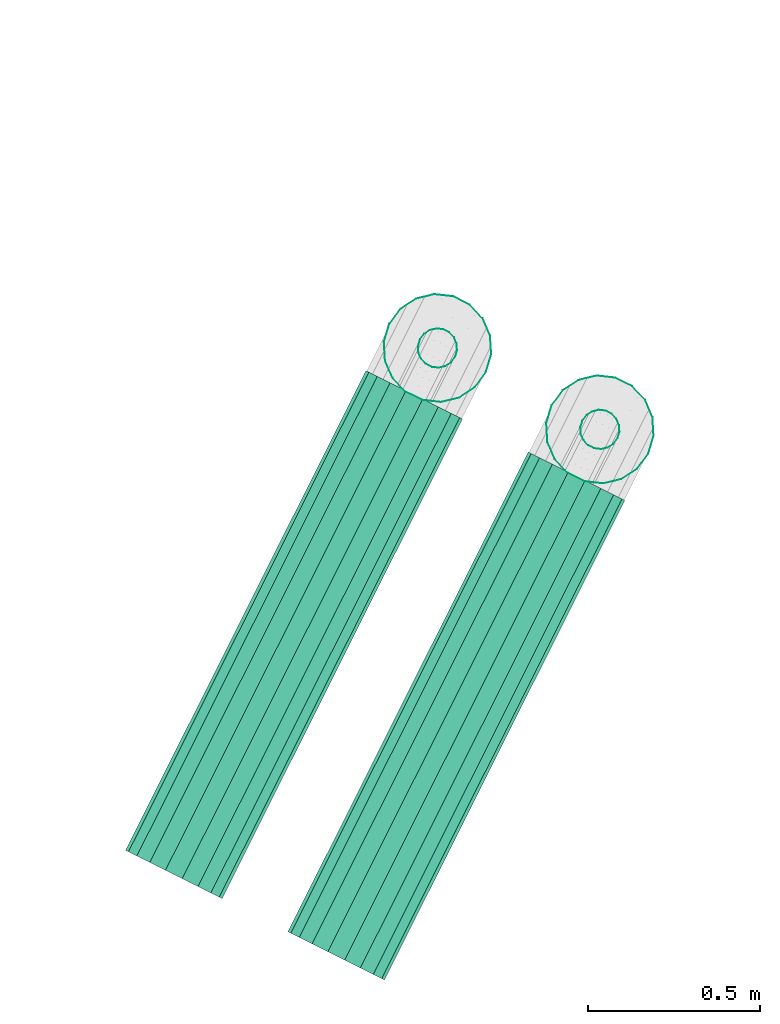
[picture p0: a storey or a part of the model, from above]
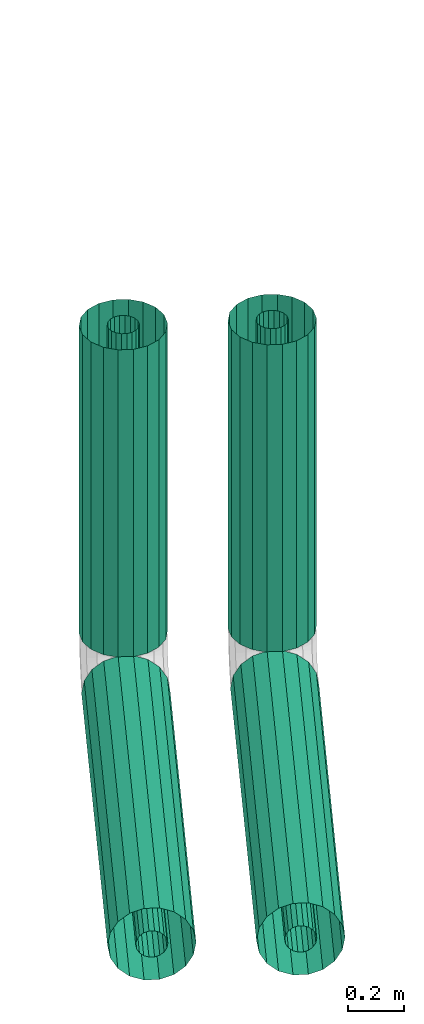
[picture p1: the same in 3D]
Properties of the parts of a building model (IFC2X3), part 1 of 23

# File
Description: ViewDefinition [CoordinationView_V2.0], RevitIdentifiers [ContentGUID: 118f7e49-5a85-4aa1-87a6-58cd707cd526, VersionGUID: 2906a081-f5fd-45af-9664-1ba8e915f47c, NumberOfSaves: 2], CoordinateReference [CoordinateBase: Aktuelle gemeinsam genutzte Koordinaten, ProjectSite: Intern], ExchangeRequirement [Architecture]
File name: Zentrale.ifc
Time: 2026-09-11T20:31:49+01:00
Written by: ODA SDAI 25.12
Made in: Autodesk - Revit 27.2.0.39 (DEU) - 27.3.0.12

# IfcProject, 2018_01
Phase: Projekt Status

# IfcSite, Default
RefLatitude: 50, 43, 7, 999999; RefLongitude: 7, 8, 55, 999999; RefElevation: 0 m
Andere - Projektausgabedatum: Projekt Datum; Projektstatus: Projekt Status; Auftraggeber: Bauherr; Projektnummer: 2018_01; Verfasser Firma 1: AUTODESK GmbH; Verfasser PLZ Ort: Ort; Verfasser Strasse: Adresse; Verfasser Telefon: Telefon; Verfasser eMail: E-Mail; Verfasser URL: www.Autodesk.de/BIM; Kategorie: Projektinformationen
IFC-Parameter - IfcOrganization: Trimble Inc.; IfcApplicationVersion: 16.1.0.21; IfcApplicationName: Trimble Nova 16.1.0.21; NameOverride: Neu Gebäude
Text - Bauherr: AUTODESK; Baustellenort: BAUORT; Baustellenstraße: BAUSTRASSE 1; Gerichtsbezirk: GERICHTSBEZIRK; Grundstücksnummer: GR; Katastralgemeinde: KG; Kundenadresse: KUNDENSTRASSE 1; Kundenort: KUNDENORT; Kundenzusatz: KUNDENZUSATZ; Kundentelefon: 0000-00000-1; Einlagezahl: 123-45; PrintManagerSettings: <PrintManagerDS xmlns="http://tempuri.org/PrintManagerDS.xsd"> <xs:schema id="PrintManagerDS" targetNamespace="http://tempuri.org/PrintManagerDS.xsd" xmlns:mstns="http://tempuri.org/PrintManagerDS.xsd" xmlns="http://tempuri.org/PrintManagerDS.xsd" xmlns:xs="http://www.w3.org/2001/XMLSchema" xmlns:msdata="urn:schemas-microsoft-com:xml-msdata" attributeFormDefault="qualified" elementFormDefault="qualified"> <xs:element name="PrintManagerDS" msdata:IsDataSet="true" msdata:UseCurrentLocale="true"> <xs:complexType> <xs:choice minOccurs="0" maxOccurs="unbounded"> <xs:element name="DruckEinstellungDT"> <xs:complexType> <xs:sequence> <xs:element name="ID" msdata:DataType="System.Guid, mscorlib, Version=4.0.0.0, Culture=neutral, PublicKeyToken=b77a5c561934e089" msdata:AutoIncrementSeed="-1" msdata:AutoIncrementStep="-1" type="xs:string" minOccurs="0" /> <xs:element name="Name" type="xs:string" minOccurs="0" /> <xs:element name="Beschreibung" type="xs:string" minOccurs="0" /> <xs:element name="Kategorie" type="xs:string" minOccurs="0" /> <xs:element name="PrinterName" type="xs:string" minOccurs="0" /> <xs:element name="PrintToFile" type="xs:boolean" minOccurs="0" /> <xs:element name="FileName" type="xs:string" minOccurs="0" /> <xs:element name="ColorDepth" type="xs:string" minOccurs="0" /> <xs:element name="HiddenLineViews" type="xs:string" minOccurs="0" /> <xs:element name="HideCropBoundaries" type="xs:boolean" minOccurs="0" /> <xs:element name="HideRefOrWorkPlanes" type="xs:boolean" minOccurs="0" /> <xs:element name="HideScopeBoxes" type="xs:boolean" minOccurs="0" /> <xs:element name="HideUnreferencedViewTags" type="xs:boolean" minOccurs="0" /> <xs:element name="MarginType" type="xs:string" minOccurs="0" /> <xs:element name="PageOrientation" type="xs:string" minOccurs="0" /> <xs:element name="PaperPlacement" type="xs:string" minOccurs="0" /> <xs:element name="PaperSize" type="xs:string" minOccurs="0" /> <xs:element name="PaperSource" type="xs:string" minOccurs="0" /> <xs:element name="RasterQuality" type="xs:string" minOccurs="0" /> <xs:element name="ReplaceHalftoneWithThinLines" type="xs:boolean" minOccurs="0" /> <xs:element name="UserDefinedMarginX" type="xs:double" minOccurs="0" /> <xs:element name="UserDefinedMarginY" type="xs:double" minOccurs="0" /> <xs:element name="ViewLinksInBlue" type="xs:boolean" minOccurs="0" /> <xs:element name="Zoom" type="xs:int" minOccurs="0" /> <xs:element name="ZoomType" type="xs:string" minOccurs="0" /> </xs:sequence> </xs:complexType> </xs:element> <xs:element name="DruckSatzDT"> <xs:complexType> <xs:sequence> <xs:element name="ID" msdata:DataType="System.Guid, mscorlib, Version=4.0.0.0, Culture=neutral, PublicKeyToken=b77a5c561934e089" type="xs:string" minOccurs="0" /> <xs:element name="PlanID" type="xs:string" minOccurs="0" /> <xs:element name="DruckEinstellungID" msdata:DataType="System.Guid, mscorlib, Version=4.0.0.0, Culture=neutral, PublicKeyToken=b77a5c561934e089" type="xs:string" minOccurs="0" /> <xs:element name="Name" type="xs:string" minOccurs="0" /> <xs:element name="Beschreibung" type="xs:string" minOccurs="0" /> <xs:element name="ParameterName" type="xs:string" minOccurs="0" /> <xs:element name="File" type="xs:string" minOccurs="0" /> <xs:element name="Path" type="xs:string" minOccurs="0" /> <xs:element name="GenerateFileName" type="xs:boolean" minOccurs="0" /> <xs:element name="Kategorie" type="xs:string" minOccurs="0" /> </xs:sequence> </xs:complexType> </xs:element> <xs:element name="DruckJobDT"> <xs:complexType> <xs:sequence> <xs:element name="ID" msdata:DataType="System.Guid, mscorlib, Version=4.0.0.0, Culture=neutral, PublicKeyToken=b77a5c561934e089" type="xs:string" minOccurs="0" /> <xs:element name="DruckJobGruppeID" msdata:DataType="System.Guid, mscorlib, Version=4.0.0.0, Culture=neutral, PublicKeyToken=b77a5c561934e089" type="xs:string" minOccurs="0" /> <xs:element name="DruckSatzID" msdata:DataType="System.Guid, mscorlib, Version=4.0.0.0, Culture=neutral, PublicKeyToken=b77a5c561934e089" type="xs:string" minOccurs="0" /> <xs:element name="Anzahl" type="xs:int" minOccurs="0" /> </xs:sequence> </xs:complexType> </xs:element> <xs:element name="DruckJobGruppeDT"> <xs:complexType> <xs:sequence> <xs:element name="ID" msdata:DataType="System.Guid, mscorlib, Version=4.0.0.0, Culture=neutral, PublicKeyToken=b77a5c561934e089" type="xs:string" minOccurs="0" /> <xs:element name="Name" type="xs:string" minOccurs="0" /> <xs:element name="Beschreibung" type="xs:string" minOccurs="0" /> <xs:element name="JobCount" msdata:ReadOnly="true" msdata:Expression="Count(Child(DruckJobGruppeDT_DruckJobDT).Anzahl)" type="xs:int" minOccurs="0" /> <xs:element name="Kategorie" type="xs:string" minOccurs="0" /> </xs:sequence> </xs:complexType> </xs:element> <xs:element name="PrintSettingCategories"> <xs:complexType> <xs:sequence> <xs:element name="CategoryName" type="xs:string" minOccurs="0" /> </xs:sequence> </xs:complexType> </xs:element> <xs:element name="PrintRecordCategories"> <xs:complexType> <xs:sequence> <xs:element name="CategoryName" type="xs:string" /> </xs:sequence> </xs:complexType> </xs:element> <xs:element name="JobGroupCategories"> <xs:complexType> <xs:sequence> <xs:element name="CategoryName" type="xs:string" /> </xs:sequence> </xs:complexType> </xs:element> <xs:element name="ExportSettingsDT"> <xs:complexType> <xs:sequence> <xs:element name="ID" msdata:DataType="System.Guid, mscorlib, Version=4.0.0.0, Culture=neutral, PublicKeyToken=b77a5c561934e089" type="xs:string" /> <xs:element name="Name" type="xs:string" minOccurs="0" /> <xs:element name="Description" type="xs:string" default="&quot;&quot;" minOccurs="0" /> <xs:element name="Category" type="xs:string" minOccurs="0" /> <xs:element name="Type" type="xs:string" minOccurs="0" /> <xs:element name="Data" type="xs:string" minOccurs="0" /> </xs:sequence> </xs:complexType> </xs:element> <xs:element name="ExportMappingDT"> <xs:complexType> <xs:sequence> <xs:element name="ID" msdata:DataType="System.Guid, mscorlib, Version=4.0.0.0, Culture=neutral, PublicKeyToken=b77a5c561934e089" type="xs:string" /> <xs:element name="DWG" msdata:DataType="System.Guid, mscorlib, Version=4.0.0.0, Culture=neutral, PublicKeyToken=b77a5c561934e089" type="xs:string" minOccurs="0" /> <xs:element name="DWGPath" type="xs:string" minOccurs="0" /> <xs:element name="DWGFile" type="xs:string" minOccurs="0" /> </xs:sequence> </xs:complexType> </xs:element> <xs:element name="ExportSettingCategories"> <xs:complexType> <xs:sequence> <xs:element name="CategoryName" type="xs:string" /> </xs:sequence> </xs:complexType> </xs:element> </xs:choice> </xs:complexType> <xs:unique name="Constraint1"> <xs:selector xpath=".//mstns:DruckEinstellungDT" /> <xs:field xpath="mstns:ID" /> </xs:unique> <xs:unique name="Constraint2"> <xs:selector xpath=".//mstns:DruckEinstellungDT" /> <xs:field xpath="mstns:Name" /> </xs:unique> <xs:unique name="DruckSatzDT_Constraint1" msdata:ConstraintName="Constraint1"> <xs:selector xpath=".//mstns:DruckSatzDT" /> <xs:field xpath="mstns:ID" /> </xs:unique> <xs:unique name="DruckJobDT_Constraint1" msdata:ConstraintName="Constraint1"> <xs:selector xpath=".//mstns:DruckJobDT" /> <xs:field xpath="mstns:ID" /> </xs:unique> <xs:unique name="DruckJobGruppeDT_Constraint1" msdata:ConstraintName="Constraint1"> <xs:selector xpath=".//mstns:DruckJobGruppeDT" /> <xs:field xpath="mstns:ID" /> </xs:unique> <xs:unique name="PrintSettingCategories_Constraint1" msdata:ConstraintName="Constraint1"> <xs:selector xpath=".//mstns:PrintSettingCategories" /> <xs:field xpath="mstns:CategoryName" /> </xs:unique> <xs:unique name="PrintRecordCategories_Constraint1" msdata:ConstraintName="Constraint1" msdata:PrimaryKey="true"> <xs:selector xpath=".//mstns:PrintRecordCategories" /> <xs:field xpath="mstns:CategoryName" /> </xs:unique> <xs:unique name="JobGroupCategories_Constraint1" msdata:ConstraintName="Constraint1" msdata:PrimaryKey="true"> <xs:selector xpath=".//mstns:JobGroupCategories" /> <xs:field xpath="mstns:CategoryName" /> </xs:unique> <xs:unique name="ExportSettingsDT_Constraint1" msdata:ConstraintName="Constraint1" msdata:PrimaryKey="true"> <xs:selector xpath=".//mstns:ExportSettingsDT" /> <xs:field xpath="mstns:ID" /> </xs:unique> <xs:unique name="ExportSettingsDT_Constraint2" msdata:ConstraintName="Constraint2"> <xs:selector xpath=".//mstns:ExportSettingsDT" /> <xs:field xpath="mstns:Name" /> </xs:unique> <xs:unique name="ExportMappingDT_Constraint1" msdata:ConstraintName="Constraint1" msdata:PrimaryKey="true"> <xs:selector xpath=".//mstns:ExportMappingDT" /> <xs:field xpath="mstns:ID" /> </xs:unique> <xs:unique name="ExportSettingCategories_Constraint1" msdata:ConstraintName="Constraint1" msdata:PrimaryKey="true"> <xs:selector xpath=".//mstns:ExportSettingCategories" /> <xs:field xpath="mstns:CategoryName" /> </xs:unique> </xs:element> <xs:annotation> <xs:appinfo> <msdata:Relationship name="PrintSettingCategories_DruckEinstellungDT" msdata:parent="PrintSettingCategories" msdata:child="DruckEinstellungDT" msdata:parentkey="CategoryName" msdata:childkey="Kategorie" /> <msdata:Relationship name="DruckEinstellungDT_DruckSatzDT" msdata:parent="DruckEinstellungDT" msdata:child="DruckSatzDT" msdata:parentkey="ID" msdata:childkey="DruckEinstellungID" /> <msdata:Relationship name="DruckJobGruppeDT_DruckJobDT" msdata:parent="DruckJobGruppeDT" msdata:child="DruckJobDT" msdata:parentkey="ID" msdata:childkey="DruckJobGruppeID" /> <msdata:Relationship name="DruckEinstellungDT_PrintRecordCategories" msdata:parent="DruckSatzDT" msdata:child="PrintRecordCategories" msdata:parentkey="Kategorie" msdata:childkey="CategoryName" /> <msdata:Relationship name="DruckJobGruppeDT_JobGroupCategories" msdata:parent="DruckJobGruppeDT" msdata:child="JobGroupCategories" msdata:parentkey="Kategorie" msdata:childkey="CategoryName" /> <msdata:Relationship name="DruckSatzDT_DruckJobDT" msdata:parent="DruckSatzDT" msdata:child="DruckJobDT" msdata:parentkey="ID" msdata:childkey="DruckSatzID" /> <msdata:Relationship name="DruckSatzDT_ExportMappingDT" msdata:parent="DruckSatzDT" msdata:child="ExportMappingDT" msdata:parentkey="ID" msdata:childkey="ID" /> <msdata:Relationship name="ExportSettingsDT_ExportSettingCategories" msdata:parent="ExportSettingCategories" msdata:child="ExportSettingsDT" msdata:parentkey="CategoryName" msdata:childkey="Category" /> </xs:appinfo> </xs:annotation> </xs:schema> <PrintRecordCategories> <CategoryName>&lt;Keine&gt;</CategoryName> </PrintRecordCategories> <JobGroupCategories> <CategoryName>&lt;Keine&gt;</CategoryName> </JobGroupCategories> </PrintManagerDS>

# IfcBuilding
Pset_BuildingCommon - NumberOfStoreys: 3
Andere - Projektausgabedatum: Projekt Datum; Projektstatus: Projekt Status; Auftraggeber: Bauherr; Projektnummer: 2018_01; Verfasser Firma 1: AUTODESK GmbH; Verfasser PLZ Ort: Ort; Verfasser Strasse: Adresse; Verfasser Telefon: Telefon; Verfasser eMail: E-Mail; Verfasser URL: www.Autodesk.de/BIM; Kategorie: Projektinformationen
IFC-Parameter - IfcOrganization: Trimble Inc.; IfcApplicationVersion: 16.1.0.21; IfcApplicationName: Trimble Nova 16.1.0.21; NameOverride: Neu Gebäude
Text - Bauherr: AUTODESK; Baustellenort: BAUORT; Baustellenstraße: BAUSTRASSE 1; Gerichtsbezirk: GERICHTSBEZIRK; Grundstücksnummer: GR; Katastralgemeinde: KG; Kundenadresse: KUNDENSTRASSE 1; Kundenort: KUNDENORT; Kundenzusatz: KUNDENZUSATZ; Kundentelefon: 0000-00000-1; Einlagezahl: 123-45; PrintManagerSettings: <PrintManagerDS xmlns="http://tempuri.org/PrintManagerDS.xsd"> <xs:schema id="PrintManagerDS" targetNamespace="http://tempuri.org/PrintManagerDS.xsd" xmlns:mstns="http://tempuri.org/PrintManagerDS.xsd" xmlns="http://tempuri.org/PrintManagerDS.xsd" xmlns:xs="http://www.w3.org/2001/XMLSchema" xmlns:msdata="urn:schemas-microsoft-com:xml-msdata" attributeFormDefault="qualified" elementFormDefault="qualified"> <xs:element name="PrintManagerDS" msdata:IsDataSet="true" msdata:UseCurrentLocale="true"> <xs:complexType> <xs:choice minOccurs="0" maxOccurs="unbounded"> <xs:element name="DruckEinstellungDT"> <xs:complexType> <xs:sequence> <xs:element name="ID" msdata:DataType="System.Guid, mscorlib, Version=4.0.0.0, Culture=neutral, PublicKeyToken=b77a5c561934e089" msdata:AutoIncrementSeed="-1" msdata:AutoIncrementStep="-1" type="xs:string" minOccurs="0" /> <xs:element name="Name" type="xs:string" minOccurs="0" /> <xs:element name="Beschreibung" type="xs:string" minOccurs="0" /> <xs:element name="Kategorie" type="xs:string" minOccurs="0" /> <xs:element name="PrinterName" type="xs:string" minOccurs="0" /> <xs:element name="PrintToFile" type="xs:boolean" minOccurs="0" /> <xs:element name="FileName" type="xs:string" minOccurs="0" /> <xs:element name="ColorDepth" type="xs:string" minOccurs="0" /> <xs:element name="HiddenLineViews" type="xs:string" minOccurs="0" /> <xs:element name="HideCropBoundaries" type="xs:boolean" minOccurs="0" /> <xs:element name="HideRefOrWorkPlanes" type="xs:boolean" minOccurs="0" /> <xs:element name="HideScopeBoxes" type="xs:boolean" minOccurs="0" /> <xs:element name="HideUnreferencedViewTags" type="xs:boolean" minOccurs="0" /> <xs:element name="MarginType" type="xs:string" minOccurs="0" /> <xs:element name="PageOrientation" type="xs:string" minOccurs="0" /> <xs:element name="PaperPlacement" type="xs:string" minOccurs="0" /> <xs:element name="PaperSize" type="xs:string" minOccurs="0" /> <xs:element name="PaperSource" type="xs:string" minOccurs="0" /> <xs:element name="RasterQuality" type="xs:string" minOccurs="0" /> <xs:element name="ReplaceHalftoneWithThinLines" type="xs:boolean" minOccurs="0" /> <xs:element name="UserDefinedMarginX" type="xs:double" minOccurs="0" /> <xs:element name="UserDefinedMarginY" type="xs:double" minOccurs="0" /> <xs:element name="ViewLinksInBlue" type="xs:boolean" minOccurs="0" /> <xs:element name="Zoom" type="xs:int" minOccurs="0" /> <xs:element name="ZoomType" type="xs:string" minOccurs="0" /> </xs:sequence> </xs:complexType> </xs:element> <xs:element name="DruckSatzDT"> <xs:complexType> <xs:sequence> <xs:element name="ID" msdata:DataType="System.Guid, mscorlib, Version=4.0.0.0, Culture=neutral, PublicKeyToken=b77a5c561934e089" type="xs:string" minOccurs="0" /> <xs:element name="PlanID" type="xs:string" minOccurs="0" /> <xs:element name="DruckEinstellungID" msdata:DataType="System.Guid, mscorlib, Version=4.0.0.0, Culture=neutral, PublicKeyToken=b77a5c561934e089" type="xs:string" minOccurs="0" /> <xs:element name="Name" type="xs:string" minOccurs="0" /> <xs:element name="Beschreibung" type="xs:string" minOccurs="0" /> <xs:element name="ParameterName" type="xs:string" minOccurs="0" /> <xs:element name="File" type="xs:string" minOccurs="0" /> <xs:element name="Path" type="xs:string" minOccurs="0" /> <xs:element name="GenerateFileName" type="xs:boolean" minOccurs="0" /> <xs:element name="Kategorie" type="xs:string" minOccurs="0" /> </xs:sequence> </xs:complexType> </xs:element> <xs:element name="DruckJobDT"> <xs:complexType> <xs:sequence> <xs:element name="ID" msdata:DataType="System.Guid, mscorlib, Version=4.0.0.0, Culture=neutral, PublicKeyToken=b77a5c561934e089" type="xs:string" minOccurs="0" /> <xs:element name="DruckJobGruppeID" msdata:DataType="System.Guid, mscorlib, Version=4.0.0.0, Culture=neutral, PublicKeyToken=b77a5c561934e089" type="xs:string" minOccurs="0" /> <xs:element name="DruckSatzID" msdata:DataType="System.Guid, mscorlib, Version=4.0.0.0, Culture=neutral, PublicKeyToken=b77a5c561934e089" type="xs:string" minOccurs="0" /> <xs:element name="Anzahl" type="xs:int" minOccurs="0" /> </xs:sequence> </xs:complexType> </xs:element> <xs:element name="DruckJobGruppeDT"> <xs:complexType> <xs:sequence> <xs:element name="ID" msdata:DataType="System.Guid, mscorlib, Version=4.0.0.0, Culture=neutral, PublicKeyToken=b77a5c561934e089" type="xs:string" minOccurs="0" /> <xs:element name="Name" type="xs:string" minOccurs="0" /> <xs:element name="Beschreibung" type="xs:string" minOccurs="0" /> <xs:element name="JobCount" msdata:ReadOnly="true" msdata:Expression="Count(Child(DruckJobGruppeDT_DruckJobDT).Anzahl)" type="xs:int" minOccurs="0" /> <xs:element name="Kategorie" type="xs:string" minOccurs="0" /> </xs:sequence> </xs:complexType> </xs:element> <xs:element name="PrintSettingCategories"> <xs:complexType> <xs:sequence> <xs:element name="CategoryName" type="xs:string" minOccurs="0" /> </xs:sequence> </xs:complexType> </xs:element> <xs:element name="PrintRecordCategories"> <xs:complexType> <xs:sequence> <xs:element name="CategoryName" type="xs:string" /> </xs:sequence> </xs:complexType> </xs:element> <xs:element name="JobGroupCategories"> <xs:complexType> <xs:sequence> <xs:element name="CategoryName" type="xs:string" /> </xs:sequence> </xs:complexType> </xs:element> <xs:element name="ExportSettingsDT"> <xs:complexType> <xs:sequence> <xs:element name="ID" msdata:DataType="System.Guid, mscorlib, Version=4.0.0.0, Culture=neutral, PublicKeyToken=b77a5c561934e089" type="xs:string" /> <xs:element name="Name" type="xs:string" minOccurs="0" /> <xs:element name="Description" type="xs:string" default="&quot;&quot;" minOccurs="0" /> <xs:element name="Category" type="xs:string" minOccurs="0" /> <xs:element name="Type" type="xs:string" minOccurs="0" /> <xs:element name="Data" type="xs:string" minOccurs="0" /> </xs:sequence> </xs:complexType> </xs:element> <xs:element name="ExportMappingDT"> <xs:complexType> <xs:sequence> <xs:element name="ID" msdata:DataType="System.Guid, mscorlib, Version=4.0.0.0, Culture=neutral, PublicKeyToken=b77a5c561934e089" type="xs:string" /> <xs:element name="DWG" msdata:DataType="System.Guid, mscorlib, Version=4.0.0.0, Culture=neutral, PublicKeyToken=b77a5c561934e089" type="xs:string" minOccurs="0" /> <xs:element name="DWGPath" type="xs:string" minOccurs="0" /> <xs:element name="DWGFile" type="xs:string" minOccurs="0" /> </xs:sequence> </xs:complexType> </xs:element> <xs:element name="ExportSettingCategories"> <xs:complexType> <xs:sequence> <xs:element name="CategoryName" type="xs:string" /> </xs:sequence> </xs:complexType> </xs:element> </xs:choice> </xs:complexType> <xs:unique name="Constraint1"> <xs:selector xpath=".//mstns:DruckEinstellungDT" /> <xs:field xpath="mstns:ID" /> </xs:unique> <xs:unique name="Constraint2"> <xs:selector xpath=".//mstns:DruckEinstellungDT" /> <xs:field xpath="mstns:Name" /> </xs:unique> <xs:unique name="DruckSatzDT_Constraint1" msdata:ConstraintName="Constraint1"> <xs:selector xpath=".//mstns:DruckSatzDT" /> <xs:field xpath="mstns:ID" /> </xs:unique> <xs:unique name="DruckJobDT_Constraint1" msdata:ConstraintName="Constraint1"> <xs:selector xpath=".//mstns:DruckJobDT" /> <xs:field xpath="mstns:ID" /> </xs:unique> <xs:unique name="DruckJobGruppeDT_Constraint1" msdata:ConstraintName="Constraint1"> <xs:selector xpath=".//mstns:DruckJobGruppeDT" /> <xs:field xpath="mstns:ID" /> </xs:unique> <xs:unique name="PrintSettingCategories_Constraint1" msdata:ConstraintName="Constraint1"> <xs:selector xpath=".//mstns:PrintSettingCategories" /> <xs:field xpath="mstns:CategoryName" /> </xs:unique> <xs:unique name="PrintRecordCategories_Constraint1" msdata:ConstraintName="Constraint1" msdata:PrimaryKey="true"> <xs:selector xpath=".//mstns:PrintRecordCategories" /> <xs:field xpath="mstns:CategoryName" /> </xs:unique> <xs:unique name="JobGroupCategories_Constraint1" msdata:ConstraintName="Constraint1" msdata:PrimaryKey="true"> <xs:selector xpath=".//mstns:JobGroupCategories" /> <xs:field xpath="mstns:CategoryName" /> </xs:unique> <xs:unique name="ExportSettingsDT_Constraint1" msdata:ConstraintName="Constraint1" msdata:PrimaryKey="true"> <xs:selector xpath=".//mstns:ExportSettingsDT" /> <xs:field xpath="mstns:ID" /> </xs:unique> <xs:unique name="ExportSettingsDT_Constraint2" msdata:ConstraintName="Constraint2"> <xs:selector xpath=".//mstns:ExportSettingsDT" /> <xs:field xpath="mstns:Name" /> </xs:unique> <xs:unique name="ExportMappingDT_Constraint1" msdata:ConstraintName="Constraint1" msdata:PrimaryKey="true"> <xs:selector xpath=".//mstns:ExportMappingDT" /> <xs:field xpath="mstns:ID" /> </xs:unique> <xs:unique name="ExportSettingCategories_Constraint1" msdata:ConstraintName="Constraint1" msdata:PrimaryKey="true"> <xs:selector xpath=".//mstns:ExportSettingCategories" /> <xs:field xpath="mstns:CategoryName" /> </xs:unique> </xs:element> <xs:annotation> <xs:appinfo> <msdata:Relationship name="PrintSettingCategories_DruckEinstellungDT" msdata:parent="PrintSettingCategories" msdata:child="DruckEinstellungDT" msdata:parentkey="CategoryName" msdata:childkey="Kategorie" /> <msdata:Relationship name="DruckEinstellungDT_DruckSatzDT" msdata:parent="DruckEinstellungDT" msdata:child="DruckSatzDT" msdata:parentkey="ID" msdata:childkey="DruckEinstellungID" /> <msdata:Relationship name="DruckJobGruppeDT_DruckJobDT" msdata:parent="DruckJobGruppeDT" msdata:child="DruckJobDT" msdata:parentkey="ID" msdata:childkey="DruckJobGruppeID" /> <msdata:Relationship name="DruckEinstellungDT_PrintRecordCategories" msdata:parent="DruckSatzDT" msdata:child="PrintRecordCategories" msdata:parentkey="Kategorie" msdata:childkey="CategoryName" /> <msdata:Relationship name="DruckJobGruppeDT_JobGroupCategories" msdata:parent="DruckJobGruppeDT" msdata:child="JobGroupCategories" msdata:parentkey="Kategorie" msdata:childkey="CategoryName" /> <msdata:Relationship name="DruckSatzDT_DruckJobDT" msdata:parent="DruckSatzDT" msdata:child="DruckJobDT" msdata:parentkey="ID" msdata:childkey="DruckSatzID" /> <msdata:Relationship name="DruckSatzDT_ExportMappingDT" msdata:parent="DruckSatzDT" msdata:child="ExportMappingDT" msdata:parentkey="ID" msdata:childkey="ID" /> <msdata:Relationship name="ExportSettingsDT_ExportSettingCategories" msdata:parent="ExportSettingCategories" msdata:child="ExportSettingsDT" msdata:parentkey="CategoryName" msdata:childkey="Category" /> </xs:appinfo> </xs:annotation> </xs:schema> <PrintRecordCategories> <CategoryName>&lt;Keine&gt;</CategoryName> </PrintRecordCategories> <JobGroupCategories> <CategoryName>&lt;Keine&gt;</CategoryName> </JobGroupCategories> </PrintManagerDS>

# IfcBuildingStorey (3)
Pset_AirSideSystemInformation - sets with these values: 2
Andere - Typ: Ebene OK FFB; Familie: Ebene; Familie und Typ: Ebene: Ebene OK FFB; Typ-ID: 696869; Kategorie: Ebenen
Bemaßungen - Höhe für Berechnung: 0 m
ID-Daten - Tragwerk: no; Gebäudegeschoss: yes
IFC-Parameter - In IFC-Datei exportieren: Nach Typ; In IFC exportieren als: ifcbuildingstorey
Andere(Typ) - Kategorie: Ebenen; Familienname: Ebene
Abhängigkeiten(Typ) - Basishöhe: Projekt-Basispunkt
Grafiken(Typ) - Linienstärke: 2; Farbe: 255; Linienmuster: (Ebene); Symbol: Beschriftung Ebene Oberkante : Fertig Fußboden; Symbol bei Ende 1 Standard: no; Symbol bei Ende 2 Standard: yes
ID-Daten(Typ) - Typname: Ebene OK FFB
IFC-Parameter(Typ) - Typ in IFC-Datei exportieren: Vorgabe
Name | LongName = Pset_AirSideSystemInformation, Name = ID-Daten, Name | Elevation (m) = Höhe (m)
1. Untergeschoss | 1. Untergeschoss | -2.75
Erdgeschoss | Erdgeschoss | 0
1. Obergeschoss | 1. Obergeschoss | 2.75

# IfcBuildingElementProxy: BuildingElementProxy 100:BuildingElementProxy 100, BuildingElementProxy 100
In: Erdgeschoss
Type - Material: IfcSurfaceStyle #623543
Type - Andere - Kategorie: Allgemeines Modell; Familienname: BuildingElementProxy 100
Type - ID-Daten - Typname: BuildingElementProxy 100
Type - IFC-Parameter - Typ in IFC-Datei exportieren: Vorgabe
Description: IfcBuildingElementProxy
Pset_BuildingElementProxyCommon - Reference: BuildingElementProxy 100; sets with these values: 2
Andere - Typ: BuildingElementProxy 100; Familie: BuildingElementProxy 100; Familie und Typ: BuildingElementProxy 100: BuildingElementProxy 100; Typ-ID: 2538749
Abhängigkeiten - Höhe von Ebene: 0 m; Verschieben mit umliegenden Elementen: no
Bemaßungen - Fläche: 0.00905707 m2; Volumen: 0.000161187 m3
IFC-Parameter - In IFC-Datei exportieren: Nach Typ; In IFC exportieren als: ifcbuildingelementproxy; NameOverride: BuildingElementProxy 100; IfcPresentationLayer: 0; IfcDescription: IfcBuildingElementProxy
Phasen - Phase erstellt: Phase 01

# IfcBuildingElementProxy: BuildingElementProxy 101:BuildingElementProxy 101, BuildingElementProxy 101
In: Erdgeschoss
Type - Material: IfcSurfaceStyle #623543
Type - Andere - Kategorie: Allgemeines Modell; Familienname: BuildingElementProxy 101
Type - ID-Daten - Typname: BuildingElementProxy 101
Type - IFC-Parameter - Typ in IFC-Datei exportieren: Vorgabe
Description: IfcBuildingElementProxy
Pset_BuildingElementProxyCommon - Reference: BuildingElementProxy 101; sets with these values: 2
Andere - Typ: BuildingElementProxy 101; Familie: BuildingElementProxy 101; Familie und Typ: BuildingElementProxy 101: BuildingElementProxy 101; Typ-ID: 2538756
Abhängigkeiten - Höhe von Ebene: 0 m; Verschieben mit umliegenden Elementen: no
Bemaßungen - Fläche: 0.00687765 m2; Volumen: 0.0000187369 m3
IFC-Parameter - In IFC-Datei exportieren: Nach Typ; In IFC exportieren als: ifcbuildingelementproxy; NameOverride: BuildingElementProxy 101; IfcPresentationLayer: 0; IfcDescription: IfcBuildingElementProxy
Phasen - Phase erstellt: Phase 01

# IfcBuildingElementProxy: BuildingElementProxy 102:BuildingElementProxy 102, BuildingElementProxy 102
In: Erdgeschoss
Type - Material: IfcSurfaceStyle #623543
Type - Andere - Kategorie: Allgemeines Modell; Familienname: BuildingElementProxy 102
Type - ID-Daten - Typname: BuildingElementProxy 102
Type - IFC-Parameter - Typ in IFC-Datei exportieren: Vorgabe
Description: IfcBuildingElementProxy
Pset_BuildingElementProxyCommon - Reference: BuildingElementProxy 102; sets with these values: 2
Andere - Typ: BuildingElementProxy 102; Familie: BuildingElementProxy 102; Familie und Typ: BuildingElementProxy 102: BuildingElementProxy 102; Typ-ID: 2538763
Abhängigkeiten - Höhe von Ebene: 0 m; Verschieben mit umliegenden Elementen: no
Bemaßungen - Fläche: 0.0156619 m2; Volumen: 0.0000724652 m3
IFC-Parameter - In IFC-Datei exportieren: Nach Typ; In IFC exportieren als: ifcbuildingelementproxy; NameOverride: BuildingElementProxy 102; IfcPresentationLayer: 0; IfcDescription: IfcBuildingElementProxy
Phasen - Phase erstellt: Phase 01

# IfcBuildingElementProxy: BuildingElementProxy 103:BuildingElementProxy 103, BuildingElementProxy 103
In: Erdgeschoss
Type - Material: IfcSurfaceStyle #623543
Type - Andere - Kategorie: Allgemeines Modell; Familienname: BuildingElementProxy 103
Type - ID-Daten - Typname: BuildingElementProxy 103
Type - IFC-Parameter - Typ in IFC-Datei exportieren: Vorgabe
Description: IfcBuildingElementProxy
Pset_BuildingElementProxyCommon - Reference: BuildingElementProxy 103; sets with these values: 2
Andere - Typ: BuildingElementProxy 103; Familie: BuildingElementProxy 103; Familie und Typ: BuildingElementProxy 103: BuildingElementProxy 103; Typ-ID: 2538770
Abhängigkeiten - Höhe von Ebene: 0 m; Verschieben mit umliegenden Elementen: no
Bemaßungen - Fläche: 0.00687765 m2; Volumen: 0.0000187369 m3
IFC-Parameter - In IFC-Datei exportieren: Nach Typ; In IFC exportieren als: ifcbuildingelementproxy; NameOverride: BuildingElementProxy 103; IfcPresentationLayer: 0; IfcDescription: IfcBuildingElementProxy
Phasen - Phase erstellt: Phase 01

# IfcBuildingElementProxy: BuildingElementProxy 104:BuildingElementProxy 104, BuildingElementProxy 104
In: Erdgeschoss
Type - Material: IfcSurfaceStyle #624876
Type - Andere - Kategorie: Allgemeines Modell; Familienname: BuildingElementProxy 104
Type - ID-Daten - Typname: BuildingElementProxy 104
Type - IFC-Parameter - Typ in IFC-Datei exportieren: Vorgabe
Description: IfcBuildingElementProxy
Pset_BuildingElementProxyCommon - Reference: BuildingElementProxy 104; sets with these values: 2
Andere - Typ: BuildingElementProxy 104; Familie: BuildingElementProxy 104; Familie und Typ: BuildingElementProxy 104: BuildingElementProxy 104; Typ-ID: 2538777
Abhängigkeiten - Höhe von Ebene: 0 m; Verschieben mit umliegenden Elementen: no
Bemaßungen - Fläche: 0.00047718 m2; Volumen: 0.00000156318 m3
IFC-Parameter - In IFC-Datei exportieren: Nach Typ; In IFC exportieren als: ifcbuildingelementproxy; NameOverride: BuildingElementProxy 104; IfcPresentationLayer: 0; IfcDescription: IfcBuildingElementProxy
Phasen - Phase erstellt: Phase 01

# IfcBuildingElementProxy: BuildingElementProxy 105:BuildingElementProxy 105, BuildingElementProxy 105
In: Erdgeschoss
Type - Material: IfcSurfaceStyle #623543
Type - Andere - Kategorie: Allgemeines Modell; Familienname: BuildingElementProxy 105
Type - ID-Daten - Typname: BuildingElementProxy 105
Type - IFC-Parameter - Typ in IFC-Datei exportieren: Vorgabe
Description: IfcBuildingElementProxy
Pset_BuildingElementProxyCommon - Reference: BuildingElementProxy 105; sets with these values: 2
Andere - Typ: BuildingElementProxy 105; Familie: BuildingElementProxy 105; Familie und Typ: BuildingElementProxy 105: BuildingElementProxy 105; Typ-ID: 2538784
Abhängigkeiten - Höhe von Ebene: 0 m; Verschieben mit umliegenden Elementen: no
Bemaßungen - Fläche: 0.00687765 m2; Volumen: 0.0000187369 m3
IFC-Parameter - In IFC-Datei exportieren: Nach Typ; In IFC exportieren als: ifcbuildingelementproxy; NameOverride: BuildingElementProxy 105; IfcPresentationLayer: 0; IfcDescription: IfcBuildingElementProxy
Phasen - Phase erstellt: Phase 01

# IfcBuildingElementProxy: BuildingElementProxy 106:BuildingElementProxy 106, BuildingElementProxy 106
In: Erdgeschoss
Type - Material: IfcSurfaceStyle #631137
Type - Andere - Kategorie: Allgemeines Modell; Familienname: BuildingElementProxy 106
Type - ID-Daten - Typname: BuildingElementProxy 106
Type - IFC-Parameter - Typ in IFC-Datei exportieren: Vorgabe
Description: IfcBuildingElementProxy
Pset_BuildingElementProxyCommon - Reference: BuildingElementProxy 106; sets with these values: 2
Andere - Typ: BuildingElementProxy 106; Familie: BuildingElementProxy 106; Familie und Typ: BuildingElementProxy 106: BuildingElementProxy 106; Typ-ID: 2538791
Abhängigkeiten - Höhe von Ebene: 0 m; Verschieben mit umliegenden Elementen: no
Bemaßungen - Fläche: 0.000530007 m2; Volumen: 0.00000237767 m3
IFC-Parameter - In IFC-Datei exportieren: Nach Typ; In IFC exportieren als: ifcbuildingelementproxy; NameOverride: BuildingElementProxy 106; IfcPresentationLayer: 0; IfcDescription: IfcBuildingElementProxy
Phasen - Phase erstellt: Phase 01

# IfcBuildingElementProxy: BuildingElementProxy 107:BuildingElementProxy 107, BuildingElementProxy 107
In: Erdgeschoss
Type - Material: IfcSurfaceStyle #631137
Type - Andere - Kategorie: Allgemeines Modell; Familienname: BuildingElementProxy 107
Type - ID-Daten - Typname: BuildingElementProxy 107
Type - IFC-Parameter - Typ in IFC-Datei exportieren: Vorgabe
Description: IfcBuildingElementProxy
Pset_BuildingElementProxyCommon - Reference: BuildingElementProxy 107; sets with these values: 2
Andere - Typ: BuildingElementProxy 107; Familie: BuildingElementProxy 107; Familie und Typ: BuildingElementProxy 107: BuildingElementProxy 107; Typ-ID: 2538798
Abhängigkeiten - Höhe von Ebene: 0 m; Verschieben mit umliegenden Elementen: no
Bemaßungen - Fläche: 0.000530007 m2; Volumen: 0.00000237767 m3
IFC-Parameter - In IFC-Datei exportieren: Nach Typ; In IFC exportieren als: ifcbuildingelementproxy; NameOverride: BuildingElementProxy 107; IfcPresentationLayer: 0; IfcDescription: IfcBuildingElementProxy
Phasen - Phase erstellt: Phase 01

# IfcBuildingElementProxy: BuildingElementProxy 108:BuildingElementProxy 108, BuildingElementProxy 108
In: Erdgeschoss
Type - Material: IfcSurfaceStyle #624289
Type - Andere - Kategorie: Allgemeines Modell; Familienname: BuildingElementProxy 108
Type - ID-Daten - Typname: BuildingElementProxy 108
Type - IFC-Parameter - Typ in IFC-Datei exportieren: Vorgabe
Description: IfcBuildingElementProxy
Pset_BuildingElementProxyCommon - Reference: BuildingElementProxy 108; sets with these values: 2
Andere - Typ: BuildingElementProxy 108; Familie: BuildingElementProxy 108; Familie und Typ: BuildingElementProxy 108: BuildingElementProxy 108; Typ-ID: 2538805
Abhängigkeiten - Höhe von Ebene: 0 m; Verschieben mit umliegenden Elementen: no
Bemaßungen - Fläche: 0.00160546 m2; Volumen: 0.0000092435 m3
IFC-Parameter - In IFC-Datei exportieren: Nach Typ; In IFC exportieren als: ifcbuildingelementproxy; NameOverride: BuildingElementProxy 108; IfcPresentationLayer: 0; IfcDescription: IfcBuildingElementProxy
Phasen - Phase erstellt: Phase 01

# IfcBuildingElementProxy: BuildingElementProxy 109:BuildingElementProxy 109, BuildingElementProxy 109
In: Erdgeschoss
Type - Material: IfcSurfaceStyle #631137
Type - Andere - Kategorie: Allgemeines Modell; Familienname: BuildingElementProxy 109
Type - ID-Daten - Typname: BuildingElementProxy 109
Type - IFC-Parameter - Typ in IFC-Datei exportieren: Vorgabe
Description: IfcBuildingElementProxy
Pset_BuildingElementProxyCommon - Reference: BuildingElementProxy 109; sets with these values: 2
Andere - Typ: BuildingElementProxy 109; Familie: BuildingElementProxy 109; Familie und Typ: BuildingElementProxy 109: BuildingElementProxy 109; Typ-ID: 2538812
Abhängigkeiten - Höhe von Ebene: 0 m; Verschieben mit umliegenden Elementen: no
Bemaßungen - Fläche: 0.000439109 m2; Volumen: 7.40875e-07 m3
IFC-Parameter - In IFC-Datei exportieren: Nach Typ; In IFC exportieren als: ifcbuildingelementproxy; NameOverride: BuildingElementProxy 109; IfcPresentationLayer: 0; IfcDescription: IfcBuildingElementProxy
Phasen - Phase erstellt: Phase 01

# IfcBuildingElementProxy: BuildingElementProxy 10:BuildingElementProxy 10, BuildingElementProxy 10
In: 1. Obergeschoss
Type - Material: IfcSurfaceStyle #220236
Type - Andere - Kategorie: Allgemeines Modell; Familienname: BuildingElementProxy 10
Type - ID-Daten - Typname: BuildingElementProxy 10
Type - IFC-Parameter - Typ in IFC-Datei exportieren: Vorgabe
Description: IfcBuildingElementProxy
Pset_BuildingElementProxyCommon - Reference: BuildingElementProxy 10; sets with these values: 2
Andere - Typ: BuildingElementProxy 10; Familie: BuildingElementProxy 10; Familie und Typ: BuildingElementProxy 10: BuildingElementProxy 10; Typ-ID: 2531754
Abhängigkeiten - Höhe von Ebene: 0 m; Verschieben mit umliegenden Elementen: no
IFC-Parameter - In IFC-Datei exportieren: Nach Typ; In IFC exportieren als: ifcbuildingelementproxy; NameOverride: BuildingElementProxy 10; IfcPresentationLayer: 0-TFT-X_Geometrie; IfcDescription: IfcBuildingElementProxy
Phasen - Phase erstellt: Phase 01

# IfcBuildingElementProxy: BuildingElementProxy 110:BuildingElementProxy 110, BuildingElementProxy 110
In: Erdgeschoss
Type - Material: IfcSurfaceStyle #624289
Type - Andere - Kategorie: Allgemeines Modell; Familienname: BuildingElementProxy 110
Type - ID-Daten - Typname: BuildingElementProxy 110
Type - IFC-Parameter - Typ in IFC-Datei exportieren: Vorgabe
Description: IfcBuildingElementProxy
Pset_BuildingElementProxyCommon - Reference: BuildingElementProxy 110; sets with these values: 2
Andere - Typ: BuildingElementProxy 110; Familie: BuildingElementProxy 110; Familie und Typ: BuildingElementProxy 110: BuildingElementProxy 110; Typ-ID: 2538819
Abhängigkeiten - Höhe von Ebene: 0 m; Verschieben mit umliegenden Elementen: no
Bemaßungen - Fläche: 0.00160152 m2; Volumen: 0.00000465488 m3
IFC-Parameter - In IFC-Datei exportieren: Nach Typ; In IFC exportieren als: ifcbuildingelementproxy; NameOverride: BuildingElementProxy 110; IfcPresentationLayer: 0; IfcDescription: IfcBuildingElementProxy
Phasen - Phase erstellt: Phase 01

# IfcBuildingElementProxy: BuildingElementProxy 111:BuildingElementProxy 111, BuildingElementProxy 111
In: Erdgeschoss
Type - Material: IfcSurfaceStyle #623543
Type - Andere - Kategorie: Allgemeines Modell; Familienname: BuildingElementProxy 111
Type - ID-Daten - Typname: BuildingElementProxy 111
Type - IFC-Parameter - Typ in IFC-Datei exportieren: Vorgabe
Description: IfcBuildingElementProxy
Pset_BuildingElementProxyCommon - Reference: BuildingElementProxy 111; sets with these values: 2
Andere - Typ: BuildingElementProxy 111; Familie: BuildingElementProxy 111; Familie und Typ: BuildingElementProxy 111: BuildingElementProxy 111; Typ-ID: 2538826
Abhängigkeiten - Höhe von Ebene: 0 m; Verschieben mit umliegenden Elementen: no
Bemaßungen - Fläche: 0.00687765 m2; Volumen: 0.0000187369 m3
IFC-Parameter - In IFC-Datei exportieren: Nach Typ; In IFC exportieren als: ifcbuildingelementproxy; NameOverride: BuildingElementProxy 111; IfcPresentationLayer: 0; IfcDescription: IfcBuildingElementProxy
Phasen - Phase erstellt: Phase 01

# IfcBuildingElementProxy: BuildingElementProxy 112:BuildingElementProxy 112, BuildingElementProxy 112
In: Erdgeschoss
Type - Material: IfcSurfaceStyle #626231
Type - Andere - Kategorie: Allgemeines Modell; Familienname: BuildingElementProxy 112
Type - ID-Daten - Typname: BuildingElementProxy 112
Type - IFC-Parameter - Typ in IFC-Datei exportieren: Vorgabe
Description: IfcBuildingElementProxy
Pset_BuildingElementProxyCommon - Reference: BuildingElementProxy 112; sets with these values: 2
Andere - Typ: BuildingElementProxy 112; Familie: BuildingElementProxy 112; Familie und Typ: BuildingElementProxy 112: BuildingElementProxy 112; Typ-ID: 2538833
Abhängigkeiten - Höhe von Ebene: 0 m; Verschieben mit umliegenden Elementen: no
Bemaßungen - Fläche: 0.174591 m2; Volumen: 0.0100035 m3
IFC-Parameter - In IFC-Datei exportieren: Nach Typ; In IFC exportieren als: ifcbuildingelementproxy; NameOverride: BuildingElementProxy 112; IfcPresentationLayer: 0; IfcDescription: IfcBuildingElementProxy
Phasen - Phase erstellt: Phase 01

# IfcBuildingElementProxy: BuildingElementProxy 113:BuildingElementProxy 113, BuildingElementProxy 113
In: Erdgeschoss
Type - Material: IfcSurfaceStyle #623543
Type - Andere - Kategorie: Allgemeines Modell; Familienname: BuildingElementProxy 113
Type - ID-Daten - Typname: BuildingElementProxy 113
Type - IFC-Parameter - Typ in IFC-Datei exportieren: Vorgabe
Description: IfcBuildingElementProxy
Pset_BuildingElementProxyCommon - Reference: BuildingElementProxy 113; sets with these values: 2
Andere - Typ: BuildingElementProxy 113; Familie: BuildingElementProxy 113; Familie und Typ: BuildingElementProxy 113: BuildingElementProxy 113; Typ-ID: 2538840
Abhängigkeiten - Höhe von Ebene: 0 m; Verschieben mit umliegenden Elementen: no
Bemaßungen - Fläche: 0.00687765 m2; Volumen: 0.0000187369 m3
IFC-Parameter - In IFC-Datei exportieren: Nach Typ; In IFC exportieren als: ifcbuildingelementproxy; NameOverride: BuildingElementProxy 113; IfcPresentationLayer: 0; IfcDescription: IfcBuildingElementProxy
Phasen - Phase erstellt: Phase 01

# IfcBuildingElementProxy: BuildingElementProxy 114:BuildingElementProxy 114, BuildingElementProxy 114
In: Erdgeschoss
Type - Material: IfcSurfaceStyle #631137
Type - Andere - Kategorie: Allgemeines Modell; Familienname: BuildingElementProxy 114
Type - ID-Daten - Typname: BuildingElementProxy 114
Type - IFC-Parameter - Typ in IFC-Datei exportieren: Vorgabe
Description: IfcBuildingElementProxy
Pset_BuildingElementProxyCommon - Reference: BuildingElementProxy 114; sets with these values: 2
Andere - Typ: BuildingElementProxy 114; Familie: BuildingElementProxy 114; Familie und Typ: BuildingElementProxy 114: BuildingElementProxy 114; Typ-ID: 2538847
Abhängigkeiten - Höhe von Ebene: 0 m; Verschieben mit umliegenden Elementen: no
Bemaßungen - Fläche: 0.000530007 m2; Volumen: 0.00000237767 m3
IFC-Parameter - In IFC-Datei exportieren: Nach Typ; In IFC exportieren als: ifcbuildingelementproxy; NameOverride: BuildingElementProxy 114; IfcPresentationLayer: 0; IfcDescription: IfcBuildingElementProxy
Phasen - Phase erstellt: Phase 01

# IfcBuildingElementProxy: BuildingElementProxy 115:BuildingElementProxy 115, BuildingElementProxy 115
In: Erdgeschoss
Type - Material: IfcSurfaceStyle #624876
Type - Andere - Kategorie: Allgemeines Modell; Familienname: BuildingElementProxy 115
Type - ID-Daten - Typname: BuildingElementProxy 115
Type - IFC-Parameter - Typ in IFC-Datei exportieren: Vorgabe
Description: IfcBuildingElementProxy
Pset_BuildingElementProxyCommon - Reference: BuildingElementProxy 115; sets with these values: 2
Andere - Typ: BuildingElementProxy 115; Familie: BuildingElementProxy 115; Familie und Typ: BuildingElementProxy 115: BuildingElementProxy 115; Typ-ID: 2538854
Abhängigkeiten - Höhe von Ebene: 0 m; Verschieben mit umliegenden Elementen: no
Bemaßungen - Fläche: 0.200194 m2; Volumen: 0.00324073 m3
IFC-Parameter - In IFC-Datei exportieren: Nach Typ; In IFC exportieren als: ifcbuildingelementproxy; NameOverride: BuildingElementProxy 115; IfcPresentationLayer: 0; IfcDescription: IfcBuildingElementProxy
Phasen - Phase erstellt: Phase 01

# IfcBuildingElementProxy: BuildingElementProxy 116:BuildingElementProxy 116, BuildingElementProxy 116
In: Erdgeschoss
Type - Material: IfcSurfaceStyle #631137
Type - Andere - Kategorie: Allgemeines Modell; Familienname: BuildingElementProxy 116
Type - ID-Daten - Typname: BuildingElementProxy 116
Type - IFC-Parameter - Typ in IFC-Datei exportieren: Vorgabe
Description: IfcBuildingElementProxy
Pset_BuildingElementProxyCommon - Reference: BuildingElementProxy 116; sets with these values: 2
Andere - Typ: BuildingElementProxy 116; Familie: BuildingElementProxy 116; Familie und Typ: BuildingElementProxy 116: BuildingElementProxy 116; Typ-ID: 2538861
Abhängigkeiten - Höhe von Ebene: 0 m; Verschieben mit umliegenden Elementen: no
Bemaßungen - Fläche: 0.00148508 m2; Volumen: 0.00000917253 m3
IFC-Parameter - In IFC-Datei exportieren: Nach Typ; In IFC exportieren als: ifcbuildingelementproxy; NameOverride: BuildingElementProxy 116; IfcPresentationLayer: 0; IfcDescription: IfcBuildingElementProxy
Phasen - Phase erstellt: Phase 01

# IfcBuildingElementProxy: BuildingElementProxy 117:BuildingElementProxy 117, BuildingElementProxy 117
In: Erdgeschoss
Type - Material: IfcSurfaceStyle #626231
Type - Andere - Kategorie: Allgemeines Modell; Familienname: BuildingElementProxy 117
Type - ID-Daten - Typname: BuildingElementProxy 117
Type - IFC-Parameter - Typ in IFC-Datei exportieren: Vorgabe
Description: IfcBuildingElementProxy
Pset_BuildingElementProxyCommon - Reference: BuildingElementProxy 117; sets with these values: 2
Andere - Typ: BuildingElementProxy 117; Familie: BuildingElementProxy 117; Familie und Typ: BuildingElementProxy 117: BuildingElementProxy 117; Typ-ID: 2538868
Abhängigkeiten - Höhe von Ebene: 0 m; Verschieben mit umliegenden Elementen: no
Bemaßungen - Fläche: 0.0729791 m2; Volumen: 0.000638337 m3
IFC-Parameter - In IFC-Datei exportieren: Nach Typ; In IFC exportieren als: ifcbuildingelementproxy; NameOverride: BuildingElementProxy 117; IfcPresentationLayer: 0; IfcDescription: IfcBuildingElementProxy
Phasen - Phase erstellt: Phase 01

# IfcBuildingElementProxy: BuildingElementProxy 118:BuildingElementProxy 118, BuildingElementProxy 118
In: Erdgeschoss
Type - Material: IfcSurfaceStyle #631137
Type - Andere - Kategorie: Allgemeines Modell; Familienname: BuildingElementProxy 118
Type - ID-Daten - Typname: BuildingElementProxy 118
Type - IFC-Parameter - Typ in IFC-Datei exportieren: Vorgabe
Description: IfcBuildingElementProxy
Pset_BuildingElementProxyCommon - Reference: BuildingElementProxy 118; sets with these values: 2
Andere - Typ: BuildingElementProxy 118; Familie: BuildingElementProxy 118; Familie und Typ: BuildingElementProxy 118: BuildingElementProxy 118; Typ-ID: 2538875
Abhängigkeiten - Höhe von Ebene: 0 m; Verschieben mit umliegenden Elementen: no
Bemaßungen - Fläche: 0.000530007 m2; Volumen: 0.00000237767 m3
IFC-Parameter - In IFC-Datei exportieren: Nach Typ; In IFC exportieren als: ifcbuildingelementproxy; NameOverride: BuildingElementProxy 118; IfcPresentationLayer: 0; IfcDescription: IfcBuildingElementProxy
Phasen - Phase erstellt: Phase 01

# IfcBuildingElementProxy: BuildingElementProxy 119:BuildingElementProxy 119, BuildingElementProxy 119
In: Erdgeschoss
Type - Material: IfcSurfaceStyle #623543
Type - Andere - Kategorie: Allgemeines Modell; Familienname: BuildingElementProxy 119
Type - ID-Daten - Typname: BuildingElementProxy 119
Type - IFC-Parameter - Typ in IFC-Datei exportieren: Vorgabe
Description: IfcBuildingElementProxy
Pset_BuildingElementProxyCommon - Reference: BuildingElementProxy 119; sets with these values: 2
Andere - Typ: BuildingElementProxy 119; Familie: BuildingElementProxy 119; Familie und Typ: BuildingElementProxy 119: BuildingElementProxy 119; Typ-ID: 2538882
Abhängigkeiten - Höhe von Ebene: 0 m; Verschieben mit umliegenden Elementen: no
Bemaßungen - Fläche: 0.010758 m2; Volumen: 0.0000135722 m3
IFC-Parameter - In IFC-Datei exportieren: Nach Typ; In IFC exportieren als: ifcbuildingelementproxy; NameOverride: BuildingElementProxy 119; IfcPresentationLayer: 0; IfcDescription: IfcBuildingElementProxy
Phasen - Phase erstellt: Phase 01

# IfcBuildingElementProxy: BuildingElementProxy 11:BuildingElementProxy 11, BuildingElementProxy 11
In: 1. Obergeschoss
Type - Material: IfcSurfaceStyle #220236
Type - Andere - Kategorie: Allgemeines Modell; Familienname: BuildingElementProxy 11
Type - ID-Daten - Typname: BuildingElementProxy 11
Type - IFC-Parameter - Typ in IFC-Datei exportieren: Vorgabe
Description: IfcBuildingElementProxy
Pset_BuildingElementProxyCommon - Reference: BuildingElementProxy 11; sets with these values: 2
Andere - Typ: BuildingElementProxy 11; Familie: BuildingElementProxy 11; Familie und Typ: BuildingElementProxy 11: BuildingElementProxy 11; Typ-ID: 2531831
Abhängigkeiten - Höhe von Ebene: 0 m; Verschieben mit umliegenden Elementen: no
IFC-Parameter - In IFC-Datei exportieren: Nach Typ; In IFC exportieren als: ifcbuildingelementproxy; NameOverride: BuildingElementProxy 11; IfcPresentationLayer: 0-TFT-X_Geometrie; IfcDescription: IfcBuildingElementProxy
Phasen - Phase erstellt: Phase 01

# IfcBuildingElementProxy: BuildingElementProxy 120:BuildingElementProxy 120, BuildingElementProxy 120
In: Erdgeschoss
Type - Material: IfcSurfaceStyle #220236
Type - Andere - Kategorie: Allgemeines Modell; Familienname: BuildingElementProxy 120
Type - ID-Daten - Typname: BuildingElementProxy 120
Type - IFC-Parameter - Typ in IFC-Datei exportieren: Vorgabe
Description: IfcBuildingElementProxy
Pset_BuildingElementProxyCommon - Reference: BuildingElementProxy 120; sets with these values: 2
Andere - Typ: BuildingElementProxy 120; Familie: BuildingElementProxy 120; Familie und Typ: BuildingElementProxy 120: BuildingElementProxy 120; Typ-ID: 2538889
Abhängigkeiten - Höhe von Ebene: 0 m; Verschieben mit umliegenden Elementen: no
Bemaßungen - Fläche: 0.00282063 m2; Volumen: 0.00000407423 m3
IFC-Parameter - In IFC-Datei exportieren: Nach Typ; In IFC exportieren als: ifcbuildingelementproxy; NameOverride: BuildingElementProxy 120; IfcPresentationLayer: 0; IfcDescription: IfcBuildingElementProxy
Phasen - Phase erstellt: Phase 01

# IfcBuildingElementProxy: BuildingElementProxy 121:BuildingElementProxy 121, BuildingElementProxy 121
In: Erdgeschoss
Type - Material: IfcSurfaceStyle #624876
Type - Andere - Kategorie: Allgemeines Modell; Familienname: BuildingElementProxy 121
Type - ID-Daten - Typname: BuildingElementProxy 121
Type - IFC-Parameter - Typ in IFC-Datei exportieren: Vorgabe
Description: IfcBuildingElementProxy
Pset_BuildingElementProxyCommon - Reference: BuildingElementProxy 121; sets with these values: 2
Andere - Typ: BuildingElementProxy 121; Familie: BuildingElementProxy 121; Familie und Typ: BuildingElementProxy 121: BuildingElementProxy 121; Typ-ID: 2538896
Abhängigkeiten - Höhe von Ebene: 0 m; Verschieben mit umliegenden Elementen: no
Bemaßungen - Fläche: 0.0063033 m2; Volumen: 0.000103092 m3
IFC-Parameter - In IFC-Datei exportieren: Nach Typ; In IFC exportieren als: ifcbuildingelementproxy; NameOverride: BuildingElementProxy 121; IfcPresentationLayer: 0; IfcDescription: IfcBuildingElementProxy
Phasen - Phase erstellt: Phase 01

# IfcBuildingElementProxy: BuildingElementProxy 122:BuildingElementProxy 122, BuildingElementProxy 122
In: Erdgeschoss
Type - Material: IfcSurfaceStyle #649647
Type - Andere - Kategorie: Allgemeines Modell; Familienname: BuildingElementProxy 122
Type - ID-Daten - Typname: BuildingElementProxy 122
Type - IFC-Parameter - Typ in IFC-Datei exportieren: Vorgabe
Description: IfcBuildingElementProxy
Pset_BuildingElementProxyCommon - Reference: BuildingElementProxy 122; sets with these values: 2
Andere - Typ: BuildingElementProxy 122; Familie: BuildingElementProxy 122; Familie und Typ: BuildingElementProxy 122: BuildingElementProxy 122; Typ-ID: 2538903
Abhängigkeiten - Höhe von Ebene: 0 m; Verschieben mit umliegenden Elementen: no
Bemaßungen - Fläche: 0.0140767 m2; Volumen: 0.000185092 m3
IFC-Parameter - In IFC-Datei exportieren: Nach Typ; In IFC exportieren als: ifcbuildingelementproxy; NameOverride: BuildingElementProxy 122; IfcPresentationLayer: 0; IfcDescription: IfcBuildingElementProxy
Phasen - Phase erstellt: Phase 01

# IfcBuildingElementProxy: BuildingElementProxy 123:BuildingElementProxy 123, BuildingElementProxy 123
In: Erdgeschoss
Type - Material: IfcSurfaceStyle #649647
Type - Andere - Kategorie: Allgemeines Modell; Familienname: BuildingElementProxy 123
Type - ID-Daten - Typname: BuildingElementProxy 123
Type - IFC-Parameter - Typ in IFC-Datei exportieren: Vorgabe
Description: IfcBuildingElementProxy
Pset_BuildingElementProxyCommon - Reference: BuildingElementProxy 123; sets with these values: 2
Andere - Typ: BuildingElementProxy 123; Familie: BuildingElementProxy 123; Familie und Typ: BuildingElementProxy 123: BuildingElementProxy 123; Typ-ID: 2538910
Abhängigkeiten - Höhe von Ebene: 0 m; Verschieben mit umliegenden Elementen: no
Bemaßungen - Fläche: 0.064131 m2; Volumen: 0.00257661 m3
IFC-Parameter - In IFC-Datei exportieren: Nach Typ; In IFC exportieren als: ifcbuildingelementproxy; NameOverride: BuildingElementProxy 123; IfcPresentationLayer: 0; IfcDescription: IfcBuildingElementProxy
Phasen - Phase erstellt: Phase 01

# IfcBuildingElementProxy: BuildingElementProxy 124:BuildingElementProxy 124, BuildingElementProxy 124
In: Erdgeschoss
Type - Material: IfcSurfaceStyle #623543
Type - Andere - Kategorie: Allgemeines Modell; Familienname: BuildingElementProxy 124
Type - ID-Daten - Typname: BuildingElementProxy 124
Type - IFC-Parameter - Typ in IFC-Datei exportieren: Vorgabe
Description: IfcBuildingElementProxy
Pset_BuildingElementProxyCommon - Reference: BuildingElementProxy 124; sets with these values: 2
Andere - Typ: BuildingElementProxy 124; Familie: BuildingElementProxy 124; Familie und Typ: BuildingElementProxy 124: BuildingElementProxy 124; Typ-ID: 2538917
Abhängigkeiten - Höhe von Ebene: 0 m; Verschieben mit umliegenden Elementen: no
Bemaßungen - Fläche: 0.00687765 m2; Volumen: 0.0000187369 m3
IFC-Parameter - In IFC-Datei exportieren: Nach Typ; In IFC exportieren als: ifcbuildingelementproxy; NameOverride: BuildingElementProxy 124; IfcPresentationLayer: 0; IfcDescription: IfcBuildingElementProxy
Phasen - Phase erstellt: Phase 01

# IfcBuildingElementProxy: BuildingElementProxy 125:BuildingElementProxy 125, BuildingElementProxy 125
In: Erdgeschoss
Type - Material: IfcSurfaceStyle #631137
Type - Andere - Kategorie: Allgemeines Modell; Familienname: BuildingElementProxy 125
Type - ID-Daten - Typname: BuildingElementProxy 125
Type - IFC-Parameter - Typ in IFC-Datei exportieren: Vorgabe
Description: IfcBuildingElementProxy
Pset_BuildingElementProxyCommon - Reference: BuildingElementProxy 125; sets with these values: 2
Andere - Typ: BuildingElementProxy 125; Familie: BuildingElementProxy 125; Familie und Typ: BuildingElementProxy 125: BuildingElementProxy 125; Typ-ID: 2538924
Abhängigkeiten - Höhe von Ebene: 0 m; Verschieben mit umliegenden Elementen: no
Bemaßungen - Fläche: 0.000439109 m2; Volumen: 7.40875e-07 m3
IFC-Parameter - In IFC-Datei exportieren: Nach Typ; In IFC exportieren als: ifcbuildingelementproxy; NameOverride: BuildingElementProxy 125; IfcPresentationLayer: 0; IfcDescription: IfcBuildingElementProxy
Phasen - Phase erstellt: Phase 01

# IfcBuildingElementProxy: BuildingElementProxy 126:BuildingElementProxy 126, BuildingElementProxy 126
In: Erdgeschoss
Type - Material: IfcSurfaceStyle #623543
Type - Andere - Kategorie: Allgemeines Modell; Familienname: BuildingElementProxy 126
Type - ID-Daten - Typname: BuildingElementProxy 126
Type - IFC-Parameter - Typ in IFC-Datei exportieren: Vorgabe
Description: IfcBuildingElementProxy
Pset_BuildingElementProxyCommon - Reference: BuildingElementProxy 126; sets with these values: 2
Andere - Typ: BuildingElementProxy 126; Familie: BuildingElementProxy 126; Familie und Typ: BuildingElementProxy 126: BuildingElementProxy 126; Typ-ID: 2538931
Abhängigkeiten - Höhe von Ebene: 0 m; Verschieben mit umliegenden Elementen: no
Bemaßungen - Fläche: 0.0614416 m2; Volumen: 0.00315739 m3
IFC-Parameter - In IFC-Datei exportieren: Nach Typ; In IFC exportieren als: ifcbuildingelementproxy; NameOverride: BuildingElementProxy 126; IfcPresentationLayer: 0; IfcDescription: IfcBuildingElementProxy
Phasen - Phase erstellt: Phase 01

# IfcBuildingElementProxy: BuildingElementProxy 127:BuildingElementProxy 127, BuildingElementProxy 127
In: Erdgeschoss
Type - Material: IfcSurfaceStyle #623543
Type - Andere - Kategorie: Allgemeines Modell; Familienname: BuildingElementProxy 127
Type - ID-Daten - Typname: BuildingElementProxy 127
Type - IFC-Parameter - Typ in IFC-Datei exportieren: Vorgabe
Description: IfcBuildingElementProxy
Pset_BuildingElementProxyCommon - Reference: BuildingElementProxy 127; sets with these values: 2
Andere - Typ: BuildingElementProxy 127; Familie: BuildingElementProxy 127; Familie und Typ: BuildingElementProxy 127: BuildingElementProxy 127; Typ-ID: 2538938
Abhängigkeiten - Höhe von Ebene: 0 m; Verschieben mit umliegenden Elementen: no
Bemaßungen - Fläche: 0.00687765 m2; Volumen: 0.0000187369 m3
IFC-Parameter - In IFC-Datei exportieren: Nach Typ; In IFC exportieren als: ifcbuildingelementproxy; NameOverride: BuildingElementProxy 127; IfcPresentationLayer: 0; IfcDescription: IfcBuildingElementProxy
Phasen - Phase erstellt: Phase 01

# IfcBuildingElementProxy: BuildingElementProxy 128:BuildingElementProxy 128, BuildingElementProxy 128
In: Erdgeschoss
Type - Material: IfcSurfaceStyle #623543
Type - Andere - Kategorie: Allgemeines Modell; Familienname: BuildingElementProxy 128
Type - ID-Daten - Typname: BuildingElementProxy 128
Type - IFC-Parameter - Typ in IFC-Datei exportieren: Vorgabe
Description: IfcBuildingElementProxy
Pset_BuildingElementProxyCommon - Reference: BuildingElementProxy 128; sets with these values: 2
Andere - Typ: BuildingElementProxy 128; Familie: BuildingElementProxy 128; Familie und Typ: BuildingElementProxy 128: BuildingElementProxy 128; Typ-ID: 2538945
Abhängigkeiten - Höhe von Ebene: 0 m; Verschieben mit umliegenden Elementen: no
Bemaßungen - Fläche: 0.00687765 m2; Volumen: 0.0000187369 m3
IFC-Parameter - In IFC-Datei exportieren: Nach Typ; In IFC exportieren als: ifcbuildingelementproxy; NameOverride: BuildingElementProxy 128; IfcPresentationLayer: 0; IfcDescription: IfcBuildingElementProxy
Phasen - Phase erstellt: Phase 01

# IfcBuildingElementProxy: BuildingElementProxy 129:BuildingElementProxy 129, BuildingElementProxy 129
In: Erdgeschoss
Type - Material: IfcSurfaceStyle #626231
Type - Andere - Kategorie: Allgemeines Modell; Familienname: BuildingElementProxy 129
Type - ID-Daten - Typname: BuildingElementProxy 129
Type - IFC-Parameter - Typ in IFC-Datei exportieren: Vorgabe
Description: IfcBuildingElementProxy
Pset_BuildingElementProxyCommon - Reference: BuildingElementProxy 129; sets with these values: 2
Andere - Typ: BuildingElementProxy 129; Familie: BuildingElementProxy 129; Familie und Typ: BuildingElementProxy 129: BuildingElementProxy 129; Typ-ID: 2538952
Abhängigkeiten - Höhe von Ebene: 0 m; Verschieben mit umliegenden Elementen: no
Bemaßungen - Fläche: 0.123579 m2; Volumen: 0.00304414 m3
IFC-Parameter - In IFC-Datei exportieren: Nach Typ; In IFC exportieren als: ifcbuildingelementproxy; NameOverride: BuildingElementProxy 129; IfcPresentationLayer: 0; IfcDescription: IfcBuildingElementProxy
Phasen - Phase erstellt: Phase 01

# IfcBuildingElementProxy: BuildingElementProxy 130:BuildingElementProxy 130, BuildingElementProxy 130
In: Erdgeschoss
Type - Material: IfcSurfaceStyle #623543
Type - Andere - Kategorie: Allgemeines Modell; Familienname: BuildingElementProxy 130
Type - ID-Daten - Typname: BuildingElementProxy 130
Type - IFC-Parameter - Typ in IFC-Datei exportieren: Vorgabe
Description: IfcBuildingElementProxy
Pset_BuildingElementProxyCommon - Reference: BuildingElementProxy 130; sets with these values: 2
Andere - Typ: BuildingElementProxy 130; Familie: BuildingElementProxy 130; Familie und Typ: BuildingElementProxy 130: BuildingElementProxy 130; Typ-ID: 2538959
Abhängigkeiten - Höhe von Ebene: 0 m; Verschieben mit umliegenden Elementen: no
Bemaßungen - Fläche: 0.00687765 m2; Volumen: 0.0000187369 m3
IFC-Parameter - In IFC-Datei exportieren: Nach Typ; In IFC exportieren als: ifcbuildingelementproxy; NameOverride: BuildingElementProxy 130; IfcPresentationLayer: 0; IfcDescription: IfcBuildingElementProxy
Phasen - Phase erstellt: Phase 01

# IfcBuildingElementProxy: BuildingElementProxy 131:BuildingElementProxy 131, BuildingElementProxy 131
In: Erdgeschoss
Type - Material: IfcSurfaceStyle #623543
Type - Andere - Kategorie: Allgemeines Modell; Familienname: BuildingElementProxy 131
Type - ID-Daten - Typname: BuildingElementProxy 131
Type - IFC-Parameter - Typ in IFC-Datei exportieren: Vorgabe
Description: IfcBuildingElementProxy
Pset_BuildingElementProxyCommon - Reference: BuildingElementProxy 131; sets with these values: 2
Andere - Typ: BuildingElementProxy 131; Familie: BuildingElementProxy 131; Familie und Typ: BuildingElementProxy 131: BuildingElementProxy 131; Typ-ID: 2538966
Abhängigkeiten - Höhe von Ebene: 0 m; Verschieben mit umliegenden Elementen: no
Bemaßungen - Fläche: 0.00687765 m2; Volumen: 0.0000187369 m3
IFC-Parameter - In IFC-Datei exportieren: Nach Typ; In IFC exportieren als: ifcbuildingelementproxy; NameOverride: BuildingElementProxy 131; IfcPresentationLayer: 0; IfcDescription: IfcBuildingElementProxy
Phasen - Phase erstellt: Phase 01

# IfcBuildingElementProxy: BuildingElementProxy 132:BuildingElementProxy 132, BuildingElementProxy 132
In: Erdgeschoss
Type - Material: IfcSurfaceStyle #220236
Type - Andere - Kategorie: Allgemeines Modell; Familienname: BuildingElementProxy 132
Type - ID-Daten - Typname: BuildingElementProxy 132
Type - IFC-Parameter - Typ in IFC-Datei exportieren: Vorgabe
Description: IfcBuildingElementProxy
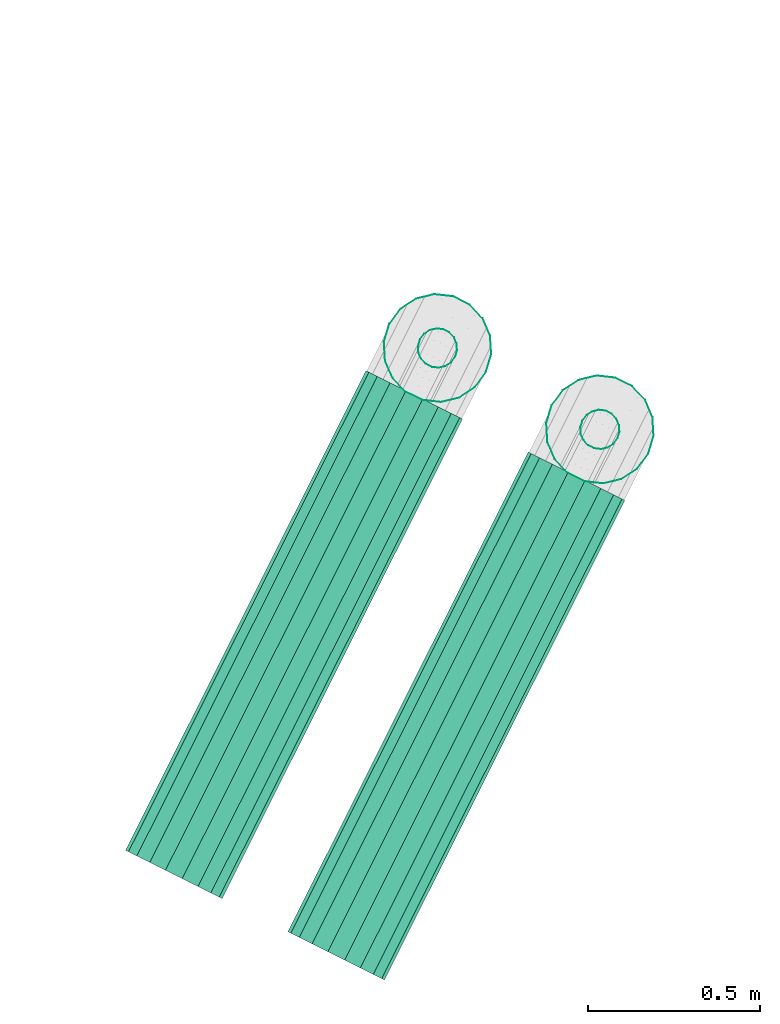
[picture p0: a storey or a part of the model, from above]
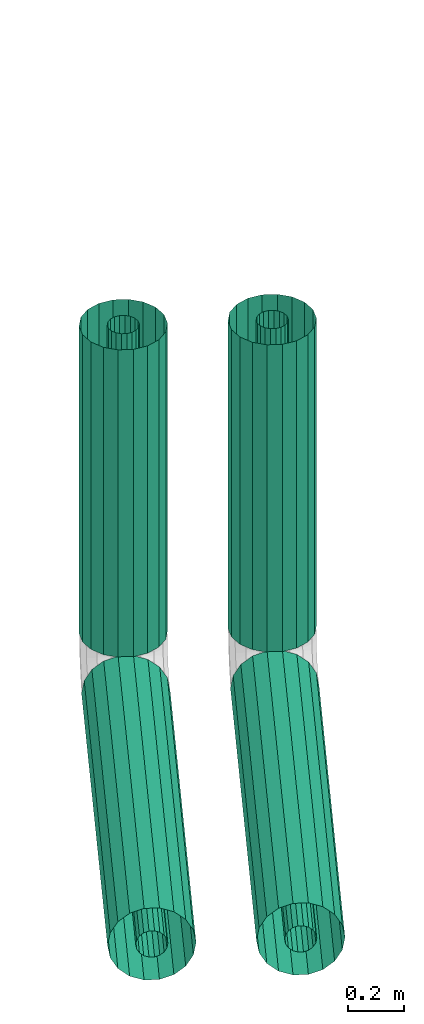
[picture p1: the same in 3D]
Properties of the parts of a building model (IFC2X3), part 2 of 23

# IfcBuildingElementProxy: BuildingElementProxy 132:BuildingElementProxy 132, BuildingElementProxy 132
Pset_BuildingElementProxyCommon - Reference: BuildingElementProxy 132; sets with these values: 2
Andere - Typ: BuildingElementProxy 132; Familie: BuildingElementProxy 132; Familie und Typ: BuildingElementProxy 132: BuildingElementProxy 132; Typ-ID: 2538973
Abhängigkeiten - Höhe von Ebene: 0 m; Verschieben mit umliegenden Elementen: no
Bemaßungen - Fläche: 0.000149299 m2
IFC-Parameter - In IFC-Datei exportieren: Nach Typ; In IFC exportieren als: ifcbuildingelementproxy; NameOverride: BuildingElementProxy 132; IfcPresentationLayer: 0; IfcDescription: IfcBuildingElementProxy
Phasen - Phase erstellt: Phase 01

# IfcBuildingElementProxy: BuildingElementProxy 133:BuildingElementProxy 133, BuildingElementProxy 133
In: Erdgeschoss
Type - Material: IfcSurfaceStyle #623543
Type - Andere - Kategorie: Allgemeines Modell; Familienname: BuildingElementProxy 133
Type - ID-Daten - Typname: BuildingElementProxy 133
Type - IFC-Parameter - Typ in IFC-Datei exportieren: Vorgabe
Description: IfcBuildingElementProxy
Pset_BuildingElementProxyCommon - Reference: BuildingElementProxy 133; sets with these values: 2
Andere - Typ: BuildingElementProxy 133; Familie: BuildingElementProxy 133; Familie und Typ: BuildingElementProxy 133: BuildingElementProxy 133; Typ-ID: 2538980
Abhängigkeiten - Höhe von Ebene: 0 m; Verschieben mit umliegenden Elementen: no
Bemaßungen - Fläche: 0.00687765 m2; Volumen: 0.0000187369 m3
IFC-Parameter - In IFC-Datei exportieren: Nach Typ; In IFC exportieren als: ifcbuildingelementproxy; NameOverride: BuildingElementProxy 133; IfcPresentationLayer: 0; IfcDescription: IfcBuildingElementProxy
Phasen - Phase erstellt: Phase 01

# IfcBuildingElementProxy: BuildingElementProxy 134:BuildingElementProxy 134, BuildingElementProxy 134
In: Erdgeschoss
Type - Material: IfcSurfaceStyle #623543
Type - Andere - Kategorie: Allgemeines Modell; Familienname: BuildingElementProxy 134
Type - ID-Daten - Typname: BuildingElementProxy 134
Type - IFC-Parameter - Typ in IFC-Datei exportieren: Vorgabe
Description: IfcBuildingElementProxy
Pset_BuildingElementProxyCommon - Reference: BuildingElementProxy 134; sets with these values: 2
Andere - Typ: BuildingElementProxy 134; Familie: BuildingElementProxy 134; Familie und Typ: BuildingElementProxy 134: BuildingElementProxy 134; Typ-ID: 2538987
Abhängigkeiten - Höhe von Ebene: 0 m; Verschieben mit umliegenden Elementen: no
Bemaßungen - Fläche: 0.00687765 m2; Volumen: 0.0000187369 m3
IFC-Parameter - In IFC-Datei exportieren: Nach Typ; In IFC exportieren als: ifcbuildingelementproxy; NameOverride: BuildingElementProxy 134; IfcPresentationLayer: 0; IfcDescription: IfcBuildingElementProxy
Phasen - Phase erstellt: Phase 01

# IfcBuildingElementProxy: BuildingElementProxy 135:BuildingElementProxy 135, BuildingElementProxy 135
In: Erdgeschoss
Type - Material: IfcSurfaceStyle #623543
Type - Andere - Kategorie: Allgemeines Modell; Familienname: BuildingElementProxy 135
Type - ID-Daten - Typname: BuildingElementProxy 135
Type - IFC-Parameter - Typ in IFC-Datei exportieren: Vorgabe
Description: IfcBuildingElementProxy
Pset_BuildingElementProxyCommon - Reference: BuildingElementProxy 135; sets with these values: 2
Andere - Typ: BuildingElementProxy 135; Familie: BuildingElementProxy 135; Familie und Typ: BuildingElementProxy 135: BuildingElementProxy 135; Typ-ID: 2538994
Abhängigkeiten - Höhe von Ebene: 0 m; Verschieben mit umliegenden Elementen: no
Bemaßungen - Fläche: 0.00687765 m2; Volumen: 0.0000187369 m3
IFC-Parameter - In IFC-Datei exportieren: Nach Typ; In IFC exportieren als: ifcbuildingelementproxy; NameOverride: BuildingElementProxy 135; IfcPresentationLayer: 0; IfcDescription: IfcBuildingElementProxy
Phasen - Phase erstellt: Phase 01

# IfcBuildingElementProxy: BuildingElementProxy 136:BuildingElementProxy 136, BuildingElementProxy 136
In: Erdgeschoss
Type - Material: IfcSurfaceStyle #623543
Type - Andere - Kategorie: Allgemeines Modell; Familienname: BuildingElementProxy 136
Type - ID-Daten - Typname: BuildingElementProxy 136
Type - IFC-Parameter - Typ in IFC-Datei exportieren: Vorgabe
Description: IfcBuildingElementProxy
Pset_BuildingElementProxyCommon - Reference: BuildingElementProxy 136; sets with these values: 2
Andere - Typ: BuildingElementProxy 136; Familie: BuildingElementProxy 136; Familie und Typ: BuildingElementProxy 136: BuildingElementProxy 136; Typ-ID: 2539001
Abhängigkeiten - Höhe von Ebene: 0 m; Verschieben mit umliegenden Elementen: no
Bemaßungen - Fläche: 0.00687765 m2; Volumen: 0.0000187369 m3
IFC-Parameter - In IFC-Datei exportieren: Nach Typ; In IFC exportieren als: ifcbuildingelementproxy; NameOverride: BuildingElementProxy 136; IfcPresentationLayer: 0; IfcDescription: IfcBuildingElementProxy
Phasen - Phase erstellt: Phase 01

# IfcBuildingElementProxy: BuildingElementProxy 137:BuildingElementProxy 137, BuildingElementProxy 137
In: Erdgeschoss
Type - Material: IfcSurfaceStyle #626231
Type - Andere - Kategorie: Allgemeines Modell; Familienname: BuildingElementProxy 137
Type - ID-Daten - Typname: BuildingElementProxy 137
Type - IFC-Parameter - Typ in IFC-Datei exportieren: Vorgabe
Description: IfcBuildingElementProxy
Pset_BuildingElementProxyCommon - Reference: BuildingElementProxy 137; sets with these values: 2
Andere - Typ: BuildingElementProxy 137; Familie: BuildingElementProxy 137; Familie und Typ: BuildingElementProxy 137: BuildingElementProxy 137; Typ-ID: 2539008
Abhängigkeiten - Höhe von Ebene: 0 m; Verschieben mit umliegenden Elementen: no
Bemaßungen - Fläche: 0.135547 m2; Volumen: 0.00324928 m3
IFC-Parameter - In IFC-Datei exportieren: Nach Typ; In IFC exportieren als: ifcbuildingelementproxy; NameOverride: BuildingElementProxy 137; IfcPresentationLayer: 0; IfcDescription: IfcBuildingElementProxy
Phasen - Phase erstellt: Phase 01

# IfcBuildingElementProxy: BuildingElementProxy 18:BuildingElementProxy 18, BuildingElementProxy 18
In: 1. Obergeschoss
Type - Material: IfcSurfaceStyle #270045
Type - Andere - Kategorie: Allgemeines Modell; Familienname: BuildingElementProxy 18
Type - ID-Daten - Typname: BuildingElementProxy 18
Type - IFC-Parameter - Typ in IFC-Datei exportieren: Vorgabe
Description: Ausdehnungsgefäß
Pset_BuildingElementProxyCommon - Reference: BuildingElementProxy 18; sets with these values: 2
Andere - Typ: BuildingElementProxy 18; Familie: BuildingElementProxy 18; Familie und Typ: BuildingElementProxy 18: BuildingElementProxy 18; Typ-ID: 2533345
Abhängigkeiten - Höhe von Ebene: 0 m; Verschieben mit umliegenden Elementen: no
Bemaßungen - Fläche: 4.39168 m2; Volumen: 1.8992 m3
IFC-Parameter - In IFC-Datei exportieren: Nach Typ; In IFC exportieren als: ifcbuildingelementproxy; NameOverride: BuildingElementProxy 18; IfcPresentationLayer: 0-TFT-S_Einrichtungsgegenstände; Pset MEP.Name: Ausdehnungsgefäß; IfcDescription: Ausdehnungsgefäß
Phasen - Phase erstellt: Phase 01

# IfcBuildingElementProxy: BuildingElementProxy 19:BuildingElementProxy 19, BuildingElementProxy 19
In: 1. Obergeschoss
Type - Material: IfcSurfaceStyle #270045
Type - Andere - Kategorie: Allgemeines Modell; Familienname: BuildingElementProxy 19
Type - ID-Daten - Typname: BuildingElementProxy 19
Type - IFC-Parameter - Typ in IFC-Datei exportieren: Vorgabe
Description: Ausdehnungsgefäß
Pset_BuildingElementProxyCommon - Reference: BuildingElementProxy 19; sets with these values: 2
Andere - Typ: BuildingElementProxy 19; Familie: BuildingElementProxy 19; Familie und Typ: BuildingElementProxy 19: BuildingElementProxy 19; Typ-ID: 2533402
Abhängigkeiten - Höhe von Ebene: 0 m; Verschieben mit umliegenden Elementen: no
Bemaßungen - Fläche: 4.39168 m2; Volumen: 1.8992 m3
IFC-Parameter - In IFC-Datei exportieren: Nach Typ; In IFC exportieren als: ifcbuildingelementproxy; NameOverride: BuildingElementProxy 19; IfcPresentationLayer: 0-TFT-S_Einrichtungsgegenstände; Pset MEP.Name: Ausdehnungsgefäß; IfcDescription: Ausdehnungsgefäß
Phasen - Phase erstellt: Phase 01

# IfcBuildingElementProxy: BuildingElementProxy 1:BuildingElementProxy 1, BuildingElementProxy 1
In: 1. Obergeschoss
Type - Material: IfcSurfaceStyle #220236
Type - Andere - Kategorie: Allgemeines Modell; Familienname: BuildingElementProxy 1
Type - ID-Daten - Typname: BuildingElementProxy 1
Type - IFC-Parameter - Typ in IFC-Datei exportieren: Vorgabe
Description: IfcBuildingElementProxy
Pset_BuildingElementProxyCommon - Reference: BuildingElementProxy 1; sets with these values: 2
Andere - Typ: BuildingElementProxy 1; Familie: BuildingElementProxy 1; Familie und Typ: BuildingElementProxy 1: BuildingElementProxy 1; Typ-ID: 2531596
Abhängigkeiten - Höhe von Ebene: 0 m; Verschieben mit umliegenden Elementen: no
IFC-Parameter - In IFC-Datei exportieren: Nach Typ; In IFC exportieren als: ifcbuildingelementproxy; NameOverride: BuildingElementProxy 1; IfcPresentationLayer: 0-TFT-X_Geometrie; IfcDescription: IfcBuildingElementProxy
Phasen - Phase erstellt: Phase 01

# IfcBuildingElementProxy: BuildingElementProxy 30:BuildingElementProxy 30, BuildingElementProxy 30
In: Erdgeschoss
Type - Material: IfcSurfaceStyle #220236
Type - Andere - Kategorie: Allgemeines Modell; Familienname: BuildingElementProxy 30
Type - ID-Daten - Typname: BuildingElementProxy 30
Type - IFC-Parameter - Typ in IFC-Datei exportieren: Vorgabe
Description: IfcBuildingElementProxy
Pset_BuildingElementProxyCommon - Reference: BuildingElementProxy 30; sets with these values: 2
Andere - Typ: BuildingElementProxy 30; Familie: BuildingElementProxy 30; Familie und Typ: BuildingElementProxy 30: BuildingElementProxy 30; Typ-ID: 2536968
Abhängigkeiten - Höhe von Ebene: 0 m; Verschieben mit umliegenden Elementen: no
IFC-Parameter - In IFC-Datei exportieren: Nach Typ; In IFC exportieren als: ifcbuildingelementproxy; NameOverride: BuildingElementProxy 30; IfcPresentationLayer: 0-TFT-X_Geometrie; IfcDescription: IfcBuildingElementProxy
Phasen - Phase erstellt: Phase 01

# IfcBuildingElementProxy: BuildingElementProxy 31:BuildingElementProxy 31, BuildingElementProxy 31
In: Erdgeschoss
Type - Material: IfcSurfaceStyle #220236
Type - Andere - Kategorie: Allgemeines Modell; Familienname: BuildingElementProxy 31
Type - ID-Daten - Typname: BuildingElementProxy 31
Type - IFC-Parameter - Typ in IFC-Datei exportieren: Vorgabe
Description: IfcBuildingElementProxy
Pset_BuildingElementProxyCommon - Reference: BuildingElementProxy 31; sets with these values: 2
Andere - Typ: BuildingElementProxy 31; Familie: BuildingElementProxy 31; Familie und Typ: BuildingElementProxy 31: BuildingElementProxy 31; Typ-ID: 2537248
Abhängigkeiten - Höhe von Ebene: 0 m; Verschieben mit umliegenden Elementen: no
IFC-Parameter - In IFC-Datei exportieren: Nach Typ; In IFC exportieren als: ifcbuildingelementproxy; NameOverride: BuildingElementProxy 31; IfcPresentationLayer: 0-TFT-X_Geometrie; IfcDescription: IfcBuildingElementProxy
Phasen - Phase erstellt: Phase 01

# IfcBuildingElementProxy: BuildingElementProxy 32:BuildingElementProxy 32, BuildingElementProxy 32
In: Erdgeschoss
Type - Material: IfcSurfaceStyle #623543
Type - Andere - Kategorie: Allgemeines Modell; Familienname: BuildingElementProxy 32
Type - ID-Daten - Typname: BuildingElementProxy 32
Type - IFC-Parameter - Typ in IFC-Datei exportieren: Vorgabe
Description: IfcBuildingElementProxy
Pset_BuildingElementProxyCommon - Reference: BuildingElementProxy 32; sets with these values: 2
Andere - Typ: BuildingElementProxy 32; Familie: BuildingElementProxy 32; Familie und Typ: BuildingElementProxy 32: BuildingElementProxy 32; Typ-ID: 2538266
Abhängigkeiten - Höhe von Ebene: 0 m; Verschieben mit umliegenden Elementen: no
Bemaßungen - Fläche: 0.00687765 m2; Volumen: 0.0000187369 m3
IFC-Parameter - In IFC-Datei exportieren: Nach Typ; In IFC exportieren als: ifcbuildingelementproxy; NameOverride: BuildingElementProxy 32; IfcPresentationLayer: 0; IfcDescription: IfcBuildingElementProxy
Phasen - Phase erstellt: Phase 01

# IfcBuildingElementProxy: BuildingElementProxy 33:BuildingElementProxy 33, BuildingElementProxy 33
In: Erdgeschoss
Type - Material: IfcSurfaceStyle #623543
Type - Andere - Kategorie: Allgemeines Modell; Familienname: BuildingElementProxy 33
Type - ID-Daten - Typname: BuildingElementProxy 33
Type - IFC-Parameter - Typ in IFC-Datei exportieren: Vorgabe
Description: IfcBuildingElementProxy
Pset_BuildingElementProxyCommon - Reference: BuildingElementProxy 33; sets with these values: 2
Andere - Typ: BuildingElementProxy 33; Familie: BuildingElementProxy 33; Familie und Typ: BuildingElementProxy 33: BuildingElementProxy 33; Typ-ID: 2538274
Abhängigkeiten - Höhe von Ebene: 0 m; Verschieben mit umliegenden Elementen: no
Bemaßungen - Fläche: 0.0190098 m2; Volumen: 0.0000417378 m3
IFC-Parameter - In IFC-Datei exportieren: Nach Typ; In IFC exportieren als: ifcbuildingelementproxy; NameOverride: BuildingElementProxy 33; IfcPresentationLayer: 0; IfcDescription: IfcBuildingElementProxy
Phasen - Phase erstellt: Phase 01

# IfcBuildingElementProxy: BuildingElementProxy 34:BuildingElementProxy 34, BuildingElementProxy 34
In: Erdgeschoss
Type - Material: IfcSurfaceStyle #624289
Type - Andere - Kategorie: Allgemeines Modell; Familienname: BuildingElementProxy 34
Type - ID-Daten - Typname: BuildingElementProxy 34
Type - IFC-Parameter - Typ in IFC-Datei exportieren: Vorgabe
Description: IfcBuildingElementProxy
Pset_BuildingElementProxyCommon - Reference: BuildingElementProxy 34; sets with these values: 2
Andere - Typ: BuildingElementProxy 34; Familie: BuildingElementProxy 34; Familie und Typ: BuildingElementProxy 34: BuildingElementProxy 34; Typ-ID: 2538281
Abhängigkeiten - Höhe von Ebene: 0 m; Verschieben mit umliegenden Elementen: no
Bemaßungen - Fläche: 0.22259 m2; Volumen: 0.00298771 m3
IFC-Parameter - In IFC-Datei exportieren: Nach Typ; In IFC exportieren als: ifcbuildingelementproxy; NameOverride: BuildingElementProxy 34; IfcPresentationLayer: 0; IfcDescription: IfcBuildingElementProxy
Phasen - Phase erstellt: Phase 01

# IfcBuildingElementProxy: BuildingElementProxy 35:BuildingElementProxy 35, BuildingElementProxy 35
In: Erdgeschoss
Type - Material: IfcSurfaceStyle #624876
Type - Andere - Kategorie: Allgemeines Modell; Familienname: BuildingElementProxy 35
Type - ID-Daten - Typname: BuildingElementProxy 35
Type - IFC-Parameter - Typ in IFC-Datei exportieren: Vorgabe
Description: IfcBuildingElementProxy
Pset_BuildingElementProxyCommon - Reference: BuildingElementProxy 35; sets with these values: 2
Andere - Typ: BuildingElementProxy 35; Familie: BuildingElementProxy 35; Familie und Typ: BuildingElementProxy 35: BuildingElementProxy 35; Typ-ID: 2538289
Abhängigkeiten - Höhe von Ebene: 0 m; Verschieben mit umliegenden Elementen: no
Bemaßungen - Fläche: 0.000997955 m2; Volumen: 0.00000176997 m3
IFC-Parameter - In IFC-Datei exportieren: Nach Typ; In IFC exportieren als: ifcbuildingelementproxy; NameOverride: BuildingElementProxy 35; IfcPresentationLayer: 0; IfcDescription: IfcBuildingElementProxy
Phasen - Phase erstellt: Phase 01

# IfcBuildingElementProxy: BuildingElementProxy 36:BuildingElementProxy 36, BuildingElementProxy 36
In: Erdgeschoss
Type - Material: IfcSurfaceStyle #626231
Type - Andere - Kategorie: Allgemeines Modell; Familienname: BuildingElementProxy 36
Type - ID-Daten - Typname: BuildingElementProxy 36
Type - IFC-Parameter - Typ in IFC-Datei exportieren: Vorgabe
Description: IfcBuildingElementProxy
Pset_BuildingElementProxyCommon - Reference: BuildingElementProxy 36; sets with these values: 2
Andere - Typ: BuildingElementProxy 36; Familie: BuildingElementProxy 36; Familie und Typ: BuildingElementProxy 36: BuildingElementProxy 36; Typ-ID: 2538297
Abhängigkeiten - Höhe von Ebene: 0 m; Verschieben mit umliegenden Elementen: no
Bemaßungen - Fläche: 0.0300089 m2; Volumen: 0.000528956 m3
IFC-Parameter - In IFC-Datei exportieren: Nach Typ; In IFC exportieren als: ifcbuildingelementproxy; NameOverride: BuildingElementProxy 36; IfcPresentationLayer: 0; IfcDescription: IfcBuildingElementProxy
Phasen - Phase erstellt: Phase 01

# IfcBuildingElementProxy: BuildingElementProxy 37:BuildingElementProxy 37, BuildingElementProxy 37
In: Erdgeschoss
Type - Material: IfcSurfaceStyle #626231
Type - Andere - Kategorie: Allgemeines Modell; Familienname: BuildingElementProxy 37
Type - ID-Daten - Typname: BuildingElementProxy 37
Type - IFC-Parameter - Typ in IFC-Datei exportieren: Vorgabe
Description: IfcBuildingElementProxy
Pset_BuildingElementProxyCommon - Reference: BuildingElementProxy 37; sets with these values: 2
Andere - Typ: BuildingElementProxy 37; Familie: BuildingElementProxy 37; Familie und Typ: BuildingElementProxy 37: BuildingElementProxy 37; Typ-ID: 2538305
Abhängigkeiten - Höhe von Ebene: 0 m; Verschieben mit umliegenden Elementen: no
Bemaßungen - Fläche: 0.117708 m2; Volumen: 0.00298537 m3
IFC-Parameter - In IFC-Datei exportieren: Nach Typ; In IFC exportieren als: ifcbuildingelementproxy; NameOverride: BuildingElementProxy 37; IfcPresentationLayer: 0; IfcDescription: IfcBuildingElementProxy
Phasen - Phase erstellt: Phase 01

# IfcBuildingElementProxy: BuildingElementProxy 38:BuildingElementProxy 38, BuildingElementProxy 38
In: Erdgeschoss
Type - Material: IfcSurfaceStyle #631137
Type - Andere - Kategorie: Allgemeines Modell; Familienname: BuildingElementProxy 38
Type - ID-Daten - Typname: BuildingElementProxy 38
Type - IFC-Parameter - Typ in IFC-Datei exportieren: Vorgabe
Description: IfcBuildingElementProxy
Pset_BuildingElementProxyCommon - Reference: BuildingElementProxy 38; sets with these values: 2
Andere - Typ: BuildingElementProxy 38; Familie: BuildingElementProxy 38; Familie und Typ: BuildingElementProxy 38: BuildingElementProxy 38; Typ-ID: 2538312
Abhängigkeiten - Höhe von Ebene: 0 m; Verschieben mit umliegenden Elementen: no
Bemaßungen - Fläche: 0.090148 m2; Volumen: 0.000756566 m3
IFC-Parameter - In IFC-Datei exportieren: Nach Typ; In IFC exportieren als: ifcbuildingelementproxy; NameOverride: BuildingElementProxy 38; IfcPresentationLayer: 0; IfcDescription: IfcBuildingElementProxy
Phasen - Phase erstellt: Phase 01

# IfcBuildingElementProxy: BuildingElementProxy 39:BuildingElementProxy 39, BuildingElementProxy 39
In: Erdgeschoss
Type - Material: IfcSurfaceStyle #623543
Type - Andere - Kategorie: Allgemeines Modell; Familienname: BuildingElementProxy 39
Type - ID-Daten - Typname: BuildingElementProxy 39
Type - IFC-Parameter - Typ in IFC-Datei exportieren: Vorgabe
Description: IfcBuildingElementProxy
Pset_BuildingElementProxyCommon - Reference: BuildingElementProxy 39; sets with these values: 2
Andere - Typ: BuildingElementProxy 39; Familie: BuildingElementProxy 39; Familie und Typ: BuildingElementProxy 39: BuildingElementProxy 39; Typ-ID: 2538320
Abhängigkeiten - Höhe von Ebene: 0 m; Verschieben mit umliegenden Elementen: no
Bemaßungen - Fläche: 0.00421083 m2; Volumen: 0.0000473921 m3
IFC-Parameter - In IFC-Datei exportieren: Nach Typ; In IFC exportieren als: ifcbuildingelementproxy; NameOverride: BuildingElementProxy 39; IfcPresentationLayer: 0; IfcDescription: IfcBuildingElementProxy
Phasen - Phase erstellt: Phase 01

# IfcBuildingElementProxy: BuildingElementProxy 40:BuildingElementProxy 40, BuildingElementProxy 40
In: Erdgeschoss
Type - Material: IfcSurfaceStyle #623543
Type - Andere - Kategorie: Allgemeines Modell; Familienname: BuildingElementProxy 40
Type - ID-Daten - Typname: BuildingElementProxy 40
Type - IFC-Parameter - Typ in IFC-Datei exportieren: Vorgabe
Description: IfcBuildingElementProxy
Pset_BuildingElementProxyCommon - Reference: BuildingElementProxy 40; sets with these values: 2
Andere - Typ: BuildingElementProxy 40; Familie: BuildingElementProxy 40; Familie und Typ: BuildingElementProxy 40: BuildingElementProxy 40; Typ-ID: 2538327
Abhängigkeiten - Höhe von Ebene: 0 m; Verschieben mit umliegenden Elementen: no
IFC-Parameter - In IFC-Datei exportieren: Nach Typ; In IFC exportieren als: ifcbuildingelementproxy; NameOverride: BuildingElementProxy 40; IfcPresentationLayer: 0; IfcDescription: IfcBuildingElementProxy
Phasen - Phase erstellt: Phase 01

# IfcBuildingElementProxy: BuildingElementProxy 41:BuildingElementProxy 41, BuildingElementProxy 41
In: Erdgeschoss
Type - Material: IfcSurfaceStyle #631137
Type - Andere - Kategorie: Allgemeines Modell; Familienname: BuildingElementProxy 41
Type - ID-Daten - Typname: BuildingElementProxy 41
Type - IFC-Parameter - Typ in IFC-Datei exportieren: Vorgabe
Description: IfcBuildingElementProxy
Pset_BuildingElementProxyCommon - Reference: BuildingElementProxy 41; sets with these values: 2
Andere - Typ: BuildingElementProxy 41; Familie: BuildingElementProxy 41; Familie und Typ: BuildingElementProxy 41: BuildingElementProxy 41; Typ-ID: 2538334
Abhängigkeiten - Höhe von Ebene: 0 m; Verschieben mit umliegenden Elementen: no
Bemaßungen - Fläche: 0.00148731 m2; Volumen: 0.00000918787 m3
IFC-Parameter - In IFC-Datei exportieren: Nach Typ; In IFC exportieren als: ifcbuildingelementproxy; NameOverride: BuildingElementProxy 41; IfcPresentationLayer: 0; IfcDescription: IfcBuildingElementProxy
Phasen - Phase erstellt: Phase 01

# IfcBuildingElementProxy: BuildingElementProxy 42:BuildingElementProxy 42, BuildingElementProxy 42
In: Erdgeschoss
Type - Material: IfcSurfaceStyle #631137
Type - Andere - Kategorie: Allgemeines Modell; Familienname: BuildingElementProxy 42
Type - ID-Daten - Typname: BuildingElementProxy 42
Type - IFC-Parameter - Typ in IFC-Datei exportieren: Vorgabe
Description: IfcBuildingElementProxy
Pset_BuildingElementProxyCommon - Reference: BuildingElementProxy 42; sets with these values: 2
Andere - Typ: BuildingElementProxy 42; Familie: BuildingElementProxy 42; Familie und Typ: BuildingElementProxy 42: BuildingElementProxy 42; Typ-ID: 2538341
Abhängigkeiten - Höhe von Ebene: 0 m; Verschieben mit umliegenden Elementen: no
Bemaßungen - Fläche: 0.00480338 m2; Volumen: 0.0000108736 m3
IFC-Parameter - In IFC-Datei exportieren: Nach Typ; In IFC exportieren als: ifcbuildingelementproxy; NameOverride: BuildingElementProxy 42; IfcPresentationLayer: 0; IfcDescription: IfcBuildingElementProxy
Phasen - Phase erstellt: Phase 01

# IfcBuildingElementProxy: BuildingElementProxy 43:BuildingElementProxy 43, BuildingElementProxy 43
In: Erdgeschoss
Type - Material: IfcSurfaceStyle #623543
Type - Andere - Kategorie: Allgemeines Modell; Familienname: BuildingElementProxy 43
Type - ID-Daten - Typname: BuildingElementProxy 43
Type - IFC-Parameter - Typ in IFC-Datei exportieren: Vorgabe
Description: IfcBuildingElementProxy
Pset_BuildingElementProxyCommon - Reference: BuildingElementProxy 43; sets with these values: 2
Andere - Typ: BuildingElementProxy 43; Familie: BuildingElementProxy 43; Familie und Typ: BuildingElementProxy 43: BuildingElementProxy 43; Typ-ID: 2538348
Abhängigkeiten - Höhe von Ebene: 0 m; Verschieben mit umliegenden Elementen: no
IFC-Parameter - In IFC-Datei exportieren: Nach Typ; In IFC exportieren als: ifcbuildingelementproxy; NameOverride: BuildingElementProxy 43; IfcPresentationLayer: 0; IfcDescription: IfcBuildingElementProxy
Phasen - Phase erstellt: Phase 01

# IfcBuildingElementProxy: BuildingElementProxy 44:BuildingElementProxy 44, BuildingElementProxy 44
In: Erdgeschoss
Type - Material: IfcSurfaceStyle #623543
Type - Andere - Kategorie: Allgemeines Modell; Familienname: BuildingElementProxy 44
Type - ID-Daten - Typname: BuildingElementProxy 44
Type - IFC-Parameter - Typ in IFC-Datei exportieren: Vorgabe
Description: IfcBuildingElementProxy
Pset_BuildingElementProxyCommon - Reference: BuildingElementProxy 44; sets with these values: 2
Andere - Typ: BuildingElementProxy 44; Familie: BuildingElementProxy 44; Familie und Typ: BuildingElementProxy 44: BuildingElementProxy 44; Typ-ID: 2538355
Abhängigkeiten - Höhe von Ebene: 0 m; Verschieben mit umliegenden Elementen: no
Bemaßungen - Fläche: 0.00687765 m2; Volumen: 0.0000187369 m3
IFC-Parameter - In IFC-Datei exportieren: Nach Typ; In IFC exportieren als: ifcbuildingelementproxy; NameOverride: BuildingElementProxy 44; IfcPresentationLayer: 0; IfcDescription: IfcBuildingElementProxy
Phasen - Phase erstellt: Phase 01

# IfcBuildingElementProxy: BuildingElementProxy 45:BuildingElementProxy 45, BuildingElementProxy 45
In: Erdgeschoss
Type - Material: IfcSurfaceStyle #631137
Type - Andere - Kategorie: Allgemeines Modell; Familienname: BuildingElementProxy 45
Type - ID-Daten - Typname: BuildingElementProxy 45
Type - IFC-Parameter - Typ in IFC-Datei exportieren: Vorgabe
Description: IfcBuildingElementProxy
Pset_BuildingElementProxyCommon - Reference: BuildingElementProxy 45; sets with these values: 2
Andere - Typ: BuildingElementProxy 45; Familie: BuildingElementProxy 45; Familie und Typ: BuildingElementProxy 45: BuildingElementProxy 45; Typ-ID: 2538362
Abhängigkeiten - Höhe von Ebene: 0 m; Verschieben mit umliegenden Elementen: no
Bemaßungen - Fläche: 0.000439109 m2; Volumen: 7.40875e-07 m3
IFC-Parameter - In IFC-Datei exportieren: Nach Typ; In IFC exportieren als: ifcbuildingelementproxy; NameOverride: BuildingElementProxy 45; IfcPresentationLayer: 0; IfcDescription: IfcBuildingElementProxy
Phasen - Phase erstellt: Phase 01

# IfcBuildingElementProxy: BuildingElementProxy 46:BuildingElementProxy 46, BuildingElementProxy 46
In: Erdgeschoss
Type - Material: IfcSurfaceStyle #624876
Type - Andere - Kategorie: Allgemeines Modell; Familienname: BuildingElementProxy 46
Type - ID-Daten - Typname: BuildingElementProxy 46
Type - IFC-Parameter - Typ in IFC-Datei exportieren: Vorgabe
Description: IfcBuildingElementProxy
Pset_BuildingElementProxyCommon - Reference: BuildingElementProxy 46; sets with these values: 2
Andere - Typ: BuildingElementProxy 46; Familie: BuildingElementProxy 46; Familie und Typ: BuildingElementProxy 46: BuildingElementProxy 46; Typ-ID: 2538369
Abhängigkeiten - Höhe von Ebene: 0 m; Verschieben mit umliegenden Elementen: no
Bemaßungen - Fläche: 0.00167763 m2; Volumen: 0.0000136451 m3
IFC-Parameter - In IFC-Datei exportieren: Nach Typ; In IFC exportieren als: ifcbuildingelementproxy; NameOverride: BuildingElementProxy 46; IfcPresentationLayer: 0; IfcDescription: IfcBuildingElementProxy
Phasen - Phase erstellt: Phase 01

# IfcBuildingElementProxy: BuildingElementProxy 47:BuildingElementProxy 47, BuildingElementProxy 47
In: Erdgeschoss
Type - Material: IfcSurfaceStyle #623543
Type - Andere - Kategorie: Allgemeines Modell; Familienname: BuildingElementProxy 47
Type - ID-Daten - Typname: BuildingElementProxy 47
Type - IFC-Parameter - Typ in IFC-Datei exportieren: Vorgabe
Description: IfcBuildingElementProxy
Pset_BuildingElementProxyCommon - Reference: BuildingElementProxy 47; sets with these values: 2
Andere - Typ: BuildingElementProxy 47; Familie: BuildingElementProxy 47; Familie und Typ: BuildingElementProxy 47: BuildingElementProxy 47; Typ-ID: 2538376
Abhängigkeiten - Höhe von Ebene: 0 m; Verschieben mit umliegenden Elementen: no
Bemaßungen - Fläche: 0.00687765 m2; Volumen: 0.0000187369 m3
IFC-Parameter - In IFC-Datei exportieren: Nach Typ; In IFC exportieren als: ifcbuildingelementproxy; NameOverride: BuildingElementProxy 47; IfcPresentationLayer: 0; IfcDescription: IfcBuildingElementProxy
Phasen - Phase erstellt: Phase 01

# IfcBuildingElementProxy: BuildingElementProxy 48:BuildingElementProxy 48, BuildingElementProxy 48
In: Erdgeschoss
Type - Material: IfcSurfaceStyle #626231
Type - Andere - Kategorie: Allgemeines Modell; Familienname: BuildingElementProxy 48
Type - ID-Daten - Typname: BuildingElementProxy 48
Type - IFC-Parameter - Typ in IFC-Datei exportieren: Vorgabe
Description: IfcBuildingElementProxy
Pset_BuildingElementProxyCommon - Reference: BuildingElementProxy 48; sets with these values: 2
Andere - Typ: BuildingElementProxy 48; Familie: BuildingElementProxy 48; Familie und Typ: BuildingElementProxy 48: BuildingElementProxy 48; Typ-ID: 2538383
Abhängigkeiten - Höhe von Ebene: 0 m; Verschieben mit umliegenden Elementen: no
Bemaßungen - Fläche: 0.00760332 m2; Volumen: 0.00004062 m3
IFC-Parameter - In IFC-Datei exportieren: Nach Typ; In IFC exportieren als: ifcbuildingelementproxy; NameOverride: BuildingElementProxy 48; IfcPresentationLayer: 0; IfcDescription: IfcBuildingElementProxy
Phasen - Phase erstellt: Phase 01

# IfcBuildingElementProxy: BuildingElementProxy 49:BuildingElementProxy 49, BuildingElementProxy 49
In: Erdgeschoss
Type - Material: IfcSurfaceStyle #623543
Type - Andere - Kategorie: Allgemeines Modell; Familienname: BuildingElementProxy 49
Type - ID-Daten - Typname: BuildingElementProxy 49
Type - IFC-Parameter - Typ in IFC-Datei exportieren: Vorgabe
Description: IfcBuildingElementProxy
Pset_BuildingElementProxyCommon - Reference: BuildingElementProxy 49; sets with these values: 2
Andere - Typ: BuildingElementProxy 49; Familie: BuildingElementProxy 49; Familie und Typ: BuildingElementProxy 49: BuildingElementProxy 49; Typ-ID: 2538390
Abhängigkeiten - Höhe von Ebene: 0 m; Verschieben mit umliegenden Elementen: no
IFC-Parameter - In IFC-Datei exportieren: Nach Typ; In IFC exportieren als: ifcbuildingelementproxy; NameOverride: BuildingElementProxy 49; IfcPresentationLayer: 0; IfcDescription: IfcBuildingElementProxy
Phasen - Phase erstellt: Phase 01

# IfcBuildingElementProxy: BuildingElementProxy 50:BuildingElementProxy 50, BuildingElementProxy 50
In: Erdgeschoss
Type - Material: IfcSurfaceStyle #623543
Type - Andere - Kategorie: Allgemeines Modell; Familienname: BuildingElementProxy 50
Type - ID-Daten - Typname: BuildingElementProxy 50
Type - IFC-Parameter - Typ in IFC-Datei exportieren: Vorgabe
Description: IfcBuildingElementProxy
Pset_BuildingElementProxyCommon - Reference: BuildingElementProxy 50; sets with these values: 2
Andere - Typ: BuildingElementProxy 50; Familie: BuildingElementProxy 50; Familie und Typ: BuildingElementProxy 50: BuildingElementProxy 50; Typ-ID: 2538397
Abhängigkeiten - Höhe von Ebene: 0 m; Verschieben mit umliegenden Elementen: no
Bemaßungen - Fläche: 0.00687765 m2; Volumen: 0.0000187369 m3
IFC-Parameter - In IFC-Datei exportieren: Nach Typ; In IFC exportieren als: ifcbuildingelementproxy; NameOverride: BuildingElementProxy 50; IfcPresentationLayer: 0; IfcDescription: IfcBuildingElementProxy
Phasen - Phase erstellt: Phase 01

# IfcBuildingElementProxy: BuildingElementProxy 51:BuildingElementProxy 51, BuildingElementProxy 51
In: Erdgeschoss
Type - Material: IfcSurfaceStyle #623543
Type - Andere - Kategorie: Allgemeines Modell; Familienname: BuildingElementProxy 51
Type - ID-Daten - Typname: BuildingElementProxy 51
Type - IFC-Parameter - Typ in IFC-Datei exportieren: Vorgabe
Description: IfcBuildingElementProxy
Pset_BuildingElementProxyCommon - Reference: BuildingElementProxy 51; sets with these values: 2
Andere - Typ: BuildingElementProxy 51; Familie: BuildingElementProxy 51; Familie und Typ: BuildingElementProxy 51: BuildingElementProxy 51; Typ-ID: 2538404
Abhängigkeiten - Höhe von Ebene: 0 m; Verschieben mit umliegenden Elementen: no
Bemaßungen - Fläche: 0.0216736 m2; Volumen: 0.000613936 m3
IFC-Parameter - In IFC-Datei exportieren: Nach Typ; In IFC exportieren als: ifcbuildingelementproxy; NameOverride: BuildingElementProxy 51; IfcPresentationLayer: 0; IfcDescription: IfcBuildingElementProxy
Phasen - Phase erstellt: Phase 01

# IfcBuildingElementProxy: BuildingElementProxy 52:BuildingElementProxy 52, BuildingElementProxy 52
In: Erdgeschoss
Type - Material: IfcSurfaceStyle #623543
Type - Andere - Kategorie: Allgemeines Modell; Familienname: BuildingElementProxy 52
Type - ID-Daten - Typname: BuildingElementProxy 52
Type - IFC-Parameter - Typ in IFC-Datei exportieren: Vorgabe
Description: IfcBuildingElementProxy
Pset_BuildingElementProxyCommon - Reference: BuildingElementProxy 52; sets with these values: 2
Andere - Typ: BuildingElementProxy 52; Familie: BuildingElementProxy 52; Familie und Typ: BuildingElementProxy 52: BuildingElementProxy 52; Typ-ID: 2538411
Abhängigkeiten - Höhe von Ebene: 0 m; Verschieben mit umliegenden Elementen: no
Bemaßungen - Fläche: 0.00687765 m2; Volumen: 0.0000187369 m3
IFC-Parameter - In IFC-Datei exportieren: Nach Typ; In IFC exportieren als: ifcbuildingelementproxy; NameOverride: BuildingElementProxy 52; IfcPresentationLayer: 0; IfcDescription: IfcBuildingElementProxy
Phasen - Phase erstellt: Phase 01

# IfcBuildingElementProxy: BuildingElementProxy 53:BuildingElementProxy 53, BuildingElementProxy 53
In: Erdgeschoss
Type - Material: IfcSurfaceStyle #631137
Type - Andere - Kategorie: Allgemeines Modell; Familienname: BuildingElementProxy 53
Type - ID-Daten - Typname: BuildingElementProxy 53
Type - IFC-Parameter - Typ in IFC-Datei exportieren: Vorgabe
Description: IfcBuildingElementProxy
Pset_BuildingElementProxyCommon - Reference: BuildingElementProxy 53; sets with these values: 2
Andere - Typ: BuildingElementProxy 53; Familie: BuildingElementProxy 53; Familie und Typ: BuildingElementProxy 53: BuildingElementProxy 53; Typ-ID: 2538418
Abhängigkeiten - Höhe von Ebene: 0 m; Verschieben mit umliegenden Elementen: no
IFC-Parameter - In IFC-Datei exportieren: Nach Typ; In IFC exportieren als: ifcbuildingelementproxy; NameOverride: BuildingElementProxy 53; IfcPresentationLayer: 0; IfcDescription: IfcBuildingElementProxy
Phasen - Phase erstellt: Phase 01

# IfcBuildingElementProxy: BuildingElementProxy 54:BuildingElementProxy 54, BuildingElementProxy 54
In: Erdgeschoss
Type - Material: IfcSurfaceStyle #626231
Type - Andere - Kategorie: Allgemeines Modell; Familienname: BuildingElementProxy 54
Type - ID-Daten - Typname: BuildingElementProxy 54
Type - IFC-Parameter - Typ in IFC-Datei exportieren: Vorgabe
Description: IfcBuildingElementProxy
Pset_BuildingElementProxyCommon - Reference: BuildingElementProxy 54; sets with these values: 2
Andere - Typ: BuildingElementProxy 54; Familie: BuildingElementProxy 54; Familie und Typ: BuildingElementProxy 54: BuildingElementProxy 54; Typ-ID: 2538425
Abhängigkeiten - Höhe von Ebene: 0 m; Verschieben mit umliegenden Elementen: no
Bemaßungen - Fläche: 0.00443146 m2; Volumen: 0.0000637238 m3
IFC-Parameter - In IFC-Datei exportieren: Nach Typ; In IFC exportieren als: ifcbuildingelementproxy; NameOverride: BuildingElementProxy 54; IfcPresentationLayer: 0; IfcDescription: IfcBuildingElementProxy
Phasen - Phase erstellt: Phase 01

# IfcBuildingElementProxy: BuildingElementProxy 55:BuildingElementProxy 55, BuildingElementProxy 55
In: Erdgeschoss
Type - Material: IfcSurfaceStyle #623543
Type - Andere - Kategorie: Allgemeines Modell; Familienname: BuildingElementProxy 55
Type - ID-Daten - Typname: BuildingElementProxy 55
Type - IFC-Parameter - Typ in IFC-Datei exportieren: Vorgabe
Description: IfcBuildingElementProxy
Pset_BuildingElementProxyCommon - Reference: BuildingElementProxy 55; sets with these values: 2
Andere - Typ: BuildingElementProxy 55; Familie: BuildingElementProxy 55; Familie und Typ: BuildingElementProxy 55: BuildingElementProxy 55; Typ-ID: 2538432
Abhängigkeiten - Höhe von Ebene: 0 m; Verschieben mit umliegenden Elementen: no
Bemaßungen - Fläche: 0.00687765 m2; Volumen: 0.0000187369 m3
IFC-Parameter - In IFC-Datei exportieren: Nach Typ; In IFC exportieren als: ifcbuildingelementproxy; NameOverride: BuildingElementProxy 55; IfcPresentationLayer: 0; IfcDescription: IfcBuildingElementProxy
Phasen - Phase erstellt: Phase 01

# IfcBuildingElementProxy: BuildingElementProxy 56:BuildingElementProxy 56, BuildingElementProxy 56
In: Erdgeschoss
Type - Material: IfcSurfaceStyle #649647
Type - Andere - Kategorie: Allgemeines Modell; Familienname: BuildingElementProxy 56
Type - ID-Daten - Typname: BuildingElementProxy 56
Type - IFC-Parameter - Typ in IFC-Datei exportieren: Vorgabe
Description: IfcBuildingElementProxy
Pset_BuildingElementProxyCommon - Reference: BuildingElementProxy 56; sets with these values: 2
Andere - Typ: BuildingElementProxy 56; Familie: BuildingElementProxy 56; Familie und Typ: BuildingElementProxy 56: BuildingElementProxy 56; Typ-ID: 2538439
Abhängigkeiten - Höhe von Ebene: 0 m; Verschieben mit umliegenden Elementen: no
Bemaßungen - Fläche: 0.102308 m2; Volumen: 0.00707921 m3
IFC-Parameter - In IFC-Datei exportieren: Nach Typ; In IFC exportieren als: ifcbuildingelementproxy; NameOverride: BuildingElementProxy 56; IfcPresentationLayer: 0; IfcDescription: IfcBuildingElementProxy
Phasen - Phase erstellt: Phase 01

# IfcBuildingElementProxy: BuildingElementProxy 57:BuildingElementProxy 57, BuildingElementProxy 57
In: Erdgeschoss
Type - Material: IfcSurfaceStyle #220236
Type - Andere - Kategorie: Allgemeines Modell; Familienname: BuildingElementProxy 57
Type - ID-Daten - Typname: BuildingElementProxy 57
Type - IFC-Parameter - Typ in IFC-Datei exportieren: Vorgabe
Description: IfcBuildingElementProxy
Pset_BuildingElementProxyCommon - Reference: BuildingElementProxy 57; sets with these values: 2
Andere - Typ: BuildingElementProxy 57; Familie: BuildingElementProxy 57; Familie und Typ: BuildingElementProxy 57: BuildingElementProxy 57; Typ-ID: 2538447
Abhängigkeiten - Höhe von Ebene: 0 m; Verschieben mit umliegenden Elementen: no
Bemaßungen - Fläche: 0.000149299 m2
IFC-Parameter - In IFC-Datei exportieren: Nach Typ; In IFC exportieren als: ifcbuildingelementproxy; NameOverride: BuildingElementProxy 57; IfcPresentationLayer: 0; IfcDescription: IfcBuildingElementProxy
Phasen - Phase erstellt: Phase 01

# IfcBuildingElementProxy: BuildingElementProxy 58:BuildingElementProxy 58, BuildingElementProxy 58
In: Erdgeschoss
Type - Material: IfcSurfaceStyle #623543
Type - Andere - Kategorie: Allgemeines Modell; Familienname: BuildingElementProxy 58
Type - ID-Daten - Typname: BuildingElementProxy 58
Type - IFC-Parameter - Typ in IFC-Datei exportieren: Vorgabe
Description: IfcBuildingElementProxy
Pset_BuildingElementProxyCommon - Reference: BuildingElementProxy 58; sets with these values: 2
Andere - Typ: BuildingElementProxy 58; Familie: BuildingElementProxy 58; Familie und Typ: BuildingElementProxy 58: BuildingElementProxy 58; Typ-ID: 2538454
Abhängigkeiten - Höhe von Ebene: 0 m; Verschieben mit umliegenden Elementen: no
Bemaßungen - Fläche: 0.137565 m2; Volumen: 0.00658776 m3
IFC-Parameter - In IFC-Datei exportieren: Nach Typ; In IFC exportieren als: ifcbuildingelementproxy; NameOverride: BuildingElementProxy 58; IfcPresentationLayer: 0; IfcDescription: IfcBuildingElementProxy
Phasen - Phase erstellt: Phase 01

# IfcBuildingElementProxy: BuildingElementProxy 59:BuildingElementProxy 59, BuildingElementProxy 59
In: Erdgeschoss
Type - Material: IfcSurfaceStyle #623543
Type - Andere - Kategorie: Allgemeines Modell; Familienname: BuildingElementProxy 59
Type - ID-Daten - Typname: BuildingElementProxy 59
Type - IFC-Parameter - Typ in IFC-Datei exportieren: Vorgabe
Description: IfcBuildingElementProxy
Pset_BuildingElementProxyCommon - Reference: BuildingElementProxy 59; sets with these values: 2
Andere - Typ: BuildingElementProxy 59; Familie: BuildingElementProxy 59; Familie und Typ: BuildingElementProxy 59: BuildingElementProxy 59; Typ-ID: 2538461
Abhängigkeiten - Höhe von Ebene: 0 m; Verschieben mit umliegenden Elementen: no
Bemaßungen - Fläche: 0.00687765 m2; Volumen: 0.0000187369 m3
IFC-Parameter - In IFC-Datei exportieren: Nach Typ; In IFC exportieren als: ifcbuildingelementproxy; NameOverride: BuildingElementProxy 59; IfcPresentationLayer: 0; IfcDescription: IfcBuildingElementProxy
Phasen - Phase erstellt: Phase 01

# IfcBuildingElementProxy: BuildingElementProxy 60:BuildingElementProxy 60, BuildingElementProxy 60
In: Erdgeschoss
Type - Material: IfcSurfaceStyle #631137
Type - Andere - Kategorie: Allgemeines Modell; Familienname: BuildingElementProxy 60
Type - ID-Daten - Typname: BuildingElementProxy 60
Type - IFC-Parameter - Typ in IFC-Datei exportieren: Vorgabe
Description: IfcBuildingElementProxy
Pset_BuildingElementProxyCommon - Reference: BuildingElementProxy 60; sets with these values: 2
Andere - Typ: BuildingElementProxy 60; Familie: BuildingElementProxy 60; Familie und Typ: BuildingElementProxy 60: BuildingElementProxy 60; Typ-ID: 2538468
Abhängigkeiten - Höhe von Ebene: 0 m; Verschieben mit umliegenden Elementen: no
Bemaßungen - Fläche: 0.00100548 m2; Volumen: 9.57839e-08 m3
IFC-Parameter - In IFC-Datei exportieren: Nach Typ; In IFC exportieren als: ifcbuildingelementproxy; NameOverride: BuildingElementProxy 60; IfcPresentationLayer: 0; IfcDescription: IfcBuildingElementProxy
Phasen - Phase erstellt: Phase 01

# IfcBuildingElementProxy: BuildingElementProxy 61:BuildingElementProxy 61, BuildingElementProxy 61
In: Erdgeschoss
Type - Material: IfcSurfaceStyle #623543
Type - Andere - Kategorie: Allgemeines Modell; Familienname: BuildingElementProxy 61
Type - ID-Daten - Typname: BuildingElementProxy 61
Type - IFC-Parameter - Typ in IFC-Datei exportieren: Vorgabe
Description: IfcBuildingElementProxy
Pset_BuildingElementProxyCommon - Reference: BuildingElementProxy 61; sets with these values: 2
Andere - Typ: BuildingElementProxy 61; Familie: BuildingElementProxy 61; Familie und Typ: BuildingElementProxy 61: BuildingElementProxy 61; Typ-ID: 2538475
Abhängigkeiten - Höhe von Ebene: 0 m; Verschieben mit umliegenden Elementen: no
Bemaßungen - Fläche: 0.000643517 m2; Volumen: 0.00000337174 m3
IFC-Parameter - In IFC-Datei exportieren: Nach Typ; In IFC exportieren als: ifcbuildingelementproxy; NameOverride: BuildingElementProxy 61; IfcPresentationLayer: 0; IfcDescription: IfcBuildingElementProxy
Phasen - Phase erstellt: Phase 01

# IfcBuildingElementProxy: BuildingElementProxy 62:BuildingElementProxy 62, BuildingElementProxy 62
In: Erdgeschoss
Type - Material: IfcSurfaceStyle #220236
Type - Andere - Kategorie: Allgemeines Modell; Familienname: BuildingElementProxy 62
Type - ID-Daten - Typname: BuildingElementProxy 62
Type - IFC-Parameter - Typ in IFC-Datei exportieren: Vorgabe
Description: IfcBuildingElementProxy
Pset_BuildingElementProxyCommon - Reference: BuildingElementProxy 62; sets with these values: 2
Andere - Typ: BuildingElementProxy 62; Familie: BuildingElementProxy 62; Familie und Typ: BuildingElementProxy 62: BuildingElementProxy 62; Typ-ID: 2538482
Abhängigkeiten - Höhe von Ebene: 0 m; Verschieben mit umliegenden Elementen: no
Bemaßungen - Fläche: 0.0131497 m2; Volumen: 0.0000124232 m3
IFC-Parameter - In IFC-Datei exportieren: Nach Typ; In IFC exportieren als: ifcbuildingelementproxy; NameOverride: BuildingElementProxy 62; IfcPresentationLayer: 0; IfcDescription: IfcBuildingElementProxy
Phasen - Phase erstellt: Phase 01

# IfcBuildingElementProxy: BuildingElementProxy 63:BuildingElementProxy 63, BuildingElementProxy 63
In: Erdgeschoss
Type - Material: IfcSurfaceStyle #649647
Type - Andere - Kategorie: Allgemeines Modell; Familienname: BuildingElementProxy 63
Type - ID-Daten - Typname: BuildingElementProxy 63
Type - IFC-Parameter - Typ in IFC-Datei exportieren: Vorgabe
Description: IfcBuildingElementProxy
Pset_BuildingElementProxyCommon - Reference: BuildingElementProxy 63; sets with these values: 2
Andere - Typ: BuildingElementProxy 63; Familie: BuildingElementProxy 63; Familie und Typ: BuildingElementProxy 63: BuildingElementProxy 63; Typ-ID: 2538489
Abhängigkeiten - Höhe von Ebene: 0 m; Verschieben mit umliegenden Elementen: no
Bemaßungen - Fläche: 0.0214209 m2; Volumen: 0.000566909 m3
IFC-Parameter - In IFC-Datei exportieren: Nach Typ; In IFC exportieren als: ifcbuildingelementproxy; NameOverride: BuildingElementProxy 63; IfcPresentationLayer: 0; IfcDescription: IfcBuildingElementProxy
Phasen - Phase erstellt: Phase 01

# IfcBuildingElementProxy: BuildingElementProxy 64:BuildingElementProxy 64, BuildingElementProxy 64
In: Erdgeschoss
Type - Material: IfcSurfaceStyle #623543
Type - Andere - Kategorie: Allgemeines Modell; Familienname: BuildingElementProxy 64
Type - ID-Daten - Typname: BuildingElementProxy 64
Type - IFC-Parameter - Typ in IFC-Datei exportieren: Vorgabe
Description: IfcBuildingElementProxy
Pset_BuildingElementProxyCommon - Reference: BuildingElementProxy 64; sets with these values: 2
Andere - Typ: BuildingElementProxy 64; Familie: BuildingElementProxy 64; Familie und Typ: BuildingElementProxy 64: BuildingElementProxy 64; Typ-ID: 2538496
Abhängigkeiten - Höhe von Ebene: 0 m; Verschieben mit umliegenden Elementen: no
IFC-Parameter - In IFC-Datei exportieren: Nach Typ; In IFC exportieren als: ifcbuildingelementproxy; NameOverride: BuildingElementProxy 64; IfcPresentationLayer: 0; IfcDescription: IfcBuildingElementProxy
Phasen - Phase erstellt: Phase 01

# IfcBuildingElementProxy: BuildingElementProxy 65:BuildingElementProxy 65, BuildingElementProxy 65
In: Erdgeschoss
Type - Material: IfcSurfaceStyle #631137
Type - Andere - Kategorie: Allgemeines Modell; Familienname: BuildingElementProxy 65
Type - ID-Daten - Typname: BuildingElementProxy 65
Type - IFC-Parameter - Typ in IFC-Datei exportieren: Vorgabe
Description: IfcBuildingElementProxy
Pset_BuildingElementProxyCommon - Reference: BuildingElementProxy 65; sets with these values: 2
Andere - Typ: BuildingElementProxy 65; Familie: BuildingElementProxy 65; Familie und Typ: BuildingElementProxy 65: BuildingElementProxy 65; Typ-ID: 2538503
Abhängigkeiten - Höhe von Ebene: 0 m; Verschieben mit umliegenden Elementen: no
Bemaßungen - Fläche: 0.000439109 m2; Volumen: 7.40875e-07 m3
IFC-Parameter - In IFC-Datei exportieren: Nach Typ; In IFC exportieren als: ifcbuildingelementproxy; NameOverride: BuildingElementProxy 65; IfcPresentationLayer: 0; IfcDescription: IfcBuildingElementProxy
Phasen - Phase erstellt: Phase 01

# IfcBuildingElementProxy: BuildingElementProxy 66:BuildingElementProxy 66, BuildingElementProxy 66
In: Erdgeschoss
Type - Material: IfcSurfaceStyle #623543
Type - Andere - Kategorie: Allgemeines Modell; Familienname: BuildingElementProxy 66
Type - ID-Daten - Typname: BuildingElementProxy 66
Type - IFC-Parameter - Typ in IFC-Datei exportieren: Vorgabe
Description: IfcBuildingElementProxy
Pset_BuildingElementProxyCommon - Reference: BuildingElementProxy 66; sets with these values: 2
Andere - Typ: BuildingElementProxy 66; Familie: BuildingElementProxy 66; Familie und Typ: BuildingElementProxy 66: BuildingElementProxy 66; Typ-ID: 2538510
Abhängigkeiten - Höhe von Ebene: 0 m; Verschieben mit umliegenden Elementen: no
Bemaßungen - Fläche: 0.00687765 m2; Volumen: 0.0000187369 m3
IFC-Parameter - In IFC-Datei exportieren: Nach Typ; In IFC exportieren als: ifcbuildingelementproxy; NameOverride: BuildingElementProxy 66; IfcPresentationLayer: 0; IfcDescription: IfcBuildingElementProxy
Phasen - Phase erstellt: Phase 01

# IfcBuildingElementProxy: BuildingElementProxy 67:BuildingElementProxy 67, BuildingElementProxy 67
In: Erdgeschoss
Type - Material: IfcSurfaceStyle #631137
Type - Andere - Kategorie: Allgemeines Modell; Familienname: BuildingElementProxy 67
Type - ID-Daten - Typname: BuildingElementProxy 67
Type - IFC-Parameter - Typ in IFC-Datei exportieren: Vorgabe
Description: IfcBuildingElementProxy
Pset_BuildingElementProxyCommon - Reference: BuildingElementProxy 67; sets with these values: 2
Andere - Typ: BuildingElementProxy 67; Familie: BuildingElementProxy 67; Familie und Typ: BuildingElementProxy 67: BuildingElementProxy 67; Typ-ID: 2538517
Abhängigkeiten - Höhe von Ebene: 0 m; Verschieben mit umliegenden Elementen: no
Bemaßungen - Fläche: 0.000439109 m2; Volumen: 7.40875e-07 m3
IFC-Parameter - In IFC-Datei exportieren: Nach Typ; In IFC exportieren als: ifcbuildingelementproxy; NameOverride: BuildingElementProxy 67; IfcPresentationLayer: 0; IfcDescription: IfcBuildingElementProxy
Phasen - Phase erstellt: Phase 01

# IfcBuildingElementProxy: BuildingElementProxy 68:BuildingElementProxy 68, BuildingElementProxy 68
In: Erdgeschoss
Type - Material: IfcSurfaceStyle #623543
Type - Andere - Kategorie: Allgemeines Modell; Familienname: BuildingElementProxy 68
Type - ID-Daten - Typname: BuildingElementProxy 68
Type - IFC-Parameter - Typ in IFC-Datei exportieren: Vorgabe
Description: IfcBuildingElementProxy
Pset_BuildingElementProxyCommon - Reference: BuildingElementProxy 68; sets with these values: 2
Andere - Typ: BuildingElementProxy 68; Familie: BuildingElementProxy 68; Familie und Typ: BuildingElementProxy 68: BuildingElementProxy 68; Typ-ID: 2538524
Abhängigkeiten - Höhe von Ebene: 0 m; Verschieben mit umliegenden Elementen: no
Bemaßungen - Fläche: 0.00687765 m2; Volumen: 0.0000187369 m3
IFC-Parameter - In IFC-Datei exportieren: Nach Typ; In IFC exportieren als: ifcbuildingelementproxy; NameOverride: BuildingElementProxy 68; IfcPresentationLayer: 0; IfcDescription: IfcBuildingElementProxy
Phasen - Phase erstellt: Phase 01

# IfcBuildingElementProxy: BuildingElementProxy 69:BuildingElementProxy 69, BuildingElementProxy 69
In: Erdgeschoss
Type - Material: IfcSurfaceStyle #623543
Type - Andere - Kategorie: Allgemeines Modell; Familienname: BuildingElementProxy 69
Type - ID-Daten - Typname: BuildingElementProxy 69
Type - IFC-Parameter - Typ in IFC-Datei exportieren: Vorgabe
Description: IfcBuildingElementProxy
Pset_BuildingElementProxyCommon - Reference: BuildingElementProxy 69; sets with these values: 2
Andere - Typ: BuildingElementProxy 69; Familie: BuildingElementProxy 69; Familie und Typ: BuildingElementProxy 69: BuildingElementProxy 69; Typ-ID: 2538531
Abhängigkeiten - Höhe von Ebene: 0 m; Verschieben mit umliegenden Elementen: no
Bemaßungen - Fläche: 0.0227427 m2; Volumen: 0.000543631 m3
IFC-Parameter - In IFC-Datei exportieren: Nach Typ; In IFC exportieren als: ifcbuildingelementproxy; NameOverride: BuildingElementProxy 69; IfcPresentationLayer: 0; IfcDescription: IfcBuildingElementProxy
Phasen - Phase erstellt: Phase 01

# IfcBuildingElementProxy: BuildingElementProxy 70:BuildingElementProxy 70, BuildingElementProxy 70
In: Erdgeschoss
Type - Material: IfcSurfaceStyle #623543
Type - Andere - Kategorie: Allgemeines Modell; Familienname: BuildingElementProxy 70
Type - ID-Daten - Typname: BuildingElementProxy 70
Type - IFC-Parameter - Typ in IFC-Datei exportieren: Vorgabe
Description: IfcBuildingElementProxy
Pset_BuildingElementProxyCommon - Reference: BuildingElementProxy 70; sets with these values: 2
Andere - Typ: BuildingElementProxy 70; Familie: BuildingElementProxy 70; Familie und Typ: BuildingElementProxy 70: BuildingElementProxy 70; Typ-ID: 2538538
Abhängigkeiten - Höhe von Ebene: 0 m; Verschieben mit umliegenden Elementen: no
Bemaßungen - Fläche: 0.00687765 m2; Volumen: 0.0000187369 m3
IFC-Parameter - In IFC-Datei exportieren: Nach Typ; In IFC exportieren als: ifcbuildingelementproxy; NameOverride: BuildingElementProxy 70; IfcPresentationLayer: 0; IfcDescription: IfcBuildingElementProxy
Phasen - Phase erstellt: Phase 01

# IfcBuildingElementProxy: BuildingElementProxy 71:BuildingElementProxy 71, BuildingElementProxy 71
In: Erdgeschoss
Type - Material: IfcSurfaceStyle #631137
Type - Andere - Kategorie: Allgemeines Modell; Familienname: BuildingElementProxy 71
Type - ID-Daten - Typname: BuildingElementProxy 71
Type - IFC-Parameter - Typ in IFC-Datei exportieren: Vorgabe
Description: IfcBuildingElementProxy
Pset_BuildingElementProxyCommon - Reference: BuildingElementProxy 71; sets with these values: 2
Andere - Typ: BuildingElementProxy 71; Familie: BuildingElementProxy 71; Familie und Typ: BuildingElementProxy 71: BuildingElementProxy 71; Typ-ID: 2538545
Abhängigkeiten - Höhe von Ebene: 0 m; Verschieben mit umliegenden Elementen: no
Bemaßungen - Fläche: 0.000530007 m2; Volumen: 0.00000237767 m3
IFC-Parameter - In IFC-Datei exportieren: Nach Typ; In IFC exportieren als: ifcbuildingelementproxy; NameOverride: BuildingElementProxy 71; IfcPresentationLayer: 0; IfcDescription: IfcBuildingElementProxy
Phasen - Phase erstellt: Phase 01

# IfcBuildingElementProxy: BuildingElementProxy 72:BuildingElementProxy 72, BuildingElementProxy 72
In: Erdgeschoss
Type - Material: IfcSurfaceStyle #626231
Type - Andere - Kategorie: Allgemeines Modell; Familienname: BuildingElementProxy 72
Type - ID-Daten - Typname: BuildingElementProxy 72
Type - IFC-Parameter - Typ in IFC-Datei exportieren: Vorgabe
Description: IfcBuildingElementProxy
Pset_BuildingElementProxyCommon - Reference: BuildingElementProxy 72; sets with these values: 2
Andere - Typ: BuildingElementProxy 72; Familie: BuildingElementProxy 72; Familie und Typ: BuildingElementProxy 72: BuildingElementProxy 72; Typ-ID: 2538552
Abhängigkeiten - Höhe von Ebene: 0 m; Verschieben mit umliegenden Elementen: no
IFC-Parameter - In IFC-Datei exportieren: Nach Typ; In IFC exportieren als: ifcbuildingelementproxy; NameOverride: BuildingElementProxy 72; IfcPresentationLayer: 0; IfcDescription: IfcBuildingElementProxy
Phasen - Phase erstellt: Phase 01

# IfcBuildingElementProxy: BuildingElementProxy 73:BuildingElementProxy 73, BuildingElementProxy 73
In: Erdgeschoss
Type - Material: IfcSurfaceStyle #623543
Type - Andere - Kategorie: Allgemeines Modell; Familienname: BuildingElementProxy 73
Type - ID-Daten - Typname: BuildingElementProxy 73
Type - IFC-Parameter - Typ in IFC-Datei exportieren: Vorgabe
Description: IfcBuildingElementProxy
Pset_BuildingElementProxyCommon - Reference: BuildingElementProxy 73; sets with these values: 2
Andere - Typ: BuildingElementProxy 73; Familie: BuildingElementProxy 73; Familie und Typ: BuildingElementProxy 73: BuildingElementProxy 73; Typ-ID: 2538559
Abhängigkeiten - Höhe von Ebene: 0 m; Verschieben mit umliegenden Elementen: no
IFC-Parameter - In IFC-Datei exportieren: Nach Typ; In IFC exportieren als: ifcbuildingelementproxy; NameOverride: BuildingElementProxy 73; IfcPresentationLayer: 0; IfcDescription: IfcBuildingElementProxy
Phasen - Phase erstellt: Phase 01

# IfcBuildingElementProxy: BuildingElementProxy 74:BuildingElementProxy 74, BuildingElementProxy 74
In: Erdgeschoss
Type - Material: IfcSurfaceStyle #631137
Type - Andere - Kategorie: Allgemeines Modell; Familienname: BuildingElementProxy 74
Type - ID-Daten - Typname: BuildingElementProxy 74
Type - IFC-Parameter - Typ in IFC-Datei exportieren: Vorgabe
Description: IfcBuildingElementProxy
Pset_BuildingElementProxyCommon - Reference: BuildingElementProxy 74; sets with these values: 2
Andere - Typ: BuildingElementProxy 74; Familie: BuildingElementProxy 74; Familie und Typ: BuildingElementProxy 74: BuildingElementProxy 74; Typ-ID: 2538566
Abhängigkeiten - Höhe von Ebene: 0 m; Verschieben mit umliegenden Elementen: no
IFC-Parameter - In IFC-Datei exportieren: Nach Typ; In IFC exportieren als: ifcbuildingelementproxy; NameOverride: BuildingElementProxy 74; IfcPresentationLayer: 0; IfcDescription: IfcBuildingElementProxy
Phasen - Phase erstellt: Phase 01

# IfcBuildingElementProxy: BuildingElementProxy 75:BuildingElementProxy 75, BuildingElementProxy 75
In: Erdgeschoss
Type - Material: IfcSurfaceStyle #626231
Type - Andere - Kategorie: Allgemeines Modell; Familienname: BuildingElementProxy 75
Type - ID-Daten - Typname: BuildingElementProxy 75
Type - IFC-Parameter - Typ in IFC-Datei exportieren: Vorgabe
Description: IfcBuildingElementProxy
Pset_BuildingElementProxyCommon - Reference: BuildingElementProxy 75; sets with these values: 2
Andere - Typ: BuildingElementProxy 75; Familie: BuildingElementProxy 75; Familie und Typ: BuildingElementProxy 75: BuildingElementProxy 75; Typ-ID: 2538573
Abhängigkeiten - Höhe von Ebene: 0 m; Verschieben mit umliegenden Elementen: no
Bemaßungen - Fläche: 0.0907802 m2; Volumen: 0.00191442 m3
IFC-Parameter - In IFC-Datei exportieren: Nach Typ; In IFC exportieren als: ifcbuildingelementproxy; NameOverride: BuildingElementProxy 75; IfcPresentationLayer: 0; IfcDescription: IfcBuildingElementProxy
Phasen - Phase erstellt: Phase 01

# IfcBuildingElementProxy: BuildingElementProxy 76:BuildingElementProxy 76, BuildingElementProxy 76
In: Erdgeschoss
Type - Material: IfcSurfaceStyle #649647
Type - Andere - Kategorie: Allgemeines Modell; Familienname: BuildingElementProxy 76
Type - ID-Daten - Typname: BuildingElementProxy 76
Type - IFC-Parameter - Typ in IFC-Datei exportieren: Vorgabe
Description: IfcBuildingElementProxy
Pset_BuildingElementProxyCommon - Reference: BuildingElementProxy 76; sets with these values: 2
Andere - Typ: BuildingElementProxy 76; Familie: BuildingElementProxy 76; Familie und Typ: BuildingElementProxy 76: BuildingElementProxy 76; Typ-ID: 2538580
Abhängigkeiten - Höhe von Ebene: 0 m; Verschieben mit umliegenden Elementen: no
Bemaßungen - Fläche: 0.00742041 m2; Volumen: 0.000092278 m3
IFC-Parameter - In IFC-Datei exportieren: Nach Typ; In IFC exportieren als: ifcbuildingelementproxy; NameOverride: BuildingElementProxy 76; IfcPresentationLayer: 0; IfcDescription: IfcBuildingElementProxy
Phasen - Phase erstellt: Phase 01

# IfcBuildingElementProxy: BuildingElementProxy 77:BuildingElementProxy 77, BuildingElementProxy 77
In: Erdgeschoss
Type - Material: IfcSurfaceStyle #623543
Type - Andere - Kategorie: Allgemeines Modell; Familienname: BuildingElementProxy 77
Type - ID-Daten - Typname: BuildingElementProxy 77
Type - IFC-Parameter - Typ in IFC-Datei exportieren: Vorgabe
Description: IfcBuildingElementProxy
Pset_BuildingElementProxyCommon - Reference: BuildingElementProxy 77; sets with these values: 2
Andere - Typ: BuildingElementProxy 77; Familie: BuildingElementProxy 77; Familie und Typ: BuildingElementProxy 77: BuildingElementProxy 77; Typ-ID: 2538587
Abhängigkeiten - Höhe von Ebene: 0 m; Verschieben mit umliegenden Elementen: no
Bemaßungen - Fläche: 0.00687765 m2; Volumen: 0.0000187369 m3
IFC-Parameter - In IFC-Datei exportieren: Nach Typ; In IFC exportieren als: ifcbuildingelementproxy; NameOverride: BuildingElementProxy 77; IfcPresentationLayer: 0; IfcDescription: IfcBuildingElementProxy
Phasen - Phase erstellt: Phase 01

# IfcBuildingElementProxy: BuildingElementProxy 78:BuildingElementProxy 78, BuildingElementProxy 78
In: Erdgeschoss
Type - Material: IfcSurfaceStyle #631137
Type - Andere - Kategorie: Allgemeines Modell; Familienname: BuildingElementProxy 78
Type - ID-Daten - Typname: BuildingElementProxy 78
Type - IFC-Parameter - Typ in IFC-Datei exportieren: Vorgabe
Description: IfcBuildingElementProxy
Pset_BuildingElementProxyCommon - Reference: BuildingElementProxy 78; sets with these values: 2
Andere - Typ: BuildingElementProxy 78; Familie: BuildingElementProxy 78; Familie und Typ: BuildingElementProxy 78: BuildingElementProxy 78; Typ-ID: 2538594
Abhängigkeiten - Höhe von Ebene: 0 m; Verschieben mit umliegenden Elementen: no
Bemaßungen - Fläche: 0.000530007 m2; Volumen: 0.00000237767 m3
IFC-Parameter - In IFC-Datei exportieren: Nach Typ; In IFC exportieren als: ifcbuildingelementproxy; NameOverride: BuildingElementProxy 78; IfcPresentationLayer: 0; IfcDescription: IfcBuildingElementProxy
Phasen - Phase erstellt: Phase 01

# IfcBuildingElementProxy: BuildingElementProxy 79:BuildingElementProxy 79, BuildingElementProxy 79
In: Erdgeschoss
Type - Material: IfcSurfaceStyle #623543
Type - Andere - Kategorie: Allgemeines Modell; Familienname: BuildingElementProxy 79
Type - ID-Daten - Typname: BuildingElementProxy 79
Type - IFC-Parameter - Typ in IFC-Datei exportieren: Vorgabe
Description: IfcBuildingElementProxy
Pset_BuildingElementProxyCommon - Reference: BuildingElementProxy 79; sets with these values: 2
Andere - Typ: BuildingElementProxy 79; Familie: BuildingElementProxy 79; Familie und Typ: BuildingElementProxy 79: BuildingElementProxy 79; Typ-ID: 2538601
Abhängigkeiten - Höhe von Ebene: 0 m; Verschieben mit umliegenden Elementen: no
Bemaßungen - Fläche: 0.0178588 m2; Volumen: 0.0000826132 m3
IFC-Parameter - In IFC-Datei exportieren: Nach Typ; In IFC exportieren als: ifcbuildingelementproxy; NameOverride: BuildingElementProxy 79; IfcPresentationLayer: 0; IfcDescription: IfcBuildingElementProxy
Phasen - Phase erstellt: Phase 01

# IfcBuildingElementProxy: BuildingElementProxy 80:BuildingElementProxy 80, BuildingElementProxy 80
In: Erdgeschoss
Type - Material: IfcSurfaceStyle #631137
Type - Andere - Kategorie: Allgemeines Modell; Familienname: BuildingElementProxy 80
Type - ID-Daten - Typname: BuildingElementProxy 80
Type - IFC-Parameter - Typ in IFC-Datei exportieren: Vorgabe
Description: IfcBuildingElementProxy
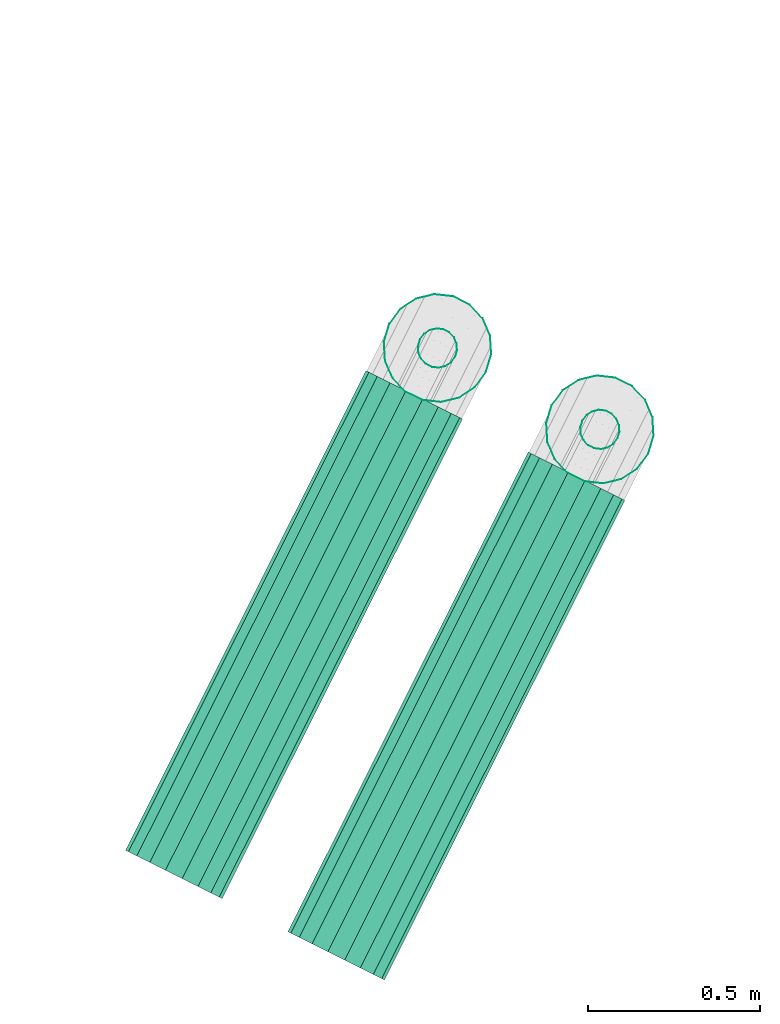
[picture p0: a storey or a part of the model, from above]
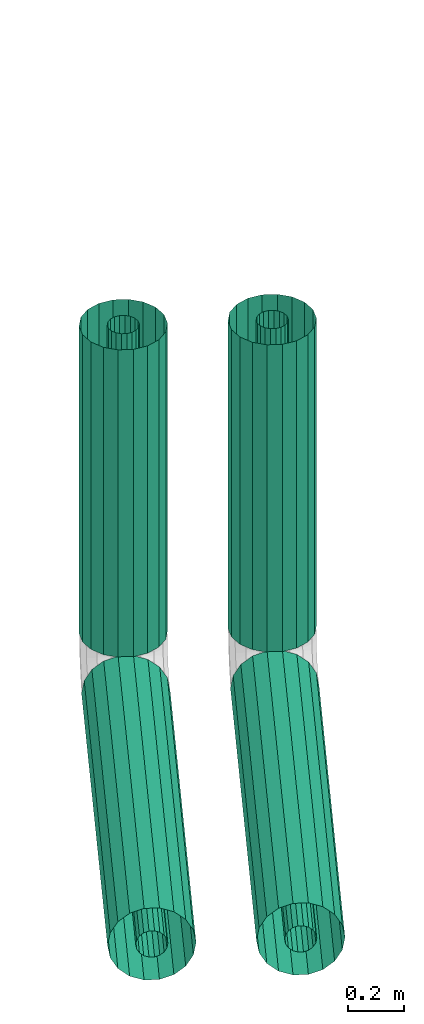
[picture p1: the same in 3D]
Properties of the parts of a building model (IFC2X3), part 3 of 23

# IfcBuildingElementProxy: BuildingElementProxy 80:BuildingElementProxy 80, BuildingElementProxy 80
Pset_BuildingElementProxyCommon - Reference: BuildingElementProxy 80; sets with these values: 2
Andere - Typ: BuildingElementProxy 80; Familie: BuildingElementProxy 80; Familie und Typ: BuildingElementProxy 80: BuildingElementProxy 80; Typ-ID: 2538608
Abhängigkeiten - Höhe von Ebene: 0 m; Verschieben mit umliegenden Elementen: no
Bemaßungen - Fläche: 0.0153135 m2; Volumen: 0.000165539 m3
IFC-Parameter - In IFC-Datei exportieren: Nach Typ; In IFC exportieren als: ifcbuildingelementproxy; NameOverride: BuildingElementProxy 80; IfcPresentationLayer: 0; IfcDescription: IfcBuildingElementProxy
Phasen - Phase erstellt: Phase 01

# IfcBuildingElementProxy: BuildingElementProxy 81:BuildingElementProxy 81, BuildingElementProxy 81
In: Erdgeschoss
Type - Material: IfcSurfaceStyle #623543
Type - Andere - Kategorie: Allgemeines Modell; Familienname: BuildingElementProxy 81
Type - ID-Daten - Typname: BuildingElementProxy 81
Type - IFC-Parameter - Typ in IFC-Datei exportieren: Vorgabe
Description: IfcBuildingElementProxy
Pset_BuildingElementProxyCommon - Reference: BuildingElementProxy 81; sets with these values: 2
Andere - Typ: BuildingElementProxy 81; Familie: BuildingElementProxy 81; Familie und Typ: BuildingElementProxy 81: BuildingElementProxy 81; Typ-ID: 2538615
Abhängigkeiten - Höhe von Ebene: 0 m; Verschieben mit umliegenden Elementen: no
Bemaßungen - Fläche: 0.00687765 m2; Volumen: 0.0000187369 m3
IFC-Parameter - In IFC-Datei exportieren: Nach Typ; In IFC exportieren als: ifcbuildingelementproxy; NameOverride: BuildingElementProxy 81; IfcPresentationLayer: 0; IfcDescription: IfcBuildingElementProxy
Phasen - Phase erstellt: Phase 01

# IfcBuildingElementProxy: BuildingElementProxy 82:BuildingElementProxy 82, BuildingElementProxy 82
In: Erdgeschoss
Type - Material: IfcSurfaceStyle #631137
Type - Andere - Kategorie: Allgemeines Modell; Familienname: BuildingElementProxy 82
Type - ID-Daten - Typname: BuildingElementProxy 82
Type - IFC-Parameter - Typ in IFC-Datei exportieren: Vorgabe
Description: IfcBuildingElementProxy
Pset_BuildingElementProxyCommon - Reference: BuildingElementProxy 82; sets with these values: 2
Andere - Typ: BuildingElementProxy 82; Familie: BuildingElementProxy 82; Familie und Typ: BuildingElementProxy 82: BuildingElementProxy 82; Typ-ID: 2538622
Abhängigkeiten - Höhe von Ebene: 0 m; Verschieben mit umliegenden Elementen: no
Bemaßungen - Fläche: 0.000530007 m2; Volumen: 0.00000237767 m3
IFC-Parameter - In IFC-Datei exportieren: Nach Typ; In IFC exportieren als: ifcbuildingelementproxy; NameOverride: BuildingElementProxy 82; IfcPresentationLayer: 0; IfcDescription: IfcBuildingElementProxy
Phasen - Phase erstellt: Phase 01

# IfcBuildingElementProxy: BuildingElementProxy 83:BuildingElementProxy 83, BuildingElementProxy 83
In: Erdgeschoss
Type - Material: IfcSurfaceStyle #623543
Type - Andere - Kategorie: Allgemeines Modell; Familienname: BuildingElementProxy 83
Type - ID-Daten - Typname: BuildingElementProxy 83
Type - IFC-Parameter - Typ in IFC-Datei exportieren: Vorgabe
Description: IfcBuildingElementProxy
Pset_BuildingElementProxyCommon - Reference: BuildingElementProxy 83; sets with these values: 2
Andere - Typ: BuildingElementProxy 83; Familie: BuildingElementProxy 83; Familie und Typ: BuildingElementProxy 83: BuildingElementProxy 83; Typ-ID: 2538629
Abhängigkeiten - Höhe von Ebene: 0 m; Verschieben mit umliegenden Elementen: no
Bemaßungen - Fläche: 0.00687765 m2; Volumen: 0.0000187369 m3
IFC-Parameter - In IFC-Datei exportieren: Nach Typ; In IFC exportieren als: ifcbuildingelementproxy; NameOverride: BuildingElementProxy 83; IfcPresentationLayer: 0; IfcDescription: IfcBuildingElementProxy
Phasen - Phase erstellt: Phase 01

# IfcBuildingElementProxy: BuildingElementProxy 84:BuildingElementProxy 84, BuildingElementProxy 84
In: Erdgeschoss
Type - Material: IfcSurfaceStyle #623543
Type - Andere - Kategorie: Allgemeines Modell; Familienname: BuildingElementProxy 84
Type - ID-Daten - Typname: BuildingElementProxy 84
Type - IFC-Parameter - Typ in IFC-Datei exportieren: Vorgabe
Description: IfcBuildingElementProxy
Pset_BuildingElementProxyCommon - Reference: BuildingElementProxy 84; sets with these values: 2
Andere - Typ: BuildingElementProxy 84; Familie: BuildingElementProxy 84; Familie und Typ: BuildingElementProxy 84: BuildingElementProxy 84; Typ-ID: 2538636
Abhängigkeiten - Höhe von Ebene: 0 m; Verschieben mit umliegenden Elementen: no
Bemaßungen - Fläche: 0.00687765 m2; Volumen: 0.0000187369 m3
IFC-Parameter - In IFC-Datei exportieren: Nach Typ; In IFC exportieren als: ifcbuildingelementproxy; NameOverride: BuildingElementProxy 84; IfcPresentationLayer: 0; IfcDescription: IfcBuildingElementProxy
Phasen - Phase erstellt: Phase 01

# IfcBuildingElementProxy: BuildingElementProxy 85:BuildingElementProxy 85, BuildingElementProxy 85
In: Erdgeschoss
Type - Material: IfcSurfaceStyle #631137
Type - Andere - Kategorie: Allgemeines Modell; Familienname: BuildingElementProxy 85
Type - ID-Daten - Typname: BuildingElementProxy 85
Type - IFC-Parameter - Typ in IFC-Datei exportieren: Vorgabe
Description: IfcBuildingElementProxy
Pset_BuildingElementProxyCommon - Reference: BuildingElementProxy 85; sets with these values: 2
Andere - Typ: BuildingElementProxy 85; Familie: BuildingElementProxy 85; Familie und Typ: BuildingElementProxy 85: BuildingElementProxy 85; Typ-ID: 2538643
Abhängigkeiten - Höhe von Ebene: 0 m; Verschieben mit umliegenden Elementen: no
Bemaßungen - Fläche: 0.000439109 m2; Volumen: 7.40875e-07 m3
IFC-Parameter - In IFC-Datei exportieren: Nach Typ; In IFC exportieren als: ifcbuildingelementproxy; NameOverride: BuildingElementProxy 85; IfcPresentationLayer: 0; IfcDescription: IfcBuildingElementProxy
Phasen - Phase erstellt: Phase 01

# IfcBuildingElementProxy: BuildingElementProxy 86:BuildingElementProxy 86, BuildingElementProxy 86
In: Erdgeschoss
Type - Material: IfcSurfaceStyle #623543
Type - Andere - Kategorie: Allgemeines Modell; Familienname: BuildingElementProxy 86
Type - ID-Daten - Typname: BuildingElementProxy 86
Type - IFC-Parameter - Typ in IFC-Datei exportieren: Vorgabe
Description: IfcBuildingElementProxy
Pset_BuildingElementProxyCommon - Reference: BuildingElementProxy 86; sets with these values: 2
Andere - Typ: BuildingElementProxy 86; Familie: BuildingElementProxy 86; Familie und Typ: BuildingElementProxy 86: BuildingElementProxy 86; Typ-ID: 2538650
Abhängigkeiten - Höhe von Ebene: 0 m; Verschieben mit umliegenden Elementen: no
Bemaßungen - Fläche: 0.00687765 m2; Volumen: 0.0000187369 m3
IFC-Parameter - In IFC-Datei exportieren: Nach Typ; In IFC exportieren als: ifcbuildingelementproxy; NameOverride: BuildingElementProxy 86; IfcPresentationLayer: 0; IfcDescription: IfcBuildingElementProxy
Phasen - Phase erstellt: Phase 01

# IfcBuildingElementProxy: BuildingElementProxy 87:BuildingElementProxy 87, BuildingElementProxy 87
In: Erdgeschoss
Type - Material: IfcSurfaceStyle #623543
Type - Andere - Kategorie: Allgemeines Modell; Familienname: BuildingElementProxy 87
Type - ID-Daten - Typname: BuildingElementProxy 87
Type - IFC-Parameter - Typ in IFC-Datei exportieren: Vorgabe
Description: IfcBuildingElementProxy
Pset_BuildingElementProxyCommon - Reference: BuildingElementProxy 87; sets with these values: 2
Andere - Typ: BuildingElementProxy 87; Familie: BuildingElementProxy 87; Familie und Typ: BuildingElementProxy 87: BuildingElementProxy 87; Typ-ID: 2538657
Abhängigkeiten - Höhe von Ebene: 0 m; Verschieben mit umliegenden Elementen: no
Bemaßungen - Fläche: 0.00687765 m2; Volumen: 0.0000187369 m3
IFC-Parameter - In IFC-Datei exportieren: Nach Typ; In IFC exportieren als: ifcbuildingelementproxy; NameOverride: BuildingElementProxy 87; IfcPresentationLayer: 0; IfcDescription: IfcBuildingElementProxy
Phasen - Phase erstellt: Phase 01

# IfcBuildingElementProxy: BuildingElementProxy 88:BuildingElementProxy 88, BuildingElementProxy 88
In: Erdgeschoss
Type - Material: IfcSurfaceStyle #623543
Type - Andere - Kategorie: Allgemeines Modell; Familienname: BuildingElementProxy 88
Type - ID-Daten - Typname: BuildingElementProxy 88
Type - IFC-Parameter - Typ in IFC-Datei exportieren: Vorgabe
Description: IfcBuildingElementProxy
Pset_BuildingElementProxyCommon - Reference: BuildingElementProxy 88; sets with these values: 2
Andere - Typ: BuildingElementProxy 88; Familie: BuildingElementProxy 88; Familie und Typ: BuildingElementProxy 88: BuildingElementProxy 88; Typ-ID: 2538664
Abhängigkeiten - Höhe von Ebene: 0 m; Verschieben mit umliegenden Elementen: no
IFC-Parameter - In IFC-Datei exportieren: Nach Typ; In IFC exportieren als: ifcbuildingelementproxy; NameOverride: BuildingElementProxy 88; IfcPresentationLayer: 0; IfcDescription: IfcBuildingElementProxy
Phasen - Phase erstellt: Phase 01

# IfcBuildingElementProxy: BuildingElementProxy 89:BuildingElementProxy 89, BuildingElementProxy 89
In: Erdgeschoss
Type - Material: IfcSurfaceStyle #626231
Type - Andere - Kategorie: Allgemeines Modell; Familienname: BuildingElementProxy 89
Type - ID-Daten - Typname: BuildingElementProxy 89
Type - IFC-Parameter - Typ in IFC-Datei exportieren: Vorgabe
Description: IfcBuildingElementProxy
Pset_BuildingElementProxyCommon - Reference: BuildingElementProxy 89; sets with these values: 2
Andere - Typ: BuildingElementProxy 89; Familie: BuildingElementProxy 89; Familie und Typ: BuildingElementProxy 89: BuildingElementProxy 89; Typ-ID: 2538671
Abhängigkeiten - Höhe von Ebene: 0 m; Verschieben mit umliegenden Elementen: no
Bemaßungen - Fläche: 0.012165 m2; Volumen: 0.000173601 m3
IFC-Parameter - In IFC-Datei exportieren: Nach Typ; In IFC exportieren als: ifcbuildingelementproxy; NameOverride: BuildingElementProxy 89; IfcPresentationLayer: 0; IfcDescription: IfcBuildingElementProxy
Phasen - Phase erstellt: Phase 01

# IfcBuildingElementProxy: BuildingElementProxy 90:BuildingElementProxy 90, BuildingElementProxy 90
In: Erdgeschoss
Type - Material: IfcSurfaceStyle #623543
Type - Andere - Kategorie: Allgemeines Modell; Familienname: BuildingElementProxy 90
Type - ID-Daten - Typname: BuildingElementProxy 90
Type - IFC-Parameter - Typ in IFC-Datei exportieren: Vorgabe
Description: IfcBuildingElementProxy
Pset_BuildingElementProxyCommon - Reference: BuildingElementProxy 90; sets with these values: 2
Andere - Typ: BuildingElementProxy 90; Familie: BuildingElementProxy 90; Familie und Typ: BuildingElementProxy 90: BuildingElementProxy 90; Typ-ID: 2538678
Abhängigkeiten - Höhe von Ebene: 0 m; Verschieben mit umliegenden Elementen: no
Bemaßungen - Fläche: 0.00687765 m2; Volumen: 0.0000187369 m3
IFC-Parameter - In IFC-Datei exportieren: Nach Typ; In IFC exportieren als: ifcbuildingelementproxy; NameOverride: BuildingElementProxy 90; IfcPresentationLayer: 0; IfcDescription: IfcBuildingElementProxy
Phasen - Phase erstellt: Phase 01

# IfcBuildingElementProxy: BuildingElementProxy 91:BuildingElementProxy 91, BuildingElementProxy 91
In: Erdgeschoss
Type - Material: IfcSurfaceStyle #631137
Type - Andere - Kategorie: Allgemeines Modell; Familienname: BuildingElementProxy 91
Type - ID-Daten - Typname: BuildingElementProxy 91
Type - IFC-Parameter - Typ in IFC-Datei exportieren: Vorgabe
Description: IfcBuildingElementProxy
Pset_BuildingElementProxyCommon - Reference: BuildingElementProxy 91; sets with these values: 2
Andere - Typ: BuildingElementProxy 91; Familie: BuildingElementProxy 91; Familie und Typ: BuildingElementProxy 91: BuildingElementProxy 91; Typ-ID: 2538685
Abhängigkeiten - Höhe von Ebene: 0 m; Verschieben mit umliegenden Elementen: no
Bemaßungen - Fläche: 0.000439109 m2; Volumen: 7.40875e-07 m3
IFC-Parameter - In IFC-Datei exportieren: Nach Typ; In IFC exportieren als: ifcbuildingelementproxy; NameOverride: BuildingElementProxy 91; IfcPresentationLayer: 0; IfcDescription: IfcBuildingElementProxy
Phasen - Phase erstellt: Phase 01

# IfcBuildingElementProxy: BuildingElementProxy 92:BuildingElementProxy 92, BuildingElementProxy 92
In: Erdgeschoss
Type - Material: IfcSurfaceStyle #631137
Type - Andere - Kategorie: Allgemeines Modell; Familienname: BuildingElementProxy 92
Type - ID-Daten - Typname: BuildingElementProxy 92
Type - IFC-Parameter - Typ in IFC-Datei exportieren: Vorgabe
Description: IfcBuildingElementProxy
Pset_BuildingElementProxyCommon - Reference: BuildingElementProxy 92; sets with these values: 2
Andere - Typ: BuildingElementProxy 92; Familie: BuildingElementProxy 92; Familie und Typ: BuildingElementProxy 92: BuildingElementProxy 92; Typ-ID: 2538692
Abhängigkeiten - Höhe von Ebene: 0 m; Verschieben mit umliegenden Elementen: no
Bemaßungen - Fläche: 0.000530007 m2; Volumen: 0.00000237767 m3
IFC-Parameter - In IFC-Datei exportieren: Nach Typ; In IFC exportieren als: ifcbuildingelementproxy; NameOverride: BuildingElementProxy 92; IfcPresentationLayer: 0; IfcDescription: IfcBuildingElementProxy
Phasen - Phase erstellt: Phase 01

# IfcBuildingElementProxy: BuildingElementProxy 93:BuildingElementProxy 93, BuildingElementProxy 93
In: Erdgeschoss
Type - Material: IfcSurfaceStyle #626231
Type - Andere - Kategorie: Allgemeines Modell; Familienname: BuildingElementProxy 93
Type - ID-Daten - Typname: BuildingElementProxy 93
Type - IFC-Parameter - Typ in IFC-Datei exportieren: Vorgabe
Description: IfcBuildingElementProxy
Pset_BuildingElementProxyCommon - Reference: BuildingElementProxy 93; sets with these values: 2
Andere - Typ: BuildingElementProxy 93; Familie: BuildingElementProxy 93; Familie und Typ: BuildingElementProxy 93: BuildingElementProxy 93; Typ-ID: 2538699
Abhängigkeiten - Höhe von Ebene: 0 m; Verschieben mit umliegenden Elementen: no
IFC-Parameter - In IFC-Datei exportieren: Nach Typ; In IFC exportieren als: ifcbuildingelementproxy; NameOverride: BuildingElementProxy 93; IfcPresentationLayer: 0; IfcDescription: IfcBuildingElementProxy
Phasen - Phase erstellt: Phase 01

# IfcBuildingElementProxy: BuildingElementProxy 94:BuildingElementProxy 94, BuildingElementProxy 94
In: Erdgeschoss
Type - Material: IfcSurfaceStyle #623543
Type - Andere - Kategorie: Allgemeines Modell; Familienname: BuildingElementProxy 94
Type - ID-Daten - Typname: BuildingElementProxy 94
Type - IFC-Parameter - Typ in IFC-Datei exportieren: Vorgabe
Description: IfcBuildingElementProxy
Pset_BuildingElementProxyCommon - Reference: BuildingElementProxy 94; sets with these values: 2
Andere - Typ: BuildingElementProxy 94; Familie: BuildingElementProxy 94; Familie und Typ: BuildingElementProxy 94: BuildingElementProxy 94; Typ-ID: 2538706
Abhängigkeiten - Höhe von Ebene: 0 m; Verschieben mit umliegenden Elementen: no
Bemaßungen - Fläche: 0.0154189 m2; Volumen: 0.000130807 m3
IFC-Parameter - In IFC-Datei exportieren: Nach Typ; In IFC exportieren als: ifcbuildingelementproxy; NameOverride: BuildingElementProxy 94; IfcPresentationLayer: 0; IfcDescription: IfcBuildingElementProxy
Phasen - Phase erstellt: Phase 01

# IfcBuildingElementProxy: BuildingElementProxy 95:BuildingElementProxy 95, BuildingElementProxy 95
In: Erdgeschoss
Type - Material: IfcSurfaceStyle #624289
Type - Andere - Kategorie: Allgemeines Modell; Familienname: BuildingElementProxy 95
Type - ID-Daten - Typname: BuildingElementProxy 95
Type - IFC-Parameter - Typ in IFC-Datei exportieren: Vorgabe
Description: IfcBuildingElementProxy
Pset_BuildingElementProxyCommon - Reference: BuildingElementProxy 95; sets with these values: 2
Andere - Typ: BuildingElementProxy 95; Familie: BuildingElementProxy 95; Familie und Typ: BuildingElementProxy 95: BuildingElementProxy 95; Typ-ID: 2538713
Abhängigkeiten - Höhe von Ebene: 0 m; Verschieben mit umliegenden Elementen: no
Bemaßungen - Fläche: 0.00172493 m2; Volumen: 0.0000108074 m3
IFC-Parameter - In IFC-Datei exportieren: Nach Typ; In IFC exportieren als: ifcbuildingelementproxy; NameOverride: BuildingElementProxy 95; IfcPresentationLayer: 0; IfcDescription: IfcBuildingElementProxy
Phasen - Phase erstellt: Phase 01

# IfcBuildingElementProxy: BuildingElementProxy 96:BuildingElementProxy 96, BuildingElementProxy 96
In: Erdgeschoss
Type - Material: IfcSurfaceStyle #623543
Type - Andere - Kategorie: Allgemeines Modell; Familienname: BuildingElementProxy 96
Type - ID-Daten - Typname: BuildingElementProxy 96
Type - IFC-Parameter - Typ in IFC-Datei exportieren: Vorgabe
Description: IfcBuildingElementProxy
Pset_BuildingElementProxyCommon - Reference: BuildingElementProxy 96; sets with these values: 2
Andere - Typ: BuildingElementProxy 96; Familie: BuildingElementProxy 96; Familie und Typ: BuildingElementProxy 96: BuildingElementProxy 96; Typ-ID: 2538720
Abhängigkeiten - Höhe von Ebene: 0 m; Verschieben mit umliegenden Elementen: no
Bemaßungen - Fläche: 0.00687765 m2; Volumen: 0.0000187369 m3
IFC-Parameter - In IFC-Datei exportieren: Nach Typ; In IFC exportieren als: ifcbuildingelementproxy; NameOverride: BuildingElementProxy 96; IfcPresentationLayer: 0; IfcDescription: IfcBuildingElementProxy
Phasen - Phase erstellt: Phase 01

# IfcBuildingElementProxy: BuildingElementProxy 97:BuildingElementProxy 97, BuildingElementProxy 97
In: Erdgeschoss
Type - Material: IfcSurfaceStyle #823620
Type - Andere - Kategorie: Allgemeines Modell; Familienname: BuildingElementProxy 97
Type - ID-Daten - Typname: BuildingElementProxy 97
Type - IFC-Parameter - Typ in IFC-Datei exportieren: Vorgabe
Description: IfcBuildingElementProxy
Pset_BuildingElementProxyCommon - Reference: BuildingElementProxy 97; sets with these values: 2
Andere - Typ: BuildingElementProxy 97; Familie: BuildingElementProxy 97; Familie und Typ: BuildingElementProxy 97: BuildingElementProxy 97; Typ-ID: 2538727
Abhängigkeiten - Höhe von Ebene: 0 m; Verschieben mit umliegenden Elementen: no
Bemaßungen - Fläche: 0.000772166 m2
IFC-Parameter - In IFC-Datei exportieren: Nach Typ; In IFC exportieren als: ifcbuildingelementproxy; NameOverride: BuildingElementProxy 97; IfcPresentationLayer: 0; IfcDescription: IfcBuildingElementProxy
Phasen - Phase erstellt: Phase 01

# IfcBuildingElementProxy: BuildingElementProxy 98:BuildingElementProxy 98, BuildingElementProxy 98
In: Erdgeschoss
Type - Material: IfcSurfaceStyle #631137
Type - Andere - Kategorie: Allgemeines Modell; Familienname: BuildingElementProxy 98
Type - ID-Daten - Typname: BuildingElementProxy 98
Type - IFC-Parameter - Typ in IFC-Datei exportieren: Vorgabe
Description: IfcBuildingElementProxy
Pset_BuildingElementProxyCommon - Reference: BuildingElementProxy 98; sets with these values: 2
Andere - Typ: BuildingElementProxy 98; Familie: BuildingElementProxy 98; Familie und Typ: BuildingElementProxy 98: BuildingElementProxy 98; Typ-ID: 2538735
Abhängigkeiten - Höhe von Ebene: 0 m; Verschieben mit umliegenden Elementen: no
Bemaßungen - Fläche: 0.000439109 m2; Volumen: 7.40875e-07 m3
IFC-Parameter - In IFC-Datei exportieren: Nach Typ; In IFC exportieren als: ifcbuildingelementproxy; NameOverride: BuildingElementProxy 98; IfcPresentationLayer: 0; IfcDescription: IfcBuildingElementProxy
Phasen - Phase erstellt: Phase 01

# IfcBuildingElementProxy: BuildingElementProxy 99:BuildingElementProxy 99, BuildingElementProxy 99
In: Erdgeschoss
Type - Material: IfcSurfaceStyle #624876
Type - Andere - Kategorie: Allgemeines Modell; Familienname: BuildingElementProxy 99
Type - ID-Daten - Typname: BuildingElementProxy 99
Type - IFC-Parameter - Typ in IFC-Datei exportieren: Vorgabe
Description: IfcBuildingElementProxy
Pset_BuildingElementProxyCommon - Reference: BuildingElementProxy 99; sets with these values: 2
Andere - Typ: BuildingElementProxy 99; Familie: BuildingElementProxy 99; Familie und Typ: BuildingElementProxy 99: BuildingElementProxy 99; Typ-ID: 2538742
Abhängigkeiten - Höhe von Ebene: 0 m; Verschieben mit umliegenden Elementen: no
Bemaßungen - Fläche: 0.000527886 m2; Volumen: 0.00000249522 m3
IFC-Parameter - In IFC-Datei exportieren: Nach Typ; In IFC exportieren als: ifcbuildingelementproxy; NameOverride: BuildingElementProxy 99; IfcPresentationLayer: 0; IfcDescription: IfcBuildingElementProxy
Phasen - Phase erstellt: Phase 01

# IfcBuildingElementProxy: DirectShape:Gebäudeautomation (89)
Type - Andere - Kategorie: Allgemeines Modell; Familienname: DirectShape
Type - ID-Daten - Typname: Gebäudeautomation
Type - IFC-Parameter - Typ in IFC-Datei exportieren: Vorgabe
Pset_BuildingElementProxyCommon - Reference: Gebäudeautomation; sets with these values: 2
Andere - Typ: Gebäudeautomation; Familie: DirectShape; Familie und Typ: DirectShape: Gebäudeautomation; Typ-ID: 2540517
IFC-Parameter - In IFC-Datei exportieren: Nach Typ
Phasen - Phase erstellt: Phase 01
Tragwerk - Betonüberdeckung: c=2.0cm <2,0 cm>
Group: Modellgruppe:Gebäudeautomation:2542714
Name (DirectShape:...) | In | RRX-Key | RRX-Label | RRX-Funktion
Wärmeversorgungsnetz Vorlauffühler:2540516 | 1. Obergeschoss | =H11.1-WVN-TI01 | Wärmeversorgungsnetz Vorlauffühler | Vorlauffühler
Wärmeversorgungsnetz Rücklauffühler:2540536 | 1. Obergeschoss | =H11.1-WVN-TI02 | Wärmeversorgungsnetz Rücklauffühler | Rücklauffühler
Wärmeversorgungsnetz Differenzdruck:2540553 | 1. Obergeschoss | =H11.1-WVN-PDI01 | Wärmeversorgungsnetz Differenzdruck | Differenzdruck
Wärmeversorgungsnetz Druckaufnehmer:2540570 | 1. Obergeschoss | =H11.1-WVN-PI01 | Wärmeversorgungsnetz Druckaufnehmer | Druckaufnehmer
Wärmeversorgungsnetz Schmutzfänger:2540587 | 1. Obergeschoss | =H11.1-WVN-PDI02 | Wärmeversorgungsnetz Schmutzfänger | Schmutzfänger
Wärmeversorgungsnetz Versorgungspumpe:2540611 | 1. Obergeschoss | =H11.1-WVN-FU-P01 | Wärmeversorgungsnetz Versorgungspumpe | Versorgungspumpe
Wärmeversorgungsnetz Versorgungspumpe:2540631 | 1. Obergeschoss | =H11.1-WVN-FU-P02 | Wärmeversorgungsnetz Versorgungspumpe | Versorgungspumpe
Wärmeversorgungsnetz Versorgungspumpe:2540651 | 1. Obergeschoss | =H11.1-WVN-FU-P03 | Wärmeversorgungsnetz Versorgungspumpe | Versorgungspumpe
Wärmeversorgungsnetz Wärmemengenzähler:2540670 | 1. Obergeschoss | =H11.1-WVN-WMZ01 | Wärmeversorgungsnetz Wärmemengenzähler | Wärmemengenzähler
Wärmeversorgungsnetz Druckaufnehmer:2540687 | 1. Obergeschoss | =H11.1-WVN-PI02 | Wärmeversorgungsnetz Druckaufnehmer | Druckaufnehmer
Wärmeversorgungsnetz Regelventil:2540705 | 1. Obergeschoss | =H11.1-WVN-Y01 | Wärmeversorgungsnetz Regelventil | Regelventil
Wärmeversorgungsnetz Regelventil:2540723 | 1. Obergeschoss | =H11.1-WVN-Y02 | Wärmeversorgungsnetz Regelventil | Regelventil
Wärmeversorgungsnetz Regelventil:2540741 | 1. Obergeschoss | =H11.1-WVN-Y03 | Wärmeversorgungsnetz Regelventil | Regelventil
Wärmeversorgungsnetz Regelventil:2540759 | 1. Obergeschoss | =H11.1-WVN-Y04 | Wärmeversorgungsnetz Regelventil | Regelventil
Wärmespeicher Vorlauffühler:2540809 | 1. Obergeschoss | =H11.1-WSP-TI06 | Wärmespeicher Vorlauffühler | Vorlauffühler
Wärmespeicher Rücklauffühler:2540827 | 1. Obergeschoss | =H11.1-WSP-TI07 | Wärmespeicher Rücklauffühler | Rücklauffühler
Wärmespeicher Vorlauffühler:2540845 | 1. Obergeschoss | =H11.1-WSP-TI08 | Wärmespeicher Vorlauffühler | Vorlauffühler
Wärmespeicher Pufferfühler oben:2540863 | 1. Obergeschoss | =H11.1-WSP-TI01 | Wärmespeicher Pufferfühler oben | Pufferfühler oben
Wärmespeicher Pufferfühler oben mitte:2540881 | 1. Obergeschoss | =H11.1-WSP-TI02 | Wärmespeicher Pufferfühler oben mitte | Pufferfühler oben mitte
Wärmespeicher Pufferfühler mitte:2540899 | 1. Obergeschoss | =H11.1-WSP-TI03 | Wärmespeicher Pufferfühler mitte | Pufferfühler mitte
Wärmespeicher Pufferfühler unten mitte:2540917 | Erdgeschoss | =H11.1-WSP-TI04 | Wärmespeicher Pufferfühler unten mitte | Pufferfühler unten mitte
Wärmespeicher Pufferfühler unten:2540935 | Erdgeschoss | =H11.1-WSP-TI05 | Wärmespeicher Pufferfühler unten | Pufferfühler unten
Heizkessel 1 Brennersteuerung:2541409 | Erdgeschoss | =H11.1-HZK1-A01 | Heizkessel 1 Brennersteuerung | Brennersteuerung
Heizkessel 1 Vorlauffühler:2541427 | Erdgeschoss | =H11.1-HZK1-TI01 | Heizkessel 1 Vorlauffühler | Vorlauffühler
Heizkessel 1 Gasmengenzähler:2541444 | Erdgeschoss | =H11.1-HZK1-GMZ01 | Heizkessel 1 Gasmengenzähler | Gasmengenzähler
Heizkessel 1 Brennermotor:2541460 | Erdgeschoss | =H11.1-HZK1-KES01 | Heizkessel 1 Brennermotor | Brennermotor
Heizkessel 1 Pumpe:2541481 | Erdgeschoss | =H11.1-HZK1-P01 | Heizkessel 1 Pumpe | Pumpe
Heizkessel 1 Regelventil:2541499 | Erdgeschoss | =H11.1-HZK1-Y01 | Heizkessel 1 Regelventil | Regelventil
Heizkessel 1 Rücklauffühler:2541517 | Erdgeschoss | =H11.1-HZK1-TI02 | Heizkessel 1 Rücklauffühler | Rücklauffühler
Heizkessel 2 Brennersteuerung:2541559 | Erdgeschoss | =H11.1-HZK2-A01 | Heizkessel 2 Brennersteuerung | Brennersteuerung
Heizkessel 2 Vorlauffühler:2541577 | Erdgeschoss | =H11.1-HZK2-TI01 | Heizkessel 2 Vorlauffühler | Vorlauffühler
Heizkessel 2 Gasmengenzähler:2541594 | Erdgeschoss | =H11.1-HZK2-GMZ01 | Heizkessel 2 Gasmengenzähler | Gasmengenzähler
Heizkessel 2 Brennermotor:2541610 | Erdgeschoss | =H11.1-HZK2-KES01 | Heizkessel 2 Brennermotor | Brennermotor
Heizkessel 2 Pumpe:2541631 | Erdgeschoss | =H11.1-HZK2-P01 | Heizkessel 2 Pumpe | Pumpe
Heizkessel 2 Regelventil:2541649 | Erdgeschoss | =H11.1-HZK2-Y01 | Heizkessel 2 Regelventil | Regelventil
Heizkessel 2 Rücklauffühler:2541667 | Erdgeschoss | =H11.1-HZK2-TI02 | Heizkessel 2 Rücklauffühler | Rücklauffühler
Heizkessel 3 Brennersteuerung:2541692 | Erdgeschoss | =H11.1-HZK3-A01 | Heizkessel 3 Brennersteuerung | Brennersteuerung
Heizkessel 3 Vorlauffühler:2541707 | Erdgeschoss | =H11.1-HZK3-TI01 | Heizkessel 3 Vorlauffühler | Vorlauffühler
Heizkessel 3 Gasmengenzähler:2541723 | Erdgeschoss | =H11.1-HZK3-GMZ01 | Heizkessel 3 Gasmengenzähler | Gasmengenzähler
Heizkessel 3 Brennermotor:2541737 | Erdgeschoss | =H11.1-HZK3-KES01 | Heizkessel 3 Brennermotor | Brennermotor
Heizkessel 3 Pumpe:2541755 | Erdgeschoss | =H11.1-HZK3-P01 | Heizkessel 3 Pumpe | Pumpe
Heizkessel 3 Regelventil:2541771 | Erdgeschoss | =H11.1-HZK3-Y01 | Heizkessel 3 Regelventil | Regelventil
Heizkessel 3 Rücklauffühler:2541786 | Erdgeschoss | =H11.1-HZK3-TI02 | Heizkessel 3 Rücklauffühler | Rücklauffühler
Blockheizkreaftwerk Gasmengenzähler:2541823 | Erdgeschoss | =H11.1-BHKW-GMZ01 | Blockheizkreaftwerk Gasmengenzähler | Gasmengenzähler
Blockheizkreaftwerk Wärmemengenzähler:2541841 | 1. Obergeschoss | =H11.1-BHKW-WMZ01 | Blockheizkreaftwerk Wärmemengenzähler | Wärmemengenzähler
Blockheizkreaftwerk:2541876 | Erdgeschoss | =H11.1-BHKW-A01 | Blockheizkreaftwerk
Blockheizkreaftwerk Gaswarngerät:2541893 | Erdgeschoss | =H11.1-BHKW-A02 | Blockheizkreaftwerk Gaswarngerät | Gaswarngerät
Blockheizkreaftwerk Neutralisation:2541911 | Erdgeschoss | =H11.1-BHKW-E01 | Blockheizkreaftwerk Neutralisation | Neutralisation
Lüftung Maschinenhalle Abluftventilator 1:2541933 | 1. Obergeschoss | =H11.1-RLT-VENT01 | Lüftung Maschinenhalle Abluftventilator 1 | Abluftventilator 1
Lüftung Maschinenhalle Abluftventilator 2:2541951 | 1. Obergeschoss | =H11.1-RLT-VENT02 | Lüftung Maschinenhalle Abluftventilator 2 | Abluftventilator 2
Schaltschranktür Versorgungspumpe 1:2541967 | 1. Obergeschoss | =H11.1-SST-HHA01 | Schaltschranktür Versorgungspumpe 1 | Versorgungspumpe 1
Schaltschranktür Versorgungspumpe 2:2541983 | 1. Obergeschoss | =H11.1-SST-HHA02 | Schaltschranktür Versorgungspumpe 2 | Versorgungspumpe 2
Schaltschranktür Versorgungspumpe 3:2541999 | 1. Obergeschoss | =H11.1-SST-HHA03 | Schaltschranktür Versorgungspumpe 3 | Versorgungspumpe 3
Schaltschranktür Heizkessel 1:2542015 | 1. Obergeschoss | =H11.1-SST-HHA04 | Schaltschranktür Heizkessel 1 | Heizkessel 1
Schaltschranktür Heizkessel 2:2542031 | 1. Obergeschoss | =H11.1-SST-HHA05 | Schaltschranktür Heizkessel 2 | Heizkessel 2
Schaltschranktür Heizkessel 3:2542047 | 1. Obergeschoss | =H11.1-SST-HHA06 | Schaltschranktür Heizkessel 3 | Heizkessel 3
Schaltschranktür BHKW:2542063 | 1. Obergeschoss | =H11.1-SST-HHA07 | Schaltschranktür BHKW | BHKW
Wärmeerzeugung Vorlauffühler:2542089 | Erdgeschoss | =H11.1-WEZ-TI01 | Wärmeerzeugung Vorlauffühler | Vorlauffühler
Wärmeerzeugung Rücklauffühler:2542107 | 1. Obergeschoss | =H11.1-WEZ-TI02 | Wärmeerzeugung Rücklauffühler | Rücklauffühler
Wärmeerzeugung Druckaufnehmer:2542124 | 1. Obergeschoss | =H11.1-WEZ-PI01 | Wärmeerzeugung Druckaufnehmer | Druckaufnehmer
Sanitär Osmoseanlage:2542140 | 1. Obergeschoss | =H11.1-SAN-A01 | Sanitär Osmoseanlage | Osmoseanlage
Sanitär Druckhaltung:2542158 | 1. Obergeschoss | =H11.1-SAN-A02 | Sanitär Druckhaltung | Druckhaltung
Sanitär Reinwasserbehälter:2542174 | 1. Obergeschoss | =H11.1-SAN-A03 | Sanitär Reinwasserbehälter | Reinwasserbehälter
Sanitär Dosierung:2542191 | 1. Obergeschoss | =H11.1-SAN-A04 | Sanitär Dosierung | Dosierung
Sanitär Druckerhöhungsanlage:2542207 | 1. Obergeschoss | =H11.1-SAN-A11 | Sanitär Druckerhöhungsanlage | Druckerhöhungsanlage
Verteiler Rücklauffühler:2542273 | 1. Obergeschoss | =H11.1-HKV-TI01 | Verteiler Rücklauffühler | Rücklauffühler | ID-Daten - RRX-Articles[0]: Name: THM 200mm | Beschreibung: THM Tauchhülse Messing für STP 200 mm | Hersteller: Schneider Electric | Kuerzel: SE | Gruppe: Fühler Wasser
Verteiler Ventil Nachspeisung:2542290 | 1. Obergeschoss | =H11.1-HKV-Y01 | Verteiler Ventil Nachspeisung | Ventil Nachspeisung | ID-Daten - RRX-Articles[0]: Name: H6125S/EV24A-MP-TPC | Beschreibung: Hubventil, 2-Weg, DN 125, kvs 220 m³/h | Hersteller: Belimo | Kuerzel: BEL | Gruppe: Hubventil mit Antrieb
Verteiler Rücklauffühler:2542308 | 1. Obergeschoss | =H11.1-HKV-TI02 | Verteiler Rücklauffühler | Rücklauffühler | ID-Daten - RRX-Articles[0]: Name: THM 200mm | Beschreibung: THM Tauchhülse Messing für STP 200 mm | Hersteller: Schneider Electric | Kuerzel: SE | Gruppe: Fühler Wasser
Verteiler Rücklauffühler:2542326 | 1. Obergeschoss | =H11.1-HKV-TI03 | Verteiler Rücklauffühler | Rücklauffühler | ID-Daten - RRX-Articles[0]: Name: THM 200mm | Beschreibung: THM Tauchhülse Messing für STP 200 mm | Hersteller: Schneider Electric | Kuerzel: SE | Gruppe: Fühler Wasser
Schaltschrank Aussenfühler:2542347 | Erdgeschoss | =H11.1-SSK-B01 | Schaltschrank Aussenfühler | Aussenfühler | ID-Daten - RRX-Articles[0]: Name: 01UT-1F | Beschreibung: Aussensensor Temperatur passiv, NTC1k8 | Hersteller: Belimo | Kuerzel: Bel | Gruppe: Aussensensor
Schaltschrank:2542381 | 1. Obergeschoss | =H11.1-SSK01 | Schaltschrank | ID-Daten - RRX-Articles[0]: Name: M-Bus/Modbus-TCP-Gateway | Beschreibung: Bis zu 20 M-Bus Loads | Hersteller: Anybus | Kuerzel: Anybus | Gruppe: Gateway; RRX-Articles[1]: Name: UK24MOD | Beschreibung: Gateway MP zu Modbus RTU | Hersteller: Belimo | Kuerzel: BEL | Gruppe: Gateway
Gebäudeautomation:2542399 | 1. Obergeschoss | M01 |  | PS-24V | ID-Daten - RRX-Articles[0]: Name: SmartX PS-24V | Beschreibung: PS-24V Spannungsversorgung 24 VAC/VDC | Hersteller: Schneider Electric | Kuerzel: SE | Gruppe: Automationsstationen; RRX-Articles[1]: Name: SmartX PS-24V | Beschreibung: PS-24V Spannungsversorgung 24 VAC/VDC | Hersteller: Schneider Electric | Kuerzel: SE | Gruppe: Automationsstationen; RRX-Zubehör[0]: Name: SmartX PS-24V | Beschreibung: PS-24V Spannungsversorgung 24 VAC/VDC | Hersteller: Schneider Electric | Kuerzel: SE | Gruppe: Automationsstationen; RRX-Zubehör[1]: Name: SmartX PS-24V | Beschreibung: PS-24V Spannungsversorgung 24 VAC/VDC | Hersteller: Schneider Electric | Kuerzel: SE | Gruppe: Automationsstationen
Gebäudeautomation:2542417 | 1. Obergeschoss | M02 |  | AS-P | ID-Daten - RRX-Articles[0]: Name: SmartX AS-P | Beschreibung: Controller AS-P | Hersteller: Schneider Electric | Kuerzel: SE | Gruppe: Automationsstationen; RRX-Articles[1]: Name: Sockel AS-P | Beschreibung: TB-ASP-W1 Sockel für AS-P und AS-P-NL (W1) | Hersteller: Schneider Electric | Kuerzel: SE | Gruppe: Automationsstationen; RRX-Zubehör[0]: Name: SmartX AS-P | Beschreibung: Controller AS-P | Hersteller: Schneider Electric | Kuerzel: SE | Gruppe: Automationsstationen; RRX-Zubehör[1]: Name: Sockel AS-P | Beschreibung: TB-ASP-W1 Sockel für AS-P und AS-P-NL (W1) | Hersteller: Schneider Electric | Kuerzel: SE | Gruppe: Automationsstationen
Gebäudeautomation:2542435 | 1. Obergeschoss | M03 |  | DO-FA-12-H | ID-Daten - RRX-Articles[0]: Name: SmartX Modul DO-FA-12-H | Beschreibung: Modul DO-FA-12-H - 12 Digitalausgänge (Schließer) Hand | Hersteller: Schneider Electric | Kuerzel: SE | Gruppe: Automationsstationen; RRX-Articles[1]: Name: Sockel IO | Beschreibung: TB-IO-W1 Sockel für I/O-Module | Hersteller: Schneider Electric | Kuerzel: SE | Gruppe: Automationsstationen; RRX-Zubehör[0]: Name: SmartX Modul DO-FA-12-H | Beschreibung: Modul DO-FA-12-H - 12 Digitalausgänge (Schließer) Hand | Hersteller: Schneider Electric | Kuerzel: SE | Gruppe: Automationsstationen; RRX-Zubehör[1]: Name: Sockel IO | Beschreibung: TB-IO-W1 Sockel für I/O-Module | Hersteller: Schneider Electric | Kuerzel: SE | Gruppe: Automationsstationen
Gebäudeautomation:2542453 | 1. Obergeschoss | M04 |  | DO-FA-12-H | ID-Daten - RRX-Articles[0]: Name: SmartX Modul DO-FA-12-H | Beschreibung: Modul DO-FA-12-H - 12 Digitalausgänge (Schließer) Hand | Hersteller: Schneider Electric | Kuerzel: SE | Gruppe: Automationsstationen; RRX-Articles[1]: Name: Sockel IO | Beschreibung: TB-IO-W1 Sockel für I/O-Module | Hersteller: Schneider Electric | Kuerzel: SE | Gruppe: Automationsstationen; RRX-Zubehör[0]: Name: SmartX Modul DO-FA-12-H | Beschreibung: Modul DO-FA-12-H - 12 Digitalausgänge (Schließer) Hand | Hersteller: Schneider Electric | Kuerzel: SE | Gruppe: Automationsstationen; RRX-Zubehör[1]: Name: Sockel IO | Beschreibung: TB-IO-W1 Sockel für I/O-Module | Hersteller: Schneider Electric | Kuerzel: SE | Gruppe: Automationsstationen
Gebäudeautomation:2542471 | 1. Obergeschoss | M05 |  | AO-V-8-H | ID-Daten - RRX-Articles[0]: Name: SmartX Modul AO-V-8-H | Beschreibung: Modul AO-V-8-H - 8 Analogausgänge (Spannung) Hand | Hersteller: Schneider Electric | Kuerzel: SE | Gruppe: Automationsstationen; RRX-Articles[1]: Name: Sockel IO | Beschreibung: TB-IO-W1 Sockel für I/O-Module | Hersteller: Schneider Electric | Kuerzel: SE | Gruppe: Automationsstationen; RRX-Zubehör[0]: Name: SmartX Modul AO-V-8-H | Beschreibung: Modul AO-V-8-H - 8 Analogausgänge (Spannung) Hand | Hersteller: Schneider Electric | Kuerzel: SE | Gruppe: Automationsstationen; RRX-Zubehör[1]: Name: Sockel IO | Beschreibung: TB-IO-W1 Sockel für I/O-Module | Hersteller: Schneider Electric | Kuerzel: SE | Gruppe: Automationsstationen
Gebäudeautomation:2542489 | 1. Obergeschoss | M06 |  | DO-FA-12-H | ID-Daten - RRX-Articles[0]: Name: SmartX Modul DO-FA-12-H | Beschreibung: Modul DO-FA-12-H - 12 Digitalausgänge (Schließer) Hand | Hersteller: Schneider Electric | Kuerzel: SE | Gruppe: Automationsstationen; RRX-Articles[1]: Name: Sockel IO | Beschreibung: TB-IO-W1 Sockel für I/O-Module | Hersteller: Schneider Electric | Kuerzel: SE | Gruppe: Automationsstationen; RRX-Zubehör[0]: Name: SmartX Modul DO-FA-12-H | Beschreibung: Modul DO-FA-12-H - 12 Digitalausgänge (Schließer) Hand | Hersteller: Schneider Electric | Kuerzel: SE | Gruppe: Automationsstationen; RRX-Zubehör[1]: Name: Sockel IO | Beschreibung: TB-IO-W1 Sockel für I/O-Module | Hersteller: Schneider Electric | Kuerzel: SE | Gruppe: Automationsstationen
Gebäudeautomation:2542507 | 1. Obergeschoss | M07 |  | UI-8-AO-V-4-H | ID-Daten - RRX-Articles[0]: Name: SmartX Modul UI-8/AO-V-4-H | Beschreibung: Modul UI-8/AO-V-4-H - Universalein-/Analogausg. (V) Hand | Hersteller: Schneider Electric | Kuerzel: SE | Gruppe: Automationsstationen; RRX-Articles[1]: Name: Sockel IO | Beschreibung: TB-IO-W1 Sockel für I/O-Module | Hersteller: Schneider Electric | Kuerzel: SE | Gruppe: Automationsstationen; RRX-Zubehör[0]: Name: SmartX Modul UI-8/AO-V-4-H | Beschreibung: Modul UI-8/AO-V-4-H - Universalein-/Analogausg. (V) Hand | Hersteller: Schneider Electric | Kuerzel: SE | Gruppe: Automationsstationen; RRX-Zubehör[1]: Name: Sockel IO | Beschreibung: TB-IO-W1 Sockel für I/O-Module | Hersteller: Schneider Electric | Kuerzel: SE | Gruppe: Automationsstationen
Gebäudeautomation:2542525 | 1. Obergeschoss | M08 |  | UI-16 | ID-Daten - RRX-Articles[0]: Name: SmartX Modul UI-16 | Beschreibung: Modul UI-16 - 16 Universaleingänge | Hersteller: Schneider Electric | Kuerzel: SE | Gruppe: Automationsstationen; RRX-Articles[1]: Name: Sockel IO | Beschreibung: TB-IO-W1 Sockel für I/O-Module | Hersteller: Schneider Electric | Kuerzel: SE | Gruppe: Automationsstationen; RRX-Zubehör[0]: Name: SmartX Modul UI-16 | Beschreibung: Modul UI-16 - 16 Universaleingänge | Hersteller: Schneider Electric | Kuerzel: SE | Gruppe: Automationsstationen; RRX-Zubehör[1]: Name: Sockel IO | Beschreibung: TB-IO-W1 Sockel für I/O-Module | Hersteller: Schneider Electric | Kuerzel: SE | Gruppe: Automationsstationen
Gebäudeautomation:2542543 | 1. Obergeschoss | M09 |  | DI-16 | ID-Daten - RRX-Articles[0]: Name: SmartX Modul DI-16 | Beschreibung: Modul DI-16 - 16 Digitaleingänge | Hersteller: Schneider Electric | Kuerzel: SE | Gruppe: Automationsstationen; RRX-Articles[1]: Name: Sockel IO | Beschreibung: TB-IO-W1 Sockel für I/O-Module | Hersteller: Schneider Electric | Kuerzel: SE | Gruppe: Automationsstationen; RRX-Zubehör[0]: Name: SmartX Modul DI-16 | Beschreibung: Modul DI-16 - 16 Digitaleingänge | Hersteller: Schneider Electric | Kuerzel: SE | Gruppe: Automationsstationen; RRX-Zubehör[1]: Name: Sockel IO | Beschreibung: TB-IO-W1 Sockel für I/O-Module | Hersteller: Schneider Electric | Kuerzel: SE | Gruppe: Automationsstationen
Gebäudeautomation:2542561 | 1. Obergeschoss | M10 |  | DI-16 | ID-Daten - RRX-Articles[0]: Name: SmartX Modul DI-16 | Beschreibung: Modul DI-16 - 16 Digitaleingänge | Hersteller: Schneider Electric | Kuerzel: SE | Gruppe: Automationsstationen; RRX-Articles[1]: Name: Sockel IO | Beschreibung: TB-IO-W1 Sockel für I/O-Module | Hersteller: Schneider Electric | Kuerzel: SE | Gruppe: Automationsstationen; RRX-Zubehör[0]: Name: SmartX Modul DI-16 | Beschreibung: Modul DI-16 - 16 Digitaleingänge | Hersteller: Schneider Electric | Kuerzel: SE | Gruppe: Automationsstationen; RRX-Zubehör[1]: Name: Sockel IO | Beschreibung: TB-IO-W1 Sockel für I/O-Module | Hersteller: Schneider Electric | Kuerzel: SE | Gruppe: Automationsstationen
Gebäudeautomation:2542579 | 1. Obergeschoss | M11 |  | DI-16 | ID-Daten - RRX-Articles[0]: Name: SmartX Modul DI-16 | Beschreibung: Modul DI-16 - 16 Digitaleingänge | Hersteller: Schneider Electric | Kuerzel: SE | Gruppe: Automationsstationen; RRX-Articles[1]: Name: Sockel IO | Beschreibung: TB-IO-W1 Sockel für I/O-Module | Hersteller: Schneider Electric | Kuerzel: SE | Gruppe: Automationsstationen; RRX-Zubehör[0]: Name: SmartX Modul DI-16 | Beschreibung: Modul DI-16 - 16 Digitaleingänge | Hersteller: Schneider Electric | Kuerzel: SE | Gruppe: Automationsstationen; RRX-Zubehör[1]: Name: Sockel IO | Beschreibung: TB-IO-W1 Sockel für I/O-Module | Hersteller: Schneider Electric | Kuerzel: SE | Gruppe: Automationsstationen
Gebäudeautomation:2542597 | 1. Obergeschoss | M12 |  | DI-16 | ID-Daten - RRX-Articles[0]: Name: SmartX Modul DI-16 | Beschreibung: Modul DI-16 - 16 Digitaleingänge | Hersteller: Schneider Electric | Kuerzel: SE | Gruppe: Automationsstationen; RRX-Articles[1]: Name: Sockel IO | Beschreibung: TB-IO-W1 Sockel für I/O-Module | Hersteller: Schneider Electric | Kuerzel: SE | Gruppe: Automationsstationen; RRX-Zubehör[0]: Name: SmartX Modul DI-16 | Beschreibung: Modul DI-16 - 16 Digitaleingänge | Hersteller: Schneider Electric | Kuerzel: SE | Gruppe: Automationsstationen; RRX-Zubehör[1]: Name: Sockel IO | Beschreibung: TB-IO-W1 Sockel für I/O-Module | Hersteller: Schneider Electric | Kuerzel: SE | Gruppe: Automationsstationen
Gebäudeautomation:2542615 | 1. Obergeschoss | M13 |  | DI-16 | ID-Daten - RRX-Articles[0]: Name: SmartX Modul DI-16 | Beschreibung: Modul DI-16 - 16 Digitaleingänge | Hersteller: Schneider Electric | Kuerzel: SE | Gruppe: Automationsstationen; RRX-Articles[1]: Name: Sockel IO | Beschreibung: TB-IO-W1 Sockel für I/O-Module | Hersteller: Schneider Electric | Kuerzel: SE | Gruppe: Automationsstationen; RRX-Zubehör[0]: Name: SmartX Modul DI-16 | Beschreibung: Modul DI-16 - 16 Digitaleingänge | Hersteller: Schneider Electric | Kuerzel: SE | Gruppe: Automationsstationen; RRX-Zubehör[1]: Name: Sockel IO | Beschreibung: TB-IO-W1 Sockel für I/O-Module | Hersteller: Schneider Electric | Kuerzel: SE | Gruppe: Automationsstationen
Gebäudeautomation:2542633 | 1. Obergeschoss | M14 |  | DI-16 | ID-Daten - RRX-Articles[0]: Name: SmartX Modul DI-16 | Beschreibung: Modul DI-16 - 16 Digitaleingänge | Hersteller: Schneider Electric | Kuerzel: SE | Gruppe: Automationsstationen; RRX-Articles[1]: Name: Sockel IO | Beschreibung: TB-IO-W1 Sockel für I/O-Module | Hersteller: Schneider Electric | Kuerzel: SE | Gruppe: Automationsstationen; RRX-Zubehör[0]: Name: SmartX Modul DI-16 | Beschreibung: Modul DI-16 - 16 Digitaleingänge | Hersteller: Schneider Electric | Kuerzel: SE | Gruppe: Automationsstationen; RRX-Zubehör[1]: Name: Sockel IO | Beschreibung: TB-IO-W1 Sockel für I/O-Module | Hersteller: Schneider Electric | Kuerzel: SE | Gruppe: Automationsstationen
Gebäudeautomation:2542651 | 1. Obergeschoss | M15 |  | PS-24V | ID-Daten - RRX-Articles[0]: Name: SmartX PS-24V | Beschreibung: PS-24V Spannungsversorgung 24 VAC/VDC | Hersteller: Schneider Electric | Kuerzel: SE | Gruppe: Automationsstationen; RRX-Articles[1]: Name: SmartX PS-24V | Beschreibung: PS-24V Spannungsversorgung 24 VAC/VDC | Hersteller: Schneider Electric | Kuerzel: SE | Gruppe: Automationsstationen; RRX-Zubehör[0]: Name: SmartX PS-24V | Beschreibung: PS-24V Spannungsversorgung 24 VAC/VDC | Hersteller: Schneider Electric | Kuerzel: SE | Gruppe: Automationsstationen; RRX-Zubehör[1]: Name: SmartX PS-24V | Beschreibung: PS-24V Spannungsversorgung 24 VAC/VDC | Hersteller: Schneider Electric | Kuerzel: SE | Gruppe: Automationsstationen
Gebäudeautomation:2542669 | 1. Obergeschoss | M16 |  | DI-16 | ID-Daten - RRX-Articles[0]: Name: SmartX Modul DI-16 | Beschreibung: Modul DI-16 - 16 Digitaleingänge | Hersteller: Schneider Electric | Kuerzel: SE | Gruppe: Automationsstationen; RRX-Articles[1]: Name: Sockel IO | Beschreibung: TB-IO-W1 Sockel für I/O-Module | Hersteller: Schneider Electric | Kuerzel: SE | Gruppe: Automationsstationen; RRX-Zubehör[0]: Name: SmartX Modul DI-16 | Beschreibung: Modul DI-16 - 16 Digitaleingänge | Hersteller: Schneider Electric | Kuerzel: SE | Gruppe: Automationsstationen; RRX-Zubehör[1]: Name: Sockel IO | Beschreibung: TB-IO-W1 Sockel für I/O-Module | Hersteller: Schneider Electric | Kuerzel: SE | Gruppe: Automationsstationen
Gebäudeautomation:2542687 | 1. Obergeschoss | M17 |  | UI-16 | ID-Daten - RRX-Articles[0]: Name: SmartX Modul UI-16 | Beschreibung: Modul UI-16 - 16 Universaleingänge | Hersteller: Schneider Electric | Kuerzel: SE | Gruppe: Automationsstationen; RRX-Articles[1]: Name: Sockel IO | Beschreibung: TB-IO-W1 Sockel für I/O-Module | Hersteller: Schneider Electric | Kuerzel: SE | Gruppe: Automationsstationen; RRX-Zubehör[0]: Name: SmartX Modul UI-16 | Beschreibung: Modul UI-16 - 16 Universaleingänge | Hersteller: Schneider Electric | Kuerzel: SE | Gruppe: Automationsstationen; RRX-Zubehör[1]: Name: Sockel IO | Beschreibung: TB-IO-W1 Sockel für I/O-Module | Hersteller: Schneider Electric | Kuerzel: SE | Gruppe: Automationsstationen
Gebäudeautomation:2542705 | 1. Obergeschoss | M18 |  | UI-16 | ID-Daten - RRX-Articles[0]: Name: SmartX Modul UI-16 | Beschreibung: Modul UI-16 - 16 Universaleingänge | Hersteller: Schneider Electric | Kuerzel: SE | Gruppe: Automationsstationen; RRX-Articles[1]: Name: Sockel IO | Beschreibung: TB-IO-W1 Sockel für I/O-Module | Hersteller: Schneider Electric | Kuerzel: SE | Gruppe: Automationsstationen; RRX-Zubehör[0]: Name: SmartX Modul UI-16 | Beschreibung: Modul UI-16 - 16 Universaleingänge | Hersteller: Schneider Electric | Kuerzel: SE | Gruppe: Automationsstationen; RRX-Zubehör[1]: Name: Sockel IO | Beschreibung: TB-IO-W1 Sockel für I/O-Module | Hersteller: Schneider Electric | Kuerzel: SE | Gruppe: Automationsstationen

# IfcBuildingElementProxy: Quader 228470:Quader 228470, Quader
In: 1. Obergeschoss
Type - Material: IfcSurfaceStyle #228457
Type - Andere - Kategorie: Allgemeines Modell; Familienname: Quader 228470
Type - ID-Daten - Typname: Quader 228470
Type - IFC-Parameter - Typ in IFC-Datei exportieren: Vorgabe
Description: Quader
Pset_BuildingElementProxyCommon - Reference: Quader 228470; sets with these values: 2
Andere - Typ: Quader 228470; Familie: Quader 228470; Familie und Typ: Quader 228470: Quader 228470; Typ-ID: 2532144
Abhängigkeiten - Höhe von Ebene: 0 m; Verschieben mit umliegenden Elementen: no
Bemaßungen - Fläche: 3.2 m2; Volumen: 0.8 m3
IFC-Parameter - In IFC-Datei exportieren: Nach Typ; In IFC exportieren als: ifcbuildingelementproxy; NameOverride: Quader; IfcPresentationLayer: 0-TFT-X_Geometrie; ObjectTypeOverride: Quader; IfcDescription: Quader; Pset nova - Archi.Name: Quader
Phasen - Phase erstellt: Phase 01

# IfcBuildingElementProxy: Quader 228493:Quader 228493, Quader
In: 1. Obergeschoss
Type - Material: IfcSurfaceStyle #228457
Type - Andere - Kategorie: Allgemeines Modell; Familienname: Quader 228493
Type - ID-Daten - Typname: Quader 228493
Type - IFC-Parameter - Typ in IFC-Datei exportieren: Vorgabe
Description: Quader
Pset_BuildingElementProxyCommon - Reference: Quader 228493; sets with these values: 2
Andere - Typ: Quader 228493; Familie: Quader 228493; Familie und Typ: Quader 228493: Quader 228493; Typ-ID: 2532151
Abhängigkeiten - Höhe von Ebene: 0 m; Verschieben mit umliegenden Elementen: no
Bemaßungen - Fläche: 3.2 m2; Volumen: 0.8 m3
IFC-Parameter - In IFC-Datei exportieren: Nach Typ; In IFC exportieren als: ifcbuildingelementproxy; NameOverride: Quader; IfcPresentationLayer: 0-TFT-X_Geometrie; ObjectTypeOverride: Quader; IfcDescription: Quader; Pset nova - Archi.Name: Quader
Phasen - Phase erstellt: Phase 01

# IfcBuildingElementProxy: Quader 270063:Quader 270063, Quader
In: 1. Obergeschoss
Type - Material: IfcSurfaceStyle #270045
Type - Andere - Kategorie: Allgemeines Modell; Familienname: Quader 270063
Type - ID-Daten - Typname: Quader 270063
Type - IFC-Parameter - Typ in IFC-Datei exportieren: Vorgabe
Description: Quader
Pset_BuildingElementProxyCommon - Reference: Quader 270063; sets with these values: 2
Andere - Typ: Quader 270063; Familie: Quader 270063; Familie und Typ: Quader 270063: Quader 270063; Typ-ID: 2533355
Abhängigkeiten - Höhe von Ebene: 0 m; Verschieben mit umliegenden Elementen: no
Bemaßungen - Fläche: 1.1042 m2; Volumen: 0.19292 m3
IFC-Parameter - In IFC-Datei exportieren: Nach Typ; In IFC exportieren als: ifcbuildingelementproxy; NameOverride: Quader; IfcPresentationLayer: 0-TFT-S_Einrichtungsgegenstände; ObjectTypeOverride: Quader; IfcDescription: Quader; Pset nova - Archi.Name: Quader
Phasen - Phase erstellt: Phase 01

# IfcBuildingElementProxy: Quader 270130:Quader 270130, Quader
In: 1. Obergeschoss
Type - Material: IfcSurfaceStyle #270045
Type - Andere - Kategorie: Allgemeines Modell; Familienname: Quader 270130
Type - ID-Daten - Typname: Quader 270130
Type - IFC-Parameter - Typ in IFC-Datei exportieren: Vorgabe
Description: Quader
Pset_BuildingElementProxyCommon - Reference: Quader 270130; sets with these values: 2
Andere - Typ: Quader 270130; Familie: Quader 270130; Familie und Typ: Quader 270130: Quader 270130; Typ-ID: 2533362
Abhängigkeiten - Höhe von Ebene: 0 m; Verschieben mit umliegenden Elementen: no
Bemaßungen - Fläche: 3.5724 m2; Volumen: 1.15596 m3
IFC-Parameter - In IFC-Datei exportieren: Nach Typ; In IFC exportieren als: ifcbuildingelementproxy; NameOverride: Quader; IfcPresentationLayer: 0-TFT-S_Einrichtungsgegenstände; ObjectTypeOverride: Quader; IfcDescription: Quader; Pset nova - Archi.Name: Quader
Phasen - Phase erstellt: Phase 01

# IfcBuildingElementProxy: Quader 270197:Quader 270197, Quader
In: 1. Obergeschoss
Type - Material: IfcSurfaceStyle #270045
Type - Andere - Kategorie: Allgemeines Modell; Familienname: Quader 270197
Type - ID-Daten - Typname: Quader 270197
Type - IFC-Parameter - Typ in IFC-Datei exportieren: Vorgabe
Description: Quader
Pset_BuildingElementProxyCommon - Reference: Quader 270197; sets with these values: 2
Andere - Typ: Quader 270197; Familie: Quader 270197; Familie und Typ: Quader 270197: Quader 270197; Typ-ID: 2533369
Abhängigkeiten - Höhe von Ebene: 0 m; Verschieben mit umliegenden Elementen: no
Bemaßungen - Fläche: 3.5724 m2; Volumen: 1.15596 m3
IFC-Parameter - In IFC-Datei exportieren: Nach Typ; In IFC exportieren als: ifcbuildingelementproxy; NameOverride: Quader; IfcPresentationLayer: 0-TFT-S_Einrichtungsgegenstände; ObjectTypeOverride: Quader; IfcDescription: Quader; Pset nova - Archi.Name: Quader
Phasen - Phase erstellt: Phase 01

# IfcBuildingElementProxy: Quader 270220:Quader 270220, Quader
In: 1. Obergeschoss
Type - Material: IfcSurfaceStyle #270045
Type - Andere - Kategorie: Allgemeines Modell; Familienname: Quader 270220
Type - ID-Daten - Typname: Quader 270220
Type - IFC-Parameter - Typ in IFC-Datei exportieren: Vorgabe
Description: Quader
Pset_BuildingElementProxyCommon - Reference: Quader 270220; sets with these values: 2
Andere - Typ: Quader 270220; Familie: Quader 270220; Familie und Typ: Quader 270220: Quader 270220; Typ-ID: 2533376
Abhängigkeiten - Höhe von Ebene: 0 m; Verschieben mit umliegenden Elementen: no
Bemaßungen - Fläche: 1.1436 m2; Volumen: 0.19503 m3
IFC-Parameter - In IFC-Datei exportieren: Nach Typ; In IFC exportieren als: ifcbuildingelementproxy; NameOverride: Quader; IfcPresentationLayer: 0-TFT-S_Einrichtungsgegenstände; ObjectTypeOverride: Quader; IfcDescription: Quader; Pset nova - Archi.Name: Quader
Phasen - Phase erstellt: Phase 01

# IfcBuildingElementProxy: Quader 270309:Quader 270309, Quader
In: 1. Obergeschoss
Type - Material: IfcSurfaceStyle #270045
Type - Andere - Kategorie: Allgemeines Modell; Familienname: Quader 270309
Type - ID-Daten - Typname: Quader 270309
Type - IFC-Parameter - Typ in IFC-Datei exportieren: Vorgabe
Description: Quader
Pset_BuildingElementProxyCommon - Reference: Quader 270309; sets with these values: 2
Andere - Typ: Quader 270309; Familie: Quader 270309; Familie und Typ: Quader 270309: Quader 270309; Typ-ID: 2533395
Abhängigkeiten - Höhe von Ebene: 0 m; Verschieben mit umliegenden Elementen: no
Bemaßungen - Fläche: 1.716 m2; Volumen: 0.4068 m3
IFC-Parameter - In IFC-Datei exportieren: Nach Typ; In IFC exportieren als: ifcbuildingelementproxy; NameOverride: Quader; IfcPresentationLayer: 0-TFT-S_Einrichtungsgegenstände; ObjectTypeOverride: Quader; IfcDescription: Quader; Pset nova - Archi.Name: Quader
Phasen - Phase erstellt: Phase 01

# IfcBuildingElementProxy: Quader 277766:Quader 277766, Quader
In: Erdgeschoss
Type - Material: IfcSurfaceStyle #277833
Type - Andere - Kategorie: Allgemeines Modell; Familienname: Quader 277766
Type - ID-Daten - Typname: Quader 277766
Type - IFC-Parameter - Typ in IFC-Datei exportieren: Vorgabe
Description: Quader
Pset_BuildingElementProxyCommon - Reference: Quader 277766; sets with these values: 2
Andere - Typ: Quader 277766; Familie: Quader 277766; Familie und Typ: Quader 277766: Quader 277766; Typ-ID: 2533893
Abhängigkeiten - Höhe von Ebene: 0 m; Verschieben mit umliegenden Elementen: no
Bemaßungen - Fläche: 15.8 m2
IFC-Parameter - In IFC-Datei exportieren: Nach Typ; In IFC exportieren als: ifcbuildingelementproxy; NameOverride: Quader; IfcPresentationLayer: 0-TFT-H_Bauteil; ObjectTypeOverride: Quader; IfcDescription: Quader; Pset nova - Archi.Name: Quader
Phasen - Phase erstellt: Phase 01

# IfcBuildingElementProxy: Quader 277839:Quader 277839, Quader
In: Erdgeschoss
Type - Material: IfcSurfaceStyle #271082
Type - Andere - Kategorie: Allgemeines Modell; Familienname: Quader 277839
Type - ID-Daten - Typname: Quader 277839
Type - IFC-Parameter - Typ in IFC-Datei exportieren: Vorgabe
Description: Quader
Pset_BuildingElementProxyCommon - Reference: Quader 277839; sets with these values: 2
Andere - Typ: Quader 277839; Familie: Quader 277839; Familie und Typ: Quader 277839: Quader 277839; Typ-ID: 2533903
Abhängigkeiten - Höhe von Ebene: 0 m; Verschieben mit umliegenden Elementen: no
Bemaßungen - Fläche: 16.7637 m2; Volumen: 12.1595 m3
IFC-Parameter - In IFC-Datei exportieren: Nach Typ; In IFC exportieren als: ifcbuildingelementproxy; NameOverride: Quader; IfcPresentationLayer: 0-TFT-H_Variante 2 Kessel; ObjectTypeOverride: Quader; IfcDescription: Quader; Pset nova - Archi.Name: Quader
Phasen - Phase erstellt: Phase 01

# IfcBuildingElementProxy: Quader 277908:Quader 277908, Quader
In: Erdgeschoss
Type - Material: IfcSurfaceStyle #271082
Type - Andere - Kategorie: Allgemeines Modell; Familienname: Quader 277908
Type - ID-Daten - Typname: Quader 277908
Type - IFC-Parameter - Typ in IFC-Datei exportieren: Vorgabe
Description: Quader
Pset_BuildingElementProxyCommon - Reference: Quader 277908; sets with these values: 2
Andere - Typ: Quader 277908; Familie: Quader 277908; Familie und Typ: Quader 277908: Quader 277908; Typ-ID: 2533910
Abhängigkeiten - Höhe von Ebene: 0 m; Verschieben mit umliegenden Elementen: no
Bemaßungen - Fläche: 16.7637 m2; Volumen: 12.1595 m3
IFC-Parameter - In IFC-Datei exportieren: Nach Typ; In IFC exportieren als: ifcbuildingelementproxy; NameOverride: Quader; IfcPresentationLayer: 0-TFT-H_Variante 2 Kessel; ObjectTypeOverride: Quader; IfcDescription: Quader; Pset nova - Archi.Name: Quader
Phasen - Phase erstellt: Phase 01

# IfcBuildingElementProxy: Quader 277931:Quader 277931, Quader
In: Erdgeschoss
Type - Material: IfcSurfaceStyle #277
Type - Andere - Kategorie: Allgemeines Modell; Familienname: Quader 277931
Type - ID-Daten - Typname: Quader 277931
Type - IFC-Parameter - Typ in IFC-Datei exportieren: Vorgabe
Description: Quader
Pset_BuildingElementProxyCommon - Reference: Quader 277931; sets with these values: 2
Andere - Typ: Quader 277931; Familie: Quader 277931; Familie und Typ: Quader 277931: Quader 277931; Typ-ID: 2533917
Abhängigkeiten - Höhe von Ebene: 0 m; Verschieben mit umliegenden Elementen: no
Bemaßungen - Fläche: 12.5418 m2; Volumen: 8.2104 m3
IFC-Parameter - In IFC-Datei exportieren: Nach Typ; In IFC exportieren als: ifcbuildingelementproxy; NameOverride: Quader; IfcPresentationLayer: 0-TFT-H_Variante 3 Kessel; ObjectTypeOverride: Quader; IfcDescription: Quader; Pset nova - Archi.Name: Quader
Phasen - Phase erstellt: Phase 01

# IfcBuildingElementProxy: Quader 297247:Quader 297247, Quader
In: Erdgeschoss
Type - Material: IfcSurfaceStyle #277
Type - Andere - Kategorie: Allgemeines Modell; Familienname: Quader 297247
Type - ID-Daten - Typname: Quader 297247
Type - IFC-Parameter - Typ in IFC-Datei exportieren: Vorgabe
Description: Quader
Pset_BuildingElementProxyCommon - Reference: Quader 297247; sets with these values: 2
Andere - Typ: Quader 297247; Familie: Quader 297247; Familie und Typ: Quader 297247: Quader 297247; Typ-ID: 2534746
Abhängigkeiten - Höhe von Ebene: 0 m; Verschieben mit umliegenden Elementen: no
Bemaßungen - Fläche: 12.5419 m2; Volumen: 8.2104 m3
IFC-Parameter - In IFC-Datei exportieren: Nach Typ; In IFC exportieren als: ifcbuildingelementproxy; NameOverride: Quader; IfcPresentationLayer: 0-TFT-H_Variante 3 Kessel; ObjectTypeOverride: Quader; IfcDescription: Quader; Pset nova - Archi.Name: Quader
Phasen - Phase erstellt: Phase 01

# IfcBuildingElementProxy: Quader 297270:Quader 297270, Quader
In: Erdgeschoss
Type - Material: IfcSurfaceStyle #277
Type - Andere - Kategorie: Allgemeines Modell; Familienname: Quader 297270
Type - ID-Daten - Typname: Quader 297270
Type - IFC-Parameter - Typ in IFC-Datei exportieren: Vorgabe
Description: Quader
Pset_BuildingElementProxyCommon - Reference: Quader 297270; sets with these values: 2
Andere - Typ: Quader 297270; Familie: Quader 297270; Familie und Typ: Quader 297270: Quader 297270; Typ-ID: 2534755
Abhängigkeiten - Höhe von Ebene: 0 m; Verschieben mit umliegenden Elementen: no
Bemaßungen - Fläche: 12.5419 m2; Volumen: 8.2104 m3
IFC-Parameter - In IFC-Datei exportieren: Nach Typ; In IFC exportieren als: ifcbuildingelementproxy; NameOverride: Quader; IfcPresentationLayer: 0-TFT-H_Variante 3 Kessel; ObjectTypeOverride: Quader; IfcDescription: Quader; Pset nova - Archi.Name: Quader
Phasen - Phase erstellt: Phase 01

# IfcBuildingElementProxy: Quader 326973:Quader 326973, Quader
In: Erdgeschoss
Type - Material: IfcSurfaceStyle #228457
Type - Andere - Kategorie: Allgemeines Modell; Familienname: Quader 326973
Type - ID-Daten - Typname: Quader 326973
Type - IFC-Parameter - Typ in IFC-Datei exportieren: Vorgabe
Description: Quader
Pset_BuildingElementProxyCommon - Reference: Quader 326973; sets with these values: 2
Andere - Typ: Quader 326973; Familie: Quader 326973; Familie und Typ: Quader 326973: Quader 326973; Typ-ID: 2535635
Abhängigkeiten - Höhe von Ebene: 0 m; Verschieben mit umliegenden Elementen: no
Bemaßungen - Fläche: 4.1625 m2; Volumen: 1.4625 m3
IFC-Parameter - In IFC-Datei exportieren: Nach Typ; In IFC exportieren als: ifcbuildingelementproxy; NameOverride: Quader; IfcPresentationLayer: 0-TFT-H_Bauteil; ObjectTypeOverride: Quader; IfcDescription: Quader; Pset nova - Archi.Name: Quader
Phasen - Phase erstellt: Phase 01

# IfcBuildingElementProxy: Quader 327038:Quader 327038, Quader
In: Erdgeschoss
Type - Material: IfcSurfaceStyle #228457
Type - Andere - Kategorie: Allgemeines Modell; Familienname: Quader 327038
Type - ID-Daten - Typname: Quader 327038
Type - IFC-Parameter - Typ in IFC-Datei exportieren: Vorgabe
Description: Quader
Pset_BuildingElementProxyCommon - Reference: Quader 327038; sets with these values: 2
Andere - Typ: Quader 327038; Familie: Quader 327038; Familie und Typ: Quader 327038: Quader 327038; Typ-ID: 2535642
Abhängigkeiten - Höhe von Ebene: 0 m; Verschieben mit umliegenden Elementen: no
Bemaßungen - Fläche: 4.1625 m2; Volumen: 1.4625 m3
IFC-Parameter - In IFC-Datei exportieren: Nach Typ; In IFC exportieren als: ifcbuildingelementproxy; NameOverride: Quader; IfcPresentationLayer: 0-TFT-H_Bauteil; ObjectTypeOverride: Quader; IfcDescription: Quader; Pset nova - Archi.Name: Quader
Phasen - Phase erstellt: Phase 01

# IfcBuildingElementProxy: Quader 355711:Quader 355711, Quader
In: Erdgeschoss
Type - Material: IfcSurfaceStyle #352577
Type - Andere - Kategorie: Allgemeines Modell; Familienname: Quader 355711
Type - ID-Daten - Typname: Quader 355711
Type - IFC-Parameter - Typ in IFC-Datei exportieren: Vorgabe
Description: Quader
Pset_BuildingElementProxyCommon - Reference: Quader 355711; sets with these values: 2
Andere - Typ: Quader 355711; Familie: Quader 355711; Familie und Typ: Quader 355711: Quader 355711; Typ-ID: 2536765
Abhängigkeiten - Höhe von Ebene: 0 m; Verschieben mit umliegenden Elementen: no
Bemaßungen - Fläche: 0.14 m2; Volumen: 0.01 m3
IFC-Parameter - In IFC-Datei exportieren: Nach Typ; In IFC exportieren als: ifcbuildingelementproxy; NameOverride: Quader; IfcPresentationLayer: 0-TFT-S_Gas; ObjectTypeOverride: Quader; IfcDescription: Quader; Pset nova - Archi.Name: Quader
Phasen - Phase erstellt: Phase 01

# IfcBuildingElementProxy: Quader 604201:Quader 604201, Quader
In: Erdgeschoss
Type - Material: IfcSurfaceStyle #352577
Type - Andere - Kategorie: Allgemeines Modell; Familienname: Quader 604201
Type - ID-Daten - Typname: Quader 604201
Type - IFC-Parameter - Typ in IFC-Datei exportieren: Vorgabe
Description: Quader
Pset_BuildingElementProxyCommon - Reference: Quader 604201; sets with these values: 2
Andere - Typ: Quader 604201; Familie: Quader 604201; Familie und Typ: Quader 604201: Quader 604201; Typ-ID: 2537073
Abhängigkeiten - Höhe von Ebene: 0 m; Verschieben mit umliegenden Elementen: no
Bemaßungen - Fläche: 0.14 m2; Volumen: 0.01 m3
IFC-Parameter - In IFC-Datei exportieren: Nach Typ; In IFC exportieren als: ifcbuildingelementproxy; NameOverride: Quader; IfcPresentationLayer: 0-TFT-S_Gas; ObjectTypeOverride: Quader; IfcDescription: Quader; Pset nova - Archi.Name: Quader
Phasen - Phase erstellt: Phase 01

# IfcBuildingElementProxy: Quader 604929:Quader 604929, Quader
In: Erdgeschoss
Type - Material: IfcSurfaceStyle #352577
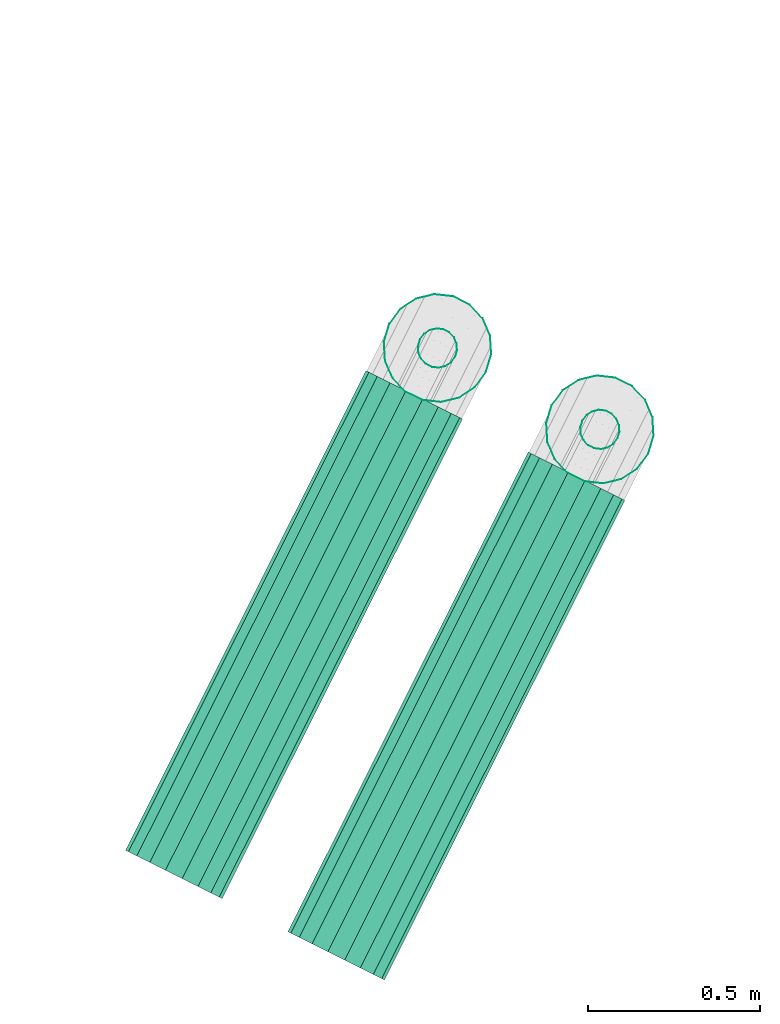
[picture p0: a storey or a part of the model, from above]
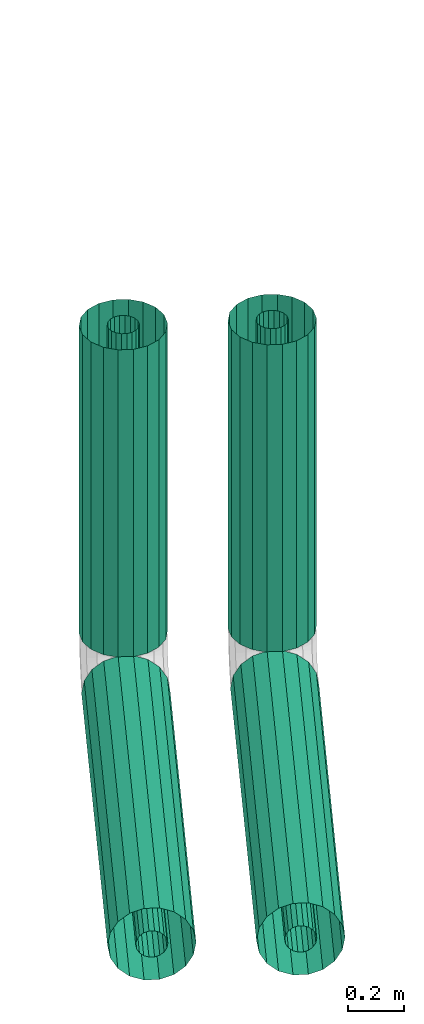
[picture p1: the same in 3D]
Properties of the parts of a building model (IFC2X3), part 4 of 23

# IfcBuildingElementProxy: Quader 604929:Quader 604929, Quader
Type - Andere - Kategorie: Allgemeines Modell; Familienname: Quader 604929
Type - ID-Daten - Typname: Quader 604929
Type - IFC-Parameter - Typ in IFC-Datei exportieren: Vorgabe
Description: Quader
Pset_BuildingElementProxyCommon - Reference: Quader 604929; sets with these values: 2
Andere - Typ: Quader 604929; Familie: Quader 604929; Familie und Typ: Quader 604929: Quader 604929; Typ-ID: 2537297
Abhängigkeiten - Höhe von Ebene: 0 m; Verschieben mit umliegenden Elementen: no
Bemaßungen - Fläche: 0.14 m2; Volumen: 0.01 m3
IFC-Parameter - In IFC-Datei exportieren: Nach Typ; In IFC exportieren als: ifcbuildingelementproxy; NameOverride: Quader; IfcPresentationLayer: 0-TFT-S_Gas; ObjectTypeOverride: Quader; IfcDescription: Quader; Pset nova - Archi.Name: Quader
Phasen - Phase erstellt: Phase 01

# IfcBuildingElementProxy: Quader 620148:Quader 620148, Quader
In: Erdgeschoss
Type - Material: IfcSurfaceStyle #228457
Type - Andere - Kategorie: Allgemeines Modell; Familienname: Quader 620148
Type - ID-Daten - Typname: Quader 620148
Type - IFC-Parameter - Typ in IFC-Datei exportieren: Vorgabe
Description: Quader
Pset_BuildingElementProxyCommon - Reference: Quader 620148; sets with these values: 2
Andere - Typ: Quader 620148; Familie: Quader 620148; Familie und Typ: Quader 620148: Quader 620148; Typ-ID: 2537951
Abhängigkeiten - Höhe von Ebene: 0 m; Verschieben mit umliegenden Elementen: no
Bemaßungen - Fläche: 3.28 m2; Volumen: 0.96 m3
IFC-Parameter - In IFC-Datei exportieren: Nach Typ; In IFC exportieren als: ifcbuildingelementproxy; NameOverride: Quader; IfcPresentationLayer: 0-TFT-X_Geometrie; ObjectTypeOverride: Quader; IfcDescription: Quader; Pset nova - Archi.Name: Quader
Phasen - Phase erstellt: Phase 01

# IfcBuildingElementProxy: Quader 620211:Quader 620211, Quader
In: Erdgeschoss
Type - Material: IfcSurfaceStyle #228457
Type - Andere - Kategorie: Allgemeines Modell; Familienname: Quader 620211
Type - ID-Daten - Typname: Quader 620211
Type - IFC-Parameter - Typ in IFC-Datei exportieren: Vorgabe
Description: Quader
Pset_BuildingElementProxyCommon - Reference: Quader 620211; sets with these values: 2
Andere - Typ: Quader 620211; Familie: Quader 620211; Familie und Typ: Quader 620211: Quader 620211; Typ-ID: 2537958
Abhängigkeiten - Höhe von Ebene: 0 m; Verschieben mit umliegenden Elementen: no
Bemaßungen - Fläche: 2.5 m2; Volumen: 0.6 m3
IFC-Parameter - In IFC-Datei exportieren: Nach Typ; In IFC exportieren als: ifcbuildingelementproxy; NameOverride: Quader; IfcPresentationLayer: 0-TFT-X_Geometrie; ObjectTypeOverride: Quader; IfcDescription: Quader; Pset nova - Archi.Name: Quader
Phasen - Phase erstellt: Phase 01

# IfcBuildingElementProxy: Quader 620274:Quader 620274, Quader
In: Erdgeschoss
Type - Material: IfcSurfaceStyle #620343
Type - Andere - Kategorie: Allgemeines Modell; Familienname: Quader 620274
Type - ID-Daten - Typname: Quader 620274
Type - IFC-Parameter - Typ in IFC-Datei exportieren: Vorgabe
Description: Quader
Pset_BuildingElementProxyCommon - Reference: Quader 620274; sets with these values: 2
Andere - Typ: Quader 620274; Familie: Quader 620274; Familie und Typ: Quader 620274: Quader 620274; Typ-ID: 2537965
Abhängigkeiten - Höhe von Ebene: 0 m; Verschieben mit umliegenden Elementen: no
Bemaßungen - Fläche: 7.053 m2; Volumen: 0.9288 m3
IFC-Parameter - In IFC-Datei exportieren: Nach Typ; In IFC exportieren als: ifcbuildingelementproxy; NameOverride: Quader; IfcPresentationLayer: 0-TFT-H_Fundament; ObjectTypeOverride: Quader; IfcDescription: Quader; Pset nova - Archi.Name: Quader
Phasen - Phase erstellt: Phase 01

# IfcBuildingElementProxy: Quader 620349:Quader 620349, Quader
In: Erdgeschoss
Type - Material: IfcSurfaceStyle #620343
Type - Andere - Kategorie: Allgemeines Modell; Familienname: Quader 620349
Type - ID-Daten - Typname: Quader 620349
Type - IFC-Parameter - Typ in IFC-Datei exportieren: Vorgabe
Description: Quader
Pset_BuildingElementProxyCommon - Reference: Quader 620349; sets with these values: 2
Andere - Typ: Quader 620349; Familie: Quader 620349; Familie und Typ: Quader 620349: Quader 620349; Typ-ID: 2537973
Abhängigkeiten - Höhe von Ebene: 0 m; Verschieben mit umliegenden Elementen: no
Bemaßungen - Fläche: 25.203 m2; Volumen: 3.5424 m3
IFC-Parameter - In IFC-Datei exportieren: Nach Typ; In IFC exportieren als: ifcbuildingelementproxy; NameOverride: Quader; IfcPresentationLayer: 0-TFT-H_Fundament; ObjectTypeOverride: Quader; IfcDescription: Quader; Pset nova - Archi.Name: Quader
Phasen - Phase erstellt: Phase 01

# IfcBuildingElementProxy: Quader 620414:Quader 620414, Quader
In: Erdgeschoss
Type - Material: IfcSurfaceStyle #620343
Type - Andere - Kategorie: Allgemeines Modell; Familienname: Quader 620414
Type - ID-Daten - Typname: Quader 620414
Type - IFC-Parameter - Typ in IFC-Datei exportieren: Vorgabe
Description: Quader
Pset_BuildingElementProxyCommon - Reference: Quader 620414; sets with these values: 2
Andere - Typ: Quader 620414; Familie: Quader 620414; Familie und Typ: Quader 620414: Quader 620414; Typ-ID: 2537980
Abhängigkeiten - Höhe von Ebene: 0 m; Verschieben mit umliegenden Elementen: no
Bemaßungen - Fläche: 4.509 m2; Volumen: 0.5832 m3
IFC-Parameter - In IFC-Datei exportieren: Nach Typ; In IFC exportieren als: ifcbuildingelementproxy; NameOverride: Quader; IfcPresentationLayer: 0-TFT-H_Fundament; ObjectTypeOverride: Quader; IfcDescription: Quader; Pset nova - Archi.Name: Quader
Phasen - Phase erstellt: Phase 01

# IfcBuildingElementProxy: Quader 849478:Quader 849478, Quader
In: Erdgeschoss
Type - Material: IfcSurfaceStyle #228457
Type - Andere - Kategorie: Allgemeines Modell; Familienname: Quader 849478
Type - ID-Daten - Typname: Quader 849478
Type - IFC-Parameter - Typ in IFC-Datei exportieren: Vorgabe
Description: Quader
Pset_BuildingElementProxyCommon - Reference: Quader 849478; sets with these values: 2
Andere - Typ: Quader 849478; Familie: Quader 849478; Familie und Typ: Quader 849478: Quader 849478; Typ-ID: 2539057
Abhängigkeiten - Höhe von Ebene: 0 m; Verschieben mit umliegenden Elementen: no
Bemaßungen - Fläche: 2.24 m2; Volumen: 0.48 m3
IFC-Parameter - In IFC-Datei exportieren: Nach Typ; In IFC exportieren als: ifcbuildingelementproxy; NameOverride: Quader; IfcPresentationLayer: 0-TFT-X_Geometrie; ObjectTypeOverride: Quader; IfcDescription: Quader; Pset nova - Archi.Name: Quader
Phasen - Phase erstellt: Phase 01

# IfcBuildingElementProxy: Quader 849525:Quader 849525, Quader
In: Erdgeschoss
Type - Material: IfcSurfaceStyle #228457
Type - Andere - Kategorie: Allgemeines Modell; Familienname: Quader 849525
Type - ID-Daten - Typname: Quader 849525
Type - IFC-Parameter - Typ in IFC-Datei exportieren: Vorgabe
Description: Quader
Pset_BuildingElementProxyCommon - Reference: Quader 849525; sets with these values: 2
Andere - Typ: Quader 849525; Familie: Quader 849525; Familie und Typ: Quader 849525: Quader 849525; Typ-ID: 2539064
Abhängigkeiten - Höhe von Ebene: 0 m; Verschieben mit umliegenden Elementen: no
Bemaßungen - Fläche: 2.24 m2; Volumen: 0.48 m3
IFC-Parameter - In IFC-Datei exportieren: Nach Typ; In IFC exportieren als: ifcbuildingelementproxy; NameOverride: Quader; IfcPresentationLayer: 0-TFT-X_Geometrie; ObjectTypeOverride: Quader; IfcDescription: Quader; Pset nova - Archi.Name: Quader
Phasen - Phase erstellt: Phase 01

# IfcBuildingElementProxy: Quader 851191:Quader 851191, Quader
In: Erdgeschoss
Type - Material: IfcSurfaceStyle #270045
Type - Andere - Kategorie: Allgemeines Modell; Familienname: Quader 851191
Type - ID-Daten - Typname: Quader 851191
Type - IFC-Parameter - Typ in IFC-Datei exportieren: Vorgabe
Description: Quader
Pset_BuildingElementProxyCommon - Reference: Quader 851191; sets with these values: 2
Andere - Typ: Quader 851191; Familie: Quader 851191; Familie und Typ: Quader 851191: Quader 851191; Typ-ID: 2539225
Abhängigkeiten - Höhe von Ebene: 0 m; Verschieben mit umliegenden Elementen: no
Bemaßungen - Fläche: 0.372342 m2; Volumen: 0.0430175 m3
IFC-Parameter - In IFC-Datei exportieren: Nach Typ; In IFC exportieren als: ifcbuildingelementproxy; NameOverride: Quader; IfcPresentationLayer: 0-TFT-S_Einrichtungsgegenstände; ObjectTypeOverride: Quader; IfcDescription: Quader; Pset nova - Archi.Name: Quader
Phasen - Phase erstellt: Phase 01

# IfcBuildingElementProxy: Quader 851264:Quader 851264, Quader
In: Erdgeschoss
Type - Material: IfcSurfaceStyle #270045
Type - Andere - Kategorie: Allgemeines Modell; Familienname: Quader 851264
Type - ID-Daten - Typname: Quader 851264
Type - IFC-Parameter - Typ in IFC-Datei exportieren: Vorgabe
Description: Quader
Pset_BuildingElementProxyCommon - Reference: Quader 851264; sets with these values: 2
Andere - Typ: Quader 851264; Familie: Quader 851264; Familie und Typ: Quader 851264: Quader 851264; Typ-ID: 2539246
Abhängigkeiten - Höhe von Ebene: 0 m; Verschieben mit umliegenden Elementen: no
Bemaßungen - Fläche: 1.089 m2; Volumen: 0.2088 m3
IFC-Parameter - In IFC-Datei exportieren: Nach Typ; In IFC exportieren als: ifcbuildingelementproxy; NameOverride: Quader; IfcPresentationLayer: 0-TFT-S_Einrichtungsgegenstände; ObjectTypeOverride: Quader; IfcDescription: Quader; Pset nova - Archi.Name: Quader
Phasen - Phase erstellt: Phase 01

# IfcBuildingElementProxy: Quader 851335:Quader 851335, Quader
In: Erdgeschoss
Type - Material: IfcSurfaceStyle #270045
Type - Andere - Kategorie: Allgemeines Modell; Familienname: Quader 851335
Type - ID-Daten - Typname: Quader 851335
Type - IFC-Parameter - Typ in IFC-Datei exportieren: Vorgabe
Description: Quader
Pset_BuildingElementProxyCommon - Reference: Quader 851335; sets with these values: 2
Andere - Typ: Quader 851335; Familie: Quader 851335; Familie und Typ: Quader 851335: Quader 851335; Typ-ID: 2539267
Abhängigkeiten - Höhe von Ebene: 0 m; Verschieben mit umliegenden Elementen: no
Bemaßungen - Fläche: 0.372342 m2; Volumen: 0.0430175 m3
IFC-Parameter - In IFC-Datei exportieren: Nach Typ; In IFC exportieren als: ifcbuildingelementproxy; NameOverride: Quader; IfcPresentationLayer: 0-TFT-S_Einrichtungsgegenstände; ObjectTypeOverride: Quader; IfcDescription: Quader; Pset nova - Archi.Name: Quader
Phasen - Phase erstellt: Phase 01

# IfcBuildingElementProxy: Quader:Quader, Quader
In: 1. Obergeschoss
Type - Material: IfcSurfaceStyle #228457
Type - Andere - Kategorie: Allgemeines Modell; Familienname: Quader
Type - ID-Daten - Typname: Quader
Type - IFC-Parameter - Typ in IFC-Datei exportieren: Vorgabe
Description: Quader
Pset_BuildingElementProxyCommon - Reference: Quader; sets with these values: 2
Andere - Typ: Quader; Familie: Quader; Familie und Typ: Quader: Quader; Typ-ID: 2532132
Abhängigkeiten - Höhe von Ebene: 0 m; Verschieben mit umliegenden Elementen: no
Bemaßungen - Fläche: 3.2 m2; Volumen: 0.8 m3
IFC-Parameter - In IFC-Datei exportieren: Nach Typ; In IFC exportieren als: ifcbuildingelementproxy; NameOverride: Quader; IfcPresentationLayer: 0-TFT-X_Geometrie; ObjectTypeOverride: Quader; IfcDescription: Quader; Pset nova - Archi.Name: Quader
Phasen - Phase erstellt: Phase 01

# IfcBuildingElementProxy: Zylinder:Zylinder, Zylinder
In: 1. Obergeschoss
Type - Material: IfcSurfaceStyle #270045
Type - Andere - Kategorie: Allgemeines Modell; Familienname: Zylinder
Type - ID-Daten - Typname: Zylinder
Type - IFC-Parameter - Typ in IFC-Datei exportieren: Vorgabe
Description: Zylinder
Pset_BuildingElementProxyCommon - Reference: Zylinder; sets with these values: 2
Andere - Typ: Zylinder; Familie: Zylinder; Familie und Typ: Zylinder: Zylinder; Typ-ID: 2533383
Abhängigkeiten - Höhe von Ebene: 0 m; Verschieben mit umliegenden Elementen: no
Bemaßungen - Fläche: 0.0314117 m2; Volumen: 0.0182204 m3
IFC-Parameter - In IFC-Datei exportieren: Nach Typ; In IFC exportieren als: ifcbuildingelementproxy; NameOverride: Zylinder; IfcPresentationLayer: 0-TFT-S_Einrichtungsgegenstände; ObjectTypeOverride: Zylinder; IfcDescription: Zylinder; Pset nova - Archi.Name: Zylinder
Phasen - Phase erstellt: Phase 01

# IfcDistributionControlElement: Messarmatur 602914:Messarmatur 602914, Messarmatur
In: Erdgeschoss
Type - Material: IfcSurfaceStyle #352577
Type - Andere - Kategorie: Allgemeines Modell; Familienname: Messarmatur 602914
Type - ID-Daten - Typname: Messarmatur 602914
Type - IFC-Parameter - Typ in IFC-Datei exportieren: Vorgabe
Description: Messarmatur
Pset_QuantityTakeOff - Reference: Messarmatur 602914
Andere - Typ: Messarmatur 602914; Familie: Messarmatur 602914; Familie und Typ: Messarmatur 602914: Messarmatur 602914; Typ-ID: 2536975
Abhängigkeiten - Höhe von Ebene: 0 m; Verschieben mit umliegenden Elementen: no
Bemaßungen - Fläche: 0.00463475 m2; Volumen: 0.0000437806 m3
IFC-Parameter - In IFC-Datei exportieren: Nach Typ; In IFC exportieren als: ifcdistributioncontrolelement; NameOverride: Messarmatur; IfcPresentationLayer: S_Gas; ObjectTypeOverride: Messarmatur; Pset MEP.Name: Messarmatur; IfcDescription: Messarmatur
Phasen - Phase erstellt: Phase 01

# IfcDistributionControlElement: Messarmatur 604316:Messarmatur 604316, Messarmatur
In: Erdgeschoss
Type - Material: IfcSurfaceStyle #352577
Type - Andere - Kategorie: Allgemeines Modell; Familienname: Messarmatur 604316
Type - ID-Daten - Typname: Messarmatur 604316
Type - IFC-Parameter - Typ in IFC-Datei exportieren: Vorgabe
Description: Messarmatur
Pset_QuantityTakeOff - Reference: Messarmatur 604316
Andere - Typ: Messarmatur 604316; Familie: Messarmatur 604316; Familie und Typ: Messarmatur 604316: Messarmatur 604316; Typ-ID: 2537108
Abhängigkeiten - Höhe von Ebene: 0 m; Verschieben mit umliegenden Elementen: no
Bemaßungen - Fläche: 0.00463475 m2; Volumen: 0.0000437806 m3
IFC-Parameter - In IFC-Datei exportieren: Nach Typ; In IFC exportieren als: ifcdistributioncontrolelement; NameOverride: Messarmatur; IfcPresentationLayer: S_Gas; ObjectTypeOverride: Messarmatur; Pset MEP.Name: Messarmatur; IfcDescription: Messarmatur
Phasen - Phase erstellt: Phase 01

# IfcDistributionControlElement: Messarmatur 612673:Messarmatur 612673, Messarmatur
In: Erdgeschoss
Type - Material: IfcSurfaceStyle #352577
Type - Andere - Kategorie: Allgemeines Modell; Familienname: Messarmatur 612673
Type - ID-Daten - Typname: Messarmatur 612673
Type - IFC-Parameter - Typ in IFC-Datei exportieren: Vorgabe
Description: Messarmatur
Pset_QuantityTakeOff - Reference: Messarmatur 612673
Andere - Typ: Messarmatur 612673; Familie: Messarmatur 612673; Familie und Typ: Messarmatur 612673: Messarmatur 612673; Typ-ID: 2537605
Abhängigkeiten - Höhe von Ebene: 0 m; Verschieben mit umliegenden Elementen: no
Bemaßungen - Fläche: 0.00463475 m2; Volumen: 0.0000437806 m3
IFC-Parameter - In IFC-Datei exportieren: Nach Typ; In IFC exportieren als: ifcdistributioncontrolelement; NameOverride: Messarmatur; IfcPresentationLayer: S_Gas; ObjectTypeOverride: Messarmatur; Pset MEP.Name: Messarmatur; IfcDescription: Messarmatur
Phasen - Phase erstellt: Phase 01

# IfcDistributionControlElement: Messarmatur:Messarmatur, Messarmatur
In: Erdgeschoss
Type - Material: IfcSurfaceStyle #352577
Type - Andere - Kategorie: Allgemeines Modell; Familienname: Messarmatur
Type - ID-Daten - Typname: Messarmatur
Type - IFC-Parameter - Typ in IFC-Datei exportieren: Vorgabe
Description: Messarmatur
Pset_QuantityTakeOff - Reference: Messarmatur
Andere - Typ: Messarmatur; Familie: Messarmatur; Familie und Typ: Messarmatur: Messarmatur; Typ-ID: 2536716
Abhängigkeiten - Höhe von Ebene: 0 m; Verschieben mit umliegenden Elementen: no
Bemaßungen - Fläche: 0.00463475 m2; Volumen: 0.0000437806 m3
IFC-Parameter - In IFC-Datei exportieren: Nach Typ; In IFC exportieren als: ifcdistributioncontrolelement; NameOverride: Messarmatur; IfcPresentationLayer: S_Gas; ObjectTypeOverride: Messarmatur; Pset MEP.Name: Messarmatur; IfcDescription: Messarmatur
Phasen - Phase erstellt: Phase 01

# IfcDistributionControlElement: Zählerpaßstück 319218:Zählerpaßstück 319218, Zählerpaßstück
In: 1. Obergeschoss
Type - Material: IfcSurfaceStyle #1741
Type - Andere - Kategorie: Allgemeines Modell; Familienname: Zählerpaßstück 319218
Type - ID-Daten - Typname: Zählerpaßstück 319218
Type - IFC-Parameter - Typ in IFC-Datei exportieren: Vorgabe
Description: Zählerpaßstück
Pset_QuantityTakeOff - Reference: Zählerpaßstück 319218
Andere - Typ: Zählerpaßstück 319218; Familie: Zählerpaßstück 319218; Familie und Typ: Zählerpaßstück 319218: Zählerpaßstück 319218; Typ-ID: 2535418
Abhängigkeiten - Höhe von Ebene: 0 m; Verschieben mit umliegenden Elementen: no
Bemaßungen - Fläche: 0.449231 m2; Volumen: 0.0378303 m3
IFC-Parameter - In IFC-Datei exportieren: Nach Typ; Pset MEP.Tech-Insulation thickness (mm): 100; Pset MEP.Tech-PN: 16; Pset MEP.Tech-Connection type (Inner thread=2, flange=3): 2; Pset MEP.Geom-DN: 100; Pset MEP.Geom-Outer Ø (mm): 220; Pset MEP.Geom-Length (mm): 350; In IFC exportieren als: ifcdistributioncontrolelement; NameOverride: Zählerpaßstück; IfcPresentationLayer: 0-TFT-H_Ruecklauf; ObjectTypeOverride: Zählerpaßstück; Pset MEP.Name: Zählerpaßstück; IfcDescription: Zählerpaßstück
Phasen - Phase erstellt: Phase 01

# IfcDistributionControlElement: Zählerpaßstück 334871:Zählerpaßstück 334871, Zählerpaßstück
In: Erdgeschoss
Type - Material: IfcSurfaceStyle #1741
Type - Andere - Kategorie: Allgemeines Modell; Familienname: Zählerpaßstück 334871
Type - ID-Daten - Typname: Zählerpaßstück 334871
Type - IFC-Parameter - Typ in IFC-Datei exportieren: Vorgabe
Description: Zählerpaßstück
Pset_QuantityTakeOff - Reference: Zählerpaßstück 334871
Andere - Typ: Zählerpaßstück 334871; Familie: Zählerpaßstück 334871; Familie und Typ: Zählerpaßstück 334871: Zählerpaßstück 334871; Typ-ID: 2535817
Abhängigkeiten - Höhe von Ebene: 0 m; Verschieben mit umliegenden Elementen: no
Bemaßungen - Fläche: 0.311901 m2; Volumen: 0.0247303 m3
IFC-Parameter - In IFC-Datei exportieren: Nach Typ; Pset MEP.Tech-Insulation thickness (mm): 100; Pset MEP.Tech-PN: 16; Pset MEP.Tech-Connection type (Inner thread=2, flange=3): 2; Pset MEP.Geom-DN: 65; Pset MEP.Geom-Outer Ø (mm): 185; Pset MEP.Geom-Length (mm): 290; In IFC exportieren als: ifcdistributioncontrolelement; NameOverride: Zählerpaßstück; IfcPresentationLayer: 0-TFT-H_Ruecklauf; ObjectTypeOverride: Zählerpaßstück; Pset MEP.Name: Zählerpaßstück; IfcDescription: Zählerpaßstück
Phasen - Phase erstellt: Phase 01

# IfcDistributionControlElement: Zählerpaßstück 614674:Zählerpaßstück 614674, Zählerpaßstück
In: 1. Obergeschoss
Type - Material: IfcSurfaceStyle #1741
Type - Andere - Kategorie: Allgemeines Modell; Familienname: Zählerpaßstück 614674
Type - ID-Daten - Typname: Zählerpaßstück 614674
Type - IFC-Parameter - Typ in IFC-Datei exportieren: Vorgabe
Description: Zählerpaßstück
Pset_QuantityTakeOff - Reference: Zählerpaßstück 614674
Andere - Typ: Zählerpaßstück 614674; Familie: Zählerpaßstück 614674; Familie und Typ: Zählerpaßstück 614674: Zählerpaßstück 614674; Typ-ID: 2537780
Abhängigkeiten - Höhe von Ebene: 0 m; Verschieben mit umliegenden Elementen: no
Bemaßungen - Fläche: 0.449231 m2; Volumen: 0.0378303 m3
IFC-Parameter - In IFC-Datei exportieren: Nach Typ; Pset MEP.Tech-Insulation thickness (mm): 100; Pset MEP.Tech-PN: 16; Pset MEP.Tech-Connection type (Inner thread=2, flange=3): 2; Pset MEP.Geom-DN: 100; Pset MEP.Geom-Outer Ø (mm): 220; Pset MEP.Geom-Length (mm): 350; In IFC exportieren als: ifcdistributioncontrolelement; NameOverride: Zählerpaßstück; IfcPresentationLayer: 0-TFT-H_Ruecklauf; ObjectTypeOverride: Zählerpaßstück; Pset MEP.Name: Zählerpaßstück; IfcDescription: Zählerpaßstück
Phasen - Phase erstellt: Phase 01

# IfcDistributionControlElement: Zählerpaßstück:Zählerpaßstück, Zählerpaßstück
In: 1. Obergeschoss
Type - Material: IfcSurfaceStyle #1741
Type - Andere - Kategorie: Allgemeines Modell; Familienname: Zählerpaßstück
Type - ID-Daten - Typname: Zählerpaßstück
Type - IFC-Parameter - Typ in IFC-Datei exportieren: Vorgabe
Description: Zählerpaßstück
Pset_QuantityTakeOff - Reference: Zählerpaßstück
Andere - Typ: Zählerpaßstück; Familie: Zählerpaßstück; Familie und Typ: Zählerpaßstück: Zählerpaßstück; Typ-ID: 2535084
Abhängigkeiten - Höhe von Ebene: 0 m; Verschieben mit umliegenden Elementen: no
Bemaßungen - Fläche: 0.219494 m2; Volumen: 0.00615581 m3
IFC-Parameter - In IFC-Datei exportieren: Nach Typ; Pset MEP.Tech-Insulation thickness (mm): 100; Pset MEP.Tech-PN: 16; Pset MEP.Tech-Connection type (Inner thread=2, flange=3): 2; Pset MEP.Geom-DN: 100; Pset MEP.Geom-Outer Ø (mm): 220; Pset MEP.Geom-Length (mm): 350; In IFC exportieren als: ifcdistributioncontrolelement; NameOverride: Zählerpaßstück; IfcPresentationLayer: 0-TFT-H_Ruecklauf; ObjectTypeOverride: Zählerpaßstück; Pset MEP.Name: Zählerpaßstück; IfcDescription: Zählerpaßstück
Phasen - Phase erstellt: Phase 01

# IfcDistributionFlowElement: Lüftungsgerät Komponente 271590:Lüftungsgerät Komponente 271590, Lüftungsgerät Komponente
In: 1. Obergeschoss
Type - Material: IfcSurfaceStyle #271082
Type - Andere - Kategorie: HLS-Bauteile; Familienname: Lüftungsgerät Komponente 271590
Type - ID-Daten - Typname: Lüftungsgerät Komponente 271590
Type - IFC-Parameter - Typ in IFC-Datei exportieren: Vorgabe
Type - HLS - Klassifizierung: Keine
Description: Lüftungsgerät Komponente
Pset_DistributionFlowElementCommon - Reference: Lüftungsgerät Komponente 271590; sets with these values: 2
Andere - Typ: Lüftungsgerät Komponente 271590; Familie: Lüftungsgerät Komponente 271590; Familie und Typ: Lüftungsgerät Komponente 271590: Lüftungsgerät Komponente 271590; Typ-ID: 2533482
Abhängigkeiten - Höhe von Ebene: 0 m; Verschieben mit umliegenden Elementen: no
Bemaßungen - Fläche: 27.4276 m2; Volumen: 21.7972 m3
IFC-Parameter - In IFC-Datei exportieren: Nach Typ; In IFC exportieren als: ifcdistributionflowelement; NameOverride: Lüftungsgerät Komponente; IfcPresentationLayer: 0-TFT-L_Bauteil; ObjectTypeOverride: Lüftungsgerät Komponente; Pset MEP.Name: Lüftungsgerät Komponente; IfcDescription: Lüftungsgerät Komponente; Pset MEP.Geom-Length (mm): 5573; Pset MEP.Geom-Height (mm): 1624; Pset MEP.Geom-Width (mm): 2448
Phasen - Phase erstellt: Phase 01

# IfcDistributionFlowElement: Lüftungsgerät Komponente:Lüftungsgerät Komponente, Lüftungsgerät Komponente
In: 1. Obergeschoss
Type - Material: IfcSurfaceStyle #271082
Type - Andere - Kategorie: HLS-Bauteile; Familienname: Lüftungsgerät Komponente
Type - ID-Daten - Typname: Lüftungsgerät Komponente
Type - IFC-Parameter - Typ in IFC-Datei exportieren: Vorgabe
Type - HLS - Klassifizierung: Keine
Description: Lüftungsgerät Komponente
Pset_DistributionFlowElementCommon - Reference: Lüftungsgerät Komponente; sets with these values: 2
Andere - Typ: Lüftungsgerät Komponente; Familie: Lüftungsgerät Komponente; Familie und Typ: Lüftungsgerät Komponente: Lüftungsgerät Komponente; Typ-ID: 2533460
Abhängigkeiten - Höhe von Ebene: 0 m; Verschieben mit umliegenden Elementen: no
Bemaßungen - Fläche: 23.0265 m2; Volumen: 17.6523 m3
IFC-Parameter - In IFC-Datei exportieren: Nach Typ; In IFC exportieren als: ifcdistributionflowelement; NameOverride: Lüftungsgerät Komponente; IfcPresentationLayer: 0-TFT-L_Bauteil; ObjectTypeOverride: Lüftungsgerät Komponente; Pset MEP.Name: Lüftungsgerät Komponente; IfcDescription: Lüftungsgerät Komponente; Pset MEP.Geom-Length (mm): 4513; Pset MEP.Geom-Height (mm): 1624; Pset MEP.Geom-Width (mm): 2448
Phasen - Phase erstellt: Phase 01

# IfcDoor: Tür:Tür, Tür
In: Erdgeschoss
Type - OperationType: DOUBLE_DOOR_SINGLE_SWING; ParameterTakesPrecedence: no; Sizeable: no; Material: <Unnamed>
Type - Tür:1 - PanelOperation: SWINGING
Type - Andere - Kategorie: Türen; Familienname: Tür
Type - ID-Daten - Typenmarkierung: 230; Typname: Tür
Type - IFC-Parameter - Typ in IFC-Datei exportieren: Vorgabe; Typ in IFC exportieren als: ifcdoor; Vorgang: DOUBLE_DOOR_SINGLE_SWING
Type - Analytische Eigenschaften - Thermische Eigenschaften definieren durch: Schema-Typ; Analytische Konstruktion: <Keine Auswahl>
OverallHeight: 2.1 m; OverallWidth: 2 m
Pset_DoorCommon - IsExternal: yes; Reference: Tür
Pset_QuantityTakeOff - Reference: Tür
Andere - Host-ID: 2540056; Typ: Tür; Familie: Tür; Familie und Typ: Tür: Tür; Typ-ID: 2539926
Abhängigkeiten - Ebene: Erdgeschoss; Schwelle/Brüstung: 0 m; Sturzhöhe: 0 m
Bemaßungen - Fläche: 4.51 m2
ID-Daten - Kennzeichen: TU 2
IFC-Parameter - In IFC-Datei exportieren: Nach Typ; In IFC exportieren als: ifcdoor; NameOverride: Tür; IfcPresentationLayer: 0-TFT-A_Tuer; ObjectTypeOverride: Tür; Pset MEP.Geom-Surface (m2): 4.2; Pset MEP.Name: Tür; Pset MEP.OverallHeight(mm): 2100; Pset MEP.OverallWidth (mm): 2000
Phasen - Phase erstellt: Phase 01

# IfcFlowController: Absperrklappe 355806:Absperrklappe 355806, Absperrklappe
In: Erdgeschoss
Type - Material: IfcSurfaceStyle #352577
Type - Andere - Kategorie: Allgemeines Modell; Familienname: Absperrklappe 355806
Type - ID-Daten - Typname: Absperrklappe 355806
Type - IFC-Parameter - Typ in IFC-Datei exportieren: Vorgabe
Description: Absperrklappe
Pset_DistributionFlowElementCommon - Reference: Absperrklappe 355806; sets with these values: 2
Andere - Typ: Absperrklappe 355806; Familie: Absperrklappe 355806; Familie und Typ: Absperrklappe 355806: Absperrklappe 355806; Typ-ID: 2536779
Abhängigkeiten - Höhe von Ebene: 0 m; Verschieben mit umliegenden Elementen: no
Bemaßungen - Fläche: 0.104043 m2; Volumen: 0.00200072 m3
IFC-Parameter - In IFC-Datei exportieren: Nach Typ; Pset MEP.Tech-PN: 16; Pset MEP.Tech-Connection type (Inner thread=2, flange=3): 2; Pset MEP.Geom-DN: 65; Pset MEP.Geom-Outer Ø (mm): 185; Pset MEP.Geom-Length (mm): 290; In IFC exportieren als: ifcflowcontroller; NameOverride: Absperrklappe; IfcPresentationLayer: S_Gas; ObjectTypeOverride: Absperrklappe; Pset MEP.Name: Absperrklappe; IfcDescription: Absperrklappe
Phasen - Phase erstellt: Phase 01

# IfcFlowController: Absperrklappe 359789:Absperrklappe 359789, Absperrklappe
In: Erdgeschoss
Type - Material: IfcSurfaceStyle #352577
Type - Andere - Kategorie: Allgemeines Modell; Familienname: Absperrklappe 359789
Type - ID-Daten - Typname: Absperrklappe 359789
Type - IFC-Parameter - Typ in IFC-Datei exportieren: Vorgabe
Description: Absperrklappe
Pset_DistributionFlowElementCommon - Reference: Absperrklappe 359789; sets with these values: 2
Andere - Typ: Absperrklappe 359789; Familie: Absperrklappe 359789; Familie und Typ: Absperrklappe 359789: Absperrklappe 359789; Typ-ID: 2536940
Abhängigkeiten - Höhe von Ebene: 0 m; Verschieben mit umliegenden Elementen: no
Bemaßungen - Fläche: 0.104043 m2; Volumen: 0.00203759 m3
IFC-Parameter - In IFC-Datei exportieren: Nach Typ; Pset MEP.Tech-PN: 16; Pset MEP.Tech-Connection type (Inner thread=2, flange=3): 2; Pset MEP.Geom-DN: 65; Pset MEP.Geom-Outer Ø (mm): 185; Pset MEP.Geom-Length (mm): 290; In IFC exportieren als: ifcflowcontroller; NameOverride: Absperrklappe; IfcPresentationLayer: S_Gas; ObjectTypeOverride: Absperrklappe; Pset MEP.Name: Absperrklappe; IfcDescription: Absperrklappe
Phasen - Phase erstellt: Phase 01

# IfcFlowController: Absperrklappe 603100:Absperrklappe 603100, Absperrklappe
In: Erdgeschoss
Type - Material: IfcSurfaceStyle #352577
Type - Andere - Kategorie: Allgemeines Modell; Familienname: Absperrklappe 603100
Type - ID-Daten - Typname: Absperrklappe 603100
Type - IFC-Parameter - Typ in IFC-Datei exportieren: Vorgabe
Description: Absperrklappe
Pset_DistributionFlowElementCommon - Reference: Absperrklappe 603100; sets with these values: 2
Andere - Typ: Absperrklappe 603100; Familie: Absperrklappe 603100; Familie und Typ: Absperrklappe 603100: Absperrklappe 603100; Typ-ID: 2537031
Abhängigkeiten - Höhe von Ebene: 0 m; Verschieben mit umliegenden Elementen: no
Bemaßungen - Fläche: 0.104043 m2; Volumen: 0.00200072 m3
IFC-Parameter - In IFC-Datei exportieren: Nach Typ; Pset MEP.Tech-PN: 16; Pset MEP.Tech-Connection type (Inner thread=2, flange=3): 2; Pset MEP.Geom-DN: 65; Pset MEP.Geom-Outer Ø (mm): 185; Pset MEP.Geom-Length (mm): 290; In IFC exportieren als: ifcflowcontroller; NameOverride: Absperrklappe; IfcPresentationLayer: S_Gas; ObjectTypeOverride: Absperrklappe; Pset MEP.Name: Absperrklappe; IfcDescription: Absperrklappe
Phasen - Phase erstellt: Phase 01

# IfcFlowController: Absperrklappe 604431:Absperrklappe 604431, Absperrklappe
In: Erdgeschoss
Type - Material: IfcSurfaceStyle #352577
Type - Andere - Kategorie: Allgemeines Modell; Familienname: Absperrklappe 604431
Type - ID-Daten - Typname: Absperrklappe 604431
Type - IFC-Parameter - Typ in IFC-Datei exportieren: Vorgabe
Description: Absperrklappe
Pset_DistributionFlowElementCommon - Reference: Absperrklappe 604431; sets with these values: 2
Andere - Typ: Absperrklappe 604431; Familie: Absperrklappe 604431; Familie und Typ: Absperrklappe 604431: Absperrklappe 604431; Typ-ID: 2537143
Abhängigkeiten - Höhe von Ebene: 0 m; Verschieben mit umliegenden Elementen: no
Bemaßungen - Fläche: 0.104043 m2; Volumen: 0.00200072 m3
IFC-Parameter - In IFC-Datei exportieren: Nach Typ; Pset MEP.Tech-PN: 16; Pset MEP.Tech-Connection type (Inner thread=2, flange=3): 2; Pset MEP.Geom-DN: 65; Pset MEP.Geom-Outer Ø (mm): 185; Pset MEP.Geom-Length (mm): 290; In IFC exportieren als: ifcflowcontroller; NameOverride: Absperrklappe; IfcPresentationLayer: S_Gas; ObjectTypeOverride: Absperrklappe; Pset MEP.Name: Absperrklappe; IfcDescription: Absperrklappe
Phasen - Phase erstellt: Phase 01

# IfcFlowController: Absperrklappe 604707:Absperrklappe 604707, Absperrklappe
In: Erdgeschoss
Type - Material: IfcSurfaceStyle #352577
Type - Andere - Kategorie: Allgemeines Modell; Familienname: Absperrklappe 604707
Type - ID-Daten - Typname: Absperrklappe 604707
Type - IFC-Parameter - Typ in IFC-Datei exportieren: Vorgabe
Description: Absperrklappe
Pset_DistributionFlowElementCommon - Reference: Absperrklappe 604707; sets with these values: 2
Andere - Typ: Absperrklappe 604707; Familie: Absperrklappe 604707; Familie und Typ: Absperrklappe 604707: Absperrklappe 604707; Typ-ID: 2537227
Abhängigkeiten - Höhe von Ebene: 0 m; Verschieben mit umliegenden Elementen: no
Bemaßungen - Fläche: 0.104043 m2; Volumen: 0.00203759 m3
IFC-Parameter - In IFC-Datei exportieren: Nach Typ; Pset MEP.Tech-PN: 16; Pset MEP.Tech-Connection type (Inner thread=2, flange=3): 2; Pset MEP.Geom-DN: 65; Pset MEP.Geom-Outer Ø (mm): 185; Pset MEP.Geom-Length (mm): 290; In IFC exportieren als: ifcflowcontroller; NameOverride: Absperrklappe; IfcPresentationLayer: S_Gas; ObjectTypeOverride: Absperrklappe; Pset MEP.Name: Absperrklappe; IfcDescription: Absperrklappe
Phasen - Phase erstellt: Phase 01

# IfcFlowController: Absperrklappe 606151:Absperrklappe 606151, Absperrklappe
In: Erdgeschoss
Type - Material: IfcSurfaceStyle #352577
Type - Andere - Kategorie: Allgemeines Modell; Familienname: Absperrklappe 606151
Type - ID-Daten - Typname: Absperrklappe 606151
Type - IFC-Parameter - Typ in IFC-Datei exportieren: Vorgabe
Description: Absperrklappe
Pset_DistributionFlowElementCommon - Reference: Absperrklappe 606151; sets with these values: 2
Andere - Typ: Absperrklappe 606151; Familie: Absperrklappe 606151; Familie und Typ: Absperrklappe 606151: Absperrklappe 606151; Typ-ID: 2537367
Abhängigkeiten - Höhe von Ebene: 0 m; Verschieben mit umliegenden Elementen: no
Bemaßungen - Fläche: 0.0553537 m2; Volumen: 0.000754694 m3
IFC-Parameter - In IFC-Datei exportieren: Nach Typ; Pset MEP.Tech-PN: 16; Pset MEP.Tech-Connection type (Inner thread=2, flange=3): 2; Pset MEP.Geom-DN: 32; Pset MEP.Geom-Outer Ø (mm): 140; In IFC exportieren als: ifcflowcontroller; NameOverride: Absperrklappe; IfcPresentationLayer: S_Gas; ObjectTypeOverride: Absperrklappe; Pset MEP.Name: Absperrklappe; IfcDescription: Absperrklappe; Pset MEP.Geom-Length (mm): 180
Phasen - Phase erstellt: Phase 01

# IfcFlowController: Absperrklappe 607034:Absperrklappe 607034, Absperrklappe
In: Erdgeschoss
Type - Material: IfcSurfaceStyle #352577
Type - Andere - Kategorie: Allgemeines Modell; Familienname: Absperrklappe 607034
Type - ID-Daten - Typname: Absperrklappe 607034
Type - IFC-Parameter - Typ in IFC-Datei exportieren: Vorgabe
Description: Absperrklappe
Pset_DistributionFlowElementCommon - Reference: Absperrklappe 607034; sets with these values: 2
Andere - Typ: Absperrklappe 607034; Familie: Absperrklappe 607034; Familie und Typ: Absperrklappe 607034: Absperrklappe 607034; Typ-ID: 2537374
Abhängigkeiten - Höhe von Ebene: 0 m; Verschieben mit umliegenden Elementen: no
Bemaßungen - Fläche: 0.0553537 m2; Volumen: 0.000754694 m3
IFC-Parameter - In IFC-Datei exportieren: Nach Typ; Pset MEP.Tech-PN: 16; Pset MEP.Tech-Connection type (Inner thread=2, flange=3): 2; Pset MEP.Geom-DN: 32; Pset MEP.Geom-Outer Ø (mm): 140; Pset MEP.Geom-Length (mm): 180; In IFC exportieren als: ifcflowcontroller; NameOverride: Absperrklappe; IfcPresentationLayer: S_Gas; ObjectTypeOverride: Absperrklappe; Pset MEP.Name: Absperrklappe; IfcDescription: Absperrklappe
Phasen - Phase erstellt: Phase 01

# IfcFlowController: Absperrklappe:Absperrklappe, Absperrklappe
In: Erdgeschoss
Type - Material: IfcSurfaceStyle #352577
Type - Andere - Kategorie: Allgemeines Modell; Familienname: Absperrklappe
Type - ID-Daten - Typname: Absperrklappe
Type - IFC-Parameter - Typ in IFC-Datei exportieren: Vorgabe
Description: Absperrklappe
Pset_DistributionFlowElementCommon - Reference: Absperrklappe; sets with these values: 2
Andere - Typ: Absperrklappe; Familie: Absperrklappe; Familie und Typ: Absperrklappe: Absperrklappe; Typ-ID: 2536688
Abhängigkeiten - Höhe von Ebene: 0 m; Verschieben mit umliegenden Elementen: no
Bemaßungen - Fläche: 0.104043 m2; Volumen: 0.00203759 m3
IFC-Parameter - In IFC-Datei exportieren: Nach Typ; Pset MEP.Tech-PN: 16; Pset MEP.Tech-Connection type (Inner thread=2, flange=3): 2; Pset MEP.Geom-DN: 65; Pset MEP.Geom-Outer Ø (mm): 185; Pset MEP.Geom-Length (mm): 290; In IFC exportieren als: ifcflowcontroller; NameOverride: Absperrklappe; IfcPresentationLayer: S_Gas; ObjectTypeOverride: Absperrklappe; Pset MEP.Name: Absperrklappe; IfcDescription: Absperrklappe
Phasen - Phase erstellt: Phase 01

# IfcFlowController: Disco-Rückschlagklappe:Disco-Rückschlagklappe, Disco-Rückschlagklappe
In: Erdgeschoss
Type - Material: IfcSurfaceStyle #1741
Type - Andere - Kategorie: Allgemeines Modell; Familienname: Disco-Rückschlagklappe
Type - ID-Daten - Typname: Disco-Rückschlagklappe
Type - IFC-Parameter - Typ in IFC-Datei exportieren: Vorgabe
Description: Disco-Rückschlagklappe
Pset_DistributionFlowElementCommon - Reference: Disco-Rückschlagklappe; sets with these values: 2
Andere - Typ: Disco-Rückschlagklappe; Familie: Disco-Rückschlagklappe; Familie und Typ: Disco-Rückschlagklappe: Disco-Rückschlagklappe; Typ-ID: 2535712
Abhängigkeiten - Höhe von Ebene: 0 m; Verschieben mit umliegenden Elementen: no
Bemaßungen - Fläche: 0.0446607 m2; Volumen: 0.00270837 m3
IFC-Parameter - In IFC-Datei exportieren: Nach Typ; Pset MEP.Tech-Insulation thickness (mm): 100; Pset MEP.Tech-PN: 16; Pset MEP.Tech-Connection type (Inner thread=2, flange=3): 2; Pset MEP.Geom-Length (mm): 46; Pset MEP.Geom-DN: 65; In IFC exportieren als: ifcflowcontroller; NameOverride: Disco-Rückschlagklappe; IfcPresentationLayer: 0-TFT-H_Ruecklauf; ObjectTypeOverride: Disco-Rückschlagklappe; Pset MEP.Name: Disco-Rückschlagklappe; IfcDescription: Disco-Rückschlagklappe; Pset MEP.Geom-Outer Ø (mm): 115
Phasen - Phase erstellt: Phase 01

# IfcFlowController: Dreiwegeventil 318032:Dreiwegeventil 318032, Dreiwegeventil
In: Erdgeschoss
Type - Material: IfcSurfaceStyle #1741
Type - Andere - Kategorie: Allgemeines Modell; Familienname: Dreiwegeventil 318032
Type - ID-Daten - Typname: Dreiwegeventil 318032
Type - IFC-Parameter - Typ in IFC-Datei exportieren: Vorgabe
Description: Dreiwegeventil
Pset_DistributionFlowElementCommon - Reference: Dreiwegeventil 318032; sets with these values: 2
Andere - Typ: Dreiwegeventil 318032; Familie: Dreiwegeventil 318032; Familie und Typ: Dreiwegeventil 318032: Dreiwegeventil 318032; Typ-ID: 2535320
Abhängigkeiten - Höhe von Ebene: 0 m; Verschieben mit umliegenden Elementen: no
Bemaßungen - Fläche: 0.822403 m2; Volumen: 0.073947 m3
IFC-Parameter - In IFC-Datei exportieren: Nach Typ; Pset MEP.Tech-Insulation thickness (mm): 100; Pset MEP.Tech-PN: 16; Pset MEP.Tech-Connection type (Inner thread=2, flange=3): 2; Pset MEP.Geom-DN: 125; Pset MEP.Geom-Outer Ø (mm): 250; In IFC exportieren als: ifcflowcontroller; NameOverride: Dreiwegeventil; IfcPresentationLayer: 0-TFT-H_Ruecklauf; ObjectTypeOverride: Dreiwegeventil; Pset MEP.Name: Dreiwegeventil; IfcDescription: Dreiwegeventil
Phasen - Phase erstellt: Phase 01

# IfcFlowController: Dreiwegeventil 323126:Dreiwegeventil 323126, Dreiwegeventil
In: Erdgeschoss
Type - Material: IfcSurfaceStyle #1741
Type - Andere - Kategorie: Allgemeines Modell; Familienname: Dreiwegeventil 323126
Type - ID-Daten - Typname: Dreiwegeventil 323126
Type - IFC-Parameter - Typ in IFC-Datei exportieren: Vorgabe
Description: Dreiwegeventil
Pset_DistributionFlowElementCommon - Reference: Dreiwegeventil 323126; sets with these values: 2
Andere - Typ: Dreiwegeventil 323126; Familie: Dreiwegeventil 323126; Familie und Typ: Dreiwegeventil 323126: Dreiwegeventil 323126; Typ-ID: 2535600
Abhängigkeiten - Höhe von Ebene: 0 m; Verschieben mit umliegenden Elementen: no
Bemaßungen - Fläche: 0.445884 m2; Volumen: 0.0363136 m3
IFC-Parameter - In IFC-Datei exportieren: Nach Typ; Pset MEP.Tech-Insulation thickness (mm): 100; Pset MEP.Tech-PN: 16; Pset MEP.Tech-Connection type (Inner thread=2, flange=3): 2; Pset MEP.Geom-DN: 65; Pset MEP.Geom-Outer Ø (mm): 185; In IFC exportieren als: ifcflowcontroller; NameOverride: Dreiwegeventil; IfcPresentationLayer: 0-TFT-H_Ruecklauf; ObjectTypeOverride: Dreiwegeventil; Pset MEP.Name: Dreiwegeventil; IfcDescription: Dreiwegeventil
Phasen - Phase erstellt: Phase 01

# IfcFlowController: Dreiwegeventil 340742:Dreiwegeventil 340742, Dreiwegeventil
In: Erdgeschoss
Type - Material: IfcSurfaceStyle #1741
Type - Andere - Kategorie: Allgemeines Modell; Familienname: Dreiwegeventil 340742
Type - ID-Daten - Typname: Dreiwegeventil 340742
Type - IFC-Parameter - Typ in IFC-Datei exportieren: Vorgabe
Description: Dreiwegeventil
Pset_DistributionFlowElementCommon - Reference: Dreiwegeventil 340742; sets with these values: 2
Andere - Typ: Dreiwegeventil 340742; Familie: Dreiwegeventil 340742; Familie und Typ: Dreiwegeventil 340742: Dreiwegeventil 340742; Typ-ID: 2535922
Abhängigkeiten - Höhe von Ebene: 0 m; Verschieben mit umliegenden Elementen: no
Bemaßungen - Fläche: 0.822403 m2; Volumen: 0.073947 m3
IFC-Parameter - In IFC-Datei exportieren: Nach Typ; Pset MEP.Tech-Insulation thickness (mm): 100; Pset MEP.Tech-PN: 16; Pset MEP.Tech-Connection type (Inner thread=2, flange=3): 2; Pset MEP.Geom-DN: 125; Pset MEP.Geom-Outer Ø (mm): 250; In IFC exportieren als: ifcflowcontroller; NameOverride: Dreiwegeventil; IfcPresentationLayer: 0-TFT-H_Ruecklauf; ObjectTypeOverride: Dreiwegeventil; Pset MEP.Name: Dreiwegeventil; IfcDescription: Dreiwegeventil
Phasen - Phase erstellt: Phase 01

# IfcFlowController: Dreiwegeventil:Dreiwegeventil, Dreiwegeventil
In: Erdgeschoss
Type - Material: IfcSurfaceStyle #1741
Type - Andere - Kategorie: Allgemeines Modell; Familienname: Dreiwegeventil
Type - ID-Daten - Typname: Dreiwegeventil
Type - IFC-Parameter - Typ in IFC-Datei exportieren: Vorgabe
Description: Dreiwegeventil
Pset_DistributionFlowElementCommon - Reference: Dreiwegeventil; sets with these values: 2
Andere - Typ: Dreiwegeventil; Familie: Dreiwegeventil; Familie und Typ: Dreiwegeventil: Dreiwegeventil; Typ-ID: 2534986
Abhängigkeiten - Höhe von Ebene: 0 m; Verschieben mit umliegenden Elementen: no
Bemaßungen - Fläche: 0.400438 m2; Volumen: 0.0116139 m3
IFC-Parameter - In IFC-Datei exportieren: Nach Typ; Pset MEP.Tech-Insulation thickness (mm): 100; Pset MEP.Tech-PN: 16; Pset MEP.Tech-Connection type (Inner thread=2, flange=3): 2; Pset MEP.Geom-DN: 125; Pset MEP.Geom-Outer Ø (mm): 250; In IFC exportieren als: ifcflowcontroller; NameOverride: Dreiwegeventil; IfcPresentationLayer: 0-TFT-H_Ruecklauf; ObjectTypeOverride: Dreiwegeventil; Pset MEP.Name: Dreiwegeventil; IfcDescription: Dreiwegeventil
Phasen - Phase erstellt: Phase 01

# IfcFlowController: Gasfilter 602937:Gasfilter 602937, Gasfilter
In: Erdgeschoss
Type - Material: IfcSurfaceStyle #352577
Type - Andere - Kategorie: Allgemeines Modell; Familienname: Gasfilter 602937
Type - ID-Daten - Typname: Gasfilter 602937
Type - IFC-Parameter - Typ in IFC-Datei exportieren: Vorgabe
Description: Gasfilter
Pset_DistributionFlowElementCommon - Reference: Gasfilter 602937; sets with these values: 2
Andere - Typ: Gasfilter 602937; Familie: Gasfilter 602937; Familie und Typ: Gasfilter 602937: Gasfilter 602937; Typ-ID: 2536982
Abhängigkeiten - Höhe von Ebene: 0 m; Verschieben mit umliegenden Elementen: no
Bemaßungen - Fläche: 0.0208436 m2; Volumen: 0.000435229 m3
IFC-Parameter - In IFC-Datei exportieren: Nach Typ; Pset MEP.Tech-PN: 16; Pset MEP.Tech-Connection type (Inner thread=2, flange=3): 2; Pset MEP.Geom-DN: 50; Pset MEP.Geom-Outer Ø (mm): 95; Pset MEP.Geom-Length (mm): 80; In IFC exportieren als: ifcflowcontroller; NameOverride: Gasfilter; IfcPresentationLayer: S_Gas; ObjectTypeOverride: Gasfilter; Pset MEP.Name: Gasfilter; IfcDescription: Gasfilter
Phasen - Phase erstellt: Phase 01

# IfcFlowController: Gasfilter 604339:Gasfilter 604339, Gasfilter
In: Erdgeschoss
Type - Material: IfcSurfaceStyle #352577
Type - Andere - Kategorie: Allgemeines Modell; Familienname: Gasfilter 604339
Type - ID-Daten - Typname: Gasfilter 604339
Type - IFC-Parameter - Typ in IFC-Datei exportieren: Vorgabe
Description: Gasfilter
Pset_DistributionFlowElementCommon - Reference: Gasfilter 604339; sets with these values: 2
Andere - Typ: Gasfilter 604339; Familie: Gasfilter 604339; Familie und Typ: Gasfilter 604339: Gasfilter 604339; Typ-ID: 2537115
Abhängigkeiten - Höhe von Ebene: 0 m; Verschieben mit umliegenden Elementen: no
Bemaßungen - Fläche: 0.0208436 m2; Volumen: 0.000435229 m3
IFC-Parameter - In IFC-Datei exportieren: Nach Typ; Pset MEP.Tech-PN: 16; Pset MEP.Tech-Connection type (Inner thread=2, flange=3): 2; Pset MEP.Geom-DN: 50; Pset MEP.Geom-Outer Ø (mm): 95; Pset MEP.Geom-Length (mm): 80; In IFC exportieren als: ifcflowcontroller; NameOverride: Gasfilter; IfcPresentationLayer: S_Gas; ObjectTypeOverride: Gasfilter; Pset MEP.Name: Gasfilter; IfcDescription: Gasfilter
Phasen - Phase erstellt: Phase 01

# IfcFlowController: Gasfilter 607536:Gasfilter 607536, Gasfilter
In: Erdgeschoss
Type - Material: IfcSurfaceStyle #352577
Type - Andere - Kategorie: Allgemeines Modell; Familienname: Gasfilter 607536
Type - ID-Daten - Typname: Gasfilter 607536
Type - IFC-Parameter - Typ in IFC-Datei exportieren: Vorgabe
Description: Gasfilter
Pset_DistributionFlowElementCommon - Reference: Gasfilter 607536; sets with these values: 2
Andere - Typ: Gasfilter 607536; Familie: Gasfilter 607536; Familie und Typ: Gasfilter 607536: Gasfilter 607536; Typ-ID: 2537402
Abhängigkeiten - Höhe von Ebene: 0 m; Verschieben mit umliegenden Elementen: no
Bemaßungen - Fläche: 0.0140068 m2; Volumen: 0.000249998 m3
IFC-Parameter - In IFC-Datei exportieren: Nach Typ; Pset MEP.Tech-PN: 16; Pset MEP.Tech-Connection type (Inner thread=2, flange=3): 2; Pset MEP.Geom-Length (mm): 80; Pset MEP.Geom-DN: 32; In IFC exportieren als: ifcflowcontroller; NameOverride: Gasfilter; IfcPresentationLayer: S_Gas; ObjectTypeOverride: Gasfilter; Pset MEP.Name: Gasfilter; IfcDescription: Gasfilter; Pset MEP.Geom-Outer Ø (mm): 72
Phasen - Phase erstellt: Phase 01

# IfcFlowController: Gasfilter:Gasfilter, Gasfilter
In: Erdgeschoss
Type - Material: IfcSurfaceStyle #352577
Type - Andere - Kategorie: Allgemeines Modell; Familienname: Gasfilter
Type - ID-Daten - Typname: Gasfilter
Type - IFC-Parameter - Typ in IFC-Datei exportieren: Vorgabe
Description: Gasfilter
Pset_DistributionFlowElementCommon - Reference: Gasfilter; sets with these values: 2
Andere - Typ: Gasfilter; Familie: Gasfilter; Familie und Typ: Gasfilter: Gasfilter; Typ-ID: 2536723
Abhängigkeiten - Höhe von Ebene: 0 m; Verschieben mit umliegenden Elementen: no
Bemaßungen - Fläche: 0.0208436 m2; Volumen: 0.000435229 m3
IFC-Parameter - In IFC-Datei exportieren: Nach Typ; Pset MEP.Tech-PN: 16; Pset MEP.Tech-Connection type (Inner thread=2, flange=3): 2; Pset MEP.Geom-DN: 50; In IFC exportieren als: ifcflowcontroller; NameOverride: Gasfilter; IfcPresentationLayer: S_Gas; ObjectTypeOverride: Gasfilter; Pset MEP.Name: Gasfilter; IfcDescription: Gasfilter; Pset MEP.Geom-Outer Ø (mm): 95; Pset MEP.Geom-Length (mm): 80
Phasen - Phase erstellt: Phase 01

# IfcFlowController: Jalousieklappe:Jalousieklappe, Jalousieklappe
In: Erdgeschoss
Type - Material: IfcSurfaceStyle #271082
Type - Andere - Kategorie: Allgemeines Modell; Familienname: Jalousieklappe
Type - ID-Daten - Typname: Jalousieklappe
Type - IFC-Parameter - Typ in IFC-Datei exportieren: Vorgabe
Description: Jalousieklappe
Pset_DistributionFlowElementCommon - Reference: Jalousieklappe; sets with these values: 2
Andere - Typ: Jalousieklappe; Familie: Jalousieklappe; Familie und Typ: Jalousieklappe: Jalousieklappe; Typ-ID: 2539407
Abhängigkeiten - Höhe von Ebene: 0 m; Verschieben mit umliegenden Elementen: no
Bemaßungen - Fläche: 0.490056 m2; Volumen: 0.0531895 m3
IFC-Parameter - In IFC-Datei exportieren: Nach Typ; Pset MEP.Calc-Pressure loss (Pa): 22; Pset MEP.Calc-Zeta: 2; Pset MEP.Geom-Side 2 (mm): 900; Pset MEP.Geom-Length (mm): 180; In IFC exportieren als: ifcflowcontroller; NameOverride: Jalousieklappe; IfcPresentationLayer: 0-TFT-L_Bauteil; ObjectTypeOverride: Jalousieklappe; Pset MEP.Name: Jalousieklappe; IfcDescription: Jalousieklappe; Pset MEP.Tech-Medium: L_Zuluft; Pset MEP.Geom-Side 1 (mm): 500
Phasen - Phase erstellt: Phase 01

# IfcFlowController: Rückschlagklappe 236840:Rückschlagklappe 236840, Rückschlagklappe
In: 1. Obergeschoss
Type - Material: IfcSurfaceStyle #9317
Type - Andere - Kategorie: Allgemeines Modell; Familienname: Rückschlagklappe 236840
Type - ID-Daten - Typname: Rückschlagklappe 236840
Type - IFC-Parameter - Typ in IFC-Datei exportieren: Vorgabe
Description: Rückschlagklappe
Pset_DistributionFlowElementCommon - Reference: Rückschlagklappe 236840; sets with these values: 2
Andere - Typ: Rückschlagklappe 236840; Familie: Rückschlagklappe 236840; Familie und Typ: Rückschlagklappe 236840: Rückschlagklappe 236840; Typ-ID: 2532277
Abhängigkeiten - Höhe von Ebene: 0 m; Verschieben mit umliegenden Elementen: no
Bemaßungen - Fläche: 0.228543 m2; Volumen: 0.0147093 m3
IFC-Parameter - In IFC-Datei exportieren: Nach Typ; Pset MEP.Tech-Insulation thickness (mm): 100; Pset MEP.Tech-PN: 16; Pset MEP.Tech-Connection type (Inner thread=2, flange=3): 2; Pset MEP.Geom-DN: 125; Pset MEP.Geom-Outer Ø (mm): 250; Pset MEP.Geom-Length (mm): 100; In IFC exportieren als: ifcflowcontroller; NameOverride: Rückschlagklappe; IfcPresentationLayer: 0-TFT-H_Vorlauf; ObjectTypeOverride: Rückschlagklappe; Pset MEP.Name: Rückschlagklappe; IfcDescription: Rückschlagklappe
Phasen - Phase erstellt: Phase 01

# IfcFlowController: Rückschlagklappe 237093:Rückschlagklappe 237093, Rückschlagklappe
In: 1. Obergeschoss
Type - Material: IfcSurfaceStyle #9317
Type - Andere - Kategorie: Allgemeines Modell; Familienname: Rückschlagklappe 237093
Type - ID-Daten - Typname: Rückschlagklappe 237093
Type - IFC-Parameter - Typ in IFC-Datei exportieren: Vorgabe
Description: Rückschlagklappe
Pset_DistributionFlowElementCommon - Reference: Rückschlagklappe 237093; sets with these values: 2
Andere - Typ: Rückschlagklappe 237093; Familie: Rückschlagklappe 237093; Familie und Typ: Rückschlagklappe 237093: Rückschlagklappe 237093; Typ-ID: 2532354
Abhängigkeiten - Höhe von Ebene: 0 m; Verschieben mit umliegenden Elementen: no
Bemaßungen - Fläche: 0.228543 m2; Volumen: 0.0147093 m3
IFC-Parameter - In IFC-Datei exportieren: Nach Typ; Pset MEP.Tech-Insulation thickness (mm): 100; Pset MEP.Tech-PN: 16; Pset MEP.Tech-Connection type (Inner thread=2, flange=3): 2; Pset MEP.Geom-DN: 125; Pset MEP.Geom-Outer Ø (mm): 250; Pset MEP.Geom-Length (mm): 100; In IFC exportieren als: ifcflowcontroller; NameOverride: Rückschlagklappe; IfcPresentationLayer: 0-TFT-H_Vorlauf; ObjectTypeOverride: Rückschlagklappe; Pset MEP.Name: Rückschlagklappe; IfcDescription: Rückschlagklappe
Phasen - Phase erstellt: Phase 01

# IfcFlowController: Rückschlagklappe 308152:Rückschlagklappe 308152, Rückschlagklappe
In: Erdgeschoss
Type - Material: IfcSurfaceStyle #1741
Type - Andere - Kategorie: Allgemeines Modell; Familienname: Rückschlagklappe 308152
Type - ID-Daten - Typname: Rückschlagklappe 308152
Type - IFC-Parameter - Typ in IFC-Datei exportieren: Vorgabe
Description: Rückschlagklappe
Pset_DistributionFlowElementCommon - Reference: Rückschlagklappe 308152; sets with these values: 2
Andere - Typ: Rückschlagklappe 308152; Familie: Rückschlagklappe 308152; Familie und Typ: Rückschlagklappe 308152: Rückschlagklappe 308152; Typ-ID: 2535028
Abhängigkeiten - Höhe von Ebene: 0 m; Verschieben mit umliegenden Elementen: no
Bemaßungen - Fläche: 0.213269 m2; Volumen: 0.00705453 m3
IFC-Parameter - In IFC-Datei exportieren: Nach Typ; Pset MEP.Tech-PN: 16; Pset MEP.Tech-Connection type (Inner thread=2, flange=3): 2; Pset MEP.Geom-Length (mm): 400; Pset MEP.Geom-DN: 125; Pset MEP.Geom-Outer Ø (mm): 250; In IFC exportieren als: ifcflowcontroller; NameOverride: Rückschlagklappe; IfcPresentationLayer: 0-TFT-H_Ruecklauf; ObjectTypeOverride: Rückschlagklappe; Pset MEP.Name: Rückschlagklappe; IfcDescription: Rückschlagklappe
Phasen - Phase erstellt: Phase 01

# IfcFlowController: Rückschlagklappe 318782:Rückschlagklappe 318782, Rückschlagklappe
In: Erdgeschoss
Type - Material: IfcSurfaceStyle #1741
Type - Andere - Kategorie: Allgemeines Modell; Familienname: Rückschlagklappe 318782
Type - ID-Daten - Typname: Rückschlagklappe 318782
Type - IFC-Parameter - Typ in IFC-Datei exportieren: Vorgabe
Description: Rückschlagklappe
Pset_DistributionFlowElementCommon - Reference: Rückschlagklappe 318782; sets with these values: 2
Andere - Typ: Rückschlagklappe 318782; Familie: Rückschlagklappe 318782; Familie und Typ: Rückschlagklappe 318782: Rückschlagklappe 318782; Typ-ID: 2535362
Abhängigkeiten - Höhe von Ebene: 0 m; Verschieben mit umliegenden Elementen: no
Bemaßungen - Fläche: 0.213269 m2; Volumen: 0.00705453 m3
IFC-Parameter - In IFC-Datei exportieren: Nach Typ; Pset MEP.Tech-PN: 16; Pset MEP.Tech-Connection type (Inner thread=2, flange=3): 2; Pset MEP.Geom-Length (mm): 400; Pset MEP.Geom-DN: 125; Pset MEP.Geom-Outer Ø (mm): 250; In IFC exportieren als: ifcflowcontroller; NameOverride: Rückschlagklappe; IfcPresentationLayer: 0-TFT-H_Ruecklauf; ObjectTypeOverride: Rückschlagklappe; Pset MEP.Name: Rückschlagklappe; IfcDescription: Rückschlagklappe
Phasen - Phase erstellt: Phase 01

# IfcFlowController: Rückschlagklappe 340834:Rückschlagklappe 340834, Rückschlagklappe
In: Erdgeschoss
Type - Material: IfcSurfaceStyle #1741
Type - Andere - Kategorie: Allgemeines Modell; Familienname: Rückschlagklappe 340834
Type - ID-Daten - Typname: Rückschlagklappe 340834
Type - IFC-Parameter - Typ in IFC-Datei exportieren: Vorgabe
Description: Rückschlagklappe
Pset_DistributionFlowElementCommon - Reference: Rückschlagklappe 340834; sets with these values: 2
Andere - Typ: Rückschlagklappe 340834; Familie: Rückschlagklappe 340834; Familie und Typ: Rückschlagklappe 340834: Rückschlagklappe 340834; Typ-ID: 2535950
Abhängigkeiten - Höhe von Ebene: 0 m; Verschieben mit umliegenden Elementen: no
Bemaßungen - Fläche: 0.213269 m2; Volumen: 0.00705453 m3
IFC-Parameter - In IFC-Datei exportieren: Nach Typ; Pset MEP.Tech-PN: 16; Pset MEP.Tech-Connection type (Inner thread=2, flange=3): 2; Pset MEP.Geom-Length (mm): 400; Pset MEP.Geom-DN: 125; Pset MEP.Geom-Outer Ø (mm): 250; In IFC exportieren als: ifcflowcontroller; NameOverride: Rückschlagklappe; IfcPresentationLayer: 0-TFT-H_Ruecklauf; ObjectTypeOverride: Rückschlagklappe; Pset MEP.Name: Rückschlagklappe; IfcDescription: Rückschlagklappe
Phasen - Phase erstellt: Phase 01

# IfcFlowController: Rückschlagklappe:Rückschlagklappe, Rückschlagklappe
In: 1. Obergeschoss
Type - Material: IfcSurfaceStyle #9317
Type - Andere - Kategorie: Allgemeines Modell; Familienname: Rückschlagklappe
Type - ID-Daten - Typname: Rückschlagklappe
Type - IFC-Parameter - Typ in IFC-Datei exportieren: Vorgabe
Description: Rückschlagklappe
Pset_DistributionFlowElementCommon - Reference: Rückschlagklappe; sets with these values: 2
Andere - Typ: Rückschlagklappe; Familie: Rückschlagklappe; Familie und Typ: Rückschlagklappe: Rückschlagklappe; Typ-ID: 2532200
Abhängigkeiten - Höhe von Ebene: 0 m; Verschieben mit umliegenden Elementen: no
Bemaßungen - Fläche: 0.228543 m2; Volumen: 0.0147093 m3
IFC-Parameter - In IFC-Datei exportieren: Nach Typ; Pset MEP.Tech-Insulation thickness (mm): 100; Pset MEP.Tech-PN: 16; Pset MEP.Tech-Connection type (Inner thread=2, flange=3): 2; Pset MEP.Geom-DN: 125; In IFC exportieren als: ifcflowcontroller; NameOverride: Rückschlagklappe; IfcPresentationLayer: 0-TFT-H_Vorlauf; ObjectTypeOverride: Rückschlagklappe; Pset MEP.Name: Rückschlagklappe; IfcDescription: Rückschlagklappe; Pset MEP.Geom-Outer Ø (mm): 250; Pset MEP.Geom-Length (mm): 100
Phasen - Phase erstellt: Phase 01

# IfcFlowController: Schieber 602983:Schieber 602983, Schieber
In: Erdgeschoss
Type - Material: IfcSurfaceStyle #352577
Type - Andere - Kategorie: Allgemeines Modell; Familienname: Schieber 602983
Type - ID-Daten - Typname: Schieber 602983
Type - IFC-Parameter - Typ in IFC-Datei exportieren: Vorgabe
Description: Schieber
Pset_DistributionFlowElementCommon - Reference: Schieber 602983; sets with these values: 2
Andere - Typ: Schieber 602983; Familie: Schieber 602983; Familie und Typ: Schieber 602983: Schieber 602983; Typ-ID: 2536996
Abhängigkeiten - Höhe von Ebene: 0 m; Verschieben mit umliegenden Elementen: no
Bemaßungen - Fläche: 0.152579 m2; Volumen: 0.00190894 m3
IFC-Parameter - In IFC-Datei exportieren: Nach Typ; Pset MEP.Tech-PN: 16; Pset MEP.Tech-Connection type (Inner thread=2, flange=3): 2; Pset MEP.Geom-DN: 65; Pset MEP.Geom-Outer Ø (mm): 185; Pset MEP.Geom-Length (mm): 290; In IFC exportieren als: ifcflowcontroller; NameOverride: Schieber; IfcPresentationLayer: S_Gas; ObjectTypeOverride: Schieber; Pset MEP.Name: Schieber; IfcDescription: Schieber
Phasen - Phase erstellt: Phase 01

# IfcFlowController: Schieber 604454:Schieber 604454, Schieber
In: Erdgeschoss
Type - Material: IfcSurfaceStyle #352577
Type - Andere - Kategorie: Allgemeines Modell; Familienname: Schieber 604454
Type - ID-Daten - Typname: Schieber 604454
Type - IFC-Parameter - Typ in IFC-Datei exportieren: Vorgabe
Description: Schieber
Pset_DistributionFlowElementCommon - Reference: Schieber 604454; sets with these values: 2
Andere - Typ: Schieber 604454; Familie: Schieber 604454; Familie und Typ: Schieber 604454: Schieber 604454; Typ-ID: 2537150
Abhängigkeiten - Höhe von Ebene: 0 m; Verschieben mit umliegenden Elementen: no
Bemaßungen - Fläche: 0.152579 m2; Volumen: 0.00190894 m3
IFC-Parameter - In IFC-Datei exportieren: Nach Typ; Pset MEP.Tech-PN: 16; Pset MEP.Tech-Connection type (Inner thread=2, flange=3): 2; Pset MEP.Geom-DN: 65; Pset MEP.Geom-Outer Ø (mm): 185; Pset MEP.Geom-Length (mm): 290; In IFC exportieren als: ifcflowcontroller; NameOverride: Schieber; IfcPresentationLayer: S_Gas; ObjectTypeOverride: Schieber; Pset MEP.Name: Schieber; IfcDescription: Schieber
Phasen - Phase erstellt: Phase 01

# IfcFlowController: Schieber 608661:Schieber 608661, Schieber
In: Erdgeschoss
Type - Material: IfcSurfaceStyle #352577
Type - Andere - Kategorie: Allgemeines Modell; Familienname: Schieber 608661
Type - ID-Daten - Typname: Schieber 608661
Type - IFC-Parameter - Typ in IFC-Datei exportieren: Vorgabe
Description: Schieber
Pset_DistributionFlowElementCommon - Reference: Schieber 608661; sets with these values: 2
Andere - Typ: Schieber 608661; Familie: Schieber 608661; Familie und Typ: Schieber 608661: Schieber 608661; Typ-ID: 2537472
Abhängigkeiten - Höhe von Ebene: 0 m; Verschieben mit umliegenden Elementen: no
Bemaßungen - Fläche: 0.0736727 m2; Volumen: 0.000972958 m3
IFC-Parameter - In IFC-Datei exportieren: Nach Typ; Pset MEP.Tech-PN: 16; Pset MEP.Tech-Connection type (Inner thread=2, flange=3): 2; Pset MEP.Geom-DN: 32; Pset MEP.Geom-Outer Ø (mm): 140; Pset MEP.Geom-Length (mm): 180; In IFC exportieren als: ifcflowcontroller; NameOverride: Schieber; IfcPresentationLayer: S_Gas; ObjectTypeOverride: Schieber; Pset MEP.Name: Schieber; IfcDescription: Schieber
Phasen - Phase erstellt: Phase 01

# IfcFlowController: Schieber:Schieber, Schieber
In: Erdgeschoss
Type - Material: IfcSurfaceStyle #352577
Type - Andere - Kategorie: Allgemeines Modell; Familienname: Schieber
Type - ID-Daten - Typname: Schieber
Type - IFC-Parameter - Typ in IFC-Datei exportieren: Vorgabe
Description: Schieber
Pset_DistributionFlowElementCommon - Reference: Schieber; sets with these values: 2
Andere - Typ: Schieber; Familie: Schieber; Familie und Typ: Schieber: Schieber; Typ-ID: 2536835
Abhängigkeiten - Höhe von Ebene: 0 m; Verschieben mit umliegenden Elementen: no
Bemaßungen - Fläche: 0.152579 m2; Volumen: 0.00190894 m3
IFC-Parameter - In IFC-Datei exportieren: Nach Typ; Pset MEP.Tech-PN: 16; Pset MEP.Tech-Connection type (Inner thread=2, flange=3): 2; Pset MEP.Geom-DN: 65; Pset MEP.Geom-Outer Ø (mm): 185; Pset MEP.Geom-Length (mm): 290; In IFC exportieren als: ifcflowcontroller; NameOverride: Schieber; IfcPresentationLayer: S_Gas; ObjectTypeOverride: Schieber; Pset MEP.Name: Schieber; IfcDescription: Schieber
Phasen - Phase erstellt: Phase 01

# IfcFlowController: Ventil 258801:Ventil 258801, Ventil
In: 1. Obergeschoss
Type - Material: IfcSurfaceStyle #1741
Type - Andere - Kategorie: Allgemeines Modell; Familienname: Ventil 258801
Type - ID-Daten - Typname: Ventil 258801
Type - IFC-Parameter - Typ in IFC-Datei exportieren: Vorgabe
Description: Ventil
Pset_DistributionFlowElementCommon - Reference: Ventil 258801; sets with these values: 2
Andere - Typ: Ventil 258801; Familie: Ventil 258801; Familie und Typ: Ventil 258801: Ventil 258801; Typ-ID: 2532995
Abhängigkeiten - Höhe von Ebene: 0 m; Verschieben mit umliegenden Elementen: no
Bemaßungen - Fläche: 0.304962 m2; Volumen: 0.0246867 m3
IFC-Parameter - In IFC-Datei exportieren: Nach Typ; Pset MEP.Tech-Insulation thickness (mm): 100; Pset MEP.Tech-PN: 16; Pset MEP.Tech-Connection type (Inner thread=2, flange=3): 2; Pset MEP.Geom-DN: 65; Pset MEP.Geom-Outer Ø (mm): 185; Pset MEP.Geom-Length (mm): 290; In IFC exportieren als: ifcflowcontroller; NameOverride: Ventil; IfcPresentationLayer: 0-TFT-H_Ruecklauf; ObjectTypeOverride: Ventil; Pset MEP.Name: Ventil; IfcDescription: Ventil
Phasen - Phase erstellt: Phase 01

# IfcFlowController: Ventil 263077:Ventil 263077, Ventil
In: 1. Obergeschoss
Type - Material: IfcSurfaceStyle #9317
Type - Andere - Kategorie: Allgemeines Modell; Familienname: Ventil 263077
Type - ID-Daten - Typname: Ventil 263077
Type - IFC-Parameter - Typ in IFC-Datei exportieren: Vorgabe
Description: Ventil
Pset_DistributionFlowElementCommon - Reference: Ventil 263077; sets with these values: 2
Andere - Typ: Ventil 263077; Familie: Ventil 263077; Familie und Typ: Ventil 263077: Ventil 263077; Typ-ID: 2533156
Abhängigkeiten - Höhe von Ebene: 0 m; Verschieben mit umliegenden Elementen: no
Bemaßungen - Fläche: 0.444799 m2; Volumen: 0.0377699 m3
IFC-Parameter - In IFC-Datei exportieren: Nach Typ; Pset MEP.Tech-Insulation thickness (mm): 100; Pset MEP.Tech-PN: 16; Pset MEP.Tech-Connection type (Inner thread=2, flange=3): 2; Pset MEP.Geom-DN: 100; Pset MEP.Geom-Outer Ø (mm): 220; In IFC exportieren als: ifcflowcontroller; NameOverride: Ventil; IfcPresentationLayer: 0-TFT-H_Vorlauf; ObjectTypeOverride: Ventil; Pset MEP.Name: Ventil; IfcDescription: Ventil; Pset MEP.Geom-Length (mm): 350
Phasen - Phase erstellt: Phase 01

# IfcFlowController: Ventil 267043:Ventil 267043, Ventil
In: 1. Obergeschoss
Type - Material: IfcSurfaceStyle #9317
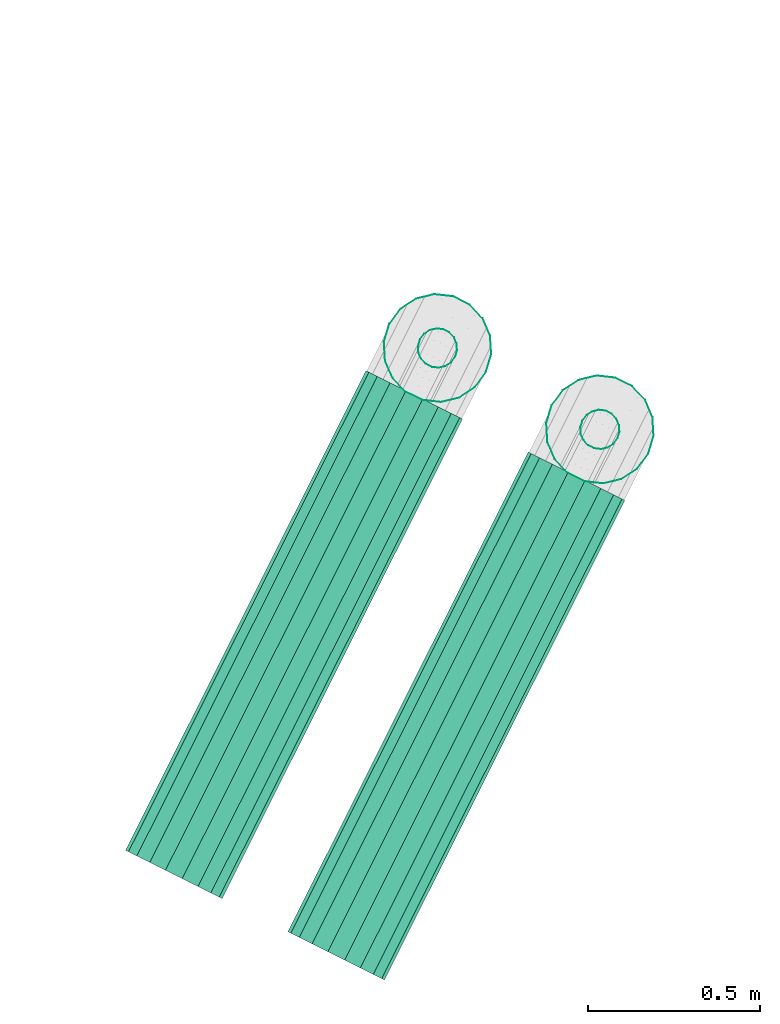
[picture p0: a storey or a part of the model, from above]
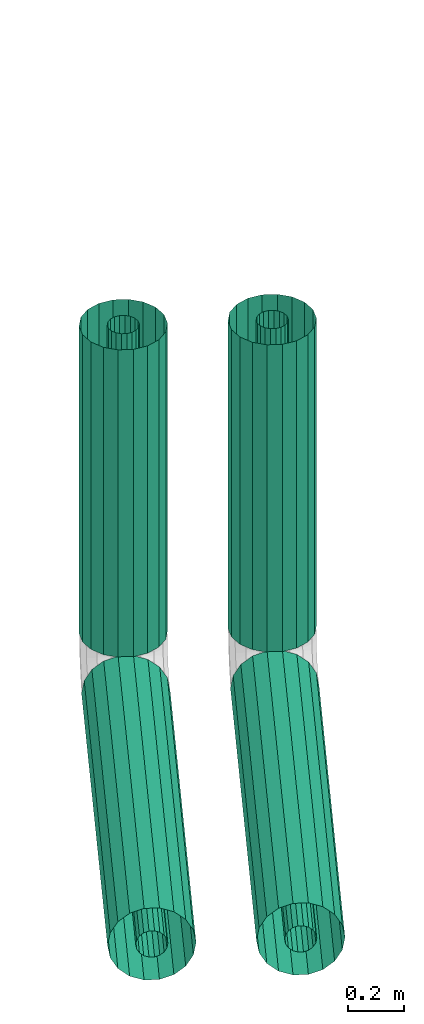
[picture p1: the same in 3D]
Properties of the parts of a building model (IFC2X3), part 5 of 23

# IfcFlowController: Ventil 267043:Ventil 267043, Ventil
Type - Andere - Kategorie: Allgemeines Modell; Familienname: Ventil 267043
Type - ID-Daten - Typname: Ventil 267043
Type - IFC-Parameter - Typ in IFC-Datei exportieren: Vorgabe
Description: Ventil
Pset_DistributionFlowElementCommon - Reference: Ventil 267043; sets with these values: 2
Andere - Typ: Ventil 267043; Familie: Ventil 267043; Familie und Typ: Ventil 267043: Ventil 267043; Typ-ID: 2533212
Abhängigkeiten - Höhe von Ebene: 0 m; Verschieben mit umliegenden Elementen: no
Bemaßungen - Fläche: 0.444799 m2; Volumen: 0.0377699 m3
IFC-Parameter - In IFC-Datei exportieren: Nach Typ; Pset MEP.Tech-Insulation thickness (mm): 100; Pset MEP.Tech-PN: 16; Pset MEP.Tech-Connection type (Inner thread=2, flange=3): 2; Pset MEP.Geom-DN: 100; Pset MEP.Geom-Outer Ø (mm): 220; Pset MEP.Geom-Length (mm): 350; In IFC exportieren als: ifcflowcontroller; NameOverride: Ventil; IfcPresentationLayer: 0-TFT-H_Vorlauf; ObjectTypeOverride: Ventil; Pset MEP.Name: Ventil; IfcDescription: Ventil
Phasen - Phase erstellt: Phase 01

# IfcFlowController: Ventil 615460:Ventil 615460, Ventil
In: Erdgeschoss
Type - Material: IfcSurfaceStyle #352577
Type - Andere - Kategorie: Allgemeines Modell; Familienname: Ventil 615460
Type - ID-Daten - Typname: Ventil 615460
Type - IFC-Parameter - Typ in IFC-Datei exportieren: Vorgabe
Description: Ventil
Pset_DistributionFlowElementCommon - Reference: Ventil 615460; sets with these values: 2
Andere - Typ: Ventil 615460; Familie: Ventil 615460; Familie und Typ: Ventil 615460: Ventil 615460; Typ-ID: 2537822
Abhängigkeiten - Höhe von Ebene: 0 m; Verschieben mit umliegenden Elementen: no
Bemaßungen - Fläche: 0.0588991 m2; Volumen: 0.000784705 m3
IFC-Parameter - In IFC-Datei exportieren: Nach Typ; Pset MEP.Tech-PN: 16; Pset MEP.Tech-Connection type (Inner thread=2, flange=3): 2; Pset MEP.Geom-DN: 32; Pset MEP.Geom-Outer Ø (mm): 140; Pset MEP.Geom-Length (mm): 180; In IFC exportieren als: ifcflowcontroller; NameOverride: Ventil; IfcPresentationLayer: S_Gas; ObjectTypeOverride: Ventil; Pset MEP.Name: Ventil; IfcDescription: Ventil
Phasen - Phase erstellt: Phase 01

# IfcFlowController: Ventil:Ventil, Ventil
In: 1. Obergeschoss
Type - Material: IfcSurfaceStyle #1741
Type - Andere - Kategorie: Allgemeines Modell; Familienname: Ventil
Type - ID-Daten - Typname: Ventil
Type - IFC-Parameter - Typ in IFC-Datei exportieren: Vorgabe
Description: Ventil
Pset_DistributionFlowElementCommon - Reference: Ventil; sets with these values: 2
Andere - Typ: Ventil; Familie: Ventil; Familie und Typ: Ventil: Ventil; Typ-ID: 2532960
Abhängigkeiten - Höhe von Ebene: 0 m; Verschieben mit umliegenden Elementen: no
Bemaßungen - Fläche: 0.304962 m2; Volumen: 0.0246867 m3
IFC-Parameter - In IFC-Datei exportieren: Nach Typ; Pset MEP.Tech-Insulation thickness (mm): 100; Pset MEP.Tech-PN: 16; Pset MEP.Tech-Connection type (Inner thread=2, flange=3): 2; In IFC exportieren als: ifcflowcontroller; NameOverride: Ventil; IfcPresentationLayer: 0-TFT-H_Ruecklauf; ObjectTypeOverride: Ventil; Pset MEP.Name: Ventil; IfcDescription: Ventil; Pset MEP.Geom-DN: 65; Pset MEP.Geom-Outer Ø (mm): 185; Pset MEP.Geom-Length (mm): 290
Phasen - Phase erstellt: Phase 01

# IfcFlowController: Zwischenflanschklappe 12210:Zwischenflanschklappe 12210, Zwischenflanschklappe
In: 1. Obergeschoss
Type - Material: IfcSurfaceStyle #9317
Type - Andere - Kategorie: Allgemeines Modell; Familienname: Zwischenflanschklappe 12210
Type - ID-Daten - Typname: Zwischenflanschklappe 12210
Type - IFC-Parameter - Typ in IFC-Datei exportieren: Vorgabe
Description: Zwischenflanschklappe
Pset_DistributionFlowElementCommon - Reference: Zwischenflanschklappe 12210; sets with these values: 2
Andere - Typ: Zwischenflanschklappe 12210; Familie: Zwischenflanschklappe 12210; Familie und Typ: Zwischenflanschklappe 12210: Zwischenflanschklappe 12210; Typ-ID: 2531541
Abhängigkeiten - Höhe von Ebene: 0 m; Verschieben mit umliegenden Elementen: no
Bemaßungen - Fläche: 0.190915 m2; Volumen: 0.00902063 m3
IFC-Parameter - In IFC-Datei exportieren: Nach Typ; Pset MEP.Tech-Insulation thickness (mm): 100; Pset MEP.Tech-PN: 16; Pset MEP.Tech-Connection type (Inner thread=2, flange=3): 2; Pset MEP.Geom-DN: 150; In IFC exportieren als: ifcflowcontroller; NameOverride: Zwischenflanschklappe; IfcPresentationLayer: 0-TFT-H_Vorlauf; ObjectTypeOverride: Zwischenflanschklappe; Pset MEP.Name: Zwischenflanschklappe; IfcDescription: Zwischenflanschklappe; Pset MEP.Geom-Length (mm): 56
Phasen - Phase erstellt: Phase 01

# IfcFlowController: Zwischenflanschklappe 221228:Zwischenflanschklappe 221228, Zwischenflanschklappe
In: 1. Obergeschoss
Type - Material: IfcSurfaceStyle #9317
Type - Andere - Kategorie: Allgemeines Modell; Familienname: Zwischenflanschklappe 221228
Type - ID-Daten - Typname: Zwischenflanschklappe 221228
Type - IFC-Parameter - Typ in IFC-Datei exportieren: Vorgabe
Description: Zwischenflanschklappe
Pset_DistributionFlowElementCommon - Reference: Zwischenflanschklappe 221228; sets with these values: 2
Andere - Typ: Zwischenflanschklappe 221228; Familie: Zwischenflanschklappe 221228; Familie und Typ: Zwischenflanschklappe 221228: Zwischenflanschklappe 221228; Typ-ID: 2531709
Abhängigkeiten - Höhe von Ebene: 0 m; Verschieben mit umliegenden Elementen: no
Bemaßungen - Fläche: 0.190915 m2; Volumen: 0.00902063 m3
IFC-Parameter - In IFC-Datei exportieren: Nach Typ; Pset MEP.Tech-Insulation thickness (mm): 100; Pset MEP.Tech-PN: 16; Pset MEP.Tech-Connection type (Inner thread=2, flange=3): 2; Pset MEP.Geom-DN: 150; Pset MEP.Geom-Length (mm): 56; In IFC exportieren als: ifcflowcontroller; NameOverride: Zwischenflanschklappe; IfcPresentationLayer: 0-TFT-H_Vorlauf; ObjectTypeOverride: Zwischenflanschklappe; Pset MEP.Name: Zwischenflanschklappe; IfcDescription: Zwischenflanschklappe
Phasen - Phase erstellt: Phase 01

# IfcFlowController: Zwischenflanschklappe 221494:Zwischenflanschklappe 221494, Zwischenflanschklappe
In: 1. Obergeschoss
Type - Material: IfcSurfaceStyle #9317
Type - Andere - Kategorie: Allgemeines Modell; Familienname: Zwischenflanschklappe 221494
Type - ID-Daten - Typname: Zwischenflanschklappe 221494
Type - IFC-Parameter - Typ in IFC-Datei exportieren: Vorgabe
Description: Zwischenflanschklappe
Pset_DistributionFlowElementCommon - Reference: Zwischenflanschklappe 221494; sets with these values: 2
Andere - Typ: Zwischenflanschklappe 221494; Familie: Zwischenflanschklappe 221494; Familie und Typ: Zwischenflanschklappe 221494: Zwischenflanschklappe 221494; Typ-ID: 2531789
Abhängigkeiten - Höhe von Ebene: 0 m; Verschieben mit umliegenden Elementen: no
Bemaßungen - Fläche: 0.190915 m2; Volumen: 0.00902063 m3
IFC-Parameter - In IFC-Datei exportieren: Nach Typ; Pset MEP.Tech-Insulation thickness (mm): 100; Pset MEP.Tech-PN: 16; Pset MEP.Tech-Connection type (Inner thread=2, flange=3): 2; Pset MEP.Geom-DN: 150; Pset MEP.Geom-Length (mm): 56; In IFC exportieren als: ifcflowcontroller; NameOverride: Zwischenflanschklappe; IfcPresentationLayer: 0-TFT-H_Vorlauf; ObjectTypeOverride: Zwischenflanschklappe; Pset MEP.Name: Zwischenflanschklappe; IfcDescription: Zwischenflanschklappe
Phasen - Phase erstellt: Phase 01

# IfcFlowController: Zwischenflanschklappe 234235:Zwischenflanschklappe 234235, Zwischenflanschklappe
In: 1. Obergeschoss
Type - Material: IfcSurfaceStyle #9317
Type - Andere - Kategorie: Allgemeines Modell; Familienname: Zwischenflanschklappe 234235
Type - ID-Daten - Typname: Zwischenflanschklappe 234235
Type - IFC-Parameter - Typ in IFC-Datei exportieren: Vorgabe
Description: Zwischenflanschklappe
Pset_DistributionFlowElementCommon - Reference: Zwischenflanschklappe 234235; sets with these values: 2
Andere - Typ: Zwischenflanschklappe 234235; Familie: Zwischenflanschklappe 234235; Familie und Typ: Zwischenflanschklappe 234235: Zwischenflanschklappe 234235; Typ-ID: 2532221
Abhängigkeiten - Höhe von Ebene: 0 m; Verschieben mit umliegenden Elementen: no
Bemaßungen - Fläche: 0.190915 m2; Volumen: 0.00902063 m3
IFC-Parameter - In IFC-Datei exportieren: Nach Typ; Pset MEP.Tech-Insulation thickness (mm): 100; Pset MEP.Tech-PN: 16; Pset MEP.Tech-Connection type (Inner thread=2, flange=3): 2; Pset MEP.Geom-DN: 150; Pset MEP.Geom-Length (mm): 56; In IFC exportieren als: ifcflowcontroller; NameOverride: Zwischenflanschklappe; IfcPresentationLayer: 0-TFT-H_Vorlauf; ObjectTypeOverride: Zwischenflanschklappe; Pset MEP.Name: Zwischenflanschklappe; IfcDescription: Zwischenflanschklappe
Phasen - Phase erstellt: Phase 01

# IfcFlowController: Zwischenflanschklappe 236909:Zwischenflanschklappe 236909, Zwischenflanschklappe
In: 1. Obergeschoss
Type - Material: IfcSurfaceStyle #9317
Type - Andere - Kategorie: Allgemeines Modell; Familienname: Zwischenflanschklappe 236909
Type - ID-Daten - Typname: Zwischenflanschklappe 236909
Type - IFC-Parameter - Typ in IFC-Datei exportieren: Vorgabe
Description: Zwischenflanschklappe
Pset_DistributionFlowElementCommon - Reference: Zwischenflanschklappe 236909; sets with these values: 2
Andere - Typ: Zwischenflanschklappe 236909; Familie: Zwischenflanschklappe 236909; Familie und Typ: Zwischenflanschklappe 236909: Zwischenflanschklappe 236909; Typ-ID: 2532298
Abhängigkeiten - Höhe von Ebene: 0 m; Verschieben mit umliegenden Elementen: no
Bemaßungen - Fläche: 0.190915 m2; Volumen: 0.00902063 m3
IFC-Parameter - In IFC-Datei exportieren: Nach Typ; Pset MEP.Tech-Insulation thickness (mm): 100; Pset MEP.Tech-PN: 16; Pset MEP.Tech-Connection type (Inner thread=2, flange=3): 2; Pset MEP.Geom-DN: 150; Pset MEP.Geom-Length (mm): 56; In IFC exportieren als: ifcflowcontroller; NameOverride: Zwischenflanschklappe; IfcPresentationLayer: 0-TFT-H_Vorlauf; ObjectTypeOverride: Zwischenflanschklappe; Pset MEP.Name: Zwischenflanschklappe; IfcDescription: Zwischenflanschklappe
Phasen - Phase erstellt: Phase 01

# IfcFlowController: Zwischenflanschklappe 237162:Zwischenflanschklappe 237162, Zwischenflanschklappe
In: 1. Obergeschoss
Type - Material: IfcSurfaceStyle #9317
Type - Andere - Kategorie: Allgemeines Modell; Familienname: Zwischenflanschklappe 237162
Type - ID-Daten - Typname: Zwischenflanschklappe 237162
Type - IFC-Parameter - Typ in IFC-Datei exportieren: Vorgabe
Description: Zwischenflanschklappe
Pset_DistributionFlowElementCommon - Reference: Zwischenflanschklappe 237162; sets with these values: 2
Andere - Typ: Zwischenflanschklappe 237162; Familie: Zwischenflanschklappe 237162; Familie und Typ: Zwischenflanschklappe 237162: Zwischenflanschklappe 237162; Typ-ID: 2532375
Abhängigkeiten - Höhe von Ebene: 0 m; Verschieben mit umliegenden Elementen: no
Bemaßungen - Fläche: 0.190915 m2; Volumen: 0.00902063 m3
IFC-Parameter - In IFC-Datei exportieren: Nach Typ; Pset MEP.Tech-Insulation thickness (mm): 100; Pset MEP.Tech-PN: 16; Pset MEP.Tech-Connection type (Inner thread=2, flange=3): 2; Pset MEP.Geom-DN: 150; Pset MEP.Geom-Length (mm): 56; In IFC exportieren als: ifcflowcontroller; NameOverride: Zwischenflanschklappe; IfcPresentationLayer: 0-TFT-H_Vorlauf; ObjectTypeOverride: Zwischenflanschklappe; Pset MEP.Name: Zwischenflanschklappe; IfcDescription: Zwischenflanschklappe
Phasen - Phase erstellt: Phase 01

# IfcFlowController: Zwischenflanschklappe 240629:Zwischenflanschklappe 240629, Zwischenflanschklappe
In: 1. Obergeschoss
Type - Material: IfcSurfaceStyle #9317
Type - Andere - Kategorie: Allgemeines Modell; Familienname: Zwischenflanschklappe 240629
Type - ID-Daten - Typname: Zwischenflanschklappe 240629
Type - IFC-Parameter - Typ in IFC-Datei exportieren: Vorgabe
Description: Zwischenflanschklappe
Pset_DistributionFlowElementCommon - Reference: Zwischenflanschklappe 240629; sets with these values: 2
Andere - Typ: Zwischenflanschklappe 240629; Familie: Zwischenflanschklappe 240629; Familie und Typ: Zwischenflanschklappe 240629: Zwischenflanschklappe 240629; Typ-ID: 2532466
Abhängigkeiten - Höhe von Ebene: 0 m; Verschieben mit umliegenden Elementen: no
Bemaßungen - Fläche: 0.119603 m2; Volumen: 0.00586969 m3
IFC-Parameter - In IFC-Datei exportieren: Nach Typ; Pset MEP.Tech-Insulation thickness (mm): 100; Pset MEP.Tech-PN: 16; Pset MEP.Tech-Connection type (Inner thread=2, flange=3): 2; Pset MEP.Geom-DN: 100; Pset MEP.Geom-Length (mm): 52; In IFC exportieren als: ifcflowcontroller; NameOverride: Zwischenflanschklappe; IfcPresentationLayer: 0-TFT-H_Vorlauf; ObjectTypeOverride: Zwischenflanschklappe; Pset MEP.Name: Zwischenflanschklappe; IfcDescription: Zwischenflanschklappe
Phasen - Phase erstellt: Phase 01

# IfcFlowController: Zwischenflanschklappe 243412:Zwischenflanschklappe 243412, Zwischenflanschklappe
In: 1. Obergeschoss
Type - Material: IfcSurfaceStyle #9317
Type - Andere - Kategorie: Allgemeines Modell; Familienname: Zwischenflanschklappe 243412
Type - ID-Daten - Typname: Zwischenflanschklappe 243412
Type - IFC-Parameter - Typ in IFC-Datei exportieren: Vorgabe
Description: Zwischenflanschklappe
Pset_DistributionFlowElementCommon - Reference: Zwischenflanschklappe 243412; sets with these values: 2
Andere - Typ: Zwischenflanschklappe 243412; Familie: Zwischenflanschklappe 243412; Familie und Typ: Zwischenflanschklappe 243412: Zwischenflanschklappe 243412; Typ-ID: 2532487
Abhängigkeiten - Höhe von Ebene: 0 m; Verschieben mit umliegenden Elementen: no
Bemaßungen - Fläche: 0.271849 m2; Volumen: 0.012674 m3
IFC-Parameter - In IFC-Datei exportieren: Nach Typ; Pset MEP.Geom-DN: 200; Pset MEP.Tech-Insulation thickness (mm): 100; Pset MEP.Tech-PN: 16; Pset MEP.Geom-Length (mm): 60; Pset MEP.Tech-Connection type (Inner thread=2, flange=3): 2; In IFC exportieren als: ifcflowcontroller; NameOverride: Zwischenflanschklappe; IfcPresentationLayer: 0-TFT-H_Vorlauf; ObjectTypeOverride: Zwischenflanschklappe; Pset MEP.Name: Zwischenflanschklappe; IfcDescription: Zwischenflanschklappe
Phasen - Phase erstellt: Phase 01

# IfcFlowController: Zwischenflanschklappe 245443:Zwischenflanschklappe 245443, Zwischenflanschklappe
In: 1. Obergeschoss
Type - Material: IfcSurfaceStyle #9317
Type - Andere - Kategorie: Allgemeines Modell; Familienname: Zwischenflanschklappe 245443
Type - ID-Daten - Typname: Zwischenflanschklappe 245443
Type - IFC-Parameter - Typ in IFC-Datei exportieren: Vorgabe
Description: Zwischenflanschklappe
Pset_DistributionFlowElementCommon - Reference: Zwischenflanschklappe 245443; sets with these values: 2
Andere - Typ: Zwischenflanschklappe 245443; Familie: Zwischenflanschklappe 245443; Familie und Typ: Zwischenflanschklappe 245443: Zwischenflanschklappe 245443; Typ-ID: 2532508
Abhängigkeiten - Höhe von Ebene: 0 m; Verschieben mit umliegenden Elementen: no
Bemaßungen - Fläche: 0.271849 m2; Volumen: 0.012674 m3
IFC-Parameter - In IFC-Datei exportieren: Nach Typ; Pset MEP.Geom-DN: 200; Pset MEP.Tech-Insulation thickness (mm): 100; Pset MEP.Tech-PN: 16; Pset MEP.Geom-Length (mm): 60; Pset MEP.Tech-Connection type (Inner thread=2, flange=3): 2; In IFC exportieren als: ifcflowcontroller; NameOverride: Zwischenflanschklappe; IfcPresentationLayer: 0-TFT-H_Vorlauf; ObjectTypeOverride: Zwischenflanschklappe; Pset MEP.Name: Zwischenflanschklappe; IfcDescription: Zwischenflanschklappe
Phasen - Phase erstellt: Phase 01

# IfcFlowController: Zwischenflanschklappe 245512:Zwischenflanschklappe 245512, Zwischenflanschklappe
In: 1. Obergeschoss
Type - Material: IfcSurfaceStyle #9317
Type - Andere - Kategorie: Allgemeines Modell; Familienname: Zwischenflanschklappe 245512
Type - ID-Daten - Typname: Zwischenflanschklappe 245512
Type - IFC-Parameter - Typ in IFC-Datei exportieren: Vorgabe
Description: Zwischenflanschklappe
Pset_DistributionFlowElementCommon - Reference: Zwischenflanschklappe 245512; sets with these values: 2
Andere - Typ: Zwischenflanschklappe 245512; Familie: Zwischenflanschklappe 245512; Familie und Typ: Zwischenflanschklappe 245512: Zwischenflanschklappe 245512; Typ-ID: 2532529
Abhängigkeiten - Höhe von Ebene: 0 m; Verschieben mit umliegenden Elementen: no
Bemaßungen - Fläche: 0.271849 m2; Volumen: 0.012674 m3
IFC-Parameter - In IFC-Datei exportieren: Nach Typ; Pset MEP.Geom-DN: 200; Pset MEP.Tech-Insulation thickness (mm): 100; Pset MEP.Tech-PN: 16; Pset MEP.Geom-Length (mm): 60; Pset MEP.Tech-Connection type (Inner thread=2, flange=3): 2; In IFC exportieren als: ifcflowcontroller; NameOverride: Zwischenflanschklappe; IfcPresentationLayer: 0-TFT-H_Vorlauf; ObjectTypeOverride: Zwischenflanschklappe; Pset MEP.Name: Zwischenflanschklappe; IfcDescription: Zwischenflanschklappe
Phasen - Phase erstellt: Phase 01

# IfcFlowController: Zwischenflanschklappe 247202:Zwischenflanschklappe 247202, Zwischenflanschklappe
In: 1. Obergeschoss
Type - Material: IfcSurfaceStyle #1741
Type - Andere - Kategorie: Allgemeines Modell; Familienname: Zwischenflanschklappe 247202
Type - ID-Daten - Typname: Zwischenflanschklappe 247202
Type - IFC-Parameter - Typ in IFC-Datei exportieren: Vorgabe
Description: Zwischenflanschklappe
Pset_DistributionFlowElementCommon - Reference: Zwischenflanschklappe 247202; sets with these values: 2
Andere - Typ: Zwischenflanschklappe 247202; Familie: Zwischenflanschklappe 247202; Familie und Typ: Zwischenflanschklappe 247202: Zwischenflanschklappe 247202; Typ-ID: 2532585
Abhängigkeiten - Höhe von Ebene: 0 m; Verschieben mit umliegenden Elementen: no
Bemaßungen - Fläche: 0.119603 m2; Volumen: 0.00586969 m3
IFC-Parameter - In IFC-Datei exportieren: Nach Typ; Pset MEP.Tech-Insulation thickness (mm): 100; Pset MEP.Tech-PN: 16; Pset MEP.Tech-Connection type (Inner thread=2, flange=3): 2; Pset MEP.Geom-DN: 100; Pset MEP.Geom-Length (mm): 52; In IFC exportieren als: ifcflowcontroller; NameOverride: Zwischenflanschklappe; IfcPresentationLayer: 0-TFT-H_Ruecklauf; ObjectTypeOverride: Zwischenflanschklappe; Pset MEP.Name: Zwischenflanschklappe; IfcDescription: Zwischenflanschklappe
Phasen - Phase erstellt: Phase 01

# IfcFlowController: Zwischenflanschklappe 247271:Zwischenflanschklappe 247271, Zwischenflanschklappe
In: 1. Obergeschoss
Type - Material: IfcSurfaceStyle #1741
Type - Andere - Kategorie: Allgemeines Modell; Familienname: Zwischenflanschklappe 247271
Type - ID-Daten - Typname: Zwischenflanschklappe 247271
Type - IFC-Parameter - Typ in IFC-Datei exportieren: Vorgabe
Description: Zwischenflanschklappe
Pset_DistributionFlowElementCommon - Reference: Zwischenflanschklappe 247271; sets with these values: 2
Andere - Typ: Zwischenflanschklappe 247271; Familie: Zwischenflanschklappe 247271; Familie und Typ: Zwischenflanschklappe 247271: Zwischenflanschklappe 247271; Typ-ID: 2532606
Abhängigkeiten - Höhe von Ebene: 0 m; Verschieben mit umliegenden Elementen: no
Bemaßungen - Fläche: 0.271849 m2; Volumen: 0.012674 m3
IFC-Parameter - In IFC-Datei exportieren: Nach Typ; Pset MEP.Geom-DN: 200; Pset MEP.Tech-Insulation thickness (mm): 100; Pset MEP.Tech-PN: 16; Pset MEP.Geom-Length (mm): 60; Pset MEP.Tech-Connection type (Inner thread=2, flange=3): 2; In IFC exportieren als: ifcflowcontroller; NameOverride: Zwischenflanschklappe; IfcPresentationLayer: 0-TFT-H_Ruecklauf; ObjectTypeOverride: Zwischenflanschklappe; Pset MEP.Name: Zwischenflanschklappe; IfcDescription: Zwischenflanschklappe
Phasen - Phase erstellt: Phase 01

# IfcFlowController: Zwischenflanschklappe 247340:Zwischenflanschklappe 247340, Zwischenflanschklappe
In: 1. Obergeschoss
Type - Material: IfcSurfaceStyle #1741
Type - Andere - Kategorie: Allgemeines Modell; Familienname: Zwischenflanschklappe 247340
Type - ID-Daten - Typname: Zwischenflanschklappe 247340
Type - IFC-Parameter - Typ in IFC-Datei exportieren: Vorgabe
Description: Zwischenflanschklappe
Pset_DistributionFlowElementCommon - Reference: Zwischenflanschklappe 247340; sets with these values: 2
Andere - Typ: Zwischenflanschklappe 247340; Familie: Zwischenflanschklappe 247340; Familie und Typ: Zwischenflanschklappe 247340: Zwischenflanschklappe 247340; Typ-ID: 2532627
Abhängigkeiten - Höhe von Ebene: 0 m; Verschieben mit umliegenden Elementen: no
Bemaßungen - Fläche: 0.271849 m2; Volumen: 0.012674 m3
IFC-Parameter - In IFC-Datei exportieren: Nach Typ; Pset MEP.Geom-DN: 200; Pset MEP.Tech-Insulation thickness (mm): 100; Pset MEP.Tech-PN: 16; Pset MEP.Geom-Length (mm): 60; Pset MEP.Tech-Connection type (Inner thread=2, flange=3): 2; In IFC exportieren als: ifcflowcontroller; NameOverride: Zwischenflanschklappe; IfcPresentationLayer: 0-TFT-H_Ruecklauf; ObjectTypeOverride: Zwischenflanschklappe; Pset MEP.Name: Zwischenflanschklappe; IfcDescription: Zwischenflanschklappe
Phasen - Phase erstellt: Phase 01

# IfcFlowController: Zwischenflanschklappe 247409:Zwischenflanschklappe 247409, Zwischenflanschklappe
In: 1. Obergeschoss
Type - Material: IfcSurfaceStyle #1741
Type - Andere - Kategorie: Allgemeines Modell; Familienname: Zwischenflanschklappe 247409
Type - ID-Daten - Typname: Zwischenflanschklappe 247409
Type - IFC-Parameter - Typ in IFC-Datei exportieren: Vorgabe
Description: Zwischenflanschklappe
Pset_DistributionFlowElementCommon - Reference: Zwischenflanschklappe 247409; sets with these values: 2
Andere - Typ: Zwischenflanschklappe 247409; Familie: Zwischenflanschklappe 247409; Familie und Typ: Zwischenflanschklappe 247409: Zwischenflanschklappe 247409; Typ-ID: 2532648
Abhängigkeiten - Höhe von Ebene: 0 m; Verschieben mit umliegenden Elementen: no
Bemaßungen - Fläche: 0.271849 m2; Volumen: 0.012674 m3
IFC-Parameter - In IFC-Datei exportieren: Nach Typ; Pset MEP.Geom-DN: 200; Pset MEP.Tech-Insulation thickness (mm): 100; Pset MEP.Tech-PN: 16; Pset MEP.Geom-Length (mm): 60; Pset MEP.Tech-Connection type (Inner thread=2, flange=3): 2; In IFC exportieren als: ifcflowcontroller; NameOverride: Zwischenflanschklappe; IfcPresentationLayer: 0-TFT-H_Ruecklauf; ObjectTypeOverride: Zwischenflanschklappe; Pset MEP.Name: Zwischenflanschklappe; IfcDescription: Zwischenflanschklappe
Phasen - Phase erstellt: Phase 01

# IfcFlowController: Zwischenflanschklappe 253202:Zwischenflanschklappe 253202, Zwischenflanschklappe
In: 1. Obergeschoss
Type - Material: IfcSurfaceStyle #1741
Type - Andere - Kategorie: Allgemeines Modell; Familienname: Zwischenflanschklappe 253202
Type - ID-Daten - Typname: Zwischenflanschklappe 253202
Type - IFC-Parameter - Typ in IFC-Datei exportieren: Vorgabe
Description: Zwischenflanschklappe
Pset_DistributionFlowElementCommon - Reference: Zwischenflanschklappe 253202; sets with these values: 2
Andere - Typ: Zwischenflanschklappe 253202; Familie: Zwischenflanschklappe 253202; Familie und Typ: Zwischenflanschklappe 253202: Zwischenflanschklappe 253202; Typ-ID: 2532932
Abhängigkeiten - Höhe von Ebene: 0 m; Verschieben mit umliegenden Elementen: no
Bemaßungen - Fläche: 0.221213 m2; Volumen: 0.00369805 m3
IFC-Parameter - In IFC-Datei exportieren: Nach Typ; Pset MEP.Geom-DN: 200; Pset MEP.Tech-Insulation thickness (mm): 100; Pset MEP.Tech-PN: 16; Pset MEP.Geom-Length (mm): 60; Pset MEP.Tech-Connection type (Inner thread=2, flange=3): 2; In IFC exportieren als: ifcflowcontroller; NameOverride: Zwischenflanschklappe; IfcPresentationLayer: 0-TFT-H_Ruecklauf; ObjectTypeOverride: Zwischenflanschklappe; Pset MEP.Name: Zwischenflanschklappe; IfcDescription: Zwischenflanschklappe
Phasen - Phase erstellt: Phase 01

# IfcFlowController: Zwischenflanschklappe 260081:Zwischenflanschklappe 260081, Zwischenflanschklappe
In: 1. Obergeschoss
Type - Material: IfcSurfaceStyle #1741
Type - Andere - Kategorie: Allgemeines Modell; Familienname: Zwischenflanschklappe 260081
Type - ID-Daten - Typname: Zwischenflanschklappe 260081
Type - IFC-Parameter - Typ in IFC-Datei exportieren: Vorgabe
Description: Zwischenflanschklappe
Pset_DistributionFlowElementCommon - Reference: Zwischenflanschklappe 260081; sets with these values: 2
Andere - Typ: Zwischenflanschklappe 260081; Familie: Zwischenflanschklappe 260081; Familie und Typ: Zwischenflanschklappe 260081: Zwischenflanschklappe 260081; Typ-ID: 2533079
Abhängigkeiten - Höhe von Ebene: 0 m; Verschieben mit umliegenden Elementen: no
Bemaßungen - Fläche: 0.0806654 m2; Volumen: 0.00412498 m3
IFC-Parameter - In IFC-Datei exportieren: Nach Typ; Pset MEP.Tech-Insulation thickness (mm): 100; Pset MEP.Tech-PN: 16; Pset MEP.Tech-Connection type (Inner thread=2, flange=3): 2; Pset MEP.Geom-Length (mm): 46; Pset MEP.Geom-DN: 65; In IFC exportieren als: ifcflowcontroller; NameOverride: Zwischenflanschklappe; IfcPresentationLayer: 0-TFT-H_Ruecklauf; ObjectTypeOverride: Zwischenflanschklappe; Pset MEP.Name: Zwischenflanschklappe; IfcDescription: Zwischenflanschklappe
Phasen - Phase erstellt: Phase 01

# IfcFlowController: Zwischenflanschklappe 262704:Zwischenflanschklappe 262704, Zwischenflanschklappe
In: 1. Obergeschoss
Type - Material: IfcSurfaceStyle #9317
Type - Andere - Kategorie: Allgemeines Modell; Familienname: Zwischenflanschklappe 262704
Type - ID-Daten - Typname: Zwischenflanschklappe 262704
Type - IFC-Parameter - Typ in IFC-Datei exportieren: Vorgabe
Description: Zwischenflanschklappe
Pset_DistributionFlowElementCommon - Reference: Zwischenflanschklappe 262704; sets with these values: 2
Andere - Typ: Zwischenflanschklappe 262704; Familie: Zwischenflanschklappe 262704; Familie und Typ: Zwischenflanschklappe 262704: Zwischenflanschklappe 262704; Typ-ID: 2533121
Abhängigkeiten - Höhe von Ebene: 0 m; Verschieben mit umliegenden Elementen: no
Bemaßungen - Fläche: 0.271849 m2; Volumen: 0.012674 m3
IFC-Parameter - In IFC-Datei exportieren: Nach Typ; Pset MEP.Geom-DN: 200; Pset MEP.Tech-Insulation thickness (mm): 100; Pset MEP.Tech-PN: 16; Pset MEP.Geom-Length (mm): 60; Pset MEP.Tech-Connection type (Inner thread=2, flange=3): 2; In IFC exportieren als: ifcflowcontroller; NameOverride: Zwischenflanschklappe; IfcPresentationLayer: 0-TFT-H_Vorlauf; ObjectTypeOverride: Zwischenflanschklappe; Pset MEP.Name: Zwischenflanschklappe; IfcDescription: Zwischenflanschklappe
Phasen - Phase erstellt: Phase 01

# IfcFlowController: Zwischenflanschklappe 301597:Zwischenflanschklappe 301597, Zwischenflanschklappe
In: 1. Obergeschoss
Type - Material: IfcSurfaceStyle #9317
Type - Andere - Kategorie: Allgemeines Modell; Familienname: Zwischenflanschklappe 301597
Type - ID-Daten - Typname: Zwischenflanschklappe 301597
Type - IFC-Parameter - Typ in IFC-Datei exportieren: Vorgabe
Description: Zwischenflanschklappe
Pset_DistributionFlowElementCommon - Reference: Zwischenflanschklappe 301597; sets with these values: 2
Andere - Typ: Zwischenflanschklappe 301597; Familie: Zwischenflanschklappe 301597; Familie und Typ: Zwischenflanschklappe 301597: Zwischenflanschklappe 301597; Typ-ID: 2534804
Abhängigkeiten - Höhe von Ebene: 0 m; Verschieben mit umliegenden Elementen: no
Bemaßungen - Fläche: 0.271849 m2; Volumen: 0.0124191 m3
IFC-Parameter - In IFC-Datei exportieren: Nach Typ; Pset MEP.Geom-DN: 200; Pset MEP.Tech-Insulation thickness (mm): 100; Pset MEP.Tech-PN: 16; Pset MEP.Geom-Length (mm): 60; Pset MEP.Tech-Connection type (Inner thread=2, flange=3): 2; In IFC exportieren als: ifcflowcontroller; NameOverride: Zwischenflanschklappe; IfcPresentationLayer: 0-TFT-H_Vorlauf; ObjectTypeOverride: Zwischenflanschklappe; Pset MEP.Name: Zwischenflanschklappe; IfcDescription: Zwischenflanschklappe
Phasen - Phase erstellt: Phase 01

# IfcFlowController: Zwischenflanschklappe 315135:Zwischenflanschklappe 315135, Zwischenflanschklappe
In: 1. Obergeschoss
Type - Material: IfcSurfaceStyle #1741
Type - Andere - Kategorie: Allgemeines Modell; Familienname: Zwischenflanschklappe 315135
Type - ID-Daten - Typname: Zwischenflanschklappe 315135
Type - IFC-Parameter - Typ in IFC-Datei exportieren: Vorgabe
Description: Zwischenflanschklappe
Pset_DistributionFlowElementCommon - Reference: Zwischenflanschklappe 315135; sets with these values: 2
Andere - Typ: Zwischenflanschklappe 315135; Familie: Zwischenflanschklappe 315135; Familie und Typ: Zwischenflanschklappe 315135: Zwischenflanschklappe 315135; Typ-ID: 2535194
Abhängigkeiten - Höhe von Ebene: 0 m; Verschieben mit umliegenden Elementen: no
Bemaßungen - Fläche: 0.148468 m2; Volumen: 0.0021425 m3
IFC-Parameter - In IFC-Datei exportieren: Nach Typ; Pset MEP.Tech-Insulation thickness (mm): 100; Pset MEP.Tech-PN: 16; Pset MEP.Tech-Connection type (Inner thread=2, flange=3): 2; Pset MEP.Geom-DN: 150; Pset MEP.Geom-Length (mm): 56; In IFC exportieren als: ifcflowcontroller; NameOverride: Zwischenflanschklappe; IfcPresentationLayer: 0-TFT-H_Ruecklauf; ObjectTypeOverride: Zwischenflanschklappe; Pset MEP.Name: Zwischenflanschklappe; IfcDescription: Zwischenflanschklappe
Phasen - Phase erstellt: Phase 01

# IfcFlowController: Zwischenflanschklappe 320400:Zwischenflanschklappe 320400, Zwischenflanschklappe
In: 1. Obergeschoss
Type - Material: IfcSurfaceStyle #1741
Type - Andere - Kategorie: Allgemeines Modell; Familienname: Zwischenflanschklappe 320400
Type - ID-Daten - Typname: Zwischenflanschklappe 320400
Type - IFC-Parameter - Typ in IFC-Datei exportieren: Vorgabe
Description: Zwischenflanschklappe
Pset_DistributionFlowElementCommon - Reference: Zwischenflanschklappe 320400; sets with these values: 2
Andere - Typ: Zwischenflanschklappe 320400; Familie: Zwischenflanschklappe 320400; Familie und Typ: Zwischenflanschklappe 320400: Zwischenflanschklappe 320400; Typ-ID: 2535516
Abhängigkeiten - Höhe von Ebene: 0 m; Verschieben mit umliegenden Elementen: no
Bemaßungen - Fläche: 0.190915 m2; Volumen: 0.00890044 m3
IFC-Parameter - In IFC-Datei exportieren: Nach Typ; Pset MEP.Tech-Insulation thickness (mm): 100; Pset MEP.Tech-PN: 16; Pset MEP.Tech-Connection type (Inner thread=2, flange=3): 2; Pset MEP.Geom-DN: 150; Pset MEP.Geom-Length (mm): 56; In IFC exportieren als: ifcflowcontroller; NameOverride: Zwischenflanschklappe; IfcPresentationLayer: 0-TFT-H_Ruecklauf; ObjectTypeOverride: Zwischenflanschklappe; Pset MEP.Name: Zwischenflanschklappe; IfcDescription: Zwischenflanschklappe
Phasen - Phase erstellt: Phase 01

# IfcFlowController: Zwischenflanschklappe 336372:Zwischenflanschklappe 336372, Zwischenflanschklappe
In: Erdgeschoss
Type - Material: IfcSurfaceStyle #1741
Type - Andere - Kategorie: Allgemeines Modell; Familienname: Zwischenflanschklappe 336372
Type - ID-Daten - Typname: Zwischenflanschklappe 336372
Type - IFC-Parameter - Typ in IFC-Datei exportieren: Vorgabe
Description: Zwischenflanschklappe
Pset_DistributionFlowElementCommon - Reference: Zwischenflanschklappe 336372; sets with these values: 2
Andere - Typ: Zwischenflanschklappe 336372; Familie: Zwischenflanschklappe 336372; Familie und Typ: Zwischenflanschklappe 336372: Zwischenflanschklappe 336372; Typ-ID: 2535845
Abhängigkeiten - Höhe von Ebene: 0 m; Verschieben mit umliegenden Elementen: no
Bemaßungen - Fläche: 0.0806654 m2; Volumen: 0.00411192 m3
IFC-Parameter - In IFC-Datei exportieren: Nach Typ; Pset MEP.Tech-Insulation thickness (mm): 100; Pset MEP.Tech-PN: 16; Pset MEP.Tech-Connection type (Inner thread=2, flange=3): 2; Pset MEP.Geom-Length (mm): 46; Pset MEP.Geom-DN: 65; In IFC exportieren als: ifcflowcontroller; NameOverride: Zwischenflanschklappe; IfcPresentationLayer: 0-TFT-H_Ruecklauf; ObjectTypeOverride: Zwischenflanschklappe; Pset MEP.Name: Zwischenflanschklappe; IfcDescription: Zwischenflanschklappe
Phasen - Phase erstellt: Phase 01

# IfcFlowController: Zwischenflanschklappe 338066:Zwischenflanschklappe 338066, Zwischenflanschklappe
In: Erdgeschoss
Type - Material: IfcSurfaceStyle #9317
Type - Andere - Kategorie: Allgemeines Modell; Familienname: Zwischenflanschklappe 338066
Type - ID-Daten - Typname: Zwischenflanschklappe 338066
Type - IFC-Parameter - Typ in IFC-Datei exportieren: Vorgabe
Description: Zwischenflanschklappe
Pset_DistributionFlowElementCommon - Reference: Zwischenflanschklappe 338066; sets with these values: 2
Andere - Typ: Zwischenflanschklappe 338066; Familie: Zwischenflanschklappe 338066; Familie und Typ: Zwischenflanschklappe 338066: Zwischenflanschklappe 338066; Typ-ID: 2535852
Abhängigkeiten - Höhe von Ebene: 0 m; Verschieben mit umliegenden Elementen: no
Bemaßungen - Fläche: 0.0927054 m2; Volumen: 0.00452555 m3
IFC-Parameter - In IFC-Datei exportieren: Nach Typ; Pset MEP.Tech-Insulation thickness (mm): 100; Pset MEP.Tech-PN: 16; Pset MEP.Tech-Connection type (Inner thread=2, flange=3): 2; Pset MEP.Geom-DN: 80; Pset MEP.Geom-Length (mm): 46; In IFC exportieren als: ifcflowcontroller; NameOverride: Zwischenflanschklappe; IfcPresentationLayer: 0-TFT-H_Vorlauf; ObjectTypeOverride: Zwischenflanschklappe; Pset MEP.Name: Zwischenflanschklappe; IfcDescription: Zwischenflanschklappe
Phasen - Phase erstellt: Phase 01

# IfcFlowController: Zwischenflanschklappe 342931:Zwischenflanschklappe 342931, Zwischenflanschklappe
In: Erdgeschoss
Type - Material: IfcSurfaceStyle #9317
Type - Andere - Kategorie: Allgemeines Modell; Familienname: Zwischenflanschklappe 342931
Type - ID-Daten - Typname: Zwischenflanschklappe 342931
Type - IFC-Parameter - Typ in IFC-Datei exportieren: Vorgabe
Description: Zwischenflanschklappe
Pset_DistributionFlowElementCommon - Reference: Zwischenflanschklappe 342931; sets with these values: 2
Andere - Typ: Zwischenflanschklappe 342931; Familie: Zwischenflanschklappe 342931; Familie und Typ: Zwischenflanschklappe 342931: Zwischenflanschklappe 342931; Typ-ID: 2536167
Abhängigkeiten - Höhe von Ebene: 0 m; Verschieben mit umliegenden Elementen: no
Bemaßungen - Fläche: 0.190915 m2; Volumen: 0.00890044 m3
IFC-Parameter - In IFC-Datei exportieren: Nach Typ; Pset MEP.Tech-Insulation thickness (mm): 100; Pset MEP.Tech-PN: 16; Pset MEP.Tech-Connection type (Inner thread=2, flange=3): 2; Pset MEP.Geom-DN: 150; Pset MEP.Geom-Length (mm): 56; In IFC exportieren als: ifcflowcontroller; NameOverride: Zwischenflanschklappe; IfcPresentationLayer: 0-TFT-H_Vorlauf; ObjectTypeOverride: Zwischenflanschklappe; Pset MEP.Name: Zwischenflanschklappe; IfcDescription: Zwischenflanschklappe
Phasen - Phase erstellt: Phase 01

# IfcFlowController: Zwischenflanschklappe 343081:Zwischenflanschklappe 343081, Zwischenflanschklappe
In: Erdgeschoss
Type - Material: IfcSurfaceStyle #9317
Type - Andere - Kategorie: Allgemeines Modell; Familienname: Zwischenflanschklappe 343081
Type - ID-Daten - Typname: Zwischenflanschklappe 343081
Type - IFC-Parameter - Typ in IFC-Datei exportieren: Vorgabe
Description: Zwischenflanschklappe
Pset_DistributionFlowElementCommon - Reference: Zwischenflanschklappe 343081; sets with these values: 2
Andere - Typ: Zwischenflanschklappe 343081; Familie: Zwischenflanschklappe 343081; Familie und Typ: Zwischenflanschklappe 343081: Zwischenflanschklappe 343081; Typ-ID: 2536209
Abhängigkeiten - Höhe von Ebene: 0 m; Verschieben mit umliegenden Elementen: no
Bemaßungen - Fläche: 0.190915 m2; Volumen: 0.00902063 m3
IFC-Parameter - In IFC-Datei exportieren: Nach Typ; Pset MEP.Tech-Insulation thickness (mm): 100; Pset MEP.Tech-PN: 16; Pset MEP.Tech-Connection type (Inner thread=2, flange=3): 2; Pset MEP.Geom-DN: 150; Pset MEP.Geom-Length (mm): 56; In IFC exportieren als: ifcflowcontroller; NameOverride: Zwischenflanschklappe; IfcPresentationLayer: 0-TFT-H_Vorlauf; ObjectTypeOverride: Zwischenflanschklappe; Pset MEP.Name: Zwischenflanschklappe; IfcDescription: Zwischenflanschklappe
Phasen - Phase erstellt: Phase 01

# IfcFlowController: Zwischenflanschklappe 343385:Zwischenflanschklappe 343385, Zwischenflanschklappe
In: Erdgeschoss
Type - Material: IfcSurfaceStyle #9317
Type - Andere - Kategorie: Allgemeines Modell; Familienname: Zwischenflanschklappe 343385
Type - ID-Daten - Typname: Zwischenflanschklappe 343385
Type - IFC-Parameter - Typ in IFC-Datei exportieren: Vorgabe
Description: Zwischenflanschklappe
Pset_DistributionFlowElementCommon - Reference: Zwischenflanschklappe 343385; sets with these values: 2
Andere - Typ: Zwischenflanschklappe 343385; Familie: Zwischenflanschklappe 343385; Familie und Typ: Zwischenflanschklappe 343385: Zwischenflanschklappe 343385; Typ-ID: 2536223
Abhängigkeiten - Höhe von Ebene: 0 m; Verschieben mit umliegenden Elementen: no
Bemaßungen - Fläche: 0.190915 m2; Volumen: 0.00902063 m3
IFC-Parameter - In IFC-Datei exportieren: Nach Typ; Pset MEP.Tech-Insulation thickness (mm): 100; Pset MEP.Tech-PN: 16; Pset MEP.Tech-Connection type (Inner thread=2, flange=3): 2; Pset MEP.Geom-DN: 150; Pset MEP.Geom-Length (mm): 56; In IFC exportieren als: ifcflowcontroller; NameOverride: Zwischenflanschklappe; IfcPresentationLayer: 0-TFT-H_Vorlauf; ObjectTypeOverride: Zwischenflanschklappe; Pset MEP.Name: Zwischenflanschklappe; IfcDescription: Zwischenflanschklappe
Phasen - Phase erstellt: Phase 01

# IfcFlowController: Zwischenflanschklappe 350180:Zwischenflanschklappe 350180, Zwischenflanschklappe
In: Erdgeschoss
Type - Material: IfcSurfaceStyle #1741
Type - Andere - Kategorie: Allgemeines Modell; Familienname: Zwischenflanschklappe 350180
Type - ID-Daten - Typname: Zwischenflanschklappe 350180
Type - IFC-Parameter - Typ in IFC-Datei exportieren: Vorgabe
Description: Zwischenflanschklappe
Pset_DistributionFlowElementCommon - Reference: Zwischenflanschklappe 350180; sets with these values: 2
Andere - Typ: Zwischenflanschklappe 350180; Familie: Zwischenflanschklappe 350180; Familie und Typ: Zwischenflanschklappe 350180: Zwischenflanschklappe 350180; Typ-ID: 2536489
Abhängigkeiten - Höhe von Ebene: 0 m; Verschieben mit umliegenden Elementen: no
Bemaßungen - Fläche: 0.271849 m2; Volumen: 0.012674 m3
IFC-Parameter - In IFC-Datei exportieren: Nach Typ; Pset MEP.Geom-DN: 200; Pset MEP.Tech-Insulation thickness (mm): 100; Pset MEP.Tech-PN: 16; Pset MEP.Geom-Length (mm): 60; Pset MEP.Tech-Connection type (Inner thread=2, flange=3): 2; In IFC exportieren als: ifcflowcontroller; NameOverride: Zwischenflanschklappe; IfcPresentationLayer: 0-TFT-H_Ruecklauf; ObjectTypeOverride: Zwischenflanschklappe; Pset MEP.Name: Zwischenflanschklappe; IfcDescription: Zwischenflanschklappe
Phasen - Phase erstellt: Phase 01

# IfcFlowController: Zwischenflanschklappe 351404:Zwischenflanschklappe 351404, Zwischenflanschklappe
In: Erdgeschoss
Type - Material: IfcSurfaceStyle #9317
Type - Andere - Kategorie: Allgemeines Modell; Familienname: Zwischenflanschklappe 351404
Type - ID-Daten - Typname: Zwischenflanschklappe 351404
Type - IFC-Parameter - Typ in IFC-Datei exportieren: Vorgabe
Description: Zwischenflanschklappe
Pset_DistributionFlowElementCommon - Reference: Zwischenflanschklappe 351404; sets with these values: 2
Andere - Typ: Zwischenflanschklappe 351404; Familie: Zwischenflanschklappe 351404; Familie und Typ: Zwischenflanschklappe 351404: Zwischenflanschklappe 351404; Typ-ID: 2536573
Abhängigkeiten - Höhe von Ebene: 0 m; Verschieben mit umliegenden Elementen: no
Bemaßungen - Fläche: 0.119603 m2; Volumen: 0.00586969 m3
IFC-Parameter - In IFC-Datei exportieren: Nach Typ; Pset MEP.Tech-Insulation thickness (mm): 100; Pset MEP.Tech-PN: 16; Pset MEP.Tech-Connection type (Inner thread=2, flange=3): 2; Pset MEP.Geom-DN: 100; Pset MEP.Geom-Length (mm): 52; In IFC exportieren als: ifcflowcontroller; NameOverride: Zwischenflanschklappe; IfcPresentationLayer: 0-TFT-H_Vorlauf; ObjectTypeOverride: Zwischenflanschklappe; Pset MEP.Name: Zwischenflanschklappe; IfcDescription: Zwischenflanschklappe
Phasen - Phase erstellt: Phase 01

# IfcFlowController: Zwischenflanschklappe 351737:Zwischenflanschklappe 351737, Zwischenflanschklappe
In: Erdgeschoss
Type - Material: IfcSurfaceStyle #1741
Type - Andere - Kategorie: Allgemeines Modell; Familienname: Zwischenflanschklappe 351737
Type - ID-Daten - Typname: Zwischenflanschklappe 351737
Type - IFC-Parameter - Typ in IFC-Datei exportieren: Vorgabe
Description: Zwischenflanschklappe
Pset_DistributionFlowElementCommon - Reference: Zwischenflanschklappe 351737; sets with these values: 2
Andere - Typ: Zwischenflanschklappe 351737; Familie: Zwischenflanschklappe 351737; Familie und Typ: Zwischenflanschklappe 351737: Zwischenflanschklappe 351737; Typ-ID: 2536594
Abhängigkeiten - Höhe von Ebene: 0 m; Verschieben mit umliegenden Elementen: no
Bemaßungen - Fläche: 0.119603 m2; Volumen: 0.00586969 m3
IFC-Parameter - In IFC-Datei exportieren: Nach Typ; Pset MEP.Tech-Insulation thickness (mm): 100; Pset MEP.Tech-PN: 16; Pset MEP.Tech-Connection type (Inner thread=2, flange=3): 2; Pset MEP.Geom-DN: 100; Pset MEP.Geom-Length (mm): 52; In IFC exportieren als: ifcflowcontroller; NameOverride: Zwischenflanschklappe; IfcPresentationLayer: 0-TFT-H_Ruecklauf; ObjectTypeOverride: Zwischenflanschklappe; Pset MEP.Name: Zwischenflanschklappe; IfcDescription: Zwischenflanschklappe
Phasen - Phase erstellt: Phase 01

# IfcFlowController: Zwischenflanschklappe 5613:Zwischenflanschklappe 5613, Zwischenflanschklappe
In: 1. Obergeschoss
Type - Material: IfcSurfaceStyle #1741
Type - Andere - Kategorie: Allgemeines Modell; Familienname: Zwischenflanschklappe 5613
Type - ID-Daten - Typname: Zwischenflanschklappe 5613
Type - IFC-Parameter - Typ in IFC-Datei exportieren: Vorgabe
Description: Zwischenflanschklappe
Pset_DistributionFlowElementCommon - Reference: Zwischenflanschklappe 5613; sets with these values: 2
Andere - Typ: Zwischenflanschklappe 5613; Familie: Zwischenflanschklappe 5613; Familie und Typ: Zwischenflanschklappe 5613: Zwischenflanschklappe 5613; Typ-ID: 2531387
Abhängigkeiten - Höhe von Ebene: 0 m; Verschieben mit umliegenden Elementen: no
Bemaßungen - Fläche: 0.261208 m2; Volumen: 0.012589 m3
IFC-Parameter - In IFC-Datei exportieren: Nach Typ; Pset MEP.Geom-DN: 200; Pset MEP.Tech-Insulation thickness (mm): 100; Pset MEP.Tech-PN: 16; Pset MEP.Geom-Length (mm): 60; Pset MEP.Tech-Connection type (Inner thread=2, flange=3): 2; In IFC exportieren als: ifcflowcontroller; NameOverride: Zwischenflanschklappe; IfcPresentationLayer: 0-TFT-H_Ruecklauf; ObjectTypeOverride: Zwischenflanschklappe; Pset MEP.Name: Zwischenflanschklappe; IfcDescription: Zwischenflanschklappe
Phasen - Phase erstellt: Phase 01

# IfcFlowController: Zwischenflanschklappe 5636:Zwischenflanschklappe 5636, Zwischenflanschklappe
In: 1. Obergeschoss
Type - Material: IfcSurfaceStyle #1741
Type - Andere - Kategorie: Allgemeines Modell; Familienname: Zwischenflanschklappe 5636
Type - ID-Daten - Typname: Zwischenflanschklappe 5636
Type - IFC-Parameter - Typ in IFC-Datei exportieren: Vorgabe
Description: Zwischenflanschklappe
Pset_DistributionFlowElementCommon - Reference: Zwischenflanschklappe 5636; sets with these values: 2
Andere - Typ: Zwischenflanschklappe 5636; Familie: Zwischenflanschklappe 5636; Familie und Typ: Zwischenflanschklappe 5636: Zwischenflanschklappe 5636; Typ-ID: 2531394
Abhängigkeiten - Höhe von Ebene: 0 m; Verschieben mit umliegenden Elementen: no
Bemaßungen - Fläche: 0.261208 m2; Volumen: 0.012589 m3
IFC-Parameter - In IFC-Datei exportieren: Nach Typ; Pset MEP.Geom-DN: 200; Pset MEP.Tech-Insulation thickness (mm): 100; Pset MEP.Tech-PN: 16; Pset MEP.Geom-Length (mm): 60; Pset MEP.Tech-Connection type (Inner thread=2, flange=3): 2; In IFC exportieren als: ifcflowcontroller; NameOverride: Zwischenflanschklappe; IfcPresentationLayer: 0-TFT-H_Ruecklauf; ObjectTypeOverride: Zwischenflanschklappe; Pset MEP.Name: Zwischenflanschklappe; IfcDescription: Zwischenflanschklappe
Phasen - Phase erstellt: Phase 01

# IfcFlowController: Zwischenflanschklappe 613281:Zwischenflanschklappe 613281, Zwischenflanschklappe
In: 1. Obergeschoss
Type - Material: IfcSurfaceStyle #9317
Type - Andere - Kategorie: Allgemeines Modell; Familienname: Zwischenflanschklappe 613281
Type - ID-Daten - Typname: Zwischenflanschklappe 613281
Type - IFC-Parameter - Typ in IFC-Datei exportieren: Vorgabe
Description: Zwischenflanschklappe
Pset_DistributionFlowElementCommon - Reference: Zwischenflanschklappe 613281; sets with these values: 2
Andere - Typ: Zwischenflanschklappe 613281; Familie: Zwischenflanschklappe 613281; Familie und Typ: Zwischenflanschklappe 613281: Zwischenflanschklappe 613281; Typ-ID: 2537633
Abhängigkeiten - Höhe von Ebene: 0 m; Verschieben mit umliegenden Elementen: no
Bemaßungen - Fläche: 0.271849 m2; Volumen: 0.012674 m3
IFC-Parameter - In IFC-Datei exportieren: Nach Typ; Pset MEP.Geom-DN: 200; Pset MEP.Tech-Insulation thickness (mm): 100; Pset MEP.Tech-PN: 16; Pset MEP.Geom-Length (mm): 60; Pset MEP.Tech-Connection type (Inner thread=2, flange=3): 2; In IFC exportieren als: ifcflowcontroller; NameOverride: Zwischenflanschklappe; IfcPresentationLayer: 0-TFT-H_Vorlauf; ObjectTypeOverride: Zwischenflanschklappe; Pset MEP.Name: Zwischenflanschklappe; IfcDescription: Zwischenflanschklappe
Phasen - Phase erstellt: Phase 01

# IfcFlowController: Zwischenflanschklappe 614474:Zwischenflanschklappe 614474, Zwischenflanschklappe
In: 1. Obergeschoss
Type - Material: IfcSurfaceStyle #1741
Type - Andere - Kategorie: Allgemeines Modell; Familienname: Zwischenflanschklappe 614474
Type - ID-Daten - Typname: Zwischenflanschklappe 614474
Type - IFC-Parameter - Typ in IFC-Datei exportieren: Vorgabe
Description: Zwischenflanschklappe
Pset_DistributionFlowElementCommon - Reference: Zwischenflanschklappe 614474; sets with these values: 2
Andere - Typ: Zwischenflanschklappe 614474; Familie: Zwischenflanschklappe 614474; Familie und Typ: Zwischenflanschklappe 614474: Zwischenflanschklappe 614474; Typ-ID: 2537724
Abhängigkeiten - Höhe von Ebene: 0 m; Verschieben mit umliegenden Elementen: no
Bemaßungen - Fläche: 0.190915 m2; Volumen: 0.00890044 m3
IFC-Parameter - In IFC-Datei exportieren: Nach Typ; Pset MEP.Tech-Insulation thickness (mm): 100; Pset MEP.Tech-PN: 16; Pset MEP.Tech-Connection type (Inner thread=2, flange=3): 2; Pset MEP.Geom-DN: 150; Pset MEP.Geom-Length (mm): 56; In IFC exportieren als: ifcflowcontroller; NameOverride: Zwischenflanschklappe; IfcPresentationLayer: 0-TFT-H_Ruecklauf; ObjectTypeOverride: Zwischenflanschklappe; Pset MEP.Name: Zwischenflanschklappe; IfcDescription: Zwischenflanschklappe
Phasen - Phase erstellt: Phase 01

# IfcFlowController: Zwischenflanschklappe 623319:Zwischenflanschklappe 623319, Zwischenflanschklappe
In: 1. Obergeschoss
Type - Material: IfcSurfaceStyle #1741
Type - Andere - Kategorie: Allgemeines Modell; Familienname: Zwischenflanschklappe 623319
Type - ID-Daten - Typname: Zwischenflanschklappe 623319
Type - IFC-Parameter - Typ in IFC-Datei exportieren: Vorgabe
Description: Zwischenflanschklappe
Pset_DistributionFlowElementCommon - Reference: Zwischenflanschklappe 623319; sets with these values: 2
Andere - Typ: Zwischenflanschklappe 623319; Familie: Zwischenflanschklappe 623319; Familie und Typ: Zwischenflanschklappe 623319: Zwischenflanschklappe 623319; Typ-ID: 2538245
Abhängigkeiten - Höhe von Ebene: 0 m; Verschieben mit umliegenden Elementen: no
Bemaßungen - Fläche: 0.190915 m2; Volumen: 0.00902063 m3
IFC-Parameter - In IFC-Datei exportieren: Nach Typ; Pset MEP.Tech-Insulation thickness (mm): 100; Pset MEP.Tech-PN: 16; Pset MEP.Tech-Connection type (Inner thread=2, flange=3): 2; Pset MEP.Geom-DN: 150; Pset MEP.Geom-Length (mm): 56; In IFC exportieren als: ifcflowcontroller; NameOverride: Zwischenflanschklappe; IfcPresentationLayer: 0-TFT-H_Ruecklauf; ObjectTypeOverride: Zwischenflanschklappe; Pset MEP.Name: Zwischenflanschklappe; IfcDescription: Zwischenflanschklappe
Phasen - Phase erstellt: Phase 01

# IfcFlowController: Zwischenflanschklappe 860856:Zwischenflanschklappe 860856, Zwischenflanschklappe
In: 1. Untergeschoss
Type - Material: IfcSurfaceStyle #9317
Type - Andere - Kategorie: Allgemeines Modell; Familienname: Zwischenflanschklappe 860856
Type - ID-Daten - Typname: Zwischenflanschklappe 860856
Type - IFC-Parameter - Typ in IFC-Datei exportieren: Vorgabe
Description: Zwischenflanschklappe
Pset_DistributionFlowElementCommon - Reference: Zwischenflanschklappe 860856; sets with these values: 2
Andere - Typ: Zwischenflanschklappe 860856; Familie: Zwischenflanschklappe 860856; Familie und Typ: Zwischenflanschklappe 860856: Zwischenflanschklappe 860856; Typ-ID: 2539618
Abhängigkeiten - Höhe von Ebene: 0 m; Verschieben mit umliegenden Elementen: no
Bemaßungen - Fläche: 0.271849 m2; Volumen: 0.012674 m3
IFC-Parameter - In IFC-Datei exportieren: Nach Typ; Pset MEP.Geom-DN: 200; Pset MEP.Tech-Insulation thickness (mm): 100; Pset MEP.Tech-PN: 16; Pset MEP.Geom-Length (mm): 60; Pset MEP.Tech-Connection type (Inner thread=2, flange=3): 2; In IFC exportieren als: ifcflowcontroller; NameOverride: Zwischenflanschklappe; IfcPresentationLayer: 0-TFT-H_Vorlauf; ObjectTypeOverride: Zwischenflanschklappe; Pset MEP.Name: Zwischenflanschklappe; IfcDescription: Zwischenflanschklappe
Phasen - Phase erstellt: Phase 01

# IfcFlowController: Zwischenflanschklappe 861187:Zwischenflanschklappe 861187, Zwischenflanschklappe
In: 1. Untergeschoss
Type - Material: IfcSurfaceStyle #1741
Type - Andere - Kategorie: Allgemeines Modell; Familienname: Zwischenflanschklappe 861187
Type - ID-Daten - Typname: Zwischenflanschklappe 861187
Type - IFC-Parameter - Typ in IFC-Datei exportieren: Vorgabe
Description: Zwischenflanschklappe
Pset_DistributionFlowElementCommon - Reference: Zwischenflanschklappe 861187; sets with these values: 2
Andere - Typ: Zwischenflanschklappe 861187; Familie: Zwischenflanschklappe 861187; Familie und Typ: Zwischenflanschklappe 861187: Zwischenflanschklappe 861187; Typ-ID: 2539639
Abhängigkeiten - Höhe von Ebene: 0 m; Verschieben mit umliegenden Elementen: no
Bemaßungen - Fläche: 0.271849 m2; Volumen: 0.012674 m3
IFC-Parameter - In IFC-Datei exportieren: Nach Typ; Pset MEP.Geom-DN: 200; Pset MEP.Tech-Insulation thickness (mm): 100; Pset MEP.Tech-PN: 16; Pset MEP.Geom-Length (mm): 60; Pset MEP.Tech-Connection type (Inner thread=2, flange=3): 2; In IFC exportieren als: ifcflowcontroller; NameOverride: Zwischenflanschklappe; IfcPresentationLayer: 0-TFT-H_Ruecklauf; ObjectTypeOverride: Zwischenflanschklappe; Pset MEP.Name: Zwischenflanschklappe; IfcDescription: Zwischenflanschklappe
Phasen - Phase erstellt: Phase 01

# IfcFlowController: Zwischenflanschklappe:Zwischenflanschklappe, Zwischenflanschklappe
In: 1. Obergeschoss
Type - Material: IfcSurfaceStyle #1741
Type - Andere - Kategorie: Allgemeines Modell; Familienname: Zwischenflanschklappe
Type - ID-Daten - Typname: Zwischenflanschklappe
Type - IFC-Parameter - Typ in IFC-Datei exportieren: Vorgabe
Description: Zwischenflanschklappe
Pset_DistributionFlowElementCommon - Reference: Zwischenflanschklappe; sets with these values: 2
Andere - Typ: Zwischenflanschklappe; Familie: Zwischenflanschklappe; Familie und Typ: Zwischenflanschklappe: Zwischenflanschklappe; Typ-ID: 2531362
Abhängigkeiten - Höhe von Ebene: 0 m; Verschieben mit umliegenden Elementen: no
Bemaßungen - Fläche: 0.261208 m2; Volumen: 0.012589 m3
IFC-Parameter - In IFC-Datei exportieren: Nach Typ; Pset MEP.Geom-DN: 200; Pset MEP.Tech-Insulation thickness (mm): 100; Pset MEP.Tech-PN: 16; In IFC exportieren als: ifcflowcontroller; NameOverride: Zwischenflanschklappe; IfcPresentationLayer: 0-TFT-H_Ruecklauf; ObjectTypeOverride: Zwischenflanschklappe; Pset MEP.Name: Zwischenflanschklappe; IfcDescription: Zwischenflanschklappe; Pset MEP.Geom-Length (mm): 60; Pset MEP.Tech-Connection type (Inner thread=2, flange=3): 2
Phasen - Phase erstellt: Phase 01

# IfcFlowFitting: Abzweigstück 221421:Abzweigstück 221421, Abzweigstück
In: 1. Obergeschoss
Type - Material: IfcSurfaceStyle #9317
Type - Andere - Kategorie: Allgemeines Modell; Familienname: Abzweigstück 221421
Type - ID-Daten - Typname: Abzweigstück 221421
Type - IFC-Parameter - Typ in IFC-Datei exportieren: Vorgabe
Description: Abzweigstück
Pset_DistributionFlowElementCommon - Reference: Abzweigstück 221421; sets with these values: 2
Andere - Typ: Abzweigstück 221421; Familie: Abzweigstück 221421; Familie und Typ: Abzweigstück 221421: Abzweigstück 221421; Typ-ID: 2531768
Abhängigkeiten - Höhe von Ebene: 0 m; Verschieben mit umliegenden Elementen: no
Bemaßungen - Fläche: 0.263294 m2; Volumen: 0.0253543 m3
IFC-Parameter - In IFC-Datei exportieren: Nach Typ; Pset MEP.Tech-Insulation thickness (mm): 100; Pset MEP.Geom-DN1: 150; Pset MEP.Geom-DN2: 150; Pset MEP.Geom-Length (mm): 286; Pset MEP.Geom-DN3: 150; Pset MEP.Geom-Length outlet (mm): 143; In IFC exportieren als: ifcflowfitting; NameOverride: Abzweigstück; IfcPresentationLayer: 0-TFT-H_Vorlauf; ObjectTypeOverride: Abzweigstück; Pset MEP.Name: Abzweigstück; IfcDescription: Abzweigstück; Pset MEP.Tech-Material: nach DIN 2615; Pset MEP.Geom-Outer Ø1 (mm): 168.3; Pset MEP.Geom-Outer Ø2 (mm): 168.3; Pset MEP.Geom-Outer Ø3 (mm): 168.3
Phasen - Phase erstellt: Phase 01

# IfcFlowFitting: Abzweigstück 221678:Abzweigstück 221678, Abzweigstück
In: 1. Obergeschoss
Type - Material: IfcSurfaceStyle #9317
Type - Andere - Kategorie: Allgemeines Modell; Familienname: Abzweigstück 221678
Type - ID-Daten - Typname: Abzweigstück 221678
Type - IFC-Parameter - Typ in IFC-Datei exportieren: Vorgabe
Description: Abzweigstück
Pset_DistributionFlowElementCommon - Reference: Abzweigstück 221678; sets with these values: 2
Andere - Typ: Abzweigstück 221678; Familie: Abzweigstück 221678; Familie und Typ: Abzweigstück 221678: Abzweigstück 221678; Typ-ID: 2531845
Abhängigkeiten - Höhe von Ebene: 0 m; Verschieben mit umliegenden Elementen: no
Bemaßungen - Fläche: 0.375346 m2; Volumen: 0.041967 m3
IFC-Parameter - In IFC-Datei exportieren: Nach Typ; Pset MEP.Tech-Insulation thickness (mm): 100; Pset MEP.Geom-DN1: 200; Pset MEP.Geom-DN2: 200; Pset MEP.Geom-DN3: 150; In IFC exportieren als: ifcflowfitting; NameOverride: Abzweigstück; IfcPresentationLayer: 0-TFT-H_Vorlauf; ObjectTypeOverride: Abzweigstück; Pset MEP.Name: Abzweigstück; IfcDescription: Abzweigstück; Pset MEP.Tech-Material: nach DIN 2615; Pset MEP.Geom-Outer Ø1 (mm): 219.1; Pset MEP.Geom-Outer Ø2 (mm): 219.1; Pset MEP.Geom-Length (mm): 356; Pset MEP.Geom-Length outlet (mm): 168; Pset MEP.Geom-Outer Ø3 (mm): 168.3
Phasen - Phase erstellt: Phase 01

# IfcFlowFitting: Abzweigstück 222781:Abzweigstück 222781, Abzweigstück
In: 1. Obergeschoss
Type - Material: IfcSurfaceStyle #9317
Type - Andere - Kategorie: Allgemeines Modell; Familienname: Abzweigstück 222781
Type - ID-Daten - Typname: Abzweigstück 222781
Type - IFC-Parameter - Typ in IFC-Datei exportieren: Vorgabe
Description: Abzweigstück
Pset_DistributionFlowElementCommon - Reference: Abzweigstück 222781; sets with these values: 2
Andere - Typ: Abzweigstück 222781; Familie: Abzweigstück 222781; Familie und Typ: Abzweigstück 222781: Abzweigstück 222781; Typ-ID: 2531873
Abhängigkeiten - Höhe von Ebene: 0 m; Verschieben mit umliegenden Elementen: no
Bemaßungen - Fläche: 0.392022 m2; Volumen: 0.0435045 m3
IFC-Parameter - In IFC-Datei exportieren: Nach Typ; Pset MEP.Tech-Insulation thickness (mm): 100; Pset MEP.Geom-DN1: 200; Pset MEP.Geom-DN2: 200; In IFC exportieren als: ifcflowfitting; NameOverride: Abzweigstück; IfcPresentationLayer: 0-TFT-H_Vorlauf; ObjectTypeOverride: Abzweigstück; Pset MEP.Name: Abzweigstück; IfcDescription: Abzweigstück; Pset MEP.Tech-Material: nach DIN 2615; Pset MEP.Geom-Outer Ø1 (mm): 219.1; Pset MEP.Geom-Outer Ø2 (mm): 219.1; Pset MEP.Geom-Length (mm): 356; Pset MEP.Geom-DN3: 200; Pset MEP.Geom-Length outlet (mm): 178; Pset MEP.Geom-Outer Ø3 (mm): 219.1
Phasen - Phase erstellt: Phase 01

# IfcFlowFitting: Abzweigstück 225554:Abzweigstück 225554, Abzweigstück
In: 1. Obergeschoss
Type - Material: IfcSurfaceStyle #9317
Type - Andere - Kategorie: Allgemeines Modell; Familienname: Abzweigstück 225554
Type - ID-Daten - Typname: Abzweigstück 225554
Type - IFC-Parameter - Typ in IFC-Datei exportieren: Vorgabe
Description: Abzweigstück
Pset_DistributionFlowElementCommon - Reference: Abzweigstück 225554; sets with these values: 2
Andere - Typ: Abzweigstück 225554; Familie: Abzweigstück 225554; Familie und Typ: Abzweigstück 225554: Abzweigstück 225554; Typ-ID: 2531957
Abhängigkeiten - Höhe von Ebene: 0 m; Verschieben mit umliegenden Elementen: no
Bemaßungen - Fläche: 0.36478 m2; Volumen: 0.0412113 m3
IFC-Parameter - In IFC-Datei exportieren: Nach Typ; Pset MEP.Tech-Insulation thickness (mm): 100; Pset MEP.Geom-DN1: 200; Pset MEP.Geom-DN2: 200; In IFC exportieren als: ifcflowfitting; NameOverride: Abzweigstück; IfcPresentationLayer: 0-TFT-H_Vorlauf; ObjectTypeOverride: Abzweigstück; Pset MEP.Name: Abzweigstück; IfcDescription: Abzweigstück; Pset MEP.Tech-Material: nach DIN 2615; Pset MEP.Geom-Outer Ø1 (mm): 219.1; Pset MEP.Geom-Outer Ø2 (mm): 219.1; Pset MEP.Geom-Length (mm): 356; Pset MEP.Geom-DN3: 100; Pset MEP.Geom-Length outlet (mm): 156; Pset MEP.Geom-Outer Ø3 (mm): 114.3
Phasen - Phase erstellt: Phase 01

# IfcFlowFitting: Abzweigstück 225748:Abzweigstück 225748, Abzweigstück
In: 1. Obergeschoss
Type - Material: IfcSurfaceStyle #9317
Type - Andere - Kategorie: Allgemeines Modell; Familienname: Abzweigstück 225748
Type - ID-Daten - Typname: Abzweigstück 225748
Type - IFC-Parameter - Typ in IFC-Datei exportieren: Vorgabe
Description: Abzweigstück
Pset_DistributionFlowElementCommon - Reference: Abzweigstück 225748; sets with these values: 2
Andere - Typ: Abzweigstück 225748; Familie: Abzweigstück 225748; Familie und Typ: Abzweigstück 225748: Abzweigstück 225748; Typ-ID: 2531964
Abhängigkeiten - Höhe von Ebene: 0 m; Verschieben mit umliegenden Elementen: no
Bemaßungen - Fläche: 0.392022 m2; Volumen: 0.0435045 m3
IFC-Parameter - In IFC-Datei exportieren: Nach Typ; Pset MEP.Tech-Insulation thickness (mm): 100; Pset MEP.Geom-DN1: 200; Pset MEP.Geom-DN2: 200; Pset MEP.Geom-DN3: 200; Pset MEP.Geom-Length outlet (mm): 178; In IFC exportieren als: ifcflowfitting; NameOverride: Abzweigstück; IfcPresentationLayer: 0-TFT-H_Vorlauf; ObjectTypeOverride: Abzweigstück; Pset MEP.Name: Abzweigstück; IfcDescription: Abzweigstück; Pset MEP.Tech-Material: nach DIN 2615; Pset MEP.Geom-Outer Ø1 (mm): 219.1; Pset MEP.Geom-Outer Ø2 (mm): 219.1; Pset MEP.Geom-Length (mm): 356; Pset MEP.Geom-Outer Ø3 (mm): 219.1
Phasen - Phase erstellt: Phase 01

# IfcFlowFitting: Abzweigstück 226052:Abzweigstück 226052, Abzweigstück
In: 1. Obergeschoss
Type - Material: IfcSurfaceStyle #9317
Type - Andere - Kategorie: Allgemeines Modell; Familienname: Abzweigstück 226052
Type - ID-Daten - Typname: Abzweigstück 226052
Type - IFC-Parameter - Typ in IFC-Datei exportieren: Vorgabe
Description: Abzweigstück
Pset_DistributionFlowElementCommon - Reference: Abzweigstück 226052; sets with these values: 2
Andere - Typ: Abzweigstück 226052; Familie: Abzweigstück 226052; Familie und Typ: Abzweigstück 226052: Abzweigstück 226052; Typ-ID: 2531978
Abhängigkeiten - Höhe von Ebene: 0 m; Verschieben mit umliegenden Elementen: no
Bemaßungen - Fläche: 0.392022 m2; Volumen: 0.0435045 m3
IFC-Parameter - In IFC-Datei exportieren: Nach Typ; Pset MEP.Tech-Insulation thickness (mm): 100; Pset MEP.Geom-DN1: 200; Pset MEP.Geom-DN2: 200; Pset MEP.Geom-DN3: 200; Pset MEP.Geom-Length outlet (mm): 178; In IFC exportieren als: ifcflowfitting; NameOverride: Abzweigstück; IfcPresentationLayer: 0-TFT-H_Vorlauf; ObjectTypeOverride: Abzweigstück; Pset MEP.Name: Abzweigstück; IfcDescription: Abzweigstück; Pset MEP.Tech-Material: nach DIN 2615; Pset MEP.Geom-Outer Ø1 (mm): 219.1; Pset MEP.Geom-Outer Ø2 (mm): 219.1; Pset MEP.Geom-Length (mm): 356; Pset MEP.Geom-Outer Ø3 (mm): 219.1
Phasen - Phase erstellt: Phase 01

# IfcFlowFitting: Abzweigstück 226356:Abzweigstück 226356, Abzweigstück
In: 1. Obergeschoss
Type - Material: IfcSurfaceStyle #9317
Type - Andere - Kategorie: Allgemeines Modell; Familienname: Abzweigstück 226356
Type - ID-Daten - Typname: Abzweigstück 226356
Type - IFC-Parameter - Typ in IFC-Datei exportieren: Vorgabe
Description: Abzweigstück
Pset_DistributionFlowElementCommon - Reference: Abzweigstück 226356; sets with these values: 2
Andere - Typ: Abzweigstück 226356; Familie: Abzweigstück 226356; Familie und Typ: Abzweigstück 226356: Abzweigstück 226356; Typ-ID: 2531992
Abhängigkeiten - Höhe von Ebene: 0 m; Verschieben mit umliegenden Elementen: no
Bemaßungen - Fläche: 0.392022 m2; Volumen: 0.0435045 m3
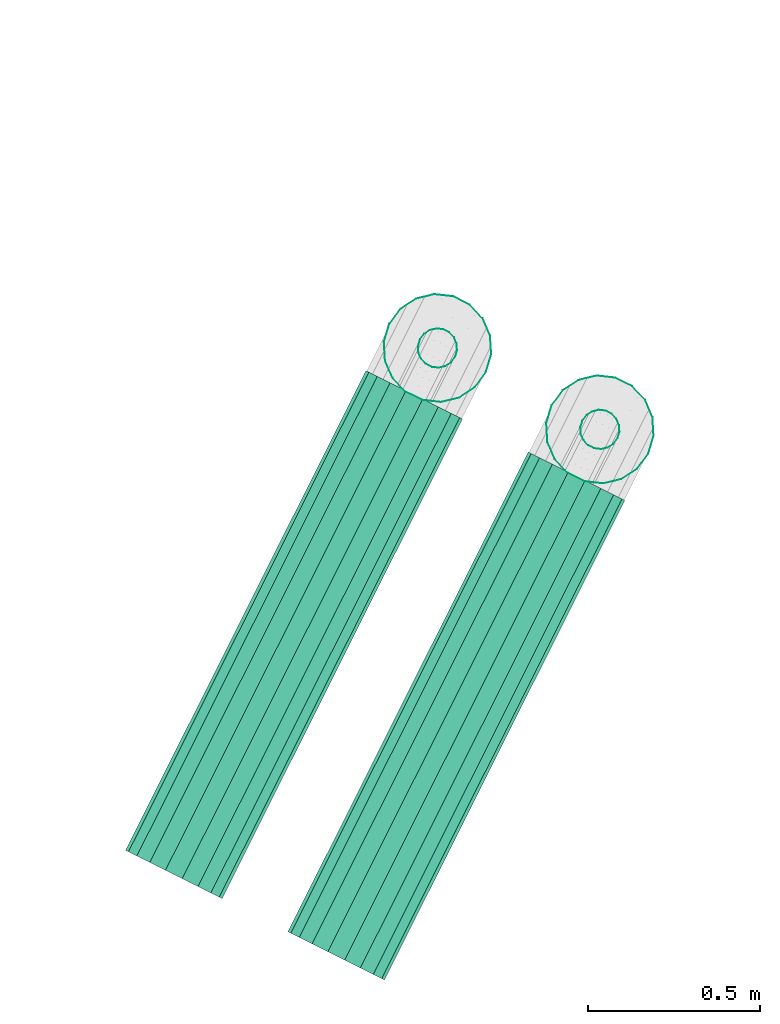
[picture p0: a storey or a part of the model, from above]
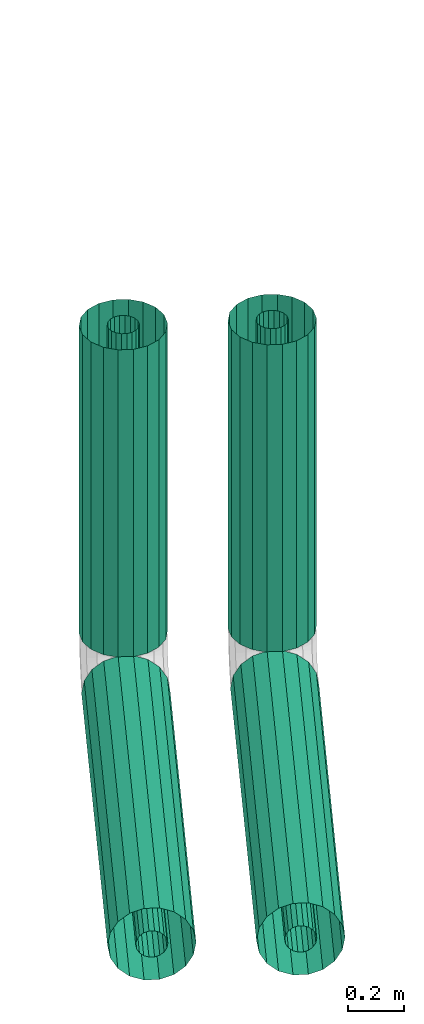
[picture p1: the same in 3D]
Properties of the parts of a building model (IFC2X3), part 6 of 23

# IfcFlowFitting: Abzweigstück 226356:Abzweigstück 226356, Abzweigstück
IFC-Parameter - In IFC-Datei exportieren: Nach Typ; Pset MEP.Tech-Insulation thickness (mm): 100; Pset MEP.Geom-DN1: 200; Pset MEP.Geom-DN2: 200; Pset MEP.Geom-DN3: 200; Pset MEP.Geom-Length outlet (mm): 178; In IFC exportieren als: ifcflowfitting; NameOverride: Abzweigstück; IfcPresentationLayer: 0-TFT-H_Vorlauf; ObjectTypeOverride: Abzweigstück; Pset MEP.Name: Abzweigstück; IfcDescription: Abzweigstück; Pset MEP.Tech-Material: nach DIN 2615; Pset MEP.Geom-Outer Ø1 (mm): 219.1; Pset MEP.Geom-Outer Ø2 (mm): 219.1; Pset MEP.Geom-Length (mm): 356; Pset MEP.Geom-Outer Ø3 (mm): 219.1
Phasen - Phase erstellt: Phase 01

# IfcFlowFitting: Abzweigstück 226660:Abzweigstück 226660, Abzweigstück
In: 1. Obergeschoss
Type - Material: IfcSurfaceStyle #1741
Type - Andere - Kategorie: Allgemeines Modell; Familienname: Abzweigstück 226660
Type - ID-Daten - Typname: Abzweigstück 226660
Type - IFC-Parameter - Typ in IFC-Datei exportieren: Vorgabe
Description: Abzweigstück
Pset_DistributionFlowElementCommon - Reference: Abzweigstück 226660; sets with these values: 2
Andere - Typ: Abzweigstück 226660; Familie: Abzweigstück 226660; Familie und Typ: Abzweigstück 226660: Abzweigstück 226660; Typ-ID: 2532006
Abhängigkeiten - Höhe von Ebene: 0 m; Verschieben mit umliegenden Elementen: no
Bemaßungen - Fläche: 0.36478 m2; Volumen: 0.0412113 m3
IFC-Parameter - In IFC-Datei exportieren: Nach Typ; Pset MEP.Tech-Insulation thickness (mm): 100; Pset MEP.Geom-DN1: 200; Pset MEP.Geom-DN2: 200; Pset MEP.Geom-DN3: 100; Pset MEP.Geom-Length outlet (mm): 156; In IFC exportieren als: ifcflowfitting; NameOverride: Abzweigstück; IfcPresentationLayer: 0-TFT-H_Ruecklauf; ObjectTypeOverride: Abzweigstück; Pset MEP.Name: Abzweigstück; IfcDescription: Abzweigstück; Pset MEP.Tech-Material: nach DIN 2615; Pset MEP.Geom-Outer Ø1 (mm): 219.1; Pset MEP.Geom-Outer Ø2 (mm): 219.1; Pset MEP.Geom-Length (mm): 356; Pset MEP.Geom-Outer Ø3 (mm): 114.3
Phasen - Phase erstellt: Phase 01

# IfcFlowFitting: Abzweigstück 226683:Abzweigstück 226683, Abzweigstück
In: 1. Obergeschoss
Type - Material: IfcSurfaceStyle #1741
Type - Andere - Kategorie: Allgemeines Modell; Familienname: Abzweigstück 226683
Type - ID-Daten - Typname: Abzweigstück 226683
Type - IFC-Parameter - Typ in IFC-Datei exportieren: Vorgabe
Description: Abzweigstück
Pset_DistributionFlowElementCommon - Reference: Abzweigstück 226683; sets with these values: 2
Andere - Typ: Abzweigstück 226683; Familie: Abzweigstück 226683; Familie und Typ: Abzweigstück 226683: Abzweigstück 226683; Typ-ID: 2532013
Abhängigkeiten - Höhe von Ebene: 0 m; Verschieben mit umliegenden Elementen: no
Bemaßungen - Fläche: 0.392022 m2; Volumen: 0.0435045 m3
IFC-Parameter - In IFC-Datei exportieren: Nach Typ; Pset MEP.Tech-Insulation thickness (mm): 100; Pset MEP.Geom-DN1: 200; Pset MEP.Geom-DN2: 200; Pset MEP.Geom-DN3: 200; Pset MEP.Geom-Length outlet (mm): 178; In IFC exportieren als: ifcflowfitting; NameOverride: Abzweigstück; IfcPresentationLayer: 0-TFT-H_Ruecklauf; ObjectTypeOverride: Abzweigstück; Pset MEP.Name: Abzweigstück; IfcDescription: Abzweigstück; Pset MEP.Tech-Material: nach DIN 2615; Pset MEP.Geom-Outer Ø1 (mm): 219.1; Pset MEP.Geom-Outer Ø2 (mm): 219.1; Pset MEP.Geom-Length (mm): 356; Pset MEP.Geom-Outer Ø3 (mm): 219.1
Phasen - Phase erstellt: Phase 01

# IfcFlowFitting: Abzweigstück 226729:Abzweigstück 226729, Abzweigstück
In: 1. Obergeschoss
Type - Material: IfcSurfaceStyle #1741
Type - Andere - Kategorie: Allgemeines Modell; Familienname: Abzweigstück 226729
Type - ID-Daten - Typname: Abzweigstück 226729
Type - IFC-Parameter - Typ in IFC-Datei exportieren: Vorgabe
Description: Abzweigstück
Pset_DistributionFlowElementCommon - Reference: Abzweigstück 226729; sets with these values: 2
Andere - Typ: Abzweigstück 226729; Familie: Abzweigstück 226729; Familie und Typ: Abzweigstück 226729: Abzweigstück 226729; Typ-ID: 2532027
Abhängigkeiten - Höhe von Ebene: 0 m; Verschieben mit umliegenden Elementen: no
Bemaßungen - Fläche: 0.392022 m2; Volumen: 0.0435045 m3
IFC-Parameter - In IFC-Datei exportieren: Nach Typ; Pset MEP.Tech-Insulation thickness (mm): 100; Pset MEP.Geom-DN1: 200; Pset MEP.Geom-DN2: 200; Pset MEP.Geom-DN3: 200; Pset MEP.Geom-Length outlet (mm): 178; In IFC exportieren als: ifcflowfitting; NameOverride: Abzweigstück; IfcPresentationLayer: 0-TFT-H_Ruecklauf; ObjectTypeOverride: Abzweigstück; Pset MEP.Name: Abzweigstück; IfcDescription: Abzweigstück; Pset MEP.Tech-Material: nach DIN 2615; Pset MEP.Geom-Outer Ø1 (mm): 219.1; Pset MEP.Geom-Outer Ø2 (mm): 219.1; Pset MEP.Geom-Length (mm): 356; Pset MEP.Geom-Outer Ø3 (mm): 219.1
Phasen - Phase erstellt: Phase 01

# IfcFlowFitting: Abzweigstück 226775:Abzweigstück 226775, Abzweigstück
In: 1. Obergeschoss
Type - Material: IfcSurfaceStyle #1741
Type - Andere - Kategorie: Allgemeines Modell; Familienname: Abzweigstück 226775
Type - ID-Daten - Typname: Abzweigstück 226775
Type - IFC-Parameter - Typ in IFC-Datei exportieren: Vorgabe
Description: Abzweigstück
Pset_DistributionFlowElementCommon - Reference: Abzweigstück 226775; sets with these values: 2
Andere - Typ: Abzweigstück 226775; Familie: Abzweigstück 226775; Familie und Typ: Abzweigstück 226775: Abzweigstück 226775; Typ-ID: 2532041
Abhängigkeiten - Höhe von Ebene: 0 m; Verschieben mit umliegenden Elementen: no
Bemaßungen - Fläche: 0.392022 m2; Volumen: 0.0435045 m3
IFC-Parameter - In IFC-Datei exportieren: Nach Typ; Pset MEP.Tech-Insulation thickness (mm): 100; Pset MEP.Geom-DN1: 200; Pset MEP.Geom-DN2: 200; Pset MEP.Geom-DN3: 200; Pset MEP.Geom-Length outlet (mm): 178; In IFC exportieren als: ifcflowfitting; NameOverride: Abzweigstück; IfcPresentationLayer: 0-TFT-H_Ruecklauf; ObjectTypeOverride: Abzweigstück; Pset MEP.Name: Abzweigstück; IfcDescription: Abzweigstück; Pset MEP.Tech-Material: nach DIN 2615; Pset MEP.Geom-Outer Ø1 (mm): 219.1; Pset MEP.Geom-Outer Ø2 (mm): 219.1; Pset MEP.Geom-Length (mm): 356; Pset MEP.Geom-Outer Ø3 (mm): 219.1
Phasen - Phase erstellt: Phase 01

# IfcFlowFitting: Abzweigstück 228516:Abzweigstück 228516, Abzweigstück
In: 1. Obergeschoss
Type - Material: IfcSurfaceStyle #1741
Type - Andere - Kategorie: Allgemeines Modell; Familienname: Abzweigstück 228516
Type - ID-Daten - Typname: Abzweigstück 228516
Type - IFC-Parameter - Typ in IFC-Datei exportieren: Vorgabe
Description: Abzweigstück
Pset_DistributionFlowElementCommon - Reference: Abzweigstück 228516; sets with these values: 2
Andere - Typ: Abzweigstück 228516; Familie: Abzweigstück 228516; Familie und Typ: Abzweigstück 228516: Abzweigstück 228516; Typ-ID: 2532158
Abhängigkeiten - Höhe von Ebene: 0 m; Verschieben mit umliegenden Elementen: no
Bemaßungen - Fläche: 0.392022 m2; Volumen: 0.0435045 m3
IFC-Parameter - In IFC-Datei exportieren: Nach Typ; Pset MEP.Tech-Insulation thickness (mm): 100; Pset MEP.Geom-DN1: 200; Pset MEP.Geom-DN2: 200; Pset MEP.Geom-DN3: 200; Pset MEP.Geom-Length outlet (mm): 178; In IFC exportieren als: ifcflowfitting; NameOverride: Abzweigstück; IfcPresentationLayer: 0-TFT-H_Ruecklauf; ObjectTypeOverride: Abzweigstück; Pset MEP.Name: Abzweigstück; IfcDescription: Abzweigstück; Pset MEP.Tech-Material: nach DIN 2615; Pset MEP.Geom-Outer Ø1 (mm): 219.1; Pset MEP.Geom-Outer Ø2 (mm): 219.1; Pset MEP.Geom-Length (mm): 356; Pset MEP.Geom-Outer Ø3 (mm): 219.1
Phasen - Phase erstellt: Phase 01

# IfcFlowFitting: Abzweigstück 247876:Abzweigstück 247876, Abzweigstück
In: 1. Obergeschoss
Type - Material: IfcSurfaceStyle #1741
Type - Andere - Kategorie: Allgemeines Modell; Familienname: Abzweigstück 247876
Type - ID-Daten - Typname: Abzweigstück 247876
Type - IFC-Parameter - Typ in IFC-Datei exportieren: Vorgabe
Description: Abzweigstück
Pset_DistributionFlowElementCommon - Reference: Abzweigstück 247876; sets with these values: 2
Andere - Typ: Abzweigstück 247876; Familie: Abzweigstück 247876; Familie und Typ: Abzweigstück 247876: Abzweigstück 247876; Typ-ID: 2532711
Abhängigkeiten - Höhe von Ebene: 0 m; Verschieben mit umliegenden Elementen: no
Bemaßungen - Fläche: 0.392022 m2; Volumen: 0.0435045 m3
IFC-Parameter - In IFC-Datei exportieren: Nach Typ; Pset MEP.Tech-Insulation thickness (mm): 100; Pset MEP.Geom-DN1: 200; Pset MEP.Geom-DN2: 200; Pset MEP.Geom-DN3: 200; Pset MEP.Geom-Length outlet (mm): 178; In IFC exportieren als: ifcflowfitting; NameOverride: Abzweigstück; IfcPresentationLayer: 0-TFT-H_Ruecklauf; ObjectTypeOverride: Abzweigstück; Pset MEP.Name: Abzweigstück; IfcDescription: Abzweigstück; Pset MEP.Tech-Material: nach DIN 2615; Pset MEP.Geom-Outer Ø1 (mm): 219.1; Pset MEP.Geom-Outer Ø2 (mm): 219.1; Pset MEP.Geom-Length (mm): 356; Pset MEP.Geom-Outer Ø3 (mm): 219.1
Phasen - Phase erstellt: Phase 01

# IfcFlowFitting: Abzweigstück 249742:Abzweigstück 249742, Abzweigstück
In: 1. Obergeschoss
Type - Material: IfcSurfaceStyle #1741
Type - Andere - Kategorie: Allgemeines Modell; Familienname: Abzweigstück 249742
Type - ID-Daten - Typname: Abzweigstück 249742
Type - IFC-Parameter - Typ in IFC-Datei exportieren: Vorgabe
Description: Abzweigstück
Pset_DistributionFlowElementCommon - Reference: Abzweigstück 249742; sets with these values: 2
Andere - Typ: Abzweigstück 249742; Familie: Abzweigstück 249742; Familie und Typ: Abzweigstück 249742: Abzweigstück 249742; Typ-ID: 2532781
Abhängigkeiten - Höhe von Ebene: 0 m; Verschieben mit umliegenden Elementen: no
Bemaßungen - Fläche: 0.392022 m2; Volumen: 0.0435045 m3
IFC-Parameter - In IFC-Datei exportieren: Nach Typ; Pset MEP.Tech-Insulation thickness (mm): 100; Pset MEP.Geom-DN1: 200; Pset MEP.Geom-DN2: 200; Pset MEP.Geom-DN3: 200; Pset MEP.Geom-Length outlet (mm): 178; In IFC exportieren als: ifcflowfitting; NameOverride: Abzweigstück; IfcPresentationLayer: 0-TFT-H_Ruecklauf; ObjectTypeOverride: Abzweigstück; Pset MEP.Name: Abzweigstück; IfcDescription: Abzweigstück; Pset MEP.Tech-Material: nach DIN 2615; Pset MEP.Geom-Outer Ø1 (mm): 219.1; Pset MEP.Geom-Outer Ø2 (mm): 219.1; Pset MEP.Geom-Length (mm): 356; Pset MEP.Geom-Outer Ø3 (mm): 219.1
Phasen - Phase erstellt: Phase 01

# IfcFlowFitting: Abzweigstück 251239:Abzweigstück 251239, Abzweigstück
In: 1. Obergeschoss
Type - Material: IfcSurfaceStyle #9317
Type - Andere - Kategorie: Allgemeines Modell; Familienname: Abzweigstück 251239
Type - ID-Daten - Typname: Abzweigstück 251239
Type - IFC-Parameter - Typ in IFC-Datei exportieren: Vorgabe
Description: Abzweigstück
Pset_DistributionFlowElementCommon - Reference: Abzweigstück 251239; sets with these values: 2
Andere - Typ: Abzweigstück 251239; Familie: Abzweigstück 251239; Familie und Typ: Abzweigstück 251239: Abzweigstück 251239; Typ-ID: 2532844
Abhängigkeiten - Höhe von Ebene: 0 m; Verschieben mit umliegenden Elementen: no
Bemaßungen - Fläche: 0.392022 m2; Volumen: 0.0435045 m3
IFC-Parameter - In IFC-Datei exportieren: Nach Typ; Pset MEP.Tech-Insulation thickness (mm): 100; Pset MEP.Geom-DN1: 200; Pset MEP.Geom-DN2: 200; Pset MEP.Geom-DN3: 200; Pset MEP.Geom-Length outlet (mm): 178; In IFC exportieren als: ifcflowfitting; NameOverride: Abzweigstück; IfcPresentationLayer: 0-TFT-H_Vorlauf; ObjectTypeOverride: Abzweigstück; Pset MEP.Name: Abzweigstück; IfcDescription: Abzweigstück; Pset MEP.Tech-Material: nach DIN 2615; Pset MEP.Geom-Outer Ø1 (mm): 219.1; Pset MEP.Geom-Outer Ø2 (mm): 219.1; Pset MEP.Geom-Length (mm): 356; Pset MEP.Geom-Outer Ø3 (mm): 219.1
Phasen - Phase erstellt: Phase 01

# IfcFlowFitting: Abzweigstück 252243:Abzweigstück 252243, Abzweigstück
In: 1. Obergeschoss
Type - Material: IfcSurfaceStyle #1741
Type - Andere - Kategorie: Allgemeines Modell; Familienname: Abzweigstück 252243
Type - ID-Daten - Typname: Abzweigstück 252243
Type - IFC-Parameter - Typ in IFC-Datei exportieren: Vorgabe
Description: Abzweigstück
Pset_DistributionFlowElementCommon - Reference: Abzweigstück 252243; sets with these values: 2
Andere - Typ: Abzweigstück 252243; Familie: Abzweigstück 252243; Familie und Typ: Abzweigstück 252243: Abzweigstück 252243; Typ-ID: 2532897
Abhängigkeiten - Höhe von Ebene: 0 m; Verschieben mit umliegenden Elementen: no
Bemaßungen - Fläche: 0.392022 m2; Volumen: 0.0435045 m3
IFC-Parameter - In IFC-Datei exportieren: Nach Typ; Pset MEP.Tech-Insulation thickness (mm): 100; Pset MEP.Geom-DN1: 200; Pset MEP.Geom-DN2: 200; Pset MEP.Geom-DN3: 200; Pset MEP.Geom-Length outlet (mm): 178; In IFC exportieren als: ifcflowfitting; NameOverride: Abzweigstück; IfcPresentationLayer: 0-TFT-H_Ruecklauf; ObjectTypeOverride: Abzweigstück; Pset MEP.Name: Abzweigstück; IfcDescription: Abzweigstück; Pset MEP.Tech-Material: nach DIN 2615; Pset MEP.Geom-Outer Ø1 (mm): 219.1; Pset MEP.Geom-Outer Ø2 (mm): 219.1; Pset MEP.Geom-Length (mm): 356; Pset MEP.Geom-Outer Ø3 (mm): 219.1
Phasen - Phase erstellt: Phase 01

# IfcFlowFitting: Abzweigstück 253225:Abzweigstück 253225, Abzweigstück
In: 1. Obergeschoss
Type - Material: IfcSurfaceStyle #1741
Type - Andere - Kategorie: Allgemeines Modell; Familienname: Abzweigstück 253225
Type - ID-Daten - Typname: Abzweigstück 253225
Type - IFC-Parameter - Typ in IFC-Datei exportieren: Vorgabe
Description: Abzweigstück
Pset_DistributionFlowElementCommon - Reference: Abzweigstück 253225; sets with these values: 2
Andere - Typ: Abzweigstück 253225; Familie: Abzweigstück 253225; Familie und Typ: Abzweigstück 253225: Abzweigstück 253225; Typ-ID: 2532939
Abhängigkeiten - Höhe von Ebene: 0 m; Verschieben mit umliegenden Elementen: no
Bemaßungen - Fläche: 0.36162 m2; Volumen: 0.0410381 m3
IFC-Parameter - In IFC-Datei exportieren: Nach Typ; Pset MEP.Tech-Insulation thickness (mm): 100; Pset MEP.Geom-DN1: 200; Pset MEP.Geom-DN2: 200; In IFC exportieren als: ifcflowfitting; NameOverride: Abzweigstück; IfcPresentationLayer: 0-TFT-H_Ruecklauf; ObjectTypeOverride: Abzweigstück; Pset MEP.Name: Abzweigstück; IfcDescription: Abzweigstück; Pset MEP.Tech-Material: nach DIN 2615; Pset MEP.Geom-Outer Ø1 (mm): 219.1; Pset MEP.Geom-Outer Ø2 (mm): 219.1; Pset MEP.Geom-Length (mm): 356; Pset MEP.Geom-DN3: 80; Pset MEP.Geom-Length outlet (mm): 152; Pset MEP.Geom-Outer Ø3 (mm): 88.9
Phasen - Phase erstellt: Phase 01

# IfcFlowFitting: Abzweigstück 253418:Abzweigstück 253418, Abzweigstück
In: 1. Obergeschoss
Type - Material: IfcSurfaceStyle #1741
Type - Andere - Kategorie: Allgemeines Modell; Familienname: Abzweigstück 253418
Type - ID-Daten - Typname: Abzweigstück 253418
Type - IFC-Parameter - Typ in IFC-Datei exportieren: Vorgabe
Description: Abzweigstück
Pset_DistributionFlowElementCommon - Reference: Abzweigstück 253418; sets with these values: 2
Andere - Typ: Abzweigstück 253418; Familie: Abzweigstück 253418; Familie und Typ: Abzweigstück 253418: Abzweigstück 253418; Typ-ID: 2532946
Abhängigkeiten - Höhe von Ebene: 0 m; Verschieben mit umliegenden Elementen: no
Bemaßungen - Fläche: 0.0898086 m2; Volumen: 0.00654962 m3
IFC-Parameter - In IFC-Datei exportieren: Nach Typ; Pset MEP.Tech-Insulation thickness (mm): 100; Pset MEP.Geom-Length (mm): 152; In IFC exportieren als: ifcflowfitting; NameOverride: Abzweigstück; IfcPresentationLayer: 0-TFT-H_Ruecklauf; ObjectTypeOverride: Abzweigstück; Pset MEP.Name: Abzweigstück; IfcDescription: Abzweigstück; Pset MEP.Tech-Material: nach DIN 2615; Pset MEP.Geom-DN1: 65; Pset MEP.Geom-DN2: 65; Pset MEP.Geom-Outer Ø1 (mm): 76.1; Pset MEP.Geom-Outer Ø2 (mm): 76.1; Pset MEP.Geom-DN3: 65; Pset MEP.Geom-Length outlet (mm): 76; Pset MEP.Geom-Outer Ø3 (mm): 76.1
Phasen - Phase erstellt: Phase 01

# IfcFlowFitting: Abzweigstück 259209:Abzweigstück 259209, Abzweigstück
In: 1. Obergeschoss
Type - Material: IfcSurfaceStyle #1741
Type - Andere - Kategorie: Allgemeines Modell; Familienname: Abzweigstück 259209
Type - ID-Daten - Typname: Abzweigstück 259209
Type - IFC-Parameter - Typ in IFC-Datei exportieren: Vorgabe
Description: Abzweigstück
Pset_DistributionFlowElementCommon - Reference: Abzweigstück 259209; sets with these values: 2
Andere - Typ: Abzweigstück 259209; Familie: Abzweigstück 259209; Familie und Typ: Abzweigstück 259209: Abzweigstück 259209; Typ-ID: 2533037
Abhängigkeiten - Höhe von Ebene: 0 m; Verschieben mit umliegenden Elementen: no
Bemaßungen - Fläche: 0.0898086 m2; Volumen: 0.00654962 m3
IFC-Parameter - In IFC-Datei exportieren: Nach Typ; Pset MEP.Tech-Insulation thickness (mm): 100; Pset MEP.Geom-Length (mm): 152; Pset MEP.Geom-DN1: 65; Pset MEP.Geom-DN2: 65; Pset MEP.Geom-DN3: 65; Pset MEP.Geom-Length outlet (mm): 76; In IFC exportieren als: ifcflowfitting; NameOverride: Abzweigstück; IfcPresentationLayer: 0-TFT-H_Ruecklauf; ObjectTypeOverride: Abzweigstück; Pset MEP.Name: Abzweigstück; IfcDescription: Abzweigstück; Pset MEP.Tech-Material: nach DIN 2615; Pset MEP.Geom-Outer Ø1 (mm): 76.1; Pset MEP.Geom-Outer Ø2 (mm): 76.1; Pset MEP.Geom-Outer Ø3 (mm): 76.1
Phasen - Phase erstellt: Phase 01

# IfcFlowFitting: Abzweigstück 260012:Abzweigstück 260012, Abzweigstück
In: 1. Obergeschoss
Type - Material: IfcSurfaceStyle #9317
Type - Andere - Kategorie: Allgemeines Modell; Familienname: Abzweigstück 260012
Type - ID-Daten - Typname: Abzweigstück 260012
Type - IFC-Parameter - Typ in IFC-Datei exportieren: Vorgabe
Description: Abzweigstück
Pset_DistributionFlowElementCommon - Reference: Abzweigstück 260012; sets with these values: 2
Andere - Typ: Abzweigstück 260012; Familie: Abzweigstück 260012; Familie und Typ: Abzweigstück 260012: Abzweigstück 260012; Typ-ID: 2533058
Abhängigkeiten - Höhe von Ebene: 0 m; Verschieben mit umliegenden Elementen: no
Bemaßungen - Fläche: 0.36162 m2; Volumen: 0.0410381 m3
IFC-Parameter - In IFC-Datei exportieren: Nach Typ; Pset MEP.Tech-Insulation thickness (mm): 100; Pset MEP.Geom-DN1: 200; Pset MEP.Geom-DN2: 200; Pset MEP.Geom-DN3: 80; Pset MEP.Geom-Length outlet (mm): 152; In IFC exportieren als: ifcflowfitting; NameOverride: Abzweigstück; IfcPresentationLayer: 0-TFT-H_Vorlauf; ObjectTypeOverride: Abzweigstück; Pset MEP.Name: Abzweigstück; IfcDescription: Abzweigstück; Pset MEP.Tech-Material: nach DIN 2615; Pset MEP.Geom-Outer Ø1 (mm): 219.1; Pset MEP.Geom-Outer Ø2 (mm): 219.1; Pset MEP.Geom-Length (mm): 356; Pset MEP.Geom-Outer Ø3 (mm): 88.9
Phasen - Phase erstellt: Phase 01

# IfcFlowFitting: Abzweigstück 263054:Abzweigstück 263054, Abzweigstück
In: 1. Obergeschoss
Type - Material: IfcSurfaceStyle #9317
Type - Andere - Kategorie: Allgemeines Modell; Familienname: Abzweigstück 263054
Type - ID-Daten - Typname: Abzweigstück 263054
Type - IFC-Parameter - Typ in IFC-Datei exportieren: Vorgabe
Description: Abzweigstück
Pset_DistributionFlowElementCommon - Reference: Abzweigstück 263054; sets with these values: 2
Andere - Typ: Abzweigstück 263054; Familie: Abzweigstück 263054; Familie und Typ: Abzweigstück 263054: Abzweigstück 263054; Typ-ID: 2533149
Abhängigkeiten - Höhe von Ebene: 0 m; Verschieben mit umliegenden Elementen: no
Bemaßungen - Fläche: 0.36478 m2; Volumen: 0.0412113 m3
IFC-Parameter - In IFC-Datei exportieren: Nach Typ; Pset MEP.Tech-Insulation thickness (mm): 100; Pset MEP.Geom-DN1: 200; Pset MEP.Geom-DN2: 200; Pset MEP.Geom-DN3: 100; Pset MEP.Geom-Length outlet (mm): 156; In IFC exportieren als: ifcflowfitting; NameOverride: Abzweigstück; IfcPresentationLayer: 0-TFT-H_Vorlauf; ObjectTypeOverride: Abzweigstück; Pset MEP.Name: Abzweigstück; IfcDescription: Abzweigstück; Pset MEP.Tech-Material: nach DIN 2615; Pset MEP.Geom-Outer Ø1 (mm): 219.1; Pset MEP.Geom-Outer Ø2 (mm): 219.1; Pset MEP.Geom-Length (mm): 356; Pset MEP.Geom-Outer Ø3 (mm): 114.3
Phasen - Phase erstellt: Phase 01

# IfcFlowFitting: Abzweigstück 266716:Abzweigstück 266716, Abzweigstück
In: 1. Obergeschoss
Type - Material: IfcSurfaceStyle #9317
Type - Andere - Kategorie: Allgemeines Modell; Familienname: Abzweigstück 266716
Type - ID-Daten - Typname: Abzweigstück 266716
Type - IFC-Parameter - Typ in IFC-Datei exportieren: Vorgabe
Description: Abzweigstück
Pset_DistributionFlowElementCommon - Reference: Abzweigstück 266716; sets with these values: 2
Andere - Typ: Abzweigstück 266716; Familie: Abzweigstück 266716; Familie und Typ: Abzweigstück 266716: Abzweigstück 266716; Typ-ID: 2533191
Abhängigkeiten - Höhe von Ebene: 0 m; Verschieben mit umliegenden Elementen: no
Bemaßungen - Fläche: 0.36478 m2; Volumen: 0.0412113 m3
IFC-Parameter - In IFC-Datei exportieren: Nach Typ; Pset MEP.Tech-Insulation thickness (mm): 100; Pset MEP.Geom-DN1: 200; Pset MEP.Geom-DN2: 200; Pset MEP.Geom-DN3: 100; Pset MEP.Geom-Length outlet (mm): 156; In IFC exportieren als: ifcflowfitting; NameOverride: Abzweigstück; IfcPresentationLayer: 0-TFT-H_Vorlauf; ObjectTypeOverride: Abzweigstück; Pset MEP.Name: Abzweigstück; IfcDescription: Abzweigstück; Pset MEP.Tech-Material: nach DIN 2615; Pset MEP.Geom-Outer Ø1 (mm): 219.1; Pset MEP.Geom-Outer Ø2 (mm): 219.1; Pset MEP.Geom-Length (mm): 356; Pset MEP.Geom-Outer Ø3 (mm): 114.3
Phasen - Phase erstellt: Phase 01

# IfcFlowFitting: Abzweigstück 316911:Abzweigstück 316911, Abzweigstück
In: Erdgeschoss
Type - Material: IfcSurfaceStyle #9317
Type - Andere - Kategorie: Allgemeines Modell; Familienname: Abzweigstück 316911
Type - ID-Daten - Typname: Abzweigstück 316911
Type - IFC-Parameter - Typ in IFC-Datei exportieren: Vorgabe
Description: Abzweigstück
Pset_DistributionFlowElementCommon - Reference: Abzweigstück 316911; sets with these values: 2
Andere - Typ: Abzweigstück 316911; Familie: Abzweigstück 316911; Familie und Typ: Abzweigstück 316911: Abzweigstück 316911; Typ-ID: 2535236
Abhängigkeiten - Höhe von Ebene: 0 m; Verschieben mit umliegenden Elementen: no
Bemaßungen - Fläche: 0.0905371 m2; Volumen: 0.00485821 m3
IFC-Parameter - In IFC-Datei exportieren: Nach Typ; Pset MEP.Tech-Insulation thickness (mm): 100; Pset MEP.Geom-DN1: 150; Pset MEP.Geom-DN2: 150; Pset MEP.Geom-Length (mm): 286; In IFC exportieren als: ifcflowfitting; NameOverride: Abzweigstück; IfcPresentationLayer: 0-TFT-H_Vorlauf; ObjectTypeOverride: Abzweigstück; Pset MEP.Name: Abzweigstück; IfcDescription: Abzweigstück; Pset MEP.Tech-Material: nach DIN 2615; Pset MEP.Geom-Outer Ø1 (mm): 168.3; Pset MEP.Geom-Outer Ø2 (mm): 168.3; Pset MEP.Geom-DN3: 125; Pset MEP.Geom-Length outlet (mm): 137; Pset MEP.Geom-Outer Ø3 (mm): 139.7
Phasen - Phase erstellt: Phase 01

# IfcFlowFitting: Abzweigstück 317503:Abzweigstück 317503, Abzweigstück
In: Erdgeschoss
Type - Material: IfcSurfaceStyle #9317
Type - Andere - Kategorie: Allgemeines Modell; Familienname: Abzweigstück 317503
Type - ID-Daten - Typname: Abzweigstück 317503
Type - IFC-Parameter - Typ in IFC-Datei exportieren: Vorgabe
Description: Abzweigstück
Pset_DistributionFlowElementCommon - Reference: Abzweigstück 317503; sets with these values: 2
Andere - Typ: Abzweigstück 317503; Familie: Abzweigstück 317503; Familie und Typ: Abzweigstück 317503: Abzweigstück 317503; Typ-ID: 2535285
Abhängigkeiten - Höhe von Ebene: 0 m; Verschieben mit umliegenden Elementen: no
Bemaßungen - Fläche: 0.255156 m2; Volumen: 0.0247609 m3
IFC-Parameter - In IFC-Datei exportieren: Nach Typ; Pset MEP.Tech-Insulation thickness (mm): 100; Pset MEP.Geom-DN1: 150; Pset MEP.Geom-DN2: 150; Pset MEP.Geom-Length (mm): 286; Pset MEP.Geom-DN3: 125; Pset MEP.Geom-Length outlet (mm): 137; In IFC exportieren als: ifcflowfitting; NameOverride: Abzweigstück; IfcPresentationLayer: 0-TFT-H_Vorlauf; ObjectTypeOverride: Abzweigstück; Pset MEP.Name: Abzweigstück; IfcDescription: Abzweigstück; Pset MEP.Tech-Material: nach DIN 2615; Pset MEP.Geom-Outer Ø1 (mm): 168.3; Pset MEP.Geom-Outer Ø2 (mm): 168.3; Pset MEP.Geom-Outer Ø3 (mm): 139.7
Phasen - Phase erstellt: Phase 01

# IfcFlowFitting: Abzweigstück 320975:Abzweigstück 320975, Abzweigstück
In: 1. Obergeschoss
Type - Material: IfcSurfaceStyle #1741
Type - Andere - Kategorie: Allgemeines Modell; Familienname: Abzweigstück 320975
Type - ID-Daten - Typname: Abzweigstück 320975
Type - IFC-Parameter - Typ in IFC-Datei exportieren: Vorgabe
Description: Abzweigstück
Pset_DistributionFlowElementCommon - Reference: Abzweigstück 320975; sets with these values: 2
Andere - Typ: Abzweigstück 320975; Familie: Abzweigstück 320975; Familie und Typ: Abzweigstück 320975: Abzweigstück 320975; Typ-ID: 2535565
Abhängigkeiten - Höhe von Ebene: 0 m; Verschieben mit umliegenden Elementen: no
Bemaßungen - Fläche: 0.375346 m2; Volumen: 0.041967 m3
IFC-Parameter - In IFC-Datei exportieren: Nach Typ; Pset MEP.Tech-Insulation thickness (mm): 100; Pset MEP.Geom-DN1: 200; Pset MEP.Geom-DN2: 200; Pset MEP.Geom-DN3: 150; Pset MEP.Geom-Length outlet (mm): 168; In IFC exportieren als: ifcflowfitting; NameOverride: Abzweigstück; IfcPresentationLayer: 0-TFT-H_Ruecklauf; ObjectTypeOverride: Abzweigstück; Pset MEP.Name: Abzweigstück; IfcDescription: Abzweigstück; Pset MEP.Tech-Material: nach DIN 2615; Pset MEP.Geom-Outer Ø1 (mm): 219.1; Pset MEP.Geom-Outer Ø2 (mm): 219.1; Pset MEP.Geom-Length (mm): 356; Pset MEP.Geom-Outer Ø3 (mm): 168.3
Phasen - Phase erstellt: Phase 01

# IfcFlowFitting: Abzweigstück 327061:Abzweigstück 327061, Abzweigstück
In: Erdgeschoss
Type - Material: IfcSurfaceStyle #9317
Type - Andere - Kategorie: Allgemeines Modell; Familienname: Abzweigstück 327061
Type - ID-Daten - Typname: Abzweigstück 327061
Type - IFC-Parameter - Typ in IFC-Datei exportieren: Vorgabe
Description: Abzweigstück
Pset_DistributionFlowElementCommon - Reference: Abzweigstück 327061; sets with these values: 2
Andere - Typ: Abzweigstück 327061; Familie: Abzweigstück 327061; Familie und Typ: Abzweigstück 327061: Abzweigstück 327061; Typ-ID: 2535649
Abhängigkeiten - Höhe von Ebene: 0 m; Verschieben mit umliegenden Elementen: no
Bemaßungen - Fläche: 0.152889 m2; Volumen: 0.0125089 m3
IFC-Parameter - In IFC-Datei exportieren: Nach Typ; Pset MEP.Tech-Insulation thickness (mm): 100; Pset MEP.Geom-DN1: 100; Pset MEP.Geom-DN2: 100; Pset MEP.Geom-DN3: 100; In IFC exportieren als: ifcflowfitting; NameOverride: Abzweigstück; IfcPresentationLayer: 0-TFT-H_Vorlauf; ObjectTypeOverride: Abzweigstück; Pset MEP.Name: Abzweigstück; IfcDescription: Abzweigstück; Pset MEP.Tech-Material: nach DIN 2615; Pset MEP.Geom-Outer Ø1 (mm): 114.3; Pset MEP.Geom-Outer Ø2 (mm): 114.3; Pset MEP.Geom-Length (mm): 210; Pset MEP.Geom-Length outlet (mm): 105; Pset MEP.Geom-Outer Ø3 (mm): 114.3
Phasen - Phase erstellt: Phase 01

# IfcFlowFitting: Abzweigstück 327505:Abzweigstück 327505, Abzweigstück
In: Erdgeschoss
Type - Material: IfcSurfaceStyle #1741
Type - Andere - Kategorie: Allgemeines Modell; Familienname: Abzweigstück 327505
Type - ID-Daten - Typname: Abzweigstück 327505
Type - IFC-Parameter - Typ in IFC-Datei exportieren: Vorgabe
Description: Abzweigstück
Pset_DistributionFlowElementCommon - Reference: Abzweigstück 327505; sets with these values: 2
Andere - Typ: Abzweigstück 327505; Familie: Abzweigstück 327505; Familie und Typ: Abzweigstück 327505: Abzweigstück 327505; Typ-ID: 2535656
Abhängigkeiten - Höhe von Ebene: 0 m; Verschieben mit umliegenden Elementen: no
Bemaßungen - Fläche: 0.152889 m2; Volumen: 0.0125089 m3
IFC-Parameter - In IFC-Datei exportieren: Nach Typ; Pset MEP.Tech-Insulation thickness (mm): 100; Pset MEP.Geom-DN1: 100; Pset MEP.Geom-DN2: 100; Pset MEP.Geom-DN3: 100; Pset MEP.Geom-Length (mm): 210; Pset MEP.Geom-Length outlet (mm): 105; In IFC exportieren als: ifcflowfitting; NameOverride: Abzweigstück; IfcPresentationLayer: 0-TFT-H_Ruecklauf; ObjectTypeOverride: Abzweigstück; Pset MEP.Name: Abzweigstück; IfcDescription: Abzweigstück; Pset MEP.Tech-Material: nach DIN 2615; Pset MEP.Geom-Outer Ø1 (mm): 114.3; Pset MEP.Geom-Outer Ø2 (mm): 114.3; Pset MEP.Geom-Outer Ø3 (mm): 114.3
Phasen - Phase erstellt: Phase 01

# IfcFlowFitting: Abzweigstück 331504:Abzweigstück 331504, Abzweigstück
In: Erdgeschoss
Type - Material: IfcSurfaceStyle #9317
Type - Andere - Kategorie: Allgemeines Modell; Familienname: Abzweigstück 331504
Type - ID-Daten - Typname: Abzweigstück 331504
Type - IFC-Parameter - Typ in IFC-Datei exportieren: Vorgabe
Description: Abzweigstück
Pset_DistributionFlowElementCommon - Reference: Abzweigstück 331504; sets with these values: 2
Andere - Typ: Abzweigstück 331504; Familie: Abzweigstück 331504; Familie und Typ: Abzweigstück 331504: Abzweigstück 331504; Typ-ID: 2535768
Abhängigkeiten - Höhe von Ebene: 0 m; Verschieben mit umliegenden Elementen: no
Bemaßungen - Fläche: 0.107315 m2; Volumen: 0.00820616 m3
IFC-Parameter - In IFC-Datei exportieren: Nach Typ; Pset MEP.Tech-Insulation thickness (mm): 100; Pset MEP.Geom-DN2: 80; Pset MEP.Geom-DN1: 80; Pset MEP.Geom-DN3: 65; In IFC exportieren als: ifcflowfitting; NameOverride: Abzweigstück; IfcPresentationLayer: 0-TFT-H_Vorlauf; ObjectTypeOverride: Abzweigstück; Pset MEP.Name: Abzweigstück; IfcDescription: Abzweigstück; Pset MEP.Tech-Material: nach DIN 2615; Pset MEP.Geom-Outer Ø1 (mm): 88.9; Pset MEP.Geom-Outer Ø2 (mm): 88.9; Pset MEP.Geom-Length (mm): 172; Pset MEP.Geom-Length outlet (mm): 83; Pset MEP.Geom-Outer Ø3 (mm): 76.1
Phasen - Phase erstellt: Phase 01

# IfcFlowFitting: Abzweigstück 340627:Abzweigstück 340627, Abzweigstück
In: Erdgeschoss
Type - Material: IfcSurfaceStyle #9317
Type - Andere - Kategorie: Allgemeines Modell; Familienname: Abzweigstück 340627
Type - ID-Daten - Typname: Abzweigstück 340627
Type - IFC-Parameter - Typ in IFC-Datei exportieren: Vorgabe
Description: Abzweigstück
Pset_DistributionFlowElementCommon - Reference: Abzweigstück 340627; sets with these values: 2
Andere - Typ: Abzweigstück 340627; Familie: Abzweigstück 340627; Familie und Typ: Abzweigstück 340627: Abzweigstück 340627; Typ-ID: 2535887
Abhängigkeiten - Höhe von Ebene: 0 m; Verschieben mit umliegenden Elementen: no
Bemaßungen - Fläche: 0.255156 m2; Volumen: 0.0247609 m3
IFC-Parameter - In IFC-Datei exportieren: Nach Typ; Pset MEP.Tech-Insulation thickness (mm): 100; Pset MEP.Geom-DN1: 150; Pset MEP.Geom-DN2: 150; Pset MEP.Geom-Length (mm): 286; Pset MEP.Geom-DN3: 125; Pset MEP.Geom-Length outlet (mm): 137; In IFC exportieren als: ifcflowfitting; NameOverride: Abzweigstück; IfcPresentationLayer: 0-TFT-H_Vorlauf; ObjectTypeOverride: Abzweigstück; Pset MEP.Name: Abzweigstück; IfcDescription: Abzweigstück; Pset MEP.Tech-Material: nach DIN 2615; Pset MEP.Geom-Outer Ø1 (mm): 168.3; Pset MEP.Geom-Outer Ø2 (mm): 168.3; Pset MEP.Geom-Outer Ø3 (mm): 139.7
Phasen - Phase erstellt: Phase 01

# IfcFlowFitting: Abzweigstück 343477:Abzweigstück 343477, Abzweigstück
In: Erdgeschoss
Type - Material: IfcSurfaceStyle #9317
Type - Andere - Kategorie: Allgemeines Modell; Familienname: Abzweigstück 343477
Type - ID-Daten - Typname: Abzweigstück 343477
Type - IFC-Parameter - Typ in IFC-Datei exportieren: Vorgabe
Description: Abzweigstück
Pset_DistributionFlowElementCommon - Reference: Abzweigstück 343477; sets with these values: 2
Andere - Typ: Abzweigstück 343477; Familie: Abzweigstück 343477; Familie und Typ: Abzweigstück 343477: Abzweigstück 343477; Typ-ID: 2536251
Abhängigkeiten - Höhe von Ebene: 0 m; Verschieben mit umliegenden Elementen: no
Bemaßungen - Fläche: 0.375346 m2; Volumen: 0.041967 m3
IFC-Parameter - In IFC-Datei exportieren: Nach Typ; Pset MEP.Tech-Insulation thickness (mm): 100; Pset MEP.Geom-DN1: 200; Pset MEP.Geom-DN2: 200; Pset MEP.Geom-DN3: 150; Pset MEP.Geom-Length outlet (mm): 168; In IFC exportieren als: ifcflowfitting; NameOverride: Abzweigstück; IfcPresentationLayer: 0-TFT-H_Vorlauf; ObjectTypeOverride: Abzweigstück; Pset MEP.Name: Abzweigstück; IfcDescription: Abzweigstück; Pset MEP.Tech-Material: nach DIN 2615; Pset MEP.Geom-Outer Ø1 (mm): 219.1; Pset MEP.Geom-Outer Ø2 (mm): 219.1; Pset MEP.Geom-Length (mm): 356; Pset MEP.Geom-Outer Ø3 (mm): 168.3
Phasen - Phase erstellt: Phase 01

# IfcFlowFitting: Abzweigstück 343500:Abzweigstück 343500, Abzweigstück
In: Erdgeschoss
Type - Material: IfcSurfaceStyle #9317
Type - Andere - Kategorie: Allgemeines Modell; Familienname: Abzweigstück 343500
Type - ID-Daten - Typname: Abzweigstück 343500
Type - IFC-Parameter - Typ in IFC-Datei exportieren: Vorgabe
Description: Abzweigstück
Pset_DistributionFlowElementCommon - Reference: Abzweigstück 343500; sets with these values: 2
Andere - Typ: Abzweigstück 343500; Familie: Abzweigstück 343500; Familie und Typ: Abzweigstück 343500: Abzweigstück 343500; Typ-ID: 2536258
Abhängigkeiten - Höhe von Ebene: 0 m; Verschieben mit umliegenden Elementen: no
Bemaßungen - Fläche: 0.375346 m2; Volumen: 0.041967 m3
IFC-Parameter - In IFC-Datei exportieren: Nach Typ; Pset MEP.Tech-Insulation thickness (mm): 100; Pset MEP.Geom-DN1: 200; Pset MEP.Geom-DN2: 200; Pset MEP.Geom-DN3: 150; Pset MEP.Geom-Length outlet (mm): 168; In IFC exportieren als: ifcflowfitting; NameOverride: Abzweigstück; IfcPresentationLayer: 0-TFT-H_Vorlauf; ObjectTypeOverride: Abzweigstück; Pset MEP.Name: Abzweigstück; IfcDescription: Abzweigstück; Pset MEP.Tech-Material: nach DIN 2615; Pset MEP.Geom-Outer Ø1 (mm): 219.1; Pset MEP.Geom-Outer Ø2 (mm): 219.1; Pset MEP.Geom-Length (mm): 356; Pset MEP.Geom-Outer Ø3 (mm): 168.3
Phasen - Phase erstellt: Phase 01

# IfcFlowFitting: Abzweigstück 345322:Abzweigstück 345322, Abzweigstück
In: Erdgeschoss
Type - Material: IfcSurfaceStyle #9317
Type - Andere - Kategorie: Allgemeines Modell; Familienname: Abzweigstück 345322
Type - ID-Daten - Typname: Abzweigstück 345322
Type - IFC-Parameter - Typ in IFC-Datei exportieren: Vorgabe
Description: Abzweigstück
Pset_DistributionFlowElementCommon - Reference: Abzweigstück 345322; sets with these values: 2
Andere - Typ: Abzweigstück 345322; Familie: Abzweigstück 345322; Familie und Typ: Abzweigstück 345322: Abzweigstück 345322; Typ-ID: 2536321
Abhängigkeiten - Höhe von Ebene: 0 m; Verschieben mit umliegenden Elementen: no
Bemaßungen - Fläche: 0.392022 m2; Volumen: 0.0435045 m3
IFC-Parameter - In IFC-Datei exportieren: Nach Typ; Pset MEP.Tech-Insulation thickness (mm): 100; Pset MEP.Geom-DN1: 200; Pset MEP.Geom-DN2: 200; Pset MEP.Geom-DN3: 200; Pset MEP.Geom-Length outlet (mm): 178; In IFC exportieren als: ifcflowfitting; NameOverride: Abzweigstück; IfcPresentationLayer: 0-TFT-H_Vorlauf; ObjectTypeOverride: Abzweigstück; Pset MEP.Name: Abzweigstück; IfcDescription: Abzweigstück; Pset MEP.Tech-Material: nach DIN 2615; Pset MEP.Geom-Outer Ø1 (mm): 219.1; Pset MEP.Geom-Outer Ø2 (mm): 219.1; Pset MEP.Geom-Length (mm): 356; Pset MEP.Geom-Outer Ø3 (mm): 219.1
Phasen - Phase erstellt: Phase 01

# IfcFlowFitting: Abzweigstück 346827:Abzweigstück 346827, Abzweigstück
In: 1. Obergeschoss
Type - Material: IfcSurfaceStyle #9317
Type - Andere - Kategorie: Allgemeines Modell; Familienname: Abzweigstück 346827
Type - ID-Daten - Typname: Abzweigstück 346827
Type - IFC-Parameter - Typ in IFC-Datei exportieren: Vorgabe
Description: Abzweigstück
Pset_DistributionFlowElementCommon - Reference: Abzweigstück 346827; sets with these values: 2
Andere - Typ: Abzweigstück 346827; Familie: Abzweigstück 346827; Familie und Typ: Abzweigstück 346827: Abzweigstück 346827; Typ-ID: 2536363
Abhängigkeiten - Höhe von Ebene: 0 m; Verschieben mit umliegenden Elementen: no
Bemaßungen - Fläche: 0.392022 m2; Volumen: 0.0435045 m3
IFC-Parameter - In IFC-Datei exportieren: Nach Typ; Pset MEP.Tech-Insulation thickness (mm): 100; Pset MEP.Geom-DN1: 200; Pset MEP.Geom-DN2: 200; Pset MEP.Geom-DN3: 200; Pset MEP.Geom-Length outlet (mm): 178; In IFC exportieren als: ifcflowfitting; NameOverride: Abzweigstück; IfcPresentationLayer: 0-TFT-H_Vorlauf; ObjectTypeOverride: Abzweigstück; Pset MEP.Name: Abzweigstück; IfcDescription: Abzweigstück; Pset MEP.Tech-Material: nach DIN 2615; Pset MEP.Geom-Outer Ø1 (mm): 219.1; Pset MEP.Geom-Outer Ø2 (mm): 219.1; Pset MEP.Geom-Length (mm): 356; Pset MEP.Geom-Outer Ø3 (mm): 219.1
Phasen - Phase erstellt: Phase 01

# IfcFlowFitting: Abzweigstück 347923:Abzweigstück 347923, Abzweigstück
In: 1. Obergeschoss
Type - Material: IfcSurfaceStyle #1741
Type - Andere - Kategorie: Allgemeines Modell; Familienname: Abzweigstück 347923
Type - ID-Daten - Typname: Abzweigstück 347923
Type - IFC-Parameter - Typ in IFC-Datei exportieren: Vorgabe
Description: Abzweigstück
Pset_DistributionFlowElementCommon - Reference: Abzweigstück 347923; sets with these values: 2
Andere - Typ: Abzweigstück 347923; Familie: Abzweigstück 347923; Familie und Typ: Abzweigstück 347923: Abzweigstück 347923; Typ-ID: 2536419
Abhängigkeiten - Höhe von Ebene: 0 m; Verschieben mit umliegenden Elementen: no
Bemaßungen - Fläche: 0.36162 m2; Volumen: 0.0410381 m3
IFC-Parameter - In IFC-Datei exportieren: Nach Typ; Pset MEP.Tech-Insulation thickness (mm): 100; Pset MEP.Geom-DN1: 200; Pset MEP.Geom-DN2: 200; Pset MEP.Geom-DN3: 80; Pset MEP.Geom-Length outlet (mm): 152; In IFC exportieren als: ifcflowfitting; NameOverride: Abzweigstück; IfcPresentationLayer: 0-TFT-H_Ruecklauf; ObjectTypeOverride: Abzweigstück; Pset MEP.Name: Abzweigstück; IfcDescription: Abzweigstück; Pset MEP.Tech-Material: nach DIN 2615; Pset MEP.Geom-Outer Ø1 (mm): 219.1; Pset MEP.Geom-Outer Ø2 (mm): 219.1; Pset MEP.Geom-Length (mm): 356; Pset MEP.Geom-Outer Ø3 (mm): 88.9
Phasen - Phase erstellt: Phase 01

# IfcFlowFitting: Abzweigstück 353086:Abzweigstück 353086, Abzweigstück
In: Erdgeschoss
Type - Material: IfcSurfaceStyle #352577
Type - Andere - Kategorie: Allgemeines Modell; Familienname: Abzweigstück 353086
Type - ID-Daten - Typname: Abzweigstück 353086
Type - IFC-Parameter - Typ in IFC-Datei exportieren: Vorgabe
Description: Abzweigstück
Pset_DistributionFlowElementCommon - Reference: Abzweigstück 353086; sets with these values: 2
Andere - Typ: Abzweigstück 353086; Familie: Abzweigstück 353086; Familie und Typ: Abzweigstück 353086: Abzweigstück 353086; Typ-ID: 2536653
Abhängigkeiten - Höhe von Ebene: 0 m; Verschieben mit umliegenden Elementen: no
Bemaßungen - Fläche: 0.0497368 m2; Volumen: 0.00186618 m3
IFC-Parameter - In IFC-Datei exportieren: Nach Typ; Pset MEP.Geom-DN1: 100; Pset MEP.Geom-DN2: 100; Pset MEP.Geom-DN3: 100; Pset MEP.Geom-Length (mm): 210; Pset MEP.Geom-Length outlet (mm): 105; In IFC exportieren als: ifcflowfitting; NameOverride: Abzweigstück; IfcPresentationLayer: S_Gas; ObjectTypeOverride: Abzweigstück; Pset MEP.Name: Abzweigstück; IfcDescription: Abzweigstück; Pset MEP.Tech-Material: nach DIN 2615; Pset MEP.Geom-Outer Ø1 (mm): 114.3; Pset MEP.Geom-Outer Ø2 (mm): 114.3; Pset MEP.Geom-Outer Ø3 (mm): 114.3
Phasen - Phase erstellt: Phase 01

# IfcFlowFitting: Abzweigstück 604998:Abzweigstück 604998, Abzweigstück
In: Erdgeschoss
Type - Material: IfcSurfaceStyle #352577
Type - Andere - Kategorie: Allgemeines Modell; Familienname: Abzweigstück 604998
Type - ID-Daten - Typname: Abzweigstück 604998
Type - IFC-Parameter - Typ in IFC-Datei exportieren: Vorgabe
Description: Abzweigstück
Pset_DistributionFlowElementCommon - Reference: Abzweigstück 604998; sets with these values: 2
Andere - Typ: Abzweigstück 604998; Familie: Abzweigstück 604998; Familie und Typ: Abzweigstück 604998: Abzweigstück 604998; Typ-ID: 2537318
Abhängigkeiten - Höhe von Ebene: 0 m; Verschieben mit umliegenden Elementen: no
Bemaßungen - Fläche: 0.0242208 m2; Volumen: 0.000605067 m3
IFC-Parameter - In IFC-Datei exportieren: Nach Typ; Pset MEP.Geom-Length (mm): 152; Pset MEP.Geom-DN1: 65; Pset MEP.Geom-DN2: 65; Pset MEP.Geom-DN3: 65; Pset MEP.Geom-Length outlet (mm): 76; In IFC exportieren als: ifcflowfitting; NameOverride: Abzweigstück; IfcPresentationLayer: S_Gas; ObjectTypeOverride: Abzweigstück; Pset MEP.Name: Abzweigstück; IfcDescription: Abzweigstück; Pset MEP.Tech-Material: nach DIN 2615; Pset MEP.Geom-Outer Ø1 (mm): 76.1; Pset MEP.Geom-Outer Ø2 (mm): 76.1; Pset MEP.Geom-Outer Ø3 (mm): 76.1
Phasen - Phase erstellt: Phase 01

# IfcFlowFitting: Abzweigstück 612696:Abzweigstück 612696, Abzweigstück
In: 1. Obergeschoss
Type - Material: IfcSurfaceStyle #9317
Type - Andere - Kategorie: Allgemeines Modell; Familienname: Abzweigstück 612696
Type - ID-Daten - Typname: Abzweigstück 612696
Type - IFC-Parameter - Typ in IFC-Datei exportieren: Vorgabe
Description: Abzweigstück
Pset_DistributionFlowElementCommon - Reference: Abzweigstück 612696; sets with these values: 2
Andere - Typ: Abzweigstück 612696; Familie: Abzweigstück 612696; Familie und Typ: Abzweigstück 612696: Abzweigstück 612696; Typ-ID: 2537612
Abhängigkeiten - Höhe von Ebene: 0 m; Verschieben mit umliegenden Elementen: no
Bemaßungen - Fläche: 0.392022 m2; Volumen: 0.0435045 m3
IFC-Parameter - In IFC-Datei exportieren: Nach Typ; Pset MEP.Tech-Insulation thickness (mm): 100; Pset MEP.Geom-DN1: 200; Pset MEP.Geom-DN2: 200; Pset MEP.Geom-DN3: 200; Pset MEP.Geom-Length outlet (mm): 178; In IFC exportieren als: ifcflowfitting; NameOverride: Abzweigstück; IfcPresentationLayer: 0-TFT-H_Vorlauf; ObjectTypeOverride: Abzweigstück; Pset MEP.Name: Abzweigstück; IfcDescription: Abzweigstück; Pset MEP.Tech-Material: nach DIN 2615; Pset MEP.Geom-Outer Ø1 (mm): 219.1; Pset MEP.Geom-Outer Ø2 (mm): 219.1; Pset MEP.Geom-Length (mm): 356; Pset MEP.Geom-Outer Ø3 (mm): 219.1
Phasen - Phase erstellt: Phase 01

# IfcFlowFitting: Abzweigstück 614428:Abzweigstück 614428, Abzweigstück
In: 1. Obergeschoss
Type - Material: IfcSurfaceStyle #1741
Type - Andere - Kategorie: Allgemeines Modell; Familienname: Abzweigstück 614428
Type - ID-Daten - Typname: Abzweigstück 614428
Type - IFC-Parameter - Typ in IFC-Datei exportieren: Vorgabe
Description: Abzweigstück
Pset_DistributionFlowElementCommon - Reference: Abzweigstück 614428; sets with these values: 2
Andere - Typ: Abzweigstück 614428; Familie: Abzweigstück 614428; Familie und Typ: Abzweigstück 614428: Abzweigstück 614428; Typ-ID: 2537710
Abhängigkeiten - Höhe von Ebene: 0 m; Verschieben mit umliegenden Elementen: no
Bemaßungen - Fläche: 0.375346 m2; Volumen: 0.041967 m3
IFC-Parameter - In IFC-Datei exportieren: Nach Typ; Pset MEP.Tech-Insulation thickness (mm): 100; Pset MEP.Geom-DN1: 200; Pset MEP.Geom-DN2: 200; Pset MEP.Geom-DN3: 150; Pset MEP.Geom-Length outlet (mm): 168; In IFC exportieren als: ifcflowfitting; NameOverride: Abzweigstück; IfcPresentationLayer: 0-TFT-H_Ruecklauf; ObjectTypeOverride: Abzweigstück; Pset MEP.Name: Abzweigstück; IfcDescription: Abzweigstück; Pset MEP.Tech-Material: nach DIN 2615; Pset MEP.Geom-Outer Ø1 (mm): 219.1; Pset MEP.Geom-Outer Ø2 (mm): 219.1; Pset MEP.Geom-Length (mm): 356; Pset MEP.Geom-Outer Ø3 (mm): 168.3
Phasen - Phase erstellt: Phase 01

# IfcFlowFitting: Abzweigstück 848954:Abzweigstück 848954, Abzweigstück
In: Erdgeschoss
Type - Material: IfcSurfaceStyle #352577
Type - Andere - Kategorie: Allgemeines Modell; Familienname: Abzweigstück 848954
Type - ID-Daten - Typname: Abzweigstück 848954
Type - IFC-Parameter - Typ in IFC-Datei exportieren: Vorgabe
Description: Abzweigstück
Pset_DistributionFlowElementCommon - Reference: Abzweigstück 848954; sets with these values: 2
Andere - Typ: Abzweigstück 848954; Familie: Abzweigstück 848954; Familie und Typ: Abzweigstück 848954: Abzweigstück 848954; Typ-ID: 2539029
Abhängigkeiten - Höhe von Ebene: 0 m; Verschieben mit umliegenden Elementen: no
Bemaßungen - Fläche: 0.0428456 m2; Volumen: 0.00154074 m3
IFC-Parameter - In IFC-Datei exportieren: Nach Typ; Pset MEP.Geom-DN1: 100; Pset MEP.Geom-DN2: 100; Pset MEP.Geom-DN3: 65; Pset MEP.Geom-Length (mm): 210; In IFC exportieren als: ifcflowfitting; NameOverride: Abzweigstück; IfcPresentationLayer: S_Gas; ObjectTypeOverride: Abzweigstück; Pset MEP.Name: Abzweigstück; IfcDescription: Abzweigstück; Pset MEP.Tech-Material: nach DIN 2615; Pset MEP.Geom-Outer Ø1 (mm): 114.3; Pset MEP.Geom-Outer Ø2 (mm): 114.3; Pset MEP.Geom-Length outlet (mm): 95; Pset MEP.Geom-Outer Ø3 (mm): 76.1
Phasen - Phase erstellt: Phase 01

# IfcFlowFitting: Abzweigstück 860202:Abzweigstück 860202, Abzweigstück
In: 1. Untergeschoss
Type - Material: IfcSurfaceStyle #1741
Type - Andere - Kategorie: Allgemeines Modell; Familienname: Abzweigstück 860202
Type - ID-Daten - Typname: Abzweigstück 860202
Type - IFC-Parameter - Typ in IFC-Datei exportieren: Vorgabe
Description: Abzweigstück
Pset_DistributionFlowElementCommon - Reference: Abzweigstück 860202; sets with these values: 2
Andere - Typ: Abzweigstück 860202; Familie: Abzweigstück 860202; Familie und Typ: Abzweigstück 860202: Abzweigstück 860202; Typ-ID: 2539576
Abhängigkeiten - Höhe von Ebene: 0 m; Verschieben mit umliegenden Elementen: no
Bemaßungen - Fläche: 0.392022 m2; Volumen: 0.0435045 m3
IFC-Parameter - In IFC-Datei exportieren: Nach Typ; Pset MEP.Tech-Insulation thickness (mm): 100; Pset MEP.Geom-DN1: 200; Pset MEP.Geom-DN2: 200; Pset MEP.Geom-DN3: 200; Pset MEP.Geom-Length outlet (mm): 178; In IFC exportieren als: ifcflowfitting; NameOverride: Abzweigstück; IfcPresentationLayer: 0-TFT-H_Ruecklauf; ObjectTypeOverride: Abzweigstück; Pset MEP.Name: Abzweigstück; IfcDescription: Abzweigstück; Pset MEP.Tech-Material: nach DIN 2615; Pset MEP.Geom-Outer Ø1 (mm): 219.1; Pset MEP.Geom-Outer Ø2 (mm): 219.1; Pset MEP.Geom-Length (mm): 356; Pset MEP.Geom-Outer Ø3 (mm): 219.1
Phasen - Phase erstellt: Phase 01

# IfcFlowFitting: Abzweigstück 860787:Abzweigstück 860787, Abzweigstück
In: 1. Untergeschoss
Type - Material: IfcSurfaceStyle #9317
Type - Andere - Kategorie: Allgemeines Modell; Familienname: Abzweigstück 860787
Type - ID-Daten - Typname: Abzweigstück 860787
Type - IFC-Parameter - Typ in IFC-Datei exportieren: Vorgabe
Description: Abzweigstück
Pset_DistributionFlowElementCommon - Reference: Abzweigstück 860787; sets with these values: 2
Andere - Typ: Abzweigstück 860787; Familie: Abzweigstück 860787; Familie und Typ: Abzweigstück 860787: Abzweigstück 860787; Typ-ID: 2539597
Abhängigkeiten - Höhe von Ebene: 0 m; Verschieben mit umliegenden Elementen: no
Bemaßungen - Fläche: 0.392022 m2; Volumen: 0.0435045 m3
IFC-Parameter - In IFC-Datei exportieren: Nach Typ; Pset MEP.Tech-Insulation thickness (mm): 100; Pset MEP.Geom-DN1: 200; Pset MEP.Geom-DN2: 200; Pset MEP.Geom-DN3: 200; Pset MEP.Geom-Length outlet (mm): 178; In IFC exportieren als: ifcflowfitting; NameOverride: Abzweigstück; IfcPresentationLayer: 0-TFT-H_Vorlauf; ObjectTypeOverride: Abzweigstück; Pset MEP.Name: Abzweigstück; IfcDescription: Abzweigstück; Pset MEP.Tech-Material: nach DIN 2615; Pset MEP.Geom-Outer Ø1 (mm): 219.1; Pset MEP.Geom-Outer Ø2 (mm): 219.1; Pset MEP.Geom-Length (mm): 356; Pset MEP.Geom-Outer Ø3 (mm): 219.1
Phasen - Phase erstellt: Phase 01

# IfcFlowFitting: Abzweigstück 90° 622630:Abzweigstück 90° 622630, Abzweigstück 90°
In: Erdgeschoss
Type - Material: IfcSurfaceStyle #251447
Type - Andere - Kategorie: Allgemeines Modell; Familienname: Abzweigstück 90° 622630
Type - ID-Daten - Typname: Abzweigstück 90° 622630
Type - IFC-Parameter - Typ in IFC-Datei exportieren: Vorgabe
Description: Abzweigstück 90°
Pset_DistributionFlowElementCommon - Reference: Abzweigstück 90° 622630; sets with these values: 2
Andere - Typ: Abzweigstück 90° 622630; Familie: Abzweigstück 90° 622630; Familie und Typ: Abzweigstück 90° 622630: Abzweigstück 90° 622630; Typ-ID: 2538196
Abhängigkeiten - Höhe von Ebene: 0 m; Verschieben mit umliegenden Elementen: no
Bemaßungen - Fläche: 0.454489 m2; Volumen: 0.0596779 m3
IFC-Parameter - In IFC-Datei exportieren: Nach Typ; Pset MEP.Tech-Material (ID): 1; Pset MEP.Geom-Length (mm): 570; Pset MEP.Geom-Ø main (mm): 400; Pset MEP.Geom-Ø secondary (mm): 400; Pset MEP.Angle (°): 90; Pset MEP.Geom-Length branch (mm): 285; Pset MEP.Geom-Ø branch (mm): 400; In IFC exportieren als: ifcflowfitting; NameOverride: Abzweigstück 90°; IfcPresentationLayer: 0-TFT-H_Abgasabführung Variante 1; ObjectTypeOverride: Abzweigstück 90°; Pset MEP.Name: Abzweigstück 90°; IfcDescription: Abzweigstück 90°; Pset MEP.Abbreviation: ATE; Pset MEP.Tech-Medium: L_Entrauchung
Phasen - Phase erstellt: Phase 01

# IfcFlowFitting: Abzweigstück 90° 622808:Abzweigstück 90° 622808, Abzweigstück 90°
In: Erdgeschoss
Type - Material: IfcSurfaceStyle #251447
Type - Andere - Kategorie: Allgemeines Modell; Familienname: Abzweigstück 90° 622808
Type - ID-Daten - Typname: Abzweigstück 90° 622808
Type - IFC-Parameter - Typ in IFC-Datei exportieren: Vorgabe
Description: Abzweigstück 90°
Pset_DistributionFlowElementCommon - Reference: Abzweigstück 90° 622808; sets with these values: 2
Andere - Typ: Abzweigstück 90° 622808; Familie: Abzweigstück 90° 622808; Familie und Typ: Abzweigstück 90° 622808: Abzweigstück 90° 622808; Typ-ID: 2538210
Abhängigkeiten - Höhe von Ebene: 0 m; Verschieben mit umliegenden Elementen: no
Bemaßungen - Fläche: 0.454489 m2; Volumen: 0.0596779 m3
IFC-Parameter - In IFC-Datei exportieren: Nach Typ; Pset MEP.Tech-Material (ID): 1; Pset MEP.Geom-Length (mm): 570; Pset MEP.Geom-Ø main (mm): 400; Pset MEP.Geom-Ø secondary (mm): 400; Pset MEP.Angle (°): 90; Pset MEP.Geom-Length branch (mm): 285; Pset MEP.Geom-Ø branch (mm): 400; In IFC exportieren als: ifcflowfitting; NameOverride: Abzweigstück 90°; IfcPresentationLayer: 0-TFT-H_Abgasabführung Variante 1; ObjectTypeOverride: Abzweigstück 90°; Pset MEP.Name: Abzweigstück 90°; IfcDescription: Abzweigstück 90°; Pset MEP.Abbreviation: ATE; Pset MEP.Tech-Medium: L_Entrauchung
Phasen - Phase erstellt: Phase 01

# IfcFlowFitting: Abzweigstück 90°:Abzweigstück 90°, Abzweigstück 90°
In: Erdgeschoss
Type - Material: IfcSurfaceStyle #251447
Type - Andere - Kategorie: Allgemeines Modell; Familienname: Abzweigstück 90°
Type - ID-Daten - Typname: Abzweigstück 90°
Type - IFC-Parameter - Typ in IFC-Datei exportieren: Vorgabe
Description: Abzweigstück 90°
Pset_DistributionFlowElementCommon - Reference: Abzweigstück 90°; sets with these values: 2
Andere - Typ: Abzweigstück 90°; Familie: Abzweigstück 90°; Familie und Typ: Abzweigstück 90°: Abzweigstück 90°; Typ-ID: 2538176
Abhängigkeiten - Höhe von Ebene: 0 m; Verschieben mit umliegenden Elementen: no
Bemaßungen - Fläche: 0.454489 m2; Volumen: 0.0596779 m3
IFC-Parameter - In IFC-Datei exportieren: Nach Typ; Pset MEP.Tech-Material (ID): 1; In IFC exportieren als: ifcflowfitting; NameOverride: Abzweigstück 90°; IfcPresentationLayer: 0-TFT-H_Abgasabführung Variante 1; ObjectTypeOverride: Abzweigstück 90°; Pset MEP.Name: Abzweigstück 90°; IfcDescription: Abzweigstück 90°; Pset MEP.Geom-Length (mm): 570; Pset MEP.Abbreviation: ATE; Pset MEP.Tech-Medium: L_Entrauchung; Pset MEP.Geom-Ø main (mm): 400; Pset MEP.Geom-Ø secondary (mm): 400; Pset MEP.Angle (°): 90; Pset MEP.Geom-Length branch (mm): 285; Pset MEP.Geom-Ø branch (mm): 400
Phasen - Phase erstellt: Phase 01

# IfcFlowFitting: Abzweigstück:Abzweigstück, Abzweigstück
In: 1. Obergeschoss
Type - Material: IfcSurfaceStyle #9317
Type - Andere - Kategorie: Allgemeines Modell; Familienname: Abzweigstück
Type - ID-Daten - Typname: Abzweigstück
Type - IFC-Parameter - Typ in IFC-Datei exportieren: Vorgabe
Description: Abzweigstück
Pset_DistributionFlowElementCommon - Reference: Abzweigstück; sets with these values: 2
Andere - Typ: Abzweigstück; Familie: Abzweigstück; Familie und Typ: Abzweigstück: Abzweigstück; Typ-ID: 2531548
Abhängigkeiten - Höhe von Ebene: 0 m; Verschieben mit umliegenden Elementen: no
Bemaßungen - Fläche: 0.263294 m2; Volumen: 0.0253543 m3
IFC-Parameter - In IFC-Datei exportieren: Nach Typ; Pset MEP.Tech-Insulation thickness (mm): 100; Pset MEP.Geom-DN1: 150; In IFC exportieren als: ifcflowfitting; NameOverride: Abzweigstück; IfcPresentationLayer: 0-TFT-H_Vorlauf; ObjectTypeOverride: Abzweigstück; Pset MEP.Name: Abzweigstück; IfcDescription: Abzweigstück; Pset MEP.Tech-Material: nach DIN 2615; Pset MEP.Geom-DN2: 150; Pset MEP.Geom-Outer Ø1 (mm): 168.3; Pset MEP.Geom-Outer Ø2 (mm): 168.3; Pset MEP.Geom-Length (mm): 286; Pset MEP.Geom-DN3: 150; Pset MEP.Geom-Length outlet (mm): 143; Pset MEP.Geom-Outer Ø3 (mm): 168.3
Phasen - Phase erstellt: Phase 01

# IfcFlowFitting: Bodenwasserablauf:Bodenwasserablauf, Bodenwasserablauf
In: 1. Untergeschoss
Type - Material: IfcSurfaceStyle #850376
Type - Andere - Kategorie: Allgemeines Modell; Familienname: Bodenwasserablauf
Type - ID-Daten - Typname: Bodenwasserablauf
Type - IFC-Parameter - Typ in IFC-Datei exportieren: Vorgabe
Description: Bodenwasserablauf
Pset_DistributionFlowElementCommon - Reference: Bodenwasserablauf; sets with these values: 2
Andere - Typ: Bodenwasserablauf; Familie: Bodenwasserablauf; Familie und Typ: Bodenwasserablauf: Bodenwasserablauf; Typ-ID: 2539092
Abhängigkeiten - Höhe von Ebene: 0 m; Verschieben mit umliegenden Elementen: no
Bemaßungen - Fläche: 0.0242735 m2; Volumen: 0.000432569 m3
IFC-Parameter - In IFC-Datei exportieren: Nach Typ; In IFC exportieren als: ifcflowfitting; NameOverride: Bodenwasserablauf; IfcPresentationLayer: 0-TFT-S_Schmutzwasser; ObjectTypeOverride: Bodenwasserablauf; Pset MEP.Name: Bodenwasserablauf; IfcDescription: Bodenwasserablauf; Pset MEP.Geom-DN: 60; Pset MEP.Tech-Medium: S_Schmutzwasser
Phasen - Phase erstellt: Phase 01

# IfcFlowFitting: Bogen asymmetrisch 272380:Bogen asymmetrisch 272380, Bogen asymmetrisch
In: 1. Obergeschoss
Type - Material: IfcSurfaceStyle #271571
Type - Andere - Kategorie: Allgemeines Modell; Familienname: Bogen asymmetrisch 272380
Type - ID-Daten - Typname: Bogen asymmetrisch 272380
Type - IFC-Parameter - Typ in IFC-Datei exportieren: Vorgabe
Description: Bogen asymmetrisch
Pset_DistributionFlowElementCommon - Reference: Bogen asymmetrisch 272380; sets with these values: 2
Andere - Typ: Bogen asymmetrisch 272380; Familie: Bogen asymmetrisch 272380; Familie und Typ: Bogen asymmetrisch 272380: Bogen asymmetrisch 272380; Typ-ID: 2533516
Abhängigkeiten - Höhe von Ebene: 0 m; Verschieben mit umliegenden Elementen: no
Bemaßungen - Fläche: 4.10182 m2; Volumen: 1.82415 m3
IFC-Parameter - In IFC-Datei exportieren: Nach Typ; Pset MEP.Tech-Material (ID): 1; Pset MEP.Geom-Angle (°): 90; Pset MEP.Geom-Radius (mm): 50; Pset MEP.Geom-Side 1 (mm): 1500; In IFC exportieren als: ifcflowfitting; NameOverride: Bogen asymmetrisch; IfcPresentationLayer: 0-TFT-L_Abluft; ObjectTypeOverride: Bogen asymmetrisch; Pset MEP.Geom-Surface (m2): 15.6461; Pset MEP.Name: Bogen asymmetrisch; IfcDescription: Bogen asymmetrisch; Pset MEP.Abbreviation: BA; Pset MEP.Tech-Medium: L_Abluft; Pset MEP.Geom-Side 2 (mm): 1530; Pset MEP.Geom-Thickness (mm): 1500; Pset MEP.Tech-Weight (kg): 125.168
Phasen - Phase erstellt: Phase 01

# IfcFlowFitting: Bogen asymmetrisch 272668:Bogen asymmetrisch 272668, Bogen asymmetrisch
In: Erdgeschoss
Type - Material: IfcSurfaceStyle #271571
Type - Andere - Kategorie: Allgemeines Modell; Familienname: Bogen asymmetrisch 272668
Type - ID-Daten - Typname: Bogen asymmetrisch 272668
Type - IFC-Parameter - Typ in IFC-Datei exportieren: Vorgabe
Description: Bogen asymmetrisch
Pset_DistributionFlowElementCommon - Reference: Bogen asymmetrisch 272668; sets with these values: 2
Andere - Typ: Bogen asymmetrisch 272668; Familie: Bogen asymmetrisch 272668; Familie und Typ: Bogen asymmetrisch 272668: Bogen asymmetrisch 272668; Typ-ID: 2533523
Abhängigkeiten - Höhe von Ebene: 0 m; Verschieben mit umliegenden Elementen: no
Bemaßungen - Fläche: 0.939337 m2; Volumen: 0.621667 m3
IFC-Parameter - In IFC-Datei exportieren: Nach Typ; Pset MEP.Tech-Material (ID): 1; Pset MEP.Geom-Radius (mm): 50; Pset MEP.Geom-Side 1 (mm): 1500; Pset MEP.Geom-Side 2 (mm): 1530; Pset MEP.Geom-Thickness (mm): 1500; In IFC exportieren als: ifcflowfitting; NameOverride: Bogen asymmetrisch; IfcPresentationLayer: 0-TFT-L_Abluft; ObjectTypeOverride: Bogen asymmetrisch; Pset MEP.Geom-Surface (m2): 3.11268; Pset MEP.Name: Bogen asymmetrisch; IfcDescription: Bogen asymmetrisch; Pset MEP.Abbreviation: BA; Pset MEP.Tech-Medium: L_Abluft; Pset MEP.Geom-Angle (°): 15; Pset MEP.Tech-Weight (kg): 24.9014
Phasen - Phase erstellt: Phase 01

# IfcFlowFitting: Bogen asymmetrisch 273239:Bogen asymmetrisch 273239, Bogen asymmetrisch
In: Erdgeschoss
Type - Material: IfcSurfaceStyle #271263
Type - Andere - Kategorie: Allgemeines Modell; Familienname: Bogen asymmetrisch 273239
Type - ID-Daten - Typname: Bogen asymmetrisch 273239
Type - IFC-Parameter - Typ in IFC-Datei exportieren: Vorgabe
Description: Bogen asymmetrisch
Pset_DistributionFlowElementCommon - Reference: Bogen asymmetrisch 273239; sets with these values: 2
Andere - Typ: Bogen asymmetrisch 273239; Familie: Bogen asymmetrisch 273239; Familie und Typ: Bogen asymmetrisch 273239: Bogen asymmetrisch 273239; Typ-ID: 2533551
Abhängigkeiten - Höhe von Ebene: 0 m; Verschieben mit umliegenden Elementen: no
Bemaßungen - Fläche: 0.948696 m2; Volumen: 0.329785 m3
IFC-Parameter - In IFC-Datei exportieren: Nach Typ; Pset MEP.Tech-Material (ID): 1; Pset MEP.Geom-Radius (mm): 50; Pset MEP.Geom-Thickness (mm): 1530; Pset MEP.Geom-Side 2 (mm): 1500; Pset MEP.Geom-Angle (°): 15; Pset MEP.Geom-Side 1 (mm): 1530; In IFC exportieren als: ifcflowfitting; NameOverride: Bogen asymmetrisch; IfcPresentationLayer: 0-TFT-L_Zuluft; ObjectTypeOverride: Bogen asymmetrisch; Pset MEP.Geom-Surface (m2): 3.1435; Pset MEP.Name: Bogen asymmetrisch; IfcDescription: Bogen asymmetrisch; Pset MEP.Abbreviation: BA; Pset MEP.Tech-Medium: L_Zuluft; Pset MEP.Tech-Weight (kg): 25.148
Phasen - Phase erstellt: Phase 01

# IfcFlowFitting: Bogen asymmetrisch 273551:Bogen asymmetrisch 273551, Bogen asymmetrisch
In: 1. Obergeschoss
Type - Material: IfcSurfaceStyle #271263
Type - Andere - Kategorie: Allgemeines Modell; Familienname: Bogen asymmetrisch 273551
Type - ID-Daten - Typname: Bogen asymmetrisch 273551
Type - IFC-Parameter - Typ in IFC-Datei exportieren: Vorgabe
Description: Bogen asymmetrisch
Pset_DistributionFlowElementCommon - Reference: Bogen asymmetrisch 273551; sets with these values: 2
Andere - Typ: Bogen asymmetrisch 273551; Familie: Bogen asymmetrisch 273551; Familie und Typ: Bogen asymmetrisch 273551: Bogen asymmetrisch 273551; Typ-ID: 2533572
Abhängigkeiten - Höhe von Ebene: 0 m; Verschieben mit umliegenden Elementen: no
Bemaßungen - Fläche: 5.37537 m2; Volumen: 2.6957 m3
IFC-Parameter - In IFC-Datei exportieren: Nach Typ; Pset MEP.Tech-Material (ID): 1; Pset MEP.Geom-Angle (°): 90; Pset MEP.Geom-Radius (mm): 50; Pset MEP.Geom-Side 2 (mm): 1500; Pset MEP.Geom-Side 1 (mm): 1530; In IFC exportieren als: ifcflowfitting; NameOverride: Bogen asymmetrisch; IfcPresentationLayer: 0-TFT-L_Zuluft; ObjectTypeOverride: Bogen asymmetrisch; Pset MEP.Geom-Surface (m2): 20.4586; Pset MEP.Name: Bogen asymmetrisch; IfcDescription: Bogen asymmetrisch; Pset MEP.Abbreviation: BA; Pset MEP.Tech-Medium: L_Zuluft; Pset MEP.Geom-Thickness (mm): 2432; Pset MEP.Tech-Weight (kg): 180.036
Phasen - Phase erstellt: Phase 01

# IfcFlowFitting: Bogen asymmetrisch 273840:Bogen asymmetrisch 273840, Bogen asymmetrisch
In: 1. Obergeschoss
Type - Material: IfcSurfaceStyle #271263
Type - Andere - Kategorie: Allgemeines Modell; Familienname: Bogen asymmetrisch 273840
Type - ID-Daten - Typname: Bogen asymmetrisch 273840
Type - IFC-Parameter - Typ in IFC-Datei exportieren: Vorgabe
Description: Bogen asymmetrisch
Pset_DistributionFlowElementCommon - Reference: Bogen asymmetrisch 273840; sets with these values: 2
Andere - Typ: Bogen asymmetrisch 273840; Familie: Bogen asymmetrisch 273840; Familie und Typ: Bogen asymmetrisch 273840: Bogen asymmetrisch 273840; Typ-ID: 2533579
Abhängigkeiten - Höhe von Ebene: 0 m; Verschieben mit umliegenden Elementen: no
Bemaßungen - Fläche: 5.03958 m2; Volumen: 2.0794 m3
IFC-Parameter - In IFC-Datei exportieren: Nach Typ; Pset MEP.Tech-Material (ID): 1; Pset MEP.Geom-Angle (°): 90; Pset MEP.Geom-Radius (mm): 50; Pset MEP.Geom-Thickness (mm): 1500; In IFC exportieren als: ifcflowfitting; NameOverride: Bogen asymmetrisch; IfcPresentationLayer: 0-TFT-L_Zuluft; ObjectTypeOverride: Bogen asymmetrisch; Pset MEP.Geom-Surface (m2): 31.4459; Pset MEP.Name: Bogen asymmetrisch; IfcDescription: Bogen asymmetrisch; Pset MEP.Abbreviation: BA; Pset MEP.Tech-Medium: L_Zuluft; Pset MEP.Geom-Side 1 (mm): 1000; Pset MEP.Geom-Side 2 (mm): 2432; Pset MEP.Tech-Weight (kg): 276.724
Phasen - Phase erstellt: Phase 01

# IfcFlowFitting: Bogen asymmetrisch 275258:Bogen asymmetrisch 275258, Bogen asymmetrisch
In: 1. Obergeschoss
Type - Material: IfcSurfaceStyle #271184
Type - Andere - Kategorie: Allgemeines Modell; Familienname: Bogen asymmetrisch 275258
Type - ID-Daten - Typname: Bogen asymmetrisch 275258
Type - IFC-Parameter - Typ in IFC-Datei exportieren: Vorgabe
Description: Bogen asymmetrisch
Pset_DistributionFlowElementCommon - Reference: Bogen asymmetrisch 275258; sets with these values: 2
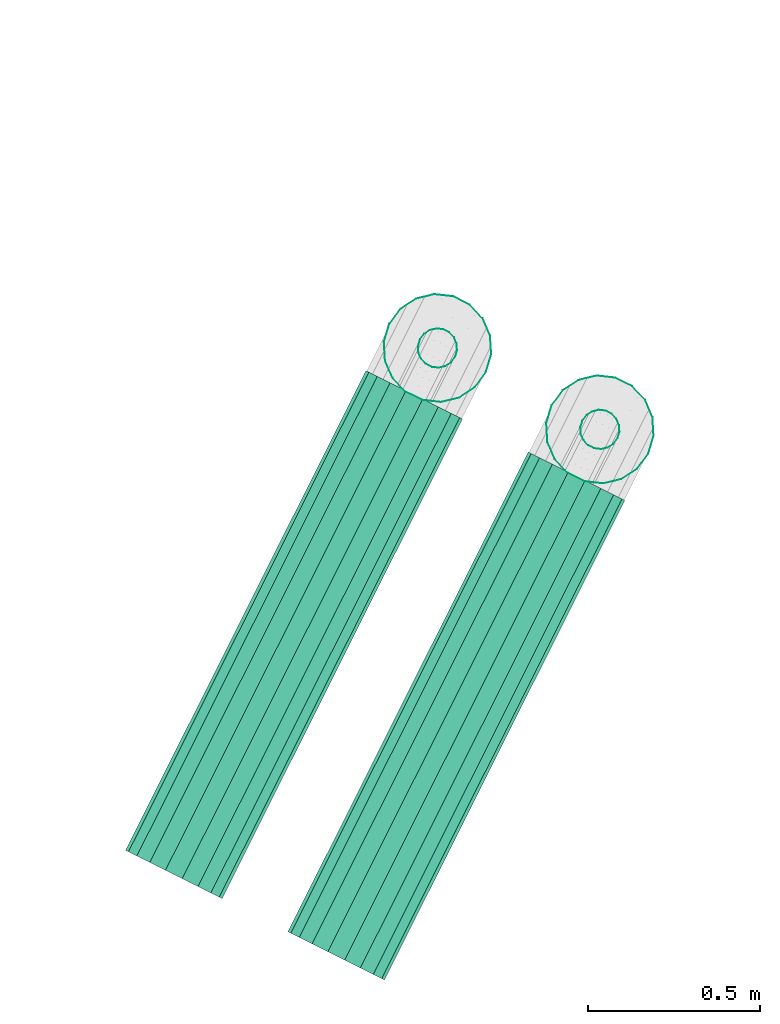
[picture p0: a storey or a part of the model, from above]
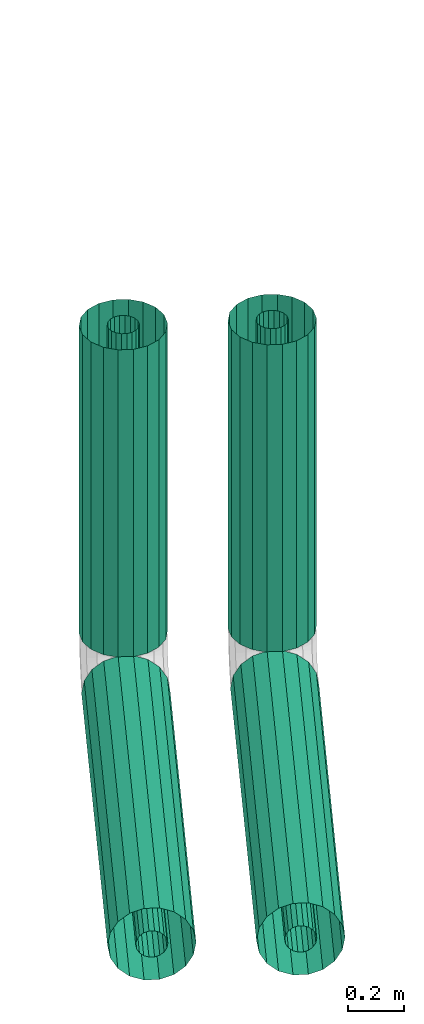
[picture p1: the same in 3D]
Properties of the parts of a building model (IFC2X3), part 7 of 23

# IfcFlowFitting: Bogen asymmetrisch 275258:Bogen asymmetrisch 275258, Bogen asymmetrisch
Andere - Typ: Bogen asymmetrisch 275258; Familie: Bogen asymmetrisch 275258; Familie und Typ: Bogen asymmetrisch 275258: Bogen asymmetrisch 275258; Typ-ID: 2533738
Abhängigkeiten - Höhe von Ebene: 0 m; Verschieben mit umliegenden Elementen: no
Bemaßungen - Fläche: 3.40214 m2; Volumen: 1.40442 m3
IFC-Parameter - In IFC-Datei exportieren: Nach Typ; Pset MEP.Tech-Material (ID): 1; Pset MEP.Geom-Angle (°): 90; Pset MEP.Geom-Radius (mm): 50; In IFC exportieren als: ifcflowfitting; NameOverride: Bogen asymmetrisch; IfcPresentationLayer: 0-TFT-L_Aussenluft; ObjectTypeOverride: Bogen asymmetrisch; Pset MEP.Geom-Surface (m2): 14.4889; Pset MEP.Name: Bogen asymmetrisch; IfcDescription: Bogen asymmetrisch; Pset MEP.Abbreviation: BA; Pset MEP.Tech-Medium: L_Aussenluft; Pset MEP.Geom-Side 1 (mm): 1242; Pset MEP.Geom-Side 2 (mm): 900; Pset MEP.Geom-Thickness (mm): 2160; Pset MEP.Tech-Weight (kg): 127.502
Phasen - Phase erstellt: Phase 01

# IfcFlowFitting: Bogen asymmetrisch 275561:Bogen asymmetrisch 275561, Bogen asymmetrisch
In: 1. Obergeschoss
Type - Material: IfcSurfaceStyle #271184
Type - Andere - Kategorie: Allgemeines Modell; Familienname: Bogen asymmetrisch 275561
Type - ID-Daten - Typname: Bogen asymmetrisch 275561
Type - IFC-Parameter - Typ in IFC-Datei exportieren: Vorgabe
Description: Bogen asymmetrisch
Pset_DistributionFlowElementCommon - Reference: Bogen asymmetrisch 275561; sets with these values: 2
Andere - Typ: Bogen asymmetrisch 275561; Familie: Bogen asymmetrisch 275561; Familie und Typ: Bogen asymmetrisch 275561: Bogen asymmetrisch 275561; Typ-ID: 2533745
Abhängigkeiten - Höhe von Ebene: 0 m; Verschieben mit umliegenden Elementen: no
Bemaßungen - Fläche: 4.20256 m2; Volumen: 1.42994 m3
IFC-Parameter - In IFC-Datei exportieren: Nach Typ; Pset MEP.Tech-Material (ID): 1; Pset MEP.Geom-Angle (°): 90; Pset MEP.Geom-Radius (mm): 50; In IFC exportieren als: ifcflowfitting; NameOverride: Bogen asymmetrisch; IfcPresentationLayer: 0-TFT-L_Aussenluft; ObjectTypeOverride: Bogen asymmetrisch; Pset MEP.Geom-Surface (m2): 21.8573; Pset MEP.Name: Bogen asymmetrisch; IfcDescription: Bogen asymmetrisch; Pset MEP.Abbreviation: BA; Pset MEP.Tech-Medium: L_Aussenluft; Pset MEP.Geom-Side 1 (mm): 2160; Pset MEP.Geom-Side 2 (mm): 1300; Pset MEP.Geom-Thickness (mm): 900; Pset MEP.Tech-Weight (kg): 192.345
Phasen - Phase erstellt: Phase 01

# IfcFlowFitting: Bogen asymmetrisch 276275:Bogen asymmetrisch 276275, Bogen asymmetrisch
In: 1. Obergeschoss
Type - Material: IfcSurfaceStyle #274455
Type - Andere - Kategorie: Allgemeines Modell; Familienname: Bogen asymmetrisch 276275
Type - ID-Daten - Typname: Bogen asymmetrisch 276275
Type - IFC-Parameter - Typ in IFC-Datei exportieren: Vorgabe
Description: Bogen asymmetrisch
Pset_DistributionFlowElementCommon - Reference: Bogen asymmetrisch 276275; sets with these values: 2
Andere - Typ: Bogen asymmetrisch 276275; Familie: Bogen asymmetrisch 276275; Familie und Typ: Bogen asymmetrisch 276275: Bogen asymmetrisch 276275; Typ-ID: 2533787
Abhängigkeiten - Höhe von Ebene: 0 m; Verschieben mit umliegenden Elementen: no
Bemaßungen - Fläche: 4.34563 m2; Volumen: 2.0136 m3
IFC-Parameter - In IFC-Datei exportieren: Nach Typ; Pset MEP.Tech-Material (ID): 1; Pset MEP.Geom-Angle (°): 90; Pset MEP.Geom-Radius (mm): 50; Pset MEP.Geom-Side 1 (mm): 1000; In IFC exportieren als: ifcflowfitting; NameOverride: Bogen asymmetrisch; IfcPresentationLayer: 0-TFT-L_Fortluft; ObjectTypeOverride: Bogen asymmetrisch; Pset MEP.Geom-Surface (m2): 19.6305; Pset MEP.Name: Bogen asymmetrisch; IfcDescription: Bogen asymmetrisch; Pset MEP.Abbreviation: BA; Pset MEP.Tech-Medium: L_Fortluft; Pset MEP.Geom-Side 2 (mm): 1514; Pset MEP.Geom-Thickness (mm): 2325; Pset MEP.Tech-Weight (kg): 172.749
Phasen - Phase erstellt: Phase 01

# IfcFlowFitting: Bogen asymmetrisch 276563:Bogen asymmetrisch 276563, Bogen asymmetrisch
In: 1. Obergeschoss
Type - Material: IfcSurfaceStyle #274455
Type - Andere - Kategorie: Allgemeines Modell; Familienname: Bogen asymmetrisch 276563
Type - ID-Daten - Typname: Bogen asymmetrisch 276563
Type - IFC-Parameter - Typ in IFC-Datei exportieren: Vorgabe
Description: Bogen asymmetrisch
Pset_DistributionFlowElementCommon - Reference: Bogen asymmetrisch 276563; sets with these values: 2
Andere - Typ: Bogen asymmetrisch 276563; Familie: Bogen asymmetrisch 276563; Familie und Typ: Bogen asymmetrisch 276563: Bogen asymmetrisch 276563; Typ-ID: 2533794
Abhängigkeiten - Höhe von Ebene: 0 m; Verschieben mit umliegenden Elementen: no
Bemaßungen - Fläche: 4.03019 m2; Volumen: 1.32563 m3
IFC-Parameter - In IFC-Datei exportieren: Nach Typ; Pset MEP.Tech-Material (ID): 1; Pset MEP.Geom-Angle (°): 90; Pset MEP.Geom-Radius (mm): 50; Pset MEP.Geom-Side 1 (mm): 1000; Pset MEP.Geom-Thickness (mm): 1000; In IFC exportieren als: ifcflowfitting; NameOverride: Bogen asymmetrisch; IfcPresentationLayer: 0-TFT-L_Fortluft; ObjectTypeOverride: Bogen asymmetrisch; Pset MEP.Geom-Surface (m2): 25.4738; Pset MEP.Name: Bogen asymmetrisch; IfcDescription: Bogen asymmetrisch; Pset MEP.Abbreviation: BA; Pset MEP.Tech-Medium: L_Fortluft; Pset MEP.Geom-Side 2 (mm): 2325; Pset MEP.Tech-Weight (kg): 224.169
Phasen - Phase erstellt: Phase 01

# IfcFlowFitting: Bogen asymmetrisch 851641:Bogen asymmetrisch 851641, Bogen asymmetrisch
In: Erdgeschoss
Type - Material: IfcSurfaceStyle #271263
Type - Andere - Kategorie: Allgemeines Modell; Familienname: Bogen asymmetrisch 851641
Type - ID-Daten - Typname: Bogen asymmetrisch 851641
Type - IFC-Parameter - Typ in IFC-Datei exportieren: Vorgabe
Description: Bogen asymmetrisch
Pset_DistributionFlowElementCommon - Reference: Bogen asymmetrisch 851641; sets with these values: 2
Andere - Typ: Bogen asymmetrisch 851641; Familie: Bogen asymmetrisch 851641; Familie und Typ: Bogen asymmetrisch 851641: Bogen asymmetrisch 851641; Typ-ID: 2539400
Abhängigkeiten - Höhe von Ebene: 0 m; Verschieben mit umliegenden Elementen: no
Bemaßungen - Fläche: 1.10914 m2; Volumen: 0.25021 m3
IFC-Parameter - In IFC-Datei exportieren: Nach Typ; Pset MEP.Tech-Material (ID): 1; Pset MEP.Geom-Angle (°): 90; Pset MEP.Geom-Radius (mm): 50; Pset MEP.Geom-Thickness (mm): 900; In IFC exportieren als: ifcflowfitting; NameOverride: Bogen asymmetrisch; IfcPresentationLayer: 0-TFT-L_Zuluft; ObjectTypeOverride: Bogen asymmetrisch; Pset MEP.Geom-Surface (m2): 4.8796; Pset MEP.Name: Bogen asymmetrisch; IfcDescription: Bogen asymmetrisch; Pset MEP.Abbreviation: BA; Pset MEP.Tech-Medium: L_Zuluft; Pset MEP.Geom-Side 1 (mm): 800; Pset MEP.Geom-Side 2 (mm): 500; Pset MEP.Tech-Weight (kg): 31.2294
Phasen - Phase erstellt: Phase 01

# IfcFlowFitting: Bogen asymmetrisch 852461:Bogen asymmetrisch 852461, Bogen asymmetrisch
In: Erdgeschoss
Type - Material: IfcSurfaceStyle #271571
Type - Andere - Kategorie: Allgemeines Modell; Familienname: Bogen asymmetrisch 852461
Type - ID-Daten - Typname: Bogen asymmetrisch 852461
Type - IFC-Parameter - Typ in IFC-Datei exportieren: Vorgabe
Description: Bogen asymmetrisch
Pset_DistributionFlowElementCommon - Reference: Bogen asymmetrisch 852461; sets with these values: 2
Andere - Typ: Bogen asymmetrisch 852461; Familie: Bogen asymmetrisch 852461; Familie und Typ: Bogen asymmetrisch 852461: Bogen asymmetrisch 852461; Typ-ID: 2539478
Abhängigkeiten - Höhe von Ebene: 0 m; Verschieben mit umliegenden Elementen: no
Bemaßungen - Fläche: 0.939337 m2; Volumen: 0.621667 m3
IFC-Parameter - In IFC-Datei exportieren: Nach Typ; Pset MEP.Tech-Material (ID): 1; Pset MEP.Geom-Radius (mm): 50; Pset MEP.Geom-Side 1 (mm): 1500; Pset MEP.Geom-Side 2 (mm): 1530; Pset MEP.Geom-Thickness (mm): 1500; Pset MEP.Geom-Angle (°): 15; In IFC exportieren als: ifcflowfitting; NameOverride: Bogen asymmetrisch; IfcPresentationLayer: 0-TFT-L_Abluft; ObjectTypeOverride: Bogen asymmetrisch; Pset MEP.Geom-Surface (m2): 3.11268; Pset MEP.Name: Bogen asymmetrisch; IfcDescription: Bogen asymmetrisch; Pset MEP.Abbreviation: BA; Pset MEP.Tech-Medium: L_Abluft; Pset MEP.Tech-Weight (kg): 24.9014
Phasen - Phase erstellt: Phase 01

# IfcFlowFitting: Bogen asymmetrisch 852484:Bogen asymmetrisch 852484, Bogen asymmetrisch
In: Erdgeschoss
Type - Material: IfcSurfaceStyle #271263
Type - Andere - Kategorie: Allgemeines Modell; Familienname: Bogen asymmetrisch 852484
Type - ID-Daten - Typname: Bogen asymmetrisch 852484
Type - IFC-Parameter - Typ in IFC-Datei exportieren: Vorgabe
Description: Bogen asymmetrisch
Pset_DistributionFlowElementCommon - Reference: Bogen asymmetrisch 852484; sets with these values: 2
Andere - Typ: Bogen asymmetrisch 852484; Familie: Bogen asymmetrisch 852484; Familie und Typ: Bogen asymmetrisch 852484: Bogen asymmetrisch 852484; Typ-ID: 2539485
Abhängigkeiten - Höhe von Ebene: 0 m; Verschieben mit umliegenden Elementen: no
Bemaßungen - Fläche: 0.948696 m2; Volumen: 0.329785 m3
IFC-Parameter - In IFC-Datei exportieren: Nach Typ; Pset MEP.Tech-Material (ID): 1; Pset MEP.Geom-Radius (mm): 50; Pset MEP.Geom-Thickness (mm): 1530; Pset MEP.Geom-Side 2 (mm): 1500; Pset MEP.Geom-Angle (°): 15; Pset MEP.Geom-Side 1 (mm): 1530; In IFC exportieren als: ifcflowfitting; NameOverride: Bogen asymmetrisch; IfcPresentationLayer: 0-TFT-L_Zuluft; ObjectTypeOverride: Bogen asymmetrisch; Pset MEP.Geom-Surface (m2): 3.1435; Pset MEP.Name: Bogen asymmetrisch; IfcDescription: Bogen asymmetrisch; Pset MEP.Abbreviation: BA; Pset MEP.Tech-Medium: L_Zuluft; Pset MEP.Tech-Weight (kg): 25.148
Phasen - Phase erstellt: Phase 01

# IfcFlowFitting: Bogen asymmetrisch:Bogen asymmetrisch, Bogen asymmetrisch
In: 1. Obergeschoss
Type - Material: IfcSurfaceStyle #271571
Type - Andere - Kategorie: Allgemeines Modell; Familienname: Bogen asymmetrisch
Type - ID-Daten - Typname: Bogen asymmetrisch
Type - IFC-Parameter - Typ in IFC-Datei exportieren: Vorgabe
Description: Bogen asymmetrisch
Pset_DistributionFlowElementCommon - Reference: Bogen asymmetrisch; sets with these values: 2
Andere - Typ: Bogen asymmetrisch; Familie: Bogen asymmetrisch; Familie und Typ: Bogen asymmetrisch: Bogen asymmetrisch; Typ-ID: 2533489
Abhängigkeiten - Höhe von Ebene: 0 m; Verschieben mit umliegenden Elementen: no
Bemaßungen - Fläche: 6.27604 m2; Volumen: 2.98769 m3
IFC-Parameter - In IFC-Datei exportieren: Nach Typ; Pset MEP.Tech-Material (ID): 1; In IFC exportieren als: ifcflowfitting; NameOverride: Bogen asymmetrisch; IfcPresentationLayer: 0-TFT-L_Abluft; ObjectTypeOverride: Bogen asymmetrisch; Pset MEP.Geom-Surface (m2): 31.6858; Pset MEP.Name: Bogen asymmetrisch; IfcDescription: Bogen asymmetrisch; Pset MEP.Abbreviation: BA; Pset MEP.Tech-Medium: L_Abluft; Pset MEP.Geom-Angle (°): 90; Pset MEP.Geom-Radius (mm): 50; Pset MEP.Geom-Side 1 (mm): 1500; Pset MEP.Geom-Side 2 (mm): 2432; Pset MEP.Geom-Thickness (mm): 1530; Pset MEP.Tech-Weight (kg): 278.835
Phasen - Phase erstellt: Phase 01

# IfcFlowFitting: Bogen symmetrisch 272910:Bogen symmetrisch 272910, Bogen symmetrisch
In: 1. Obergeschoss
Type - Material: IfcSurfaceStyle #271263
Type - Andere - Kategorie: Allgemeines Modell; Familienname: Bogen symmetrisch 272910
Type - ID-Daten - Typname: Bogen symmetrisch 272910
Type - IFC-Parameter - Typ in IFC-Datei exportieren: Vorgabe
Description: Bogen symmetrisch
Pset_DistributionFlowElementCommon - Reference: Bogen symmetrisch 272910; sets with these values: 2
Andere - Typ: Bogen symmetrisch 272910; Familie: Bogen symmetrisch 272910; Familie und Typ: Bogen symmetrisch 272910: Bogen symmetrisch 272910; Typ-ID: 2533537
Abhängigkeiten - Höhe von Ebene: 0 m; Verschieben mit umliegenden Elementen: no
Bemaßungen - Fläche: 4.07186 m2; Volumen: 1.64983 m3
IFC-Parameter - In IFC-Datei exportieren: Nach Typ; Pset MEP.Tech-Material (ID): 1; Pset MEP.Geom-Angle (°): 90; Pset MEP.Geom-Radius (mm): 50; Pset MEP.Geom-Side 1 (mm): 1500; Pset MEP.Geom-Thickness (mm): 1530; Pset MEP.Geom-Side 2 (mm): 1500; In IFC exportieren als: ifcflowfitting; NameOverride: Bogen symmetrisch; IfcPresentationLayer: 0-TFT-L_Zuluft; ObjectTypeOverride: Bogen symmetrisch; Pset MEP.Geom-Surface (m2): 15.3605; Pset MEP.Name: Bogen symmetrisch; IfcDescription: Bogen symmetrisch; Pset MEP.Abbreviation: BS; Pset MEP.Tech-Medium: L_Zuluft; Pset MEP.Tech-Weight (kg): 122.884
Phasen - Phase erstellt: Phase 01

# IfcFlowFitting: Bogen symmetrisch 272938:Bogen symmetrisch 272938, Bogen symmetrisch
In: 1. Obergeschoss
Type - Material: IfcSurfaceStyle #271263
Type - Andere - Kategorie: Allgemeines Modell; Familienname: Bogen symmetrisch 272938
Type - ID-Daten - Typname: Bogen symmetrisch 272938
Type - IFC-Parameter - Typ in IFC-Datei exportieren: Vorgabe
Description: Bogen symmetrisch
Pset_DistributionFlowElementCommon - Reference: Bogen symmetrisch 272938; sets with these values: 2
Andere - Typ: Bogen symmetrisch 272938; Familie: Bogen symmetrisch 272938; Familie und Typ: Bogen symmetrisch 272938: Bogen symmetrisch 272938; Typ-ID: 2533544
Abhängigkeiten - Höhe von Ebene: 0 m; Verschieben mit umliegenden Elementen: no
Bemaßungen - Fläche: 4.14206 m2; Volumen: 1.67709 m3
IFC-Parameter - In IFC-Datei exportieren: Nach Typ; Pset MEP.Tech-Material (ID): 1; Pset MEP.Geom-Angle (°): 90; Pset MEP.Geom-Radius (mm): 50; Pset MEP.Geom-Side 2 (mm): 1530; Pset MEP.Geom-Thickness (mm): 1500; In IFC exportieren als: ifcflowfitting; NameOverride: Bogen symmetrisch; IfcPresentationLayer: 0-TFT-L_Zuluft; ObjectTypeOverride: Bogen symmetrisch; Pset MEP.Geom-Surface (m2): 15.6461; Pset MEP.Name: Bogen symmetrisch; IfcDescription: Bogen symmetrisch; Pset MEP.Abbreviation: BS; Pset MEP.Tech-Medium: L_Zuluft; Pset MEP.Geom-Side 1 (mm): 1530; Pset MEP.Tech-Weight (kg): 125.168
Phasen - Phase erstellt: Phase 01

# IfcFlowFitting: Bogen symmetrisch 274544:Bogen symmetrisch 274544, Bogen symmetrisch
In: 1. Obergeschoss
Type - Material: IfcSurfaceStyle #274455
Type - Andere - Kategorie: Allgemeines Modell; Familienname: Bogen symmetrisch 274544
Type - ID-Daten - Typname: Bogen symmetrisch 274544
Type - IFC-Parameter - Typ in IFC-Datei exportieren: Vorgabe
Description: Bogen symmetrisch
Pset_DistributionFlowElementCommon - Reference: Bogen symmetrisch 274544; sets with these values: 2
Andere - Typ: Bogen symmetrisch 274544; Familie: Bogen symmetrisch 274544; Familie und Typ: Bogen symmetrisch 274544: Bogen symmetrisch 274544; Typ-ID: 2533657
Abhängigkeiten - Höhe von Ebene: 0 m; Verschieben mit umliegenden Elementen: no
Bemaßungen - Fläche: 0.283765 m2; Volumen: 0.082989 m3
IFC-Parameter - In IFC-Datei exportieren: Nach Typ; Pset MEP.Tech-Material (ID): 1; Pset MEP.Geom-Side 1 (mm): 1000; Pset MEP.Geom-Side 2 (mm): 1000; In IFC exportieren als: ifcflowfitting; NameOverride: Bogen symmetrisch; IfcPresentationLayer: 0-TFT-L_Fortluft; ObjectTypeOverride: Bogen symmetrisch; Pset MEP.Geom-Surface (m2): 1; Pset MEP.Name: Bogen symmetrisch; IfcDescription: Bogen symmetrisch; Pset MEP.Abbreviation: BS; Pset MEP.Tech-Medium: L_Fortluft; Pset MEP.Geom-Angle (°): 4; Pset MEP.Geom-Radius (mm): 100; Pset MEP.Geom-Thickness (mm): 1000; Pset MEP.Tech-Weight (kg): 4.52594
Phasen - Phase erstellt: Phase 01

# IfcFlowFitting: Bogen symmetrisch 274813:Bogen symmetrisch 274813, Bogen symmetrisch
In: 1. Obergeschoss
Type - Material: IfcSurfaceStyle #274455
Type - Andere - Kategorie: Allgemeines Modell; Familienname: Bogen symmetrisch 274813
Type - ID-Daten - Typname: Bogen symmetrisch 274813
Type - IFC-Parameter - Typ in IFC-Datei exportieren: Vorgabe
Description: Bogen symmetrisch
Pset_DistributionFlowElementCommon - Reference: Bogen symmetrisch 274813; sets with these values: 2
Andere - Typ: Bogen symmetrisch 274813; Familie: Bogen symmetrisch 274813; Familie und Typ: Bogen symmetrisch 274813: Bogen symmetrisch 274813; Typ-ID: 2533683
Abhängigkeiten - Höhe von Ebene: 0 m; Verschieben mit umliegenden Elementen: no
Bemaßungen - Fläche: 0.283765 m2; Volumen: 0.0829609 m3
IFC-Parameter - In IFC-Datei exportieren: Nach Typ; Pset MEP.Tech-Material (ID): 1; Pset MEP.Geom-Side 1 (mm): 1000; Pset MEP.Geom-Side 2 (mm): 1000; Pset MEP.Geom-Surface (m2): 1; Pset MEP.Geom-Angle (°): 4; Pset MEP.Geom-Radius (mm): 100; Pset MEP.Geom-Thickness (mm): 1000; In IFC exportieren als: ifcflowfitting; NameOverride: Bogen symmetrisch; IfcPresentationLayer: 0-TFT-L_Fortluft; ObjectTypeOverride: Bogen symmetrisch; Pset MEP.Name: Bogen symmetrisch; IfcDescription: Bogen symmetrisch; Pset MEP.Abbreviation: BS; Pset MEP.Tech-Medium: L_Fortluft; Pset MEP.Tech-Weight (kg): 4.52594
Phasen - Phase erstellt: Phase 01

# IfcFlowFitting: Bogen symmetrisch 275929:Bogen symmetrisch 275929, Bogen symmetrisch
In: 1. Obergeschoss
Type - Material: IfcSurfaceStyle #271184
Type - Andere - Kategorie: Allgemeines Modell; Familienname: Bogen symmetrisch 275929
Type - ID-Daten - Typname: Bogen symmetrisch 275929
Type - IFC-Parameter - Typ in IFC-Datei exportieren: Vorgabe
Description: Bogen symmetrisch
Pset_DistributionFlowElementCommon - Reference: Bogen symmetrisch 275929; sets with these values: 2
Andere - Typ: Bogen symmetrisch 275929; Familie: Bogen symmetrisch 275929; Familie und Typ: Bogen symmetrisch 275929: Bogen symmetrisch 275929; Typ-ID: 2533759
Abhängigkeiten - Höhe von Ebene: 0 m; Verschieben mit umliegenden Elementen: no
Bemaßungen - Fläche: 0.325574 m2; Volumen: 0.100131 m3
IFC-Parameter - In IFC-Datei exportieren: Nach Typ; Pset MEP.Tech-Material (ID): 1; Pset MEP.Geom-Surface (m2): 1; Pset MEP.Geom-Radius (mm): 100; Pset MEP.Geom-Side 2 (mm): 900; In IFC exportieren als: ifcflowfitting; NameOverride: Bogen symmetrisch; IfcPresentationLayer: 0-TFT-L_Aussenluft; ObjectTypeOverride: Bogen symmetrisch; Pset MEP.Name: Bogen symmetrisch; IfcDescription: Bogen symmetrisch; Pset MEP.Abbreviation: BS; Pset MEP.Tech-Medium: L_Aussenluft; Pset MEP.Geom-Angle (°): 5; Pset MEP.Geom-Side 1 (mm): 900; Pset MEP.Geom-Thickness (mm): 1300; Pset MEP.Tech-Weight (kg): 6.59178
Phasen - Phase erstellt: Phase 01

# IfcFlowFitting: Bogen symmetrisch 276186:Bogen symmetrisch 276186, Bogen symmetrisch
In: 1. Obergeschoss
Type - Material: IfcSurfaceStyle #271184
Type - Andere - Kategorie: Allgemeines Modell; Familienname: Bogen symmetrisch 276186
Type - ID-Daten - Typname: Bogen symmetrisch 276186
Type - IFC-Parameter - Typ in IFC-Datei exportieren: Vorgabe
Description: Bogen symmetrisch
Pset_DistributionFlowElementCommon - Reference: Bogen symmetrisch 276186; sets with these values: 2
Andere - Typ: Bogen symmetrisch 276186; Familie: Bogen symmetrisch 276186; Familie und Typ: Bogen symmetrisch 276186: Bogen symmetrisch 276186; Typ-ID: 2533773
Abhängigkeiten - Höhe von Ebene: 0 m; Verschieben mit umliegenden Elementen: no
Bemaßungen - Fläche: 0.325574 m2; Volumen: 0.100131 m3
IFC-Parameter - In IFC-Datei exportieren: Nach Typ; Pset MEP.Tech-Material (ID): 1; Pset MEP.Geom-Surface (m2): 1; Pset MEP.Geom-Radius (mm): 100; Pset MEP.Geom-Side 2 (mm): 900; Pset MEP.Geom-Angle (°): 5; Pset MEP.Geom-Side 1 (mm): 900; Pset MEP.Geom-Thickness (mm): 1300; In IFC exportieren als: ifcflowfitting; NameOverride: Bogen symmetrisch; IfcPresentationLayer: 0-TFT-L_Aussenluft; ObjectTypeOverride: Bogen symmetrisch; Pset MEP.Name: Bogen symmetrisch; IfcDescription: Bogen symmetrisch; Pset MEP.Abbreviation: BS; Pset MEP.Tech-Medium: L_Aussenluft; Pset MEP.Tech-Weight (kg): 6.59178
Phasen - Phase erstellt: Phase 01

# IfcFlowFitting: Bogen symmetrisch:Bogen symmetrisch, Bogen symmetrisch
In: 1. Obergeschoss
Type - Material: IfcSurfaceStyle #271571
Type - Andere - Kategorie: Allgemeines Modell; Familienname: Bogen symmetrisch
Type - ID-Daten - Typname: Bogen symmetrisch
Type - IFC-Parameter - Typ in IFC-Datei exportieren: Vorgabe
Description: Bogen symmetrisch
Pset_DistributionFlowElementCommon - Reference: Bogen symmetrisch; sets with these values: 2
Andere - Typ: Bogen symmetrisch; Familie: Bogen symmetrisch; Familie und Typ: Bogen symmetrisch: Bogen symmetrisch; Typ-ID: 2533509
Abhängigkeiten - Höhe von Ebene: 0 m; Verschieben mit umliegenden Elementen: no
Bemaßungen - Fläche: 4.07186 m2; Volumen: 1.64983 m3
IFC-Parameter - In IFC-Datei exportieren: Nach Typ; Pset MEP.Tech-Material (ID): 1; Pset MEP.Geom-Angle (°): 90; Pset MEP.Geom-Radius (mm): 50; Pset MEP.Geom-Side 1 (mm): 1500; Pset MEP.Geom-Thickness (mm): 1530; In IFC exportieren als: ifcflowfitting; NameOverride: Bogen symmetrisch; IfcPresentationLayer: 0-TFT-L_Abluft; ObjectTypeOverride: Bogen symmetrisch; Pset MEP.Geom-Surface (m2): 15.3605; Pset MEP.Name: Bogen symmetrisch; IfcDescription: Bogen symmetrisch; Pset MEP.Abbreviation: BS; Pset MEP.Tech-Medium: L_Abluft; Pset MEP.Geom-Side 2 (mm): 1500; Pset MEP.Tech-Weight (kg): 122.884
Phasen - Phase erstellt: Phase 01

# IfcFlowFitting: Flansch 11443:Flansch 11443, Flansch
In: 1. Obergeschoss
Type - Material: IfcSurfaceStyle #9317
Type - Andere - Kategorie: Allgemeines Modell; Familienname: Flansch 11443
Type - ID-Daten - Typname: Flansch 11443
Type - IFC-Parameter - Typ in IFC-Datei exportieren: Vorgabe
Description: Flansch
Pset_DistributionFlowElementCommon - Reference: Flansch 11443; sets with these values: 2
Andere - Typ: Flansch 11443; Familie: Flansch 11443; Familie und Typ: Flansch 11443: Flansch 11443; Typ-ID: 2531534
Abhängigkeiten - Höhe von Ebene: 0 m; Verschieben mit umliegenden Elementen: no
Bemaßungen - Fläche: 0.111243 m2; Volumen: 0.00814942 m3
IFC-Parameter - In IFC-Datei exportieren: Nach Typ; Pset MEP.Tech-Insulation thickness (mm): 100; Pset MEP.Tech-PN: 16; In IFC exportieren als: ifcflowfitting; NameOverride: Flansch; IfcPresentationLayer: 0-TFT-H_Vorlauf; ObjectTypeOverride: Flansch; Pset MEP.Name: Flansch; IfcDescription: Flansch; Pset MEP.Geom-Depth: 55; Pset MEP.Geom-DN: 150; Pset MEP.Geom-Outer Ø (mm): 285; Pset MEP.Tech-Material: nach DIN 2627
Phasen - Phase erstellt: Phase 01

# IfcFlowFitting: Flansch 15062:Flansch 15062, Flansch
In: 1. Obergeschoss
Type - Material: IfcSurfaceStyle #9317
Type - Andere - Kategorie: Allgemeines Modell; Familienname: Flansch 15062
Type - ID-Daten - Typname: Flansch 15062
Type - IFC-Parameter - Typ in IFC-Datei exportieren: Vorgabe
Description: Flansch
Pset_DistributionFlowElementCommon - Reference: Flansch 15062; sets with these values: 2
Andere - Typ: Flansch 15062; Familie: Flansch 15062; Familie und Typ: Flansch 15062: Flansch 15062; Typ-ID: 2531568
Abhängigkeiten - Höhe von Ebene: 0 m; Verschieben mit umliegenden Elementen: no
Bemaßungen - Fläche: 0.111243 m2; Volumen: 0.00814942 m3
IFC-Parameter - In IFC-Datei exportieren: Nach Typ; Pset MEP.Tech-Insulation thickness (mm): 100; Pset MEP.Tech-PN: 16; Pset MEP.Geom-Depth: 55; Pset MEP.Geom-DN: 150; Pset MEP.Geom-Outer Ø (mm): 285; In IFC exportieren als: ifcflowfitting; NameOverride: Flansch; IfcPresentationLayer: 0-TFT-H_Vorlauf; ObjectTypeOverride: Flansch; Pset MEP.Name: Flansch; IfcDescription: Flansch; Pset MEP.Tech-Material: nach DIN 2627
Phasen - Phase erstellt: Phase 01

# IfcFlowFitting: Flansch 16447:Flansch 16447, Flansch
In: 1. Obergeschoss
Type - Material: IfcSurfaceStyle #9317
Type - Andere - Kategorie: Allgemeines Modell; Familienname: Flansch 16447
Type - ID-Daten - Typname: Flansch 16447
Type - IFC-Parameter - Typ in IFC-Datei exportieren: Vorgabe
Description: Flansch
Pset_DistributionFlowElementCommon - Reference: Flansch 16447; sets with these values: 2
Andere - Typ: Flansch 16447; Familie: Flansch 16447; Familie und Typ: Flansch 16447: Flansch 16447; Typ-ID: 2531582
Abhängigkeiten - Höhe von Ebene: 0 m; Verschieben mit umliegenden Elementen: no
Bemaßungen - Fläche: 0.0724331 m2; Volumen: 0.0046363 m3
IFC-Parameter - In IFC-Datei exportieren: Nach Typ; Pset MEP.Tech-Insulation thickness (mm): 100; Pset MEP.Tech-PN: 16; Pset MEP.Geom-DN: 80; In IFC exportieren als: ifcflowfitting; NameOverride: Flansch; IfcPresentationLayer: 0-TFT-H_Vorlauf; ObjectTypeOverride: Flansch; Pset MEP.Name: Flansch; IfcDescription: Flansch; Pset MEP.Geom-Depth: 50; Pset MEP.Geom-Outer Ø (mm): 200; Pset MEP.Tech-Material: nach DIN 2627
Phasen - Phase erstellt: Phase 01

# IfcFlowFitting: Flansch 17216:Flansch 17216, Flansch
In: 1. Obergeschoss
Type - Material: IfcSurfaceStyle #9317
Type - Andere - Kategorie: Allgemeines Modell; Familienname: Flansch 17216
Type - ID-Daten - Typname: Flansch 17216
Type - IFC-Parameter - Typ in IFC-Datei exportieren: Vorgabe
Description: Flansch
Pset_DistributionFlowElementCommon - Reference: Flansch 17216; sets with these values: 2
Andere - Typ: Flansch 17216; Familie: Flansch 17216; Familie und Typ: Flansch 17216: Flansch 17216; Typ-ID: 2531589
Abhängigkeiten - Höhe von Ebene: 0 m; Verschieben mit umliegenden Elementen: no
Bemaßungen - Fläche: 0.0724331 m2; Volumen: 0.0046363 m3
IFC-Parameter - In IFC-Datei exportieren: Nach Typ; Pset MEP.Tech-Insulation thickness (mm): 100; Pset MEP.Tech-PN: 16; Pset MEP.Geom-DN: 80; Pset MEP.Geom-Depth: 50; Pset MEP.Geom-Outer Ø (mm): 200; In IFC exportieren als: ifcflowfitting; NameOverride: Flansch; IfcPresentationLayer: 0-TFT-H_Vorlauf; ObjectTypeOverride: Flansch; Pset MEP.Name: Flansch; IfcDescription: Flansch; Pset MEP.Tech-Material: nach DIN 2627
Phasen - Phase erstellt: Phase 01

# IfcFlowFitting: Flansch 221205:Flansch 221205, Flansch
In: 1. Obergeschoss
Type - Material: IfcSurfaceStyle #9317
Type - Andere - Kategorie: Allgemeines Modell; Familienname: Flansch 221205
Type - ID-Daten - Typname: Flansch 221205
Type - IFC-Parameter - Typ in IFC-Datei exportieren: Vorgabe
Description: Flansch
Pset_DistributionFlowElementCommon - Reference: Flansch 221205; sets with these values: 2
Andere - Typ: Flansch 221205; Familie: Flansch 221205; Familie und Typ: Flansch 221205: Flansch 221205; Typ-ID: 2531702
Abhängigkeiten - Höhe von Ebene: 0 m; Verschieben mit umliegenden Elementen: no
Bemaßungen - Fläche: 0.111243 m2; Volumen: 0.00814942 m3
IFC-Parameter - In IFC-Datei exportieren: Nach Typ; Pset MEP.Tech-Insulation thickness (mm): 100; Pset MEP.Tech-PN: 16; Pset MEP.Geom-Depth: 55; Pset MEP.Geom-DN: 150; Pset MEP.Geom-Outer Ø (mm): 285; In IFC exportieren als: ifcflowfitting; NameOverride: Flansch; IfcPresentationLayer: 0-TFT-H_Vorlauf; ObjectTypeOverride: Flansch; Pset MEP.Name: Flansch; IfcDescription: Flansch; Pset MEP.Tech-Material: nach DIN 2627
Phasen - Phase erstellt: Phase 01

# IfcFlowFitting: Flansch 221274:Flansch 221274, Flansch
In: 1. Obergeschoss
Type - Material: IfcSurfaceStyle #9317
Type - Andere - Kategorie: Allgemeines Modell; Familienname: Flansch 221274
Type - ID-Daten - Typname: Flansch 221274
Type - IFC-Parameter - Typ in IFC-Datei exportieren: Vorgabe
Description: Flansch
Pset_DistributionFlowElementCommon - Reference: Flansch 221274; sets with these values: 2
Andere - Typ: Flansch 221274; Familie: Flansch 221274; Familie und Typ: Flansch 221274: Flansch 221274; Typ-ID: 2531723
Abhängigkeiten - Höhe von Ebene: 0 m; Verschieben mit umliegenden Elementen: no
Bemaßungen - Fläche: 0.111243 m2; Volumen: 0.00814942 m3
IFC-Parameter - In IFC-Datei exportieren: Nach Typ; Pset MEP.Tech-Insulation thickness (mm): 100; Pset MEP.Tech-PN: 16; Pset MEP.Geom-Depth: 55; Pset MEP.Geom-DN: 150; Pset MEP.Geom-Outer Ø (mm): 285; In IFC exportieren als: ifcflowfitting; NameOverride: Flansch; IfcPresentationLayer: 0-TFT-H_Vorlauf; ObjectTypeOverride: Flansch; Pset MEP.Name: Flansch; IfcDescription: Flansch; Pset MEP.Tech-Material: nach DIN 2627
Phasen - Phase erstellt: Phase 01

# IfcFlowFitting: Flansch 221320:Flansch 221320, Flansch
In: 1. Obergeschoss
Type - Material: IfcSurfaceStyle #221345
Type - Andere - Kategorie: Allgemeines Modell; Familienname: Flansch 221320
Type - ID-Daten - Typname: Flansch 221320
Type - IFC-Parameter - Typ in IFC-Datei exportieren: Vorgabe
Description: Flansch
Pset_DistributionFlowElementCommon - Reference: Flansch 221320; sets with these values: 2
Andere - Typ: Flansch 221320; Familie: Flansch 221320; Familie und Typ: Flansch 221320: Flansch 221320; Typ-ID: 2531737
Abhängigkeiten - Höhe von Ebene: 0 m; Verschieben mit umliegenden Elementen: no
Bemaßungen - Fläche: 0.0724331 m2; Volumen: 0.0046363 m3
IFC-Parameter - In IFC-Datei exportieren: Nach Typ; Pset MEP.Tech-Insulation thickness (mm): 100; Pset MEP.Tech-PN: 16; Pset MEP.Geom-DN: 80; Pset MEP.Geom-Depth: 50; Pset MEP.Geom-Outer Ø (mm): 200; In IFC exportieren als: ifcflowfitting; NameOverride: Flansch; IfcPresentationLayer: 0; ObjectTypeOverride: Flansch; Pset MEP.Name: Flansch; IfcDescription: Flansch; Pset MEP.Tech-Material: nach DIN 2627
Phasen - Phase erstellt: Phase 01

# IfcFlowFitting: Flansch 221352:Flansch 221352, Flansch
In: 1. Obergeschoss
Type - Material: IfcSurfaceStyle #9317
Type - Andere - Kategorie: Allgemeines Modell; Familienname: Flansch 221352
Type - ID-Daten - Typname: Flansch 221352
Type - IFC-Parameter - Typ in IFC-Datei exportieren: Vorgabe
Description: Flansch
Pset_DistributionFlowElementCommon - Reference: Flansch 221352; sets with these values: 2
Andere - Typ: Flansch 221352; Familie: Flansch 221352; Familie und Typ: Flansch 221352: Flansch 221352; Typ-ID: 2531747
Abhängigkeiten - Höhe von Ebene: 0 m; Verschieben mit umliegenden Elementen: no
Bemaßungen - Fläche: 0.0724331 m2; Volumen: 0.0046363 m3
IFC-Parameter - In IFC-Datei exportieren: Nach Typ; Pset MEP.Tech-Insulation thickness (mm): 100; Pset MEP.Tech-PN: 16; Pset MEP.Geom-DN: 80; Pset MEP.Geom-Depth: 50; Pset MEP.Geom-Outer Ø (mm): 200; In IFC exportieren als: ifcflowfitting; NameOverride: Flansch; IfcPresentationLayer: 0-TFT-H_Vorlauf; ObjectTypeOverride: Flansch; Pset MEP.Name: Flansch; IfcDescription: Flansch; Pset MEP.Tech-Material: nach DIN 2627
Phasen - Phase erstellt: Phase 01

# IfcFlowFitting: Flansch 221471:Flansch 221471, Flansch
In: 1. Obergeschoss
Type - Material: IfcSurfaceStyle #9317
Type - Andere - Kategorie: Allgemeines Modell; Familienname: Flansch 221471
Type - ID-Daten - Typname: Flansch 221471
Type - IFC-Parameter - Typ in IFC-Datei exportieren: Vorgabe
Description: Flansch
Pset_DistributionFlowElementCommon - Reference: Flansch 221471; sets with these values: 2
Andere - Typ: Flansch 221471; Familie: Flansch 221471; Familie und Typ: Flansch 221471: Flansch 221471; Typ-ID: 2531782
Abhängigkeiten - Höhe von Ebene: 0 m; Verschieben mit umliegenden Elementen: no
Bemaßungen - Fläche: 0.111243 m2; Volumen: 0.00814942 m3
IFC-Parameter - In IFC-Datei exportieren: Nach Typ; Pset MEP.Tech-Insulation thickness (mm): 100; Pset MEP.Tech-PN: 16; Pset MEP.Geom-Depth: 55; Pset MEP.Geom-DN: 150; Pset MEP.Geom-Outer Ø (mm): 285; In IFC exportieren als: ifcflowfitting; NameOverride: Flansch; IfcPresentationLayer: 0-TFT-H_Vorlauf; ObjectTypeOverride: Flansch; Pset MEP.Name: Flansch; IfcDescription: Flansch; Pset MEP.Tech-Material: nach DIN 2627
Phasen - Phase erstellt: Phase 01

# IfcFlowFitting: Flansch 221540:Flansch 221540, Flansch
In: 1. Obergeschoss
Type - Material: IfcSurfaceStyle #9317
Type - Andere - Kategorie: Allgemeines Modell; Familienname: Flansch 221540
Type - ID-Daten - Typname: Flansch 221540
Type - IFC-Parameter - Typ in IFC-Datei exportieren: Vorgabe
Description: Flansch
Pset_DistributionFlowElementCommon - Reference: Flansch 221540; sets with these values: 2
Andere - Typ: Flansch 221540; Familie: Flansch 221540; Familie und Typ: Flansch 221540: Flansch 221540; Typ-ID: 2531803
Abhängigkeiten - Höhe von Ebene: 0 m; Verschieben mit umliegenden Elementen: no
Bemaßungen - Fläche: 0.111243 m2; Volumen: 0.00814942 m3
IFC-Parameter - In IFC-Datei exportieren: Nach Typ; Pset MEP.Tech-Insulation thickness (mm): 100; Pset MEP.Tech-PN: 16; Pset MEP.Geom-Depth: 55; Pset MEP.Geom-DN: 150; Pset MEP.Geom-Outer Ø (mm): 285; In IFC exportieren als: ifcflowfitting; NameOverride: Flansch; IfcPresentationLayer: 0-TFT-H_Vorlauf; ObjectTypeOverride: Flansch; Pset MEP.Name: Flansch; IfcDescription: Flansch; Pset MEP.Tech-Material: nach DIN 2627
Phasen - Phase erstellt: Phase 01

# IfcFlowFitting: Flansch 221586:Flansch 221586, Flansch
In: 1. Obergeschoss
Type - Material: IfcSurfaceStyle #221345
Type - Andere - Kategorie: Allgemeines Modell; Familienname: Flansch 221586
Type - ID-Daten - Typname: Flansch 221586
Type - IFC-Parameter - Typ in IFC-Datei exportieren: Vorgabe
Description: Flansch
Pset_DistributionFlowElementCommon - Reference: Flansch 221586; sets with these values: 2
Andere - Typ: Flansch 221586; Familie: Flansch 221586; Familie und Typ: Flansch 221586: Flansch 221586; Typ-ID: 2531817
Abhängigkeiten - Höhe von Ebene: 0 m; Verschieben mit umliegenden Elementen: no
Bemaßungen - Fläche: 0.0724331 m2; Volumen: 0.0046363 m3
IFC-Parameter - In IFC-Datei exportieren: Nach Typ; Pset MEP.Tech-Insulation thickness (mm): 100; Pset MEP.Tech-PN: 16; Pset MEP.Geom-DN: 80; Pset MEP.Geom-Depth: 50; Pset MEP.Geom-Outer Ø (mm): 200; In IFC exportieren als: ifcflowfitting; NameOverride: Flansch; IfcPresentationLayer: 0; ObjectTypeOverride: Flansch; Pset MEP.Name: Flansch; IfcDescription: Flansch; Pset MEP.Tech-Material: nach DIN 2627
Phasen - Phase erstellt: Phase 01

# IfcFlowFitting: Flansch 221609:Flansch 221609, Flansch
In: 1. Obergeschoss
Type - Material: IfcSurfaceStyle #9317
Type - Andere - Kategorie: Allgemeines Modell; Familienname: Flansch 221609
Type - ID-Daten - Typname: Flansch 221609
Type - IFC-Parameter - Typ in IFC-Datei exportieren: Vorgabe
Description: Flansch
Pset_DistributionFlowElementCommon - Reference: Flansch 221609; sets with these values: 2
Andere - Typ: Flansch 221609; Familie: Flansch 221609; Familie und Typ: Flansch 221609: Flansch 221609; Typ-ID: 2531824
Abhängigkeiten - Höhe von Ebene: 0 m; Verschieben mit umliegenden Elementen: no
Bemaßungen - Fläche: 0.0724331 m2; Volumen: 0.0046363 m3
IFC-Parameter - In IFC-Datei exportieren: Nach Typ; Pset MEP.Tech-Insulation thickness (mm): 100; Pset MEP.Tech-PN: 16; Pset MEP.Geom-DN: 80; Pset MEP.Geom-Depth: 50; Pset MEP.Geom-Outer Ø (mm): 200; In IFC exportieren als: ifcflowfitting; NameOverride: Flansch; IfcPresentationLayer: 0-TFT-H_Vorlauf; ObjectTypeOverride: Flansch; Pset MEP.Name: Flansch; IfcDescription: Flansch; Pset MEP.Tech-Material: nach DIN 2627
Phasen - Phase erstellt: Phase 01

# IfcFlowFitting: Flansch 233463:Flansch 233463, Flansch
In: 1. Obergeschoss
Type - Material: IfcSurfaceStyle #9317
Type - Andere - Kategorie: Allgemeines Modell; Familienname: Flansch 233463
Type - ID-Daten - Typname: Flansch 233463
Type - IFC-Parameter - Typ in IFC-Datei exportieren: Vorgabe
Description: Flansch
Pset_DistributionFlowElementCommon - Reference: Flansch 233463; sets with these values: 2
Andere - Typ: Flansch 233463; Familie: Flansch 233463; Familie und Typ: Flansch 233463: Flansch 233463; Typ-ID: 2532214
Abhängigkeiten - Höhe von Ebene: 0 m; Verschieben mit umliegenden Elementen: no
Bemaßungen - Fläche: 0.0951801 m2; Volumen: 0.00573602 m3
IFC-Parameter - In IFC-Datei exportieren: Nach Typ; Pset MEP.Tech-Insulation thickness (mm): 100; Pset MEP.Tech-PN: 16; Pset MEP.Geom-Depth: 55; Pset MEP.Geom-DN: 125; Pset MEP.Geom-Outer Ø (mm): 250; In IFC exportieren als: ifcflowfitting; NameOverride: Flansch; IfcPresentationLayer: 0-TFT-H_Vorlauf; ObjectTypeOverride: Flansch; Pset MEP.Name: Flansch; IfcDescription: Flansch; Pset MEP.Tech-Material: nach DIN 2627
Phasen - Phase erstellt: Phase 01

# IfcFlowFitting: Flansch 234258:Flansch 234258, Flansch
In: 1. Obergeschoss
Type - Material: IfcSurfaceStyle #9317
Type - Andere - Kategorie: Allgemeines Modell; Familienname: Flansch 234258
Type - ID-Daten - Typname: Flansch 234258
Type - IFC-Parameter - Typ in IFC-Datei exportieren: Vorgabe
Description: Flansch
Pset_DistributionFlowElementCommon - Reference: Flansch 234258; sets with these values: 2
Andere - Typ: Flansch 234258; Familie: Flansch 234258; Familie und Typ: Flansch 234258: Flansch 234258; Typ-ID: 2532228
Abhängigkeiten - Höhe von Ebene: 0 m; Verschieben mit umliegenden Elementen: no
Bemaßungen - Fläche: 0.0951801 m2; Volumen: 0.00682535 m3
IFC-Parameter - In IFC-Datei exportieren: Nach Typ; Pset MEP.Tech-Insulation thickness (mm): 100; Pset MEP.Tech-PN: 16; Pset MEP.Geom-Depth: 55; Pset MEP.Geom-DN: 125; Pset MEP.Geom-Outer Ø (mm): 250; In IFC exportieren als: ifcflowfitting; NameOverride: Flansch; IfcPresentationLayer: 0-TFT-H_Vorlauf; ObjectTypeOverride: Flansch; Pset MEP.Name: Flansch; IfcDescription: Flansch; Pset MEP.Tech-Material: nach DIN 2627
Phasen - Phase erstellt: Phase 01

# IfcFlowFitting: Flansch 236004:Flansch 236004, Flansch
In: 1. Obergeschoss
Type - Material: IfcSurfaceStyle #9317
Type - Andere - Kategorie: Allgemeines Modell; Familienname: Flansch 236004
Type - ID-Daten - Typname: Flansch 236004
Type - IFC-Parameter - Typ in IFC-Datei exportieren: Vorgabe
Description: Flansch
Pset_DistributionFlowElementCommon - Reference: Flansch 236004; sets with these values: 2
Andere - Typ: Flansch 236004; Familie: Flansch 236004; Familie und Typ: Flansch 236004: Flansch 236004; Typ-ID: 2532249
Abhängigkeiten - Höhe von Ebene: 0 m; Verschieben mit umliegenden Elementen: no
Bemaßungen - Fläche: 0.111243 m2; Volumen: 0.00683497 m3
IFC-Parameter - In IFC-Datei exportieren: Nach Typ; Pset MEP.Tech-Insulation thickness (mm): 100; Pset MEP.Tech-PN: 16; Pset MEP.Geom-Depth: 55; Pset MEP.Geom-DN: 150; Pset MEP.Geom-Outer Ø (mm): 285; In IFC exportieren als: ifcflowfitting; NameOverride: Flansch; IfcPresentationLayer: 0-TFT-H_Vorlauf; ObjectTypeOverride: Flansch; Pset MEP.Name: Flansch; IfcDescription: Flansch; Pset MEP.Tech-Material: nach DIN 2627
Phasen - Phase erstellt: Phase 01

# IfcFlowFitting: Flansch 236886:Flansch 236886, Flansch
In: 1. Obergeschoss
Type - Material: IfcSurfaceStyle #9317
Type - Andere - Kategorie: Allgemeines Modell; Familienname: Flansch 236886
Type - ID-Daten - Typname: Flansch 236886
Type - IFC-Parameter - Typ in IFC-Datei exportieren: Vorgabe
Description: Flansch
Pset_DistributionFlowElementCommon - Reference: Flansch 236886; sets with these values: 2
Andere - Typ: Flansch 236886; Familie: Flansch 236886; Familie und Typ: Flansch 236886: Flansch 236886; Typ-ID: 2532291
Abhängigkeiten - Höhe von Ebene: 0 m; Verschieben mit umliegenden Elementen: no
Bemaßungen - Fläche: 0.0951801 m2; Volumen: 0.00573602 m3
IFC-Parameter - In IFC-Datei exportieren: Nach Typ; Pset MEP.Tech-Insulation thickness (mm): 100; Pset MEP.Tech-PN: 16; Pset MEP.Geom-Depth: 55; Pset MEP.Geom-DN: 125; Pset MEP.Geom-Outer Ø (mm): 250; In IFC exportieren als: ifcflowfitting; NameOverride: Flansch; IfcPresentationLayer: 0-TFT-H_Vorlauf; ObjectTypeOverride: Flansch; Pset MEP.Name: Flansch; IfcDescription: Flansch; Pset MEP.Tech-Material: nach DIN 2627
Phasen - Phase erstellt: Phase 01

# IfcFlowFitting: Flansch 236932:Flansch 236932, Flansch
In: 1. Obergeschoss
Type - Material: IfcSurfaceStyle #9317
Type - Andere - Kategorie: Allgemeines Modell; Familienname: Flansch 236932
Type - ID-Daten - Typname: Flansch 236932
Type - IFC-Parameter - Typ in IFC-Datei exportieren: Vorgabe
Description: Flansch
Pset_DistributionFlowElementCommon - Reference: Flansch 236932; sets with these values: 2
Andere - Typ: Flansch 236932; Familie: Flansch 236932; Familie und Typ: Flansch 236932: Flansch 236932; Typ-ID: 2532305
Abhängigkeiten - Höhe von Ebene: 0 m; Verschieben mit umliegenden Elementen: no
Bemaßungen - Fläche: 0.0951801 m2; Volumen: 0.00682535 m3
IFC-Parameter - In IFC-Datei exportieren: Nach Typ; Pset MEP.Tech-Insulation thickness (mm): 100; Pset MEP.Tech-PN: 16; Pset MEP.Geom-Depth: 55; Pset MEP.Geom-DN: 125; Pset MEP.Geom-Outer Ø (mm): 250; In IFC exportieren als: ifcflowfitting; NameOverride: Flansch; IfcPresentationLayer: 0-TFT-H_Vorlauf; ObjectTypeOverride: Flansch; Pset MEP.Name: Flansch; IfcDescription: Flansch; Pset MEP.Tech-Material: nach DIN 2627
Phasen - Phase erstellt: Phase 01

# IfcFlowFitting: Flansch 237001:Flansch 237001, Flansch
In: 1. Obergeschoss
Type - Material: IfcSurfaceStyle #9317
Type - Andere - Kategorie: Allgemeines Modell; Familienname: Flansch 237001
Type - ID-Daten - Typname: Flansch 237001
Type - IFC-Parameter - Typ in IFC-Datei exportieren: Vorgabe
Description: Flansch
Pset_DistributionFlowElementCommon - Reference: Flansch 237001; sets with these values: 2
Andere - Typ: Flansch 237001; Familie: Flansch 237001; Familie und Typ: Flansch 237001: Flansch 237001; Typ-ID: 2532326
Abhängigkeiten - Höhe von Ebene: 0 m; Verschieben mit umliegenden Elementen: no
Bemaßungen - Fläche: 0.111243 m2; Volumen: 0.00683497 m3
IFC-Parameter - In IFC-Datei exportieren: Nach Typ; Pset MEP.Tech-Insulation thickness (mm): 100; Pset MEP.Tech-PN: 16; Pset MEP.Geom-Depth: 55; Pset MEP.Geom-DN: 150; Pset MEP.Geom-Outer Ø (mm): 285; In IFC exportieren als: ifcflowfitting; NameOverride: Flansch; IfcPresentationLayer: 0-TFT-H_Vorlauf; ObjectTypeOverride: Flansch; Pset MEP.Name: Flansch; IfcDescription: Flansch; Pset MEP.Tech-Material: nach DIN 2627
Phasen - Phase erstellt: Phase 01

# IfcFlowFitting: Flansch 237139:Flansch 237139, Flansch
In: 1. Obergeschoss
Type - Material: IfcSurfaceStyle #9317
Type - Andere - Kategorie: Allgemeines Modell; Familienname: Flansch 237139
Type - ID-Daten - Typname: Flansch 237139
Type - IFC-Parameter - Typ in IFC-Datei exportieren: Vorgabe
Description: Flansch
Pset_DistributionFlowElementCommon - Reference: Flansch 237139; sets with these values: 2
Andere - Typ: Flansch 237139; Familie: Flansch 237139; Familie und Typ: Flansch 237139: Flansch 237139; Typ-ID: 2532368
Abhängigkeiten - Höhe von Ebene: 0 m; Verschieben mit umliegenden Elementen: no
Bemaßungen - Fläche: 0.0951801 m2; Volumen: 0.00573602 m3
IFC-Parameter - In IFC-Datei exportieren: Nach Typ; Pset MEP.Tech-Insulation thickness (mm): 100; Pset MEP.Tech-PN: 16; Pset MEP.Geom-Depth: 55; Pset MEP.Geom-DN: 125; Pset MEP.Geom-Outer Ø (mm): 250; In IFC exportieren als: ifcflowfitting; NameOverride: Flansch; IfcPresentationLayer: 0-TFT-H_Vorlauf; ObjectTypeOverride: Flansch; Pset MEP.Name: Flansch; IfcDescription: Flansch; Pset MEP.Tech-Material: nach DIN 2627
Phasen - Phase erstellt: Phase 01

# IfcFlowFitting: Flansch 237185:Flansch 237185, Flansch
In: 1. Obergeschoss
Type - Material: IfcSurfaceStyle #9317
Type - Andere - Kategorie: Allgemeines Modell; Familienname: Flansch 237185
Type - ID-Daten - Typname: Flansch 237185
Type - IFC-Parameter - Typ in IFC-Datei exportieren: Vorgabe
Description: Flansch
Pset_DistributionFlowElementCommon - Reference: Flansch 237185; sets with these values: 2
Andere - Typ: Flansch 237185; Familie: Flansch 237185; Familie und Typ: Flansch 237185: Flansch 237185; Typ-ID: 2532382
Abhängigkeiten - Höhe von Ebene: 0 m; Verschieben mit umliegenden Elementen: no
Bemaßungen - Fläche: 0.0951801 m2; Volumen: 0.00682535 m3
IFC-Parameter - In IFC-Datei exportieren: Nach Typ; Pset MEP.Tech-Insulation thickness (mm): 100; Pset MEP.Tech-PN: 16; Pset MEP.Geom-Depth: 55; Pset MEP.Geom-DN: 125; Pset MEP.Geom-Outer Ø (mm): 250; In IFC exportieren als: ifcflowfitting; NameOverride: Flansch; IfcPresentationLayer: 0-TFT-H_Vorlauf; ObjectTypeOverride: Flansch; Pset MEP.Name: Flansch; IfcDescription: Flansch; Pset MEP.Tech-Material: nach DIN 2627
Phasen - Phase erstellt: Phase 01

# IfcFlowFitting: Flansch 237254:Flansch 237254, Flansch
In: 1. Obergeschoss
Type - Material: IfcSurfaceStyle #9317
Type - Andere - Kategorie: Allgemeines Modell; Familienname: Flansch 237254
Type - ID-Daten - Typname: Flansch 237254
Type - IFC-Parameter - Typ in IFC-Datei exportieren: Vorgabe
Description: Flansch
Pset_DistributionFlowElementCommon - Reference: Flansch 237254; sets with these values: 2
Andere - Typ: Flansch 237254; Familie: Flansch 237254; Familie und Typ: Flansch 237254: Flansch 237254; Typ-ID: 2532403
Abhängigkeiten - Höhe von Ebene: 0 m; Verschieben mit umliegenden Elementen: no
Bemaßungen - Fläche: 0.111243 m2; Volumen: 0.00683497 m3
IFC-Parameter - In IFC-Datei exportieren: Nach Typ; Pset MEP.Tech-Insulation thickness (mm): 100; Pset MEP.Tech-PN: 16; Pset MEP.Geom-Depth: 55; Pset MEP.Geom-DN: 150; Pset MEP.Geom-Outer Ø (mm): 285; In IFC exportieren als: ifcflowfitting; NameOverride: Flansch; IfcPresentationLayer: 0-TFT-H_Vorlauf; ObjectTypeOverride: Flansch; Pset MEP.Name: Flansch; IfcDescription: Flansch; Pset MEP.Tech-Material: nach DIN 2627
Phasen - Phase erstellt: Phase 01

# IfcFlowFitting: Flansch 237558:Flansch 237558, Flansch
In: 1. Obergeschoss
Type - Material: IfcSurfaceStyle #9317
Type - Andere - Kategorie: Allgemeines Modell; Familienname: Flansch 237558
Type - ID-Daten - Typname: Flansch 237558
Type - IFC-Parameter - Typ in IFC-Datei exportieren: Vorgabe
Description: Flansch
Pset_DistributionFlowElementCommon - Reference: Flansch 237558; sets with these values: 2
Andere - Typ: Flansch 237558; Familie: Flansch 237558; Familie und Typ: Flansch 237558: Flansch 237558; Typ-ID: 2532417
Abhängigkeiten - Höhe von Ebene: 0 m; Verschieben mit umliegenden Elementen: no
Bemaßungen - Fläche: 0.111243 m2; Volumen: 0.00683497 m3
IFC-Parameter - In IFC-Datei exportieren: Nach Typ; Pset MEP.Tech-Insulation thickness (mm): 100; Pset MEP.Tech-PN: 16; Pset MEP.Geom-Depth: 55; Pset MEP.Geom-DN: 150; Pset MEP.Geom-Outer Ø (mm): 285; In IFC exportieren als: ifcflowfitting; NameOverride: Flansch; IfcPresentationLayer: 0-TFT-H_Vorlauf; ObjectTypeOverride: Flansch; Pset MEP.Name: Flansch; IfcDescription: Flansch; Pset MEP.Tech-Material: nach DIN 2627
Phasen - Phase erstellt: Phase 01

# IfcFlowFitting: Flansch 242638:Flansch 242638, Flansch
In: 1. Obergeschoss
Type - Material: IfcSurfaceStyle #9317
Type - Andere - Kategorie: Allgemeines Modell; Familienname: Flansch 242638
Type - ID-Daten - Typname: Flansch 242638
Type - IFC-Parameter - Typ in IFC-Datei exportieren: Vorgabe
Description: Flansch
Pset_DistributionFlowElementCommon - Reference: Flansch 242638; sets with these values: 2
Andere - Typ: Flansch 242638; Familie: Flansch 242638; Familie und Typ: Flansch 242638: Flansch 242638; Typ-ID: 2532480
Abhängigkeiten - Höhe von Ebene: 0 m; Verschieben mit umliegenden Elementen: no
Bemaßungen - Fläche: 0.0800177 m2; Volumen: 0.00456789 m3
IFC-Parameter - In IFC-Datei exportieren: Nach Typ; Pset MEP.Tech-Insulation thickness (mm): 100; Pset MEP.Tech-PN: 16; Pset MEP.Geom-DN: 100; In IFC exportieren als: ifcflowfitting; NameOverride: Flansch; IfcPresentationLayer: 0-TFT-H_Vorlauf; ObjectTypeOverride: Flansch; Pset MEP.Name: Flansch; IfcDescription: Flansch; Pset MEP.Geom-Depth: 52; Pset MEP.Geom-Outer Ø (mm): 220; Pset MEP.Tech-Material: nach DIN 2627
Phasen - Phase erstellt: Phase 01

# IfcFlowFitting: Flansch 245416:Flansch 245416, Flansch
In: 1. Obergeschoss
Type - Material: IfcSurfaceStyle #9317
Type - Andere - Kategorie: Allgemeines Modell; Familienname: Flansch 245416
Type - ID-Daten - Typname: Flansch 245416
Type - IFC-Parameter - Typ in IFC-Datei exportieren: Vorgabe
Description: Flansch
Pset_DistributionFlowElementCommon - Reference: Flansch 245416; sets with these values: 2
Andere - Typ: Flansch 245416; Familie: Flansch 245416; Familie und Typ: Flansch 245416: Flansch 245416; Typ-ID: 2532501
Abhängigkeiten - Höhe von Ebene: 0 m; Verschieben mit umliegenden Elementen: no
Bemaßungen - Fläche: 0.144185 m2; Volumen: 0.0099386 m3
IFC-Parameter - In IFC-Datei exportieren: Nach Typ; Pset MEP.Geom-Depth: 62; Pset MEP.Geom-DN: 200; Pset MEP.Geom-Outer Ø (mm): 340; Pset MEP.Tech-Insulation thickness (mm): 100; Pset MEP.Tech-PN: 16; In IFC exportieren als: ifcflowfitting; NameOverride: Flansch; IfcPresentationLayer: 0-TFT-H_Vorlauf; ObjectTypeOverride: Flansch; Pset MEP.Name: Flansch; IfcDescription: Flansch; Pset MEP.Tech-Material: nach DIN 2627
Phasen - Phase erstellt: Phase 01

# IfcFlowFitting: Flansch 245489:Flansch 245489, Flansch
In: 1. Obergeschoss
Type - Material: IfcSurfaceStyle #9317
Type - Andere - Kategorie: Allgemeines Modell; Familienname: Flansch 245489
Type - ID-Daten - Typname: Flansch 245489
Type - IFC-Parameter - Typ in IFC-Datei exportieren: Vorgabe
Description: Flansch
Pset_DistributionFlowElementCommon - Reference: Flansch 245489; sets with these values: 2
Andere - Typ: Flansch 245489; Familie: Flansch 245489; Familie und Typ: Flansch 245489: Flansch 245489; Typ-ID: 2532522
Abhängigkeiten - Höhe von Ebene: 0 m; Verschieben mit umliegenden Elementen: no
Bemaßungen - Fläche: 0.144185 m2; Volumen: 0.0099386 m3
IFC-Parameter - In IFC-Datei exportieren: Nach Typ; Pset MEP.Geom-Depth: 62; Pset MEP.Geom-DN: 200; Pset MEP.Geom-Outer Ø (mm): 340; Pset MEP.Tech-Insulation thickness (mm): 100; Pset MEP.Tech-PN: 16; In IFC exportieren als: ifcflowfitting; NameOverride: Flansch; IfcPresentationLayer: 0-TFT-H_Vorlauf; ObjectTypeOverride: Flansch; Pset MEP.Name: Flansch; IfcDescription: Flansch; Pset MEP.Tech-Material: nach DIN 2627
Phasen - Phase erstellt: Phase 01

# IfcFlowFitting: Flansch 245558:Flansch 245558, Flansch
In: 1. Obergeschoss
Type - Material: IfcSurfaceStyle #9317
Type - Andere - Kategorie: Allgemeines Modell; Familienname: Flansch 245558
Type - ID-Daten - Typname: Flansch 245558
Type - IFC-Parameter - Typ in IFC-Datei exportieren: Vorgabe
Description: Flansch
Pset_DistributionFlowElementCommon - Reference: Flansch 245558; sets with these values: 2
Andere - Typ: Flansch 245558; Familie: Flansch 245558; Familie und Typ: Flansch 245558: Flansch 245558; Typ-ID: 2532543
Abhängigkeiten - Höhe von Ebene: 0 m; Verschieben mit umliegenden Elementen: no
Bemaßungen - Fläche: 0.144185 m2; Volumen: 0.0099386 m3
IFC-Parameter - In IFC-Datei exportieren: Nach Typ; Pset MEP.Geom-Depth: 62; Pset MEP.Geom-DN: 200; Pset MEP.Geom-Outer Ø (mm): 340; Pset MEP.Tech-Insulation thickness (mm): 100; Pset MEP.Tech-PN: 16; In IFC exportieren als: ifcflowfitting; NameOverride: Flansch; IfcPresentationLayer: 0-TFT-H_Vorlauf; ObjectTypeOverride: Flansch; Pset MEP.Name: Flansch; IfcDescription: Flansch; Pset MEP.Tech-Material: nach DIN 2627
Phasen - Phase erstellt: Phase 01

# IfcFlowFitting: Flansch 245581:Flansch 245581, Flansch
In: 1. Obergeschoss
Type - Material: IfcSurfaceStyle #9317
Type - Andere - Kategorie: Allgemeines Modell; Familienname: Flansch 245581
Type - ID-Daten - Typname: Flansch 245581
Type - IFC-Parameter - Typ in IFC-Datei exportieren: Vorgabe
Description: Flansch
Pset_DistributionFlowElementCommon - Reference: Flansch 245581; sets with these values: 2
Andere - Typ: Flansch 245581; Familie: Flansch 245581; Familie und Typ: Flansch 245581: Flansch 245581; Typ-ID: 2532550
Abhängigkeiten - Höhe von Ebene: 0 m; Verschieben mit umliegenden Elementen: no
Bemaßungen - Fläche: 0.144185 m2; Volumen: 0.0118373 m3
IFC-Parameter - In IFC-Datei exportieren: Nach Typ; Pset MEP.Geom-Depth: 62; Pset MEP.Geom-DN: 200; Pset MEP.Geom-Outer Ø (mm): 340; Pset MEP.Tech-Insulation thickness (mm): 100; Pset MEP.Tech-PN: 16; In IFC exportieren als: ifcflowfitting; NameOverride: Flansch; IfcPresentationLayer: 0-TFT-H_Vorlauf; ObjectTypeOverride: Flansch; Pset MEP.Name: Flansch; IfcDescription: Flansch; Pset MEP.Tech-Material: nach DIN 2627
Phasen - Phase erstellt: Phase 01

# IfcFlowFitting: Flansch 245885:Flansch 245885, Flansch
In: 1. Obergeschoss
Type - Material: IfcSurfaceStyle #9317
Type - Andere - Kategorie: Allgemeines Modell; Familienname: Flansch 245885
Type - ID-Daten - Typname: Flansch 245885
Type - IFC-Parameter - Typ in IFC-Datei exportieren: Vorgabe
Description: Flansch
Pset_DistributionFlowElementCommon - Reference: Flansch 245885; sets with these values: 2
Andere - Typ: Flansch 245885; Familie: Flansch 245885; Familie und Typ: Flansch 245885: Flansch 245885; Typ-ID: 2532564
Abhängigkeiten - Höhe von Ebene: 0 m; Verschieben mit umliegenden Elementen: no
Bemaßungen - Fläche: 0.0800177 m2; Volumen: 0.00543566 m3
IFC-Parameter - In IFC-Datei exportieren: Nach Typ; Pset MEP.Tech-Insulation thickness (mm): 100; Pset MEP.Tech-PN: 16; Pset MEP.Geom-DN: 100; Pset MEP.Geom-Depth: 52; Pset MEP.Geom-Outer Ø (mm): 220; In IFC exportieren als: ifcflowfitting; NameOverride: Flansch; IfcPresentationLayer: 0-TFT-H_Vorlauf; ObjectTypeOverride: Flansch; Pset MEP.Name: Flansch; IfcDescription: Flansch; Pset MEP.Tech-Material: nach DIN 2627
Phasen - Phase erstellt: Phase 01

# IfcFlowFitting: Flansch 247248:Flansch 247248, Flansch
In: 1. Obergeschoss
Type - Material: IfcSurfaceStyle #1741
Type - Andere - Kategorie: Allgemeines Modell; Familienname: Flansch 247248
Type - ID-Daten - Typname: Flansch 247248
Type - IFC-Parameter - Typ in IFC-Datei exportieren: Vorgabe
Description: Flansch
Pset_DistributionFlowElementCommon - Reference: Flansch 247248; sets with these values: 2
Andere - Typ: Flansch 247248; Familie: Flansch 247248; Familie und Typ: Flansch 247248: Flansch 247248; Typ-ID: 2532599
Abhängigkeiten - Höhe von Ebene: 0 m; Verschieben mit umliegenden Elementen: no
Bemaßungen - Fläche: 0.0800177 m2; Volumen: 0.00456789 m3
IFC-Parameter - In IFC-Datei exportieren: Nach Typ; Pset MEP.Tech-Insulation thickness (mm): 100; Pset MEP.Tech-PN: 16; Pset MEP.Geom-DN: 100; Pset MEP.Geom-Depth: 52; Pset MEP.Geom-Outer Ø (mm): 220; In IFC exportieren als: ifcflowfitting; NameOverride: Flansch; IfcPresentationLayer: 0-TFT-H_Ruecklauf; ObjectTypeOverride: Flansch; Pset MEP.Name: Flansch; IfcDescription: Flansch; Pset MEP.Tech-Material: nach DIN 2627
Phasen - Phase erstellt: Phase 01

# IfcFlowFitting: Flansch 247317:Flansch 247317, Flansch
In: 1. Obergeschoss
Type - Material: IfcSurfaceStyle #1741
Type - Andere - Kategorie: Allgemeines Modell; Familienname: Flansch 247317
Type - ID-Daten - Typname: Flansch 247317
Type - IFC-Parameter - Typ in IFC-Datei exportieren: Vorgabe
Description: Flansch
Pset_DistributionFlowElementCommon - Reference: Flansch 247317; sets with these values: 2
Andere - Typ: Flansch 247317; Familie: Flansch 247317; Familie und Typ: Flansch 247317: Flansch 247317; Typ-ID: 2532620
Abhängigkeiten - Höhe von Ebene: 0 m; Verschieben mit umliegenden Elementen: no
Bemaßungen - Fläche: 0.144185 m2; Volumen: 0.0099386 m3
IFC-Parameter - In IFC-Datei exportieren: Nach Typ; Pset MEP.Geom-Depth: 62; Pset MEP.Geom-DN: 200; Pset MEP.Geom-Outer Ø (mm): 340; Pset MEP.Tech-Insulation thickness (mm): 100; Pset MEP.Tech-PN: 16; In IFC exportieren als: ifcflowfitting; NameOverride: Flansch; IfcPresentationLayer: 0-TFT-H_Ruecklauf; ObjectTypeOverride: Flansch; Pset MEP.Name: Flansch; IfcDescription: Flansch; Pset MEP.Tech-Material: nach DIN 2627
Phasen - Phase erstellt: Phase 01

# IfcFlowFitting: Flansch 247386:Flansch 247386, Flansch
In: 1. Obergeschoss
Type - Material: IfcSurfaceStyle #1741
Type - Andere - Kategorie: Allgemeines Modell; Familienname: Flansch 247386
Type - ID-Daten - Typname: Flansch 247386
Type - IFC-Parameter - Typ in IFC-Datei exportieren: Vorgabe
Description: Flansch
Pset_DistributionFlowElementCommon - Reference: Flansch 247386; sets with these values: 2
Andere - Typ: Flansch 247386; Familie: Flansch 247386; Familie und Typ: Flansch 247386: Flansch 247386; Typ-ID: 2532641
Abhängigkeiten - Höhe von Ebene: 0 m; Verschieben mit umliegenden Elementen: no
Bemaßungen - Fläche: 0.144185 m2; Volumen: 0.0099386 m3
IFC-Parameter - In IFC-Datei exportieren: Nach Typ; Pset MEP.Geom-Depth: 62; Pset MEP.Geom-DN: 200; Pset MEP.Geom-Outer Ø (mm): 340; Pset MEP.Tech-Insulation thickness (mm): 100; Pset MEP.Tech-PN: 16; In IFC exportieren als: ifcflowfitting; NameOverride: Flansch; IfcPresentationLayer: 0-TFT-H_Ruecklauf; ObjectTypeOverride: Flansch; Pset MEP.Name: Flansch; IfcDescription: Flansch; Pset MEP.Tech-Material: nach DIN 2627
Phasen - Phase erstellt: Phase 01

# IfcFlowFitting: Flansch 247455:Flansch 247455, Flansch
In: 1. Obergeschoss
Type - Material: IfcSurfaceStyle #1741
Type - Andere - Kategorie: Allgemeines Modell; Familienname: Flansch 247455
Type - ID-Daten - Typname: Flansch 247455
Type - IFC-Parameter - Typ in IFC-Datei exportieren: Vorgabe
Description: Flansch
Pset_DistributionFlowElementCommon - Reference: Flansch 247455; sets with these values: 2
Andere - Typ: Flansch 247455; Familie: Flansch 247455; Familie und Typ: Flansch 247455: Flansch 247455; Typ-ID: 2532662
Abhängigkeiten - Höhe von Ebene: 0 m; Verschieben mit umliegenden Elementen: no
Bemaßungen - Fläche: 0.144185 m2; Volumen: 0.0099386 m3
IFC-Parameter - In IFC-Datei exportieren: Nach Typ; Pset MEP.Geom-Depth: 62; Pset MEP.Geom-DN: 200; Pset MEP.Geom-Outer Ø (mm): 340; Pset MEP.Tech-Insulation thickness (mm): 100; Pset MEP.Tech-PN: 16; In IFC exportieren als: ifcflowfitting; NameOverride: Flansch; IfcPresentationLayer: 0-TFT-H_Ruecklauf; ObjectTypeOverride: Flansch; Pset MEP.Name: Flansch; IfcDescription: Flansch; Pset MEP.Tech-Material: nach DIN 2627
Phasen - Phase erstellt: Phase 01

# IfcFlowFitting: Flansch 247478:Flansch 247478, Flansch
In: 1. Obergeschoss
Type - Material: IfcSurfaceStyle #1741
Type - Andere - Kategorie: Allgemeines Modell; Familienname: Flansch 247478
Type - ID-Daten - Typname: Flansch 247478
Type - IFC-Parameter - Typ in IFC-Datei exportieren: Vorgabe
Description: Flansch
Pset_DistributionFlowElementCommon - Reference: Flansch 247478; sets with these values: 2
Andere - Typ: Flansch 247478; Familie: Flansch 247478; Familie und Typ: Flansch 247478: Flansch 247478; Typ-ID: 2532669
Abhängigkeiten - Höhe von Ebene: 0 m; Verschieben mit umliegenden Elementen: no
Bemaßungen - Fläche: 0.144185 m2; Volumen: 0.0118373 m3
IFC-Parameter - In IFC-Datei exportieren: Nach Typ; Pset MEP.Geom-Depth: 62; Pset MEP.Geom-DN: 200; Pset MEP.Geom-Outer Ø (mm): 340; Pset MEP.Tech-Insulation thickness (mm): 100; Pset MEP.Tech-PN: 16; In IFC exportieren als: ifcflowfitting; NameOverride: Flansch; IfcPresentationLayer: 0-TFT-H_Ruecklauf; ObjectTypeOverride: Flansch; Pset MEP.Name: Flansch; IfcDescription: Flansch; Pset MEP.Tech-Material: nach DIN 2627
Phasen - Phase erstellt: Phase 01

# IfcFlowFitting: Flansch 247524:Flansch 247524, Flansch
In: 1. Obergeschoss
Type - Material: IfcSurfaceStyle #1741
Type - Andere - Kategorie: Allgemeines Modell; Familienname: Flansch 247524
Type - ID-Daten - Typname: Flansch 247524
Type - IFC-Parameter - Typ in IFC-Datei exportieren: Vorgabe
Description: Flansch
Pset_DistributionFlowElementCommon - Reference: Flansch 247524; sets with these values: 2
Andere - Typ: Flansch 247524; Familie: Flansch 247524; Familie und Typ: Flansch 247524: Flansch 247524; Typ-ID: 2532683
Abhängigkeiten - Höhe von Ebene: 0 m; Verschieben mit umliegenden Elementen: no
Bemaßungen - Fläche: 0.0800177 m2; Volumen: 0.00543566 m3
IFC-Parameter - In IFC-Datei exportieren: Nach Typ; Pset MEP.Tech-Insulation thickness (mm): 100; Pset MEP.Tech-PN: 16; Pset MEP.Geom-DN: 100; Pset MEP.Geom-Depth: 52; Pset MEP.Geom-Outer Ø (mm): 220; In IFC exportieren als: ifcflowfitting; NameOverride: Flansch; IfcPresentationLayer: 0-TFT-H_Ruecklauf; ObjectTypeOverride: Flansch; Pset MEP.Name: Flansch; IfcDescription: Flansch; Pset MEP.Tech-Material: nach DIN 2627
Phasen - Phase erstellt: Phase 01

# IfcFlowFitting: Flansch 253175:Flansch 253175, Flansch
In: 1. Obergeschoss
Type - Material: IfcSurfaceStyle #1741
Type - Andere - Kategorie: Allgemeines Modell; Familienname: Flansch 253175
Type - ID-Daten - Typname: Flansch 253175
Type - IFC-Parameter - Typ in IFC-Datei exportieren: Vorgabe
Description: Flansch
Pset_DistributionFlowElementCommon - Reference: Flansch 253175; sets with these values: 2
Andere - Typ: Flansch 253175; Familie: Flansch 253175; Familie und Typ: Flansch 253175: Flansch 253175; Typ-ID: 2532925
Abhängigkeiten - Höhe von Ebene: 0 m; Verschieben mit umliegenden Elementen: no
Bemaßungen - Fläche: 0.144185 m2; Volumen: 0.0099386 m3
IFC-Parameter - In IFC-Datei exportieren: Nach Typ; Pset MEP.Geom-Depth: 62; Pset MEP.Geom-DN: 200; Pset MEP.Geom-Outer Ø (mm): 340; Pset MEP.Tech-Insulation thickness (mm): 100; Pset MEP.Tech-PN: 16; In IFC exportieren als: ifcflowfitting; NameOverride: Flansch; IfcPresentationLayer: 0-TFT-H_Ruecklauf; ObjectTypeOverride: Flansch; Pset MEP.Name: Flansch; IfcDescription: Flansch; Pset MEP.Tech-Material: nach DIN 2627
Phasen - Phase erstellt: Phase 01

# IfcFlowFitting: Flansch 256500:Flansch 256500, Flansch
In: 1. Obergeschoss
Type - Material: IfcSurfaceStyle #1741
Type - Andere - Kategorie: Allgemeines Modell; Familienname: Flansch 256500
Type - ID-Daten - Typname: Flansch 256500
Type - IFC-Parameter - Typ in IFC-Datei exportieren: Vorgabe
Description: Flansch
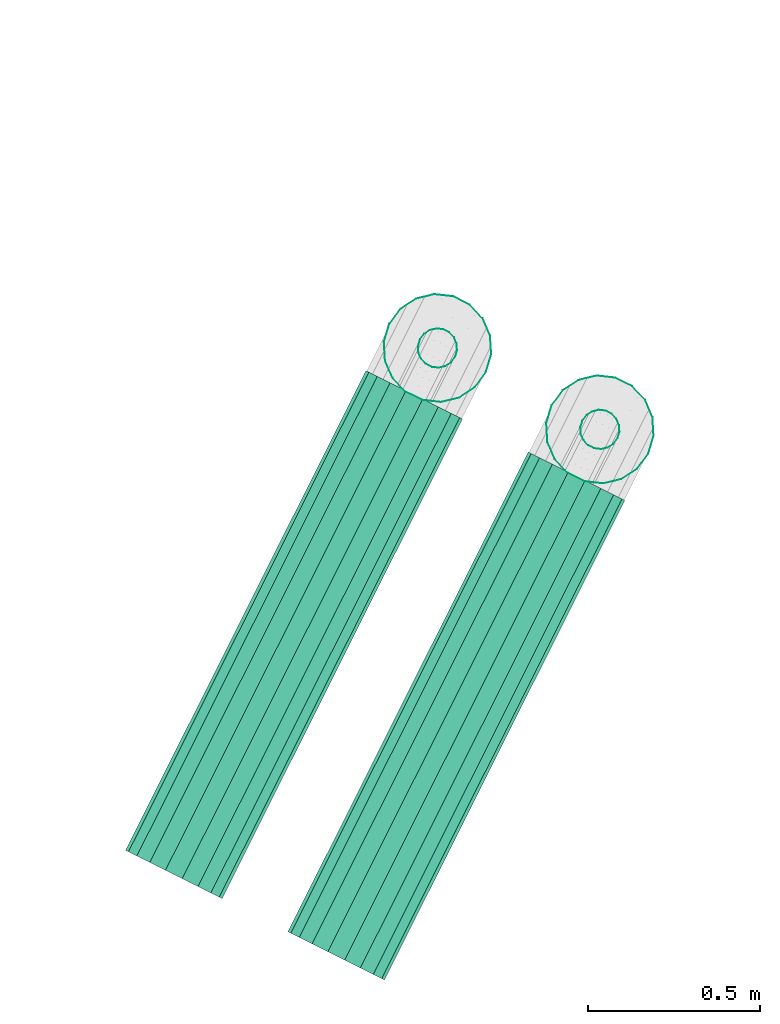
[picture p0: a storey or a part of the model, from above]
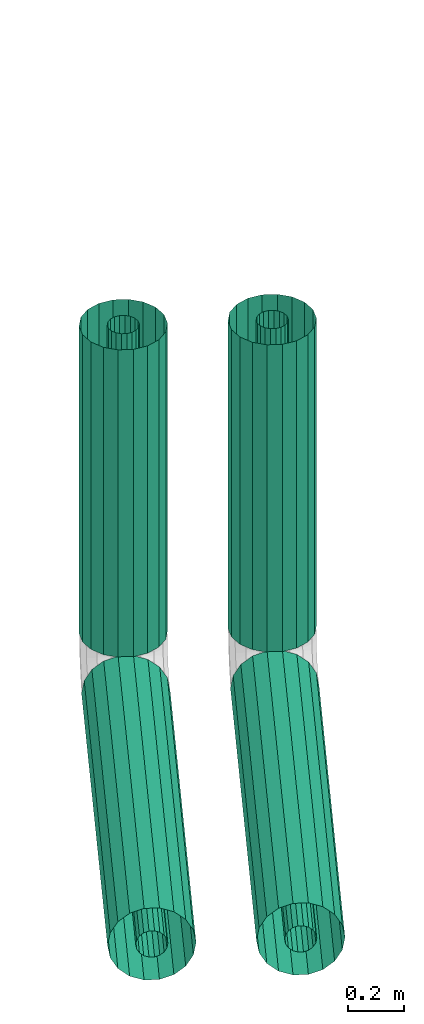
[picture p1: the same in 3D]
Properties of the parts of a building model (IFC2X3), part 8 of 23

# IfcFlowFitting: Flansch 256500:Flansch 256500, Flansch
Pset_DistributionFlowElementCommon - Reference: Flansch 256500; sets with these values: 2
Andere - Typ: Flansch 256500; Familie: Flansch 256500; Familie und Typ: Flansch 256500: Flansch 256500; Typ-ID: 2532974
Abhängigkeiten - Höhe von Ebene: 0 m; Verschieben mit umliegenden Elementen: no
Bemaßungen - Fläche: 0.0638334 m2; Volumen: 0.00317536 m3
IFC-Parameter - In IFC-Datei exportieren: Nach Typ; Pset MEP.Tech-Insulation thickness (mm): 100; Pset MEP.Tech-PN: 16; Pset MEP.Geom-DN: 65; Pset MEP.Geom-Outer Ø (mm): 185; In IFC exportieren als: ifcflowfitting; NameOverride: Flansch; IfcPresentationLayer: 0-TFT-H_Ruecklauf; ObjectTypeOverride: Flansch; Pset MEP.Name: Flansch; IfcDescription: Flansch; Pset MEP.Geom-Depth: 45; Pset MEP.Tech-Material: nach DIN 2627
Phasen - Phase erstellt: Phase 01

# IfcFlowFitting: Flansch 259105:Flansch 259105, Flansch
In: 1. Obergeschoss
Type - Material: IfcSurfaceStyle #1741
Type - Andere - Kategorie: Allgemeines Modell; Familienname: Flansch 259105
Type - ID-Daten - Typname: Flansch 259105
Type - IFC-Parameter - Typ in IFC-Datei exportieren: Vorgabe
Description: Flansch
Pset_DistributionFlowElementCommon - Reference: Flansch 259105; sets with these values: 2
Andere - Typ: Flansch 259105; Familie: Flansch 259105; Familie und Typ: Flansch 259105: Flansch 259105; Typ-ID: 2533009
Abhängigkeiten - Höhe von Ebene: 0 m; Verschieben mit umliegenden Elementen: no
Bemaßungen - Fläche: 0.0638334 m2; Volumen: 0.00317536 m3
IFC-Parameter - In IFC-Datei exportieren: Nach Typ; Pset MEP.Tech-Insulation thickness (mm): 100; Pset MEP.Tech-PN: 16; Pset MEP.Geom-DN: 65; Pset MEP.Geom-Outer Ø (mm): 185; Pset MEP.Geom-Depth: 45; In IFC exportieren als: ifcflowfitting; NameOverride: Flansch; IfcPresentationLayer: 0-TFT-H_Ruecklauf; ObjectTypeOverride: Flansch; Pset MEP.Name: Flansch; IfcDescription: Flansch; Pset MEP.Tech-Material: nach DIN 2627
Phasen - Phase erstellt: Phase 01

# IfcFlowFitting: Flansch 259128:Flansch 259128, Flansch
In: 1. Obergeschoss
Type - Material: IfcSurfaceStyle #1741
Type - Andere - Kategorie: Allgemeines Modell; Familienname: Flansch 259128
Type - ID-Daten - Typname: Flansch 259128
Type - IFC-Parameter - Typ in IFC-Datei exportieren: Vorgabe
Description: Flansch
Pset_DistributionFlowElementCommon - Reference: Flansch 259128; sets with these values: 2
Andere - Typ: Flansch 259128; Familie: Flansch 259128; Familie und Typ: Flansch 259128: Flansch 259128; Typ-ID: 2533016
Abhängigkeiten - Höhe von Ebene: 0 m; Verschieben mit umliegenden Elementen: no
Bemaßungen - Fläche: 0.0638334 m2; Volumen: 0.00317536 m3
IFC-Parameter - In IFC-Datei exportieren: Nach Typ; Pset MEP.Tech-Insulation thickness (mm): 100; Pset MEP.Tech-PN: 16; Pset MEP.Geom-DN: 65; Pset MEP.Geom-Outer Ø (mm): 185; Pset MEP.Geom-Depth: 45; In IFC exportieren als: ifcflowfitting; NameOverride: Flansch; IfcPresentationLayer: 0-TFT-H_Ruecklauf; ObjectTypeOverride: Flansch; Pset MEP.Name: Flansch; IfcDescription: Flansch; Pset MEP.Tech-Material: nach DIN 2627
Phasen - Phase erstellt: Phase 01

# IfcFlowFitting: Flansch 259232:Flansch 259232, Flansch
In: 1. Obergeschoss
Type - Material: IfcSurfaceStyle #1741
Type - Andere - Kategorie: Allgemeines Modell; Familienname: Flansch 259232
Type - ID-Daten - Typname: Flansch 259232
Type - IFC-Parameter - Typ in IFC-Datei exportieren: Vorgabe
Description: Flansch
Pset_DistributionFlowElementCommon - Reference: Flansch 259232; sets with these values: 2
Andere - Typ: Flansch 259232; Familie: Flansch 259232; Familie und Typ: Flansch 259232: Flansch 259232; Typ-ID: 2533044
Abhängigkeiten - Höhe von Ebene: 0 m; Verschieben mit umliegenden Elementen: no
Bemaßungen - Fläche: 0.0638334 m2; Volumen: 0.00380173 m3
IFC-Parameter - In IFC-Datei exportieren: Nach Typ; Pset MEP.Tech-Insulation thickness (mm): 100; Pset MEP.Tech-PN: 16; Pset MEP.Geom-DN: 65; Pset MEP.Geom-Outer Ø (mm): 185; Pset MEP.Geom-Depth: 45; In IFC exportieren als: ifcflowfitting; NameOverride: Flansch; IfcPresentationLayer: 0-TFT-H_Ruecklauf; ObjectTypeOverride: Flansch; Pset MEP.Name: Flansch; IfcDescription: Flansch; Pset MEP.Tech-Material: nach DIN 2627
Phasen - Phase erstellt: Phase 01

# IfcFlowFitting: Flansch 262090:Flansch 262090, Flansch
In: 1. Obergeschoss
Type - Material: IfcSurfaceStyle #1741
Type - Andere - Kategorie: Allgemeines Modell; Familienname: Flansch 262090
Type - ID-Daten - Typname: Flansch 262090
Type - IFC-Parameter - Typ in IFC-Datei exportieren: Vorgabe
Description: Flansch
Pset_DistributionFlowElementCommon - Reference: Flansch 262090; sets with these values: 2
Andere - Typ: Flansch 262090; Familie: Flansch 262090; Familie und Typ: Flansch 262090: Flansch 262090; Typ-ID: 2533093
Abhängigkeiten - Höhe von Ebene: 0 m; Verschieben mit umliegenden Elementen: no
Bemaßungen - Fläche: 0.0638334 m2; Volumen: 0.00317536 m3
IFC-Parameter - In IFC-Datei exportieren: Nach Typ; Pset MEP.Tech-Insulation thickness (mm): 100; Pset MEP.Tech-PN: 16; Pset MEP.Geom-DN: 65; Pset MEP.Geom-Outer Ø (mm): 185; Pset MEP.Geom-Depth: 45; In IFC exportieren als: ifcflowfitting; NameOverride: Flansch; IfcPresentationLayer: 0-TFT-H_Ruecklauf; ObjectTypeOverride: Flansch; Pset MEP.Name: Flansch; IfcDescription: Flansch; Pset MEP.Tech-Material: nach DIN 2627
Phasen - Phase erstellt: Phase 01

# IfcFlowFitting: Flansch 262119:Flansch 262119, Flansch
In: 1. Obergeschoss
Type - Material: IfcSurfaceStyle #1741
Type - Andere - Kategorie: Allgemeines Modell; Familienname: Flansch 262119
Type - ID-Daten - Typname: Flansch 262119
Type - IFC-Parameter - Typ in IFC-Datei exportieren: Vorgabe
Description: Flansch
Pset_DistributionFlowElementCommon - Reference: Flansch 262119; sets with these values: 2
Andere - Typ: Flansch 262119; Familie: Flansch 262119; Familie und Typ: Flansch 262119: Flansch 262119; Typ-ID: 2533100
Abhängigkeiten - Höhe von Ebene: 0 m; Verschieben mit umliegenden Elementen: no
Bemaßungen - Fläche: 0.0638334 m2; Volumen: 0.00380173 m3
IFC-Parameter - In IFC-Datei exportieren: Nach Typ; Pset MEP.Tech-Insulation thickness (mm): 100; Pset MEP.Tech-PN: 16; Pset MEP.Geom-DN: 65; Pset MEP.Geom-Outer Ø (mm): 185; Pset MEP.Geom-Depth: 45; In IFC exportieren als: ifcflowfitting; NameOverride: Flansch; IfcPresentationLayer: 0-TFT-H_Ruecklauf; ObjectTypeOverride: Flansch; Pset MEP.Name: Flansch; IfcDescription: Flansch; Pset MEP.Tech-Material: nach DIN 2627
Phasen - Phase erstellt: Phase 01

# IfcFlowFitting: Flansch 262727:Flansch 262727, Flansch
In: 1. Obergeschoss
Type - Material: IfcSurfaceStyle #9317
Type - Andere - Kategorie: Allgemeines Modell; Familienname: Flansch 262727
Type - ID-Daten - Typname: Flansch 262727
Type - IFC-Parameter - Typ in IFC-Datei exportieren: Vorgabe
Description: Flansch
Pset_DistributionFlowElementCommon - Reference: Flansch 262727; sets with these values: 2
Andere - Typ: Flansch 262727; Familie: Flansch 262727; Familie und Typ: Flansch 262727: Flansch 262727; Typ-ID: 2533128
Abhängigkeiten - Höhe von Ebene: 0 m; Verschieben mit umliegenden Elementen: no
Bemaßungen - Fläche: 0.144185 m2; Volumen: 0.0118373 m3
IFC-Parameter - In IFC-Datei exportieren: Nach Typ; Pset MEP.Geom-Depth: 62; Pset MEP.Geom-DN: 200; Pset MEP.Geom-Outer Ø (mm): 340; Pset MEP.Tech-Insulation thickness (mm): 100; Pset MEP.Tech-PN: 16; In IFC exportieren als: ifcflowfitting; NameOverride: Flansch; IfcPresentationLayer: 0-TFT-H_Vorlauf; ObjectTypeOverride: Flansch; Pset MEP.Name: Flansch; IfcDescription: Flansch; Pset MEP.Tech-Material: nach DIN 2627
Phasen - Phase erstellt: Phase 01

# IfcFlowFitting: Flansch 262750:Flansch 262750, Flansch
In: 1. Obergeschoss
Type - Material: IfcSurfaceStyle #9317
Type - Andere - Kategorie: Allgemeines Modell; Familienname: Flansch 262750
Type - ID-Daten - Typname: Flansch 262750
Type - IFC-Parameter - Typ in IFC-Datei exportieren: Vorgabe
Description: Flansch
Pset_DistributionFlowElementCommon - Reference: Flansch 262750; sets with these values: 2
Andere - Typ: Flansch 262750; Familie: Flansch 262750; Familie und Typ: Flansch 262750: Flansch 262750; Typ-ID: 2533135
Abhängigkeiten - Höhe von Ebene: 0 m; Verschieben mit umliegenden Elementen: no
Bemaßungen - Fläche: 0.144185 m2; Volumen: 0.0118373 m3
IFC-Parameter - In IFC-Datei exportieren: Nach Typ; Pset MEP.Geom-Depth: 62; Pset MEP.Geom-DN: 200; Pset MEP.Geom-Outer Ø (mm): 340; Pset MEP.Tech-Insulation thickness (mm): 100; Pset MEP.Tech-PN: 16; In IFC exportieren als: ifcflowfitting; NameOverride: Flansch; IfcPresentationLayer: 0-TFT-H_Vorlauf; ObjectTypeOverride: Flansch; Pset MEP.Name: Flansch; IfcDescription: Flansch; Pset MEP.Tech-Material: nach DIN 2627
Phasen - Phase erstellt: Phase 01

# IfcFlowFitting: Flansch 265680:Flansch 265680, Flansch
In: 1. Obergeschoss
Type - Material: IfcSurfaceStyle #9317
Type - Andere - Kategorie: Allgemeines Modell; Familienname: Flansch 265680
Type - ID-Daten - Typname: Flansch 265680
Type - IFC-Parameter - Typ in IFC-Datei exportieren: Vorgabe
Description: Flansch
Pset_DistributionFlowElementCommon - Reference: Flansch 265680; sets with these values: 2
Andere - Typ: Flansch 265680; Familie: Flansch 265680; Familie und Typ: Flansch 265680: Flansch 265680; Typ-ID: 2533170
Abhängigkeiten - Höhe von Ebene: 0 m; Verschieben mit umliegenden Elementen: no
Bemaßungen - Fläche: 0.0800177 m2; Volumen: 0.00543566 m3
IFC-Parameter - In IFC-Datei exportieren: Nach Typ; Pset MEP.Tech-Insulation thickness (mm): 100; Pset MEP.Tech-PN: 16; Pset MEP.Geom-DN: 100; Pset MEP.Geom-Depth: 52; Pset MEP.Geom-Outer Ø (mm): 220; In IFC exportieren als: ifcflowfitting; NameOverride: Flansch; IfcPresentationLayer: 0-TFT-H_Vorlauf; ObjectTypeOverride: Flansch; Pset MEP.Name: Flansch; IfcDescription: Flansch; Pset MEP.Tech-Material: nach DIN 2627
Phasen - Phase erstellt: Phase 01

# IfcFlowFitting: Flansch 265703:Flansch 265703, Flansch
In: 1. Obergeschoss
Type - Material: IfcSurfaceStyle #9317
Type - Andere - Kategorie: Allgemeines Modell; Familienname: Flansch 265703
Type - ID-Daten - Typname: Flansch 265703
Type - IFC-Parameter - Typ in IFC-Datei exportieren: Vorgabe
Description: Flansch
Pset_DistributionFlowElementCommon - Reference: Flansch 265703; sets with these values: 2
Andere - Typ: Flansch 265703; Familie: Flansch 265703; Familie und Typ: Flansch 265703: Flansch 265703; Typ-ID: 2533177
Abhängigkeiten - Höhe von Ebene: 0 m; Verschieben mit umliegenden Elementen: no
Bemaßungen - Fläche: 0.0800177 m2; Volumen: 0.00543566 m3
IFC-Parameter - In IFC-Datei exportieren: Nach Typ; Pset MEP.Tech-Insulation thickness (mm): 100; Pset MEP.Tech-PN: 16; Pset MEP.Geom-DN: 100; Pset MEP.Geom-Depth: 52; Pset MEP.Geom-Outer Ø (mm): 220; In IFC exportieren als: ifcflowfitting; NameOverride: Flansch; IfcPresentationLayer: 0-TFT-H_Vorlauf; ObjectTypeOverride: Flansch; Pset MEP.Name: Flansch; IfcDescription: Flansch; Pset MEP.Tech-Material: nach DIN 2627
Phasen - Phase erstellt: Phase 01

# IfcFlowFitting: Flansch 267347:Flansch 267347, Flansch
In: 1. Obergeschoss
Type - Material: IfcSurfaceStyle #9317
Type - Andere - Kategorie: Allgemeines Modell; Familienname: Flansch 267347
Type - ID-Daten - Typname: Flansch 267347
Type - IFC-Parameter - Typ in IFC-Datei exportieren: Vorgabe
Description: Flansch
Pset_DistributionFlowElementCommon - Reference: Flansch 267347; sets with these values: 2
Andere - Typ: Flansch 267347; Familie: Flansch 267347; Familie und Typ: Flansch 267347: Flansch 267347; Typ-ID: 2533226
Abhängigkeiten - Höhe von Ebene: 0 m; Verschieben mit umliegenden Elementen: no
Bemaßungen - Fläche: 0.0800177 m2; Volumen: 0.00456789 m3
IFC-Parameter - In IFC-Datei exportieren: Nach Typ; Pset MEP.Tech-Insulation thickness (mm): 100; Pset MEP.Tech-PN: 16; Pset MEP.Geom-DN: 100; Pset MEP.Geom-Depth: 52; Pset MEP.Geom-Outer Ø (mm): 220; In IFC exportieren als: ifcflowfitting; NameOverride: Flansch; IfcPresentationLayer: 0-TFT-H_Vorlauf; ObjectTypeOverride: Flansch; Pset MEP.Name: Flansch; IfcDescription: Flansch; Pset MEP.Tech-Material: nach DIN 2627
Phasen - Phase erstellt: Phase 01

# IfcFlowFitting: Flansch 267399:Flansch 267399, Flansch
In: 1. Obergeschoss
Type - Material: IfcSurfaceStyle #9317
Type - Andere - Kategorie: Allgemeines Modell; Familienname: Flansch 267399
Type - ID-Daten - Typname: Flansch 267399
Type - IFC-Parameter - Typ in IFC-Datei exportieren: Vorgabe
Description: Flansch
Pset_DistributionFlowElementCommon - Reference: Flansch 267399; sets with these values: 2
Andere - Typ: Flansch 267399; Familie: Flansch 267399; Familie und Typ: Flansch 267399: Flansch 267399; Typ-ID: 2533240
Abhängigkeiten - Höhe von Ebene: 0 m; Verschieben mit umliegenden Elementen: no
Bemaßungen - Fläche: 0.0800177 m2; Volumen: 0.00543566 m3
IFC-Parameter - In IFC-Datei exportieren: Nach Typ; Pset MEP.Tech-Insulation thickness (mm): 100; Pset MEP.Tech-PN: 16; Pset MEP.Geom-DN: 100; Pset MEP.Geom-Depth: 52; Pset MEP.Geom-Outer Ø (mm): 220; In IFC exportieren als: ifcflowfitting; NameOverride: Flansch; IfcPresentationLayer: 0-TFT-H_Vorlauf; ObjectTypeOverride: Flansch; Pset MEP.Name: Flansch; IfcDescription: Flansch; Pset MEP.Tech-Material: nach DIN 2627
Phasen - Phase erstellt: Phase 01

# IfcFlowFitting: Flansch 293605:Flansch 293605, Flansch
In: Erdgeschoss
Type - Material: IfcSurfaceStyle #9317
Type - Andere - Kategorie: Allgemeines Modell; Familienname: Flansch 293605
Type - ID-Daten - Typname: Flansch 293605
Type - IFC-Parameter - Typ in IFC-Datei exportieren: Vorgabe
Description: Flansch
Pset_DistributionFlowElementCommon - Reference: Flansch 293605; sets with these values: 2
Andere - Typ: Flansch 293605; Familie: Flansch 293605; Familie und Typ: Flansch 293605: Flansch 293605; Typ-ID: 2534396
Abhängigkeiten - Höhe von Ebene: 0 m; Verschieben mit umliegenden Elementen: no
Bemaßungen - Fläche: 0.0724331 m2; Volumen: 0.0046363 m3
IFC-Parameter - In IFC-Datei exportieren: Nach Typ; Pset MEP.Tech-Insulation thickness (mm): 100; Pset MEP.Tech-PN: 16; Pset MEP.Geom-DN: 80; Pset MEP.Geom-Depth: 50; Pset MEP.Geom-Outer Ø (mm): 200; In IFC exportieren als: ifcflowfitting; NameOverride: Flansch; IfcPresentationLayer: 0-TFT-H_Vorlauf; ObjectTypeOverride: Flansch; Pset MEP.Name: Flansch; IfcDescription: Flansch; Pset MEP.Tech-Material: nach DIN 2627
Phasen - Phase erstellt: Phase 01

# IfcFlowFitting: Flansch 301516:Flansch 301516, Flansch
In: Erdgeschoss
Type - Material: IfcSurfaceStyle #1741
Type - Andere - Kategorie: Allgemeines Modell; Familienname: Flansch 301516
Type - ID-Daten - Typname: Flansch 301516
Type - IFC-Parameter - Typ in IFC-Datei exportieren: Vorgabe
Description: Flansch
Pset_DistributionFlowElementCommon - Reference: Flansch 301516; sets with these values: 2
Andere - Typ: Flansch 301516; Familie: Flansch 301516; Familie und Typ: Flansch 301516: Flansch 301516; Typ-ID: 2534783
Abhängigkeiten - Höhe von Ebene: 0 m; Verschieben mit umliegenden Elementen: no
Bemaßungen - Fläche: 0.144185 m2; Volumen: 0.0099386 m3
IFC-Parameter - In IFC-Datei exportieren: Nach Typ; Pset MEP.Geom-Depth: 62; Pset MEP.Geom-DN: 200; Pset MEP.Geom-Outer Ø (mm): 340; Pset MEP.Tech-Insulation thickness (mm): 100; Pset MEP.Tech-PN: 16; In IFC exportieren als: ifcflowfitting; NameOverride: Flansch; IfcPresentationLayer: 0-TFT-H_Ruecklauf; ObjectTypeOverride: Flansch; Pset MEP.Name: Flansch; IfcDescription: Flansch; Pset MEP.Tech-Material: nach DIN 2627
Phasen - Phase erstellt: Phase 01

# IfcFlowFitting: Flansch 301545:Flansch 301545, Flansch
In: Erdgeschoss
Type - Material: IfcSurfaceStyle #1741
Type - Andere - Kategorie: Allgemeines Modell; Familienname: Flansch 301545
Type - ID-Daten - Typname: Flansch 301545
Type - IFC-Parameter - Typ in IFC-Datei exportieren: Vorgabe
Description: Flansch
Pset_DistributionFlowElementCommon - Reference: Flansch 301545; sets with these values: 2
Andere - Typ: Flansch 301545; Familie: Flansch 301545; Familie und Typ: Flansch 301545: Flansch 301545; Typ-ID: 2534790
Abhängigkeiten - Höhe von Ebene: 0 m; Verschieben mit umliegenden Elementen: no
Bemaßungen - Fläche: 0.144185 m2; Volumen: 0.0099386 m3
IFC-Parameter - In IFC-Datei exportieren: Nach Typ; Pset MEP.Geom-Depth: 62; Pset MEP.Geom-DN: 200; Pset MEP.Geom-Outer Ø (mm): 340; Pset MEP.Tech-Insulation thickness (mm): 100; Pset MEP.Tech-PN: 16; In IFC exportieren als: ifcflowfitting; NameOverride: Flansch; IfcPresentationLayer: 0-TFT-H_Ruecklauf; ObjectTypeOverride: Flansch; Pset MEP.Name: Flansch; IfcDescription: Flansch; Pset MEP.Tech-Material: nach DIN 2627
Phasen - Phase erstellt: Phase 01

# IfcFlowFitting: Flansch 301574:Flansch 301574, Flansch
In: 1. Obergeschoss
Type - Material: IfcSurfaceStyle #9317
Type - Andere - Kategorie: Allgemeines Modell; Familienname: Flansch 301574
Type - ID-Daten - Typname: Flansch 301574
Type - IFC-Parameter - Typ in IFC-Datei exportieren: Vorgabe
Description: Flansch
Pset_DistributionFlowElementCommon - Reference: Flansch 301574; sets with these values: 2
Andere - Typ: Flansch 301574; Familie: Flansch 301574; Familie und Typ: Flansch 301574: Flansch 301574; Typ-ID: 2534797
Abhängigkeiten - Höhe von Ebene: 0 m; Verschieben mit umliegenden Elementen: no
Bemaßungen - Fläche: 0.144185 m2; Volumen: 0.0118373 m3
IFC-Parameter - In IFC-Datei exportieren: Nach Typ; Pset MEP.Geom-Depth: 62; Pset MEP.Geom-DN: 200; Pset MEP.Geom-Outer Ø (mm): 340; Pset MEP.Tech-Insulation thickness (mm): 100; Pset MEP.Tech-PN: 16; In IFC exportieren als: ifcflowfitting; NameOverride: Flansch; IfcPresentationLayer: 0-TFT-H_Vorlauf; ObjectTypeOverride: Flansch; Pset MEP.Name: Flansch; IfcDescription: Flansch; Pset MEP.Tech-Material: nach DIN 2627
Phasen - Phase erstellt: Phase 01

# IfcFlowFitting: Flansch 303291:Flansch 303291, Flansch
In: 1. Obergeschoss
Type - Material: IfcSurfaceStyle #9317
Type - Andere - Kategorie: Allgemeines Modell; Familienname: Flansch 303291
Type - ID-Daten - Typname: Flansch 303291
Type - IFC-Parameter - Typ in IFC-Datei exportieren: Vorgabe
Description: Flansch
Pset_DistributionFlowElementCommon - Reference: Flansch 303291; sets with these values: 2
Andere - Typ: Flansch 303291; Familie: Flansch 303291; Familie und Typ: Flansch 303291: Flansch 303291; Typ-ID: 2534811
Abhängigkeiten - Höhe von Ebene: 0 m; Verschieben mit umliegenden Elementen: no
Bemaßungen - Fläche: 0.144185 m2; Volumen: 0.0099386 m3
IFC-Parameter - In IFC-Datei exportieren: Nach Typ; Pset MEP.Geom-Depth: 62; Pset MEP.Geom-DN: 200; Pset MEP.Geom-Outer Ø (mm): 340; Pset MEP.Tech-Insulation thickness (mm): 100; Pset MEP.Tech-PN: 16; In IFC exportieren als: ifcflowfitting; NameOverride: Flansch; IfcPresentationLayer: 0-TFT-H_Vorlauf; ObjectTypeOverride: Flansch; Pset MEP.Name: Flansch; IfcDescription: Flansch; Pset MEP.Tech-Material: nach DIN 2627
Phasen - Phase erstellt: Phase 01

# IfcFlowFitting: Flansch 303318:Flansch 303318, Flansch
In: 1. Obergeschoss
Type - Material: IfcSurfaceStyle #9317
Type - Andere - Kategorie: Allgemeines Modell; Familienname: Flansch 303318
Type - ID-Daten - Typname: Flansch 303318
Type - IFC-Parameter - Typ in IFC-Datei exportieren: Vorgabe
Description: Flansch
Pset_DistributionFlowElementCommon - Reference: Flansch 303318; sets with these values: 2
Andere - Typ: Flansch 303318; Familie: Flansch 303318; Familie und Typ: Flansch 303318: Flansch 303318; Typ-ID: 2534818
Abhängigkeiten - Höhe von Ebene: 0 m; Verschieben mit umliegenden Elementen: no
Bemaßungen - Fläche: 0.144185 m2; Volumen: 0.0099386 m3
IFC-Parameter - In IFC-Datei exportieren: Nach Typ; Pset MEP.Geom-Depth: 62; Pset MEP.Geom-DN: 200; Pset MEP.Geom-Outer Ø (mm): 340; Pset MEP.Tech-Insulation thickness (mm): 100; Pset MEP.Tech-PN: 16; In IFC exportieren als: ifcflowfitting; NameOverride: Flansch; IfcPresentationLayer: 0-TFT-H_Vorlauf; ObjectTypeOverride: Flansch; Pset MEP.Name: Flansch; IfcDescription: Flansch; Pset MEP.Tech-Material: nach DIN 2627
Phasen - Phase erstellt: Phase 01

# IfcFlowFitting: Flansch 303626:Flansch 303626, Flansch
In: 1. Obergeschoss
Type - Material: IfcSurfaceStyle #9317
Type - Andere - Kategorie: Allgemeines Modell; Familienname: Flansch 303626
Type - ID-Daten - Typname: Flansch 303626
Type - IFC-Parameter - Typ in IFC-Datei exportieren: Vorgabe
Description: Flansch
Pset_DistributionFlowElementCommon - Reference: Flansch 303626; sets with these values: 2
Andere - Typ: Flansch 303626; Familie: Flansch 303626; Familie und Typ: Flansch 303626: Flansch 303626; Typ-ID: 2534832
Abhängigkeiten - Höhe von Ebene: 0 m; Verschieben mit umliegenden Elementen: no
Bemaßungen - Fläche: 0.144185 m2; Volumen: 0.0099386 m3
IFC-Parameter - In IFC-Datei exportieren: Nach Typ; Pset MEP.Geom-Depth: 62; Pset MEP.Geom-DN: 200; Pset MEP.Geom-Outer Ø (mm): 340; Pset MEP.Tech-Insulation thickness (mm): 100; Pset MEP.Tech-PN: 16; In IFC exportieren als: ifcflowfitting; NameOverride: Flansch; IfcPresentationLayer: 0-TFT-H_Vorlauf; ObjectTypeOverride: Flansch; Pset MEP.Name: Flansch; IfcDescription: Flansch; Pset MEP.Tech-Material: nach DIN 2627
Phasen - Phase erstellt: Phase 01

# IfcFlowFitting: Flansch 303653:Flansch 303653, Flansch
In: Erdgeschoss
Type - Material: IfcSurfaceStyle #1741
Type - Andere - Kategorie: Allgemeines Modell; Familienname: Flansch 303653
Type - ID-Daten - Typname: Flansch 303653
Type - IFC-Parameter - Typ in IFC-Datei exportieren: Vorgabe
Description: Flansch
Pset_DistributionFlowElementCommon - Reference: Flansch 303653; sets with these values: 2
Andere - Typ: Flansch 303653; Familie: Flansch 303653; Familie und Typ: Flansch 303653: Flansch 303653; Typ-ID: 2534839
Abhängigkeiten - Höhe von Ebene: 0 m; Verschieben mit umliegenden Elementen: no
Bemaßungen - Fläche: 0.0503828 m2; Volumen: 0.00171028 m3
IFC-Parameter - In IFC-Datei exportieren: Nach Typ; Pset MEP.Tech-Insulation thickness (mm): 100; Pset MEP.Tech-PN: 16; Pset MEP.Geom-Depth: 55; Pset MEP.Geom-DN: 150; Pset MEP.Geom-Outer Ø (mm): 285; In IFC exportieren als: ifcflowfitting; NameOverride: Flansch; IfcPresentationLayer: 0-TFT-H_Ruecklauf; ObjectTypeOverride: Flansch; Pset MEP.Name: Flansch; IfcDescription: Flansch; Pset MEP.Tech-Material: nach DIN 2627
Phasen - Phase erstellt: Phase 01

# IfcFlowFitting: Flansch 304728:Flansch 304728, Flansch
In: Erdgeschoss
Type - Material: IfcSurfaceStyle #9317
Type - Andere - Kategorie: Allgemeines Modell; Familienname: Flansch 304728
Type - ID-Daten - Typname: Flansch 304728
Type - IFC-Parameter - Typ in IFC-Datei exportieren: Vorgabe
Description: Flansch
Pset_DistributionFlowElementCommon - Reference: Flansch 304728; sets with these values: 2
Andere - Typ: Flansch 304728; Familie: Flansch 304728; Familie und Typ: Flansch 304728: Flansch 304728; Typ-ID: 2534930
Abhängigkeiten - Höhe von Ebene: 0 m; Verschieben mit umliegenden Elementen: no
Bemaßungen - Fläche: 0.0503828 m2; Volumen: 0.00171028 m3
IFC-Parameter - In IFC-Datei exportieren: Nach Typ; Pset MEP.Tech-Insulation thickness (mm): 100; Pset MEP.Tech-PN: 16; Pset MEP.Geom-Depth: 55; Pset MEP.Geom-DN: 150; Pset MEP.Geom-Outer Ø (mm): 285; In IFC exportieren als: ifcflowfitting; NameOverride: Flansch; IfcPresentationLayer: 0-TFT-H_Vorlauf; ObjectTypeOverride: Flansch; Pset MEP.Name: Flansch; IfcDescription: Flansch; Pset MEP.Tech-Material: nach DIN 2627
Phasen - Phase erstellt: Phase 01

# IfcFlowFitting: Flansch 307744:Flansch 307744, Flansch
In: Erdgeschoss
Type - Material: IfcSurfaceStyle #1741
Type - Andere - Kategorie: Allgemeines Modell; Familienname: Flansch 307744
Type - ID-Daten - Typname: Flansch 307744
Type - IFC-Parameter - Typ in IFC-Datei exportieren: Vorgabe
Description: Flansch
Pset_DistributionFlowElementCommon - Reference: Flansch 307744; sets with these values: 2
Andere - Typ: Flansch 307744; Familie: Flansch 307744; Familie und Typ: Flansch 307744: Flansch 307744; Typ-ID: 2534993
Abhängigkeiten - Höhe von Ebene: 0 m; Verschieben mit umliegenden Elementen: no
Bemaßungen - Fläche: 0.0318326 m2; Volumen: 0.000895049 m3
IFC-Parameter - In IFC-Datei exportieren: Nach Typ; Pset MEP.Tech-Insulation thickness (mm): 100; Pset MEP.Tech-PN: 16; Pset MEP.Geom-DN: 100; Pset MEP.Geom-Depth: 52; Pset MEP.Geom-Outer Ø (mm): 220; In IFC exportieren als: ifcflowfitting; NameOverride: Flansch; IfcPresentationLayer: 0-TFT-H_Ruecklauf; ObjectTypeOverride: Flansch; Pset MEP.Name: Flansch; IfcDescription: Flansch; Pset MEP.Tech-Material: nach DIN 2627
Phasen - Phase erstellt: Phase 01

# IfcFlowFitting: Flansch 307790:Flansch 307790, Flansch
In: Erdgeschoss
Type - Material: IfcSurfaceStyle #1741
Type - Andere - Kategorie: Allgemeines Modell; Familienname: Flansch 307790
Type - ID-Daten - Typname: Flansch 307790
Type - IFC-Parameter - Typ in IFC-Datei exportieren: Vorgabe
Description: Flansch
Pset_DistributionFlowElementCommon - Reference: Flansch 307790; sets with these values: 2
Andere - Typ: Flansch 307790; Familie: Flansch 307790; Familie und Typ: Flansch 307790: Flansch 307790; Typ-ID: 2535007
Abhängigkeiten - Höhe von Ebene: 0 m; Verschieben mit umliegenden Elementen: no
Bemaßungen - Fläche: 0.0404913 m2; Volumen: 0.00128585 m3
IFC-Parameter - In IFC-Datei exportieren: Nach Typ; Pset MEP.Tech-Insulation thickness (mm): 100; Pset MEP.Tech-PN: 16; Pset MEP.Geom-Depth: 55; Pset MEP.Geom-DN: 125; Pset MEP.Geom-Outer Ø (mm): 250; In IFC exportieren als: ifcflowfitting; NameOverride: Flansch; IfcPresentationLayer: 0-TFT-H_Ruecklauf; ObjectTypeOverride: Flansch; Pset MEP.Name: Flansch; IfcDescription: Flansch; Pset MEP.Tech-Material: nach DIN 2627
Phasen - Phase erstellt: Phase 01

# IfcFlowFitting: Flansch 307813:Flansch 307813, Flansch
In: 1. Obergeschoss
Type - Material: IfcSurfaceStyle #1741
Type - Andere - Kategorie: Allgemeines Modell; Familienname: Flansch 307813
Type - ID-Daten - Typname: Flansch 307813
Type - IFC-Parameter - Typ in IFC-Datei exportieren: Vorgabe
Description: Flansch
Pset_DistributionFlowElementCommon - Reference: Flansch 307813; sets with these values: 2
Andere - Typ: Flansch 307813; Familie: Flansch 307813; Familie und Typ: Flansch 307813: Flansch 307813; Typ-ID: 2535014
Abhängigkeiten - Höhe von Ebene: 0 m; Verschieben mit umliegenden Elementen: no
Bemaßungen - Fläche: 0.0318326 m2; Volumen: 0.000895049 m3
IFC-Parameter - In IFC-Datei exportieren: Nach Typ; Pset MEP.Tech-Insulation thickness (mm): 100; Pset MEP.Tech-PN: 16; Pset MEP.Geom-DN: 100; Pset MEP.Geom-Depth: 52; Pset MEP.Geom-Outer Ø (mm): 220; In IFC exportieren als: ifcflowfitting; NameOverride: Flansch; IfcPresentationLayer: 0-TFT-H_Ruecklauf; ObjectTypeOverride: Flansch; Pset MEP.Name: Flansch; IfcDescription: Flansch; Pset MEP.Tech-Material: nach DIN 2627
Phasen - Phase erstellt: Phase 01

# IfcFlowFitting: Flansch 309235:Flansch 309235, Flansch
In: Erdgeschoss
Type - Material: IfcSurfaceStyle #1741
Type - Andere - Kategorie: Allgemeines Modell; Familienname: Flansch 309235
Type - ID-Daten - Typname: Flansch 309235
Type - IFC-Parameter - Typ in IFC-Datei exportieren: Vorgabe
Description: Flansch
Pset_DistributionFlowElementCommon - Reference: Flansch 309235; sets with these values: 2
Andere - Typ: Flansch 309235; Familie: Flansch 309235; Familie und Typ: Flansch 309235: Flansch 309235; Typ-ID: 2535035
Abhängigkeiten - Höhe von Ebene: 0 m; Verschieben mit umliegenden Elementen: no
Bemaßungen - Fläche: 0.0318326 m2; Volumen: 0.000895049 m3
IFC-Parameter - In IFC-Datei exportieren: Nach Typ; Pset MEP.Tech-Insulation thickness (mm): 100; Pset MEP.Tech-PN: 16; Pset MEP.Geom-DN: 100; Pset MEP.Geom-Depth: 52; Pset MEP.Geom-Outer Ø (mm): 220; In IFC exportieren als: ifcflowfitting; NameOverride: Flansch; IfcPresentationLayer: 0-TFT-H_Ruecklauf; ObjectTypeOverride: Flansch; Pset MEP.Name: Flansch; IfcDescription: Flansch; Pset MEP.Tech-Material: nach DIN 2627
Phasen - Phase erstellt: Phase 01

# IfcFlowFitting: Flansch 309258:Flansch 309258, Flansch
In: Erdgeschoss
Type - Material: IfcSurfaceStyle #1741
Type - Andere - Kategorie: Allgemeines Modell; Familienname: Flansch 309258
Type - ID-Daten - Typname: Flansch 309258
Type - IFC-Parameter - Typ in IFC-Datei exportieren: Vorgabe
Description: Flansch
Pset_DistributionFlowElementCommon - Reference: Flansch 309258; sets with these values: 2
Andere - Typ: Flansch 309258; Familie: Flansch 309258; Familie und Typ: Flansch 309258: Flansch 309258; Typ-ID: 2535042
Abhängigkeiten - Höhe von Ebene: 0 m; Verschieben mit umliegenden Elementen: no
Bemaßungen - Fläche: 0.0404913 m2; Volumen: 0.00128585 m3
IFC-Parameter - In IFC-Datei exportieren: Nach Typ; Pset MEP.Tech-Insulation thickness (mm): 100; Pset MEP.Tech-PN: 16; Pset MEP.Geom-Depth: 55; Pset MEP.Geom-DN: 125; Pset MEP.Geom-Outer Ø (mm): 250; In IFC exportieren als: ifcflowfitting; NameOverride: Flansch; IfcPresentationLayer: 0-TFT-H_Ruecklauf; ObjectTypeOverride: Flansch; Pset MEP.Name: Flansch; IfcDescription: Flansch; Pset MEP.Tech-Material: nach DIN 2627
Phasen - Phase erstellt: Phase 01

# IfcFlowFitting: Flansch 309281:Flansch 309281, Flansch
In: Erdgeschoss
Type - Material: IfcSurfaceStyle #1741
Type - Andere - Kategorie: Allgemeines Modell; Familienname: Flansch 309281
Type - ID-Daten - Typname: Flansch 309281
Type - IFC-Parameter - Typ in IFC-Datei exportieren: Vorgabe
Description: Flansch
Pset_DistributionFlowElementCommon - Reference: Flansch 309281; sets with these values: 2
Andere - Typ: Flansch 309281; Familie: Flansch 309281; Familie und Typ: Flansch 309281: Flansch 309281; Typ-ID: 2535049
Abhängigkeiten - Höhe von Ebene: 0 m; Verschieben mit umliegenden Elementen: no
Bemaßungen - Fläche: 0.0404913 m2; Volumen: 0.00128585 m3
IFC-Parameter - In IFC-Datei exportieren: Nach Typ; Pset MEP.Tech-Insulation thickness (mm): 100; Pset MEP.Tech-PN: 16; Pset MEP.Geom-Depth: 55; Pset MEP.Geom-DN: 125; Pset MEP.Geom-Outer Ø (mm): 250; In IFC exportieren als: ifcflowfitting; NameOverride: Flansch; IfcPresentationLayer: 0-TFT-H_Ruecklauf; ObjectTypeOverride: Flansch; Pset MEP.Name: Flansch; IfcDescription: Flansch; Pset MEP.Tech-Material: nach DIN 2627
Phasen - Phase erstellt: Phase 01

# IfcFlowFitting: Flansch 311528:Flansch 311528, Flansch
In: 1. Obergeschoss
Type - Material: IfcSurfaceStyle #1741
Type - Andere - Kategorie: Allgemeines Modell; Familienname: Flansch 311528
Type - ID-Daten - Typname: Flansch 311528
Type - IFC-Parameter - Typ in IFC-Datei exportieren: Vorgabe
Description: Flansch
Pset_DistributionFlowElementCommon - Reference: Flansch 311528; sets with these values: 2
Andere - Typ: Flansch 311528; Familie: Flansch 311528; Familie und Typ: Flansch 311528: Flansch 311528; Typ-ID: 2535105
Abhängigkeiten - Höhe von Ebene: 0 m; Verschieben mit umliegenden Elementen: no
Bemaßungen - Fläche: 0.0318326 m2; Volumen: 0.000544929 m3
IFC-Parameter - In IFC-Datei exportieren: Nach Typ; Pset MEP.Tech-Insulation thickness (mm): 100; Pset MEP.Tech-PN: 16; Pset MEP.Geom-DN: 100; Pset MEP.Geom-Depth: 52; Pset MEP.Geom-Outer Ø (mm): 220; In IFC exportieren als: ifcflowfitting; NameOverride: Flansch; IfcPresentationLayer: 0-TFT-H_Ruecklauf; ObjectTypeOverride: Flansch; Pset MEP.Name: Flansch; IfcDescription: Flansch; Pset MEP.Tech-Material: nach DIN 2627
Phasen - Phase erstellt: Phase 01

# IfcFlowFitting: Flansch 311584:Flansch 311584, Flansch
In: Erdgeschoss
Type - Material: IfcSurfaceStyle #1741
Type - Andere - Kategorie: Allgemeines Modell; Familienname: Flansch 311584
Type - ID-Daten - Typname: Flansch 311584
Type - IFC-Parameter - Typ in IFC-Datei exportieren: Vorgabe
Description: Flansch
Pset_DistributionFlowElementCommon - Reference: Flansch 311584; sets with these values: 2
Andere - Typ: Flansch 311584; Familie: Flansch 311584; Familie und Typ: Flansch 311584: Flansch 311584; Typ-ID: 2535119
Abhängigkeiten - Höhe von Ebene: 0 m; Verschieben mit umliegenden Elementen: no
Bemaßungen - Fläche: 0.0404913 m2; Volumen: 0.00128585 m3
IFC-Parameter - In IFC-Datei exportieren: Nach Typ; Pset MEP.Tech-PN: 16; Pset MEP.Geom-Depth: 55; Pset MEP.Geom-DN: 125; Pset MEP.Geom-Outer Ø (mm): 250; In IFC exportieren als: ifcflowfitting; NameOverride: Flansch; IfcPresentationLayer: 0-TFT-H_Ruecklauf; ObjectTypeOverride: Flansch; Pset MEP.Name: Flansch; IfcDescription: Flansch; Pset MEP.Tech-Material: nach DIN 2627
Phasen - Phase erstellt: Phase 01

# IfcFlowFitting: Flansch 311610:Flansch 311610, Flansch
In: Erdgeschoss
Type - Material: IfcSurfaceStyle #1741
Type - Andere - Kategorie: Allgemeines Modell; Familienname: Flansch 311610
Type - ID-Daten - Typname: Flansch 311610
Type - IFC-Parameter - Typ in IFC-Datei exportieren: Vorgabe
Description: Flansch
Pset_DistributionFlowElementCommon - Reference: Flansch 311610; sets with these values: 2
Andere - Typ: Flansch 311610; Familie: Flansch 311610; Familie und Typ: Flansch 311610: Flansch 311610; Typ-ID: 2535126
Abhängigkeiten - Höhe von Ebene: 0 m; Verschieben mit umliegenden Elementen: no
Bemaßungen - Fläche: 0.0404913 m2; Volumen: 0.00128585 m3
IFC-Parameter - In IFC-Datei exportieren: Nach Typ; Pset MEP.Tech-Insulation thickness (mm): 100; Pset MEP.Tech-PN: 16; Pset MEP.Geom-Depth: 55; Pset MEP.Geom-DN: 125; Pset MEP.Geom-Outer Ø (mm): 250; In IFC exportieren als: ifcflowfitting; NameOverride: Flansch; IfcPresentationLayer: 0-TFT-H_Ruecklauf; ObjectTypeOverride: Flansch; Pset MEP.Name: Flansch; IfcDescription: Flansch; Pset MEP.Tech-Material: nach DIN 2627
Phasen - Phase erstellt: Phase 01

# IfcFlowFitting: Flansch 314715:Flansch 314715, Flansch
In: Erdgeschoss
Type - Material: IfcSurfaceStyle #1741
Type - Andere - Kategorie: Allgemeines Modell; Familienname: Flansch 314715
Type - ID-Daten - Typname: Flansch 314715
Type - IFC-Parameter - Typ in IFC-Datei exportieren: Vorgabe
Description: Flansch
Pset_DistributionFlowElementCommon - Reference: Flansch 314715; sets with these values: 2
Andere - Typ: Flansch 314715; Familie: Flansch 314715; Familie und Typ: Flansch 314715: Flansch 314715; Typ-ID: 2535152
Abhängigkeiten - Höhe von Ebene: 0 m; Verschieben mit umliegenden Elementen: no
Bemaßungen - Fläche: 0.0404913 m2; Volumen: 0.00128585 m3
IFC-Parameter - In IFC-Datei exportieren: Nach Typ; Pset MEP.Tech-Insulation thickness (mm): 100; Pset MEP.Tech-PN: 16; Pset MEP.Geom-Depth: 55; Pset MEP.Geom-DN: 125; Pset MEP.Geom-Outer Ø (mm): 250; In IFC exportieren als: ifcflowfitting; NameOverride: Flansch; IfcPresentationLayer: 0-TFT-H_Ruecklauf; ObjectTypeOverride: Flansch; Pset MEP.Name: Flansch; IfcDescription: Flansch; Pset MEP.Tech-Material: nach DIN 2627
Phasen - Phase erstellt: Phase 01

# IfcFlowFitting: Flansch 314916:Flansch 314916, Flansch
In: Erdgeschoss
Type - Material: IfcSurfaceStyle #1741
Type - Andere - Kategorie: Allgemeines Modell; Familienname: Flansch 314916
Type - ID-Daten - Typname: Flansch 314916
Type - IFC-Parameter - Typ in IFC-Datei exportieren: Vorgabe
Description: Flansch
Pset_DistributionFlowElementCommon - Reference: Flansch 314916; sets with these values: 2
Andere - Typ: Flansch 314916; Familie: Flansch 314916; Familie und Typ: Flansch 314916: Flansch 314916; Typ-ID: 2535173
Abhängigkeiten - Höhe von Ebene: 0 m; Verschieben mit umliegenden Elementen: no
Bemaßungen - Fläche: 0.0503828 m2; Volumen: 0.00109829 m3
IFC-Parameter - In IFC-Datei exportieren: Nach Typ; Pset MEP.Tech-Insulation thickness (mm): 100; Pset MEP.Tech-PN: 16; Pset MEP.Geom-Depth: 55; Pset MEP.Geom-DN: 150; Pset MEP.Geom-Outer Ø (mm): 285; In IFC exportieren als: ifcflowfitting; NameOverride: Flansch; IfcPresentationLayer: 0-TFT-H_Ruecklauf; ObjectTypeOverride: Flansch; Pset MEP.Name: Flansch; IfcDescription: Flansch; Pset MEP.Tech-Material: nach DIN 2627
Phasen - Phase erstellt: Phase 01

# IfcFlowFitting: Flansch 314957:Flansch 314957, Flansch
In: Erdgeschoss
Type - Material: IfcSurfaceStyle #1741
Type - Andere - Kategorie: Allgemeines Modell; Familienname: Flansch 314957
Type - ID-Daten - Typname: Flansch 314957
Type - IFC-Parameter - Typ in IFC-Datei exportieren: Vorgabe
Description: Flansch
Pset_DistributionFlowElementCommon - Reference: Flansch 314957; sets with these values: 2
Andere - Typ: Flansch 314957; Familie: Flansch 314957; Familie und Typ: Flansch 314957: Flansch 314957; Typ-ID: 2535180
Abhängigkeiten - Höhe von Ebene: 0 m; Verschieben mit umliegenden Elementen: no
Bemaßungen - Fläche: 0.0503828 m2; Volumen: 0.00171028 m3
IFC-Parameter - In IFC-Datei exportieren: Nach Typ; Pset MEP.Tech-Insulation thickness (mm): 100; Pset MEP.Tech-PN: 16; Pset MEP.Geom-Depth: 55; Pset MEP.Geom-DN: 150; Pset MEP.Geom-Outer Ø (mm): 285; In IFC exportieren als: ifcflowfitting; NameOverride: Flansch; IfcPresentationLayer: 0-TFT-H_Ruecklauf; ObjectTypeOverride: Flansch; Pset MEP.Name: Flansch; IfcDescription: Flansch; Pset MEP.Tech-Material: nach DIN 2627
Phasen - Phase erstellt: Phase 01

# IfcFlowFitting: Flansch 316667:Flansch 316667, Flansch
In: 1. Obergeschoss
Type - Material: IfcSurfaceStyle #1741
Type - Andere - Kategorie: Allgemeines Modell; Familienname: Flansch 316667
Type - ID-Daten - Typname: Flansch 316667
Type - IFC-Parameter - Typ in IFC-Datei exportieren: Vorgabe
Description: Flansch
Pset_DistributionFlowElementCommon - Reference: Flansch 316667; sets with these values: 2
Andere - Typ: Flansch 316667; Familie: Flansch 316667; Familie und Typ: Flansch 316667: Flansch 316667; Typ-ID: 2535201
Abhängigkeiten - Höhe von Ebene: 0 m; Verschieben mit umliegenden Elementen: no
Bemaßungen - Fläche: 0.0503828 m2; Volumen: 0.00171028 m3
IFC-Parameter - In IFC-Datei exportieren: Nach Typ; Pset MEP.Tech-Insulation thickness (mm): 100; Pset MEP.Tech-PN: 16; Pset MEP.Geom-Depth: 55; Pset MEP.Geom-DN: 150; Pset MEP.Geom-Outer Ø (mm): 285; In IFC exportieren als: ifcflowfitting; NameOverride: Flansch; IfcPresentationLayer: 0-TFT-H_Ruecklauf; ObjectTypeOverride: Flansch; Pset MEP.Name: Flansch; IfcDescription: Flansch; Pset MEP.Tech-Material: nach DIN 2627
Phasen - Phase erstellt: Phase 01

# IfcFlowFitting: Flansch 316845:Flansch 316845, Flansch
In: 1. Obergeschoss
Type - Material: IfcSurfaceStyle #1741
Type - Andere - Kategorie: Allgemeines Modell; Familienname: Flansch 316845
Type - ID-Daten - Typname: Flansch 316845
Type - IFC-Parameter - Typ in IFC-Datei exportieren: Vorgabe
Description: Flansch
Pset_DistributionFlowElementCommon - Reference: Flansch 316845; sets with these values: 2
Andere - Typ: Flansch 316845; Familie: Flansch 316845; Familie und Typ: Flansch 316845: Flansch 316845; Typ-ID: 2535215
Abhängigkeiten - Höhe von Ebene: 0 m; Verschieben mit umliegenden Elementen: no
Bemaßungen - Fläche: 0.0503828 m2; Volumen: 0.00171028 m3
IFC-Parameter - In IFC-Datei exportieren: Nach Typ; Pset MEP.Tech-Insulation thickness (mm): 100; Pset MEP.Tech-PN: 16; Pset MEP.Geom-Depth: 55; Pset MEP.Geom-DN: 150; Pset MEP.Geom-Outer Ø (mm): 285; In IFC exportieren als: ifcflowfitting; NameOverride: Flansch; IfcPresentationLayer: 0-TFT-H_Ruecklauf; ObjectTypeOverride: Flansch; Pset MEP.Name: Flansch; IfcDescription: Flansch; Pset MEP.Tech-Material: nach DIN 2627
Phasen - Phase erstellt: Phase 01

# IfcFlowFitting: Flansch 316891:Flansch 316891, Flansch
In: Erdgeschoss
Type - Material: IfcSurfaceStyle #9317
Type - Andere - Kategorie: Allgemeines Modell; Familienname: Flansch 316891
Type - ID-Daten - Typname: Flansch 316891
Type - IFC-Parameter - Typ in IFC-Datei exportieren: Vorgabe
Description: Flansch
Pset_DistributionFlowElementCommon - Reference: Flansch 316891; sets with these values: 2
Andere - Typ: Flansch 316891; Familie: Flansch 316891; Familie und Typ: Flansch 316891: Flansch 316891; Typ-ID: 2535229
Abhängigkeiten - Höhe von Ebene: 0 m; Verschieben mit umliegenden Elementen: no
Bemaßungen - Fläche: 0.0503828 m2; Volumen: 0.00171028 m3
IFC-Parameter - In IFC-Datei exportieren: Nach Typ; Pset MEP.Tech-Insulation thickness (mm): 100; Pset MEP.Tech-PN: 16; Pset MEP.Geom-Depth: 55; Pset MEP.Geom-DN: 150; Pset MEP.Geom-Outer Ø (mm): 285; In IFC exportieren als: ifcflowfitting; NameOverride: Flansch; IfcPresentationLayer: 0-TFT-H_Vorlauf; ObjectTypeOverride: Flansch; Pset MEP.Name: Flansch; IfcDescription: Flansch; Pset MEP.Tech-Material: nach DIN 2627
Phasen - Phase erstellt: Phase 01

# IfcFlowFitting: Flansch 317259:Flansch 317259, Flansch
In: Erdgeschoss
Type - Material: IfcSurfaceStyle #1741
Type - Andere - Kategorie: Allgemeines Modell; Familienname: Flansch 317259
Type - ID-Daten - Typname: Flansch 317259
Type - IFC-Parameter - Typ in IFC-Datei exportieren: Vorgabe
Description: Flansch
Pset_DistributionFlowElementCommon - Reference: Flansch 317259; sets with these values: 2
Andere - Typ: Flansch 317259; Familie: Flansch 317259; Familie und Typ: Flansch 317259: Flansch 317259; Typ-ID: 2535250
Abhängigkeiten - Höhe von Ebene: 0 m; Verschieben mit umliegenden Elementen: no
Bemaßungen - Fläche: 0.0404913 m2; Volumen: 0.00128585 m3
IFC-Parameter - In IFC-Datei exportieren: Nach Typ; Pset MEP.Tech-Insulation thickness (mm): 100; Pset MEP.Tech-PN: 16; Pset MEP.Geom-Depth: 55; Pset MEP.Geom-DN: 125; Pset MEP.Geom-Outer Ø (mm): 250; In IFC exportieren als: ifcflowfitting; NameOverride: Flansch; IfcPresentationLayer: 0-TFT-H_Ruecklauf; ObjectTypeOverride: Flansch; Pset MEP.Name: Flansch; IfcDescription: Flansch; Pset MEP.Tech-Material: nach DIN 2627
Phasen - Phase erstellt: Phase 01

# IfcFlowFitting: Flansch 317437:Flansch 317437, Flansch
In: Erdgeschoss
Type - Material: IfcSurfaceStyle #9317
Type - Andere - Kategorie: Allgemeines Modell; Familienname: Flansch 317437
Type - ID-Daten - Typname: Flansch 317437
Type - IFC-Parameter - Typ in IFC-Datei exportieren: Vorgabe
Description: Flansch
Pset_DistributionFlowElementCommon - Reference: Flansch 317437; sets with these values: 2
Andere - Typ: Flansch 317437; Familie: Flansch 317437; Familie und Typ: Flansch 317437: Flansch 317437; Typ-ID: 2535264
Abhängigkeiten - Höhe von Ebene: 0 m; Verschieben mit umliegenden Elementen: no
Bemaßungen - Fläche: 0.111243 m2; Volumen: 0.00814942 m3
IFC-Parameter - In IFC-Datei exportieren: Nach Typ; Pset MEP.Tech-Insulation thickness (mm): 100; Pset MEP.Tech-PN: 16; Pset MEP.Geom-Depth: 55; Pset MEP.Geom-DN: 150; Pset MEP.Geom-Outer Ø (mm): 285; In IFC exportieren als: ifcflowfitting; NameOverride: Flansch; IfcPresentationLayer: 0-TFT-H_Vorlauf; ObjectTypeOverride: Flansch; Pset MEP.Name: Flansch; IfcDescription: Flansch; Pset MEP.Tech-Material: nach DIN 2627
Phasen - Phase erstellt: Phase 01

# IfcFlowFitting: Flansch 317483:Flansch 317483, Flansch
In: Erdgeschoss
Type - Material: IfcSurfaceStyle #9317
Type - Andere - Kategorie: Allgemeines Modell; Familienname: Flansch 317483
Type - ID-Daten - Typname: Flansch 317483
Type - IFC-Parameter - Typ in IFC-Datei exportieren: Vorgabe
Description: Flansch
Pset_DistributionFlowElementCommon - Reference: Flansch 317483; sets with these values: 2
Andere - Typ: Flansch 317483; Familie: Flansch 317483; Familie und Typ: Flansch 317483: Flansch 317483; Typ-ID: 2535278
Abhängigkeiten - Höhe von Ebene: 0 m; Verschieben mit umliegenden Elementen: no
Bemaßungen - Fläche: 0.111243 m2; Volumen: 0.00814942 m3
IFC-Parameter - In IFC-Datei exportieren: Nach Typ; Pset MEP.Tech-Insulation thickness (mm): 100; Pset MEP.Tech-PN: 16; Pset MEP.Geom-Depth: 55; Pset MEP.Geom-DN: 150; Pset MEP.Geom-Outer Ø (mm): 285; In IFC exportieren als: ifcflowfitting; NameOverride: Flansch; IfcPresentationLayer: 0-TFT-H_Vorlauf; ObjectTypeOverride: Flansch; Pset MEP.Name: Flansch; IfcDescription: Flansch; Pset MEP.Tech-Material: nach DIN 2627
Phasen - Phase erstellt: Phase 01

# IfcFlowFitting: Flansch 317675:Flansch 317675, Flansch
In: Erdgeschoss
Type - Material: IfcSurfaceStyle #1741
Type - Andere - Kategorie: Allgemeines Modell; Familienname: Flansch 317675
Type - ID-Daten - Typname: Flansch 317675
Type - IFC-Parameter - Typ in IFC-Datei exportieren: Vorgabe
Description: Flansch
Pset_DistributionFlowElementCommon - Reference: Flansch 317675; sets with these values: 2
Andere - Typ: Flansch 317675; Familie: Flansch 317675; Familie und Typ: Flansch 317675: Flansch 317675; Typ-ID: 2535299
Abhängigkeiten - Höhe von Ebene: 0 m; Verschieben mit umliegenden Elementen: no
Bemaßungen - Fläche: 0.111243 m2; Volumen: 0.00814942 m3
IFC-Parameter - In IFC-Datei exportieren: Nach Typ; Pset MEP.Tech-Insulation thickness (mm): 100; Pset MEP.Tech-PN: 16; Pset MEP.Geom-Depth: 55; Pset MEP.Geom-DN: 150; Pset MEP.Geom-Outer Ø (mm): 285; In IFC exportieren als: ifcflowfitting; NameOverride: Flansch; IfcPresentationLayer: 0-TFT-H_Ruecklauf; ObjectTypeOverride: Flansch; Pset MEP.Name: Flansch; IfcDescription: Flansch; Pset MEP.Tech-Material: nach DIN 2627
Phasen - Phase erstellt: Phase 01

# IfcFlowFitting: Flansch 318379:Flansch 318379, Flansch
In: Erdgeschoss
Type - Material: IfcSurfaceStyle #1741
Type - Andere - Kategorie: Allgemeines Modell; Familienname: Flansch 318379
Type - ID-Daten - Typname: Flansch 318379
Type - IFC-Parameter - Typ in IFC-Datei exportieren: Vorgabe
Description: Flansch
Pset_DistributionFlowElementCommon - Reference: Flansch 318379; sets with these values: 2
Andere - Typ: Flansch 318379; Familie: Flansch 318379; Familie und Typ: Flansch 318379: Flansch 318379; Typ-ID: 2535327
Abhängigkeiten - Höhe von Ebene: 0 m; Verschieben mit umliegenden Elementen: no
Bemaßungen - Fläche: 0.0800177 m2; Volumen: 0.00543566 m3
IFC-Parameter - In IFC-Datei exportieren: Nach Typ; Pset MEP.Tech-Insulation thickness (mm): 100; Pset MEP.Tech-PN: 16; Pset MEP.Geom-DN: 100; Pset MEP.Geom-Depth: 52; Pset MEP.Geom-Outer Ø (mm): 220; In IFC exportieren als: ifcflowfitting; NameOverride: Flansch; IfcPresentationLayer: 0-TFT-H_Ruecklauf; ObjectTypeOverride: Flansch; Pset MEP.Name: Flansch; IfcDescription: Flansch; Pset MEP.Tech-Material: nach DIN 2627
Phasen - Phase erstellt: Phase 01

# IfcFlowFitting: Flansch 318425:Flansch 318425, Flansch
In: Erdgeschoss
Type - Material: IfcSurfaceStyle #1741
Type - Andere - Kategorie: Allgemeines Modell; Familienname: Flansch 318425
Type - ID-Daten - Typname: Flansch 318425
Type - IFC-Parameter - Typ in IFC-Datei exportieren: Vorgabe
Description: Flansch
Pset_DistributionFlowElementCommon - Reference: Flansch 318425; sets with these values: 2
Andere - Typ: Flansch 318425; Familie: Flansch 318425; Familie und Typ: Flansch 318425: Flansch 318425; Typ-ID: 2535341
Abhängigkeiten - Höhe von Ebene: 0 m; Verschieben mit umliegenden Elementen: no
Bemaßungen - Fläche: 0.0951801 m2; Volumen: 0.00682535 m3
IFC-Parameter - In IFC-Datei exportieren: Nach Typ; Pset MEP.Tech-Insulation thickness (mm): 100; Pset MEP.Tech-PN: 16; Pset MEP.Geom-Depth: 55; Pset MEP.Geom-DN: 125; Pset MEP.Geom-Outer Ø (mm): 250; In IFC exportieren als: ifcflowfitting; NameOverride: Flansch; IfcPresentationLayer: 0-TFT-H_Ruecklauf; ObjectTypeOverride: Flansch; Pset MEP.Name: Flansch; IfcDescription: Flansch; Pset MEP.Tech-Material: nach DIN 2627
Phasen - Phase erstellt: Phase 01

# IfcFlowFitting: Flansch 318448:Flansch 318448, Flansch
In: 1. Obergeschoss
Type - Material: IfcSurfaceStyle #1741
Type - Andere - Kategorie: Allgemeines Modell; Familienname: Flansch 318448
Type - ID-Daten - Typname: Flansch 318448
Type - IFC-Parameter - Typ in IFC-Datei exportieren: Vorgabe
Description: Flansch
Pset_DistributionFlowElementCommon - Reference: Flansch 318448; sets with these values: 2
Andere - Typ: Flansch 318448; Familie: Flansch 318448; Familie und Typ: Flansch 318448: Flansch 318448; Typ-ID: 2535348
Abhängigkeiten - Höhe von Ebene: 0 m; Verschieben mit umliegenden Elementen: no
Bemaßungen - Fläche: 0.0800177 m2; Volumen: 0.00543566 m3
IFC-Parameter - In IFC-Datei exportieren: Nach Typ; Pset MEP.Tech-Insulation thickness (mm): 100; Pset MEP.Tech-PN: 16; Pset MEP.Geom-DN: 100; Pset MEP.Geom-Depth: 52; Pset MEP.Geom-Outer Ø (mm): 220; In IFC exportieren als: ifcflowfitting; NameOverride: Flansch; IfcPresentationLayer: 0-TFT-H_Ruecklauf; ObjectTypeOverride: Flansch; Pset MEP.Name: Flansch; IfcDescription: Flansch; Pset MEP.Tech-Material: nach DIN 2627
Phasen - Phase erstellt: Phase 01

# IfcFlowFitting: Flansch 318805:Flansch 318805, Flansch
In: Erdgeschoss
Type - Material: IfcSurfaceStyle #1741
Type - Andere - Kategorie: Allgemeines Modell; Familienname: Flansch 318805
Type - ID-Daten - Typname: Flansch 318805
Type - IFC-Parameter - Typ in IFC-Datei exportieren: Vorgabe
Description: Flansch
Pset_DistributionFlowElementCommon - Reference: Flansch 318805; sets with these values: 2
Andere - Typ: Flansch 318805; Familie: Flansch 318805; Familie und Typ: Flansch 318805: Flansch 318805; Typ-ID: 2535369
Abhängigkeiten - Höhe von Ebene: 0 m; Verschieben mit umliegenden Elementen: no
Bemaßungen - Fläche: 0.0800177 m2; Volumen: 0.00543566 m3
IFC-Parameter - In IFC-Datei exportieren: Nach Typ; Pset MEP.Tech-Insulation thickness (mm): 100; Pset MEP.Tech-PN: 16; Pset MEP.Geom-DN: 100; Pset MEP.Geom-Depth: 52; Pset MEP.Geom-Outer Ø (mm): 220; In IFC exportieren als: ifcflowfitting; NameOverride: Flansch; IfcPresentationLayer: 0-TFT-H_Ruecklauf; ObjectTypeOverride: Flansch; Pset MEP.Name: Flansch; IfcDescription: Flansch; Pset MEP.Tech-Material: nach DIN 2627
Phasen - Phase erstellt: Phase 01

# IfcFlowFitting: Flansch 318828:Flansch 318828, Flansch
In: Erdgeschoss
Type - Material: IfcSurfaceStyle #1741
Type - Andere - Kategorie: Allgemeines Modell; Familienname: Flansch 318828
Type - ID-Daten - Typname: Flansch 318828
Type - IFC-Parameter - Typ in IFC-Datei exportieren: Vorgabe
Description: Flansch
Pset_DistributionFlowElementCommon - Reference: Flansch 318828; sets with these values: 2
Andere - Typ: Flansch 318828; Familie: Flansch 318828; Familie und Typ: Flansch 318828: Flansch 318828; Typ-ID: 2535376
Abhängigkeiten - Höhe von Ebene: 0 m; Verschieben mit umliegenden Elementen: no
Bemaßungen - Fläche: 0.0951801 m2; Volumen: 0.00682535 m3
IFC-Parameter - In IFC-Datei exportieren: Nach Typ; Pset MEP.Tech-Insulation thickness (mm): 100; Pset MEP.Tech-PN: 16; Pset MEP.Geom-Depth: 55; Pset MEP.Geom-DN: 125; Pset MEP.Geom-Outer Ø (mm): 250; In IFC exportieren als: ifcflowfitting; NameOverride: Flansch; IfcPresentationLayer: 0-TFT-H_Ruecklauf; ObjectTypeOverride: Flansch; Pset MEP.Name: Flansch; IfcDescription: Flansch; Pset MEP.Tech-Material: nach DIN 2627
Phasen - Phase erstellt: Phase 01

# IfcFlowFitting: Flansch 318851:Flansch 318851, Flansch
In: Erdgeschoss
Type - Material: IfcSurfaceStyle #1741
Type - Andere - Kategorie: Allgemeines Modell; Familienname: Flansch 318851
Type - ID-Daten - Typname: Flansch 318851
Type - IFC-Parameter - Typ in IFC-Datei exportieren: Vorgabe
Description: Flansch
Pset_DistributionFlowElementCommon - Reference: Flansch 318851; sets with these values: 2
Andere - Typ: Flansch 318851; Familie: Flansch 318851; Familie und Typ: Flansch 318851: Flansch 318851; Typ-ID: 2535383
Abhängigkeiten - Höhe von Ebene: 0 m; Verschieben mit umliegenden Elementen: no
Bemaßungen - Fläche: 0.0951801 m2; Volumen: 0.00682535 m3
IFC-Parameter - In IFC-Datei exportieren: Nach Typ; Pset MEP.Tech-Insulation thickness (mm): 100; Pset MEP.Tech-PN: 16; Pset MEP.Geom-Depth: 55; Pset MEP.Geom-DN: 125; Pset MEP.Geom-Outer Ø (mm): 250; In IFC exportieren als: ifcflowfitting; NameOverride: Flansch; IfcPresentationLayer: 0-TFT-H_Ruecklauf; ObjectTypeOverride: Flansch; Pset MEP.Name: Flansch; IfcDescription: Flansch; Pset MEP.Tech-Material: nach DIN 2627
Phasen - Phase erstellt: Phase 01

# IfcFlowFitting: Flansch 319861:Flansch 319861, Flansch
In: 1. Obergeschoss
Type - Material: IfcSurfaceStyle #1741
Type - Andere - Kategorie: Allgemeines Modell; Familienname: Flansch 319861
Type - ID-Daten - Typname: Flansch 319861
Type - IFC-Parameter - Typ in IFC-Datei exportieren: Vorgabe
Description: Flansch
Pset_DistributionFlowElementCommon - Reference: Flansch 319861; sets with these values: 2
Andere - Typ: Flansch 319861; Familie: Flansch 319861; Familie und Typ: Flansch 319861: Flansch 319861; Typ-ID: 2535439
Abhängigkeiten - Höhe von Ebene: 0 m; Verschieben mit umliegenden Elementen: no
Bemaßungen - Fläche: 0.0800177 m2; Volumen: 0.00456789 m3
IFC-Parameter - In IFC-Datei exportieren: Nach Typ; Pset MEP.Tech-Insulation thickness (mm): 100; Pset MEP.Tech-PN: 16; Pset MEP.Geom-DN: 100; Pset MEP.Geom-Depth: 52; Pset MEP.Geom-Outer Ø (mm): 220; In IFC exportieren als: ifcflowfitting; NameOverride: Flansch; IfcPresentationLayer: 0-TFT-H_Ruecklauf; ObjectTypeOverride: Flansch; Pset MEP.Name: Flansch; IfcDescription: Flansch; Pset MEP.Tech-Material: nach DIN 2627
Phasen - Phase erstellt: Phase 01

# IfcFlowFitting: Flansch 319907:Flansch 319907, Flansch
In: Erdgeschoss
Type - Material: IfcSurfaceStyle #1741
Type - Andere - Kategorie: Allgemeines Modell; Familienname: Flansch 319907
Type - ID-Daten - Typname: Flansch 319907
Type - IFC-Parameter - Typ in IFC-Datei exportieren: Vorgabe
Description: Flansch
Pset_DistributionFlowElementCommon - Reference: Flansch 319907; sets with these values: 2
Andere - Typ: Flansch 319907; Familie: Flansch 319907; Familie und Typ: Flansch 319907: Flansch 319907; Typ-ID: 2535453
Abhängigkeiten - Höhe von Ebene: 0 m; Verschieben mit umliegenden Elementen: no
Bemaßungen - Fläche: 0.0404913 m2; Volumen: 0.00128585 m3
IFC-Parameter - In IFC-Datei exportieren: Nach Typ; Pset MEP.Tech-PN: 16; Pset MEP.Geom-Depth: 55; Pset MEP.Geom-DN: 125; Pset MEP.Geom-Outer Ø (mm): 250; In IFC exportieren als: ifcflowfitting; NameOverride: Flansch; IfcPresentationLayer: 0-TFT-H_Ruecklauf; ObjectTypeOverride: Flansch; Pset MEP.Name: Flansch; IfcDescription: Flansch; Pset MEP.Tech-Material: nach DIN 2627
Phasen - Phase erstellt: Phase 01

# IfcFlowFitting: Flansch 319928:Flansch 319928, Flansch
In: Erdgeschoss
Type - Material: IfcSurfaceStyle #1741
Type - Andere - Kategorie: Allgemeines Modell; Familienname: Flansch 319928
Type - ID-Daten - Typname: Flansch 319928
Type - IFC-Parameter - Typ in IFC-Datei exportieren: Vorgabe
Description: Flansch
Pset_DistributionFlowElementCommon - Reference: Flansch 319928; sets with these values: 2
Andere - Typ: Flansch 319928; Familie: Flansch 319928; Familie und Typ: Flansch 319928: Flansch 319928; Typ-ID: 2535460
Abhängigkeiten - Höhe von Ebene: 0 m; Verschieben mit umliegenden Elementen: no
Bemaßungen - Fläche: 0.0951801 m2; Volumen: 0.00682535 m3
IFC-Parameter - In IFC-Datei exportieren: Nach Typ; Pset MEP.Tech-Insulation thickness (mm): 100; Pset MEP.Tech-PN: 16; Pset MEP.Geom-Depth: 55; Pset MEP.Geom-DN: 125; Pset MEP.Geom-Outer Ø (mm): 250; In IFC exportieren als: ifcflowfitting; NameOverride: Flansch; IfcPresentationLayer: 0-TFT-H_Ruecklauf; ObjectTypeOverride: Flansch; Pset MEP.Name: Flansch; IfcDescription: Flansch; Pset MEP.Tech-Material: nach DIN 2627
Phasen - Phase erstellt: Phase 01

# IfcFlowFitting: Flansch 320155:Flansch 320155, Flansch
In: Erdgeschoss
Type - Material: IfcSurfaceStyle #1741
Type - Andere - Kategorie: Allgemeines Modell; Familienname: Flansch 320155
Type - ID-Daten - Typname: Flansch 320155
Type - IFC-Parameter - Typ in IFC-Datei exportieren: Vorgabe
Description: Flansch
Pset_DistributionFlowElementCommon - Reference: Flansch 320155; sets with these values: 2
Andere - Typ: Flansch 320155; Familie: Flansch 320155; Familie und Typ: Flansch 320155: Flansch 320155; Typ-ID: 2535481
Abhängigkeiten - Höhe von Ebene: 0 m; Verschieben mit umliegenden Elementen: no
Bemaßungen - Fläche: 0.0951801 m2; Volumen: 0.00682535 m3
IFC-Parameter - In IFC-Datei exportieren: Nach Typ; Pset MEP.Tech-Insulation thickness (mm): 100; Pset MEP.Tech-PN: 16; Pset MEP.Geom-Depth: 55; Pset MEP.Geom-DN: 125; Pset MEP.Geom-Outer Ø (mm): 250; In IFC exportieren als: ifcflowfitting; NameOverride: Flansch; IfcPresentationLayer: 0-TFT-H_Ruecklauf; ObjectTypeOverride: Flansch; Pset MEP.Name: Flansch; IfcDescription: Flansch; Pset MEP.Tech-Material: nach DIN 2627
Phasen - Phase erstellt: Phase 01

# IfcFlowFitting: Flansch 320350:Flansch 320350, Flansch
In: Erdgeschoss
Type - Material: IfcSurfaceStyle #1741
Type - Andere - Kategorie: Allgemeines Modell; Familienname: Flansch 320350
Type - ID-Daten - Typname: Flansch 320350
Type - IFC-Parameter - Typ in IFC-Datei exportieren: Vorgabe
Description: Flansch
Pset_DistributionFlowElementCommon - Reference: Flansch 320350; sets with these values: 2
Andere - Typ: Flansch 320350; Familie: Flansch 320350; Familie und Typ: Flansch 320350: Flansch 320350; Typ-ID: 2535502
Abhängigkeiten - Höhe von Ebene: 0 m; Verschieben mit umliegenden Elementen: no
Bemaßungen - Fläche: 0.111243 m2; Volumen: 0.00683497 m3
IFC-Parameter - In IFC-Datei exportieren: Nach Typ; Pset MEP.Tech-Insulation thickness (mm): 100; Pset MEP.Tech-PN: 16; Pset MEP.Geom-Depth: 55; Pset MEP.Geom-DN: 150; Pset MEP.Geom-Outer Ø (mm): 285; In IFC exportieren als: ifcflowfitting; NameOverride: Flansch; IfcPresentationLayer: 0-TFT-H_Ruecklauf; ObjectTypeOverride: Flansch; Pset MEP.Name: Flansch; IfcDescription: Flansch; Pset MEP.Tech-Material: nach DIN 2627
Phasen - Phase erstellt: Phase 01

# IfcFlowFitting: Flansch 320377:Flansch 320377, Flansch
In: Erdgeschoss
Type - Material: IfcSurfaceStyle #1741
Type - Andere - Kategorie: Allgemeines Modell; Familienname: Flansch 320377
Type - ID-Daten - Typname: Flansch 320377
Type - IFC-Parameter - Typ in IFC-Datei exportieren: Vorgabe
Description: Flansch
Pset_DistributionFlowElementCommon - Reference: Flansch 320377; sets with these values: 2
Andere - Typ: Flansch 320377; Familie: Flansch 320377; Familie und Typ: Flansch 320377: Flansch 320377; Typ-ID: 2535509
Abhängigkeiten - Höhe von Ebene: 0 m; Verschieben mit umliegenden Elementen: no
Bemaßungen - Fläche: 0.111243 m2; Volumen: 0.00814942 m3
IFC-Parameter - In IFC-Datei exportieren: Nach Typ; Pset MEP.Tech-Insulation thickness (mm): 100; Pset MEP.Tech-PN: 16; Pset MEP.Geom-Depth: 55; Pset MEP.Geom-DN: 150; Pset MEP.Geom-Outer Ø (mm): 285; In IFC exportieren als: ifcflowfitting; NameOverride: Flansch; IfcPresentationLayer: 0-TFT-H_Ruecklauf; ObjectTypeOverride: Flansch; Pset MEP.Name: Flansch; IfcDescription: Flansch; Pset MEP.Tech-Material: nach DIN 2627
Phasen - Phase erstellt: Phase 01

# IfcFlowFitting: Flansch 320585:Flansch 320585, Flansch
In: 1. Obergeschoss
Type - Material: IfcSurfaceStyle #1741
Type - Andere - Kategorie: Allgemeines Modell; Familienname: Flansch 320585
Type - ID-Daten - Typname: Flansch 320585
Type - IFC-Parameter - Typ in IFC-Datei exportieren: Vorgabe
Description: Flansch
Pset_DistributionFlowElementCommon - Reference: Flansch 320585; sets with these values: 2
Andere - Typ: Flansch 320585; Familie: Flansch 320585; Familie und Typ: Flansch 320585: Flansch 320585; Typ-ID: 2535523
Abhängigkeiten - Höhe von Ebene: 0 m; Verschieben mit umliegenden Elementen: no
Bemaßungen - Fläche: 0.111243 m2; Volumen: 0.00814942 m3
IFC-Parameter - In IFC-Datei exportieren: Nach Typ; Pset MEP.Tech-Insulation thickness (mm): 100; Pset MEP.Tech-PN: 16; Pset MEP.Geom-Depth: 55; Pset MEP.Geom-DN: 150; Pset MEP.Geom-Outer Ø (mm): 285; In IFC exportieren als: ifcflowfitting; NameOverride: Flansch; IfcPresentationLayer: 0-TFT-H_Ruecklauf; ObjectTypeOverride: Flansch; Pset MEP.Name: Flansch; IfcDescription: Flansch; Pset MEP.Tech-Material: nach DIN 2627
Phasen - Phase erstellt: Phase 01

# IfcFlowFitting: Flansch 320757:Flansch 320757, Flansch
In: 1. Obergeschoss
Type - Material: IfcSurfaceStyle #1741
Type - Andere - Kategorie: Allgemeines Modell; Familienname: Flansch 320757
Type - ID-Daten - Typname: Flansch 320757
Type - IFC-Parameter - Typ in IFC-Datei exportieren: Vorgabe
Description: Flansch
Pset_DistributionFlowElementCommon - Reference: Flansch 320757; sets with these values: 2
Andere - Typ: Flansch 320757; Familie: Flansch 320757; Familie und Typ: Flansch 320757: Flansch 320757; Typ-ID: 2535537
Abhängigkeiten - Höhe von Ebene: 0 m; Verschieben mit umliegenden Elementen: no
Bemaßungen - Fläche: 0.111243 m2; Volumen: 0.00814942 m3
IFC-Parameter - In IFC-Datei exportieren: Nach Typ; Pset MEP.Tech-Insulation thickness (mm): 100; Pset MEP.Tech-PN: 16; Pset MEP.Geom-Depth: 55; Pset MEP.Geom-DN: 150; Pset MEP.Geom-Outer Ø (mm): 285; In IFC exportieren als: ifcflowfitting; NameOverride: Flansch; IfcPresentationLayer: 0-TFT-H_Ruecklauf; ObjectTypeOverride: Flansch; Pset MEP.Name: Flansch; IfcDescription: Flansch; Pset MEP.Tech-Material: nach DIN 2627
Phasen - Phase erstellt: Phase 01
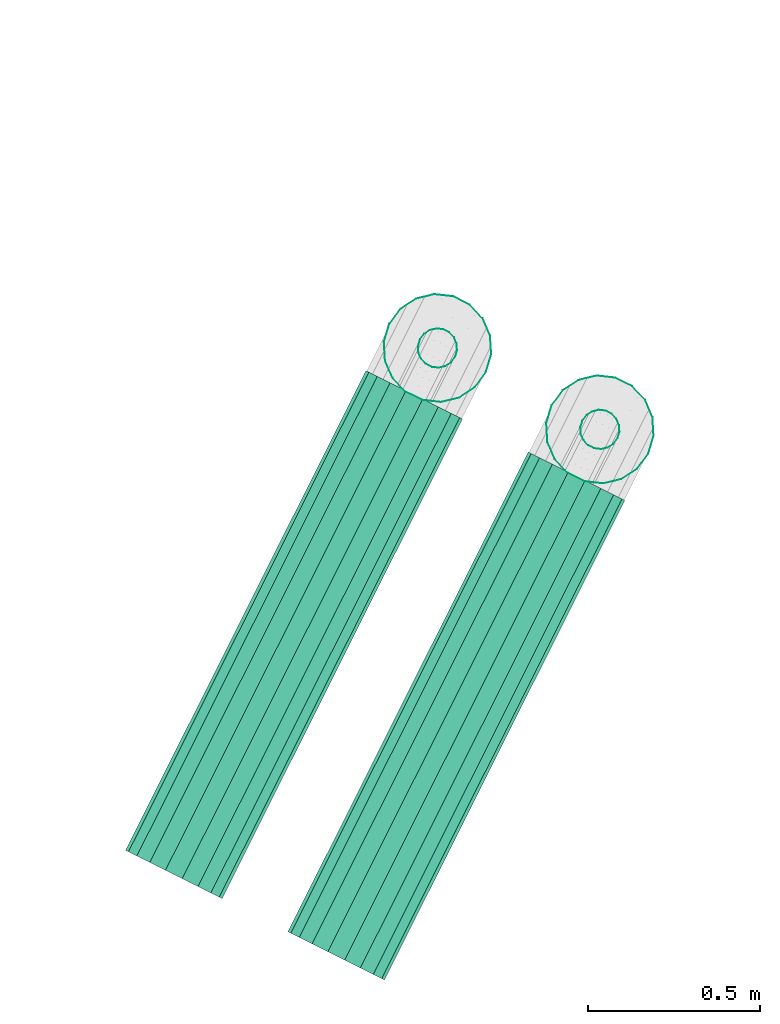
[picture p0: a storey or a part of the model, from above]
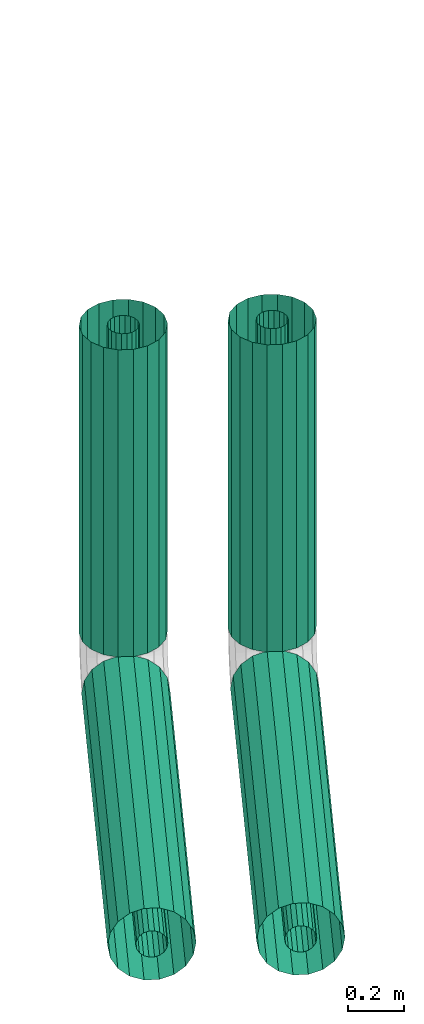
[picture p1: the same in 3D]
Properties of the parts of a building model (IFC2X3), part 9 of 23

# IfcFlowFitting: Flansch 320780:Flansch 320780, Flansch
In: Erdgeschoss
Type - Material: IfcSurfaceStyle #1741
Type - Andere - Kategorie: Allgemeines Modell; Familienname: Flansch 320780
Type - ID-Daten - Typname: Flansch 320780
Type - IFC-Parameter - Typ in IFC-Datei exportieren: Vorgabe
Description: Flansch
Pset_DistributionFlowElementCommon - Reference: Flansch 320780; sets with these values: 2
Andere - Typ: Flansch 320780; Familie: Flansch 320780; Familie und Typ: Flansch 320780: Flansch 320780; Typ-ID: 2535544
Abhängigkeiten - Höhe von Ebene: 0 m; Verschieben mit umliegenden Elementen: no
Bemaßungen - Fläche: 0.0951801 m2; Volumen: 0.00682535 m3
IFC-Parameter - In IFC-Datei exportieren: Nach Typ; Pset MEP.Tech-Insulation thickness (mm): 100; Pset MEP.Tech-PN: 16; Pset MEP.Geom-Depth: 55; Pset MEP.Geom-DN: 125; Pset MEP.Geom-Outer Ø (mm): 250; In IFC exportieren als: ifcflowfitting; NameOverride: Flansch; IfcPresentationLayer: 0-TFT-H_Ruecklauf; ObjectTypeOverride: Flansch; Pset MEP.Name: Flansch; IfcDescription: Flansch; Pset MEP.Tech-Material: nach DIN 2627
Phasen - Phase erstellt: Phase 01

# IfcFlowFitting: Flansch 325457:Flansch 325457, Flansch
In: Erdgeschoss
Type - Material: IfcSurfaceStyle #1741
Type - Andere - Kategorie: Allgemeines Modell; Familienname: Flansch 325457
Type - ID-Daten - Typname: Flansch 325457
Type - IFC-Parameter - Typ in IFC-Datei exportieren: Vorgabe
Description: Flansch
Pset_DistributionFlowElementCommon - Reference: Flansch 325457; sets with these values: 2
Andere - Typ: Flansch 325457; Familie: Flansch 325457; Familie und Typ: Flansch 325457: Flansch 325457; Typ-ID: 2535607
Abhängigkeiten - Höhe von Ebene: 0 m; Verschieben mit umliegenden Elementen: no
Bemaßungen - Fläche: 0.0567765 m2; Volumen: 0.00335128 m3
IFC-Parameter - In IFC-Datei exportieren: Nach Typ; Pset MEP.Tech-Insulation thickness (mm): 100; Pset MEP.Tech-PN: 16; Pset MEP.Geom-Depth: 45; Pset MEP.Geom-DN: 50; Pset MEP.Geom-Outer Ø (mm): 165; In IFC exportieren als: ifcflowfitting; NameOverride: Flansch; IfcPresentationLayer: 0-TFT-H_Ruecklauf; ObjectTypeOverride: Flansch; Pset MEP.Name: Flansch; IfcDescription: Flansch; Pset MEP.Tech-Material: nach DIN 2627
Phasen - Phase erstellt: Phase 01

# IfcFlowFitting: Flansch 325929:Flansch 325929, Flansch
In: Erdgeschoss
Type - Material: IfcSurfaceStyle #1741
Type - Andere - Kategorie: Allgemeines Modell; Familienname: Flansch 325929
Type - ID-Daten - Typname: Flansch 325929
Type - IFC-Parameter - Typ in IFC-Datei exportieren: Vorgabe
Description: Flansch
Pset_DistributionFlowElementCommon - Reference: Flansch 325929; sets with these values: 2
Andere - Typ: Flansch 325929; Familie: Flansch 325929; Familie und Typ: Flansch 325929: Flansch 325929; Typ-ID: 2535614
Abhängigkeiten - Höhe von Ebene: 0 m; Verschieben mit umliegenden Elementen: no
Bemaßungen - Fläche: 0.0638334 m2; Volumen: 0.00380173 m3
IFC-Parameter - In IFC-Datei exportieren: Nach Typ; Pset MEP.Tech-Insulation thickness (mm): 100; Pset MEP.Tech-PN: 16; Pset MEP.Geom-DN: 65; Pset MEP.Geom-Outer Ø (mm): 185; Pset MEP.Geom-Depth: 45; In IFC exportieren als: ifcflowfitting; NameOverride: Flansch; IfcPresentationLayer: 0-TFT-H_Ruecklauf; ObjectTypeOverride: Flansch; Pset MEP.Name: Flansch; IfcDescription: Flansch; Pset MEP.Tech-Material: nach DIN 2627
Phasen - Phase erstellt: Phase 01

# IfcFlowFitting: Flansch 326950:Flansch 326950, Flansch
In: Erdgeschoss
Type - Material: IfcSurfaceStyle #1741
Type - Andere - Kategorie: Allgemeines Modell; Familienname: Flansch 326950
Type - ID-Daten - Typname: Flansch 326950
Type - IFC-Parameter - Typ in IFC-Datei exportieren: Vorgabe
Description: Flansch
Pset_DistributionFlowElementCommon - Reference: Flansch 326950; sets with these values: 2
Andere - Typ: Flansch 326950; Familie: Flansch 326950; Familie und Typ: Flansch 326950: Flansch 326950; Typ-ID: 2535628
Abhängigkeiten - Höhe von Ebene: 0 m; Verschieben mit umliegenden Elementen: no
Bemaßungen - Fläche: 0.0638334 m2; Volumen: 0.00380173 m3
IFC-Parameter - In IFC-Datei exportieren: Nach Typ; Pset MEP.Tech-Insulation thickness (mm): 100; Pset MEP.Tech-PN: 16; Pset MEP.Geom-DN: 65; Pset MEP.Geom-Outer Ø (mm): 185; Pset MEP.Geom-Depth: 45; In IFC exportieren als: ifcflowfitting; NameOverride: Flansch; IfcPresentationLayer: 0-TFT-H_Ruecklauf; ObjectTypeOverride: Flansch; Pset MEP.Name: Flansch; IfcDescription: Flansch; Pset MEP.Tech-Material: nach DIN 2627
Phasen - Phase erstellt: Phase 01

# IfcFlowFitting: Flansch 329199:Flansch 329199, Flansch
In: Erdgeschoss
Type - Material: IfcSurfaceStyle #1741
Type - Andere - Kategorie: Allgemeines Modell; Familienname: Flansch 329199
Type - ID-Daten - Typname: Flansch 329199
Type - IFC-Parameter - Typ in IFC-Datei exportieren: Vorgabe
Description: Flansch
Pset_DistributionFlowElementCommon - Reference: Flansch 329199; sets with these values: 2
Andere - Typ: Flansch 329199; Familie: Flansch 329199; Familie und Typ: Flansch 329199: Flansch 329199; Typ-ID: 2535684
Abhängigkeiten - Höhe von Ebene: 0 m; Verschieben mit umliegenden Elementen: no
Bemaßungen - Fläche: 0.0724331 m2; Volumen: 0.0046363 m3
IFC-Parameter - In IFC-Datei exportieren: Nach Typ; Pset MEP.Tech-Insulation thickness (mm): 100; Pset MEP.Tech-PN: 16; Pset MEP.Geom-DN: 80; Pset MEP.Geom-Depth: 50; Pset MEP.Geom-Outer Ø (mm): 200; In IFC exportieren als: ifcflowfitting; NameOverride: Flansch; IfcPresentationLayer: 0-TFT-H_Ruecklauf; ObjectTypeOverride: Flansch; Pset MEP.Name: Flansch; IfcDescription: Flansch; Pset MEP.Tech-Material: nach DIN 2627
Phasen - Phase erstellt: Phase 01

# IfcFlowFitting: Flansch 329268:Flansch 329268, Flansch
In: Erdgeschoss
Type - Material: IfcSurfaceStyle #1741
Type - Andere - Kategorie: Allgemeines Modell; Familienname: Flansch 329268
Type - ID-Daten - Typname: Flansch 329268
Type - IFC-Parameter - Typ in IFC-Datei exportieren: Vorgabe
Description: Flansch
Pset_DistributionFlowElementCommon - Reference: Flansch 329268; sets with these values: 2
Andere - Typ: Flansch 329268; Familie: Flansch 329268; Familie und Typ: Flansch 329268: Flansch 329268; Typ-ID: 2535705
Abhängigkeiten - Höhe von Ebene: 0 m; Verschieben mit umliegenden Elementen: no
Bemaßungen - Fläche: 0.0567765 m2; Volumen: 0.00335128 m3
IFC-Parameter - In IFC-Datei exportieren: Nach Typ; Pset MEP.Tech-Insulation thickness (mm): 100; Pset MEP.Tech-PN: 16; Pset MEP.Geom-Depth: 45; Pset MEP.Geom-DN: 50; Pset MEP.Geom-Outer Ø (mm): 165; In IFC exportieren als: ifcflowfitting; NameOverride: Flansch; IfcPresentationLayer: 0-TFT-H_Ruecklauf; ObjectTypeOverride: Flansch; Pset MEP.Name: Flansch; IfcDescription: Flansch; Pset MEP.Tech-Material: nach DIN 2627
Phasen - Phase erstellt: Phase 01

# IfcFlowFitting: Flansch 330104:Flansch 330104, Flansch
In: Erdgeschoss
Type - Material: IfcSurfaceStyle #1741
Type - Andere - Kategorie: Allgemeines Modell; Familienname: Flansch 330104
Type - ID-Daten - Typname: Flansch 330104
Type - IFC-Parameter - Typ in IFC-Datei exportieren: Vorgabe
Description: Flansch
Pset_DistributionFlowElementCommon - Reference: Flansch 330104; sets with these values: 2
Andere - Typ: Flansch 330104; Familie: Flansch 330104; Familie und Typ: Flansch 330104: Flansch 330104; Typ-ID: 2535726
Abhängigkeiten - Höhe von Ebene: 0 m; Verschieben mit umliegenden Elementen: no
Bemaßungen - Fläche: 0.0638334 m2; Volumen: 0.00317536 m3
IFC-Parameter - In IFC-Datei exportieren: Nach Typ; Pset MEP.Tech-Insulation thickness (mm): 100; Pset MEP.Tech-PN: 16; Pset MEP.Geom-DN: 65; Pset MEP.Geom-Outer Ø (mm): 185; Pset MEP.Geom-Depth: 45; In IFC exportieren als: ifcflowfitting; NameOverride: Flansch; IfcPresentationLayer: 0-TFT-H_Ruecklauf; ObjectTypeOverride: Flansch; Pset MEP.Name: Flansch; IfcDescription: Flansch; Pset MEP.Tech-Material: nach DIN 2627
Phasen - Phase erstellt: Phase 01

# IfcFlowFitting: Flansch 331171:Flansch 331171, Flansch
In: Erdgeschoss
Type - Material: IfcSurfaceStyle #1741
Type - Andere - Kategorie: Allgemeines Modell; Familienname: Flansch 331171
Type - ID-Daten - Typname: Flansch 331171
Type - IFC-Parameter - Typ in IFC-Datei exportieren: Vorgabe
Description: Flansch
Pset_DistributionFlowElementCommon - Reference: Flansch 331171; sets with these values: 2
Andere - Typ: Flansch 331171; Familie: Flansch 331171; Familie und Typ: Flansch 331171: Flansch 331171; Typ-ID: 2535747
Abhängigkeiten - Höhe von Ebene: 0 m; Verschieben mit umliegenden Elementen: no
Bemaßungen - Fläche: 0.0638334 m2; Volumen: 0.00317536 m3
IFC-Parameter - In IFC-Datei exportieren: Nach Typ; Pset MEP.Tech-Insulation thickness (mm): 100; Pset MEP.Tech-PN: 16; Pset MEP.Geom-DN: 65; Pset MEP.Geom-Outer Ø (mm): 185; Pset MEP.Geom-Depth: 45; In IFC exportieren als: ifcflowfitting; NameOverride: Flansch; IfcPresentationLayer: 0-TFT-H_Ruecklauf; ObjectTypeOverride: Flansch; Pset MEP.Name: Flansch; IfcDescription: Flansch; Pset MEP.Tech-Material: nach DIN 2627
Phasen - Phase erstellt: Phase 01

# IfcFlowFitting: Flansch 334538:Flansch 334538, Flansch
In: Erdgeschoss
Type - Material: IfcSurfaceStyle #1741
Type - Andere - Kategorie: Allgemeines Modell; Familienname: Flansch 334538
Type - ID-Daten - Typname: Flansch 334538
Type - IFC-Parameter - Typ in IFC-Datei exportieren: Vorgabe
Description: Flansch
Pset_DistributionFlowElementCommon - Reference: Flansch 334538; sets with these values: 2
Andere - Typ: Flansch 334538; Familie: Flansch 334538; Familie und Typ: Flansch 334538: Flansch 334538; Typ-ID: 2535796
Abhängigkeiten - Höhe von Ebene: 0 m; Verschieben mit umliegenden Elementen: no
Bemaßungen - Fläche: 0.0638334 m2; Volumen: 0.00380173 m3
IFC-Parameter - In IFC-Datei exportieren: Nach Typ; Pset MEP.Tech-Insulation thickness (mm): 100; Pset MEP.Tech-PN: 16; Pset MEP.Geom-DN: 65; Pset MEP.Geom-Outer Ø (mm): 185; Pset MEP.Geom-Depth: 45; In IFC exportieren als: ifcflowfitting; NameOverride: Flansch; IfcPresentationLayer: 0-TFT-H_Ruecklauf; ObjectTypeOverride: Flansch; Pset MEP.Name: Flansch; IfcDescription: Flansch; Pset MEP.Tech-Material: nach DIN 2627
Phasen - Phase erstellt: Phase 01

# IfcFlowFitting: Flansch 334842:Flansch 334842, Flansch
In: Erdgeschoss
Type - Material: IfcSurfaceStyle #1741
Type - Andere - Kategorie: Allgemeines Modell; Familienname: Flansch 334842
Type - ID-Daten - Typname: Flansch 334842
Type - IFC-Parameter - Typ in IFC-Datei exportieren: Vorgabe
Description: Flansch
Pset_DistributionFlowElementCommon - Reference: Flansch 334842; sets with these values: 2
Andere - Typ: Flansch 334842; Familie: Flansch 334842; Familie und Typ: Flansch 334842: Flansch 334842; Typ-ID: 2535810
Abhängigkeiten - Höhe von Ebene: 0 m; Verschieben mit umliegenden Elementen: no
Bemaßungen - Fläche: 0.0638334 m2; Volumen: 0.00317536 m3
IFC-Parameter - In IFC-Datei exportieren: Nach Typ; Pset MEP.Tech-Insulation thickness (mm): 100; Pset MEP.Tech-PN: 16; Pset MEP.Geom-DN: 65; Pset MEP.Geom-Outer Ø (mm): 185; Pset MEP.Geom-Depth: 45; In IFC exportieren als: ifcflowfitting; NameOverride: Flansch; IfcPresentationLayer: 0-TFT-H_Ruecklauf; ObjectTypeOverride: Flansch; Pset MEP.Name: Flansch; IfcDescription: Flansch; Pset MEP.Tech-Material: nach DIN 2627
Phasen - Phase erstellt: Phase 01

# IfcFlowFitting: Flansch 336047:Flansch 336047, Flansch
In: Erdgeschoss
Type - Material: IfcSurfaceStyle #1741
Type - Andere - Kategorie: Allgemeines Modell; Familienname: Flansch 336047
Type - ID-Daten - Typname: Flansch 336047
Type - IFC-Parameter - Typ in IFC-Datei exportieren: Vorgabe
Description: Flansch
Pset_DistributionFlowElementCommon - Reference: Flansch 336047; sets with these values: 2
Andere - Typ: Flansch 336047; Familie: Flansch 336047; Familie und Typ: Flansch 336047: Flansch 336047; Typ-ID: 2535824
Abhängigkeiten - Höhe von Ebene: 0 m; Verschieben mit umliegenden Elementen: no
Bemaßungen - Fläche: 0.0638334 m2; Volumen: 0.00380173 m3
IFC-Parameter - In IFC-Datei exportieren: Nach Typ; Pset MEP.Tech-Insulation thickness (mm): 100; Pset MEP.Tech-PN: 16; Pset MEP.Geom-DN: 65; Pset MEP.Geom-Outer Ø (mm): 185; Pset MEP.Geom-Depth: 45; In IFC exportieren als: ifcflowfitting; NameOverride: Flansch; IfcPresentationLayer: 0-TFT-H_Ruecklauf; ObjectTypeOverride: Flansch; Pset MEP.Name: Flansch; IfcDescription: Flansch; Pset MEP.Tech-Material: nach DIN 2627
Phasen - Phase erstellt: Phase 01

# IfcFlowFitting: Flansch 336070:Flansch 336070, Flansch
In: Erdgeschoss
Type - Material: IfcSurfaceStyle #1741
Type - Andere - Kategorie: Allgemeines Modell; Familienname: Flansch 336070
Type - ID-Daten - Typname: Flansch 336070
Type - IFC-Parameter - Typ in IFC-Datei exportieren: Vorgabe
Description: Flansch
Pset_DistributionFlowElementCommon - Reference: Flansch 336070; sets with these values: 2
Andere - Typ: Flansch 336070; Familie: Flansch 336070; Familie und Typ: Flansch 336070: Flansch 336070; Typ-ID: 2535831
Abhängigkeiten - Höhe von Ebene: 0 m; Verschieben mit umliegenden Elementen: no
Bemaßungen - Fläche: 0.0638334 m2; Volumen: 0.00380173 m3
IFC-Parameter - In IFC-Datei exportieren: Nach Typ; Pset MEP.Tech-Insulation thickness (mm): 100; Pset MEP.Tech-PN: 16; Pset MEP.Geom-DN: 65; Pset MEP.Geom-Outer Ø (mm): 185; Pset MEP.Geom-Depth: 45; In IFC exportieren als: ifcflowfitting; NameOverride: Flansch; IfcPresentationLayer: 0-TFT-H_Ruecklauf; ObjectTypeOverride: Flansch; Pset MEP.Name: Flansch; IfcDescription: Flansch; Pset MEP.Tech-Material: nach DIN 2627
Phasen - Phase erstellt: Phase 01

# IfcFlowFitting: Flansch 339794:Flansch 339794, Flansch
In: Erdgeschoss
Type - Material: IfcSurfaceStyle #9317
Type - Andere - Kategorie: Allgemeines Modell; Familienname: Flansch 339794
Type - ID-Daten - Typname: Flansch 339794
Type - IFC-Parameter - Typ in IFC-Datei exportieren: Vorgabe
Description: Flansch
Pset_DistributionFlowElementCommon - Reference: Flansch 339794; sets with these values: 2
Andere - Typ: Flansch 339794; Familie: Flansch 339794; Familie und Typ: Flansch 339794: Flansch 339794; Typ-ID: 2535859
Abhängigkeiten - Höhe von Ebene: 0 m; Verschieben mit umliegenden Elementen: no
Bemaßungen - Fläche: 0.0724331 m2; Volumen: 0.00386894 m3
IFC-Parameter - In IFC-Datei exportieren: Nach Typ; Pset MEP.Tech-Insulation thickness (mm): 100; Pset MEP.Tech-PN: 16; Pset MEP.Geom-DN: 80; Pset MEP.Geom-Depth: 50; Pset MEP.Geom-Outer Ø (mm): 200; In IFC exportieren als: ifcflowfitting; NameOverride: Flansch; IfcPresentationLayer: 0-TFT-H_Vorlauf; ObjectTypeOverride: Flansch; Pset MEP.Name: Flansch; IfcDescription: Flansch; Pset MEP.Tech-Material: nach DIN 2627
Phasen - Phase erstellt: Phase 01

# IfcFlowFitting: Flansch 340561:Flansch 340561, Flansch
In: Erdgeschoss
Type - Material: IfcSurfaceStyle #9317
Type - Andere - Kategorie: Allgemeines Modell; Familienname: Flansch 340561
Type - ID-Daten - Typname: Flansch 340561
Type - IFC-Parameter - Typ in IFC-Datei exportieren: Vorgabe
Description: Flansch
Pset_DistributionFlowElementCommon - Reference: Flansch 340561; sets with these values: 2
Andere - Typ: Flansch 340561; Familie: Flansch 340561; Familie und Typ: Flansch 340561: Flansch 340561; Typ-ID: 2535866
Abhängigkeiten - Höhe von Ebene: 0 m; Verschieben mit umliegenden Elementen: no
Bemaßungen - Fläche: 0.111243 m2; Volumen: 0.00814942 m3
IFC-Parameter - In IFC-Datei exportieren: Nach Typ; Pset MEP.Tech-Insulation thickness (mm): 100; Pset MEP.Tech-PN: 16; Pset MEP.Geom-Depth: 55; Pset MEP.Geom-DN: 150; Pset MEP.Geom-Outer Ø (mm): 285; In IFC exportieren als: ifcflowfitting; NameOverride: Flansch; IfcPresentationLayer: 0-TFT-H_Vorlauf; ObjectTypeOverride: Flansch; Pset MEP.Name: Flansch; IfcDescription: Flansch; Pset MEP.Tech-Material: nach DIN 2627
Phasen - Phase erstellt: Phase 01

# IfcFlowFitting: Flansch 340607:Flansch 340607, Flansch
In: Erdgeschoss
Type - Material: IfcSurfaceStyle #9317
Type - Andere - Kategorie: Allgemeines Modell; Familienname: Flansch 340607
Type - ID-Daten - Typname: Flansch 340607
Type - IFC-Parameter - Typ in IFC-Datei exportieren: Vorgabe
Description: Flansch
Pset_DistributionFlowElementCommon - Reference: Flansch 340607; sets with these values: 2
Andere - Typ: Flansch 340607; Familie: Flansch 340607; Familie und Typ: Flansch 340607: Flansch 340607; Typ-ID: 2535880
Abhängigkeiten - Höhe von Ebene: 0 m; Verschieben mit umliegenden Elementen: no
Bemaßungen - Fläche: 0.111243 m2; Volumen: 0.00814942 m3
IFC-Parameter - In IFC-Datei exportieren: Nach Typ; Pset MEP.Tech-Insulation thickness (mm): 100; Pset MEP.Tech-PN: 16; Pset MEP.Geom-Depth: 55; Pset MEP.Geom-DN: 150; Pset MEP.Geom-Outer Ø (mm): 285; In IFC exportieren als: ifcflowfitting; NameOverride: Flansch; IfcPresentationLayer: 0-TFT-H_Vorlauf; ObjectTypeOverride: Flansch; Pset MEP.Name: Flansch; IfcDescription: Flansch; Pset MEP.Tech-Material: nach DIN 2627
Phasen - Phase erstellt: Phase 01

# IfcFlowFitting: Flansch 340673:Flansch 340673, Flansch
In: Erdgeschoss
Type - Material: IfcSurfaceStyle #1741
Type - Andere - Kategorie: Allgemeines Modell; Familienname: Flansch 340673
Type - ID-Daten - Typname: Flansch 340673
Type - IFC-Parameter - Typ in IFC-Datei exportieren: Vorgabe
Description: Flansch
Pset_DistributionFlowElementCommon - Reference: Flansch 340673; sets with these values: 2
Andere - Typ: Flansch 340673; Familie: Flansch 340673; Familie und Typ: Flansch 340673: Flansch 340673; Typ-ID: 2535901
Abhängigkeiten - Höhe von Ebene: 0 m; Verschieben mit umliegenden Elementen: no
Bemaßungen - Fläche: 0.111243 m2; Volumen: 0.00814942 m3
IFC-Parameter - In IFC-Datei exportieren: Nach Typ; Pset MEP.Tech-Insulation thickness (mm): 100; Pset MEP.Tech-PN: 16; Pset MEP.Geom-Depth: 55; Pset MEP.Geom-DN: 150; Pset MEP.Geom-Outer Ø (mm): 285; In IFC exportieren als: ifcflowfitting; NameOverride: Flansch; IfcPresentationLayer: 0-TFT-H_Ruecklauf; ObjectTypeOverride: Flansch; Pset MEP.Name: Flansch; IfcDescription: Flansch; Pset MEP.Tech-Material: nach DIN 2627
Phasen - Phase erstellt: Phase 01

# IfcFlowFitting: Flansch 340765:Flansch 340765, Flansch
In: Erdgeschoss
Type - Material: IfcSurfaceStyle #1741
Type - Andere - Kategorie: Allgemeines Modell; Familienname: Flansch 340765
Type - ID-Daten - Typname: Flansch 340765
Type - IFC-Parameter - Typ in IFC-Datei exportieren: Vorgabe
Description: Flansch
Pset_DistributionFlowElementCommon - Reference: Flansch 340765; sets with these values: 2
Andere - Typ: Flansch 340765; Familie: Flansch 340765; Familie und Typ: Flansch 340765: Flansch 340765; Typ-ID: 2535929
Abhängigkeiten - Höhe von Ebene: 0 m; Verschieben mit umliegenden Elementen: no
Bemaßungen - Fläche: 0.0800177 m2; Volumen: 0.00543566 m3
IFC-Parameter - In IFC-Datei exportieren: Nach Typ; Pset MEP.Tech-Insulation thickness (mm): 100; Pset MEP.Tech-PN: 16; Pset MEP.Geom-DN: 100; Pset MEP.Geom-Depth: 52; Pset MEP.Geom-Outer Ø (mm): 220; In IFC exportieren als: ifcflowfitting; NameOverride: Flansch; IfcPresentationLayer: 0-TFT-H_Ruecklauf; ObjectTypeOverride: Flansch; Pset MEP.Name: Flansch; IfcDescription: Flansch; Pset MEP.Tech-Material: nach DIN 2627
Phasen - Phase erstellt: Phase 01

# IfcFlowFitting: Flansch 340811:Flansch 340811, Flansch
In: Erdgeschoss
Type - Material: IfcSurfaceStyle #1741
Type - Andere - Kategorie: Allgemeines Modell; Familienname: Flansch 340811
Type - ID-Daten - Typname: Flansch 340811
Type - IFC-Parameter - Typ in IFC-Datei exportieren: Vorgabe
Description: Flansch
Pset_DistributionFlowElementCommon - Reference: Flansch 340811; sets with these values: 2
Andere - Typ: Flansch 340811; Familie: Flansch 340811; Familie und Typ: Flansch 340811: Flansch 340811; Typ-ID: 2535943
Abhängigkeiten - Höhe von Ebene: 0 m; Verschieben mit umliegenden Elementen: no
Bemaßungen - Fläche: 0.0951801 m2; Volumen: 0.00682535 m3
IFC-Parameter - In IFC-Datei exportieren: Nach Typ; Pset MEP.Tech-Insulation thickness (mm): 100; Pset MEP.Tech-PN: 16; Pset MEP.Geom-Depth: 55; Pset MEP.Geom-DN: 125; Pset MEP.Geom-Outer Ø (mm): 250; In IFC exportieren als: ifcflowfitting; NameOverride: Flansch; IfcPresentationLayer: 0-TFT-H_Ruecklauf; ObjectTypeOverride: Flansch; Pset MEP.Name: Flansch; IfcDescription: Flansch; Pset MEP.Tech-Material: nach DIN 2627
Phasen - Phase erstellt: Phase 01

# IfcFlowFitting: Flansch 340857:Flansch 340857, Flansch
In: Erdgeschoss
Type - Material: IfcSurfaceStyle #1741
Type - Andere - Kategorie: Allgemeines Modell; Familienname: Flansch 340857
Type - ID-Daten - Typname: Flansch 340857
Type - IFC-Parameter - Typ in IFC-Datei exportieren: Vorgabe
Description: Flansch
Pset_DistributionFlowElementCommon - Reference: Flansch 340857; sets with these values: 2
Andere - Typ: Flansch 340857; Familie: Flansch 340857; Familie und Typ: Flansch 340857: Flansch 340857; Typ-ID: 2535957
Abhängigkeiten - Höhe von Ebene: 0 m; Verschieben mit umliegenden Elementen: no
Bemaßungen - Fläche: 0.0800177 m2; Volumen: 0.00543566 m3
IFC-Parameter - In IFC-Datei exportieren: Nach Typ; Pset MEP.Tech-Insulation thickness (mm): 100; Pset MEP.Tech-PN: 16; Pset MEP.Geom-DN: 100; Pset MEP.Geom-Depth: 52; Pset MEP.Geom-Outer Ø (mm): 220; In IFC exportieren als: ifcflowfitting; NameOverride: Flansch; IfcPresentationLayer: 0-TFT-H_Ruecklauf; ObjectTypeOverride: Flansch; Pset MEP.Name: Flansch; IfcDescription: Flansch; Pset MEP.Tech-Material: nach DIN 2627
Phasen - Phase erstellt: Phase 01

# IfcFlowFitting: Flansch 340880:Flansch 340880, Flansch
In: Erdgeschoss
Type - Material: IfcSurfaceStyle #1741
Type - Andere - Kategorie: Allgemeines Modell; Familienname: Flansch 340880
Type - ID-Daten - Typname: Flansch 340880
Type - IFC-Parameter - Typ in IFC-Datei exportieren: Vorgabe
Description: Flansch
Pset_DistributionFlowElementCommon - Reference: Flansch 340880; sets with these values: 2
Andere - Typ: Flansch 340880; Familie: Flansch 340880; Familie und Typ: Flansch 340880: Flansch 340880; Typ-ID: 2535964
Abhängigkeiten - Höhe von Ebene: 0 m; Verschieben mit umliegenden Elementen: no
Bemaßungen - Fläche: 0.0951801 m2; Volumen: 0.00682535 m3
IFC-Parameter - In IFC-Datei exportieren: Nach Typ; Pset MEP.Tech-Insulation thickness (mm): 100; Pset MEP.Tech-PN: 16; Pset MEP.Geom-Depth: 55; Pset MEP.Geom-DN: 125; Pset MEP.Geom-Outer Ø (mm): 250; In IFC exportieren als: ifcflowfitting; NameOverride: Flansch; IfcPresentationLayer: 0-TFT-H_Ruecklauf; ObjectTypeOverride: Flansch; Pset MEP.Name: Flansch; IfcDescription: Flansch; Pset MEP.Tech-Material: nach DIN 2627
Phasen - Phase erstellt: Phase 01

# IfcFlowFitting: Flansch 340903:Flansch 340903, Flansch
In: Erdgeschoss
Type - Material: IfcSurfaceStyle #1741
Type - Andere - Kategorie: Allgemeines Modell; Familienname: Flansch 340903
Type - ID-Daten - Typname: Flansch 340903
Type - IFC-Parameter - Typ in IFC-Datei exportieren: Vorgabe
Description: Flansch
Pset_DistributionFlowElementCommon - Reference: Flansch 340903; sets with these values: 2
Andere - Typ: Flansch 340903; Familie: Flansch 340903; Familie und Typ: Flansch 340903: Flansch 340903; Typ-ID: 2535971
Abhängigkeiten - Höhe von Ebene: 0 m; Verschieben mit umliegenden Elementen: no
Bemaßungen - Fläche: 0.0951801 m2; Volumen: 0.00682535 m3
IFC-Parameter - In IFC-Datei exportieren: Nach Typ; Pset MEP.Tech-Insulation thickness (mm): 100; Pset MEP.Tech-PN: 16; Pset MEP.Geom-Depth: 55; Pset MEP.Geom-DN: 125; Pset MEP.Geom-Outer Ø (mm): 250; In IFC exportieren als: ifcflowfitting; NameOverride: Flansch; IfcPresentationLayer: 0-TFT-H_Ruecklauf; ObjectTypeOverride: Flansch; Pset MEP.Name: Flansch; IfcDescription: Flansch; Pset MEP.Tech-Material: nach DIN 2627
Phasen - Phase erstellt: Phase 01

# IfcFlowFitting: Flansch 340995:Flansch 340995, Flansch
In: Erdgeschoss
Type - Material: IfcSurfaceStyle #1741
Type - Andere - Kategorie: Allgemeines Modell; Familienname: Flansch 340995
Type - ID-Daten - Typname: Flansch 340995
Type - IFC-Parameter - Typ in IFC-Datei exportieren: Vorgabe
Description: Flansch
Pset_DistributionFlowElementCommon - Reference: Flansch 340995; sets with these values: 2
Andere - Typ: Flansch 340995; Familie: Flansch 340995; Familie und Typ: Flansch 340995: Flansch 340995; Typ-ID: 2535999
Abhängigkeiten - Höhe von Ebene: 0 m; Verschieben mit umliegenden Elementen: no
Bemaßungen - Fläche: 0.0404913 m2; Volumen: 0.00128585 m3
IFC-Parameter - In IFC-Datei exportieren: Nach Typ; Pset MEP.Tech-PN: 16; Pset MEP.Geom-Depth: 55; Pset MEP.Geom-DN: 125; Pset MEP.Geom-Outer Ø (mm): 250; In IFC exportieren als: ifcflowfitting; NameOverride: Flansch; IfcPresentationLayer: 0-TFT-H_Ruecklauf; ObjectTypeOverride: Flansch; Pset MEP.Name: Flansch; IfcDescription: Flansch; Pset MEP.Tech-Material: nach DIN 2627
Phasen - Phase erstellt: Phase 01

# IfcFlowFitting: Flansch 341016:Flansch 341016, Flansch
In: Erdgeschoss
Type - Material: IfcSurfaceStyle #1741
Type - Andere - Kategorie: Allgemeines Modell; Familienname: Flansch 341016
Type - ID-Daten - Typname: Flansch 341016
Type - IFC-Parameter - Typ in IFC-Datei exportieren: Vorgabe
Description: Flansch
Pset_DistributionFlowElementCommon - Reference: Flansch 341016; sets with these values: 2
Andere - Typ: Flansch 341016; Familie: Flansch 341016; Familie und Typ: Flansch 341016: Flansch 341016; Typ-ID: 2536006
Abhängigkeiten - Höhe von Ebene: 0 m; Verschieben mit umliegenden Elementen: no
Bemaßungen - Fläche: 0.0951801 m2; Volumen: 0.00682535 m3
IFC-Parameter - In IFC-Datei exportieren: Nach Typ; Pset MEP.Tech-Insulation thickness (mm): 100; Pset MEP.Tech-PN: 16; Pset MEP.Geom-Depth: 55; Pset MEP.Geom-DN: 125; Pset MEP.Geom-Outer Ø (mm): 250; In IFC exportieren als: ifcflowfitting; NameOverride: Flansch; IfcPresentationLayer: 0-TFT-H_Ruecklauf; ObjectTypeOverride: Flansch; Pset MEP.Name: Flansch; IfcDescription: Flansch; Pset MEP.Tech-Material: nach DIN 2627
Phasen - Phase erstellt: Phase 01

# IfcFlowFitting: Flansch 341081:Flansch 341081, Flansch
In: Erdgeschoss
Type - Material: IfcSurfaceStyle #1741
Type - Andere - Kategorie: Allgemeines Modell; Familienname: Flansch 341081
Type - ID-Daten - Typname: Flansch 341081
Type - IFC-Parameter - Typ in IFC-Datei exportieren: Vorgabe
Description: Flansch
Pset_DistributionFlowElementCommon - Reference: Flansch 341081; sets with these values: 2
Andere - Typ: Flansch 341081; Familie: Flansch 341081; Familie und Typ: Flansch 341081: Flansch 341081; Typ-ID: 2536027
Abhängigkeiten - Höhe von Ebene: 0 m; Verschieben mit umliegenden Elementen: no
Bemaßungen - Fläche: 0.0951801 m2; Volumen: 0.00682535 m3
IFC-Parameter - In IFC-Datei exportieren: Nach Typ; Pset MEP.Tech-Insulation thickness (mm): 100; Pset MEP.Tech-PN: 16; Pset MEP.Geom-Depth: 55; Pset MEP.Geom-DN: 125; Pset MEP.Geom-Outer Ø (mm): 250; In IFC exportieren als: ifcflowfitting; NameOverride: Flansch; IfcPresentationLayer: 0-TFT-H_Ruecklauf; ObjectTypeOverride: Flansch; Pset MEP.Name: Flansch; IfcDescription: Flansch; Pset MEP.Tech-Material: nach DIN 2627
Phasen - Phase erstellt: Phase 01

# IfcFlowFitting: Flansch 341150:Flansch 341150, Flansch
In: Erdgeschoss
Type - Material: IfcSurfaceStyle #1741
Type - Andere - Kategorie: Allgemeines Modell; Familienname: Flansch 341150
Type - ID-Daten - Typname: Flansch 341150
Type - IFC-Parameter - Typ in IFC-Datei exportieren: Vorgabe
Description: Flansch
Pset_DistributionFlowElementCommon - Reference: Flansch 341150; sets with these values: 2
Andere - Typ: Flansch 341150; Familie: Flansch 341150; Familie und Typ: Flansch 341150: Flansch 341150; Typ-ID: 2536048
Abhängigkeiten - Höhe von Ebene: 0 m; Verschieben mit umliegenden Elementen: no
Bemaßungen - Fläche: 0.111243 m2; Volumen: 0.00683497 m3
IFC-Parameter - In IFC-Datei exportieren: Nach Typ; Pset MEP.Tech-Insulation thickness (mm): 100; Pset MEP.Tech-PN: 16; Pset MEP.Geom-Depth: 55; Pset MEP.Geom-DN: 150; Pset MEP.Geom-Outer Ø (mm): 285; In IFC exportieren als: ifcflowfitting; NameOverride: Flansch; IfcPresentationLayer: 0-TFT-H_Ruecklauf; ObjectTypeOverride: Flansch; Pset MEP.Name: Flansch; IfcDescription: Flansch; Pset MEP.Tech-Material: nach DIN 2627
Phasen - Phase erstellt: Phase 01

# IfcFlowFitting: Flansch 341197:Flansch 341197, Flansch
In: Erdgeschoss
Type - Material: IfcSurfaceStyle #1741
Type - Andere - Kategorie: Allgemeines Modell; Familienname: Flansch 341197
Type - ID-Daten - Typname: Flansch 341197
Type - IFC-Parameter - Typ in IFC-Datei exportieren: Vorgabe
Description: Flansch
Pset_DistributionFlowElementCommon - Reference: Flansch 341197; sets with these values: 2
Andere - Typ: Flansch 341197; Familie: Flansch 341197; Familie und Typ: Flansch 341197: Flansch 341197; Typ-ID: 2536055
Abhängigkeiten - Höhe von Ebene: 0 m; Verschieben mit umliegenden Elementen: no
Bemaßungen - Fläche: 0.0951801 m2; Volumen: 0.00682535 m3
IFC-Parameter - In IFC-Datei exportieren: Nach Typ; Pset MEP.Tech-Insulation thickness (mm): 100; Pset MEP.Tech-PN: 16; Pset MEP.Geom-Depth: 55; Pset MEP.Geom-DN: 125; Pset MEP.Geom-Outer Ø (mm): 250; In IFC exportieren als: ifcflowfitting; NameOverride: Flansch; IfcPresentationLayer: 0-TFT-H_Ruecklauf; ObjectTypeOverride: Flansch; Pset MEP.Name: Flansch; IfcDescription: Flansch; Pset MEP.Tech-Material: nach DIN 2627
Phasen - Phase erstellt: Phase 01

# IfcFlowFitting: Flansch 342954:Flansch 342954, Flansch
In: Erdgeschoss
Type - Material: IfcSurfaceStyle #9317
Type - Andere - Kategorie: Allgemeines Modell; Familienname: Flansch 342954
Type - ID-Daten - Typname: Flansch 342954
Type - IFC-Parameter - Typ in IFC-Datei exportieren: Vorgabe
Description: Flansch
Pset_DistributionFlowElementCommon - Reference: Flansch 342954; sets with these values: 2
Andere - Typ: Flansch 342954; Familie: Flansch 342954; Familie und Typ: Flansch 342954: Flansch 342954; Typ-ID: 2536174
Abhängigkeiten - Höhe von Ebene: 0 m; Verschieben mit umliegenden Elementen: no
Bemaßungen - Fläche: 0.0503828 m2; Volumen: 0.00109829 m3
IFC-Parameter - In IFC-Datei exportieren: Nach Typ; Pset MEP.Tech-Insulation thickness (mm): 100; Pset MEP.Tech-PN: 16; Pset MEP.Geom-Depth: 55; Pset MEP.Geom-DN: 150; Pset MEP.Geom-Outer Ø (mm): 285; In IFC exportieren als: ifcflowfitting; NameOverride: Flansch; IfcPresentationLayer: 0-TFT-H_Vorlauf; ObjectTypeOverride: Flansch; Pset MEP.Name: Flansch; IfcDescription: Flansch; Pset MEP.Tech-Material: nach DIN 2627
Phasen - Phase erstellt: Phase 01

# IfcFlowFitting: Flansch 343006:Flansch 343006, Flansch
In: Erdgeschoss
Type - Material: IfcSurfaceStyle #9317
Type - Andere - Kategorie: Allgemeines Modell; Familienname: Flansch 343006
Type - ID-Daten - Typname: Flansch 343006
Type - IFC-Parameter - Typ in IFC-Datei exportieren: Vorgabe
Description: Flansch
Pset_DistributionFlowElementCommon - Reference: Flansch 343006; sets with these values: 2
Andere - Typ: Flansch 343006; Familie: Flansch 343006; Familie und Typ: Flansch 343006: Flansch 343006; Typ-ID: 2536188
Abhängigkeiten - Höhe von Ebene: 0 m; Verschieben mit umliegenden Elementen: no
Bemaßungen - Fläche: 0.111243 m2; Volumen: 0.00814942 m3
IFC-Parameter - In IFC-Datei exportieren: Nach Typ; Pset MEP.Tech-Insulation thickness (mm): 100; Pset MEP.Tech-PN: 16; Pset MEP.Geom-Depth: 55; Pset MEP.Geom-DN: 150; Pset MEP.Geom-Outer Ø (mm): 285; In IFC exportieren als: ifcflowfitting; NameOverride: Flansch; IfcPresentationLayer: 0-TFT-H_Vorlauf; ObjectTypeOverride: Flansch; Pset MEP.Name: Flansch; IfcDescription: Flansch; Pset MEP.Tech-Material: nach DIN 2627
Phasen - Phase erstellt: Phase 01

# IfcFlowFitting: Flansch 343029:Flansch 343029, Flansch
In: Erdgeschoss
Type - Material: IfcSurfaceStyle #9317
Type - Andere - Kategorie: Allgemeines Modell; Familienname: Flansch 343029
Type - ID-Daten - Typname: Flansch 343029
Type - IFC-Parameter - Typ in IFC-Datei exportieren: Vorgabe
Description: Flansch
Pset_DistributionFlowElementCommon - Reference: Flansch 343029; sets with these values: 2
Andere - Typ: Flansch 343029; Familie: Flansch 343029; Familie und Typ: Flansch 343029: Flansch 343029; Typ-ID: 2536195
Abhängigkeiten - Höhe von Ebene: 0 m; Verschieben mit umliegenden Elementen: no
Bemaßungen - Fläche: 0.111243 m2; Volumen: 0.00683497 m3
IFC-Parameter - In IFC-Datei exportieren: Nach Typ; Pset MEP.Tech-Insulation thickness (mm): 100; Pset MEP.Tech-PN: 16; Pset MEP.Geom-Depth: 55; Pset MEP.Geom-DN: 150; Pset MEP.Geom-Outer Ø (mm): 285; In IFC exportieren als: ifcflowfitting; NameOverride: Flansch; IfcPresentationLayer: 0-TFT-H_Vorlauf; ObjectTypeOverride: Flansch; Pset MEP.Name: Flansch; IfcDescription: Flansch; Pset MEP.Tech-Material: nach DIN 2627
Phasen - Phase erstellt: Phase 01

# IfcFlowFitting: Flansch 343058:Flansch 343058, Flansch
In: Erdgeschoss
Type - Material: IfcSurfaceStyle #9317
Type - Andere - Kategorie: Allgemeines Modell; Familienname: Flansch 343058
Type - ID-Daten - Typname: Flansch 343058
Type - IFC-Parameter - Typ in IFC-Datei exportieren: Vorgabe
Description: Flansch
Pset_DistributionFlowElementCommon - Reference: Flansch 343058; sets with these values: 2
Andere - Typ: Flansch 343058; Familie: Flansch 343058; Familie und Typ: Flansch 343058: Flansch 343058; Typ-ID: 2536202
Abhängigkeiten - Höhe von Ebene: 0 m; Verschieben mit umliegenden Elementen: no
Bemaßungen - Fläche: 0.0503828 m2; Volumen: 0.00171028 m3
IFC-Parameter - In IFC-Datei exportieren: Nach Typ; Pset MEP.Tech-Insulation thickness (mm): 100; Pset MEP.Tech-PN: 16; Pset MEP.Geom-Depth: 55; Pset MEP.Geom-DN: 150; Pset MEP.Geom-Outer Ø (mm): 285; In IFC exportieren als: ifcflowfitting; NameOverride: Flansch; IfcPresentationLayer: 0-TFT-H_Vorlauf; ObjectTypeOverride: Flansch; Pset MEP.Name: Flansch; IfcDescription: Flansch; Pset MEP.Tech-Material: nach DIN 2627
Phasen - Phase erstellt: Phase 01

# IfcFlowFitting: Flansch 343431:Flansch 343431, Flansch
In: Erdgeschoss
Type - Material: IfcSurfaceStyle #9317
Type - Andere - Kategorie: Allgemeines Modell; Familienname: Flansch 343431
Type - ID-Daten - Typname: Flansch 343431
Type - IFC-Parameter - Typ in IFC-Datei exportieren: Vorgabe
Description: Flansch
Pset_DistributionFlowElementCommon - Reference: Flansch 343431; sets with these values: 2
Andere - Typ: Flansch 343431; Familie: Flansch 343431; Familie und Typ: Flansch 343431: Flansch 343431; Typ-ID: 2536237
Abhängigkeiten - Höhe von Ebene: 0 m; Verschieben mit umliegenden Elementen: no
Bemaßungen - Fläche: 0.111243 m2; Volumen: 0.00683497 m3
IFC-Parameter - In IFC-Datei exportieren: Nach Typ; Pset MEP.Tech-Insulation thickness (mm): 100; Pset MEP.Tech-PN: 16; Pset MEP.Geom-Depth: 55; Pset MEP.Geom-DN: 150; Pset MEP.Geom-Outer Ø (mm): 285; In IFC exportieren als: ifcflowfitting; NameOverride: Flansch; IfcPresentationLayer: 0-TFT-H_Vorlauf; ObjectTypeOverride: Flansch; Pset MEP.Name: Flansch; IfcDescription: Flansch; Pset MEP.Tech-Material: nach DIN 2627
Phasen - Phase erstellt: Phase 01

# IfcFlowFitting: Flansch 343454:Flansch 343454, Flansch
In: Erdgeschoss
Type - Material: IfcSurfaceStyle #9317
Type - Andere - Kategorie: Allgemeines Modell; Familienname: Flansch 343454
Type - ID-Daten - Typname: Flansch 343454
Type - IFC-Parameter - Typ in IFC-Datei exportieren: Vorgabe
Description: Flansch
Pset_DistributionFlowElementCommon - Reference: Flansch 343454; sets with these values: 2
Andere - Typ: Flansch 343454; Familie: Flansch 343454; Familie und Typ: Flansch 343454: Flansch 343454; Typ-ID: 2536244
Abhängigkeiten - Höhe von Ebene: 0 m; Verschieben mit umliegenden Elementen: no
Bemaßungen - Fläche: 0.0503828 m2; Volumen: 0.00171028 m3
IFC-Parameter - In IFC-Datei exportieren: Nach Typ; Pset MEP.Tech-Insulation thickness (mm): 100; Pset MEP.Tech-PN: 16; Pset MEP.Geom-Depth: 55; Pset MEP.Geom-DN: 150; Pset MEP.Geom-Outer Ø (mm): 285; In IFC exportieren als: ifcflowfitting; NameOverride: Flansch; IfcPresentationLayer: 0-TFT-H_Vorlauf; ObjectTypeOverride: Flansch; Pset MEP.Name: Flansch; IfcDescription: Flansch; Pset MEP.Tech-Material: nach DIN 2627
Phasen - Phase erstellt: Phase 01

# IfcFlowFitting: Flansch 344699:Flansch 344699, Flansch
In: Erdgeschoss
Type - Material: IfcSurfaceStyle #9317
Type - Andere - Kategorie: Allgemeines Modell; Familienname: Flansch 344699
Type - ID-Daten - Typname: Flansch 344699
Type - IFC-Parameter - Typ in IFC-Datei exportieren: Vorgabe
Description: Flansch
Pset_DistributionFlowElementCommon - Reference: Flansch 344699; sets with these values: 2
Andere - Typ: Flansch 344699; Familie: Flansch 344699; Familie und Typ: Flansch 344699: Flansch 344699; Typ-ID: 2536307
Abhängigkeiten - Höhe von Ebene: 0 m; Verschieben mit umliegenden Elementen: no
Bemaßungen - Fläche: 0.0263438 m2; Volumen: 0.000677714 m3
IFC-Parameter - In IFC-Datei exportieren: Nach Typ; Pset MEP.Tech-Insulation thickness (mm): 100; Pset MEP.Tech-PN: 16; Pset MEP.Geom-DN: 80; Pset MEP.Geom-Depth: 50; Pset MEP.Geom-Outer Ø (mm): 200; In IFC exportieren als: ifcflowfitting; NameOverride: Flansch; IfcPresentationLayer: 0-TFT-H_Vorlauf; ObjectTypeOverride: Flansch; Pset MEP.Name: Flansch; IfcDescription: Flansch; Pset MEP.Tech-Material: nach DIN 2627
Phasen - Phase erstellt: Phase 01

# IfcFlowFitting: Flansch 348272:Flansch 348272, Flansch
In: Erdgeschoss
Type - Material: IfcSurfaceStyle #1741
Type - Andere - Kategorie: Allgemeines Modell; Familienname: Flansch 348272
Type - ID-Daten - Typname: Flansch 348272
Type - IFC-Parameter - Typ in IFC-Datei exportieren: Vorgabe
Description: Flansch
Pset_DistributionFlowElementCommon - Reference: Flansch 348272; sets with these values: 2
Andere - Typ: Flansch 348272; Familie: Flansch 348272; Familie und Typ: Flansch 348272: Flansch 348272; Typ-ID: 2536440
Abhängigkeiten - Höhe von Ebene: 0 m; Verschieben mit umliegenden Elementen: no
Bemaßungen - Fläche: 0.0219883 m2; Volumen: 0.000503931 m3
IFC-Parameter - In IFC-Datei exportieren: Nach Typ; Pset MEP.Tech-Insulation thickness (mm): 100; Pset MEP.Tech-PN: 16; Pset MEP.Geom-DN: 65; Pset MEP.Geom-Outer Ø (mm): 185; Pset MEP.Geom-Depth: 45; In IFC exportieren als: ifcflowfitting; NameOverride: Flansch; IfcPresentationLayer: 0-TFT-H_Ruecklauf; ObjectTypeOverride: Flansch; Pset MEP.Name: Flansch; IfcDescription: Flansch; Pset MEP.Tech-Material: nach DIN 2627
Phasen - Phase erstellt: Phase 01

# IfcFlowFitting: Flansch 350492:Flansch 350492, Flansch
In: Erdgeschoss
Type - Material: IfcSurfaceStyle #1741
Type - Andere - Kategorie: Allgemeines Modell; Familienname: Flansch 350492
Type - ID-Daten - Typname: Flansch 350492
Type - IFC-Parameter - Typ in IFC-Datei exportieren: Vorgabe
Description: Flansch
Pset_DistributionFlowElementCommon - Reference: Flansch 350492; sets with these values: 2
Andere - Typ: Flansch 350492; Familie: Flansch 350492; Familie und Typ: Flansch 350492: Flansch 350492; Typ-ID: 2536503
Abhängigkeiten - Höhe von Ebene: 0 m; Verschieben mit umliegenden Elementen: no
Bemaßungen - Fläche: 0.0709996 m2; Volumen: 0.00186495 m3
IFC-Parameter - In IFC-Datei exportieren: Nach Typ; Pset MEP.Geom-Depth: 62; Pset MEP.Geom-DN: 200; Pset MEP.Geom-Outer Ø (mm): 340; Pset MEP.Tech-Insulation thickness (mm): 100; Pset MEP.Tech-PN: 16; In IFC exportieren als: ifcflowfitting; NameOverride: Flansch; IfcPresentationLayer: 0-TFT-H_Ruecklauf; ObjectTypeOverride: Flansch; Pset MEP.Name: Flansch; IfcDescription: Flansch; Pset MEP.Tech-Material: nach DIN 2627
Phasen - Phase erstellt: Phase 01

# IfcFlowFitting: Flansch 350519:Flansch 350519, Flansch
In: Erdgeschoss
Type - Material: IfcSurfaceStyle #1741
Type - Andere - Kategorie: Allgemeines Modell; Familienname: Flansch 350519
Type - ID-Daten - Typname: Flansch 350519
Type - IFC-Parameter - Typ in IFC-Datei exportieren: Vorgabe
Description: Flansch
Pset_DistributionFlowElementCommon - Reference: Flansch 350519; sets with these values: 2
Andere - Typ: Flansch 350519; Familie: Flansch 350519; Familie und Typ: Flansch 350519: Flansch 350519; Typ-ID: 2536510
Abhängigkeiten - Höhe von Ebene: 0 m; Verschieben mit umliegenden Elementen: no
Bemaßungen - Fläche: 0.0709996 m2; Volumen: 0.00284161 m3
IFC-Parameter - In IFC-Datei exportieren: Nach Typ; Pset MEP.Geom-Depth: 62; Pset MEP.Geom-DN: 200; Pset MEP.Geom-Outer Ø (mm): 340; Pset MEP.Tech-Insulation thickness (mm): 100; Pset MEP.Tech-PN: 16; In IFC exportieren als: ifcflowfitting; NameOverride: Flansch; IfcPresentationLayer: 0-TFT-H_Ruecklauf; ObjectTypeOverride: Flansch; Pset MEP.Name: Flansch; IfcDescription: Flansch; Pset MEP.Tech-Material: nach DIN 2627
Phasen - Phase erstellt: Phase 01

# IfcFlowFitting: Flansch 351708:Flansch 351708, Flansch
In: Erdgeschoss
Type - Material: IfcSurfaceStyle #9317
Type - Andere - Kategorie: Allgemeines Modell; Familienname: Flansch 351708
Type - ID-Daten - Typname: Flansch 351708
Type - IFC-Parameter - Typ in IFC-Datei exportieren: Vorgabe
Description: Flansch
Pset_DistributionFlowElementCommon - Reference: Flansch 351708; sets with these values: 2
Andere - Typ: Flansch 351708; Familie: Flansch 351708; Familie und Typ: Flansch 351708: Flansch 351708; Typ-ID: 2536587
Abhängigkeiten - Höhe von Ebene: 0 m; Verschieben mit umliegenden Elementen: no
Bemaßungen - Fläche: 0.0800177 m2; Volumen: 0.00456789 m3
IFC-Parameter - In IFC-Datei exportieren: Nach Typ; Pset MEP.Tech-Insulation thickness (mm): 100; Pset MEP.Tech-PN: 16; Pset MEP.Geom-DN: 100; Pset MEP.Geom-Depth: 52; Pset MEP.Geom-Outer Ø (mm): 220; In IFC exportieren als: ifcflowfitting; NameOverride: Flansch; IfcPresentationLayer: 0-TFT-H_Vorlauf; ObjectTypeOverride: Flansch; Pset MEP.Name: Flansch; IfcDescription: Flansch; Pset MEP.Tech-Material: nach DIN 2627
Phasen - Phase erstellt: Phase 01

# IfcFlowFitting: Flansch 351783:Flansch 351783, Flansch
In: Erdgeschoss
Type - Material: IfcSurfaceStyle #1741
Type - Andere - Kategorie: Allgemeines Modell; Familienname: Flansch 351783
Type - ID-Daten - Typname: Flansch 351783
Type - IFC-Parameter - Typ in IFC-Datei exportieren: Vorgabe
Description: Flansch
Pset_DistributionFlowElementCommon - Reference: Flansch 351783; sets with these values: 2
Andere - Typ: Flansch 351783; Familie: Flansch 351783; Familie und Typ: Flansch 351783: Flansch 351783; Typ-ID: 2536608
Abhängigkeiten - Höhe von Ebene: 0 m; Verschieben mit umliegenden Elementen: no
Bemaßungen - Fläche: 0.0800177 m2; Volumen: 0.00456789 m3
IFC-Parameter - In IFC-Datei exportieren: Nach Typ; Pset MEP.Tech-Insulation thickness (mm): 100; Pset MEP.Tech-PN: 16; Pset MEP.Geom-DN: 100; Pset MEP.Geom-Depth: 52; Pset MEP.Geom-Outer Ø (mm): 220; In IFC exportieren als: ifcflowfitting; NameOverride: Flansch; IfcPresentationLayer: 0-TFT-H_Ruecklauf; ObjectTypeOverride: Flansch; Pset MEP.Name: Flansch; IfcDescription: Flansch; Pset MEP.Tech-Material: nach DIN 2627
Phasen - Phase erstellt: Phase 01

# IfcFlowFitting: Flansch 353114:Flansch 353114, Flansch
In: Erdgeschoss
Type - Material: IfcSurfaceStyle #352577
Type - Andere - Kategorie: Allgemeines Modell; Familienname: Flansch 353114
Type - ID-Daten - Typname: Flansch 353114
Type - IFC-Parameter - Typ in IFC-Datei exportieren: Vorgabe
Description: Flansch
Pset_DistributionFlowElementCommon - Reference: Flansch 353114; sets with these values: 2
Andere - Typ: Flansch 353114; Familie: Flansch 353114; Familie und Typ: Flansch 353114: Flansch 353114; Typ-ID: 2536660
Abhängigkeiten - Höhe von Ebene: 0 m; Verschieben mit umliegenden Elementen: no
Bemaßungen - Fläche: 0.0219883 m2; Volumen: 0.000503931 m3
IFC-Parameter - In IFC-Datei exportieren: Nach Typ; Pset MEP.Tech-PN: 16; Pset MEP.Geom-DN: 65; Pset MEP.Geom-Outer Ø (mm): 185; Pset MEP.Geom-Depth: 45; In IFC exportieren als: ifcflowfitting; NameOverride: Flansch; IfcPresentationLayer: S_Gas; ObjectTypeOverride: Flansch; Pset MEP.Name: Flansch; IfcDescription: Flansch; Pset MEP.Tech-Material: nach DIN 2627
Phasen - Phase erstellt: Phase 01

# IfcFlowFitting: Flansch 353144:Flansch 353144, Flansch
In: Erdgeschoss
Type - Material: IfcSurfaceStyle #352577
Type - Andere - Kategorie: Allgemeines Modell; Familienname: Flansch 353144
Type - ID-Daten - Typname: Flansch 353144
Type - IFC-Parameter - Typ in IFC-Datei exportieren: Vorgabe
Description: Flansch
Pset_DistributionFlowElementCommon - Reference: Flansch 353144; sets with these values: 2
Andere - Typ: Flansch 353144; Familie: Flansch 353144; Familie und Typ: Flansch 353144: Flansch 353144; Typ-ID: 2536667
Abhängigkeiten - Höhe von Ebene: 0 m; Verschieben mit umliegenden Elementen: no
Bemaßungen - Fläche: 0.0219883 m2; Volumen: 0.000503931 m3
IFC-Parameter - In IFC-Datei exportieren: Nach Typ; Pset MEP.Tech-PN: 16; Pset MEP.Geom-DN: 65; Pset MEP.Geom-Outer Ø (mm): 185; Pset MEP.Geom-Depth: 45; In IFC exportieren als: ifcflowfitting; NameOverride: Flansch; IfcPresentationLayer: S_Gas; ObjectTypeOverride: Flansch; Pset MEP.Name: Flansch; IfcDescription: Flansch; Pset MEP.Tech-Material: nach DIN 2627
Phasen - Phase erstellt: Phase 01

# IfcFlowFitting: Flansch 353167:Flansch 353167, Flansch
In: Erdgeschoss
Type - Material: IfcSurfaceStyle #352577
Type - Andere - Kategorie: Allgemeines Modell; Familienname: Flansch 353167
Type - ID-Daten - Typname: Flansch 353167
Type - IFC-Parameter - Typ in IFC-Datei exportieren: Vorgabe
Description: Flansch
Pset_DistributionFlowElementCommon - Reference: Flansch 353167; sets with these values: 2
Andere - Typ: Flansch 353167; Familie: Flansch 353167; Familie und Typ: Flansch 353167: Flansch 353167; Typ-ID: 2536674
Abhängigkeiten - Höhe von Ebene: 0 m; Verschieben mit umliegenden Elementen: no
Bemaßungen - Fläche: 0.0219883 m2; Volumen: 0.000293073 m3
IFC-Parameter - In IFC-Datei exportieren: Nach Typ; Pset MEP.Tech-PN: 16; Pset MEP.Geom-DN: 65; Pset MEP.Geom-Outer Ø (mm): 185; Pset MEP.Geom-Depth: 45; In IFC exportieren als: ifcflowfitting; NameOverride: Flansch; IfcPresentationLayer: S_Gas; ObjectTypeOverride: Flansch; Pset MEP.Name: Flansch; IfcDescription: Flansch; Pset MEP.Tech-Material: nach DIN 2627
Phasen - Phase erstellt: Phase 01

# IfcFlowFitting: Flansch 353196:Flansch 353196, Flansch
In: Erdgeschoss
Type - Material: IfcSurfaceStyle #352577
Type - Andere - Kategorie: Allgemeines Modell; Familienname: Flansch 353196
Type - ID-Daten - Typname: Flansch 353196
Type - IFC-Parameter - Typ in IFC-Datei exportieren: Vorgabe
Description: Flansch
Pset_DistributionFlowElementCommon - Reference: Flansch 353196; sets with these values: 2
Andere - Typ: Flansch 353196; Familie: Flansch 353196; Familie und Typ: Flansch 353196: Flansch 353196; Typ-ID: 2536681
Abhängigkeiten - Höhe von Ebene: 0 m; Verschieben mit umliegenden Elementen: no
Bemaßungen - Fläche: 0.0219883 m2; Volumen: 0.000503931 m3
IFC-Parameter - In IFC-Datei exportieren: Nach Typ; Pset MEP.Tech-PN: 16; Pset MEP.Geom-DN: 65; Pset MEP.Geom-Outer Ø (mm): 185; Pset MEP.Geom-Depth: 45; In IFC exportieren als: ifcflowfitting; NameOverride: Flansch; IfcPresentationLayer: S_Gas; ObjectTypeOverride: Flansch; Pset MEP.Name: Flansch; IfcDescription: Flansch; Pset MEP.Tech-Material: nach DIN 2627
Phasen - Phase erstellt: Phase 01

# IfcFlowFitting: Flansch 354304:Flansch 354304, Flansch
In: Erdgeschoss
Type - Material: IfcSurfaceStyle #352577
Type - Andere - Kategorie: Allgemeines Modell; Familienname: Flansch 354304
Type - ID-Daten - Typname: Flansch 354304
Type - IFC-Parameter - Typ in IFC-Datei exportieren: Vorgabe
Description: Flansch
Pset_DistributionFlowElementCommon - Reference: Flansch 354304; sets with these values: 2
Andere - Typ: Flansch 354304; Familie: Flansch 354304; Familie und Typ: Flansch 354304: Flansch 354304; Typ-ID: 2536695
Abhängigkeiten - Höhe von Ebene: 0 m; Verschieben mit umliegenden Elementen: no
Bemaßungen - Fläche: 0.0219883 m2; Volumen: 0.000293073 m3
IFC-Parameter - In IFC-Datei exportieren: Nach Typ; Pset MEP.Tech-PN: 16; Pset MEP.Geom-DN: 65; Pset MEP.Geom-Outer Ø (mm): 185; Pset MEP.Geom-Depth: 45; In IFC exportieren als: ifcflowfitting; NameOverride: Flansch; IfcPresentationLayer: S_Gas; ObjectTypeOverride: Flansch; Pset MEP.Name: Flansch; IfcDescription: Flansch; Pset MEP.Tech-Material: nach DIN 2627
Phasen - Phase erstellt: Phase 01

# IfcFlowFitting: Flansch 354333:Flansch 354333, Flansch
In: Erdgeschoss
Type - Material: IfcSurfaceStyle #352577
Type - Andere - Kategorie: Allgemeines Modell; Familienname: Flansch 354333
Type - ID-Daten - Typname: Flansch 354333
Type - IFC-Parameter - Typ in IFC-Datei exportieren: Vorgabe
Description: Flansch
Pset_DistributionFlowElementCommon - Reference: Flansch 354333; sets with these values: 2
Andere - Typ: Flansch 354333; Familie: Flansch 354333; Familie und Typ: Flansch 354333: Flansch 354333; Typ-ID: 2536702
Abhängigkeiten - Höhe von Ebene: 0 m; Verschieben mit umliegenden Elementen: no
Bemaßungen - Fläche: 0.0219883 m2; Volumen: 0.000503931 m3
IFC-Parameter - In IFC-Datei exportieren: Nach Typ; Pset MEP.Tech-PN: 16; Pset MEP.Geom-DN: 65; Pset MEP.Geom-Outer Ø (mm): 185; Pset MEP.Geom-Depth: 45; In IFC exportieren als: ifcflowfitting; NameOverride: Flansch; IfcPresentationLayer: S_Gas; ObjectTypeOverride: Flansch; Pset MEP.Name: Flansch; IfcDescription: Flansch; Pset MEP.Tech-Material: nach DIN 2627
Phasen - Phase erstellt: Phase 01

# IfcFlowFitting: Flansch 354354:Flansch 354354, Flansch
In: Erdgeschoss
Type - Material: IfcSurfaceStyle #352577
Type - Andere - Kategorie: Allgemeines Modell; Familienname: Flansch 354354
Type - ID-Daten - Typname: Flansch 354354
Type - IFC-Parameter - Typ in IFC-Datei exportieren: Vorgabe
Description: Flansch
Pset_DistributionFlowElementCommon - Reference: Flansch 354354; sets with these values: 2
Andere - Typ: Flansch 354354; Familie: Flansch 354354; Familie und Typ: Flansch 354354: Flansch 354354; Typ-ID: 2536709
Abhängigkeiten - Höhe von Ebene: 0 m; Verschieben mit umliegenden Elementen: no
Bemaßungen - Fläche: 0.0219883 m2; Volumen: 0.000503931 m3
IFC-Parameter - In IFC-Datei exportieren: Nach Typ; Pset MEP.Tech-PN: 16; Pset MEP.Geom-DN: 65; Pset MEP.Geom-Outer Ø (mm): 185; Pset MEP.Geom-Depth: 45; In IFC exportieren als: ifcflowfitting; NameOverride: Flansch; IfcPresentationLayer: S_Gas; ObjectTypeOverride: Flansch; Pset MEP.Name: Flansch; IfcDescription: Flansch; Pset MEP.Tech-Material: nach DIN 2627
Phasen - Phase erstellt: Phase 01

# IfcFlowFitting: Flansch 355455:Flansch 355455, Flansch
In: Erdgeschoss
Type - Material: IfcSurfaceStyle #352577
Type - Andere - Kategorie: Allgemeines Modell; Familienname: Flansch 355455
Type - ID-Daten - Typname: Flansch 355455
Type - IFC-Parameter - Typ in IFC-Datei exportieren: Vorgabe
Description: Flansch
Pset_DistributionFlowElementCommon - Reference: Flansch 355455; sets with these values: 2
Andere - Typ: Flansch 355455; Familie: Flansch 355455; Familie und Typ: Flansch 355455: Flansch 355455; Typ-ID: 2536730
Abhängigkeiten - Höhe von Ebene: 0 m; Verschieben mit umliegenden Elementen: no
Bemaßungen - Fläche: 0.0219883 m2; Volumen: 0.000293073 m3
IFC-Parameter - In IFC-Datei exportieren: Nach Typ; Pset MEP.Tech-PN: 16; Pset MEP.Geom-DN: 65; Pset MEP.Geom-Outer Ø (mm): 185; Pset MEP.Geom-Depth: 45; In IFC exportieren als: ifcflowfitting; NameOverride: Flansch; IfcPresentationLayer: S_Gas; ObjectTypeOverride: Flansch; Pset MEP.Name: Flansch; IfcDescription: Flansch; Pset MEP.Tech-Material: nach DIN 2627
Phasen - Phase erstellt: Phase 01

# IfcFlowFitting: Flansch 355484:Flansch 355484, Flansch
In: Erdgeschoss
Type - Material: IfcSurfaceStyle #352577
Type - Andere - Kategorie: Allgemeines Modell; Familienname: Flansch 355484
Type - ID-Daten - Typname: Flansch 355484
Type - IFC-Parameter - Typ in IFC-Datei exportieren: Vorgabe
Description: Flansch
Pset_DistributionFlowElementCommon - Reference: Flansch 355484; sets with these values: 2
Andere - Typ: Flansch 355484; Familie: Flansch 355484; Familie und Typ: Flansch 355484: Flansch 355484; Typ-ID: 2536737
Abhängigkeiten - Höhe von Ebene: 0 m; Verschieben mit umliegenden Elementen: no
Bemaßungen - Fläche: 0.0219883 m2; Volumen: 0.000503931 m3
IFC-Parameter - In IFC-Datei exportieren: Nach Typ; Pset MEP.Tech-PN: 16; Pset MEP.Geom-DN: 65; Pset MEP.Geom-Outer Ø (mm): 185; Pset MEP.Geom-Depth: 45; In IFC exportieren als: ifcflowfitting; NameOverride: Flansch; IfcPresentationLayer: S_Gas; ObjectTypeOverride: Flansch; Pset MEP.Name: Flansch; IfcDescription: Flansch; Pset MEP.Tech-Material: nach DIN 2627
Phasen - Phase erstellt: Phase 01

# IfcFlowFitting: Flansch 355505:Flansch 355505, Flansch
In: Erdgeschoss
Type - Material: IfcSurfaceStyle #352577
Type - Andere - Kategorie: Allgemeines Modell; Familienname: Flansch 355505
Type - ID-Daten - Typname: Flansch 355505
Type - IFC-Parameter - Typ in IFC-Datei exportieren: Vorgabe
Description: Flansch
Pset_DistributionFlowElementCommon - Reference: Flansch 355505; sets with these values: 2
Andere - Typ: Flansch 355505; Familie: Flansch 355505; Familie und Typ: Flansch 355505: Flansch 355505; Typ-ID: 2536744
Abhängigkeiten - Höhe von Ebene: 0 m; Verschieben mit umliegenden Elementen: no
Bemaßungen - Fläche: 0.0219883 m2; Volumen: 0.000293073 m3
IFC-Parameter - In IFC-Datei exportieren: Nach Typ; Pset MEP.Tech-PN: 16; Pset MEP.Geom-DN: 65; Pset MEP.Geom-Outer Ø (mm): 185; Pset MEP.Geom-Depth: 45; In IFC exportieren als: ifcflowfitting; NameOverride: Flansch; IfcPresentationLayer: S_Gas; ObjectTypeOverride: Flansch; Pset MEP.Name: Flansch; IfcDescription: Flansch; Pset MEP.Tech-Material: nach DIN 2627
Phasen - Phase erstellt: Phase 01

# IfcFlowFitting: Flansch 355534:Flansch 355534, Flansch
In: Erdgeschoss
Type - Material: IfcSurfaceStyle #352577
Type - Andere - Kategorie: Allgemeines Modell; Familienname: Flansch 355534
Type - ID-Daten - Typname: Flansch 355534
Type - IFC-Parameter - Typ in IFC-Datei exportieren: Vorgabe
Description: Flansch
Pset_DistributionFlowElementCommon - Reference: Flansch 355534; sets with these values: 2
Andere - Typ: Flansch 355534; Familie: Flansch 355534; Familie und Typ: Flansch 355534: Flansch 355534; Typ-ID: 2536751
Abhängigkeiten - Höhe von Ebene: 0 m; Verschieben mit umliegenden Elementen: no
Bemaßungen - Fläche: 0.0219883 m2; Volumen: 0.000503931 m3
IFC-Parameter - In IFC-Datei exportieren: Nach Typ; Pset MEP.Tech-PN: 16; Pset MEP.Geom-DN: 65; Pset MEP.Geom-Outer Ø (mm): 185; Pset MEP.Geom-Depth: 45; In IFC exportieren als: ifcflowfitting; NameOverride: Flansch; IfcPresentationLayer: S_Gas; ObjectTypeOverride: Flansch; Pset MEP.Name: Flansch; IfcDescription: Flansch; Pset MEP.Tech-Material: nach DIN 2627
Phasen - Phase erstellt: Phase 01

# IfcFlowFitting: Flansch 357862:Flansch 357862, Flansch
In: Erdgeschoss
Type - Material: IfcSurfaceStyle #352577
Type - Andere - Kategorie: Allgemeines Modell; Familienname: Flansch 357862
Type - ID-Daten - Typname: Flansch 357862
Type - IFC-Parameter - Typ in IFC-Datei exportieren: Vorgabe
Description: Flansch
Pset_DistributionFlowElementCommon - Reference: Flansch 357862; sets with these values: 2
Andere - Typ: Flansch 357862; Familie: Flansch 357862; Familie und Typ: Flansch 357862: Flansch 357862; Typ-ID: 2536793
Abhängigkeiten - Höhe von Ebene: 0 m; Verschieben mit umliegenden Elementen: no
Bemaßungen - Fläche: 0.0219883 m2; Volumen: 0.000293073 m3
IFC-Parameter - In IFC-Datei exportieren: Nach Typ; Pset MEP.Tech-PN: 16; Pset MEP.Geom-DN: 65; Pset MEP.Geom-Outer Ø (mm): 185; Pset MEP.Geom-Depth: 45; In IFC exportieren als: ifcflowfitting; NameOverride: Flansch; IfcPresentationLayer: S_Gas; ObjectTypeOverride: Flansch; Pset MEP.Name: Flansch; IfcDescription: Flansch; Pset MEP.Tech-Material: nach DIN 2627
Phasen - Phase erstellt: Phase 01

# IfcFlowFitting: Flansch 357885:Flansch 357885, Flansch
In: Erdgeschoss
Type - Material: IfcSurfaceStyle #352577
Type - Andere - Kategorie: Allgemeines Modell; Familienname: Flansch 357885
Type - ID-Daten - Typname: Flansch 357885
Type - IFC-Parameter - Typ in IFC-Datei exportieren: Vorgabe
Description: Flansch
Pset_DistributionFlowElementCommon - Reference: Flansch 357885; sets with these values: 2
Andere - Typ: Flansch 357885; Familie: Flansch 357885; Familie und Typ: Flansch 357885: Flansch 357885; Typ-ID: 2536800
Abhängigkeiten - Höhe von Ebene: 0 m; Verschieben mit umliegenden Elementen: no
Bemaßungen - Fläche: 0.0219883 m2; Volumen: 0.000503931 m3
IFC-Parameter - In IFC-Datei exportieren: Nach Typ; Pset MEP.Tech-PN: 16; Pset MEP.Geom-DN: 65; Pset MEP.Geom-Outer Ø (mm): 185; Pset MEP.Geom-Depth: 45; In IFC exportieren als: ifcflowfitting; NameOverride: Flansch; IfcPresentationLayer: S_Gas; ObjectTypeOverride: Flansch; Pset MEP.Name: Flansch; IfcDescription: Flansch; Pset MEP.Tech-Material: nach DIN 2627
Phasen - Phase erstellt: Phase 01

# IfcFlowFitting: Flansch 357906:Flansch 357906, Flansch
In: Erdgeschoss
Type - Material: IfcSurfaceStyle #352577
Type - Andere - Kategorie: Allgemeines Modell; Familienname: Flansch 357906
Type - ID-Daten - Typname: Flansch 357906
Type - IFC-Parameter - Typ in IFC-Datei exportieren: Vorgabe
Description: Flansch
Pset_DistributionFlowElementCommon - Reference: Flansch 357906; sets with these values: 2
Andere - Typ: Flansch 357906; Familie: Flansch 357906; Familie und Typ: Flansch 357906: Flansch 357906; Typ-ID: 2536807
Abhängigkeiten - Höhe von Ebene: 0 m; Verschieben mit umliegenden Elementen: no
Bemaßungen - Fläche: 0.0219883 m2; Volumen: 0.000503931 m3
IFC-Parameter - In IFC-Datei exportieren: Nach Typ; Pset MEP.Tech-PN: 16; Pset MEP.Geom-DN: 65; Pset MEP.Geom-Outer Ø (mm): 185; Pset MEP.Geom-Depth: 45; In IFC exportieren als: ifcflowfitting; NameOverride: Flansch; IfcPresentationLayer: S_Gas; ObjectTypeOverride: Flansch; Pset MEP.Name: Flansch; IfcDescription: Flansch; Pset MEP.Tech-Material: nach DIN 2627
Phasen - Phase erstellt: Phase 01

# IfcFlowFitting: Flansch 357927:Flansch 357927, Flansch
In: Erdgeschoss
Type - Material: IfcSurfaceStyle #352577
Type - Andere - Kategorie: Allgemeines Modell; Familienname: Flansch 357927
Type - ID-Daten - Typname: Flansch 357927
Type - IFC-Parameter - Typ in IFC-Datei exportieren: Vorgabe
Description: Flansch
Pset_DistributionFlowElementCommon - Reference: Flansch 357927; sets with these values: 2
Andere - Typ: Flansch 357927; Familie: Flansch 357927; Familie und Typ: Flansch 357927: Flansch 357927; Typ-ID: 2536814
Abhängigkeiten - Höhe von Ebene: 0 m; Verschieben mit umliegenden Elementen: no
Bemaßungen - Fläche: 0.0219883 m2; Volumen: 0.000293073 m3
IFC-Parameter - In IFC-Datei exportieren: Nach Typ; Pset MEP.Tech-PN: 16; Pset MEP.Geom-DN: 65; Pset MEP.Geom-Outer Ø (mm): 185; Pset MEP.Geom-Depth: 45; In IFC exportieren als: ifcflowfitting; NameOverride: Flansch; IfcPresentationLayer: S_Gas; ObjectTypeOverride: Flansch; Pset MEP.Name: Flansch; IfcDescription: Flansch; Pset MEP.Tech-Material: nach DIN 2627
Phasen - Phase erstellt: Phase 01

# IfcFlowFitting: Flansch 357950:Flansch 357950, Flansch
In: Erdgeschoss
Type - Material: IfcSurfaceStyle #352577
Type - Andere - Kategorie: Allgemeines Modell; Familienname: Flansch 357950
Type - ID-Daten - Typname: Flansch 357950
Type - IFC-Parameter - Typ in IFC-Datei exportieren: Vorgabe
Description: Flansch
Pset_DistributionFlowElementCommon - Reference: Flansch 357950; sets with these values: 2
Andere - Typ: Flansch 357950; Familie: Flansch 357950; Familie und Typ: Flansch 357950: Flansch 357950; Typ-ID: 2536821
Abhängigkeiten - Höhe von Ebene: 0 m; Verschieben mit umliegenden Elementen: no
Bemaßungen - Fläche: 0.0219883 m2; Volumen: 0.000293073 m3
IFC-Parameter - In IFC-Datei exportieren: Nach Typ; Pset MEP.Tech-PN: 16; Pset MEP.Geom-DN: 65; Pset MEP.Geom-Outer Ø (mm): 185; Pset MEP.Geom-Depth: 45; In IFC exportieren als: ifcflowfitting; NameOverride: Flansch; IfcPresentationLayer: S_Gas; ObjectTypeOverride: Flansch; Pset MEP.Name: Flansch; IfcDescription: Flansch; Pset MEP.Tech-Material: nach DIN 2627
Phasen - Phase erstellt: Phase 01

# IfcFlowFitting: Flansch 357973:Flansch 357973, Flansch
In: Erdgeschoss
Type - Material: IfcSurfaceStyle #352577
Type - Andere - Kategorie: Allgemeines Modell; Familienname: Flansch 357973
Type - ID-Daten - Typname: Flansch 357973
Type - IFC-Parameter - Typ in IFC-Datei exportieren: Vorgabe
Description: Flansch
Pset_DistributionFlowElementCommon - Reference: Flansch 357973; sets with these values: 2
Andere - Typ: Flansch 357973; Familie: Flansch 357973; Familie und Typ: Flansch 357973: Flansch 357973; Typ-ID: 2536828
Abhängigkeiten - Höhe von Ebene: 0 m; Verschieben mit umliegenden Elementen: no
Bemaßungen - Fläche: 0.0219883 m2; Volumen: 0.000293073 m3
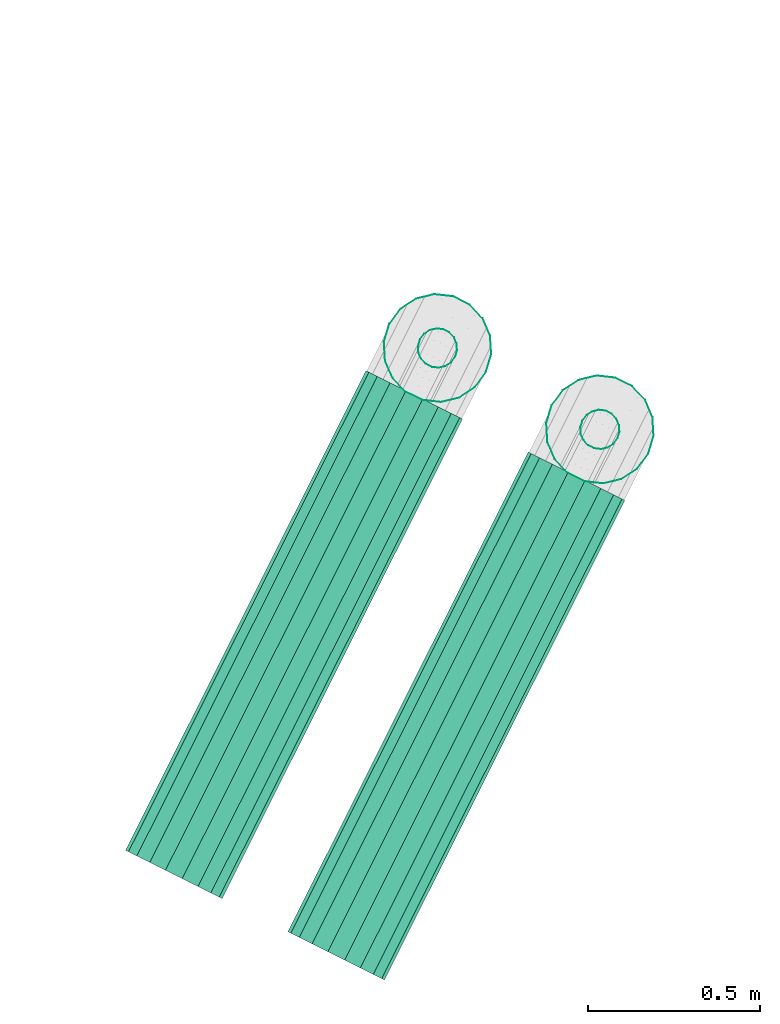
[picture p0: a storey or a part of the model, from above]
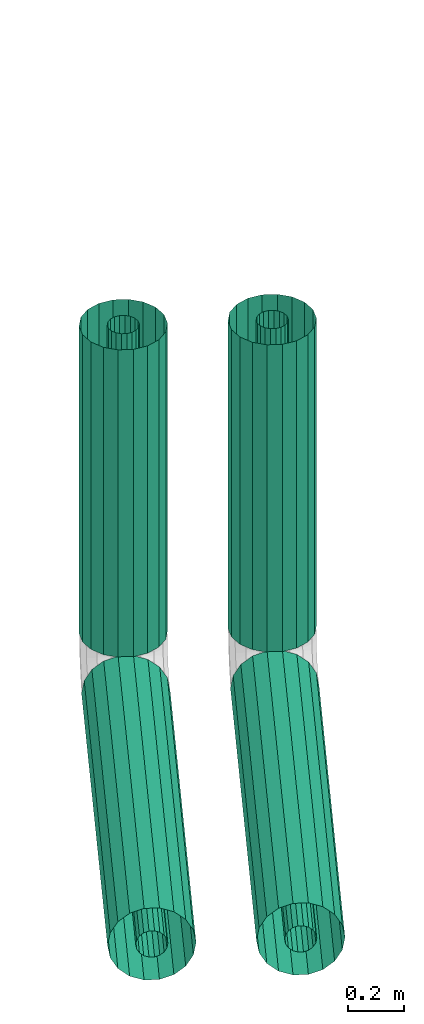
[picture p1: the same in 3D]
Properties of the parts of a building model (IFC2X3), part 10 of 23

# IfcFlowFitting: Flansch 357973:Flansch 357973, Flansch
IFC-Parameter - In IFC-Datei exportieren: Nach Typ; Pset MEP.Tech-PN: 16; Pset MEP.Geom-DN: 65; Pset MEP.Geom-Outer Ø (mm): 185; Pset MEP.Geom-Depth: 45; In IFC exportieren als: ifcflowfitting; NameOverride: Flansch; IfcPresentationLayer: S_Gas; ObjectTypeOverride: Flansch; Pset MEP.Name: Flansch; IfcDescription: Flansch; Pset MEP.Tech-Material: nach DIN 2627
Phasen - Phase erstellt: Phase 01

# IfcFlowFitting: Flansch 359647:Flansch 359647, Flansch
In: Erdgeschoss
Type - Material: IfcSurfaceStyle #352577
Type - Andere - Kategorie: Allgemeines Modell; Familienname: Flansch 359647
Type - ID-Daten - Typname: Flansch 359647
Type - IFC-Parameter - Typ in IFC-Datei exportieren: Vorgabe
Description: Flansch
Pset_DistributionFlowElementCommon - Reference: Flansch 359647; sets with these values: 2
Andere - Typ: Flansch 359647; Familie: Flansch 359647; Familie und Typ: Flansch 359647: Flansch 359647; Typ-ID: 2536898
Abhängigkeiten - Höhe von Ebene: 0 m; Verschieben mit umliegenden Elementen: no
Bemaßungen - Fläche: 0.0219883 m2; Volumen: 0.000503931 m3
IFC-Parameter - In IFC-Datei exportieren: Nach Typ; Pset MEP.Tech-PN: 16; Pset MEP.Geom-DN: 65; Pset MEP.Geom-Outer Ø (mm): 185; Pset MEP.Geom-Depth: 45; In IFC exportieren als: ifcflowfitting; NameOverride: Flansch; IfcPresentationLayer: S_Gas; ObjectTypeOverride: Flansch; Pset MEP.Name: Flansch; IfcDescription: Flansch; Pset MEP.Tech-Material: nach DIN 2627
Phasen - Phase erstellt: Phase 01

# IfcFlowFitting: Flansch 359670:Flansch 359670, Flansch
In: Erdgeschoss
Type - Material: IfcSurfaceStyle #352577
Type - Andere - Kategorie: Allgemeines Modell; Familienname: Flansch 359670
Type - ID-Daten - Typname: Flansch 359670
Type - IFC-Parameter - Typ in IFC-Datei exportieren: Vorgabe
Description: Flansch
Pset_DistributionFlowElementCommon - Reference: Flansch 359670; sets with these values: 2
Andere - Typ: Flansch 359670; Familie: Flansch 359670; Familie und Typ: Flansch 359670: Flansch 359670; Typ-ID: 2536905
Abhängigkeiten - Höhe von Ebene: 0 m; Verschieben mit umliegenden Elementen: no
Bemaßungen - Fläche: 0.0219883 m2; Volumen: 0.000503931 m3
IFC-Parameter - In IFC-Datei exportieren: Nach Typ; Pset MEP.Tech-PN: 16; Pset MEP.Geom-DN: 65; Pset MEP.Geom-Outer Ø (mm): 185; Pset MEP.Geom-Depth: 45; In IFC exportieren als: ifcflowfitting; NameOverride: Flansch; IfcPresentationLayer: S_Gas; ObjectTypeOverride: Flansch; Pset MEP.Name: Flansch; IfcDescription: Flansch; Pset MEP.Tech-Material: nach DIN 2627
Phasen - Phase erstellt: Phase 01

# IfcFlowFitting: Flansch 359693:Flansch 359693, Flansch
In: Erdgeschoss
Type - Material: IfcSurfaceStyle #352577
Type - Andere - Kategorie: Allgemeines Modell; Familienname: Flansch 359693
Type - ID-Daten - Typname: Flansch 359693
Type - IFC-Parameter - Typ in IFC-Datei exportieren: Vorgabe
Description: Flansch
Pset_DistributionFlowElementCommon - Reference: Flansch 359693; sets with these values: 2
Andere - Typ: Flansch 359693; Familie: Flansch 359693; Familie und Typ: Flansch 359693: Flansch 359693; Typ-ID: 2536912
Abhängigkeiten - Höhe von Ebene: 0 m; Verschieben mit umliegenden Elementen: no
Bemaßungen - Fläche: 0.0219883 m2; Volumen: 0.000293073 m3
IFC-Parameter - In IFC-Datei exportieren: Nach Typ; Pset MEP.Tech-PN: 16; Pset MEP.Geom-DN: 65; Pset MEP.Geom-Outer Ø (mm): 185; Pset MEP.Geom-Depth: 45; In IFC exportieren als: ifcflowfitting; NameOverride: Flansch; IfcPresentationLayer: S_Gas; ObjectTypeOverride: Flansch; Pset MEP.Name: Flansch; IfcDescription: Flansch; Pset MEP.Tech-Material: nach DIN 2627
Phasen - Phase erstellt: Phase 01

# IfcFlowFitting: Flansch 359720:Flansch 359720, Flansch
In: Erdgeschoss
Type - Material: IfcSurfaceStyle #352577
Type - Andere - Kategorie: Allgemeines Modell; Familienname: Flansch 359720
Type - ID-Daten - Typname: Flansch 359720
Type - IFC-Parameter - Typ in IFC-Datei exportieren: Vorgabe
Description: Flansch
Pset_DistributionFlowElementCommon - Reference: Flansch 359720; sets with these values: 2
Andere - Typ: Flansch 359720; Familie: Flansch 359720; Familie und Typ: Flansch 359720: Flansch 359720; Typ-ID: 2536919
Abhängigkeiten - Höhe von Ebene: 0 m; Verschieben mit umliegenden Elementen: no
Bemaßungen - Fläche: 0.0219883 m2; Volumen: 0.000503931 m3
IFC-Parameter - In IFC-Datei exportieren: Nach Typ; Pset MEP.Tech-PN: 16; Pset MEP.Geom-DN: 65; Pset MEP.Geom-Outer Ø (mm): 185; Pset MEP.Geom-Depth: 45; In IFC exportieren als: ifcflowfitting; NameOverride: Flansch; IfcPresentationLayer: S_Gas; ObjectTypeOverride: Flansch; Pset MEP.Name: Flansch; IfcDescription: Flansch; Pset MEP.Tech-Material: nach DIN 2627
Phasen - Phase erstellt: Phase 01

# IfcFlowFitting: Flansch 359743:Flansch 359743, Flansch
In: Erdgeschoss
Type - Material: IfcSurfaceStyle #352577
Type - Andere - Kategorie: Allgemeines Modell; Familienname: Flansch 359743
Type - ID-Daten - Typname: Flansch 359743
Type - IFC-Parameter - Typ in IFC-Datei exportieren: Vorgabe
Description: Flansch
Pset_DistributionFlowElementCommon - Reference: Flansch 359743; sets with these values: 2
Andere - Typ: Flansch 359743; Familie: Flansch 359743; Familie und Typ: Flansch 359743: Flansch 359743; Typ-ID: 2536926
Abhängigkeiten - Höhe von Ebene: 0 m; Verschieben mit umliegenden Elementen: no
Bemaßungen - Fläche: 0.0219883 m2; Volumen: 0.000293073 m3
IFC-Parameter - In IFC-Datei exportieren: Nach Typ; Pset MEP.Tech-PN: 16; Pset MEP.Geom-DN: 65; Pset MEP.Geom-Outer Ø (mm): 185; Pset MEP.Geom-Depth: 45; In IFC exportieren als: ifcflowfitting; NameOverride: Flansch; IfcPresentationLayer: S_Gas; ObjectTypeOverride: Flansch; Pset MEP.Name: Flansch; IfcDescription: Flansch; Pset MEP.Tech-Material: nach DIN 2627
Phasen - Phase erstellt: Phase 01

# IfcFlowFitting: Flansch 360782:Flansch 360782, Flansch
In: Erdgeschoss
Type - Material: IfcSurfaceStyle #352577
Type - Andere - Kategorie: Allgemeines Modell; Familienname: Flansch 360782
Type - ID-Daten - Typname: Flansch 360782
Type - IFC-Parameter - Typ in IFC-Datei exportieren: Vorgabe
Description: Flansch
Pset_DistributionFlowElementCommon - Reference: Flansch 360782; sets with these values: 2
Andere - Typ: Flansch 360782; Familie: Flansch 360782; Familie und Typ: Flansch 360782: Flansch 360782; Typ-ID: 2536947
Abhängigkeiten - Höhe von Ebene: 0 m; Verschieben mit umliegenden Elementen: no
Bemaßungen - Fläche: 0.0219883 m2; Volumen: 0.000503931 m3
IFC-Parameter - In IFC-Datei exportieren: Nach Typ; Pset MEP.Tech-PN: 16; Pset MEP.Geom-DN: 65; Pset MEP.Geom-Outer Ø (mm): 185; Pset MEP.Geom-Depth: 45; In IFC exportieren als: ifcflowfitting; NameOverride: Flansch; IfcPresentationLayer: S_Gas; ObjectTypeOverride: Flansch; Pset MEP.Name: Flansch; IfcDescription: Flansch; Pset MEP.Tech-Material: nach DIN 2627
Phasen - Phase erstellt: Phase 01

# IfcFlowFitting: Flansch 360828:Flansch 360828, Flansch
In: Erdgeschoss
Type - Material: IfcSurfaceStyle #352577
Type - Andere - Kategorie: Allgemeines Modell; Familienname: Flansch 360828
Type - ID-Daten - Typname: Flansch 360828
Type - IFC-Parameter - Typ in IFC-Datei exportieren: Vorgabe
Description: Flansch
Pset_DistributionFlowElementCommon - Reference: Flansch 360828; sets with these values: 2
Andere - Typ: Flansch 360828; Familie: Flansch 360828; Familie und Typ: Flansch 360828: Flansch 360828; Typ-ID: 2536961
Abhängigkeiten - Höhe von Ebene: 0 m; Verschieben mit umliegenden Elementen: no
Bemaßungen - Fläche: 0.0219883 m2; Volumen: 0.000293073 m3
IFC-Parameter - In IFC-Datei exportieren: Nach Typ; Pset MEP.Tech-PN: 16; Pset MEP.Geom-DN: 65; Pset MEP.Geom-Outer Ø (mm): 185; Pset MEP.Geom-Depth: 45; In IFC exportieren als: ifcflowfitting; NameOverride: Flansch; IfcPresentationLayer: S_Gas; ObjectTypeOverride: Flansch; Pset MEP.Name: Flansch; IfcDescription: Flansch; Pset MEP.Tech-Material: nach DIN 2627
Phasen - Phase erstellt: Phase 01

# IfcFlowFitting: Flansch 4825:Flansch 4825, Flansch
In: 1. Obergeschoss
Type - Material: IfcSurfaceStyle #1741
Type - Andere - Kategorie: Allgemeines Modell; Familienname: Flansch 4825
Type - ID-Daten - Typname: Flansch 4825
Type - IFC-Parameter - Typ in IFC-Datei exportieren: Vorgabe
Description: Flansch
Pset_DistributionFlowElementCommon - Reference: Flansch 4825; sets with these values: 2
Andere - Typ: Flansch 4825; Familie: Flansch 4825; Familie und Typ: Flansch 4825: Flansch 4825; Typ-ID: 2531373
Abhängigkeiten - Höhe von Ebene: 0 m; Verschieben mit umliegenden Elementen: no
Bemaßungen - Fläche: 0.144185 m2; Volumen: 0.0099386 m3
IFC-Parameter - In IFC-Datei exportieren: Nach Typ; Pset MEP.Geom-Depth: 62; Pset MEP.Geom-DN: 200; Pset MEP.Geom-Outer Ø (mm): 340; Pset MEP.Tech-Insulation thickness (mm): 100; Pset MEP.Tech-PN: 16; In IFC exportieren als: ifcflowfitting; NameOverride: Flansch; IfcPresentationLayer: 0-TFT-H_Ruecklauf; ObjectTypeOverride: Flansch; Pset MEP.Name: Flansch; IfcDescription: Flansch; Pset MEP.Tech-Material: nach DIN 2627
Phasen - Phase erstellt: Phase 01

# IfcFlowFitting: Flansch 5590:Flansch 5590, Flansch
In: 1. Obergeschoss
Type - Material: IfcSurfaceStyle #1741
Type - Andere - Kategorie: Allgemeines Modell; Familienname: Flansch 5590
Type - ID-Daten - Typname: Flansch 5590
Type - IFC-Parameter - Typ in IFC-Datei exportieren: Vorgabe
Description: Flansch
Pset_DistributionFlowElementCommon - Reference: Flansch 5590; sets with these values: 2
Andere - Typ: Flansch 5590; Familie: Flansch 5590; Familie und Typ: Flansch 5590: Flansch 5590; Typ-ID: 2531380
Abhängigkeiten - Höhe von Ebene: 0 m; Verschieben mit umliegenden Elementen: no
Bemaßungen - Fläche: 0.144185 m2; Volumen: 0.0118373 m3
IFC-Parameter - In IFC-Datei exportieren: Nach Typ; Pset MEP.Geom-Depth: 62; Pset MEP.Geom-DN: 200; Pset MEP.Geom-Outer Ø (mm): 340; Pset MEP.Tech-Insulation thickness (mm): 100; Pset MEP.Tech-PN: 16; In IFC exportieren als: ifcflowfitting; NameOverride: Flansch; IfcPresentationLayer: 0-TFT-H_Ruecklauf; ObjectTypeOverride: Flansch; Pset MEP.Name: Flansch; IfcDescription: Flansch; Pset MEP.Tech-Material: nach DIN 2627
Phasen - Phase erstellt: Phase 01

# IfcFlowFitting: Flansch 5663:Flansch 5663, Flansch
In: 1. Obergeschoss
Type - Material: IfcSurfaceStyle #1741
Type - Andere - Kategorie: Allgemeines Modell; Familienname: Flansch 5663
Type - ID-Daten - Typname: Flansch 5663
Type - IFC-Parameter - Typ in IFC-Datei exportieren: Vorgabe
Description: Flansch
Pset_DistributionFlowElementCommon - Reference: Flansch 5663; sets with these values: 2
Andere - Typ: Flansch 5663; Familie: Flansch 5663; Familie und Typ: Flansch 5663: Flansch 5663; Typ-ID: 2531401
Abhängigkeiten - Höhe von Ebene: 0 m; Verschieben mit umliegenden Elementen: no
Bemaßungen - Fläche: 0.144185 m2; Volumen: 0.0118373 m3
IFC-Parameter - In IFC-Datei exportieren: Nach Typ; Pset MEP.Geom-Depth: 62; Pset MEP.Geom-DN: 200; Pset MEP.Geom-Outer Ø (mm): 340; Pset MEP.Tech-Insulation thickness (mm): 100; Pset MEP.Tech-PN: 16; In IFC exportieren als: ifcflowfitting; NameOverride: Flansch; IfcPresentationLayer: 0-TFT-H_Ruecklauf; ObjectTypeOverride: Flansch; Pset MEP.Name: Flansch; IfcDescription: Flansch; Pset MEP.Tech-Material: nach DIN 2627
Phasen - Phase erstellt: Phase 01

# IfcFlowFitting: Flansch 5686:Flansch 5686, Flansch
In: 1. Obergeschoss
Type - Material: IfcSurfaceStyle #1741
Type - Andere - Kategorie: Allgemeines Modell; Familienname: Flansch 5686
Type - ID-Daten - Typname: Flansch 5686
Type - IFC-Parameter - Typ in IFC-Datei exportieren: Vorgabe
Description: Flansch
Pset_DistributionFlowElementCommon - Reference: Flansch 5686; sets with these values: 2
Andere - Typ: Flansch 5686; Familie: Flansch 5686; Familie und Typ: Flansch 5686: Flansch 5686; Typ-ID: 2531408
Abhängigkeiten - Höhe von Ebene: 0 m; Verschieben mit umliegenden Elementen: no
Bemaßungen - Fläche: 0.144185 m2; Volumen: 0.0118373 m3
IFC-Parameter - In IFC-Datei exportieren: Nach Typ; Pset MEP.Geom-Depth: 62; Pset MEP.Geom-DN: 200; Pset MEP.Geom-Outer Ø (mm): 340; Pset MEP.Tech-Insulation thickness (mm): 100; Pset MEP.Tech-PN: 16; In IFC exportieren als: ifcflowfitting; NameOverride: Flansch; IfcPresentationLayer: 0-TFT-H_Ruecklauf; ObjectTypeOverride: Flansch; Pset MEP.Name: Flansch; IfcDescription: Flansch; Pset MEP.Tech-Material: nach DIN 2627
Phasen - Phase erstellt: Phase 01

# IfcFlowFitting: Flansch 5742:Flansch 5742, Flansch
In: 1. Obergeschoss
Type - Material: IfcSurfaceStyle #1741
Type - Andere - Kategorie: Allgemeines Modell; Familienname: Flansch 5742
Type - ID-Daten - Typname: Flansch 5742
Type - IFC-Parameter - Typ in IFC-Datei exportieren: Vorgabe
Description: Flansch
Pset_DistributionFlowElementCommon - Reference: Flansch 5742; sets with these values: 2
Andere - Typ: Flansch 5742; Familie: Flansch 5742; Familie und Typ: Flansch 5742: Flansch 5742; Typ-ID: 2531422
Abhängigkeiten - Höhe von Ebene: 0 m; Verschieben mit umliegenden Elementen: no
Bemaßungen - Fläche: 0.144185 m2; Volumen: 0.0099386 m3
IFC-Parameter - In IFC-Datei exportieren: Nach Typ; Pset MEP.Geom-Depth: 62; Pset MEP.Geom-DN: 200; Pset MEP.Geom-Outer Ø (mm): 340; Pset MEP.Tech-Insulation thickness (mm): 100; Pset MEP.Tech-PN: 16; In IFC exportieren als: ifcflowfitting; NameOverride: Flansch; IfcPresentationLayer: 0-TFT-H_Ruecklauf; ObjectTypeOverride: Flansch; Pset MEP.Name: Flansch; IfcDescription: Flansch; Pset MEP.Tech-Material: nach DIN 2627
Phasen - Phase erstellt: Phase 01

# IfcFlowFitting: Flansch 5771:Flansch 5771, Flansch
In: 1. Obergeschoss
Type - Material: IfcSurfaceStyle #1741
Type - Andere - Kategorie: Allgemeines Modell; Familienname: Flansch 5771
Type - ID-Daten - Typname: Flansch 5771
Type - IFC-Parameter - Typ in IFC-Datei exportieren: Vorgabe
Description: Flansch
Pset_DistributionFlowElementCommon - Reference: Flansch 5771; sets with these values: 2
Andere - Typ: Flansch 5771; Familie: Flansch 5771; Familie und Typ: Flansch 5771: Flansch 5771; Typ-ID: 2531429
Abhängigkeiten - Höhe von Ebene: 0 m; Verschieben mit umliegenden Elementen: no
Bemaßungen - Fläche: 0.144185 m2; Volumen: 0.0099386 m3
IFC-Parameter - In IFC-Datei exportieren: Nach Typ; Pset MEP.Geom-Depth: 62; Pset MEP.Geom-DN: 200; Pset MEP.Geom-Outer Ø (mm): 340; Pset MEP.Tech-Insulation thickness (mm): 100; Pset MEP.Tech-PN: 16; In IFC exportieren als: ifcflowfitting; NameOverride: Flansch; IfcPresentationLayer: 0-TFT-H_Ruecklauf; ObjectTypeOverride: Flansch; Pset MEP.Name: Flansch; IfcDescription: Flansch; Pset MEP.Tech-Material: nach DIN 2627
Phasen - Phase erstellt: Phase 01

# IfcFlowFitting: Flansch 603006:Flansch 603006, Flansch
In: Erdgeschoss
Type - Material: IfcSurfaceStyle #352577
Type - Andere - Kategorie: Allgemeines Modell; Familienname: Flansch 603006
Type - ID-Daten - Typname: Flansch 603006
Type - IFC-Parameter - Typ in IFC-Datei exportieren: Vorgabe
Description: Flansch
Pset_DistributionFlowElementCommon - Reference: Flansch 603006; sets with these values: 2
Andere - Typ: Flansch 603006; Familie: Flansch 603006; Familie und Typ: Flansch 603006: Flansch 603006; Typ-ID: 2537003
Abhängigkeiten - Höhe von Ebene: 0 m; Verschieben mit umliegenden Elementen: no
Bemaßungen - Fläche: 0.0219883 m2; Volumen: 0.000503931 m3
IFC-Parameter - In IFC-Datei exportieren: Nach Typ; Pset MEP.Tech-PN: 16; Pset MEP.Geom-DN: 65; Pset MEP.Geom-Outer Ø (mm): 185; Pset MEP.Geom-Depth: 45; In IFC exportieren als: ifcflowfitting; NameOverride: Flansch; IfcPresentationLayer: S_Gas; ObjectTypeOverride: Flansch; Pset MEP.Name: Flansch; IfcDescription: Flansch; Pset MEP.Tech-Material: nach DIN 2627
Phasen - Phase erstellt: Phase 01

# IfcFlowFitting: Flansch 603027:Flansch 603027, Flansch
In: Erdgeschoss
Type - Material: IfcSurfaceStyle #352577
Type - Andere - Kategorie: Allgemeines Modell; Familienname: Flansch 603027
Type - ID-Daten - Typname: Flansch 603027
Type - IFC-Parameter - Typ in IFC-Datei exportieren: Vorgabe
Description: Flansch
Pset_DistributionFlowElementCommon - Reference: Flansch 603027; sets with these values: 2
Andere - Typ: Flansch 603027; Familie: Flansch 603027; Familie und Typ: Flansch 603027: Flansch 603027; Typ-ID: 2537010
Abhängigkeiten - Höhe von Ebene: 0 m; Verschieben mit umliegenden Elementen: no
Bemaßungen - Fläche: 0.0219883 m2; Volumen: 0.000503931 m3
IFC-Parameter - In IFC-Datei exportieren: Nach Typ; Pset MEP.Tech-PN: 16; Pset MEP.Geom-DN: 65; Pset MEP.Geom-Outer Ø (mm): 185; Pset MEP.Geom-Depth: 45; In IFC exportieren als: ifcflowfitting; NameOverride: Flansch; IfcPresentationLayer: S_Gas; ObjectTypeOverride: Flansch; Pset MEP.Name: Flansch; IfcDescription: Flansch; Pset MEP.Tech-Material: nach DIN 2627
Phasen - Phase erstellt: Phase 01

# IfcFlowFitting: Flansch 603050:Flansch 603050, Flansch
In: Erdgeschoss
Type - Material: IfcSurfaceStyle #352577
Type - Andere - Kategorie: Allgemeines Modell; Familienname: Flansch 603050
Type - ID-Daten - Typname: Flansch 603050
Type - IFC-Parameter - Typ in IFC-Datei exportieren: Vorgabe
Description: Flansch
Pset_DistributionFlowElementCommon - Reference: Flansch 603050; sets with these values: 2
Andere - Typ: Flansch 603050; Familie: Flansch 603050; Familie und Typ: Flansch 603050: Flansch 603050; Typ-ID: 2537017
Abhängigkeiten - Höhe von Ebene: 0 m; Verschieben mit umliegenden Elementen: no
Bemaßungen - Fläche: 0.0219883 m2; Volumen: 0.000293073 m3
IFC-Parameter - In IFC-Datei exportieren: Nach Typ; Pset MEP.Tech-PN: 16; Pset MEP.Geom-DN: 65; Pset MEP.Geom-Outer Ø (mm): 185; Pset MEP.Geom-Depth: 45; In IFC exportieren als: ifcflowfitting; NameOverride: Flansch; IfcPresentationLayer: S_Gas; ObjectTypeOverride: Flansch; Pset MEP.Name: Flansch; IfcDescription: Flansch; Pset MEP.Tech-Material: nach DIN 2627
Phasen - Phase erstellt: Phase 01

# IfcFlowFitting: Flansch 603073:Flansch 603073, Flansch
In: Erdgeschoss
Type - Material: IfcSurfaceStyle #352577
Type - Andere - Kategorie: Allgemeines Modell; Familienname: Flansch 603073
Type - ID-Daten - Typname: Flansch 603073
Type - IFC-Parameter - Typ in IFC-Datei exportieren: Vorgabe
Description: Flansch
Pset_DistributionFlowElementCommon - Reference: Flansch 603073; sets with these values: 2
Andere - Typ: Flansch 603073; Familie: Flansch 603073; Familie und Typ: Flansch 603073: Flansch 603073; Typ-ID: 2537024
Abhängigkeiten - Höhe von Ebene: 0 m; Verschieben mit umliegenden Elementen: no
Bemaßungen - Fläche: 0.0219883 m2; Volumen: 0.000293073 m3
IFC-Parameter - In IFC-Datei exportieren: Nach Typ; Pset MEP.Tech-PN: 16; Pset MEP.Geom-DN: 65; Pset MEP.Geom-Outer Ø (mm): 185; Pset MEP.Geom-Depth: 45; In IFC exportieren als: ifcflowfitting; NameOverride: Flansch; IfcPresentationLayer: S_Gas; ObjectTypeOverride: Flansch; Pset MEP.Name: Flansch; IfcDescription: Flansch; Pset MEP.Tech-Material: nach DIN 2627
Phasen - Phase erstellt: Phase 01

# IfcFlowFitting: Flansch 604088:Flansch 604088, Flansch
In: Erdgeschoss
Type - Material: IfcSurfaceStyle #352577
Type - Andere - Kategorie: Allgemeines Modell; Familienname: Flansch 604088
Type - ID-Daten - Typname: Flansch 604088
Type - IFC-Parameter - Typ in IFC-Datei exportieren: Vorgabe
Description: Flansch
Pset_DistributionFlowElementCommon - Reference: Flansch 604088; sets with these values: 2
Andere - Typ: Flansch 604088; Familie: Flansch 604088; Familie und Typ: Flansch 604088: Flansch 604088; Typ-ID: 2537038
Abhängigkeiten - Höhe von Ebene: 0 m; Verschieben mit umliegenden Elementen: no
Bemaßungen - Fläche: 0.0219883 m2; Volumen: 0.000503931 m3
IFC-Parameter - In IFC-Datei exportieren: Nach Typ; Pset MEP.Tech-PN: 16; Pset MEP.Geom-DN: 65; Pset MEP.Geom-Outer Ø (mm): 185; Pset MEP.Geom-Depth: 45; In IFC exportieren als: ifcflowfitting; NameOverride: Flansch; IfcPresentationLayer: S_Gas; ObjectTypeOverride: Flansch; Pset MEP.Name: Flansch; IfcDescription: Flansch; Pset MEP.Tech-Material: nach DIN 2627
Phasen - Phase erstellt: Phase 01

# IfcFlowFitting: Flansch 604109:Flansch 604109, Flansch
In: Erdgeschoss
Type - Material: IfcSurfaceStyle #352577
Type - Andere - Kategorie: Allgemeines Modell; Familienname: Flansch 604109
Type - ID-Daten - Typname: Flansch 604109
Type - IFC-Parameter - Typ in IFC-Datei exportieren: Vorgabe
Description: Flansch
Pset_DistributionFlowElementCommon - Reference: Flansch 604109; sets with these values: 2
Andere - Typ: Flansch 604109; Familie: Flansch 604109; Familie und Typ: Flansch 604109: Flansch 604109; Typ-ID: 2537045
Abhängigkeiten - Höhe von Ebene: 0 m; Verschieben mit umliegenden Elementen: no
Bemaßungen - Fläche: 0.0219883 m2; Volumen: 0.000293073 m3
IFC-Parameter - In IFC-Datei exportieren: Nach Typ; Pset MEP.Tech-PN: 16; Pset MEP.Geom-DN: 65; Pset MEP.Geom-Outer Ø (mm): 185; Pset MEP.Geom-Depth: 45; In IFC exportieren als: ifcflowfitting; NameOverride: Flansch; IfcPresentationLayer: S_Gas; ObjectTypeOverride: Flansch; Pset MEP.Name: Flansch; IfcDescription: Flansch; Pset MEP.Tech-Material: nach DIN 2627
Phasen - Phase erstellt: Phase 01

# IfcFlowFitting: Flansch 604132:Flansch 604132, Flansch
In: Erdgeschoss
Type - Material: IfcSurfaceStyle #352577
Type - Andere - Kategorie: Allgemeines Modell; Familienname: Flansch 604132
Type - ID-Daten - Typname: Flansch 604132
Type - IFC-Parameter - Typ in IFC-Datei exportieren: Vorgabe
Description: Flansch
Pset_DistributionFlowElementCommon - Reference: Flansch 604132; sets with these values: 2
Andere - Typ: Flansch 604132; Familie: Flansch 604132; Familie und Typ: Flansch 604132: Flansch 604132; Typ-ID: 2537052
Abhängigkeiten - Höhe von Ebene: 0 m; Verschieben mit umliegenden Elementen: no
Bemaßungen - Fläche: 0.0219883 m2; Volumen: 0.000293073 m3
IFC-Parameter - In IFC-Datei exportieren: Nach Typ; Pset MEP.Tech-PN: 16; Pset MEP.Geom-DN: 65; Pset MEP.Geom-Outer Ø (mm): 185; Pset MEP.Geom-Depth: 45; In IFC exportieren als: ifcflowfitting; NameOverride: Flansch; IfcPresentationLayer: S_Gas; ObjectTypeOverride: Flansch; Pset MEP.Name: Flansch; IfcDescription: Flansch; Pset MEP.Tech-Material: nach DIN 2627
Phasen - Phase erstellt: Phase 01

# IfcFlowFitting: Flansch 604159:Flansch 604159, Flansch
In: Erdgeschoss
Type - Material: IfcSurfaceStyle #352577
Type - Andere - Kategorie: Allgemeines Modell; Familienname: Flansch 604159
Type - ID-Daten - Typname: Flansch 604159
Type - IFC-Parameter - Typ in IFC-Datei exportieren: Vorgabe
Description: Flansch
Pset_DistributionFlowElementCommon - Reference: Flansch 604159; sets with these values: 2
Andere - Typ: Flansch 604159; Familie: Flansch 604159; Familie und Typ: Flansch 604159: Flansch 604159; Typ-ID: 2537059
Abhängigkeiten - Höhe von Ebene: 0 m; Verschieben mit umliegenden Elementen: no
Bemaßungen - Fläche: 0.0219883 m2; Volumen: 0.000503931 m3
IFC-Parameter - In IFC-Datei exportieren: Nach Typ; Pset MEP.Tech-PN: 16; Pset MEP.Geom-DN: 65; Pset MEP.Geom-Outer Ø (mm): 185; Pset MEP.Geom-Depth: 45; In IFC exportieren als: ifcflowfitting; NameOverride: Flansch; IfcPresentationLayer: S_Gas; ObjectTypeOverride: Flansch; Pset MEP.Name: Flansch; IfcDescription: Flansch; Pset MEP.Tech-Material: nach DIN 2627
Phasen - Phase erstellt: Phase 01

# IfcFlowFitting: Flansch 604180:Flansch 604180, Flansch
In: Erdgeschoss
Type - Material: IfcSurfaceStyle #352577
Type - Andere - Kategorie: Allgemeines Modell; Familienname: Flansch 604180
Type - ID-Daten - Typname: Flansch 604180
Type - IFC-Parameter - Typ in IFC-Datei exportieren: Vorgabe
Description: Flansch
Pset_DistributionFlowElementCommon - Reference: Flansch 604180; sets with these values: 2
Andere - Typ: Flansch 604180; Familie: Flansch 604180; Familie und Typ: Flansch 604180: Flansch 604180; Typ-ID: 2537066
Abhängigkeiten - Höhe von Ebene: 0 m; Verschieben mit umliegenden Elementen: no
Bemaßungen - Fläche: 0.0219883 m2; Volumen: 0.000503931 m3
IFC-Parameter - In IFC-Datei exportieren: Nach Typ; Pset MEP.Tech-PN: 16; Pset MEP.Geom-DN: 65; Pset MEP.Geom-Outer Ø (mm): 185; Pset MEP.Geom-Depth: 45; In IFC exportieren als: ifcflowfitting; NameOverride: Flansch; IfcPresentationLayer: S_Gas; ObjectTypeOverride: Flansch; Pset MEP.Name: Flansch; IfcDescription: Flansch; Pset MEP.Tech-Material: nach DIN 2627
Phasen - Phase erstellt: Phase 01

# IfcFlowFitting: Flansch 604293:Flansch 604293, Flansch
In: Erdgeschoss
Type - Material: IfcSurfaceStyle #352577
Type - Andere - Kategorie: Allgemeines Modell; Familienname: Flansch 604293
Type - ID-Daten - Typname: Flansch 604293
Type - IFC-Parameter - Typ in IFC-Datei exportieren: Vorgabe
Description: Flansch
Pset_DistributionFlowElementCommon - Reference: Flansch 604293; sets with these values: 2
Andere - Typ: Flansch 604293; Familie: Flansch 604293; Familie und Typ: Flansch 604293: Flansch 604293; Typ-ID: 2537101
Abhängigkeiten - Höhe von Ebene: 0 m; Verschieben mit umliegenden Elementen: no
Bemaßungen - Fläche: 0.0219883 m2; Volumen: 0.000293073 m3
IFC-Parameter - In IFC-Datei exportieren: Nach Typ; Pset MEP.Tech-PN: 16; Pset MEP.Geom-DN: 65; Pset MEP.Geom-Outer Ø (mm): 185; Pset MEP.Geom-Depth: 45; In IFC exportieren als: ifcflowfitting; NameOverride: Flansch; IfcPresentationLayer: S_Gas; ObjectTypeOverride: Flansch; Pset MEP.Name: Flansch; IfcDescription: Flansch; Pset MEP.Tech-Material: nach DIN 2627
Phasen - Phase erstellt: Phase 01

# IfcFlowFitting: Flansch 604362:Flansch 604362, Flansch
In: Erdgeschoss
Type - Material: IfcSurfaceStyle #352577
Type - Andere - Kategorie: Allgemeines Modell; Familienname: Flansch 604362
Type - ID-Daten - Typname: Flansch 604362
Type - IFC-Parameter - Typ in IFC-Datei exportieren: Vorgabe
Description: Flansch
Pset_DistributionFlowElementCommon - Reference: Flansch 604362; sets with these values: 2
Andere - Typ: Flansch 604362; Familie: Flansch 604362; Familie und Typ: Flansch 604362: Flansch 604362; Typ-ID: 2537122
Abhängigkeiten - Höhe von Ebene: 0 m; Verschieben mit umliegenden Elementen: no
Bemaßungen - Fläche: 0.0219883 m2; Volumen: 0.000503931 m3
IFC-Parameter - In IFC-Datei exportieren: Nach Typ; Pset MEP.Tech-PN: 16; Pset MEP.Geom-DN: 65; Pset MEP.Geom-Outer Ø (mm): 185; Pset MEP.Geom-Depth: 45; In IFC exportieren als: ifcflowfitting; NameOverride: Flansch; IfcPresentationLayer: S_Gas; ObjectTypeOverride: Flansch; Pset MEP.Name: Flansch; IfcDescription: Flansch; Pset MEP.Tech-Material: nach DIN 2627
Phasen - Phase erstellt: Phase 01

# IfcFlowFitting: Flansch 604385:Flansch 604385, Flansch
In: Erdgeschoss
Type - Material: IfcSurfaceStyle #352577
Type - Andere - Kategorie: Allgemeines Modell; Familienname: Flansch 604385
Type - ID-Daten - Typname: Flansch 604385
Type - IFC-Parameter - Typ in IFC-Datei exportieren: Vorgabe
Description: Flansch
Pset_DistributionFlowElementCommon - Reference: Flansch 604385; sets with these values: 2
Andere - Typ: Flansch 604385; Familie: Flansch 604385; Familie und Typ: Flansch 604385: Flansch 604385; Typ-ID: 2537129
Abhängigkeiten - Höhe von Ebene: 0 m; Verschieben mit umliegenden Elementen: no
Bemaßungen - Fläche: 0.0219883 m2; Volumen: 0.000293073 m3
IFC-Parameter - In IFC-Datei exportieren: Nach Typ; Pset MEP.Tech-PN: 16; Pset MEP.Geom-DN: 65; Pset MEP.Geom-Outer Ø (mm): 185; Pset MEP.Geom-Depth: 45; In IFC exportieren als: ifcflowfitting; NameOverride: Flansch; IfcPresentationLayer: S_Gas; ObjectTypeOverride: Flansch; Pset MEP.Name: Flansch; IfcDescription: Flansch; Pset MEP.Tech-Material: nach DIN 2627
Phasen - Phase erstellt: Phase 01

# IfcFlowFitting: Flansch 604408:Flansch 604408, Flansch
In: Erdgeschoss
Type - Material: IfcSurfaceStyle #352577
Type - Andere - Kategorie: Allgemeines Modell; Familienname: Flansch 604408
Type - ID-Daten - Typname: Flansch 604408
Type - IFC-Parameter - Typ in IFC-Datei exportieren: Vorgabe
Description: Flansch
Pset_DistributionFlowElementCommon - Reference: Flansch 604408; sets with these values: 2
Andere - Typ: Flansch 604408; Familie: Flansch 604408; Familie und Typ: Flansch 604408: Flansch 604408; Typ-ID: 2537136
Abhängigkeiten - Höhe von Ebene: 0 m; Verschieben mit umliegenden Elementen: no
Bemaßungen - Fläche: 0.0219883 m2; Volumen: 0.000293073 m3
IFC-Parameter - In IFC-Datei exportieren: Nach Typ; Pset MEP.Tech-PN: 16; Pset MEP.Geom-DN: 65; Pset MEP.Geom-Outer Ø (mm): 185; Pset MEP.Geom-Depth: 45; In IFC exportieren als: ifcflowfitting; NameOverride: Flansch; IfcPresentationLayer: S_Gas; ObjectTypeOverride: Flansch; Pset MEP.Name: Flansch; IfcDescription: Flansch; Pset MEP.Tech-Material: nach DIN 2627
Phasen - Phase erstellt: Phase 01

# IfcFlowFitting: Flansch 604477:Flansch 604477, Flansch
In: Erdgeschoss
Type - Material: IfcSurfaceStyle #352577
Type - Andere - Kategorie: Allgemeines Modell; Familienname: Flansch 604477
Type - ID-Daten - Typname: Flansch 604477
Type - IFC-Parameter - Typ in IFC-Datei exportieren: Vorgabe
Description: Flansch
Pset_DistributionFlowElementCommon - Reference: Flansch 604477; sets with these values: 2
Andere - Typ: Flansch 604477; Familie: Flansch 604477; Familie und Typ: Flansch 604477: Flansch 604477; Typ-ID: 2537157
Abhängigkeiten - Höhe von Ebene: 0 m; Verschieben mit umliegenden Elementen: no
Bemaßungen - Fläche: 0.0219883 m2; Volumen: 0.000503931 m3
IFC-Parameter - In IFC-Datei exportieren: Nach Typ; Pset MEP.Tech-PN: 16; Pset MEP.Geom-DN: 65; Pset MEP.Geom-Outer Ø (mm): 185; Pset MEP.Geom-Depth: 45; In IFC exportieren als: ifcflowfitting; NameOverride: Flansch; IfcPresentationLayer: S_Gas; ObjectTypeOverride: Flansch; Pset MEP.Name: Flansch; IfcDescription: Flansch; Pset MEP.Tech-Material: nach DIN 2627
Phasen - Phase erstellt: Phase 01

# IfcFlowFitting: Flansch 604546:Flansch 604546, Flansch
In: Erdgeschoss
Type - Material: IfcSurfaceStyle #352577
Type - Andere - Kategorie: Allgemeines Modell; Familienname: Flansch 604546
Type - ID-Daten - Typname: Flansch 604546
Type - IFC-Parameter - Typ in IFC-Datei exportieren: Vorgabe
Description: Flansch
Pset_DistributionFlowElementCommon - Reference: Flansch 604546; sets with these values: 2
Andere - Typ: Flansch 604546; Familie: Flansch 604546; Familie und Typ: Flansch 604546: Flansch 604546; Typ-ID: 2537178
Abhängigkeiten - Höhe von Ebene: 0 m; Verschieben mit umliegenden Elementen: no
Bemaßungen - Fläche: 0.0219883 m2; Volumen: 0.000503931 m3
IFC-Parameter - In IFC-Datei exportieren: Nach Typ; Pset MEP.Tech-PN: 16; Pset MEP.Geom-DN: 65; Pset MEP.Geom-Outer Ø (mm): 185; Pset MEP.Geom-Depth: 45; In IFC exportieren als: ifcflowfitting; NameOverride: Flansch; IfcPresentationLayer: S_Gas; ObjectTypeOverride: Flansch; Pset MEP.Name: Flansch; IfcDescription: Flansch; Pset MEP.Tech-Material: nach DIN 2627
Phasen - Phase erstellt: Phase 01

# IfcFlowFitting: Flansch 604569:Flansch 604569, Flansch
In: Erdgeschoss
Type - Material: IfcSurfaceStyle #352577
Type - Andere - Kategorie: Allgemeines Modell; Familienname: Flansch 604569
Type - ID-Daten - Typname: Flansch 604569
Type - IFC-Parameter - Typ in IFC-Datei exportieren: Vorgabe
Description: Flansch
Pset_DistributionFlowElementCommon - Reference: Flansch 604569; sets with these values: 2
Andere - Typ: Flansch 604569; Familie: Flansch 604569; Familie und Typ: Flansch 604569: Flansch 604569; Typ-ID: 2537185
Abhängigkeiten - Höhe von Ebene: 0 m; Verschieben mit umliegenden Elementen: no
Bemaßungen - Fläche: 0.0219883 m2; Volumen: 0.000293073 m3
IFC-Parameter - In IFC-Datei exportieren: Nach Typ; Pset MEP.Tech-PN: 16; Pset MEP.Geom-DN: 65; Pset MEP.Geom-Outer Ø (mm): 185; Pset MEP.Geom-Depth: 45; In IFC exportieren als: ifcflowfitting; NameOverride: Flansch; IfcPresentationLayer: S_Gas; ObjectTypeOverride: Flansch; Pset MEP.Name: Flansch; IfcDescription: Flansch; Pset MEP.Tech-Material: nach DIN 2627
Phasen - Phase erstellt: Phase 01

# IfcFlowFitting: Flansch 604592:Flansch 604592, Flansch
In: Erdgeschoss
Type - Material: IfcSurfaceStyle #352577
Type - Andere - Kategorie: Allgemeines Modell; Familienname: Flansch 604592
Type - ID-Daten - Typname: Flansch 604592
Type - IFC-Parameter - Typ in IFC-Datei exportieren: Vorgabe
Description: Flansch
Pset_DistributionFlowElementCommon - Reference: Flansch 604592; sets with these values: 2
Andere - Typ: Flansch 604592; Familie: Flansch 604592; Familie und Typ: Flansch 604592: Flansch 604592; Typ-ID: 2537192
Abhängigkeiten - Höhe von Ebene: 0 m; Verschieben mit umliegenden Elementen: no
Bemaßungen - Fläche: 0.0219883 m2; Volumen: 0.000293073 m3
IFC-Parameter - In IFC-Datei exportieren: Nach Typ; Pset MEP.Tech-PN: 16; Pset MEP.Geom-DN: 65; Pset MEP.Geom-Outer Ø (mm): 185; Pset MEP.Geom-Depth: 45; In IFC exportieren als: ifcflowfitting; NameOverride: Flansch; IfcPresentationLayer: S_Gas; ObjectTypeOverride: Flansch; Pset MEP.Name: Flansch; IfcDescription: Flansch; Pset MEP.Tech-Material: nach DIN 2627
Phasen - Phase erstellt: Phase 01

# IfcFlowFitting: Flansch 604615:Flansch 604615, Flansch
In: Erdgeschoss
Type - Material: IfcSurfaceStyle #352577
Type - Andere - Kategorie: Allgemeines Modell; Familienname: Flansch 604615
Type - ID-Daten - Typname: Flansch 604615
Type - IFC-Parameter - Typ in IFC-Datei exportieren: Vorgabe
Description: Flansch
Pset_DistributionFlowElementCommon - Reference: Flansch 604615; sets with these values: 2
Andere - Typ: Flansch 604615; Familie: Flansch 604615; Familie und Typ: Flansch 604615: Flansch 604615; Typ-ID: 2537199
Abhängigkeiten - Höhe von Ebene: 0 m; Verschieben mit umliegenden Elementen: no
Bemaßungen - Fläche: 0.0219883 m2; Volumen: 0.000503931 m3
IFC-Parameter - In IFC-Datei exportieren: Nach Typ; Pset MEP.Tech-PN: 16; Pset MEP.Geom-DN: 65; Pset MEP.Geom-Outer Ø (mm): 185; Pset MEP.Geom-Depth: 45; In IFC exportieren als: ifcflowfitting; NameOverride: Flansch; IfcPresentationLayer: S_Gas; ObjectTypeOverride: Flansch; Pset MEP.Name: Flansch; IfcDescription: Flansch; Pset MEP.Tech-Material: nach DIN 2627
Phasen - Phase erstellt: Phase 01

# IfcFlowFitting: Flansch 604638:Flansch 604638, Flansch
In: Erdgeschoss
Type - Material: IfcSurfaceStyle #352577
Type - Andere - Kategorie: Allgemeines Modell; Familienname: Flansch 604638
Type - ID-Daten - Typname: Flansch 604638
Type - IFC-Parameter - Typ in IFC-Datei exportieren: Vorgabe
Description: Flansch
Pset_DistributionFlowElementCommon - Reference: Flansch 604638; sets with these values: 2
Andere - Typ: Flansch 604638; Familie: Flansch 604638; Familie und Typ: Flansch 604638: Flansch 604638; Typ-ID: 2537206
Abhängigkeiten - Höhe von Ebene: 0 m; Verschieben mit umliegenden Elementen: no
Bemaßungen - Fläche: 0.0219883 m2; Volumen: 0.000293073 m3
IFC-Parameter - In IFC-Datei exportieren: Nach Typ; Pset MEP.Tech-PN: 16; Pset MEP.Geom-DN: 65; Pset MEP.Geom-Outer Ø (mm): 185; Pset MEP.Geom-Depth: 45; In IFC exportieren als: ifcflowfitting; NameOverride: Flansch; IfcPresentationLayer: S_Gas; ObjectTypeOverride: Flansch; Pset MEP.Name: Flansch; IfcDescription: Flansch; Pset MEP.Tech-Material: nach DIN 2627
Phasen - Phase erstellt: Phase 01

# IfcFlowFitting: Flansch 604730:Flansch 604730, Flansch
In: Erdgeschoss
Type - Material: IfcSurfaceStyle #352577
Type - Andere - Kategorie: Allgemeines Modell; Familienname: Flansch 604730
Type - ID-Daten - Typname: Flansch 604730
Type - IFC-Parameter - Typ in IFC-Datei exportieren: Vorgabe
Description: Flansch
Pset_DistributionFlowElementCommon - Reference: Flansch 604730; sets with these values: 2
Andere - Typ: Flansch 604730; Familie: Flansch 604730; Familie und Typ: Flansch 604730: Flansch 604730; Typ-ID: 2537234
Abhängigkeiten - Höhe von Ebene: 0 m; Verschieben mit umliegenden Elementen: no
Bemaßungen - Fläche: 0.0219883 m2; Volumen: 0.000503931 m3
IFC-Parameter - In IFC-Datei exportieren: Nach Typ; Pset MEP.Tech-PN: 16; Pset MEP.Geom-DN: 65; Pset MEP.Geom-Outer Ø (mm): 185; Pset MEP.Geom-Depth: 45; In IFC exportieren als: ifcflowfitting; NameOverride: Flansch; IfcPresentationLayer: S_Gas; ObjectTypeOverride: Flansch; Pset MEP.Name: Flansch; IfcDescription: Flansch; Pset MEP.Tech-Material: nach DIN 2627
Phasen - Phase erstellt: Phase 01

# IfcFlowFitting: Flansch 604820:Flansch 604820, Flansch
In: Erdgeschoss
Type - Material: IfcSurfaceStyle #352577
Type - Andere - Kategorie: Allgemeines Modell; Familienname: Flansch 604820
Type - ID-Daten - Typname: Flansch 604820
Type - IFC-Parameter - Typ in IFC-Datei exportieren: Vorgabe
Description: Flansch
Pset_DistributionFlowElementCommon - Reference: Flansch 604820; sets with these values: 2
Andere - Typ: Flansch 604820; Familie: Flansch 604820; Familie und Typ: Flansch 604820: Flansch 604820; Typ-ID: 2537262
Abhängigkeiten - Höhe von Ebene: 0 m; Verschieben mit umliegenden Elementen: no
Bemaßungen - Fläche: 0.0219883 m2; Volumen: 0.000293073 m3
IFC-Parameter - In IFC-Datei exportieren: Nach Typ; Pset MEP.Tech-PN: 16; Pset MEP.Geom-DN: 65; Pset MEP.Geom-Outer Ø (mm): 185; Pset MEP.Geom-Depth: 45; In IFC exportieren als: ifcflowfitting; NameOverride: Flansch; IfcPresentationLayer: S_Gas; ObjectTypeOverride: Flansch; Pset MEP.Name: Flansch; IfcDescription: Flansch; Pset MEP.Tech-Material: nach DIN 2627
Phasen - Phase erstellt: Phase 01

# IfcFlowFitting: Flansch 604843:Flansch 604843, Flansch
In: Erdgeschoss
Type - Material: IfcSurfaceStyle #352577
Type - Andere - Kategorie: Allgemeines Modell; Familienname: Flansch 604843
Type - ID-Daten - Typname: Flansch 604843
Type - IFC-Parameter - Typ in IFC-Datei exportieren: Vorgabe
Description: Flansch
Pset_DistributionFlowElementCommon - Reference: Flansch 604843; sets with these values: 2
Andere - Typ: Flansch 604843; Familie: Flansch 604843; Familie und Typ: Flansch 604843: Flansch 604843; Typ-ID: 2537269
Abhängigkeiten - Höhe von Ebene: 0 m; Verschieben mit umliegenden Elementen: no
Bemaßungen - Fläche: 0.0219883 m2; Volumen: 0.000503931 m3
IFC-Parameter - In IFC-Datei exportieren: Nach Typ; Pset MEP.Tech-PN: 16; Pset MEP.Geom-DN: 65; Pset MEP.Geom-Outer Ø (mm): 185; Pset MEP.Geom-Depth: 45; In IFC exportieren als: ifcflowfitting; NameOverride: Flansch; IfcPresentationLayer: S_Gas; ObjectTypeOverride: Flansch; Pset MEP.Name: Flansch; IfcDescription: Flansch; Pset MEP.Tech-Material: nach DIN 2627
Phasen - Phase erstellt: Phase 01

# IfcFlowFitting: Flansch 604864:Flansch 604864, Flansch
In: Erdgeschoss
Type - Material: IfcSurfaceStyle #352577
Type - Andere - Kategorie: Allgemeines Modell; Familienname: Flansch 604864
Type - ID-Daten - Typname: Flansch 604864
Type - IFC-Parameter - Typ in IFC-Datei exportieren: Vorgabe
Description: Flansch
Pset_DistributionFlowElementCommon - Reference: Flansch 604864; sets with these values: 2
Andere - Typ: Flansch 604864; Familie: Flansch 604864; Familie und Typ: Flansch 604864: Flansch 604864; Typ-ID: 2537276
Abhängigkeiten - Höhe von Ebene: 0 m; Verschieben mit umliegenden Elementen: no
Bemaßungen - Fläche: 0.0219883 m2; Volumen: 0.000503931 m3
IFC-Parameter - In IFC-Datei exportieren: Nach Typ; Pset MEP.Tech-PN: 16; Pset MEP.Geom-DN: 65; Pset MEP.Geom-Outer Ø (mm): 185; Pset MEP.Geom-Depth: 45; In IFC exportieren als: ifcflowfitting; NameOverride: Flansch; IfcPresentationLayer: S_Gas; ObjectTypeOverride: Flansch; Pset MEP.Name: Flansch; IfcDescription: Flansch; Pset MEP.Tech-Material: nach DIN 2627
Phasen - Phase erstellt: Phase 01

# IfcFlowFitting: Flansch 604885:Flansch 604885, Flansch
In: Erdgeschoss
Type - Material: IfcSurfaceStyle #352577
Type - Andere - Kategorie: Allgemeines Modell; Familienname: Flansch 604885
Type - ID-Daten - Typname: Flansch 604885
Type - IFC-Parameter - Typ in IFC-Datei exportieren: Vorgabe
Description: Flansch
Pset_DistributionFlowElementCommon - Reference: Flansch 604885; sets with these values: 2
Andere - Typ: Flansch 604885; Familie: Flansch 604885; Familie und Typ: Flansch 604885: Flansch 604885; Typ-ID: 2537283
Abhängigkeiten - Höhe von Ebene: 0 m; Verschieben mit umliegenden Elementen: no
Bemaßungen - Fläche: 0.0219883 m2; Volumen: 0.000293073 m3
IFC-Parameter - In IFC-Datei exportieren: Nach Typ; Pset MEP.Tech-PN: 16; Pset MEP.Geom-DN: 65; Pset MEP.Geom-Outer Ø (mm): 185; Pset MEP.Geom-Depth: 45; In IFC exportieren als: ifcflowfitting; NameOverride: Flansch; IfcPresentationLayer: S_Gas; ObjectTypeOverride: Flansch; Pset MEP.Name: Flansch; IfcDescription: Flansch; Pset MEP.Tech-Material: nach DIN 2627
Phasen - Phase erstellt: Phase 01

# IfcFlowFitting: Flansch 604908:Flansch 604908, Flansch
In: Erdgeschoss
Type - Material: IfcSurfaceStyle #352577
Type - Andere - Kategorie: Allgemeines Modell; Familienname: Flansch 604908
Type - ID-Daten - Typname: Flansch 604908
Type - IFC-Parameter - Typ in IFC-Datei exportieren: Vorgabe
Description: Flansch
Pset_DistributionFlowElementCommon - Reference: Flansch 604908; sets with these values: 2
Andere - Typ: Flansch 604908; Familie: Flansch 604908; Familie und Typ: Flansch 604908: Flansch 604908; Typ-ID: 2537290
Abhängigkeiten - Höhe von Ebene: 0 m; Verschieben mit umliegenden Elementen: no
Bemaßungen - Fläche: 0.0219883 m2; Volumen: 0.000503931 m3
IFC-Parameter - In IFC-Datei exportieren: Nach Typ; Pset MEP.Tech-PN: 16; Pset MEP.Geom-DN: 65; Pset MEP.Geom-Outer Ø (mm): 185; Pset MEP.Geom-Depth: 45; In IFC exportieren als: ifcflowfitting; NameOverride: Flansch; IfcPresentationLayer: S_Gas; ObjectTypeOverride: Flansch; Pset MEP.Name: Flansch; IfcDescription: Flansch; Pset MEP.Tech-Material: nach DIN 2627
Phasen - Phase erstellt: Phase 01

# IfcFlowFitting: Flansch 604952:Flansch 604952, Flansch
In: Erdgeschoss
Type - Material: IfcSurfaceStyle #352577
Type - Andere - Kategorie: Allgemeines Modell; Familienname: Flansch 604952
Type - ID-Daten - Typname: Flansch 604952
Type - IFC-Parameter - Typ in IFC-Datei exportieren: Vorgabe
Description: Flansch
Pset_DistributionFlowElementCommon - Reference: Flansch 604952; sets with these values: 2
Andere - Typ: Flansch 604952; Familie: Flansch 604952; Familie und Typ: Flansch 604952: Flansch 604952; Typ-ID: 2537304
Abhängigkeiten - Höhe von Ebene: 0 m; Verschieben mit umliegenden Elementen: no
Bemaßungen - Fläche: 0.0219883 m2; Volumen: 0.000503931 m3
IFC-Parameter - In IFC-Datei exportieren: Nach Typ; Pset MEP.Tech-PN: 16; Pset MEP.Geom-DN: 65; Pset MEP.Geom-Outer Ø (mm): 185; Pset MEP.Geom-Depth: 45; In IFC exportieren als: ifcflowfitting; NameOverride: Flansch; IfcPresentationLayer: S_Gas; ObjectTypeOverride: Flansch; Pset MEP.Name: Flansch; IfcDescription: Flansch; Pset MEP.Tech-Material: nach DIN 2627
Phasen - Phase erstellt: Phase 01

# IfcFlowFitting: Flansch 604975:Flansch 604975, Flansch
In: Erdgeschoss
Type - Material: IfcSurfaceStyle #352577
Type - Andere - Kategorie: Allgemeines Modell; Familienname: Flansch 604975
Type - ID-Daten - Typname: Flansch 604975
Type - IFC-Parameter - Typ in IFC-Datei exportieren: Vorgabe
Description: Flansch
Pset_DistributionFlowElementCommon - Reference: Flansch 604975; sets with these values: 2
Andere - Typ: Flansch 604975; Familie: Flansch 604975; Familie und Typ: Flansch 604975: Flansch 604975; Typ-ID: 2537311
Abhängigkeiten - Höhe von Ebene: 0 m; Verschieben mit umliegenden Elementen: no
Bemaßungen - Fläche: 0.0219883 m2; Volumen: 0.000293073 m3
IFC-Parameter - In IFC-Datei exportieren: Nach Typ; Pset MEP.Tech-PN: 16; Pset MEP.Geom-DN: 65; Pset MEP.Geom-Outer Ø (mm): 185; Pset MEP.Geom-Depth: 45; In IFC exportieren als: ifcflowfitting; NameOverride: Flansch; IfcPresentationLayer: S_Gas; ObjectTypeOverride: Flansch; Pset MEP.Name: Flansch; IfcDescription: Flansch; Pset MEP.Tech-Material: nach DIN 2627
Phasen - Phase erstellt: Phase 01

# IfcFlowFitting: Flansch 605700:Flansch 605700, Flansch
In: Erdgeschoss
Type - Material: IfcSurfaceStyle #352577
Type - Andere - Kategorie: Allgemeines Modell; Familienname: Flansch 605700
Type - ID-Daten - Typname: Flansch 605700
Type - IFC-Parameter - Typ in IFC-Datei exportieren: Vorgabe
Description: Flansch
Pset_DistributionFlowElementCommon - Reference: Flansch 605700; sets with these values: 2
Andere - Typ: Flansch 605700; Familie: Flansch 605700; Familie und Typ: Flansch 605700: Flansch 605700; Typ-ID: 2537360
Abhängigkeiten - Höhe von Ebene: 0 m; Verschieben mit umliegenden Elementen: no
Bemaßungen - Fläche: 0.0129582 m2; Volumen: 0.000130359 m3
IFC-Parameter - In IFC-Datei exportieren: Nach Typ; Pset MEP.Tech-PN: 16; In IFC exportieren als: ifcflowfitting; NameOverride: Flansch; IfcPresentationLayer: S_Gas; ObjectTypeOverride: Flansch; Pset MEP.Name: Flansch; IfcDescription: Flansch; Pset MEP.Geom-Depth: 40; Pset MEP.Geom-DN: 32; Pset MEP.Geom-Outer Ø (mm): 140; Pset MEP.Tech-Material: nach DIN 2627
Phasen - Phase erstellt: Phase 01

# IfcFlowFitting: Flansch 607057:Flansch 607057, Flansch
In: Erdgeschoss
Type - Material: IfcSurfaceStyle #352577
Type - Andere - Kategorie: Allgemeines Modell; Familienname: Flansch 607057
Type - ID-Daten - Typname: Flansch 607057
Type - IFC-Parameter - Typ in IFC-Datei exportieren: Vorgabe
Description: Flansch
Pset_DistributionFlowElementCommon - Reference: Flansch 607057; sets with these values: 2
Andere - Typ: Flansch 607057; Familie: Flansch 607057; Familie und Typ: Flansch 607057: Flansch 607057; Typ-ID: 2537381
Abhängigkeiten - Höhe von Ebene: 0 m; Verschieben mit umliegenden Elementen: no
Bemaßungen - Fläche: 0.0129582 m2; Volumen: 0.000237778 m3
IFC-Parameter - In IFC-Datei exportieren: Nach Typ; Pset MEP.Tech-PN: 16; Pset MEP.Geom-Depth: 40; Pset MEP.Geom-DN: 32; Pset MEP.Geom-Outer Ø (mm): 140; In IFC exportieren als: ifcflowfitting; NameOverride: Flansch; IfcPresentationLayer: S_Gas; ObjectTypeOverride: Flansch; Pset MEP.Name: Flansch; IfcDescription: Flansch; Pset MEP.Tech-Material: nach DIN 2627
Phasen - Phase erstellt: Phase 01

# IfcFlowFitting: Flansch 607492:Flansch 607492, Flansch
In: Erdgeschoss
Type - Material: IfcSurfaceStyle #352577
Type - Andere - Kategorie: Allgemeines Modell; Familienname: Flansch 607492
Type - ID-Daten - Typname: Flansch 607492
Type - IFC-Parameter - Typ in IFC-Datei exportieren: Vorgabe
Description: Flansch
Pset_DistributionFlowElementCommon - Reference: Flansch 607492; sets with these values: 2
Andere - Typ: Flansch 607492; Familie: Flansch 607492; Familie und Typ: Flansch 607492: Flansch 607492; Typ-ID: 2537388
Abhängigkeiten - Höhe von Ebene: 0 m; Verschieben mit umliegenden Elementen: no
Bemaßungen - Fläche: 0.0129582 m2; Volumen: 0.000237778 m3
IFC-Parameter - In IFC-Datei exportieren: Nach Typ; Pset MEP.Tech-PN: 16; Pset MEP.Geom-Depth: 40; Pset MEP.Geom-DN: 32; Pset MEP.Geom-Outer Ø (mm): 140; In IFC exportieren als: ifcflowfitting; NameOverride: Flansch; IfcPresentationLayer: S_Gas; ObjectTypeOverride: Flansch; Pset MEP.Name: Flansch; IfcDescription: Flansch; Pset MEP.Tech-Material: nach DIN 2627
Phasen - Phase erstellt: Phase 01

# IfcFlowFitting: Flansch 607515:Flansch 607515, Flansch
In: Erdgeschoss
Type - Material: IfcSurfaceStyle #352577
Type - Andere - Kategorie: Allgemeines Modell; Familienname: Flansch 607515
Type - ID-Daten - Typname: Flansch 607515
Type - IFC-Parameter - Typ in IFC-Datei exportieren: Vorgabe
Description: Flansch
Pset_DistributionFlowElementCommon - Reference: Flansch 607515; sets with these values: 2
Andere - Typ: Flansch 607515; Familie: Flansch 607515; Familie und Typ: Flansch 607515: Flansch 607515; Typ-ID: 2537395
Abhängigkeiten - Höhe von Ebene: 0 m; Verschieben mit umliegenden Elementen: no
Bemaßungen - Fläche: 0.0129582 m2; Volumen: 0.000237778 m3
IFC-Parameter - In IFC-Datei exportieren: Nach Typ; Pset MEP.Tech-PN: 16; Pset MEP.Geom-Depth: 40; Pset MEP.Geom-DN: 32; Pset MEP.Geom-Outer Ø (mm): 140; In IFC exportieren als: ifcflowfitting; NameOverride: Flansch; IfcPresentationLayer: S_Gas; ObjectTypeOverride: Flansch; Pset MEP.Name: Flansch; IfcDescription: Flansch; Pset MEP.Tech-Material: nach DIN 2627
Phasen - Phase erstellt: Phase 01

# IfcFlowFitting: Flansch 608161:Flansch 608161, Flansch
In: Erdgeschoss
Type - Material: IfcSurfaceStyle #352577
Type - Andere - Kategorie: Allgemeines Modell; Familienname: Flansch 608161
Type - ID-Daten - Typname: Flansch 608161
Type - IFC-Parameter - Typ in IFC-Datei exportieren: Vorgabe
Description: Flansch
Pset_DistributionFlowElementCommon - Reference: Flansch 608161; sets with these values: 2
Andere - Typ: Flansch 608161; Familie: Flansch 608161; Familie und Typ: Flansch 608161: Flansch 608161; Typ-ID: 2537409
Abhängigkeiten - Höhe von Ebene: 0 m; Verschieben mit umliegenden Elementen: no
Bemaßungen - Fläche: 0.0129582 m2; Volumen: 0.000237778 m3
IFC-Parameter - In IFC-Datei exportieren: Nach Typ; Pset MEP.Tech-PN: 16; Pset MEP.Geom-Depth: 40; Pset MEP.Geom-DN: 32; Pset MEP.Geom-Outer Ø (mm): 140; In IFC exportieren als: ifcflowfitting; NameOverride: Flansch; IfcPresentationLayer: S_Gas; ObjectTypeOverride: Flansch; Pset MEP.Name: Flansch; IfcDescription: Flansch; Pset MEP.Tech-Material: nach DIN 2627
Phasen - Phase erstellt: Phase 01

# IfcFlowFitting: Flansch 608184:Flansch 608184, Flansch
In: Erdgeschoss
Type - Material: IfcSurfaceStyle #352577
Type - Andere - Kategorie: Allgemeines Modell; Familienname: Flansch 608184
Type - ID-Daten - Typname: Flansch 608184
Type - IFC-Parameter - Typ in IFC-Datei exportieren: Vorgabe
Description: Flansch
Pset_DistributionFlowElementCommon - Reference: Flansch 608184; sets with these values: 2
Andere - Typ: Flansch 608184; Familie: Flansch 608184; Familie und Typ: Flansch 608184: Flansch 608184; Typ-ID: 2537416
Abhängigkeiten - Höhe von Ebene: 0 m; Verschieben mit umliegenden Elementen: no
Bemaßungen - Fläche: 0.0129582 m2; Volumen: 0.000237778 m3
IFC-Parameter - In IFC-Datei exportieren: Nach Typ; Pset MEP.Tech-PN: 16; Pset MEP.Geom-Depth: 40; Pset MEP.Geom-DN: 32; Pset MEP.Geom-Outer Ø (mm): 140; In IFC exportieren als: ifcflowfitting; NameOverride: Flansch; IfcPresentationLayer: S_Gas; ObjectTypeOverride: Flansch; Pset MEP.Name: Flansch; IfcDescription: Flansch; Pset MEP.Tech-Material: nach DIN 2627
Phasen - Phase erstellt: Phase 01

# IfcFlowFitting: Flansch 608205:Flansch 608205, Flansch
In: Erdgeschoss
Type - Material: IfcSurfaceStyle #352577
Type - Andere - Kategorie: Allgemeines Modell; Familienname: Flansch 608205
Type - ID-Daten - Typname: Flansch 608205
Type - IFC-Parameter - Typ in IFC-Datei exportieren: Vorgabe
Description: Flansch
Pset_DistributionFlowElementCommon - Reference: Flansch 608205; sets with these values: 2
Andere - Typ: Flansch 608205; Familie: Flansch 608205; Familie und Typ: Flansch 608205: Flansch 608205; Typ-ID: 2537423
Abhängigkeiten - Höhe von Ebene: 0 m; Verschieben mit umliegenden Elementen: no
Bemaßungen - Fläche: 0.0129582 m2; Volumen: 0.000237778 m3
IFC-Parameter - In IFC-Datei exportieren: Nach Typ; Pset MEP.Tech-PN: 16; Pset MEP.Geom-Depth: 40; Pset MEP.Geom-DN: 32; Pset MEP.Geom-Outer Ø (mm): 140; In IFC exportieren als: ifcflowfitting; NameOverride: Flansch; IfcPresentationLayer: S_Gas; ObjectTypeOverride: Flansch; Pset MEP.Name: Flansch; IfcDescription: Flansch; Pset MEP.Tech-Material: nach DIN 2627
Phasen - Phase erstellt: Phase 01

# IfcFlowFitting: Flansch 608228:Flansch 608228, Flansch
In: Erdgeschoss
Type - Material: IfcSurfaceStyle #352577
Type - Andere - Kategorie: Allgemeines Modell; Familienname: Flansch 608228
Type - ID-Daten - Typname: Flansch 608228
Type - IFC-Parameter - Typ in IFC-Datei exportieren: Vorgabe
Description: Flansch
Pset_DistributionFlowElementCommon - Reference: Flansch 608228; sets with these values: 2
Andere - Typ: Flansch 608228; Familie: Flansch 608228; Familie und Typ: Flansch 608228: Flansch 608228; Typ-ID: 2537430
Abhängigkeiten - Höhe von Ebene: 0 m; Verschieben mit umliegenden Elementen: no
Bemaßungen - Fläche: 0.0129582 m2; Volumen: 0.000237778 m3
IFC-Parameter - In IFC-Datei exportieren: Nach Typ; Pset MEP.Tech-PN: 16; Pset MEP.Geom-Depth: 40; Pset MEP.Geom-DN: 32; Pset MEP.Geom-Outer Ø (mm): 140; In IFC exportieren als: ifcflowfitting; NameOverride: Flansch; IfcPresentationLayer: S_Gas; ObjectTypeOverride: Flansch; Pset MEP.Name: Flansch; IfcDescription: Flansch; Pset MEP.Tech-Material: nach DIN 2627
Phasen - Phase erstellt: Phase 01

# IfcFlowFitting: Flansch 608436:Flansch 608436, Flansch
In: Erdgeschoss
Type - Material: IfcSurfaceStyle #352577
Type - Andere - Kategorie: Allgemeines Modell; Familienname: Flansch 608436
Type - ID-Daten - Typname: Flansch 608436
Type - IFC-Parameter - Typ in IFC-Datei exportieren: Vorgabe
Description: Flansch
Pset_DistributionFlowElementCommon - Reference: Flansch 608436; sets with these values: 2
Andere - Typ: Flansch 608436; Familie: Flansch 608436; Familie und Typ: Flansch 608436: Flansch 608436; Typ-ID: 2537444
Abhängigkeiten - Höhe von Ebene: 0 m; Verschieben mit umliegenden Elementen: no
Bemaßungen - Fläche: 0.0129582 m2; Volumen: 0.000237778 m3
IFC-Parameter - In IFC-Datei exportieren: Nach Typ; Pset MEP.Tech-PN: 16; Pset MEP.Geom-Depth: 40; Pset MEP.Geom-DN: 32; Pset MEP.Geom-Outer Ø (mm): 140; In IFC exportieren als: ifcflowfitting; NameOverride: Flansch; IfcPresentationLayer: S_Gas; ObjectTypeOverride: Flansch; Pset MEP.Name: Flansch; IfcDescription: Flansch; Pset MEP.Tech-Material: nach DIN 2627
Phasen - Phase erstellt: Phase 01

# IfcFlowFitting: Flansch 608459:Flansch 608459, Flansch
In: Erdgeschoss
Type - Material: IfcSurfaceStyle #352577
Type - Andere - Kategorie: Allgemeines Modell; Familienname: Flansch 608459
Type - ID-Daten - Typname: Flansch 608459
Type - IFC-Parameter - Typ in IFC-Datei exportieren: Vorgabe
Description: Flansch
Pset_DistributionFlowElementCommon - Reference: Flansch 608459; sets with these values: 2
Andere - Typ: Flansch 608459; Familie: Flansch 608459; Familie und Typ: Flansch 608459: Flansch 608459; Typ-ID: 2537451
Abhängigkeiten - Höhe von Ebene: 0 m; Verschieben mit umliegenden Elementen: no
Bemaßungen - Fläche: 0.0129582 m2; Volumen: 0.000237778 m3
IFC-Parameter - In IFC-Datei exportieren: Nach Typ; Pset MEP.Tech-PN: 16; Pset MEP.Geom-Depth: 40; Pset MEP.Geom-DN: 32; Pset MEP.Geom-Outer Ø (mm): 140; In IFC exportieren als: ifcflowfitting; NameOverride: Flansch; IfcPresentationLayer: S_Gas; ObjectTypeOverride: Flansch; Pset MEP.Name: Flansch; IfcDescription: Flansch; Pset MEP.Tech-Material: nach DIN 2627
Phasen - Phase erstellt: Phase 01

# IfcFlowFitting: Flansch 608632:Flansch 608632, Flansch
In: Erdgeschoss
Type - Material: IfcSurfaceStyle #352577
Type - Andere - Kategorie: Allgemeines Modell; Familienname: Flansch 608632
Type - ID-Daten - Typname: Flansch 608632
Type - IFC-Parameter - Typ in IFC-Datei exportieren: Vorgabe
Description: Flansch
Pset_DistributionFlowElementCommon - Reference: Flansch 608632; sets with these values: 2
Andere - Typ: Flansch 608632; Familie: Flansch 608632; Familie und Typ: Flansch 608632: Flansch 608632; Typ-ID: 2537465
Abhängigkeiten - Höhe von Ebene: 0 m; Verschieben mit umliegenden Elementen: no
Bemaßungen - Fläche: 0.0129582 m2; Volumen: 0.000130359 m3
IFC-Parameter - In IFC-Datei exportieren: Nach Typ; Pset MEP.Tech-PN: 16; Pset MEP.Geom-Depth: 40; Pset MEP.Geom-DN: 32; Pset MEP.Geom-Outer Ø (mm): 140; In IFC exportieren als: ifcflowfitting; NameOverride: Flansch; IfcPresentationLayer: S_Gas; ObjectTypeOverride: Flansch; Pset MEP.Name: Flansch; IfcDescription: Flansch; Pset MEP.Tech-Material: nach DIN 2627
Phasen - Phase erstellt: Phase 01

# IfcFlowFitting: Flansch 610219:Flansch 610219, Flansch
In: Erdgeschoss
Type - Material: IfcSurfaceStyle #352577
Type - Andere - Kategorie: Allgemeines Modell; Familienname: Flansch 610219
Type - ID-Daten - Typname: Flansch 610219
Type - IFC-Parameter - Typ in IFC-Datei exportieren: Vorgabe
Description: Flansch
Pset_DistributionFlowElementCommon - Reference: Flansch 610219; sets with these values: 2
Andere - Typ: Flansch 610219; Familie: Flansch 610219; Familie und Typ: Flansch 610219: Flansch 610219; Typ-ID: 2537479
Abhängigkeiten - Höhe von Ebene: 0 m; Verschieben mit umliegenden Elementen: no
Bemaßungen - Fläche: 0.0129582 m2; Volumen: 0.000130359 m3
IFC-Parameter - In IFC-Datei exportieren: Nach Typ; Pset MEP.Tech-PN: 16; Pset MEP.Geom-Depth: 40; Pset MEP.Geom-DN: 32; Pset MEP.Geom-Outer Ø (mm): 140; In IFC exportieren als: ifcflowfitting; NameOverride: Flansch; IfcPresentationLayer: S_Gas; ObjectTypeOverride: Flansch; Pset MEP.Name: Flansch; IfcDescription: Flansch; Pset MEP.Tech-Material: nach DIN 2627
Phasen - Phase erstellt: Phase 01

# IfcFlowFitting: Flansch 610248:Flansch 610248, Flansch
In: Erdgeschoss
Type - Material: IfcSurfaceStyle #352577
Type - Andere - Kategorie: Allgemeines Modell; Familienname: Flansch 610248
Type - ID-Daten - Typname: Flansch 610248
Type - IFC-Parameter - Typ in IFC-Datei exportieren: Vorgabe
Description: Flansch
Pset_DistributionFlowElementCommon - Reference: Flansch 610248; sets with these values: 2
Andere - Typ: Flansch 610248; Familie: Flansch 610248; Familie und Typ: Flansch 610248: Flansch 610248; Typ-ID: 2537486
Abhängigkeiten - Höhe von Ebene: 0 m; Verschieben mit umliegenden Elementen: no
Bemaßungen - Fläche: 0.0129582 m2; Volumen: 0.000130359 m3
IFC-Parameter - In IFC-Datei exportieren: Nach Typ; Pset MEP.Tech-PN: 16; Pset MEP.Geom-Depth: 40; Pset MEP.Geom-DN: 32; Pset MEP.Geom-Outer Ø (mm): 140; In IFC exportieren als: ifcflowfitting; NameOverride: Flansch; IfcPresentationLayer: S_Gas; ObjectTypeOverride: Flansch; Pset MEP.Name: Flansch; IfcDescription: Flansch; Pset MEP.Tech-Material: nach DIN 2627
Phasen - Phase erstellt: Phase 01

# IfcFlowFitting: Flansch 610987:Flansch 610987, Flansch
In: Erdgeschoss
Type - Material: IfcSurfaceStyle #352577
Type - Andere - Kategorie: Allgemeines Modell; Familienname: Flansch 610987
Type - ID-Daten - Typname: Flansch 610987
Type - IFC-Parameter - Typ in IFC-Datei exportieren: Vorgabe
Description: Flansch
Pset_DistributionFlowElementCommon - Reference: Flansch 610987; sets with these values: 2
Andere - Typ: Flansch 610987; Familie: Flansch 610987; Familie und Typ: Flansch 610987: Flansch 610987; Typ-ID: 2537500
Abhängigkeiten - Höhe von Ebene: 0 m; Verschieben mit umliegenden Elementen: no
Bemaßungen - Fläche: 0.0129582 m2; Volumen: 0.000130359 m3
IFC-Parameter - In IFC-Datei exportieren: Nach Typ; Pset MEP.Tech-PN: 16; Pset MEP.Geom-Depth: 40; Pset MEP.Geom-DN: 32; Pset MEP.Geom-Outer Ø (mm): 140; In IFC exportieren als: ifcflowfitting; NameOverride: Flansch; IfcPresentationLayer: S_Gas; ObjectTypeOverride: Flansch; Pset MEP.Name: Flansch; IfcDescription: Flansch; Pset MEP.Tech-Material: nach DIN 2627
Phasen - Phase erstellt: Phase 01

# IfcFlowFitting: Flansch 611010:Flansch 611010, Flansch
In: Erdgeschoss
Type - Material: IfcSurfaceStyle #352577
Type - Andere - Kategorie: Allgemeines Modell; Familienname: Flansch 611010
Type - ID-Daten - Typname: Flansch 611010
Type - IFC-Parameter - Typ in IFC-Datei exportieren: Vorgabe
Description: Flansch
Pset_DistributionFlowElementCommon - Reference: Flansch 611010; sets with these values: 2
Andere - Typ: Flansch 611010; Familie: Flansch 611010; Familie und Typ: Flansch 611010: Flansch 611010; Typ-ID: 2537507
Abhängigkeiten - Höhe von Ebene: 0 m; Verschieben mit umliegenden Elementen: no
Bemaßungen - Fläche: 0.0129582 m2; Volumen: 0.000130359 m3
IFC-Parameter - In IFC-Datei exportieren: Nach Typ; Pset MEP.Tech-PN: 16; Pset MEP.Geom-Depth: 40; Pset MEP.Geom-DN: 32; Pset MEP.Geom-Outer Ø (mm): 140; In IFC exportieren als: ifcflowfitting; NameOverride: Flansch; IfcPresentationLayer: S_Gas; ObjectTypeOverride: Flansch; Pset MEP.Name: Flansch; IfcDescription: Flansch; Pset MEP.Tech-Material: nach DIN 2627
Phasen - Phase erstellt: Phase 01

# IfcFlowFitting: Flansch 611033:Flansch 611033, Flansch
In: Erdgeschoss
Type - Material: IfcSurfaceStyle #352577
Type - Andere - Kategorie: Allgemeines Modell; Familienname: Flansch 611033
Type - ID-Daten - Typname: Flansch 611033
Type - IFC-Parameter - Typ in IFC-Datei exportieren: Vorgabe
Description: Flansch
Pset_DistributionFlowElementCommon - Reference: Flansch 611033; sets with these values: 2
Andere - Typ: Flansch 611033; Familie: Flansch 611033; Familie und Typ: Flansch 611033: Flansch 611033; Typ-ID: 2537514
Abhängigkeiten - Höhe von Ebene: 0 m; Verschieben mit umliegenden Elementen: no
Bemaßungen - Fläche: 0.0129582 m2; Volumen: 0.000130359 m3
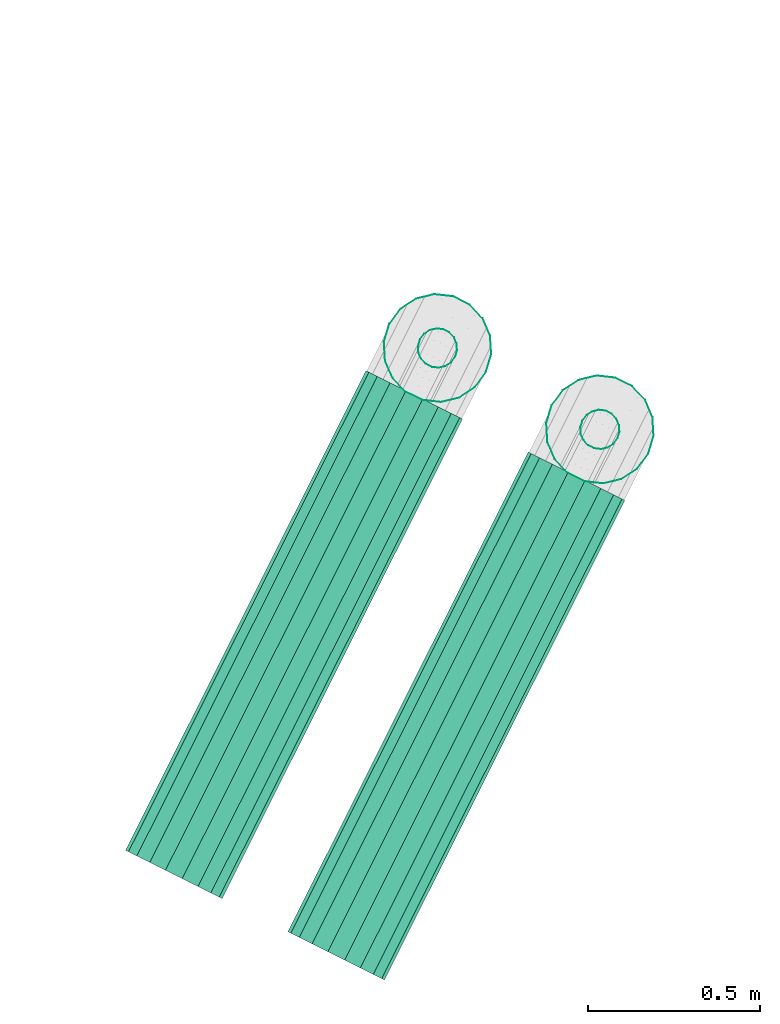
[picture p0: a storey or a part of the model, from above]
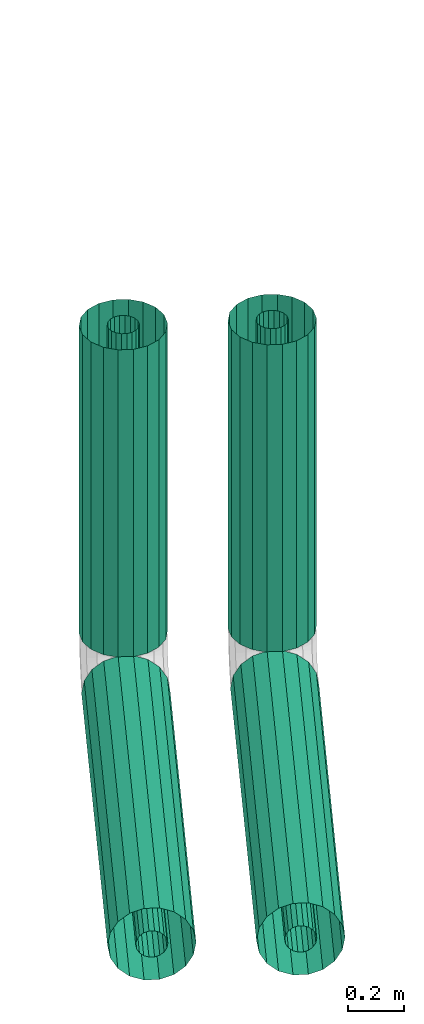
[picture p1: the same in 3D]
Properties of the parts of a building model (IFC2X3), part 11 of 23

# IfcFlowFitting: Flansch 611033:Flansch 611033, Flansch
IFC-Parameter - In IFC-Datei exportieren: Nach Typ; Pset MEP.Tech-PN: 16; Pset MEP.Geom-Depth: 40; Pset MEP.Geom-DN: 32; Pset MEP.Geom-Outer Ø (mm): 140; In IFC exportieren als: ifcflowfitting; NameOverride: Flansch; IfcPresentationLayer: S_Gas; ObjectTypeOverride: Flansch; Pset MEP.Name: Flansch; IfcDescription: Flansch; Pset MEP.Tech-Material: nach DIN 2627
Phasen - Phase erstellt: Phase 01

# IfcFlowFitting: Flansch 612489:Flansch 612489, Flansch
In: Erdgeschoss
Type - Material: IfcSurfaceStyle #352577
Type - Andere - Kategorie: Allgemeines Modell; Familienname: Flansch 612489
Type - ID-Daten - Typname: Flansch 612489
Type - IFC-Parameter - Typ in IFC-Datei exportieren: Vorgabe
Description: Flansch
Pset_DistributionFlowElementCommon - Reference: Flansch 612489; sets with these values: 2
Andere - Typ: Flansch 612489; Familie: Flansch 612489; Familie und Typ: Flansch 612489: Flansch 612489; Typ-ID: 2537591
Abhängigkeiten - Höhe von Ebene: 0 m; Verschieben mit umliegenden Elementen: no
Bemaßungen - Fläche: 0.0129582 m2; Volumen: 0.000130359 m3
IFC-Parameter - In IFC-Datei exportieren: Nach Typ; Pset MEP.Tech-PN: 16; Pset MEP.Geom-Depth: 40; Pset MEP.Geom-DN: 32; Pset MEP.Geom-Outer Ø (mm): 140; In IFC exportieren als: ifcflowfitting; NameOverride: Flansch; IfcPresentationLayer: S_Gas; ObjectTypeOverride: Flansch; Pset MEP.Name: Flansch; IfcDescription: Flansch; Pset MEP.Tech-Material: nach DIN 2627
Phasen - Phase erstellt: Phase 01

# IfcFlowFitting: Flansch 613585:Flansch 613585, Flansch
In: 1. Obergeschoss
Type - Material: IfcSurfaceStyle #9317
Type - Andere - Kategorie: Allgemeines Modell; Familienname: Flansch 613585
Type - ID-Daten - Typname: Flansch 613585
Type - IFC-Parameter - Typ in IFC-Datei exportieren: Vorgabe
Description: Flansch
Pset_DistributionFlowElementCommon - Reference: Flansch 613585; sets with these values: 2
Andere - Typ: Flansch 613585; Familie: Flansch 613585; Familie und Typ: Flansch 613585: Flansch 613585; Typ-ID: 2537647
Abhängigkeiten - Höhe von Ebene: 0 m; Verschieben mit umliegenden Elementen: no
Bemaßungen - Fläche: 0.144185 m2; Volumen: 0.0099386 m3
IFC-Parameter - In IFC-Datei exportieren: Nach Typ; Pset MEP.Geom-Depth: 62; Pset MEP.Geom-DN: 200; Pset MEP.Geom-Outer Ø (mm): 340; Pset MEP.Tech-Insulation thickness (mm): 100; Pset MEP.Tech-PN: 16; In IFC exportieren als: ifcflowfitting; NameOverride: Flansch; IfcPresentationLayer: 0-TFT-H_Vorlauf; ObjectTypeOverride: Flansch; Pset MEP.Name: Flansch; IfcDescription: Flansch; Pset MEP.Tech-Material: nach DIN 2627
Phasen - Phase erstellt: Phase 01

# IfcFlowFitting: Flansch 614336:Flansch 614336, Flansch
In: 1. Obergeschoss
Type - Material: IfcSurfaceStyle #1741
Type - Andere - Kategorie: Allgemeines Modell; Familienname: Flansch 614336
Type - ID-Daten - Typname: Flansch 614336
Type - IFC-Parameter - Typ in IFC-Datei exportieren: Vorgabe
Description: Flansch
Pset_DistributionFlowElementCommon - Reference: Flansch 614336; sets with these values: 2
Andere - Typ: Flansch 614336; Familie: Flansch 614336; Familie und Typ: Flansch 614336: Flansch 614336; Typ-ID: 2537682
Abhängigkeiten - Höhe von Ebene: 0 m; Verschieben mit umliegenden Elementen: no
Bemaßungen - Fläche: 0.111243 m2; Volumen: 0.00814942 m3
IFC-Parameter - In IFC-Datei exportieren: Nach Typ; Pset MEP.Tech-Insulation thickness (mm): 100; Pset MEP.Tech-PN: 16; Pset MEP.Geom-Depth: 55; Pset MEP.Geom-DN: 150; Pset MEP.Geom-Outer Ø (mm): 285; In IFC exportieren als: ifcflowfitting; NameOverride: Flansch; IfcPresentationLayer: 0-TFT-H_Ruecklauf; ObjectTypeOverride: Flansch; Pset MEP.Name: Flansch; IfcDescription: Flansch; Pset MEP.Tech-Material: nach DIN 2627
Phasen - Phase erstellt: Phase 01

# IfcFlowFitting: Flansch 614497:Flansch 614497, Flansch
In: 1. Obergeschoss
Type - Material: IfcSurfaceStyle #1741
Type - Andere - Kategorie: Allgemeines Modell; Familienname: Flansch 614497
Type - ID-Daten - Typname: Flansch 614497
Type - IFC-Parameter - Typ in IFC-Datei exportieren: Vorgabe
Description: Flansch
Pset_DistributionFlowElementCommon - Reference: Flansch 614497; sets with these values: 2
Andere - Typ: Flansch 614497; Familie: Flansch 614497; Familie und Typ: Flansch 614497: Flansch 614497; Typ-ID: 2537731
Abhängigkeiten - Höhe von Ebene: 0 m; Verschieben mit umliegenden Elementen: no
Bemaßungen - Fläche: 0.0800177 m2; Volumen: 0.00543566 m3
IFC-Parameter - In IFC-Datei exportieren: Nach Typ; Pset MEP.Tech-Insulation thickness (mm): 100; Pset MEP.Tech-PN: 16; Pset MEP.Geom-DN: 100; Pset MEP.Geom-Depth: 52; Pset MEP.Geom-Outer Ø (mm): 220; In IFC exportieren als: ifcflowfitting; NameOverride: Flansch; IfcPresentationLayer: 0-TFT-H_Ruecklauf; ObjectTypeOverride: Flansch; Pset MEP.Name: Flansch; IfcDescription: Flansch; Pset MEP.Tech-Material: nach DIN 2627
Phasen - Phase erstellt: Phase 01

# IfcFlowFitting: Flansch 614520:Flansch 614520, Flansch
In: 1. Obergeschoss
Type - Material: IfcSurfaceStyle #1741
Type - Andere - Kategorie: Allgemeines Modell; Familienname: Flansch 614520
Type - ID-Daten - Typname: Flansch 614520
Type - IFC-Parameter - Typ in IFC-Datei exportieren: Vorgabe
Description: Flansch
Pset_DistributionFlowElementCommon - Reference: Flansch 614520; sets with these values: 2
Andere - Typ: Flansch 614520; Familie: Flansch 614520; Familie und Typ: Flansch 614520: Flansch 614520; Typ-ID: 2537738
Abhängigkeiten - Höhe von Ebene: 0 m; Verschieben mit umliegenden Elementen: no
Bemaßungen - Fläche: 0.0800177 m2; Volumen: 0.00456789 m3
IFC-Parameter - In IFC-Datei exportieren: Nach Typ; Pset MEP.Tech-Insulation thickness (mm): 100; Pset MEP.Tech-PN: 16; Pset MEP.Geom-DN: 100; Pset MEP.Geom-Depth: 52; Pset MEP.Geom-Outer Ø (mm): 220; In IFC exportieren als: ifcflowfitting; NameOverride: Flansch; IfcPresentationLayer: 0-TFT-H_Ruecklauf; ObjectTypeOverride: Flansch; Pset MEP.Name: Flansch; IfcDescription: Flansch; Pset MEP.Tech-Material: nach DIN 2627
Phasen - Phase erstellt: Phase 01

# IfcFlowFitting: Flansch 614559:Flansch 614559, Flansch
In: Erdgeschoss
Type - Material: IfcSurfaceStyle #1741
Type - Andere - Kategorie: Allgemeines Modell; Familienname: Flansch 614559
Type - ID-Daten - Typname: Flansch 614559
Type - IFC-Parameter - Typ in IFC-Datei exportieren: Vorgabe
Description: Flansch
Pset_DistributionFlowElementCommon - Reference: Flansch 614559; sets with these values: 2
Andere - Typ: Flansch 614559; Familie: Flansch 614559; Familie und Typ: Flansch 614559: Flansch 614559; Typ-ID: 2537745
Abhängigkeiten - Höhe von Ebene: 0 m; Verschieben mit umliegenden Elementen: no
Bemaßungen - Fläche: 0.111243 m2; Volumen: 0.00814942 m3
IFC-Parameter - In IFC-Datei exportieren: Nach Typ; Pset MEP.Tech-Insulation thickness (mm): 100; Pset MEP.Tech-PN: 16; Pset MEP.Geom-Depth: 55; Pset MEP.Geom-DN: 150; Pset MEP.Geom-Outer Ø (mm): 285; In IFC exportieren als: ifcflowfitting; NameOverride: Flansch; IfcPresentationLayer: 0-TFT-H_Ruecklauf; ObjectTypeOverride: Flansch; Pset MEP.Name: Flansch; IfcDescription: Flansch; Pset MEP.Tech-Material: nach DIN 2627
Phasen - Phase erstellt: Phase 01

# IfcFlowFitting: Flansch 614651:Flansch 614651, Flansch
In: 1. Obergeschoss
Type - Material: IfcSurfaceStyle #1741
Type - Andere - Kategorie: Allgemeines Modell; Familienname: Flansch 614651
Type - ID-Daten - Typname: Flansch 614651
Type - IFC-Parameter - Typ in IFC-Datei exportieren: Vorgabe
Description: Flansch
Pset_DistributionFlowElementCommon - Reference: Flansch 614651; sets with these values: 2
Andere - Typ: Flansch 614651; Familie: Flansch 614651; Familie und Typ: Flansch 614651: Flansch 614651; Typ-ID: 2537773
Abhängigkeiten - Höhe von Ebene: 0 m; Verschieben mit umliegenden Elementen: no
Bemaßungen - Fläche: 0.111243 m2; Volumen: 0.00814942 m3
IFC-Parameter - In IFC-Datei exportieren: Nach Typ; Pset MEP.Tech-Insulation thickness (mm): 100; Pset MEP.Tech-PN: 16; Pset MEP.Geom-Depth: 55; Pset MEP.Geom-DN: 150; Pset MEP.Geom-Outer Ø (mm): 285; In IFC exportieren als: ifcflowfitting; NameOverride: Flansch; IfcPresentationLayer: 0-TFT-H_Ruecklauf; ObjectTypeOverride: Flansch; Pset MEP.Name: Flansch; IfcDescription: Flansch; Pset MEP.Tech-Material: nach DIN 2627
Phasen - Phase erstellt: Phase 01

# IfcFlowFitting: Flansch 617588:Flansch 617588, Flansch
In: Erdgeschoss
Type - Material: IfcSurfaceStyle #352577
Type - Andere - Kategorie: Allgemeines Modell; Familienname: Flansch 617588
Type - ID-Daten - Typname: Flansch 617588
Type - IFC-Parameter - Typ in IFC-Datei exportieren: Vorgabe
Description: Flansch
Pset_DistributionFlowElementCommon - Reference: Flansch 617588; sets with these values: 2
Andere - Typ: Flansch 617588; Familie: Flansch 617588; Familie und Typ: Flansch 617588: Flansch 617588; Typ-ID: 2537829
Abhängigkeiten - Höhe von Ebene: 0 m; Verschieben mit umliegenden Elementen: no
Bemaßungen - Fläche: 0.0129582 m2; Volumen: 0.000237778 m3
IFC-Parameter - In IFC-Datei exportieren: Nach Typ; Pset MEP.Tech-PN: 16; Pset MEP.Geom-Depth: 40; Pset MEP.Geom-DN: 32; Pset MEP.Geom-Outer Ø (mm): 140; In IFC exportieren als: ifcflowfitting; NameOverride: Flansch; IfcPresentationLayer: S_Gas; ObjectTypeOverride: Flansch; Pset MEP.Name: Flansch; IfcDescription: Flansch; Pset MEP.Tech-Material: nach DIN 2627
Phasen - Phase erstellt: Phase 01

# IfcFlowFitting: Flansch 617766:Flansch 617766, Flansch
In: Erdgeschoss
Type - Material: IfcSurfaceStyle #352577
Type - Andere - Kategorie: Allgemeines Modell; Familienname: Flansch 617766
Type - ID-Daten - Typname: Flansch 617766
Type - IFC-Parameter - Typ in IFC-Datei exportieren: Vorgabe
Description: Flansch
Pset_DistributionFlowElementCommon - Reference: Flansch 617766; sets with these values: 2
Andere - Typ: Flansch 617766; Familie: Flansch 617766; Familie und Typ: Flansch 617766: Flansch 617766; Typ-ID: 2537843
Abhängigkeiten - Höhe von Ebene: 0 m; Verschieben mit umliegenden Elementen: no
Bemaßungen - Fläche: 0.0129582 m2; Volumen: 0.000237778 m3
IFC-Parameter - In IFC-Datei exportieren: Nach Typ; Pset MEP.Tech-PN: 16; Pset MEP.Geom-Depth: 40; Pset MEP.Geom-DN: 32; Pset MEP.Geom-Outer Ø (mm): 140; In IFC exportieren als: ifcflowfitting; NameOverride: Flansch; IfcPresentationLayer: S_Gas; ObjectTypeOverride: Flansch; Pset MEP.Name: Flansch; IfcDescription: Flansch; Pset MEP.Tech-Material: nach DIN 2627
Phasen - Phase erstellt: Phase 01

# IfcFlowFitting: Flansch 623342:Flansch 623342, Flansch
In: 1. Obergeschoss
Type - Material: IfcSurfaceStyle #1741
Type - Andere - Kategorie: Allgemeines Modell; Familienname: Flansch 623342
Type - ID-Daten - Typname: Flansch 623342
Type - IFC-Parameter - Typ in IFC-Datei exportieren: Vorgabe
Description: Flansch
Pset_DistributionFlowElementCommon - Reference: Flansch 623342; sets with these values: 2
Andere - Typ: Flansch 623342; Familie: Flansch 623342; Familie und Typ: Flansch 623342: Flansch 623342; Typ-ID: 2538252
Abhängigkeiten - Höhe von Ebene: 0 m; Verschieben mit umliegenden Elementen: no
Bemaßungen - Fläche: 0.0503828 m2; Volumen: 0.00171028 m3
IFC-Parameter - In IFC-Datei exportieren: Nach Typ; Pset MEP.Tech-Insulation thickness (mm): 100; Pset MEP.Tech-PN: 16; Pset MEP.Geom-Depth: 55; Pset MEP.Geom-DN: 150; Pset MEP.Geom-Outer Ø (mm): 285; In IFC exportieren als: ifcflowfitting; NameOverride: Flansch; IfcPresentationLayer: 0-TFT-H_Ruecklauf; ObjectTypeOverride: Flansch; Pset MEP.Name: Flansch; IfcDescription: Flansch; Pset MEP.Tech-Material: nach DIN 2627
Phasen - Phase erstellt: Phase 01

# IfcFlowFitting: Flansch 7864:Flansch 7864, Flansch
In: 1. Obergeschoss
Type - Material: IfcSurfaceStyle #1741
Type - Andere - Kategorie: Allgemeines Modell; Familienname: Flansch 7864
Type - ID-Daten - Typname: Flansch 7864
Type - IFC-Parameter - Typ in IFC-Datei exportieren: Vorgabe
Description: Flansch
Pset_DistributionFlowElementCommon - Reference: Flansch 7864; sets with these values: 2
Andere - Typ: Flansch 7864; Familie: Flansch 7864; Familie und Typ: Flansch 7864: Flansch 7864; Typ-ID: 2531454
Abhängigkeiten - Höhe von Ebene: 0 m; Verschieben mit umliegenden Elementen: no
Bemaßungen - Fläche: 0.144185 m2; Volumen: 0.0118373 m3
IFC-Parameter - In IFC-Datei exportieren: Nach Typ; Pset MEP.Geom-Depth: 62; Pset MEP.Geom-DN: 200; Pset MEP.Geom-Outer Ø (mm): 340; Pset MEP.Tech-Insulation thickness (mm): 100; Pset MEP.Tech-PN: 16; In IFC exportieren als: ifcflowfitting; NameOverride: Flansch; IfcPresentationLayer: 0-TFT-H_Ruecklauf; ObjectTypeOverride: Flansch; Pset MEP.Name: Flansch; IfcDescription: Flansch; Pset MEP.Tech-Material: nach DIN 2627
Phasen - Phase erstellt: Phase 01

# IfcFlowFitting: Flansch 861160:Flansch 861160, Flansch
In: 1. Untergeschoss
Type - Material: IfcSurfaceStyle #9317
Type - Andere - Kategorie: Allgemeines Modell; Familienname: Flansch 861160
Type - ID-Daten - Typname: Flansch 861160
Type - IFC-Parameter - Typ in IFC-Datei exportieren: Vorgabe
Description: Flansch
Pset_DistributionFlowElementCommon - Reference: Flansch 861160; sets with these values: 2
Andere - Typ: Flansch 861160; Familie: Flansch 861160; Familie und Typ: Flansch 861160: Flansch 861160; Typ-ID: 2539632
Abhängigkeiten - Höhe von Ebene: 0 m; Verschieben mit umliegenden Elementen: no
Bemaßungen - Fläche: 0.144185 m2; Volumen: 0.0099386 m3
IFC-Parameter - In IFC-Datei exportieren: Nach Typ; Pset MEP.Geom-Depth: 62; Pset MEP.Geom-DN: 200; Pset MEP.Geom-Outer Ø (mm): 340; Pset MEP.Tech-Insulation thickness (mm): 100; Pset MEP.Tech-PN: 16; In IFC exportieren als: ifcflowfitting; NameOverride: Flansch; IfcPresentationLayer: 0-TFT-H_Vorlauf; ObjectTypeOverride: Flansch; Pset MEP.Name: Flansch; IfcDescription: Flansch; Pset MEP.Tech-Material: nach DIN 2627
Phasen - Phase erstellt: Phase 01

# IfcFlowFitting: Flansch 861233:Flansch 861233, Flansch
In: 1. Untergeschoss
Type - Material: IfcSurfaceStyle #1741
Type - Andere - Kategorie: Allgemeines Modell; Familienname: Flansch 861233
Type - ID-Daten - Typname: Flansch 861233
Type - IFC-Parameter - Typ in IFC-Datei exportieren: Vorgabe
Description: Flansch
Pset_DistributionFlowElementCommon - Reference: Flansch 861233; sets with these values: 2
Andere - Typ: Flansch 861233; Familie: Flansch 861233; Familie und Typ: Flansch 861233: Flansch 861233; Typ-ID: 2539653
Abhängigkeiten - Höhe von Ebene: 0 m; Verschieben mit umliegenden Elementen: no
Bemaßungen - Fläche: 0.144185 m2; Volumen: 0.0099386 m3
IFC-Parameter - In IFC-Datei exportieren: Nach Typ; Pset MEP.Geom-Depth: 62; Pset MEP.Geom-DN: 200; Pset MEP.Geom-Outer Ø (mm): 340; Pset MEP.Tech-Insulation thickness (mm): 100; Pset MEP.Tech-PN: 16; In IFC exportieren als: ifcflowfitting; NameOverride: Flansch; IfcPresentationLayer: 0-TFT-H_Ruecklauf; ObjectTypeOverride: Flansch; Pset MEP.Name: Flansch; IfcDescription: Flansch; Pset MEP.Tech-Material: nach DIN 2627
Phasen - Phase erstellt: Phase 01

# IfcFlowFitting: Flansch:Flansch, Flansch
In: 1. Obergeschoss
Type - Material: IfcSurfaceStyle #1741
Type - Andere - Kategorie: Allgemeines Modell; Familienname: Flansch
Type - ID-Daten - Typname: Flansch
Type - IFC-Parameter - Typ in IFC-Datei exportieren: Vorgabe
Description: Flansch
Pset_DistributionFlowElementCommon - Reference: Flansch; sets with these values: 2
Andere - Typ: Flansch; Familie: Flansch; Familie und Typ: Flansch: Flansch; Typ-ID: 2531319
Abhängigkeiten - Höhe von Ebene: 0 m; Verschieben mit umliegenden Elementen: no
Bemaßungen - Fläche: 0.144185 m2; Volumen: 0.0118373 m3
IFC-Parameter - In IFC-Datei exportieren: Nach Typ; In IFC exportieren als: ifcflowfitting; NameOverride: Flansch; IfcPresentationLayer: 0-TFT-H_Ruecklauf; ObjectTypeOverride: Flansch; Pset MEP.Name: Flansch; IfcDescription: Flansch; Pset MEP.Geom-Depth: 62; Pset MEP.Geom-DN: 200; Pset MEP.Geom-Outer Ø (mm): 340; Pset MEP.Tech-Insulation thickness (mm): 100; Pset MEP.Tech-Material: nach DIN 2627; Pset MEP.Tech-PN: 16
Phasen - Phase erstellt: Phase 01

# IfcFlowFitting: Klöpperboden 240325:Klöpperboden 240325, Klöpperboden
In: 1. Obergeschoss
Type - Material: IfcSurfaceStyle #1741
Type - Andere - Kategorie: Allgemeines Modell; Familienname: Klöpperboden 240325
Type - ID-Daten - Typname: Klöpperboden 240325
Type - IFC-Parameter - Typ in IFC-Datei exportieren: Vorgabe
Description: Klöpperboden
Pset_DistributionFlowElementCommon - Reference: Klöpperboden 240325; sets with these values: 2
Andere - Typ: Klöpperboden 240325; Familie: Klöpperboden 240325; Familie und Typ: Klöpperboden 240325: Klöpperboden 240325; Typ-ID: 2532452
Abhängigkeiten - Höhe von Ebene: 0 m; Verschieben mit umliegenden Elementen: no
Bemaßungen - Fläche: 0.142509 m2; Volumen: 0.013389 m3
IFC-Parameter - In IFC-Datei exportieren: Nach Typ; Pset MEP.Geom-DN: 200; Pset MEP.Tech-Insulation thickness (mm): 100; In IFC exportieren als: ifcflowfitting; NameOverride: Klöpperboden; IfcPresentationLayer: 0-TFT-H_Ruecklauf; ObjectTypeOverride: Klöpperboden; Pset MEP.Name: Klöpperboden; IfcDescription: Klöpperboden; Pset MEP.Geom-Outer Ø (mm): 219.1; Pset MEP.Tech-Material: Stahlrohr nach DIN 2448
Phasen - Phase erstellt: Phase 01

# IfcFlowFitting: Klöpperboden:Klöpperboden, Klöpperboden
In: 1. Obergeschoss
Type - Material: IfcSurfaceStyle #9317
Type - Andere - Kategorie: Allgemeines Modell; Familienname: Klöpperboden
Type - ID-Daten - Typname: Klöpperboden
Type - IFC-Parameter - Typ in IFC-Datei exportieren: Vorgabe
Description: Klöpperboden
Pset_DistributionFlowElementCommon - Reference: Klöpperboden; sets with these values: 2
Andere - Typ: Klöpperboden; Familie: Klöpperboden; Familie und Typ: Klöpperboden: Klöpperboden; Typ-ID: 2532445
Abhängigkeiten - Höhe von Ebene: 0 m; Verschieben mit umliegenden Elementen: no
Bemaßungen - Fläche: 0.142509 m2; Volumen: 0.013389 m3
IFC-Parameter - In IFC-Datei exportieren: Nach Typ; Pset MEP.Geom-DN: 200; Pset MEP.Tech-Insulation thickness (mm): 100; In IFC exportieren als: ifcflowfitting; NameOverride: Klöpperboden; IfcPresentationLayer: 0-TFT-H_Vorlauf; ObjectTypeOverride: Klöpperboden; Pset MEP.Name: Klöpperboden; IfcDescription: Klöpperboden; Pset MEP.Geom-Outer Ø (mm): 219.1; Pset MEP.Tech-Material: Stahlrohr nach DIN 2448
Phasen - Phase erstellt: Phase 01

# IfcFlowFitting: Konisches Übergangsstück:Konisches Übergangsstück, Konisches Übergangsstück
In: Erdgeschoss
Type - Material: IfcSurfaceStyle #251447
Type - Andere - Kategorie: Allgemeines Modell; Familienname: Konisches Übergangsstück
Type - ID-Daten - Typname: Konisches Übergangsstück
Type - IFC-Parameter - Typ in IFC-Datei exportieren: Vorgabe
Description: Konisches Übergangsstück
Pset_DistributionFlowElementCommon - Reference: Konisches Übergangsstück; sets with these values: 2
Andere - Typ: Konisches Übergangsstück; Familie: Konisches Übergangsstück; Familie und Typ: Konisches Übergangsstück: Konisches Übergangsstück; Typ-ID: 2537931
Abhängigkeiten - Höhe von Ebene: 0 m; Verschieben mit umliegenden Elementen: no
Bemaßungen - Fläche: 0.0171762 m2; Volumen: 0.00105566 m3
IFC-Parameter - In IFC-Datei exportieren: Nach Typ; Pset MEP.Tech-Material (ID): 1; In IFC exportieren als: ifcflowfitting; NameOverride: Konisches Übergangsstück; IfcPresentationLayer: 0-TFT-H_Abgasabführung Variante 1; ObjectTypeOverride: Konisches Übergangsstück; Pset MEP.Name: Konisches Übergangsstück; IfcDescription: Konisches Übergangsstück; Pset MEP.Geom-Length (mm): 57; Pset MEP.Abbreviation: USE; Pset MEP.Tech-Medium: L_Entrauchung; Pset MEP.Geom-Offset (mm): 0; Pset MEP.Geom-Ø main (mm): 180; Pset MEP.Geom-Ø secondary (mm): 200
Phasen - Phase erstellt: Phase 01

# IfcFlowFitting: Segmentbogen 2 teilig 620470:Segmentbogen 2 teilig 620470, Segmentbogen 2 teilig
In: Erdgeschoss
Type - Material: IfcSurfaceStyle #251447
Type - Andere - Kategorie: Allgemeines Modell; Familienname: Segmentbogen 2 teilig 620470
Type - ID-Daten - Typname: Segmentbogen 2 teilig 620470
Type - IFC-Parameter - Typ in IFC-Datei exportieren: Vorgabe
Description: Segmentbogen 2 teilig
Pset_DistributionFlowElementCommon - Reference: Segmentbogen 2 teilig 620470; sets with these values: 2
Andere - Typ: Segmentbogen 2 teilig 620470; Familie: Segmentbogen 2 teilig 620470; Familie und Typ: Segmentbogen 2 teilig 620470: Segmentbogen 2 teilig 620470; Typ-ID: 2537987
Abhängigkeiten - Höhe von Ebene: 0 m; Verschieben mit umliegenden Elementen: no
Bemaßungen - Fläche: 0.134003 m2; Volumen: 0.0185922 m3
IFC-Parameter - In IFC-Datei exportieren: Nach Typ; Pset MEP.Geom-Ø (mm): 400; Pset MEP.Tech-Material (ID): 1; Pset MEP.Geom-Radius (mm): 400; Pset MEP.Geom-Angle (°): 30; Pset MEP.Geom-Segment number (if segmented): 2; In IFC exportieren als: ifcflowfitting; NameOverride: Segmentbogen 2 teilig; IfcPresentationLayer: 0-TFT-H_Abgasabführung Variante 1; ObjectTypeOverride: Segmentbogen 2 teilig; Pset MEP.Name: Segmentbogen 2 teilig; IfcDescription: Segmentbogen 2 teilig; Pset MEP.Abbreviation: BSE; Pset MEP.Tech-Medium: L_Entrauchung
Phasen - Phase erstellt: Phase 01

# IfcFlowFitting: Segmentbogen 2 teilig:Segmentbogen 2 teilig, Segmentbogen 2 teilig
In: Erdgeschoss
Type - Material: IfcSurfaceStyle #251447
Type - Andere - Kategorie: Allgemeines Modell; Familienname: Segmentbogen 2 teilig
Type - ID-Daten - Typname: Segmentbogen 2 teilig
Type - IFC-Parameter - Typ in IFC-Datei exportieren: Vorgabe
Description: Segmentbogen 2 teilig
Pset_DistributionFlowElementCommon - Reference: Segmentbogen 2 teilig; sets with these values: 2
Andere - Typ: Segmentbogen 2 teilig; Familie: Segmentbogen 2 teilig; Familie und Typ: Segmentbogen 2 teilig: Segmentbogen 2 teilig; Typ-ID: 2534209
Abhängigkeiten - Höhe von Ebene: 0 m; Verschieben mit umliegenden Elementen: no
Bemaßungen - Fläche: 0.052345 m2; Volumen: 0.00453911 m3
IFC-Parameter - In IFC-Datei exportieren: Nach Typ; Pset MEP.Tech-Material (ID): 1; Pset MEP.Geom-Ø (mm): 250; Pset MEP.Geom-Radius (mm): 250; In IFC exportieren als: ifcflowfitting; NameOverride: Segmentbogen 2 teilig; IfcPresentationLayer: 0-TFT-H_Abgasabführung Variante 2; ObjectTypeOverride: Segmentbogen 2 teilig; Pset MEP.Name: Segmentbogen 2 teilig; IfcDescription: Segmentbogen 2 teilig; Pset MEP.Abbreviation: BSE; Pset MEP.Tech-Medium: L_Entrauchung; Pset MEP.Geom-Angle (°): 30; Pset MEP.Geom-Segment number (if segmented): 2
Phasen - Phase erstellt: Phase 01

# IfcFlowFitting: Segmentbogen 3 teilig 280972:Segmentbogen 3 teilig 280972, Segmentbogen 3 teilig
In: Erdgeschoss
Type - Material: IfcSurfaceStyle #251447
Type - Andere - Kategorie: Allgemeines Modell; Familienname: Segmentbogen 3 teilig 280972
Type - ID-Daten - Typname: Segmentbogen 3 teilig 280972
Type - IFC-Parameter - Typ in IFC-Datei exportieren: Vorgabe
Description: Segmentbogen 3 teilig
Pset_DistributionFlowElementCommon - Reference: Segmentbogen 3 teilig 280972; sets with these values: 2
Andere - Typ: Segmentbogen 3 teilig 280972; Familie: Segmentbogen 3 teilig 280972; Familie und Typ: Segmentbogen 3 teilig 280972: Segmentbogen 3 teilig 280972; Typ-ID: 2534055
Abhängigkeiten - Höhe von Ebene: 0 m; Verschieben mit umliegenden Elementen: no
Bemaßungen - Fläche: 0.268006 m2; Volumen: 0.0386854 m3
IFC-Parameter - In IFC-Datei exportieren: Nach Typ; Pset MEP.Geom-Ø (mm): 400; Pset MEP.Tech-Material (ID): 1; Pset MEP.Geom-Radius (mm): 400; Pset MEP.Geom-Angle (°): 60; Pset MEP.Geom-Segment number (if segmented): 3; In IFC exportieren als: ifcflowfitting; NameOverride: Segmentbogen 3 teilig; IfcPresentationLayer: 0-TFT-H_Abgasabführung Variante 2; ObjectTypeOverride: Segmentbogen 3 teilig; Pset MEP.Name: Segmentbogen 3 teilig; IfcDescription: Segmentbogen 3 teilig; Pset MEP.Abbreviation: BSE; Pset MEP.Tech-Medium: L_Entrauchung
Phasen - Phase erstellt: Phase 01

# IfcFlowFitting: Segmentbogen 3 teilig 281600:Segmentbogen 3 teilig 281600, Segmentbogen 3 teilig
In: Erdgeschoss
Type - Material: IfcSurfaceStyle #251447
Type - Andere - Kategorie: Allgemeines Modell; Familienname: Segmentbogen 3 teilig 281600
Type - ID-Daten - Typname: Segmentbogen 3 teilig 281600
Type - IFC-Parameter - Typ in IFC-Datei exportieren: Vorgabe
Description: Segmentbogen 3 teilig
Pset_DistributionFlowElementCommon - Reference: Segmentbogen 3 teilig 281600; sets with these values: 2
Andere - Typ: Segmentbogen 3 teilig 281600; Familie: Segmentbogen 3 teilig 281600; Familie und Typ: Segmentbogen 3 teilig 281600: Segmentbogen 3 teilig 281600; Typ-ID: 2534125
Abhängigkeiten - Höhe von Ebene: 0 m; Verschieben mit umliegenden Elementen: no
Bemaßungen - Fläche: 0.268006 m2; Volumen: 0.0386854 m3
IFC-Parameter - In IFC-Datei exportieren: Nach Typ; Pset MEP.Geom-Ø (mm): 400; Pset MEP.Tech-Material (ID): 1; Pset MEP.Geom-Radius (mm): 400; Pset MEP.Geom-Angle (°): 60; Pset MEP.Geom-Segment number (if segmented): 3; In IFC exportieren als: ifcflowfitting; NameOverride: Segmentbogen 3 teilig; IfcPresentationLayer: 0-TFT-H_Abgasabführung Variante 2; ObjectTypeOverride: Segmentbogen 3 teilig; Pset MEP.Name: Segmentbogen 3 teilig; IfcDescription: Segmentbogen 3 teilig; Pset MEP.Abbreviation: BSE; Pset MEP.Tech-Medium: L_Entrauchung
Phasen - Phase erstellt: Phase 01

# IfcFlowFitting: Segmentbogen 3 teilig 284191:Segmentbogen 3 teilig 284191, Segmentbogen 3 teilig
In: Erdgeschoss
Type - Material: IfcSurfaceStyle #251447
Type - Andere - Kategorie: Allgemeines Modell; Familienname: Segmentbogen 3 teilig 284191
Type - ID-Daten - Typname: Segmentbogen 3 teilig 284191
Type - IFC-Parameter - Typ in IFC-Datei exportieren: Vorgabe
Description: Segmentbogen 3 teilig
Pset_DistributionFlowElementCommon - Reference: Segmentbogen 3 teilig 284191; sets with these values: 2
Andere - Typ: Segmentbogen 3 teilig 284191; Familie: Segmentbogen 3 teilig 284191; Familie und Typ: Segmentbogen 3 teilig 284191: Segmentbogen 3 teilig 284191; Typ-ID: 2534223
Abhängigkeiten - Höhe von Ebene: 0 m; Verschieben mit umliegenden Elementen: no
Bemaßungen - Fläche: 0.10469 m2; Volumen: 0.00944467 m3
IFC-Parameter - In IFC-Datei exportieren: Nach Typ; Pset MEP.Tech-Material (ID): 1; Pset MEP.Geom-Angle (°): 60; Pset MEP.Geom-Segment number (if segmented): 3; Pset MEP.Geom-Ø (mm): 250; Pset MEP.Geom-Radius (mm): 250; In IFC exportieren als: ifcflowfitting; NameOverride: Segmentbogen 3 teilig; IfcPresentationLayer: 0-TFT-H_Abgasabführung Variante 2; ObjectTypeOverride: Segmentbogen 3 teilig; Pset MEP.Name: Segmentbogen 3 teilig; IfcDescription: Segmentbogen 3 teilig; Pset MEP.Abbreviation: BSE; Pset MEP.Tech-Medium: L_Entrauchung
Phasen - Phase erstellt: Phase 01

# IfcFlowFitting: Segmentbogen 3 teilig 293769:Segmentbogen 3 teilig 293769, Segmentbogen 3 teilig
In: Erdgeschoss
Type - Material: IfcSurfaceStyle #251447
Type - Andere - Kategorie: Allgemeines Modell; Familienname: Segmentbogen 3 teilig 293769
Type - ID-Daten - Typname: Segmentbogen 3 teilig 293769
Type - IFC-Parameter - Typ in IFC-Datei exportieren: Vorgabe
Description: Segmentbogen 3 teilig
Pset_DistributionFlowElementCommon - Reference: Segmentbogen 3 teilig 293769; sets with these values: 2
Andere - Typ: Segmentbogen 3 teilig 293769; Familie: Segmentbogen 3 teilig 293769; Familie und Typ: Segmentbogen 3 teilig 293769: Segmentbogen 3 teilig 293769; Typ-ID: 2534445
Abhängigkeiten - Höhe von Ebene: 0 m; Verschieben mit umliegenden Elementen: no
Bemaßungen - Fläche: 0.10469 m2; Volumen: 0.00944467 m3
IFC-Parameter - In IFC-Datei exportieren: Nach Typ; Pset MEP.Tech-Material (ID): 1; Pset MEP.Geom-Angle (°): 60; Pset MEP.Geom-Segment number (if segmented): 3; Pset MEP.Geom-Ø (mm): 250; Pset MEP.Geom-Radius (mm): 250; In IFC exportieren als: ifcflowfitting; NameOverride: Segmentbogen 3 teilig; IfcPresentationLayer: 0-TFT-H_Abgasabführung Variante 3; ObjectTypeOverride: Segmentbogen 3 teilig; Pset MEP.Name: Segmentbogen 3 teilig; IfcDescription: Segmentbogen 3 teilig; Pset MEP.Abbreviation: BSE; Pset MEP.Tech-Medium: L_Entrauchung
Phasen - Phase erstellt: Phase 01

# IfcFlowFitting: Segmentbogen 3 teilig 294636:Segmentbogen 3 teilig 294636, Segmentbogen 3 teilig
In: Erdgeschoss
Type - Material: IfcSurfaceStyle #251447
Type - Andere - Kategorie: Allgemeines Modell; Familienname: Segmentbogen 3 teilig 294636
Type - ID-Daten - Typname: Segmentbogen 3 teilig 294636
Type - IFC-Parameter - Typ in IFC-Datei exportieren: Vorgabe
Description: Segmentbogen 3 teilig
Pset_DistributionFlowElementCommon - Reference: Segmentbogen 3 teilig 294636; sets with these values: 2
Andere - Typ: Segmentbogen 3 teilig 294636; Familie: Segmentbogen 3 teilig 294636; Familie und Typ: Segmentbogen 3 teilig 294636: Segmentbogen 3 teilig 294636; Typ-ID: 2534508
Abhängigkeiten - Höhe von Ebene: 0 m; Verschieben mit umliegenden Elementen: no
Bemaßungen - Fläche: 0.268006 m2; Volumen: 0.0386854 m3
IFC-Parameter - In IFC-Datei exportieren: Nach Typ; Pset MEP.Geom-Ø (mm): 400; Pset MEP.Tech-Material (ID): 1; Pset MEP.Geom-Radius (mm): 400; Pset MEP.Geom-Angle (°): 60; Pset MEP.Geom-Segment number (if segmented): 3; In IFC exportieren als: ifcflowfitting; NameOverride: Segmentbogen 3 teilig; IfcPresentationLayer: 0-TFT-H_Abgasabführung Variante 3; ObjectTypeOverride: Segmentbogen 3 teilig; Pset MEP.Name: Segmentbogen 3 teilig; IfcDescription: Segmentbogen 3 teilig; Pset MEP.Abbreviation: BSE; Pset MEP.Tech-Medium: L_Entrauchung
Phasen - Phase erstellt: Phase 01

# IfcFlowFitting: Segmentbogen 3 teilig 295093:Segmentbogen 3 teilig 295093, Segmentbogen 3 teilig
In: Erdgeschoss
Type - Material: IfcSurfaceStyle #251447
Type - Andere - Kategorie: Allgemeines Modell; Familienname: Segmentbogen 3 teilig 295093
Type - ID-Daten - Typname: Segmentbogen 3 teilig 295093
Type - IFC-Parameter - Typ in IFC-Datei exportieren: Vorgabe
Description: Segmentbogen 3 teilig
Pset_DistributionFlowElementCommon - Reference: Segmentbogen 3 teilig 295093; sets with these values: 2
Andere - Typ: Segmentbogen 3 teilig 295093; Familie: Segmentbogen 3 teilig 295093; Familie und Typ: Segmentbogen 3 teilig 295093: Segmentbogen 3 teilig 295093; Typ-ID: 2534543
Abhängigkeiten - Höhe von Ebene: 0 m; Verschieben mit umliegenden Elementen: no
Bemaßungen - Fläche: 0.268006 m2; Volumen: 0.0386854 m3
IFC-Parameter - In IFC-Datei exportieren: Nach Typ; Pset MEP.Geom-Ø (mm): 400; Pset MEP.Tech-Material (ID): 1; Pset MEP.Geom-Radius (mm): 400; Pset MEP.Geom-Angle (°): 60; Pset MEP.Geom-Segment number (if segmented): 3; In IFC exportieren als: ifcflowfitting; NameOverride: Segmentbogen 3 teilig; IfcPresentationLayer: 0-TFT-H_Abgasabführung Variante 3; ObjectTypeOverride: Segmentbogen 3 teilig; Pset MEP.Name: Segmentbogen 3 teilig; IfcDescription: Segmentbogen 3 teilig; Pset MEP.Abbreviation: BSE; Pset MEP.Tech-Medium: L_Entrauchung
Phasen - Phase erstellt: Phase 01

# IfcFlowFitting: Segmentbogen 3 teilig 295357:Segmentbogen 3 teilig 295357, Segmentbogen 3 teilig
In: Erdgeschoss
Type - Material: IfcSurfaceStyle #251447
Type - Andere - Kategorie: Allgemeines Modell; Familienname: Segmentbogen 3 teilig 295357
Type - ID-Daten - Typname: Segmentbogen 3 teilig 295357
Type - IFC-Parameter - Typ in IFC-Datei exportieren: Vorgabe
Description: Segmentbogen 3 teilig
Pset_DistributionFlowElementCommon - Reference: Segmentbogen 3 teilig 295357; sets with these values: 2
Andere - Typ: Segmentbogen 3 teilig 295357; Familie: Segmentbogen 3 teilig 295357; Familie und Typ: Segmentbogen 3 teilig 295357: Segmentbogen 3 teilig 295357; Typ-ID: 2534585
Abhängigkeiten - Höhe von Ebene: 0 m; Verschieben mit umliegenden Elementen: no
Bemaßungen - Fläche: 0.198955 m2; Volumen: 0.0280923 m3
IFC-Parameter - In IFC-Datei exportieren: Nach Typ; Pset MEP.Geom-Ø (mm): 400; Pset MEP.Tech-Material (ID): 1; Pset MEP.Geom-Radius (mm): 400; Pset MEP.Geom-Segment number (if segmented): 3; In IFC exportieren als: ifcflowfitting; NameOverride: Segmentbogen 3 teilig; IfcPresentationLayer: 0-TFT-H_Abgasabführung Variante 3; ObjectTypeOverride: Segmentbogen 3 teilig; Pset MEP.Name: Segmentbogen 3 teilig; IfcDescription: Segmentbogen 3 teilig; Pset MEP.Abbreviation: BSE; Pset MEP.Tech-Medium: L_Entrauchung; Pset MEP.Geom-Angle (°): 45
Phasen - Phase erstellt: Phase 01

# IfcFlowFitting: Segmentbogen 3 teilig 296050:Segmentbogen 3 teilig 296050, Segmentbogen 3 teilig
In: Erdgeschoss
Type - Material: IfcSurfaceStyle #251447
Type - Andere - Kategorie: Allgemeines Modell; Familienname: Segmentbogen 3 teilig 296050
Type - ID-Daten - Typname: Segmentbogen 3 teilig 296050
Type - IFC-Parameter - Typ in IFC-Datei exportieren: Vorgabe
Description: Segmentbogen 3 teilig
Pset_DistributionFlowElementCommon - Reference: Segmentbogen 3 teilig 296050; sets with these values: 2
Andere - Typ: Segmentbogen 3 teilig 296050; Familie: Segmentbogen 3 teilig 296050; Familie und Typ: Segmentbogen 3 teilig 296050: Segmentbogen 3 teilig 296050; Typ-ID: 2534627
Abhängigkeiten - Höhe von Ebene: 0 m; Verschieben mit umliegenden Elementen: no
Bemaßungen - Fläche: 0.198955 m2; Volumen: 0.0280923 m3
IFC-Parameter - In IFC-Datei exportieren: Nach Typ; Pset MEP.Geom-Ø (mm): 400; Pset MEP.Tech-Material (ID): 1; Pset MEP.Geom-Radius (mm): 400; Pset MEP.Geom-Segment number (if segmented): 3; Pset MEP.Geom-Angle (°): 45; In IFC exportieren als: ifcflowfitting; NameOverride: Segmentbogen 3 teilig; IfcPresentationLayer: 0-TFT-H_Abgasabführung Variante 3; ObjectTypeOverride: Segmentbogen 3 teilig; Pset MEP.Name: Segmentbogen 3 teilig; IfcDescription: Segmentbogen 3 teilig; Pset MEP.Abbreviation: BSE; Pset MEP.Tech-Medium: L_Entrauchung
Phasen - Phase erstellt: Phase 01

# IfcFlowFitting: Segmentbogen 3 teilig 296588:Segmentbogen 3 teilig 296588, Segmentbogen 3 teilig
In: Erdgeschoss
Type - Material: IfcSurfaceStyle #251447
Type - Andere - Kategorie: Allgemeines Modell; Familienname: Segmentbogen 3 teilig 296588
Type - ID-Daten - Typname: Segmentbogen 3 teilig 296588
Type - IFC-Parameter - Typ in IFC-Datei exportieren: Vorgabe
Description: Segmentbogen 3 teilig
Pset_DistributionFlowElementCommon - Reference: Segmentbogen 3 teilig 296588; sets with these values: 2
Andere - Typ: Segmentbogen 3 teilig 296588; Familie: Segmentbogen 3 teilig 296588; Familie und Typ: Segmentbogen 3 teilig 296588: Segmentbogen 3 teilig 296588; Typ-ID: 2534669
Abhängigkeiten - Höhe von Ebene: 0 m; Verschieben mit umliegenden Elementen: no
Bemaßungen - Fläche: 0.268006 m2; Volumen: 0.0386854 m3
IFC-Parameter - In IFC-Datei exportieren: Nach Typ; Pset MEP.Geom-Ø (mm): 400; Pset MEP.Tech-Material (ID): 1; Pset MEP.Geom-Radius (mm): 400; Pset MEP.Geom-Angle (°): 60; Pset MEP.Geom-Segment number (if segmented): 3; In IFC exportieren als: ifcflowfitting; NameOverride: Segmentbogen 3 teilig; IfcPresentationLayer: 0-TFT-H_Abgasabführung Variante 3; ObjectTypeOverride: Segmentbogen 3 teilig; Pset MEP.Name: Segmentbogen 3 teilig; IfcDescription: Segmentbogen 3 teilig; Pset MEP.Abbreviation: BSE; Pset MEP.Tech-Medium: L_Entrauchung
Phasen - Phase erstellt: Phase 01

# IfcFlowFitting: Segmentbogen 3 teilig 618862:Segmentbogen 3 teilig 618862, Segmentbogen 3 teilig
In: Erdgeschoss
Type - Material: IfcSurfaceStyle #251447
Type - Andere - Kategorie: Allgemeines Modell; Familienname: Segmentbogen 3 teilig 618862
Type - ID-Daten - Typname: Segmentbogen 3 teilig 618862
Type - IFC-Parameter - Typ in IFC-Datei exportieren: Vorgabe
Description: Segmentbogen 3 teilig
Pset_DistributionFlowElementCommon - Reference: Segmentbogen 3 teilig 618862; sets with these values: 2
Andere - Typ: Segmentbogen 3 teilig 618862; Familie: Segmentbogen 3 teilig 618862; Familie und Typ: Segmentbogen 3 teilig 618862: Segmentbogen 3 teilig 618862; Typ-ID: 2537892
Abhängigkeiten - Höhe von Ebene: 0 m; Verschieben mit umliegenden Elementen: no
Bemaßungen - Fläche: 0.0497387 m2; Volumen: 0.00351153 m3
IFC-Parameter - In IFC-Datei exportieren: Nach Typ; Pset MEP.Tech-Material (ID): 1; Pset MEP.Geom-Ø (mm): 200; Pset MEP.Geom-Segment number (if segmented): 3; Pset MEP.Geom-Angle (°): 45; Pset MEP.Geom-Radius (mm): 200; In IFC exportieren als: ifcflowfitting; NameOverride: Segmentbogen 3 teilig; IfcPresentationLayer: 0-TFT-H_Abgasabführung Variante 1; ObjectTypeOverride: Segmentbogen 3 teilig; Pset MEP.Name: Segmentbogen 3 teilig; IfcDescription: Segmentbogen 3 teilig; Pset MEP.Abbreviation: BSE; Pset MEP.Tech-Medium: L_Entrauchung
Phasen - Phase erstellt: Phase 01

# IfcFlowFitting: Segmentbogen 3 teilig 619455:Segmentbogen 3 teilig 619455, Segmentbogen 3 teilig
In: Erdgeschoss
Type - Material: IfcSurfaceStyle #251447
Type - Andere - Kategorie: Allgemeines Modell; Familienname: Segmentbogen 3 teilig 619455
Type - ID-Daten - Typname: Segmentbogen 3 teilig 619455
Type - IFC-Parameter - Typ in IFC-Datei exportieren: Vorgabe
Description: Segmentbogen 3 teilig
Pset_DistributionFlowElementCommon - Reference: Segmentbogen 3 teilig 619455; sets with these values: 2
Andere - Typ: Segmentbogen 3 teilig 619455; Familie: Segmentbogen 3 teilig 619455; Familie und Typ: Segmentbogen 3 teilig 619455: Segmentbogen 3 teilig 619455; Typ-ID: 2537906
Abhängigkeiten - Höhe von Ebene: 0 m; Verschieben mit umliegenden Elementen: no
Bemaßungen - Fläche: 0.0497387 m2; Volumen: 0.00351153 m3
IFC-Parameter - In IFC-Datei exportieren: Nach Typ; Pset MEP.Tech-Material (ID): 1; Pset MEP.Geom-Ø (mm): 200; Pset MEP.Geom-Segment number (if segmented): 3; Pset MEP.Geom-Angle (°): 45; Pset MEP.Geom-Radius (mm): 200; In IFC exportieren als: ifcflowfitting; NameOverride: Segmentbogen 3 teilig; IfcPresentationLayer: 0-TFT-H_Abgasabführung Variante 1; ObjectTypeOverride: Segmentbogen 3 teilig; Pset MEP.Name: Segmentbogen 3 teilig; IfcDescription: Segmentbogen 3 teilig; Pset MEP.Abbreviation: BSE; Pset MEP.Tech-Medium: L_Entrauchung
Phasen - Phase erstellt: Phase 01

# IfcFlowFitting: Segmentbogen 3 teilig 620877:Segmentbogen 3 teilig 620877, Segmentbogen 3 teilig
In: Erdgeschoss
Type - Material: IfcSurfaceStyle #251447
Type - Andere - Kategorie: Allgemeines Modell; Familienname: Segmentbogen 3 teilig 620877
Type - ID-Daten - Typname: Segmentbogen 3 teilig 620877
Type - IFC-Parameter - Typ in IFC-Datei exportieren: Vorgabe
Description: Segmentbogen 3 teilig
Pset_DistributionFlowElementCommon - Reference: Segmentbogen 3 teilig 620877; sets with these values: 2
Andere - Typ: Segmentbogen 3 teilig 620877; Familie: Segmentbogen 3 teilig 620877; Familie und Typ: Segmentbogen 3 teilig 620877: Segmentbogen 3 teilig 620877; Typ-ID: 2538029
Abhängigkeiten - Höhe von Ebene: 0 m; Verschieben mit umliegenden Elementen: no
Bemaßungen - Fläche: 0.198955 m2; Volumen: 0.0280923 m3
IFC-Parameter - In IFC-Datei exportieren: Nach Typ; Pset MEP.Geom-Ø (mm): 400; Pset MEP.Tech-Material (ID): 1; Pset MEP.Geom-Radius (mm): 400; Pset MEP.Geom-Segment number (if segmented): 3; Pset MEP.Geom-Angle (°): 45; In IFC exportieren als: ifcflowfitting; NameOverride: Segmentbogen 3 teilig; IfcPresentationLayer: 0-TFT-H_Abgasabführung Variante 1; ObjectTypeOverride: Segmentbogen 3 teilig; Pset MEP.Name: Segmentbogen 3 teilig; IfcDescription: Segmentbogen 3 teilig; Pset MEP.Abbreviation: BSE; Pset MEP.Tech-Medium: L_Entrauchung
Phasen - Phase erstellt: Phase 01

# IfcFlowFitting: Segmentbogen 3 teilig 621520:Segmentbogen 3 teilig 621520, Segmentbogen 3 teilig
In: Erdgeschoss
Type - Material: IfcSurfaceStyle #251447
Type - Andere - Kategorie: Allgemeines Modell; Familienname: Segmentbogen 3 teilig 621520
Type - ID-Daten - Typname: Segmentbogen 3 teilig 621520
Type - IFC-Parameter - Typ in IFC-Datei exportieren: Vorgabe
Description: Segmentbogen 3 teilig
Pset_DistributionFlowElementCommon - Reference: Segmentbogen 3 teilig 621520; sets with these values: 2
Andere - Typ: Segmentbogen 3 teilig 621520; Familie: Segmentbogen 3 teilig 621520; Familie und Typ: Segmentbogen 3 teilig 621520: Segmentbogen 3 teilig 621520; Typ-ID: 2538064
Abhängigkeiten - Höhe von Ebene: 0 m; Verschieben mit umliegenden Elementen: no
Bemaßungen - Fläche: 0.198955 m2; Volumen: 0.0280923 m3
IFC-Parameter - In IFC-Datei exportieren: Nach Typ; Pset MEP.Geom-Ø (mm): 400; Pset MEP.Tech-Material (ID): 1; Pset MEP.Geom-Radius (mm): 400; Pset MEP.Geom-Segment number (if segmented): 3; Pset MEP.Geom-Angle (°): 45; In IFC exportieren als: ifcflowfitting; NameOverride: Segmentbogen 3 teilig; IfcPresentationLayer: 0-TFT-H_Abgasabführung Variante 1; ObjectTypeOverride: Segmentbogen 3 teilig; Pset MEP.Name: Segmentbogen 3 teilig; IfcDescription: Segmentbogen 3 teilig; Pset MEP.Abbreviation: BSE; Pset MEP.Tech-Medium: L_Entrauchung
Phasen - Phase erstellt: Phase 01

# IfcFlowFitting: Segmentbogen 3 teilig:Segmentbogen 3 teilig, Segmentbogen 3 teilig
In: Erdgeschoss
Type - Material: IfcSurfaceStyle #251447
Type - Andere - Kategorie: Allgemeines Modell; Familienname: Segmentbogen 3 teilig
Type - ID-Daten - Typname: Segmentbogen 3 teilig
Type - IFC-Parameter - Typ in IFC-Datei exportieren: Vorgabe
Description: Segmentbogen 3 teilig
Pset_DistributionFlowElementCommon - Reference: Segmentbogen 3 teilig; sets with these values: 2
Andere - Typ: Segmentbogen 3 teilig; Familie: Segmentbogen 3 teilig; Familie und Typ: Segmentbogen 3 teilig: Segmentbogen 3 teilig; Typ-ID: 2533992
Abhängigkeiten - Höhe von Ebene: 0 m; Verschieben mit umliegenden Elementen: no
Bemaßungen - Fläche: 0.268006 m2; Volumen: 0.0386854 m3
IFC-Parameter - In IFC-Datei exportieren: Nach Typ; Pset MEP.Geom-Ø (mm): 400; Pset MEP.Tech-Material (ID): 1; Pset MEP.Geom-Radius (mm): 400; In IFC exportieren als: ifcflowfitting; NameOverride: Segmentbogen 3 teilig; IfcPresentationLayer: 0-TFT-H_Abgasabführung Variante 2; ObjectTypeOverride: Segmentbogen 3 teilig; Pset MEP.Name: Segmentbogen 3 teilig; IfcDescription: Segmentbogen 3 teilig; Pset MEP.Abbreviation: BSE; Pset MEP.Tech-Medium: L_Entrauchung; Pset MEP.Geom-Angle (°): 60; Pset MEP.Geom-Segment number (if segmented): 3
Phasen - Phase erstellt: Phase 01

# IfcFlowFitting: Segmentbogen 4 teilig 278884:Segmentbogen 4 teilig 278884, Segmentbogen 4 teilig
In: Erdgeschoss
Type - Material: IfcSurfaceStyle #251447
Type - Andere - Kategorie: Allgemeines Modell; Familienname: Segmentbogen 4 teilig 278884
Type - ID-Daten - Typname: Segmentbogen 4 teilig 278884
Type - IFC-Parameter - Typ in IFC-Datei exportieren: Vorgabe
Description: Segmentbogen 4 teilig
Pset_DistributionFlowElementCommon - Reference: Segmentbogen 4 teilig 278884; sets with these values: 2
Andere - Typ: Segmentbogen 4 teilig 278884; Familie: Segmentbogen 4 teilig 278884; Familie und Typ: Segmentbogen 4 teilig 278884: Segmentbogen 4 teilig 278884; Typ-ID: 2533950
Abhängigkeiten - Höhe von Ebene: 0 m; Verschieben mit umliegenden Elementen: no
Bemaßungen - Fläche: 0.40201 m2; Volumen: 0.0619677 m3
IFC-Parameter - In IFC-Datei exportieren: Nach Typ; Pset MEP.Geom-Ø (mm): 400; Pset MEP.Tech-Material (ID): 1; Pset MEP.Geom-Angle (°): 90; Pset MEP.Geom-Segment number (if segmented): 4; In IFC exportieren als: ifcflowfitting; NameOverride: Segmentbogen 4 teilig; IfcPresentationLayer: 0-TFT-H_Abgasabführung Variante 1; ObjectTypeOverride: Segmentbogen 4 teilig; Pset MEP.Name: Segmentbogen 4 teilig; IfcDescription: Segmentbogen 4 teilig; Pset MEP.Abbreviation: BSE; Pset MEP.Tech-Medium: L_Entrauchung; Pset MEP.Geom-Radius (mm): 400
Phasen - Phase erstellt: Phase 01

# IfcFlowFitting: Segmentbogen 4 teilig 279474:Segmentbogen 4 teilig 279474, Segmentbogen 4 teilig
In: Erdgeschoss
Type - Material: IfcSurfaceStyle #251447
Type - Andere - Kategorie: Allgemeines Modell; Familienname: Segmentbogen 4 teilig 279474
Type - ID-Daten - Typname: Segmentbogen 4 teilig 279474
Type - IFC-Parameter - Typ in IFC-Datei exportieren: Vorgabe
Description: Segmentbogen 4 teilig
Pset_DistributionFlowElementCommon - Reference: Segmentbogen 4 teilig 279474; sets with these values: 2
Andere - Typ: Segmentbogen 4 teilig 279474; Familie: Segmentbogen 4 teilig 279474; Familie und Typ: Segmentbogen 4 teilig 279474: Segmentbogen 4 teilig 279474; Typ-ID: 2533964
Abhängigkeiten - Höhe von Ebene: 0 m; Verschieben mit umliegenden Elementen: no
Bemaßungen - Fläche: 0.40201 m2; Volumen: 0.0619677 m3
IFC-Parameter - In IFC-Datei exportieren: Nach Typ; Pset MEP.Geom-Ø (mm): 400; Pset MEP.Tech-Material (ID): 1; Pset MEP.Geom-Angle (°): 90; Pset MEP.Geom-Segment number (if segmented): 4; Pset MEP.Geom-Radius (mm): 400; In IFC exportieren als: ifcflowfitting; NameOverride: Segmentbogen 4 teilig; IfcPresentationLayer: 0-TFT-H_Abgasabführung Variante 2; ObjectTypeOverride: Segmentbogen 4 teilig; Pset MEP.Name: Segmentbogen 4 teilig; IfcDescription: Segmentbogen 4 teilig; Pset MEP.Abbreviation: BSE; Pset MEP.Tech-Medium: L_Entrauchung
Phasen - Phase erstellt: Phase 01

# IfcFlowFitting: Segmentbogen 4 teilig 279497:Segmentbogen 4 teilig 279497, Segmentbogen 4 teilig
In: Erdgeschoss
Type - Material: IfcSurfaceStyle #251447
Type - Andere - Kategorie: Allgemeines Modell; Familienname: Segmentbogen 4 teilig 279497
Type - ID-Daten - Typname: Segmentbogen 4 teilig 279497
Type - IFC-Parameter - Typ in IFC-Datei exportieren: Vorgabe
Description: Segmentbogen 4 teilig
Pset_DistributionFlowElementCommon - Reference: Segmentbogen 4 teilig 279497; sets with these values: 2
Andere - Typ: Segmentbogen 4 teilig 279497; Familie: Segmentbogen 4 teilig 279497; Familie und Typ: Segmentbogen 4 teilig 279497: Segmentbogen 4 teilig 279497; Typ-ID: 2533971
Abhängigkeiten - Höhe von Ebene: 0 m; Verschieben mit umliegenden Elementen: no
Bemaßungen - Fläche: 0.40201 m2; Volumen: 0.0619677 m3
IFC-Parameter - In IFC-Datei exportieren: Nach Typ; Pset MEP.Geom-Ø (mm): 400; Pset MEP.Tech-Material (ID): 1; Pset MEP.Geom-Angle (°): 90; Pset MEP.Geom-Segment number (if segmented): 4; Pset MEP.Geom-Radius (mm): 400; In IFC exportieren als: ifcflowfitting; NameOverride: Segmentbogen 4 teilig; IfcPresentationLayer: 0-TFT-H_Abgasabführung Variante 2; ObjectTypeOverride: Segmentbogen 4 teilig; Pset MEP.Name: Segmentbogen 4 teilig; IfcDescription: Segmentbogen 4 teilig; Pset MEP.Abbreviation: BSE; Pset MEP.Tech-Medium: L_Entrauchung
Phasen - Phase erstellt: Phase 01

# IfcFlowFitting: Segmentbogen 4 teilig 280394:Segmentbogen 4 teilig 280394, Segmentbogen 4 teilig
In: Erdgeschoss
Type - Material: IfcSurfaceStyle #251447
Type - Andere - Kategorie: Allgemeines Modell; Familienname: Segmentbogen 4 teilig 280394
Type - ID-Daten - Typname: Segmentbogen 4 teilig 280394
Type - IFC-Parameter - Typ in IFC-Datei exportieren: Vorgabe
Description: Segmentbogen 4 teilig
Pset_DistributionFlowElementCommon - Reference: Segmentbogen 4 teilig 280394; sets with these values: 2
Andere - Typ: Segmentbogen 4 teilig 280394; Familie: Segmentbogen 4 teilig 280394; Familie und Typ: Segmentbogen 4 teilig 280394: Segmentbogen 4 teilig 280394; Typ-ID: 2533999
Abhängigkeiten - Höhe von Ebene: 0 m; Verschieben mit umliegenden Elementen: no
Bemaßungen - Fläche: 0.40201 m2; Volumen: 0.0619677 m3
IFC-Parameter - In IFC-Datei exportieren: Nach Typ; Pset MEP.Geom-Ø (mm): 400; Pset MEP.Tech-Material (ID): 1; Pset MEP.Geom-Angle (°): 90; Pset MEP.Geom-Segment number (if segmented): 4; Pset MEP.Geom-Radius (mm): 400; In IFC exportieren als: ifcflowfitting; NameOverride: Segmentbogen 4 teilig; IfcPresentationLayer: 0-TFT-H_Abgasabführung Variante 2; ObjectTypeOverride: Segmentbogen 4 teilig; Pset MEP.Name: Segmentbogen 4 teilig; IfcDescription: Segmentbogen 4 teilig; Pset MEP.Abbreviation: BSE; Pset MEP.Tech-Medium: L_Entrauchung
Phasen - Phase erstellt: Phase 01

# IfcFlowFitting: Segmentbogen 4 teilig 280750:Segmentbogen 4 teilig 280750, Segmentbogen 4 teilig
In: Erdgeschoss
Type - Material: IfcSurfaceStyle #251447
Type - Andere - Kategorie: Allgemeines Modell; Familienname: Segmentbogen 4 teilig 280750
Type - ID-Daten - Typname: Segmentbogen 4 teilig 280750
Type - IFC-Parameter - Typ in IFC-Datei exportieren: Vorgabe
Description: Segmentbogen 4 teilig
Pset_DistributionFlowElementCommon - Reference: Segmentbogen 4 teilig 280750; sets with these values: 2
Andere - Typ: Segmentbogen 4 teilig 280750; Familie: Segmentbogen 4 teilig 280750; Familie und Typ: Segmentbogen 4 teilig 280750: Segmentbogen 4 teilig 280750; Typ-ID: 2534027
Abhängigkeiten - Höhe von Ebene: 0 m; Verschieben mit umliegenden Elementen: no
Bemaßungen - Fläche: 0.40201 m2; Volumen: 0.0619677 m3
IFC-Parameter - In IFC-Datei exportieren: Nach Typ; Pset MEP.Geom-Ø (mm): 400; Pset MEP.Tech-Material (ID): 1; Pset MEP.Geom-Angle (°): 90; Pset MEP.Geom-Segment number (if segmented): 4; Pset MEP.Geom-Radius (mm): 400; In IFC exportieren als: ifcflowfitting; NameOverride: Segmentbogen 4 teilig; IfcPresentationLayer: 0-TFT-H_Abgasabführung Variante 2; ObjectTypeOverride: Segmentbogen 4 teilig; Pset MEP.Name: Segmentbogen 4 teilig; IfcDescription: Segmentbogen 4 teilig; Pset MEP.Abbreviation: BSE; Pset MEP.Tech-Medium: L_Entrauchung
Phasen - Phase erstellt: Phase 01

# IfcFlowFitting: Segmentbogen 4 teilig 280773:Segmentbogen 4 teilig 280773, Segmentbogen 4 teilig
In: Erdgeschoss
Type - Material: IfcSurfaceStyle #251447
Type - Andere - Kategorie: Allgemeines Modell; Familienname: Segmentbogen 4 teilig 280773
Type - ID-Daten - Typname: Segmentbogen 4 teilig 280773
Type - IFC-Parameter - Typ in IFC-Datei exportieren: Vorgabe
Description: Segmentbogen 4 teilig
Pset_DistributionFlowElementCommon - Reference: Segmentbogen 4 teilig 280773; sets with these values: 2
Andere - Typ: Segmentbogen 4 teilig 280773; Familie: Segmentbogen 4 teilig 280773; Familie und Typ: Segmentbogen 4 teilig 280773: Segmentbogen 4 teilig 280773; Typ-ID: 2534034
Abhängigkeiten - Höhe von Ebene: 0 m; Verschieben mit umliegenden Elementen: no
Bemaßungen - Fläche: 0.40201 m2; Volumen: 0.0619677 m3
IFC-Parameter - In IFC-Datei exportieren: Nach Typ; Pset MEP.Geom-Ø (mm): 400; Pset MEP.Tech-Material (ID): 1; Pset MEP.Geom-Angle (°): 90; Pset MEP.Geom-Segment number (if segmented): 4; Pset MEP.Geom-Radius (mm): 400; In IFC exportieren als: ifcflowfitting; NameOverride: Segmentbogen 4 teilig; IfcPresentationLayer: 0-TFT-H_Abgasabführung Variante 2; ObjectTypeOverride: Segmentbogen 4 teilig; Pset MEP.Name: Segmentbogen 4 teilig; IfcDescription: Segmentbogen 4 teilig; Pset MEP.Abbreviation: BSE; Pset MEP.Tech-Medium: L_Entrauchung
Phasen - Phase erstellt: Phase 01

# IfcFlowFitting: Segmentbogen 4 teilig 281152:Segmentbogen 4 teilig 281152, Segmentbogen 4 teilig
In: Erdgeschoss
Type - Material: IfcSurfaceStyle #251447
Type - Andere - Kategorie: Allgemeines Modell; Familienname: Segmentbogen 4 teilig 281152
Type - ID-Daten - Typname: Segmentbogen 4 teilig 281152
Type - IFC-Parameter - Typ in IFC-Datei exportieren: Vorgabe
Description: Segmentbogen 4 teilig
Pset_DistributionFlowElementCommon - Reference: Segmentbogen 4 teilig 281152; sets with these values: 2
Andere - Typ: Segmentbogen 4 teilig 281152; Familie: Segmentbogen 4 teilig 281152; Familie und Typ: Segmentbogen 4 teilig 281152: Segmentbogen 4 teilig 281152; Typ-ID: 2534069
Abhängigkeiten - Höhe von Ebene: 0 m; Verschieben mit umliegenden Elementen: no
Bemaßungen - Fläche: 0.40201 m2; Volumen: 0.0619677 m3
IFC-Parameter - In IFC-Datei exportieren: Nach Typ; Pset MEP.Geom-Ø (mm): 400; Pset MEP.Tech-Material (ID): 1; Pset MEP.Geom-Angle (°): 90; Pset MEP.Geom-Segment number (if segmented): 4; Pset MEP.Geom-Radius (mm): 400; In IFC exportieren als: ifcflowfitting; NameOverride: Segmentbogen 4 teilig; IfcPresentationLayer: 0-TFT-H_Abgasabführung Variante 2; ObjectTypeOverride: Segmentbogen 4 teilig; Pset MEP.Name: Segmentbogen 4 teilig; IfcDescription: Segmentbogen 4 teilig; Pset MEP.Abbreviation: BSE; Pset MEP.Tech-Medium: L_Entrauchung
Phasen - Phase erstellt: Phase 01

# IfcFlowFitting: Segmentbogen 4 teilig 281376:Segmentbogen 4 teilig 281376, Segmentbogen 4 teilig
In: Erdgeschoss
Type - Material: IfcSurfaceStyle #251447
Type - Andere - Kategorie: Allgemeines Modell; Familienname: Segmentbogen 4 teilig 281376
Type - ID-Daten - Typname: Segmentbogen 4 teilig 281376
Type - IFC-Parameter - Typ in IFC-Datei exportieren: Vorgabe
Description: Segmentbogen 4 teilig
Pset_DistributionFlowElementCommon - Reference: Segmentbogen 4 teilig 281376; sets with these values: 2
Andere - Typ: Segmentbogen 4 teilig 281376; Familie: Segmentbogen 4 teilig 281376; Familie und Typ: Segmentbogen 4 teilig 281376: Segmentbogen 4 teilig 281376; Typ-ID: 2534097
Abhängigkeiten - Höhe von Ebene: 0 m; Verschieben mit umliegenden Elementen: no
Bemaßungen - Fläche: 0.40201 m2; Volumen: 0.0619677 m3
IFC-Parameter - In IFC-Datei exportieren: Nach Typ; Pset MEP.Geom-Ø (mm): 400; Pset MEP.Tech-Material (ID): 1; Pset MEP.Geom-Angle (°): 90; Pset MEP.Geom-Segment number (if segmented): 4; Pset MEP.Geom-Radius (mm): 400; In IFC exportieren als: ifcflowfitting; NameOverride: Segmentbogen 4 teilig; IfcPresentationLayer: 0-TFT-H_Abgasabführung Variante 2; ObjectTypeOverride: Segmentbogen 4 teilig; Pset MEP.Name: Segmentbogen 4 teilig; IfcDescription: Segmentbogen 4 teilig; Pset MEP.Abbreviation: BSE; Pset MEP.Tech-Medium: L_Entrauchung
Phasen - Phase erstellt: Phase 01

# IfcFlowFitting: Segmentbogen 4 teilig 281399:Segmentbogen 4 teilig 281399, Segmentbogen 4 teilig
In: Erdgeschoss
Type - Material: IfcSurfaceStyle #251447
Type - Andere - Kategorie: Allgemeines Modell; Familienname: Segmentbogen 4 teilig 281399
Type - ID-Daten - Typname: Segmentbogen 4 teilig 281399
Type - IFC-Parameter - Typ in IFC-Datei exportieren: Vorgabe
Description: Segmentbogen 4 teilig
Pset_DistributionFlowElementCommon - Reference: Segmentbogen 4 teilig 281399; sets with these values: 2
Andere - Typ: Segmentbogen 4 teilig 281399; Familie: Segmentbogen 4 teilig 281399; Familie und Typ: Segmentbogen 4 teilig 281399: Segmentbogen 4 teilig 281399; Typ-ID: 2534104
Abhängigkeiten - Höhe von Ebene: 0 m; Verschieben mit umliegenden Elementen: no
Bemaßungen - Fläche: 0.40201 m2; Volumen: 0.0619677 m3
IFC-Parameter - In IFC-Datei exportieren: Nach Typ; Pset MEP.Geom-Ø (mm): 400; Pset MEP.Tech-Material (ID): 1; Pset MEP.Geom-Angle (°): 90; Pset MEP.Geom-Segment number (if segmented): 4; Pset MEP.Geom-Radius (mm): 400; In IFC exportieren als: ifcflowfitting; NameOverride: Segmentbogen 4 teilig; IfcPresentationLayer: 0-TFT-H_Abgasabführung Variante 2; ObjectTypeOverride: Segmentbogen 4 teilig; Pset MEP.Name: Segmentbogen 4 teilig; IfcDescription: Segmentbogen 4 teilig; Pset MEP.Abbreviation: BSE; Pset MEP.Tech-Medium: L_Entrauchung
Phasen - Phase erstellt: Phase 01

# IfcFlowFitting: Segmentbogen 4 teilig 281778:Segmentbogen 4 teilig 281778, Segmentbogen 4 teilig
In: Erdgeschoss
Type - Material: IfcSurfaceStyle #251447
Type - Andere - Kategorie: Allgemeines Modell; Familienname: Segmentbogen 4 teilig 281778
Type - ID-Daten - Typname: Segmentbogen 4 teilig 281778
Type - IFC-Parameter - Typ in IFC-Datei exportieren: Vorgabe
Description: Segmentbogen 4 teilig
Pset_DistributionFlowElementCommon - Reference: Segmentbogen 4 teilig 281778; sets with these values: 2
Andere - Typ: Segmentbogen 4 teilig 281778; Familie: Segmentbogen 4 teilig 281778; Familie und Typ: Segmentbogen 4 teilig 281778: Segmentbogen 4 teilig 281778; Typ-ID: 2534139
Abhängigkeiten - Höhe von Ebene: 0 m; Verschieben mit umliegenden Elementen: no
Bemaßungen - Fläche: 0.40201 m2; Volumen: 0.0619677 m3
IFC-Parameter - In IFC-Datei exportieren: Nach Typ; Pset MEP.Geom-Ø (mm): 400; Pset MEP.Tech-Material (ID): 1; Pset MEP.Geom-Angle (°): 90; Pset MEP.Geom-Segment number (if segmented): 4; Pset MEP.Geom-Radius (mm): 400; In IFC exportieren als: ifcflowfitting; NameOverride: Segmentbogen 4 teilig; IfcPresentationLayer: 0-TFT-H_Abgasabführung Variante 2; ObjectTypeOverride: Segmentbogen 4 teilig; Pset MEP.Name: Segmentbogen 4 teilig; IfcDescription: Segmentbogen 4 teilig; Pset MEP.Abbreviation: BSE; Pset MEP.Tech-Medium: L_Entrauchung
Phasen - Phase erstellt: Phase 01

# IfcFlowFitting: Segmentbogen 4 teilig 282981:Segmentbogen 4 teilig 282981, Segmentbogen 4 teilig
In: Erdgeschoss
Type - Material: IfcSurfaceStyle #251447
Type - Andere - Kategorie: Allgemeines Modell; Familienname: Segmentbogen 4 teilig 282981
Type - ID-Daten - Typname: Segmentbogen 4 teilig 282981
Type - IFC-Parameter - Typ in IFC-Datei exportieren: Vorgabe
Description: Segmentbogen 4 teilig
Pset_DistributionFlowElementCommon - Reference: Segmentbogen 4 teilig 282981; sets with these values: 2
Andere - Typ: Segmentbogen 4 teilig 282981; Familie: Segmentbogen 4 teilig 282981; Familie und Typ: Segmentbogen 4 teilig 282981: Segmentbogen 4 teilig 282981; Typ-ID: 2534181
Abhängigkeiten - Höhe von Ebene: 0 m; Verschieben mit umliegenden Elementen: no
Bemaßungen - Fläche: 0.157035 m2; Volumen: 0.0151288 m3
IFC-Parameter - In IFC-Datei exportieren: Nach Typ; Pset MEP.Tech-Material (ID): 1; Pset MEP.Geom-Angle (°): 90; Pset MEP.Geom-Segment number (if segmented): 4; Pset MEP.Geom-Ø (mm): 250; In IFC exportieren als: ifcflowfitting; NameOverride: Segmentbogen 4 teilig; IfcPresentationLayer: 0-TFT-H_Abgasabführung Variante 2; ObjectTypeOverride: Segmentbogen 4 teilig; Pset MEP.Name: Segmentbogen 4 teilig; IfcDescription: Segmentbogen 4 teilig; Pset MEP.Abbreviation: BSE; Pset MEP.Tech-Medium: L_Entrauchung; Pset MEP.Geom-Radius (mm): 250
Phasen - Phase erstellt: Phase 01

# IfcFlowFitting: Segmentbogen 4 teilig 283546:Segmentbogen 4 teilig 283546, Segmentbogen 4 teilig
In: Erdgeschoss
Type - Material: IfcSurfaceStyle #251447
Type - Andere - Kategorie: Allgemeines Modell; Familienname: Segmentbogen 4 teilig 283546
Type - ID-Daten - Typname: Segmentbogen 4 teilig 283546
Type - IFC-Parameter - Typ in IFC-Datei exportieren: Vorgabe
Description: Segmentbogen 4 teilig
Pset_DistributionFlowElementCommon - Reference: Segmentbogen 4 teilig 283546; sets with these values: 2
Andere - Typ: Segmentbogen 4 teilig 283546; Familie: Segmentbogen 4 teilig 283546; Familie und Typ: Segmentbogen 4 teilig 283546: Segmentbogen 4 teilig 283546; Typ-ID: 2534188
Abhängigkeiten - Höhe von Ebene: 0 m; Verschieben mit umliegenden Elementen: no
Bemaßungen - Fläche: 0.157035 m2; Volumen: 0.0151288 m3
IFC-Parameter - In IFC-Datei exportieren: Nach Typ; Pset MEP.Tech-Material (ID): 1; Pset MEP.Geom-Angle (°): 90; Pset MEP.Geom-Segment number (if segmented): 4; Pset MEP.Geom-Ø (mm): 250; Pset MEP.Geom-Radius (mm): 250; In IFC exportieren als: ifcflowfitting; NameOverride: Segmentbogen 4 teilig; IfcPresentationLayer: 0-TFT-H_Abgasabführung Variante 2; ObjectTypeOverride: Segmentbogen 4 teilig; Pset MEP.Name: Segmentbogen 4 teilig; IfcDescription: Segmentbogen 4 teilig; Pset MEP.Abbreviation: BSE; Pset MEP.Tech-Medium: L_Entrauchung
Phasen - Phase erstellt: Phase 01

# IfcFlowFitting: Segmentbogen 4 teilig 284962:Segmentbogen 4 teilig 284962, Segmentbogen 4 teilig
In: Erdgeschoss
Type - Material: IfcSurfaceStyle #251447
Type - Andere - Kategorie: Allgemeines Modell; Familienname: Segmentbogen 4 teilig 284962
Type - ID-Daten - Typname: Segmentbogen 4 teilig 284962
Type - IFC-Parameter - Typ in IFC-Datei exportieren: Vorgabe
Description: Segmentbogen 4 teilig
Pset_DistributionFlowElementCommon - Reference: Segmentbogen 4 teilig 284962; sets with these values: 2
Andere - Typ: Segmentbogen 4 teilig 284962; Familie: Segmentbogen 4 teilig 284962; Familie und Typ: Segmentbogen 4 teilig 284962: Segmentbogen 4 teilig 284962; Typ-ID: 2534258
Abhängigkeiten - Höhe von Ebene: 0 m; Verschieben mit umliegenden Elementen: no
Bemaßungen - Fläche: 0.157035 m2; Volumen: 0.0151288 m3
IFC-Parameter - In IFC-Datei exportieren: Nach Typ; Pset MEP.Tech-Material (ID): 1; Pset MEP.Geom-Angle (°): 90; Pset MEP.Geom-Segment number (if segmented): 4; Pset MEP.Geom-Ø (mm): 250; Pset MEP.Geom-Radius (mm): 250; In IFC exportieren als: ifcflowfitting; NameOverride: Segmentbogen 4 teilig; IfcPresentationLayer: 0-TFT-H_Abgasabführung Variante 2; ObjectTypeOverride: Segmentbogen 4 teilig; Pset MEP.Name: Segmentbogen 4 teilig; IfcDescription: Segmentbogen 4 teilig; Pset MEP.Abbreviation: BSE; Pset MEP.Tech-Medium: L_Entrauchung
Phasen - Phase erstellt: Phase 01

# IfcFlowFitting: Segmentbogen 4 teilig 293653:Segmentbogen 4 teilig 293653, Segmentbogen 4 teilig
In: Erdgeschoss
Type - Material: IfcSurfaceStyle #251447
Type - Andere - Kategorie: Allgemeines Modell; Familienname: Segmentbogen 4 teilig 293653
Type - ID-Daten - Typname: Segmentbogen 4 teilig 293653
Type - IFC-Parameter - Typ in IFC-Datei exportieren: Vorgabe
Description: Segmentbogen 4 teilig
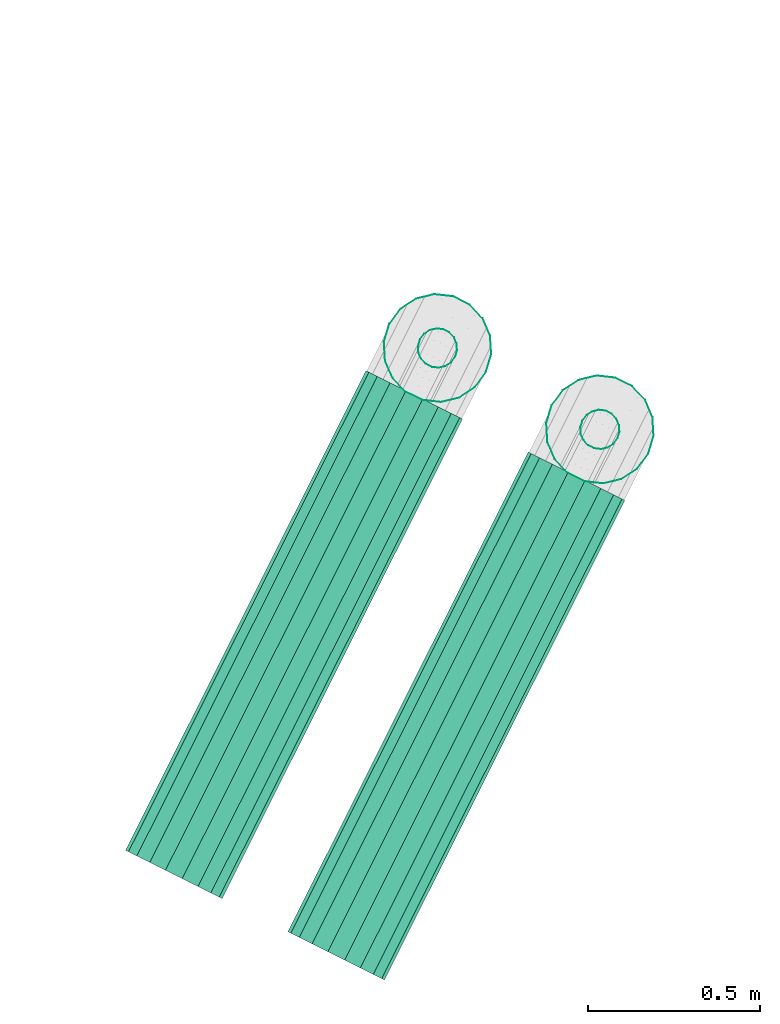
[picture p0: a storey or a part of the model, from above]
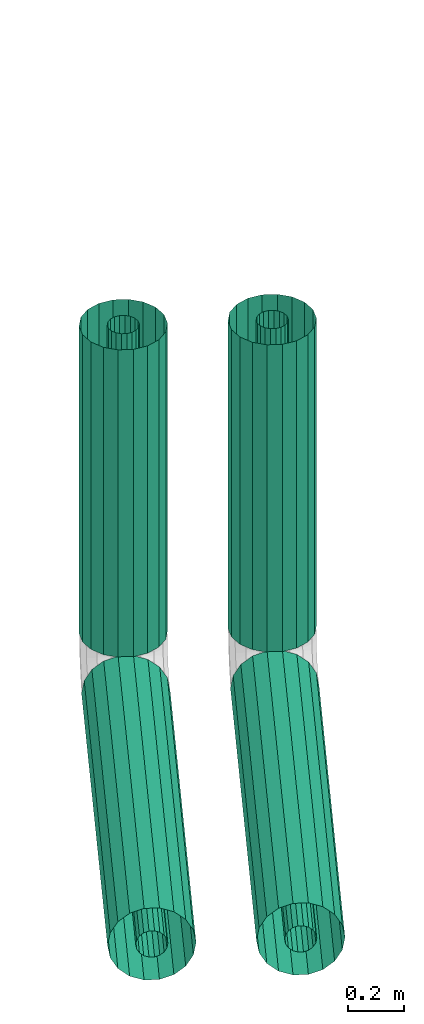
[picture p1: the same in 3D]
Properties of the parts of a building model (IFC2X3), part 12 of 23

# IfcFlowFitting: Segmentbogen 4 teilig 293653:Segmentbogen 4 teilig 293653, Segmentbogen 4 teilig
Pset_DistributionFlowElementCommon - Reference: Segmentbogen 4 teilig 293653; sets with these values: 2
Andere - Typ: Segmentbogen 4 teilig 293653; Familie: Segmentbogen 4 teilig 293653; Familie und Typ: Segmentbogen 4 teilig 293653: Segmentbogen 4 teilig 293653; Typ-ID: 2534410
Abhängigkeiten - Höhe von Ebene: 0 m; Verschieben mit umliegenden Elementen: no
Bemaßungen - Fläche: 0.157035 m2; Volumen: 0.0151288 m3
IFC-Parameter - In IFC-Datei exportieren: Nach Typ; Pset MEP.Tech-Material (ID): 1; Pset MEP.Geom-Angle (°): 90; Pset MEP.Geom-Segment number (if segmented): 4; Pset MEP.Geom-Ø (mm): 250; Pset MEP.Geom-Radius (mm): 250; In IFC exportieren als: ifcflowfitting; NameOverride: Segmentbogen 4 teilig; IfcPresentationLayer: 0-TFT-H_Abgasabführung Variante 3; ObjectTypeOverride: Segmentbogen 4 teilig; Pset MEP.Name: Segmentbogen 4 teilig; IfcDescription: Segmentbogen 4 teilig; Pset MEP.Abbreviation: BSE; Pset MEP.Tech-Medium: L_Entrauchung
Phasen - Phase erstellt: Phase 01

# IfcFlowFitting: Segmentbogen 4 teilig 293676:Segmentbogen 4 teilig 293676, Segmentbogen 4 teilig
In: Erdgeschoss
Type - Material: IfcSurfaceStyle #251447
Type - Andere - Kategorie: Allgemeines Modell; Familienname: Segmentbogen 4 teilig 293676
Type - ID-Daten - Typname: Segmentbogen 4 teilig 293676
Type - IFC-Parameter - Typ in IFC-Datei exportieren: Vorgabe
Description: Segmentbogen 4 teilig
Pset_DistributionFlowElementCommon - Reference: Segmentbogen 4 teilig 293676; sets with these values: 2
Andere - Typ: Segmentbogen 4 teilig 293676; Familie: Segmentbogen 4 teilig 293676; Familie und Typ: Segmentbogen 4 teilig 293676: Segmentbogen 4 teilig 293676; Typ-ID: 2534417
Abhängigkeiten - Höhe von Ebene: 0 m; Verschieben mit umliegenden Elementen: no
Bemaßungen - Fläche: 0.157035 m2; Volumen: 0.0151288 m3
IFC-Parameter - In IFC-Datei exportieren: Nach Typ; Pset MEP.Tech-Material (ID): 1; Pset MEP.Geom-Angle (°): 90; Pset MEP.Geom-Segment number (if segmented): 4; Pset MEP.Geom-Ø (mm): 250; Pset MEP.Geom-Radius (mm): 250; In IFC exportieren als: ifcflowfitting; NameOverride: Segmentbogen 4 teilig; IfcPresentationLayer: 0-TFT-H_Abgasabführung Variante 3; ObjectTypeOverride: Segmentbogen 4 teilig; Pset MEP.Name: Segmentbogen 4 teilig; IfcDescription: Segmentbogen 4 teilig; Pset MEP.Abbreviation: BSE; Pset MEP.Tech-Medium: L_Entrauchung
Phasen - Phase erstellt: Phase 01

# IfcFlowFitting: Segmentbogen 4 teilig 293722:Segmentbogen 4 teilig 293722, Segmentbogen 4 teilig
In: Erdgeschoss
Type - Material: IfcSurfaceStyle #251447
Type - Andere - Kategorie: Allgemeines Modell; Familienname: Segmentbogen 4 teilig 293722
Type - ID-Daten - Typname: Segmentbogen 4 teilig 293722
Type - IFC-Parameter - Typ in IFC-Datei exportieren: Vorgabe
Description: Segmentbogen 4 teilig
Pset_DistributionFlowElementCommon - Reference: Segmentbogen 4 teilig 293722; sets with these values: 2
Andere - Typ: Segmentbogen 4 teilig 293722; Familie: Segmentbogen 4 teilig 293722; Familie und Typ: Segmentbogen 4 teilig 293722: Segmentbogen 4 teilig 293722; Typ-ID: 2534431
Abhängigkeiten - Höhe von Ebene: 0 m; Verschieben mit umliegenden Elementen: no
Bemaßungen - Fläche: 0.157035 m2; Volumen: 0.0151288 m3
IFC-Parameter - In IFC-Datei exportieren: Nach Typ; Pset MEP.Tech-Material (ID): 1; Pset MEP.Geom-Angle (°): 90; Pset MEP.Geom-Segment number (if segmented): 4; Pset MEP.Geom-Ø (mm): 250; Pset MEP.Geom-Radius (mm): 250; In IFC exportieren als: ifcflowfitting; NameOverride: Segmentbogen 4 teilig; IfcPresentationLayer: 0-TFT-H_Abgasabführung Variante 3; ObjectTypeOverride: Segmentbogen 4 teilig; Pset MEP.Name: Segmentbogen 4 teilig; IfcDescription: Segmentbogen 4 teilig; Pset MEP.Abbreviation: BSE; Pset MEP.Tech-Medium: L_Entrauchung
Phasen - Phase erstellt: Phase 01

# IfcFlowFitting: Segmentbogen 4 teilig 293742:Segmentbogen 4 teilig 293742, Segmentbogen 4 teilig
In: Erdgeschoss
Type - Material: IfcSurfaceStyle #251447
Type - Andere - Kategorie: Allgemeines Modell; Familienname: Segmentbogen 4 teilig 293742
Type - ID-Daten - Typname: Segmentbogen 4 teilig 293742
Type - IFC-Parameter - Typ in IFC-Datei exportieren: Vorgabe
Description: Segmentbogen 4 teilig
Pset_DistributionFlowElementCommon - Reference: Segmentbogen 4 teilig 293742; sets with these values: 2
Andere - Typ: Segmentbogen 4 teilig 293742; Familie: Segmentbogen 4 teilig 293742; Familie und Typ: Segmentbogen 4 teilig 293742: Segmentbogen 4 teilig 293742; Typ-ID: 2534438
Abhängigkeiten - Höhe von Ebene: 0 m; Verschieben mit umliegenden Elementen: no
Bemaßungen - Fläche: 0.157035 m2; Volumen: 0.0151288 m3
IFC-Parameter - In IFC-Datei exportieren: Nach Typ; Pset MEP.Tech-Material (ID): 1; Pset MEP.Geom-Angle (°): 90; Pset MEP.Geom-Segment number (if segmented): 4; Pset MEP.Geom-Ø (mm): 250; Pset MEP.Geom-Radius (mm): 250; In IFC exportieren als: ifcflowfitting; NameOverride: Segmentbogen 4 teilig; IfcPresentationLayer: 0-TFT-H_Abgasabführung Variante 3; ObjectTypeOverride: Segmentbogen 4 teilig; Pset MEP.Name: Segmentbogen 4 teilig; IfcDescription: Segmentbogen 4 teilig; Pset MEP.Abbreviation: BSE; Pset MEP.Tech-Medium: L_Entrauchung
Phasen - Phase erstellt: Phase 01

# IfcFlowFitting: Segmentbogen 4 teilig 294590:Segmentbogen 4 teilig 294590, Segmentbogen 4 teilig
In: Erdgeschoss
Type - Material: IfcSurfaceStyle #251447
Type - Andere - Kategorie: Allgemeines Modell; Familienname: Segmentbogen 4 teilig 294590
Type - ID-Daten - Typname: Segmentbogen 4 teilig 294590
Type - IFC-Parameter - Typ in IFC-Datei exportieren: Vorgabe
Description: Segmentbogen 4 teilig
Pset_DistributionFlowElementCommon - Reference: Segmentbogen 4 teilig 294590; sets with these values: 2
Andere - Typ: Segmentbogen 4 teilig 294590; Familie: Segmentbogen 4 teilig 294590; Familie und Typ: Segmentbogen 4 teilig 294590: Segmentbogen 4 teilig 294590; Typ-ID: 2534494
Abhängigkeiten - Höhe von Ebene: 0 m; Verschieben mit umliegenden Elementen: no
Bemaßungen - Fläche: 0.40201 m2; Volumen: 0.0619677 m3
IFC-Parameter - In IFC-Datei exportieren: Nach Typ; Pset MEP.Geom-Ø (mm): 400; Pset MEP.Tech-Material (ID): 1; Pset MEP.Geom-Angle (°): 90; Pset MEP.Geom-Segment number (if segmented): 4; Pset MEP.Geom-Radius (mm): 400; In IFC exportieren als: ifcflowfitting; NameOverride: Segmentbogen 4 teilig; IfcPresentationLayer: 0-TFT-H_Abgasabführung Variante 3; ObjectTypeOverride: Segmentbogen 4 teilig; Pset MEP.Name: Segmentbogen 4 teilig; IfcDescription: Segmentbogen 4 teilig; Pset MEP.Abbreviation: BSE; Pset MEP.Tech-Medium: L_Entrauchung
Phasen - Phase erstellt: Phase 01

# IfcFlowFitting: Segmentbogen 4 teilig 294659:Segmentbogen 4 teilig 294659, Segmentbogen 4 teilig
In: Erdgeschoss
Type - Material: IfcSurfaceStyle #251447
Type - Andere - Kategorie: Allgemeines Modell; Familienname: Segmentbogen 4 teilig 294659
Type - ID-Daten - Typname: Segmentbogen 4 teilig 294659
Type - IFC-Parameter - Typ in IFC-Datei exportieren: Vorgabe
Description: Segmentbogen 4 teilig
Pset_DistributionFlowElementCommon - Reference: Segmentbogen 4 teilig 294659; sets with these values: 2
Andere - Typ: Segmentbogen 4 teilig 294659; Familie: Segmentbogen 4 teilig 294659; Familie und Typ: Segmentbogen 4 teilig 294659: Segmentbogen 4 teilig 294659; Typ-ID: 2534515
Abhängigkeiten - Höhe von Ebene: 0 m; Verschieben mit umliegenden Elementen: no
Bemaßungen - Fläche: 0.40201 m2; Volumen: 0.0619677 m3
IFC-Parameter - In IFC-Datei exportieren: Nach Typ; Pset MEP.Geom-Ø (mm): 400; Pset MEP.Tech-Material (ID): 1; Pset MEP.Geom-Angle (°): 90; Pset MEP.Geom-Segment number (if segmented): 4; Pset MEP.Geom-Radius (mm): 400; In IFC exportieren als: ifcflowfitting; NameOverride: Segmentbogen 4 teilig; IfcPresentationLayer: 0-TFT-H_Abgasabführung Variante 3; ObjectTypeOverride: Segmentbogen 4 teilig; Pset MEP.Name: Segmentbogen 4 teilig; IfcDescription: Segmentbogen 4 teilig; Pset MEP.Abbreviation: BSE; Pset MEP.Tech-Medium: L_Entrauchung
Phasen - Phase erstellt: Phase 01

# IfcFlowFitting: Segmentbogen 4 teilig 294679:Segmentbogen 4 teilig 294679, Segmentbogen 4 teilig
In: Erdgeschoss
Type - Material: IfcSurfaceStyle #251447
Type - Andere - Kategorie: Allgemeines Modell; Familienname: Segmentbogen 4 teilig 294679
Type - ID-Daten - Typname: Segmentbogen 4 teilig 294679
Type - IFC-Parameter - Typ in IFC-Datei exportieren: Vorgabe
Description: Segmentbogen 4 teilig
Pset_DistributionFlowElementCommon - Reference: Segmentbogen 4 teilig 294679; sets with these values: 2
Andere - Typ: Segmentbogen 4 teilig 294679; Familie: Segmentbogen 4 teilig 294679; Familie und Typ: Segmentbogen 4 teilig 294679: Segmentbogen 4 teilig 294679; Typ-ID: 2534522
Abhängigkeiten - Höhe von Ebene: 0 m; Verschieben mit umliegenden Elementen: no
Bemaßungen - Fläche: 0.40201 m2; Volumen: 0.0619677 m3
IFC-Parameter - In IFC-Datei exportieren: Nach Typ; Pset MEP.Geom-Ø (mm): 400; Pset MEP.Tech-Material (ID): 1; Pset MEP.Geom-Angle (°): 90; Pset MEP.Geom-Segment number (if segmented): 4; Pset MEP.Geom-Radius (mm): 400; In IFC exportieren als: ifcflowfitting; NameOverride: Segmentbogen 4 teilig; IfcPresentationLayer: 0-TFT-H_Abgasabführung Variante 3; ObjectTypeOverride: Segmentbogen 4 teilig; Pset MEP.Name: Segmentbogen 4 teilig; IfcDescription: Segmentbogen 4 teilig; Pset MEP.Abbreviation: BSE; Pset MEP.Tech-Medium: L_Entrauchung
Phasen - Phase erstellt: Phase 01

# IfcFlowFitting: Segmentbogen 4 teilig 295291:Segmentbogen 4 teilig 295291, Segmentbogen 4 teilig
In: Erdgeschoss
Type - Material: IfcSurfaceStyle #251447
Type - Andere - Kategorie: Allgemeines Modell; Familienname: Segmentbogen 4 teilig 295291
Type - ID-Daten - Typname: Segmentbogen 4 teilig 295291
Type - IFC-Parameter - Typ in IFC-Datei exportieren: Vorgabe
Description: Segmentbogen 4 teilig
Pset_DistributionFlowElementCommon - Reference: Segmentbogen 4 teilig 295291; sets with these values: 2
Andere - Typ: Segmentbogen 4 teilig 295291; Familie: Segmentbogen 4 teilig 295291; Familie und Typ: Segmentbogen 4 teilig 295291: Segmentbogen 4 teilig 295291; Typ-ID: 2534564
Abhängigkeiten - Höhe von Ebene: 0 m; Verschieben mit umliegenden Elementen: no
Bemaßungen - Fläche: 0.40201 m2; Volumen: 0.0619677 m3
IFC-Parameter - In IFC-Datei exportieren: Nach Typ; Pset MEP.Geom-Ø (mm): 400; Pset MEP.Tech-Material (ID): 1; Pset MEP.Geom-Angle (°): 90; Pset MEP.Geom-Segment number (if segmented): 4; Pset MEP.Geom-Radius (mm): 400; In IFC exportieren als: ifcflowfitting; NameOverride: Segmentbogen 4 teilig; IfcPresentationLayer: 0-TFT-H_Abgasabführung Variante 3; ObjectTypeOverride: Segmentbogen 4 teilig; Pset MEP.Name: Segmentbogen 4 teilig; IfcDescription: Segmentbogen 4 teilig; Pset MEP.Abbreviation: BSE; Pset MEP.Tech-Medium: L_Entrauchung
Phasen - Phase erstellt: Phase 01

# IfcFlowFitting: Segmentbogen 4 teilig 295802:Segmentbogen 4 teilig 295802, Segmentbogen 4 teilig
In: Erdgeschoss
Type - Material: IfcSurfaceStyle #251447
Type - Andere - Kategorie: Allgemeines Modell; Familienname: Segmentbogen 4 teilig 295802
Type - ID-Daten - Typname: Segmentbogen 4 teilig 295802
Type - IFC-Parameter - Typ in IFC-Datei exportieren: Vorgabe
Description: Segmentbogen 4 teilig
Pset_DistributionFlowElementCommon - Reference: Segmentbogen 4 teilig 295802; sets with these values: 2
Andere - Typ: Segmentbogen 4 teilig 295802; Familie: Segmentbogen 4 teilig 295802; Familie und Typ: Segmentbogen 4 teilig 295802: Segmentbogen 4 teilig 295802; Typ-ID: 2534592
Abhängigkeiten - Höhe von Ebene: 0 m; Verschieben mit umliegenden Elementen: no
Bemaßungen - Fläche: 0.40201 m2; Volumen: 0.0619677 m3
IFC-Parameter - In IFC-Datei exportieren: Nach Typ; Pset MEP.Geom-Ø (mm): 400; Pset MEP.Tech-Material (ID): 1; Pset MEP.Geom-Angle (°): 90; Pset MEP.Geom-Segment number (if segmented): 4; Pset MEP.Geom-Radius (mm): 400; In IFC exportieren als: ifcflowfitting; NameOverride: Segmentbogen 4 teilig; IfcPresentationLayer: 0-TFT-H_Abgasabführung Variante 3; ObjectTypeOverride: Segmentbogen 4 teilig; Pset MEP.Name: Segmentbogen 4 teilig; IfcDescription: Segmentbogen 4 teilig; Pset MEP.Abbreviation: BSE; Pset MEP.Tech-Medium: L_Entrauchung
Phasen - Phase erstellt: Phase 01

# IfcFlowFitting: Segmentbogen 4 teilig 295845:Segmentbogen 4 teilig 295845, Segmentbogen 4 teilig
In: Erdgeschoss
Type - Material: IfcSurfaceStyle #251447
Type - Andere - Kategorie: Allgemeines Modell; Familienname: Segmentbogen 4 teilig 295845
Type - ID-Daten - Typname: Segmentbogen 4 teilig 295845
Type - IFC-Parameter - Typ in IFC-Datei exportieren: Vorgabe
Description: Segmentbogen 4 teilig
Pset_DistributionFlowElementCommon - Reference: Segmentbogen 4 teilig 295845; sets with these values: 2
Andere - Typ: Segmentbogen 4 teilig 295845; Familie: Segmentbogen 4 teilig 295845; Familie und Typ: Segmentbogen 4 teilig 295845: Segmentbogen 4 teilig 295845; Typ-ID: 2534606
Abhängigkeiten - Höhe von Ebene: 0 m; Verschieben mit umliegenden Elementen: no
Bemaßungen - Fläche: 0.40201 m2; Volumen: 0.0619677 m3
IFC-Parameter - In IFC-Datei exportieren: Nach Typ; Pset MEP.Geom-Ø (mm): 400; Pset MEP.Tech-Material (ID): 1; Pset MEP.Geom-Angle (°): 90; Pset MEP.Geom-Segment number (if segmented): 4; Pset MEP.Geom-Radius (mm): 400; In IFC exportieren als: ifcflowfitting; NameOverride: Segmentbogen 4 teilig; IfcPresentationLayer: 0-TFT-H_Abgasabführung Variante 3; ObjectTypeOverride: Segmentbogen 4 teilig; Pset MEP.Name: Segmentbogen 4 teilig; IfcDescription: Segmentbogen 4 teilig; Pset MEP.Abbreviation: BSE; Pset MEP.Tech-Medium: L_Entrauchung
Phasen - Phase erstellt: Phase 01

# IfcFlowFitting: Segmentbogen 4 teilig 296410:Segmentbogen 4 teilig 296410, Segmentbogen 4 teilig
In: Erdgeschoss
Type - Material: IfcSurfaceStyle #251447
Type - Andere - Kategorie: Allgemeines Modell; Familienname: Segmentbogen 4 teilig 296410
Type - ID-Daten - Typname: Segmentbogen 4 teilig 296410
Type - IFC-Parameter - Typ in IFC-Datei exportieren: Vorgabe
Description: Segmentbogen 4 teilig
Pset_DistributionFlowElementCommon - Reference: Segmentbogen 4 teilig 296410; sets with these values: 2
Andere - Typ: Segmentbogen 4 teilig 296410; Familie: Segmentbogen 4 teilig 296410; Familie und Typ: Segmentbogen 4 teilig 296410: Segmentbogen 4 teilig 296410; Typ-ID: 2534655
Abhängigkeiten - Höhe von Ebene: 0 m; Verschieben mit umliegenden Elementen: no
Bemaßungen - Fläche: 0.40201 m2; Volumen: 0.0619677 m3
IFC-Parameter - In IFC-Datei exportieren: Nach Typ; Pset MEP.Geom-Ø (mm): 400; Pset MEP.Tech-Material (ID): 1; Pset MEP.Geom-Angle (°): 90; Pset MEP.Geom-Segment number (if segmented): 4; Pset MEP.Geom-Radius (mm): 400; In IFC exportieren als: ifcflowfitting; NameOverride: Segmentbogen 4 teilig; IfcPresentationLayer: 0-TFT-H_Abgasabführung Variante 3; ObjectTypeOverride: Segmentbogen 4 teilig; Pset MEP.Name: Segmentbogen 4 teilig; IfcDescription: Segmentbogen 4 teilig; Pset MEP.Abbreviation: BSE; Pset MEP.Tech-Medium: L_Entrauchung
Phasen - Phase erstellt: Phase 01

# IfcFlowFitting: Segmentbogen 4 teilig 296617:Segmentbogen 4 teilig 296617, Segmentbogen 4 teilig
In: Erdgeschoss
Type - Material: IfcSurfaceStyle #251447
Type - Andere - Kategorie: Allgemeines Modell; Familienname: Segmentbogen 4 teilig 296617
Type - ID-Daten - Typname: Segmentbogen 4 teilig 296617
Type - IFC-Parameter - Typ in IFC-Datei exportieren: Vorgabe
Description: Segmentbogen 4 teilig
Pset_DistributionFlowElementCommon - Reference: Segmentbogen 4 teilig 296617; sets with these values: 2
Andere - Typ: Segmentbogen 4 teilig 296617; Familie: Segmentbogen 4 teilig 296617; Familie und Typ: Segmentbogen 4 teilig 296617: Segmentbogen 4 teilig 296617; Typ-ID: 2534676
Abhängigkeiten - Höhe von Ebene: 0 m; Verschieben mit umliegenden Elementen: no
Bemaßungen - Fläche: 0.40201 m2; Volumen: 0.0619677 m3
IFC-Parameter - In IFC-Datei exportieren: Nach Typ; Pset MEP.Geom-Ø (mm): 400; Pset MEP.Tech-Material (ID): 1; Pset MEP.Geom-Angle (°): 90; Pset MEP.Geom-Segment number (if segmented): 4; Pset MEP.Geom-Radius (mm): 400; In IFC exportieren als: ifcflowfitting; NameOverride: Segmentbogen 4 teilig; IfcPresentationLayer: 0-TFT-H_Abgasabführung Variante 3; ObjectTypeOverride: Segmentbogen 4 teilig; Pset MEP.Name: Segmentbogen 4 teilig; IfcDescription: Segmentbogen 4 teilig; Pset MEP.Abbreviation: BSE; Pset MEP.Tech-Medium: L_Entrauchung
Phasen - Phase erstellt: Phase 01

# IfcFlowFitting: Segmentbogen 4 teilig 296837:Segmentbogen 4 teilig 296837, Segmentbogen 4 teilig
In: Erdgeschoss
Type - Material: IfcSurfaceStyle #251447
Type - Andere - Kategorie: Allgemeines Modell; Familienname: Segmentbogen 4 teilig 296837
Type - ID-Daten - Typname: Segmentbogen 4 teilig 296837
Type - IFC-Parameter - Typ in IFC-Datei exportieren: Vorgabe
Description: Segmentbogen 4 teilig
Pset_DistributionFlowElementCommon - Reference: Segmentbogen 4 teilig 296837; sets with these values: 2
Andere - Typ: Segmentbogen 4 teilig 296837; Familie: Segmentbogen 4 teilig 296837; Familie und Typ: Segmentbogen 4 teilig 296837: Segmentbogen 4 teilig 296837; Typ-ID: 2534704
Abhängigkeiten - Höhe von Ebene: 0 m; Verschieben mit umliegenden Elementen: no
Bemaßungen - Fläche: 0.40201 m2; Volumen: 0.0619677 m3
IFC-Parameter - In IFC-Datei exportieren: Nach Typ; Pset MEP.Geom-Ø (mm): 400; Pset MEP.Tech-Material (ID): 1; Pset MEP.Geom-Angle (°): 90; Pset MEP.Geom-Segment number (if segmented): 4; Pset MEP.Geom-Radius (mm): 400; In IFC exportieren als: ifcflowfitting; NameOverride: Segmentbogen 4 teilig; IfcPresentationLayer: 0-TFT-H_Abgasabführung Variante 3; ObjectTypeOverride: Segmentbogen 4 teilig; Pset MEP.Name: Segmentbogen 4 teilig; IfcDescription: Segmentbogen 4 teilig; Pset MEP.Abbreviation: BSE; Pset MEP.Tech-Medium: L_Entrauchung
Phasen - Phase erstellt: Phase 01

# IfcFlowFitting: Segmentbogen 4 teilig 296860:Segmentbogen 4 teilig 296860, Segmentbogen 4 teilig
In: Erdgeschoss
Type - Material: IfcSurfaceStyle #251447
Type - Andere - Kategorie: Allgemeines Modell; Familienname: Segmentbogen 4 teilig 296860
Type - ID-Daten - Typname: Segmentbogen 4 teilig 296860
Type - IFC-Parameter - Typ in IFC-Datei exportieren: Vorgabe
Description: Segmentbogen 4 teilig
Pset_DistributionFlowElementCommon - Reference: Segmentbogen 4 teilig 296860; sets with these values: 2
Andere - Typ: Segmentbogen 4 teilig 296860; Familie: Segmentbogen 4 teilig 296860; Familie und Typ: Segmentbogen 4 teilig 296860: Segmentbogen 4 teilig 296860; Typ-ID: 2534711
Abhängigkeiten - Höhe von Ebene: 0 m; Verschieben mit umliegenden Elementen: no
Bemaßungen - Fläche: 0.40201 m2; Volumen: 0.0619677 m3
IFC-Parameter - In IFC-Datei exportieren: Nach Typ; Pset MEP.Geom-Ø (mm): 400; Pset MEP.Tech-Material (ID): 1; Pset MEP.Geom-Angle (°): 90; Pset MEP.Geom-Segment number (if segmented): 4; Pset MEP.Geom-Radius (mm): 400; In IFC exportieren als: ifcflowfitting; NameOverride: Segmentbogen 4 teilig; IfcPresentationLayer: 0-TFT-H_Abgasabführung Variante 3; ObjectTypeOverride: Segmentbogen 4 teilig; Pset MEP.Name: Segmentbogen 4 teilig; IfcDescription: Segmentbogen 4 teilig; Pset MEP.Abbreviation: BSE; Pset MEP.Tech-Medium: L_Entrauchung
Phasen - Phase erstellt: Phase 01

# IfcFlowFitting: Segmentbogen 4 teilig 297316:Segmentbogen 4 teilig 297316, Segmentbogen 4 teilig
In: Erdgeschoss
Type - Material: IfcSurfaceStyle #251447
Type - Andere - Kategorie: Allgemeines Modell; Familienname: Segmentbogen 4 teilig 297316
Type - ID-Daten - Typname: Segmentbogen 4 teilig 297316
Type - IFC-Parameter - Typ in IFC-Datei exportieren: Vorgabe
Description: Segmentbogen 4 teilig
Pset_DistributionFlowElementCommon - Reference: Segmentbogen 4 teilig 297316; sets with these values: 2
Andere - Typ: Segmentbogen 4 teilig 297316; Familie: Segmentbogen 4 teilig 297316; Familie und Typ: Segmentbogen 4 teilig 297316: Segmentbogen 4 teilig 297316; Typ-ID: 2534769
Abhängigkeiten - Höhe von Ebene: 0 m; Verschieben mit umliegenden Elementen: no
Bemaßungen - Fläche: 0.40201 m2; Volumen: 0.0619677 m3
IFC-Parameter - In IFC-Datei exportieren: Nach Typ; Pset MEP.Geom-Ø (mm): 400; Pset MEP.Tech-Material (ID): 1; Pset MEP.Geom-Angle (°): 90; Pset MEP.Geom-Segment number (if segmented): 4; Pset MEP.Geom-Radius (mm): 400; In IFC exportieren als: ifcflowfitting; NameOverride: Segmentbogen 4 teilig; IfcPresentationLayer: 0-TFT-H_Abgasabführung Variante 1; ObjectTypeOverride: Segmentbogen 4 teilig; Pset MEP.Name: Segmentbogen 4 teilig; IfcDescription: Segmentbogen 4 teilig; Pset MEP.Abbreviation: BSE; Pset MEP.Tech-Medium: L_Entrauchung
Phasen - Phase erstellt: Phase 01

# IfcFlowFitting: Segmentbogen 4 teilig 614290:Segmentbogen 4 teilig 614290, Segmentbogen 4 teilig
In: Erdgeschoss
Type - Material: IfcSurfaceStyle #251447
Type - Andere - Kategorie: Allgemeines Modell; Familienname: Segmentbogen 4 teilig 614290
Type - ID-Daten - Typname: Segmentbogen 4 teilig 614290
Type - IFC-Parameter - Typ in IFC-Datei exportieren: Vorgabe
Description: Segmentbogen 4 teilig
Pset_DistributionFlowElementCommon - Reference: Segmentbogen 4 teilig 614290; sets with these values: 2
Andere - Typ: Segmentbogen 4 teilig 614290; Familie: Segmentbogen 4 teilig 614290; Familie und Typ: Segmentbogen 4 teilig 614290: Segmentbogen 4 teilig 614290; Typ-ID: 2537668
Abhängigkeiten - Höhe von Ebene: 0 m; Verschieben mit umliegenden Elementen: no
Bemaßungen - Fläche: 0.0814069 m2; Volumen: 0.00564681 m3
IFC-Parameter - In IFC-Datei exportieren: Nach Typ; Pset MEP.Tech-Material (ID): 1; Pset MEP.Geom-Angle (°): 90; Pset MEP.Geom-Ø (mm): 180; Pset MEP.Geom-Radius (mm): 180; Pset MEP.Geom-Segment number (if segmented): 4; In IFC exportieren als: ifcflowfitting; NameOverride: Segmentbogen 4 teilig; IfcPresentationLayer: 0-TFT-H_Abgasabführung Variante 1; ObjectTypeOverride: Segmentbogen 4 teilig; Pset MEP.Name: Segmentbogen 4 teilig; IfcDescription: Segmentbogen 4 teilig; Pset MEP.Abbreviation: BSE; Pset MEP.Tech-Medium: L_Entrauchung
Phasen - Phase erstellt: Phase 01

# IfcFlowFitting: Segmentbogen 4 teilig 617944:Segmentbogen 4 teilig 617944, Segmentbogen 4 teilig
In: Erdgeschoss
Type - Material: IfcSurfaceStyle #251447
Type - Andere - Kategorie: Allgemeines Modell; Familienname: Segmentbogen 4 teilig 617944
Type - ID-Daten - Typname: Segmentbogen 4 teilig 617944
Type - IFC-Parameter - Typ in IFC-Datei exportieren: Vorgabe
Description: Segmentbogen 4 teilig
Pset_DistributionFlowElementCommon - Reference: Segmentbogen 4 teilig 617944; sets with these values: 2
Andere - Typ: Segmentbogen 4 teilig 617944; Familie: Segmentbogen 4 teilig 617944; Familie und Typ: Segmentbogen 4 teilig 617944: Segmentbogen 4 teilig 617944; Typ-ID: 2537857
Abhängigkeiten - Höhe von Ebene: 0 m; Verschieben mit umliegenden Elementen: no
Bemaßungen - Fläche: 0.100502 m2; Volumen: 0.00774597 m3
IFC-Parameter - In IFC-Datei exportieren: Nach Typ; Pset MEP.Tech-Material (ID): 1; Pset MEP.Geom-Ø (mm): 200; Pset MEP.Geom-Angle (°): 90; Pset MEP.Geom-Segment number (if segmented): 4; In IFC exportieren als: ifcflowfitting; NameOverride: Segmentbogen 4 teilig; IfcPresentationLayer: 0-TFT-H_Abgasabführung Variante 1; ObjectTypeOverride: Segmentbogen 4 teilig; Pset MEP.Name: Segmentbogen 4 teilig; IfcDescription: Segmentbogen 4 teilig; Pset MEP.Abbreviation: BSE; Pset MEP.Tech-Medium: L_Entrauchung; Pset MEP.Geom-Radius (mm): 200
Phasen - Phase erstellt: Phase 01

# IfcFlowFitting: Segmentbogen 4 teilig 618684:Segmentbogen 4 teilig 618684, Segmentbogen 4 teilig
In: Erdgeschoss
Type - Material: IfcSurfaceStyle #251447
Type - Andere - Kategorie: Allgemeines Modell; Familienname: Segmentbogen 4 teilig 618684
Type - ID-Daten - Typname: Segmentbogen 4 teilig 618684
Type - IFC-Parameter - Typ in IFC-Datei exportieren: Vorgabe
Description: Segmentbogen 4 teilig
Pset_DistributionFlowElementCommon - Reference: Segmentbogen 4 teilig 618684; sets with these values: 2
Andere - Typ: Segmentbogen 4 teilig 618684; Familie: Segmentbogen 4 teilig 618684; Familie und Typ: Segmentbogen 4 teilig 618684: Segmentbogen 4 teilig 618684; Typ-ID: 2537878
Abhängigkeiten - Höhe von Ebene: 0 m; Verschieben mit umliegenden Elementen: no
Bemaßungen - Fläche: 0.100502 m2; Volumen: 0.00774597 m3
IFC-Parameter - In IFC-Datei exportieren: Nach Typ; Pset MEP.Tech-Material (ID): 1; Pset MEP.Geom-Ø (mm): 200; Pset MEP.Geom-Angle (°): 90; Pset MEP.Geom-Segment number (if segmented): 4; Pset MEP.Geom-Radius (mm): 200; In IFC exportieren als: ifcflowfitting; NameOverride: Segmentbogen 4 teilig; IfcPresentationLayer: 0-TFT-H_Abgasabführung Variante 1; ObjectTypeOverride: Segmentbogen 4 teilig; Pset MEP.Name: Segmentbogen 4 teilig; IfcDescription: Segmentbogen 4 teilig; Pset MEP.Abbreviation: BSE; Pset MEP.Tech-Medium: L_Entrauchung
Phasen - Phase erstellt: Phase 01

# IfcFlowFitting: Segmentbogen 4 teilig 620645:Segmentbogen 4 teilig 620645, Segmentbogen 4 teilig
In: Erdgeschoss
Type - Material: IfcSurfaceStyle #251447
Type - Andere - Kategorie: Allgemeines Modell; Familienname: Segmentbogen 4 teilig 620645
Type - ID-Daten - Typname: Segmentbogen 4 teilig 620645
Type - IFC-Parameter - Typ in IFC-Datei exportieren: Vorgabe
Description: Segmentbogen 4 teilig
Pset_DistributionFlowElementCommon - Reference: Segmentbogen 4 teilig 620645; sets with these values: 2
Andere - Typ: Segmentbogen 4 teilig 620645; Familie: Segmentbogen 4 teilig 620645; Familie und Typ: Segmentbogen 4 teilig 620645: Segmentbogen 4 teilig 620645; Typ-ID: 2538001
Abhängigkeiten - Höhe von Ebene: 0 m; Verschieben mit umliegenden Elementen: no
Bemaßungen - Fläche: 0.40201 m2; Volumen: 0.0619677 m3
IFC-Parameter - In IFC-Datei exportieren: Nach Typ; Pset MEP.Geom-Ø (mm): 400; Pset MEP.Tech-Material (ID): 1; Pset MEP.Geom-Angle (°): 90; Pset MEP.Geom-Segment number (if segmented): 4; Pset MEP.Geom-Radius (mm): 400; In IFC exportieren als: ifcflowfitting; NameOverride: Segmentbogen 4 teilig; IfcPresentationLayer: 0-TFT-H_Abgasabführung Variante 1; ObjectTypeOverride: Segmentbogen 4 teilig; Pset MEP.Name: Segmentbogen 4 teilig; IfcDescription: Segmentbogen 4 teilig; Pset MEP.Abbreviation: BSE; Pset MEP.Tech-Medium: L_Entrauchung
Phasen - Phase erstellt: Phase 01

# IfcFlowFitting: Segmentbogen 4 teilig 620668:Segmentbogen 4 teilig 620668, Segmentbogen 4 teilig
In: Erdgeschoss
Type - Material: IfcSurfaceStyle #251447
Type - Andere - Kategorie: Allgemeines Modell; Familienname: Segmentbogen 4 teilig 620668
Type - ID-Daten - Typname: Segmentbogen 4 teilig 620668
Type - IFC-Parameter - Typ in IFC-Datei exportieren: Vorgabe
Description: Segmentbogen 4 teilig
Pset_DistributionFlowElementCommon - Reference: Segmentbogen 4 teilig 620668; sets with these values: 2
Andere - Typ: Segmentbogen 4 teilig 620668; Familie: Segmentbogen 4 teilig 620668; Familie und Typ: Segmentbogen 4 teilig 620668: Segmentbogen 4 teilig 620668; Typ-ID: 2538008
Abhängigkeiten - Höhe von Ebene: 0 m; Verschieben mit umliegenden Elementen: no
Bemaßungen - Fläche: 0.40201 m2; Volumen: 0.0619677 m3
IFC-Parameter - In IFC-Datei exportieren: Nach Typ; Pset MEP.Geom-Ø (mm): 400; Pset MEP.Tech-Material (ID): 1; Pset MEP.Geom-Angle (°): 90; Pset MEP.Geom-Segment number (if segmented): 4; Pset MEP.Geom-Radius (mm): 400; In IFC exportieren als: ifcflowfitting; NameOverride: Segmentbogen 4 teilig; IfcPresentationLayer: 0-TFT-H_Abgasabführung Variante 1; ObjectTypeOverride: Segmentbogen 4 teilig; Pset MEP.Name: Segmentbogen 4 teilig; IfcDescription: Segmentbogen 4 teilig; Pset MEP.Abbreviation: BSE; Pset MEP.Tech-Medium: L_Entrauchung
Phasen - Phase erstellt: Phase 01

# IfcFlowFitting: Segmentbogen 4 teilig 621900:Segmentbogen 4 teilig 621900, Segmentbogen 4 teilig
In: Erdgeschoss
Type - Material: IfcSurfaceStyle #251447
Type - Andere - Kategorie: Allgemeines Modell; Familienname: Segmentbogen 4 teilig 621900
Type - ID-Daten - Typname: Segmentbogen 4 teilig 621900
Type - IFC-Parameter - Typ in IFC-Datei exportieren: Vorgabe
Description: Segmentbogen 4 teilig
Pset_DistributionFlowElementCommon - Reference: Segmentbogen 4 teilig 621900; sets with these values: 2
Andere - Typ: Segmentbogen 4 teilig 621900; Familie: Segmentbogen 4 teilig 621900; Familie und Typ: Segmentbogen 4 teilig 621900: Segmentbogen 4 teilig 621900; Typ-ID: 2538099
Abhängigkeiten - Höhe von Ebene: 0 m; Verschieben mit umliegenden Elementen: no
Bemaßungen - Fläche: 0.40201 m2; Volumen: 0.0619677 m3
IFC-Parameter - In IFC-Datei exportieren: Nach Typ; Pset MEP.Geom-Ø (mm): 400; Pset MEP.Tech-Material (ID): 1; Pset MEP.Geom-Angle (°): 90; Pset MEP.Geom-Segment number (if segmented): 4; Pset MEP.Geom-Radius (mm): 400; In IFC exportieren als: ifcflowfitting; NameOverride: Segmentbogen 4 teilig; IfcPresentationLayer: 0-TFT-H_Abgasabführung Variante 1; ObjectTypeOverride: Segmentbogen 4 teilig; Pset MEP.Name: Segmentbogen 4 teilig; IfcDescription: Segmentbogen 4 teilig; Pset MEP.Abbreviation: BSE; Pset MEP.Tech-Medium: L_Entrauchung
Phasen - Phase erstellt: Phase 01

# IfcFlowFitting: Segmentbogen 4 teilig 621969:Segmentbogen 4 teilig 621969, Segmentbogen 4 teilig
In: Erdgeschoss
Type - Material: IfcSurfaceStyle #251447
Type - Andere - Kategorie: Allgemeines Modell; Familienname: Segmentbogen 4 teilig 621969
Type - ID-Daten - Typname: Segmentbogen 4 teilig 621969
Type - IFC-Parameter - Typ in IFC-Datei exportieren: Vorgabe
Description: Segmentbogen 4 teilig
Pset_DistributionFlowElementCommon - Reference: Segmentbogen 4 teilig 621969; sets with these values: 2
Andere - Typ: Segmentbogen 4 teilig 621969; Familie: Segmentbogen 4 teilig 621969; Familie und Typ: Segmentbogen 4 teilig 621969: Segmentbogen 4 teilig 621969; Typ-ID: 2538120
Abhängigkeiten - Höhe von Ebene: 0 m; Verschieben mit umliegenden Elementen: no
Bemaßungen - Fläche: 0.40201 m2; Volumen: 0.0619677 m3
IFC-Parameter - In IFC-Datei exportieren: Nach Typ; Pset MEP.Geom-Ø (mm): 400; Pset MEP.Tech-Material (ID): 1; Pset MEP.Geom-Angle (°): 90; Pset MEP.Geom-Segment number (if segmented): 4; Pset MEP.Geom-Radius (mm): 400; In IFC exportieren als: ifcflowfitting; NameOverride: Segmentbogen 4 teilig; IfcPresentationLayer: 0-TFT-H_Abgasabführung Variante 1; ObjectTypeOverride: Segmentbogen 4 teilig; Pset MEP.Name: Segmentbogen 4 teilig; IfcDescription: Segmentbogen 4 teilig; Pset MEP.Abbreviation: BSE; Pset MEP.Tech-Medium: L_Entrauchung
Phasen - Phase erstellt: Phase 01

# IfcFlowFitting: Segmentbogen 4 teilig 622065:Segmentbogen 4 teilig 622065, Segmentbogen 4 teilig
In: Erdgeschoss
Type - Material: IfcSurfaceStyle #251447
Type - Andere - Kategorie: Allgemeines Modell; Familienname: Segmentbogen 4 teilig 622065
Type - ID-Daten - Typname: Segmentbogen 4 teilig 622065
Type - IFC-Parameter - Typ in IFC-Datei exportieren: Vorgabe
Description: Segmentbogen 4 teilig
Pset_DistributionFlowElementCommon - Reference: Segmentbogen 4 teilig 622065; sets with these values: 2
Andere - Typ: Segmentbogen 4 teilig 622065; Familie: Segmentbogen 4 teilig 622065; Familie und Typ: Segmentbogen 4 teilig 622065: Segmentbogen 4 teilig 622065; Typ-ID: 2538148
Abhängigkeiten - Höhe von Ebene: 0 m; Verschieben mit umliegenden Elementen: no
Bemaßungen - Fläche: 0.40201 m2; Volumen: 0.0619677 m3
IFC-Parameter - In IFC-Datei exportieren: Nach Typ; Pset MEP.Geom-Ø (mm): 400; Pset MEP.Tech-Material (ID): 1; Pset MEP.Geom-Angle (°): 90; Pset MEP.Geom-Segment number (if segmented): 4; Pset MEP.Geom-Radius (mm): 400; In IFC exportieren als: ifcflowfitting; NameOverride: Segmentbogen 4 teilig; IfcPresentationLayer: 0-TFT-H_Abgasabführung Variante 1; ObjectTypeOverride: Segmentbogen 4 teilig; Pset MEP.Name: Segmentbogen 4 teilig; IfcDescription: Segmentbogen 4 teilig; Pset MEP.Abbreviation: BSE; Pset MEP.Tech-Medium: L_Entrauchung
Phasen - Phase erstellt: Phase 01

# IfcFlowFitting: Segmentbogen 4 teilig 622128:Segmentbogen 4 teilig 622128, Segmentbogen 4 teilig
In: Erdgeschoss
Type - Material: IfcSurfaceStyle #251447
Type - Andere - Kategorie: Allgemeines Modell; Familienname: Segmentbogen 4 teilig 622128
Type - ID-Daten - Typname: Segmentbogen 4 teilig 622128
Type - IFC-Parameter - Typ in IFC-Datei exportieren: Vorgabe
Description: Segmentbogen 4 teilig
Pset_DistributionFlowElementCommon - Reference: Segmentbogen 4 teilig 622128; sets with these values: 2
Andere - Typ: Segmentbogen 4 teilig 622128; Familie: Segmentbogen 4 teilig 622128; Familie und Typ: Segmentbogen 4 teilig 622128: Segmentbogen 4 teilig 622128; Typ-ID: 2538169
Abhängigkeiten - Höhe von Ebene: 0 m; Verschieben mit umliegenden Elementen: no
Bemaßungen - Fläche: 0.40201 m2; Volumen: 0.0619677 m3
IFC-Parameter - In IFC-Datei exportieren: Nach Typ; Pset MEP.Geom-Ø (mm): 400; Pset MEP.Tech-Material (ID): 1; Pset MEP.Geom-Angle (°): 90; Pset MEP.Geom-Segment number (if segmented): 4; Pset MEP.Geom-Radius (mm): 400; In IFC exportieren als: ifcflowfitting; NameOverride: Segmentbogen 4 teilig; IfcPresentationLayer: 0-TFT-H_Abgasabführung Variante 1; ObjectTypeOverride: Segmentbogen 4 teilig; Pset MEP.Name: Segmentbogen 4 teilig; IfcDescription: Segmentbogen 4 teilig; Pset MEP.Abbreviation: BSE; Pset MEP.Tech-Medium: L_Entrauchung
Phasen - Phase erstellt: Phase 01

# IfcFlowFitting: Segmentbogen 4 teilig:Segmentbogen 4 teilig, Segmentbogen 4 teilig
In: Erdgeschoss
Type - Material: IfcSurfaceStyle #251447
Type - Andere - Kategorie: Allgemeines Modell; Familienname: Segmentbogen 4 teilig
Type - ID-Daten - Typname: Segmentbogen 4 teilig
Type - IFC-Parameter - Typ in IFC-Datei exportieren: Vorgabe
Description: Segmentbogen 4 teilig
Pset_DistributionFlowElementCommon - Reference: Segmentbogen 4 teilig; sets with these values: 2
Andere - Typ: Segmentbogen 4 teilig; Familie: Segmentbogen 4 teilig; Familie und Typ: Segmentbogen 4 teilig: Segmentbogen 4 teilig; Typ-ID: 2533934
Abhängigkeiten - Höhe von Ebene: 0 m; Verschieben mit umliegenden Elementen: no
Bemaßungen - Fläche: 0.0814069 m2; Volumen: 0.00564681 m3
IFC-Parameter - In IFC-Datei exportieren: Nach Typ; Pset MEP.Tech-Material (ID): 1; Pset MEP.Geom-Angle (°): 90; In IFC exportieren als: ifcflowfitting; NameOverride: Segmentbogen 4 teilig; IfcPresentationLayer: 0-TFT-H_Abgasabführung Variante 1; ObjectTypeOverride: Segmentbogen 4 teilig; Pset MEP.Name: Segmentbogen 4 teilig; IfcDescription: Segmentbogen 4 teilig; Pset MEP.Abbreviation: BSE; Pset MEP.Geom-Ø (mm): 180; Pset MEP.Tech-Medium: L_Entrauchung; Pset MEP.Geom-Radius (mm): 180; Pset MEP.Geom-Segment number (if segmented): 4
Phasen - Phase erstellt: Phase 01

# IfcFlowFitting: Übergang asymmetrisch 277154:Übergang asymmetrisch 277154, Übergang asymmetrisch
In: 1. Obergeschoss
Type - Material: IfcSurfaceStyle #271184
Type - Andere - Kategorie: Allgemeines Modell; Familienname: Übergang asymmetrisch 277154
Type - ID-Daten - Typname: Übergang asymmetrisch 277154
Type - IFC-Parameter - Typ in IFC-Datei exportieren: Vorgabe
Description: Übergang asymmetrisch
Pset_DistributionFlowElementCommon - Reference: Übergang asymmetrisch 277154; sets with these values: 2
Andere - Typ: Übergang asymmetrisch 277154; Familie: Übergang asymmetrisch 277154; Familie und Typ: Übergang asymmetrisch 277154: Übergang asymmetrisch 277154; Typ-ID: 2533836
Abhängigkeiten - Höhe von Ebene: 0 m; Verschieben mit umliegenden Elementen: no
Bemaßungen - Fläche: 1.23953 m2; Volumen: 0.270375 m3
IFC-Parameter - In IFC-Datei exportieren: Nach Typ; Pset MEP.Tech-Material (ID): 1; In IFC exportieren als: ifcflowfitting; NameOverride: Übergang asymmetrisch; IfcPresentationLayer: 0-TFT-L_Aussenluft; ObjectTypeOverride: Übergang asymmetrisch; Pset MEP.Geom-Surface (m2): 5.6921; Pset MEP.Name: Übergang asymmetrisch; IfcDescription: Übergang asymmetrisch; Pset MEP.Geom-Length (mm): 300; Pset MEP.Abbreviation: UA; Pset MEP.Tech-Medium: L_Aussenluft; Pset MEP.Tech-Weight (kg): 45.5368; Pset MEP.Geom-Offset to edge 1 (mm): 50; Pset MEP.Geom-Offset to edge 2 (mm): 0; Pset MEP.Geom-Section 1 side 1 (mm): 1200; Pset MEP.Geom-Section 1 side 2 (mm): 1800; Pset MEP.Geom-Section 2 side 1 (mm): 1300; Pset MEP.Geom-Section 2 side 2 (mm): 900
Phasen - Phase erstellt: Phase 01

# IfcFlowFitting: Übergang asymmetrisch 277344:Übergang asymmetrisch 277344, Übergang asymmetrisch
In: 1. Obergeschoss
Type - Material: IfcSurfaceStyle #274455
Type - Andere - Kategorie: Allgemeines Modell; Familienname: Übergang asymmetrisch 277344
Type - ID-Daten - Typname: Übergang asymmetrisch 277344
Type - IFC-Parameter - Typ in IFC-Datei exportieren: Vorgabe
Description: Übergang asymmetrisch
Pset_DistributionFlowElementCommon - Reference: Übergang asymmetrisch 277344; sets with these values: 2
Andere - Typ: Übergang asymmetrisch 277344; Familie: Übergang asymmetrisch 277344; Familie und Typ: Übergang asymmetrisch 277344: Übergang asymmetrisch 277344; Typ-ID: 2533850
Abhängigkeiten - Höhe von Ebene: 0 m; Verschieben mit umliegenden Elementen: no
Bemaßungen - Fläche: 1.12759 m2; Volumen: 0.171523 m3
IFC-Parameter - In IFC-Datei exportieren: Nach Typ; Pset MEP.Tech-Material (ID): 1; In IFC exportieren als: ifcflowfitting; NameOverride: Übergang asymmetrisch; IfcPresentationLayer: 0-TFT-L_Fortluft; ObjectTypeOverride: Übergang asymmetrisch; Pset MEP.Geom-Surface (m2): 5.12749; Pset MEP.Name: Übergang asymmetrisch; IfcDescription: Übergang asymmetrisch; Pset MEP.Geom-Length (mm): 300.516; Pset MEP.Abbreviation: UA; Pset MEP.Tech-Medium: L_Fortluft; Pset MEP.Tech-Weight (kg): 41.0199; Pset MEP.Geom-Offset to edge 1 (mm): 100; Pset MEP.Geom-Offset to edge 2 (mm): 800; Pset MEP.Geom-Section 1 side 1 (mm): 1000; Pset MEP.Geom-Section 1 side 2 (mm): 1000; Pset MEP.Geom-Section 2 side 1 (mm): 1200; Pset MEP.Geom-Section 2 side 2 (mm): 1800
Phasen - Phase erstellt: Phase 01

# IfcFlowFitting: Übergang asymmetrisch 851519:Übergang asymmetrisch 851519, Übergang asymmetrisch
In: Erdgeschoss
Type - Material: IfcSurfaceStyle #271263
Type - Andere - Kategorie: Allgemeines Modell; Familienname: Übergang asymmetrisch 851519
Type - ID-Daten - Typname: Übergang asymmetrisch 851519
Type - IFC-Parameter - Typ in IFC-Datei exportieren: Vorgabe
Description: Übergang asymmetrisch
Pset_DistributionFlowElementCommon - Reference: Übergang asymmetrisch 851519; sets with these values: 2
Andere - Typ: Übergang asymmetrisch 851519; Familie: Übergang asymmetrisch 851519; Familie und Typ: Übergang asymmetrisch 851519: Übergang asymmetrisch 851519; Typ-ID: 2539393
Abhängigkeiten - Höhe von Ebene: 0 m; Verschieben mit umliegenden Elementen: no
Bemaßungen - Fläche: 1.47003 m2; Volumen: 0.138 m3
IFC-Parameter - In IFC-Datei exportieren: Nach Typ; Pset MEP.Tech-Material (ID): 1; Pset MEP.Geom-Offset to edge 1 (mm): 0; Pset MEP.Geom-Offset to edge 2 (mm): 0; Pset MEP.Geom-Section 1 side 2 (mm): 1800; Pset MEP.Geom-Section 2 side 2 (mm): 900; In IFC exportieren als: ifcflowfitting; NameOverride: Übergang asymmetrisch; IfcPresentationLayer: 0-TFT-L_Zuluft; ObjectTypeOverride: Übergang asymmetrisch; Pset MEP.Geom-Surface (m2): 6.26929; Pset MEP.Name: Übergang asymmetrisch; IfcDescription: Übergang asymmetrisch; Pset MEP.Geom-Length (mm): 200; Pset MEP.Abbreviation: UA; Pset MEP.Tech-Medium: L_Zuluft; Pset MEP.Tech-Weight (kg): 50.1543; Pset MEP.Geom-Section 1 side 1 (mm): 1600; Pset MEP.Geom-Section 2 side 1 (mm): 800
Phasen - Phase erstellt: Phase 01

# IfcFlowFitting: Übergang asymmetrisch:Übergang asymmetrisch, Übergang asymmetrisch
In: 1. Obergeschoss
Type - Material: IfcSurfaceStyle #271263
Type - Andere - Kategorie: Allgemeines Modell; Familienname: Übergang asymmetrisch
Type - ID-Daten - Typname: Übergang asymmetrisch
Type - IFC-Parameter - Typ in IFC-Datei exportieren: Vorgabe
Description: Übergang asymmetrisch
Pset_DistributionFlowElementCommon - Reference: Übergang asymmetrisch; sets with these values: 2
Andere - Typ: Übergang asymmetrisch; Familie: Übergang asymmetrisch; Familie und Typ: Übergang asymmetrisch: Übergang asymmetrisch; Typ-ID: 2533593
Abhängigkeiten - Höhe von Ebene: 0 m; Verschieben mit umliegenden Elementen: no
Bemaßungen - Fläche: 3.07396 m2; Volumen: 0.821625 m3
IFC-Parameter - In IFC-Datei exportieren: Nach Typ; Pset MEP.Tech-Material (ID): 1; In IFC exportieren als: ifcflowfitting; NameOverride: Übergang asymmetrisch; IfcPresentationLayer: 0-TFT-L_Zuluft; ObjectTypeOverride: Übergang asymmetrisch; Pset MEP.Geom-Surface (m2): 8.0252; Pset MEP.Name: Übergang asymmetrisch; IfcDescription: Übergang asymmetrisch; Pset MEP.Geom-Length (mm): 1000; Pset MEP.Abbreviation: UA; Pset MEP.Tech-Medium: L_Zuluft; Pset MEP.Tech-Weight (kg): 64.2016; Pset MEP.Geom-Offset to edge 1 (mm): 0; Pset MEP.Geom-Offset to edge 2 (mm): 338.186; Pset MEP.Geom-Section 1 side 1 (mm): 1500; Pset MEP.Geom-Section 1 side 2 (mm): 1530; Pset MEP.Geom-Section 2 side 1 (mm): 1500; Pset MEP.Geom-Section 2 side 2 (mm): 1000
Phasen - Phase erstellt: Phase 01

# IfcFlowFitting: Übergangsstück 14455:Übergangsstück 14455, Übergangsstück
In: 1. Obergeschoss
Type - Material: IfcSurfaceStyle #9317
Type - Andere - Kategorie: Allgemeines Modell; Familienname: Übergangsstück 14455
Type - ID-Daten - Typname: Übergangsstück 14455
Type - IFC-Parameter - Typ in IFC-Datei exportieren: Vorgabe
Description: Übergangsstück
Pset_DistributionFlowElementCommon - Reference: Übergangsstück 14455; sets with these values: 2
Andere - Typ: Übergangsstück 14455; Familie: Übergangsstück 14455; Familie und Typ: Übergangsstück 14455: Übergangsstück 14455; Typ-ID: 2531561
Abhängigkeiten - Höhe von Ebene: 0 m; Verschieben mit umliegenden Elementen: no
Bemaßungen - Fläche: 0.104798 m2; Volumen: 0.0102705 m3
IFC-Parameter - In IFC-Datei exportieren: Nach Typ; Pset MEP.Tech-Insulation thickness (mm): 100; Pset MEP.Geom-DN1: 150; In IFC exportieren als: ifcflowfitting; NameOverride: Übergangsstück; IfcPresentationLayer: 0-TFT-H_Vorlauf; ObjectTypeOverride: Übergangsstück; Pset MEP.Name: Übergangsstück; IfcDescription: Übergangsstück; Pset MEP.Tech-Material: nach DIN 2616; Pset MEP.Geom-DN2: 80; Pset MEP.Geom-Outer Ø1 (mm): 168.3; Pset MEP.Geom-Outer Ø2 (mm): 88.9; Pset MEP.Geom-Length (mm): 140
Phasen - Phase erstellt: Phase 01

# IfcFlowFitting: Übergangsstück 221251:Übergangsstück 221251, Übergangsstück
In: 1. Obergeschoss
Type - Material: IfcSurfaceStyle #9317
Type - Andere - Kategorie: Allgemeines Modell; Familienname: Übergangsstück 221251
Type - ID-Daten - Typname: Übergangsstück 221251
Type - IFC-Parameter - Typ in IFC-Datei exportieren: Vorgabe
Description: Übergangsstück
Pset_DistributionFlowElementCommon - Reference: Übergangsstück 221251; sets with these values: 2
Andere - Typ: Übergangsstück 221251; Familie: Übergangsstück 221251; Familie und Typ: Übergangsstück 221251: Übergangsstück 221251; Typ-ID: 2531716
Abhängigkeiten - Höhe von Ebene: 0 m; Verschieben mit umliegenden Elementen: no
Bemaßungen - Fläche: 0.104798 m2; Volumen: 0.0102705 m3
IFC-Parameter - In IFC-Datei exportieren: Nach Typ; Pset MEP.Tech-Insulation thickness (mm): 100; Pset MEP.Geom-DN1: 150; Pset MEP.Geom-DN2: 80; Pset MEP.Geom-Length (mm): 140; In IFC exportieren als: ifcflowfitting; NameOverride: Übergangsstück; IfcPresentationLayer: 0-TFT-H_Vorlauf; ObjectTypeOverride: Übergangsstück; Pset MEP.Name: Übergangsstück; IfcDescription: Übergangsstück; Pset MEP.Tech-Material: nach DIN 2616; Pset MEP.Geom-Outer Ø1 (mm): 168.3; Pset MEP.Geom-Outer Ø2 (mm): 88.9
Phasen - Phase erstellt: Phase 01

# IfcFlowFitting: Übergangsstück 221517:Übergangsstück 221517, Übergangsstück
In: 1. Obergeschoss
Type - Material: IfcSurfaceStyle #9317
Type - Andere - Kategorie: Allgemeines Modell; Familienname: Übergangsstück 221517
Type - ID-Daten - Typname: Übergangsstück 221517
Type - IFC-Parameter - Typ in IFC-Datei exportieren: Vorgabe
Description: Übergangsstück
Pset_DistributionFlowElementCommon - Reference: Übergangsstück 221517; sets with these values: 2
Andere - Typ: Übergangsstück 221517; Familie: Übergangsstück 221517; Familie und Typ: Übergangsstück 221517: Übergangsstück 221517; Typ-ID: 2531796
Abhängigkeiten - Höhe von Ebene: 0 m; Verschieben mit umliegenden Elementen: no
Bemaßungen - Fläche: 0.104798 m2; Volumen: 0.0102705 m3
IFC-Parameter - In IFC-Datei exportieren: Nach Typ; Pset MEP.Tech-Insulation thickness (mm): 100; Pset MEP.Geom-DN1: 150; Pset MEP.Geom-DN2: 80; Pset MEP.Geom-Length (mm): 140; In IFC exportieren als: ifcflowfitting; NameOverride: Übergangsstück; IfcPresentationLayer: 0-TFT-H_Vorlauf; ObjectTypeOverride: Übergangsstück; Pset MEP.Name: Übergangsstück; IfcDescription: Übergangsstück; Pset MEP.Tech-Material: nach DIN 2616; Pset MEP.Geom-Outer Ø1 (mm): 168.3; Pset MEP.Geom-Outer Ø2 (mm): 88.9
Phasen - Phase erstellt: Phase 01

# IfcFlowFitting: Übergangsstück 222976:Übergangsstück 222976, Übergangsstück
In: 1. Obergeschoss
Type - Material: IfcSurfaceStyle #9317
Type - Andere - Kategorie: Allgemeines Modell; Familienname: Übergangsstück 222976
Type - ID-Daten - Typname: Übergangsstück 222976
Type - IFC-Parameter - Typ in IFC-Datei exportieren: Vorgabe
Description: Übergangsstück
Pset_DistributionFlowElementCommon - Reference: Übergangsstück 222976; sets with these values: 2
Andere - Typ: Übergangsstück 222976; Familie: Übergangsstück 222976; Familie und Typ: Übergangsstück 222976: Übergangsstück 222976; Typ-ID: 2531880
Abhängigkeiten - Höhe von Ebene: 0 m; Verschieben mit umliegenden Elementen: no
Bemaßungen - Fläche: 0.141914 m2; Volumen: 0.0139939 m3
IFC-Parameter - In IFC-Datei exportieren: Nach Typ; Pset MEP.Tech-Insulation thickness (mm): 100; Pset MEP.Geom-DN2: 200; Pset MEP.Geom-DN1: 150; Pset MEP.Geom-Length (mm): 152; In IFC exportieren als: ifcflowfitting; NameOverride: Übergangsstück; IfcPresentationLayer: 0-TFT-H_Vorlauf; ObjectTypeOverride: Übergangsstück; Pset MEP.Name: Übergangsstück; IfcDescription: Übergangsstück; Pset MEP.Tech-Material: nach DIN 2616; Pset MEP.Geom-Outer Ø1 (mm): 168.3; Pset MEP.Geom-Outer Ø2 (mm): 219.1
Phasen - Phase erstellt: Phase 01

# IfcFlowFitting: Übergangsstück 223281:Übergangsstück 223281, Übergangsstück
In: 1. Obergeschoss
Type - Material: IfcSurfaceStyle #9317
Type - Andere - Kategorie: Allgemeines Modell; Familienname: Übergangsstück 223281
Type - ID-Daten - Typname: Übergangsstück 223281
Type - IFC-Parameter - Typ in IFC-Datei exportieren: Vorgabe
Description: Übergangsstück
Pset_DistributionFlowElementCommon - Reference: Übergangsstück 223281; sets with these values: 2
Andere - Typ: Übergangsstück 223281; Familie: Übergangsstück 223281; Familie und Typ: Übergangsstück 223281: Übergangsstück 223281; Typ-ID: 2531894
Abhängigkeiten - Höhe von Ebene: 0 m; Verschieben mit umliegenden Elementen: no
Bemaßungen - Fläche: 0.141914 m2; Volumen: 0.0139939 m3
IFC-Parameter - In IFC-Datei exportieren: Nach Typ; Pset MEP.Tech-Insulation thickness (mm): 100; Pset MEP.Geom-DN2: 200; Pset MEP.Geom-DN1: 150; Pset MEP.Geom-Length (mm): 152; In IFC exportieren als: ifcflowfitting; NameOverride: Übergangsstück; IfcPresentationLayer: 0-TFT-H_Vorlauf; ObjectTypeOverride: Übergangsstück; Pset MEP.Name: Übergangsstück; IfcDescription: Übergangsstück; Pset MEP.Tech-Material: nach DIN 2616; Pset MEP.Geom-Outer Ø1 (mm): 168.3; Pset MEP.Geom-Outer Ø2 (mm): 219.1
Phasen - Phase erstellt: Phase 01

# IfcFlowFitting: Übergangsstück 230215:Übergangsstück 230215, Übergangsstück
In: 1. Obergeschoss
Type - Material: IfcSurfaceStyle #9317
Type - Andere - Kategorie: Allgemeines Modell; Familienname: Übergangsstück 230215
Type - ID-Daten - Typname: Übergangsstück 230215
Type - IFC-Parameter - Typ in IFC-Datei exportieren: Vorgabe
Description: Übergangsstück
Pset_DistributionFlowElementCommon - Reference: Übergangsstück 230215; sets with these values: 2
Andere - Typ: Übergangsstück 230215; Familie: Übergangsstück 230215; Familie und Typ: Übergangsstück 230215: Übergangsstück 230215; Typ-ID: 2532186
Abhängigkeiten - Höhe von Ebene: 0 m; Verschieben mit umliegenden Elementen: no
Bemaßungen - Fläche: 0.0871331 m2; Volumen: 0.00666904 m3
IFC-Parameter - In IFC-Datei exportieren: Nach Typ; Pset MEP.Tech-Insulation thickness (mm): 100; Pset MEP.Geom-DN2: 125; In IFC exportieren als: ifcflowfitting; NameOverride: Übergangsstück; IfcPresentationLayer: 0-TFT-H_Vorlauf; ObjectTypeOverride: Übergangsstück; Pset MEP.Name: Übergangsstück; IfcDescription: Übergangsstück; Pset MEP.Tech-Material: nach DIN 2616; Pset MEP.Geom-DN1: 80; Pset MEP.Geom-Outer Ø1 (mm): 88.9; Pset MEP.Geom-Outer Ø2 (mm): 139.7; Pset MEP.Geom-Length (mm): 127
Phasen - Phase erstellt: Phase 01

# IfcFlowFitting: Übergangsstück 234729:Übergangsstück 234729, Übergangsstück
In: 1. Obergeschoss
Type - Material: IfcSurfaceStyle #9317
Type - Andere - Kategorie: Allgemeines Modell; Familienname: Übergangsstück 234729
Type - ID-Daten - Typname: Übergangsstück 234729
Type - IFC-Parameter - Typ in IFC-Datei exportieren: Vorgabe
Description: Übergangsstück
Pset_DistributionFlowElementCommon - Reference: Übergangsstück 234729; sets with these values: 2
Andere - Typ: Übergangsstück 234729; Familie: Übergangsstück 234729; Familie und Typ: Übergangsstück 234729: Übergangsstück 234729; Typ-ID: 2532235
Abhängigkeiten - Höhe von Ebene: 0 m; Verschieben mit umliegenden Elementen: no
Bemaßungen - Fläche: 0.111844 m2; Volumen: 0.0102325 m3
IFC-Parameter - In IFC-Datei exportieren: Nach Typ; Pset MEP.Tech-Insulation thickness (mm): 100; Pset MEP.Geom-DN2: 150; Pset MEP.Geom-Length (mm): 140; Pset MEP.Geom-DN1: 125; In IFC exportieren als: ifcflowfitting; NameOverride: Übergangsstück; IfcPresentationLayer: 0-TFT-H_Vorlauf; ObjectTypeOverride: Übergangsstück; Pset MEP.Name: Übergangsstück; IfcDescription: Übergangsstück; Pset MEP.Tech-Material: nach DIN 2616; Pset MEP.Geom-Outer Ø1 (mm): 139.7; Pset MEP.Geom-Outer Ø2 (mm): 168.3
Phasen - Phase erstellt: Phase 01

# IfcFlowFitting: Übergangsstück 236794:Übergangsstück 236794, Übergangsstück
In: 1. Obergeschoss
Type - Material: IfcSurfaceStyle #9317
Type - Andere - Kategorie: Allgemeines Modell; Familienname: Übergangsstück 236794
Type - ID-Daten - Typname: Übergangsstück 236794
Type - IFC-Parameter - Typ in IFC-Datei exportieren: Vorgabe
Description: Übergangsstück
Pset_DistributionFlowElementCommon - Reference: Übergangsstück 236794; sets with these values: 2
Andere - Typ: Übergangsstück 236794; Familie: Übergangsstück 236794; Familie und Typ: Übergangsstück 236794: Übergangsstück 236794; Typ-ID: 2532263
Abhängigkeiten - Höhe von Ebene: 0 m; Verschieben mit umliegenden Elementen: no
Bemaßungen - Fläche: 0.0871331 m2; Volumen: 0.00666904 m3
IFC-Parameter - In IFC-Datei exportieren: Nach Typ; Pset MEP.Tech-Insulation thickness (mm): 100; Pset MEP.Geom-DN2: 125; Pset MEP.Geom-DN1: 80; Pset MEP.Geom-Length (mm): 127; In IFC exportieren als: ifcflowfitting; NameOverride: Übergangsstück; IfcPresentationLayer: 0-TFT-H_Vorlauf; ObjectTypeOverride: Übergangsstück; Pset MEP.Name: Übergangsstück; IfcDescription: Übergangsstück; Pset MEP.Tech-Material: nach DIN 2616; Pset MEP.Geom-Outer Ø1 (mm): 88.9; Pset MEP.Geom-Outer Ø2 (mm): 139.7
Phasen - Phase erstellt: Phase 01

# IfcFlowFitting: Übergangsstück 236955:Übergangsstück 236955, Übergangsstück
In: 1. Obergeschoss
Type - Material: IfcSurfaceStyle #9317
Type - Andere - Kategorie: Allgemeines Modell; Familienname: Übergangsstück 236955
Type - ID-Daten - Typname: Übergangsstück 236955
Type - IFC-Parameter - Typ in IFC-Datei exportieren: Vorgabe
Description: Übergangsstück
Pset_DistributionFlowElementCommon - Reference: Übergangsstück 236955; sets with these values: 2
Andere - Typ: Übergangsstück 236955; Familie: Übergangsstück 236955; Familie und Typ: Übergangsstück 236955: Übergangsstück 236955; Typ-ID: 2532312
Abhängigkeiten - Höhe von Ebene: 0 m; Verschieben mit umliegenden Elementen: no
Bemaßungen - Fläche: 0.111844 m2; Volumen: 0.0102325 m3
IFC-Parameter - In IFC-Datei exportieren: Nach Typ; Pset MEP.Tech-Insulation thickness (mm): 100; Pset MEP.Geom-DN2: 150; Pset MEP.Geom-Length (mm): 140; Pset MEP.Geom-DN1: 125; In IFC exportieren als: ifcflowfitting; NameOverride: Übergangsstück; IfcPresentationLayer: 0-TFT-H_Vorlauf; ObjectTypeOverride: Übergangsstück; Pset MEP.Name: Übergangsstück; IfcDescription: Übergangsstück; Pset MEP.Tech-Material: nach DIN 2616; Pset MEP.Geom-Outer Ø1 (mm): 139.7; Pset MEP.Geom-Outer Ø2 (mm): 168.3
Phasen - Phase erstellt: Phase 01

# IfcFlowFitting: Übergangsstück 237047:Übergangsstück 237047, Übergangsstück
In: 1. Obergeschoss
Type - Material: IfcSurfaceStyle #9317
Type - Andere - Kategorie: Allgemeines Modell; Familienname: Übergangsstück 237047
Type - ID-Daten - Typname: Übergangsstück 237047
Type - IFC-Parameter - Typ in IFC-Datei exportieren: Vorgabe
Description: Übergangsstück
Pset_DistributionFlowElementCommon - Reference: Übergangsstück 237047; sets with these values: 2
Andere - Typ: Übergangsstück 237047; Familie: Übergangsstück 237047; Familie und Typ: Übergangsstück 237047: Übergangsstück 237047; Typ-ID: 2532340
Abhängigkeiten - Höhe von Ebene: 0 m; Verschieben mit umliegenden Elementen: no
Bemaßungen - Fläche: 0.0871331 m2; Volumen: 0.00666904 m3
IFC-Parameter - In IFC-Datei exportieren: Nach Typ; Pset MEP.Tech-Insulation thickness (mm): 100; Pset MEP.Geom-DN2: 125; Pset MEP.Geom-DN1: 80; Pset MEP.Geom-Length (mm): 127; In IFC exportieren als: ifcflowfitting; NameOverride: Übergangsstück; IfcPresentationLayer: 0-TFT-H_Vorlauf; ObjectTypeOverride: Übergangsstück; Pset MEP.Name: Übergangsstück; IfcDescription: Übergangsstück; Pset MEP.Tech-Material: nach DIN 2616; Pset MEP.Geom-Outer Ø1 (mm): 88.9; Pset MEP.Geom-Outer Ø2 (mm): 139.7
Phasen - Phase erstellt: Phase 01

# IfcFlowFitting: Übergangsstück 237208:Übergangsstück 237208, Übergangsstück
In: 1. Obergeschoss
Type - Material: IfcSurfaceStyle #9317
Type - Andere - Kategorie: Allgemeines Modell; Familienname: Übergangsstück 237208
Type - ID-Daten - Typname: Übergangsstück 237208
Type - IFC-Parameter - Typ in IFC-Datei exportieren: Vorgabe
Description: Übergangsstück
Pset_DistributionFlowElementCommon - Reference: Übergangsstück 237208; sets with these values: 2
Andere - Typ: Übergangsstück 237208; Familie: Übergangsstück 237208; Familie und Typ: Übergangsstück 237208: Übergangsstück 237208; Typ-ID: 2532389
Abhängigkeiten - Höhe von Ebene: 0 m; Verschieben mit umliegenden Elementen: no
Bemaßungen - Fläche: 0.111844 m2; Volumen: 0.0102325 m3
IFC-Parameter - In IFC-Datei exportieren: Nach Typ; Pset MEP.Tech-Insulation thickness (mm): 100; Pset MEP.Geom-DN2: 150; Pset MEP.Geom-Length (mm): 140; Pset MEP.Geom-DN1: 125; In IFC exportieren als: ifcflowfitting; NameOverride: Übergangsstück; IfcPresentationLayer: 0-TFT-H_Vorlauf; ObjectTypeOverride: Übergangsstück; Pset MEP.Name: Übergangsstück; IfcDescription: Übergangsstück; Pset MEP.Tech-Material: nach DIN 2616; Pset MEP.Geom-Outer Ø1 (mm): 139.7; Pset MEP.Geom-Outer Ø2 (mm): 168.3
Phasen - Phase erstellt: Phase 01

# IfcFlowFitting: Übergangsstück 253935:Übergangsstück 253935, Übergangsstück
In: 1. Obergeschoss
Type - Material: IfcSurfaceStyle #1741
Type - Andere - Kategorie: Allgemeines Modell; Familienname: Übergangsstück 253935
Type - ID-Daten - Typname: Übergangsstück 253935
Type - IFC-Parameter - Typ in IFC-Datei exportieren: Vorgabe
Description: Übergangsstück
Pset_DistributionFlowElementCommon - Reference: Übergangsstück 253935; sets with these values: 2
Andere - Typ: Übergangsstück 253935; Familie: Übergangsstück 253935; Familie und Typ: Übergangsstück 253935: Übergangsstück 253935; Typ-ID: 2532953
Abhängigkeiten - Höhe von Ebene: 0 m; Verschieben mit umliegenden Elementen: no
Bemaßungen - Fläche: 0.0514981 m2; Volumen: 0.00410093 m3
IFC-Parameter - In IFC-Datei exportieren: Nach Typ; Pset MEP.Tech-Insulation thickness (mm): 100; Pset MEP.Geom-DN1: 80; Pset MEP.Geom-DN2: 65; In IFC exportieren als: ifcflowfitting; NameOverride: Übergangsstück; IfcPresentationLayer: 0-TFT-H_Ruecklauf; ObjectTypeOverride: Übergangsstück; Pset MEP.Name: Übergangsstück; IfcDescription: Übergangsstück; Pset MEP.Tech-Material: nach DIN 2616; Pset MEP.Geom-Outer Ø1 (mm): 88.9; Pset MEP.Geom-Outer Ø2 (mm): 76.1; Pset MEP.Geom-Length (mm): 90
Phasen - Phase erstellt: Phase 01

# IfcFlowFitting: Übergangsstück 260035:Übergangsstück 260035, Übergangsstück
In: 1. Obergeschoss
Type - Material: IfcSurfaceStyle #9317
Type - Andere - Kategorie: Allgemeines Modell; Familienname: Übergangsstück 260035
Type - ID-Daten - Typname: Übergangsstück 260035
Type - IFC-Parameter - Typ in IFC-Datei exportieren: Vorgabe
Description: Übergangsstück
Pset_DistributionFlowElementCommon - Reference: Übergangsstück 260035; sets with these values: 2
Andere - Typ: Übergangsstück 260035; Familie: Übergangsstück 260035; Familie und Typ: Übergangsstück 260035: Übergangsstück 260035; Typ-ID: 2533065
Abhängigkeiten - Höhe von Ebene: 0 m; Verschieben mit umliegenden Elementen: no
Bemaßungen - Fläche: 0.0514981 m2; Volumen: 0.00410093 m3
IFC-Parameter - In IFC-Datei exportieren: Nach Typ; Pset MEP.Tech-Insulation thickness (mm): 100; Pset MEP.Geom-DN1: 80; Pset MEP.Geom-DN2: 65; Pset MEP.Geom-Length (mm): 90; In IFC exportieren als: ifcflowfitting; NameOverride: Übergangsstück; IfcPresentationLayer: 0-TFT-H_Vorlauf; ObjectTypeOverride: Übergangsstück; Pset MEP.Name: Übergangsstück; IfcDescription: Übergangsstück; Pset MEP.Tech-Material: nach DIN 2616; Pset MEP.Geom-Outer Ø1 (mm): 88.9; Pset MEP.Geom-Outer Ø2 (mm): 76.1
Phasen - Phase erstellt: Phase 01

# IfcFlowFitting: Übergangsstück 264752:Übergangsstück 264752, Übergangsstück
In: 1. Obergeschoss
Type - Material: IfcSurfaceStyle #9317
Type - Andere - Kategorie: Allgemeines Modell; Familienname: Übergangsstück 264752
Type - ID-Daten - Typname: Übergangsstück 264752
Type - IFC-Parameter - Typ in IFC-Datei exportieren: Vorgabe
Description: Übergangsstück
Pset_DistributionFlowElementCommon - Reference: Übergangsstück 264752; sets with these values: 2
Andere - Typ: Übergangsstück 264752; Familie: Übergangsstück 264752; Familie und Typ: Übergangsstück 264752: Übergangsstück 264752; Typ-ID: 2533163
Abhängigkeiten - Höhe von Ebene: 0 m; Verschieben mit umliegenden Elementen: no
Bemaßungen - Fläche: 0.135542 m2; Volumen: 0.014883 m3
IFC-Parameter - In IFC-Datei exportieren: Nach Typ; Pset MEP.Tech-Insulation thickness (mm): 100; Pset MEP.Geom-DN1: 200; Pset MEP.Geom-DN2: 100; Pset MEP.Geom-Length (mm): 152; In IFC exportieren als: ifcflowfitting; NameOverride: Übergangsstück; IfcPresentationLayer: 0-TFT-H_Vorlauf; ObjectTypeOverride: Übergangsstück; Pset MEP.Name: Übergangsstück; IfcDescription: Übergangsstück; Pset MEP.Tech-Material: nach DIN 2616; Pset MEP.Geom-Outer Ø1 (mm): 219.1; Pset MEP.Geom-Outer Ø2 (mm): 114.3
Phasen - Phase erstellt: Phase 01

# IfcFlowFitting: Übergangsstück 265726:Übergangsstück 265726, Übergangsstück
In: 1. Obergeschoss
Type - Material: IfcSurfaceStyle #9317
Type - Andere - Kategorie: Allgemeines Modell; Familienname: Übergangsstück 265726
Type - ID-Daten - Typname: Übergangsstück 265726
Type - IFC-Parameter - Typ in IFC-Datei exportieren: Vorgabe
Description: Übergangsstück
Pset_DistributionFlowElementCommon - Reference: Übergangsstück 265726; sets with these values: 2
Andere - Typ: Übergangsstück 265726; Familie: Übergangsstück 265726; Familie und Typ: Übergangsstück 265726: Übergangsstück 265726; Typ-ID: 2533184
Abhängigkeiten - Höhe von Ebene: 0 m; Verschieben mit umliegenden Elementen: no
Bemaßungen - Fläche: 0.135542 m2; Volumen: 0.0108282 m3
IFC-Parameter - In IFC-Datei exportieren: Nach Typ; Pset MEP.Tech-Insulation thickness (mm): 100; Pset MEP.Geom-DN2: 200; Pset MEP.Geom-DN1: 100; Pset MEP.Geom-Length (mm): 152; In IFC exportieren als: ifcflowfitting; NameOverride: Übergangsstück; IfcPresentationLayer: 0-TFT-H_Vorlauf; ObjectTypeOverride: Übergangsstück; Pset MEP.Name: Übergangsstück; IfcDescription: Übergangsstück; Pset MEP.Tech-Material: nach DIN 2616; Pset MEP.Geom-Outer Ø1 (mm): 114.3; Pset MEP.Geom-Outer Ø2 (mm): 219.1
Phasen - Phase erstellt: Phase 01

# IfcFlowFitting: Übergangsstück 304753:Übergangsstück 304753, Übergangsstück
In: 1. Obergeschoss
Type - Material: IfcSurfaceStyle #1741
Type - Andere - Kategorie: Allgemeines Modell; Familienname: Übergangsstück 304753
Type - ID-Daten - Typname: Übergangsstück 304753
Type - IFC-Parameter - Typ in IFC-Datei exportieren: Vorgabe
Description: Übergangsstück
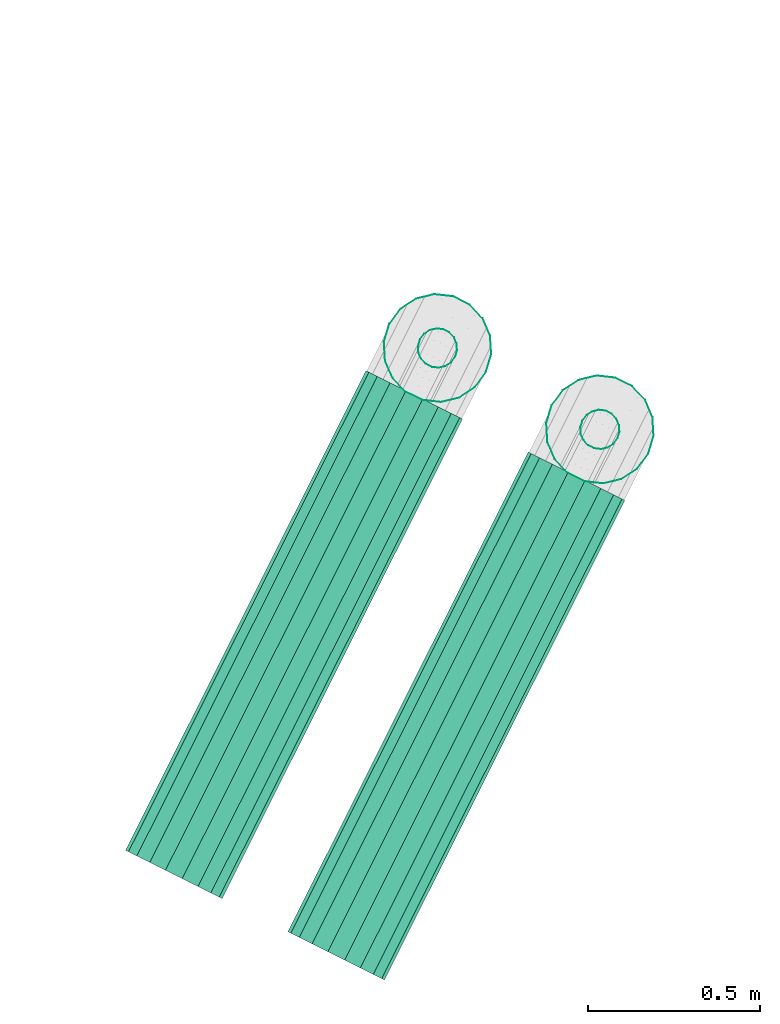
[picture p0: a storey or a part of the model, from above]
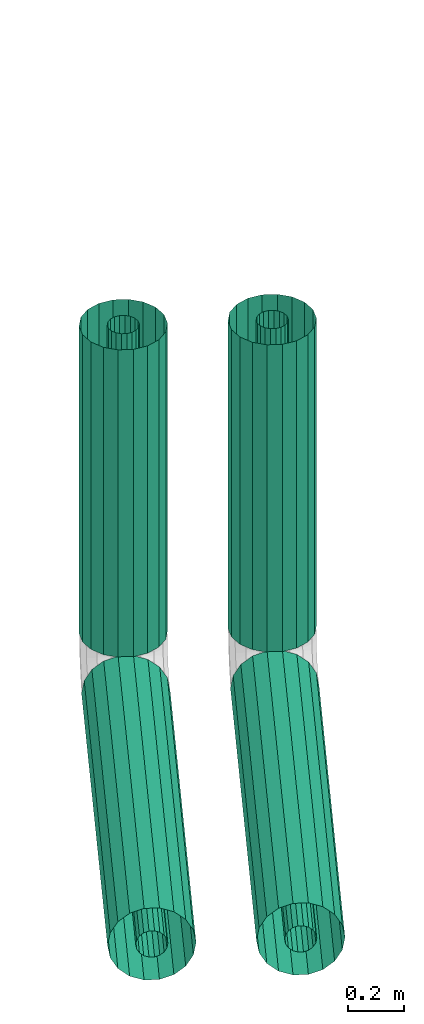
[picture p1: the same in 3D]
Properties of the parts of a building model (IFC2X3), part 13 of 23

# IfcFlowFitting: Übergangsstück 304753:Übergangsstück 304753, Übergangsstück
Pset_DistributionFlowElementCommon - Reference: Übergangsstück 304753; sets with these values: 2
Andere - Typ: Übergangsstück 304753; Familie: Übergangsstück 304753; Familie und Typ: Übergangsstück 304753: Übergangsstück 304753; Typ-ID: 2534937
Abhängigkeiten - Höhe von Ebene: 0 m; Verschieben mit umliegenden Elementen: no
Bemaßungen - Fläche: 0.141914 m2; Volumen: 0.0139939 m3
IFC-Parameter - In IFC-Datei exportieren: Nach Typ; Pset MEP.Tech-Insulation thickness (mm): 100; Pset MEP.Geom-DN2: 200; Pset MEP.Geom-DN1: 150; Pset MEP.Geom-Length (mm): 152; In IFC exportieren als: ifcflowfitting; NameOverride: Übergangsstück; IfcPresentationLayer: 0-TFT-H_Ruecklauf; ObjectTypeOverride: Übergangsstück; Pset MEP.Name: Übergangsstück; IfcDescription: Übergangsstück; Pset MEP.Tech-Material: nach DIN 2616; Pset MEP.Geom-Outer Ø1 (mm): 168.3; Pset MEP.Geom-Outer Ø2 (mm): 219.1
Phasen - Phase erstellt: Phase 01

# IfcFlowFitting: Übergangsstück 305407:Übergangsstück 305407, Übergangsstück
In: Erdgeschoss
Type - Material: IfcSurfaceStyle #1741
Type - Andere - Kategorie: Allgemeines Modell; Familienname: Übergangsstück 305407
Type - ID-Daten - Typname: Übergangsstück 305407
Type - IFC-Parameter - Typ in IFC-Datei exportieren: Vorgabe
Description: Übergangsstück
Pset_DistributionFlowElementCommon - Reference: Übergangsstück 305407; sets with these values: 2
Andere - Typ: Übergangsstück 305407; Familie: Übergangsstück 305407; Familie und Typ: Übergangsstück 305407: Übergangsstück 305407; Typ-ID: 2534979
Abhängigkeiten - Höhe von Ebene: 0 m; Verschieben mit umliegenden Elementen: no
Bemaßungen - Fläche: 0.0253671 m2; Volumen: 0.00115185 m3
IFC-Parameter - In IFC-Datei exportieren: Nach Typ; Pset MEP.Tech-Insulation thickness (mm): 100; Pset MEP.Geom-DN2: 100; Pset MEP.Geom-DN1: 125; Pset MEP.Geom-Length (mm): 127; In IFC exportieren als: ifcflowfitting; NameOverride: Übergangsstück; IfcPresentationLayer: 0-TFT-H_Ruecklauf; ObjectTypeOverride: Übergangsstück; Pset MEP.Name: Übergangsstück; IfcDescription: Übergangsstück; Pset MEP.Tech-Material: nach DIN 2616; Pset MEP.Geom-Outer Ø1 (mm): 139.7; Pset MEP.Geom-Outer Ø2 (mm): 114.3
Phasen - Phase erstellt: Phase 01

# IfcFlowFitting: Übergangsstück 307767:Übergangsstück 307767, Übergangsstück
In: Erdgeschoss
Type - Material: IfcSurfaceStyle #1741
Type - Andere - Kategorie: Allgemeines Modell; Familienname: Übergangsstück 307767
Type - ID-Daten - Typname: Übergangsstück 307767
Type - IFC-Parameter - Typ in IFC-Datei exportieren: Vorgabe
Description: Übergangsstück
Pset_DistributionFlowElementCommon - Reference: Übergangsstück 307767; sets with these values: 2
Andere - Typ: Übergangsstück 307767; Familie: Übergangsstück 307767; Familie und Typ: Übergangsstück 307767: Übergangsstück 307767; Typ-ID: 2535000
Abhängigkeiten - Höhe von Ebene: 0 m; Verschieben mit umliegenden Elementen: no
Bemaßungen - Fläche: 0.0253671 m2; Volumen: 0.00115185 m3
IFC-Parameter - In IFC-Datei exportieren: Nach Typ; Pset MEP.Tech-Insulation thickness (mm): 100; Pset MEP.Geom-DN2: 100; Pset MEP.Geom-DN1: 125; Pset MEP.Geom-Length (mm): 127; In IFC exportieren als: ifcflowfitting; NameOverride: Übergangsstück; IfcPresentationLayer: 0-TFT-H_Ruecklauf; ObjectTypeOverride: Übergangsstück; Pset MEP.Name: Übergangsstück; IfcDescription: Übergangsstück; Pset MEP.Tech-Material: nach DIN 2616; Pset MEP.Geom-Outer Ø1 (mm): 139.7; Pset MEP.Geom-Outer Ø2 (mm): 114.3
Phasen - Phase erstellt: Phase 01

# IfcFlowFitting: Übergangsstück 307836:Übergangsstück 307836, Übergangsstück
In: 1. Obergeschoss
Type - Material: IfcSurfaceStyle #1741
Type - Andere - Kategorie: Allgemeines Modell; Familienname: Übergangsstück 307836
Type - ID-Daten - Typname: Übergangsstück 307836
Type - IFC-Parameter - Typ in IFC-Datei exportieren: Vorgabe
Description: Übergangsstück
Pset_DistributionFlowElementCommon - Reference: Übergangsstück 307836; sets with these values: 2
Andere - Typ: Übergangsstück 307836; Familie: Übergangsstück 307836; Familie und Typ: Übergangsstück 307836: Übergangsstück 307836; Typ-ID: 2535021
Abhängigkeiten - Höhe von Ebene: 0 m; Verschieben mit umliegenden Elementen: no
Bemaßungen - Fläche: 0.0316316 m2; Volumen: 0.00119481 m3
IFC-Parameter - In IFC-Datei exportieren: Nach Typ; Pset MEP.Tech-Insulation thickness (mm): 100; Pset MEP.Geom-DN1: 100; Pset MEP.Geom-DN2: 150; Pset MEP.Geom-Length (mm): 140; In IFC exportieren als: ifcflowfitting; NameOverride: Übergangsstück; IfcPresentationLayer: 0-TFT-H_Ruecklauf; ObjectTypeOverride: Übergangsstück; Pset MEP.Name: Übergangsstück; IfcDescription: Übergangsstück; Pset MEP.Tech-Material: nach DIN 2616; Pset MEP.Geom-Outer Ø1 (mm): 114.3; Pset MEP.Geom-Outer Ø2 (mm): 168.3
Phasen - Phase erstellt: Phase 01

# IfcFlowFitting: Übergangsstück 309304:Übergangsstück 309304, Übergangsstück
In: Erdgeschoss
Type - Material: IfcSurfaceStyle #1741
Type - Andere - Kategorie: Allgemeines Modell; Familienname: Übergangsstück 309304
Type - ID-Daten - Typname: Übergangsstück 309304
Type - IFC-Parameter - Typ in IFC-Datei exportieren: Vorgabe
Description: Übergangsstück
Pset_DistributionFlowElementCommon - Reference: Übergangsstück 309304; sets with these values: 2
Andere - Typ: Übergangsstück 309304; Familie: Übergangsstück 309304; Familie und Typ: Übergangsstück 309304: Übergangsstück 309304; Typ-ID: 2535056
Abhängigkeiten - Höhe von Ebene: 0 m; Verschieben mit umliegenden Elementen: no
Bemaßungen - Fläche: 0.0339137 m2; Volumen: 0.00156123 m3
IFC-Parameter - In IFC-Datei exportieren: Nach Typ; Pset MEP.Tech-Insulation thickness (mm): 100; Pset MEP.Geom-DN2: 150; Pset MEP.Geom-Length (mm): 140; Pset MEP.Geom-DN1: 125; In IFC exportieren als: ifcflowfitting; NameOverride: Übergangsstück; IfcPresentationLayer: 0-TFT-H_Ruecklauf; ObjectTypeOverride: Übergangsstück; Pset MEP.Name: Übergangsstück; IfcDescription: Übergangsstück; Pset MEP.Tech-Material: nach DIN 2616; Pset MEP.Geom-Outer Ø1 (mm): 139.7; Pset MEP.Geom-Outer Ø2 (mm): 168.3
Phasen - Phase erstellt: Phase 01

# IfcFlowFitting: Übergangsstück 311059:Übergangsstück 311059, Übergangsstück
In: 1. Obergeschoss
Type - Material: IfcSurfaceStyle #1741
Type - Andere - Kategorie: Allgemeines Modell; Familienname: Übergangsstück 311059
Type - ID-Daten - Typname: Übergangsstück 311059
Type - IFC-Parameter - Typ in IFC-Datei exportieren: Vorgabe
Description: Übergangsstück
Pset_DistributionFlowElementCommon - Reference: Übergangsstück 311059; sets with these values: 2
Andere - Typ: Übergangsstück 311059; Familie: Übergangsstück 311059; Familie und Typ: Übergangsstück 311059: Übergangsstück 311059; Typ-ID: 2535091
Abhängigkeiten - Höhe von Ebene: 0 m; Verschieben mit umliegenden Elementen: no
Bemaßungen - Fläche: 0.0316316 m2; Volumen: 0.0017055 m3
IFC-Parameter - In IFC-Datei exportieren: Nach Typ; Pset MEP.Tech-Insulation thickness (mm): 100; Pset MEP.Geom-DN2: 100; Pset MEP.Geom-DN1: 150; Pset MEP.Geom-Length (mm): 140; In IFC exportieren als: ifcflowfitting; NameOverride: Übergangsstück; IfcPresentationLayer: 0-TFT-H_Ruecklauf; ObjectTypeOverride: Übergangsstück; Pset MEP.Name: Übergangsstück; IfcDescription: Übergangsstück; Pset MEP.Tech-Material: nach DIN 2616; Pset MEP.Geom-Outer Ø1 (mm): 168.3; Pset MEP.Geom-Outer Ø2 (mm): 114.3
Phasen - Phase erstellt: Phase 01

# IfcFlowFitting: Übergangsstück 314738:Übergangsstück 314738, Übergangsstück
In: Erdgeschoss
Type - Material: IfcSurfaceStyle #1741
Type - Andere - Kategorie: Allgemeines Modell; Familienname: Übergangsstück 314738
Type - ID-Daten - Typname: Übergangsstück 314738
Type - IFC-Parameter - Typ in IFC-Datei exportieren: Vorgabe
Description: Übergangsstück
Pset_DistributionFlowElementCommon - Reference: Übergangsstück 314738; sets with these values: 2
Andere - Typ: Übergangsstück 314738; Familie: Übergangsstück 314738; Familie und Typ: Übergangsstück 314738: Übergangsstück 314738; Typ-ID: 2535159
Abhängigkeiten - Höhe von Ebene: 0 m; Verschieben mit umliegenden Elementen: no
Bemaßungen - Fläche: 0.0339137 m2; Volumen: 0.00156123 m3
IFC-Parameter - In IFC-Datei exportieren: Nach Typ; Pset MEP.Tech-Insulation thickness (mm): 100; Pset MEP.Geom-DN2: 150; Pset MEP.Geom-Length (mm): 140; Pset MEP.Geom-DN1: 125; In IFC exportieren als: ifcflowfitting; NameOverride: Übergangsstück; IfcPresentationLayer: 0-TFT-H_Ruecklauf; ObjectTypeOverride: Übergangsstück; Pset MEP.Name: Übergangsstück; IfcDescription: Übergangsstück; Pset MEP.Tech-Material: nach DIN 2616; Pset MEP.Geom-Outer Ø1 (mm): 139.7; Pset MEP.Geom-Outer Ø2 (mm): 168.3
Phasen - Phase erstellt: Phase 01

# IfcFlowFitting: Übergangsstück 317721:Übergangsstück 317721, Übergangsstück
In: Erdgeschoss
Type - Material: IfcSurfaceStyle #1741
Type - Andere - Kategorie: Allgemeines Modell; Familienname: Übergangsstück 317721
Type - ID-Daten - Typname: Übergangsstück 317721
Type - IFC-Parameter - Typ in IFC-Datei exportieren: Vorgabe
Description: Übergangsstück
Pset_DistributionFlowElementCommon - Reference: Übergangsstück 317721; sets with these values: 2
Andere - Typ: Übergangsstück 317721; Familie: Übergangsstück 317721; Familie und Typ: Übergangsstück 317721: Übergangsstück 317721; Typ-ID: 2535313
Abhängigkeiten - Höhe von Ebene: 0 m; Verschieben mit umliegenden Elementen: no
Bemaßungen - Fläche: 0.0906541 m2; Volumen: 0.00837638 m3
IFC-Parameter - In IFC-Datei exportieren: Nach Typ; Pset MEP.Tech-Insulation thickness (mm): 100; Pset MEP.Geom-DN2: 100; Pset MEP.Geom-DN1: 125; Pset MEP.Geom-Length (mm): 127; In IFC exportieren als: ifcflowfitting; NameOverride: Übergangsstück; IfcPresentationLayer: 0-TFT-H_Ruecklauf; ObjectTypeOverride: Übergangsstück; Pset MEP.Name: Übergangsstück; IfcDescription: Übergangsstück; Pset MEP.Tech-Material: nach DIN 2616; Pset MEP.Geom-Outer Ø1 (mm): 139.7; Pset MEP.Geom-Outer Ø2 (mm): 114.3
Phasen - Phase erstellt: Phase 01

# IfcFlowFitting: Übergangsstück 318402:Übergangsstück 318402, Übergangsstück
In: Erdgeschoss
Type - Material: IfcSurfaceStyle #1741
Type - Andere - Kategorie: Allgemeines Modell; Familienname: Übergangsstück 318402
Type - ID-Daten - Typname: Übergangsstück 318402
Type - IFC-Parameter - Typ in IFC-Datei exportieren: Vorgabe
Description: Übergangsstück
Pset_DistributionFlowElementCommon - Reference: Übergangsstück 318402; sets with these values: 2
Andere - Typ: Übergangsstück 318402; Familie: Übergangsstück 318402; Familie und Typ: Übergangsstück 318402: Übergangsstück 318402; Typ-ID: 2535334
Abhängigkeiten - Höhe von Ebene: 0 m; Verschieben mit umliegenden Elementen: no
Bemaßungen - Fläche: 0.0906541 m2; Volumen: 0.00837638 m3
IFC-Parameter - In IFC-Datei exportieren: Nach Typ; Pset MEP.Tech-Insulation thickness (mm): 100; Pset MEP.Geom-DN2: 100; Pset MEP.Geom-DN1: 125; Pset MEP.Geom-Length (mm): 127; In IFC exportieren als: ifcflowfitting; NameOverride: Übergangsstück; IfcPresentationLayer: 0-TFT-H_Ruecklauf; ObjectTypeOverride: Übergangsstück; Pset MEP.Name: Übergangsstück; IfcDescription: Übergangsstück; Pset MEP.Tech-Material: nach DIN 2616; Pset MEP.Geom-Outer Ø1 (mm): 139.7; Pset MEP.Geom-Outer Ø2 (mm): 114.3
Phasen - Phase erstellt: Phase 01

# IfcFlowFitting: Übergangsstück 318471:Übergangsstück 318471, Übergangsstück
In: 1. Obergeschoss
Type - Material: IfcSurfaceStyle #1741
Type - Andere - Kategorie: Allgemeines Modell; Familienname: Übergangsstück 318471
Type - ID-Daten - Typname: Übergangsstück 318471
Type - IFC-Parameter - Typ in IFC-Datei exportieren: Vorgabe
Description: Übergangsstück
Pset_DistributionFlowElementCommon - Reference: Übergangsstück 318471; sets with these values: 2
Andere - Typ: Übergangsstück 318471; Familie: Übergangsstück 318471; Familie und Typ: Übergangsstück 318471: Übergangsstück 318471; Typ-ID: 2535355
Abhängigkeiten - Höhe von Ebene: 0 m; Verschieben mit umliegenden Elementen: no
Bemaßungen - Fläche: 0.107925 m2; Volumen: 0.00897342 m3
IFC-Parameter - In IFC-Datei exportieren: Nach Typ; Pset MEP.Tech-Insulation thickness (mm): 100; Pset MEP.Geom-DN1: 100; Pset MEP.Geom-DN2: 150; Pset MEP.Geom-Length (mm): 140; In IFC exportieren als: ifcflowfitting; NameOverride: Übergangsstück; IfcPresentationLayer: 0-TFT-H_Ruecklauf; ObjectTypeOverride: Übergangsstück; Pset MEP.Name: Übergangsstück; IfcDescription: Übergangsstück; Pset MEP.Tech-Material: nach DIN 2616; Pset MEP.Geom-Outer Ø1 (mm): 114.3; Pset MEP.Geom-Outer Ø2 (mm): 168.3
Phasen - Phase erstellt: Phase 01

# IfcFlowFitting: Übergangsstück 318874:Übergangsstück 318874, Übergangsstück
In: Erdgeschoss
Type - Material: IfcSurfaceStyle #1741
Type - Andere - Kategorie: Allgemeines Modell; Familienname: Übergangsstück 318874
Type - ID-Daten - Typname: Übergangsstück 318874
Type - IFC-Parameter - Typ in IFC-Datei exportieren: Vorgabe
Description: Übergangsstück
Pset_DistributionFlowElementCommon - Reference: Übergangsstück 318874; sets with these values: 2
Andere - Typ: Übergangsstück 318874; Familie: Übergangsstück 318874; Familie und Typ: Übergangsstück 318874: Übergangsstück 318874; Typ-ID: 2535390
Abhängigkeiten - Höhe von Ebene: 0 m; Verschieben mit umliegenden Elementen: no
Bemaßungen - Fläche: 0.111844 m2; Volumen: 0.0102325 m3
IFC-Parameter - In IFC-Datei exportieren: Nach Typ; Pset MEP.Tech-Insulation thickness (mm): 100; Pset MEP.Geom-DN2: 150; Pset MEP.Geom-Length (mm): 140; Pset MEP.Geom-DN1: 125; In IFC exportieren als: ifcflowfitting; NameOverride: Übergangsstück; IfcPresentationLayer: 0-TFT-H_Ruecklauf; ObjectTypeOverride: Übergangsstück; Pset MEP.Name: Übergangsstück; IfcDescription: Übergangsstück; Pset MEP.Tech-Material: nach DIN 2616; Pset MEP.Geom-Outer Ø1 (mm): 139.7; Pset MEP.Geom-Outer Ø2 (mm): 168.3
Phasen - Phase erstellt: Phase 01

# IfcFlowFitting: Übergangsstück 319403:Übergangsstück 319403, Übergangsstück
In: 1. Obergeschoss
Type - Material: IfcSurfaceStyle #1741
Type - Andere - Kategorie: Allgemeines Modell; Familienname: Übergangsstück 319403
Type - ID-Daten - Typname: Übergangsstück 319403
Type - IFC-Parameter - Typ in IFC-Datei exportieren: Vorgabe
Description: Übergangsstück
Pset_DistributionFlowElementCommon - Reference: Übergangsstück 319403; sets with these values: 2
Andere - Typ: Übergangsstück 319403; Familie: Übergangsstück 319403; Familie und Typ: Übergangsstück 319403: Übergangsstück 319403; Typ-ID: 2535425
Abhängigkeiten - Höhe von Ebene: 0 m; Verschieben mit umliegenden Elementen: no
Bemaßungen - Fläche: 0.107925 m2; Volumen: 0.0107176 m3
IFC-Parameter - In IFC-Datei exportieren: Nach Typ; Pset MEP.Tech-Insulation thickness (mm): 100; Pset MEP.Geom-DN2: 100; Pset MEP.Geom-DN1: 150; Pset MEP.Geom-Length (mm): 140; In IFC exportieren als: ifcflowfitting; NameOverride: Übergangsstück; IfcPresentationLayer: 0-TFT-H_Ruecklauf; ObjectTypeOverride: Übergangsstück; Pset MEP.Name: Übergangsstück; IfcDescription: Übergangsstück; Pset MEP.Tech-Material: nach DIN 2616; Pset MEP.Geom-Outer Ø1 (mm): 168.3; Pset MEP.Geom-Outer Ø2 (mm): 114.3
Phasen - Phase erstellt: Phase 01

# IfcFlowFitting: Übergangsstück 320178:Übergangsstück 320178, Übergangsstück
In: Erdgeschoss
Type - Material: IfcSurfaceStyle #1741
Type - Andere - Kategorie: Allgemeines Modell; Familienname: Übergangsstück 320178
Type - ID-Daten - Typname: Übergangsstück 320178
Type - IFC-Parameter - Typ in IFC-Datei exportieren: Vorgabe
Description: Übergangsstück
Pset_DistributionFlowElementCommon - Reference: Übergangsstück 320178; sets with these values: 2
Andere - Typ: Übergangsstück 320178; Familie: Übergangsstück 320178; Familie und Typ: Übergangsstück 320178: Übergangsstück 320178; Typ-ID: 2535488
Abhängigkeiten - Höhe von Ebene: 0 m; Verschieben mit umliegenden Elementen: no
Bemaßungen - Fläche: 0.111844 m2; Volumen: 0.0102325 m3
IFC-Parameter - In IFC-Datei exportieren: Nach Typ; Pset MEP.Tech-Insulation thickness (mm): 100; Pset MEP.Geom-DN2: 150; Pset MEP.Geom-Length (mm): 140; Pset MEP.Geom-DN1: 125; In IFC exportieren als: ifcflowfitting; NameOverride: Übergangsstück; IfcPresentationLayer: 0-TFT-H_Ruecklauf; ObjectTypeOverride: Übergangsstück; Pset MEP.Name: Übergangsstück; IfcDescription: Übergangsstück; Pset MEP.Tech-Material: nach DIN 2616; Pset MEP.Geom-Outer Ø1 (mm): 139.7; Pset MEP.Geom-Outer Ø2 (mm): 168.3
Phasen - Phase erstellt: Phase 01

# IfcFlowFitting: Übergangsstück 325952:Übergangsstück 325952, Übergangsstück
In: Erdgeschoss
Type - Material: IfcSurfaceStyle #1741
Type - Andere - Kategorie: Allgemeines Modell; Familienname: Übergangsstück 325952
Type - ID-Daten - Typname: Übergangsstück 325952
Type - IFC-Parameter - Typ in IFC-Datei exportieren: Vorgabe
Description: Übergangsstück
Pset_DistributionFlowElementCommon - Reference: Übergangsstück 325952; sets with these values: 2
Andere - Typ: Übergangsstück 325952; Familie: Übergangsstück 325952; Familie und Typ: Übergangsstück 325952: Übergangsstück 325952; Typ-ID: 2535621
Abhängigkeiten - Höhe von Ebene: 0 m; Verschieben mit umliegenden Elementen: no
Bemaßungen - Fläche: 0.0475479 m2; Volumen: 0.00342617 m3
IFC-Parameter - In IFC-Datei exportieren: Nach Typ; Pset MEP.Tech-Insulation thickness (mm): 100; Pset MEP.Geom-DN2: 65; Pset MEP.Geom-Length (mm): 90; In IFC exportieren als: ifcflowfitting; NameOverride: Übergangsstück; IfcPresentationLayer: 0-TFT-H_Ruecklauf; ObjectTypeOverride: Übergangsstück; Pset MEP.Name: Übergangsstück; IfcDescription: Übergangsstück; Pset MEP.Tech-Material: nach DIN 2616; Pset MEP.Geom-DN1: 50; Pset MEP.Geom-Outer Ø1 (mm): 60.3; Pset MEP.Geom-Outer Ø2 (mm): 76.1
Phasen - Phase erstellt: Phase 01

# IfcFlowFitting: Übergangsstück 330081:Übergangsstück 330081, Übergangsstück
In: Erdgeschoss
Type - Material: IfcSurfaceStyle #1741
Type - Andere - Kategorie: Allgemeines Modell; Familienname: Übergangsstück 330081
Type - ID-Daten - Typname: Übergangsstück 330081
Type - IFC-Parameter - Typ in IFC-Datei exportieren: Vorgabe
Description: Übergangsstück
Pset_DistributionFlowElementCommon - Reference: Übergangsstück 330081; sets with these values: 2
Andere - Typ: Übergangsstück 330081; Familie: Übergangsstück 330081; Familie und Typ: Übergangsstück 330081: Übergangsstück 330081; Typ-ID: 2535719
Abhängigkeiten - Höhe von Ebene: 0 m; Verschieben mit umliegenden Elementen: no
Bemaßungen - Fläche: 0.0475479 m2; Volumen: 0.00342617 m3
IFC-Parameter - In IFC-Datei exportieren: Nach Typ; Pset MEP.Tech-Insulation thickness (mm): 100; Pset MEP.Geom-DN2: 65; Pset MEP.Geom-Length (mm): 90; Pset MEP.Geom-DN1: 50; In IFC exportieren als: ifcflowfitting; NameOverride: Übergangsstück; IfcPresentationLayer: 0-TFT-H_Ruecklauf; ObjectTypeOverride: Übergangsstück; Pset MEP.Name: Übergangsstück; IfcDescription: Übergangsstück; Pset MEP.Tech-Material: nach DIN 2616; Pset MEP.Geom-Outer Ø1 (mm): 60.3; Pset MEP.Geom-Outer Ø2 (mm): 76.1
Phasen - Phase erstellt: Phase 01

# IfcFlowFitting: Übergangsstück 330867:Übergangsstück 330867, Übergangsstück
In: Erdgeschoss
Type - Material: IfcSurfaceStyle #1741
Type - Andere - Kategorie: Allgemeines Modell; Familienname: Übergangsstück 330867
Type - ID-Daten - Typname: Übergangsstück 330867
Type - IFC-Parameter - Typ in IFC-Datei exportieren: Vorgabe
Description: Übergangsstück
Pset_DistributionFlowElementCommon - Reference: Übergangsstück 330867; sets with these values: 2
Andere - Typ: Übergangsstück 330867; Familie: Übergangsstück 330867; Familie und Typ: Übergangsstück 330867: Übergangsstück 330867; Typ-ID: 2535733
Abhängigkeiten - Höhe von Ebene: 0 m; Verschieben mit umliegenden Elementen: no
Bemaßungen - Fläche: 0.0514981 m2; Volumen: 0.00410093 m3
IFC-Parameter - In IFC-Datei exportieren: Nach Typ; Pset MEP.Tech-Insulation thickness (mm): 100; Pset MEP.Geom-DN1: 80; Pset MEP.Geom-DN2: 65; Pset MEP.Geom-Length (mm): 90; In IFC exportieren als: ifcflowfitting; NameOverride: Übergangsstück; IfcPresentationLayer: 0-TFT-H_Ruecklauf; ObjectTypeOverride: Übergangsstück; Pset MEP.Name: Übergangsstück; IfcDescription: Übergangsstück; Pset MEP.Tech-Material: nach DIN 2616; Pset MEP.Geom-Outer Ø1 (mm): 88.9; Pset MEP.Geom-Outer Ø2 (mm): 76.1
Phasen - Phase erstellt: Phase 01

# IfcFlowFitting: Übergangsstück 340719:Übergangsstück 340719, Übergangsstück
In: Erdgeschoss
Type - Material: IfcSurfaceStyle #1741
Type - Andere - Kategorie: Allgemeines Modell; Familienname: Übergangsstück 340719
Type - ID-Daten - Typname: Übergangsstück 340719
Type - IFC-Parameter - Typ in IFC-Datei exportieren: Vorgabe
Description: Übergangsstück
Pset_DistributionFlowElementCommon - Reference: Übergangsstück 340719; sets with these values: 2
Andere - Typ: Übergangsstück 340719; Familie: Übergangsstück 340719; Familie und Typ: Übergangsstück 340719: Übergangsstück 340719; Typ-ID: 2535915
Abhängigkeiten - Höhe von Ebene: 0 m; Verschieben mit umliegenden Elementen: no
Bemaßungen - Fläche: 0.0906541 m2; Volumen: 0.00837638 m3
IFC-Parameter - In IFC-Datei exportieren: Nach Typ; Pset MEP.Tech-Insulation thickness (mm): 100; Pset MEP.Geom-DN2: 100; Pset MEP.Geom-DN1: 125; Pset MEP.Geom-Length (mm): 127; In IFC exportieren als: ifcflowfitting; NameOverride: Übergangsstück; IfcPresentationLayer: 0-TFT-H_Ruecklauf; ObjectTypeOverride: Übergangsstück; Pset MEP.Name: Übergangsstück; IfcDescription: Übergangsstück; Pset MEP.Tech-Material: nach DIN 2616; Pset MEP.Geom-Outer Ø1 (mm): 139.7; Pset MEP.Geom-Outer Ø2 (mm): 114.3
Phasen - Phase erstellt: Phase 01

# IfcFlowFitting: Übergangsstück 340788:Übergangsstück 340788, Übergangsstück
In: Erdgeschoss
Type - Material: IfcSurfaceStyle #1741
Type - Andere - Kategorie: Allgemeines Modell; Familienname: Übergangsstück 340788
Type - ID-Daten - Typname: Übergangsstück 340788
Type - IFC-Parameter - Typ in IFC-Datei exportieren: Vorgabe
Description: Übergangsstück
Pset_DistributionFlowElementCommon - Reference: Übergangsstück 340788; sets with these values: 2
Andere - Typ: Übergangsstück 340788; Familie: Übergangsstück 340788; Familie und Typ: Übergangsstück 340788: Übergangsstück 340788; Typ-ID: 2535936
Abhängigkeiten - Höhe von Ebene: 0 m; Verschieben mit umliegenden Elementen: no
Bemaßungen - Fläche: 0.0906541 m2; Volumen: 0.00837638 m3
IFC-Parameter - In IFC-Datei exportieren: Nach Typ; Pset MEP.Tech-Insulation thickness (mm): 100; Pset MEP.Geom-DN2: 100; Pset MEP.Geom-DN1: 125; Pset MEP.Geom-Length (mm): 127; In IFC exportieren als: ifcflowfitting; NameOverride: Übergangsstück; IfcPresentationLayer: 0-TFT-H_Ruecklauf; ObjectTypeOverride: Übergangsstück; Pset MEP.Name: Übergangsstück; IfcDescription: Übergangsstück; Pset MEP.Tech-Material: nach DIN 2616; Pset MEP.Geom-Outer Ø1 (mm): 139.7; Pset MEP.Geom-Outer Ø2 (mm): 114.3
Phasen - Phase erstellt: Phase 01

# IfcFlowFitting: Übergangsstück 340926:Übergangsstück 340926, Übergangsstück
In: Erdgeschoss
Type - Material: IfcSurfaceStyle #1741
Type - Andere - Kategorie: Allgemeines Modell; Familienname: Übergangsstück 340926
Type - ID-Daten - Typname: Übergangsstück 340926
Type - IFC-Parameter - Typ in IFC-Datei exportieren: Vorgabe
Description: Übergangsstück
Pset_DistributionFlowElementCommon - Reference: Übergangsstück 340926; sets with these values: 2
Andere - Typ: Übergangsstück 340926; Familie: Übergangsstück 340926; Familie und Typ: Übergangsstück 340926: Übergangsstück 340926; Typ-ID: 2535978
Abhängigkeiten - Höhe von Ebene: 0 m; Verschieben mit umliegenden Elementen: no
Bemaßungen - Fläche: 0.111844 m2; Volumen: 0.0102325 m3
IFC-Parameter - In IFC-Datei exportieren: Nach Typ; Pset MEP.Tech-Insulation thickness (mm): 100; Pset MEP.Geom-DN2: 150; Pset MEP.Geom-Length (mm): 140; Pset MEP.Geom-DN1: 125; In IFC exportieren als: ifcflowfitting; NameOverride: Übergangsstück; IfcPresentationLayer: 0-TFT-H_Ruecklauf; ObjectTypeOverride: Übergangsstück; Pset MEP.Name: Übergangsstück; IfcDescription: Übergangsstück; Pset MEP.Tech-Material: nach DIN 2616; Pset MEP.Geom-Outer Ø1 (mm): 139.7; Pset MEP.Geom-Outer Ø2 (mm): 168.3
Phasen - Phase erstellt: Phase 01

# IfcFlowFitting: Übergangsstück 341104:Übergangsstück 341104, Übergangsstück
In: Erdgeschoss
Type - Material: IfcSurfaceStyle #1741
Type - Andere - Kategorie: Allgemeines Modell; Familienname: Übergangsstück 341104
Type - ID-Daten - Typname: Übergangsstück 341104
Type - IFC-Parameter - Typ in IFC-Datei exportieren: Vorgabe
Description: Übergangsstück
Pset_DistributionFlowElementCommon - Reference: Übergangsstück 341104; sets with these values: 2
Andere - Typ: Übergangsstück 341104; Familie: Übergangsstück 341104; Familie und Typ: Übergangsstück 341104: Übergangsstück 341104; Typ-ID: 2536034
Abhängigkeiten - Höhe von Ebene: 0 m; Verschieben mit umliegenden Elementen: no
Bemaßungen - Fläche: 0.111844 m2; Volumen: 0.0102325 m3
IFC-Parameter - In IFC-Datei exportieren: Nach Typ; Pset MEP.Tech-Insulation thickness (mm): 100; Pset MEP.Geom-DN2: 150; Pset MEP.Geom-Length (mm): 140; Pset MEP.Geom-DN1: 125; In IFC exportieren als: ifcflowfitting; NameOverride: Übergangsstück; IfcPresentationLayer: 0-TFT-H_Ruecklauf; ObjectTypeOverride: Übergangsstück; Pset MEP.Name: Übergangsstück; IfcDescription: Übergangsstück; Pset MEP.Tech-Material: nach DIN 2616; Pset MEP.Geom-Outer Ø1 (mm): 139.7; Pset MEP.Geom-Outer Ø2 (mm): 168.3
Phasen - Phase erstellt: Phase 01

# IfcFlowFitting: Übergangsstück 344722:Übergangsstück 344722, Übergangsstück
In: Erdgeschoss
Type - Material: IfcSurfaceStyle #9317
Type - Andere - Kategorie: Allgemeines Modell; Familienname: Übergangsstück 344722
Type - ID-Daten - Typname: Übergangsstück 344722
Type - IFC-Parameter - Typ in IFC-Datei exportieren: Vorgabe
Description: Übergangsstück
Pset_DistributionFlowElementCommon - Reference: Übergangsstück 344722; sets with these values: 2
Andere - Typ: Übergangsstück 344722; Familie: Übergangsstück 344722; Familie und Typ: Übergangsstück 344722: Übergangsstück 344722; Typ-ID: 2536314
Abhängigkeiten - Höhe von Ebene: 0 m; Verschieben mit umliegenden Elementen: no
Bemaßungen - Fläche: 0.141914 m2; Volumen: 0.0161443 m3
IFC-Parameter - In IFC-Datei exportieren: Nach Typ; Pset MEP.Tech-Insulation thickness (mm): 100; Pset MEP.Geom-DN1: 200; Pset MEP.Geom-Length (mm): 152; Pset MEP.Geom-DN2: 150; In IFC exportieren als: ifcflowfitting; NameOverride: Übergangsstück; IfcPresentationLayer: 0-TFT-H_Vorlauf; ObjectTypeOverride: Übergangsstück; Pset MEP.Name: Übergangsstück; IfcDescription: Übergangsstück; Pset MEP.Tech-Material: nach DIN 2616; Pset MEP.Geom-Outer Ø1 (mm): 219.1; Pset MEP.Geom-Outer Ø2 (mm): 168.3
Phasen - Phase erstellt: Phase 01

# IfcFlowFitting: Übergangsstück 345655:Übergangsstück 345655, Übergangsstück
In: Erdgeschoss
Type - Material: IfcSurfaceStyle #9317
Type - Andere - Kategorie: Allgemeines Modell; Familienname: Übergangsstück 345655
Type - ID-Daten - Typname: Übergangsstück 345655
Type - IFC-Parameter - Typ in IFC-Datei exportieren: Vorgabe
Description: Übergangsstück
Pset_DistributionFlowElementCommon - Reference: Übergangsstück 345655; sets with these values: 2
Andere - Typ: Übergangsstück 345655; Familie: Übergangsstück 345655; Familie und Typ: Übergangsstück 345655: Übergangsstück 345655; Typ-ID: 2536342
Abhängigkeiten - Höhe von Ebene: 0 m; Verschieben mit umliegenden Elementen: no
Bemaßungen - Fläche: 0.133473 m2; Volumen: 0.0143501 m3
IFC-Parameter - In IFC-Datei exportieren: Nach Typ; Pset MEP.Tech-Insulation thickness (mm): 100; Pset MEP.Geom-DN1: 200; Pset MEP.Geom-Length (mm): 152; Pset MEP.Geom-DN2: 80; In IFC exportieren als: ifcflowfitting; NameOverride: Übergangsstück; IfcPresentationLayer: 0-TFT-H_Vorlauf; ObjectTypeOverride: Übergangsstück; Pset MEP.Name: Übergangsstück; IfcDescription: Übergangsstück; Pset MEP.Tech-Material: nach DIN 2616; Pset MEP.Geom-Outer Ø1 (mm): 219.1; Pset MEP.Geom-Outer Ø2 (mm): 88.9
Phasen - Phase erstellt: Phase 01

# IfcFlowFitting: Übergangsstück 348295:Übergangsstück 348295, Übergangsstück
In: Erdgeschoss
Type - Material: IfcSurfaceStyle #1741
Type - Andere - Kategorie: Allgemeines Modell; Familienname: Übergangsstück 348295
Type - ID-Daten - Typname: Übergangsstück 348295
Type - IFC-Parameter - Typ in IFC-Datei exportieren: Vorgabe
Description: Übergangsstück
Pset_DistributionFlowElementCommon - Reference: Übergangsstück 348295; sets with these values: 2
Andere - Typ: Übergangsstück 348295; Familie: Übergangsstück 348295; Familie und Typ: Übergangsstück 348295: Übergangsstück 348295; Typ-ID: 2536447
Abhängigkeiten - Höhe von Ebene: 0 m; Verschieben mit umliegenden Elementen: no
Bemaßungen - Fläche: 0.0514981 m2; Volumen: 0.0039017 m3
IFC-Parameter - In IFC-Datei exportieren: Nach Typ; Pset MEP.Tech-Insulation thickness (mm): 100; Pset MEP.Geom-DN2: 80; Pset MEP.Geom-DN1: 65; Pset MEP.Geom-Length (mm): 90; In IFC exportieren als: ifcflowfitting; NameOverride: Übergangsstück; IfcPresentationLayer: 0-TFT-H_Ruecklauf; ObjectTypeOverride: Übergangsstück; Pset MEP.Name: Übergangsstück; IfcDescription: Übergangsstück; Pset MEP.Tech-Material: nach DIN 2616; Pset MEP.Geom-Outer Ø1 (mm): 76.1; Pset MEP.Geom-Outer Ø2 (mm): 88.9
Phasen - Phase erstellt: Phase 01

# IfcFlowFitting: Übergangsstück 358843:Übergangsstück 358843, Übergangsstück
In: Erdgeschoss
Type - Material: IfcSurfaceStyle #352577
Type - Andere - Kategorie: Allgemeines Modell; Familienname: Übergangsstück 358843
Type - ID-Daten - Typname: Übergangsstück 358843
Type - IFC-Parameter - Typ in IFC-Datei exportieren: Vorgabe
Description: Übergangsstück
Pset_DistributionFlowElementCommon - Reference: Übergangsstück 358843; sets with these values: 2
Andere - Typ: Übergangsstück 358843; Familie: Übergangsstück 358843; Familie und Typ: Übergangsstück 358843: Übergangsstück 358843; Typ-ID: 2536863
Abhängigkeiten - Höhe von Ebene: 0 m; Verschieben mit umliegenden Elementen: no
Bemaßungen - Fläche: 0.0152448 m2; Volumen: 0.000558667 m3
IFC-Parameter - In IFC-Datei exportieren: Nach Typ; Pset MEP.Geom-DN1: 100; Pset MEP.Geom-Length (mm): 100; Pset MEP.Geom-DN2: 65; In IFC exportieren als: ifcflowfitting; NameOverride: Übergangsstück; IfcPresentationLayer: S_Gas; ObjectTypeOverride: Übergangsstück; Pset MEP.Name: Übergangsstück; IfcDescription: Übergangsstück; Pset MEP.Tech-Material: nach DIN 2616; Pset MEP.Geom-Outer Ø1 (mm): 114.3; Pset MEP.Geom-Outer Ø2 (mm): 76.1
Phasen - Phase erstellt: Phase 01

# IfcFlowFitting: Übergangsstück 605382:Übergangsstück 605382, Übergangsstück
In: Erdgeschoss
Type - Material: IfcSurfaceStyle #352577
Type - Andere - Kategorie: Allgemeines Modell; Familienname: Übergangsstück 605382
Type - ID-Daten - Typname: Übergangsstück 605382
Type - IFC-Parameter - Typ in IFC-Datei exportieren: Vorgabe
Description: Übergangsstück
Pset_DistributionFlowElementCommon - Reference: Übergangsstück 605382; sets with these values: 2
Andere - Typ: Übergangsstück 605382; Familie: Übergangsstück 605382; Familie und Typ: Übergangsstück 605382: Übergangsstück 605382; Typ-ID: 2537353
Abhängigkeiten - Höhe von Ebene: 0 m; Verschieben mit umliegenden Elementen: no
Bemaßungen - Fläche: 0.00854683 m2; Volumen: 0.000209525 m3
IFC-Parameter - In IFC-Datei exportieren: Nach Typ; Pset MEP.Geom-DN1: 65; Pset MEP.Geom-Length (mm): 90; In IFC exportieren als: ifcflowfitting; NameOverride: Übergangsstück; IfcPresentationLayer: S_Gas; ObjectTypeOverride: Übergangsstück; Pset MEP.Name: Übergangsstück; IfcDescription: Übergangsstück; Pset MEP.Tech-Material: nach DIN 2616; Pset MEP.Geom-DN2: 32; Pset MEP.Geom-Outer Ø1 (mm): 76.1; Pset MEP.Geom-Outer Ø2 (mm): 42.4
Phasen - Phase erstellt: Phase 01

# IfcFlowFitting: Übergangsstück 614405:Übergangsstück 614405, Übergangsstück
In: 1. Obergeschoss
Type - Material: IfcSurfaceStyle #1741
Type - Andere - Kategorie: Allgemeines Modell; Familienname: Übergangsstück 614405
Type - ID-Daten - Typname: Übergangsstück 614405
Type - IFC-Parameter - Typ in IFC-Datei exportieren: Vorgabe
Description: Übergangsstück
Pset_DistributionFlowElementCommon - Reference: Übergangsstück 614405; sets with these values: 2
Andere - Typ: Übergangsstück 614405; Familie: Übergangsstück 614405; Familie und Typ: Übergangsstück 614405: Übergangsstück 614405; Typ-ID: 2537703
Abhängigkeiten - Höhe von Ebene: 0 m; Verschieben mit umliegenden Elementen: no
Bemaßungen - Fläche: 0.107925 m2; Volumen: 0.00897342 m3
IFC-Parameter - In IFC-Datei exportieren: Nach Typ; Pset MEP.Tech-Insulation thickness (mm): 100; Pset MEP.Geom-DN1: 100; Pset MEP.Geom-DN2: 150; Pset MEP.Geom-Length (mm): 140; In IFC exportieren als: ifcflowfitting; NameOverride: Übergangsstück; IfcPresentationLayer: 0-TFT-H_Ruecklauf; ObjectTypeOverride: Übergangsstück; Pset MEP.Name: Übergangsstück; IfcDescription: Übergangsstück; Pset MEP.Tech-Material: nach DIN 2616; Pset MEP.Geom-Outer Ø1 (mm): 114.3; Pset MEP.Geom-Outer Ø2 (mm): 168.3
Phasen - Phase erstellt: Phase 01

# IfcFlowFitting: Übergangsstück 614605:Übergangsstück 614605, Übergangsstück
In: 1. Obergeschoss
Type - Material: IfcSurfaceStyle #1741
Type - Andere - Kategorie: Allgemeines Modell; Familienname: Übergangsstück 614605
Type - ID-Daten - Typname: Übergangsstück 614605
Type - IFC-Parameter - Typ in IFC-Datei exportieren: Vorgabe
Description: Übergangsstück
Pset_DistributionFlowElementCommon - Reference: Übergangsstück 614605; sets with these values: 2
Andere - Typ: Übergangsstück 614605; Familie: Übergangsstück 614605; Familie und Typ: Übergangsstück 614605: Übergangsstück 614605; Typ-ID: 2537759
Abhängigkeiten - Höhe von Ebene: 0 m; Verschieben mit umliegenden Elementen: no
Bemaßungen - Fläche: 0.107925 m2; Volumen: 0.0107176 m3
IFC-Parameter - In IFC-Datei exportieren: Nach Typ; Pset MEP.Tech-Insulation thickness (mm): 100; Pset MEP.Geom-DN2: 100; Pset MEP.Geom-DN1: 150; Pset MEP.Geom-Length (mm): 140; In IFC exportieren als: ifcflowfitting; NameOverride: Übergangsstück; IfcPresentationLayer: 0-TFT-H_Ruecklauf; ObjectTypeOverride: Übergangsstück; Pset MEP.Name: Übergangsstück; IfcDescription: Übergangsstück; Pset MEP.Tech-Material: nach DIN 2616; Pset MEP.Geom-Outer Ø1 (mm): 168.3; Pset MEP.Geom-Outer Ø2 (mm): 114.3
Phasen - Phase erstellt: Phase 01

# IfcFlowFitting: Übergangsstück 849300:Übergangsstück 849300, Übergangsstück
In: Erdgeschoss
Type - Material: IfcSurfaceStyle #352577
Type - Andere - Kategorie: Allgemeines Modell; Familienname: Übergangsstück 849300
Type - ID-Daten - Typname: Übergangsstück 849300
Type - IFC-Parameter - Typ in IFC-Datei exportieren: Vorgabe
Description: Übergangsstück
Pset_DistributionFlowElementCommon - Reference: Übergangsstück 849300; sets with these values: 2
Andere - Typ: Übergangsstück 849300; Familie: Übergangsstück 849300; Familie und Typ: Übergangsstück 849300: Übergangsstück 849300; Typ-ID: 2539043
Abhängigkeiten - Höhe von Ebene: 0 m; Verschieben mit umliegenden Elementen: no
Bemaßungen - Fläche: 0.0152448 m2; Volumen: 0.000558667 m3
IFC-Parameter - In IFC-Datei exportieren: Nach Typ; Pset MEP.Geom-DN1: 100; Pset MEP.Geom-Length (mm): 100; Pset MEP.Geom-DN2: 65; In IFC exportieren als: ifcflowfitting; NameOverride: Übergangsstück; IfcPresentationLayer: S_Gas; ObjectTypeOverride: Übergangsstück; Pset MEP.Name: Übergangsstück; IfcDescription: Übergangsstück; Pset MEP.Tech-Material: nach DIN 2616; Pset MEP.Geom-Outer Ø1 (mm): 114.3; Pset MEP.Geom-Outer Ø2 (mm): 76.1
Phasen - Phase erstellt: Phase 01

# IfcFlowFitting: Übergangsstück:Übergangsstück, Übergangsstück
In: 1. Obergeschoss
Type - Material: IfcSurfaceStyle #9317
Type - Andere - Kategorie: Allgemeines Modell; Familienname: Übergangsstück
Type - ID-Daten - Typname: Übergangsstück
Type - IFC-Parameter - Typ in IFC-Datei exportieren: Vorgabe
Description: Übergangsstück
Pset_DistributionFlowElementCommon - Reference: Übergangsstück; sets with these values: 2
Andere - Typ: Übergangsstück; Familie: Übergangsstück; Familie und Typ: Übergangsstück: Übergangsstück; Typ-ID: 2531520
Abhängigkeiten - Höhe von Ebene: 0 m; Verschieben mit umliegenden Elementen: no
Bemaßungen - Fläche: 0.141914 m2; Volumen: 0.0139939 m3
IFC-Parameter - In IFC-Datei exportieren: Nach Typ; Pset MEP.Tech-Insulation thickness (mm): 100; Pset MEP.Geom-DN2: 200; In IFC exportieren als: ifcflowfitting; NameOverride: Übergangsstück; IfcPresentationLayer: 0-TFT-H_Vorlauf; ObjectTypeOverride: Übergangsstück; Pset MEP.Name: Übergangsstück; IfcDescription: Übergangsstück; Pset MEP.Tech-Material: nach DIN 2616; Pset MEP.Geom-DN1: 150; Pset MEP.Geom-Outer Ø1 (mm): 168.3; Pset MEP.Geom-Outer Ø2 (mm): 219.1; Pset MEP.Geom-Length (mm): 152
Phasen - Phase erstellt: Phase 01

# IfcFlowMovingDevice: Dachventilator Rund 271102:Dachventilator Rund 271102, Dachventilator Rund
In: 1. Obergeschoss
Type - Material: IfcSurfaceStyle #271082
Type - Andere - Kategorie: HLS-Bauteile; Familienname: Dachventilator Rund 271102
Type - ID-Daten - Typname: Dachventilator Rund 271102
Type - IFC-Parameter - Typ in IFC-Datei exportieren: Vorgabe
Type - HLS - Klassifizierung: Keine
Description: Dachventilator Rund
Pset_DistributionFlowElementCommon - Reference: Dachventilator Rund 271102; sets with these values: 2
Andere - Typ: Dachventilator Rund 271102; Familie: Dachventilator Rund 271102; Familie und Typ: Dachventilator Rund 271102: Dachventilator Rund 271102; Typ-ID: 2533427
Abhängigkeiten - Höhe von Ebene: 0 m; Verschieben mit umliegenden Elementen: no
Bemaßungen - Fläche: 1.12819 m2; Volumen: 0.137448 m3
IFC-Parameter - In IFC-Datei exportieren: Nach Typ; In IFC exportieren als: ifcflowmovingdevice; NameOverride: Dachventilator Rund; IfcPresentationLayer: 0-TFT-L_Bauteil; ObjectTypeOverride: Dachventilator Rund; Pset MEP.Name: Dachventilator Rund; IfcDescription: Dachventilator Rund; Pset MEP.Tech-Medium: L_Zuluft; Pset MEP.Geom-Ø Connection (mm): 438
Phasen - Phase erstellt: Phase 01

# IfcFlowMovingDevice: Dachventilator Rund:Dachventilator Rund, Dachventilator Rund
In: 1. Obergeschoss
Type - Material: IfcSurfaceStyle #271082
Type - Andere - Kategorie: HLS-Bauteile; Familienname: Dachventilator Rund
Type - ID-Daten - Typname: Dachventilator Rund
Type - IFC-Parameter - Typ in IFC-Datei exportieren: Vorgabe
Type - HLS - Klassifizierung: Keine
Description: Dachventilator Rund
Pset_DistributionFlowElementCommon - Reference: Dachventilator Rund; sets with these values: 2
Andere - Typ: Dachventilator Rund; Familie: Dachventilator Rund; Familie und Typ: Dachventilator Rund: Dachventilator Rund; Typ-ID: 2533409
Abhängigkeiten - Höhe von Ebene: 0 m; Verschieben mit umliegenden Elementen: no
Bemaßungen - Fläche: 1.12819 m2; Volumen: 0.137448 m3
IFC-Parameter - In IFC-Datei exportieren: Nach Typ; In IFC exportieren als: ifcflowmovingdevice; NameOverride: Dachventilator Rund; IfcPresentationLayer: 0-TFT-L_Bauteil; ObjectTypeOverride: Dachventilator Rund; Pset MEP.Name: Dachventilator Rund; IfcDescription: Dachventilator Rund; Pset MEP.Tech-Medium: L_Zuluft; Pset MEP.Geom-Ø Connection (mm): 438
Phasen - Phase erstellt: Phase 01

# IfcFlowMovingDevice: Geräteanschluss 271206:Geräteanschluss 271206, Geräteanschluss
In: 1. Obergeschoss
Type - Material: IfcSurfaceStyle #271263
Type - Andere - Kategorie: HLS-Bauteile; Familienname: Geräteanschluss 271206
Type - ID-Daten - Typname: Geräteanschluss 271206
Type - IFC-Parameter - Typ in IFC-Datei exportieren: Vorgabe
Type - HLS - Klassifizierung: Keine
Description: Geräteanschluss
Pset_DistributionFlowElementCommon - Reference: Geräteanschluss 271206; sets with these values: 2
Andere - Typ: Geräteanschluss 271206; Familie: Geräteanschluss 271206; Familie und Typ: Geräteanschluss 271206: Geräteanschluss 271206; Typ-ID: 2533450
Abhängigkeiten - Höhe von Ebene: 0 m; Verschieben mit umliegenden Elementen: no
Bemaßungen - Fläche: 0.3962 m2; Volumen: 0.248064 m3
IFC-Parameter - In IFC-Datei exportieren: Nach Typ; In IFC exportieren als: ifcflowmovingdevice; NameOverride: Geräteanschluss; IfcPresentationLayer: 0-TFT-L_Zuluft; ObjectTypeOverride: Geräteanschluss; Pset MEP.Name: Geräteanschluss; IfcDescription: Geräteanschluss; Pset MEP.Tech-Medium: L_Zuluft; Pset MEP.Geom-Side 1 connection (mm): 2432; Pset MEP.Geom-Side 2 connection (mm): 1530; Pset MEP.Name of System: Zuluft
Phasen - Phase erstellt: Phase 01

# IfcFlowMovingDevice: Geräteanschluss 271546:Geräteanschluss 271546, Geräteanschluss
In: 1. Obergeschoss
Type - Material: IfcSurfaceStyle #271571
Type - Andere - Kategorie: HLS-Bauteile; Familienname: Geräteanschluss 271546
Type - ID-Daten - Typname: Geräteanschluss 271546
Type - IFC-Parameter - Typ in IFC-Datei exportieren: Vorgabe
Type - HLS - Klassifizierung: Keine
Description: Geräteanschluss
Pset_DistributionFlowElementCommon - Reference: Geräteanschluss 271546; sets with these values: 2
Andere - Typ: Geräteanschluss 271546; Familie: Geräteanschluss 271546; Familie und Typ: Geräteanschluss 271546: Geräteanschluss 271546; Typ-ID: 2533472
Abhängigkeiten - Höhe von Ebene: 0 m; Verschieben mit umliegenden Elementen: no
Bemaßungen - Fläche: 0.3962 m2; Volumen: 0.248064 m3
IFC-Parameter - In IFC-Datei exportieren: Nach Typ; Pset MEP.Geom-Side 2 connection (mm): 1530; In IFC exportieren als: ifcflowmovingdevice; NameOverride: Geräteanschluss; IfcPresentationLayer: 0-TFT-L_Abluft; ObjectTypeOverride: Geräteanschluss; Pset MEP.Name: Geräteanschluss; IfcDescription: Geräteanschluss; Pset MEP.Tech-Medium: L_Abluft; Pset MEP.Geom-Side 1 connection (mm): 2432; Pset MEP.Name of System: Abluft
Phasen - Phase erstellt: Phase 01

# IfcFlowMovingDevice: Geräteanschluss 276213:Geräteanschluss 276213, Geräteanschluss
In: 1. Obergeschoss
Type - Material: IfcSurfaceStyle #274455
Type - Andere - Kategorie: HLS-Bauteile; Familienname: Geräteanschluss 276213
Type - ID-Daten - Typname: Geräteanschluss 276213
Type - IFC-Parameter - Typ in IFC-Datei exportieren: Vorgabe
Type - HLS - Klassifizierung: Keine
Description: Geräteanschluss
Pset_DistributionFlowElementCommon - Reference: Geräteanschluss 276213; sets with these values: 2
Andere - Typ: Geräteanschluss 276213; Familie: Geräteanschluss 276213; Familie und Typ: Geräteanschluss 276213: Geräteanschluss 276213; Typ-ID: 2533780
Abhängigkeiten - Höhe von Ebene: 0 m; Verschieben mit umliegenden Elementen: no
Bemaßungen - Fläche: 0.3839 m2; Volumen: 0.23467 m3
IFC-Parameter - In IFC-Datei exportieren: Nach Typ; In IFC exportieren als: ifcflowmovingdevice; NameOverride: Geräteanschluss; IfcPresentationLayer: 0-TFT-L_Fortluft; ObjectTypeOverride: Geräteanschluss; Pset MEP.Name: Geräteanschluss; IfcDescription: Geräteanschluss; Pset MEP.Tech-Medium: L_Fortluft; Pset MEP.Geom-Side 1 connection (mm): 1514; Pset MEP.Geom-Side 2 connection (mm): 2325; Pset MEP.Name of System: Abluft
Phasen - Phase erstellt: Phase 01

# IfcFlowMovingDevice: Geräteanschluss:Geräteanschluss, Geräteanschluss
In: 1. Obergeschoss
Type - Material: IfcSurfaceStyle #271184
Type - Andere - Kategorie: HLS-Bauteile; Familienname: Geräteanschluss
Type - ID-Daten - Typname: Geräteanschluss
Type - IFC-Parameter - Typ in IFC-Datei exportieren: Vorgabe
Type - HLS - Klassifizierung: Keine
Description: Geräteanschluss
Pset_DistributionFlowElementCommon - Reference: Geräteanschluss; sets with these values: 2
Andere - Typ: Geräteanschluss; Familie: Geräteanschluss; Familie und Typ: Geräteanschluss: Geräteanschluss; Typ-ID: 2533434
Abhängigkeiten - Höhe von Ebene: 0 m; Verschieben mit umliegenden Elementen: no
Bemaßungen - Fläche: 0.3402 m2; Volumen: 0.178848 m3
IFC-Parameter - In IFC-Datei exportieren: Nach Typ; In IFC exportieren als: ifcflowmovingdevice; NameOverride: Geräteanschluss; IfcPresentationLayer: 0-TFT-L_Aussenluft; ObjectTypeOverride: Geräteanschluss; Pset MEP.Name: Geräteanschluss; IfcDescription: Geräteanschluss; Pset MEP.Tech-Medium: L_Aussenluft; Pset MEP.Geom-Side 1 connection (mm): 2160; Pset MEP.Geom-Side 2 connection (mm): 1242; Pset MEP.Name of System: Außenluft
Phasen - Phase erstellt: Phase 01

# IfcFlowMovingDevice: Inline-Pumpe 319949:Inline-Pumpe 319949, Inline-Pumpe
In: Erdgeschoss
Type - Material: IfcSurfaceStyle #1741
Type - Andere - Kategorie: HLS-Bauteile; Familienname: Inline-Pumpe 319949
Type - ID-Daten - Typname: Inline-Pumpe 319949
Type - IFC-Parameter - Typ in IFC-Datei exportieren: Vorgabe
Type - HLS - Klassifizierung: Keine
Description: Inline-Pumpe
Pset_DistributionFlowElementCommon - Reference: Inline-Pumpe 319949; sets with these values: 2
Andere - Typ: Inline-Pumpe 319949; Familie: Inline-Pumpe 319949; Familie und Typ: Inline-Pumpe 319949: Inline-Pumpe 319949; Typ-ID: 2535467
Abhängigkeiten - Höhe von Ebene: 0 m; Verschieben mit umliegenden Elementen: no
Bemaßungen - Fläche: 0.284172 m2; Volumen: 0.0132919 m3
IFC-Parameter - In IFC-Datei exportieren: Nach Typ; Pset MEP.Tech-Insulation thickness (mm): 100; Pset MEP.Tech-PN: 16; Pset MEP.Tech-Connection type (Inner thread=2, flange=3): 2; Pset MEP.Geom-DN: 100; Pset MEP.Geom-Outer Ø (mm): 220; Pset MEP.Geom-Length (mm): 350; In IFC exportieren als: ifcflowmovingdevice; NameOverride: Inline-Pumpe; IfcPresentationLayer: 0-TFT-H_Ruecklauf; ObjectTypeOverride: Inline-Pumpe; Pset MEP.Name: Inline-Pumpe; IfcDescription: Inline-Pumpe
Phasen - Phase erstellt: Phase 01

# IfcFlowMovingDevice: Inline-Pumpe 321583:Inline-Pumpe 321583, Inline-Pumpe
In: Erdgeschoss
Type - Material: IfcSurfaceStyle #1741
Type - Andere - Kategorie: HLS-Bauteile; Familienname: Inline-Pumpe 321583
Type - ID-Daten - Typname: Inline-Pumpe 321583
Type - IFC-Parameter - Typ in IFC-Datei exportieren: Vorgabe
Type - HLS - Klassifizierung: Keine
Description: Inline-Pumpe
Pset_DistributionFlowElementCommon - Reference: Inline-Pumpe 321583; sets with these values: 2
Andere - Typ: Inline-Pumpe 321583; Familie: Inline-Pumpe 321583; Familie und Typ: Inline-Pumpe 321583: Inline-Pumpe 321583; Typ-ID: 2535593
Abhängigkeiten - Höhe von Ebene: 0 m; Verschieben mit umliegenden Elementen: no
Bemaßungen - Fläche: 0.126567 m2; Volumen: 0.00435939 m3
IFC-Parameter - In IFC-Datei exportieren: Nach Typ; Pset MEP.Tech-Insulation thickness (mm): 100; Pset MEP.Tech-PN: 16; Pset MEP.Tech-Connection type (Inner thread=2, flange=3): 2; In IFC exportieren als: ifcflowmovingdevice; NameOverride: Inline-Pumpe; IfcPresentationLayer: 0-TFT-H_Ruecklauf; ObjectTypeOverride: Inline-Pumpe; Pset MEP.Name: Inline-Pumpe; IfcDescription: Inline-Pumpe; Pset MEP.Geom-DN: 50; Pset MEP.Geom-Outer Ø (mm): 165; Pset MEP.Geom-Length (mm): 230
Phasen - Phase erstellt: Phase 01

# IfcFlowMovingDevice: Inline-Pumpe 341037:Inline-Pumpe 341037, Inline-Pumpe
In: Erdgeschoss
Type - Material: IfcSurfaceStyle #1741
Type - Andere - Kategorie: HLS-Bauteile; Familienname: Inline-Pumpe 341037
Type - ID-Daten - Typname: Inline-Pumpe 341037
Type - IFC-Parameter - Typ in IFC-Datei exportieren: Vorgabe
Type - HLS - Klassifizierung: Keine
Description: Inline-Pumpe
Pset_DistributionFlowElementCommon - Reference: Inline-Pumpe 341037; sets with these values: 2
Andere - Typ: Inline-Pumpe 341037; Familie: Inline-Pumpe 341037; Familie und Typ: Inline-Pumpe 341037: Inline-Pumpe 341037; Typ-ID: 2536013
Abhängigkeiten - Höhe von Ebene: 0 m; Verschieben mit umliegenden Elementen: no
Bemaßungen - Fläche: 0.284172 m2; Volumen: 0.0132919 m3
IFC-Parameter - In IFC-Datei exportieren: Nach Typ; Pset MEP.Tech-Insulation thickness (mm): 100; Pset MEP.Tech-PN: 16; Pset MEP.Tech-Connection type (Inner thread=2, flange=3): 2; Pset MEP.Geom-DN: 100; Pset MEP.Geom-Outer Ø (mm): 220; Pset MEP.Geom-Length (mm): 350; In IFC exportieren als: ifcflowmovingdevice; NameOverride: Inline-Pumpe; IfcPresentationLayer: 0-TFT-H_Ruecklauf; ObjectTypeOverride: Inline-Pumpe; Pset MEP.Name: Inline-Pumpe; IfcDescription: Inline-Pumpe
Phasen - Phase erstellt: Phase 01

# IfcFlowMovingDevice: Inline-Pumpe:Inline-Pumpe, Inline-Pumpe
In: Erdgeschoss
Type - Material: IfcSurfaceStyle #1741
Type - Andere - Kategorie: HLS-Bauteile; Familienname: Inline-Pumpe
Type - ID-Daten - Typname: Inline-Pumpe
Type - IFC-Parameter - Typ in IFC-Datei exportieren: Vorgabe
Type - HLS - Klassifizierung: Keine
Description: Inline-Pumpe
Pset_DistributionFlowElementCommon - Reference: Inline-Pumpe; sets with these values: 2
Andere - Typ: Inline-Pumpe; Familie: Inline-Pumpe; Familie und Typ: Inline-Pumpe: Inline-Pumpe; Typ-ID: 2535133
Abhängigkeiten - Höhe von Ebene: 0 m; Verschieben mit umliegenden Elementen: no
Bemaßungen - Fläche: 0.284172 m2; Volumen: 0.0132919 m3
IFC-Parameter - In IFC-Datei exportieren: Nach Typ; Pset MEP.Tech-Insulation thickness (mm): 100; Pset MEP.Tech-PN: 16; Pset MEP.Tech-Connection type (Inner thread=2, flange=3): 2; Pset MEP.Geom-DN: 100; Pset MEP.Geom-Outer Ø (mm): 220; Pset MEP.Geom-Length (mm): 350; In IFC exportieren als: ifcflowmovingdevice; NameOverride: Inline-Pumpe; IfcPresentationLayer: 0-TFT-H_Ruecklauf; ObjectTypeOverride: Inline-Pumpe; Pset MEP.Name: Inline-Pumpe; IfcDescription: Inline-Pumpe
Phasen - Phase erstellt: Phase 01

# IfcFlowSegment: Gummikompensator 604247:Gummikompensator 604247, Gummikompensator
In: Erdgeschoss
Type - Material: IfcSurfaceStyle #352577
Type - Andere - Kategorie: Allgemeines Modell; Familienname: Gummikompensator 604247
Type - ID-Daten - Typname: Gummikompensator 604247
Type - IFC-Parameter - Typ in IFC-Datei exportieren: Vorgabe
Description: Gummikompensator
Pset_DistributionFlowElementCommon - Reference: Gummikompensator 604247; sets with these values: 2
Andere - Typ: Gummikompensator 604247; Familie: Gummikompensator 604247; Familie und Typ: Gummikompensator 604247: Gummikompensator 604247; Typ-ID: 2537087
Abhängigkeiten - Höhe von Ebene: 0 m; Verschieben mit umliegenden Elementen: no
Bemaßungen - Fläche: 0.030631 m2; Volumen: 0.000588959 m3
IFC-Parameter - In IFC-Datei exportieren: Nach Typ; Pset MEP.Tech-PN: 16; Pset MEP.Tech-Connection type (Inner thread=2, flange=3): 2; Pset MEP.Geom-Length (mm): 100; Pset MEP.Geom-DN: 65; Pset MEP.Geom-Outer Ø (mm): 100; In IFC exportieren als: ifcflowsegment; NameOverride: Gummikompensator; IfcPresentationLayer: S_Gas; ObjectTypeOverride: Gummikompensator; Pset MEP.Name: Gummikompensator; IfcDescription: Gummikompensator
Phasen - Phase erstellt: Phase 01

# IfcFlowSegment: Gummikompensator 604661:Gummikompensator 604661, Gummikompensator
In: Erdgeschoss
Type - Material: IfcSurfaceStyle #352577
Type - Andere - Kategorie: Allgemeines Modell; Familienname: Gummikompensator 604661
Type - ID-Daten - Typname: Gummikompensator 604661
Type - IFC-Parameter - Typ in IFC-Datei exportieren: Vorgabe
Description: Gummikompensator
Pset_DistributionFlowElementCommon - Reference: Gummikompensator 604661; sets with these values: 2
Andere - Typ: Gummikompensator 604661; Familie: Gummikompensator 604661; Familie und Typ: Gummikompensator 604661: Gummikompensator 604661; Typ-ID: 2537213
Abhängigkeiten - Höhe von Ebene: 0 m; Verschieben mit umliegenden Elementen: no
Bemaßungen - Fläche: 0.030631 m2; Volumen: 0.000588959 m3
IFC-Parameter - In IFC-Datei exportieren: Nach Typ; Pset MEP.Tech-PN: 16; Pset MEP.Tech-Connection type (Inner thread=2, flange=3): 2; Pset MEP.Geom-Length (mm): 100; Pset MEP.Geom-DN: 65; Pset MEP.Geom-Outer Ø (mm): 100; In IFC exportieren als: ifcflowsegment; NameOverride: Gummikompensator; IfcPresentationLayer: S_Gas; ObjectTypeOverride: Gummikompensator; Pset MEP.Name: Gummikompensator; IfcDescription: Gummikompensator
Phasen - Phase erstellt: Phase 01

# IfcFlowSegment: Gummikompensator 610271:Gummikompensator 610271, Gummikompensator
In: Erdgeschoss
Type - Material: IfcSurfaceStyle #352577
Type - Andere - Kategorie: Allgemeines Modell; Familienname: Gummikompensator 610271
Type - ID-Daten - Typname: Gummikompensator 610271
Type - IFC-Parameter - Typ in IFC-Datei exportieren: Vorgabe
Description: Gummikompensator
Pset_DistributionFlowElementCommon - Reference: Gummikompensator 610271; sets with these values: 2
Andere - Typ: Gummikompensator 610271; Familie: Gummikompensator 610271; Familie und Typ: Gummikompensator 610271: Gummikompensator 610271; Typ-ID: 2537493
Abhängigkeiten - Höhe von Ebene: 0 m; Verschieben mit umliegenden Elementen: no
Bemaßungen - Fläche: 0.0535686 m2; Volumen: 0.000961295 m3
IFC-Parameter - In IFC-Datei exportieren: Nach Typ; Pset MEP.Tech-PN: 16; Pset MEP.Tech-Connection type (Inner thread=2, flange=3): 2; Pset MEP.Geom-Length (mm): 100; Pset MEP.Geom-DN: 32; Pset MEP.Geom-Outer Ø (mm): 140; In IFC exportieren als: ifcflowsegment; NameOverride: Gummikompensator; IfcPresentationLayer: S_Gas; ObjectTypeOverride: Gummikompensator; Pset MEP.Name: Gummikompensator; IfcDescription: Gummikompensator
Phasen - Phase erstellt: Phase 01

# IfcFlowSegment: Gummikompensator:Gummikompensator, Gummikompensator
In: Erdgeschoss
Type - Material: IfcSurfaceStyle #352577
Type - Andere - Kategorie: Allgemeines Modell; Familienname: Gummikompensator
Type - ID-Daten - Typname: Gummikompensator
Type - IFC-Parameter - Typ in IFC-Datei exportieren: Vorgabe
Description: Gummikompensator
Pset_DistributionFlowElementCommon - Reference: Gummikompensator; sets with these values: 2
Andere - Typ: Gummikompensator; Familie: Gummikompensator; Familie und Typ: Gummikompensator: Gummikompensator; Typ-ID: 2536786
Abhängigkeiten - Höhe von Ebene: 0 m; Verschieben mit umliegenden Elementen: no
Bemaßungen - Fläche: 0.030631 m2; Volumen: 0.000588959 m3
IFC-Parameter - In IFC-Datei exportieren: Nach Typ; Pset MEP.Tech-PN: 16; Pset MEP.Tech-Connection type (Inner thread=2, flange=3): 2; Pset MEP.Geom-Length (mm): 100; Pset MEP.Geom-DN: 65; In IFC exportieren als: ifcflowsegment; NameOverride: Gummikompensator; IfcPresentationLayer: S_Gas; ObjectTypeOverride: Gummikompensator; Pset MEP.Name: Gummikompensator; IfcDescription: Gummikompensator; Pset MEP.Geom-Outer Ø (mm): 100
Phasen - Phase erstellt: Phase 01

# IfcFlowSegment: Luftleitung 274478:Luftleitung 274478, Luftleitung
In: 1. Obergeschoss
Type - Material: IfcSurfaceStyle #274455
Type - Andere - Kategorie: Allgemeines Modell; Familienname: Luftleitung 274478
Type - ID-Daten - Typname: Luftleitung 274478
Type - IFC-Parameter - Typ in IFC-Datei exportieren: Vorgabe
Description: Luftleitung
Pset_DistributionFlowElementCommon - Reference: Luftleitung 274478; sets with these values: 2
Andere - Typ: Luftleitung 274478; Familie: Luftleitung 274478; Familie und Typ: Luftleitung 274478: Luftleitung 274478; Typ-ID: 2533650
Abhängigkeiten - Höhe von Ebene: 0 m; Verschieben mit umliegenden Elementen: no
Bemaßungen - Fläche: 2.97759 m2; Volumen: 0.99253 m3
IFC-Parameter - In IFC-Datei exportieren: Nach Typ; Pset MEP.Tech-Material (ID): 1; Pset MEP.Geom-Side 1 (mm): 1000; In IFC exportieren als: ifcflowsegment; NameOverride: Luftleitung; IfcPresentationLayer: 0-TFT-L_Fortluft; ObjectTypeOverride: Luftleitung; Pset MEP.Geom-Surface (m2): 5.95518; Pset MEP.Name: Luftleitung; IfcDescription: Luftleitung; Pset MEP.Geom-Length (mm): 1488.8; Pset MEP.Abbreviation: L; Pset MEP.Tech-Medium: L_Fortluft; Pset MEP.Geom-Side 2 (mm): 1000; Pset MEP.Tech-Weight (kg): 38.1132
Phasen - Phase erstellt: Phase 01

# IfcFlowSegment: Luftleitung 276864:Luftleitung 276864, Luftleitung
In: 1. Obergeschoss
Type - Material: IfcSurfaceStyle #274455
Type - Andere - Kategorie: Allgemeines Modell; Familienname: Luftleitung 276864
Type - ID-Daten - Typname: Luftleitung 276864
Type - IFC-Parameter - Typ in IFC-Datei exportieren: Vorgabe
Description: Luftleitung
Pset_DistributionFlowElementCommon - Reference: Luftleitung 276864; sets with these values: 2
Andere - Typ: Luftleitung 276864; Familie: Luftleitung 276864; Familie und Typ: Luftleitung 276864: Luftleitung 276864; Typ-ID: 2533801
Abhängigkeiten - Höhe von Ebene: 0 m; Verschieben mit umliegenden Elementen: no
Bemaßungen - Fläche: 3.325 m2; Volumen: 1.55 m3
IFC-Parameter - In IFC-Datei exportieren: Nach Typ; Pset MEP.Tech-Material (ID): 1; Pset MEP.Geom-Length (mm): 1000; Pset MEP.Geom-Side 2 (mm): 1000; In IFC exportieren als: ifcflowsegment; NameOverride: Luftleitung; IfcPresentationLayer: 0-TFT-L_Fortluft; ObjectTypeOverride: Luftleitung; Pset MEP.Geom-Surface (m2): 6.65; Pset MEP.Name: Luftleitung; IfcDescription: Luftleitung; Pset MEP.Abbreviation: L; Pset MEP.Tech-Medium: L_Fortluft; Pset MEP.Geom-Side 1 (mm): 2325; Pset MEP.Tech-Weight (kg): 58.52
Phasen - Phase erstellt: Phase 01

# IfcFlowSegment: Luftleitung 277036:Luftleitung 277036, Luftleitung
In: 1. Obergeschoss
Type - Material: IfcSurfaceStyle #271571
Type - Andere - Kategorie: Allgemeines Modell; Familienname: Luftleitung 277036
Type - ID-Daten - Typname: Luftleitung 277036
Type - IFC-Parameter - Typ in IFC-Datei exportieren: Vorgabe
Description: Luftleitung
Pset_DistributionFlowElementCommon - Reference: Luftleitung 277036; sets with these values: 2
Andere - Typ: Luftleitung 277036; Familie: Luftleitung 277036; Familie und Typ: Luftleitung 277036: Luftleitung 277036; Typ-ID: 2533822
Abhängigkeiten - Höhe von Ebene: 0 m; Verschieben mit umliegenden Elementen: no
Bemaßungen - Fläche: 3.73232 m2; Volumen: 1.88464 m3
IFC-Parameter - In IFC-Datei exportieren: Nach Typ; Pset MEP.Tech-Material (ID): 1; Pset MEP.Geom-Side 1 (mm): 1500; Pset MEP.Geom-Side 2 (mm): 1530; In IFC exportieren als: ifcflowsegment; NameOverride: Luftleitung; IfcPresentationLayer: 0-TFT-L_Abluft; ObjectTypeOverride: Luftleitung; Pset MEP.Geom-Surface (m2): 7.46464; Pset MEP.Name: Luftleitung; IfcDescription: Luftleitung; Pset MEP.Geom-Length (mm): 1231.79; Pset MEP.Abbreviation: L; Pset MEP.Tech-Medium: L_Abluft; Pset MEP.Tech-Weight (kg): 59.7171
Phasen - Phase erstellt: Phase 01

# IfcFlowSegment: Luftleitung 277095:Luftleitung 277095, Luftleitung
In: 1. Obergeschoss
Type - Material: IfcSurfaceStyle #271263
Type - Andere - Kategorie: Allgemeines Modell; Familienname: Luftleitung 277095
Type - ID-Daten - Typname: Luftleitung 277095
Type - IFC-Parameter - Typ in IFC-Datei exportieren: Vorgabe
Description: Luftleitung
Pset_DistributionFlowElementCommon - Reference: Luftleitung 277095; sets with these values: 2
Andere - Typ: Luftleitung 277095; Familie: Luftleitung 277095; Familie und Typ: Luftleitung 277095: Luftleitung 277095; Typ-ID: 2533829
Abhängigkeiten - Höhe von Ebene: 0 m; Verschieben mit umliegenden Elementen: no
Bemaßungen - Fläche: 2.96334 m2; Volumen: 1.49634 m3
IFC-Parameter - In IFC-Datei exportieren: Nach Typ; Pset MEP.Tech-Material (ID): 1; Pset MEP.Geom-Side 1 (mm): 1500; Pset MEP.Geom-Side 2 (mm): 1530; In IFC exportieren als: ifcflowsegment; NameOverride: Luftleitung; IfcPresentationLayer: 0-TFT-L_Zuluft; ObjectTypeOverride: Luftleitung; Pset MEP.Geom-Surface (m2): 5.92668; Pset MEP.Name: Luftleitung; IfcDescription: Luftleitung; Pset MEP.Geom-Length (mm): 978; Pset MEP.Abbreviation: L; Pset MEP.Tech-Medium: L_Zuluft; Pset MEP.Tech-Weight (kg): 47.4134
Phasen - Phase erstellt: Phase 01

# IfcFlowSegment: Luftleitung 277283:Luftleitung 277283, Luftleitung
In: 1. Obergeschoss
Type - Material: IfcSurfaceStyle #271184
Type - Andere - Kategorie: Allgemeines Modell; Familienname: Luftleitung 277283
Type - ID-Daten - Typname: Luftleitung 277283
Type - IFC-Parameter - Typ in IFC-Datei exportieren: Vorgabe
Description: Luftleitung
Pset_DistributionFlowElementCommon - Reference: Luftleitung 277283; sets with these values: 2
Andere - Typ: Luftleitung 277283; Familie: Luftleitung 277283; Familie und Typ: Luftleitung 277283: Luftleitung 277283; Typ-ID: 2533843
Abhängigkeiten - Höhe von Ebene: 0 m; Verschieben mit umliegenden Elementen: no
Bemaßungen - Fläche: 2.04172 m2; Volumen: 0.723883 m3
IFC-Parameter - In IFC-Datei exportieren: Nach Typ; Pset MEP.Tech-Material (ID): 1; Pset MEP.Geom-Side 2 (mm): 900; Pset MEP.Geom-Side 1 (mm): 1300; In IFC exportieren als: ifcflowsegment; NameOverride: Luftleitung; IfcPresentationLayer: 0-TFT-L_Aussenluft; ObjectTypeOverride: Luftleitung; Pset MEP.Geom-Surface (m2): 4.08344; Pset MEP.Name: Luftleitung; IfcDescription: Luftleitung; Pset MEP.Geom-Length (mm): 928.056; Pset MEP.Abbreviation: L; Pset MEP.Tech-Medium: L_Aussenluft; Pset MEP.Tech-Weight (kg): 32.6676
Phasen - Phase erstellt: Phase 01

# IfcFlowSegment: Luftleitung:Luftleitung, Luftleitung
In: 1. Obergeschoss
Type - Material: IfcSurfaceStyle #271263
Type - Andere - Kategorie: Allgemeines Modell; Familienname: Luftleitung
Type - ID-Daten - Typname: Luftleitung
Type - IFC-Parameter - Typ in IFC-Datei exportieren: Vorgabe
Description: Luftleitung
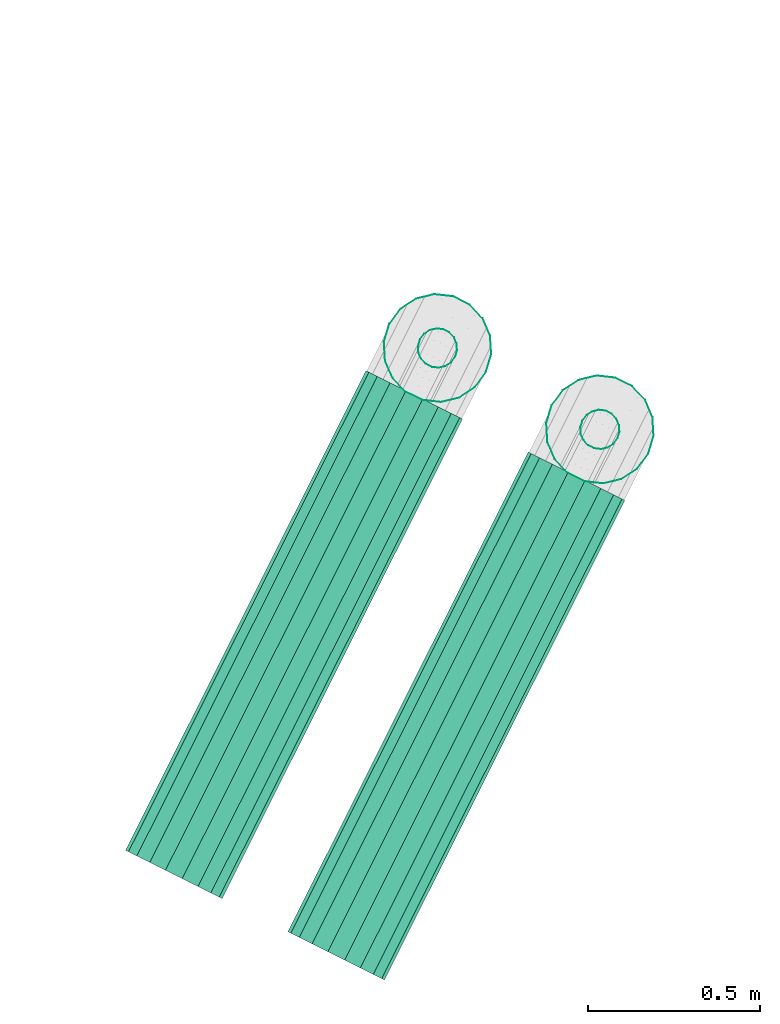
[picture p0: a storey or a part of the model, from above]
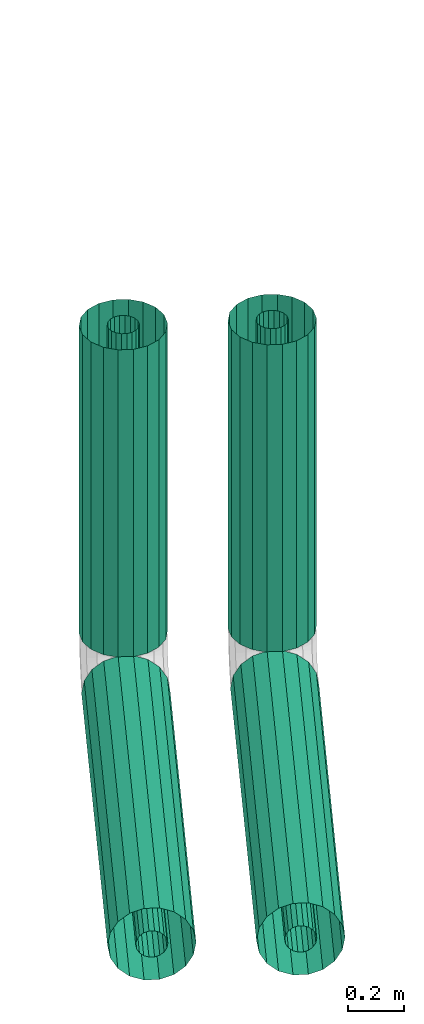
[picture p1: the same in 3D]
Properties of the parts of a building model (IFC2X3), part 14 of 23

# IfcFlowSegment: Luftleitung:Luftleitung, Luftleitung
Pset_DistributionFlowElementCommon - Reference: Luftleitung; sets with these values: 2
Andere - Typ: Luftleitung; Familie: Luftleitung; Familie und Typ: Luftleitung: Luftleitung; Typ-ID: 2533558
Abhängigkeiten - Höhe von Ebene: 0 m; Verschieben mit umliegenden Elementen: no
Bemaßungen - Fläche: 4.545 m2; Volumen: 2.295 m3
IFC-Parameter - In IFC-Datei exportieren: Nach Typ; Pset MEP.Tech-Material (ID): 1; Pset MEP.Geom-Side 1 (mm): 1500; Pset MEP.Geom-Side 2 (mm): 1530; In IFC exportieren als: ifcflowsegment; NameOverride: Luftleitung; IfcPresentationLayer: 0-TFT-L_Zuluft; ObjectTypeOverride: Luftleitung; Pset MEP.Geom-Surface (m2): 9.09; Pset MEP.Name: Luftleitung; IfcDescription: Luftleitung; Pset MEP.Geom-Length (mm): 1500; Pset MEP.Abbreviation: L; Pset MEP.Tech-Medium: L_Zuluft; Pset MEP.Tech-Weight (kg): 72.72
Phasen - Phase erstellt: Phase 01

# IfcFlowSegment: Luftleitungsteil 273492:Luftleitungsteil 273492, Luftleitungsteil
In: 1. Obergeschoss
Type - Material: IfcSurfaceStyle #271263
Type - Andere - Kategorie: Allgemeines Modell; Familienname: Luftleitungsteil 273492
Type - ID-Daten - Typname: Luftleitungsteil 273492
Type - IFC-Parameter - Typ in IFC-Datei exportieren: Vorgabe
Description: Luftleitungsteil
Pset_DistributionFlowElementCommon - Reference: Luftleitungsteil 273492; sets with these values: 2
Andere - Typ: Luftleitungsteil 273492; Familie: Luftleitungsteil 273492; Familie und Typ: Luftleitungsteil 273492: Luftleitungsteil 273492; Typ-ID: 2533565
Abhängigkeiten - Höhe von Ebene: 0 m; Verschieben mit umliegenden Elementen: no
Bemaßungen - Fläche: 0.967231 m2; Volumen: 0.488404 m3
IFC-Parameter - In IFC-Datei exportieren: Nach Typ; Pset MEP.Tech-Material (ID): 1; Pset MEP.Geom-Side 1 (mm): 1500; Pset MEP.Geom-Side 2 (mm): 1530; In IFC exportieren als: ifcflowsegment; NameOverride: Luftleitungsteil; IfcPresentationLayer: 0-TFT-L_Zuluft; ObjectTypeOverride: Luftleitungsteil; Pset MEP.Geom-Surface (m2): 1.93446; Pset MEP.Name: Luftleitungsteil; IfcDescription: Luftleitungsteil; Pset MEP.Geom-Length (mm): 319.218; Pset MEP.Abbreviation: LT; Pset MEP.Tech-Medium: L_Zuluft; Pset MEP.Tech-Weight (kg): 15.4757
Phasen - Phase erstellt: Phase 01

# IfcFlowSegment: Luftleitungsteil 274141:Luftleitungsteil 274141, Luftleitungsteil
In: 1. Obergeschoss
Type - Material: IfcSurfaceStyle #271263
Type - Andere - Kategorie: Allgemeines Modell; Familienname: Luftleitungsteil 274141
Type - ID-Daten - Typname: Luftleitungsteil 274141
Type - IFC-Parameter - Typ in IFC-Datei exportieren: Vorgabe
Description: Luftleitungsteil
Pset_DistributionFlowElementCommon - Reference: Luftleitungsteil 274141; sets with these values: 2
Andere - Typ: Luftleitungsteil 274141; Familie: Luftleitungsteil 274141; Familie und Typ: Luftleitungsteil 274141: Luftleitungsteil 274141; Typ-ID: 2533586
Abhängigkeiten - Höhe von Ebene: 0 m; Verschieben mit umliegenden Elementen: no
Bemaßungen - Fläche: 2.6113 m2; Volumen: 1.31858 m3
IFC-Parameter - In IFC-Datei exportieren: Nach Typ; Pset MEP.Tech-Material (ID): 1; Pset MEP.Geom-Side 1 (mm): 1500; Pset MEP.Geom-Side 2 (mm): 1530; In IFC exportieren als: ifcflowsegment; NameOverride: Luftleitungsteil; IfcPresentationLayer: 0-TFT-L_Zuluft; ObjectTypeOverride: Luftleitungsteil; Pset MEP.Geom-Surface (m2): 5.22259; Pset MEP.Name: Luftleitungsteil; IfcDescription: Luftleitungsteil; Pset MEP.Geom-Length (mm): 861.814; Pset MEP.Abbreviation: LT; Pset MEP.Tech-Medium: L_Zuluft; Pset MEP.Tech-Weight (kg): 41.7807
Phasen - Phase erstellt: Phase 01

# IfcFlowSegment: Luftleitungsteil 274337:Luftleitungsteil 274337, Luftleitungsteil
In: 1. Obergeschoss
Type - Material: IfcSurfaceStyle #271571
Type - Andere - Kategorie: Allgemeines Modell; Familienname: Luftleitungsteil 274337
Type - ID-Daten - Typname: Luftleitungsteil 274337
Type - IFC-Parameter - Typ in IFC-Datei exportieren: Vorgabe
Description: Luftleitungsteil
Pset_DistributionFlowElementCommon - Reference: Luftleitungsteil 274337; sets with these values: 2
Andere - Typ: Luftleitungsteil 274337; Familie: Luftleitungsteil 274337; Familie und Typ: Luftleitungsteil 274337: Luftleitungsteil 274337; Typ-ID: 2533633
Abhängigkeiten - Höhe von Ebene: 0 m; Verschieben mit umliegenden Elementen: no
Bemaßungen - Fläche: 2.48827 m2; Volumen: 1.25645 m3
IFC-Parameter - In IFC-Datei exportieren: Nach Typ; Pset MEP.Tech-Material (ID): 1; Pset MEP.Geom-Side 1 (mm): 1500; Pset MEP.Geom-Side 2 (mm): 1530; In IFC exportieren als: ifcflowsegment; NameOverride: Luftleitungsteil; IfcPresentationLayer: 0-TFT-L_Abluft; ObjectTypeOverride: Luftleitungsteil; Pset MEP.Geom-Surface (m2): 4.97654; Pset MEP.Name: Luftleitungsteil; IfcDescription: Luftleitungsteil; Pset MEP.Geom-Length (mm): 821.212; Pset MEP.Abbreviation: LT; Pset MEP.Tech-Medium: L_Abluft; Pset MEP.Tech-Weight (kg): 39.8123
Phasen - Phase erstellt: Phase 01

# IfcFlowSegment: Luftleitungsteil 274396:Luftleitungsteil 274396, Luftleitungsteil
In: 1. Obergeschoss
Type - Material: IfcSurfaceStyle #274455
Type - Andere - Kategorie: Allgemeines Modell; Familienname: Luftleitungsteil 274396
Type - ID-Daten - Typname: Luftleitungsteil 274396
Type - IFC-Parameter - Typ in IFC-Datei exportieren: Vorgabe
Description: Luftleitungsteil
Pset_DistributionFlowElementCommon - Reference: Luftleitungsteil 274396; sets with these values: 2
Andere - Typ: Luftleitungsteil 274396; Familie: Luftleitungsteil 274396; Familie und Typ: Luftleitungsteil 274396: Luftleitungsteil 274396; Typ-ID: 2533640
Abhängigkeiten - Höhe von Ebene: 0 m; Verschieben mit umliegenden Elementen: no
Bemaßungen - Fläche: 0.933542 m2; Volumen: 0.4481 m3
IFC-Parameter - In IFC-Datei exportieren: Nach Typ; Pset MEP.Tech-Material (ID): 1; In IFC exportieren als: ifcflowsegment; NameOverride: Luftleitungsteil; IfcPresentationLayer: 0-TFT-L_Fortluft; ObjectTypeOverride: Luftleitungsteil; Pset MEP.Geom-Surface (m2): 1.86708; Pset MEP.Name: Luftleitungsteil; IfcDescription: Luftleitungsteil; Pset MEP.Geom-Length (mm): 311.181; Pset MEP.Abbreviation: LT; Pset MEP.Tech-Medium: L_Fortluft; Pset MEP.Geom-Side 1 (mm): 1200; Pset MEP.Geom-Side 2 (mm): 1800; Pset MEP.Tech-Weight (kg): 14.9367
Phasen - Phase erstellt: Phase 01

# IfcFlowSegment: Luftleitungsteil 275061:Luftleitungsteil 275061, Luftleitungsteil
In: 1. Obergeschoss
Type - Material: IfcSurfaceStyle #274455
Type - Andere - Kategorie: Allgemeines Modell; Familienname: Luftleitungsteil 275061
Type - ID-Daten - Typname: Luftleitungsteil 275061
Type - IFC-Parameter - Typ in IFC-Datei exportieren: Vorgabe
Description: Luftleitungsteil
Pset_DistributionFlowElementCommon - Reference: Luftleitungsteil 275061; sets with these values: 2
Andere - Typ: Luftleitungsteil 275061; Familie: Luftleitungsteil 275061; Familie und Typ: Luftleitungsteil 275061: Luftleitungsteil 275061; Typ-ID: 2533703
Abhängigkeiten - Höhe von Ebene: 0 m; Verschieben mit umliegenden Elementen: no
Bemaßungen - Fläche: 0.680435 m2; Volumen: 0.226812 m3
IFC-Parameter - In IFC-Datei exportieren: Nach Typ; Pset MEP.Tech-Material (ID): 1; Pset MEP.Geom-Side 1 (mm): 1000; Pset MEP.Geom-Side 2 (mm): 1000; In IFC exportieren als: ifcflowsegment; NameOverride: Luftleitungsteil; IfcPresentationLayer: 0-TFT-L_Fortluft; ObjectTypeOverride: Luftleitungsteil; Pset MEP.Geom-Surface (m2): 1.36087; Pset MEP.Name: Luftleitungsteil; IfcDescription: Luftleitungsteil; Pset MEP.Geom-Length (mm): 340.218; Pset MEP.Abbreviation: LT; Pset MEP.Tech-Medium: L_Fortluft; Pset MEP.Tech-Weight (kg): 8.70957
Phasen - Phase erstellt: Phase 01

# IfcFlowSegment: Luftleitungsteil 275122:Luftleitungsteil 275122, Luftleitungsteil
In: 1. Obergeschoss
Type - Material: IfcSurfaceStyle #271184
Type - Andere - Kategorie: Allgemeines Modell; Familienname: Luftleitungsteil 275122
Type - ID-Daten - Typname: Luftleitungsteil 275122
Type - IFC-Parameter - Typ in IFC-Datei exportieren: Vorgabe
Description: Luftleitungsteil
Pset_DistributionFlowElementCommon - Reference: Luftleitungsteil 275122; sets with these values: 2
Andere - Typ: Luftleitungsteil 275122; Familie: Luftleitungsteil 275122; Familie und Typ: Luftleitungsteil 275122: Luftleitungsteil 275122; Typ-ID: 2533710
Abhängigkeiten - Höhe von Ebene: 0 m; Verschieben mit umliegenden Elementen: no
Bemaßungen - Fläche: 1.035 m2; Volumen: 0.4968 m3
IFC-Parameter - In IFC-Datei exportieren: Nach Typ; Pset MEP.Tech-Material (ID): 1; In IFC exportieren als: ifcflowsegment; NameOverride: Luftleitungsteil; IfcPresentationLayer: 0-TFT-L_Aussenluft; ObjectTypeOverride: Luftleitungsteil; Pset MEP.Geom-Surface (m2): 2.07; Pset MEP.Name: Luftleitungsteil; IfcDescription: Luftleitungsteil; Pset MEP.Geom-Length (mm): 345; Pset MEP.Abbreviation: LT; Pset MEP.Tech-Medium: L_Aussenluft; Pset MEP.Geom-Side 1 (mm): 1800; Pset MEP.Geom-Side 2 (mm): 1200; Pset MEP.Tech-Weight (kg): 16.56
Phasen - Phase erstellt: Phase 01

# IfcFlowSegment: Luftleitungsteil 275866:Luftleitungsteil 275866, Luftleitungsteil
In: 1. Obergeschoss
Type - Material: IfcSurfaceStyle #271184
Type - Andere - Kategorie: Allgemeines Modell; Familienname: Luftleitungsteil 275866
Type - ID-Daten - Typname: Luftleitungsteil 275866
Type - IFC-Parameter - Typ in IFC-Datei exportieren: Vorgabe
Description: Luftleitungsteil
Pset_DistributionFlowElementCommon - Reference: Luftleitungsteil 275866; sets with these values: 2
Andere - Typ: Luftleitungsteil 275866; Familie: Luftleitungsteil 275866; Familie und Typ: Luftleitungsteil 275866: Luftleitungsteil 275866; Typ-ID: 2533752
Abhängigkeiten - Höhe von Ebene: 0 m; Verschieben mit umliegenden Elementen: no
Bemaßungen - Fläche: 1.08301 m2; Volumen: 0.458688 m3
IFC-Parameter - In IFC-Datei exportieren: Nach Typ; Pset MEP.Tech-Material (ID): 1; Pset MEP.Geom-Side 2 (mm): 900; Pset MEP.Geom-Side 1 (mm): 2160; In IFC exportieren als: ifcflowsegment; NameOverride: Luftleitungsteil; IfcPresentationLayer: 0-TFT-L_Aussenluft; ObjectTypeOverride: Luftleitungsteil; Pset MEP.Geom-Surface (m2): 2.16602; Pset MEP.Name: Luftleitungsteil; IfcDescription: Luftleitungsteil; Pset MEP.Geom-Length (mm): 353.926; Pset MEP.Abbreviation: LT; Pset MEP.Tech-Medium: L_Aussenluft; Pset MEP.Tech-Weight (kg): 19.061
Phasen - Phase erstellt: Phase 01

# IfcFlowSegment: Luftleitungsteil 276919:Luftleitungsteil 276919, Luftleitungsteil
In: 1. Obergeschoss
Type - Material: IfcSurfaceStyle #274455
Type - Andere - Kategorie: Allgemeines Modell; Familienname: Luftleitungsteil 276919
Type - ID-Daten - Typname: Luftleitungsteil 276919
Type - IFC-Parameter - Typ in IFC-Datei exportieren: Vorgabe
Description: Luftleitungsteil
Pset_DistributionFlowElementCommon - Reference: Luftleitungsteil 276919; sets with these values: 2
Andere - Typ: Luftleitungsteil 276919; Familie: Luftleitungsteil 276919; Familie und Typ: Luftleitungsteil 276919: Luftleitungsteil 276919; Typ-ID: 2533808
Abhängigkeiten - Höhe von Ebene: 0 m; Verschieben mit umliegenden Elementen: no
Bemaßungen - Fläche: 2.1014 m2; Volumen: 0.9796 m3
IFC-Parameter - In IFC-Datei exportieren: Nach Typ; Pset MEP.Tech-Material (ID): 1; Pset MEP.Geom-Side 2 (mm): 1000; Pset MEP.Geom-Side 1 (mm): 2325; In IFC exportieren als: ifcflowsegment; NameOverride: Luftleitungsteil; IfcPresentationLayer: 0-TFT-L_Fortluft; ObjectTypeOverride: Luftleitungsteil; Pset MEP.Geom-Surface (m2): 4.2028; Pset MEP.Name: Luftleitungsteil; IfcDescription: Luftleitungsteil; Pset MEP.Geom-Length (mm): 632; Pset MEP.Abbreviation: LT; Pset MEP.Tech-Medium: L_Fortluft; Pset MEP.Tech-Weight (kg): 36.9846
Phasen - Phase erstellt: Phase 01

# IfcFlowSegment: Luftleitungsteil 276978:Luftleitungsteil 276978, Luftleitungsteil
In: 1. Obergeschoss
Type - Material: IfcSurfaceStyle #274455
Type - Andere - Kategorie: Allgemeines Modell; Familienname: Luftleitungsteil 276978
Type - ID-Daten - Typname: Luftleitungsteil 276978
Type - IFC-Parameter - Typ in IFC-Datei exportieren: Vorgabe
Description: Luftleitungsteil
Pset_DistributionFlowElementCommon - Reference: Luftleitungsteil 276978; sets with these values: 2
Andere - Typ: Luftleitungsteil 276978; Familie: Luftleitungsteil 276978; Familie und Typ: Luftleitungsteil 276978: Luftleitungsteil 276978; Typ-ID: 2533815
Abhängigkeiten - Höhe von Ebene: 0 m; Verschieben mit umliegenden Elementen: no
Bemaßungen - Fläche: 0.107 m2; Volumen: 0.0356667 m3
IFC-Parameter - In IFC-Datei exportieren: Nach Typ; Pset MEP.Tech-Material (ID): 1; Pset MEP.Geom-Side 1 (mm): 1000; Pset MEP.Geom-Side 2 (mm): 1000; Pset MEP.Geom-Surface (m2): 1; In IFC exportieren als: ifcflowsegment; NameOverride: Luftleitungsteil; IfcPresentationLayer: 0-TFT-L_Fortluft; ObjectTypeOverride: Luftleitungsteil; Pset MEP.Name: Luftleitungsteil; IfcDescription: Luftleitungsteil; Pset MEP.Geom-Length (mm): 53.5; Pset MEP.Abbreviation: LT; Pset MEP.Tech-Medium: L_Fortluft; Pset MEP.Tech-Weight (kg): 1.3696
Phasen - Phase erstellt: Phase 01

# IfcFlowSegment: Luftleitungsteil 851455:Luftleitungsteil 851455, Luftleitungsteil
In: Erdgeschoss
Type - Material: IfcSurfaceStyle #271263
Type - Andere - Kategorie: Allgemeines Modell; Familienname: Luftleitungsteil 851455
Type - ID-Daten - Typname: Luftleitungsteil 851455
Type - IFC-Parameter - Typ in IFC-Datei exportieren: Vorgabe
Description: Luftleitungsteil
Pset_DistributionFlowElementCommon - Reference: Luftleitungsteil 851455; sets with these values: 2
Andere - Typ: Luftleitungsteil 851455; Familie: Luftleitungsteil 851455; Familie und Typ: Luftleitungsteil 851455: Luftleitungsteil 851455; Typ-ID: 2539386
Abhängigkeiten - Höhe von Ebene: 0 m; Verschieben mit umliegenden Elementen: no
Bemaßungen - Fläche: 1.32235 m2; Volumen: 0.746738 m3
IFC-Parameter - In IFC-Datei exportieren: Nach Typ; Pset MEP.Tech-Material (ID): 1; Pset MEP.Geom-Side 1 (mm): 1800; In IFC exportieren als: ifcflowsegment; NameOverride: Luftleitungsteil; IfcPresentationLayer: 0-TFT-L_Zuluft; ObjectTypeOverride: Luftleitungsteil; Pset MEP.Geom-Surface (m2): 2.6447; Pset MEP.Name: Luftleitungsteil; IfcDescription: Luftleitungsteil; Pset MEP.Geom-Length (mm): 388.926; Pset MEP.Abbreviation: LT; Pset MEP.Tech-Medium: L_Zuluft; Pset MEP.Geom-Side 2 (mm): 1600; Pset MEP.Tech-Weight (kg): 21.1576
Phasen - Phase erstellt: Phase 01

# IfcFlowSegment: Luftleitungsteil 852232:Luftleitungsteil 852232, Luftleitungsteil
In: Erdgeschoss
Type - Material: IfcSurfaceStyle #271082
Type - Andere - Kategorie: Allgemeines Modell; Familienname: Luftleitungsteil 852232
Type - ID-Daten - Typname: Luftleitungsteil 852232
Type - IFC-Parameter - Typ in IFC-Datei exportieren: Vorgabe
Description: Luftleitungsteil
Pset_DistributionFlowElementCommon - Reference: Luftleitungsteil 852232; sets with these values: 2
Andere - Typ: Luftleitungsteil 852232; Familie: Luftleitungsteil 852232; Familie und Typ: Luftleitungsteil 852232: Luftleitungsteil 852232; Typ-ID: 2539429
Abhängigkeiten - Höhe von Ebene: 0 m; Verschieben mit umliegenden Elementen: no
Bemaßungen - Fläche: 0.14 m2; Volumen: 0.03 m3
IFC-Parameter - In IFC-Datei exportieren: Nach Typ; Pset MEP.Geom-Length (mm): 100; Pset MEP.Tech-Material (ID): 1; Pset MEP.Geom-Surface (m2): 1; Pset MEP.Geom-Side 2 (mm): 900; Pset MEP.Geom-Side 1 (mm): 500; In IFC exportieren als: ifcflowsegment; NameOverride: Luftleitungsteil; IfcPresentationLayer: 0-TFT-L_Schalldaempfer; ObjectTypeOverride: Luftleitungsteil; Pset MEP.Name: Luftleitungsteil; IfcDescription: Luftleitungsteil; Pset MEP.Abbreviation: LT; Pset MEP.Tech-Medium: L_Zuluft; Pset MEP.Tech-Weight (kg): 1.792
Phasen - Phase erstellt: Phase 01

# IfcFlowSegment: Luftleitungsteil 852361:Luftleitungsteil 852361, Luftleitungsteil
In: 1. Obergeschoss
Type - Material: IfcSurfaceStyle #271263
Type - Andere - Kategorie: Allgemeines Modell; Familienname: Luftleitungsteil 852361
Type - ID-Daten - Typname: Luftleitungsteil 852361
Type - IFC-Parameter - Typ in IFC-Datei exportieren: Vorgabe
Description: Luftleitungsteil
Pset_DistributionFlowElementCommon - Reference: Luftleitungsteil 852361; sets with these values: 2
Andere - Typ: Luftleitungsteil 852361; Familie: Luftleitungsteil 852361; Familie und Typ: Luftleitungsteil 852361: Luftleitungsteil 852361; Typ-ID: 2539457
Abhängigkeiten - Höhe von Ebene: 0 m; Verschieben mit umliegenden Elementen: no
Bemaßungen - Fläche: 0.967231 m2; Volumen: 0.488404 m3
IFC-Parameter - In IFC-Datei exportieren: Nach Typ; Pset MEP.Tech-Material (ID): 1; Pset MEP.Geom-Side 1 (mm): 1500; Pset MEP.Geom-Side 2 (mm): 1530; In IFC exportieren als: ifcflowsegment; NameOverride: Luftleitungsteil; IfcPresentationLayer: 0-TFT-L_Zuluft; ObjectTypeOverride: Luftleitungsteil; Pset MEP.Geom-Surface (m2): 1.93446; Pset MEP.Name: Luftleitungsteil; IfcDescription: Luftleitungsteil; Pset MEP.Geom-Length (mm): 319.218; Pset MEP.Abbreviation: LT; Pset MEP.Tech-Medium: L_Zuluft; Pset MEP.Tech-Weight (kg): 15.4757
Phasen - Phase erstellt: Phase 01

# IfcFlowSegment: Luftleitungsteil 852384:Luftleitungsteil 852384, Luftleitungsteil
In: 1. Obergeschoss
Type - Material: IfcSurfaceStyle #271571
Type - Andere - Kategorie: Allgemeines Modell; Familienname: Luftleitungsteil 852384
Type - ID-Daten - Typname: Luftleitungsteil 852384
Type - IFC-Parameter - Typ in IFC-Datei exportieren: Vorgabe
Description: Luftleitungsteil
Pset_DistributionFlowElementCommon - Reference: Luftleitungsteil 852384; sets with these values: 2
Andere - Typ: Luftleitungsteil 852384; Familie: Luftleitungsteil 852384; Familie und Typ: Luftleitungsteil 852384: Luftleitungsteil 852384; Typ-ID: 2539464
Abhängigkeiten - Höhe von Ebene: 0 m; Verschieben mit umliegenden Elementen: no
Bemaßungen - Fläche: 0.537951 m2; Volumen: 0.268976 m3
IFC-Parameter - In IFC-Datei exportieren: Nach Typ; Pset MEP.Tech-Material (ID): 1; Pset MEP.Geom-Side 1 (mm): 1500; Pset MEP.Geom-Side 2 (mm): 1500; In IFC exportieren als: ifcflowsegment; NameOverride: Luftleitungsteil; IfcPresentationLayer: 0-TFT-L_Abluft; ObjectTypeOverride: Luftleitungsteil; Pset MEP.Geom-Surface (m2): 1.0759; Pset MEP.Name: Luftleitungsteil; IfcDescription: Luftleitungsteil; Pset MEP.Geom-Length (mm): 179.317; Pset MEP.Abbreviation: LT; Pset MEP.Tech-Medium: L_Abluft; Pset MEP.Tech-Weight (kg): 8.60722
Phasen - Phase erstellt: Phase 01

# IfcFlowSegment: Luftleitungsteil:Luftleitungsteil, Luftleitungsteil
In: 1. Obergeschoss
Type - Material: IfcSurfaceStyle #271571
Type - Andere - Kategorie: Allgemeines Modell; Familienname: Luftleitungsteil
Type - ID-Daten - Typname: Luftleitungsteil
Type - IFC-Parameter - Typ in IFC-Datei exportieren: Vorgabe
Description: Luftleitungsteil
Pset_DistributionFlowElementCommon - Reference: Luftleitungsteil; sets with these values: 2
Andere - Typ: Luftleitungsteil; Familie: Luftleitungsteil; Familie und Typ: Luftleitungsteil: Luftleitungsteil; Typ-ID: 2533530
Abhängigkeiten - Höhe von Ebene: 0 m; Verschieben mit umliegenden Elementen: no
Bemaßungen - Fläche: 0.537951 m2; Volumen: 0.268976 m3
IFC-Parameter - In IFC-Datei exportieren: Nach Typ; Pset MEP.Tech-Material (ID): 1; Pset MEP.Geom-Side 1 (mm): 1500; Pset MEP.Geom-Side 2 (mm): 1500; In IFC exportieren als: ifcflowsegment; NameOverride: Luftleitungsteil; IfcPresentationLayer: 0-TFT-L_Abluft; ObjectTypeOverride: Luftleitungsteil; Pset MEP.Geom-Surface (m2): 1.0759; Pset MEP.Name: Luftleitungsteil; IfcDescription: Luftleitungsteil; Pset MEP.Geom-Length (mm): 179.317; Pset MEP.Abbreviation: LT; Pset MEP.Tech-Medium: L_Abluft; Pset MEP.Tech-Weight (kg): 8.60722
Phasen - Phase erstellt: Phase 01

# IfcFlowSegment: Muffe 621744:Muffe 621744, Muffe
In: Erdgeschoss
Type - Material: IfcSurfaceStyle #251447
Type - Andere - Kategorie: Allgemeines Modell; Familienname: Muffe 621744
Type - ID-Daten - Typname: Muffe 621744
Type - IFC-Parameter - Typ in IFC-Datei exportieren: Vorgabe
Description: Muffe
Pset_DistributionFlowElementCommon - Reference: Muffe 621744; sets with these values: 2
Andere - Typ: Muffe 621744; Familie: Muffe 621744; Familie und Typ: Muffe 621744: Muffe 621744; Typ-ID: 2538092
Abhängigkeiten - Höhe von Ebene: 0 m; Verschieben mit umliegenden Elementen: no
Bemaßungen - Fläche: 0.112524 m2; Volumen: 0.0147753 m3
IFC-Parameter - In IFC-Datei exportieren: Nach Typ; Pset MEP.Geom-Ø (mm): 400; Pset MEP.Tech-Material (ID): 1; In IFC exportieren als: ifcflowsegment; NameOverride: Muffe; IfcPresentationLayer: 0-TFT-H_Abgasabführung Variante 1; ObjectTypeOverride: Muffe; Pset MEP.Name: Muffe; IfcDescription: Muffe; Pset MEP.Abbreviation: MFA; Pset MEP.Tech-Medium: L_Entrauchung; Pset MEP.Geom-Additional length (mm): 20; Pset MEP.Geom-Half length (mm): 80
Phasen - Phase erstellt: Phase 01

# IfcFlowSegment: Muffe 622019:Muffe 622019, Muffe
In: Erdgeschoss
Type - Material: IfcSurfaceStyle #251447
Type - Andere - Kategorie: Allgemeines Modell; Familienname: Muffe 622019
Type - ID-Daten - Typname: Muffe 622019
Type - IFC-Parameter - Typ in IFC-Datei exportieren: Vorgabe
Description: Muffe
Pset_DistributionFlowElementCommon - Reference: Muffe 622019; sets with these values: 2
Andere - Typ: Muffe 622019; Familie: Muffe 622019; Familie und Typ: Muffe 622019: Muffe 622019; Typ-ID: 2538134
Abhängigkeiten - Höhe von Ebene: 0 m; Verschieben mit umliegenden Elementen: no
Bemaßungen - Fläche: 0.112524 m2; Volumen: 0.0147753 m3
IFC-Parameter - In IFC-Datei exportieren: Nach Typ; Pset MEP.Geom-Ø (mm): 400; Pset MEP.Tech-Material (ID): 1; Pset MEP.Geom-Additional length (mm): 20; Pset MEP.Geom-Half length (mm): 80; In IFC exportieren als: ifcflowsegment; NameOverride: Muffe; IfcPresentationLayer: 0-TFT-H_Abgasabführung Variante 1; ObjectTypeOverride: Muffe; Pset MEP.Name: Muffe; IfcDescription: Muffe; Pset MEP.Abbreviation: MFA; Pset MEP.Tech-Medium: L_Entrauchung
Phasen - Phase erstellt: Phase 01

# IfcFlowSegment: Muffe:Muffe, Muffe
In: Erdgeschoss
Type - Material: IfcSurfaceStyle #251447
Type - Andere - Kategorie: Allgemeines Modell; Familienname: Muffe
Type - ID-Daten - Typname: Muffe
Type - IFC-Parameter - Typ in IFC-Datei exportieren: Vorgabe
Description: Muffe
Pset_DistributionFlowElementCommon - Reference: Muffe; sets with these values: 2
Andere - Typ: Muffe; Familie: Muffe; Familie und Typ: Muffe: Muffe; Typ-ID: 2537920
Abhängigkeiten - Höhe von Ebene: 0 m; Verschieben mit umliegenden Elementen: no
Bemaßungen - Fläche: 0.0267245 m2; Volumen: 0.00157911 m3
IFC-Parameter - In IFC-Datei exportieren: Nach Typ; Pset MEP.Tech-Material (ID): 1; Pset MEP.Geom-Ø (mm): 180; In IFC exportieren als: ifcflowsegment; NameOverride: Muffe; IfcPresentationLayer: 0-TFT-H_Abgasabführung Variante 1; ObjectTypeOverride: Muffe; Pset MEP.Name: Muffe; IfcDescription: Muffe; Pset MEP.Abbreviation: MFA; Pset MEP.Tech-Medium: L_Entrauchung; Pset MEP.Geom-Additional length (mm): 15; Pset MEP.Geom-Half length (mm): 40
Phasen - Phase erstellt: Phase 01

# IfcFlowSegment: Rohrbogen 15085:Rohrbogen 15085, Rohrbogen
In: 1. Obergeschoss
Type - Material: IfcSurfaceStyle #9317
Type - Andere - Kategorie: Allgemeines Modell; Familienname: Rohrbogen 15085
Type - ID-Daten - Typname: Rohrbogen 15085
Type - IFC-Parameter - Typ in IFC-Datei exportieren: Vorgabe
Description: Rohrbogen
Pset_DistributionFlowElementCommon - Reference: Rohrbogen 15085; sets with these values: 2
Andere - Typ: Rohrbogen 15085; Familie: Rohrbogen 15085; Familie und Typ: Rohrbogen 15085: Rohrbogen 15085; Typ-ID: 2531575
Abhängigkeiten - Höhe von Ebene: 0 m; Verschieben mit umliegenden Elementen: no
Bemaßungen - Fläche: 0.298575 m2; Volumen: 0.0298688 m3
IFC-Parameter - In IFC-Datei exportieren: Nach Typ; Pset MEP.Tech-Insulation thickness (mm): 100; Pset MEP.Geom-DN1: 150; Pset MEP.Geom-DN2: 150; In IFC exportieren als: ifcflowsegment; NameOverride: Rohrbogen; IfcPresentationLayer: 0-TFT-H_Vorlauf; ObjectTypeOverride: Rohrbogen; Pset MEP.Name: Rohrbogen; IfcDescription: Rohrbogen; Pset MEP.Tech-Material: nach DIN 2605; Pset MEP.Geom-Outer Ø1 (mm): 168.3; Pset MEP.Geom-Outer Ø2 (mm): 168.3
Phasen - Phase erstellt: Phase 01

# IfcFlowSegment: Rohrbogen 220246:Rohrbogen 220246, Rohrbogen
In: 1. Obergeschoss
Type - Material: IfcSurfaceStyle #9317
Type - Andere - Kategorie: Allgemeines Modell; Familienname: Rohrbogen 220246
Type - ID-Daten - Typname: Rohrbogen 220246
Type - IFC-Parameter - Typ in IFC-Datei exportieren: Vorgabe
Description: Rohrbogen
Pset_DistributionFlowElementCommon - Reference: Rohrbogen 220246; sets with these values: 2
Andere - Typ: Rohrbogen 220246; Familie: Rohrbogen 220246; Familie und Typ: Rohrbogen 220246: Rohrbogen 220246; Typ-ID: 2531604
Abhängigkeiten - Höhe von Ebene: 0 m; Verschieben mit umliegenden Elementen: no
Bemaßungen - Fläche: 0.298575 m2; Volumen: 0.0298688 m3
IFC-Parameter - In IFC-Datei exportieren: Nach Typ; Pset MEP.Tech-Insulation thickness (mm): 100; Pset MEP.Geom-DN1: 150; Pset MEP.Geom-DN2: 150; In IFC exportieren als: ifcflowsegment; NameOverride: Rohrbogen; IfcPresentationLayer: 0-TFT-H_Vorlauf; ObjectTypeOverride: Rohrbogen; Pset MEP.Name: Rohrbogen; IfcDescription: Rohrbogen; Pset MEP.Tech-Material: nach DIN 2605; Pset MEP.Geom-Outer Ø1 (mm): 168.3; Pset MEP.Geom-Outer Ø2 (mm): 168.3
Phasen - Phase erstellt: Phase 01

# IfcFlowSegment: Rohrbogen 220556:Rohrbogen 220556, Rohrbogen
In: 1. Obergeschoss
Type - Material: IfcSurfaceStyle #9317
Type - Andere - Kategorie: Allgemeines Modell; Familienname: Rohrbogen 220556
Type - ID-Daten - Typname: Rohrbogen 220556
Type - IFC-Parameter - Typ in IFC-Datei exportieren: Vorgabe
Description: Rohrbogen
Pset_DistributionFlowElementCommon - Reference: Rohrbogen 220556; sets with these values: 2
Andere - Typ: Rohrbogen 220556; Familie: Rohrbogen 220556; Familie und Typ: Rohrbogen 220556: Rohrbogen 220556; Typ-ID: 2531618
Abhängigkeiten - Höhe von Ebene: 0 m; Verschieben mit umliegenden Elementen: no
Bemaßungen - Fläche: 0.47296 m2; Volumen: 0.0544204 m3
IFC-Parameter - In IFC-Datei exportieren: Nach Typ; Pset MEP.Tech-Insulation thickness (mm): 100; Pset MEP.Geom-DN1: 200; Pset MEP.Geom-DN2: 200; In IFC exportieren als: ifcflowsegment; NameOverride: Rohrbogen; IfcPresentationLayer: 0-TFT-H_Vorlauf; ObjectTypeOverride: Rohrbogen; Pset MEP.Name: Rohrbogen; IfcDescription: Rohrbogen; Pset MEP.Tech-Material: nach DIN 2605; Pset MEP.Geom-Outer Ø1 (mm): 219.1; Pset MEP.Geom-Outer Ø2 (mm): 219.1
Phasen - Phase erstellt: Phase 01

# IfcFlowSegment: Rohrbogen 221297:Rohrbogen 221297, Rohrbogen
In: 1. Obergeschoss
Type - Material: IfcSurfaceStyle #9317
Type - Andere - Kategorie: Allgemeines Modell; Familienname: Rohrbogen 221297
Type - ID-Daten - Typname: Rohrbogen 221297
Type - IFC-Parameter - Typ in IFC-Datei exportieren: Vorgabe
Description: Rohrbogen
Pset_DistributionFlowElementCommon - Reference: Rohrbogen 221297; sets with these values: 2
Andere - Typ: Rohrbogen 221297; Familie: Rohrbogen 221297; Familie und Typ: Rohrbogen 221297: Rohrbogen 221297; Typ-ID: 2531730
Abhängigkeiten - Höhe von Ebene: 0 m; Verschieben mit umliegenden Elementen: no
Bemaßungen - Fläche: 0.298575 m2; Volumen: 0.0298688 m3
IFC-Parameter - In IFC-Datei exportieren: Nach Typ; Pset MEP.Tech-Insulation thickness (mm): 100; Pset MEP.Geom-DN1: 150; Pset MEP.Geom-DN2: 150; In IFC exportieren als: ifcflowsegment; NameOverride: Rohrbogen; IfcPresentationLayer: 0-TFT-H_Vorlauf; ObjectTypeOverride: Rohrbogen; Pset MEP.Name: Rohrbogen; IfcDescription: Rohrbogen; Pset MEP.Tech-Material: nach DIN 2605; Pset MEP.Geom-Outer Ø1 (mm): 168.3; Pset MEP.Geom-Outer Ø2 (mm): 168.3
Phasen - Phase erstellt: Phase 01

# IfcFlowSegment: Rohrbogen 221563:Rohrbogen 221563, Rohrbogen
In: 1. Obergeschoss
Type - Material: IfcSurfaceStyle #9317
Type - Andere - Kategorie: Allgemeines Modell; Familienname: Rohrbogen 221563
Type - ID-Daten - Typname: Rohrbogen 221563
Type - IFC-Parameter - Typ in IFC-Datei exportieren: Vorgabe
Description: Rohrbogen
Pset_DistributionFlowElementCommon - Reference: Rohrbogen 221563; sets with these values: 2
Andere - Typ: Rohrbogen 221563; Familie: Rohrbogen 221563; Familie und Typ: Rohrbogen 221563: Rohrbogen 221563; Typ-ID: 2531810
Abhängigkeiten - Höhe von Ebene: 0 m; Verschieben mit umliegenden Elementen: no
Bemaßungen - Fläche: 0.298575 m2; Volumen: 0.0298688 m3
IFC-Parameter - In IFC-Datei exportieren: Nach Typ; Pset MEP.Tech-Insulation thickness (mm): 100; Pset MEP.Geom-DN1: 150; Pset MEP.Geom-DN2: 150; In IFC exportieren als: ifcflowsegment; NameOverride: Rohrbogen; IfcPresentationLayer: 0-TFT-H_Vorlauf; ObjectTypeOverride: Rohrbogen; Pset MEP.Name: Rohrbogen; IfcDescription: Rohrbogen; Pset MEP.Tech-Material: nach DIN 2605; Pset MEP.Geom-Outer Ø1 (mm): 168.3; Pset MEP.Geom-Outer Ø2 (mm): 168.3
Phasen - Phase erstellt: Phase 01

# IfcFlowSegment: Rohrbogen 222471:Rohrbogen 222471, Rohrbogen
In: 1. Obergeschoss
Type - Material: IfcSurfaceStyle #9317
Type - Andere - Kategorie: Allgemeines Modell; Familienname: Rohrbogen 222471
Type - ID-Daten - Typname: Rohrbogen 222471
Type - IFC-Parameter - Typ in IFC-Datei exportieren: Vorgabe
Description: Rohrbogen
Pset_DistributionFlowElementCommon - Reference: Rohrbogen 222471; sets with these values: 2
Andere - Typ: Rohrbogen 222471; Familie: Rohrbogen 222471; Familie und Typ: Rohrbogen 222471: Rohrbogen 222471; Typ-ID: 2531859
Abhängigkeiten - Höhe von Ebene: 0 m; Verschieben mit umliegenden Elementen: no
Bemaßungen - Fläche: 0.298575 m2; Volumen: 0.0298688 m3
IFC-Parameter - In IFC-Datei exportieren: Nach Typ; Pset MEP.Tech-Insulation thickness (mm): 100; Pset MEP.Geom-DN1: 150; Pset MEP.Geom-DN2: 150; In IFC exportieren als: ifcflowsegment; NameOverride: Rohrbogen; IfcPresentationLayer: 0-TFT-H_Vorlauf; ObjectTypeOverride: Rohrbogen; Pset MEP.Name: Rohrbogen; IfcDescription: Rohrbogen; Pset MEP.Tech-Material: nach DIN 2605; Pset MEP.Geom-Outer Ø1 (mm): 168.3; Pset MEP.Geom-Outer Ø2 (mm): 168.3
Phasen - Phase erstellt: Phase 01

# IfcFlowSegment: Rohrbogen 226821:Rohrbogen 226821, Rohrbogen
In: 1. Obergeschoss
Type - Material: IfcSurfaceStyle #1741
Type - Andere - Kategorie: Allgemeines Modell; Familienname: Rohrbogen 226821
Type - ID-Daten - Typname: Rohrbogen 226821
Type - IFC-Parameter - Typ in IFC-Datei exportieren: Vorgabe
Description: Rohrbogen
Pset_DistributionFlowElementCommon - Reference: Rohrbogen 226821; sets with these values: 2
Andere - Typ: Rohrbogen 226821; Familie: Rohrbogen 226821; Familie und Typ: Rohrbogen 226821: Rohrbogen 226821; Typ-ID: 2532055
Abhängigkeiten - Höhe von Ebene: 0 m; Verschieben mit umliegenden Elementen: no
IFC-Parameter - In IFC-Datei exportieren: Nach Typ; Pset MEP.Tech-Insulation thickness (mm): 100; Pset MEP.Geom-DN1: 100; Pset MEP.Geom-DN2: 100; In IFC exportieren als: ifcflowsegment; NameOverride: Rohrbogen; IfcPresentationLayer: 0-TFT-H_Ruecklauf; ObjectTypeOverride: Rohrbogen; Pset MEP.Name: Rohrbogen; IfcDescription: Rohrbogen; Pset MEP.Tech-Material: nach DIN 2605; Pset MEP.Geom-Outer Ø1 (mm): 114.3; Pset MEP.Geom-Outer Ø2 (mm): 114.3
Phasen - Phase erstellt: Phase 01

# IfcFlowSegment: Rohrbogen 226850:Rohrbogen 226850, Rohrbogen
In: 1. Obergeschoss
Type - Material: IfcSurfaceStyle #9317
Type - Andere - Kategorie: Allgemeines Modell; Familienname: Rohrbogen 226850
Type - ID-Daten - Typname: Rohrbogen 226850
Type - IFC-Parameter - Typ in IFC-Datei exportieren: Vorgabe
Description: Rohrbogen
Pset_DistributionFlowElementCommon - Reference: Rohrbogen 226850; sets with these values: 2
Andere - Typ: Rohrbogen 226850; Familie: Rohrbogen 226850; Familie und Typ: Rohrbogen 226850: Rohrbogen 226850; Typ-ID: 2532062
Abhängigkeiten - Höhe von Ebene: 0 m; Verschieben mit umliegenden Elementen: no
IFC-Parameter - In IFC-Datei exportieren: Nach Typ; Pset MEP.Tech-Insulation thickness (mm): 100; Pset MEP.Geom-DN1: 100; Pset MEP.Geom-DN2: 100; In IFC exportieren als: ifcflowsegment; NameOverride: Rohrbogen; IfcPresentationLayer: 0-TFT-H_Vorlauf; ObjectTypeOverride: Rohrbogen; Pset MEP.Name: Rohrbogen; IfcDescription: Rohrbogen; Pset MEP.Tech-Material: nach DIN 2605; Pset MEP.Geom-Outer Ø1 (mm): 114.3; Pset MEP.Geom-Outer Ø2 (mm): 114.3
Phasen - Phase erstellt: Phase 01

# IfcFlowSegment: Rohrbogen 226873:Rohrbogen 226873, Rohrbogen
In: 1. Obergeschoss
Type - Material: IfcSurfaceStyle #9317
Type - Andere - Kategorie: Allgemeines Modell; Familienname: Rohrbogen 226873
Type - ID-Daten - Typname: Rohrbogen 226873
Type - IFC-Parameter - Typ in IFC-Datei exportieren: Vorgabe
Description: Rohrbogen
Pset_DistributionFlowElementCommon - Reference: Rohrbogen 226873; sets with these values: 2
Andere - Typ: Rohrbogen 226873; Familie: Rohrbogen 226873; Familie und Typ: Rohrbogen 226873: Rohrbogen 226873; Typ-ID: 2532069
Abhängigkeiten - Höhe von Ebene: 0 m; Verschieben mit umliegenden Elementen: no
Bemaßungen - Fläche: 0.47296 m2; Volumen: 0.0544204 m3
IFC-Parameter - In IFC-Datei exportieren: Nach Typ; Pset MEP.Tech-Insulation thickness (mm): 100; Pset MEP.Geom-DN1: 200; Pset MEP.Geom-DN2: 200; In IFC exportieren als: ifcflowsegment; NameOverride: Rohrbogen; IfcPresentationLayer: 0-TFT-H_Vorlauf; ObjectTypeOverride: Rohrbogen; Pset MEP.Name: Rohrbogen; IfcDescription: Rohrbogen; Pset MEP.Tech-Material: nach DIN 2605; Pset MEP.Geom-Outer Ø1 (mm): 219.1; Pset MEP.Geom-Outer Ø2 (mm): 219.1
Phasen - Phase erstellt: Phase 01

# IfcFlowSegment: Rohrbogen 226902:Rohrbogen 226902, Rohrbogen
In: 1. Obergeschoss
Type - Material: IfcSurfaceStyle #9317
Type - Andere - Kategorie: Allgemeines Modell; Familienname: Rohrbogen 226902
Type - ID-Daten - Typname: Rohrbogen 226902
Type - IFC-Parameter - Typ in IFC-Datei exportieren: Vorgabe
Description: Rohrbogen
Pset_DistributionFlowElementCommon - Reference: Rohrbogen 226902; sets with these values: 2
Andere - Typ: Rohrbogen 226902; Familie: Rohrbogen 226902; Familie und Typ: Rohrbogen 226902: Rohrbogen 226902; Typ-ID: 2532076
Abhängigkeiten - Höhe von Ebene: 0 m; Verschieben mit umliegenden Elementen: no
Bemaßungen - Fläche: 0.47296 m2; Volumen: 0.0544204 m3
IFC-Parameter - In IFC-Datei exportieren: Nach Typ; Pset MEP.Tech-Insulation thickness (mm): 100; Pset MEP.Geom-DN1: 200; Pset MEP.Geom-DN2: 200; In IFC exportieren als: ifcflowsegment; NameOverride: Rohrbogen; IfcPresentationLayer: 0-TFT-H_Vorlauf; ObjectTypeOverride: Rohrbogen; Pset MEP.Name: Rohrbogen; IfcDescription: Rohrbogen; Pset MEP.Tech-Material: nach DIN 2605; Pset MEP.Geom-Outer Ø1 (mm): 219.1; Pset MEP.Geom-Outer Ø2 (mm): 219.1
Phasen - Phase erstellt: Phase 01

# IfcFlowSegment: Rohrbogen 227214:Rohrbogen 227214, Rohrbogen
In: 1. Obergeschoss
Type - Material: IfcSurfaceStyle #1741
Type - Andere - Kategorie: Allgemeines Modell; Familienname: Rohrbogen 227214
Type - ID-Daten - Typname: Rohrbogen 227214
Type - IFC-Parameter - Typ in IFC-Datei exportieren: Vorgabe
Description: Rohrbogen
Pset_DistributionFlowElementCommon - Reference: Rohrbogen 227214; sets with these values: 2
Andere - Typ: Rohrbogen 227214; Familie: Rohrbogen 227214; Familie und Typ: Rohrbogen 227214: Rohrbogen 227214; Typ-ID: 2532090
Abhängigkeiten - Höhe von Ebene: 0 m; Verschieben mit umliegenden Elementen: no
Bemaßungen - Fläche: 0.47296 m2; Volumen: 0.0544204 m3
IFC-Parameter - In IFC-Datei exportieren: Nach Typ; Pset MEP.Tech-Insulation thickness (mm): 100; Pset MEP.Geom-DN1: 200; Pset MEP.Geom-DN2: 200; In IFC exportieren als: ifcflowsegment; NameOverride: Rohrbogen; IfcPresentationLayer: 0-TFT-H_Ruecklauf; ObjectTypeOverride: Rohrbogen; Pset MEP.Name: Rohrbogen; IfcDescription: Rohrbogen; Pset MEP.Tech-Material: nach DIN 2605; Pset MEP.Geom-Outer Ø1 (mm): 219.1; Pset MEP.Geom-Outer Ø2 (mm): 219.1
Phasen - Phase erstellt: Phase 01

# IfcFlowSegment: Rohrbogen 227237:Rohrbogen 227237, Rohrbogen
In: 1. Obergeschoss
Type - Material: IfcSurfaceStyle #1741
Type - Andere - Kategorie: Allgemeines Modell; Familienname: Rohrbogen 227237
Type - ID-Daten - Typname: Rohrbogen 227237
Type - IFC-Parameter - Typ in IFC-Datei exportieren: Vorgabe
Description: Rohrbogen
Pset_DistributionFlowElementCommon - Reference: Rohrbogen 227237; sets with these values: 2
Andere - Typ: Rohrbogen 227237; Familie: Rohrbogen 227237; Familie und Typ: Rohrbogen 227237: Rohrbogen 227237; Typ-ID: 2532097
Abhängigkeiten - Höhe von Ebene: 0 m; Verschieben mit umliegenden Elementen: no
Bemaßungen - Fläche: 0.47296 m2; Volumen: 0.0544204 m3
IFC-Parameter - In IFC-Datei exportieren: Nach Typ; Pset MEP.Tech-Insulation thickness (mm): 100; Pset MEP.Geom-DN1: 200; Pset MEP.Geom-DN2: 200; In IFC exportieren als: ifcflowsegment; NameOverride: Rohrbogen; IfcPresentationLayer: 0-TFT-H_Ruecklauf; ObjectTypeOverride: Rohrbogen; Pset MEP.Name: Rohrbogen; IfcDescription: Rohrbogen; Pset MEP.Tech-Material: nach DIN 2605; Pset MEP.Geom-Outer Ø1 (mm): 219.1; Pset MEP.Geom-Outer Ø2 (mm): 219.1
Phasen - Phase erstellt: Phase 01

# IfcFlowSegment: Rohrbogen 228539:Rohrbogen 228539, Rohrbogen
In: 1. Obergeschoss
Type - Material: IfcSurfaceStyle #9317
Type - Andere - Kategorie: Allgemeines Modell; Familienname: Rohrbogen 228539
Type - ID-Daten - Typname: Rohrbogen 228539
Type - IFC-Parameter - Typ in IFC-Datei exportieren: Vorgabe
Description: Rohrbogen
Pset_DistributionFlowElementCommon - Reference: Rohrbogen 228539; sets with these values: 2
Andere - Typ: Rohrbogen 228539; Familie: Rohrbogen 228539; Familie und Typ: Rohrbogen 228539: Rohrbogen 228539; Typ-ID: 2532165
Abhängigkeiten - Höhe von Ebene: 0 m; Verschieben mit umliegenden Elementen: no
Bemaßungen - Fläche: 0.47296 m2; Volumen: 0.0544204 m3
IFC-Parameter - In IFC-Datei exportieren: Nach Typ; Pset MEP.Tech-Insulation thickness (mm): 100; Pset MEP.Geom-DN1: 200; Pset MEP.Geom-DN2: 200; In IFC exportieren als: ifcflowsegment; NameOverride: Rohrbogen; IfcPresentationLayer: 0-TFT-H_Vorlauf; ObjectTypeOverride: Rohrbogen; Pset MEP.Name: Rohrbogen; IfcDescription: Rohrbogen; Pset MEP.Tech-Material: nach DIN 2605; Pset MEP.Geom-Outer Ø1 (mm): 219.1; Pset MEP.Geom-Outer Ø2 (mm): 219.1
Phasen - Phase erstellt: Phase 01

# IfcFlowSegment: Rohrbogen 228849:Rohrbogen 228849, Rohrbogen
In: 1. Obergeschoss
Type - Material: IfcSurfaceStyle #9317
Type - Andere - Kategorie: Allgemeines Modell; Familienname: Rohrbogen 228849
Type - ID-Daten - Typname: Rohrbogen 228849
Type - IFC-Parameter - Typ in IFC-Datei exportieren: Vorgabe
Description: Rohrbogen
Pset_DistributionFlowElementCommon - Reference: Rohrbogen 228849; sets with these values: 2
Andere - Typ: Rohrbogen 228849; Familie: Rohrbogen 228849; Familie und Typ: Rohrbogen 228849: Rohrbogen 228849; Typ-ID: 2532179
Abhängigkeiten - Höhe von Ebene: 0 m; Verschieben mit umliegenden Elementen: no
Bemaßungen - Fläche: 0.221319 m2; Volumen: 0.0203891 m3
IFC-Parameter - In IFC-Datei exportieren: Nach Typ; Pset MEP.Tech-Insulation thickness (mm): 100; In IFC exportieren als: ifcflowsegment; NameOverride: Rohrbogen; IfcPresentationLayer: 0-TFT-H_Vorlauf; ObjectTypeOverride: Rohrbogen; Pset MEP.Name: Rohrbogen; IfcDescription: Rohrbogen; Pset MEP.Tech-Material: nach DIN 2605; Pset MEP.Geom-DN1: 125; Pset MEP.Geom-DN2: 125; Pset MEP.Geom-Outer Ø1 (mm): 139.7; Pset MEP.Geom-Outer Ø2 (mm): 139.7
Phasen - Phase erstellt: Phase 01

# IfcFlowSegment: Rohrbogen 236771:Rohrbogen 236771, Rohrbogen
In: 1. Obergeschoss
Type - Material: IfcSurfaceStyle #9317
Type - Andere - Kategorie: Allgemeines Modell; Familienname: Rohrbogen 236771
Type - ID-Daten - Typname: Rohrbogen 236771
Type - IFC-Parameter - Typ in IFC-Datei exportieren: Vorgabe
Description: Rohrbogen
Pset_DistributionFlowElementCommon - Reference: Rohrbogen 236771; sets with these values: 2
Andere - Typ: Rohrbogen 236771; Familie: Rohrbogen 236771; Familie und Typ: Rohrbogen 236771: Rohrbogen 236771; Typ-ID: 2532256
Abhängigkeiten - Höhe von Ebene: 0 m; Verschieben mit umliegenden Elementen: no
Bemaßungen - Fläche: 0.221319 m2; Volumen: 0.0203891 m3
IFC-Parameter - In IFC-Datei exportieren: Nach Typ; Pset MEP.Tech-Insulation thickness (mm): 100; Pset MEP.Geom-DN1: 125; Pset MEP.Geom-DN2: 125; In IFC exportieren als: ifcflowsegment; NameOverride: Rohrbogen; IfcPresentationLayer: 0-TFT-H_Vorlauf; ObjectTypeOverride: Rohrbogen; Pset MEP.Name: Rohrbogen; IfcDescription: Rohrbogen; Pset MEP.Tech-Material: nach DIN 2605; Pset MEP.Geom-Outer Ø1 (mm): 139.7; Pset MEP.Geom-Outer Ø2 (mm): 139.7
Phasen - Phase erstellt: Phase 01

# IfcFlowSegment: Rohrbogen 237024:Rohrbogen 237024, Rohrbogen
In: 1. Obergeschoss
Type - Material: IfcSurfaceStyle #9317
Type - Andere - Kategorie: Allgemeines Modell; Familienname: Rohrbogen 237024
Type - ID-Daten - Typname: Rohrbogen 237024
Type - IFC-Parameter - Typ in IFC-Datei exportieren: Vorgabe
Description: Rohrbogen
Pset_DistributionFlowElementCommon - Reference: Rohrbogen 237024; sets with these values: 2
Andere - Typ: Rohrbogen 237024; Familie: Rohrbogen 237024; Familie und Typ: Rohrbogen 237024: Rohrbogen 237024; Typ-ID: 2532333
Abhängigkeiten - Höhe von Ebene: 0 m; Verschieben mit umliegenden Elementen: no
Bemaßungen - Fläche: 0.221319 m2; Volumen: 0.0203891 m3
IFC-Parameter - In IFC-Datei exportieren: Nach Typ; Pset MEP.Tech-Insulation thickness (mm): 100; Pset MEP.Geom-DN1: 125; Pset MEP.Geom-DN2: 125; In IFC exportieren als: ifcflowsegment; NameOverride: Rohrbogen; IfcPresentationLayer: 0-TFT-H_Vorlauf; ObjectTypeOverride: Rohrbogen; Pset MEP.Name: Rohrbogen; IfcDescription: Rohrbogen; Pset MEP.Tech-Material: nach DIN 2605; Pset MEP.Geom-Outer Ø1 (mm): 139.7; Pset MEP.Geom-Outer Ø2 (mm): 139.7
Phasen - Phase erstellt: Phase 01

# IfcFlowSegment: Rohrbogen 248180:Rohrbogen 248180, Rohrbogen
In: 1. Obergeschoss
Type - Material: IfcSurfaceStyle #1741
Type - Andere - Kategorie: Allgemeines Modell; Familienname: Rohrbogen 248180
Type - ID-Daten - Typname: Rohrbogen 248180
Type - IFC-Parameter - Typ in IFC-Datei exportieren: Vorgabe
Description: Rohrbogen
Pset_DistributionFlowElementCommon - Reference: Rohrbogen 248180; sets with these values: 2
Andere - Typ: Rohrbogen 248180; Familie: Rohrbogen 248180; Familie und Typ: Rohrbogen 248180: Rohrbogen 248180; Typ-ID: 2532725
Abhängigkeiten - Höhe von Ebene: 0 m; Verschieben mit umliegenden Elementen: no
Bemaßungen - Fläche: 0.0794992 m2; Volumen: 0.00757056 m3
IFC-Parameter - In IFC-Datei exportieren: Nach Typ; Pset MEP.Tech-Insulation thickness (mm): 100; Pset MEP.Geom-DN1: 200; Pset MEP.Geom-DN2: 200; In IFC exportieren als: ifcflowsegment; NameOverride: Rohrbogen; IfcPresentationLayer: 0-TFT-H_Ruecklauf; ObjectTypeOverride: Rohrbogen; Pset MEP.Name: Rohrbogen; IfcDescription: Rohrbogen; Pset MEP.Tech-Material: nach DIN 2605; Pset MEP.Geom-Outer Ø1 (mm): 219.1; Pset MEP.Geom-Outer Ø2 (mm): 219.1
Phasen - Phase erstellt: Phase 01

# IfcFlowSegment: Rohrbogen 248783:Rohrbogen 248783, Rohrbogen
In: 1. Obergeschoss
Type - Material: IfcSurfaceStyle #1741
Type - Andere - Kategorie: Allgemeines Modell; Familienname: Rohrbogen 248783
Type - ID-Daten - Typname: Rohrbogen 248783
Type - IFC-Parameter - Typ in IFC-Datei exportieren: Vorgabe
Description: Rohrbogen
Pset_DistributionFlowElementCommon - Reference: Rohrbogen 248783; sets with these values: 2
Andere - Typ: Rohrbogen 248783; Familie: Rohrbogen 248783; Familie und Typ: Rohrbogen 248783: Rohrbogen 248783; Typ-ID: 2532732
Abhängigkeiten - Höhe von Ebene: 0 m; Verschieben mit umliegenden Elementen: no
Bemaßungen - Fläche: 0.0794992 m2; Volumen: 0.00757056 m3
IFC-Parameter - In IFC-Datei exportieren: Nach Typ; Pset MEP.Tech-Insulation thickness (mm): 100; Pset MEP.Geom-DN1: 200; Pset MEP.Geom-DN2: 200; In IFC exportieren als: ifcflowsegment; NameOverride: Rohrbogen; IfcPresentationLayer: 0-TFT-H_Ruecklauf; ObjectTypeOverride: Rohrbogen; Pset MEP.Name: Rohrbogen; IfcDescription: Rohrbogen; Pset MEP.Tech-Material: nach DIN 2605; Pset MEP.Geom-Outer Ø1 (mm): 219.1; Pset MEP.Geom-Outer Ø2 (mm): 219.1
Phasen - Phase erstellt: Phase 01

# IfcFlowSegment: Rohrbogen 249432:Rohrbogen 249432, Rohrbogen
In: 1. Obergeschoss
Type - Material: IfcSurfaceStyle #9317
Type - Andere - Kategorie: Allgemeines Modell; Familienname: Rohrbogen 249432
Type - ID-Daten - Typname: Rohrbogen 249432
Type - IFC-Parameter - Typ in IFC-Datei exportieren: Vorgabe
Description: Rohrbogen
Pset_DistributionFlowElementCommon - Reference: Rohrbogen 249432; sets with these values: 2
Andere - Typ: Rohrbogen 249432; Familie: Rohrbogen 249432; Familie und Typ: Rohrbogen 249432: Rohrbogen 249432; Typ-ID: 2532767
Abhängigkeiten - Höhe von Ebene: 0 m; Verschieben mit umliegenden Elementen: no
Bemaßungen - Fläche: 0.47296 m2; Volumen: 0.0544204 m3
IFC-Parameter - In IFC-Datei exportieren: Nach Typ; Pset MEP.Tech-Insulation thickness (mm): 100; Pset MEP.Geom-DN1: 200; Pset MEP.Geom-DN2: 200; In IFC exportieren als: ifcflowsegment; NameOverride: Rohrbogen; IfcPresentationLayer: 0-TFT-H_Vorlauf; ObjectTypeOverride: Rohrbogen; Pset MEP.Name: Rohrbogen; IfcDescription: Rohrbogen; Pset MEP.Tech-Material: nach DIN 2605; Pset MEP.Geom-Outer Ø1 (mm): 219.1; Pset MEP.Geom-Outer Ø2 (mm): 219.1
Phasen - Phase erstellt: Phase 01

# IfcFlowSegment: Rohrbogen 250327:Rohrbogen 250327, Rohrbogen
In: 1. Obergeschoss
Type - Material: IfcSurfaceStyle #1741
Type - Andere - Kategorie: Allgemeines Modell; Familienname: Rohrbogen 250327
Type - ID-Daten - Typname: Rohrbogen 250327
Type - IFC-Parameter - Typ in IFC-Datei exportieren: Vorgabe
Description: Rohrbogen
Pset_DistributionFlowElementCommon - Reference: Rohrbogen 250327; sets with these values: 2
Andere - Typ: Rohrbogen 250327; Familie: Rohrbogen 250327; Familie und Typ: Rohrbogen 250327: Rohrbogen 250327; Typ-ID: 2532802
Abhängigkeiten - Höhe von Ebene: 0 m; Verschieben mit umliegenden Elementen: no
Bemaßungen - Fläche: 0.47296 m2; Volumen: 0.0544204 m3
IFC-Parameter - In IFC-Datei exportieren: Nach Typ; Pset MEP.Tech-Insulation thickness (mm): 100; Pset MEP.Geom-DN1: 200; Pset MEP.Geom-DN2: 200; In IFC exportieren als: ifcflowsegment; NameOverride: Rohrbogen; IfcPresentationLayer: 0-TFT-H_Ruecklauf; ObjectTypeOverride: Rohrbogen; Pset MEP.Name: Rohrbogen; IfcDescription: Rohrbogen; Pset MEP.Tech-Material: nach DIN 2605; Pset MEP.Geom-Outer Ø1 (mm): 219.1; Pset MEP.Geom-Outer Ø2 (mm): 219.1
Phasen - Phase erstellt: Phase 01

# IfcFlowSegment: Rohrbogen 250912:Rohrbogen 250912, Rohrbogen
In: 1. Obergeschoss
Type - Material: IfcSurfaceStyle #1741
Type - Andere - Kategorie: Allgemeines Modell; Familienname: Rohrbogen 250912
Type - ID-Daten - Typname: Rohrbogen 250912
Type - IFC-Parameter - Typ in IFC-Datei exportieren: Vorgabe
Description: Rohrbogen
Pset_DistributionFlowElementCommon - Reference: Rohrbogen 250912; sets with these values: 2
Andere - Typ: Rohrbogen 250912; Familie: Rohrbogen 250912; Familie und Typ: Rohrbogen 250912: Rohrbogen 250912; Typ-ID: 2532823
Abhängigkeiten - Höhe von Ebene: 0 m; Verschieben mit umliegenden Elementen: no
Bemaßungen - Fläche: 0.47296 m2; Volumen: 0.0544204 m3
IFC-Parameter - In IFC-Datei exportieren: Nach Typ; Pset MEP.Tech-Insulation thickness (mm): 100; Pset MEP.Geom-DN1: 200; Pset MEP.Geom-DN2: 200; In IFC exportieren als: ifcflowsegment; NameOverride: Rohrbogen; IfcPresentationLayer: 0-TFT-H_Ruecklauf; ObjectTypeOverride: Rohrbogen; Pset MEP.Name: Rohrbogen; IfcDescription: Rohrbogen; Pset MEP.Tech-Material: nach DIN 2605; Pset MEP.Geom-Outer Ø1 (mm): 219.1; Pset MEP.Geom-Outer Ø2 (mm): 219.1
Phasen - Phase erstellt: Phase 01

# IfcFlowSegment: Rohrbogen 250935:Rohrbogen 250935, Rohrbogen
In: 1. Obergeschoss
Type - Material: IfcSurfaceStyle #9317
Type - Andere - Kategorie: Allgemeines Modell; Familienname: Rohrbogen 250935
Type - ID-Daten - Typname: Rohrbogen 250935
Type - IFC-Parameter - Typ in IFC-Datei exportieren: Vorgabe
Description: Rohrbogen
Pset_DistributionFlowElementCommon - Reference: Rohrbogen 250935; sets with these values: 2
Andere - Typ: Rohrbogen 250935; Familie: Rohrbogen 250935; Familie und Typ: Rohrbogen 250935: Rohrbogen 250935; Typ-ID: 2532830
Abhängigkeiten - Höhe von Ebene: 0 m; Verschieben mit umliegenden Elementen: no
Bemaßungen - Fläche: 0.47296 m2; Volumen: 0.0544204 m3
IFC-Parameter - In IFC-Datei exportieren: Nach Typ; Pset MEP.Tech-Insulation thickness (mm): 100; Pset MEP.Geom-DN1: 200; Pset MEP.Geom-DN2: 200; In IFC exportieren als: ifcflowsegment; NameOverride: Rohrbogen; IfcPresentationLayer: 0-TFT-H_Vorlauf; ObjectTypeOverride: Rohrbogen; Pset MEP.Name: Rohrbogen; IfcDescription: Rohrbogen; Pset MEP.Tech-Material: nach DIN 2605; Pset MEP.Geom-Outer Ø1 (mm): 219.1; Pset MEP.Geom-Outer Ø2 (mm): 219.1
Phasen - Phase erstellt: Phase 01

# IfcFlowSegment: Rohrbogen 257273:Rohrbogen 257273, Rohrbogen
In: 1. Obergeschoss
Type - Material: IfcSurfaceStyle #1741
Type - Andere - Kategorie: Allgemeines Modell; Familienname: Rohrbogen 257273
Type - ID-Daten - Typname: Rohrbogen 257273
Type - IFC-Parameter - Typ in IFC-Datei exportieren: Vorgabe
Description: Rohrbogen
Pset_DistributionFlowElementCommon - Reference: Rohrbogen 257273; sets with these values: 2
Andere - Typ: Rohrbogen 257273; Familie: Rohrbogen 257273; Familie und Typ: Rohrbogen 257273: Rohrbogen 257273; Typ-ID: 2532981
Abhängigkeiten - Höhe von Ebene: 0 m; Verschieben mit umliegenden Elementen: no
IFC-Parameter - In IFC-Datei exportieren: Nach Typ; Pset MEP.Tech-Insulation thickness (mm): 100; Pset MEP.Geom-DN1: 65; Pset MEP.Geom-DN2: 65; In IFC exportieren als: ifcflowsegment; NameOverride: Rohrbogen; IfcPresentationLayer: 0-TFT-H_Ruecklauf; ObjectTypeOverride: Rohrbogen; Pset MEP.Name: Rohrbogen; IfcDescription: Rohrbogen; Pset MEP.Tech-Material: nach DIN 2605; Pset MEP.Geom-Outer Ø1 (mm): 76.1; Pset MEP.Geom-Outer Ø2 (mm): 76.1
Phasen - Phase erstellt: Phase 01

# IfcFlowSegment: Rohrbogen 259180:Rohrbogen 259180, Rohrbogen
In: 1. Obergeschoss
Type - Material: IfcSurfaceStyle #1741
Type - Andere - Kategorie: Allgemeines Modell; Familienname: Rohrbogen 259180
Type - ID-Daten - Typname: Rohrbogen 259180
Type - IFC-Parameter - Typ in IFC-Datei exportieren: Vorgabe
Description: Rohrbogen
Pset_DistributionFlowElementCommon - Reference: Rohrbogen 259180; sets with these values: 2
Andere - Typ: Rohrbogen 259180; Familie: Rohrbogen 259180; Familie und Typ: Rohrbogen 259180: Rohrbogen 259180; Typ-ID: 2533030
Abhängigkeiten - Höhe von Ebene: 0 m; Verschieben mit umliegenden Elementen: no
IFC-Parameter - In IFC-Datei exportieren: Nach Typ; Pset MEP.Tech-Insulation thickness (mm): 100; Pset MEP.Geom-DN1: 65; Pset MEP.Geom-DN2: 65; In IFC exportieren als: ifcflowsegment; NameOverride: Rohrbogen; IfcPresentationLayer: 0-TFT-H_Ruecklauf; ObjectTypeOverride: Rohrbogen; Pset MEP.Name: Rohrbogen; IfcDescription: Rohrbogen; Pset MEP.Tech-Material: nach DIN 2605; Pset MEP.Geom-Outer Ø1 (mm): 76.1; Pset MEP.Geom-Outer Ø2 (mm): 76.1
Phasen - Phase erstellt: Phase 01

# IfcFlowSegment: Rohrbogen 266739:Rohrbogen 266739, Rohrbogen
In: 1. Obergeschoss
Type - Material: IfcSurfaceStyle #9317
Type - Andere - Kategorie: Allgemeines Modell; Familienname: Rohrbogen 266739
Type - ID-Daten - Typname: Rohrbogen 266739
Type - IFC-Parameter - Typ in IFC-Datei exportieren: Vorgabe
Description: Rohrbogen
Pset_DistributionFlowElementCommon - Reference: Rohrbogen 266739; sets with these values: 2
Andere - Typ: Rohrbogen 266739; Familie: Rohrbogen 266739; Familie und Typ: Rohrbogen 266739: Rohrbogen 266739; Typ-ID: 2533198
Abhängigkeiten - Höhe von Ebene: 0 m; Verschieben mit umliegenden Elementen: no
IFC-Parameter - In IFC-Datei exportieren: Nach Typ; Pset MEP.Tech-Insulation thickness (mm): 100; Pset MEP.Geom-DN1: 100; Pset MEP.Geom-DN2: 100; In IFC exportieren als: ifcflowsegment; NameOverride: Rohrbogen; IfcPresentationLayer: 0-TFT-H_Vorlauf; ObjectTypeOverride: Rohrbogen; Pset MEP.Name: Rohrbogen; IfcDescription: Rohrbogen; Pset MEP.Tech-Material: nach DIN 2605; Pset MEP.Geom-Outer Ø1 (mm): 114.3; Pset MEP.Geom-Outer Ø2 (mm): 114.3
Phasen - Phase erstellt: Phase 01

# IfcFlowSegment: Rohrbogen 267376:Rohrbogen 267376, Rohrbogen
In: 1. Obergeschoss
Type - Material: IfcSurfaceStyle #9317
Type - Andere - Kategorie: Allgemeines Modell; Familienname: Rohrbogen 267376
Type - ID-Daten - Typname: Rohrbogen 267376
Type - IFC-Parameter - Typ in IFC-Datei exportieren: Vorgabe
Description: Rohrbogen
Pset_DistributionFlowElementCommon - Reference: Rohrbogen 267376; sets with these values: 2
Andere - Typ: Rohrbogen 267376; Familie: Rohrbogen 267376; Familie und Typ: Rohrbogen 267376: Rohrbogen 267376; Typ-ID: 2533233
Abhängigkeiten - Höhe von Ebene: 0 m; Verschieben mit umliegenden Elementen: no
IFC-Parameter - In IFC-Datei exportieren: Nach Typ; Pset MEP.Tech-Insulation thickness (mm): 100; Pset MEP.Geom-DN1: 100; Pset MEP.Geom-DN2: 100; In IFC exportieren als: ifcflowsegment; NameOverride: Rohrbogen; IfcPresentationLayer: 0-TFT-H_Vorlauf; ObjectTypeOverride: Rohrbogen; Pset MEP.Name: Rohrbogen; IfcDescription: Rohrbogen; Pset MEP.Tech-Material: nach DIN 2605; Pset MEP.Geom-Outer Ø1 (mm): 114.3; Pset MEP.Geom-Outer Ø2 (mm): 114.3
Phasen - Phase erstellt: Phase 01

# IfcFlowSegment: Rohrbogen 277743:Rohrbogen 277743, Rohrbogen
In: Erdgeschoss
Type - Material: IfcSurfaceStyle #9317
Type - Andere - Kategorie: Allgemeines Modell; Familienname: Rohrbogen 277743
Type - ID-Daten - Typname: Rohrbogen 277743
Type - IFC-Parameter - Typ in IFC-Datei exportieren: Vorgabe
Description: Rohrbogen
Pset_DistributionFlowElementCommon - Reference: Rohrbogen 277743; sets with these values: 2
Andere - Typ: Rohrbogen 277743; Familie: Rohrbogen 277743; Familie und Typ: Rohrbogen 277743: Rohrbogen 277743; Typ-ID: 2533886
Abhängigkeiten - Höhe von Ebene: 0 m; Verschieben mit umliegenden Elementen: no
Bemaßungen - Fläche: 0.47296 m2; Volumen: 0.0544204 m3
IFC-Parameter - In IFC-Datei exportieren: Nach Typ; Pset MEP.Tech-Insulation thickness (mm): 100; Pset MEP.Geom-DN1: 200; Pset MEP.Geom-DN2: 200; In IFC exportieren als: ifcflowsegment; NameOverride: Rohrbogen; IfcPresentationLayer: 0-TFT-H_Vorlauf; ObjectTypeOverride: Rohrbogen; Pset MEP.Name: Rohrbogen; IfcDescription: Rohrbogen; Pset MEP.Tech-Material: nach DIN 2605; Pset MEP.Geom-Outer Ø1 (mm): 219.1; Pset MEP.Geom-Outer Ø2 (mm): 219.1
Phasen - Phase erstellt: Phase 01

# IfcFlowSegment: Rohrbogen 292566:Rohrbogen 292566, Rohrbogen
In: Erdgeschoss
Type - Material: IfcSurfaceStyle #1741
Type - Andere - Kategorie: Allgemeines Modell; Familienname: Rohrbogen 292566
Type - ID-Daten - Typname: Rohrbogen 292566
Type - IFC-Parameter - Typ in IFC-Datei exportieren: Vorgabe
Description: Rohrbogen
Pset_DistributionFlowElementCommon - Reference: Rohrbogen 292566; sets with these values: 2
Andere - Typ: Rohrbogen 292566; Familie: Rohrbogen 292566; Familie und Typ: Rohrbogen 292566: Rohrbogen 292566; Typ-ID: 2534319
Abhängigkeiten - Höhe von Ebene: 0 m; Verschieben mit umliegenden Elementen: no
Bemaßungen - Fläche: 0.47296 m2; Volumen: 0.0544204 m3
IFC-Parameter - In IFC-Datei exportieren: Nach Typ; Pset MEP.Tech-Insulation thickness (mm): 100; Pset MEP.Geom-DN1: 200; Pset MEP.Geom-DN2: 200; In IFC exportieren als: ifcflowsegment; NameOverride: Rohrbogen; IfcPresentationLayer: 0-TFT-H_Ruecklauf; ObjectTypeOverride: Rohrbogen; Pset MEP.Name: Rohrbogen; IfcDescription: Rohrbogen; Pset MEP.Tech-Material: nach DIN 2605; Pset MEP.Geom-Outer Ø1 (mm): 219.1; Pset MEP.Geom-Outer Ø2 (mm): 219.1
Phasen - Phase erstellt: Phase 01

# IfcFlowSegment: Rohrbogen 292589:Rohrbogen 292589, Rohrbogen
In: Erdgeschoss
Type - Material: IfcSurfaceStyle #1741
Type - Andere - Kategorie: Allgemeines Modell; Familienname: Rohrbogen 292589
Type - ID-Daten - Typname: Rohrbogen 292589
Type - IFC-Parameter - Typ in IFC-Datei exportieren: Vorgabe
Description: Rohrbogen
Pset_DistributionFlowElementCommon - Reference: Rohrbogen 292589; sets with these values: 2
Andere - Typ: Rohrbogen 292589; Familie: Rohrbogen 292589; Familie und Typ: Rohrbogen 292589: Rohrbogen 292589; Typ-ID: 2534326
Abhängigkeiten - Höhe von Ebene: 0 m; Verschieben mit umliegenden Elementen: no
IFC-Parameter - In IFC-Datei exportieren: Nach Typ; Pset MEP.Tech-Insulation thickness (mm): 100; Pset MEP.Geom-DN1: 100; Pset MEP.Geom-DN2: 100; In IFC exportieren als: ifcflowsegment; NameOverride: Rohrbogen; IfcPresentationLayer: 0-TFT-H_Ruecklauf; ObjectTypeOverride: Rohrbogen; Pset MEP.Name: Rohrbogen; IfcDescription: Rohrbogen; Pset MEP.Tech-Material: nach DIN 2605; Pset MEP.Geom-Outer Ø1 (mm): 114.3; Pset MEP.Geom-Outer Ø2 (mm): 114.3
Phasen - Phase erstellt: Phase 01

# IfcFlowSegment: Rohrbogen 292612:Rohrbogen 292612, Rohrbogen
In: Erdgeschoss
Type - Material: IfcSurfaceStyle #1741
Type - Andere - Kategorie: Allgemeines Modell; Familienname: Rohrbogen 292612
Type - ID-Daten - Typname: Rohrbogen 292612
Type - IFC-Parameter - Typ in IFC-Datei exportieren: Vorgabe
Description: Rohrbogen
Pset_DistributionFlowElementCommon - Reference: Rohrbogen 292612; sets with these values: 2
Andere - Typ: Rohrbogen 292612; Familie: Rohrbogen 292612; Familie und Typ: Rohrbogen 292612: Rohrbogen 292612; Typ-ID: 2534333
Abhängigkeiten - Höhe von Ebene: 0 m; Verschieben mit umliegenden Elementen: no
IFC-Parameter - In IFC-Datei exportieren: Nach Typ; Pset MEP.Tech-Insulation thickness (mm): 100; Pset MEP.Geom-DN1: 100; Pset MEP.Geom-DN2: 100; In IFC exportieren als: ifcflowsegment; NameOverride: Rohrbogen; IfcPresentationLayer: 0-TFT-H_Ruecklauf; ObjectTypeOverride: Rohrbogen; Pset MEP.Name: Rohrbogen; IfcDescription: Rohrbogen; Pset MEP.Tech-Material: nach DIN 2605; Pset MEP.Geom-Outer Ø1 (mm): 114.3; Pset MEP.Geom-Outer Ø2 (mm): 114.3
Phasen - Phase erstellt: Phase 01

# IfcFlowSegment: Rohrbogen 292641:Rohrbogen 292641, Rohrbogen
In: Erdgeschoss
Type - Material: IfcSurfaceStyle #9317
Type - Andere - Kategorie: Allgemeines Modell; Familienname: Rohrbogen 292641
Type - ID-Daten - Typname: Rohrbogen 292641
Type - IFC-Parameter - Typ in IFC-Datei exportieren: Vorgabe
Description: Rohrbogen
Pset_DistributionFlowElementCommon - Reference: Rohrbogen 292641; sets with these values: 2
Andere - Typ: Rohrbogen 292641; Familie: Rohrbogen 292641; Familie und Typ: Rohrbogen 292641: Rohrbogen 292641; Typ-ID: 2534340
Abhängigkeiten - Höhe von Ebene: 0 m; Verschieben mit umliegenden Elementen: no
IFC-Parameter - In IFC-Datei exportieren: Nach Typ; Pset MEP.Tech-Insulation thickness (mm): 100; Pset MEP.Geom-DN1: 100; Pset MEP.Geom-DN2: 100; In IFC exportieren als: ifcflowsegment; NameOverride: Rohrbogen; IfcPresentationLayer: 0-TFT-H_Vorlauf; ObjectTypeOverride: Rohrbogen; Pset MEP.Name: Rohrbogen; IfcDescription: Rohrbogen; Pset MEP.Tech-Material: nach DIN 2605; Pset MEP.Geom-Outer Ø1 (mm): 114.3; Pset MEP.Geom-Outer Ø2 (mm): 114.3
Phasen - Phase erstellt: Phase 01

# IfcFlowSegment: Rohrbogen 292945:Rohrbogen 292945, Rohrbogen
In: Erdgeschoss
Type - Material: IfcSurfaceStyle #9317
Type - Andere - Kategorie: Allgemeines Modell; Familienname: Rohrbogen 292945
Type - ID-Daten - Typname: Rohrbogen 292945
Type - IFC-Parameter - Typ in IFC-Datei exportieren: Vorgabe
Description: Rohrbogen
Pset_DistributionFlowElementCommon - Reference: Rohrbogen 292945; sets with these values: 2
Andere - Typ: Rohrbogen 292945; Familie: Rohrbogen 292945; Familie und Typ: Rohrbogen 292945: Rohrbogen 292945; Typ-ID: 2534354
Abhängigkeiten - Höhe von Ebene: 0 m; Verschieben mit umliegenden Elementen: no
IFC-Parameter - In IFC-Datei exportieren: Nach Typ; Pset MEP.Tech-Insulation thickness (mm): 100; Pset MEP.Geom-DN1: 100; Pset MEP.Geom-DN2: 100; In IFC exportieren als: ifcflowsegment; NameOverride: Rohrbogen; IfcPresentationLayer: 0-TFT-H_Vorlauf; ObjectTypeOverride: Rohrbogen; Pset MEP.Name: Rohrbogen; IfcDescription: Rohrbogen; Pset MEP.Tech-Material: nach DIN 2605; Pset MEP.Geom-Outer Ø1 (mm): 114.3; Pset MEP.Geom-Outer Ø2 (mm): 114.3
Phasen - Phase erstellt: Phase 01

# IfcFlowSegment: Rohrbogen 292968:Rohrbogen 292968, Rohrbogen
In: Erdgeschoss
Type - Material: IfcSurfaceStyle #9317
Type - Andere - Kategorie: Allgemeines Modell; Familienname: Rohrbogen 292968
Type - ID-Daten - Typname: Rohrbogen 292968
Type - IFC-Parameter - Typ in IFC-Datei exportieren: Vorgabe
Description: Rohrbogen
Pset_DistributionFlowElementCommon - Reference: Rohrbogen 292968; sets with these values: 2
Andere - Typ: Rohrbogen 292968; Familie: Rohrbogen 292968; Familie und Typ: Rohrbogen 292968: Rohrbogen 292968; Typ-ID: 2534361
Abhängigkeiten - Höhe von Ebene: 0 m; Verschieben mit umliegenden Elementen: no
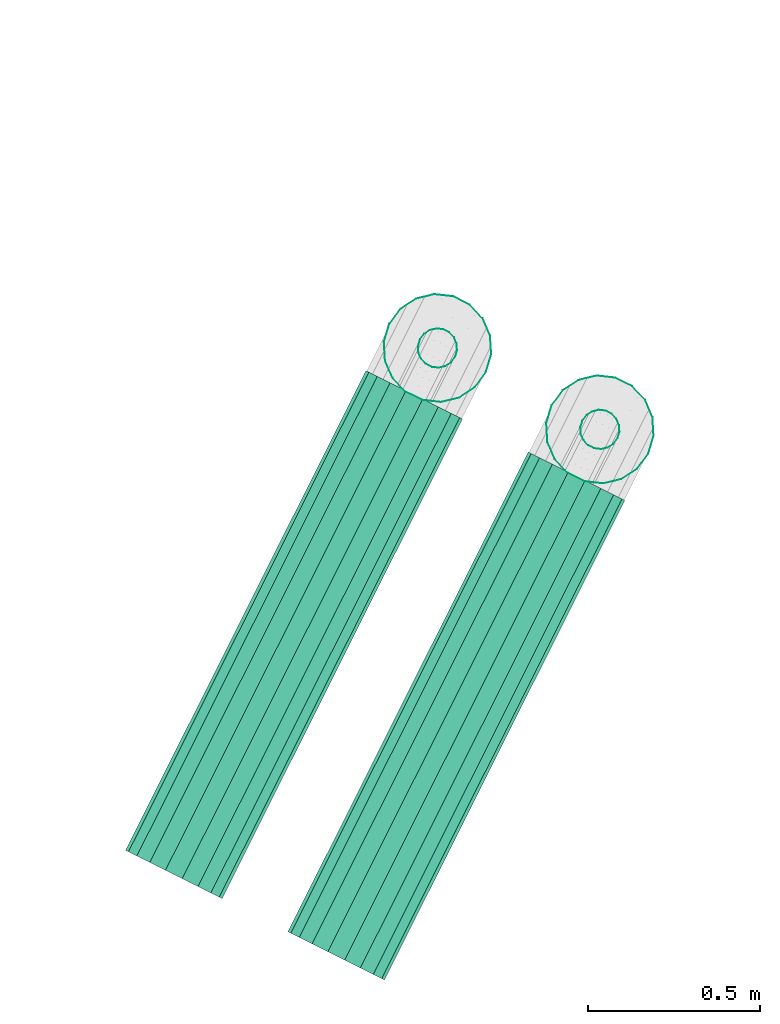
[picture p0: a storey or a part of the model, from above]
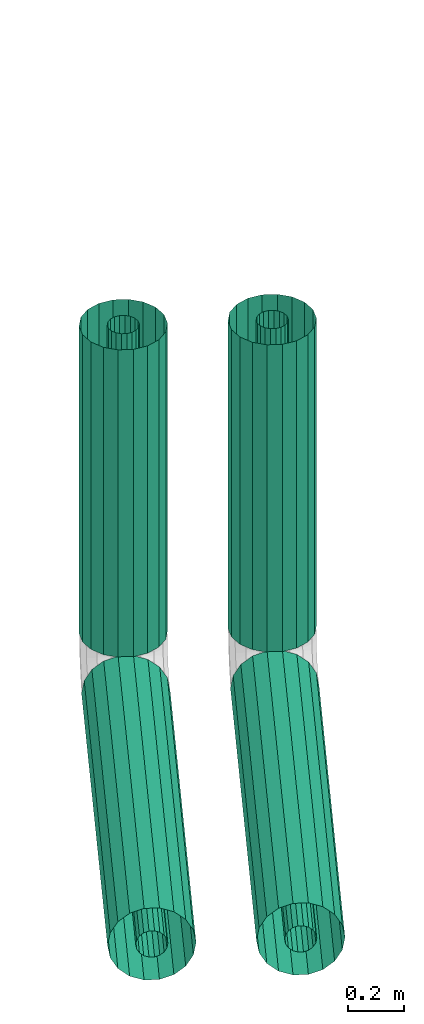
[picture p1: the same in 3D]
Properties of the parts of a building model (IFC2X3), part 15 of 23

# IfcFlowSegment: Rohrbogen 292968:Rohrbogen 292968, Rohrbogen
IFC-Parameter - In IFC-Datei exportieren: Nach Typ; Pset MEP.Tech-Insulation thickness (mm): 100; Pset MEP.Geom-DN1: 100; Pset MEP.Geom-DN2: 100; In IFC exportieren als: ifcflowsegment; NameOverride: Rohrbogen; IfcPresentationLayer: 0-TFT-H_Vorlauf; ObjectTypeOverride: Rohrbogen; Pset MEP.Name: Rohrbogen; IfcDescription: Rohrbogen; Pset MEP.Tech-Material: nach DIN 2605; Pset MEP.Geom-Outer Ø1 (mm): 114.3; Pset MEP.Geom-Outer Ø2 (mm): 114.3
Phasen - Phase erstellt: Phase 01

# IfcFlowSegment: Rohrbogen 293576:Rohrbogen 293576, Rohrbogen
In: 1. Untergeschoss
Type - Material: IfcSurfaceStyle #9317
Type - Andere - Kategorie: Allgemeines Modell; Familienname: Rohrbogen 293576
Type - ID-Daten - Typname: Rohrbogen 293576
Type - IFC-Parameter - Typ in IFC-Datei exportieren: Vorgabe
Description: Rohrbogen
Pset_DistributionFlowElementCommon - Reference: Rohrbogen 293576; sets with these values: 2
Andere - Typ: Rohrbogen 293576; Familie: Rohrbogen 293576; Familie und Typ: Rohrbogen 293576: Rohrbogen 293576; Typ-ID: 2534389
Abhängigkeiten - Höhe von Ebene: 0 m; Verschieben mit umliegenden Elementen: no
IFC-Parameter - In IFC-Datei exportieren: Nach Typ; Pset MEP.Tech-Insulation thickness (mm): 100; Pset MEP.Geom-DN1: 100; Pset MEP.Geom-DN2: 100; In IFC exportieren als: ifcflowsegment; NameOverride: Rohrbogen; IfcPresentationLayer: 0-TFT-H_Vorlauf; ObjectTypeOverride: Rohrbogen; Pset MEP.Name: Rohrbogen; IfcDescription: Rohrbogen; Pset MEP.Tech-Material: nach DIN 2605; Pset MEP.Geom-Outer Ø1 (mm): 114.3; Pset MEP.Geom-Outer Ø2 (mm): 114.3
Phasen - Phase erstellt: Phase 01

# IfcFlowSegment: Rohrbogen 303678:Rohrbogen 303678, Rohrbogen
In: Erdgeschoss
Type - Material: IfcSurfaceStyle #9317
Type - Andere - Kategorie: Allgemeines Modell; Familienname: Rohrbogen 303678
Type - ID-Daten - Typname: Rohrbogen 303678
Type - IFC-Parameter - Typ in IFC-Datei exportieren: Vorgabe
Description: Rohrbogen
Pset_DistributionFlowElementCommon - Reference: Rohrbogen 303678; sets with these values: 2
Andere - Typ: Rohrbogen 303678; Familie: Rohrbogen 303678; Familie und Typ: Rohrbogen 303678: Rohrbogen 303678; Typ-ID: 2534846
Abhängigkeiten - Höhe von Ebene: 0 m; Verschieben mit umliegenden Elementen: no
IFC-Parameter - In IFC-Datei exportieren: Nach Typ; Pset MEP.Tech-Insulation thickness (mm): 100; Pset MEP.Geom-DN1: 100; Pset MEP.Geom-DN2: 100; In IFC exportieren als: ifcflowsegment; NameOverride: Rohrbogen; IfcPresentationLayer: 0-TFT-H_Vorlauf; ObjectTypeOverride: Rohrbogen; Pset MEP.Name: Rohrbogen; IfcDescription: Rohrbogen; Pset MEP.Tech-Material: nach DIN 2605; Pset MEP.Geom-Outer Ø1 (mm): 114.3; Pset MEP.Geom-Outer Ø2 (mm): 114.3
Phasen - Phase erstellt: Phase 01

# IfcFlowSegment: Rohrbogen 304005:Rohrbogen 304005, Rohrbogen
In: Erdgeschoss
Type - Material: IfcSurfaceStyle #9317
Type - Andere - Kategorie: Allgemeines Modell; Familienname: Rohrbogen 304005
Type - ID-Daten - Typname: Rohrbogen 304005
Type - IFC-Parameter - Typ in IFC-Datei exportieren: Vorgabe
Description: Rohrbogen
Pset_DistributionFlowElementCommon - Reference: Rohrbogen 304005; sets with these values: 2
Andere - Typ: Rohrbogen 304005; Familie: Rohrbogen 304005; Familie und Typ: Rohrbogen 304005: Rohrbogen 304005; Typ-ID: 2534867
Abhängigkeiten - Höhe von Ebene: 0 m; Verschieben mit umliegenden Elementen: no
Bemaßungen - Fläche: 0.47296 m2; Volumen: 0.0544204 m3
IFC-Parameter - In IFC-Datei exportieren: Nach Typ; Pset MEP.Tech-Insulation thickness (mm): 100; Pset MEP.Geom-DN1: 200; Pset MEP.Geom-DN2: 200; In IFC exportieren als: ifcflowsegment; NameOverride: Rohrbogen; IfcPresentationLayer: 0-TFT-H_Vorlauf; ObjectTypeOverride: Rohrbogen; Pset MEP.Name: Rohrbogen; IfcDescription: Rohrbogen; Pset MEP.Tech-Material: nach DIN 2605; Pset MEP.Geom-Outer Ø1 (mm): 219.1; Pset MEP.Geom-Outer Ø2 (mm): 219.1
Phasen - Phase erstellt: Phase 01

# IfcFlowSegment: Rohrbogen 304590:Rohrbogen 304590, Rohrbogen
In: Erdgeschoss
Type - Material: IfcSurfaceStyle #1741
Type - Andere - Kategorie: Allgemeines Modell; Familienname: Rohrbogen 304590
Type - ID-Daten - Typname: Rohrbogen 304590
Type - IFC-Parameter - Typ in IFC-Datei exportieren: Vorgabe
Description: Rohrbogen
Pset_DistributionFlowElementCommon - Reference: Rohrbogen 304590; sets with these values: 2
Andere - Typ: Rohrbogen 304590; Familie: Rohrbogen 304590; Familie und Typ: Rohrbogen 304590: Rohrbogen 304590; Typ-ID: 2534888
Abhängigkeiten - Höhe von Ebene: 0 m; Verschieben mit umliegenden Elementen: no
IFC-Parameter - In IFC-Datei exportieren: Nach Typ; Pset MEP.Tech-Insulation thickness (mm): 100; Pset MEP.Geom-DN1: 100; Pset MEP.Geom-DN2: 100; In IFC exportieren als: ifcflowsegment; NameOverride: Rohrbogen; IfcPresentationLayer: 0-TFT-H_Ruecklauf; ObjectTypeOverride: Rohrbogen; Pset MEP.Name: Rohrbogen; IfcDescription: Rohrbogen; Pset MEP.Tech-Material: nach DIN 2605; Pset MEP.Geom-Outer Ø1 (mm): 114.3; Pset MEP.Geom-Outer Ø2 (mm): 114.3
Phasen - Phase erstellt: Phase 01

# IfcFlowSegment: Rohrbogen 304636:Rohrbogen 304636, Rohrbogen
In: Erdgeschoss
Type - Material: IfcSurfaceStyle #1741
Type - Andere - Kategorie: Allgemeines Modell; Familienname: Rohrbogen 304636
Type - ID-Daten - Typname: Rohrbogen 304636
Type - IFC-Parameter - Typ in IFC-Datei exportieren: Vorgabe
Description: Rohrbogen
Pset_DistributionFlowElementCommon - Reference: Rohrbogen 304636; sets with these values: 2
Andere - Typ: Rohrbogen 304636; Familie: Rohrbogen 304636; Familie und Typ: Rohrbogen 304636: Rohrbogen 304636; Typ-ID: 2534902
Abhängigkeiten - Höhe von Ebene: 0 m; Verschieben mit umliegenden Elementen: no
Bemaßungen - Fläche: 0.47296 m2; Volumen: 0.0544204 m3
IFC-Parameter - In IFC-Datei exportieren: Nach Typ; Pset MEP.Tech-Insulation thickness (mm): 100; Pset MEP.Geom-DN1: 200; Pset MEP.Geom-DN2: 200; In IFC exportieren als: ifcflowsegment; NameOverride: Rohrbogen; IfcPresentationLayer: 0-TFT-H_Ruecklauf; ObjectTypeOverride: Rohrbogen; Pset MEP.Name: Rohrbogen; IfcDescription: Rohrbogen; Pset MEP.Tech-Material: nach DIN 2605; Pset MEP.Geom-Outer Ø1 (mm): 219.1; Pset MEP.Geom-Outer Ø2 (mm): 219.1
Phasen - Phase erstellt: Phase 01

# IfcFlowSegment: Rohrbogen 305384:Rohrbogen 305384, Rohrbogen
In: Erdgeschoss
Type - Material: IfcSurfaceStyle #1741
Type - Andere - Kategorie: Allgemeines Modell; Familienname: Rohrbogen 305384
Type - ID-Daten - Typname: Rohrbogen 305384
Type - IFC-Parameter - Typ in IFC-Datei exportieren: Vorgabe
Description: Rohrbogen
Pset_DistributionFlowElementCommon - Reference: Rohrbogen 305384; sets with these values: 2
Andere - Typ: Rohrbogen 305384; Familie: Rohrbogen 305384; Familie und Typ: Rohrbogen 305384: Rohrbogen 305384; Typ-ID: 2534972
Abhängigkeiten - Höhe von Ebene: 0 m; Verschieben mit umliegenden Elementen: no
Bemaßungen - Fläche: 0.0936456 m2; Volumen: 0.00515968 m3
IFC-Parameter - In IFC-Datei exportieren: Nach Typ; Pset MEP.Tech-Insulation thickness (mm): 100; Pset MEP.Geom-DN1: 150; Pset MEP.Geom-DN2: 150; In IFC exportieren als: ifcflowsegment; NameOverride: Rohrbogen; IfcPresentationLayer: 0-TFT-H_Ruecklauf; ObjectTypeOverride: Rohrbogen; Pset MEP.Name: Rohrbogen; IfcDescription: Rohrbogen; Pset MEP.Tech-Material: nach DIN 2605; Pset MEP.Geom-Outer Ø1 (mm): 168.3; Pset MEP.Geom-Outer Ø2 (mm): 168.3
Phasen - Phase erstellt: Phase 01

# IfcFlowSegment: Rohrbogen 309482:Rohrbogen 309482, Rohrbogen
In: Erdgeschoss
Type - Material: IfcSurfaceStyle #1741
Type - Andere - Kategorie: Allgemeines Modell; Familienname: Rohrbogen 309482
Type - ID-Daten - Typname: Rohrbogen 309482
Type - IFC-Parameter - Typ in IFC-Datei exportieren: Vorgabe
Description: Rohrbogen
Pset_DistributionFlowElementCommon - Reference: Rohrbogen 309482; sets with these values: 2
Andere - Typ: Rohrbogen 309482; Familie: Rohrbogen 309482; Familie und Typ: Rohrbogen 309482: Rohrbogen 309482; Typ-ID: 2535070
Abhängigkeiten - Höhe von Ebene: 0 m; Verschieben mit umliegenden Elementen: no
Bemaßungen - Fläche: 0.0936456 m2; Volumen: 0.00515968 m3
IFC-Parameter - In IFC-Datei exportieren: Nach Typ; Pset MEP.Tech-Insulation thickness (mm): 100; Pset MEP.Geom-DN1: 150; Pset MEP.Geom-DN2: 150; In IFC exportieren als: ifcflowsegment; NameOverride: Rohrbogen; IfcPresentationLayer: 0-TFT-H_Ruecklauf; ObjectTypeOverride: Rohrbogen; Pset MEP.Name: Rohrbogen; IfcDescription: Rohrbogen; Pset MEP.Tech-Material: nach DIN 2605; Pset MEP.Geom-Outer Ø1 (mm): 168.3; Pset MEP.Geom-Outer Ø2 (mm): 168.3
Phasen - Phase erstellt: Phase 01

# IfcFlowSegment: Rohrbogen 311557:Rohrbogen 311557, Rohrbogen
In: Erdgeschoss
Type - Material: IfcSurfaceStyle #1741
Type - Andere - Kategorie: Allgemeines Modell; Familienname: Rohrbogen 311557
Type - ID-Daten - Typname: Rohrbogen 311557
Type - IFC-Parameter - Typ in IFC-Datei exportieren: Vorgabe
Description: Rohrbogen
Pset_DistributionFlowElementCommon - Reference: Rohrbogen 311557; sets with these values: 2
Andere - Typ: Rohrbogen 311557; Familie: Rohrbogen 311557; Familie und Typ: Rohrbogen 311557: Rohrbogen 311557; Typ-ID: 2535112
Abhängigkeiten - Höhe von Ebene: 0 m; Verschieben mit umliegenden Elementen: no
Bemaßungen - Fläche: 0.0644938 m2; Volumen: 0.00294944 m3
IFC-Parameter - In IFC-Datei exportieren: Nach Typ; Pset MEP.Tech-Insulation thickness (mm): 100; Pset MEP.Geom-DN1: 125; Pset MEP.Geom-DN2: 125; In IFC exportieren als: ifcflowsegment; NameOverride: Rohrbogen; IfcPresentationLayer: 0-TFT-H_Ruecklauf; ObjectTypeOverride: Rohrbogen; Pset MEP.Name: Rohrbogen; IfcDescription: Rohrbogen; Pset MEP.Tech-Material: nach DIN 2605; Pset MEP.Geom-Outer Ø1 (mm): 139.7; Pset MEP.Geom-Outer Ø2 (mm): 139.7
Phasen - Phase erstellt: Phase 01

# IfcFlowSegment: Rohrbogen 316868:Rohrbogen 316868, Rohrbogen
In: Erdgeschoss
Type - Material: IfcSurfaceStyle #9317
Type - Andere - Kategorie: Allgemeines Modell; Familienname: Rohrbogen 316868
Type - ID-Daten - Typname: Rohrbogen 316868
Type - IFC-Parameter - Typ in IFC-Datei exportieren: Vorgabe
Description: Rohrbogen
Pset_DistributionFlowElementCommon - Reference: Rohrbogen 316868; sets with these values: 2
Andere - Typ: Rohrbogen 316868; Familie: Rohrbogen 316868; Familie und Typ: Rohrbogen 316868: Rohrbogen 316868; Typ-ID: 2535222
Abhängigkeiten - Höhe von Ebene: 0 m; Verschieben mit umliegenden Elementen: no
Bemaßungen - Fläche: 0.0936456 m2; Volumen: 0.00515968 m3
IFC-Parameter - In IFC-Datei exportieren: Nach Typ; Pset MEP.Tech-Insulation thickness (mm): 100; Pset MEP.Geom-DN1: 150; Pset MEP.Geom-DN2: 150; In IFC exportieren als: ifcflowsegment; NameOverride: Rohrbogen; IfcPresentationLayer: 0-TFT-H_Vorlauf; ObjectTypeOverride: Rohrbogen; Pset MEP.Name: Rohrbogen; IfcDescription: Rohrbogen; Pset MEP.Tech-Material: nach DIN 2605; Pset MEP.Geom-Outer Ø1 (mm): 168.3; Pset MEP.Geom-Outer Ø2 (mm): 168.3
Phasen - Phase erstellt: Phase 01

# IfcFlowSegment: Rohrbogen 317460:Rohrbogen 317460, Rohrbogen
In: Erdgeschoss
Type - Material: IfcSurfaceStyle #9317
Type - Andere - Kategorie: Allgemeines Modell; Familienname: Rohrbogen 317460
Type - ID-Daten - Typname: Rohrbogen 317460
Type - IFC-Parameter - Typ in IFC-Datei exportieren: Vorgabe
Description: Rohrbogen
Pset_DistributionFlowElementCommon - Reference: Rohrbogen 317460; sets with these values: 2
Andere - Typ: Rohrbogen 317460; Familie: Rohrbogen 317460; Familie und Typ: Rohrbogen 317460: Rohrbogen 317460; Typ-ID: 2535271
Abhängigkeiten - Höhe von Ebene: 0 m; Verschieben mit umliegenden Elementen: no
Bemaßungen - Fläche: 0.298575 m2; Volumen: 0.0298688 m3
IFC-Parameter - In IFC-Datei exportieren: Nach Typ; Pset MEP.Tech-Insulation thickness (mm): 100; Pset MEP.Geom-DN1: 150; Pset MEP.Geom-DN2: 150; In IFC exportieren als: ifcflowsegment; NameOverride: Rohrbogen; IfcPresentationLayer: 0-TFT-H_Vorlauf; ObjectTypeOverride: Rohrbogen; Pset MEP.Name: Rohrbogen; IfcDescription: Rohrbogen; Pset MEP.Tech-Material: nach DIN 2605; Pset MEP.Geom-Outer Ø1 (mm): 168.3; Pset MEP.Geom-Outer Ø2 (mm): 168.3
Phasen - Phase erstellt: Phase 01

# IfcFlowSegment: Rohrbogen 317698:Rohrbogen 317698, Rohrbogen
In: Erdgeschoss
Type - Material: IfcSurfaceStyle #1741
Type - Andere - Kategorie: Allgemeines Modell; Familienname: Rohrbogen 317698
Type - ID-Daten - Typname: Rohrbogen 317698
Type - IFC-Parameter - Typ in IFC-Datei exportieren: Vorgabe
Description: Rohrbogen
Pset_DistributionFlowElementCommon - Reference: Rohrbogen 317698; sets with these values: 2
Andere - Typ: Rohrbogen 317698; Familie: Rohrbogen 317698; Familie und Typ: Rohrbogen 317698: Rohrbogen 317698; Typ-ID: 2535306
Abhängigkeiten - Höhe von Ebene: 0 m; Verschieben mit umliegenden Elementen: no
Bemaßungen - Fläche: 0.298575 m2; Volumen: 0.0298688 m3
IFC-Parameter - In IFC-Datei exportieren: Nach Typ; Pset MEP.Tech-Insulation thickness (mm): 100; Pset MEP.Geom-DN1: 150; Pset MEP.Geom-DN2: 150; In IFC exportieren als: ifcflowsegment; NameOverride: Rohrbogen; IfcPresentationLayer: 0-TFT-H_Ruecklauf; ObjectTypeOverride: Rohrbogen; Pset MEP.Name: Rohrbogen; IfcDescription: Rohrbogen; Pset MEP.Tech-Material: nach DIN 2605; Pset MEP.Geom-Outer Ø1 (mm): 168.3; Pset MEP.Geom-Outer Ø2 (mm): 168.3
Phasen - Phase erstellt: Phase 01

# IfcFlowSegment: Rohrbogen 319046:Rohrbogen 319046, Rohrbogen
In: Erdgeschoss
Type - Material: IfcSurfaceStyle #1741
Type - Andere - Kategorie: Allgemeines Modell; Familienname: Rohrbogen 319046
Type - ID-Daten - Typname: Rohrbogen 319046
Type - IFC-Parameter - Typ in IFC-Datei exportieren: Vorgabe
Description: Rohrbogen
Pset_DistributionFlowElementCommon - Reference: Rohrbogen 319046; sets with these values: 2
Andere - Typ: Rohrbogen 319046; Familie: Rohrbogen 319046; Familie und Typ: Rohrbogen 319046: Rohrbogen 319046; Typ-ID: 2535404
Abhängigkeiten - Höhe von Ebene: 0 m; Verschieben mit umliegenden Elementen: no
Bemaßungen - Fläche: 0.298575 m2; Volumen: 0.0298688 m3
IFC-Parameter - In IFC-Datei exportieren: Nach Typ; Pset MEP.Tech-Insulation thickness (mm): 100; Pset MEP.Geom-DN1: 150; Pset MEP.Geom-DN2: 150; In IFC exportieren als: ifcflowsegment; NameOverride: Rohrbogen; IfcPresentationLayer: 0-TFT-H_Ruecklauf; ObjectTypeOverride: Rohrbogen; Pset MEP.Name: Rohrbogen; IfcDescription: Rohrbogen; Pset MEP.Tech-Material: nach DIN 2605; Pset MEP.Geom-Outer Ø1 (mm): 168.3; Pset MEP.Geom-Outer Ø2 (mm): 168.3
Phasen - Phase erstellt: Phase 01

# IfcFlowSegment: Rohrbogen 319884:Rohrbogen 319884, Rohrbogen
In: Erdgeschoss
Type - Material: IfcSurfaceStyle #1741
Type - Andere - Kategorie: Allgemeines Modell; Familienname: Rohrbogen 319884
Type - ID-Daten - Typname: Rohrbogen 319884
Type - IFC-Parameter - Typ in IFC-Datei exportieren: Vorgabe
Description: Rohrbogen
Pset_DistributionFlowElementCommon - Reference: Rohrbogen 319884; sets with these values: 2
Andere - Typ: Rohrbogen 319884; Familie: Rohrbogen 319884; Familie und Typ: Rohrbogen 319884: Rohrbogen 319884; Typ-ID: 2535446
Abhängigkeiten - Höhe von Ebene: 0 m; Verschieben mit umliegenden Elementen: no
Bemaßungen - Fläche: 0.221319 m2; Volumen: 0.0203891 m3
IFC-Parameter - In IFC-Datei exportieren: Nach Typ; Pset MEP.Tech-Insulation thickness (mm): 100; Pset MEP.Geom-DN1: 125; Pset MEP.Geom-DN2: 125; In IFC exportieren als: ifcflowsegment; NameOverride: Rohrbogen; IfcPresentationLayer: 0-TFT-H_Ruecklauf; ObjectTypeOverride: Rohrbogen; Pset MEP.Name: Rohrbogen; IfcDescription: Rohrbogen; Pset MEP.Tech-Material: nach DIN 2605; Pset MEP.Geom-Outer Ø1 (mm): 139.7; Pset MEP.Geom-Outer Ø2 (mm): 139.7
Phasen - Phase erstellt: Phase 01

# IfcFlowSegment: Rohrbogen 320952:Rohrbogen 320952, Rohrbogen
In: 1. Obergeschoss
Type - Material: IfcSurfaceStyle #1741
Type - Andere - Kategorie: Allgemeines Modell; Familienname: Rohrbogen 320952
Type - ID-Daten - Typname: Rohrbogen 320952
Type - IFC-Parameter - Typ in IFC-Datei exportieren: Vorgabe
Description: Rohrbogen
Pset_DistributionFlowElementCommon - Reference: Rohrbogen 320952; sets with these values: 2
Andere - Typ: Rohrbogen 320952; Familie: Rohrbogen 320952; Familie und Typ: Rohrbogen 320952: Rohrbogen 320952; Typ-ID: 2535558
Abhängigkeiten - Höhe von Ebene: 0 m; Verschieben mit umliegenden Elementen: no
Bemaßungen - Fläche: 0.0936456 m2; Volumen: 0.00515968 m3
IFC-Parameter - In IFC-Datei exportieren: Nach Typ; Pset MEP.Tech-Insulation thickness (mm): 100; Pset MEP.Geom-DN1: 150; Pset MEP.Geom-DN2: 150; In IFC exportieren als: ifcflowsegment; NameOverride: Rohrbogen; IfcPresentationLayer: 0-TFT-H_Ruecklauf; ObjectTypeOverride: Rohrbogen; Pset MEP.Name: Rohrbogen; IfcDescription: Rohrbogen; Pset MEP.Tech-Material: nach DIN 2605; Pset MEP.Geom-Outer Ø1 (mm): 168.3; Pset MEP.Geom-Outer Ø2 (mm): 168.3
Phasen - Phase erstellt: Phase 01

# IfcFlowSegment: Rohrbogen 327528:Rohrbogen 327528, Rohrbogen
In: Erdgeschoss
Type - Material: IfcSurfaceStyle #9317
Type - Andere - Kategorie: Allgemeines Modell; Familienname: Rohrbogen 327528
Type - ID-Daten - Typname: Rohrbogen 327528
Type - IFC-Parameter - Typ in IFC-Datei exportieren: Vorgabe
Description: Rohrbogen
Pset_DistributionFlowElementCommon - Reference: Rohrbogen 327528; sets with these values: 2
Andere - Typ: Rohrbogen 327528; Familie: Rohrbogen 327528; Familie und Typ: Rohrbogen 327528: Rohrbogen 327528; Typ-ID: 2535663
Abhängigkeiten - Höhe von Ebene: 0 m; Verschieben mit umliegenden Elementen: no
IFC-Parameter - In IFC-Datei exportieren: Nach Typ; Pset MEP.Tech-Insulation thickness (mm): 100; Pset MEP.Geom-DN2: 80; Pset MEP.Geom-DN1: 80; In IFC exportieren als: ifcflowsegment; NameOverride: Rohrbogen; IfcPresentationLayer: 0-TFT-H_Vorlauf; ObjectTypeOverride: Rohrbogen; Pset MEP.Name: Rohrbogen; IfcDescription: Rohrbogen; Pset MEP.Tech-Material: nach DIN 2605; Pset MEP.Geom-Outer Ø1 (mm): 88.9; Pset MEP.Geom-Outer Ø2 (mm): 88.9
Phasen - Phase erstellt: Phase 01

# IfcFlowSegment: Rohrbogen 329222:Rohrbogen 329222, Rohrbogen
In: Erdgeschoss
Type - Material: IfcSurfaceStyle #1741
Type - Andere - Kategorie: Allgemeines Modell; Familienname: Rohrbogen 329222
Type - ID-Daten - Typname: Rohrbogen 329222
Type - IFC-Parameter - Typ in IFC-Datei exportieren: Vorgabe
Description: Rohrbogen
Pset_DistributionFlowElementCommon - Reference: Rohrbogen 329222; sets with these values: 2
Andere - Typ: Rohrbogen 329222; Familie: Rohrbogen 329222; Familie und Typ: Rohrbogen 329222: Rohrbogen 329222; Typ-ID: 2535691
Abhängigkeiten - Höhe von Ebene: 0 m; Verschieben mit umliegenden Elementen: no
IFC-Parameter - In IFC-Datei exportieren: Nach Typ; Pset MEP.Tech-Insulation thickness (mm): 100; Pset MEP.Geom-DN2: 80; Pset MEP.Geom-DN1: 80; In IFC exportieren als: ifcflowsegment; NameOverride: Rohrbogen; IfcPresentationLayer: 0-TFT-H_Ruecklauf; ObjectTypeOverride: Rohrbogen; Pset MEP.Name: Rohrbogen; IfcDescription: Rohrbogen; Pset MEP.Tech-Material: nach DIN 2605; Pset MEP.Geom-Outer Ø1 (mm): 88.9; Pset MEP.Geom-Outer Ø2 (mm): 88.9
Phasen - Phase erstellt: Phase 01

# IfcFlowSegment: Rohrbogen 329245:Rohrbogen 329245, Rohrbogen
In: Erdgeschoss
Type - Material: IfcSurfaceStyle #1741
Type - Andere - Kategorie: Allgemeines Modell; Familienname: Rohrbogen 329245
Type - ID-Daten - Typname: Rohrbogen 329245
Type - IFC-Parameter - Typ in IFC-Datei exportieren: Vorgabe
Description: Rohrbogen
Pset_DistributionFlowElementCommon - Reference: Rohrbogen 329245; sets with these values: 2
Andere - Typ: Rohrbogen 329245; Familie: Rohrbogen 329245; Familie und Typ: Rohrbogen 329245: Rohrbogen 329245; Typ-ID: 2535698
Abhängigkeiten - Höhe von Ebene: 0 m; Verschieben mit umliegenden Elementen: no
IFC-Parameter - In IFC-Datei exportieren: Nach Typ; Pset MEP.Tech-Insulation thickness (mm): 100; Pset MEP.Geom-DN2: 80; Pset MEP.Geom-DN1: 80; In IFC exportieren als: ifcflowsegment; NameOverride: Rohrbogen; IfcPresentationLayer: 0-TFT-H_Ruecklauf; ObjectTypeOverride: Rohrbogen; Pset MEP.Name: Rohrbogen; IfcDescription: Rohrbogen; Pset MEP.Tech-Material: nach DIN 2605; Pset MEP.Geom-Outer Ø1 (mm): 88.9; Pset MEP.Geom-Outer Ø2 (mm): 88.9
Phasen - Phase erstellt: Phase 01

# IfcFlowSegment: Rohrbogen 331481:Rohrbogen 331481, Rohrbogen
In: Erdgeschoss
Type - Material: IfcSurfaceStyle #9317
Type - Andere - Kategorie: Allgemeines Modell; Familienname: Rohrbogen 331481
Type - ID-Daten - Typname: Rohrbogen 331481
Type - IFC-Parameter - Typ in IFC-Datei exportieren: Vorgabe
Description: Rohrbogen
Pset_DistributionFlowElementCommon - Reference: Rohrbogen 331481; sets with these values: 2
Andere - Typ: Rohrbogen 331481; Familie: Rohrbogen 331481; Familie und Typ: Rohrbogen 331481: Rohrbogen 331481; Typ-ID: 2535761
Abhängigkeiten - Höhe von Ebene: 0 m; Verschieben mit umliegenden Elementen: no
IFC-Parameter - In IFC-Datei exportieren: Nach Typ; Pset MEP.Tech-Insulation thickness (mm): 100; Pset MEP.Geom-DN2: 80; Pset MEP.Geom-DN1: 80; In IFC exportieren als: ifcflowsegment; NameOverride: Rohrbogen; IfcPresentationLayer: 0-TFT-H_Vorlauf; ObjectTypeOverride: Rohrbogen; Pset MEP.Name: Rohrbogen; IfcDescription: Rohrbogen; Pset MEP.Tech-Material: nach DIN 2605; Pset MEP.Geom-Outer Ø1 (mm): 88.9; Pset MEP.Geom-Outer Ø2 (mm): 88.9
Phasen - Phase erstellt: Phase 01

# IfcFlowSegment: Rohrbogen 340584:Rohrbogen 340584, Rohrbogen
In: Erdgeschoss
Type - Material: IfcSurfaceStyle #9317
Type - Andere - Kategorie: Allgemeines Modell; Familienname: Rohrbogen 340584
Type - ID-Daten - Typname: Rohrbogen 340584
Type - IFC-Parameter - Typ in IFC-Datei exportieren: Vorgabe
Description: Rohrbogen
Pset_DistributionFlowElementCommon - Reference: Rohrbogen 340584; sets with these values: 2
Andere - Typ: Rohrbogen 340584; Familie: Rohrbogen 340584; Familie und Typ: Rohrbogen 340584: Rohrbogen 340584; Typ-ID: 2535873
Abhängigkeiten - Höhe von Ebene: 0 m; Verschieben mit umliegenden Elementen: no
Bemaßungen - Fläche: 0.298575 m2; Volumen: 0.0298688 m3
IFC-Parameter - In IFC-Datei exportieren: Nach Typ; Pset MEP.Tech-Insulation thickness (mm): 100; Pset MEP.Geom-DN1: 150; Pset MEP.Geom-DN2: 150; In IFC exportieren als: ifcflowsegment; NameOverride: Rohrbogen; IfcPresentationLayer: 0-TFT-H_Vorlauf; ObjectTypeOverride: Rohrbogen; Pset MEP.Name: Rohrbogen; IfcDescription: Rohrbogen; Pset MEP.Tech-Material: nach DIN 2605; Pset MEP.Geom-Outer Ø1 (mm): 168.3; Pset MEP.Geom-Outer Ø2 (mm): 168.3
Phasen - Phase erstellt: Phase 01

# IfcFlowSegment: Rohrbogen 340696:Rohrbogen 340696, Rohrbogen
In: Erdgeschoss
Type - Material: IfcSurfaceStyle #1741
Type - Andere - Kategorie: Allgemeines Modell; Familienname: Rohrbogen 340696
Type - ID-Daten - Typname: Rohrbogen 340696
Type - IFC-Parameter - Typ in IFC-Datei exportieren: Vorgabe
Description: Rohrbogen
Pset_DistributionFlowElementCommon - Reference: Rohrbogen 340696; sets with these values: 2
Andere - Typ: Rohrbogen 340696; Familie: Rohrbogen 340696; Familie und Typ: Rohrbogen 340696: Rohrbogen 340696; Typ-ID: 2535908
Abhängigkeiten - Höhe von Ebene: 0 m; Verschieben mit umliegenden Elementen: no
Bemaßungen - Fläche: 0.298575 m2; Volumen: 0.0298688 m3
IFC-Parameter - In IFC-Datei exportieren: Nach Typ; Pset MEP.Tech-Insulation thickness (mm): 100; Pset MEP.Geom-DN1: 150; Pset MEP.Geom-DN2: 150; In IFC exportieren als: ifcflowsegment; NameOverride: Rohrbogen; IfcPresentationLayer: 0-TFT-H_Ruecklauf; ObjectTypeOverride: Rohrbogen; Pset MEP.Name: Rohrbogen; IfcDescription: Rohrbogen; Pset MEP.Tech-Material: nach DIN 2605; Pset MEP.Geom-Outer Ø1 (mm): 168.3; Pset MEP.Geom-Outer Ø2 (mm): 168.3
Phasen - Phase erstellt: Phase 01

# IfcFlowSegment: Rohrbogen 340972:Rohrbogen 340972, Rohrbogen
In: Erdgeschoss
Type - Material: IfcSurfaceStyle #1741
Type - Andere - Kategorie: Allgemeines Modell; Familienname: Rohrbogen 340972
Type - ID-Daten - Typname: Rohrbogen 340972
Type - IFC-Parameter - Typ in IFC-Datei exportieren: Vorgabe
Description: Rohrbogen
Pset_DistributionFlowElementCommon - Reference: Rohrbogen 340972; sets with these values: 2
Andere - Typ: Rohrbogen 340972; Familie: Rohrbogen 340972; Familie und Typ: Rohrbogen 340972: Rohrbogen 340972; Typ-ID: 2535992
Abhängigkeiten - Höhe von Ebene: 0 m; Verschieben mit umliegenden Elementen: no
Bemaßungen - Fläche: 0.221319 m2; Volumen: 0.0203891 m3
IFC-Parameter - In IFC-Datei exportieren: Nach Typ; Pset MEP.Tech-Insulation thickness (mm): 100; Pset MEP.Geom-DN1: 125; Pset MEP.Geom-DN2: 125; In IFC exportieren als: ifcflowsegment; NameOverride: Rohrbogen; IfcPresentationLayer: 0-TFT-H_Ruecklauf; ObjectTypeOverride: Rohrbogen; Pset MEP.Name: Rohrbogen; IfcDescription: Rohrbogen; Pset MEP.Tech-Material: nach DIN 2605; Pset MEP.Geom-Outer Ø1 (mm): 139.7; Pset MEP.Geom-Outer Ø2 (mm): 139.7
Phasen - Phase erstellt: Phase 01

# IfcFlowSegment: Rohrbogen 341243:Rohrbogen 341243, Rohrbogen
In: Erdgeschoss
Type - Material: IfcSurfaceStyle #9317
Type - Andere - Kategorie: Allgemeines Modell; Familienname: Rohrbogen 341243
Type - ID-Daten - Typname: Rohrbogen 341243
Type - IFC-Parameter - Typ in IFC-Datei exportieren: Vorgabe
Description: Rohrbogen
Pset_DistributionFlowElementCommon - Reference: Rohrbogen 341243; sets with these values: 2
Andere - Typ: Rohrbogen 341243; Familie: Rohrbogen 341243; Familie und Typ: Rohrbogen 341243: Rohrbogen 341243; Typ-ID: 2536069
Abhängigkeiten - Höhe von Ebene: 0 m; Verschieben mit umliegenden Elementen: no
Bemaßungen - Fläche: 0.0465528 m2; Volumen: 0.00215826 m3
IFC-Parameter - In IFC-Datei exportieren: Nach Typ; Pset MEP.Tech-Insulation thickness (mm): 100; Pset MEP.Geom-DN1: 150; Pset MEP.Geom-DN2: 150; In IFC exportieren als: ifcflowsegment; NameOverride: Rohrbogen; IfcPresentationLayer: 0-TFT-H_Vorlauf; ObjectTypeOverride: Rohrbogen; Pset MEP.Name: Rohrbogen; IfcDescription: Rohrbogen; Pset MEP.Tech-Material: nach DIN 2605; Pset MEP.Geom-Outer Ø1 (mm): 168.3; Pset MEP.Geom-Outer Ø2 (mm): 168.3
Phasen - Phase erstellt: Phase 01

# IfcFlowSegment: Rohrbogen 341558:Rohrbogen 341558, Rohrbogen
In: Erdgeschoss
Type - Material: IfcSurfaceStyle #9317
Type - Andere - Kategorie: Allgemeines Modell; Familienname: Rohrbogen 341558
Type - ID-Daten - Typname: Rohrbogen 341558
Type - IFC-Parameter - Typ in IFC-Datei exportieren: Vorgabe
Description: Rohrbogen
Pset_DistributionFlowElementCommon - Reference: Rohrbogen 341558; sets with these values: 2
Andere - Typ: Rohrbogen 341558; Familie: Rohrbogen 341558; Familie und Typ: Rohrbogen 341558: Rohrbogen 341558; Typ-ID: 2536076
Abhängigkeiten - Höhe von Ebene: 0 m; Verschieben mit umliegenden Elementen: no
Bemaßungen - Fläche: 0.0465528 m2; Volumen: 0.00215826 m3
IFC-Parameter - In IFC-Datei exportieren: Nach Typ; Pset MEP.Tech-Insulation thickness (mm): 100; Pset MEP.Geom-DN1: 150; Pset MEP.Geom-DN2: 150; In IFC exportieren als: ifcflowsegment; NameOverride: Rohrbogen; IfcPresentationLayer: 0-TFT-H_Vorlauf; ObjectTypeOverride: Rohrbogen; Pset MEP.Name: Rohrbogen; IfcDescription: Rohrbogen; Pset MEP.Tech-Material: nach DIN 2605; Pset MEP.Geom-Outer Ø1 (mm): 168.3; Pset MEP.Geom-Outer Ø2 (mm): 168.3
Phasen - Phase erstellt: Phase 01

# IfcFlowSegment: Rohrbogen 341748:Rohrbogen 341748, Rohrbogen
In: Erdgeschoss
Type - Material: IfcSurfaceStyle #9317
Type - Andere - Kategorie: Allgemeines Modell; Familienname: Rohrbogen 341748
Type - ID-Daten - Typname: Rohrbogen 341748
Type - IFC-Parameter - Typ in IFC-Datei exportieren: Vorgabe
Description: Rohrbogen
Pset_DistributionFlowElementCommon - Reference: Rohrbogen 341748; sets with these values: 2
Andere - Typ: Rohrbogen 341748; Familie: Rohrbogen 341748; Familie und Typ: Rohrbogen 341748: Rohrbogen 341748; Typ-ID: 2536090
Abhängigkeiten - Höhe von Ebene: 0 m; Verschieben mit umliegenden Elementen: no
Bemaßungen - Fläche: 0.148427 m2; Volumen: 0.0124939 m3
IFC-Parameter - In IFC-Datei exportieren: Nach Typ; Pset MEP.Tech-Insulation thickness (mm): 100; Pset MEP.Geom-DN1: 150; Pset MEP.Geom-DN2: 150; In IFC exportieren als: ifcflowsegment; NameOverride: Rohrbogen; IfcPresentationLayer: 0-TFT-H_Vorlauf; ObjectTypeOverride: Rohrbogen; Pset MEP.Name: Rohrbogen; IfcDescription: Rohrbogen; Pset MEP.Tech-Material: nach DIN 2605; Pset MEP.Geom-Outer Ø1 (mm): 168.3; Pset MEP.Geom-Outer Ø2 (mm): 168.3
Phasen - Phase erstellt: Phase 01

# IfcFlowSegment: Rohrbogen 342059:Rohrbogen 342059, Rohrbogen
In: Erdgeschoss
Type - Material: IfcSurfaceStyle #9317
Type - Andere - Kategorie: Allgemeines Modell; Familienname: Rohrbogen 342059
Type - ID-Daten - Typname: Rohrbogen 342059
Type - IFC-Parameter - Typ in IFC-Datei exportieren: Vorgabe
Description: Rohrbogen
Pset_DistributionFlowElementCommon - Reference: Rohrbogen 342059; sets with these values: 2
Andere - Typ: Rohrbogen 342059; Familie: Rohrbogen 342059; Familie und Typ: Rohrbogen 342059: Rohrbogen 342059; Typ-ID: 2536097
Abhängigkeiten - Höhe von Ebene: 0 m; Verschieben mit umliegenden Elementen: no
Bemaßungen - Fläche: 0.148427 m2; Volumen: 0.0124939 m3
IFC-Parameter - In IFC-Datei exportieren: Nach Typ; Pset MEP.Tech-Insulation thickness (mm): 100; Pset MEP.Geom-DN1: 150; Pset MEP.Geom-DN2: 150; In IFC exportieren als: ifcflowsegment; NameOverride: Rohrbogen; IfcPresentationLayer: 0-TFT-H_Vorlauf; ObjectTypeOverride: Rohrbogen; Pset MEP.Name: Rohrbogen; IfcDescription: Rohrbogen; Pset MEP.Tech-Material: nach DIN 2605; Pset MEP.Geom-Outer Ø1 (mm): 168.3; Pset MEP.Geom-Outer Ø2 (mm): 168.3
Phasen - Phase erstellt: Phase 01

# IfcFlowSegment: Rohrbogen 342231:Rohrbogen 342231, Rohrbogen
In: Erdgeschoss
Type - Material: IfcSurfaceStyle #9317
Type - Andere - Kategorie: Allgemeines Modell; Familienname: Rohrbogen 342231
Type - ID-Daten - Typname: Rohrbogen 342231
Type - IFC-Parameter - Typ in IFC-Datei exportieren: Vorgabe
Description: Rohrbogen
Pset_DistributionFlowElementCommon - Reference: Rohrbogen 342231; sets with these values: 2
Andere - Typ: Rohrbogen 342231; Familie: Rohrbogen 342231; Familie und Typ: Rohrbogen 342231: Rohrbogen 342231; Typ-ID: 2536111
Abhängigkeiten - Höhe von Ebene: 0 m; Verschieben mit umliegenden Elementen: no
Bemaßungen - Fläche: 0.148427 m2; Volumen: 0.0124939 m3
IFC-Parameter - In IFC-Datei exportieren: Nach Typ; Pset MEP.Tech-Insulation thickness (mm): 100; Pset MEP.Geom-DN1: 150; Pset MEP.Geom-DN2: 150; In IFC exportieren als: ifcflowsegment; NameOverride: Rohrbogen; IfcPresentationLayer: 0-TFT-H_Vorlauf; ObjectTypeOverride: Rohrbogen; Pset MEP.Name: Rohrbogen; IfcDescription: Rohrbogen; Pset MEP.Tech-Material: nach DIN 2605; Pset MEP.Geom-Outer Ø1 (mm): 168.3; Pset MEP.Geom-Outer Ø2 (mm): 168.3
Phasen - Phase erstellt: Phase 01

# IfcFlowSegment: Rohrbogen 342254:Rohrbogen 342254, Rohrbogen
In: Erdgeschoss
Type - Material: IfcSurfaceStyle #9317
Type - Andere - Kategorie: Allgemeines Modell; Familienname: Rohrbogen 342254
Type - ID-Daten - Typname: Rohrbogen 342254
Type - IFC-Parameter - Typ in IFC-Datei exportieren: Vorgabe
Description: Rohrbogen
Pset_DistributionFlowElementCommon - Reference: Rohrbogen 342254; sets with these values: 2
Andere - Typ: Rohrbogen 342254; Familie: Rohrbogen 342254; Familie und Typ: Rohrbogen 342254: Rohrbogen 342254; Typ-ID: 2536118
Abhängigkeiten - Höhe von Ebene: 0 m; Verschieben mit umliegenden Elementen: no
Bemaßungen - Fläche: 0.148427 m2; Volumen: 0.0124939 m3
IFC-Parameter - In IFC-Datei exportieren: Nach Typ; Pset MEP.Tech-Insulation thickness (mm): 100; Pset MEP.Geom-DN1: 150; Pset MEP.Geom-DN2: 150; In IFC exportieren als: ifcflowsegment; NameOverride: Rohrbogen; IfcPresentationLayer: 0-TFT-H_Vorlauf; ObjectTypeOverride: Rohrbogen; Pset MEP.Name: Rohrbogen; IfcDescription: Rohrbogen; Pset MEP.Tech-Material: nach DIN 2605; Pset MEP.Geom-Outer Ø1 (mm): 168.3; Pset MEP.Geom-Outer Ø2 (mm): 168.3
Phasen - Phase erstellt: Phase 01

# IfcFlowSegment: Rohrbogen 342300:Rohrbogen 342300, Rohrbogen
In: Erdgeschoss
Type - Material: IfcSurfaceStyle #9317
Type - Andere - Kategorie: Allgemeines Modell; Familienname: Rohrbogen 342300
Type - ID-Daten - Typname: Rohrbogen 342300
Type - IFC-Parameter - Typ in IFC-Datei exportieren: Vorgabe
Description: Rohrbogen
Pset_DistributionFlowElementCommon - Reference: Rohrbogen 342300; sets with these values: 2
Andere - Typ: Rohrbogen 342300; Familie: Rohrbogen 342300; Familie und Typ: Rohrbogen 342300: Rohrbogen 342300; Typ-ID: 2536132
Abhängigkeiten - Höhe von Ebene: 0 m; Verschieben mit umliegenden Elementen: no
Bemaßungen - Fläche: 0.47296 m2; Volumen: 0.0544204 m3
IFC-Parameter - In IFC-Datei exportieren: Nach Typ; Pset MEP.Tech-Insulation thickness (mm): 100; Pset MEP.Geom-DN1: 200; Pset MEP.Geom-DN2: 200; In IFC exportieren als: ifcflowsegment; NameOverride: Rohrbogen; IfcPresentationLayer: 0-TFT-H_Vorlauf; ObjectTypeOverride: Rohrbogen; Pset MEP.Name: Rohrbogen; IfcDescription: Rohrbogen; Pset MEP.Tech-Material: nach DIN 2605; Pset MEP.Geom-Outer Ø1 (mm): 219.1; Pset MEP.Geom-Outer Ø2 (mm): 219.1
Phasen - Phase erstellt: Phase 01

# IfcFlowSegment: Rohrbogen 342323:Rohrbogen 342323, Rohrbogen
In: Erdgeschoss
Type - Material: IfcSurfaceStyle #9317
Type - Andere - Kategorie: Allgemeines Modell; Familienname: Rohrbogen 342323
Type - ID-Daten - Typname: Rohrbogen 342323
Type - IFC-Parameter - Typ in IFC-Datei exportieren: Vorgabe
Description: Rohrbogen
Pset_DistributionFlowElementCommon - Reference: Rohrbogen 342323; sets with these values: 2
Andere - Typ: Rohrbogen 342323; Familie: Rohrbogen 342323; Familie und Typ: Rohrbogen 342323: Rohrbogen 342323; Typ-ID: 2536139
Abhängigkeiten - Höhe von Ebene: 0 m; Verschieben mit umliegenden Elementen: no
Bemaßungen - Fläche: 0.47296 m2; Volumen: 0.0544204 m3
IFC-Parameter - In IFC-Datei exportieren: Nach Typ; Pset MEP.Tech-Insulation thickness (mm): 100; Pset MEP.Geom-DN1: 200; Pset MEP.Geom-DN2: 200; In IFC exportieren als: ifcflowsegment; NameOverride: Rohrbogen; IfcPresentationLayer: 0-TFT-H_Vorlauf; ObjectTypeOverride: Rohrbogen; Pset MEP.Name: Rohrbogen; IfcDescription: Rohrbogen; Pset MEP.Tech-Material: nach DIN 2605; Pset MEP.Geom-Outer Ø1 (mm): 219.1; Pset MEP.Geom-Outer Ø2 (mm): 219.1
Phasen - Phase erstellt: Phase 01

# IfcFlowSegment: Rohrbogen 342627:Rohrbogen 342627, Rohrbogen
In: Erdgeschoss
Type - Material: IfcSurfaceStyle #9317
Type - Andere - Kategorie: Allgemeines Modell; Familienname: Rohrbogen 342627
Type - ID-Daten - Typname: Rohrbogen 342627
Type - IFC-Parameter - Typ in IFC-Datei exportieren: Vorgabe
Description: Rohrbogen
Pset_DistributionFlowElementCommon - Reference: Rohrbogen 342627; sets with these values: 2
Andere - Typ: Rohrbogen 342627; Familie: Rohrbogen 342627; Familie und Typ: Rohrbogen 342627: Rohrbogen 342627; Typ-ID: 2536153
Abhängigkeiten - Höhe von Ebene: 0 m; Verschieben mit umliegenden Elementen: no
Bemaßungen - Fläche: 0.47296 m2; Volumen: 0.0544204 m3
IFC-Parameter - In IFC-Datei exportieren: Nach Typ; Pset MEP.Tech-Insulation thickness (mm): 100; Pset MEP.Geom-DN1: 200; Pset MEP.Geom-DN2: 200; In IFC exportieren als: ifcflowsegment; NameOverride: Rohrbogen; IfcPresentationLayer: 0-TFT-H_Vorlauf; ObjectTypeOverride: Rohrbogen; Pset MEP.Name: Rohrbogen; IfcDescription: Rohrbogen; Pset MEP.Tech-Material: nach DIN 2605; Pset MEP.Geom-Outer Ø1 (mm): 219.1; Pset MEP.Geom-Outer Ø2 (mm): 219.1
Phasen - Phase erstellt: Phase 01

# IfcFlowSegment: Rohrbogen 342983:Rohrbogen 342983, Rohrbogen
In: Erdgeschoss
Type - Material: IfcSurfaceStyle #9317
Type - Andere - Kategorie: Allgemeines Modell; Familienname: Rohrbogen 342983
Type - ID-Daten - Typname: Rohrbogen 342983
Type - IFC-Parameter - Typ in IFC-Datei exportieren: Vorgabe
Description: Rohrbogen
Pset_DistributionFlowElementCommon - Reference: Rohrbogen 342983; sets with these values: 2
Andere - Typ: Rohrbogen 342983; Familie: Rohrbogen 342983; Familie und Typ: Rohrbogen 342983: Rohrbogen 342983; Typ-ID: 2536181
Abhängigkeiten - Höhe von Ebene: 0 m; Verschieben mit umliegenden Elementen: no
Bemaßungen - Fläche: 0.0936456 m2; Volumen: 0.00515968 m3
IFC-Parameter - In IFC-Datei exportieren: Nach Typ; Pset MEP.Tech-Insulation thickness (mm): 100; Pset MEP.Geom-DN1: 150; Pset MEP.Geom-DN2: 150; In IFC exportieren als: ifcflowsegment; NameOverride: Rohrbogen; IfcPresentationLayer: 0-TFT-H_Vorlauf; ObjectTypeOverride: Rohrbogen; Pset MEP.Name: Rohrbogen; IfcDescription: Rohrbogen; Pset MEP.Tech-Material: nach DIN 2605; Pset MEP.Geom-Outer Ø1 (mm): 168.3; Pset MEP.Geom-Outer Ø2 (mm): 168.3
Phasen - Phase erstellt: Phase 01

# IfcFlowSegment: Rohrbogen 344670:Rohrbogen 344670, Rohrbogen
In: Erdgeschoss
Type - Material: IfcSurfaceStyle #9317
Type - Andere - Kategorie: Allgemeines Modell; Familienname: Rohrbogen 344670
Type - ID-Daten - Typname: Rohrbogen 344670
Type - IFC-Parameter - Typ in IFC-Datei exportieren: Vorgabe
Description: Rohrbogen
Pset_DistributionFlowElementCommon - Reference: Rohrbogen 344670; sets with these values: 2
Andere - Typ: Rohrbogen 344670; Familie: Rohrbogen 344670; Familie und Typ: Rohrbogen 344670: Rohrbogen 344670; Typ-ID: 2536300
Abhängigkeiten - Höhe von Ebene: 0 m; Verschieben mit umliegenden Elementen: no
IFC-Parameter - In IFC-Datei exportieren: Nach Typ; Pset MEP.Tech-Insulation thickness (mm): 100; Pset MEP.Geom-DN2: 80; Pset MEP.Geom-DN1: 80; In IFC exportieren als: ifcflowsegment; NameOverride: Rohrbogen; IfcPresentationLayer: 0-TFT-H_Vorlauf; ObjectTypeOverride: Rohrbogen; Pset MEP.Name: Rohrbogen; IfcDescription: Rohrbogen; Pset MEP.Tech-Material: nach DIN 2605; Pset MEP.Geom-Outer Ø1 (mm): 88.9; Pset MEP.Geom-Outer Ø2 (mm): 88.9
Phasen - Phase erstellt: Phase 01

# IfcFlowSegment: Rohrbogen 345626:Rohrbogen 345626, Rohrbogen
In: Erdgeschoss
Type - Material: IfcSurfaceStyle #9317
Type - Andere - Kategorie: Allgemeines Modell; Familienname: Rohrbogen 345626
Type - ID-Daten - Typname: Rohrbogen 345626
Type - IFC-Parameter - Typ in IFC-Datei exportieren: Vorgabe
Description: Rohrbogen
Pset_DistributionFlowElementCommon - Reference: Rohrbogen 345626; sets with these values: 2
Andere - Typ: Rohrbogen 345626; Familie: Rohrbogen 345626; Familie und Typ: Rohrbogen 345626: Rohrbogen 345626; Typ-ID: 2536335
Abhängigkeiten - Höhe von Ebene: 0 m; Verschieben mit umliegenden Elementen: no
IFC-Parameter - In IFC-Datei exportieren: Nach Typ; Pset MEP.Tech-Insulation thickness (mm): 100; Pset MEP.Geom-DN2: 80; Pset MEP.Geom-DN1: 80; In IFC exportieren als: ifcflowsegment; NameOverride: Rohrbogen; IfcPresentationLayer: 0-TFT-H_Vorlauf; ObjectTypeOverride: Rohrbogen; Pset MEP.Name: Rohrbogen; IfcDescription: Rohrbogen; Pset MEP.Tech-Material: nach DIN 2605; Pset MEP.Geom-Outer Ø1 (mm): 88.9; Pset MEP.Geom-Outer Ø2 (mm): 88.9
Phasen - Phase erstellt: Phase 01

# IfcFlowSegment: Rohrbogen 347131:Rohrbogen 347131, Rohrbogen
In: 1. Obergeschoss
Type - Material: IfcSurfaceStyle #9317
Type - Andere - Kategorie: Allgemeines Modell; Familienname: Rohrbogen 347131
Type - ID-Daten - Typname: Rohrbogen 347131
Type - IFC-Parameter - Typ in IFC-Datei exportieren: Vorgabe
Description: Rohrbogen
Pset_DistributionFlowElementCommon - Reference: Rohrbogen 347131; sets with these values: 2
Andere - Typ: Rohrbogen 347131; Familie: Rohrbogen 347131; Familie und Typ: Rohrbogen 347131: Rohrbogen 347131; Typ-ID: 2536377
Abhängigkeiten - Höhe von Ebene: 0 m; Verschieben mit umliegenden Elementen: no
Bemaßungen - Fläche: 0.47296 m2; Volumen: 0.0544204 m3
IFC-Parameter - In IFC-Datei exportieren: Nach Typ; Pset MEP.Tech-Insulation thickness (mm): 100; Pset MEP.Geom-DN1: 200; Pset MEP.Geom-DN2: 200; In IFC exportieren als: ifcflowsegment; NameOverride: Rohrbogen; IfcPresentationLayer: 0-TFT-H_Vorlauf; ObjectTypeOverride: Rohrbogen; Pset MEP.Name: Rohrbogen; IfcDescription: Rohrbogen; Pset MEP.Tech-Material: nach DIN 2605; Pset MEP.Geom-Outer Ø1 (mm): 219.1; Pset MEP.Geom-Outer Ø2 (mm): 219.1
Phasen - Phase erstellt: Phase 01

# IfcFlowSegment: Rohrbogen 347619:Rohrbogen 347619, Rohrbogen
In: Erdgeschoss
Type - Material: IfcSurfaceStyle #1741
Type - Andere - Kategorie: Allgemeines Modell; Familienname: Rohrbogen 347619
Type - ID-Daten - Typname: Rohrbogen 347619
Type - IFC-Parameter - Typ in IFC-Datei exportieren: Vorgabe
Description: Rohrbogen
Pset_DistributionFlowElementCommon - Reference: Rohrbogen 347619; sets with these values: 2
Andere - Typ: Rohrbogen 347619; Familie: Rohrbogen 347619; Familie und Typ: Rohrbogen 347619: Rohrbogen 347619; Typ-ID: 2536405
Abhängigkeiten - Höhe von Ebene: 0 m; Verschieben mit umliegenden Elementen: no
IFC-Parameter - In IFC-Datei exportieren: Nach Typ; Pset MEP.Tech-Insulation thickness (mm): 100; Pset MEP.Geom-DN1: 65; Pset MEP.Geom-DN2: 65; In IFC exportieren als: ifcflowsegment; NameOverride: Rohrbogen; IfcPresentationLayer: 0-TFT-H_Ruecklauf; ObjectTypeOverride: Rohrbogen; Pset MEP.Name: Rohrbogen; IfcDescription: Rohrbogen; Pset MEP.Tech-Material: nach DIN 2605; Pset MEP.Geom-Outer Ø1 (mm): 76.1; Pset MEP.Geom-Outer Ø2 (mm): 76.1
Phasen - Phase erstellt: Phase 01

# IfcFlowSegment: Rohrbogen 347946:Rohrbogen 347946, Rohrbogen
In: Erdgeschoss
Type - Material: IfcSurfaceStyle #1741
Type - Andere - Kategorie: Allgemeines Modell; Familienname: Rohrbogen 347946
Type - ID-Daten - Typname: Rohrbogen 347946
Type - IFC-Parameter - Typ in IFC-Datei exportieren: Vorgabe
Description: Rohrbogen
Pset_DistributionFlowElementCommon - Reference: Rohrbogen 347946; sets with these values: 2
Andere - Typ: Rohrbogen 347946; Familie: Rohrbogen 347946; Familie und Typ: Rohrbogen 347946: Rohrbogen 347946; Typ-ID: 2536426
Abhängigkeiten - Höhe von Ebene: 0 m; Verschieben mit umliegenden Elementen: no
IFC-Parameter - In IFC-Datei exportieren: Nach Typ; Pset MEP.Tech-Insulation thickness (mm): 100; Pset MEP.Geom-DN2: 80; Pset MEP.Geom-DN1: 80; In IFC exportieren als: ifcflowsegment; NameOverride: Rohrbogen; IfcPresentationLayer: 0-TFT-H_Ruecklauf; ObjectTypeOverride: Rohrbogen; Pset MEP.Name: Rohrbogen; IfcDescription: Rohrbogen; Pset MEP.Tech-Material: nach DIN 2605; Pset MEP.Geom-Outer Ø1 (mm): 88.9; Pset MEP.Geom-Outer Ø2 (mm): 88.9
Phasen - Phase erstellt: Phase 01

# IfcFlowSegment: Rohrbogen 349566:Rohrbogen 349566, Rohrbogen
In: 1. Obergeschoss
Type - Material: IfcSurfaceStyle #1741
Type - Andere - Kategorie: Allgemeines Modell; Familienname: Rohrbogen 349566
Type - ID-Daten - Typname: Rohrbogen 349566
Type - IFC-Parameter - Typ in IFC-Datei exportieren: Vorgabe
Description: Rohrbogen
Pset_DistributionFlowElementCommon - Reference: Rohrbogen 349566; sets with these values: 2
Andere - Typ: Rohrbogen 349566; Familie: Rohrbogen 349566; Familie und Typ: Rohrbogen 349566: Rohrbogen 349566; Typ-ID: 2536461
Abhängigkeiten - Höhe von Ebene: 0 m; Verschieben mit umliegenden Elementen: no
Bemaßungen - Fläche: 0.47296 m2; Volumen: 0.0544204 m3
IFC-Parameter - In IFC-Datei exportieren: Nach Typ; Pset MEP.Tech-Insulation thickness (mm): 100; Pset MEP.Geom-DN1: 200; Pset MEP.Geom-DN2: 200; In IFC exportieren als: ifcflowsegment; NameOverride: Rohrbogen; IfcPresentationLayer: 0-TFT-H_Ruecklauf; ObjectTypeOverride: Rohrbogen; Pset MEP.Name: Rohrbogen; IfcDescription: Rohrbogen; Pset MEP.Tech-Material: nach DIN 2605; Pset MEP.Geom-Outer Ø1 (mm): 219.1; Pset MEP.Geom-Outer Ø2 (mm): 219.1
Phasen - Phase erstellt: Phase 01

# IfcFlowSegment: Rohrbogen 350151:Rohrbogen 350151, Rohrbogen
In: Erdgeschoss
Type - Material: IfcSurfaceStyle #1741
Type - Andere - Kategorie: Allgemeines Modell; Familienname: Rohrbogen 350151
Type - ID-Daten - Typname: Rohrbogen 350151
Type - IFC-Parameter - Typ in IFC-Datei exportieren: Vorgabe
Description: Rohrbogen
Pset_DistributionFlowElementCommon - Reference: Rohrbogen 350151; sets with these values: 2
Andere - Typ: Rohrbogen 350151; Familie: Rohrbogen 350151; Familie und Typ: Rohrbogen 350151: Rohrbogen 350151; Typ-ID: 2536482
Abhängigkeiten - Höhe von Ebene: 0 m; Verschieben mit umliegenden Elementen: no
Bemaßungen - Fläche: 0.47296 m2; Volumen: 0.0544204 m3
IFC-Parameter - In IFC-Datei exportieren: Nach Typ; Pset MEP.Tech-Insulation thickness (mm): 100; Pset MEP.Geom-DN1: 200; Pset MEP.Geom-DN2: 200; In IFC exportieren als: ifcflowsegment; NameOverride: Rohrbogen; IfcPresentationLayer: 0-TFT-H_Ruecklauf; ObjectTypeOverride: Rohrbogen; Pset MEP.Name: Rohrbogen; IfcDescription: Rohrbogen; Pset MEP.Tech-Material: nach DIN 2605; Pset MEP.Geom-Outer Ø1 (mm): 219.1; Pset MEP.Geom-Outer Ø2 (mm): 219.1
Phasen - Phase erstellt: Phase 01

# IfcFlowSegment: Rohrbogen 352546:Rohrbogen 352546, Rohrbogen
In: Erdgeschoss
Type - Material: IfcSurfaceStyle #352577
Type - Andere - Kategorie: Allgemeines Modell; Familienname: Rohrbogen 352546
Type - ID-Daten - Typname: Rohrbogen 352546
Type - IFC-Parameter - Typ in IFC-Datei exportieren: Vorgabe
Description: Rohrbogen
Pset_DistributionFlowElementCommon - Reference: Rohrbogen 352546; sets with these values: 2
Andere - Typ: Rohrbogen 352546; Familie: Rohrbogen 352546; Familie und Typ: Rohrbogen 352546: Rohrbogen 352546; Typ-ID: 2536615
Abhängigkeiten - Höhe von Ebene: 0 m; Verschieben mit umliegenden Elementen: no
Bemaßungen - Fläche: 0.0422141 m2; Volumen: 0.00157486 m3
IFC-Parameter - In IFC-Datei exportieren: Nach Typ; Pset MEP.Geom-DN1: 100; Pset MEP.Geom-DN2: 100; In IFC exportieren als: ifcflowsegment; NameOverride: Rohrbogen; IfcPresentationLayer: S_Gas; ObjectTypeOverride: Rohrbogen; Pset MEP.Name: Rohrbogen; IfcDescription: Rohrbogen; Pset MEP.Tech-Material: nach DIN 2605; Pset MEP.Geom-Outer Ø1 (mm): 114.3; Pset MEP.Geom-Outer Ø2 (mm): 114.3
Phasen - Phase erstellt: Phase 01

# IfcFlowSegment: Rohrbogen 352747:Rohrbogen 352747, Rohrbogen
In: Erdgeschoss
Type - Material: IfcSurfaceStyle #352577
Type - Andere - Kategorie: Allgemeines Modell; Familienname: Rohrbogen 352747
Type - ID-Daten - Typname: Rohrbogen 352747
Type - IFC-Parameter - Typ in IFC-Datei exportieren: Vorgabe
Description: Rohrbogen
Pset_DistributionFlowElementCommon - Reference: Rohrbogen 352747; sets with these values: 2
Andere - Typ: Rohrbogen 352747; Familie: Rohrbogen 352747; Familie und Typ: Rohrbogen 352747: Rohrbogen 352747; Typ-ID: 2536632
Abhängigkeiten - Höhe von Ebene: 0 m; Verschieben mit umliegenden Elementen: no
Bemaßungen - Fläche: 0.0422141 m2; Volumen: 0.00157486 m3
IFC-Parameter - In IFC-Datei exportieren: Nach Typ; Pset MEP.Geom-DN1: 100; Pset MEP.Geom-DN2: 100; In IFC exportieren als: ifcflowsegment; NameOverride: Rohrbogen; IfcPresentationLayer: S_Gas; ObjectTypeOverride: Rohrbogen; Pset MEP.Name: Rohrbogen; IfcDescription: Rohrbogen; Pset MEP.Tech-Material: nach DIN 2605; Pset MEP.Geom-Outer Ø1 (mm): 114.3; Pset MEP.Geom-Outer Ø2 (mm): 114.3
Phasen - Phase erstellt: Phase 01

# IfcFlowSegment: Rohrbogen 355778:Rohrbogen 355778, Rohrbogen
In: Erdgeschoss
Type - Material: IfcSurfaceStyle #352577
Type - Andere - Kategorie: Allgemeines Modell; Familienname: Rohrbogen 355778
Type - ID-Daten - Typname: Rohrbogen 355778
Type - IFC-Parameter - Typ in IFC-Datei exportieren: Vorgabe
Description: Rohrbogen
Pset_DistributionFlowElementCommon - Reference: Rohrbogen 355778; sets with these values: 2
Andere - Typ: Rohrbogen 355778; Familie: Rohrbogen 355778; Familie und Typ: Rohrbogen 355778: Rohrbogen 355778; Typ-ID: 2536772
Abhängigkeiten - Höhe von Ebene: 0 m; Verschieben mit umliegenden Elementen: no
Bemaßungen - Fläche: 0.0175661 m2; Volumen: 0.000432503 m3
IFC-Parameter - In IFC-Datei exportieren: Nach Typ; Pset MEP.Geom-DN1: 65; Pset MEP.Geom-DN2: 65; In IFC exportieren als: ifcflowsegment; NameOverride: Rohrbogen; IfcPresentationLayer: S_Gas; ObjectTypeOverride: Rohrbogen; Pset MEP.Name: Rohrbogen; IfcDescription: Rohrbogen; Pset MEP.Tech-Material: nach DIN 2605; Pset MEP.Geom-Outer Ø1 (mm): 76.1; Pset MEP.Geom-Outer Ø2 (mm): 76.1
Phasen - Phase erstellt: Phase 01

# IfcFlowSegment: Rohrbogen 358820:Rohrbogen 358820, Rohrbogen
In: Erdgeschoss
Type - Material: IfcSurfaceStyle #352577
Type - Andere - Kategorie: Allgemeines Modell; Familienname: Rohrbogen 358820
Type - ID-Daten - Typname: Rohrbogen 358820
Type - IFC-Parameter - Typ in IFC-Datei exportieren: Vorgabe
Description: Rohrbogen
Pset_DistributionFlowElementCommon - Reference: Rohrbogen 358820; sets with these values: 2
Andere - Typ: Rohrbogen 358820; Familie: Rohrbogen 358820; Familie und Typ: Rohrbogen 358820: Rohrbogen 358820; Typ-ID: 2536856
Abhängigkeiten - Höhe von Ebene: 0 m; Verschieben mit umliegenden Elementen: no
Bemaßungen - Fläche: 0.0175661 m2; Volumen: 0.000432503 m3
IFC-Parameter - In IFC-Datei exportieren: Nach Typ; Pset MEP.Geom-DN1: 65; Pset MEP.Geom-DN2: 65; In IFC exportieren als: ifcflowsegment; NameOverride: Rohrbogen; IfcPresentationLayer: S_Gas; ObjectTypeOverride: Rohrbogen; Pset MEP.Name: Rohrbogen; IfcDescription: Rohrbogen; Pset MEP.Tech-Material: nach DIN 2605; Pset MEP.Geom-Outer Ø1 (mm): 76.1; Pset MEP.Geom-Outer Ø2 (mm): 76.1
Phasen - Phase erstellt: Phase 01

# IfcFlowSegment: Rohrbogen 359314:Rohrbogen 359314, Rohrbogen
In: Erdgeschoss
Type - Material: IfcSurfaceStyle #352577
Type - Andere - Kategorie: Allgemeines Modell; Familienname: Rohrbogen 359314
Type - ID-Daten - Typname: Rohrbogen 359314
Type - IFC-Parameter - Typ in IFC-Datei exportieren: Vorgabe
Description: Rohrbogen
Pset_DistributionFlowElementCommon - Reference: Rohrbogen 359314; sets with these values: 2
Andere - Typ: Rohrbogen 359314; Familie: Rohrbogen 359314; Familie und Typ: Rohrbogen 359314: Rohrbogen 359314; Typ-ID: 2536877
Abhängigkeiten - Höhe von Ebene: 0 m; Verschieben mit umliegenden Elementen: no
Bemaßungen - Fläche: 0.0175661 m2; Volumen: 0.000432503 m3
IFC-Parameter - In IFC-Datei exportieren: Nach Typ; Pset MEP.Geom-DN1: 65; Pset MEP.Geom-DN2: 65; In IFC exportieren als: ifcflowsegment; NameOverride: Rohrbogen; IfcPresentationLayer: S_Gas; ObjectTypeOverride: Rohrbogen; Pset MEP.Name: Rohrbogen; IfcDescription: Rohrbogen; Pset MEP.Tech-Material: nach DIN 2605; Pset MEP.Geom-Outer Ø1 (mm): 76.1; Pset MEP.Geom-Outer Ø2 (mm): 76.1
Phasen - Phase erstellt: Phase 01

# IfcFlowSegment: Rohrbogen 5713:Rohrbogen 5713, Rohrbogen
In: 1. Obergeschoss
Type - Material: IfcSurfaceStyle #1741
Type - Andere - Kategorie: Allgemeines Modell; Familienname: Rohrbogen 5713
Type - ID-Daten - Typname: Rohrbogen 5713
Type - IFC-Parameter - Typ in IFC-Datei exportieren: Vorgabe
Description: Rohrbogen
Pset_DistributionFlowElementCommon - Reference: Rohrbogen 5713; sets with these values: 2
Andere - Typ: Rohrbogen 5713; Familie: Rohrbogen 5713; Familie und Typ: Rohrbogen 5713: Rohrbogen 5713; Typ-ID: 2531415
Abhängigkeiten - Höhe von Ebene: 0 m; Verschieben mit umliegenden Elementen: no
Bemaßungen - Fläche: 0.47296 m2; Volumen: 0.0544204 m3
IFC-Parameter - In IFC-Datei exportieren: Nach Typ; Pset MEP.Tech-Insulation thickness (mm): 100; Pset MEP.Geom-DN1: 200; Pset MEP.Geom-DN2: 200; In IFC exportieren als: ifcflowsegment; NameOverride: Rohrbogen; IfcPresentationLayer: 0-TFT-H_Ruecklauf; ObjectTypeOverride: Rohrbogen; Pset MEP.Name: Rohrbogen; IfcDescription: Rohrbogen; Pset MEP.Tech-Material: nach DIN 2605; Pset MEP.Geom-Outer Ø1 (mm): 219.1; Pset MEP.Geom-Outer Ø2 (mm): 219.1
Phasen - Phase erstellt: Phase 01

# IfcFlowSegment: Rohrbogen 604270:Rohrbogen 604270, Rohrbogen
In: Erdgeschoss
Type - Material: IfcSurfaceStyle #352577
Type - Andere - Kategorie: Allgemeines Modell; Familienname: Rohrbogen 604270
Type - ID-Daten - Typname: Rohrbogen 604270
Type - IFC-Parameter - Typ in IFC-Datei exportieren: Vorgabe
Description: Rohrbogen
Pset_DistributionFlowElementCommon - Reference: Rohrbogen 604270; sets with these values: 2
Andere - Typ: Rohrbogen 604270; Familie: Rohrbogen 604270; Familie und Typ: Rohrbogen 604270: Rohrbogen 604270; Typ-ID: 2537094
Abhängigkeiten - Höhe von Ebene: 0 m; Verschieben mit umliegenden Elementen: no
Bemaßungen - Fläche: 0.0175661 m2; Volumen: 0.000432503 m3
IFC-Parameter - In IFC-Datei exportieren: Nach Typ; Pset MEP.Geom-DN1: 65; Pset MEP.Geom-DN2: 65; In IFC exportieren als: ifcflowsegment; NameOverride: Rohrbogen; IfcPresentationLayer: S_Gas; ObjectTypeOverride: Rohrbogen; Pset MEP.Name: Rohrbogen; IfcDescription: Rohrbogen; Pset MEP.Tech-Material: nach DIN 2605; Pset MEP.Geom-Outer Ø1 (mm): 76.1; Pset MEP.Geom-Outer Ø2 (mm): 76.1
Phasen - Phase erstellt: Phase 01

# IfcFlowSegment: Rohrbogen 604500:Rohrbogen 604500, Rohrbogen
In: Erdgeschoss
Type - Material: IfcSurfaceStyle #352577
Type - Andere - Kategorie: Allgemeines Modell; Familienname: Rohrbogen 604500
Type - ID-Daten - Typname: Rohrbogen 604500
Type - IFC-Parameter - Typ in IFC-Datei exportieren: Vorgabe
Description: Rohrbogen
Pset_DistributionFlowElementCommon - Reference: Rohrbogen 604500; sets with these values: 2
Andere - Typ: Rohrbogen 604500; Familie: Rohrbogen 604500; Familie und Typ: Rohrbogen 604500: Rohrbogen 604500; Typ-ID: 2537164
Abhängigkeiten - Höhe von Ebene: 0 m; Verschieben mit umliegenden Elementen: no
Bemaßungen - Fläche: 0.0175661 m2; Volumen: 0.000432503 m3
IFC-Parameter - In IFC-Datei exportieren: Nach Typ; Pset MEP.Geom-DN1: 65; Pset MEP.Geom-DN2: 65; In IFC exportieren als: ifcflowsegment; NameOverride: Rohrbogen; IfcPresentationLayer: S_Gas; ObjectTypeOverride: Rohrbogen; Pset MEP.Name: Rohrbogen; IfcDescription: Rohrbogen; Pset MEP.Tech-Material: nach DIN 2605; Pset MEP.Geom-Outer Ø1 (mm): 76.1; Pset MEP.Geom-Outer Ø2 (mm): 76.1
Phasen - Phase erstellt: Phase 01

# IfcFlowSegment: Rohrbogen 605026:Rohrbogen 605026, Rohrbogen
In: Erdgeschoss
Type - Material: IfcSurfaceStyle #352577
Type - Andere - Kategorie: Allgemeines Modell; Familienname: Rohrbogen 605026
Type - ID-Daten - Typname: Rohrbogen 605026
Type - IFC-Parameter - Typ in IFC-Datei exportieren: Vorgabe
Description: Rohrbogen
Pset_DistributionFlowElementCommon - Reference: Rohrbogen 605026; sets with these values: 2
Andere - Typ: Rohrbogen 605026; Familie: Rohrbogen 605026; Familie und Typ: Rohrbogen 605026: Rohrbogen 605026; Typ-ID: 2537325
Abhängigkeiten - Höhe von Ebene: 0 m; Verschieben mit umliegenden Elementen: no
Bemaßungen - Fläche: 0.0175661 m2; Volumen: 0.000432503 m3
IFC-Parameter - In IFC-Datei exportieren: Nach Typ; Pset MEP.Geom-DN1: 65; Pset MEP.Geom-DN2: 65; In IFC exportieren als: ifcflowsegment; NameOverride: Rohrbogen; IfcPresentationLayer: S_Gas; ObjectTypeOverride: Rohrbogen; Pset MEP.Name: Rohrbogen; IfcDescription: Rohrbogen; Pset MEP.Tech-Material: nach DIN 2605; Pset MEP.Geom-Outer Ø1 (mm): 76.1; Pset MEP.Geom-Outer Ø2 (mm): 76.1
Phasen - Phase erstellt: Phase 01

# IfcFlowSegment: Rohrbogen 605204:Rohrbogen 605204, Rohrbogen
In: Erdgeschoss
Type - Material: IfcSurfaceStyle #352577
Type - Andere - Kategorie: Allgemeines Modell; Familienname: Rohrbogen 605204
Type - ID-Daten - Typname: Rohrbogen 605204
Type - IFC-Parameter - Typ in IFC-Datei exportieren: Vorgabe
Description: Rohrbogen
Pset_DistributionFlowElementCommon - Reference: Rohrbogen 605204; sets with these values: 2
Andere - Typ: Rohrbogen 605204; Familie: Rohrbogen 605204; Familie und Typ: Rohrbogen 605204: Rohrbogen 605204; Typ-ID: 2537339
Abhängigkeiten - Höhe von Ebene: 0 m; Verschieben mit umliegenden Elementen: no
Bemaßungen - Fläche: 0.0175661 m2; Volumen: 0.000432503 m3
IFC-Parameter - In IFC-Datei exportieren: Nach Typ; Pset MEP.Geom-DN1: 65; Pset MEP.Geom-DN2: 65; In IFC exportieren als: ifcflowsegment; NameOverride: Rohrbogen; IfcPresentationLayer: S_Gas; ObjectTypeOverride: Rohrbogen; Pset MEP.Name: Rohrbogen; IfcDescription: Rohrbogen; Pset MEP.Tech-Material: nach DIN 2605; Pset MEP.Geom-Outer Ø1 (mm): 76.1; Pset MEP.Geom-Outer Ø2 (mm): 76.1
Phasen - Phase erstellt: Phase 01

# IfcFlowSegment: Rohrbogen 611056:Rohrbogen 611056, Rohrbogen
In: Erdgeschoss
Type - Material: IfcSurfaceStyle #352577
Type - Andere - Kategorie: Allgemeines Modell; Familienname: Rohrbogen 611056
Type - ID-Daten - Typname: Rohrbogen 611056
Type - IFC-Parameter - Typ in IFC-Datei exportieren: Vorgabe
Description: Rohrbogen
Pset_DistributionFlowElementCommon - Reference: Rohrbogen 611056; sets with these values: 2
Andere - Typ: Rohrbogen 611056; Familie: Rohrbogen 611056; Familie und Typ: Rohrbogen 611056: Rohrbogen 611056; Typ-ID: 2537521
Abhängigkeiten - Höhe von Ebene: 0 m; Verschieben mit umliegenden Elementen: no
Bemaßungen - Fläche: 0.0049451 m2; Volumen: 0.0000668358 m3
IFC-Parameter - In IFC-Datei exportieren: Nach Typ; Pset MEP.Geom-DN2: 32; In IFC exportieren als: ifcflowsegment; NameOverride: Rohrbogen; IfcPresentationLayer: S_Gas; ObjectTypeOverride: Rohrbogen; Pset MEP.Name: Rohrbogen; IfcDescription: Rohrbogen; Pset MEP.Tech-Material: nach DIN 2605; Pset MEP.Geom-DN1: 32; Pset MEP.Geom-Outer Ø1 (mm): 42.4; Pset MEP.Geom-Outer Ø2 (mm): 42.4
Phasen - Phase erstellt: Phase 01

# IfcFlowSegment: Rohrbogen 611750:Rohrbogen 611750, Rohrbogen
In: Erdgeschoss
Type - Material: IfcSurfaceStyle #352577
Type - Andere - Kategorie: Allgemeines Modell; Familienname: Rohrbogen 611750
Type - ID-Daten - Typname: Rohrbogen 611750
Type - IFC-Parameter - Typ in IFC-Datei exportieren: Vorgabe
Description: Rohrbogen
Pset_DistributionFlowElementCommon - Reference: Rohrbogen 611750; sets with these values: 2
Andere - Typ: Rohrbogen 611750; Familie: Rohrbogen 611750; Familie und Typ: Rohrbogen 611750: Rohrbogen 611750; Typ-ID: 2537528
Abhängigkeiten - Höhe von Ebene: 0 m; Verschieben mit umliegenden Elementen: no
Bemaßungen - Fläche: 0.0049451 m2; Volumen: 0.0000668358 m3
IFC-Parameter - In IFC-Datei exportieren: Nach Typ; Pset MEP.Geom-DN2: 32; Pset MEP.Geom-DN1: 32; In IFC exportieren als: ifcflowsegment; NameOverride: Rohrbogen; IfcPresentationLayer: S_Gas; ObjectTypeOverride: Rohrbogen; Pset MEP.Name: Rohrbogen; IfcDescription: Rohrbogen; Pset MEP.Tech-Material: nach DIN 2605; Pset MEP.Geom-Outer Ø1 (mm): 42.4; Pset MEP.Geom-Outer Ø2 (mm): 42.4
Phasen - Phase erstellt: Phase 01

# IfcFlowSegment: Rohrbogen 611777:Rohrbogen 611777, Rohrbogen
In: Erdgeschoss
Type - Material: IfcSurfaceStyle #352577
Type - Andere - Kategorie: Allgemeines Modell; Familienname: Rohrbogen 611777
Type - ID-Daten - Typname: Rohrbogen 611777
Type - IFC-Parameter - Typ in IFC-Datei exportieren: Vorgabe
Description: Rohrbogen
Pset_DistributionFlowElementCommon - Reference: Rohrbogen 611777; sets with these values: 2
Andere - Typ: Rohrbogen 611777; Familie: Rohrbogen 611777; Familie und Typ: Rohrbogen 611777: Rohrbogen 611777; Typ-ID: 2537535
Abhängigkeiten - Höhe von Ebene: 0 m; Verschieben mit umliegenden Elementen: no
Bemaßungen - Fläche: 0.0049451 m2; Volumen: 0.0000668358 m3
IFC-Parameter - In IFC-Datei exportieren: Nach Typ; Pset MEP.Geom-DN2: 32; Pset MEP.Geom-DN1: 32; In IFC exportieren als: ifcflowsegment; NameOverride: Rohrbogen; IfcPresentationLayer: S_Gas; ObjectTypeOverride: Rohrbogen; Pset MEP.Name: Rohrbogen; IfcDescription: Rohrbogen; Pset MEP.Tech-Material: nach DIN 2605; Pset MEP.Geom-Outer Ø1 (mm): 42.4; Pset MEP.Geom-Outer Ø2 (mm): 42.4
Phasen - Phase erstellt: Phase 01

# IfcFlowSegment: Rohrbogen 611955:Rohrbogen 611955, Rohrbogen
In: Erdgeschoss
Type - Material: IfcSurfaceStyle #352577
Type - Andere - Kategorie: Allgemeines Modell; Familienname: Rohrbogen 611955
Type - ID-Daten - Typname: Rohrbogen 611955
Type - IFC-Parameter - Typ in IFC-Datei exportieren: Vorgabe
Description: Rohrbogen
Pset_DistributionFlowElementCommon - Reference: Rohrbogen 611955; sets with these values: 2
Andere - Typ: Rohrbogen 611955; Familie: Rohrbogen 611955; Familie und Typ: Rohrbogen 611955: Rohrbogen 611955; Typ-ID: 2537549
Abhängigkeiten - Höhe von Ebene: 0 m; Verschieben mit umliegenden Elementen: no
Bemaßungen - Fläche: 0.0049451 m2; Volumen: 0.0000668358 m3
IFC-Parameter - In IFC-Datei exportieren: Nach Typ; Pset MEP.Geom-DN2: 32; Pset MEP.Geom-DN1: 32; In IFC exportieren als: ifcflowsegment; NameOverride: Rohrbogen; IfcPresentationLayer: S_Gas; ObjectTypeOverride: Rohrbogen; Pset MEP.Name: Rohrbogen; IfcDescription: Rohrbogen; Pset MEP.Tech-Material: nach DIN 2605; Pset MEP.Geom-Outer Ø1 (mm): 42.4; Pset MEP.Geom-Outer Ø2 (mm): 42.4
Phasen - Phase erstellt: Phase 01

# IfcFlowSegment: Rohrbogen 612133:Rohrbogen 612133, Rohrbogen
In: Erdgeschoss
Type - Material: IfcSurfaceStyle #352577
Type - Andere - Kategorie: Allgemeines Modell; Familienname: Rohrbogen 612133
Type - ID-Daten - Typname: Rohrbogen 612133
Type - IFC-Parameter - Typ in IFC-Datei exportieren: Vorgabe
Description: Rohrbogen
Pset_DistributionFlowElementCommon - Reference: Rohrbogen 612133; sets with these values: 2
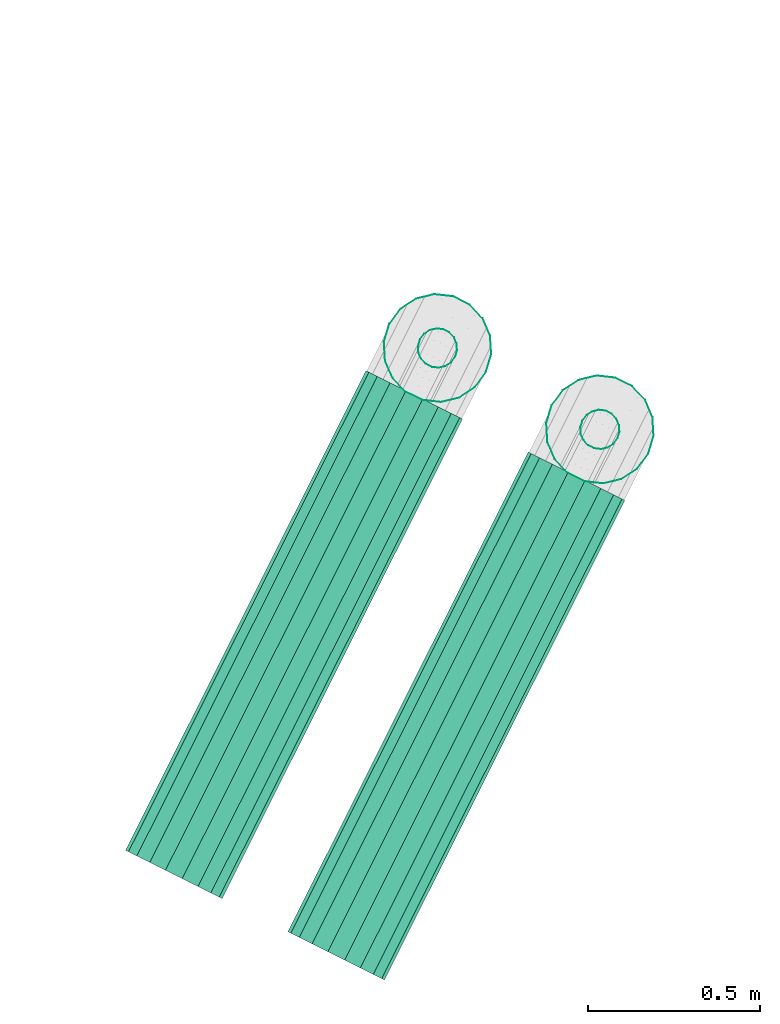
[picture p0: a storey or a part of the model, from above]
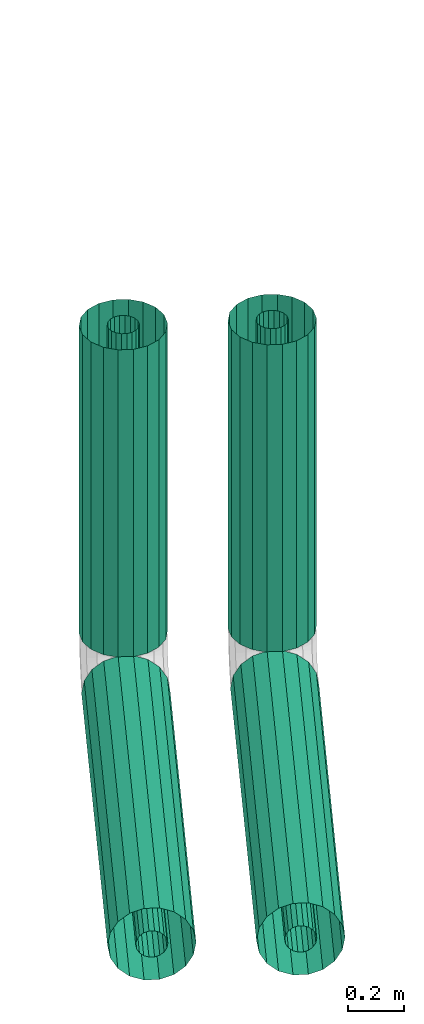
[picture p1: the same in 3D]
Properties of the parts of a building model (IFC2X3), part 16 of 23

# IfcFlowSegment: Rohrbogen 612133:Rohrbogen 612133, Rohrbogen
Andere - Typ: Rohrbogen 612133; Familie: Rohrbogen 612133; Familie und Typ: Rohrbogen 612133: Rohrbogen 612133; Typ-ID: 2537563
Abhängigkeiten - Höhe von Ebene: 0 m; Verschieben mit umliegenden Elementen: no
Bemaßungen - Fläche: 0.0049451 m2; Volumen: 0.0000668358 m3
IFC-Parameter - In IFC-Datei exportieren: Nach Typ; Pset MEP.Geom-DN2: 32; Pset MEP.Geom-DN1: 32; In IFC exportieren als: ifcflowsegment; NameOverride: Rohrbogen; IfcPresentationLayer: S_Gas; ObjectTypeOverride: Rohrbogen; Pset MEP.Name: Rohrbogen; IfcDescription: Rohrbogen; Pset MEP.Tech-Material: nach DIN 2605; Pset MEP.Geom-Outer Ø1 (mm): 42.4; Pset MEP.Geom-Outer Ø2 (mm): 42.4
Phasen - Phase erstellt: Phase 01

# IfcFlowSegment: Rohrbogen 612311:Rohrbogen 612311, Rohrbogen
In: Erdgeschoss
Type - Material: IfcSurfaceStyle #352577
Type - Andere - Kategorie: Allgemeines Modell; Familienname: Rohrbogen 612311
Type - ID-Daten - Typname: Rohrbogen 612311
Type - IFC-Parameter - Typ in IFC-Datei exportieren: Vorgabe
Description: Rohrbogen
Pset_DistributionFlowElementCommon - Reference: Rohrbogen 612311; sets with these values: 2
Andere - Typ: Rohrbogen 612311; Familie: Rohrbogen 612311; Familie und Typ: Rohrbogen 612311: Rohrbogen 612311; Typ-ID: 2537577
Abhängigkeiten - Höhe von Ebene: 0 m; Verschieben mit umliegenden Elementen: no
Bemaßungen - Fläche: 0.0049451 m2; Volumen: 0.0000668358 m3
IFC-Parameter - In IFC-Datei exportieren: Nach Typ; Pset MEP.Geom-DN2: 32; Pset MEP.Geom-DN1: 32; In IFC exportieren als: ifcflowsegment; NameOverride: Rohrbogen; IfcPresentationLayer: S_Gas; ObjectTypeOverride: Rohrbogen; Pset MEP.Name: Rohrbogen; IfcDescription: Rohrbogen; Pset MEP.Tech-Material: nach DIN 2605; Pset MEP.Geom-Outer Ø1 (mm): 42.4; Pset MEP.Geom-Outer Ø2 (mm): 42.4
Phasen - Phase erstellt: Phase 01

# IfcFlowSegment: Rohrbogen 613608:Rohrbogen 613608, Rohrbogen
In: 1. Untergeschoss
Type - Material: IfcSurfaceStyle #1741
Type - Andere - Kategorie: Allgemeines Modell; Familienname: Rohrbogen 613608
Type - ID-Daten - Typname: Rohrbogen 613608
Type - IFC-Parameter - Typ in IFC-Datei exportieren: Vorgabe
Description: Rohrbogen
Pset_DistributionFlowElementCommon - Reference: Rohrbogen 613608; sets with these values: 2
Andere - Typ: Rohrbogen 613608; Familie: Rohrbogen 613608; Familie und Typ: Rohrbogen 613608: Rohrbogen 613608; Typ-ID: 2537654
Abhängigkeiten - Höhe von Ebene: 0 m; Verschieben mit umliegenden Elementen: no
IFC-Parameter - In IFC-Datei exportieren: Nach Typ; Pset MEP.Tech-Insulation thickness (mm): 100; Pset MEP.Geom-DN1: 100; Pset MEP.Geom-DN2: 100; In IFC exportieren als: ifcflowsegment; NameOverride: Rohrbogen; IfcPresentationLayer: 0-TFT-H_Ruecklauf; ObjectTypeOverride: Rohrbogen; Pset MEP.Name: Rohrbogen; IfcDescription: Rohrbogen; Pset MEP.Tech-Material: nach DIN 2605; Pset MEP.Geom-Outer Ø1 (mm): 114.3; Pset MEP.Geom-Outer Ø2 (mm): 114.3
Phasen - Phase erstellt: Phase 01

# IfcFlowSegment: Rohrbogen 614451:Rohrbogen 614451, Rohrbogen
In: Erdgeschoss
Type - Material: IfcSurfaceStyle #1741
Type - Andere - Kategorie: Allgemeines Modell; Familienname: Rohrbogen 614451
Type - ID-Daten - Typname: Rohrbogen 614451
Type - IFC-Parameter - Typ in IFC-Datei exportieren: Vorgabe
Description: Rohrbogen
Pset_DistributionFlowElementCommon - Reference: Rohrbogen 614451; sets with these values: 2
Andere - Typ: Rohrbogen 614451; Familie: Rohrbogen 614451; Familie und Typ: Rohrbogen 614451: Rohrbogen 614451; Typ-ID: 2537717
Abhängigkeiten - Höhe von Ebene: 0 m; Verschieben mit umliegenden Elementen: no
Bemaßungen - Fläche: 0.298575 m2; Volumen: 0.0298688 m3
IFC-Parameter - In IFC-Datei exportieren: Nach Typ; Pset MEP.Tech-Insulation thickness (mm): 100; Pset MEP.Geom-DN1: 150; Pset MEP.Geom-DN2: 150; In IFC exportieren als: ifcflowsegment; NameOverride: Rohrbogen; IfcPresentationLayer: 0-TFT-H_Ruecklauf; ObjectTypeOverride: Rohrbogen; Pset MEP.Name: Rohrbogen; IfcDescription: Rohrbogen; Pset MEP.Tech-Material: nach DIN 2605; Pset MEP.Geom-Outer Ø1 (mm): 168.3; Pset MEP.Geom-Outer Ø2 (mm): 168.3
Phasen - Phase erstellt: Phase 01

# IfcFlowSegment: Rohrbogen 614720:Rohrbogen 614720, Rohrbogen
In: 1. Obergeschoss
Type - Material: IfcSurfaceStyle #1741
Type - Andere - Kategorie: Allgemeines Modell; Familienname: Rohrbogen 614720
Type - ID-Daten - Typname: Rohrbogen 614720
Type - IFC-Parameter - Typ in IFC-Datei exportieren: Vorgabe
Description: Rohrbogen
Pset_DistributionFlowElementCommon - Reference: Rohrbogen 614720; sets with these values: 2
Andere - Typ: Rohrbogen 614720; Familie: Rohrbogen 614720; Familie und Typ: Rohrbogen 614720: Rohrbogen 614720; Typ-ID: 2537794
Abhängigkeiten - Höhe von Ebene: 0 m; Verschieben mit umliegenden Elementen: no
Bemaßungen - Fläche: 0.47296 m2; Volumen: 0.0544204 m3
IFC-Parameter - In IFC-Datei exportieren: Nach Typ; Pset MEP.Tech-Insulation thickness (mm): 100; Pset MEP.Geom-DN1: 200; Pset MEP.Geom-DN2: 200; In IFC exportieren als: ifcflowsegment; NameOverride: Rohrbogen; IfcPresentationLayer: 0-TFT-H_Ruecklauf; ObjectTypeOverride: Rohrbogen; Pset MEP.Name: Rohrbogen; IfcDescription: Rohrbogen; Pset MEP.Tech-Material: nach DIN 2605; Pset MEP.Geom-Outer Ø1 (mm): 219.1; Pset MEP.Geom-Outer Ø2 (mm): 219.1
Phasen - Phase erstellt: Phase 01

# IfcFlowSegment: Rohrbogen 7887:Rohrbogen 7887, Rohrbogen
In: 1. Obergeschoss
Type - Material: IfcSurfaceStyle #1741
Type - Andere - Kategorie: Allgemeines Modell; Familienname: Rohrbogen 7887
Type - ID-Daten - Typname: Rohrbogen 7887
Type - IFC-Parameter - Typ in IFC-Datei exportieren: Vorgabe
Description: Rohrbogen
Pset_DistributionFlowElementCommon - Reference: Rohrbogen 7887; sets with these values: 2
Andere - Typ: Rohrbogen 7887; Familie: Rohrbogen 7887; Familie und Typ: Rohrbogen 7887: Rohrbogen 7887; Typ-ID: 2531461
Abhängigkeiten - Höhe von Ebene: 0 m; Verschieben mit umliegenden Elementen: no
IFC-Parameter - In IFC-Datei exportieren: Nach Typ; Pset MEP.Tech-Insulation thickness (mm): 100; In IFC exportieren als: ifcflowsegment; NameOverride: Rohrbogen; IfcPresentationLayer: 0-TFT-H_Ruecklauf; ObjectTypeOverride: Rohrbogen; Pset MEP.Name: Rohrbogen; IfcDescription: Rohrbogen; Pset MEP.Tech-Material: nach DIN 2605; Pset MEP.Geom-DN1: 100; Pset MEP.Geom-DN2: 100; Pset MEP.Geom-Outer Ø1 (mm): 114.3; Pset MEP.Geom-Outer Ø2 (mm): 114.3
Phasen - Phase erstellt: Phase 01

# IfcFlowSegment: Rohrbogen 852507:Rohrbogen 852507, Rohrbogen
In: 1. Untergeschoss
Type - Material: IfcSurfaceStyle #9317
Type - Andere - Kategorie: Allgemeines Modell; Familienname: Rohrbogen 852507
Type - ID-Daten - Typname: Rohrbogen 852507
Type - IFC-Parameter - Typ in IFC-Datei exportieren: Vorgabe
Description: Rohrbogen
Pset_DistributionFlowElementCommon - Reference: Rohrbogen 852507; sets with these values: 2
Andere - Typ: Rohrbogen 852507; Familie: Rohrbogen 852507; Familie und Typ: Rohrbogen 852507: Rohrbogen 852507; Typ-ID: 2539492
Abhängigkeiten - Höhe von Ebene: 0 m; Verschieben mit umliegenden Elementen: no
Bemaßungen - Fläche: 0.47296 m2; Volumen: 0.0544204 m3
IFC-Parameter - In IFC-Datei exportieren: Nach Typ; Pset MEP.Tech-Insulation thickness (mm): 100; Pset MEP.Geom-DN1: 200; Pset MEP.Geom-DN2: 200; In IFC exportieren als: ifcflowsegment; NameOverride: Rohrbogen; IfcPresentationLayer: 0-TFT-H_Vorlauf; ObjectTypeOverride: Rohrbogen; Pset MEP.Name: Rohrbogen; IfcDescription: Rohrbogen; Pset MEP.Tech-Material: nach DIN 2605; Pset MEP.Geom-Outer Ø1 (mm): 219.1; Pset MEP.Geom-Outer Ø2 (mm): 219.1
Phasen - Phase erstellt: Phase 01

# IfcFlowSegment: Rohrbogen 852813:Rohrbogen 852813, Rohrbogen
In: 1. Untergeschoss
Type - Material: IfcSurfaceStyle #1741
Type - Andere - Kategorie: Allgemeines Modell; Familienname: Rohrbogen 852813
Type - ID-Daten - Typname: Rohrbogen 852813
Type - IFC-Parameter - Typ in IFC-Datei exportieren: Vorgabe
Description: Rohrbogen
Pset_DistributionFlowElementCommon - Reference: Rohrbogen 852813; sets with these values: 2
Andere - Typ: Rohrbogen 852813; Familie: Rohrbogen 852813; Familie und Typ: Rohrbogen 852813: Rohrbogen 852813; Typ-ID: 2539506
Abhängigkeiten - Höhe von Ebene: 0 m; Verschieben mit umliegenden Elementen: no
Bemaßungen - Fläche: 0.47296 m2; Volumen: 0.0544204 m3
IFC-Parameter - In IFC-Datei exportieren: Nach Typ; Pset MEP.Tech-Insulation thickness (mm): 100; Pset MEP.Geom-DN1: 200; Pset MEP.Geom-DN2: 200; In IFC exportieren als: ifcflowsegment; NameOverride: Rohrbogen; IfcPresentationLayer: 0-TFT-H_Ruecklauf; ObjectTypeOverride: Rohrbogen; Pset MEP.Name: Rohrbogen; IfcDescription: Rohrbogen; Pset MEP.Tech-Material: nach DIN 2605; Pset MEP.Geom-Outer Ø1 (mm): 219.1; Pset MEP.Geom-Outer Ø2 (mm): 219.1
Phasen - Phase erstellt: Phase 01

# IfcFlowSegment: Rohrbogen 9292:Rohrbogen 9292, Rohrbogen
In: 1. Obergeschoss
Type - Material: IfcSurfaceStyle #9317
Type - Andere - Kategorie: Allgemeines Modell; Familienname: Rohrbogen 9292
Type - ID-Daten - Typname: Rohrbogen 9292
Type - IFC-Parameter - Typ in IFC-Datei exportieren: Vorgabe
Description: Rohrbogen
Pset_DistributionFlowElementCommon - Reference: Rohrbogen 9292; sets with these values: 2
Andere - Typ: Rohrbogen 9292; Familie: Rohrbogen 9292; Familie und Typ: Rohrbogen 9292: Rohrbogen 9292; Typ-ID: 2531468
Abhängigkeiten - Höhe von Ebene: 0 m; Verschieben mit umliegenden Elementen: no
IFC-Parameter - In IFC-Datei exportieren: Nach Typ; Pset MEP.Tech-Insulation thickness (mm): 100; Pset MEP.Geom-DN1: 100; Pset MEP.Geom-DN2: 100; In IFC exportieren als: ifcflowsegment; NameOverride: Rohrbogen; IfcPresentationLayer: 0-TFT-H_Vorlauf; ObjectTypeOverride: Rohrbogen; Pset MEP.Name: Rohrbogen; IfcDescription: Rohrbogen; Pset MEP.Tech-Material: nach DIN 2605; Pset MEP.Geom-Outer Ø1 (mm): 114.3; Pset MEP.Geom-Outer Ø2 (mm): 114.3
Phasen - Phase erstellt: Phase 01

# IfcFlowSegment: Rohrbogen 9709:Rohrbogen 9709, Rohrbogen
In: 1. Obergeschoss
Type - Material: IfcSurfaceStyle #9317
Type - Andere - Kategorie: Allgemeines Modell; Familienname: Rohrbogen 9709
Type - ID-Daten - Typname: Rohrbogen 9709
Type - IFC-Parameter - Typ in IFC-Datei exportieren: Vorgabe
Description: Rohrbogen
Pset_DistributionFlowElementCommon - Reference: Rohrbogen 9709; sets with these values: 2
Andere - Typ: Rohrbogen 9709; Familie: Rohrbogen 9709; Familie und Typ: Rohrbogen 9709: Rohrbogen 9709; Typ-ID: 2531492
Abhängigkeiten - Höhe von Ebene: 0 m; Verschieben mit umliegenden Elementen: no
IFC-Parameter - In IFC-Datei exportieren: Nach Typ; Pset MEP.Tech-Insulation thickness (mm): 100; Pset MEP.Geom-DN1: 100; Pset MEP.Geom-DN2: 100; In IFC exportieren als: ifcflowsegment; NameOverride: Rohrbogen; IfcPresentationLayer: 0-TFT-H_Vorlauf; ObjectTypeOverride: Rohrbogen; Pset MEP.Name: Rohrbogen; IfcDescription: Rohrbogen; Pset MEP.Tech-Material: nach DIN 2605; Pset MEP.Geom-Outer Ø1 (mm): 114.3; Pset MEP.Geom-Outer Ø2 (mm): 114.3
Phasen - Phase erstellt: Phase 01

# IfcFlowSegment: Rohrbogen 9738:Rohrbogen 9738, Rohrbogen
In: 1. Obergeschoss
Type - Material: IfcSurfaceStyle #1741
Type - Andere - Kategorie: Allgemeines Modell; Familienname: Rohrbogen 9738
Type - ID-Daten - Typname: Rohrbogen 9738
Type - IFC-Parameter - Typ in IFC-Datei exportieren: Vorgabe
Description: Rohrbogen
Pset_DistributionFlowElementCommon - Reference: Rohrbogen 9738; sets with these values: 2
Andere - Typ: Rohrbogen 9738; Familie: Rohrbogen 9738; Familie und Typ: Rohrbogen 9738: Rohrbogen 9738; Typ-ID: 2531499
Abhängigkeiten - Höhe von Ebene: 0 m; Verschieben mit umliegenden Elementen: no
IFC-Parameter - In IFC-Datei exportieren: Nach Typ; Pset MEP.Tech-Insulation thickness (mm): 100; Pset MEP.Geom-DN1: 100; Pset MEP.Geom-DN2: 100; In IFC exportieren als: ifcflowsegment; NameOverride: Rohrbogen; IfcPresentationLayer: 0-TFT-H_Ruecklauf; ObjectTypeOverride: Rohrbogen; Pset MEP.Name: Rohrbogen; IfcDescription: Rohrbogen; Pset MEP.Tech-Material: nach DIN 2605; Pset MEP.Geom-Outer Ø1 (mm): 114.3; Pset MEP.Geom-Outer Ø2 (mm): 114.3
Phasen - Phase erstellt: Phase 01

# IfcFlowSegment: Rohrbogen:Rohrbogen, Rohrbogen
In: 1. Obergeschoss
Type - Material: IfcSurfaceStyle #1741
Type - Andere - Kategorie: Allgemeines Modell; Familienname: Rohrbogen
Type - ID-Daten - Typname: Rohrbogen
Type - IFC-Parameter - Typ in IFC-Datei exportieren: Vorgabe
Description: Rohrbogen
Pset_DistributionFlowElementCommon - Reference: Rohrbogen; sets with these values: 2
Andere - Typ: Rohrbogen; Familie: Rohrbogen; Familie und Typ: Rohrbogen: Rohrbogen; Typ-ID: 2531347
Abhängigkeiten - Höhe von Ebene: 0 m; Verschieben mit umliegenden Elementen: no
Bemaßungen - Fläche: 0.47296 m2; Volumen: 0.0544204 m3
IFC-Parameter - In IFC-Datei exportieren: Nach Typ; Pset MEP.Tech-Insulation thickness (mm): 100; In IFC exportieren als: ifcflowsegment; NameOverride: Rohrbogen; IfcPresentationLayer: 0-TFT-H_Ruecklauf; ObjectTypeOverride: Rohrbogen; Pset MEP.Name: Rohrbogen; IfcDescription: Rohrbogen; Pset MEP.Tech-Material: nach DIN 2605; Pset MEP.Geom-DN1: 200; Pset MEP.Geom-DN2: 200; Pset MEP.Geom-Outer Ø1 (mm): 219.1; Pset MEP.Geom-Outer Ø2 (mm): 219.1
Phasen - Phase erstellt: Phase 01

# IfcFlowSegment: Stahlrohr nach DIN 2448 10064:Stahlrohr nach DIN 2448 10064, Stahlrohr nach DIN 2448
In: 1. Obergeschoss
Type - Material: IfcSurfaceStyle #9317
Type - Andere - Kategorie: Allgemeines Modell; Familienname: Stahlrohr nach DIN 2448 10064
Type - ID-Daten - Typname: Stahlrohr nach DIN 2448 10064
Type - IFC-Parameter - Typ in IFC-Datei exportieren: Vorgabe
Description: Stahlrohr nach DIN 2448
Pset_DistributionFlowElementCommon - Reference: Stahlrohr nach DIN 2448 10064; sets with these values: 2
Andere - Typ: Stahlrohr nach DIN 2448 10064; Familie: Stahlrohr nach DIN 2448 10064; Familie und Typ: Stahlrohr nach DIN 2448 10064: Stahlrohr nach DIN 2448 10064; Typ-ID: 2531513
Abhängigkeiten - Höhe von Ebene: 0 m; Verschieben mit umliegenden Elementen: no
Bemaßungen - Fläche: 2.39022 m2; Volumen: 0.204762 m3
IFC-Parameter - In IFC-Datei exportieren: Nach Typ; Pset MEP.Tech-Insulation thickness (mm): 100; Pset MEP.Geom-DN: 100; In IFC exportieren als: ifcflowsegment; NameOverride: Stahlrohr nach DIN 2448; IfcPresentationLayer: 0-TFT-H_Vorlauf; ObjectTypeOverride: Stahlrohr nach DIN 2448; Pset MEP.Name: Stahlrohr nach DIN 2448; IfcDescription: Stahlrohr nach DIN 2448; Pset MEP.Geom-Outer Ø (mm): 114.3; Pset MEP.Tech-Material: Stahlrohr nach DIN 2448; Pset MEP.Geom-Length (mm): 3568.4
Phasen - Phase erstellt: Phase 01

# IfcFlowSegment: Stahlrohr nach DIN 2448 11088:Stahlrohr nach DIN 2448 11088, Stahlrohr nach DIN 2448
In: 1. Obergeschoss
Type - Material: IfcSurfaceStyle #9317
Type - Andere - Kategorie: Allgemeines Modell; Familienname: Stahlrohr nach DIN 2448 11088
Type - ID-Daten - Typname: Stahlrohr nach DIN 2448 11088
Type - IFC-Parameter - Typ in IFC-Datei exportieren: Vorgabe
Description: Stahlrohr nach DIN 2448
Pset_DistributionFlowElementCommon - Reference: Stahlrohr nach DIN 2448 11088; sets with these values: 2
Andere - Typ: Stahlrohr nach DIN 2448 11088; Familie: Stahlrohr nach DIN 2448 11088; Familie und Typ: Stahlrohr nach DIN 2448 11088: Stahlrohr nach DIN 2448 11088; Typ-ID: 2531527
Abhängigkeiten - Höhe von Ebene: 0 m; Verschieben mit umliegenden Elementen: no
Bemaßungen - Fläche: 0.206154 m2; Volumen: 0.0163662 m3
IFC-Parameter - In IFC-Datei exportieren: Nach Typ; Pset MEP.Tech-Insulation thickness (mm): 100; In IFC exportieren als: ifcflowsegment; NameOverride: Stahlrohr nach DIN 2448; IfcPresentationLayer: 0-TFT-H_Vorlauf; ObjectTypeOverride: Stahlrohr nach DIN 2448; Pset MEP.Name: Stahlrohr nach DIN 2448; IfcDescription: Stahlrohr nach DIN 2448; Pset MEP.Geom-DN: 80; Pset MEP.Geom-Outer Ø (mm): 88.9; Pset MEP.Tech-Material: Stahlrohr nach DIN 2448; Pset MEP.Geom-Length (mm): 349.155
Phasen - Phase erstellt: Phase 01

# IfcFlowSegment: Stahlrohr nach DIN 2448 220275:Stahlrohr nach DIN 2448 220275, Stahlrohr nach DIN 2448
In: 1. Obergeschoss
Type - Material: IfcSurfaceStyle #9317
Type - Andere - Kategorie: Allgemeines Modell; Familienname: Stahlrohr nach DIN 2448 220275
Type - ID-Daten - Typname: Stahlrohr nach DIN 2448 220275
Type - IFC-Parameter - Typ in IFC-Datei exportieren: Vorgabe
Description: Stahlrohr nach DIN 2448
Pset_DistributionFlowElementCommon - Reference: Stahlrohr nach DIN 2448 220275; sets with these values: 2
Andere - Typ: Stahlrohr nach DIN 2448 220275; Familie: Stahlrohr nach DIN 2448 220275; Familie und Typ: Stahlrohr nach DIN 2448 220275: Stahlrohr nach DIN 2448 220275; Typ-ID: 2531611
Abhängigkeiten - Höhe von Ebene: 0 m; Verschieben mit umliegenden Elementen: no
Bemaßungen - Fläche: 0.274138 m2; Volumen: 0.0217633 m3
IFC-Parameter - In IFC-Datei exportieren: Nach Typ; Pset MEP.Tech-Insulation thickness (mm): 100; Pset MEP.Geom-DN: 80; In IFC exportieren als: ifcflowsegment; NameOverride: Stahlrohr nach DIN 2448; IfcPresentationLayer: 0-TFT-H_Vorlauf; ObjectTypeOverride: Stahlrohr nach DIN 2448; Pset MEP.Name: Stahlrohr nach DIN 2448; IfcDescription: Stahlrohr nach DIN 2448; Pset MEP.Geom-Outer Ø (mm): 88.9; Pset MEP.Tech-Material: Stahlrohr nach DIN 2448; Pset MEP.Geom-Length (mm): 464.296
Phasen - Phase erstellt: Phase 01

# IfcFlowSegment: Stahlrohr nach DIN 2448 220585:Stahlrohr nach DIN 2448 220585, Stahlrohr nach DIN 2448
In: 1. Obergeschoss
Type - Material: IfcSurfaceStyle #9317
Type - Andere - Kategorie: Allgemeines Modell; Familienname: Stahlrohr nach DIN 2448 220585
Type - ID-Daten - Typname: Stahlrohr nach DIN 2448 220585
Type - IFC-Parameter - Typ in IFC-Datei exportieren: Vorgabe
Description: Stahlrohr nach DIN 2448
Pset_DistributionFlowElementCommon - Reference: Stahlrohr nach DIN 2448 220585; sets with these values: 2
Andere - Typ: Stahlrohr nach DIN 2448 220585; Familie: Stahlrohr nach DIN 2448 220585; Familie und Typ: Stahlrohr nach DIN 2448 220585: Stahlrohr nach DIN 2448 220585; Typ-ID: 2531625
Abhängigkeiten - Höhe von Ebene: 0 m; Verschieben mit umliegenden Elementen: no
Bemaßungen - Fläche: 0.147597 m2; Volumen: 0.0148054 m3
IFC-Parameter - In IFC-Datei exportieren: Nach Typ; Pset MEP.Tech-Insulation thickness (mm): 100; Pset MEP.Geom-DN: 150; In IFC exportieren als: ifcflowsegment; NameOverride: Stahlrohr nach DIN 2448; IfcPresentationLayer: 0-TFT-H_Vorlauf; ObjectTypeOverride: Stahlrohr nach DIN 2448; Pset MEP.Name: Stahlrohr nach DIN 2448; IfcDescription: Stahlrohr nach DIN 2448; Pset MEP.Geom-Outer Ø (mm): 168.3; Pset MEP.Tech-Material: Stahlrohr nach DIN 2448; Pset MEP.Geom-Length (mm): 176
Phasen - Phase erstellt: Phase 01

# IfcFlowSegment: Stahlrohr nach DIN 2448 220871:Stahlrohr nach DIN 2448 220871, Stahlrohr nach DIN 2448
In: 1. Obergeschoss
Type - Material: IfcSurfaceStyle #9317
Type - Andere - Kategorie: Allgemeines Modell; Familienname: Stahlrohr nach DIN 2448 220871
Type - ID-Daten - Typname: Stahlrohr nach DIN 2448 220871
Type - IFC-Parameter - Typ in IFC-Datei exportieren: Vorgabe
Description: Stahlrohr nach DIN 2448
Pset_DistributionFlowElementCommon - Reference: Stahlrohr nach DIN 2448 220871; sets with these values: 2
Andere - Typ: Stahlrohr nach DIN 2448 220871; Familie: Stahlrohr nach DIN 2448 220871; Familie und Typ: Stahlrohr nach DIN 2448 220871: Stahlrohr nach DIN 2448 220871; Typ-ID: 2531632
Abhängigkeiten - Höhe von Ebene: 0 m; Verschieben mit umliegenden Elementen: no
Bemaßungen - Fläche: 0.376539 m2; Volumen: 0.0377705 m3
IFC-Parameter - In IFC-Datei exportieren: Nach Typ; Pset MEP.Tech-Insulation thickness (mm): 100; Pset MEP.Geom-DN: 150; In IFC exportieren als: ifcflowsegment; NameOverride: Stahlrohr nach DIN 2448; IfcPresentationLayer: 0-TFT-H_Vorlauf; ObjectTypeOverride: Stahlrohr nach DIN 2448; Pset MEP.Name: Stahlrohr nach DIN 2448; IfcDescription: Stahlrohr nach DIN 2448; Pset MEP.Geom-Outer Ø (mm): 168.3; Pset MEP.Tech-Material: Stahlrohr nach DIN 2448; Pset MEP.Geom-Length (mm): 449
Phasen - Phase erstellt: Phase 01

# IfcFlowSegment: Stahlrohr nach DIN 2448 221182:Stahlrohr nach DIN 2448 221182, Stahlrohr nach DIN 2448
In: 1. Obergeschoss
Type - Material: IfcSurfaceStyle #9317
Type - Andere - Kategorie: Allgemeines Modell; Familienname: Stahlrohr nach DIN 2448 221182
Type - ID-Daten - Typname: Stahlrohr nach DIN 2448 221182
Type - IFC-Parameter - Typ in IFC-Datei exportieren: Vorgabe
Description: Stahlrohr nach DIN 2448
Pset_DistributionFlowElementCommon - Reference: Stahlrohr nach DIN 2448 221182; sets with these values: 2
Andere - Typ: Stahlrohr nach DIN 2448 221182; Familie: Stahlrohr nach DIN 2448 221182; Familie und Typ: Stahlrohr nach DIN 2448 221182: Stahlrohr nach DIN 2448 221182; Typ-ID: 2531695
Abhängigkeiten - Höhe von Ebene: 0 m; Verschieben mit umliegenden Elementen: no
Bemaßungen - Fläche: 0.206154 m2; Volumen: 0.0163662 m3
IFC-Parameter - In IFC-Datei exportieren: Nach Typ; Pset MEP.Tech-Insulation thickness (mm): 100; Pset MEP.Geom-DN: 80; In IFC exportieren als: ifcflowsegment; NameOverride: Stahlrohr nach DIN 2448; IfcPresentationLayer: 0-TFT-H_Vorlauf; ObjectTypeOverride: Stahlrohr nach DIN 2448; Pset MEP.Name: Stahlrohr nach DIN 2448; IfcDescription: Stahlrohr nach DIN 2448; Pset MEP.Geom-Outer Ø (mm): 88.9; Pset MEP.Tech-Material: Stahlrohr nach DIN 2448; Pset MEP.Geom-Length (mm): 349.155
Phasen - Phase erstellt: Phase 01

# IfcFlowSegment: Stahlrohr nach DIN 2448 221398:Stahlrohr nach DIN 2448 221398, Stahlrohr nach DIN 2448
In: 1. Obergeschoss
Type - Material: IfcSurfaceStyle #9317
Type - Andere - Kategorie: Allgemeines Modell; Familienname: Stahlrohr nach DIN 2448 221398
Type - ID-Daten - Typname: Stahlrohr nach DIN 2448 221398
Type - IFC-Parameter - Typ in IFC-Datei exportieren: Vorgabe
Description: Stahlrohr nach DIN 2448
Pset_DistributionFlowElementCommon - Reference: Stahlrohr nach DIN 2448 221398; sets with these values: 2
Andere - Typ: Stahlrohr nach DIN 2448 221398; Familie: Stahlrohr nach DIN 2448 221398; Familie und Typ: Stahlrohr nach DIN 2448 221398: Stahlrohr nach DIN 2448 221398; Typ-ID: 2531761
Abhängigkeiten - Höhe von Ebene: 0 m; Verschieben mit umliegenden Elementen: no
Bemaßungen - Fläche: 0.274138 m2; Volumen: 0.0217633 m3
IFC-Parameter - In IFC-Datei exportieren: Nach Typ; Pset MEP.Tech-Insulation thickness (mm): 100; Pset MEP.Geom-DN: 80; In IFC exportieren als: ifcflowsegment; NameOverride: Stahlrohr nach DIN 2448; IfcPresentationLayer: 0-TFT-H_Vorlauf; ObjectTypeOverride: Stahlrohr nach DIN 2448; Pset MEP.Name: Stahlrohr nach DIN 2448; IfcDescription: Stahlrohr nach DIN 2448; Pset MEP.Geom-Outer Ø (mm): 88.9; Pset MEP.Tech-Material: Stahlrohr nach DIN 2448; Pset MEP.Geom-Length (mm): 464.296
Phasen - Phase erstellt: Phase 01

# IfcFlowSegment: Stahlrohr nach DIN 2448 221448:Stahlrohr nach DIN 2448 221448, Stahlrohr nach DIN 2448
In: 1. Obergeschoss
Type - Material: IfcSurfaceStyle #9317
Type - Andere - Kategorie: Allgemeines Modell; Familienname: Stahlrohr nach DIN 2448 221448
Type - ID-Daten - Typname: Stahlrohr nach DIN 2448 221448
Type - IFC-Parameter - Typ in IFC-Datei exportieren: Vorgabe
Description: Stahlrohr nach DIN 2448
Pset_DistributionFlowElementCommon - Reference: Stahlrohr nach DIN 2448 221448; sets with these values: 2
Andere - Typ: Stahlrohr nach DIN 2448 221448; Familie: Stahlrohr nach DIN 2448 221448; Familie und Typ: Stahlrohr nach DIN 2448 221448: Stahlrohr nach DIN 2448 221448; Typ-ID: 2531775
Abhängigkeiten - Höhe von Ebene: 0 m; Verschieben mit umliegenden Elementen: no
Bemaßungen - Fläche: 0.206154 m2; Volumen: 0.0163662 m3
IFC-Parameter - In IFC-Datei exportieren: Nach Typ; Pset MEP.Tech-Insulation thickness (mm): 100; Pset MEP.Geom-DN: 80; In IFC exportieren als: ifcflowsegment; NameOverride: Stahlrohr nach DIN 2448; IfcPresentationLayer: 0-TFT-H_Vorlauf; ObjectTypeOverride: Stahlrohr nach DIN 2448; Pset MEP.Name: Stahlrohr nach DIN 2448; IfcDescription: Stahlrohr nach DIN 2448; Pset MEP.Geom-Outer Ø (mm): 88.9; Pset MEP.Tech-Material: Stahlrohr nach DIN 2448; Pset MEP.Geom-Length (mm): 349.155
Phasen - Phase erstellt: Phase 01

# IfcFlowSegment: Stahlrohr nach DIN 2448 221655:Stahlrohr nach DIN 2448 221655, Stahlrohr nach DIN 2448
In: 1. Obergeschoss
Type - Material: IfcSurfaceStyle #9317
Type - Andere - Kategorie: Allgemeines Modell; Familienname: Stahlrohr nach DIN 2448 221655
Type - ID-Daten - Typname: Stahlrohr nach DIN 2448 221655
Type - IFC-Parameter - Typ in IFC-Datei exportieren: Vorgabe
Description: Stahlrohr nach DIN 2448
Pset_DistributionFlowElementCommon - Reference: Stahlrohr nach DIN 2448 221655; sets with these values: 2
Andere - Typ: Stahlrohr nach DIN 2448 221655; Familie: Stahlrohr nach DIN 2448 221655; Familie und Typ: Stahlrohr nach DIN 2448 221655: Stahlrohr nach DIN 2448 221655; Typ-ID: 2531838
Abhängigkeiten - Höhe von Ebene: 0 m; Verschieben mit umliegenden Elementen: no
Bemaßungen - Fläche: 0.274138 m2; Volumen: 0.0217633 m3
IFC-Parameter - In IFC-Datei exportieren: Nach Typ; Pset MEP.Tech-Insulation thickness (mm): 100; Pset MEP.Geom-DN: 80; In IFC exportieren als: ifcflowsegment; NameOverride: Stahlrohr nach DIN 2448; IfcPresentationLayer: 0-TFT-H_Vorlauf; ObjectTypeOverride: Stahlrohr nach DIN 2448; Pset MEP.Name: Stahlrohr nach DIN 2448; IfcDescription: Stahlrohr nach DIN 2448; Pset MEP.Geom-Outer Ø (mm): 88.9; Pset MEP.Tech-Material: Stahlrohr nach DIN 2448; Pset MEP.Geom-Length (mm): 464.296
Phasen - Phase erstellt: Phase 01

# IfcFlowSegment: Stahlrohr nach DIN 2448 222190:Stahlrohr nach DIN 2448 222190, Stahlrohr nach DIN 2448
In: 1. Obergeschoss
Type - Material: IfcSurfaceStyle #9317
Type - Andere - Kategorie: Allgemeines Modell; Familienname: Stahlrohr nach DIN 2448 222190
Type - ID-Daten - Typname: Stahlrohr nach DIN 2448 222190
Type - IFC-Parameter - Typ in IFC-Datei exportieren: Vorgabe
Description: Stahlrohr nach DIN 2448
Pset_DistributionFlowElementCommon - Reference: Stahlrohr nach DIN 2448 222190; sets with these values: 2
Andere - Typ: Stahlrohr nach DIN 2448 222190; Familie: Stahlrohr nach DIN 2448 222190; Familie und Typ: Stahlrohr nach DIN 2448 222190: Stahlrohr nach DIN 2448 222190; Typ-ID: 2531852
Abhängigkeiten - Höhe von Ebene: 0 m; Verschieben mit umliegenden Elementen: no
Bemaßungen - Fläche: 0.128308 m2; Volumen: 0.0128706 m3
IFC-Parameter - In IFC-Datei exportieren: Nach Typ; Pset MEP.Tech-Insulation thickness (mm): 100; Pset MEP.Geom-DN: 150; In IFC exportieren als: ifcflowsegment; NameOverride: Stahlrohr nach DIN 2448; IfcPresentationLayer: 0-TFT-H_Vorlauf; ObjectTypeOverride: Stahlrohr nach DIN 2448; Pset MEP.Name: Stahlrohr nach DIN 2448; IfcDescription: Stahlrohr nach DIN 2448; Pset MEP.Geom-Outer Ø (mm): 168.3; Pset MEP.Tech-Material: Stahlrohr nach DIN 2448; Pset MEP.Geom-Length (mm): 153
Phasen - Phase erstellt: Phase 01

# IfcFlowSegment: Stahlrohr nach DIN 2448 222500:Stahlrohr nach DIN 2448 222500, Stahlrohr nach DIN 2448
In: 1. Obergeschoss
Type - Material: IfcSurfaceStyle #9317
Type - Andere - Kategorie: Allgemeines Modell; Familienname: Stahlrohr nach DIN 2448 222500
Type - ID-Daten - Typname: Stahlrohr nach DIN 2448 222500
Type - IFC-Parameter - Typ in IFC-Datei exportieren: Vorgabe
Description: Stahlrohr nach DIN 2448
Pset_DistributionFlowElementCommon - Reference: Stahlrohr nach DIN 2448 222500; sets with these values: 2
Andere - Typ: Stahlrohr nach DIN 2448 222500; Familie: Stahlrohr nach DIN 2448 222500; Familie und Typ: Stahlrohr nach DIN 2448 222500: Stahlrohr nach DIN 2448 222500; Typ-ID: 2531866
Abhängigkeiten - Höhe von Ebene: 0 m; Verschieben mit umliegenden Elementen: no
Bemaßungen - Fläche: 0.304804 m2; Volumen: 0.0305748 m3
IFC-Parameter - In IFC-Datei exportieren: Nach Typ; Pset MEP.Tech-Insulation thickness (mm): 100; Pset MEP.Geom-DN: 150; In IFC exportieren als: ifcflowsegment; NameOverride: Stahlrohr nach DIN 2448; IfcPresentationLayer: 0-TFT-H_Vorlauf; ObjectTypeOverride: Stahlrohr nach DIN 2448; Pset MEP.Name: Stahlrohr nach DIN 2448; IfcDescription: Stahlrohr nach DIN 2448; Pset MEP.Geom-Outer Ø (mm): 168.3; Pset MEP.Tech-Material: Stahlrohr nach DIN 2448; Pset MEP.Geom-Length (mm): 363.46
Phasen - Phase erstellt: Phase 01

# IfcFlowSegment: Stahlrohr nach DIN 2448 222999:Stahlrohr nach DIN 2448 222999, Stahlrohr nach DIN 2448
In: 1. Obergeschoss
Type - Material: IfcSurfaceStyle #9317
Type - Andere - Kategorie: Allgemeines Modell; Familienname: Stahlrohr nach DIN 2448 222999
Type - ID-Daten - Typname: Stahlrohr nach DIN 2448 222999
Type - IFC-Parameter - Typ in IFC-Datei exportieren: Vorgabe
Description: Stahlrohr nach DIN 2448
Pset_DistributionFlowElementCommon - Reference: Stahlrohr nach DIN 2448 222999; sets with these values: 2
Andere - Typ: Stahlrohr nach DIN 2448 222999; Familie: Stahlrohr nach DIN 2448 222999; Familie und Typ: Stahlrohr nach DIN 2448 222999: Stahlrohr nach DIN 2448 222999; Typ-ID: 2531887
Abhängigkeiten - Höhe von Ebene: 0 m; Verschieben mit umliegenden Elementen: no
Bemaßungen - Fläche: 0.379012 m2; Volumen: 0.0436008 m3
IFC-Parameter - In IFC-Datei exportieren: Nach Typ; Pset MEP.Geom-DN: 200; Pset MEP.Tech-Insulation thickness (mm): 100; In IFC exportieren als: ifcflowsegment; NameOverride: Stahlrohr nach DIN 2448; IfcPresentationLayer: 0-TFT-H_Vorlauf; ObjectTypeOverride: Stahlrohr nach DIN 2448; Pset MEP.Name: Stahlrohr nach DIN 2448; IfcDescription: Stahlrohr nach DIN 2448; Pset MEP.Geom-Outer Ø (mm): 219.1; Pset MEP.Tech-Material: Stahlrohr nach DIN 2448; Pset MEP.Geom-Length (mm): 380
Phasen - Phase erstellt: Phase 01

# IfcFlowSegment: Stahlrohr nach DIN 2448 223304:Stahlrohr nach DIN 2448 223304, Stahlrohr nach DIN 2448
In: 1. Obergeschoss
Type - Material: IfcSurfaceStyle #1741
Type - Andere - Kategorie: Allgemeines Modell; Familienname: Stahlrohr nach DIN 2448 223304
Type - ID-Daten - Typname: Stahlrohr nach DIN 2448 223304
Type - IFC-Parameter - Typ in IFC-Datei exportieren: Vorgabe
Description: Stahlrohr nach DIN 2448
Pset_DistributionFlowElementCommon - Reference: Stahlrohr nach DIN 2448 223304; sets with these values: 2
Andere - Typ: Stahlrohr nach DIN 2448 223304; Familie: Stahlrohr nach DIN 2448 223304; Familie und Typ: Stahlrohr nach DIN 2448 223304: Stahlrohr nach DIN 2448 223304; Typ-ID: 2531901
Abhängigkeiten - Höhe von Ebene: 0 m; Verschieben mit umliegenden Elementen: no
Bemaßungen - Fläche: 0.400118 m2; Volumen: 0.0460288 m3
IFC-Parameter - In IFC-Datei exportieren: Nach Typ; Pset MEP.Geom-DN: 200; Pset MEP.Tech-Insulation thickness (mm): 100; In IFC exportieren als: ifcflowsegment; NameOverride: Stahlrohr nach DIN 2448; IfcPresentationLayer: 0-TFT-H_Ruecklauf; ObjectTypeOverride: Stahlrohr nach DIN 2448; Pset MEP.Name: Stahlrohr nach DIN 2448; IfcDescription: Stahlrohr nach DIN 2448; Pset MEP.Geom-Outer Ø (mm): 219.1; Pset MEP.Tech-Material: Stahlrohr nach DIN 2448; Pset MEP.Geom-Length (mm): 401.161
Phasen - Phase erstellt: Phase 01

# IfcFlowSegment: Stahlrohr nach DIN 2448 223585:Stahlrohr nach DIN 2448 223585, Stahlrohr nach DIN 2448
In: 1. Obergeschoss
Type - Material: IfcSurfaceStyle #1741
Type - Andere - Kategorie: Allgemeines Modell; Familienname: Stahlrohr nach DIN 2448 223585
Type - ID-Daten - Typname: Stahlrohr nach DIN 2448 223585
Type - IFC-Parameter - Typ in IFC-Datei exportieren: Vorgabe
Description: Stahlrohr nach DIN 2448
Pset_DistributionFlowElementCommon - Reference: Stahlrohr nach DIN 2448 223585; sets with these values: 2
Andere - Typ: Stahlrohr nach DIN 2448 223585; Familie: Stahlrohr nach DIN 2448 223585; Familie und Typ: Stahlrohr nach DIN 2448 223585: Stahlrohr nach DIN 2448 223585; Typ-ID: 2531908
Abhängigkeiten - Höhe von Ebene: 0 m; Verschieben mit umliegenden Elementen: no
Bemaßungen - Fläche: 0.273288 m2; Volumen: 0.0314385 m3
IFC-Parameter - In IFC-Datei exportieren: Nach Typ; Pset MEP.Geom-DN: 200; Pset MEP.Tech-Insulation thickness (mm): 100; In IFC exportieren als: ifcflowsegment; NameOverride: Stahlrohr nach DIN 2448; IfcPresentationLayer: 0-TFT-H_Ruecklauf; ObjectTypeOverride: Stahlrohr nach DIN 2448; Pset MEP.Name: Stahlrohr nach DIN 2448; IfcDescription: Stahlrohr nach DIN 2448; Pset MEP.Geom-Outer Ø (mm): 219.1; Pset MEP.Tech-Material: Stahlrohr nach DIN 2448; Pset MEP.Geom-Length (mm): 274
Phasen - Phase erstellt: Phase 01

# IfcFlowSegment: Stahlrohr nach DIN 2448 223866:Stahlrohr nach DIN 2448 223866, Stahlrohr nach DIN 2448
In: 1. Obergeschoss
Type - Material: IfcSurfaceStyle #1741
Type - Andere - Kategorie: Allgemeines Modell; Familienname: Stahlrohr nach DIN 2448 223866
Type - ID-Daten - Typname: Stahlrohr nach DIN 2448 223866
Type - IFC-Parameter - Typ in IFC-Datei exportieren: Vorgabe
Description: Stahlrohr nach DIN 2448
Pset_DistributionFlowElementCommon - Reference: Stahlrohr nach DIN 2448 223866; sets with these values: 2
Andere - Typ: Stahlrohr nach DIN 2448 223866; Familie: Stahlrohr nach DIN 2448 223866; Familie und Typ: Stahlrohr nach DIN 2448 223866: Stahlrohr nach DIN 2448 223866; Typ-ID: 2531915
Abhängigkeiten - Höhe von Ebene: 0 m; Verschieben mit umliegenden Elementen: no
Bemaßungen - Fläche: 0.322321 m2; Volumen: 0.0370792 m3
IFC-Parameter - In IFC-Datei exportieren: Nach Typ; Pset MEP.Geom-DN: 200; Pset MEP.Tech-Insulation thickness (mm): 100; In IFC exportieren als: ifcflowsegment; NameOverride: Stahlrohr nach DIN 2448; IfcPresentationLayer: 0-TFT-H_Ruecklauf; ObjectTypeOverride: Stahlrohr nach DIN 2448; Pset MEP.Name: Stahlrohr nach DIN 2448; IfcDescription: Stahlrohr nach DIN 2448; Pset MEP.Geom-Outer Ø (mm): 219.1; Pset MEP.Tech-Material: Stahlrohr nach DIN 2448; Pset MEP.Geom-Length (mm): 323.161
Phasen - Phase erstellt: Phase 01

# IfcFlowSegment: Stahlrohr nach DIN 2448 224147:Stahlrohr nach DIN 2448 224147, Stahlrohr nach DIN 2448
In: 1. Obergeschoss
Type - Material: IfcSurfaceStyle #1741
Type - Andere - Kategorie: Allgemeines Modell; Familienname: Stahlrohr nach DIN 2448 224147
Type - ID-Daten - Typname: Stahlrohr nach DIN 2448 224147
Type - IFC-Parameter - Typ in IFC-Datei exportieren: Vorgabe
Description: Stahlrohr nach DIN 2448
Pset_DistributionFlowElementCommon - Reference: Stahlrohr nach DIN 2448 224147; sets with these values: 2
Andere - Typ: Stahlrohr nach DIN 2448 224147; Familie: Stahlrohr nach DIN 2448 224147; Familie und Typ: Stahlrohr nach DIN 2448 224147: Stahlrohr nach DIN 2448 224147; Typ-ID: 2531922
Abhängigkeiten - Höhe von Ebene: 0 m; Verschieben mit umliegenden Elementen: no
Bemaßungen - Fläche: 0.273446 m2; Volumen: 0.0314567 m3
IFC-Parameter - In IFC-Datei exportieren: Nach Typ; Pset MEP.Geom-DN: 200; Pset MEP.Tech-Insulation thickness (mm): 100; In IFC exportieren als: ifcflowsegment; NameOverride: Stahlrohr nach DIN 2448; IfcPresentationLayer: 0-TFT-H_Ruecklauf; ObjectTypeOverride: Stahlrohr nach DIN 2448; Pset MEP.Name: Stahlrohr nach DIN 2448; IfcDescription: Stahlrohr nach DIN 2448; Pset MEP.Geom-Outer Ø (mm): 219.1; Pset MEP.Tech-Material: Stahlrohr nach DIN 2448; Pset MEP.Geom-Length (mm): 274.159
Phasen - Phase erstellt: Phase 01

# IfcFlowSegment: Stahlrohr nach DIN 2448 224428:Stahlrohr nach DIN 2448 224428, Stahlrohr nach DIN 2448
In: 1. Obergeschoss
Type - Material: IfcSurfaceStyle #1741
Type - Andere - Kategorie: Allgemeines Modell; Familienname: Stahlrohr nach DIN 2448 224428
Type - ID-Daten - Typname: Stahlrohr nach DIN 2448 224428
Type - IFC-Parameter - Typ in IFC-Datei exportieren: Vorgabe
Description: Stahlrohr nach DIN 2448
Pset_DistributionFlowElementCommon - Reference: Stahlrohr nach DIN 2448 224428; sets with these values: 2
Andere - Typ: Stahlrohr nach DIN 2448 224428; Familie: Stahlrohr nach DIN 2448 224428; Familie und Typ: Stahlrohr nach DIN 2448 224428: Stahlrohr nach DIN 2448 224428; Typ-ID: 2531929
Abhängigkeiten - Höhe von Ebene: 0 m; Verschieben mit umliegenden Elementen: no
Bemaßungen - Fläche: 1.15587 m2; Volumen: 0.132969 m3
IFC-Parameter - In IFC-Datei exportieren: Nach Typ; Pset MEP.Geom-DN: 200; Pset MEP.Tech-Insulation thickness (mm): 100; In IFC exportieren als: ifcflowsegment; NameOverride: Stahlrohr nach DIN 2448; IfcPresentationLayer: 0-TFT-H_Ruecklauf; ObjectTypeOverride: Stahlrohr nach DIN 2448; Pset MEP.Name: Stahlrohr nach DIN 2448; IfcDescription: Stahlrohr nach DIN 2448; Pset MEP.Geom-Outer Ø (mm): 219.1; Pset MEP.Tech-Material: Stahlrohr nach DIN 2448; Pset MEP.Geom-Length (mm): 1158.88
Phasen - Phase erstellt: Phase 01

# IfcFlowSegment: Stahlrohr nach DIN 2448 224709:Stahlrohr nach DIN 2448 224709, Stahlrohr nach DIN 2448
In: 1. Obergeschoss
Type - Material: IfcSurfaceStyle #1741
Type - Andere - Kategorie: Allgemeines Modell; Familienname: Stahlrohr nach DIN 2448 224709
Type - ID-Daten - Typname: Stahlrohr nach DIN 2448 224709
Type - IFC-Parameter - Typ in IFC-Datei exportieren: Vorgabe
Description: Stahlrohr nach DIN 2448
Pset_DistributionFlowElementCommon - Reference: Stahlrohr nach DIN 2448 224709; sets with these values: 2
Andere - Typ: Stahlrohr nach DIN 2448 224709; Familie: Stahlrohr nach DIN 2448 224709; Familie und Typ: Stahlrohr nach DIN 2448 224709: Stahlrohr nach DIN 2448 224709; Typ-ID: 2531936
Abhängigkeiten - Höhe von Ebene: 0 m; Verschieben mit umliegenden Elementen: no
Bemaßungen - Fläche: 0.641212 m2; Volumen: 0.0737638 m3
IFC-Parameter - In IFC-Datei exportieren: Nach Typ; Pset MEP.Geom-DN: 200; Pset MEP.Tech-Insulation thickness (mm): 100; In IFC exportieren als: ifcflowsegment; NameOverride: Stahlrohr nach DIN 2448; IfcPresentationLayer: 0-TFT-H_Ruecklauf; ObjectTypeOverride: Stahlrohr nach DIN 2448; Pset MEP.Name: Stahlrohr nach DIN 2448; IfcDescription: Stahlrohr nach DIN 2448; Pset MEP.Geom-Outer Ø (mm): 219.1; Pset MEP.Tech-Material: Stahlrohr nach DIN 2448; Pset MEP.Geom-Length (mm): 642.883
Phasen - Phase erstellt: Phase 01

# IfcFlowSegment: Stahlrohr nach DIN 2448 224992:Stahlrohr nach DIN 2448 224992, Stahlrohr nach DIN 2448
In: 1. Obergeschoss
Type - Material: IfcSurfaceStyle #1741
Type - Andere - Kategorie: Allgemeines Modell; Familienname: Stahlrohr nach DIN 2448 224992
Type - ID-Daten - Typname: Stahlrohr nach DIN 2448 224992
Type - IFC-Parameter - Typ in IFC-Datei exportieren: Vorgabe
Description: Stahlrohr nach DIN 2448
Pset_DistributionFlowElementCommon - Reference: Stahlrohr nach DIN 2448 224992; sets with these values: 2
Andere - Typ: Stahlrohr nach DIN 2448 224992; Familie: Stahlrohr nach DIN 2448 224992; Familie und Typ: Stahlrohr nach DIN 2448 224992: Stahlrohr nach DIN 2448 224992; Typ-ID: 2531943
Abhängigkeiten - Höhe von Ebene: 0 m; Verschieben mit umliegenden Elementen: no
Bemaßungen - Fläche: 1.14901 m2; Volumen: 0.132179 m3
IFC-Parameter - In IFC-Datei exportieren: Nach Typ; Pset MEP.Geom-DN: 200; Pset MEP.Tech-Insulation thickness (mm): 100; In IFC exportieren als: ifcflowsegment; NameOverride: Stahlrohr nach DIN 2448; IfcPresentationLayer: 0-TFT-H_Ruecklauf; ObjectTypeOverride: Stahlrohr nach DIN 2448; Pset MEP.Name: Stahlrohr nach DIN 2448; IfcDescription: Stahlrohr nach DIN 2448; Pset MEP.Geom-Outer Ø (mm): 219.1; Pset MEP.Tech-Material: Stahlrohr nach DIN 2448; Pset MEP.Geom-Length (mm): 1152
Phasen - Phase erstellt: Phase 01

# IfcFlowSegment: Stahlrohr nach DIN 2448 225273:Stahlrohr nach DIN 2448 225273, Stahlrohr nach DIN 2448
In: 1. Obergeschoss
Type - Material: IfcSurfaceStyle #1741
Type - Andere - Kategorie: Allgemeines Modell; Familienname: Stahlrohr nach DIN 2448 225273
Type - ID-Daten - Typname: Stahlrohr nach DIN 2448 225273
Type - IFC-Parameter - Typ in IFC-Datei exportieren: Vorgabe
Description: Stahlrohr nach DIN 2448
Pset_DistributionFlowElementCommon - Reference: Stahlrohr nach DIN 2448 225273; sets with these values: 2
Andere - Typ: Stahlrohr nach DIN 2448 225273; Familie: Stahlrohr nach DIN 2448 225273; Familie und Typ: Stahlrohr nach DIN 2448 225273: Stahlrohr nach DIN 2448 225273; Typ-ID: 2531950
Abhängigkeiten - Höhe von Ebene: 0 m; Verschieben mit umliegenden Elementen: no
Bemaßungen - Fläche: 1.15 m2; Volumen: 0.132294 m3
IFC-Parameter - In IFC-Datei exportieren: Nach Typ; Pset MEP.Geom-DN: 200; Pset MEP.Tech-Insulation thickness (mm): 100; In IFC exportieren als: ifcflowsegment; NameOverride: Stahlrohr nach DIN 2448; IfcPresentationLayer: 0-TFT-H_Ruecklauf; ObjectTypeOverride: Stahlrohr nach DIN 2448; Pset MEP.Name: Stahlrohr nach DIN 2448; IfcDescription: Stahlrohr nach DIN 2448; Pset MEP.Geom-Outer Ø (mm): 219.1; Pset MEP.Tech-Material: Stahlrohr nach DIN 2448; Pset MEP.Geom-Length (mm): 1153
Phasen - Phase erstellt: Phase 01

# IfcFlowSegment: Stahlrohr nach DIN 2448 225771:Stahlrohr nach DIN 2448 225771, Stahlrohr nach DIN 2448
In: 1. Obergeschoss
Type - Material: IfcSurfaceStyle #9317
Type - Andere - Kategorie: Allgemeines Modell; Familienname: Stahlrohr nach DIN 2448 225771
Type - ID-Daten - Typname: Stahlrohr nach DIN 2448 225771
Type - IFC-Parameter - Typ in IFC-Datei exportieren: Vorgabe
Description: Stahlrohr nach DIN 2448
Pset_DistributionFlowElementCommon - Reference: Stahlrohr nach DIN 2448 225771; sets with these values: 2
Andere - Typ: Stahlrohr nach DIN 2448 225771; Familie: Stahlrohr nach DIN 2448 225771; Familie und Typ: Stahlrohr nach DIN 2448 225771: Stahlrohr nach DIN 2448 225771; Typ-ID: 2531971
Abhängigkeiten - Höhe von Ebene: 0 m; Verschieben mit umliegenden Elementen: no
Bemaßungen - Fläche: 0.337923 m2; Volumen: 0.038874 m3
IFC-Parameter - In IFC-Datei exportieren: Nach Typ; Pset MEP.Geom-DN: 200; Pset MEP.Tech-Insulation thickness (mm): 100; In IFC exportieren als: ifcflowsegment; NameOverride: Stahlrohr nach DIN 2448; IfcPresentationLayer: 0-TFT-H_Vorlauf; ObjectTypeOverride: Stahlrohr nach DIN 2448; Pset MEP.Name: Stahlrohr nach DIN 2448; IfcDescription: Stahlrohr nach DIN 2448; Pset MEP.Geom-Outer Ø (mm): 219.1; Pset MEP.Tech-Material: Stahlrohr nach DIN 2448; Pset MEP.Geom-Length (mm): 338.804
Phasen - Phase erstellt: Phase 01

# IfcFlowSegment: Stahlrohr nach DIN 2448 226075:Stahlrohr nach DIN 2448 226075, Stahlrohr nach DIN 2448
In: 1. Obergeschoss
Type - Material: IfcSurfaceStyle #9317
Type - Andere - Kategorie: Allgemeines Modell; Familienname: Stahlrohr nach DIN 2448 226075
Type - ID-Daten - Typname: Stahlrohr nach DIN 2448 226075
Type - IFC-Parameter - Typ in IFC-Datei exportieren: Vorgabe
Description: Stahlrohr nach DIN 2448
Pset_DistributionFlowElementCommon - Reference: Stahlrohr nach DIN 2448 226075; sets with these values: 2
Andere - Typ: Stahlrohr nach DIN 2448 226075; Familie: Stahlrohr nach DIN 2448 226075; Familie und Typ: Stahlrohr nach DIN 2448 226075: Stahlrohr nach DIN 2448 226075; Typ-ID: 2531985
Abhängigkeiten - Höhe von Ebene: 0 m; Verschieben mit umliegenden Elementen: no
Bemaßungen - Fläche: 0.369432 m2; Volumen: 0.0424988 m3
IFC-Parameter - In IFC-Datei exportieren: Nach Typ; Pset MEP.Geom-DN: 200; Pset MEP.Tech-Insulation thickness (mm): 100; In IFC exportieren als: ifcflowsegment; NameOverride: Stahlrohr nach DIN 2448; IfcPresentationLayer: 0-TFT-H_Vorlauf; ObjectTypeOverride: Stahlrohr nach DIN 2448; Pset MEP.Name: Stahlrohr nach DIN 2448; IfcDescription: Stahlrohr nach DIN 2448; Pset MEP.Geom-Outer Ø (mm): 219.1; Pset MEP.Tech-Material: Stahlrohr nach DIN 2448; Pset MEP.Geom-Length (mm): 370.395
Phasen - Phase erstellt: Phase 01

# IfcFlowSegment: Stahlrohr nach DIN 2448 226379:Stahlrohr nach DIN 2448 226379, Stahlrohr nach DIN 2448
In: 1. Obergeschoss
Type - Material: IfcSurfaceStyle #9317
Type - Andere - Kategorie: Allgemeines Modell; Familienname: Stahlrohr nach DIN 2448 226379
Type - ID-Daten - Typname: Stahlrohr nach DIN 2448 226379
Type - IFC-Parameter - Typ in IFC-Datei exportieren: Vorgabe
Description: Stahlrohr nach DIN 2448
Pset_DistributionFlowElementCommon - Reference: Stahlrohr nach DIN 2448 226379; sets with these values: 2
Andere - Typ: Stahlrohr nach DIN 2448 226379; Familie: Stahlrohr nach DIN 2448 226379; Familie und Typ: Stahlrohr nach DIN 2448 226379: Stahlrohr nach DIN 2448 226379; Typ-ID: 2531999
Abhängigkeiten - Höhe von Ebene: 0 m; Verschieben mit umliegenden Elementen: no
Bemaßungen - Fläche: 0.381658 m2; Volumen: 0.0439052 m3
IFC-Parameter - In IFC-Datei exportieren: Nach Typ; Pset MEP.Geom-DN: 200; Pset MEP.Tech-Insulation thickness (mm): 100; In IFC exportieren als: ifcflowsegment; NameOverride: Stahlrohr nach DIN 2448; IfcPresentationLayer: 0-TFT-H_Vorlauf; ObjectTypeOverride: Stahlrohr nach DIN 2448; Pset MEP.Name: Stahlrohr nach DIN 2448; IfcDescription: Stahlrohr nach DIN 2448; Pset MEP.Geom-Outer Ø (mm): 219.1; Pset MEP.Tech-Material: Stahlrohr nach DIN 2448; Pset MEP.Geom-Length (mm): 382.653
Phasen - Phase erstellt: Phase 01

# IfcFlowSegment: Stahlrohr nach DIN 2448 226706:Stahlrohr nach DIN 2448 226706, Stahlrohr nach DIN 2448
In: 1. Obergeschoss
Type - Material: IfcSurfaceStyle #1741
Type - Andere - Kategorie: Allgemeines Modell; Familienname: Stahlrohr nach DIN 2448 226706
Type - ID-Daten - Typname: Stahlrohr nach DIN 2448 226706
Type - IFC-Parameter - Typ in IFC-Datei exportieren: Vorgabe
Description: Stahlrohr nach DIN 2448
Pset_DistributionFlowElementCommon - Reference: Stahlrohr nach DIN 2448 226706; sets with these values: 2
Andere - Typ: Stahlrohr nach DIN 2448 226706; Familie: Stahlrohr nach DIN 2448 226706; Familie und Typ: Stahlrohr nach DIN 2448 226706: Stahlrohr nach DIN 2448 226706; Typ-ID: 2532020
Abhängigkeiten - Höhe von Ebene: 0 m; Verschieben mit umliegenden Elementen: no
Bemaßungen - Fläche: 0.337923 m2; Volumen: 0.038874 m3
IFC-Parameter - In IFC-Datei exportieren: Nach Typ; Pset MEP.Geom-DN: 200; Pset MEP.Tech-Insulation thickness (mm): 100; In IFC exportieren als: ifcflowsegment; NameOverride: Stahlrohr nach DIN 2448; IfcPresentationLayer: 0-TFT-H_Ruecklauf; ObjectTypeOverride: Stahlrohr nach DIN 2448; Pset MEP.Name: Stahlrohr nach DIN 2448; IfcDescription: Stahlrohr nach DIN 2448; Pset MEP.Geom-Outer Ø (mm): 219.1; Pset MEP.Tech-Material: Stahlrohr nach DIN 2448; Pset MEP.Geom-Length (mm): 338.804
Phasen - Phase erstellt: Phase 01

# IfcFlowSegment: Stahlrohr nach DIN 2448 226752:Stahlrohr nach DIN 2448 226752, Stahlrohr nach DIN 2448
In: 1. Obergeschoss
Type - Material: IfcSurfaceStyle #1741
Type - Andere - Kategorie: Allgemeines Modell; Familienname: Stahlrohr nach DIN 2448 226752
Type - ID-Daten - Typname: Stahlrohr nach DIN 2448 226752
Type - IFC-Parameter - Typ in IFC-Datei exportieren: Vorgabe
Description: Stahlrohr nach DIN 2448
Pset_DistributionFlowElementCommon - Reference: Stahlrohr nach DIN 2448 226752; sets with these values: 2
Andere - Typ: Stahlrohr nach DIN 2448 226752; Familie: Stahlrohr nach DIN 2448 226752; Familie und Typ: Stahlrohr nach DIN 2448 226752: Stahlrohr nach DIN 2448 226752; Typ-ID: 2532034
Abhängigkeiten - Höhe von Ebene: 0 m; Verschieben mit umliegenden Elementen: no
Bemaßungen - Fläche: 0.369432 m2; Volumen: 0.0424988 m3
IFC-Parameter - In IFC-Datei exportieren: Nach Typ; Pset MEP.Geom-DN: 200; Pset MEP.Tech-Insulation thickness (mm): 100; In IFC exportieren als: ifcflowsegment; NameOverride: Stahlrohr nach DIN 2448; IfcPresentationLayer: 0-TFT-H_Ruecklauf; ObjectTypeOverride: Stahlrohr nach DIN 2448; Pset MEP.Name: Stahlrohr nach DIN 2448; IfcDescription: Stahlrohr nach DIN 2448; Pset MEP.Geom-Outer Ø (mm): 219.1; Pset MEP.Tech-Material: Stahlrohr nach DIN 2448; Pset MEP.Geom-Length (mm): 370.395
Phasen - Phase erstellt: Phase 01

# IfcFlowSegment: Stahlrohr nach DIN 2448 226798:Stahlrohr nach DIN 2448 226798, Stahlrohr nach DIN 2448
In: 1. Obergeschoss
Type - Material: IfcSurfaceStyle #1741
Type - Andere - Kategorie: Allgemeines Modell; Familienname: Stahlrohr nach DIN 2448 226798
Type - ID-Daten - Typname: Stahlrohr nach DIN 2448 226798
Type - IFC-Parameter - Typ in IFC-Datei exportieren: Vorgabe
Description: Stahlrohr nach DIN 2448
Pset_DistributionFlowElementCommon - Reference: Stahlrohr nach DIN 2448 226798; sets with these values: 2
Andere - Typ: Stahlrohr nach DIN 2448 226798; Familie: Stahlrohr nach DIN 2448 226798; Familie und Typ: Stahlrohr nach DIN 2448 226798: Stahlrohr nach DIN 2448 226798; Typ-ID: 2532048
Abhängigkeiten - Höhe von Ebene: 0 m; Verschieben mit umliegenden Elementen: no
Bemaßungen - Fläche: 0.381658 m2; Volumen: 0.0439052 m3
IFC-Parameter - In IFC-Datei exportieren: Nach Typ; Pset MEP.Geom-DN: 200; Pset MEP.Tech-Insulation thickness (mm): 100; In IFC exportieren als: ifcflowsegment; NameOverride: Stahlrohr nach DIN 2448; IfcPresentationLayer: 0-TFT-H_Ruecklauf; ObjectTypeOverride: Stahlrohr nach DIN 2448; Pset MEP.Name: Stahlrohr nach DIN 2448; IfcDescription: Stahlrohr nach DIN 2448; Pset MEP.Geom-Outer Ø (mm): 219.1; Pset MEP.Tech-Material: Stahlrohr nach DIN 2448; Pset MEP.Geom-Length (mm): 382.653
Phasen - Phase erstellt: Phase 01

# IfcFlowSegment: Stahlrohr nach DIN 2448 226931:Stahlrohr nach DIN 2448 226931, Stahlrohr nach DIN 2448
In: 1. Obergeschoss
Type - Material: IfcSurfaceStyle #9317
Type - Andere - Kategorie: Allgemeines Modell; Familienname: Stahlrohr nach DIN 2448 226931
Type - ID-Daten - Typname: Stahlrohr nach DIN 2448 226931
Type - IFC-Parameter - Typ in IFC-Datei exportieren: Vorgabe
Description: Stahlrohr nach DIN 2448
Pset_DistributionFlowElementCommon - Reference: Stahlrohr nach DIN 2448 226931; sets with these values: 2
Andere - Typ: Stahlrohr nach DIN 2448 226931; Familie: Stahlrohr nach DIN 2448 226931; Familie und Typ: Stahlrohr nach DIN 2448 226931: Stahlrohr nach DIN 2448 226931; Typ-ID: 2532083
Abhängigkeiten - Höhe von Ebene: 0 m; Verschieben mit umliegenden Elementen: no
Bemaßungen - Fläche: 4.78355 m2; Volumen: 0.55029 m3
IFC-Parameter - In IFC-Datei exportieren: Nach Typ; Pset MEP.Geom-DN: 200; Pset MEP.Tech-Insulation thickness (mm): 100; In IFC exportieren als: ifcflowsegment; NameOverride: Stahlrohr nach DIN 2448; IfcPresentationLayer: 0-TFT-H_Vorlauf; ObjectTypeOverride: Stahlrohr nach DIN 2448; Pset MEP.Name: Stahlrohr nach DIN 2448; IfcDescription: Stahlrohr nach DIN 2448; Pset MEP.Geom-Outer Ø (mm): 219.1; Pset MEP.Tech-Material: Stahlrohr nach DIN 2448; Pset MEP.Geom-Length (mm): 4796.02
Phasen - Phase erstellt: Phase 01

# IfcFlowSegment: Stahlrohr nach DIN 2448 227266:Stahlrohr nach DIN 2448 227266, Stahlrohr nach DIN 2448
In: 1. Obergeschoss
Type - Material: IfcSurfaceStyle #1741
Type - Andere - Kategorie: Allgemeines Modell; Familienname: Stahlrohr nach DIN 2448 227266
Type - ID-Daten - Typname: Stahlrohr nach DIN 2448 227266
Type - IFC-Parameter - Typ in IFC-Datei exportieren: Vorgabe
Description: Stahlrohr nach DIN 2448
Pset_DistributionFlowElementCommon - Reference: Stahlrohr nach DIN 2448 227266; sets with these values: 2
Andere - Typ: Stahlrohr nach DIN 2448 227266; Familie: Stahlrohr nach DIN 2448 227266; Familie und Typ: Stahlrohr nach DIN 2448 227266: Stahlrohr nach DIN 2448 227266; Typ-ID: 2532104
Abhängigkeiten - Höhe von Ebene: 0 m; Verschieben mit umliegenden Elementen: no
Bemaßungen - Fläche: 3.21944 m2; Volumen: 0.370358 m3
IFC-Parameter - In IFC-Datei exportieren: Nach Typ; Pset MEP.Geom-DN: 200; Pset MEP.Tech-Insulation thickness (mm): 100; In IFC exportieren als: ifcflowsegment; NameOverride: Stahlrohr nach DIN 2448; IfcPresentationLayer: 0-TFT-H_Ruecklauf; ObjectTypeOverride: Stahlrohr nach DIN 2448; Pset MEP.Name: Stahlrohr nach DIN 2448; IfcDescription: Stahlrohr nach DIN 2448; Pset MEP.Geom-Outer Ø (mm): 219.1; Pset MEP.Tech-Material: Stahlrohr nach DIN 2448; Pset MEP.Geom-Length (mm): 3227.83
Phasen - Phase erstellt: Phase 01

# IfcFlowSegment: Stahlrohr nach DIN 2448 227547:Stahlrohr nach DIN 2448 227547, Stahlrohr nach DIN 2448
In: 1. Obergeschoss
Type - Material: IfcSurfaceStyle #1741
Type - Andere - Kategorie: Allgemeines Modell; Familienname: Stahlrohr nach DIN 2448 227547
Type - ID-Daten - Typname: Stahlrohr nach DIN 2448 227547
Type - IFC-Parameter - Typ in IFC-Datei exportieren: Vorgabe
Description: Stahlrohr nach DIN 2448
Pset_DistributionFlowElementCommon - Reference: Stahlrohr nach DIN 2448 227547; sets with these values: 2
Andere - Typ: Stahlrohr nach DIN 2448 227547; Familie: Stahlrohr nach DIN 2448 227547; Familie und Typ: Stahlrohr nach DIN 2448 227547: Stahlrohr nach DIN 2448 227547; Typ-ID: 2532111
Abhängigkeiten - Höhe von Ebene: 0 m; Verschieben mit umliegenden Elementen: no
Bemaßungen - Fläche: 2.18159 m2; Volumen: 0.250966 m3
IFC-Parameter - In IFC-Datei exportieren: Nach Typ; Pset MEP.Geom-DN: 200; Pset MEP.Tech-Insulation thickness (mm): 100; In IFC exportieren als: ifcflowsegment; NameOverride: Stahlrohr nach DIN 2448; IfcPresentationLayer: 0-TFT-H_Ruecklauf; ObjectTypeOverride: Stahlrohr nach DIN 2448; Pset MEP.Name: Stahlrohr nach DIN 2448; IfcDescription: Stahlrohr nach DIN 2448; Pset MEP.Geom-Outer Ø (mm): 219.1; Pset MEP.Tech-Material: Stahlrohr nach DIN 2448; Pset MEP.Geom-Length (mm): 2187.28
Phasen - Phase erstellt: Phase 01

# IfcFlowSegment: Stahlrohr nach DIN 2448 227828:Stahlrohr nach DIN 2448 227828, Stahlrohr nach DIN 2448
In: 1. Obergeschoss
Type - Material: IfcSurfaceStyle #9317
Type - Andere - Kategorie: Allgemeines Modell; Familienname: Stahlrohr nach DIN 2448 227828
Type - ID-Daten - Typname: Stahlrohr nach DIN 2448 227828
Type - IFC-Parameter - Typ in IFC-Datei exportieren: Vorgabe
Description: Stahlrohr nach DIN 2448
Pset_DistributionFlowElementCommon - Reference: Stahlrohr nach DIN 2448 227828; sets with these values: 2
Andere - Typ: Stahlrohr nach DIN 2448 227828; Familie: Stahlrohr nach DIN 2448 227828; Familie und Typ: Stahlrohr nach DIN 2448 227828: Stahlrohr nach DIN 2448 227828; Typ-ID: 2532118
Abhängigkeiten - Höhe von Ebene: 0 m; Verschieben mit umliegenden Elementen: no
Bemaßungen - Fläche: 3.04471 m2; Volumen: 0.260829 m3
IFC-Parameter - In IFC-Datei exportieren: Nach Typ; Pset MEP.Tech-Insulation thickness (mm): 100; Pset MEP.Geom-DN: 100; In IFC exportieren als: ifcflowsegment; NameOverride: Stahlrohr nach DIN 2448; IfcPresentationLayer: 0-TFT-H_Vorlauf; ObjectTypeOverride: Stahlrohr nach DIN 2448; Pset MEP.Name: Stahlrohr nach DIN 2448; IfcDescription: Stahlrohr nach DIN 2448; Pset MEP.Geom-Outer Ø (mm): 114.3; Pset MEP.Tech-Material: Stahlrohr nach DIN 2448; Pset MEP.Geom-Length (mm): 4545.49
Phasen - Phase erstellt: Phase 01

# IfcFlowSegment: Stahlrohr nach DIN 2448 228109:Stahlrohr nach DIN 2448 228109, Stahlrohr nach DIN 2448
In: 1. Obergeschoss
Type - Material: IfcSurfaceStyle #1741
Type - Andere - Kategorie: Allgemeines Modell; Familienname: Stahlrohr nach DIN 2448 228109
Type - ID-Daten - Typname: Stahlrohr nach DIN 2448 228109
Type - IFC-Parameter - Typ in IFC-Datei exportieren: Vorgabe
Description: Stahlrohr nach DIN 2448
Pset_DistributionFlowElementCommon - Reference: Stahlrohr nach DIN 2448 228109; sets with these values: 2
Andere - Typ: Stahlrohr nach DIN 2448 228109; Familie: Stahlrohr nach DIN 2448 228109; Familie und Typ: Stahlrohr nach DIN 2448 228109: Stahlrohr nach DIN 2448 228109; Typ-ID: 2532125
Abhängigkeiten - Höhe von Ebene: 0 m; Verschieben mit umliegenden Elementen: no
Bemaßungen - Fläche: 3.43974 m2; Volumen: 0.29467 m3
IFC-Parameter - In IFC-Datei exportieren: Nach Typ; Pset MEP.Tech-Insulation thickness (mm): 100; Pset MEP.Geom-DN: 100; In IFC exportieren als: ifcflowsegment; NameOverride: Stahlrohr nach DIN 2448; IfcPresentationLayer: 0-TFT-H_Ruecklauf; ObjectTypeOverride: Stahlrohr nach DIN 2448; Pset MEP.Name: Stahlrohr nach DIN 2448; IfcDescription: Stahlrohr nach DIN 2448; Pset MEP.Geom-Outer Ø (mm): 114.3; Pset MEP.Tech-Material: Stahlrohr nach DIN 2448; Pset MEP.Geom-Length (mm): 5135.24
Phasen - Phase erstellt: Phase 01

# IfcFlowSegment: Stahlrohr nach DIN 2448 228568:Stahlrohr nach DIN 2448 228568, Stahlrohr nach DIN 2448
In: 1. Obergeschoss
Type - Material: IfcSurfaceStyle #9317
Type - Andere - Kategorie: Allgemeines Modell; Familienname: Stahlrohr nach DIN 2448 228568
Type - ID-Daten - Typname: Stahlrohr nach DIN 2448 228568
Type - IFC-Parameter - Typ in IFC-Datei exportieren: Vorgabe
Description: Stahlrohr nach DIN 2448
Pset_DistributionFlowElementCommon - Reference: Stahlrohr nach DIN 2448 228568; sets with these values: 2
Andere - Typ: Stahlrohr nach DIN 2448 228568; Familie: Stahlrohr nach DIN 2448 228568; Familie und Typ: Stahlrohr nach DIN 2448 228568: Stahlrohr nach DIN 2448 228568; Typ-ID: 2532172
Abhängigkeiten - Höhe von Ebene: 0 m; Verschieben mit umliegenden Elementen: no
Bemaßungen - Fläche: 0.147338 m2; Volumen: 0.0169495 m3
IFC-Parameter - In IFC-Datei exportieren: Nach Typ; Pset MEP.Geom-DN: 200; Pset MEP.Tech-Insulation thickness (mm): 100; In IFC exportieren als: ifcflowsegment; NameOverride: Stahlrohr nach DIN 2448; IfcPresentationLayer: 0-TFT-H_Vorlauf; ObjectTypeOverride: Stahlrohr nach DIN 2448; Pset MEP.Name: Stahlrohr nach DIN 2448; IfcDescription: Stahlrohr nach DIN 2448; Pset MEP.Geom-Outer Ø (mm): 219.1; Pset MEP.Tech-Material: Stahlrohr nach DIN 2448; Pset MEP.Geom-Length (mm): 147.722
Phasen - Phase erstellt: Phase 01

# IfcFlowSegment: Stahlrohr nach DIN 2448 231212:Stahlrohr nach DIN 2448 231212, Stahlrohr nach DIN 2448
In: 1. Obergeschoss
Type - Material: IfcSurfaceStyle #9317
Type - Andere - Kategorie: Allgemeines Modell; Familienname: Stahlrohr nach DIN 2448 231212
Type - ID-Daten - Typname: Stahlrohr nach DIN 2448 231212
Type - IFC-Parameter - Typ in IFC-Datei exportieren: Vorgabe
Description: Stahlrohr nach DIN 2448
Pset_DistributionFlowElementCommon - Reference: Stahlrohr nach DIN 2448 231212; sets with these values: 2
Andere - Typ: Stahlrohr nach DIN 2448 231212; Familie: Stahlrohr nach DIN 2448 231212; Familie und Typ: Stahlrohr nach DIN 2448 231212: Stahlrohr nach DIN 2448 231212; Typ-ID: 2532193
Abhängigkeiten - Höhe von Ebene: 0 m; Verschieben mit umliegenden Elementen: no
Bemaßungen - Fläche: 0.0389596 m2; Volumen: 0.00359913 m3
IFC-Parameter - In IFC-Datei exportieren: Nach Typ; Pset MEP.Tech-Insulation thickness (mm): 100; In IFC exportieren als: ifcflowsegment; NameOverride: Stahlrohr nach DIN 2448; IfcPresentationLayer: 0-TFT-H_Vorlauf; ObjectTypeOverride: Stahlrohr nach DIN 2448; Pset MEP.Name: Stahlrohr nach DIN 2448; IfcDescription: Stahlrohr nach DIN 2448; Pset MEP.Geom-DN: 125; Pset MEP.Geom-Outer Ø (mm): 139.7; Pset MEP.Tech-Material: Stahlrohr nach DIN 2448; Pset MEP.Geom-Length (mm): 52
Phasen - Phase erstellt: Phase 01

# IfcFlowSegment: Stahlrohr nach DIN 2448 233182:Stahlrohr nach DIN 2448 233182, Stahlrohr nach DIN 2448
In: 1. Obergeschoss
Type - Material: IfcSurfaceStyle #9317
Type - Andere - Kategorie: Allgemeines Modell; Familienname: Stahlrohr nach DIN 2448 233182
Type - ID-Daten - Typname: Stahlrohr nach DIN 2448 233182
Type - IFC-Parameter - Typ in IFC-Datei exportieren: Vorgabe
Description: Stahlrohr nach DIN 2448
Pset_DistributionFlowElementCommon - Reference: Stahlrohr nach DIN 2448 233182; sets with these values: 2
Andere - Typ: Stahlrohr nach DIN 2448 233182; Familie: Stahlrohr nach DIN 2448 233182; Familie und Typ: Stahlrohr nach DIN 2448 233182: Stahlrohr nach DIN 2448 233182; Typ-ID: 2532207
Abhängigkeiten - Höhe von Ebene: 0 m; Verschieben mit umliegenden Elementen: no
Bemaßungen - Fläche: 0.453218 m2; Volumen: 0.0418688 m3
IFC-Parameter - In IFC-Datei exportieren: Nach Typ; Pset MEP.Tech-Insulation thickness (mm): 100; Pset MEP.Geom-DN: 125; In IFC exportieren als: ifcflowsegment; NameOverride: Stahlrohr nach DIN 2448; IfcPresentationLayer: 0-TFT-H_Vorlauf; ObjectTypeOverride: Stahlrohr nach DIN 2448; Pset MEP.Name: Stahlrohr nach DIN 2448; IfcDescription: Stahlrohr nach DIN 2448; Pset MEP.Geom-Outer Ø (mm): 139.7; Pset MEP.Tech-Material: Stahlrohr nach DIN 2448; Pset MEP.Geom-Length (mm): 604.917
Phasen - Phase erstellt: Phase 01

# IfcFlowSegment: Stahlrohr nach DIN 2448 235723:Stahlrohr nach DIN 2448 235723, Stahlrohr nach DIN 2448
In: 1. Obergeschoss
Type - Material: IfcSurfaceStyle #9317
Type - Andere - Kategorie: Allgemeines Modell; Familienname: Stahlrohr nach DIN 2448 235723
Type - ID-Daten - Typname: Stahlrohr nach DIN 2448 235723
Type - IFC-Parameter - Typ in IFC-Datei exportieren: Vorgabe
Description: Stahlrohr nach DIN 2448
Pset_DistributionFlowElementCommon - Reference: Stahlrohr nach DIN 2448 235723; sets with these values: 2
Andere - Typ: Stahlrohr nach DIN 2448 235723; Familie: Stahlrohr nach DIN 2448 235723; Familie und Typ: Stahlrohr nach DIN 2448 235723: Stahlrohr nach DIN 2448 235723; Typ-ID: 2532242
Abhängigkeiten - Höhe von Ebene: 0 m; Verschieben mit umliegenden Elementen: no
Bemaßungen - Fläche: 0.00942146 m2; Volumen: 0.000945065 m3
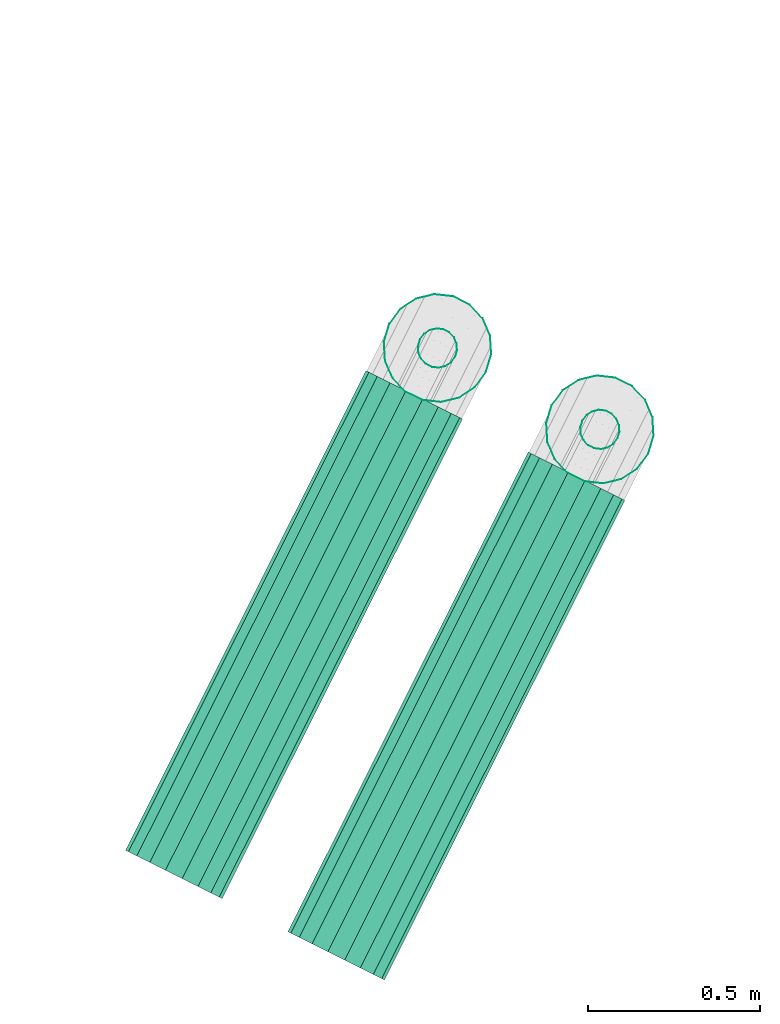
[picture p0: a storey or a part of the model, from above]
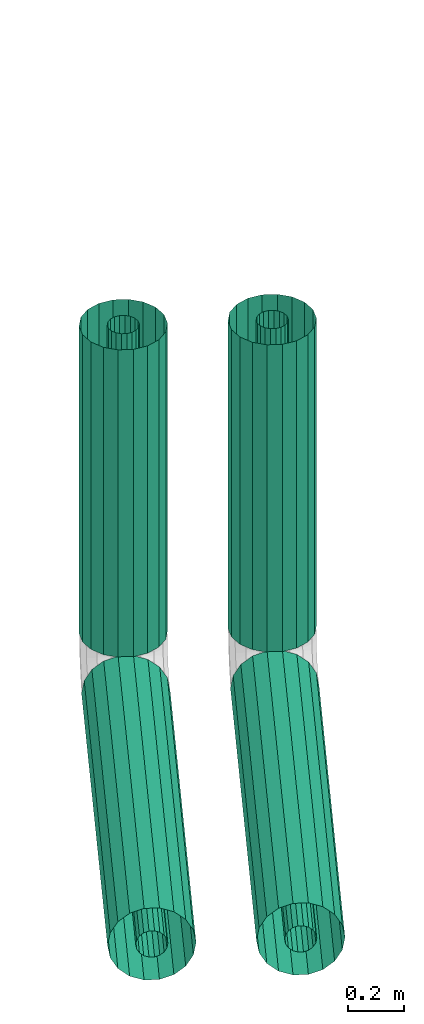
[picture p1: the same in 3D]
Properties of the parts of a building model (IFC2X3), part 17 of 23

# IfcFlowSegment: Stahlrohr nach DIN 2448 235723:Stahlrohr nach DIN 2448 235723, Stahlrohr nach DIN 2448
IFC-Parameter - In IFC-Datei exportieren: Nach Typ; Pset MEP.Tech-Insulation thickness (mm): 100; Pset MEP.Geom-DN: 150; In IFC exportieren als: ifcflowsegment; NameOverride: Stahlrohr nach DIN 2448; IfcPresentationLayer: 0-TFT-H_Vorlauf; ObjectTypeOverride: Stahlrohr nach DIN 2448; Pset MEP.Name: Stahlrohr nach DIN 2448; IfcDescription: Stahlrohr nach DIN 2448; Pset MEP.Geom-Outer Ø (mm): 168.3; Pset MEP.Tech-Material: Stahlrohr nach DIN 2448; Pset MEP.Geom-Length (mm): 11.2345
Phasen - Phase erstellt: Phase 01

# IfcFlowSegment: Stahlrohr nach DIN 2448 236817:Stahlrohr nach DIN 2448 236817, Stahlrohr nach DIN 2448
In: 1. Obergeschoss
Type - Material: IfcSurfaceStyle #9317
Type - Andere - Kategorie: Allgemeines Modell; Familienname: Stahlrohr nach DIN 2448 236817
Type - ID-Daten - Typname: Stahlrohr nach DIN 2448 236817
Type - IFC-Parameter - Typ in IFC-Datei exportieren: Vorgabe
Description: Stahlrohr nach DIN 2448
Pset_DistributionFlowElementCommon - Reference: Stahlrohr nach DIN 2448 236817; sets with these values: 2
Andere - Typ: Stahlrohr nach DIN 2448 236817; Familie: Stahlrohr nach DIN 2448 236817; Familie und Typ: Stahlrohr nach DIN 2448 236817: Stahlrohr nach DIN 2448 236817; Typ-ID: 2532270
Abhängigkeiten - Höhe von Ebene: 0 m; Verschieben mit umliegenden Elementen: no
Bemaßungen - Fläche: 0.0389596 m2; Volumen: 0.00359913 m3
IFC-Parameter - In IFC-Datei exportieren: Nach Typ; Pset MEP.Tech-Insulation thickness (mm): 100; Pset MEP.Geom-DN: 125; Pset MEP.Geom-Length (mm): 52; In IFC exportieren als: ifcflowsegment; NameOverride: Stahlrohr nach DIN 2448; IfcPresentationLayer: 0-TFT-H_Vorlauf; ObjectTypeOverride: Stahlrohr nach DIN 2448; Pset MEP.Name: Stahlrohr nach DIN 2448; IfcDescription: Stahlrohr nach DIN 2448; Pset MEP.Geom-Outer Ø (mm): 139.7; Pset MEP.Tech-Material: Stahlrohr nach DIN 2448
Phasen - Phase erstellt: Phase 01

# IfcFlowSegment: Stahlrohr nach DIN 2448 236863:Stahlrohr nach DIN 2448 236863, Stahlrohr nach DIN 2448
In: 1. Obergeschoss
Type - Material: IfcSurfaceStyle #9317
Type - Andere - Kategorie: Allgemeines Modell; Familienname: Stahlrohr nach DIN 2448 236863
Type - ID-Daten - Typname: Stahlrohr nach DIN 2448 236863
Type - IFC-Parameter - Typ in IFC-Datei exportieren: Vorgabe
Description: Stahlrohr nach DIN 2448
Pset_DistributionFlowElementCommon - Reference: Stahlrohr nach DIN 2448 236863; sets with these values: 2
Andere - Typ: Stahlrohr nach DIN 2448 236863; Familie: Stahlrohr nach DIN 2448 236863; Familie und Typ: Stahlrohr nach DIN 2448 236863: Stahlrohr nach DIN 2448 236863; Typ-ID: 2532284
Abhängigkeiten - Höhe von Ebene: 0 m; Verschieben mit umliegenden Elementen: no
Bemaßungen - Fläche: 0.453218 m2; Volumen: 0.0418688 m3
IFC-Parameter - In IFC-Datei exportieren: Nach Typ; Pset MEP.Tech-Insulation thickness (mm): 100; Pset MEP.Geom-DN: 125; In IFC exportieren als: ifcflowsegment; NameOverride: Stahlrohr nach DIN 2448; IfcPresentationLayer: 0-TFT-H_Vorlauf; ObjectTypeOverride: Stahlrohr nach DIN 2448; Pset MEP.Name: Stahlrohr nach DIN 2448; IfcDescription: Stahlrohr nach DIN 2448; Pset MEP.Geom-Outer Ø (mm): 139.7; Pset MEP.Tech-Material: Stahlrohr nach DIN 2448; Pset MEP.Geom-Length (mm): 604.917
Phasen - Phase erstellt: Phase 01

# IfcFlowSegment: Stahlrohr nach DIN 2448 236978:Stahlrohr nach DIN 2448 236978, Stahlrohr nach DIN 2448
In: 1. Obergeschoss
Type - Material: IfcSurfaceStyle #9317
Type - Andere - Kategorie: Allgemeines Modell; Familienname: Stahlrohr nach DIN 2448 236978
Type - ID-Daten - Typname: Stahlrohr nach DIN 2448 236978
Type - IFC-Parameter - Typ in IFC-Datei exportieren: Vorgabe
Description: Stahlrohr nach DIN 2448
Pset_DistributionFlowElementCommon - Reference: Stahlrohr nach DIN 2448 236978; sets with these values: 2
Andere - Typ: Stahlrohr nach DIN 2448 236978; Familie: Stahlrohr nach DIN 2448 236978; Familie und Typ: Stahlrohr nach DIN 2448 236978: Stahlrohr nach DIN 2448 236978; Typ-ID: 2532319
Abhängigkeiten - Höhe von Ebene: 0 m; Verschieben mit umliegenden Elementen: no
Bemaßungen - Fläche: 0.00942146 m2; Volumen: 0.000945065 m3
IFC-Parameter - In IFC-Datei exportieren: Nach Typ; Pset MEP.Tech-Insulation thickness (mm): 100; Pset MEP.Geom-DN: 150; In IFC exportieren als: ifcflowsegment; NameOverride: Stahlrohr nach DIN 2448; IfcPresentationLayer: 0-TFT-H_Vorlauf; ObjectTypeOverride: Stahlrohr nach DIN 2448; Pset MEP.Name: Stahlrohr nach DIN 2448; IfcDescription: Stahlrohr nach DIN 2448; Pset MEP.Geom-Outer Ø (mm): 168.3; Pset MEP.Tech-Material: Stahlrohr nach DIN 2448; Pset MEP.Geom-Length (mm): 11.2345
Phasen - Phase erstellt: Phase 01

# IfcFlowSegment: Stahlrohr nach DIN 2448 237070:Stahlrohr nach DIN 2448 237070, Stahlrohr nach DIN 2448
In: 1. Obergeschoss
Type - Material: IfcSurfaceStyle #9317
Type - Andere - Kategorie: Allgemeines Modell; Familienname: Stahlrohr nach DIN 2448 237070
Type - ID-Daten - Typname: Stahlrohr nach DIN 2448 237070
Type - IFC-Parameter - Typ in IFC-Datei exportieren: Vorgabe
Description: Stahlrohr nach DIN 2448
Pset_DistributionFlowElementCommon - Reference: Stahlrohr nach DIN 2448 237070; sets with these values: 2
Andere - Typ: Stahlrohr nach DIN 2448 237070; Familie: Stahlrohr nach DIN 2448 237070; Familie und Typ: Stahlrohr nach DIN 2448 237070: Stahlrohr nach DIN 2448 237070; Typ-ID: 2532347
Abhängigkeiten - Höhe von Ebene: 0 m; Verschieben mit umliegenden Elementen: no
Bemaßungen - Fläche: 0.0389596 m2; Volumen: 0.00359913 m3
IFC-Parameter - In IFC-Datei exportieren: Nach Typ; Pset MEP.Tech-Insulation thickness (mm): 100; Pset MEP.Geom-DN: 125; Pset MEP.Geom-Length (mm): 52; In IFC exportieren als: ifcflowsegment; NameOverride: Stahlrohr nach DIN 2448; IfcPresentationLayer: 0-TFT-H_Vorlauf; ObjectTypeOverride: Stahlrohr nach DIN 2448; Pset MEP.Name: Stahlrohr nach DIN 2448; IfcDescription: Stahlrohr nach DIN 2448; Pset MEP.Geom-Outer Ø (mm): 139.7; Pset MEP.Tech-Material: Stahlrohr nach DIN 2448
Phasen - Phase erstellt: Phase 01

# IfcFlowSegment: Stahlrohr nach DIN 2448 237116:Stahlrohr nach DIN 2448 237116, Stahlrohr nach DIN 2448
In: 1. Obergeschoss
Type - Material: IfcSurfaceStyle #9317
Type - Andere - Kategorie: Allgemeines Modell; Familienname: Stahlrohr nach DIN 2448 237116
Type - ID-Daten - Typname: Stahlrohr nach DIN 2448 237116
Type - IFC-Parameter - Typ in IFC-Datei exportieren: Vorgabe
Description: Stahlrohr nach DIN 2448
Pset_DistributionFlowElementCommon - Reference: Stahlrohr nach DIN 2448 237116; sets with these values: 2
Andere - Typ: Stahlrohr nach DIN 2448 237116; Familie: Stahlrohr nach DIN 2448 237116; Familie und Typ: Stahlrohr nach DIN 2448 237116: Stahlrohr nach DIN 2448 237116; Typ-ID: 2532361
Abhängigkeiten - Höhe von Ebene: 0 m; Verschieben mit umliegenden Elementen: no
Bemaßungen - Fläche: 0.453218 m2; Volumen: 0.0418688 m3
IFC-Parameter - In IFC-Datei exportieren: Nach Typ; Pset MEP.Tech-Insulation thickness (mm): 100; Pset MEP.Geom-DN: 125; In IFC exportieren als: ifcflowsegment; NameOverride: Stahlrohr nach DIN 2448; IfcPresentationLayer: 0-TFT-H_Vorlauf; ObjectTypeOverride: Stahlrohr nach DIN 2448; Pset MEP.Name: Stahlrohr nach DIN 2448; IfcDescription: Stahlrohr nach DIN 2448; Pset MEP.Geom-Outer Ø (mm): 139.7; Pset MEP.Tech-Material: Stahlrohr nach DIN 2448; Pset MEP.Geom-Length (mm): 604.917
Phasen - Phase erstellt: Phase 01

# IfcFlowSegment: Stahlrohr nach DIN 2448 237231:Stahlrohr nach DIN 2448 237231, Stahlrohr nach DIN 2448
In: 1. Obergeschoss
Type - Material: IfcSurfaceStyle #9317
Type - Andere - Kategorie: Allgemeines Modell; Familienname: Stahlrohr nach DIN 2448 237231
Type - ID-Daten - Typname: Stahlrohr nach DIN 2448 237231
Type - IFC-Parameter - Typ in IFC-Datei exportieren: Vorgabe
Description: Stahlrohr nach DIN 2448
Pset_DistributionFlowElementCommon - Reference: Stahlrohr nach DIN 2448 237231; sets with these values: 2
Andere - Typ: Stahlrohr nach DIN 2448 237231; Familie: Stahlrohr nach DIN 2448 237231; Familie und Typ: Stahlrohr nach DIN 2448 237231: Stahlrohr nach DIN 2448 237231; Typ-ID: 2532396
Abhängigkeiten - Höhe von Ebene: 0 m; Verschieben mit umliegenden Elementen: no
Bemaßungen - Fläche: 0.00942146 m2; Volumen: 0.000945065 m3
IFC-Parameter - In IFC-Datei exportieren: Nach Typ; Pset MEP.Tech-Insulation thickness (mm): 100; Pset MEP.Geom-DN: 150; In IFC exportieren als: ifcflowsegment; NameOverride: Stahlrohr nach DIN 2448; IfcPresentationLayer: 0-TFT-H_Vorlauf; ObjectTypeOverride: Stahlrohr nach DIN 2448; Pset MEP.Name: Stahlrohr nach DIN 2448; IfcDescription: Stahlrohr nach DIN 2448; Pset MEP.Geom-Outer Ø (mm): 168.3; Pset MEP.Tech-Material: Stahlrohr nach DIN 2448; Pset MEP.Geom-Length (mm): 11.2345
Phasen - Phase erstellt: Phase 01

# IfcFlowSegment: Stahlrohr nach DIN 2448 237277:Stahlrohr nach DIN 2448 237277, Stahlrohr nach DIN 2448
In: 1. Obergeschoss
Type - Material: IfcSurfaceStyle #9317
Type - Andere - Kategorie: Allgemeines Modell; Familienname: Stahlrohr nach DIN 2448 237277
Type - ID-Daten - Typname: Stahlrohr nach DIN 2448 237277
Type - IFC-Parameter - Typ in IFC-Datei exportieren: Vorgabe
Description: Stahlrohr nach DIN 2448
Pset_DistributionFlowElementCommon - Reference: Stahlrohr nach DIN 2448 237277; sets with these values: 2
Andere - Typ: Stahlrohr nach DIN 2448 237277; Familie: Stahlrohr nach DIN 2448 237277; Familie und Typ: Stahlrohr nach DIN 2448 237277: Stahlrohr nach DIN 2448 237277; Typ-ID: 2532410
Abhängigkeiten - Höhe von Ebene: 0 m; Verschieben mit umliegenden Elementen: no
Bemaßungen - Fläche: 0.0385764 m2; Volumen: 0.00386959 m3
IFC-Parameter - In IFC-Datei exportieren: Nach Typ; Pset MEP.Tech-Insulation thickness (mm): 100; Pset MEP.Geom-DN: 150; In IFC exportieren als: ifcflowsegment; NameOverride: Stahlrohr nach DIN 2448; IfcPresentationLayer: 0-TFT-H_Vorlauf; ObjectTypeOverride: Stahlrohr nach DIN 2448; Pset MEP.Name: Stahlrohr nach DIN 2448; IfcDescription: Stahlrohr nach DIN 2448; Pset MEP.Geom-Outer Ø (mm): 168.3; Pset MEP.Tech-Material: Stahlrohr nach DIN 2448; Pset MEP.Geom-Length (mm): 46
Phasen - Phase erstellt: Phase 01

# IfcFlowSegment: Stahlrohr nach DIN 2448 238323:Stahlrohr nach DIN 2448 238323, Stahlrohr nach DIN 2448
In: 1. Obergeschoss
Type - Material: IfcSurfaceStyle #9317
Type - Andere - Kategorie: Allgemeines Modell; Familienname: Stahlrohr nach DIN 2448 238323
Type - ID-Daten - Typname: Stahlrohr nach DIN 2448 238323
Type - IFC-Parameter - Typ in IFC-Datei exportieren: Vorgabe
Description: Stahlrohr nach DIN 2448
Pset_DistributionFlowElementCommon - Reference: Stahlrohr nach DIN 2448 238323; sets with these values: 2
Andere - Typ: Stahlrohr nach DIN 2448 238323; Familie: Stahlrohr nach DIN 2448 238323; Familie und Typ: Stahlrohr nach DIN 2448 238323: Stahlrohr nach DIN 2448 238323; Typ-ID: 2532424
Abhängigkeiten - Höhe von Ebene: 0 m; Verschieben mit umliegenden Elementen: no
Bemaßungen - Fläche: 0.883188 m2; Volumen: 0.0885924 m3
IFC-Parameter - In IFC-Datei exportieren: Nach Typ; Pset MEP.Tech-Insulation thickness (mm): 100; Pset MEP.Geom-DN: 150; In IFC exportieren als: ifcflowsegment; NameOverride: Stahlrohr nach DIN 2448; IfcPresentationLayer: 0-TFT-H_Vorlauf; ObjectTypeOverride: Stahlrohr nach DIN 2448; Pset MEP.Name: Stahlrohr nach DIN 2448; IfcDescription: Stahlrohr nach DIN 2448; Pset MEP.Geom-Outer Ø (mm): 168.3; Pset MEP.Tech-Material: Stahlrohr nach DIN 2448; Pset MEP.Geom-Length (mm): 1053.15
Phasen - Phase erstellt: Phase 01

# IfcFlowSegment: Stahlrohr nach DIN 2448 238604:Stahlrohr nach DIN 2448 238604, Stahlrohr nach DIN 2448
In: 1. Obergeschoss
Type - Material: IfcSurfaceStyle #9317
Type - Andere - Kategorie: Allgemeines Modell; Familienname: Stahlrohr nach DIN 2448 238604
Type - ID-Daten - Typname: Stahlrohr nach DIN 2448 238604
Type - IFC-Parameter - Typ in IFC-Datei exportieren: Vorgabe
Description: Stahlrohr nach DIN 2448
Pset_DistributionFlowElementCommon - Reference: Stahlrohr nach DIN 2448 238604; sets with these values: 2
Andere - Typ: Stahlrohr nach DIN 2448 238604; Familie: Stahlrohr nach DIN 2448 238604; Familie und Typ: Stahlrohr nach DIN 2448 238604: Stahlrohr nach DIN 2448 238604; Typ-ID: 2532431
Abhängigkeiten - Höhe von Ebene: 0 m; Verschieben mit umliegenden Elementen: no
Bemaßungen - Fläche: 0.883188 m2; Volumen: 0.0885924 m3
IFC-Parameter - In IFC-Datei exportieren: Nach Typ; Pset MEP.Tech-Insulation thickness (mm): 100; Pset MEP.Geom-DN: 150; In IFC exportieren als: ifcflowsegment; NameOverride: Stahlrohr nach DIN 2448; IfcPresentationLayer: 0-TFT-H_Vorlauf; ObjectTypeOverride: Stahlrohr nach DIN 2448; Pset MEP.Name: Stahlrohr nach DIN 2448; IfcDescription: Stahlrohr nach DIN 2448; Pset MEP.Geom-Outer Ø (mm): 168.3; Pset MEP.Tech-Material: Stahlrohr nach DIN 2448; Pset MEP.Geom-Length (mm): 1053.15
Phasen - Phase erstellt: Phase 01

# IfcFlowSegment: Stahlrohr nach DIN 2448 238627:Stahlrohr nach DIN 2448 238627, Stahlrohr nach DIN 2448
In: 1. Obergeschoss
Type - Material: IfcSurfaceStyle #9317
Type - Andere - Kategorie: Allgemeines Modell; Familienname: Stahlrohr nach DIN 2448 238627
Type - ID-Daten - Typname: Stahlrohr nach DIN 2448 238627
Type - IFC-Parameter - Typ in IFC-Datei exportieren: Vorgabe
Description: Stahlrohr nach DIN 2448
Pset_DistributionFlowElementCommon - Reference: Stahlrohr nach DIN 2448 238627; sets with these values: 2
Andere - Typ: Stahlrohr nach DIN 2448 238627; Familie: Stahlrohr nach DIN 2448 238627; Familie und Typ: Stahlrohr nach DIN 2448 238627: Stahlrohr nach DIN 2448 238627; Typ-ID: 2532438
Abhängigkeiten - Höhe von Ebene: 0 m; Verschieben mit umliegenden Elementen: no
Bemaßungen - Fläche: 0.883188 m2; Volumen: 0.0885924 m3
IFC-Parameter - In IFC-Datei exportieren: Nach Typ; Pset MEP.Tech-Insulation thickness (mm): 100; Pset MEP.Geom-DN: 150; In IFC exportieren als: ifcflowsegment; NameOverride: Stahlrohr nach DIN 2448; IfcPresentationLayer: 0-TFT-H_Vorlauf; ObjectTypeOverride: Stahlrohr nach DIN 2448; Pset MEP.Name: Stahlrohr nach DIN 2448; IfcDescription: Stahlrohr nach DIN 2448; Pset MEP.Geom-Outer Ø (mm): 168.3; Pset MEP.Tech-Material: Stahlrohr nach DIN 2448; Pset MEP.Geom-Length (mm): 1053.15
Phasen - Phase erstellt: Phase 01

# IfcFlowSegment: Stahlrohr nach DIN 2448 240348:Stahlrohr nach DIN 2448 240348, Stahlrohr nach DIN 2448
In: 1. Obergeschoss
Type - Material: IfcSurfaceStyle #9317
Type - Andere - Kategorie: Allgemeines Modell; Familienname: Stahlrohr nach DIN 2448 240348
Type - ID-Daten - Typname: Stahlrohr nach DIN 2448 240348
Type - IFC-Parameter - Typ in IFC-Datei exportieren: Vorgabe
Description: Stahlrohr nach DIN 2448
Pset_DistributionFlowElementCommon - Reference: Stahlrohr nach DIN 2448 240348; sets with these values: 2
Andere - Typ: Stahlrohr nach DIN 2448 240348; Familie: Stahlrohr nach DIN 2448 240348; Familie und Typ: Stahlrohr nach DIN 2448 240348: Stahlrohr nach DIN 2448 240348; Typ-ID: 2532459
Abhängigkeiten - Höhe von Ebene: 0 m; Verschieben mit umliegenden Elementen: no
Bemaßungen - Fläche: 1.85532 m2; Volumen: 0.213432 m3
IFC-Parameter - In IFC-Datei exportieren: Nach Typ; Pset MEP.Geom-DN: 200; Pset MEP.Tech-Insulation thickness (mm): 100; In IFC exportieren als: ifcflowsegment; NameOverride: Stahlrohr nach DIN 2448; IfcPresentationLayer: 0-TFT-H_Vorlauf; ObjectTypeOverride: Stahlrohr nach DIN 2448; Pset MEP.Name: Stahlrohr nach DIN 2448; IfcDescription: Stahlrohr nach DIN 2448; Pset MEP.Geom-Outer Ø (mm): 219.1; Pset MEP.Tech-Material: Stahlrohr nach DIN 2448; Pset MEP.Geom-Length (mm): 1860.15
Phasen - Phase erstellt: Phase 01

# IfcFlowSegment: Stahlrohr nach DIN 2448 242357:Stahlrohr nach DIN 2448 242357, Stahlrohr nach DIN 2448
In: 1. Obergeschoss
Type - Material: IfcSurfaceStyle #9317
Type - Andere - Kategorie: Allgemeines Modell; Familienname: Stahlrohr nach DIN 2448 242357
Type - ID-Daten - Typname: Stahlrohr nach DIN 2448 242357
Type - IFC-Parameter - Typ in IFC-Datei exportieren: Vorgabe
Description: Stahlrohr nach DIN 2448
Pset_DistributionFlowElementCommon - Reference: Stahlrohr nach DIN 2448 242357; sets with these values: 2
Andere - Typ: Stahlrohr nach DIN 2448 242357; Familie: Stahlrohr nach DIN 2448 242357; Familie und Typ: Stahlrohr nach DIN 2448 242357: Stahlrohr nach DIN 2448 242357; Typ-ID: 2532473
Abhängigkeiten - Höhe von Ebene: 0 m; Verschieben mit umliegenden Elementen: no
Bemaßungen - Fläche: 0.242751 m2; Volumen: 0.0207956 m3
IFC-Parameter - In IFC-Datei exportieren: Nach Typ; Pset MEP.Tech-Insulation thickness (mm): 100; Pset MEP.Geom-DN: 100; In IFC exportieren als: ifcflowsegment; NameOverride: Stahlrohr nach DIN 2448; IfcPresentationLayer: 0-TFT-H_Vorlauf; ObjectTypeOverride: Stahlrohr nach DIN 2448; Pset MEP.Name: Stahlrohr nach DIN 2448; IfcDescription: Stahlrohr nach DIN 2448; Pset MEP.Geom-Outer Ø (mm): 114.3; Pset MEP.Tech-Material: Stahlrohr nach DIN 2448; Pset MEP.Geom-Length (mm): 362.407
Phasen - Phase erstellt: Phase 01

# IfcFlowSegment: Stahlrohr nach DIN 2448 245135:Stahlrohr nach DIN 2448 245135, Stahlrohr nach DIN 2448
In: 1. Obergeschoss
Type - Material: IfcSurfaceStyle #9317
Type - Andere - Kategorie: Allgemeines Modell; Familienname: Stahlrohr nach DIN 2448 245135
Type - ID-Daten - Typname: Stahlrohr nach DIN 2448 245135
Type - IFC-Parameter - Typ in IFC-Datei exportieren: Vorgabe
Description: Stahlrohr nach DIN 2448
Pset_DistributionFlowElementCommon - Reference: Stahlrohr nach DIN 2448 245135; sets with these values: 2
Andere - Typ: Stahlrohr nach DIN 2448 245135; Familie: Stahlrohr nach DIN 2448 245135; Familie und Typ: Stahlrohr nach DIN 2448 245135: Stahlrohr nach DIN 2448 245135; Typ-ID: 2532494
Abhängigkeiten - Höhe von Ebene: 0 m; Verschieben mit umliegenden Elementen: no
Bemaßungen - Fläche: 0.321569 m2; Volumen: 0.0369926 m3
IFC-Parameter - In IFC-Datei exportieren: Nach Typ; Pset MEP.Geom-DN: 200; Pset MEP.Tech-Insulation thickness (mm): 100; In IFC exportieren als: ifcflowsegment; NameOverride: Stahlrohr nach DIN 2448; IfcPresentationLayer: 0-TFT-H_Vorlauf; ObjectTypeOverride: Stahlrohr nach DIN 2448; Pset MEP.Name: Stahlrohr nach DIN 2448; IfcDescription: Stahlrohr nach DIN 2448; Pset MEP.Geom-Outer Ø (mm): 219.1; Pset MEP.Tech-Material: Stahlrohr nach DIN 2448; Pset MEP.Geom-Length (mm): 322.407
Phasen - Phase erstellt: Phase 01

# IfcFlowSegment: Stahlrohr nach DIN 2448 245466:Stahlrohr nach DIN 2448 245466, Stahlrohr nach DIN 2448
In: 1. Obergeschoss
Type - Material: IfcSurfaceStyle #9317
Type - Andere - Kategorie: Allgemeines Modell; Familienname: Stahlrohr nach DIN 2448 245466
Type - ID-Daten - Typname: Stahlrohr nach DIN 2448 245466
Type - IFC-Parameter - Typ in IFC-Datei exportieren: Vorgabe
Description: Stahlrohr nach DIN 2448
Pset_DistributionFlowElementCommon - Reference: Stahlrohr nach DIN 2448 245466; sets with these values: 2
Andere - Typ: Stahlrohr nach DIN 2448 245466; Familie: Stahlrohr nach DIN 2448 245466; Familie und Typ: Stahlrohr nach DIN 2448 245466: Stahlrohr nach DIN 2448 245466; Typ-ID: 2532515
Abhängigkeiten - Höhe von Ebene: 0 m; Verschieben mit umliegenden Elementen: no
Bemaßungen - Fläche: 0.321569 m2; Volumen: 0.0369926 m3
IFC-Parameter - In IFC-Datei exportieren: Nach Typ; Pset MEP.Geom-DN: 200; Pset MEP.Tech-Insulation thickness (mm): 100; In IFC exportieren als: ifcflowsegment; NameOverride: Stahlrohr nach DIN 2448; IfcPresentationLayer: 0-TFT-H_Vorlauf; ObjectTypeOverride: Stahlrohr nach DIN 2448; Pset MEP.Name: Stahlrohr nach DIN 2448; IfcDescription: Stahlrohr nach DIN 2448; Pset MEP.Geom-Outer Ø (mm): 219.1; Pset MEP.Tech-Material: Stahlrohr nach DIN 2448; Pset MEP.Geom-Length (mm): 322.407
Phasen - Phase erstellt: Phase 01

# IfcFlowSegment: Stahlrohr nach DIN 2448 245535:Stahlrohr nach DIN 2448 245535, Stahlrohr nach DIN 2448
In: 1. Obergeschoss
Type - Material: IfcSurfaceStyle #9317
Type - Andere - Kategorie: Allgemeines Modell; Familienname: Stahlrohr nach DIN 2448 245535
Type - ID-Daten - Typname: Stahlrohr nach DIN 2448 245535
Type - IFC-Parameter - Typ in IFC-Datei exportieren: Vorgabe
Description: Stahlrohr nach DIN 2448
Pset_DistributionFlowElementCommon - Reference: Stahlrohr nach DIN 2448 245535; sets with these values: 2
Andere - Typ: Stahlrohr nach DIN 2448 245535; Familie: Stahlrohr nach DIN 2448 245535; Familie und Typ: Stahlrohr nach DIN 2448 245535: Stahlrohr nach DIN 2448 245535; Typ-ID: 2532536
Abhängigkeiten - Höhe von Ebene: 0 m; Verschieben mit umliegenden Elementen: no
Bemaßungen - Fläche: 0.321569 m2; Volumen: 0.0369926 m3
IFC-Parameter - In IFC-Datei exportieren: Nach Typ; Pset MEP.Geom-DN: 200; Pset MEP.Tech-Insulation thickness (mm): 100; In IFC exportieren als: ifcflowsegment; NameOverride: Stahlrohr nach DIN 2448; IfcPresentationLayer: 0-TFT-H_Vorlauf; ObjectTypeOverride: Stahlrohr nach DIN 2448; Pset MEP.Name: Stahlrohr nach DIN 2448; IfcDescription: Stahlrohr nach DIN 2448; Pset MEP.Geom-Outer Ø (mm): 219.1; Pset MEP.Tech-Material: Stahlrohr nach DIN 2448; Pset MEP.Geom-Length (mm): 322.407
Phasen - Phase erstellt: Phase 01

# IfcFlowSegment: Stahlrohr nach DIN 2448 245604:Stahlrohr nach DIN 2448 245604, Stahlrohr nach DIN 2448
In: 1. Obergeschoss
Type - Material: IfcSurfaceStyle #9317
Type - Andere - Kategorie: Allgemeines Modell; Familienname: Stahlrohr nach DIN 2448 245604
Type - ID-Daten - Typname: Stahlrohr nach DIN 2448 245604
Type - IFC-Parameter - Typ in IFC-Datei exportieren: Vorgabe
Description: Stahlrohr nach DIN 2448
Pset_DistributionFlowElementCommon - Reference: Stahlrohr nach DIN 2448 245604; sets with these values: 2
Andere - Typ: Stahlrohr nach DIN 2448 245604; Familie: Stahlrohr nach DIN 2448 245604; Familie und Typ: Stahlrohr nach DIN 2448 245604: Stahlrohr nach DIN 2448 245604; Typ-ID: 2532557
Abhängigkeiten - Höhe von Ebene: 0 m; Verschieben mit umliegenden Elementen: no
Bemaßungen - Fläche: 1.91363 m2; Volumen: 0.220141 m3
IFC-Parameter - In IFC-Datei exportieren: Nach Typ; Pset MEP.Geom-DN: 200; Pset MEP.Tech-Insulation thickness (mm): 100; In IFC exportieren als: ifcflowsegment; NameOverride: Stahlrohr nach DIN 2448; IfcPresentationLayer: 0-TFT-H_Vorlauf; ObjectTypeOverride: Stahlrohr nach DIN 2448; Pset MEP.Name: Stahlrohr nach DIN 2448; IfcDescription: Stahlrohr nach DIN 2448; Pset MEP.Geom-Outer Ø (mm): 219.1; Pset MEP.Tech-Material: Stahlrohr nach DIN 2448; Pset MEP.Geom-Length (mm): 1918.62
Phasen - Phase erstellt: Phase 01

# IfcFlowSegment: Stahlrohr nach DIN 2448 246640:Stahlrohr nach DIN 2448 246640, Stahlrohr nach DIN 2448
In: 1. Obergeschoss
Type - Material: IfcSurfaceStyle #9317
Type - Andere - Kategorie: Allgemeines Modell; Familienname: Stahlrohr nach DIN 2448 246640
Type - ID-Daten - Typname: Stahlrohr nach DIN 2448 246640
Type - IFC-Parameter - Typ in IFC-Datei exportieren: Vorgabe
Description: Stahlrohr nach DIN 2448
Pset_DistributionFlowElementCommon - Reference: Stahlrohr nach DIN 2448 246640; sets with these values: 2
Andere - Typ: Stahlrohr nach DIN 2448 246640; Familie: Stahlrohr nach DIN 2448 246640; Familie und Typ: Stahlrohr nach DIN 2448 246640: Stahlrohr nach DIN 2448 246640; Typ-ID: 2532571
Abhängigkeiten - Höhe von Ebene: 0 m; Verschieben mit umliegenden Elementen: no
Bemaßungen - Fläche: 1.29185 m2; Volumen: 0.110668 m3
IFC-Parameter - In IFC-Datei exportieren: Nach Typ; Pset MEP.Tech-Insulation thickness (mm): 100; Pset MEP.Geom-DN: 100; In IFC exportieren als: ifcflowsegment; NameOverride: Stahlrohr nach DIN 2448; IfcPresentationLayer: 0-TFT-H_Vorlauf; ObjectTypeOverride: Stahlrohr nach DIN 2448; Pset MEP.Name: Stahlrohr nach DIN 2448; IfcDescription: Stahlrohr nach DIN 2448; Pset MEP.Geom-Outer Ø (mm): 114.3; Pset MEP.Tech-Material: Stahlrohr nach DIN 2448; Pset MEP.Geom-Length (mm): 1928.62
Phasen - Phase erstellt: Phase 01

# IfcFlowSegment: Stahlrohr nach DIN 2448 246921:Stahlrohr nach DIN 2448 246921, Stahlrohr nach DIN 2448
In: 1. Obergeschoss
Type - Material: IfcSurfaceStyle #1741
Type - Andere - Kategorie: Allgemeines Modell; Familienname: Stahlrohr nach DIN 2448 246921
Type - ID-Daten - Typname: Stahlrohr nach DIN 2448 246921
Type - IFC-Parameter - Typ in IFC-Datei exportieren: Vorgabe
Description: Stahlrohr nach DIN 2448
Pset_DistributionFlowElementCommon - Reference: Stahlrohr nach DIN 2448 246921; sets with these values: 2
Andere - Typ: Stahlrohr nach DIN 2448 246921; Familie: Stahlrohr nach DIN 2448 246921; Familie und Typ: Stahlrohr nach DIN 2448 246921: Stahlrohr nach DIN 2448 246921; Typ-ID: 2532578
Abhängigkeiten - Höhe von Ebene: 0 m; Verschieben mit umliegenden Elementen: no
Bemaßungen - Fläche: 1.98199 m2; Volumen: 0.228004 m3
IFC-Parameter - In IFC-Datei exportieren: Nach Typ; Pset MEP.Geom-DN: 200; Pset MEP.Tech-Insulation thickness (mm): 100; In IFC exportieren als: ifcflowsegment; NameOverride: Stahlrohr nach DIN 2448; IfcPresentationLayer: 0-TFT-H_Ruecklauf; ObjectTypeOverride: Stahlrohr nach DIN 2448; Pset MEP.Name: Stahlrohr nach DIN 2448; IfcDescription: Stahlrohr nach DIN 2448; Pset MEP.Geom-Outer Ø (mm): 219.1; Pset MEP.Tech-Material: Stahlrohr nach DIN 2448; Pset MEP.Geom-Length (mm): 1987.15
Phasen - Phase erstellt: Phase 01

# IfcFlowSegment: Stahlrohr nach DIN 2448 247225:Stahlrohr nach DIN 2448 247225, Stahlrohr nach DIN 2448
In: 1. Obergeschoss
Type - Material: IfcSurfaceStyle #1741
Type - Andere - Kategorie: Allgemeines Modell; Familienname: Stahlrohr nach DIN 2448 247225
Type - ID-Daten - Typname: Stahlrohr nach DIN 2448 247225
Type - IFC-Parameter - Typ in IFC-Datei exportieren: Vorgabe
Description: Stahlrohr nach DIN 2448
Pset_DistributionFlowElementCommon - Reference: Stahlrohr nach DIN 2448 247225; sets with these values: 2
Andere - Typ: Stahlrohr nach DIN 2448 247225; Familie: Stahlrohr nach DIN 2448 247225; Familie und Typ: Stahlrohr nach DIN 2448 247225: Stahlrohr nach DIN 2448 247225; Typ-ID: 2532592
Abhängigkeiten - Höhe von Ebene: 0 m; Verschieben mit umliegenden Elementen: no
Bemaßungen - Fläche: 0.242751 m2; Volumen: 0.0207956 m3
IFC-Parameter - In IFC-Datei exportieren: Nach Typ; Pset MEP.Tech-Insulation thickness (mm): 100; Pset MEP.Geom-DN: 100; In IFC exportieren als: ifcflowsegment; NameOverride: Stahlrohr nach DIN 2448; IfcPresentationLayer: 0-TFT-H_Ruecklauf; ObjectTypeOverride: Stahlrohr nach DIN 2448; Pset MEP.Name: Stahlrohr nach DIN 2448; IfcDescription: Stahlrohr nach DIN 2448; Pset MEP.Geom-Outer Ø (mm): 114.3; Pset MEP.Tech-Material: Stahlrohr nach DIN 2448; Pset MEP.Geom-Length (mm): 362.407
Phasen - Phase erstellt: Phase 01

# IfcFlowSegment: Stahlrohr nach DIN 2448 247294:Stahlrohr nach DIN 2448 247294, Stahlrohr nach DIN 2448
In: 1. Obergeschoss
Type - Material: IfcSurfaceStyle #1741
Type - Andere - Kategorie: Allgemeines Modell; Familienname: Stahlrohr nach DIN 2448 247294
Type - ID-Daten - Typname: Stahlrohr nach DIN 2448 247294
Type - IFC-Parameter - Typ in IFC-Datei exportieren: Vorgabe
Description: Stahlrohr nach DIN 2448
Pset_DistributionFlowElementCommon - Reference: Stahlrohr nach DIN 2448 247294; sets with these values: 2
Andere - Typ: Stahlrohr nach DIN 2448 247294; Familie: Stahlrohr nach DIN 2448 247294; Familie und Typ: Stahlrohr nach DIN 2448 247294: Stahlrohr nach DIN 2448 247294; Typ-ID: 2532613
Abhängigkeiten - Höhe von Ebene: 0 m; Verschieben mit umliegenden Elementen: no
Bemaßungen - Fläche: 0.321569 m2; Volumen: 0.0369926 m3
IFC-Parameter - In IFC-Datei exportieren: Nach Typ; Pset MEP.Geom-DN: 200; Pset MEP.Tech-Insulation thickness (mm): 100; In IFC exportieren als: ifcflowsegment; NameOverride: Stahlrohr nach DIN 2448; IfcPresentationLayer: 0-TFT-H_Ruecklauf; ObjectTypeOverride: Stahlrohr nach DIN 2448; Pset MEP.Name: Stahlrohr nach DIN 2448; IfcDescription: Stahlrohr nach DIN 2448; Pset MEP.Geom-Outer Ø (mm): 219.1; Pset MEP.Tech-Material: Stahlrohr nach DIN 2448; Pset MEP.Geom-Length (mm): 322.407
Phasen - Phase erstellt: Phase 01

# IfcFlowSegment: Stahlrohr nach DIN 2448 247363:Stahlrohr nach DIN 2448 247363, Stahlrohr nach DIN 2448
In: 1. Obergeschoss
Type - Material: IfcSurfaceStyle #1741
Type - Andere - Kategorie: Allgemeines Modell; Familienname: Stahlrohr nach DIN 2448 247363
Type - ID-Daten - Typname: Stahlrohr nach DIN 2448 247363
Type - IFC-Parameter - Typ in IFC-Datei exportieren: Vorgabe
Description: Stahlrohr nach DIN 2448
Pset_DistributionFlowElementCommon - Reference: Stahlrohr nach DIN 2448 247363; sets with these values: 2
Andere - Typ: Stahlrohr nach DIN 2448 247363; Familie: Stahlrohr nach DIN 2448 247363; Familie und Typ: Stahlrohr nach DIN 2448 247363: Stahlrohr nach DIN 2448 247363; Typ-ID: 2532634
Abhängigkeiten - Höhe von Ebene: 0 m; Verschieben mit umliegenden Elementen: no
Bemaßungen - Fläche: 0.321569 m2; Volumen: 0.0369926 m3
IFC-Parameter - In IFC-Datei exportieren: Nach Typ; Pset MEP.Geom-DN: 200; Pset MEP.Tech-Insulation thickness (mm): 100; In IFC exportieren als: ifcflowsegment; NameOverride: Stahlrohr nach DIN 2448; IfcPresentationLayer: 0-TFT-H_Ruecklauf; ObjectTypeOverride: Stahlrohr nach DIN 2448; Pset MEP.Name: Stahlrohr nach DIN 2448; IfcDescription: Stahlrohr nach DIN 2448; Pset MEP.Geom-Outer Ø (mm): 219.1; Pset MEP.Tech-Material: Stahlrohr nach DIN 2448; Pset MEP.Geom-Length (mm): 322.407
Phasen - Phase erstellt: Phase 01

# IfcFlowSegment: Stahlrohr nach DIN 2448 247432:Stahlrohr nach DIN 2448 247432, Stahlrohr nach DIN 2448
In: 1. Obergeschoss
Type - Material: IfcSurfaceStyle #1741
Type - Andere - Kategorie: Allgemeines Modell; Familienname: Stahlrohr nach DIN 2448 247432
Type - ID-Daten - Typname: Stahlrohr nach DIN 2448 247432
Type - IFC-Parameter - Typ in IFC-Datei exportieren: Vorgabe
Description: Stahlrohr nach DIN 2448
Pset_DistributionFlowElementCommon - Reference: Stahlrohr nach DIN 2448 247432; sets with these values: 2
Andere - Typ: Stahlrohr nach DIN 2448 247432; Familie: Stahlrohr nach DIN 2448 247432; Familie und Typ: Stahlrohr nach DIN 2448 247432: Stahlrohr nach DIN 2448 247432; Typ-ID: 2532655
Abhängigkeiten - Höhe von Ebene: 0 m; Verschieben mit umliegenden Elementen: no
Bemaßungen - Fläche: 0.321569 m2; Volumen: 0.0369926 m3
IFC-Parameter - In IFC-Datei exportieren: Nach Typ; Pset MEP.Geom-DN: 200; Pset MEP.Tech-Insulation thickness (mm): 100; In IFC exportieren als: ifcflowsegment; NameOverride: Stahlrohr nach DIN 2448; IfcPresentationLayer: 0-TFT-H_Ruecklauf; ObjectTypeOverride: Stahlrohr nach DIN 2448; Pset MEP.Name: Stahlrohr nach DIN 2448; IfcDescription: Stahlrohr nach DIN 2448; Pset MEP.Geom-Outer Ø (mm): 219.1; Pset MEP.Tech-Material: Stahlrohr nach DIN 2448; Pset MEP.Geom-Length (mm): 322.407
Phasen - Phase erstellt: Phase 01

# IfcFlowSegment: Stahlrohr nach DIN 2448 247501:Stahlrohr nach DIN 2448 247501, Stahlrohr nach DIN 2448
In: 1. Obergeschoss
Type - Material: IfcSurfaceStyle #1741
Type - Andere - Kategorie: Allgemeines Modell; Familienname: Stahlrohr nach DIN 2448 247501
Type - ID-Daten - Typname: Stahlrohr nach DIN 2448 247501
Type - IFC-Parameter - Typ in IFC-Datei exportieren: Vorgabe
Description: Stahlrohr nach DIN 2448
Pset_DistributionFlowElementCommon - Reference: Stahlrohr nach DIN 2448 247501; sets with these values: 2
Andere - Typ: Stahlrohr nach DIN 2448 247501; Familie: Stahlrohr nach DIN 2448 247501; Familie und Typ: Stahlrohr nach DIN 2448 247501: Stahlrohr nach DIN 2448 247501; Typ-ID: 2532676
Abhängigkeiten - Höhe von Ebene: 0 m; Verschieben mit umliegenden Elementen: no
Bemaßungen - Fläche: 1.91363 m2; Volumen: 0.220141 m3
IFC-Parameter - In IFC-Datei exportieren: Nach Typ; Pset MEP.Geom-DN: 200; Pset MEP.Tech-Insulation thickness (mm): 100; In IFC exportieren als: ifcflowsegment; NameOverride: Stahlrohr nach DIN 2448; IfcPresentationLayer: 0-TFT-H_Ruecklauf; ObjectTypeOverride: Stahlrohr nach DIN 2448; Pset MEP.Name: Stahlrohr nach DIN 2448; IfcDescription: Stahlrohr nach DIN 2448; Pset MEP.Geom-Outer Ø (mm): 219.1; Pset MEP.Tech-Material: Stahlrohr nach DIN 2448; Pset MEP.Geom-Length (mm): 1918.62
Phasen - Phase erstellt: Phase 01

# IfcFlowSegment: Stahlrohr nach DIN 2448 247547:Stahlrohr nach DIN 2448 247547, Stahlrohr nach DIN 2448
In: 1. Obergeschoss
Type - Material: IfcSurfaceStyle #1741
Type - Andere - Kategorie: Allgemeines Modell; Familienname: Stahlrohr nach DIN 2448 247547
Type - ID-Daten - Typname: Stahlrohr nach DIN 2448 247547
Type - IFC-Parameter - Typ in IFC-Datei exportieren: Vorgabe
Description: Stahlrohr nach DIN 2448
Pset_DistributionFlowElementCommon - Reference: Stahlrohr nach DIN 2448 247547; sets with these values: 2
Andere - Typ: Stahlrohr nach DIN 2448 247547; Familie: Stahlrohr nach DIN 2448 247547; Familie und Typ: Stahlrohr nach DIN 2448 247547: Stahlrohr nach DIN 2448 247547; Typ-ID: 2532690
Abhängigkeiten - Höhe von Ebene: 0 m; Verschieben mit umliegenden Elementen: no
Bemaßungen - Fläche: 1.29185 m2; Volumen: 0.110668 m3
IFC-Parameter - In IFC-Datei exportieren: Nach Typ; Pset MEP.Tech-Insulation thickness (mm): 100; Pset MEP.Geom-DN: 100; In IFC exportieren als: ifcflowsegment; NameOverride: Stahlrohr nach DIN 2448; IfcPresentationLayer: 0-TFT-H_Ruecklauf; ObjectTypeOverride: Stahlrohr nach DIN 2448; Pset MEP.Name: Stahlrohr nach DIN 2448; IfcDescription: Stahlrohr nach DIN 2448; Pset MEP.Geom-Outer Ø (mm): 114.3; Pset MEP.Tech-Material: Stahlrohr nach DIN 2448; Pset MEP.Geom-Length (mm): 1928.62
Phasen - Phase erstellt: Phase 01

# IfcFlowSegment: Stahlrohr nach DIN 2448 247570:Stahlrohr nach DIN 2448 247570, Stahlrohr nach DIN 2448
In: 1. Obergeschoss
Type - Material: IfcSurfaceStyle #9317
Type - Andere - Kategorie: Allgemeines Modell; Familienname: Stahlrohr nach DIN 2448 247570
Type - ID-Daten - Typname: Stahlrohr nach DIN 2448 247570
Type - IFC-Parameter - Typ in IFC-Datei exportieren: Vorgabe
Description: Stahlrohr nach DIN 2448
Pset_DistributionFlowElementCommon - Reference: Stahlrohr nach DIN 2448 247570; sets with these values: 2
Andere - Typ: Stahlrohr nach DIN 2448 247570; Familie: Stahlrohr nach DIN 2448 247570; Familie und Typ: Stahlrohr nach DIN 2448 247570: Stahlrohr nach DIN 2448 247570; Typ-ID: 2532697
Abhängigkeiten - Höhe von Ebene: 0 m; Verschieben mit umliegenden Elementen: no
Bemaßungen - Fläche: 0.873713 m2; Volumen: 0.0748478 m3
IFC-Parameter - In IFC-Datei exportieren: Nach Typ; Pset MEP.Tech-Insulation thickness (mm): 100; Pset MEP.Geom-DN: 100; In IFC exportieren als: ifcflowsegment; NameOverride: Stahlrohr nach DIN 2448; IfcPresentationLayer: 0-TFT-H_Vorlauf; ObjectTypeOverride: Stahlrohr nach DIN 2448; Pset MEP.Name: Stahlrohr nach DIN 2448; IfcDescription: Stahlrohr nach DIN 2448; Pset MEP.Geom-Outer Ø (mm): 114.3; Pset MEP.Tech-Material: Stahlrohr nach DIN 2448; Pset MEP.Geom-Length (mm): 1304.38
Phasen - Phase erstellt: Phase 01

# IfcFlowSegment: Stahlrohr nach DIN 2448 247853:Stahlrohr nach DIN 2448 247853, Stahlrohr nach DIN 2448
In: 1. Obergeschoss
Type - Material: IfcSurfaceStyle #1741
Type - Andere - Kategorie: Allgemeines Modell; Familienname: Stahlrohr nach DIN 2448 247853
Type - ID-Daten - Typname: Stahlrohr nach DIN 2448 247853
Type - IFC-Parameter - Typ in IFC-Datei exportieren: Vorgabe
Description: Stahlrohr nach DIN 2448
Pset_DistributionFlowElementCommon - Reference: Stahlrohr nach DIN 2448 247853; sets with these values: 2
Andere - Typ: Stahlrohr nach DIN 2448 247853; Familie: Stahlrohr nach DIN 2448 247853; Familie und Typ: Stahlrohr nach DIN 2448 247853: Stahlrohr nach DIN 2448 247853; Typ-ID: 2532704
Abhängigkeiten - Höhe von Ebene: 0 m; Verschieben mit umliegenden Elementen: no
Bemaßungen - Fläche: 0.873713 m2; Volumen: 0.0748478 m3
IFC-Parameter - In IFC-Datei exportieren: Nach Typ; Pset MEP.Tech-Insulation thickness (mm): 100; Pset MEP.Geom-DN: 100; In IFC exportieren als: ifcflowsegment; NameOverride: Stahlrohr nach DIN 2448; IfcPresentationLayer: 0-TFT-H_Ruecklauf; ObjectTypeOverride: Stahlrohr nach DIN 2448; Pset MEP.Name: Stahlrohr nach DIN 2448; IfcDescription: Stahlrohr nach DIN 2448; Pset MEP.Geom-Outer Ø (mm): 114.3; Pset MEP.Tech-Material: Stahlrohr nach DIN 2448; Pset MEP.Geom-Length (mm): 1304.38
Phasen - Phase erstellt: Phase 01

# IfcFlowSegment: Stahlrohr nach DIN 2448 247899:Stahlrohr nach DIN 2448 247899, Stahlrohr nach DIN 2448
In: 1. Obergeschoss
Type - Material: IfcSurfaceStyle #9317
Type - Andere - Kategorie: Allgemeines Modell; Familienname: Stahlrohr nach DIN 2448 247899
Type - ID-Daten - Typname: Stahlrohr nach DIN 2448 247899
Type - IFC-Parameter - Typ in IFC-Datei exportieren: Vorgabe
Description: Stahlrohr nach DIN 2448
Pset_DistributionFlowElementCommon - Reference: Stahlrohr nach DIN 2448 247899; sets with these values: 2
Andere - Typ: Stahlrohr nach DIN 2448 247899; Familie: Stahlrohr nach DIN 2448 247899; Familie und Typ: Stahlrohr nach DIN 2448 247899: Stahlrohr nach DIN 2448 247899; Typ-ID: 2532718
Abhängigkeiten - Höhe von Ebene: 0 m; Verschieben mit umliegenden Elementen: no
Bemaßungen - Fläche: 1.43137 m2; Volumen: 0.164662 m3
IFC-Parameter - In IFC-Datei exportieren: Nach Typ; Pset MEP.Geom-DN: 200; Pset MEP.Tech-Insulation thickness (mm): 100; In IFC exportieren als: ifcflowsegment; NameOverride: Stahlrohr nach DIN 2448; IfcPresentationLayer: 0-TFT-H_Vorlauf; ObjectTypeOverride: Stahlrohr nach DIN 2448; Pset MEP.Name: Stahlrohr nach DIN 2448; IfcDescription: Stahlrohr nach DIN 2448; Pset MEP.Geom-Outer Ø (mm): 219.1; Pset MEP.Tech-Material: Stahlrohr nach DIN 2448; Pset MEP.Geom-Length (mm): 1435.1
Phasen - Phase erstellt: Phase 01

# IfcFlowSegment: Stahlrohr nach DIN 2448 248812:Stahlrohr nach DIN 2448 248812, Stahlrohr nach DIN 2448
In: 1. Obergeschoss
Type - Material: IfcSurfaceStyle #1741
Type - Andere - Kategorie: Allgemeines Modell; Familienname: Stahlrohr nach DIN 2448 248812
Type - ID-Daten - Typname: Stahlrohr nach DIN 2448 248812
Type - IFC-Parameter - Typ in IFC-Datei exportieren: Vorgabe
Description: Stahlrohr nach DIN 2448
Pset_DistributionFlowElementCommon - Reference: Stahlrohr nach DIN 2448 248812; sets with these values: 2
Andere - Typ: Stahlrohr nach DIN 2448 248812; Familie: Stahlrohr nach DIN 2448 248812; Familie und Typ: Stahlrohr nach DIN 2448 248812: Stahlrohr nach DIN 2448 248812; Typ-ID: 2532739
Abhängigkeiten - Höhe von Ebene: 0 m; Verschieben mit umliegenden Elementen: no
Bemaßungen - Fläche: 0.234406 m2; Volumen: 0.0269656 m3
IFC-Parameter - In IFC-Datei exportieren: Nach Typ; Pset MEP.Geom-DN: 200; Pset MEP.Tech-Insulation thickness (mm): 100; In IFC exportieren als: ifcflowsegment; NameOverride: Stahlrohr nach DIN 2448; IfcPresentationLayer: 0-TFT-H_Ruecklauf; ObjectTypeOverride: Stahlrohr nach DIN 2448; Pset MEP.Name: Stahlrohr nach DIN 2448; IfcDescription: Stahlrohr nach DIN 2448; Pset MEP.Geom-Outer Ø (mm): 219.1; Pset MEP.Tech-Material: Stahlrohr nach DIN 2448; Pset MEP.Geom-Length (mm): 235.016
Phasen - Phase erstellt: Phase 01

# IfcFlowSegment: Stahlrohr nach DIN 2448 249099:Stahlrohr nach DIN 2448 249099, Stahlrohr nach DIN 2448
In: 1. Obergeschoss
Type - Material: IfcSurfaceStyle #9317
Type - Andere - Kategorie: Allgemeines Modell; Familienname: Stahlrohr nach DIN 2448 249099
Type - ID-Daten - Typname: Stahlrohr nach DIN 2448 249099
Type - IFC-Parameter - Typ in IFC-Datei exportieren: Vorgabe
Description: Stahlrohr nach DIN 2448
Pset_DistributionFlowElementCommon - Reference: Stahlrohr nach DIN 2448 249099; sets with these values: 2
Andere - Typ: Stahlrohr nach DIN 2448 249099; Familie: Stahlrohr nach DIN 2448 249099; Familie und Typ: Stahlrohr nach DIN 2448 249099: Stahlrohr nach DIN 2448 249099; Typ-ID: 2532746
Abhängigkeiten - Höhe von Ebene: 0 m; Verschieben mit umliegenden Elementen: no
Bemaßungen - Fläche: 0.00876866 m2; Volumen: 0.000484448 m3
IFC-Parameter - In IFC-Datei exportieren: Nach Typ; Pset MEP.Tech-Insulation thickness (mm): 100; Pset MEP.Geom-DN: 150; In IFC exportieren als: ifcflowsegment; NameOverride: Stahlrohr nach DIN 2448; IfcPresentationLayer: 0-TFT-H_Vorlauf; ObjectTypeOverride: Stahlrohr nach DIN 2448; Pset MEP.Name: Stahlrohr nach DIN 2448; IfcDescription: Stahlrohr nach DIN 2448; Pset MEP.Geom-Outer Ø (mm): 168.3; Pset MEP.Tech-Material: Stahlrohr nach DIN 2448; Pset MEP.Geom-Length (mm): 33.3378
Phasen - Phase erstellt: Phase 01

# IfcFlowSegment: Stahlrohr nach DIN 2448 249254:Stahlrohr nach DIN 2448 249254, Stahlrohr nach DIN 2448
In: 1. Obergeschoss
Type - Material: IfcSurfaceStyle #9317
Type - Andere - Kategorie: Allgemeines Modell; Familienname: Stahlrohr nach DIN 2448 249254
Type - ID-Daten - Typname: Stahlrohr nach DIN 2448 249254
Type - IFC-Parameter - Typ in IFC-Datei exportieren: Vorgabe
Description: Stahlrohr nach DIN 2448
Pset_DistributionFlowElementCommon - Reference: Stahlrohr nach DIN 2448 249254; sets with these values: 2
Andere - Typ: Stahlrohr nach DIN 2448 249254; Familie: Stahlrohr nach DIN 2448 249254; Familie und Typ: Stahlrohr nach DIN 2448 249254: Stahlrohr nach DIN 2448 249254; Typ-ID: 2532753
Abhängigkeiten - Höhe von Ebene: 0 m; Verschieben mit umliegenden Elementen: no
Bemaßungen - Fläche: 0.0313888 m2; Volumen: 0.00173416 m3
IFC-Parameter - In IFC-Datei exportieren: Nach Typ; Pset MEP.Tech-Insulation thickness (mm): 100; Pset MEP.Geom-DN: 150; In IFC exportieren als: ifcflowsegment; NameOverride: Stahlrohr nach DIN 2448; IfcPresentationLayer: 0-TFT-H_Vorlauf; ObjectTypeOverride: Stahlrohr nach DIN 2448; Pset MEP.Name: Stahlrohr nach DIN 2448; IfcDescription: Stahlrohr nach DIN 2448; Pset MEP.Geom-Outer Ø (mm): 168.3; Pset MEP.Tech-Material: Stahlrohr nach DIN 2448; Pset MEP.Geom-Length (mm): 119.338
Phasen - Phase erstellt: Phase 01

# IfcFlowSegment: Stahlrohr nach DIN 2448 249409:Stahlrohr nach DIN 2448 249409, Stahlrohr nach DIN 2448
In: 1. Obergeschoss
Type - Material: IfcSurfaceStyle #9317
Type - Andere - Kategorie: Allgemeines Modell; Familienname: Stahlrohr nach DIN 2448 249409
Type - ID-Daten - Typname: Stahlrohr nach DIN 2448 249409
Type - IFC-Parameter - Typ in IFC-Datei exportieren: Vorgabe
Description: Stahlrohr nach DIN 2448
Pset_DistributionFlowElementCommon - Reference: Stahlrohr nach DIN 2448 249409; sets with these values: 2
Andere - Typ: Stahlrohr nach DIN 2448 249409; Familie: Stahlrohr nach DIN 2448 249409; Familie und Typ: Stahlrohr nach DIN 2448 249409: Stahlrohr nach DIN 2448 249409; Typ-ID: 2532760
Abhängigkeiten - Höhe von Ebene: 0 m; Verschieben mit umliegenden Elementen: no
Bemaßungen - Fläche: 0.0313888 m2; Volumen: 0.00173416 m3
IFC-Parameter - In IFC-Datei exportieren: Nach Typ; Pset MEP.Tech-Insulation thickness (mm): 100; Pset MEP.Geom-DN: 150; In IFC exportieren als: ifcflowsegment; NameOverride: Stahlrohr nach DIN 2448; IfcPresentationLayer: 0-TFT-H_Vorlauf; ObjectTypeOverride: Stahlrohr nach DIN 2448; Pset MEP.Name: Stahlrohr nach DIN 2448; IfcDescription: Stahlrohr nach DIN 2448; Pset MEP.Geom-Outer Ø (mm): 168.3; Pset MEP.Tech-Material: Stahlrohr nach DIN 2448; Pset MEP.Geom-Length (mm): 119.338
Phasen - Phase erstellt: Phase 01

# IfcFlowSegment: Stahlrohr nach DIN 2448 249461:Stahlrohr nach DIN 2448 249461, Stahlrohr nach DIN 2448
In: 1. Obergeschoss
Type - Material: IfcSurfaceStyle #9317
Type - Andere - Kategorie: Allgemeines Modell; Familienname: Stahlrohr nach DIN 2448 249461
Type - ID-Daten - Typname: Stahlrohr nach DIN 2448 249461
Type - IFC-Parameter - Typ in IFC-Datei exportieren: Vorgabe
Description: Stahlrohr nach DIN 2448
Pset_DistributionFlowElementCommon - Reference: Stahlrohr nach DIN 2448 249461; sets with these values: 2
Andere - Typ: Stahlrohr nach DIN 2448 249461; Familie: Stahlrohr nach DIN 2448 249461; Familie und Typ: Stahlrohr nach DIN 2448 249461: Stahlrohr nach DIN 2448 249461; Typ-ID: 2532774
Abhängigkeiten - Höhe von Ebene: 0 m; Verschieben mit umliegenden Elementen: no
Bemaßungen - Fläche: 13.0889 m2; Volumen: 1.50572 m3
IFC-Parameter - In IFC-Datei exportieren: Nach Typ; Pset MEP.Geom-DN: 200; Pset MEP.Tech-Insulation thickness (mm): 100; In IFC exportieren als: ifcflowsegment; NameOverride: Stahlrohr nach DIN 2448; IfcPresentationLayer: 0-TFT-H_Vorlauf; ObjectTypeOverride: Stahlrohr nach DIN 2448; Pset MEP.Name: Stahlrohr nach DIN 2448; IfcDescription: Stahlrohr nach DIN 2448; Pset MEP.Geom-Outer Ø (mm): 219.1; Pset MEP.Tech-Material: Stahlrohr nach DIN 2448; Pset MEP.Geom-Length (mm): 13123
Phasen - Phase erstellt: Phase 01

# IfcFlowSegment: Stahlrohr nach DIN 2448 249765:Stahlrohr nach DIN 2448 249765, Stahlrohr nach DIN 2448
In: 1. Obergeschoss
Type - Material: IfcSurfaceStyle #1741
Type - Andere - Kategorie: Allgemeines Modell; Familienname: Stahlrohr nach DIN 2448 249765
Type - ID-Daten - Typname: Stahlrohr nach DIN 2448 249765
Type - IFC-Parameter - Typ in IFC-Datei exportieren: Vorgabe
Description: Stahlrohr nach DIN 2448
Pset_DistributionFlowElementCommon - Reference: Stahlrohr nach DIN 2448 249765; sets with these values: 2
Andere - Typ: Stahlrohr nach DIN 2448 249765; Familie: Stahlrohr nach DIN 2448 249765; Familie und Typ: Stahlrohr nach DIN 2448 249765: Stahlrohr nach DIN 2448 249765; Typ-ID: 2532788
Abhängigkeiten - Höhe von Ebene: 0 m; Verschieben mit umliegenden Elementen: no
Bemaßungen - Fläche: 9.7924 m2; Volumen: 1.1265 m3
IFC-Parameter - In IFC-Datei exportieren: Nach Typ; Pset MEP.Geom-DN: 200; Pset MEP.Tech-Insulation thickness (mm): 100; In IFC exportieren als: ifcflowsegment; NameOverride: Stahlrohr nach DIN 2448; IfcPresentationLayer: 0-TFT-H_Ruecklauf; ObjectTypeOverride: Stahlrohr nach DIN 2448; Pset MEP.Name: Stahlrohr nach DIN 2448; IfcDescription: Stahlrohr nach DIN 2448; Pset MEP.Geom-Outer Ø (mm): 219.1; Pset MEP.Tech-Material: Stahlrohr nach DIN 2448; Pset MEP.Geom-Length (mm): 9817.92
Phasen - Phase erstellt: Phase 01

# IfcFlowSegment: Stahlrohr nach DIN 2448 250046:Stahlrohr nach DIN 2448 250046, Stahlrohr nach DIN 2448
In: 1. Obergeschoss
Type - Material: IfcSurfaceStyle #9317
Type - Andere - Kategorie: Allgemeines Modell; Familienname: Stahlrohr nach DIN 2448 250046
Type - ID-Daten - Typname: Stahlrohr nach DIN 2448 250046
Type - IFC-Parameter - Typ in IFC-Datei exportieren: Vorgabe
Description: Stahlrohr nach DIN 2448
Pset_DistributionFlowElementCommon - Reference: Stahlrohr nach DIN 2448 250046; sets with these values: 2
Andere - Typ: Stahlrohr nach DIN 2448 250046; Familie: Stahlrohr nach DIN 2448 250046; Familie und Typ: Stahlrohr nach DIN 2448 250046: Stahlrohr nach DIN 2448 250046; Typ-ID: 2532795
Abhängigkeiten - Höhe von Ebene: 0 m; Verschieben mit umliegenden Elementen: no
Bemaßungen - Fläche: 2.01357 m2; Volumen: 0.231637 m3
IFC-Parameter - In IFC-Datei exportieren: Nach Typ; Pset MEP.Geom-DN: 200; Pset MEP.Tech-Insulation thickness (mm): 100; In IFC exportieren als: ifcflowsegment; NameOverride: Stahlrohr nach DIN 2448; IfcPresentationLayer: 0-TFT-H_Vorlauf; ObjectTypeOverride: Stahlrohr nach DIN 2448; Pset MEP.Name: Stahlrohr nach DIN 2448; IfcDescription: Stahlrohr nach DIN 2448; Pset MEP.Geom-Outer Ø (mm): 219.1; Pset MEP.Tech-Material: Stahlrohr nach DIN 2448; Pset MEP.Geom-Length (mm): 2018.82
Phasen - Phase erstellt: Phase 01

# IfcFlowSegment: Stahlrohr nach DIN 2448 250350:Stahlrohr nach DIN 2448 250350, Stahlrohr nach DIN 2448
In: 1. Obergeschoss
Type - Material: IfcSurfaceStyle #1741
Type - Andere - Kategorie: Allgemeines Modell; Familienname: Stahlrohr nach DIN 2448 250350
Type - ID-Daten - Typname: Stahlrohr nach DIN 2448 250350
Type - IFC-Parameter - Typ in IFC-Datei exportieren: Vorgabe
Description: Stahlrohr nach DIN 2448
Pset_DistributionFlowElementCommon - Reference: Stahlrohr nach DIN 2448 250350; sets with these values: 2
Andere - Typ: Stahlrohr nach DIN 2448 250350; Familie: Stahlrohr nach DIN 2448 250350; Familie und Typ: Stahlrohr nach DIN 2448 250350: Stahlrohr nach DIN 2448 250350; Typ-ID: 2532809
Abhängigkeiten - Höhe von Ebene: 0 m; Verschieben mit umliegenden Elementen: no
Bemaßungen - Fläche: 4.06899 m2; Volumen: 0.468089 m3
IFC-Parameter - In IFC-Datei exportieren: Nach Typ; Pset MEP.Geom-DN: 200; Pset MEP.Tech-Insulation thickness (mm): 100; In IFC exportieren als: ifcflowsegment; NameOverride: Stahlrohr nach DIN 2448; IfcPresentationLayer: 0-TFT-H_Ruecklauf; ObjectTypeOverride: Stahlrohr nach DIN 2448; Pset MEP.Name: Stahlrohr nach DIN 2448; IfcDescription: Stahlrohr nach DIN 2448; Pset MEP.Geom-Outer Ø (mm): 219.1; Pset MEP.Tech-Material: Stahlrohr nach DIN 2448; Pset MEP.Geom-Length (mm): 4079.6
Phasen - Phase erstellt: Phase 01

# IfcFlowSegment: Stahlrohr nach DIN 2448 250631:Stahlrohr nach DIN 2448 250631, Stahlrohr nach DIN 2448
In: 1. Obergeschoss
Type - Material: IfcSurfaceStyle #9317
Type - Andere - Kategorie: Allgemeines Modell; Familienname: Stahlrohr nach DIN 2448 250631
Type - ID-Daten - Typname: Stahlrohr nach DIN 2448 250631
Type - IFC-Parameter - Typ in IFC-Datei exportieren: Vorgabe
Description: Stahlrohr nach DIN 2448
Pset_DistributionFlowElementCommon - Reference: Stahlrohr nach DIN 2448 250631; sets with these values: 2
Andere - Typ: Stahlrohr nach DIN 2448 250631; Familie: Stahlrohr nach DIN 2448 250631; Familie und Typ: Stahlrohr nach DIN 2448 250631: Stahlrohr nach DIN 2448 250631; Typ-ID: 2532816
Abhängigkeiten - Höhe von Ebene: 0 m; Verschieben mit umliegenden Elementen: no
Bemaßungen - Fläche: 0.516015 m2; Volumen: 0.0593614 m3
IFC-Parameter - In IFC-Datei exportieren: Nach Typ; Pset MEP.Geom-DN: 200; Pset MEP.Tech-Insulation thickness (mm): 100; In IFC exportieren als: ifcflowsegment; NameOverride: Stahlrohr nach DIN 2448; IfcPresentationLayer: 0-TFT-H_Vorlauf; ObjectTypeOverride: Stahlrohr nach DIN 2448; Pset MEP.Name: Stahlrohr nach DIN 2448; IfcDescription: Stahlrohr nach DIN 2448; Pset MEP.Geom-Outer Ø (mm): 219.1; Pset MEP.Tech-Material: Stahlrohr nach DIN 2448; Pset MEP.Geom-Length (mm): 517.36
Phasen - Phase erstellt: Phase 01

# IfcFlowSegment: Stahlrohr nach DIN 2448 250958:Stahlrohr nach DIN 2448 250958, Stahlrohr nach DIN 2448
In: 1. Obergeschoss
Type - Material: IfcSurfaceStyle #9317
Type - Andere - Kategorie: Allgemeines Modell; Familienname: Stahlrohr nach DIN 2448 250958
Type - ID-Daten - Typname: Stahlrohr nach DIN 2448 250958
Type - IFC-Parameter - Typ in IFC-Datei exportieren: Vorgabe
Description: Stahlrohr nach DIN 2448
Pset_DistributionFlowElementCommon - Reference: Stahlrohr nach DIN 2448 250958; sets with these values: 2
Andere - Typ: Stahlrohr nach DIN 2448 250958; Familie: Stahlrohr nach DIN 2448 250958; Familie und Typ: Stahlrohr nach DIN 2448 250958: Stahlrohr nach DIN 2448 250958; Typ-ID: 2532837
Abhängigkeiten - Höhe von Ebene: 0 m; Verschieben mit umliegenden Elementen: no
Bemaßungen - Fläche: 0.591549 m2; Volumen: 0.0680507 m3
IFC-Parameter - In IFC-Datei exportieren: Nach Typ; Pset MEP.Geom-DN: 200; Pset MEP.Tech-Insulation thickness (mm): 100; In IFC exportieren als: ifcflowsegment; NameOverride: Stahlrohr nach DIN 2448; IfcPresentationLayer: 0-TFT-H_Vorlauf; ObjectTypeOverride: Stahlrohr nach DIN 2448; Pset MEP.Name: Stahlrohr nach DIN 2448; IfcDescription: Stahlrohr nach DIN 2448; Pset MEP.Geom-Outer Ø (mm): 219.1; Pset MEP.Tech-Material: Stahlrohr nach DIN 2448; Pset MEP.Geom-Length (mm): 593.091
Phasen - Phase erstellt: Phase 01

# IfcFlowSegment: Stahlrohr nach DIN 2448 251681:Stahlrohr nach DIN 2448 251681, Stahlrohr nach DIN 2448
In: 1. Obergeschoss
Type - Material: IfcSurfaceStyle #1741
Type - Andere - Kategorie: Allgemeines Modell; Familienname: Stahlrohr nach DIN 2448 251681
Type - ID-Daten - Typname: Stahlrohr nach DIN 2448 251681
Type - IFC-Parameter - Typ in IFC-Datei exportieren: Vorgabe
Description: Stahlrohr nach DIN 2448
Pset_DistributionFlowElementCommon - Reference: Stahlrohr nach DIN 2448 251681; sets with these values: 2
Andere - Typ: Stahlrohr nach DIN 2448 251681; Familie: Stahlrohr nach DIN 2448 251681; Familie und Typ: Stahlrohr nach DIN 2448 251681: Stahlrohr nach DIN 2448 251681; Typ-ID: 2532883
Abhängigkeiten - Höhe von Ebene: 0 m; Verschieben mit umliegenden Elementen: no
Bemaßungen - Fläche: 5.15372 m2; Volumen: 0.4415 m3
IFC-Parameter - In IFC-Datei exportieren: Nach Typ; Pset MEP.Tech-Insulation thickness (mm): 100; Pset MEP.Geom-DN: 100; In IFC exportieren als: ifcflowsegment; NameOverride: Stahlrohr nach DIN 2448; IfcPresentationLayer: 0-TFT-H_Ruecklauf; ObjectTypeOverride: Stahlrohr nach DIN 2448; Pset MEP.Name: Stahlrohr nach DIN 2448; IfcDescription: Stahlrohr nach DIN 2448; Pset MEP.Geom-Outer Ø (mm): 114.3; Pset MEP.Tech-Material: Stahlrohr nach DIN 2448; Pset MEP.Geom-Length (mm): 7694.07
Phasen - Phase erstellt: Phase 01

# IfcFlowSegment: Stahlrohr nach DIN 2448 251962:Stahlrohr nach DIN 2448 251962, Stahlrohr nach DIN 2448
In: 1. Obergeschoss
Type - Material: IfcSurfaceStyle #9317
Type - Andere - Kategorie: Allgemeines Modell; Familienname: Stahlrohr nach DIN 2448 251962
Type - ID-Daten - Typname: Stahlrohr nach DIN 2448 251962
Type - IFC-Parameter - Typ in IFC-Datei exportieren: Vorgabe
Description: Stahlrohr nach DIN 2448
Pset_DistributionFlowElementCommon - Reference: Stahlrohr nach DIN 2448 251962; sets with these values: 2
Andere - Typ: Stahlrohr nach DIN 2448 251962; Familie: Stahlrohr nach DIN 2448 251962; Familie und Typ: Stahlrohr nach DIN 2448 251962: Stahlrohr nach DIN 2448 251962; Typ-ID: 2532890
Abhängigkeiten - Höhe von Ebene: 0 m; Verschieben mit umliegenden Elementen: no
Bemaßungen - Fläche: 4.79965 m2; Volumen: 0.411168 m3
IFC-Parameter - In IFC-Datei exportieren: Nach Typ; Pset MEP.Tech-Insulation thickness (mm): 100; Pset MEP.Geom-DN: 100; In IFC exportieren als: ifcflowsegment; NameOverride: Stahlrohr nach DIN 2448; IfcPresentationLayer: 0-TFT-H_Vorlauf; ObjectTypeOverride: Stahlrohr nach DIN 2448; Pset MEP.Name: Stahlrohr nach DIN 2448; IfcDescription: Stahlrohr nach DIN 2448; Pset MEP.Geom-Outer Ø (mm): 114.3; Pset MEP.Tech-Material: Stahlrohr nach DIN 2448; Pset MEP.Geom-Length (mm): 7165.47
Phasen - Phase erstellt: Phase 01

# IfcFlowSegment: Stahlrohr nach DIN 2448 252266:Stahlrohr nach DIN 2448 252266, Stahlrohr nach DIN 2448
In: 1. Obergeschoss
Type - Material: IfcSurfaceStyle #1741
Type - Andere - Kategorie: Allgemeines Modell; Familienname: Stahlrohr nach DIN 2448 252266
Type - ID-Daten - Typname: Stahlrohr nach DIN 2448 252266
Type - IFC-Parameter - Typ in IFC-Datei exportieren: Vorgabe
Description: Stahlrohr nach DIN 2448
Pset_DistributionFlowElementCommon - Reference: Stahlrohr nach DIN 2448 252266; sets with these values: 2
Andere - Typ: Stahlrohr nach DIN 2448 252266; Familie: Stahlrohr nach DIN 2448 252266; Familie und Typ: Stahlrohr nach DIN 2448 252266: Stahlrohr nach DIN 2448 252266; Typ-ID: 2532904
Abhängigkeiten - Höhe von Ebene: 0 m; Verschieben mit umliegenden Elementen: no
Bemaßungen - Fläche: 2.14169 m2; Volumen: 0.246376 m3
IFC-Parameter - In IFC-Datei exportieren: Nach Typ; Pset MEP.Geom-DN: 200; Pset MEP.Tech-Insulation thickness (mm): 100; In IFC exportieren als: ifcflowsegment; NameOverride: Stahlrohr nach DIN 2448; IfcPresentationLayer: 0-TFT-H_Ruecklauf; ObjectTypeOverride: Stahlrohr nach DIN 2448; Pset MEP.Name: Stahlrohr nach DIN 2448; IfcDescription: Stahlrohr nach DIN 2448; Pset MEP.Geom-Outer Ø (mm): 219.1; Pset MEP.Tech-Material: Stahlrohr nach DIN 2448; Pset MEP.Geom-Length (mm): 2147.27
Phasen - Phase erstellt: Phase 01

# IfcFlowSegment: Stahlrohr nach DIN 2448 252547:Stahlrohr nach DIN 2448 252547, Stahlrohr nach DIN 2448
In: 1. Obergeschoss
Type - Material: IfcSurfaceStyle #1741
Type - Andere - Kategorie: Allgemeines Modell; Familienname: Stahlrohr nach DIN 2448 252547
Type - ID-Daten - Typname: Stahlrohr nach DIN 2448 252547
Type - IFC-Parameter - Typ in IFC-Datei exportieren: Vorgabe
Description: Stahlrohr nach DIN 2448
Pset_DistributionFlowElementCommon - Reference: Stahlrohr nach DIN 2448 252547; sets with these values: 2
Andere - Typ: Stahlrohr nach DIN 2448 252547; Familie: Stahlrohr nach DIN 2448 252547; Familie und Typ: Stahlrohr nach DIN 2448 252547: Stahlrohr nach DIN 2448 252547; Typ-ID: 2532911
Abhängigkeiten - Höhe von Ebene: 0 m; Verschieben mit umliegenden Elementen: no
Bemaßungen - Fläche: 0.334384 m2; Volumen: 0.0384669 m3
IFC-Parameter - In IFC-Datei exportieren: Nach Typ; Pset MEP.Geom-DN: 200; Pset MEP.Tech-Insulation thickness (mm): 100; In IFC exportieren als: ifcflowsegment; NameOverride: Stahlrohr nach DIN 2448; IfcPresentationLayer: 0-TFT-H_Ruecklauf; ObjectTypeOverride: Stahlrohr nach DIN 2448; Pset MEP.Name: Stahlrohr nach DIN 2448; IfcDescription: Stahlrohr nach DIN 2448; Pset MEP.Geom-Outer Ø (mm): 219.1; Pset MEP.Tech-Material: Stahlrohr nach DIN 2448; Pset MEP.Geom-Length (mm): 335.256
Phasen - Phase erstellt: Phase 01

# IfcFlowSegment: Stahlrohr nach DIN 2448 252828:Stahlrohr nach DIN 2448 252828, Stahlrohr nach DIN 2448
In: 1. Obergeschoss
Type - Material: IfcSurfaceStyle #1741
Type - Andere - Kategorie: Allgemeines Modell; Familienname: Stahlrohr nach DIN 2448 252828
Type - ID-Daten - Typname: Stahlrohr nach DIN 2448 252828
Type - IFC-Parameter - Typ in IFC-Datei exportieren: Vorgabe
Description: Stahlrohr nach DIN 2448
Pset_DistributionFlowElementCommon - Reference: Stahlrohr nach DIN 2448 252828; sets with these values: 2
Andere - Typ: Stahlrohr nach DIN 2448 252828; Familie: Stahlrohr nach DIN 2448 252828; Familie und Typ: Stahlrohr nach DIN 2448 252828: Stahlrohr nach DIN 2448 252828; Typ-ID: 2532918
Abhängigkeiten - Höhe von Ebene: 0 m; Verschieben mit umliegenden Elementen: no
Bemaßungen - Fläche: 0.0287987 m2; Volumen: 0.00331295 m3
IFC-Parameter - In IFC-Datei exportieren: Nach Typ; Pset MEP.Geom-DN: 200; Pset MEP.Tech-Insulation thickness (mm): 100; In IFC exportieren als: ifcflowsegment; NameOverride: Stahlrohr nach DIN 2448; IfcPresentationLayer: 0-TFT-H_Ruecklauf; ObjectTypeOverride: Stahlrohr nach DIN 2448; Pset MEP.Name: Stahlrohr nach DIN 2448; IfcDescription: Stahlrohr nach DIN 2448; Pset MEP.Geom-Outer Ø (mm): 219.1; Pset MEP.Tech-Material: Stahlrohr nach DIN 2448; Pset MEP.Geom-Length (mm): 28.8737
Phasen - Phase erstellt: Phase 01

# IfcFlowSegment: Stahlrohr nach DIN 2448 256218:Stahlrohr nach DIN 2448 256218, Stahlrohr nach DIN 2448
In: 1. Obergeschoss
Type - Material: IfcSurfaceStyle #1741
Type - Andere - Kategorie: Allgemeines Modell; Familienname: Stahlrohr nach DIN 2448 256218
Type - ID-Daten - Typname: Stahlrohr nach DIN 2448 256218
Type - IFC-Parameter - Typ in IFC-Datei exportieren: Vorgabe
Description: Stahlrohr nach DIN 2448
Pset_DistributionFlowElementCommon - Reference: Stahlrohr nach DIN 2448 256218; sets with these values: 2
Andere - Typ: Stahlrohr nach DIN 2448 256218; Familie: Stahlrohr nach DIN 2448 256218; Familie und Typ: Stahlrohr nach DIN 2448 256218: Stahlrohr nach DIN 2448 256218; Typ-ID: 2532967
Abhängigkeiten - Höhe von Ebene: 0 m; Verschieben mit umliegenden Elementen: no
Bemaßungen - Fläche: 0.153429 m2; Volumen: 0.0117296 m3
IFC-Parameter - In IFC-Datei exportieren: Nach Typ; Pset MEP.Tech-Insulation thickness (mm): 100; Pset MEP.Geom-DN: 65; In IFC exportieren als: ifcflowsegment; NameOverride: Stahlrohr nach DIN 2448; IfcPresentationLayer: 0-TFT-H_Ruecklauf; ObjectTypeOverride: Stahlrohr nach DIN 2448; Pset MEP.Name: Stahlrohr nach DIN 2448; IfcDescription: Stahlrohr nach DIN 2448; Pset MEP.Geom-Outer Ø (mm): 76.1; Pset MEP.Tech-Material: Stahlrohr nach DIN 2448; Pset MEP.Geom-Length (mm): 278.745
Phasen - Phase erstellt: Phase 01

# IfcFlowSegment: Stahlrohr nach DIN 2448 258520:Stahlrohr nach DIN 2448 258520, Stahlrohr nach DIN 2448
In: 1. Obergeschoss
Type - Material: IfcSurfaceStyle #1741
Type - Andere - Kategorie: Allgemeines Modell; Familienname: Stahlrohr nach DIN 2448 258520
Type - ID-Daten - Typname: Stahlrohr nach DIN 2448 258520
Type - IFC-Parameter - Typ in IFC-Datei exportieren: Vorgabe
Description: Stahlrohr nach DIN 2448
Pset_DistributionFlowElementCommon - Reference: Stahlrohr nach DIN 2448 258520; sets with these values: 2
Andere - Typ: Stahlrohr nach DIN 2448 258520; Familie: Stahlrohr nach DIN 2448 258520; Familie und Typ: Stahlrohr nach DIN 2448 258520: Stahlrohr nach DIN 2448 258520; Typ-ID: 2532988
Abhängigkeiten - Höhe von Ebene: 0 m; Verschieben mit umliegenden Elementen: no
Bemaßungen - Fläche: 0.271347 m2; Volumen: 0.0207443 m3
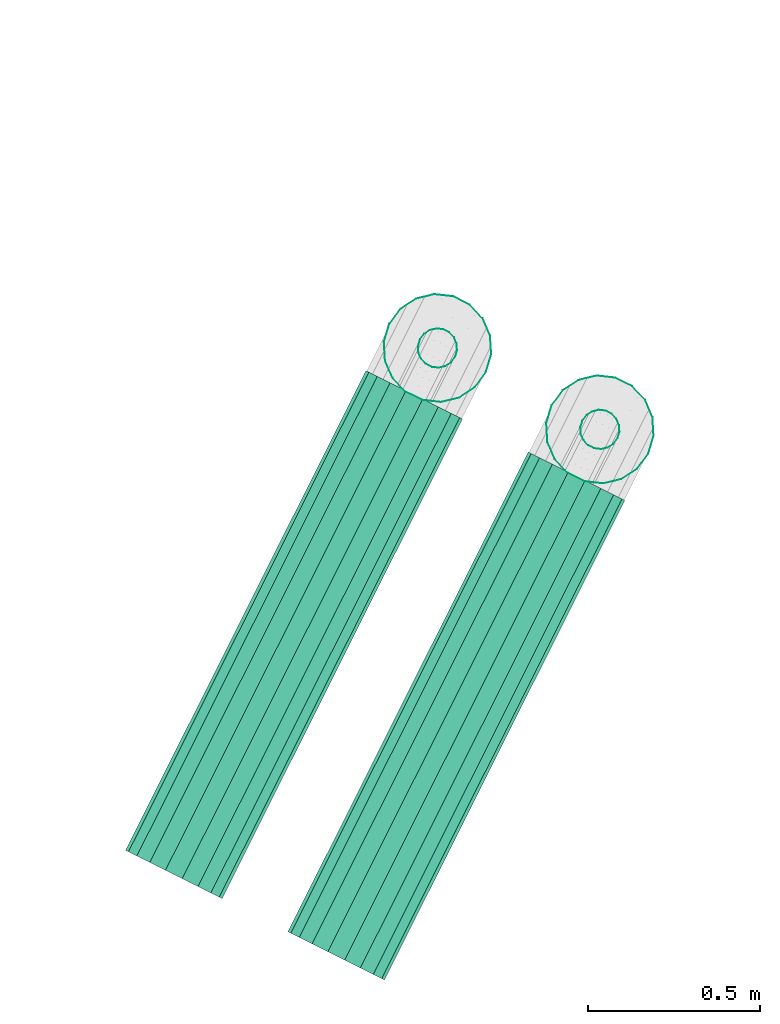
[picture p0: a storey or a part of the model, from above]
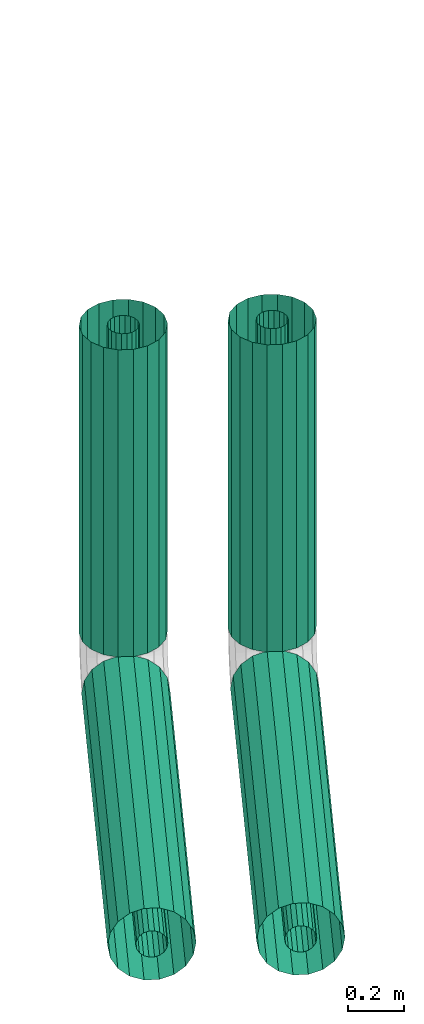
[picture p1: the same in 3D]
Properties of the parts of a building model (IFC2X3), part 18 of 23

# IfcFlowSegment: Stahlrohr nach DIN 2448 258520:Stahlrohr nach DIN 2448 258520, Stahlrohr nach DIN 2448
IFC-Parameter - In IFC-Datei exportieren: Nach Typ; Pset MEP.Tech-Insulation thickness (mm): 100; Pset MEP.Geom-DN: 65; In IFC exportieren als: ifcflowsegment; NameOverride: Stahlrohr nach DIN 2448; IfcPresentationLayer: 0-TFT-H_Ruecklauf; ObjectTypeOverride: Stahlrohr nach DIN 2448; Pset MEP.Name: Stahlrohr nach DIN 2448; IfcDescription: Stahlrohr nach DIN 2448; Pset MEP.Geom-Outer Ø (mm): 76.1; Pset MEP.Tech-Material: Stahlrohr nach DIN 2448; Pset MEP.Geom-Length (mm): 492.973
Phasen - Phase erstellt: Phase 01

# IfcFlowSegment: Stahlrohr nach DIN 2448 258824:Stahlrohr nach DIN 2448 258824, Stahlrohr nach DIN 2448
In: 1. Obergeschoss
Type - Material: IfcSurfaceStyle #1741
Type - Andere - Kategorie: Allgemeines Modell; Familienname: Stahlrohr nach DIN 2448 258824
Type - ID-Daten - Typname: Stahlrohr nach DIN 2448 258824
Type - IFC-Parameter - Typ in IFC-Datei exportieren: Vorgabe
Description: Stahlrohr nach DIN 2448
Pset_DistributionFlowElementCommon - Reference: Stahlrohr nach DIN 2448 258824; sets with these values: 2
Andere - Typ: Stahlrohr nach DIN 2448 258824; Familie: Stahlrohr nach DIN 2448 258824; Familie und Typ: Stahlrohr nach DIN 2448 258824: Stahlrohr nach DIN 2448 258824; Typ-ID: 2533002
Abhängigkeiten - Höhe von Ebene: 0 m; Verschieben mit umliegenden Elementen: no
Bemaßungen - Fläche: 0.142971 m2; Volumen: 0.01093 m3
IFC-Parameter - In IFC-Datei exportieren: Nach Typ; Pset MEP.Tech-Insulation thickness (mm): 100; Pset MEP.Geom-DN: 65; In IFC exportieren als: ifcflowsegment; NameOverride: Stahlrohr nach DIN 2448; IfcPresentationLayer: 0-TFT-H_Ruecklauf; ObjectTypeOverride: Stahlrohr nach DIN 2448; Pset MEP.Name: Stahlrohr nach DIN 2448; IfcDescription: Stahlrohr nach DIN 2448; Pset MEP.Geom-Outer Ø (mm): 76.1; Pset MEP.Tech-Material: Stahlrohr nach DIN 2448; Pset MEP.Geom-Length (mm): 259.745
Phasen - Phase erstellt: Phase 01

# IfcFlowSegment: Stahlrohr nach DIN 2448 259157:Stahlrohr nach DIN 2448 259157, Stahlrohr nach DIN 2448
In: 1. Obergeschoss
Type - Material: IfcSurfaceStyle #1741
Type - Andere - Kategorie: Allgemeines Modell; Familienname: Stahlrohr nach DIN 2448 259157
Type - ID-Daten - Typname: Stahlrohr nach DIN 2448 259157
Type - IFC-Parameter - Typ in IFC-Datei exportieren: Vorgabe
Description: Stahlrohr nach DIN 2448
Pset_DistributionFlowElementCommon - Reference: Stahlrohr nach DIN 2448 259157; sets with these values: 2
Andere - Typ: Stahlrohr nach DIN 2448 259157; Familie: Stahlrohr nach DIN 2448 259157; Familie und Typ: Stahlrohr nach DIN 2448 259157: Stahlrohr nach DIN 2448 259157; Typ-ID: 2533023
Abhängigkeiten - Höhe von Ebene: 0 m; Verschieben mit umliegenden Elementen: no
Bemaßungen - Fläche: 0.142971 m2; Volumen: 0.01093 m3
IFC-Parameter - In IFC-Datei exportieren: Nach Typ; Pset MEP.Tech-Insulation thickness (mm): 100; Pset MEP.Geom-DN: 65; In IFC exportieren als: ifcflowsegment; NameOverride: Stahlrohr nach DIN 2448; IfcPresentationLayer: 0-TFT-H_Ruecklauf; ObjectTypeOverride: Stahlrohr nach DIN 2448; Pset MEP.Name: Stahlrohr nach DIN 2448; IfcDescription: Stahlrohr nach DIN 2448; Pset MEP.Geom-Outer Ø (mm): 76.1; Pset MEP.Tech-Material: Stahlrohr nach DIN 2448; Pset MEP.Geom-Length (mm): 259.745
Phasen - Phase erstellt: Phase 01

# IfcFlowSegment: Stahlrohr nach DIN 2448 259989:Stahlrohr nach DIN 2448 259989, Stahlrohr nach DIN 2448
In: 1. Obergeschoss
Type - Material: IfcSurfaceStyle #1741
Type - Andere - Kategorie: Allgemeines Modell; Familienname: Stahlrohr nach DIN 2448 259989
Type - ID-Daten - Typname: Stahlrohr nach DIN 2448 259989
Type - IFC-Parameter - Typ in IFC-Datei exportieren: Vorgabe
Description: Stahlrohr nach DIN 2448
Pset_DistributionFlowElementCommon - Reference: Stahlrohr nach DIN 2448 259989; sets with these values: 2
Andere - Typ: Stahlrohr nach DIN 2448 259989; Familie: Stahlrohr nach DIN 2448 259989; Familie und Typ: Stahlrohr nach DIN 2448 259989: Stahlrohr nach DIN 2448 259989; Typ-ID: 2533051
Abhängigkeiten - Höhe von Ebene: 0 m; Verschieben mit umliegenden Elementen: no
Bemaßungen - Fläche: 0.153429 m2; Volumen: 0.0117296 m3
IFC-Parameter - In IFC-Datei exportieren: Nach Typ; Pset MEP.Tech-Insulation thickness (mm): 100; Pset MEP.Geom-DN: 65; In IFC exportieren als: ifcflowsegment; NameOverride: Stahlrohr nach DIN 2448; IfcPresentationLayer: 0-TFT-H_Ruecklauf; ObjectTypeOverride: Stahlrohr nach DIN 2448; Pset MEP.Name: Stahlrohr nach DIN 2448; IfcDescription: Stahlrohr nach DIN 2448; Pset MEP.Geom-Outer Ø (mm): 76.1; Pset MEP.Tech-Material: Stahlrohr nach DIN 2448; Pset MEP.Geom-Length (mm): 278.745
Phasen - Phase erstellt: Phase 01

# IfcFlowSegment: Stahlrohr nach DIN 2448 260058:Stahlrohr nach DIN 2448 260058, Stahlrohr nach DIN 2448
In: 1. Obergeschoss
Type - Material: IfcSurfaceStyle #1741
Type - Andere - Kategorie: Allgemeines Modell; Familienname: Stahlrohr nach DIN 2448 260058
Type - ID-Daten - Typname: Stahlrohr nach DIN 2448 260058
Type - IFC-Parameter - Typ in IFC-Datei exportieren: Vorgabe
Description: Stahlrohr nach DIN 2448
Pset_DistributionFlowElementCommon - Reference: Stahlrohr nach DIN 2448 260058; sets with these values: 2
Andere - Typ: Stahlrohr nach DIN 2448 260058; Familie: Stahlrohr nach DIN 2448 260058; Familie und Typ: Stahlrohr nach DIN 2448 260058: Stahlrohr nach DIN 2448 260058; Typ-ID: 2533072
Abhängigkeiten - Höhe von Ebene: 0 m; Verschieben mit umliegenden Elementen: no
Bemaßungen - Fläche: 0.271347 m2; Volumen: 0.0207443 m3
IFC-Parameter - In IFC-Datei exportieren: Nach Typ; Pset MEP.Tech-Insulation thickness (mm): 100; Pset MEP.Geom-DN: 65; In IFC exportieren als: ifcflowsegment; NameOverride: Stahlrohr nach DIN 2448; IfcPresentationLayer: 0-TFT-H_Ruecklauf; ObjectTypeOverride: Stahlrohr nach DIN 2448; Pset MEP.Name: Stahlrohr nach DIN 2448; IfcDescription: Stahlrohr nach DIN 2448; Pset MEP.Geom-Outer Ø (mm): 76.1; Pset MEP.Tech-Material: Stahlrohr nach DIN 2448; Pset MEP.Geom-Length (mm): 492.973
Phasen - Phase erstellt: Phase 01

# IfcFlowSegment: Stahlrohr nach DIN 2448 261809:Stahlrohr nach DIN 2448 261809, Stahlrohr nach DIN 2448
In: 1. Obergeschoss
Type - Material: IfcSurfaceStyle #1741
Type - Andere - Kategorie: Allgemeines Modell; Familienname: Stahlrohr nach DIN 2448 261809
Type - ID-Daten - Typname: Stahlrohr nach DIN 2448 261809
Type - IFC-Parameter - Typ in IFC-Datei exportieren: Vorgabe
Description: Stahlrohr nach DIN 2448
Pset_DistributionFlowElementCommon - Reference: Stahlrohr nach DIN 2448 261809; sets with these values: 2
Andere - Typ: Stahlrohr nach DIN 2448 261809; Familie: Stahlrohr nach DIN 2448 261809; Familie und Typ: Stahlrohr nach DIN 2448 261809: Stahlrohr nach DIN 2448 261809; Typ-ID: 2533086
Abhängigkeiten - Höhe von Ebene: 0 m; Verschieben mit umliegenden Elementen: no
Bemaßungen - Fläche: 0.0213716 m2; Volumen: 0.00163384 m3
IFC-Parameter - In IFC-Datei exportieren: Nach Typ; Pset MEP.Tech-Insulation thickness (mm): 100; Pset MEP.Geom-DN: 65; In IFC exportieren als: ifcflowsegment; NameOverride: Stahlrohr nach DIN 2448; IfcPresentationLayer: 0-TFT-H_Ruecklauf; ObjectTypeOverride: Stahlrohr nach DIN 2448; Pset MEP.Name: Stahlrohr nach DIN 2448; IfcDescription: Stahlrohr nach DIN 2448; Pset MEP.Geom-Outer Ø (mm): 76.1; Pset MEP.Tech-Material: Stahlrohr nach DIN 2448; Pset MEP.Geom-Length (mm): 38.8271
Phasen - Phase erstellt: Phase 01

# IfcFlowSegment: Stahlrohr nach DIN 2448 262142:Stahlrohr nach DIN 2448 262142, Stahlrohr nach DIN 2448
In: 1. Obergeschoss
Type - Material: IfcSurfaceStyle #1741
Type - Andere - Kategorie: Allgemeines Modell; Familienname: Stahlrohr nach DIN 2448 262142
Type - ID-Daten - Typname: Stahlrohr nach DIN 2448 262142
Type - IFC-Parameter - Typ in IFC-Datei exportieren: Vorgabe
Description: Stahlrohr nach DIN 2448
Pset_DistributionFlowElementCommon - Reference: Stahlrohr nach DIN 2448 262142; sets with these values: 2
Andere - Typ: Stahlrohr nach DIN 2448 262142; Familie: Stahlrohr nach DIN 2448 262142; Familie und Typ: Stahlrohr nach DIN 2448 262142: Stahlrohr nach DIN 2448 262142; Typ-ID: 2533107
Abhängigkeiten - Höhe von Ebene: 0 m; Verschieben mit umliegenden Elementen: no
Bemaßungen - Fläche: 0.0220953 m2; Volumen: 0.00168917 m3
IFC-Parameter - In IFC-Datei exportieren: Nach Typ; Pset MEP.Tech-Insulation thickness (mm): 100; Pset MEP.Geom-DN: 65; In IFC exportieren als: ifcflowsegment; NameOverride: Stahlrohr nach DIN 2448; IfcPresentationLayer: 0-TFT-H_Ruecklauf; ObjectTypeOverride: Stahlrohr nach DIN 2448; Pset MEP.Name: Stahlrohr nach DIN 2448; IfcDescription: Stahlrohr nach DIN 2448; Pset MEP.Geom-Outer Ø (mm): 76.1; Pset MEP.Tech-Material: Stahlrohr nach DIN 2448; Pset MEP.Geom-Length (mm): 40.1419
Phasen - Phase erstellt: Phase 01

# IfcFlowSegment: Stahlrohr nach DIN 2448 262423:Stahlrohr nach DIN 2448 262423, Stahlrohr nach DIN 2448
In: 1. Obergeschoss
Type - Material: IfcSurfaceStyle #1741
Type - Andere - Kategorie: Allgemeines Modell; Familienname: Stahlrohr nach DIN 2448 262423
Type - ID-Daten - Typname: Stahlrohr nach DIN 2448 262423
Type - IFC-Parameter - Typ in IFC-Datei exportieren: Vorgabe
Description: Stahlrohr nach DIN 2448
Pset_DistributionFlowElementCommon - Reference: Stahlrohr nach DIN 2448 262423; sets with these values: 2
Andere - Typ: Stahlrohr nach DIN 2448 262423; Familie: Stahlrohr nach DIN 2448 262423; Familie und Typ: Stahlrohr nach DIN 2448 262423: Stahlrohr nach DIN 2448 262423; Typ-ID: 2533114
Abhängigkeiten - Höhe von Ebene: 0 m; Verschieben mit umliegenden Elementen: no
Bemaßungen - Fläche: 0.118322 m2; Volumen: 0.00904562 m3
IFC-Parameter - In IFC-Datei exportieren: Nach Typ; Pset MEP.Tech-Insulation thickness (mm): 100; Pset MEP.Geom-DN: 65; In IFC exportieren als: ifcflowsegment; NameOverride: Stahlrohr nach DIN 2448; IfcPresentationLayer: 0-TFT-H_Ruecklauf; ObjectTypeOverride: Stahlrohr nach DIN 2448; Pset MEP.Name: Stahlrohr nach DIN 2448; IfcDescription: Stahlrohr nach DIN 2448; Pset MEP.Geom-Outer Ø (mm): 76.1; Pset MEP.Tech-Material: Stahlrohr nach DIN 2448; Pset MEP.Geom-Length (mm): 214.962
Phasen - Phase erstellt: Phase 01

# IfcFlowSegment: Stahlrohr nach DIN 2448 262773:Stahlrohr nach DIN 2448 262773, Stahlrohr nach DIN 2448
In: 1. Obergeschoss
Type - Material: IfcSurfaceStyle #9317
Type - Andere - Kategorie: Allgemeines Modell; Familienname: Stahlrohr nach DIN 2448 262773
Type - ID-Daten - Typname: Stahlrohr nach DIN 2448 262773
Type - IFC-Parameter - Typ in IFC-Datei exportieren: Vorgabe
Description: Stahlrohr nach DIN 2448
Pset_DistributionFlowElementCommon - Reference: Stahlrohr nach DIN 2448 262773; sets with these values: 2
Andere - Typ: Stahlrohr nach DIN 2448 262773; Familie: Stahlrohr nach DIN 2448 262773; Familie und Typ: Stahlrohr nach DIN 2448 262773: Stahlrohr nach DIN 2448 262773; Typ-ID: 2533142
Abhängigkeiten - Höhe von Ebene: 0 m; Verschieben mit umliegenden Elementen: no
Bemaßungen - Fläche: 0.360804 m2; Volumen: 0.0415062 m3
IFC-Parameter - In IFC-Datei exportieren: Nach Typ; Pset MEP.Geom-DN: 200; Pset MEP.Tech-Insulation thickness (mm): 100; In IFC exportieren als: ifcflowsegment; NameOverride: Stahlrohr nach DIN 2448; IfcPresentationLayer: 0-TFT-H_Vorlauf; ObjectTypeOverride: Stahlrohr nach DIN 2448; Pset MEP.Name: Stahlrohr nach DIN 2448; IfcDescription: Stahlrohr nach DIN 2448; Pset MEP.Geom-Outer Ø (mm): 219.1; Pset MEP.Tech-Material: Stahlrohr nach DIN 2448; Pset MEP.Geom-Length (mm): 361.744
Phasen - Phase erstellt: Phase 01

# IfcFlowSegment: Stahlrohr nach DIN 2448 266762:Stahlrohr nach DIN 2448 266762, Stahlrohr nach DIN 2448
In: 1. Obergeschoss
Type - Material: IfcSurfaceStyle #9317
Type - Andere - Kategorie: Allgemeines Modell; Familienname: Stahlrohr nach DIN 2448 266762
Type - ID-Daten - Typname: Stahlrohr nach DIN 2448 266762
Type - IFC-Parameter - Typ in IFC-Datei exportieren: Vorgabe
Description: Stahlrohr nach DIN 2448
Pset_DistributionFlowElementCommon - Reference: Stahlrohr nach DIN 2448 266762; sets with these values: 2
Andere - Typ: Stahlrohr nach DIN 2448 266762; Familie: Stahlrohr nach DIN 2448 266762; Familie und Typ: Stahlrohr nach DIN 2448 266762: Stahlrohr nach DIN 2448 266762; Typ-ID: 2533205
Abhängigkeiten - Höhe von Ebene: 0 m; Verschieben mit umliegenden Elementen: no
Bemaßungen - Fläche: 0.236207 m2; Volumen: 0.020235 m3
IFC-Parameter - In IFC-Datei exportieren: Nach Typ; Pset MEP.Tech-Insulation thickness (mm): 100; Pset MEP.Geom-DN: 100; In IFC exportieren als: ifcflowsegment; NameOverride: Stahlrohr nach DIN 2448; IfcPresentationLayer: 0-TFT-H_Vorlauf; ObjectTypeOverride: Stahlrohr nach DIN 2448; Pset MEP.Name: Stahlrohr nach DIN 2448; IfcDescription: Stahlrohr nach DIN 2448; Pset MEP.Geom-Outer Ø (mm): 114.3; Pset MEP.Tech-Material: Stahlrohr nach DIN 2448; Pset MEP.Geom-Length (mm): 352.637
Phasen - Phase erstellt: Phase 01

# IfcFlowSegment: Stahlrohr nach DIN 2448 267066:Stahlrohr nach DIN 2448 267066, Stahlrohr nach DIN 2448
In: 1. Obergeschoss
Type - Material: IfcSurfaceStyle #9317
Type - Andere - Kategorie: Allgemeines Modell; Familienname: Stahlrohr nach DIN 2448 267066
Type - ID-Daten - Typname: Stahlrohr nach DIN 2448 267066
Type - IFC-Parameter - Typ in IFC-Datei exportieren: Vorgabe
Description: Stahlrohr nach DIN 2448
Pset_DistributionFlowElementCommon - Reference: Stahlrohr nach DIN 2448 267066; sets with these values: 2
Andere - Typ: Stahlrohr nach DIN 2448 267066; Familie: Stahlrohr nach DIN 2448 267066; Familie und Typ: Stahlrohr nach DIN 2448 267066: Stahlrohr nach DIN 2448 267066; Typ-ID: 2533219
Abhängigkeiten - Höhe von Ebene: 0 m; Verschieben mit umliegenden Elementen: no
Bemaßungen - Fläche: 0.11923 m2; Volumen: 0.010214 m3
IFC-Parameter - In IFC-Datei exportieren: Nach Typ; Pset MEP.Tech-Insulation thickness (mm): 100; Pset MEP.Geom-DN: 100; In IFC exportieren als: ifcflowsegment; NameOverride: Stahlrohr nach DIN 2448; IfcPresentationLayer: 0-TFT-H_Vorlauf; ObjectTypeOverride: Stahlrohr nach DIN 2448; Pset MEP.Name: Stahlrohr nach DIN 2448; IfcDescription: Stahlrohr nach DIN 2448; Pset MEP.Geom-Outer Ø (mm): 114.3; Pset MEP.Tech-Material: Stahlrohr nach DIN 2448; Pset MEP.Geom-Length (mm): 178
Phasen - Phase erstellt: Phase 01

# IfcFlowSegment: Stahlrohr nach DIN 2448 267422:Stahlrohr nach DIN 2448 267422, Stahlrohr nach DIN 2448
In: 1. Obergeschoss
Type - Material: IfcSurfaceStyle #9317
Type - Andere - Kategorie: Allgemeines Modell; Familienname: Stahlrohr nach DIN 2448 267422
Type - ID-Daten - Typname: Stahlrohr nach DIN 2448 267422
Type - IFC-Parameter - Typ in IFC-Datei exportieren: Vorgabe
Description: Stahlrohr nach DIN 2448
Pset_DistributionFlowElementCommon - Reference: Stahlrohr nach DIN 2448 267422; sets with these values: 2
Andere - Typ: Stahlrohr nach DIN 2448 267422; Familie: Stahlrohr nach DIN 2448 267422; Familie und Typ: Stahlrohr nach DIN 2448 267422: Stahlrohr nach DIN 2448 267422; Typ-ID: 2533247
Abhängigkeiten - Höhe von Ebene: 0 m; Verschieben mit umliegenden Elementen: no
Bemaßungen - Fläche: 0.11923 m2; Volumen: 0.010214 m3
IFC-Parameter - In IFC-Datei exportieren: Nach Typ; Pset MEP.Tech-Insulation thickness (mm): 100; Pset MEP.Geom-DN: 100; Pset MEP.Geom-Length (mm): 178; In IFC exportieren als: ifcflowsegment; NameOverride: Stahlrohr nach DIN 2448; IfcPresentationLayer: 0-TFT-H_Vorlauf; ObjectTypeOverride: Stahlrohr nach DIN 2448; Pset MEP.Name: Stahlrohr nach DIN 2448; IfcDescription: Stahlrohr nach DIN 2448; Pset MEP.Geom-Outer Ø (mm): 114.3; Pset MEP.Tech-Material: Stahlrohr nach DIN 2448
Phasen - Phase erstellt: Phase 01

# IfcFlowSegment: Stahlrohr nach DIN 2448 267445:Stahlrohr nach DIN 2448 267445, Stahlrohr nach DIN 2448
In: 1. Obergeschoss
Type - Material: IfcSurfaceStyle #9317
Type - Andere - Kategorie: Allgemeines Modell; Familienname: Stahlrohr nach DIN 2448 267445
Type - ID-Daten - Typname: Stahlrohr nach DIN 2448 267445
Type - IFC-Parameter - Typ in IFC-Datei exportieren: Vorgabe
Description: Stahlrohr nach DIN 2448
Pset_DistributionFlowElementCommon - Reference: Stahlrohr nach DIN 2448 267445; sets with these values: 2
Andere - Typ: Stahlrohr nach DIN 2448 267445; Familie: Stahlrohr nach DIN 2448 267445; Familie und Typ: Stahlrohr nach DIN 2448 267445: Stahlrohr nach DIN 2448 267445; Typ-ID: 2533254
Abhängigkeiten - Höhe von Ebene: 0 m; Verschieben mit umliegenden Elementen: no
Bemaßungen - Fläche: 0.236207 m2; Volumen: 0.020235 m3
IFC-Parameter - In IFC-Datei exportieren: Nach Typ; Pset MEP.Tech-Insulation thickness (mm): 100; Pset MEP.Geom-DN: 100; In IFC exportieren als: ifcflowsegment; NameOverride: Stahlrohr nach DIN 2448; IfcPresentationLayer: 0-TFT-H_Vorlauf; ObjectTypeOverride: Stahlrohr nach DIN 2448; Pset MEP.Name: Stahlrohr nach DIN 2448; IfcDescription: Stahlrohr nach DIN 2448; Pset MEP.Geom-Outer Ø (mm): 114.3; Pset MEP.Tech-Material: Stahlrohr nach DIN 2448; Pset MEP.Geom-Length (mm): 352.637
Phasen - Phase erstellt: Phase 01

# IfcFlowSegment: Stahlrohr nach DIN 2448 267468:Stahlrohr nach DIN 2448 267468, Stahlrohr nach DIN 2448
In: 1. Obergeschoss
Type - Material: IfcSurfaceStyle #1741
Type - Andere - Kategorie: Allgemeines Modell; Familienname: Stahlrohr nach DIN 2448 267468
Type - ID-Daten - Typname: Stahlrohr nach DIN 2448 267468
Type - IFC-Parameter - Typ in IFC-Datei exportieren: Vorgabe
Description: Stahlrohr nach DIN 2448
Pset_DistributionFlowElementCommon - Reference: Stahlrohr nach DIN 2448 267468; sets with these values: 2
Andere - Typ: Stahlrohr nach DIN 2448 267468; Familie: Stahlrohr nach DIN 2448 267468; Familie und Typ: Stahlrohr nach DIN 2448 267468: Stahlrohr nach DIN 2448 267468; Typ-ID: 2533261
Abhängigkeiten - Höhe von Ebene: 0 m; Verschieben mit umliegenden Elementen: no
Bemaßungen - Fläche: 2.58381 m2; Volumen: 0.297236 m3
IFC-Parameter - In IFC-Datei exportieren: Nach Typ; Pset MEP.Geom-DN: 200; Pset MEP.Tech-Insulation thickness (mm): 100; In IFC exportieren als: ifcflowsegment; NameOverride: Stahlrohr nach DIN 2448; IfcPresentationLayer: 0-TFT-H_Ruecklauf; ObjectTypeOverride: Stahlrohr nach DIN 2448; Pset MEP.Name: Stahlrohr nach DIN 2448; IfcDescription: Stahlrohr nach DIN 2448; Pset MEP.Geom-Outer Ø (mm): 219.1; Pset MEP.Tech-Material: Stahlrohr nach DIN 2448; Pset MEP.Geom-Length (mm): 2590.54
Phasen - Phase erstellt: Phase 01

# IfcFlowSegment: Stahlrohr nach DIN 2448 267749:Stahlrohr nach DIN 2448 267749, Stahlrohr nach DIN 2448
In: 1. Obergeschoss
Type - Material: IfcSurfaceStyle #1741
Type - Andere - Kategorie: Allgemeines Modell; Familienname: Stahlrohr nach DIN 2448 267749
Type - ID-Daten - Typname: Stahlrohr nach DIN 2448 267749
Type - IFC-Parameter - Typ in IFC-Datei exportieren: Vorgabe
Description: Stahlrohr nach DIN 2448
Pset_DistributionFlowElementCommon - Reference: Stahlrohr nach DIN 2448 267749; sets with these values: 2
Andere - Typ: Stahlrohr nach DIN 2448 267749; Familie: Stahlrohr nach DIN 2448 267749; Familie und Typ: Stahlrohr nach DIN 2448 267749: Stahlrohr nach DIN 2448 267749; Typ-ID: 2533268
Abhängigkeiten - Höhe von Ebene: 0 m; Verschieben mit umliegenden Elementen: no
Bemaßungen - Fläche: 0.516137 m2; Volumen: 0.0593754 m3
IFC-Parameter - In IFC-Datei exportieren: Nach Typ; Pset MEP.Geom-DN: 200; Pset MEP.Tech-Insulation thickness (mm): 100; In IFC exportieren als: ifcflowsegment; NameOverride: Stahlrohr nach DIN 2448; IfcPresentationLayer: 0-TFT-H_Ruecklauf; ObjectTypeOverride: Stahlrohr nach DIN 2448; Pset MEP.Name: Stahlrohr nach DIN 2448; IfcDescription: Stahlrohr nach DIN 2448; Pset MEP.Geom-Outer Ø (mm): 219.1; Pset MEP.Tech-Material: Stahlrohr nach DIN 2448; Pset MEP.Geom-Length (mm): 517.482
Phasen - Phase erstellt: Phase 01

# IfcFlowSegment: Stahlrohr nach DIN 2448 268030:Stahlrohr nach DIN 2448 268030, Stahlrohr nach DIN 2448
In: 1. Obergeschoss
Type - Material: IfcSurfaceStyle #9317
Type - Andere - Kategorie: Allgemeines Modell; Familienname: Stahlrohr nach DIN 2448 268030
Type - ID-Daten - Typname: Stahlrohr nach DIN 2448 268030
Type - IFC-Parameter - Typ in IFC-Datei exportieren: Vorgabe
Description: Stahlrohr nach DIN 2448
Pset_DistributionFlowElementCommon - Reference: Stahlrohr nach DIN 2448 268030; sets with these values: 2
Andere - Typ: Stahlrohr nach DIN 2448 268030; Familie: Stahlrohr nach DIN 2448 268030; Familie und Typ: Stahlrohr nach DIN 2448 268030: Stahlrohr nach DIN 2448 268030; Typ-ID: 2533275
Abhängigkeiten - Höhe von Ebene: 0 m; Verschieben mit umliegenden Elementen: no
Bemaßungen - Fläche: 0.722173 m2; Volumen: 0.0830774 m3
IFC-Parameter - In IFC-Datei exportieren: Nach Typ; Pset MEP.Geom-DN: 200; Pset MEP.Tech-Insulation thickness (mm): 100; In IFC exportieren als: ifcflowsegment; NameOverride: Stahlrohr nach DIN 2448; IfcPresentationLayer: 0-TFT-H_Vorlauf; ObjectTypeOverride: Stahlrohr nach DIN 2448; Pset MEP.Name: Stahlrohr nach DIN 2448; IfcDescription: Stahlrohr nach DIN 2448; Pset MEP.Geom-Outer Ø (mm): 219.1; Pset MEP.Tech-Material: Stahlrohr nach DIN 2448; Pset MEP.Geom-Length (mm): 724.055
Phasen - Phase erstellt: Phase 01

# IfcFlowSegment: Stahlrohr nach DIN 2448 268311:Stahlrohr nach DIN 2448 268311, Stahlrohr nach DIN 2448
In: 1. Obergeschoss
Type - Material: IfcSurfaceStyle #9317
Type - Andere - Kategorie: Allgemeines Modell; Familienname: Stahlrohr nach DIN 2448 268311
Type - ID-Daten - Typname: Stahlrohr nach DIN 2448 268311
Type - IFC-Parameter - Typ in IFC-Datei exportieren: Vorgabe
Description: Stahlrohr nach DIN 2448
Pset_DistributionFlowElementCommon - Reference: Stahlrohr nach DIN 2448 268311; sets with these values: 2
Andere - Typ: Stahlrohr nach DIN 2448 268311; Familie: Stahlrohr nach DIN 2448 268311; Familie und Typ: Stahlrohr nach DIN 2448 268311: Stahlrohr nach DIN 2448 268311; Typ-ID: 2533282
Abhängigkeiten - Höhe von Ebene: 0 m; Verschieben mit umliegenden Elementen: no
Bemaßungen - Fläche: 1.04858 m2; Volumen: 0.120627 m3
IFC-Parameter - In IFC-Datei exportieren: Nach Typ; Pset MEP.Geom-DN: 200; Pset MEP.Tech-Insulation thickness (mm): 100; In IFC exportieren als: ifcflowsegment; NameOverride: Stahlrohr nach DIN 2448; IfcPresentationLayer: 0-TFT-H_Vorlauf; ObjectTypeOverride: Stahlrohr nach DIN 2448; Pset MEP.Name: Stahlrohr nach DIN 2448; IfcDescription: Stahlrohr nach DIN 2448; Pset MEP.Geom-Outer Ø (mm): 219.1; Pset MEP.Tech-Material: Stahlrohr nach DIN 2448; Pset MEP.Geom-Length (mm): 1051.31
Phasen - Phase erstellt: Phase 01

# IfcFlowSegment: Stahlrohr nach DIN 2448 268592:Stahlrohr nach DIN 2448 268592, Stahlrohr nach DIN 2448
In: 1. Obergeschoss
Type - Material: IfcSurfaceStyle #9317
Type - Andere - Kategorie: Allgemeines Modell; Familienname: Stahlrohr nach DIN 2448 268592
Type - ID-Daten - Typname: Stahlrohr nach DIN 2448 268592
Type - IFC-Parameter - Typ in IFC-Datei exportieren: Vorgabe
Description: Stahlrohr nach DIN 2448
Pset_DistributionFlowElementCommon - Reference: Stahlrohr nach DIN 2448 268592; sets with these values: 2
Andere - Typ: Stahlrohr nach DIN 2448 268592; Familie: Stahlrohr nach DIN 2448 268592; Familie und Typ: Stahlrohr nach DIN 2448 268592: Stahlrohr nach DIN 2448 268592; Typ-ID: 2533289
Abhängigkeiten - Höhe von Ebene: 0 m; Verschieben mit umliegenden Elementen: no
Bemaßungen - Fläche: 0.326409 m2; Volumen: 0.0375494 m3
IFC-Parameter - In IFC-Datei exportieren: Nach Typ; Pset MEP.Geom-DN: 200; Pset MEP.Tech-Insulation thickness (mm): 100; In IFC exportieren als: ifcflowsegment; NameOverride: Stahlrohr nach DIN 2448; IfcPresentationLayer: 0-TFT-H_Vorlauf; ObjectTypeOverride: Stahlrohr nach DIN 2448; Pset MEP.Name: Stahlrohr nach DIN 2448; IfcDescription: Stahlrohr nach DIN 2448; Pset MEP.Geom-Outer Ø (mm): 219.1; Pset MEP.Tech-Material: Stahlrohr nach DIN 2448; Pset MEP.Geom-Length (mm): 327.259
Phasen - Phase erstellt: Phase 01

# IfcFlowSegment: Stahlrohr nach DIN 2448 277462:Stahlrohr nach DIN 2448 277462, Stahlrohr nach DIN 2448
In: Erdgeschoss
Type - Material: IfcSurfaceStyle #9317
Type - Andere - Kategorie: Allgemeines Modell; Familienname: Stahlrohr nach DIN 2448 277462
Type - ID-Daten - Typname: Stahlrohr nach DIN 2448 277462
Type - IFC-Parameter - Typ in IFC-Datei exportieren: Vorgabe
Description: Stahlrohr nach DIN 2448
Pset_DistributionFlowElementCommon - Reference: Stahlrohr nach DIN 2448 277462; sets with these values: 2
Andere - Typ: Stahlrohr nach DIN 2448 277462; Familie: Stahlrohr nach DIN 2448 277462; Familie und Typ: Stahlrohr nach DIN 2448 277462: Stahlrohr nach DIN 2448 277462; Typ-ID: 2533879
Abhängigkeiten - Höhe von Ebene: 0 m; Verschieben mit umliegenden Elementen: no
Bemaßungen - Fläche: 0.661075 m2; Volumen: 0.0760488 m3
IFC-Parameter - In IFC-Datei exportieren: Nach Typ; Pset MEP.Geom-DN: 200; Pset MEP.Tech-Insulation thickness (mm): 100; In IFC exportieren als: ifcflowsegment; NameOverride: Stahlrohr nach DIN 2448; IfcPresentationLayer: 0-TFT-H_Vorlauf; ObjectTypeOverride: Stahlrohr nach DIN 2448; Pset MEP.Name: Stahlrohr nach DIN 2448; IfcDescription: Stahlrohr nach DIN 2448; Pset MEP.Geom-Outer Ø (mm): 219.1; Pset MEP.Tech-Material: Stahlrohr nach DIN 2448; Pset MEP.Geom-Length (mm): 662.798
Phasen - Phase erstellt: Phase 01

# IfcFlowSegment: Stahlrohr nach DIN 2448 292285:Stahlrohr nach DIN 2448 292285, Stahlrohr nach DIN 2448
In: Erdgeschoss
Type - Material: IfcSurfaceStyle #1741
Type - Andere - Kategorie: Allgemeines Modell; Familienname: Stahlrohr nach DIN 2448 292285
Type - ID-Daten - Typname: Stahlrohr nach DIN 2448 292285
Type - IFC-Parameter - Typ in IFC-Datei exportieren: Vorgabe
Description: Stahlrohr nach DIN 2448
Pset_DistributionFlowElementCommon - Reference: Stahlrohr nach DIN 2448 292285; sets with these values: 2
Andere - Typ: Stahlrohr nach DIN 2448 292285; Familie: Stahlrohr nach DIN 2448 292285; Familie und Typ: Stahlrohr nach DIN 2448 292285: Stahlrohr nach DIN 2448 292285; Typ-ID: 2534312
Abhängigkeiten - Höhe von Ebene: 0 m; Verschieben mit umliegenden Elementen: no
Bemaßungen - Fläche: 6.69094 m2; Volumen: 0.573188 m3
IFC-Parameter - In IFC-Datei exportieren: Nach Typ; Pset MEP.Tech-Insulation thickness (mm): 100; Pset MEP.Geom-DN: 100; In IFC exportieren als: ifcflowsegment; NameOverride: Stahlrohr nach DIN 2448; IfcPresentationLayer: 0-TFT-H_Ruecklauf; ObjectTypeOverride: Stahlrohr nach DIN 2448; Pset MEP.Name: Stahlrohr nach DIN 2448; IfcDescription: Stahlrohr nach DIN 2448; Pset MEP.Geom-Outer Ø (mm): 114.3; Pset MEP.Tech-Material: Stahlrohr nach DIN 2448; Pset MEP.Geom-Length (mm): 9989
Phasen - Phase erstellt: Phase 01

# IfcFlowSegment: Stahlrohr nach DIN 2448 292664:Stahlrohr nach DIN 2448 292664, Stahlrohr nach DIN 2448
In: Erdgeschoss
Type - Material: IfcSurfaceStyle #9317
Type - Andere - Kategorie: Allgemeines Modell; Familienname: Stahlrohr nach DIN 2448 292664
Type - ID-Daten - Typname: Stahlrohr nach DIN 2448 292664
Type - IFC-Parameter - Typ in IFC-Datei exportieren: Vorgabe
Description: Stahlrohr nach DIN 2448
Pset_DistributionFlowElementCommon - Reference: Stahlrohr nach DIN 2448 292664; sets with these values: 2
Andere - Typ: Stahlrohr nach DIN 2448 292664; Familie: Stahlrohr nach DIN 2448 292664; Familie und Typ: Stahlrohr nach DIN 2448 292664: Stahlrohr nach DIN 2448 292664; Typ-ID: 2534347
Abhängigkeiten - Höhe von Ebene: 0 m; Verschieben mit umliegenden Elementen: no
Bemaßungen - Fläche: 6.30645 m2; Volumen: 0.540251 m3
IFC-Parameter - In IFC-Datei exportieren: Nach Typ; Pset MEP.Tech-Insulation thickness (mm): 100; Pset MEP.Geom-DN: 100; In IFC exportieren als: ifcflowsegment; NameOverride: Stahlrohr nach DIN 2448; IfcPresentationLayer: 0-TFT-H_Vorlauf; ObjectTypeOverride: Stahlrohr nach DIN 2448; Pset MEP.Name: Stahlrohr nach DIN 2448; IfcDescription: Stahlrohr nach DIN 2448; Pset MEP.Geom-Outer Ø (mm): 114.3; Pset MEP.Tech-Material: Stahlrohr nach DIN 2448; Pset MEP.Geom-Length (mm): 9415
Phasen - Phase erstellt: Phase 01

# IfcFlowSegment: Stahlrohr nach DIN 2448 292991:Stahlrohr nach DIN 2448 292991, Stahlrohr nach DIN 2448
In: Erdgeschoss
Type - Material: IfcSurfaceStyle #9317
Type - Andere - Kategorie: Allgemeines Modell; Familienname: Stahlrohr nach DIN 2448 292991
Type - ID-Daten - Typname: Stahlrohr nach DIN 2448 292991
Type - IFC-Parameter - Typ in IFC-Datei exportieren: Vorgabe
Description: Stahlrohr nach DIN 2448
Pset_DistributionFlowElementCommon - Reference: Stahlrohr nach DIN 2448 292991; sets with these values: 2
Andere - Typ: Stahlrohr nach DIN 2448 292991; Familie: Stahlrohr nach DIN 2448 292991; Familie und Typ: Stahlrohr nach DIN 2448 292991: Stahlrohr nach DIN 2448 292991; Typ-ID: 2534368
Abhängigkeiten - Höhe von Ebene: 0 m; Verschieben mit umliegenden Elementen: no
Bemaßungen - Fläche: 0.181058 m2; Volumen: 0.0155106 m3
IFC-Parameter - In IFC-Datei exportieren: Nach Typ; Pset MEP.Tech-Insulation thickness (mm): 100; Pset MEP.Geom-DN: 100; In IFC exportieren als: ifcflowsegment; NameOverride: Stahlrohr nach DIN 2448; IfcPresentationLayer: 0-TFT-H_Vorlauf; ObjectTypeOverride: Stahlrohr nach DIN 2448; Pset MEP.Name: Stahlrohr nach DIN 2448; IfcDescription: Stahlrohr nach DIN 2448; Pset MEP.Geom-Outer Ø (mm): 114.3; Pset MEP.Tech-Material: Stahlrohr nach DIN 2448; Pset MEP.Geom-Length (mm): 270.304
Phasen - Phase erstellt: Phase 01

# IfcFlowSegment: Stahlrohr nach DIN 2448 293272:Stahlrohr nach DIN 2448 293272, Stahlrohr nach DIN 2448
In: Erdgeschoss
Type - Material: IfcSurfaceStyle #1741
Type - Andere - Kategorie: Allgemeines Modell; Familienname: Stahlrohr nach DIN 2448 293272
Type - ID-Daten - Typname: Stahlrohr nach DIN 2448 293272
Type - IFC-Parameter - Typ in IFC-Datei exportieren: Vorgabe
Description: Stahlrohr nach DIN 2448
Pset_DistributionFlowElementCommon - Reference: Stahlrohr nach DIN 2448 293272; sets with these values: 2
Andere - Typ: Stahlrohr nach DIN 2448 293272; Familie: Stahlrohr nach DIN 2448 293272; Familie und Typ: Stahlrohr nach DIN 2448 293272: Stahlrohr nach DIN 2448 293272; Typ-ID: 2534375
Abhängigkeiten - Höhe von Ebene: 0 m; Verschieben mit umliegenden Elementen: no
Bemaßungen - Fläche: 0.321654 m2; Volumen: 0.0275549 m3
IFC-Parameter - In IFC-Datei exportieren: Nach Typ; Pset MEP.Tech-Insulation thickness (mm): 100; Pset MEP.Geom-DN: 100; In IFC exportieren als: ifcflowsegment; NameOverride: Stahlrohr nach DIN 2448; IfcPresentationLayer: 0-TFT-H_Ruecklauf; ObjectTypeOverride: Stahlrohr nach DIN 2448; Pset MEP.Name: Stahlrohr nach DIN 2448; IfcDescription: Stahlrohr nach DIN 2448; Pset MEP.Geom-Outer Ø (mm): 114.3; Pset MEP.Tech-Material: Stahlrohr nach DIN 2448; Pset MEP.Geom-Length (mm): 480.202
Phasen - Phase erstellt: Phase 01

# IfcFlowSegment: Stahlrohr nach DIN 2448 293553:Stahlrohr nach DIN 2448 293553, Stahlrohr nach DIN 2448
In: Erdgeschoss
Type - Material: IfcSurfaceStyle #9317
Type - Andere - Kategorie: Allgemeines Modell; Familienname: Stahlrohr nach DIN 2448 293553
Type - ID-Daten - Typname: Stahlrohr nach DIN 2448 293553
Type - IFC-Parameter - Typ in IFC-Datei exportieren: Vorgabe
Description: Stahlrohr nach DIN 2448
Pset_DistributionFlowElementCommon - Reference: Stahlrohr nach DIN 2448 293553; sets with these values: 2
Andere - Typ: Stahlrohr nach DIN 2448 293553; Familie: Stahlrohr nach DIN 2448 293553; Familie und Typ: Stahlrohr nach DIN 2448 293553: Stahlrohr nach DIN 2448 293553; Typ-ID: 2534382
Abhängigkeiten - Höhe von Ebene: 0 m; Verschieben mit umliegenden Elementen: no
Bemaßungen - Fläche: 0.321654 m2; Volumen: 0.0275549 m3
IFC-Parameter - In IFC-Datei exportieren: Nach Typ; Pset MEP.Tech-Insulation thickness (mm): 100; Pset MEP.Geom-DN: 100; In IFC exportieren als: ifcflowsegment; NameOverride: Stahlrohr nach DIN 2448; IfcPresentationLayer: 0-TFT-H_Vorlauf; ObjectTypeOverride: Stahlrohr nach DIN 2448; Pset MEP.Name: Stahlrohr nach DIN 2448; IfcDescription: Stahlrohr nach DIN 2448; Pset MEP.Geom-Outer Ø (mm): 114.3; Pset MEP.Tech-Material: Stahlrohr nach DIN 2448; Pset MEP.Geom-Length (mm): 480.202
Phasen - Phase erstellt: Phase 01

# IfcFlowSegment: Stahlrohr nach DIN 2448 297293:Stahlrohr nach DIN 2448 297293, Stahlrohr nach DIN 2448
In: Erdgeschoss
Type - Material: IfcSurfaceStyle #1741
Type - Andere - Kategorie: Allgemeines Modell; Familienname: Stahlrohr nach DIN 2448 297293
Type - ID-Daten - Typname: Stahlrohr nach DIN 2448 297293
Type - IFC-Parameter - Typ in IFC-Datei exportieren: Vorgabe
Description: Stahlrohr nach DIN 2448
Pset_DistributionFlowElementCommon - Reference: Stahlrohr nach DIN 2448 297293; sets with these values: 2
Andere - Typ: Stahlrohr nach DIN 2448 297293; Familie: Stahlrohr nach DIN 2448 297293; Familie und Typ: Stahlrohr nach DIN 2448 297293: Stahlrohr nach DIN 2448 297293; Typ-ID: 2534762
Abhängigkeiten - Höhe von Ebene: 0 m; Verschieben mit umliegenden Elementen: no
Bemaßungen - Fläche: 0.661075 m2; Volumen: 0.0760488 m3
IFC-Parameter - In IFC-Datei exportieren: Nach Typ; Pset MEP.Geom-DN: 200; Pset MEP.Tech-Insulation thickness (mm): 100; In IFC exportieren als: ifcflowsegment; NameOverride: Stahlrohr nach DIN 2448; IfcPresentationLayer: 0-TFT-H_Ruecklauf; ObjectTypeOverride: Stahlrohr nach DIN 2448; Pset MEP.Name: Stahlrohr nach DIN 2448; IfcDescription: Stahlrohr nach DIN 2448; Pset MEP.Geom-Outer Ø (mm): 219.1; Pset MEP.Tech-Material: Stahlrohr nach DIN 2448; Pset MEP.Geom-Length (mm): 662.798
Phasen - Phase erstellt: Phase 01

# IfcFlowSegment: Stahlrohr nach DIN 2448 303345:Stahlrohr nach DIN 2448 303345, Stahlrohr nach DIN 2448
In: 1. Obergeschoss
Type - Material: IfcSurfaceStyle #9317
Type - Andere - Kategorie: Allgemeines Modell; Familienname: Stahlrohr nach DIN 2448 303345
Type - ID-Daten - Typname: Stahlrohr nach DIN 2448 303345
Type - IFC-Parameter - Typ in IFC-Datei exportieren: Vorgabe
Description: Stahlrohr nach DIN 2448
Pset_DistributionFlowElementCommon - Reference: Stahlrohr nach DIN 2448 303345; sets with these values: 2
Andere - Typ: Stahlrohr nach DIN 2448 303345; Familie: Stahlrohr nach DIN 2448 303345; Familie und Typ: Stahlrohr nach DIN 2448 303345: Stahlrohr nach DIN 2448 303345; Typ-ID: 2534825
Abhängigkeiten - Höhe von Ebene: 0 m; Verschieben mit umliegenden Elementen: no
Bemaßungen - Fläche: 0.0618023 m2; Volumen: 0.00710962 m3
IFC-Parameter - In IFC-Datei exportieren: Nach Typ; Pset MEP.Geom-DN: 200; Pset MEP.Tech-Insulation thickness (mm): 100; In IFC exportieren als: ifcflowsegment; NameOverride: Stahlrohr nach DIN 2448; IfcPresentationLayer: 0-TFT-H_Vorlauf; ObjectTypeOverride: Stahlrohr nach DIN 2448; Pset MEP.Name: Stahlrohr nach DIN 2448; IfcDescription: Stahlrohr nach DIN 2448; Pset MEP.Geom-Outer Ø (mm): 219.1; Pset MEP.Tech-Material: Stahlrohr nach DIN 2448; Pset MEP.Geom-Length (mm): 61.9634
Phasen - Phase erstellt: Phase 01

# IfcFlowSegment: Stahlrohr nach DIN 2448 303701:Stahlrohr nach DIN 2448 303701, Stahlrohr nach DIN 2448
In: Erdgeschoss
Type - Material: IfcSurfaceStyle #9317
Type - Andere - Kategorie: Allgemeines Modell; Familienname: Stahlrohr nach DIN 2448 303701
Type - ID-Daten - Typname: Stahlrohr nach DIN 2448 303701
Type - IFC-Parameter - Typ in IFC-Datei exportieren: Vorgabe
Description: Stahlrohr nach DIN 2448
Pset_DistributionFlowElementCommon - Reference: Stahlrohr nach DIN 2448 303701; sets with these values: 2
Andere - Typ: Stahlrohr nach DIN 2448 303701; Familie: Stahlrohr nach DIN 2448 303701; Familie und Typ: Stahlrohr nach DIN 2448 303701: Stahlrohr nach DIN 2448 303701; Typ-ID: 2534853
Abhängigkeiten - Höhe von Ebene: 0 m; Verschieben mit umliegenden Elementen: no
Bemaßungen - Fläche: 0.034155 m2; Volumen: 0.00292593 m3
IFC-Parameter - In IFC-Datei exportieren: Nach Typ; Pset MEP.Tech-Insulation thickness (mm): 100; Pset MEP.Geom-DN: 100; In IFC exportieren als: ifcflowsegment; NameOverride: Stahlrohr nach DIN 2448; IfcPresentationLayer: 0-TFT-H_Vorlauf; ObjectTypeOverride: Stahlrohr nach DIN 2448; Pset MEP.Name: Stahlrohr nach DIN 2448; IfcDescription: Stahlrohr nach DIN 2448; Pset MEP.Geom-Outer Ø (mm): 114.3; Pset MEP.Tech-Material: Stahlrohr nach DIN 2448; Pset MEP.Geom-Length (mm): 50.9905
Phasen - Phase erstellt: Phase 01

# IfcFlowSegment: Stahlrohr nach DIN 2448 303982:Stahlrohr nach DIN 2448 303982, Stahlrohr nach DIN 2448
In: Erdgeschoss
Type - Material: IfcSurfaceStyle #9317
Type - Andere - Kategorie: Allgemeines Modell; Familienname: Stahlrohr nach DIN 2448 303982
Type - ID-Daten - Typname: Stahlrohr nach DIN 2448 303982
Type - IFC-Parameter - Typ in IFC-Datei exportieren: Vorgabe
Description: Stahlrohr nach DIN 2448
Pset_DistributionFlowElementCommon - Reference: Stahlrohr nach DIN 2448 303982; sets with these values: 2
Andere - Typ: Stahlrohr nach DIN 2448 303982; Familie: Stahlrohr nach DIN 2448 303982; Familie und Typ: Stahlrohr nach DIN 2448 303982: Stahlrohr nach DIN 2448 303982; Typ-ID: 2534860
Abhängigkeiten - Höhe von Ebene: 0 m; Verschieben mit umliegenden Elementen: no
Bemaßungen - Fläche: 0.321654 m2; Volumen: 0.0275549 m3
IFC-Parameter - In IFC-Datei exportieren: Nach Typ; Pset MEP.Tech-Insulation thickness (mm): 100; Pset MEP.Geom-DN: 100; In IFC exportieren als: ifcflowsegment; NameOverride: Stahlrohr nach DIN 2448; IfcPresentationLayer: 0-TFT-H_Vorlauf; ObjectTypeOverride: Stahlrohr nach DIN 2448; Pset MEP.Name: Stahlrohr nach DIN 2448; IfcDescription: Stahlrohr nach DIN 2448; Pset MEP.Geom-Outer Ø (mm): 114.3; Pset MEP.Tech-Material: Stahlrohr nach DIN 2448; Pset MEP.Geom-Length (mm): 480.202
Phasen - Phase erstellt: Phase 01

# IfcFlowSegment: Stahlrohr nach DIN 2448 304028:Stahlrohr nach DIN 2448 304028, Stahlrohr nach DIN 2448
In: Erdgeschoss
Type - Material: IfcSurfaceStyle #9317
Type - Andere - Kategorie: Allgemeines Modell; Familienname: Stahlrohr nach DIN 2448 304028
Type - ID-Daten - Typname: Stahlrohr nach DIN 2448 304028
Type - IFC-Parameter - Typ in IFC-Datei exportieren: Vorgabe
Description: Stahlrohr nach DIN 2448
Pset_DistributionFlowElementCommon - Reference: Stahlrohr nach DIN 2448 304028; sets with these values: 2
Andere - Typ: Stahlrohr nach DIN 2448 304028; Familie: Stahlrohr nach DIN 2448 304028; Familie und Typ: Stahlrohr nach DIN 2448 304028: Stahlrohr nach DIN 2448 304028; Typ-ID: 2534874
Abhängigkeiten - Höhe von Ebene: 0 m; Verschieben mit umliegenden Elementen: no
Bemaßungen - Fläche: 5.04839 m2; Volumen: 0.580757 m3
IFC-Parameter - In IFC-Datei exportieren: Nach Typ; Pset MEP.Geom-DN: 200; Pset MEP.Tech-Insulation thickness (mm): 100; In IFC exportieren als: ifcflowsegment; NameOverride: Stahlrohr nach DIN 2448; IfcPresentationLayer: 0-TFT-H_Vorlauf; ObjectTypeOverride: Stahlrohr nach DIN 2448; Pset MEP.Name: Stahlrohr nach DIN 2448; IfcDescription: Stahlrohr nach DIN 2448; Pset MEP.Geom-Outer Ø (mm): 219.1; Pset MEP.Tech-Material: Stahlrohr nach DIN 2448; Pset MEP.Geom-Length (mm): 5061.54
Phasen - Phase erstellt: Phase 01

# IfcFlowSegment: Stahlrohr nach DIN 2448 304309:Stahlrohr nach DIN 2448 304309, Stahlrohr nach DIN 2448
In: Erdgeschoss
Type - Material: IfcSurfaceStyle #9317
Type - Andere - Kategorie: Allgemeines Modell; Familienname: Stahlrohr nach DIN 2448 304309
Type - ID-Daten - Typname: Stahlrohr nach DIN 2448 304309
Type - IFC-Parameter - Typ in IFC-Datei exportieren: Vorgabe
Description: Stahlrohr nach DIN 2448
Pset_DistributionFlowElementCommon - Reference: Stahlrohr nach DIN 2448 304309; sets with these values: 2
Andere - Typ: Stahlrohr nach DIN 2448 304309; Familie: Stahlrohr nach DIN 2448 304309; Familie und Typ: Stahlrohr nach DIN 2448 304309: Stahlrohr nach DIN 2448 304309; Typ-ID: 2534881
Abhängigkeiten - Höhe von Ebene: 0 m; Verschieben mit umliegenden Elementen: no
Bemaßungen - Fläche: 0.326351 m2; Volumen: 0.0375428 m3
IFC-Parameter - In IFC-Datei exportieren: Nach Typ; Pset MEP.Geom-DN: 200; Pset MEP.Tech-Insulation thickness (mm): 100; In IFC exportieren als: ifcflowsegment; NameOverride: Stahlrohr nach DIN 2448; IfcPresentationLayer: 0-TFT-H_Vorlauf; ObjectTypeOverride: Stahlrohr nach DIN 2448; Pset MEP.Name: Stahlrohr nach DIN 2448; IfcDescription: Stahlrohr nach DIN 2448; Pset MEP.Geom-Outer Ø (mm): 219.1; Pset MEP.Tech-Material: Stahlrohr nach DIN 2448; Pset MEP.Geom-Length (mm): 327.202
Phasen - Phase erstellt: Phase 01

# IfcFlowSegment: Stahlrohr nach DIN 2448 304613:Stahlrohr nach DIN 2448 304613, Stahlrohr nach DIN 2448
In: Erdgeschoss
Type - Material: IfcSurfaceStyle #1741
Type - Andere - Kategorie: Allgemeines Modell; Familienname: Stahlrohr nach DIN 2448 304613
Type - ID-Daten - Typname: Stahlrohr nach DIN 2448 304613
Type - IFC-Parameter - Typ in IFC-Datei exportieren: Vorgabe
Description: Stahlrohr nach DIN 2448
Pset_DistributionFlowElementCommon - Reference: Stahlrohr nach DIN 2448 304613; sets with these values: 2
Andere - Typ: Stahlrohr nach DIN 2448 304613; Familie: Stahlrohr nach DIN 2448 304613; Familie und Typ: Stahlrohr nach DIN 2448 304613: Stahlrohr nach DIN 2448 304613; Typ-ID: 2534895
Abhängigkeiten - Höhe von Ebene: 0 m; Verschieben mit umliegenden Elementen: no
Bemaßungen - Fläche: 0.034155 m2; Volumen: 0.00292593 m3
IFC-Parameter - In IFC-Datei exportieren: Nach Typ; Pset MEP.Tech-Insulation thickness (mm): 100; Pset MEP.Geom-DN: 100; In IFC exportieren als: ifcflowsegment; NameOverride: Stahlrohr nach DIN 2448; IfcPresentationLayer: 0-TFT-H_Ruecklauf; ObjectTypeOverride: Stahlrohr nach DIN 2448; Pset MEP.Name: Stahlrohr nach DIN 2448; IfcDescription: Stahlrohr nach DIN 2448; Pset MEP.Geom-Outer Ø (mm): 114.3; Pset MEP.Tech-Material: Stahlrohr nach DIN 2448; Pset MEP.Geom-Length (mm): 50.9905
Phasen - Phase erstellt: Phase 01

# IfcFlowSegment: Stahlrohr nach DIN 2448 304659:Stahlrohr nach DIN 2448 304659, Stahlrohr nach DIN 2448
In: Erdgeschoss
Type - Material: IfcSurfaceStyle #1741
Type - Andere - Kategorie: Allgemeines Modell; Familienname: Stahlrohr nach DIN 2448 304659
Type - ID-Daten - Typname: Stahlrohr nach DIN 2448 304659
Type - IFC-Parameter - Typ in IFC-Datei exportieren: Vorgabe
Description: Stahlrohr nach DIN 2448
Pset_DistributionFlowElementCommon - Reference: Stahlrohr nach DIN 2448 304659; sets with these values: 2
Andere - Typ: Stahlrohr nach DIN 2448 304659; Familie: Stahlrohr nach DIN 2448 304659; Familie und Typ: Stahlrohr nach DIN 2448 304659: Stahlrohr nach DIN 2448 304659; Typ-ID: 2534909
Abhängigkeiten - Höhe von Ebene: 0 m; Verschieben mit umliegenden Elementen: no
Bemaßungen - Fläche: 5.04839 m2; Volumen: 0.580757 m3
IFC-Parameter - In IFC-Datei exportieren: Nach Typ; Pset MEP.Geom-DN: 200; Pset MEP.Tech-Insulation thickness (mm): 100; In IFC exportieren als: ifcflowsegment; NameOverride: Stahlrohr nach DIN 2448; IfcPresentationLayer: 0-TFT-H_Ruecklauf; ObjectTypeOverride: Stahlrohr nach DIN 2448; Pset MEP.Name: Stahlrohr nach DIN 2448; IfcDescription: Stahlrohr nach DIN 2448; Pset MEP.Geom-Outer Ø (mm): 219.1; Pset MEP.Tech-Material: Stahlrohr nach DIN 2448; Pset MEP.Geom-Length (mm): 5061.54
Phasen - Phase erstellt: Phase 01

# IfcFlowSegment: Stahlrohr nach DIN 2448 304682:Stahlrohr nach DIN 2448 304682, Stahlrohr nach DIN 2448
In: Erdgeschoss
Type - Material: IfcSurfaceStyle #1741
Type - Andere - Kategorie: Allgemeines Modell; Familienname: Stahlrohr nach DIN 2448 304682
Type - ID-Daten - Typname: Stahlrohr nach DIN 2448 304682
Type - IFC-Parameter - Typ in IFC-Datei exportieren: Vorgabe
Description: Stahlrohr nach DIN 2448
Pset_DistributionFlowElementCommon - Reference: Stahlrohr nach DIN 2448 304682; sets with these values: 2
Andere - Typ: Stahlrohr nach DIN 2448 304682; Familie: Stahlrohr nach DIN 2448 304682; Familie und Typ: Stahlrohr nach DIN 2448 304682: Stahlrohr nach DIN 2448 304682; Typ-ID: 2534916
Abhängigkeiten - Höhe von Ebene: 0 m; Verschieben mit umliegenden Elementen: no
Bemaßungen - Fläche: 0.326351 m2; Volumen: 0.0375428 m3
IFC-Parameter - In IFC-Datei exportieren: Nach Typ; Pset MEP.Geom-DN: 200; Pset MEP.Tech-Insulation thickness (mm): 100; In IFC exportieren als: ifcflowsegment; NameOverride: Stahlrohr nach DIN 2448; IfcPresentationLayer: 0-TFT-H_Ruecklauf; ObjectTypeOverride: Stahlrohr nach DIN 2448; Pset MEP.Name: Stahlrohr nach DIN 2448; IfcDescription: Stahlrohr nach DIN 2448; Pset MEP.Geom-Outer Ø (mm): 219.1; Pset MEP.Tech-Material: Stahlrohr nach DIN 2448; Pset MEP.Geom-Length (mm): 327.202
Phasen - Phase erstellt: Phase 01

# IfcFlowSegment: Stahlrohr nach DIN 2448 304705:Stahlrohr nach DIN 2448 304705, Stahlrohr nach DIN 2448
In: Erdgeschoss
Type - Material: IfcSurfaceStyle #1741
Type - Andere - Kategorie: Allgemeines Modell; Familienname: Stahlrohr nach DIN 2448 304705
Type - ID-Daten - Typname: Stahlrohr nach DIN 2448 304705
Type - IFC-Parameter - Typ in IFC-Datei exportieren: Vorgabe
Description: Stahlrohr nach DIN 2448
Pset_DistributionFlowElementCommon - Reference: Stahlrohr nach DIN 2448 304705; sets with these values: 2
Andere - Typ: Stahlrohr nach DIN 2448 304705; Familie: Stahlrohr nach DIN 2448 304705; Familie und Typ: Stahlrohr nach DIN 2448 304705: Stahlrohr nach DIN 2448 304705; Typ-ID: 2534923
Abhängigkeiten - Höhe von Ebene: 0 m; Verschieben mit umliegenden Elementen: no
Bemaßungen - Fläche: 0.321654 m2; Volumen: 0.0275549 m3
IFC-Parameter - In IFC-Datei exportieren: Nach Typ; Pset MEP.Tech-Insulation thickness (mm): 100; Pset MEP.Geom-DN: 100; In IFC exportieren als: ifcflowsegment; NameOverride: Stahlrohr nach DIN 2448; IfcPresentationLayer: 0-TFT-H_Ruecklauf; ObjectTypeOverride: Stahlrohr nach DIN 2448; Pset MEP.Name: Stahlrohr nach DIN 2448; IfcDescription: Stahlrohr nach DIN 2448; Pset MEP.Geom-Outer Ø (mm): 114.3; Pset MEP.Tech-Material: Stahlrohr nach DIN 2448; Pset MEP.Geom-Length (mm): 480.202
Phasen - Phase erstellt: Phase 01

# IfcFlowSegment: Stahlrohr nach DIN 2448 304776:Stahlrohr nach DIN 2448 304776, Stahlrohr nach DIN 2448
In: 1. Untergeschoss
Type - Material: IfcSurfaceStyle #9317
Type - Andere - Kategorie: Allgemeines Modell; Familienname: Stahlrohr nach DIN 2448 304776
Type - ID-Daten - Typname: Stahlrohr nach DIN 2448 304776
Type - IFC-Parameter - Typ in IFC-Datei exportieren: Vorgabe
Description: Stahlrohr nach DIN 2448
Pset_DistributionFlowElementCommon - Reference: Stahlrohr nach DIN 2448 304776; sets with these values: 2
Andere - Typ: Stahlrohr nach DIN 2448 304776; Familie: Stahlrohr nach DIN 2448 304776; Familie und Typ: Stahlrohr nach DIN 2448 304776: Stahlrohr nach DIN 2448 304776; Typ-ID: 2534944
Abhängigkeiten - Höhe von Ebene: 0 m; Verschieben mit umliegenden Elementen: no
Bemaßungen - Fläche: 0.89048 m2; Volumen: 0.0762841 m3
IFC-Parameter - In IFC-Datei exportieren: Nach Typ; Pset MEP.Tech-Insulation thickness (mm): 100; Pset MEP.Geom-DN: 100; In IFC exportieren als: ifcflowsegment; NameOverride: Stahlrohr nach DIN 2448; IfcPresentationLayer: 0-TFT-H_Vorlauf; ObjectTypeOverride: Stahlrohr nach DIN 2448; Pset MEP.Name: Stahlrohr nach DIN 2448; IfcDescription: Stahlrohr nach DIN 2448; Pset MEP.Geom-Outer Ø (mm): 114.3; Pset MEP.Tech-Material: Stahlrohr nach DIN 2448; Pset MEP.Geom-Length (mm): 1329.41
Phasen - Phase erstellt: Phase 01

# IfcFlowSegment: Stahlrohr nach DIN 2448 305057:Stahlrohr nach DIN 2448 305057, Stahlrohr nach DIN 2448
In: Erdgeschoss
Type - Material: IfcSurfaceStyle #9317
Type - Andere - Kategorie: Allgemeines Modell; Familienname: Stahlrohr nach DIN 2448 305057
Type - ID-Daten - Typname: Stahlrohr nach DIN 2448 305057
Type - IFC-Parameter - Typ in IFC-Datei exportieren: Vorgabe
Description: Stahlrohr nach DIN 2448
Pset_DistributionFlowElementCommon - Reference: Stahlrohr nach DIN 2448 305057; sets with these values: 2
Andere - Typ: Stahlrohr nach DIN 2448 305057; Familie: Stahlrohr nach DIN 2448 305057; Familie und Typ: Stahlrohr nach DIN 2448 305057: Stahlrohr nach DIN 2448 305057; Typ-ID: 2534951
Abhängigkeiten - Höhe von Ebene: 0 m; Verschieben mit umliegenden Elementen: no
Bemaßungen - Fläche: 1.19939 m2; Volumen: 0.102747 m3
IFC-Parameter - In IFC-Datei exportieren: Nach Typ; Pset MEP.Tech-Insulation thickness (mm): 100; Pset MEP.Geom-DN: 100; In IFC exportieren als: ifcflowsegment; NameOverride: Stahlrohr nach DIN 2448; IfcPresentationLayer: 0-TFT-H_Vorlauf; ObjectTypeOverride: Stahlrohr nach DIN 2448; Pset MEP.Name: Stahlrohr nach DIN 2448; IfcDescription: Stahlrohr nach DIN 2448; Pset MEP.Geom-Outer Ø (mm): 114.3; Pset MEP.Tech-Material: Stahlrohr nach DIN 2448; Pset MEP.Geom-Length (mm): 1790.59
Phasen - Phase erstellt: Phase 01

# IfcFlowSegment: Stahlrohr nach DIN 2448 305338:Stahlrohr nach DIN 2448 305338, Stahlrohr nach DIN 2448
In: 1. Untergeschoss
Type - Material: IfcSurfaceStyle #1741
Type - Andere - Kategorie: Allgemeines Modell; Familienname: Stahlrohr nach DIN 2448 305338
Type - ID-Daten - Typname: Stahlrohr nach DIN 2448 305338
Type - IFC-Parameter - Typ in IFC-Datei exportieren: Vorgabe
Description: Stahlrohr nach DIN 2448
Pset_DistributionFlowElementCommon - Reference: Stahlrohr nach DIN 2448 305338; sets with these values: 2
Andere - Typ: Stahlrohr nach DIN 2448 305338; Familie: Stahlrohr nach DIN 2448 305338; Familie und Typ: Stahlrohr nach DIN 2448 305338: Stahlrohr nach DIN 2448 305338; Typ-ID: 2534958
Abhängigkeiten - Höhe von Ebene: 0 m; Verschieben mit umliegenden Elementen: no
Bemaßungen - Fläche: 0.89048 m2; Volumen: 0.0762841 m3
IFC-Parameter - In IFC-Datei exportieren: Nach Typ; Pset MEP.Tech-Insulation thickness (mm): 100; Pset MEP.Geom-DN: 100; In IFC exportieren als: ifcflowsegment; NameOverride: Stahlrohr nach DIN 2448; IfcPresentationLayer: 0-TFT-H_Ruecklauf; ObjectTypeOverride: Stahlrohr nach DIN 2448; Pset MEP.Name: Stahlrohr nach DIN 2448; IfcDescription: Stahlrohr nach DIN 2448; Pset MEP.Geom-Outer Ø (mm): 114.3; Pset MEP.Tech-Material: Stahlrohr nach DIN 2448; Pset MEP.Geom-Length (mm): 1329.41
Phasen - Phase erstellt: Phase 01

# IfcFlowSegment: Stahlrohr nach DIN 2448 305361:Stahlrohr nach DIN 2448 305361, Stahlrohr nach DIN 2448
In: Erdgeschoss
Type - Material: IfcSurfaceStyle #1741
Type - Andere - Kategorie: Allgemeines Modell; Familienname: Stahlrohr nach DIN 2448 305361
Type - ID-Daten - Typname: Stahlrohr nach DIN 2448 305361
Type - IFC-Parameter - Typ in IFC-Datei exportieren: Vorgabe
Description: Stahlrohr nach DIN 2448
Pset_DistributionFlowElementCommon - Reference: Stahlrohr nach DIN 2448 305361; sets with these values: 2
Andere - Typ: Stahlrohr nach DIN 2448 305361; Familie: Stahlrohr nach DIN 2448 305361; Familie und Typ: Stahlrohr nach DIN 2448 305361: Stahlrohr nach DIN 2448 305361; Typ-ID: 2534965
Abhängigkeiten - Höhe von Ebene: 0 m; Verschieben mit umliegenden Elementen: no
Bemaßungen - Fläche: 1.19939 m2; Volumen: 0.102747 m3
IFC-Parameter - In IFC-Datei exportieren: Nach Typ; Pset MEP.Tech-Insulation thickness (mm): 100; Pset MEP.Geom-DN: 100; In IFC exportieren als: ifcflowsegment; NameOverride: Stahlrohr nach DIN 2448; IfcPresentationLayer: 0-TFT-H_Ruecklauf; ObjectTypeOverride: Stahlrohr nach DIN 2448; Pset MEP.Name: Stahlrohr nach DIN 2448; IfcDescription: Stahlrohr nach DIN 2448; Pset MEP.Geom-Outer Ø (mm): 114.3; Pset MEP.Tech-Material: Stahlrohr nach DIN 2448; Pset MEP.Geom-Length (mm): 1790.59
Phasen - Phase erstellt: Phase 01

# IfcFlowSegment: Stahlrohr nach DIN 2448 309327:Stahlrohr nach DIN 2448 309327, Stahlrohr nach DIN 2448
In: Erdgeschoss
Type - Material: IfcSurfaceStyle #1741
Type - Andere - Kategorie: Allgemeines Modell; Familienname: Stahlrohr nach DIN 2448 309327
Type - ID-Daten - Typname: Stahlrohr nach DIN 2448 309327
Type - IFC-Parameter - Typ in IFC-Datei exportieren: Vorgabe
Description: Stahlrohr nach DIN 2448
Pset_DistributionFlowElementCommon - Reference: Stahlrohr nach DIN 2448 309327; sets with these values: 2
Andere - Typ: Stahlrohr nach DIN 2448 309327; Familie: Stahlrohr nach DIN 2448 309327; Familie und Typ: Stahlrohr nach DIN 2448 309327: Stahlrohr nach DIN 2448 309327; Typ-ID: 2535063
Abhängigkeiten - Höhe von Ebene: 0 m; Verschieben mit umliegenden Elementen: no
Bemaßungen - Fläche: 0.00551505 m2; Volumen: 0.000304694 m3
IFC-Parameter - In IFC-Datei exportieren: Nach Typ; Pset MEP.Tech-Insulation thickness (mm): 100; Pset MEP.Geom-DN: 150; In IFC exportieren als: ifcflowsegment; NameOverride: Stahlrohr nach DIN 2448; IfcPresentationLayer: 0-TFT-H_Ruecklauf; ObjectTypeOverride: Stahlrohr nach DIN 2448; Pset MEP.Name: Stahlrohr nach DIN 2448; IfcDescription: Stahlrohr nach DIN 2448; Pset MEP.Geom-Outer Ø (mm): 168.3; Pset MEP.Tech-Material: Stahlrohr nach DIN 2448; Pset MEP.Geom-Length (mm): 20.9678
Phasen - Phase erstellt: Phase 01

# IfcFlowSegment: Stahlrohr nach DIN 2448 309511:Stahlrohr nach DIN 2448 309511, Stahlrohr nach DIN 2448
In: Erdgeschoss
Type - Material: IfcSurfaceStyle #1741
Type - Andere - Kategorie: Allgemeines Modell; Familienname: Stahlrohr nach DIN 2448 309511
Type - ID-Daten - Typname: Stahlrohr nach DIN 2448 309511
Type - IFC-Parameter - Typ in IFC-Datei exportieren: Vorgabe
Description: Stahlrohr nach DIN 2448
Pset_DistributionFlowElementCommon - Reference: Stahlrohr nach DIN 2448 309511; sets with these values: 2
Andere - Typ: Stahlrohr nach DIN 2448 309511; Familie: Stahlrohr nach DIN 2448 309511; Familie und Typ: Stahlrohr nach DIN 2448 309511: Stahlrohr nach DIN 2448 309511; Typ-ID: 2535077
Abhängigkeiten - Höhe von Ebene: 0 m; Verschieben mit umliegenden Elementen: no
Bemaßungen - Fläche: 0.131512 m2; Volumen: 0.00726576 m3
IFC-Parameter - In IFC-Datei exportieren: Nach Typ; Pset MEP.Tech-Insulation thickness (mm): 100; Pset MEP.Geom-DN: 150; In IFC exportieren als: ifcflowsegment; NameOverride: Stahlrohr nach DIN 2448; IfcPresentationLayer: 0-TFT-H_Ruecklauf; ObjectTypeOverride: Stahlrohr nach DIN 2448; Pset MEP.Name: Stahlrohr nach DIN 2448; IfcDescription: Stahlrohr nach DIN 2448; Pset MEP.Geom-Outer Ø (mm): 168.3; Pset MEP.Tech-Material: Stahlrohr nach DIN 2448; Pset MEP.Geom-Length (mm): 500
Phasen - Phase erstellt: Phase 01

# IfcFlowSegment: Stahlrohr nach DIN 2448 311373:Stahlrohr nach DIN 2448 311373, Stahlrohr nach DIN 2448
In: 1. Obergeschoss
Type - Material: IfcSurfaceStyle #1741
Type - Andere - Kategorie: Allgemeines Modell; Familienname: Stahlrohr nach DIN 2448 311373
Type - ID-Daten - Typname: Stahlrohr nach DIN 2448 311373
Type - IFC-Parameter - Typ in IFC-Datei exportieren: Vorgabe
Description: Stahlrohr nach DIN 2448
Pset_DistributionFlowElementCommon - Reference: Stahlrohr nach DIN 2448 311373; sets with these values: 2
Andere - Typ: Stahlrohr nach DIN 2448 311373; Familie: Stahlrohr nach DIN 2448 311373; Familie und Typ: Stahlrohr nach DIN 2448 311373: Stahlrohr nach DIN 2448 311373; Typ-ID: 2535098
Abhängigkeiten - Höhe von Ebene: 0 m; Verschieben mit umliegenden Elementen: no
Bemaßungen - Fläche: 0.0426698 m2; Volumen: 0.00160102 m3
IFC-Parameter - In IFC-Datei exportieren: Nach Typ; Pset MEP.Tech-Insulation thickness (mm): 100; Pset MEP.Geom-DN: 100; In IFC exportieren als: ifcflowsegment; NameOverride: Stahlrohr nach DIN 2448; IfcPresentationLayer: 0-TFT-H_Ruecklauf; ObjectTypeOverride: Stahlrohr nach DIN 2448; Pset MEP.Name: Stahlrohr nach DIN 2448; IfcDescription: Stahlrohr nach DIN 2448; Pset MEP.Geom-Outer Ø (mm): 114.3; Pset MEP.Tech-Material: Stahlrohr nach DIN 2448; Pset MEP.Geom-Length (mm): 238.87
Phasen - Phase erstellt: Phase 01

# IfcFlowSegment: Stahlrohr nach DIN 2448 314761:Stahlrohr nach DIN 2448 314761, Stahlrohr nach DIN 2448
In: Erdgeschoss
Type - Material: IfcSurfaceStyle #1741
Type - Andere - Kategorie: Allgemeines Modell; Familienname: Stahlrohr nach DIN 2448 314761
Type - ID-Daten - Typname: Stahlrohr nach DIN 2448 314761
Type - IFC-Parameter - Typ in IFC-Datei exportieren: Vorgabe
Description: Stahlrohr nach DIN 2448
Pset_DistributionFlowElementCommon - Reference: Stahlrohr nach DIN 2448 314761; sets with these values: 2
Andere - Typ: Stahlrohr nach DIN 2448 314761; Familie: Stahlrohr nach DIN 2448 314761; Familie und Typ: Stahlrohr nach DIN 2448 314761: Stahlrohr nach DIN 2448 314761; Typ-ID: 2535166
Abhängigkeiten - Höhe von Ebene: 0 m; Verschieben mit umliegenden Elementen: no
Bemaßungen - Fläche: 0.0178677 m2; Volumen: 0.000987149 m3
IFC-Parameter - In IFC-Datei exportieren: Nach Typ; Pset MEP.Tech-Insulation thickness (mm): 100; Pset MEP.Geom-DN: 150; In IFC exportieren als: ifcflowsegment; NameOverride: Stahlrohr nach DIN 2448; IfcPresentationLayer: 0-TFT-H_Ruecklauf; ObjectTypeOverride: Stahlrohr nach DIN 2448; Pset MEP.Name: Stahlrohr nach DIN 2448; IfcDescription: Stahlrohr nach DIN 2448; Pset MEP.Geom-Outer Ø (mm): 168.3; Pset MEP.Tech-Material: Stahlrohr nach DIN 2448; Pset MEP.Geom-Length (mm): 67.9316
Phasen - Phase erstellt: Phase 01

# IfcFlowSegment: Stahlrohr nach DIN 2448 314980:Stahlrohr nach DIN 2448 314980, Stahlrohr nach DIN 2448
In: Erdgeschoss
Type - Material: IfcSurfaceStyle #1741
Type - Andere - Kategorie: Allgemeines Modell; Familienname: Stahlrohr nach DIN 2448 314980
Type - ID-Daten - Typname: Stahlrohr nach DIN 2448 314980
Type - IFC-Parameter - Typ in IFC-Datei exportieren: Vorgabe
Description: Stahlrohr nach DIN 2448
Pset_DistributionFlowElementCommon - Reference: Stahlrohr nach DIN 2448 314980; sets with these values: 2
Andere - Typ: Stahlrohr nach DIN 2448 314980; Familie: Stahlrohr nach DIN 2448 314980; Familie und Typ: Stahlrohr nach DIN 2448 314980: Stahlrohr nach DIN 2448 314980; Typ-ID: 2535187
Abhängigkeiten - Höhe von Ebene: 0 m; Verschieben mit umliegenden Elementen: no
Bemaßungen - Fläche: 0.134246 m2; Volumen: 0.00741676 m3
IFC-Parameter - In IFC-Datei exportieren: Nach Typ; Pset MEP.Tech-Insulation thickness (mm): 100; Pset MEP.Geom-DN: 150; In IFC exportieren als: ifcflowsegment; NameOverride: Stahlrohr nach DIN 2448; IfcPresentationLayer: 0-TFT-H_Ruecklauf; ObjectTypeOverride: Stahlrohr nach DIN 2448; Pset MEP.Name: Stahlrohr nach DIN 2448; IfcDescription: Stahlrohr nach DIN 2448; Pset MEP.Geom-Outer Ø (mm): 168.3; Pset MEP.Tech-Material: Stahlrohr nach DIN 2448; Pset MEP.Geom-Length (mm): 510.391
Phasen - Phase erstellt: Phase 01

# IfcFlowSegment: Stahlrohr nach DIN 2448 316690:Stahlrohr nach DIN 2448 316690, Stahlrohr nach DIN 2448
In: 1. Obergeschoss
Type - Material: IfcSurfaceStyle #1741
Type - Andere - Kategorie: Allgemeines Modell; Familienname: Stahlrohr nach DIN 2448 316690
Type - ID-Daten - Typname: Stahlrohr nach DIN 2448 316690
Type - IFC-Parameter - Typ in IFC-Datei exportieren: Vorgabe
Description: Stahlrohr nach DIN 2448
Pset_DistributionFlowElementCommon - Reference: Stahlrohr nach DIN 2448 316690; sets with these values: 2
Andere - Typ: Stahlrohr nach DIN 2448 316690; Familie: Stahlrohr nach DIN 2448 316690; Familie und Typ: Stahlrohr nach DIN 2448 316690: Stahlrohr nach DIN 2448 316690; Typ-ID: 2535208
Abhängigkeiten - Höhe von Ebene: 0 m; Verschieben mit umliegenden Elementen: no
Bemaßungen - Fläche: 0.0626823 m2; Volumen: 0.00346306 m3
IFC-Parameter - In IFC-Datei exportieren: Nach Typ; Pset MEP.Tech-Insulation thickness (mm): 100; Pset MEP.Geom-DN: 150; In IFC exportieren als: ifcflowsegment; NameOverride: Stahlrohr nach DIN 2448; IfcPresentationLayer: 0-TFT-H_Ruecklauf; ObjectTypeOverride: Stahlrohr nach DIN 2448; Pset MEP.Name: Stahlrohr nach DIN 2448; IfcDescription: Stahlrohr nach DIN 2448; Pset MEP.Geom-Outer Ø (mm): 168.3; Pset MEP.Tech-Material: Stahlrohr nach DIN 2448; Pset MEP.Geom-Length (mm): 238.313
Phasen - Phase erstellt: Phase 01

# IfcFlowSegment: Stahlrohr nach DIN 2448 317104:Stahlrohr nach DIN 2448 317104, Stahlrohr nach DIN 2448
In: Erdgeschoss
Type - Material: IfcSurfaceStyle #9317
Type - Andere - Kategorie: Allgemeines Modell; Familienname: Stahlrohr nach DIN 2448 317104
Type - ID-Daten - Typname: Stahlrohr nach DIN 2448 317104
Type - IFC-Parameter - Typ in IFC-Datei exportieren: Vorgabe
Description: Stahlrohr nach DIN 2448
Pset_DistributionFlowElementCommon - Reference: Stahlrohr nach DIN 2448 317104; sets with these values: 2
Andere - Typ: Stahlrohr nach DIN 2448 317104; Familie: Stahlrohr nach DIN 2448 317104; Familie und Typ: Stahlrohr nach DIN 2448 317104: Stahlrohr nach DIN 2448 317104; Typ-ID: 2535243
Abhängigkeiten - Höhe von Ebene: 0 m; Verschieben mit umliegenden Elementen: no
Bemaßungen - Fläche: 0.0884674 m2; Volumen: 0.00488762 m3
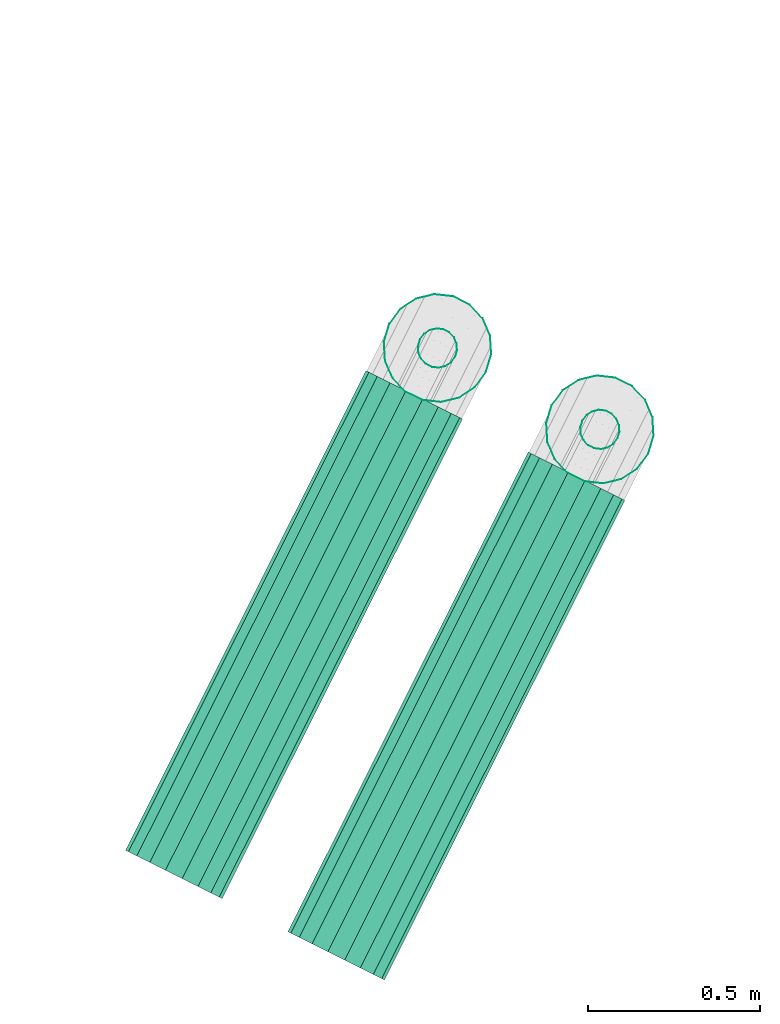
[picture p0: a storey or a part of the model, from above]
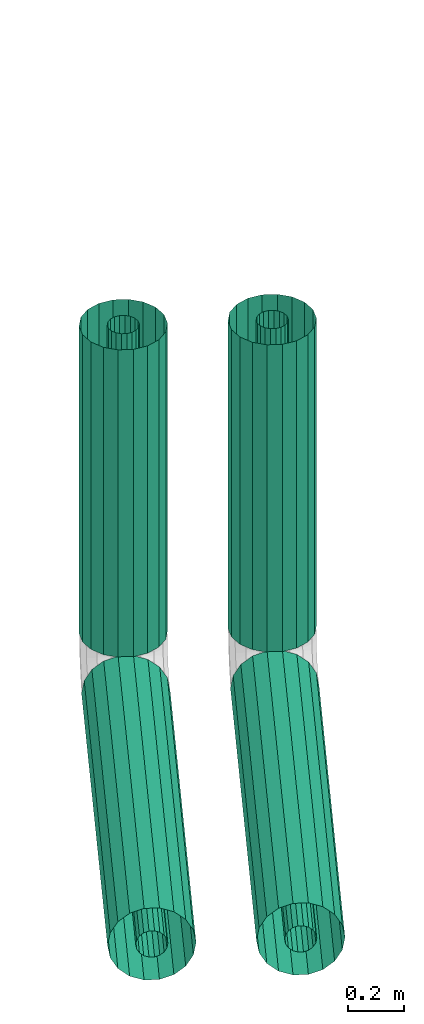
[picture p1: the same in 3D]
Properties of the parts of a building model (IFC2X3), part 19 of 23

# IfcFlowSegment: Stahlrohr nach DIN 2448 317104:Stahlrohr nach DIN 2448 317104, Stahlrohr nach DIN 2448
IFC-Parameter - In IFC-Datei exportieren: Nach Typ; Pset MEP.Tech-Insulation thickness (mm): 100; Pset MEP.Geom-DN: 150; In IFC exportieren als: ifcflowsegment; NameOverride: Stahlrohr nach DIN 2448; IfcPresentationLayer: 0-TFT-H_Vorlauf; ObjectTypeOverride: Stahlrohr nach DIN 2448; Pset MEP.Name: Stahlrohr nach DIN 2448; IfcDescription: Stahlrohr nach DIN 2448; Pset MEP.Geom-Outer Ø (mm): 168.3; Pset MEP.Tech-Material: Stahlrohr nach DIN 2448; Pset MEP.Geom-Length (mm): 336.346
Phasen - Phase erstellt: Phase 01

# IfcFlowSegment: Stahlrohr nach DIN 2448 317282:Stahlrohr nach DIN 2448 317282, Stahlrohr nach DIN 2448
In: Erdgeschoss
Type - Material: IfcSurfaceStyle #9317
Type - Andere - Kategorie: Allgemeines Modell; Familienname: Stahlrohr nach DIN 2448 317282
Type - ID-Daten - Typname: Stahlrohr nach DIN 2448 317282
Type - IFC-Parameter - Typ in IFC-Datei exportieren: Vorgabe
Description: Stahlrohr nach DIN 2448
Pset_DistributionFlowElementCommon - Reference: Stahlrohr nach DIN 2448 317282; sets with these values: 2
Andere - Typ: Stahlrohr nach DIN 2448 317282; Familie: Stahlrohr nach DIN 2448 317282; Familie und Typ: Stahlrohr nach DIN 2448 317282: Stahlrohr nach DIN 2448 317282; Typ-ID: 2535257
Abhängigkeiten - Höhe von Ebene: 0 m; Verschieben mit umliegenden Elementen: no
Bemaßungen - Fläche: 0.152386 m2; Volumen: 0.00698829 m3
IFC-Parameter - In IFC-Datei exportieren: Nach Typ; Pset MEP.Tech-Insulation thickness (mm): 100; Pset MEP.Geom-DN: 125; In IFC exportieren als: ifcflowsegment; NameOverride: Stahlrohr nach DIN 2448; IfcPresentationLayer: 0-TFT-H_Vorlauf; ObjectTypeOverride: Stahlrohr nach DIN 2448; Pset MEP.Name: Stahlrohr nach DIN 2448; IfcDescription: Stahlrohr nach DIN 2448; Pset MEP.Geom-Outer Ø (mm): 139.7; Pset MEP.Tech-Material: Stahlrohr nach DIN 2448; Pset MEP.Geom-Length (mm): 697.968
Phasen - Phase erstellt: Phase 01

# IfcFlowSegment: Stahlrohr nach DIN 2448 317526:Stahlrohr nach DIN 2448 317526, Stahlrohr nach DIN 2448
In: Erdgeschoss
Type - Material: IfcSurfaceStyle #9317
Type - Andere - Kategorie: Allgemeines Modell; Familienname: Stahlrohr nach DIN 2448 317526
Type - ID-Daten - Typname: Stahlrohr nach DIN 2448 317526
Type - IFC-Parameter - Typ in IFC-Datei exportieren: Vorgabe
Description: Stahlrohr nach DIN 2448
Pset_DistributionFlowElementCommon - Reference: Stahlrohr nach DIN 2448 317526; sets with these values: 2
Andere - Typ: Stahlrohr nach DIN 2448 317526; Familie: Stahlrohr nach DIN 2448 317526; Familie und Typ: Stahlrohr nach DIN 2448 317526: Stahlrohr nach DIN 2448 317526; Typ-ID: 2535292
Abhängigkeiten - Höhe von Ebene: 0 m; Verschieben mit umliegenden Elementen: no
Bemaßungen - Fläche: 0.282065 m2; Volumen: 0.0282939 m3
IFC-Parameter - In IFC-Datei exportieren: Nach Typ; Pset MEP.Tech-Insulation thickness (mm): 100; Pset MEP.Geom-DN: 150; In IFC exportieren als: ifcflowsegment; NameOverride: Stahlrohr nach DIN 2448; IfcPresentationLayer: 0-TFT-H_Vorlauf; ObjectTypeOverride: Stahlrohr nach DIN 2448; Pset MEP.Name: Stahlrohr nach DIN 2448; IfcDescription: Stahlrohr nach DIN 2448; Pset MEP.Geom-Outer Ø (mm): 168.3; Pset MEP.Tech-Material: Stahlrohr nach DIN 2448; Pset MEP.Geom-Length (mm): 336.346
Phasen - Phase erstellt: Phase 01

# IfcFlowSegment: Stahlrohr nach DIN 2448 318897:Stahlrohr nach DIN 2448 318897, Stahlrohr nach DIN 2448
In: Erdgeschoss
Type - Material: IfcSurfaceStyle #1741
Type - Andere - Kategorie: Allgemeines Modell; Familienname: Stahlrohr nach DIN 2448 318897
Type - ID-Daten - Typname: Stahlrohr nach DIN 2448 318897
Type - IFC-Parameter - Typ in IFC-Datei exportieren: Vorgabe
Description: Stahlrohr nach DIN 2448
Pset_DistributionFlowElementCommon - Reference: Stahlrohr nach DIN 2448 318897; sets with these values: 2
Andere - Typ: Stahlrohr nach DIN 2448 318897; Familie: Stahlrohr nach DIN 2448 318897; Familie und Typ: Stahlrohr nach DIN 2448 318897: Stahlrohr nach DIN 2448 318897; Typ-ID: 2535397
Abhängigkeiten - Höhe von Ebene: 0 m; Verschieben mit umliegenden Elementen: no
Bemaßungen - Fläche: 0.0175839 m2; Volumen: 0.00176384 m3
IFC-Parameter - In IFC-Datei exportieren: Nach Typ; Pset MEP.Tech-Insulation thickness (mm): 100; Pset MEP.Geom-DN: 150; In IFC exportieren als: ifcflowsegment; NameOverride: Stahlrohr nach DIN 2448; IfcPresentationLayer: 0-TFT-H_Ruecklauf; ObjectTypeOverride: Stahlrohr nach DIN 2448; Pset MEP.Name: Stahlrohr nach DIN 2448; IfcDescription: Stahlrohr nach DIN 2448; Pset MEP.Geom-Outer Ø (mm): 168.3; Pset MEP.Tech-Material: Stahlrohr nach DIN 2448; Pset MEP.Geom-Length (mm): 20.9678
Phasen - Phase erstellt: Phase 01

# IfcFlowSegment: Stahlrohr nach DIN 2448 319069:Stahlrohr nach DIN 2448 319069, Stahlrohr nach DIN 2448
In: Erdgeschoss
Type - Material: IfcSurfaceStyle #1741
Type - Andere - Kategorie: Allgemeines Modell; Familienname: Stahlrohr nach DIN 2448 319069
Type - ID-Daten - Typname: Stahlrohr nach DIN 2448 319069
Type - IFC-Parameter - Typ in IFC-Datei exportieren: Vorgabe
Description: Stahlrohr nach DIN 2448
Pset_DistributionFlowElementCommon - Reference: Stahlrohr nach DIN 2448 319069; sets with these values: 2
Andere - Typ: Stahlrohr nach DIN 2448 319069; Familie: Stahlrohr nach DIN 2448 319069; Familie und Typ: Stahlrohr nach DIN 2448 319069: Stahlrohr nach DIN 2448 319069; Typ-ID: 2535411
Abhängigkeiten - Höhe von Ebene: 0 m; Verschieben mit umliegenden Elementen: no
Bemaßungen - Fläche: 0.419308 m2; Volumen: 0.0420607 m3
IFC-Parameter - In IFC-Datei exportieren: Nach Typ; Pset MEP.Tech-Insulation thickness (mm): 100; Pset MEP.Geom-DN: 150; Pset MEP.Geom-Length (mm): 500; In IFC exportieren als: ifcflowsegment; NameOverride: Stahlrohr nach DIN 2448; IfcPresentationLayer: 0-TFT-H_Ruecklauf; ObjectTypeOverride: Stahlrohr nach DIN 2448; Pset MEP.Name: Stahlrohr nach DIN 2448; IfcDescription: Stahlrohr nach DIN 2448; Pset MEP.Geom-Outer Ø (mm): 168.3; Pset MEP.Tech-Material: Stahlrohr nach DIN 2448
Phasen - Phase erstellt: Phase 01

# IfcFlowSegment: Stahlrohr nach DIN 2448 319712:Stahlrohr nach DIN 2448 319712, Stahlrohr nach DIN 2448
In: 1. Obergeschoss
Type - Material: IfcSurfaceStyle #1741
Type - Andere - Kategorie: Allgemeines Modell; Familienname: Stahlrohr nach DIN 2448 319712
Type - ID-Daten - Typname: Stahlrohr nach DIN 2448 319712
Type - IFC-Parameter - Typ in IFC-Datei exportieren: Vorgabe
Description: Stahlrohr nach DIN 2448
Pset_DistributionFlowElementCommon - Reference: Stahlrohr nach DIN 2448 319712; sets with these values: 2
Andere - Typ: Stahlrohr nach DIN 2448 319712; Familie: Stahlrohr nach DIN 2448 319712; Familie und Typ: Stahlrohr nach DIN 2448 319712: Stahlrohr nach DIN 2448 319712; Typ-ID: 2535432
Abhängigkeiten - Höhe von Ebene: 0 m; Verschieben mit umliegenden Elementen: no
Bemaßungen - Fläche: 0.160003 m2; Volumen: 0.0137068 m3
IFC-Parameter - In IFC-Datei exportieren: Nach Typ; Pset MEP.Tech-Insulation thickness (mm): 100; Pset MEP.Geom-DN: 100; In IFC exportieren als: ifcflowsegment; NameOverride: Stahlrohr nach DIN 2448; IfcPresentationLayer: 0-TFT-H_Ruecklauf; ObjectTypeOverride: Stahlrohr nach DIN 2448; Pset MEP.Name: Stahlrohr nach DIN 2448; IfcDescription: Stahlrohr nach DIN 2448; Pset MEP.Geom-Outer Ø (mm): 114.3; Pset MEP.Tech-Material: Stahlrohr nach DIN 2448; Pset MEP.Geom-Length (mm): 238.87
Phasen - Phase erstellt: Phase 01

# IfcFlowSegment: Stahlrohr nach DIN 2448 320201:Stahlrohr nach DIN 2448 320201, Stahlrohr nach DIN 2448
In: Erdgeschoss
Type - Material: IfcSurfaceStyle #1741
Type - Andere - Kategorie: Allgemeines Modell; Familienname: Stahlrohr nach DIN 2448 320201
Type - ID-Daten - Typname: Stahlrohr nach DIN 2448 320201
Type - IFC-Parameter - Typ in IFC-Datei exportieren: Vorgabe
Description: Stahlrohr nach DIN 2448
Pset_DistributionFlowElementCommon - Reference: Stahlrohr nach DIN 2448 320201; sets with these values: 2
Andere - Typ: Stahlrohr nach DIN 2448 320201; Familie: Stahlrohr nach DIN 2448 320201; Familie und Typ: Stahlrohr nach DIN 2448 320201: Stahlrohr nach DIN 2448 320201; Typ-ID: 2535495
Abhängigkeiten - Höhe von Ebene: 0 m; Verschieben mit umliegenden Elementen: no
Bemaßungen - Fläche: 0.0569685 m2; Volumen: 0.0057145 m3
IFC-Parameter - In IFC-Datei exportieren: Nach Typ; Pset MEP.Tech-Insulation thickness (mm): 100; Pset MEP.Geom-DN: 150; In IFC exportieren als: ifcflowsegment; NameOverride: Stahlrohr nach DIN 2448; IfcPresentationLayer: 0-TFT-H_Ruecklauf; ObjectTypeOverride: Stahlrohr nach DIN 2448; Pset MEP.Name: Stahlrohr nach DIN 2448; IfcDescription: Stahlrohr nach DIN 2448; Pset MEP.Geom-Outer Ø (mm): 168.3; Pset MEP.Tech-Material: Stahlrohr nach DIN 2448; Pset MEP.Geom-Length (mm): 67.9316
Phasen - Phase erstellt: Phase 01

# IfcFlowSegment: Stahlrohr nach DIN 2448 320608:Stahlrohr nach DIN 2448 320608, Stahlrohr nach DIN 2448
In: 1. Obergeschoss
Type - Material: IfcSurfaceStyle #1741
Type - Andere - Kategorie: Allgemeines Modell; Familienname: Stahlrohr nach DIN 2448 320608
Type - ID-Daten - Typname: Stahlrohr nach DIN 2448 320608
Type - IFC-Parameter - Typ in IFC-Datei exportieren: Vorgabe
Description: Stahlrohr nach DIN 2448
Pset_DistributionFlowElementCommon - Reference: Stahlrohr nach DIN 2448 320608; sets with these values: 2
Andere - Typ: Stahlrohr nach DIN 2448 320608; Familie: Stahlrohr nach DIN 2448 320608; Familie und Typ: Stahlrohr nach DIN 2448 320608: Stahlrohr nach DIN 2448 320608; Typ-ID: 2535530
Abhängigkeiten - Höhe von Ebene: 0 m; Verschieben mit umliegenden Elementen: no
Bemaßungen - Fläche: 0.199853 m2; Volumen: 0.0200473 m3
IFC-Parameter - In IFC-Datei exportieren: Nach Typ; Pset MEP.Tech-Insulation thickness (mm): 100; Pset MEP.Geom-DN: 150; In IFC exportieren als: ifcflowsegment; NameOverride: Stahlrohr nach DIN 2448; IfcPresentationLayer: 0-TFT-H_Ruecklauf; ObjectTypeOverride: Stahlrohr nach DIN 2448; Pset MEP.Name: Stahlrohr nach DIN 2448; IfcDescription: Stahlrohr nach DIN 2448; Pset MEP.Geom-Outer Ø (mm): 168.3; Pset MEP.Tech-Material: Stahlrohr nach DIN 2448; Pset MEP.Geom-Length (mm): 238.313
Phasen - Phase erstellt: Phase 01

# IfcFlowSegment: Stahlrohr nach DIN 2448 320803:Stahlrohr nach DIN 2448 320803, Stahlrohr nach DIN 2448
In: Erdgeschoss
Type - Material: IfcSurfaceStyle #9317
Type - Andere - Kategorie: Allgemeines Modell; Familienname: Stahlrohr nach DIN 2448 320803
Type - ID-Daten - Typname: Stahlrohr nach DIN 2448 320803
Type - IFC-Parameter - Typ in IFC-Datei exportieren: Vorgabe
Description: Stahlrohr nach DIN 2448
Pset_DistributionFlowElementCommon - Reference: Stahlrohr nach DIN 2448 320803; sets with these values: 2
Andere - Typ: Stahlrohr nach DIN 2448 320803; Familie: Stahlrohr nach DIN 2448 320803; Familie und Typ: Stahlrohr nach DIN 2448 320803: Stahlrohr nach DIN 2448 320803; Typ-ID: 2535551
Abhängigkeiten - Höhe von Ebene: 0 m; Verschieben mit umliegenden Elementen: no
Bemaßungen - Fläche: 0.522933 m2; Volumen: 0.0483092 m3
IFC-Parameter - In IFC-Datei exportieren: Nach Typ; Pset MEP.Tech-Insulation thickness (mm): 100; Pset MEP.Geom-DN: 125; In IFC exportieren als: ifcflowsegment; NameOverride: Stahlrohr nach DIN 2448; IfcPresentationLayer: 0-TFT-H_Vorlauf; ObjectTypeOverride: Stahlrohr nach DIN 2448; Pset MEP.Name: Stahlrohr nach DIN 2448; IfcDescription: Stahlrohr nach DIN 2448; Pset MEP.Geom-Outer Ø (mm): 139.7; Pset MEP.Tech-Material: Stahlrohr nach DIN 2448; Pset MEP.Geom-Length (mm): 697.968
Phasen - Phase erstellt: Phase 01

# IfcFlowSegment: Stahlrohr nach DIN 2448 320998:Stahlrohr nach DIN 2448 320998, Stahlrohr nach DIN 2448
In: Erdgeschoss
Type - Material: IfcSurfaceStyle #1741
Type - Andere - Kategorie: Allgemeines Modell; Familienname: Stahlrohr nach DIN 2448 320998
Type - ID-Daten - Typname: Stahlrohr nach DIN 2448 320998
Type - IFC-Parameter - Typ in IFC-Datei exportieren: Vorgabe
Description: Stahlrohr nach DIN 2448
Pset_DistributionFlowElementCommon - Reference: Stahlrohr nach DIN 2448 320998; sets with these values: 2
Andere - Typ: Stahlrohr nach DIN 2448 320998; Familie: Stahlrohr nach DIN 2448 320998; Familie und Typ: Stahlrohr nach DIN 2448 320998: Stahlrohr nach DIN 2448 320998; Typ-ID: 2535572
Abhängigkeiten - Höhe von Ebene: 0 m; Verschieben mit umliegenden Elementen: no
Bemaßungen - Fläche: 0.435094 m2; Volumen: 0.0436441 m3
IFC-Parameter - In IFC-Datei exportieren: Nach Typ; Pset MEP.Tech-Insulation thickness (mm): 100; Pset MEP.Geom-DN: 150; In IFC exportieren als: ifcflowsegment; NameOverride: Stahlrohr nach DIN 2448; IfcPresentationLayer: 0-TFT-H_Ruecklauf; ObjectTypeOverride: Stahlrohr nach DIN 2448; Pset MEP.Name: Stahlrohr nach DIN 2448; IfcDescription: Stahlrohr nach DIN 2448; Pset MEP.Geom-Outer Ø (mm): 168.3; Pset MEP.Tech-Material: Stahlrohr nach DIN 2448; Pset MEP.Geom-Length (mm): 518.823
Phasen - Phase erstellt: Phase 01

# IfcFlowSegment: Stahlrohr nach DIN 2448 321279:Stahlrohr nach DIN 2448 321279, Stahlrohr nach DIN 2448
In: 1. Untergeschoss
Type - Material: IfcSurfaceStyle #1741
Type - Andere - Kategorie: Allgemeines Modell; Familienname: Stahlrohr nach DIN 2448 321279
Type - ID-Daten - Typname: Stahlrohr nach DIN 2448 321279
Type - IFC-Parameter - Typ in IFC-Datei exportieren: Vorgabe
Description: Stahlrohr nach DIN 2448
Pset_DistributionFlowElementCommon - Reference: Stahlrohr nach DIN 2448 321279; sets with these values: 2
Andere - Typ: Stahlrohr nach DIN 2448 321279; Familie: Stahlrohr nach DIN 2448 321279; Familie und Typ: Stahlrohr nach DIN 2448 321279: Stahlrohr nach DIN 2448 321279; Typ-ID: 2535579
Abhängigkeiten - Höhe von Ebene: 0 m; Verschieben mit umliegenden Elementen: no
Bemaßungen - Fläche: 1.04574 m2; Volumen: 0.0895843 m3
IFC-Parameter - In IFC-Datei exportieren: Nach Typ; Pset MEP.Tech-Insulation thickness (mm): 100; Pset MEP.Geom-DN: 100; In IFC exportieren als: ifcflowsegment; NameOverride: Stahlrohr nach DIN 2448; IfcPresentationLayer: 0-TFT-H_Ruecklauf; ObjectTypeOverride: Stahlrohr nach DIN 2448; Pset MEP.Name: Stahlrohr nach DIN 2448; IfcDescription: Stahlrohr nach DIN 2448; Pset MEP.Geom-Outer Ø (mm): 114.3; Pset MEP.Tech-Material: Stahlrohr nach DIN 2448; Pset MEP.Geom-Length (mm): 1561.2
Phasen - Phase erstellt: Phase 01

# IfcFlowSegment: Stahlrohr nach DIN 2448 321560:Stahlrohr nach DIN 2448 321560, Stahlrohr nach DIN 2448
In: 1. Untergeschoss
Type - Material: IfcSurfaceStyle #9317
Type - Andere - Kategorie: Allgemeines Modell; Familienname: Stahlrohr nach DIN 2448 321560
Type - ID-Daten - Typname: Stahlrohr nach DIN 2448 321560
Type - IFC-Parameter - Typ in IFC-Datei exportieren: Vorgabe
Description: Stahlrohr nach DIN 2448
Pset_DistributionFlowElementCommon - Reference: Stahlrohr nach DIN 2448 321560; sets with these values: 2
Andere - Typ: Stahlrohr nach DIN 2448 321560; Familie: Stahlrohr nach DIN 2448 321560; Familie und Typ: Stahlrohr nach DIN 2448 321560: Stahlrohr nach DIN 2448 321560; Typ-ID: 2535586
Abhängigkeiten - Höhe von Ebene: 0 m; Verschieben mit umliegenden Elementen: no
Bemaßungen - Fläche: 1.04574 m2; Volumen: 0.0895843 m3
IFC-Parameter - In IFC-Datei exportieren: Nach Typ; Pset MEP.Tech-Insulation thickness (mm): 100; Pset MEP.Geom-DN: 100; In IFC exportieren als: ifcflowsegment; NameOverride: Stahlrohr nach DIN 2448; IfcPresentationLayer: 0-TFT-H_Vorlauf; ObjectTypeOverride: Stahlrohr nach DIN 2448; Pset MEP.Name: Stahlrohr nach DIN 2448; IfcDescription: Stahlrohr nach DIN 2448; Pset MEP.Geom-Outer Ø (mm): 114.3; Pset MEP.Tech-Material: Stahlrohr nach DIN 2448; Pset MEP.Geom-Length (mm): 1561.2
Phasen - Phase erstellt: Phase 01

# IfcFlowSegment: Stahlrohr nach DIN 2448 330890:Stahlrohr nach DIN 2448 330890, Stahlrohr nach DIN 2448
In: Erdgeschoss
Type - Material: IfcSurfaceStyle #1741
Type - Andere - Kategorie: Allgemeines Modell; Familienname: Stahlrohr nach DIN 2448 330890
Type - ID-Daten - Typname: Stahlrohr nach DIN 2448 330890
Type - IFC-Parameter - Typ in IFC-Datei exportieren: Vorgabe
Description: Stahlrohr nach DIN 2448
Pset_DistributionFlowElementCommon - Reference: Stahlrohr nach DIN 2448 330890; sets with these values: 2
Andere - Typ: Stahlrohr nach DIN 2448 330890; Familie: Stahlrohr nach DIN 2448 330890; Familie und Typ: Stahlrohr nach DIN 2448 330890: Stahlrohr nach DIN 2448 330890; Typ-ID: 2535740
Abhängigkeiten - Höhe von Ebene: 0 m; Verschieben mit umliegenden Elementen: no
Bemaßungen - Fläche: 0.0213276 m2; Volumen: 0.00163048 m3
IFC-Parameter - In IFC-Datei exportieren: Nach Typ; Pset MEP.Tech-Insulation thickness (mm): 100; Pset MEP.Geom-DN: 65; In IFC exportieren als: ifcflowsegment; NameOverride: Stahlrohr nach DIN 2448; IfcPresentationLayer: 0-TFT-H_Ruecklauf; ObjectTypeOverride: Stahlrohr nach DIN 2448; Pset MEP.Name: Stahlrohr nach DIN 2448; IfcDescription: Stahlrohr nach DIN 2448; Pset MEP.Geom-Outer Ø (mm): 76.1; Pset MEP.Tech-Material: Stahlrohr nach DIN 2448; Pset MEP.Geom-Length (mm): 38.7472
Phasen - Phase erstellt: Phase 01

# IfcFlowSegment: Stahlrohr nach DIN 2448 331200:Stahlrohr nach DIN 2448 331200, Stahlrohr nach DIN 2448
In: Erdgeschoss
Type - Material: IfcSurfaceStyle #1741
Type - Andere - Kategorie: Allgemeines Modell; Familienname: Stahlrohr nach DIN 2448 331200
Type - ID-Daten - Typname: Stahlrohr nach DIN 2448 331200
Type - IFC-Parameter - Typ in IFC-Datei exportieren: Vorgabe
Description: Stahlrohr nach DIN 2448
Pset_DistributionFlowElementCommon - Reference: Stahlrohr nach DIN 2448 331200; sets with these values: 2
Andere - Typ: Stahlrohr nach DIN 2448 331200; Familie: Stahlrohr nach DIN 2448 331200; Familie und Typ: Stahlrohr nach DIN 2448 331200: Stahlrohr nach DIN 2448 331200; Typ-ID: 2535754
Abhängigkeiten - Höhe von Ebene: 0 m; Verschieben mit umliegenden Elementen: no
Bemaßungen - Fläche: 0.0908771 m2; Volumen: 0.00694749 m3
IFC-Parameter - In IFC-Datei exportieren: Nach Typ; Pset MEP.Tech-Insulation thickness (mm): 100; Pset MEP.Geom-DN: 65; In IFC exportieren als: ifcflowsegment; NameOverride: Stahlrohr nach DIN 2448; IfcPresentationLayer: 0-TFT-H_Ruecklauf; ObjectTypeOverride: Stahlrohr nach DIN 2448; Pset MEP.Name: Stahlrohr nach DIN 2448; IfcDescription: Stahlrohr nach DIN 2448; Pset MEP.Geom-Outer Ø (mm): 76.1; Pset MEP.Tech-Material: Stahlrohr nach DIN 2448; Pset MEP.Geom-Length (mm): 165.102
Phasen - Phase erstellt: Phase 01

# IfcFlowSegment: Stahlrohr nach DIN 2448 331948:Stahlrohr nach DIN 2448 331948, Stahlrohr nach DIN 2448
In: Erdgeschoss
Type - Material: IfcSurfaceStyle #9317
Type - Andere - Kategorie: Allgemeines Modell; Familienname: Stahlrohr nach DIN 2448 331948
Type - ID-Daten - Typname: Stahlrohr nach DIN 2448 331948
Type - IFC-Parameter - Typ in IFC-Datei exportieren: Vorgabe
Description: Stahlrohr nach DIN 2448
Pset_DistributionFlowElementCommon - Reference: Stahlrohr nach DIN 2448 331948; sets with these values: 2
Andere - Typ: Stahlrohr nach DIN 2448 331948; Familie: Stahlrohr nach DIN 2448 331948; Familie und Typ: Stahlrohr nach DIN 2448 331948: Stahlrohr nach DIN 2448 331948; Typ-ID: 2535775
Abhängigkeiten - Höhe von Ebene: 0 m; Verschieben mit umliegenden Elementen: no
Bemaßungen - Fläche: 0.610424 m2; Volumen: 0.0484604 m3
IFC-Parameter - In IFC-Datei exportieren: Nach Typ; Pset MEP.Tech-Insulation thickness (mm): 100; Pset MEP.Geom-DN: 80; In IFC exportieren als: ifcflowsegment; NameOverride: Stahlrohr nach DIN 2448; IfcPresentationLayer: 0-TFT-H_Vorlauf; ObjectTypeOverride: Stahlrohr nach DIN 2448; Pset MEP.Name: Stahlrohr nach DIN 2448; IfcDescription: Stahlrohr nach DIN 2448; Pset MEP.Geom-Outer Ø (mm): 88.9; Pset MEP.Tech-Material: Stahlrohr nach DIN 2448; Pset MEP.Geom-Length (mm): 1033.85
Phasen - Phase erstellt: Phase 01

# IfcFlowSegment: Stahlrohr nach DIN 2448 332229:Stahlrohr nach DIN 2448 332229, Stahlrohr nach DIN 2448
In: Erdgeschoss
Type - Material: IfcSurfaceStyle #9317
Type - Andere - Kategorie: Allgemeines Modell; Familienname: Stahlrohr nach DIN 2448 332229
Type - ID-Daten - Typname: Stahlrohr nach DIN 2448 332229
Type - IFC-Parameter - Typ in IFC-Datei exportieren: Vorgabe
Description: Stahlrohr nach DIN 2448
Pset_DistributionFlowElementCommon - Reference: Stahlrohr nach DIN 2448 332229; sets with these values: 2
Andere - Typ: Stahlrohr nach DIN 2448 332229; Familie: Stahlrohr nach DIN 2448 332229; Familie und Typ: Stahlrohr nach DIN 2448 332229: Stahlrohr nach DIN 2448 332229; Typ-ID: 2535782
Abhängigkeiten - Höhe von Ebene: 0 m; Verschieben mit umliegenden Elementen: no
Bemaßungen - Fläche: 0.499099 m2; Volumen: 0.0381558 m3
IFC-Parameter - In IFC-Datei exportieren: Nach Typ; Pset MEP.Tech-Insulation thickness (mm): 100; Pset MEP.Geom-DN: 65; In IFC exportieren als: ifcflowsegment; NameOverride: Stahlrohr nach DIN 2448; IfcPresentationLayer: 0-TFT-H_Vorlauf; ObjectTypeOverride: Stahlrohr nach DIN 2448; Pset MEP.Name: Stahlrohr nach DIN 2448; IfcDescription: Stahlrohr nach DIN 2448; Pset MEP.Geom-Outer Ø (mm): 76.1; Pset MEP.Tech-Material: Stahlrohr nach DIN 2448; Pset MEP.Geom-Length (mm): 906.744
Phasen - Phase erstellt: Phase 01

# IfcFlowSegment: Stahlrohr nach DIN 2448 334561:Stahlrohr nach DIN 2448 334561, Stahlrohr nach DIN 2448
In: Erdgeschoss
Type - Material: IfcSurfaceStyle #1741
Type - Andere - Kategorie: Allgemeines Modell; Familienname: Stahlrohr nach DIN 2448 334561
Type - ID-Daten - Typname: Stahlrohr nach DIN 2448 334561
Type - IFC-Parameter - Typ in IFC-Datei exportieren: Vorgabe
Description: Stahlrohr nach DIN 2448
Pset_DistributionFlowElementCommon - Reference: Stahlrohr nach DIN 2448 334561; sets with these values: 2
Andere - Typ: Stahlrohr nach DIN 2448 334561; Familie: Stahlrohr nach DIN 2448 334561; Familie und Typ: Stahlrohr nach DIN 2448 334561: Stahlrohr nach DIN 2448 334561; Typ-ID: 2535803
Abhängigkeiten - Höhe von Ebene: 0 m; Verschieben mit umliegenden Elementen: no
Bemaßungen - Fläche: 0.124686 m2; Volumen: 0.00953212 m3
IFC-Parameter - In IFC-Datei exportieren: Nach Typ; Pset MEP.Tech-Insulation thickness (mm): 100; Pset MEP.Geom-DN: 65; In IFC exportieren als: ifcflowsegment; NameOverride: Stahlrohr nach DIN 2448; IfcPresentationLayer: 0-TFT-H_Ruecklauf; ObjectTypeOverride: Stahlrohr nach DIN 2448; Pset MEP.Name: Stahlrohr nach DIN 2448; IfcDescription: Stahlrohr nach DIN 2448; Pset MEP.Geom-Outer Ø (mm): 76.1; Pset MEP.Tech-Material: Stahlrohr nach DIN 2448; Pset MEP.Geom-Length (mm): 226.524
Phasen - Phase erstellt: Phase 01

# IfcFlowSegment: Stahlrohr nach DIN 2448 336093:Stahlrohr nach DIN 2448 336093, Stahlrohr nach DIN 2448
In: Erdgeschoss
Type - Material: IfcSurfaceStyle #1741
Type - Andere - Kategorie: Allgemeines Modell; Familienname: Stahlrohr nach DIN 2448 336093
Type - ID-Daten - Typname: Stahlrohr nach DIN 2448 336093
Type - IFC-Parameter - Typ in IFC-Datei exportieren: Vorgabe
Description: Stahlrohr nach DIN 2448
Pset_DistributionFlowElementCommon - Reference: Stahlrohr nach DIN 2448 336093; sets with these values: 2
Andere - Typ: Stahlrohr nach DIN 2448 336093; Familie: Stahlrohr nach DIN 2448 336093; Familie und Typ: Stahlrohr nach DIN 2448 336093: Stahlrohr nach DIN 2448 336093; Typ-ID: 2535838
Abhängigkeiten - Höhe von Ebene: 0 m; Verschieben mit umliegenden Elementen: no
Bemaßungen - Fläche: 0.0275215 m2; Volumen: 0.002104 m3
IFC-Parameter - In IFC-Datei exportieren: Nach Typ; Pset MEP.Tech-Insulation thickness (mm): 100; Pset MEP.Geom-DN: 65; In IFC exportieren als: ifcflowsegment; NameOverride: Stahlrohr nach DIN 2448; IfcPresentationLayer: 0-TFT-H_Ruecklauf; ObjectTypeOverride: Stahlrohr nach DIN 2448; Pset MEP.Name: Stahlrohr nach DIN 2448; IfcDescription: Stahlrohr nach DIN 2448; Pset MEP.Geom-Outer Ø (mm): 76.1; Pset MEP.Tech-Material: Stahlrohr nach DIN 2448; Pset MEP.Geom-Length (mm): 50
Phasen - Phase erstellt: Phase 01

# IfcFlowSegment: Stahlrohr nach DIN 2448 340650:Stahlrohr nach DIN 2448 340650, Stahlrohr nach DIN 2448
In: Erdgeschoss
Type - Material: IfcSurfaceStyle #9317
Type - Andere - Kategorie: Allgemeines Modell; Familienname: Stahlrohr nach DIN 2448 340650
Type - ID-Daten - Typname: Stahlrohr nach DIN 2448 340650
Type - IFC-Parameter - Typ in IFC-Datei exportieren: Vorgabe
Description: Stahlrohr nach DIN 2448
Pset_DistributionFlowElementCommon - Reference: Stahlrohr nach DIN 2448 340650; sets with these values: 2
Andere - Typ: Stahlrohr nach DIN 2448 340650; Familie: Stahlrohr nach DIN 2448 340650; Familie und Typ: Stahlrohr nach DIN 2448 340650: Stahlrohr nach DIN 2448 340650; Typ-ID: 2535894
Abhängigkeiten - Höhe von Ebene: 0 m; Verschieben mit umliegenden Elementen: no
Bemaßungen - Fläche: 0.282065 m2; Volumen: 0.0282939 m3
IFC-Parameter - In IFC-Datei exportieren: Nach Typ; Pset MEP.Tech-Insulation thickness (mm): 100; Pset MEP.Geom-DN: 150; In IFC exportieren als: ifcflowsegment; NameOverride: Stahlrohr nach DIN 2448; IfcPresentationLayer: 0-TFT-H_Vorlauf; ObjectTypeOverride: Stahlrohr nach DIN 2448; Pset MEP.Name: Stahlrohr nach DIN 2448; IfcDescription: Stahlrohr nach DIN 2448; Pset MEP.Geom-Outer Ø (mm): 168.3; Pset MEP.Tech-Material: Stahlrohr nach DIN 2448; Pset MEP.Geom-Length (mm): 336.346
Phasen - Phase erstellt: Phase 01

# IfcFlowSegment: Stahlrohr nach DIN 2448 340949:Stahlrohr nach DIN 2448 340949, Stahlrohr nach DIN 2448
In: Erdgeschoss
Type - Material: IfcSurfaceStyle #1741
Type - Andere - Kategorie: Allgemeines Modell; Familienname: Stahlrohr nach DIN 2448 340949
Type - ID-Daten - Typname: Stahlrohr nach DIN 2448 340949
Type - IFC-Parameter - Typ in IFC-Datei exportieren: Vorgabe
Description: Stahlrohr nach DIN 2448
Pset_DistributionFlowElementCommon - Reference: Stahlrohr nach DIN 2448 340949; sets with these values: 2
Andere - Typ: Stahlrohr nach DIN 2448 340949; Familie: Stahlrohr nach DIN 2448 340949; Familie und Typ: Stahlrohr nach DIN 2448 340949: Stahlrohr nach DIN 2448 340949; Typ-ID: 2535985
Abhängigkeiten - Höhe von Ebene: 0 m; Verschieben mit umliegenden Elementen: no
Bemaßungen - Fläche: 0.0175839 m2; Volumen: 0.00176384 m3
IFC-Parameter - In IFC-Datei exportieren: Nach Typ; Pset MEP.Tech-Insulation thickness (mm): 100; Pset MEP.Geom-DN: 150; In IFC exportieren als: ifcflowsegment; NameOverride: Stahlrohr nach DIN 2448; IfcPresentationLayer: 0-TFT-H_Ruecklauf; ObjectTypeOverride: Stahlrohr nach DIN 2448; Pset MEP.Name: Stahlrohr nach DIN 2448; IfcDescription: Stahlrohr nach DIN 2448; Pset MEP.Geom-Outer Ø (mm): 168.3; Pset MEP.Tech-Material: Stahlrohr nach DIN 2448; Pset MEP.Geom-Length (mm): 20.9678
Phasen - Phase erstellt: Phase 01

# IfcFlowSegment: Stahlrohr nach DIN 2448 341127:Stahlrohr nach DIN 2448 341127, Stahlrohr nach DIN 2448
In: Erdgeschoss
Type - Material: IfcSurfaceStyle #1741
Type - Andere - Kategorie: Allgemeines Modell; Familienname: Stahlrohr nach DIN 2448 341127
Type - ID-Daten - Typname: Stahlrohr nach DIN 2448 341127
Type - IFC-Parameter - Typ in IFC-Datei exportieren: Vorgabe
Description: Stahlrohr nach DIN 2448
Pset_DistributionFlowElementCommon - Reference: Stahlrohr nach DIN 2448 341127; sets with these values: 2
Andere - Typ: Stahlrohr nach DIN 2448 341127; Familie: Stahlrohr nach DIN 2448 341127; Familie und Typ: Stahlrohr nach DIN 2448 341127: Stahlrohr nach DIN 2448 341127; Typ-ID: 2536041
Abhängigkeiten - Höhe von Ebene: 0 m; Verschieben mit umliegenden Elementen: no
Bemaßungen - Fläche: 0.0569685 m2; Volumen: 0.0057145 m3
IFC-Parameter - In IFC-Datei exportieren: Nach Typ; Pset MEP.Tech-Insulation thickness (mm): 100; Pset MEP.Geom-DN: 150; In IFC exportieren als: ifcflowsegment; NameOverride: Stahlrohr nach DIN 2448; IfcPresentationLayer: 0-TFT-H_Ruecklauf; ObjectTypeOverride: Stahlrohr nach DIN 2448; Pset MEP.Name: Stahlrohr nach DIN 2448; IfcDescription: Stahlrohr nach DIN 2448; Pset MEP.Geom-Outer Ø (mm): 168.3; Pset MEP.Tech-Material: Stahlrohr nach DIN 2448; Pset MEP.Geom-Length (mm): 67.9316
Phasen - Phase erstellt: Phase 01

# IfcFlowSegment: Stahlrohr nach DIN 2448 341220:Stahlrohr nach DIN 2448 341220, Stahlrohr nach DIN 2448
In: Erdgeschoss
Type - Material: IfcSurfaceStyle #9317
Type - Andere - Kategorie: Allgemeines Modell; Familienname: Stahlrohr nach DIN 2448 341220
Type - ID-Daten - Typname: Stahlrohr nach DIN 2448 341220
Type - IFC-Parameter - Typ in IFC-Datei exportieren: Vorgabe
Description: Stahlrohr nach DIN 2448
Pset_DistributionFlowElementCommon - Reference: Stahlrohr nach DIN 2448 341220; sets with these values: 2
Andere - Typ: Stahlrohr nach DIN 2448 341220; Familie: Stahlrohr nach DIN 2448 341220; Familie und Typ: Stahlrohr nach DIN 2448 341220: Stahlrohr nach DIN 2448 341220; Typ-ID: 2536062
Abhängigkeiten - Höhe von Ebene: 0 m; Verschieben mit umliegenden Elementen: no
Bemaßungen - Fläche: 0.522933 m2; Volumen: 0.0483092 m3
IFC-Parameter - In IFC-Datei exportieren: Nach Typ; Pset MEP.Tech-Insulation thickness (mm): 100; Pset MEP.Geom-DN: 125; In IFC exportieren als: ifcflowsegment; NameOverride: Stahlrohr nach DIN 2448; IfcPresentationLayer: 0-TFT-H_Vorlauf; ObjectTypeOverride: Stahlrohr nach DIN 2448; Pset MEP.Name: Stahlrohr nach DIN 2448; IfcDescription: Stahlrohr nach DIN 2448; Pset MEP.Geom-Outer Ø (mm): 139.7; Pset MEP.Tech-Material: Stahlrohr nach DIN 2448; Pset MEP.Geom-Length (mm): 697.968
Phasen - Phase erstellt: Phase 01

# IfcFlowSegment: Stahlrohr nach DIN 2448 341587:Stahlrohr nach DIN 2448 341587, Stahlrohr nach DIN 2448
In: Erdgeschoss
Type - Material: IfcSurfaceStyle #9317
Type - Andere - Kategorie: Allgemeines Modell; Familienname: Stahlrohr nach DIN 2448 341587
Type - ID-Daten - Typname: Stahlrohr nach DIN 2448 341587
Type - IFC-Parameter - Typ in IFC-Datei exportieren: Vorgabe
Description: Stahlrohr nach DIN 2448
Pset_DistributionFlowElementCommon - Reference: Stahlrohr nach DIN 2448 341587; sets with these values: 2
Andere - Typ: Stahlrohr nach DIN 2448 341587; Familie: Stahlrohr nach DIN 2448 341587; Familie und Typ: Stahlrohr nach DIN 2448 341587: Stahlrohr nach DIN 2448 341587; Typ-ID: 2536083
Abhängigkeiten - Höhe von Ebene: 0 m; Verschieben mit umliegenden Elementen: no
Bemaßungen - Fläche: 0.234876 m2; Volumen: 0.0129764 m3
IFC-Parameter - In IFC-Datei exportieren: Nach Typ; Pset MEP.Tech-Insulation thickness (mm): 100; Pset MEP.Geom-DN: 150; In IFC exportieren als: ifcflowsegment; NameOverride: Stahlrohr nach DIN 2448; IfcPresentationLayer: 0-TFT-H_Vorlauf; ObjectTypeOverride: Stahlrohr nach DIN 2448; Pset MEP.Name: Stahlrohr nach DIN 2448; IfcDescription: Stahlrohr nach DIN 2448; Pset MEP.Geom-Outer Ø (mm): 168.3; Pset MEP.Tech-Material: Stahlrohr nach DIN 2448; Pset MEP.Geom-Length (mm): 892.98
Phasen - Phase erstellt: Phase 01

# IfcFlowSegment: Stahlrohr nach DIN 2448 342082:Stahlrohr nach DIN 2448 342082, Stahlrohr nach DIN 2448
In: Erdgeschoss
Type - Material: IfcSurfaceStyle #9317
Type - Andere - Kategorie: Allgemeines Modell; Familienname: Stahlrohr nach DIN 2448 342082
Type - ID-Daten - Typname: Stahlrohr nach DIN 2448 342082
Type - IFC-Parameter - Typ in IFC-Datei exportieren: Vorgabe
Description: Stahlrohr nach DIN 2448
Pset_DistributionFlowElementCommon - Reference: Stahlrohr nach DIN 2448 342082; sets with these values: 2
Andere - Typ: Stahlrohr nach DIN 2448 342082; Familie: Stahlrohr nach DIN 2448 342082; Familie und Typ: Stahlrohr nach DIN 2448 342082: Stahlrohr nach DIN 2448 342082; Typ-ID: 2536104
Abhängigkeiten - Höhe von Ebene: 0 m; Verschieben mit umliegenden Elementen: no
Bemaßungen - Fläche: 0.748867 m2; Volumen: 0.0751187 m3
IFC-Parameter - In IFC-Datei exportieren: Nach Typ; Pset MEP.Tech-Insulation thickness (mm): 100; Pset MEP.Geom-DN: 150; In IFC exportieren als: ifcflowsegment; NameOverride: Stahlrohr nach DIN 2448; IfcPresentationLayer: 0-TFT-H_Vorlauf; ObjectTypeOverride: Stahlrohr nach DIN 2448; Pset MEP.Name: Stahlrohr nach DIN 2448; IfcDescription: Stahlrohr nach DIN 2448; Pset MEP.Geom-Outer Ø (mm): 168.3; Pset MEP.Tech-Material: Stahlrohr nach DIN 2448; Pset MEP.Geom-Length (mm): 892.98
Phasen - Phase erstellt: Phase 01

# IfcFlowSegment: Stahlrohr nach DIN 2448 342277:Stahlrohr nach DIN 2448 342277, Stahlrohr nach DIN 2448
In: Erdgeschoss
Type - Material: IfcSurfaceStyle #9317
Type - Andere - Kategorie: Allgemeines Modell; Familienname: Stahlrohr nach DIN 2448 342277
Type - ID-Daten - Typname: Stahlrohr nach DIN 2448 342277
Type - IFC-Parameter - Typ in IFC-Datei exportieren: Vorgabe
Description: Stahlrohr nach DIN 2448
Pset_DistributionFlowElementCommon - Reference: Stahlrohr nach DIN 2448 342277; sets with these values: 2
Andere - Typ: Stahlrohr nach DIN 2448 342277; Familie: Stahlrohr nach DIN 2448 342277; Familie und Typ: Stahlrohr nach DIN 2448 342277: Stahlrohr nach DIN 2448 342277; Typ-ID: 2536125
Abhängigkeiten - Höhe von Ebene: 0 m; Verschieben mit umliegenden Elementen: no
Bemaßungen - Fläche: 0.748867 m2; Volumen: 0.0751187 m3
IFC-Parameter - In IFC-Datei exportieren: Nach Typ; Pset MEP.Tech-Insulation thickness (mm): 100; Pset MEP.Geom-DN: 150; In IFC exportieren als: ifcflowsegment; NameOverride: Stahlrohr nach DIN 2448; IfcPresentationLayer: 0-TFT-H_Vorlauf; ObjectTypeOverride: Stahlrohr nach DIN 2448; Pset MEP.Name: Stahlrohr nach DIN 2448; IfcDescription: Stahlrohr nach DIN 2448; Pset MEP.Geom-Outer Ø (mm): 168.3; Pset MEP.Tech-Material: Stahlrohr nach DIN 2448; Pset MEP.Geom-Length (mm): 892.98
Phasen - Phase erstellt: Phase 01

# IfcFlowSegment: Stahlrohr nach DIN 2448 342346:Stahlrohr nach DIN 2448 342346, Stahlrohr nach DIN 2448
In: Erdgeschoss
Type - Material: IfcSurfaceStyle #9317
Type - Andere - Kategorie: Allgemeines Modell; Familienname: Stahlrohr nach DIN 2448 342346
Type - ID-Daten - Typname: Stahlrohr nach DIN 2448 342346
Type - IFC-Parameter - Typ in IFC-Datei exportieren: Vorgabe
Description: Stahlrohr nach DIN 2448
Pset_DistributionFlowElementCommon - Reference: Stahlrohr nach DIN 2448 342346; sets with these values: 2
Andere - Typ: Stahlrohr nach DIN 2448 342346; Familie: Stahlrohr nach DIN 2448 342346; Familie und Typ: Stahlrohr nach DIN 2448 342346: Stahlrohr nach DIN 2448 342346; Typ-ID: 2536146
Abhängigkeiten - Höhe von Ebene: 0 m; Verschieben mit umliegenden Elementen: no
Bemaßungen - Fläche: 1.77781 m2; Volumen: 0.204516 m3
IFC-Parameter - In IFC-Datei exportieren: Nach Typ; Pset MEP.Geom-DN: 200; Pset MEP.Tech-Insulation thickness (mm): 100; In IFC exportieren als: ifcflowsegment; NameOverride: Stahlrohr nach DIN 2448; IfcPresentationLayer: 0-TFT-H_Vorlauf; ObjectTypeOverride: Stahlrohr nach DIN 2448; Pset MEP.Name: Stahlrohr nach DIN 2448; IfcDescription: Stahlrohr nach DIN 2448; Pset MEP.Geom-Outer Ø (mm): 219.1; Pset MEP.Tech-Material: Stahlrohr nach DIN 2448; Pset MEP.Geom-Length (mm): 1782.44
Phasen - Phase erstellt: Phase 01

# IfcFlowSegment: Stahlrohr nach DIN 2448 342650:Stahlrohr nach DIN 2448 342650, Stahlrohr nach DIN 2448
In: Erdgeschoss
Type - Material: IfcSurfaceStyle #9317
Type - Andere - Kategorie: Allgemeines Modell; Familienname: Stahlrohr nach DIN 2448 342650
Type - ID-Daten - Typname: Stahlrohr nach DIN 2448 342650
Type - IFC-Parameter - Typ in IFC-Datei exportieren: Vorgabe
Description: Stahlrohr nach DIN 2448
Pset_DistributionFlowElementCommon - Reference: Stahlrohr nach DIN 2448 342650; sets with these values: 2
Andere - Typ: Stahlrohr nach DIN 2448 342650; Familie: Stahlrohr nach DIN 2448 342650; Familie und Typ: Stahlrohr nach DIN 2448 342650: Stahlrohr nach DIN 2448 342650; Typ-ID: 2536160
Abhängigkeiten - Höhe von Ebene: 0 m; Verschieben mit umliegenden Elementen: no
Bemaßungen - Fläche: 3.30024 m2; Volumen: 0.379654 m3
IFC-Parameter - In IFC-Datei exportieren: Nach Typ; Pset MEP.Geom-DN: 200; Pset MEP.Tech-Insulation thickness (mm): 100; In IFC exportieren als: ifcflowsegment; NameOverride: Stahlrohr nach DIN 2448; IfcPresentationLayer: 0-TFT-H_Vorlauf; ObjectTypeOverride: Stahlrohr nach DIN 2448; Pset MEP.Name: Stahlrohr nach DIN 2448; IfcDescription: Stahlrohr nach DIN 2448; Pset MEP.Geom-Outer Ø (mm): 219.1; Pset MEP.Tech-Material: Stahlrohr nach DIN 2448; Pset MEP.Geom-Length (mm): 3308.85
Phasen - Phase erstellt: Phase 01

# IfcFlowSegment: Stahlrohr nach DIN 2448 343104:Stahlrohr nach DIN 2448 343104, Stahlrohr nach DIN 2448
In: Erdgeschoss
Type - Material: IfcSurfaceStyle #9317
Type - Andere - Kategorie: Allgemeines Modell; Familienname: Stahlrohr nach DIN 2448 343104
Type - ID-Daten - Typname: Stahlrohr nach DIN 2448 343104
Type - IFC-Parameter - Typ in IFC-Datei exportieren: Vorgabe
Description: Stahlrohr nach DIN 2448
Pset_DistributionFlowElementCommon - Reference: Stahlrohr nach DIN 2448 343104; sets with these values: 2
Andere - Typ: Stahlrohr nach DIN 2448 343104; Familie: Stahlrohr nach DIN 2448 343104; Familie und Typ: Stahlrohr nach DIN 2448 343104: Stahlrohr nach DIN 2448 343104; Typ-ID: 2536216
Abhängigkeiten - Höhe von Ebene: 0 m; Verschieben mit umliegenden Elementen: no
Bemaßungen - Fläche: 0.0886938 m2; Volumen: 0.00889686 m3
IFC-Parameter - In IFC-Datei exportieren: Nach Typ; Pset MEP.Tech-Insulation thickness (mm): 100; Pset MEP.Geom-DN: 150; In IFC exportieren als: ifcflowsegment; NameOverride: Stahlrohr nach DIN 2448; IfcPresentationLayer: 0-TFT-H_Vorlauf; ObjectTypeOverride: Stahlrohr nach DIN 2448; Pset MEP.Name: Stahlrohr nach DIN 2448; IfcDescription: Stahlrohr nach DIN 2448; Pset MEP.Geom-Outer Ø (mm): 168.3; Pset MEP.Tech-Material: Stahlrohr nach DIN 2448; Pset MEP.Geom-Length (mm): 105.762
Phasen - Phase erstellt: Phase 01

# IfcFlowSegment: Stahlrohr nach DIN 2448 343408:Stahlrohr nach DIN 2448 343408, Stahlrohr nach DIN 2448
In: Erdgeschoss
Type - Material: IfcSurfaceStyle #9317
Type - Andere - Kategorie: Allgemeines Modell; Familienname: Stahlrohr nach DIN 2448 343408
Type - ID-Daten - Typname: Stahlrohr nach DIN 2448 343408
Type - IFC-Parameter - Typ in IFC-Datei exportieren: Vorgabe
Description: Stahlrohr nach DIN 2448
Pset_DistributionFlowElementCommon - Reference: Stahlrohr nach DIN 2448 343408; sets with these values: 2
Andere - Typ: Stahlrohr nach DIN 2448 343408; Familie: Stahlrohr nach DIN 2448 343408; Familie und Typ: Stahlrohr nach DIN 2448 343408: Stahlrohr nach DIN 2448 343408; Typ-ID: 2536230
Abhängigkeiten - Höhe von Ebene: 0 m; Verschieben mit umliegenden Elementen: no
Bemaßungen - Fläche: 0.0886938 m2; Volumen: 0.00889686 m3
IFC-Parameter - In IFC-Datei exportieren: Nach Typ; Pset MEP.Tech-Insulation thickness (mm): 100; Pset MEP.Geom-DN: 150; In IFC exportieren als: ifcflowsegment; NameOverride: Stahlrohr nach DIN 2448; IfcPresentationLayer: 0-TFT-H_Vorlauf; ObjectTypeOverride: Stahlrohr nach DIN 2448; Pset MEP.Name: Stahlrohr nach DIN 2448; IfcDescription: Stahlrohr nach DIN 2448; Pset MEP.Geom-Outer Ø (mm): 168.3; Pset MEP.Tech-Material: Stahlrohr nach DIN 2448; Pset MEP.Geom-Length (mm): 105.762
Phasen - Phase erstellt: Phase 01

# IfcFlowSegment: Stahlrohr nach DIN 2448 343523:Stahlrohr nach DIN 2448 343523, Stahlrohr nach DIN 2448
In: Erdgeschoss
Type - Material: IfcSurfaceStyle #9317
Type - Andere - Kategorie: Allgemeines Modell; Familienname: Stahlrohr nach DIN 2448 343523
Type - ID-Daten - Typname: Stahlrohr nach DIN 2448 343523
Type - IFC-Parameter - Typ in IFC-Datei exportieren: Vorgabe
Description: Stahlrohr nach DIN 2448
Pset_DistributionFlowElementCommon - Reference: Stahlrohr nach DIN 2448 343523; sets with these values: 2
Andere - Typ: Stahlrohr nach DIN 2448 343523; Familie: Stahlrohr nach DIN 2448 343523; Familie und Typ: Stahlrohr nach DIN 2448 343523: Stahlrohr nach DIN 2448 343523; Typ-ID: 2536265
Abhängigkeiten - Höhe von Ebene: 0 m; Verschieben mit umliegenden Elementen: no
Bemaßungen - Fläche: 1.9938 m2; Volumen: 0.229363 m3
IFC-Parameter - In IFC-Datei exportieren: Nach Typ; Pset MEP.Geom-DN: 200; Pset MEP.Tech-Insulation thickness (mm): 100; In IFC exportieren als: ifcflowsegment; NameOverride: Stahlrohr nach DIN 2448; IfcPresentationLayer: 0-TFT-H_Vorlauf; ObjectTypeOverride: Stahlrohr nach DIN 2448; Pset MEP.Name: Stahlrohr nach DIN 2448; IfcDescription: Stahlrohr nach DIN 2448; Pset MEP.Geom-Outer Ø (mm): 219.1; Pset MEP.Tech-Material: Stahlrohr nach DIN 2448; Pset MEP.Geom-Length (mm): 1999
Phasen - Phase erstellt: Phase 01

# IfcFlowSegment: Stahlrohr nach DIN 2448 343804:Stahlrohr nach DIN 2448 343804, Stahlrohr nach DIN 2448
In: Erdgeschoss
Type - Material: IfcSurfaceStyle #9317
Type - Andere - Kategorie: Allgemeines Modell; Familienname: Stahlrohr nach DIN 2448 343804
Type - ID-Daten - Typname: Stahlrohr nach DIN 2448 343804
Type - IFC-Parameter - Typ in IFC-Datei exportieren: Vorgabe
Description: Stahlrohr nach DIN 2448
Pset_DistributionFlowElementCommon - Reference: Stahlrohr nach DIN 2448 343804; sets with these values: 2
Andere - Typ: Stahlrohr nach DIN 2448 343804; Familie: Stahlrohr nach DIN 2448 343804; Familie und Typ: Stahlrohr nach DIN 2448 343804: Stahlrohr nach DIN 2448 343804; Typ-ID: 2536272
Abhängigkeiten - Höhe von Ebene: 0 m; Verschieben mit umliegenden Elementen: no
Bemaßungen - Fläche: 0.210995 m2; Volumen: 0.0211649 m3
IFC-Parameter - In IFC-Datei exportieren: Nach Typ; Pset MEP.Tech-Insulation thickness (mm): 100; Pset MEP.Geom-DN: 150; In IFC exportieren als: ifcflowsegment; NameOverride: Stahlrohr nach DIN 2448; IfcPresentationLayer: 0-TFT-H_Vorlauf; ObjectTypeOverride: Stahlrohr nach DIN 2448; Pset MEP.Name: Stahlrohr nach DIN 2448; IfcDescription: Stahlrohr nach DIN 2448; Pset MEP.Geom-Outer Ø (mm): 168.3; Pset MEP.Tech-Material: Stahlrohr nach DIN 2448; Pset MEP.Geom-Length (mm): 251.599
Phasen - Phase erstellt: Phase 01

# IfcFlowSegment: Stahlrohr nach DIN 2448 344085:Stahlrohr nach DIN 2448 344085, Stahlrohr nach DIN 2448
In: Erdgeschoss
Type - Material: IfcSurfaceStyle #9317
Type - Andere - Kategorie: Allgemeines Modell; Familienname: Stahlrohr nach DIN 2448 344085
Type - ID-Daten - Typname: Stahlrohr nach DIN 2448 344085
Type - IFC-Parameter - Typ in IFC-Datei exportieren: Vorgabe
Description: Stahlrohr nach DIN 2448
Pset_DistributionFlowElementCommon - Reference: Stahlrohr nach DIN 2448 344085; sets with these values: 2
Andere - Typ: Stahlrohr nach DIN 2448 344085; Familie: Stahlrohr nach DIN 2448 344085; Familie und Typ: Stahlrohr nach DIN 2448 344085: Stahlrohr nach DIN 2448 344085; Typ-ID: 2536279
Abhängigkeiten - Höhe von Ebene: 0 m; Verschieben mit umliegenden Elementen: no
Bemaßungen - Fläche: 0.210995 m2; Volumen: 0.0211649 m3
IFC-Parameter - In IFC-Datei exportieren: Nach Typ; Pset MEP.Tech-Insulation thickness (mm): 100; Pset MEP.Geom-DN: 150; In IFC exportieren als: ifcflowsegment; NameOverride: Stahlrohr nach DIN 2448; IfcPresentationLayer: 0-TFT-H_Vorlauf; ObjectTypeOverride: Stahlrohr nach DIN 2448; Pset MEP.Name: Stahlrohr nach DIN 2448; IfcDescription: Stahlrohr nach DIN 2448; Pset MEP.Geom-Outer Ø (mm): 168.3; Pset MEP.Tech-Material: Stahlrohr nach DIN 2448; Pset MEP.Geom-Length (mm): 251.599
Phasen - Phase erstellt: Phase 01

# IfcFlowSegment: Stahlrohr nach DIN 2448 344108:Stahlrohr nach DIN 2448 344108, Stahlrohr nach DIN 2448
In: Erdgeschoss
Type - Material: IfcSurfaceStyle #9317
Type - Andere - Kategorie: Allgemeines Modell; Familienname: Stahlrohr nach DIN 2448 344108
Type - ID-Daten - Typname: Stahlrohr nach DIN 2448 344108
Type - IFC-Parameter - Typ in IFC-Datei exportieren: Vorgabe
Description: Stahlrohr nach DIN 2448
Pset_DistributionFlowElementCommon - Reference: Stahlrohr nach DIN 2448 344108; sets with these values: 2
Andere - Typ: Stahlrohr nach DIN 2448 344108; Familie: Stahlrohr nach DIN 2448 344108; Familie und Typ: Stahlrohr nach DIN 2448 344108: Stahlrohr nach DIN 2448 344108; Typ-ID: 2536286
Abhängigkeiten - Höhe von Ebene: 0 m; Verschieben mit umliegenden Elementen: no
Bemaßungen - Fläche: 0.796074 m2; Volumen: 0.0915788 m3
IFC-Parameter - In IFC-Datei exportieren: Nach Typ; Pset MEP.Geom-DN: 200; Pset MEP.Tech-Insulation thickness (mm): 100; In IFC exportieren als: ifcflowsegment; NameOverride: Stahlrohr nach DIN 2448; IfcPresentationLayer: 0-TFT-H_Vorlauf; ObjectTypeOverride: Stahlrohr nach DIN 2448; Pset MEP.Name: Stahlrohr nach DIN 2448; IfcDescription: Stahlrohr nach DIN 2448; Pset MEP.Geom-Outer Ø (mm): 219.1; Pset MEP.Tech-Material: Stahlrohr nach DIN 2448; Pset MEP.Geom-Length (mm): 798.148
Phasen - Phase erstellt: Phase 01

# IfcFlowSegment: Stahlrohr nach DIN 2448 344389:Stahlrohr nach DIN 2448 344389, Stahlrohr nach DIN 2448
In: Erdgeschoss
Type - Material: IfcSurfaceStyle #9317
Type - Andere - Kategorie: Allgemeines Modell; Familienname: Stahlrohr nach DIN 2448 344389
Type - ID-Daten - Typname: Stahlrohr nach DIN 2448 344389
Type - IFC-Parameter - Typ in IFC-Datei exportieren: Vorgabe
Description: Stahlrohr nach DIN 2448
Pset_DistributionFlowElementCommon - Reference: Stahlrohr nach DIN 2448 344389; sets with these values: 2
Andere - Typ: Stahlrohr nach DIN 2448 344389; Familie: Stahlrohr nach DIN 2448 344389; Familie und Typ: Stahlrohr nach DIN 2448 344389: Stahlrohr nach DIN 2448 344389; Typ-ID: 2536293
Abhängigkeiten - Höhe von Ebene: 0 m; Verschieben mit umliegenden Elementen: no
Bemaßungen - Fläche: 0.206529 m2; Volumen: 0.0163959 m3
IFC-Parameter - In IFC-Datei exportieren: Nach Typ; Pset MEP.Tech-Insulation thickness (mm): 100; Pset MEP.Geom-DN: 80; In IFC exportieren als: ifcflowsegment; NameOverride: Stahlrohr nach DIN 2448; IfcPresentationLayer: 0-TFT-H_Vorlauf; ObjectTypeOverride: Stahlrohr nach DIN 2448; Pset MEP.Name: Stahlrohr nach DIN 2448; IfcDescription: Stahlrohr nach DIN 2448; Pset MEP.Geom-Outer Ø (mm): 88.9; Pset MEP.Tech-Material: Stahlrohr nach DIN 2448; Pset MEP.Geom-Length (mm): 349.789
Phasen - Phase erstellt: Phase 01

# IfcFlowSegment: Stahlrohr nach DIN 2448 345345:Stahlrohr nach DIN 2448 345345, Stahlrohr nach DIN 2448
In: Erdgeschoss
Type - Material: IfcSurfaceStyle #9317
Type - Andere - Kategorie: Allgemeines Modell; Familienname: Stahlrohr nach DIN 2448 345345
Type - ID-Daten - Typname: Stahlrohr nach DIN 2448 345345
Type - IFC-Parameter - Typ in IFC-Datei exportieren: Vorgabe
Description: Stahlrohr nach DIN 2448
Pset_DistributionFlowElementCommon - Reference: Stahlrohr nach DIN 2448 345345; sets with these values: 2
Andere - Typ: Stahlrohr nach DIN 2448 345345; Familie: Stahlrohr nach DIN 2448 345345; Familie und Typ: Stahlrohr nach DIN 2448 345345: Stahlrohr nach DIN 2448 345345; Typ-ID: 2536328
Abhängigkeiten - Höhe von Ebene: 0 m; Verschieben mit umliegenden Elementen: no
Bemaßungen - Fläche: 5.65937 m2; Volumen: 0.651043 m3
IFC-Parameter - In IFC-Datei exportieren: Nach Typ; Pset MEP.Geom-DN: 200; Pset MEP.Tech-Insulation thickness (mm): 100; In IFC exportieren als: ifcflowsegment; NameOverride: Stahlrohr nach DIN 2448; IfcPresentationLayer: 0-TFT-H_Vorlauf; ObjectTypeOverride: Stahlrohr nach DIN 2448; Pset MEP.Name: Stahlrohr nach DIN 2448; IfcDescription: Stahlrohr nach DIN 2448; Pset MEP.Geom-Outer Ø (mm): 219.1; Pset MEP.Tech-Material: Stahlrohr nach DIN 2448; Pset MEP.Geom-Length (mm): 5674.12
Phasen - Phase erstellt: Phase 01

# IfcFlowSegment: Stahlrohr nach DIN 2448 346259:Stahlrohr nach DIN 2448 346259, Stahlrohr nach DIN 2448
In: Erdgeschoss
Type - Material: IfcSurfaceStyle #9317
Type - Andere - Kategorie: Allgemeines Modell; Familienname: Stahlrohr nach DIN 2448 346259
Type - ID-Daten - Typname: Stahlrohr nach DIN 2448 346259
Type - IFC-Parameter - Typ in IFC-Datei exportieren: Vorgabe
Description: Stahlrohr nach DIN 2448
Pset_DistributionFlowElementCommon - Reference: Stahlrohr nach DIN 2448 346259; sets with these values: 2
Andere - Typ: Stahlrohr nach DIN 2448 346259; Familie: Stahlrohr nach DIN 2448 346259; Familie und Typ: Stahlrohr nach DIN 2448 346259: Stahlrohr nach DIN 2448 346259; Typ-ID: 2536349
Abhängigkeiten - Höhe von Ebene: 0 m; Verschieben mit umliegenden Elementen: no
Bemaßungen - Fläche: 0.782462 m2; Volumen: 0.0621181 m3
IFC-Parameter - In IFC-Datei exportieren: Nach Typ; Pset MEP.Tech-Insulation thickness (mm): 100; Pset MEP.Geom-DN: 80; In IFC exportieren als: ifcflowsegment; NameOverride: Stahlrohr nach DIN 2448; IfcPresentationLayer: 0-TFT-H_Vorlauf; ObjectTypeOverride: Stahlrohr nach DIN 2448; Pset MEP.Name: Stahlrohr nach DIN 2448; IfcDescription: Stahlrohr nach DIN 2448; Pset MEP.Geom-Outer Ø (mm): 88.9; Pset MEP.Tech-Material: Stahlrohr nach DIN 2448; Pset MEP.Geom-Length (mm): 1325.22
Phasen - Phase erstellt: Phase 01

# IfcFlowSegment: Stahlrohr nach DIN 2448 346540:Stahlrohr nach DIN 2448 346540, Stahlrohr nach DIN 2448
In: Erdgeschoss
Type - Material: IfcSurfaceStyle #9317
Type - Andere - Kategorie: Allgemeines Modell; Familienname: Stahlrohr nach DIN 2448 346540
Type - ID-Daten - Typname: Stahlrohr nach DIN 2448 346540
Type - IFC-Parameter - Typ in IFC-Datei exportieren: Vorgabe
Description: Stahlrohr nach DIN 2448
Pset_DistributionFlowElementCommon - Reference: Stahlrohr nach DIN 2448 346540; sets with these values: 2
Andere - Typ: Stahlrohr nach DIN 2448 346540; Familie: Stahlrohr nach DIN 2448 346540; Familie und Typ: Stahlrohr nach DIN 2448 346540: Stahlrohr nach DIN 2448 346540; Typ-ID: 2536356
Abhängigkeiten - Höhe von Ebene: 0 m; Verschieben mit umliegenden Elementen: no
Bemaßungen - Fläche: 0.666081 m2; Volumen: 0.0528789 m3
IFC-Parameter - In IFC-Datei exportieren: Nach Typ; Pset MEP.Tech-Insulation thickness (mm): 100; Pset MEP.Geom-DN: 80; In IFC exportieren als: ifcflowsegment; NameOverride: Stahlrohr nach DIN 2448; IfcPresentationLayer: 0-TFT-H_Vorlauf; ObjectTypeOverride: Stahlrohr nach DIN 2448; Pset MEP.Name: Stahlrohr nach DIN 2448; IfcDescription: Stahlrohr nach DIN 2448; Pset MEP.Geom-Outer Ø (mm): 88.9; Pset MEP.Tech-Material: Stahlrohr nach DIN 2448; Pset MEP.Geom-Length (mm): 1128.11
Phasen - Phase erstellt: Phase 01

# IfcFlowSegment: Stahlrohr nach DIN 2448 346850:Stahlrohr nach DIN 2448 346850, Stahlrohr nach DIN 2448
In: Erdgeschoss
Type - Material: IfcSurfaceStyle #9317
Type - Andere - Kategorie: Allgemeines Modell; Familienname: Stahlrohr nach DIN 2448 346850
Type - ID-Daten - Typname: Stahlrohr nach DIN 2448 346850
Type - IFC-Parameter - Typ in IFC-Datei exportieren: Vorgabe
Description: Stahlrohr nach DIN 2448
Pset_DistributionFlowElementCommon - Reference: Stahlrohr nach DIN 2448 346850; sets with these values: 2
Andere - Typ: Stahlrohr nach DIN 2448 346850; Familie: Stahlrohr nach DIN 2448 346850; Familie und Typ: Stahlrohr nach DIN 2448 346850: Stahlrohr nach DIN 2448 346850; Typ-ID: 2536370
Abhängigkeiten - Höhe von Ebene: 0 m; Verschieben mit umliegenden Elementen: no
Bemaßungen - Fläche: 1.84474 m2; Volumen: 0.212216 m3
IFC-Parameter - In IFC-Datei exportieren: Nach Typ; Pset MEP.Geom-DN: 200; Pset MEP.Tech-Insulation thickness (mm): 100; In IFC exportieren als: ifcflowsegment; NameOverride: Stahlrohr nach DIN 2448; IfcPresentationLayer: 0-TFT-H_Vorlauf; ObjectTypeOverride: Stahlrohr nach DIN 2448; Pset MEP.Name: Stahlrohr nach DIN 2448; IfcDescription: Stahlrohr nach DIN 2448; Pset MEP.Geom-Outer Ø (mm): 219.1; Pset MEP.Tech-Material: Stahlrohr nach DIN 2448; Pset MEP.Geom-Length (mm): 1849.55
Phasen - Phase erstellt: Phase 01

# IfcFlowSegment: Stahlrohr nach DIN 2448 347160:Stahlrohr nach DIN 2448 347160, Stahlrohr nach DIN 2448
In: 1. Obergeschoss
Type - Material: IfcSurfaceStyle #1741
Type - Andere - Kategorie: Allgemeines Modell; Familienname: Stahlrohr nach DIN 2448 347160
Type - ID-Daten - Typname: Stahlrohr nach DIN 2448 347160
Type - IFC-Parameter - Typ in IFC-Datei exportieren: Vorgabe
Description: Stahlrohr nach DIN 2448
Pset_DistributionFlowElementCommon - Reference: Stahlrohr nach DIN 2448 347160; sets with these values: 2
Andere - Typ: Stahlrohr nach DIN 2448 347160; Familie: Stahlrohr nach DIN 2448 347160; Familie und Typ: Stahlrohr nach DIN 2448 347160: Stahlrohr nach DIN 2448 347160; Typ-ID: 2536384
Abhängigkeiten - Höhe von Ebene: 0 m; Verschieben mit umliegenden Elementen: no
Bemaßungen - Fläche: 0.114104 m2; Volumen: 0.00630398 m3
IFC-Parameter - In IFC-Datei exportieren: Nach Typ; Pset MEP.Tech-Insulation thickness (mm): 100; Pset MEP.Geom-DN: 150; In IFC exportieren als: ifcflowsegment; NameOverride: Stahlrohr nach DIN 2448; IfcPresentationLayer: 0-TFT-H_Ruecklauf; ObjectTypeOverride: Stahlrohr nach DIN 2448; Pset MEP.Name: Stahlrohr nach DIN 2448; IfcDescription: Stahlrohr nach DIN 2448; Pset MEP.Geom-Outer Ø (mm): 168.3; Pset MEP.Tech-Material: Stahlrohr nach DIN 2448; Pset MEP.Geom-Length (mm): 433.814
Phasen - Phase erstellt: Phase 01

# IfcFlowSegment: Stahlrohr nach DIN 2448 347315:Stahlrohr nach DIN 2448 347315, Stahlrohr nach DIN 2448
In: 1. Obergeschoss
Type - Material: IfcSurfaceStyle #1741
Type - Andere - Kategorie: Allgemeines Modell; Familienname: Stahlrohr nach DIN 2448 347315
Type - ID-Daten - Typname: Stahlrohr nach DIN 2448 347315
Type - IFC-Parameter - Typ in IFC-Datei exportieren: Vorgabe
Description: Stahlrohr nach DIN 2448
Pset_DistributionFlowElementCommon - Reference: Stahlrohr nach DIN 2448 347315; sets with these values: 2
Andere - Typ: Stahlrohr nach DIN 2448 347315; Familie: Stahlrohr nach DIN 2448 347315; Familie und Typ: Stahlrohr nach DIN 2448 347315: Stahlrohr nach DIN 2448 347315; Typ-ID: 2536391
Abhängigkeiten - Höhe von Ebene: 0 m; Verschieben mit umliegenden Elementen: no
Bemaßungen - Fläche: 0.414959 m2; Volumen: 0.0416245 m3
IFC-Parameter - In IFC-Datei exportieren: Nach Typ; Pset MEP.Tech-Insulation thickness (mm): 100; Pset MEP.Geom-DN: 150; In IFC exportieren als: ifcflowsegment; NameOverride: Stahlrohr nach DIN 2448; IfcPresentationLayer: 0-TFT-H_Ruecklauf; ObjectTypeOverride: Stahlrohr nach DIN 2448; Pset MEP.Name: Stahlrohr nach DIN 2448; IfcDescription: Stahlrohr nach DIN 2448; Pset MEP.Geom-Outer Ø (mm): 168.3; Pset MEP.Tech-Material: Stahlrohr nach DIN 2448; Pset MEP.Geom-Length (mm): 494.814
Phasen - Phase erstellt: Phase 01

# IfcFlowSegment: Stahlrohr nach DIN 2448 347596:Stahlrohr nach DIN 2448 347596, Stahlrohr nach DIN 2448
In: 1. Obergeschoss
Type - Material: IfcSurfaceStyle #9317
Type - Andere - Kategorie: Allgemeines Modell; Familienname: Stahlrohr nach DIN 2448 347596
Type - ID-Daten - Typname: Stahlrohr nach DIN 2448 347596
Type - IFC-Parameter - Typ in IFC-Datei exportieren: Vorgabe
Description: Stahlrohr nach DIN 2448
Pset_DistributionFlowElementCommon - Reference: Stahlrohr nach DIN 2448 347596; sets with these values: 2
Andere - Typ: Stahlrohr nach DIN 2448 347596; Familie: Stahlrohr nach DIN 2448 347596; Familie und Typ: Stahlrohr nach DIN 2448 347596: Stahlrohr nach DIN 2448 347596; Typ-ID: 2536398
Abhängigkeiten - Höhe von Ebene: 0 m; Verschieben mit umliegenden Elementen: no
Bemaßungen - Fläche: 0.591549 m2; Volumen: 0.0680507 m3
IFC-Parameter - In IFC-Datei exportieren: Nach Typ; Pset MEP.Geom-DN: 200; Pset MEP.Tech-Insulation thickness (mm): 100; In IFC exportieren als: ifcflowsegment; NameOverride: Stahlrohr nach DIN 2448; IfcPresentationLayer: 0-TFT-H_Vorlauf; ObjectTypeOverride: Stahlrohr nach DIN 2448; Pset MEP.Name: Stahlrohr nach DIN 2448; IfcDescription: Stahlrohr nach DIN 2448; Pset MEP.Geom-Outer Ø (mm): 219.1; Pset MEP.Tech-Material: Stahlrohr nach DIN 2448; Pset MEP.Geom-Length (mm): 593.091
Phasen - Phase erstellt: Phase 01

# IfcFlowSegment: Stahlrohr nach DIN 2448 347642:Stahlrohr nach DIN 2448 347642, Stahlrohr nach DIN 2448
In: Erdgeschoss
Type - Material: IfcSurfaceStyle #1741
Type - Andere - Kategorie: Allgemeines Modell; Familienname: Stahlrohr nach DIN 2448 347642
Type - ID-Daten - Typname: Stahlrohr nach DIN 2448 347642
Type - IFC-Parameter - Typ in IFC-Datei exportieren: Vorgabe
Description: Stahlrohr nach DIN 2448
Pset_DistributionFlowElementCommon - Reference: Stahlrohr nach DIN 2448 347642; sets with these values: 2
Andere - Typ: Stahlrohr nach DIN 2448 347642; Familie: Stahlrohr nach DIN 2448 347642; Familie und Typ: Stahlrohr nach DIN 2448 347642: Stahlrohr nach DIN 2448 347642; Typ-ID: 2536412
Abhängigkeiten - Höhe von Ebene: 0 m; Verschieben mit umliegenden Elementen: no
Bemaßungen - Fläche: 0.101425 m2; Volumen: 0.00775387 m3
IFC-Parameter - In IFC-Datei exportieren: Nach Typ; Pset MEP.Tech-Insulation thickness (mm): 100; Pset MEP.Geom-DN: 65; In IFC exportieren als: ifcflowsegment; NameOverride: Stahlrohr nach DIN 2448; IfcPresentationLayer: 0-TFT-H_Ruecklauf; ObjectTypeOverride: Stahlrohr nach DIN 2448; Pset MEP.Name: Stahlrohr nach DIN 2448; IfcDescription: Stahlrohr nach DIN 2448; Pset MEP.Geom-Outer Ø (mm): 76.1; Pset MEP.Tech-Material: Stahlrohr nach DIN 2448; Pset MEP.Geom-Length (mm): 184.265
Phasen - Phase erstellt: Phase 01

# IfcFlowSegment: Stahlrohr nach DIN 2448 347991:Stahlrohr nach DIN 2448 347991, Stahlrohr nach DIN 2448
In: Erdgeschoss
Type - Material: IfcSurfaceStyle #1741
Type - Andere - Kategorie: Allgemeines Modell; Familienname: Stahlrohr nach DIN 2448 347991
Type - ID-Daten - Typname: Stahlrohr nach DIN 2448 347991
Type - IFC-Parameter - Typ in IFC-Datei exportieren: Vorgabe
Description: Stahlrohr nach DIN 2448
Pset_DistributionFlowElementCommon - Reference: Stahlrohr nach DIN 2448 347991; sets with these values: 2
Andere - Typ: Stahlrohr nach DIN 2448 347991; Familie: Stahlrohr nach DIN 2448 347991; Familie und Typ: Stahlrohr nach DIN 2448 347991: Stahlrohr nach DIN 2448 347991; Typ-ID: 2536433
Abhängigkeiten - Höhe von Ebene: 0 m; Verschieben mit umliegenden Elementen: no
Bemaßungen - Fläche: 1.50148 m2; Volumen: 0.1192 m3
IFC-Parameter - In IFC-Datei exportieren: Nach Typ; Pset MEP.Tech-Insulation thickness (mm): 100; Pset MEP.Geom-DN: 80; In IFC exportieren als: ifcflowsegment; NameOverride: Stahlrohr nach DIN 2448; IfcPresentationLayer: 0-TFT-H_Ruecklauf; ObjectTypeOverride: Stahlrohr nach DIN 2448; Pset MEP.Name: Stahlrohr nach DIN 2448; IfcDescription: Stahlrohr nach DIN 2448; Pset MEP.Geom-Outer Ø (mm): 88.9; Pset MEP.Tech-Material: Stahlrohr nach DIN 2448; Pset MEP.Geom-Length (mm): 2543
Phasen - Phase erstellt: Phase 01

# IfcFlowSegment: Stahlrohr nach DIN 2448 349285:Stahlrohr nach DIN 2448 349285, Stahlrohr nach DIN 2448
In: Erdgeschoss
Type - Material: IfcSurfaceStyle #1741
Type - Andere - Kategorie: Allgemeines Modell; Familienname: Stahlrohr nach DIN 2448 349285
Type - ID-Daten - Typname: Stahlrohr nach DIN 2448 349285
Type - IFC-Parameter - Typ in IFC-Datei exportieren: Vorgabe
Description: Stahlrohr nach DIN 2448
Pset_DistributionFlowElementCommon - Reference: Stahlrohr nach DIN 2448 349285; sets with these values: 2
Andere - Typ: Stahlrohr nach DIN 2448 349285; Familie: Stahlrohr nach DIN 2448 349285; Familie und Typ: Stahlrohr nach DIN 2448 349285: Stahlrohr nach DIN 2448 349285; Typ-ID: 2536454
Abhängigkeiten - Höhe von Ebene: 0 m; Verschieben mit umliegenden Elementen: no
Bemaßungen - Fläche: 0.153044 m2; Volumen: 0.0121498 m3
IFC-Parameter - In IFC-Datei exportieren: Nach Typ; Pset MEP.Tech-Insulation thickness (mm): 100; Pset MEP.Geom-DN: 80; In IFC exportieren als: ifcflowsegment; NameOverride: Stahlrohr nach DIN 2448; IfcPresentationLayer: 0-TFT-H_Ruecklauf; ObjectTypeOverride: Stahlrohr nach DIN 2448; Pset MEP.Name: Stahlrohr nach DIN 2448; IfcDescription: Stahlrohr nach DIN 2448; Pset MEP.Geom-Outer Ø (mm): 88.9; Pset MEP.Tech-Material: Stahlrohr nach DIN 2448; Pset MEP.Geom-Length (mm): 259.203
Phasen - Phase erstellt: Phase 01

# IfcFlowSegment: Stahlrohr nach DIN 2448 349589:Stahlrohr nach DIN 2448 349589, Stahlrohr nach DIN 2448
In: 1. Obergeschoss
Type - Material: IfcSurfaceStyle #1741
Type - Andere - Kategorie: Allgemeines Modell; Familienname: Stahlrohr nach DIN 2448 349589
Type - ID-Daten - Typname: Stahlrohr nach DIN 2448 349589
Type - IFC-Parameter - Typ in IFC-Datei exportieren: Vorgabe
Description: Stahlrohr nach DIN 2448
Pset_DistributionFlowElementCommon - Reference: Stahlrohr nach DIN 2448 349589; sets with these values: 2
Andere - Typ: Stahlrohr nach DIN 2448 349589; Familie: Stahlrohr nach DIN 2448 349589; Familie und Typ: Stahlrohr nach DIN 2448 349589: Stahlrohr nach DIN 2448 349589; Typ-ID: 2536468
Abhängigkeiten - Höhe von Ebene: 0 m; Verschieben mit umliegenden Elementen: no
Bemaßungen - Fläche: 0.961323 m2; Volumen: 0.110589 m3
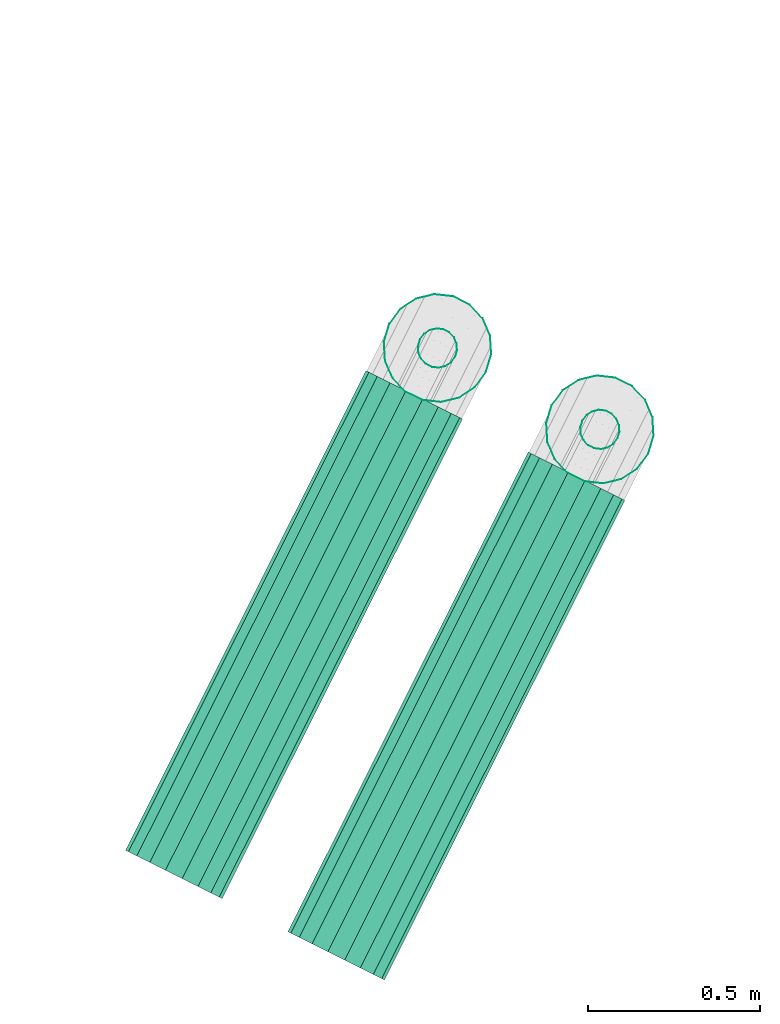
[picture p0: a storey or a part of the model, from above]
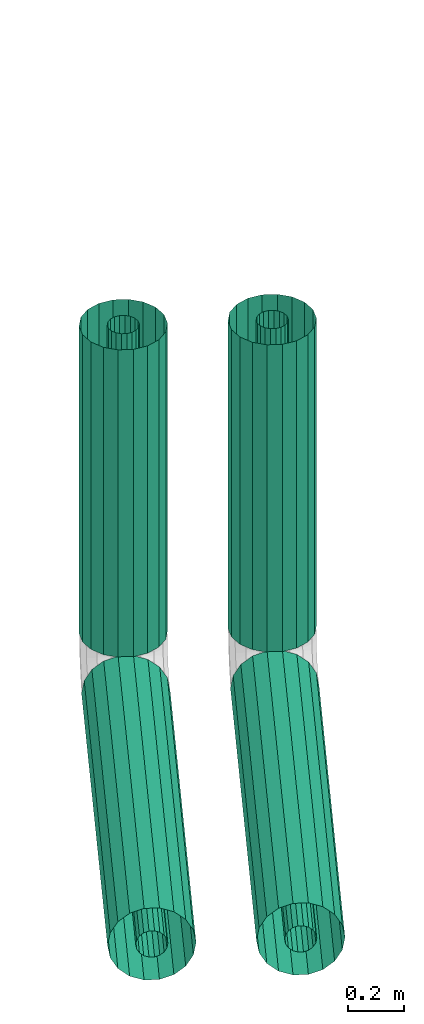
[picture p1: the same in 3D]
Properties of the parts of a building model (IFC2X3), part 20 of 23

# IfcFlowSegment: Stahlrohr nach DIN 2448 349589:Stahlrohr nach DIN 2448 349589, Stahlrohr nach DIN 2448
IFC-Parameter - In IFC-Datei exportieren: Nach Typ; Pset MEP.Geom-DN: 200; Pset MEP.Tech-Insulation thickness (mm): 100; In IFC exportieren als: ifcflowsegment; NameOverride: Stahlrohr nach DIN 2448; IfcPresentationLayer: 0-TFT-H_Ruecklauf; ObjectTypeOverride: Stahlrohr nach DIN 2448; Pset MEP.Name: Stahlrohr nach DIN 2448; IfcDescription: Stahlrohr nach DIN 2448; Pset MEP.Geom-Outer Ø (mm): 219.1; Pset MEP.Tech-Material: Stahlrohr nach DIN 2448; Pset MEP.Geom-Length (mm): 963.829
Phasen - Phase erstellt: Phase 01

# IfcFlowSegment: Stahlrohr nach DIN 2448 349870:Stahlrohr nach DIN 2448 349870, Stahlrohr nach DIN 2448
In: 1. Obergeschoss
Type - Material: IfcSurfaceStyle #1741
Type - Andere - Kategorie: Allgemeines Modell; Familienname: Stahlrohr nach DIN 2448 349870
Type - ID-Daten - Typname: Stahlrohr nach DIN 2448 349870
Type - IFC-Parameter - Typ in IFC-Datei exportieren: Vorgabe
Description: Stahlrohr nach DIN 2448
Pset_DistributionFlowElementCommon - Reference: Stahlrohr nach DIN 2448 349870; sets with these values: 2
Andere - Typ: Stahlrohr nach DIN 2448 349870; Familie: Stahlrohr nach DIN 2448 349870; Familie und Typ: Stahlrohr nach DIN 2448 349870: Stahlrohr nach DIN 2448 349870; Typ-ID: 2536475
Abhängigkeiten - Höhe von Ebene: 0 m; Verschieben mit umliegenden Elementen: no
Bemaßungen - Fläche: 0.0295665 m2; Volumen: 0.00340127 m3
IFC-Parameter - In IFC-Datei exportieren: Nach Typ; Pset MEP.Geom-DN: 200; Pset MEP.Tech-Insulation thickness (mm): 100; In IFC exportieren als: ifcflowsegment; NameOverride: Stahlrohr nach DIN 2448; IfcPresentationLayer: 0-TFT-H_Ruecklauf; ObjectTypeOverride: Stahlrohr nach DIN 2448; Pset MEP.Name: Stahlrohr nach DIN 2448; IfcDescription: Stahlrohr nach DIN 2448; Pset MEP.Geom-Outer Ø (mm): 219.1; Pset MEP.Tech-Material: Stahlrohr nach DIN 2448; Pset MEP.Geom-Length (mm): 29.6436
Phasen - Phase erstellt: Phase 01

# IfcFlowSegment: Stahlrohr nach DIN 2448 350207:Stahlrohr nach DIN 2448 350207, Stahlrohr nach DIN 2448
In: Erdgeschoss
Type - Material: IfcSurfaceStyle #1741
Type - Andere - Kategorie: Allgemeines Modell; Familienname: Stahlrohr nach DIN 2448 350207
Type - ID-Daten - Typname: Stahlrohr nach DIN 2448 350207
Type - IFC-Parameter - Typ in IFC-Datei exportieren: Vorgabe
Description: Stahlrohr nach DIN 2448
Pset_DistributionFlowElementCommon - Reference: Stahlrohr nach DIN 2448 350207; sets with these values: 2
Andere - Typ: Stahlrohr nach DIN 2448 350207; Familie: Stahlrohr nach DIN 2448 350207; Familie und Typ: Stahlrohr nach DIN 2448 350207: Stahlrohr nach DIN 2448 350207; Typ-ID: 2536496
Abhängigkeiten - Höhe von Ebene: 0 m; Verschieben mit umliegenden Elementen: no
Bemaßungen - Fläche: 0.157449 m2; Volumen: 0.0181127 m3
IFC-Parameter - In IFC-Datei exportieren: Nach Typ; Pset MEP.Geom-DN: 200; Pset MEP.Tech-Insulation thickness (mm): 100; In IFC exportieren als: ifcflowsegment; NameOverride: Stahlrohr nach DIN 2448; IfcPresentationLayer: 0-TFT-H_Ruecklauf; ObjectTypeOverride: Stahlrohr nach DIN 2448; Pset MEP.Name: Stahlrohr nach DIN 2448; IfcDescription: Stahlrohr nach DIN 2448; Pset MEP.Geom-Outer Ø (mm): 219.1; Pset MEP.Tech-Material: Stahlrohr nach DIN 2448; Pset MEP.Geom-Length (mm): 157.86
Phasen - Phase erstellt: Phase 01

# IfcFlowSegment: Stahlrohr nach DIN 2448 350546:Stahlrohr nach DIN 2448 350546, Stahlrohr nach DIN 2448
In: Erdgeschoss
Type - Material: IfcSurfaceStyle #1741
Type - Andere - Kategorie: Allgemeines Modell; Familienname: Stahlrohr nach DIN 2448 350546
Type - ID-Daten - Typname: Stahlrohr nach DIN 2448 350546
Type - IFC-Parameter - Typ in IFC-Datei exportieren: Vorgabe
Description: Stahlrohr nach DIN 2448
Pset_DistributionFlowElementCommon - Reference: Stahlrohr nach DIN 2448 350546; sets with these values: 2
Andere - Typ: Stahlrohr nach DIN 2448 350546; Familie: Stahlrohr nach DIN 2448 350546; Familie und Typ: Stahlrohr nach DIN 2448 350546: Stahlrohr nach DIN 2448 350546; Typ-ID: 2536517
Abhängigkeiten - Höhe von Ebene: 0 m; Verschieben mit umliegenden Elementen: no
Bemaßungen - Fläche: 3.26572 m2; Volumen: 0.375682 m3
IFC-Parameter - In IFC-Datei exportieren: Nach Typ; Pset MEP.Geom-DN: 200; Pset MEP.Tech-Insulation thickness (mm): 100; In IFC exportieren als: ifcflowsegment; NameOverride: Stahlrohr nach DIN 2448; IfcPresentationLayer: 0-TFT-H_Ruecklauf; ObjectTypeOverride: Stahlrohr nach DIN 2448; Pset MEP.Name: Stahlrohr nach DIN 2448; IfcDescription: Stahlrohr nach DIN 2448; Pset MEP.Geom-Outer Ø (mm): 219.1; Pset MEP.Tech-Material: Stahlrohr nach DIN 2448; Pset MEP.Geom-Length (mm): 3274.23
Phasen - Phase erstellt: Phase 01

# IfcFlowSegment: Stahlrohr nach DIN 2448 350827:Stahlrohr nach DIN 2448 350827, Stahlrohr nach DIN 2448
In: Erdgeschoss
Type - Material: IfcSurfaceStyle #1741
Type - Andere - Kategorie: Allgemeines Modell; Familienname: Stahlrohr nach DIN 2448 350827
Type - ID-Daten - Typname: Stahlrohr nach DIN 2448 350827
Type - IFC-Parameter - Typ in IFC-Datei exportieren: Vorgabe
Description: Stahlrohr nach DIN 2448
Pset_DistributionFlowElementCommon - Reference: Stahlrohr nach DIN 2448 350827; sets with these values: 2
Andere - Typ: Stahlrohr nach DIN 2448 350827; Familie: Stahlrohr nach DIN 2448 350827; Familie und Typ: Stahlrohr nach DIN 2448 350827: Stahlrohr nach DIN 2448 350827; Typ-ID: 2536524
Abhängigkeiten - Höhe von Ebene: 0 m; Verschieben mit umliegenden Elementen: no
Bemaßungen - Fläche: 0.235974 m2; Volumen: 0.020215 m3
IFC-Parameter - In IFC-Datei exportieren: Nach Typ; Pset MEP.Tech-Insulation thickness (mm): 100; Pset MEP.Geom-DN: 100; In IFC exportieren als: ifcflowsegment; NameOverride: Stahlrohr nach DIN 2448; IfcPresentationLayer: 0-TFT-H_Ruecklauf; ObjectTypeOverride: Stahlrohr nach DIN 2448; Pset MEP.Name: Stahlrohr nach DIN 2448; IfcDescription: Stahlrohr nach DIN 2448; Pset MEP.Geom-Outer Ø (mm): 114.3; Pset MEP.Tech-Material: Stahlrohr nach DIN 2448; Pset MEP.Geom-Length (mm): 352.289
Phasen - Phase erstellt: Phase 01

# IfcFlowSegment: Stahlrohr nach DIN 2448 351108:Stahlrohr nach DIN 2448 351108, Stahlrohr nach DIN 2448
In: Erdgeschoss
Type - Material: IfcSurfaceStyle #9317
Type - Andere - Kategorie: Allgemeines Modell; Familienname: Stahlrohr nach DIN 2448 351108
Type - ID-Daten - Typname: Stahlrohr nach DIN 2448 351108
Type - IFC-Parameter - Typ in IFC-Datei exportieren: Vorgabe
Description: Stahlrohr nach DIN 2448
Pset_DistributionFlowElementCommon - Reference: Stahlrohr nach DIN 2448 351108; sets with these values: 2
Andere - Typ: Stahlrohr nach DIN 2448 351108; Familie: Stahlrohr nach DIN 2448 351108; Familie und Typ: Stahlrohr nach DIN 2448 351108: Stahlrohr nach DIN 2448 351108; Typ-ID: 2536531
Abhängigkeiten - Höhe von Ebene: 0 m; Verschieben mit umliegenden Elementen: no
Bemaßungen - Fläche: 0.172174 m2; Volumen: 0.0147495 m3
IFC-Parameter - In IFC-Datei exportieren: Nach Typ; Pset MEP.Tech-Insulation thickness (mm): 100; Pset MEP.Geom-DN: 100; In IFC exportieren als: ifcflowsegment; NameOverride: Stahlrohr nach DIN 2448; IfcPresentationLayer: 0-TFT-H_Vorlauf; ObjectTypeOverride: Stahlrohr nach DIN 2448; Pset MEP.Name: Stahlrohr nach DIN 2448; IfcDescription: Stahlrohr nach DIN 2448; Pset MEP.Geom-Outer Ø (mm): 114.3; Pset MEP.Tech-Material: Stahlrohr nach DIN 2448; Pset MEP.Geom-Length (mm): 257.04
Phasen - Phase erstellt: Phase 01

# IfcFlowSegment: Stahlrohr nach DIN 2448 351427:Stahlrohr nach DIN 2448 351427, Stahlrohr nach DIN 2448
In: Erdgeschoss
Type - Material: IfcSurfaceStyle #9317
Type - Andere - Kategorie: Allgemeines Modell; Familienname: Stahlrohr nach DIN 2448 351427
Type - ID-Daten - Typname: Stahlrohr nach DIN 2448 351427
Type - IFC-Parameter - Typ in IFC-Datei exportieren: Vorgabe
Description: Stahlrohr nach DIN 2448
Pset_DistributionFlowElementCommon - Reference: Stahlrohr nach DIN 2448 351427; sets with these values: 2
Andere - Typ: Stahlrohr nach DIN 2448 351427; Familie: Stahlrohr nach DIN 2448 351427; Familie und Typ: Stahlrohr nach DIN 2448 351427: Stahlrohr nach DIN 2448 351427; Typ-ID: 2536580
Abhängigkeiten - Höhe von Ebene: 0 m; Verschieben mit umliegenden Elementen: no
Bemaßungen - Fläche: 0.074735 m2; Volumen: 0.00640227 m3
IFC-Parameter - In IFC-Datei exportieren: Nach Typ; Pset MEP.Tech-Insulation thickness (mm): 100; Pset MEP.Geom-DN: 100; In IFC exportieren als: ifcflowsegment; NameOverride: Stahlrohr nach DIN 2448; IfcPresentationLayer: 0-TFT-H_Vorlauf; ObjectTypeOverride: Stahlrohr nach DIN 2448; Pset MEP.Name: Stahlrohr nach DIN 2448; IfcDescription: Stahlrohr nach DIN 2448; Pset MEP.Geom-Outer Ø (mm): 114.3; Pset MEP.Tech-Material: Stahlrohr nach DIN 2448; Pset MEP.Geom-Length (mm): 111.573
Phasen - Phase erstellt: Phase 01

# IfcFlowSegment: Stahlrohr nach DIN 2448 351760:Stahlrohr nach DIN 2448 351760, Stahlrohr nach DIN 2448
In: Erdgeschoss
Type - Material: IfcSurfaceStyle #1741
Type - Andere - Kategorie: Allgemeines Modell; Familienname: Stahlrohr nach DIN 2448 351760
Type - ID-Daten - Typname: Stahlrohr nach DIN 2448 351760
Type - IFC-Parameter - Typ in IFC-Datei exportieren: Vorgabe
Description: Stahlrohr nach DIN 2448
Pset_DistributionFlowElementCommon - Reference: Stahlrohr nach DIN 2448 351760; sets with these values: 2
Andere - Typ: Stahlrohr nach DIN 2448 351760; Familie: Stahlrohr nach DIN 2448 351760; Familie und Typ: Stahlrohr nach DIN 2448 351760: Stahlrohr nach DIN 2448 351760; Typ-ID: 2536601
Abhängigkeiten - Höhe von Ebene: 0 m; Verschieben mit umliegenden Elementen: no
Bemaßungen - Fläche: 0.074735 m2; Volumen: 0.00640227 m3
IFC-Parameter - In IFC-Datei exportieren: Nach Typ; Pset MEP.Tech-Insulation thickness (mm): 100; Pset MEP.Geom-DN: 100; In IFC exportieren als: ifcflowsegment; NameOverride: Stahlrohr nach DIN 2448; IfcPresentationLayer: 0-TFT-H_Ruecklauf; ObjectTypeOverride: Stahlrohr nach DIN 2448; Pset MEP.Name: Stahlrohr nach DIN 2448; IfcDescription: Stahlrohr nach DIN 2448; Pset MEP.Geom-Outer Ø (mm): 114.3; Pset MEP.Tech-Material: Stahlrohr nach DIN 2448; Pset MEP.Geom-Length (mm): 111.573
Phasen - Phase erstellt: Phase 01

# IfcFlowSegment: Stahlrohr nach DIN 2448 352592:Stahlrohr nach DIN 2448 352592, Stahlrohr nach DIN 2448
In: Erdgeschoss
Type - Material: IfcSurfaceStyle #352577
Type - Andere - Kategorie: Allgemeines Modell; Familienname: Stahlrohr nach DIN 2448 352592
Type - ID-Daten - Typname: Stahlrohr nach DIN 2448 352592
Type - IFC-Parameter - Typ in IFC-Datei exportieren: Vorgabe
Description: Stahlrohr nach DIN 2448
Pset_DistributionFlowElementCommon - Reference: Stahlrohr nach DIN 2448 352592; sets with these values: 2
Andere - Typ: Stahlrohr nach DIN 2448 352592; Familie: Stahlrohr nach DIN 2448 352592; Familie und Typ: Stahlrohr nach DIN 2448 352592: Stahlrohr nach DIN 2448 352592; Typ-ID: 2536625
Abhängigkeiten - Höhe von Ebene: 0 m; Verschieben mit umliegenden Elementen: no
Bemaßungen - Fläche: 0.255156 m2; Volumen: 0.00957376 m3
IFC-Parameter - In IFC-Datei exportieren: Nach Typ; Pset MEP.Geom-DN: 100; In IFC exportieren als: ifcflowsegment; NameOverride: Stahlrohr nach DIN 2448; IfcPresentationLayer: S_Gas; ObjectTypeOverride: Stahlrohr nach DIN 2448; Pset MEP.Name: Stahlrohr nach DIN 2448; IfcDescription: Stahlrohr nach DIN 2448; Pset MEP.Geom-Outer Ø (mm): 114.3; Pset MEP.Tech-Material: Stahlrohr nach DIN 2448; Pset MEP.Geom-Length (mm): 1428.39
Phasen - Phase erstellt: Phase 01

# IfcFlowSegment: Stahlrohr nach DIN 2448 352776:Stahlrohr nach DIN 2448 352776, Stahlrohr nach DIN 2448
In: Erdgeschoss
Type - Material: IfcSurfaceStyle #352577
Type - Andere - Kategorie: Allgemeines Modell; Familienname: Stahlrohr nach DIN 2448 352776
Type - ID-Daten - Typname: Stahlrohr nach DIN 2448 352776
Type - IFC-Parameter - Typ in IFC-Datei exportieren: Vorgabe
Description: Stahlrohr nach DIN 2448
Pset_DistributionFlowElementCommon - Reference: Stahlrohr nach DIN 2448 352776; sets with these values: 2
Andere - Typ: Stahlrohr nach DIN 2448 352776; Familie: Stahlrohr nach DIN 2448 352776; Familie und Typ: Stahlrohr nach DIN 2448 352776: Stahlrohr nach DIN 2448 352776; Typ-ID: 2536639
Abhängigkeiten - Höhe von Ebene: 0 m; Verschieben mit umliegenden Elementen: no
Bemaßungen - Fläche: 0.222221 m2; Volumen: 0.00833798 m3
IFC-Parameter - In IFC-Datei exportieren: Nach Typ; Pset MEP.Geom-DN: 100; In IFC exportieren als: ifcflowsegment; NameOverride: Stahlrohr nach DIN 2448; IfcPresentationLayer: S_Gas; ObjectTypeOverride: Stahlrohr nach DIN 2448; Pset MEP.Name: Stahlrohr nach DIN 2448; IfcDescription: Stahlrohr nach DIN 2448; Pset MEP.Geom-Outer Ø (mm): 114.3; Pset MEP.Tech-Material: Stahlrohr nach DIN 2448; Pset MEP.Geom-Length (mm): 1244.01
Phasen - Phase erstellt: Phase 01

# IfcFlowSegment: Stahlrohr nach DIN 2448 352931:Stahlrohr nach DIN 2448 352931, Stahlrohr nach DIN 2448
In: Erdgeschoss
Type - Material: IfcSurfaceStyle #352577
Type - Andere - Kategorie: Allgemeines Modell; Familienname: Stahlrohr nach DIN 2448 352931
Type - ID-Daten - Typname: Stahlrohr nach DIN 2448 352931
Type - IFC-Parameter - Typ in IFC-Datei exportieren: Vorgabe
Description: Stahlrohr nach DIN 2448
Pset_DistributionFlowElementCommon - Reference: Stahlrohr nach DIN 2448 352931; sets with these values: 2
Andere - Typ: Stahlrohr nach DIN 2448 352931; Familie: Stahlrohr nach DIN 2448 352931; Familie und Typ: Stahlrohr nach DIN 2448 352931: Stahlrohr nach DIN 2448 352931; Typ-ID: 2536646
Abhängigkeiten - Höhe von Ebene: 0 m; Verschieben mit umliegenden Elementen: no
Bemaßungen - Fläche: 0.605628 m2; Volumen: 0.0227239 m3
IFC-Parameter - In IFC-Datei exportieren: Nach Typ; Pset MEP.Geom-DN: 100; In IFC exportieren als: ifcflowsegment; NameOverride: Stahlrohr nach DIN 2448; IfcPresentationLayer: S_Gas; ObjectTypeOverride: Stahlrohr nach DIN 2448; Pset MEP.Name: Stahlrohr nach DIN 2448; IfcDescription: Stahlrohr nach DIN 2448; Pset MEP.Geom-Outer Ø (mm): 114.3; Pset MEP.Tech-Material: Stahlrohr nach DIN 2448; Pset MEP.Geom-Length (mm): 3390.37
Phasen - Phase erstellt: Phase 01

# IfcFlowSegment: Stahlrohr nach DIN 2448 355557:Stahlrohr nach DIN 2448 355557, Stahlrohr nach DIN 2448
In: Erdgeschoss
Type - Material: IfcSurfaceStyle #352577
Type - Andere - Kategorie: Allgemeines Modell; Familienname: Stahlrohr nach DIN 2448 355557
Type - ID-Daten - Typname: Stahlrohr nach DIN 2448 355557
Type - IFC-Parameter - Typ in IFC-Datei exportieren: Vorgabe
Description: Stahlrohr nach DIN 2448
Pset_DistributionFlowElementCommon - Reference: Stahlrohr nach DIN 2448 355557; sets with these values: 2
Andere - Typ: Stahlrohr nach DIN 2448 355557; Familie: Stahlrohr nach DIN 2448 355557; Familie und Typ: Stahlrohr nach DIN 2448 355557: Stahlrohr nach DIN 2448 355557; Typ-ID: 2536758
Abhängigkeiten - Höhe von Ebene: 0 m; Verschieben mit umliegenden Elementen: no
Bemaßungen - Fläche: 0.0118932 m2; Volumen: 0.000297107 m3
IFC-Parameter - In IFC-Datei exportieren: Nach Typ; Pset MEP.Geom-Length (mm): 100; Pset MEP.Geom-DN: 65; In IFC exportieren als: ifcflowsegment; NameOverride: Stahlrohr nach DIN 2448; IfcPresentationLayer: S_Gas; ObjectTypeOverride: Stahlrohr nach DIN 2448; Pset MEP.Name: Stahlrohr nach DIN 2448; IfcDescription: Stahlrohr nach DIN 2448; Pset MEP.Geom-Outer Ø (mm): 76.1; Pset MEP.Tech-Material: Stahlrohr nach DIN 2448
Phasen - Phase erstellt: Phase 01

# IfcFlowSegment: Stahlrohr nach DIN 2448 358511:Stahlrohr nach DIN 2448 358511, Stahlrohr nach DIN 2448
In: Erdgeschoss
Type - Material: IfcSurfaceStyle #352577
Type - Andere - Kategorie: Allgemeines Modell; Familienname: Stahlrohr nach DIN 2448 358511
Type - ID-Daten - Typname: Stahlrohr nach DIN 2448 358511
Type - IFC-Parameter - Typ in IFC-Datei exportieren: Vorgabe
Description: Stahlrohr nach DIN 2448
Pset_DistributionFlowElementCommon - Reference: Stahlrohr nach DIN 2448 358511; sets with these values: 2
Andere - Typ: Stahlrohr nach DIN 2448 358511; Familie: Stahlrohr nach DIN 2448 358511; Familie und Typ: Stahlrohr nach DIN 2448 358511: Stahlrohr nach DIN 2448 358511; Typ-ID: 2536842
Abhängigkeiten - Höhe von Ebene: 0 m; Verschieben mit umliegenden Elementen: no
Bemaßungen - Fläche: 0.0541728 m2; Volumen: 0.00135331 m3
IFC-Parameter - In IFC-Datei exportieren: Nach Typ; Pset MEP.Geom-DN: 65; In IFC exportieren als: ifcflowsegment; NameOverride: Stahlrohr nach DIN 2448; IfcPresentationLayer: S_Gas; ObjectTypeOverride: Stahlrohr nach DIN 2448; Pset MEP.Name: Stahlrohr nach DIN 2448; IfcDescription: Stahlrohr nach DIN 2448; Pset MEP.Geom-Outer Ø (mm): 76.1; Pset MEP.Tech-Material: Stahlrohr nach DIN 2448; Pset MEP.Geom-Length (mm): 455.495
Phasen - Phase erstellt: Phase 01

# IfcFlowSegment: Stahlrohr nach DIN 2448 358666:Stahlrohr nach DIN 2448 358666, Stahlrohr nach DIN 2448
In: Erdgeschoss
Type - Material: IfcSurfaceStyle #352577
Type - Andere - Kategorie: Allgemeines Modell; Familienname: Stahlrohr nach DIN 2448 358666
Type - ID-Daten - Typname: Stahlrohr nach DIN 2448 358666
Type - IFC-Parameter - Typ in IFC-Datei exportieren: Vorgabe
Description: Stahlrohr nach DIN 2448
Pset_DistributionFlowElementCommon - Reference: Stahlrohr nach DIN 2448 358666; sets with these values: 2
Andere - Typ: Stahlrohr nach DIN 2448 358666; Familie: Stahlrohr nach DIN 2448 358666; Familie und Typ: Stahlrohr nach DIN 2448 358666: Stahlrohr nach DIN 2448 358666; Typ-ID: 2536849
Abhängigkeiten - Höhe von Ebene: 0 m; Verschieben mit umliegenden Elementen: no
Bemaßungen - Fläche: 0.0107038 m2; Volumen: 0.000267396 m3
IFC-Parameter - In IFC-Datei exportieren: Nach Typ; Pset MEP.Geom-Length (mm): 90; Pset MEP.Geom-DN: 65; In IFC exportieren als: ifcflowsegment; NameOverride: Stahlrohr nach DIN 2448; IfcPresentationLayer: S_Gas; ObjectTypeOverride: Stahlrohr nach DIN 2448; Pset MEP.Name: Stahlrohr nach DIN 2448; IfcDescription: Stahlrohr nach DIN 2448; Pset MEP.Geom-Outer Ø (mm): 76.1; Pset MEP.Tech-Material: Stahlrohr nach DIN 2448
Phasen - Phase erstellt: Phase 01

# IfcFlowSegment: Stahlrohr nach DIN 2448 359159:Stahlrohr nach DIN 2448 359159, Stahlrohr nach DIN 2448
In: Erdgeschoss
Type - Material: IfcSurfaceStyle #352577
Type - Andere - Kategorie: Allgemeines Modell; Familienname: Stahlrohr nach DIN 2448 359159
Type - ID-Daten - Typname: Stahlrohr nach DIN 2448 359159
Type - IFC-Parameter - Typ in IFC-Datei exportieren: Vorgabe
Description: Stahlrohr nach DIN 2448
Pset_DistributionFlowElementCommon - Reference: Stahlrohr nach DIN 2448 359159; sets with these values: 2
Andere - Typ: Stahlrohr nach DIN 2448 359159; Familie: Stahlrohr nach DIN 2448 359159; Familie und Typ: Stahlrohr nach DIN 2448 359159: Stahlrohr nach DIN 2448 359159; Typ-ID: 2536870
Abhängigkeiten - Höhe von Ebene: 0 m; Verschieben mit umliegenden Elementen: no
Bemaßungen - Fläche: 0.12215 m2; Volumen: 0.00305147 m3
IFC-Parameter - In IFC-Datei exportieren: Nach Typ; Pset MEP.Geom-DN: 65; In IFC exportieren als: ifcflowsegment; NameOverride: Stahlrohr nach DIN 2448; IfcPresentationLayer: S_Gas; ObjectTypeOverride: Stahlrohr nach DIN 2448; Pset MEP.Name: Stahlrohr nach DIN 2448; IfcDescription: Stahlrohr nach DIN 2448; Pset MEP.Geom-Outer Ø (mm): 76.1; Pset MEP.Tech-Material: Stahlrohr nach DIN 2448; Pset MEP.Geom-Length (mm): 1027.06
Phasen - Phase erstellt: Phase 01

# IfcFlowSegment: Stahlrohr nach DIN 2448 359337:Stahlrohr nach DIN 2448 359337, Stahlrohr nach DIN 2448
In: Erdgeschoss
Type - Material: IfcSurfaceStyle #352577
Type - Andere - Kategorie: Allgemeines Modell; Familienname: Stahlrohr nach DIN 2448 359337
Type - ID-Daten - Typname: Stahlrohr nach DIN 2448 359337
Type - IFC-Parameter - Typ in IFC-Datei exportieren: Vorgabe
Description: Stahlrohr nach DIN 2448
Pset_DistributionFlowElementCommon - Reference: Stahlrohr nach DIN 2448 359337; sets with these values: 2
Andere - Typ: Stahlrohr nach DIN 2448 359337; Familie: Stahlrohr nach DIN 2448 359337; Familie und Typ: Stahlrohr nach DIN 2448 359337: Stahlrohr nach DIN 2448 359337; Typ-ID: 2536884
Abhängigkeiten - Höhe von Ebene: 0 m; Verschieben mit umliegenden Elementen: no
Bemaßungen - Fläche: 0.183769 m2; Volumen: 0.00459078 m3
IFC-Parameter - In IFC-Datei exportieren: Nach Typ; Pset MEP.Geom-DN: 65; In IFC exportieren als: ifcflowsegment; NameOverride: Stahlrohr nach DIN 2448; IfcPresentationLayer: S_Gas; ObjectTypeOverride: Stahlrohr nach DIN 2448; Pset MEP.Name: Stahlrohr nach DIN 2448; IfcDescription: Stahlrohr nach DIN 2448; Pset MEP.Geom-Outer Ø (mm): 76.1; Pset MEP.Tech-Material: Stahlrohr nach DIN 2448; Pset MEP.Geom-Length (mm): 1545.16
Phasen - Phase erstellt: Phase 01

# IfcFlowSegment: Stahlrohr nach DIN 2448 359492:Stahlrohr nach DIN 2448 359492, Stahlrohr nach DIN 2448
In: Erdgeschoss
Type - Material: IfcSurfaceStyle #352577
Type - Andere - Kategorie: Allgemeines Modell; Familienname: Stahlrohr nach DIN 2448 359492
Type - ID-Daten - Typname: Stahlrohr nach DIN 2448 359492
Type - IFC-Parameter - Typ in IFC-Datei exportieren: Vorgabe
Description: Stahlrohr nach DIN 2448
Pset_DistributionFlowElementCommon - Reference: Stahlrohr nach DIN 2448 359492; sets with these values: 2
Andere - Typ: Stahlrohr nach DIN 2448 359492; Familie: Stahlrohr nach DIN 2448 359492; Familie und Typ: Stahlrohr nach DIN 2448 359492: Stahlrohr nach DIN 2448 359492; Typ-ID: 2536891
Abhängigkeiten - Höhe von Ebene: 0 m; Verschieben mit umliegenden Elementen: no
Bemaßungen - Fläche: 0.13073 m2; Volumen: 0.00326581 m3
IFC-Parameter - In IFC-Datei exportieren: Nach Typ; Pset MEP.Geom-DN: 65; In IFC exportieren als: ifcflowsegment; NameOverride: Stahlrohr nach DIN 2448; IfcPresentationLayer: S_Gas; ObjectTypeOverride: Stahlrohr nach DIN 2448; Pset MEP.Name: Stahlrohr nach DIN 2448; IfcDescription: Stahlrohr nach DIN 2448; Pset MEP.Geom-Outer Ø (mm): 76.1; Pset MEP.Tech-Material: Stahlrohr nach DIN 2448; Pset MEP.Geom-Length (mm): 1099.2
Phasen - Phase erstellt: Phase 01

# IfcFlowSegment: Stahlrohr nach DIN 2448 359766:Stahlrohr nach DIN 2448 359766, Stahlrohr nach DIN 2448
In: Erdgeschoss
Type - Material: IfcSurfaceStyle #352577
Type - Andere - Kategorie: Allgemeines Modell; Familienname: Stahlrohr nach DIN 2448 359766
Type - ID-Daten - Typname: Stahlrohr nach DIN 2448 359766
Type - IFC-Parameter - Typ in IFC-Datei exportieren: Vorgabe
Description: Stahlrohr nach DIN 2448
Pset_DistributionFlowElementCommon - Reference: Stahlrohr nach DIN 2448 359766; sets with these values: 2
Andere - Typ: Stahlrohr nach DIN 2448 359766; Familie: Stahlrohr nach DIN 2448 359766; Familie und Typ: Stahlrohr nach DIN 2448 359766: Stahlrohr nach DIN 2448 359766; Typ-ID: 2536933
Abhängigkeiten - Höhe von Ebene: 0 m; Verschieben mit umliegenden Elementen: no
Bemaßungen - Fläche: 0.13073 m2; Volumen: 0.00326581 m3
IFC-Parameter - In IFC-Datei exportieren: Nach Typ; Pset MEP.Geom-DN: 65; In IFC exportieren als: ifcflowsegment; NameOverride: Stahlrohr nach DIN 2448; IfcPresentationLayer: S_Gas; ObjectTypeOverride: Stahlrohr nach DIN 2448; Pset MEP.Name: Stahlrohr nach DIN 2448; IfcDescription: Stahlrohr nach DIN 2448; Pset MEP.Geom-Outer Ø (mm): 76.1; Pset MEP.Tech-Material: Stahlrohr nach DIN 2448; Pset MEP.Geom-Length (mm): 1099.2
Phasen - Phase erstellt: Phase 01

# IfcFlowSegment: Stahlrohr nach DIN 2448 360805:Stahlrohr nach DIN 2448 360805, Stahlrohr nach DIN 2448
In: Erdgeschoss
Type - Material: IfcSurfaceStyle #352577
Type - Andere - Kategorie: Allgemeines Modell; Familienname: Stahlrohr nach DIN 2448 360805
Type - ID-Daten - Typname: Stahlrohr nach DIN 2448 360805
Type - IFC-Parameter - Typ in IFC-Datei exportieren: Vorgabe
Description: Stahlrohr nach DIN 2448
Pset_DistributionFlowElementCommon - Reference: Stahlrohr nach DIN 2448 360805; sets with these values: 2
Andere - Typ: Stahlrohr nach DIN 2448 360805; Familie: Stahlrohr nach DIN 2448 360805; Familie und Typ: Stahlrohr nach DIN 2448 360805: Stahlrohr nach DIN 2448 360805; Typ-ID: 2536954
Abhängigkeiten - Höhe von Ebene: 0 m; Verschieben mit umliegenden Elementen: no
Bemaßungen - Fläche: 0.0118932 m2; Volumen: 0.000297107 m3
IFC-Parameter - In IFC-Datei exportieren: Nach Typ; Pset MEP.Geom-Length (mm): 100; Pset MEP.Geom-DN: 65; In IFC exportieren als: ifcflowsegment; NameOverride: Stahlrohr nach DIN 2448; IfcPresentationLayer: S_Gas; ObjectTypeOverride: Stahlrohr nach DIN 2448; Pset MEP.Name: Stahlrohr nach DIN 2448; IfcDescription: Stahlrohr nach DIN 2448; Pset MEP.Geom-Outer Ø (mm): 76.1; Pset MEP.Tech-Material: Stahlrohr nach DIN 2448
Phasen - Phase erstellt: Phase 01

# IfcFlowSegment: Stahlrohr nach DIN 2448 602960:Stahlrohr nach DIN 2448 602960, Stahlrohr nach DIN 2448
In: Erdgeschoss
Type - Material: IfcSurfaceStyle #352577
Type - Andere - Kategorie: Allgemeines Modell; Familienname: Stahlrohr nach DIN 2448 602960
Type - ID-Daten - Typname: Stahlrohr nach DIN 2448 602960
Type - IFC-Parameter - Typ in IFC-Datei exportieren: Vorgabe
Description: Stahlrohr nach DIN 2448
Pset_DistributionFlowElementCommon - Reference: Stahlrohr nach DIN 2448 602960; sets with these values: 2
Andere - Typ: Stahlrohr nach DIN 2448 602960; Familie: Stahlrohr nach DIN 2448 602960; Familie und Typ: Stahlrohr nach DIN 2448 602960: Stahlrohr nach DIN 2448 602960; Typ-ID: 2536989
Abhängigkeiten - Höhe von Ebene: 0 m; Verschieben mit umliegenden Elementen: no
Bemaßungen - Fläche: 0.0541728 m2; Volumen: 0.00135331 m3
IFC-Parameter - In IFC-Datei exportieren: Nach Typ; Pset MEP.Geom-DN: 65; In IFC exportieren als: ifcflowsegment; NameOverride: Stahlrohr nach DIN 2448; IfcPresentationLayer: S_Gas; ObjectTypeOverride: Stahlrohr nach DIN 2448; Pset MEP.Name: Stahlrohr nach DIN 2448; IfcDescription: Stahlrohr nach DIN 2448; Pset MEP.Geom-Outer Ø (mm): 76.1; Pset MEP.Tech-Material: Stahlrohr nach DIN 2448; Pset MEP.Geom-Length (mm): 455.495
Phasen - Phase erstellt: Phase 01

# IfcFlowSegment: Stahlrohr nach DIN 2448 604224:Stahlrohr nach DIN 2448 604224, Stahlrohr nach DIN 2448
In: Erdgeschoss
Type - Material: IfcSurfaceStyle #352577
Type - Andere - Kategorie: Allgemeines Modell; Familienname: Stahlrohr nach DIN 2448 604224
Type - ID-Daten - Typname: Stahlrohr nach DIN 2448 604224
Type - IFC-Parameter - Typ in IFC-Datei exportieren: Vorgabe
Description: Stahlrohr nach DIN 2448
Pset_DistributionFlowElementCommon - Reference: Stahlrohr nach DIN 2448 604224; sets with these values: 2
Andere - Typ: Stahlrohr nach DIN 2448 604224; Familie: Stahlrohr nach DIN 2448 604224; Familie und Typ: Stahlrohr nach DIN 2448 604224: Stahlrohr nach DIN 2448 604224; Typ-ID: 2537080
Abhängigkeiten - Höhe von Ebene: 0 m; Verschieben mit umliegenden Elementen: no
Bemaßungen - Fläche: 0.0107038 m2; Volumen: 0.000267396 m3
IFC-Parameter - In IFC-Datei exportieren: Nach Typ; Pset MEP.Geom-Length (mm): 90; Pset MEP.Geom-DN: 65; In IFC exportieren als: ifcflowsegment; NameOverride: Stahlrohr nach DIN 2448; IfcPresentationLayer: S_Gas; ObjectTypeOverride: Stahlrohr nach DIN 2448; Pset MEP.Name: Stahlrohr nach DIN 2448; IfcDescription: Stahlrohr nach DIN 2448; Pset MEP.Geom-Outer Ø (mm): 76.1; Pset MEP.Tech-Material: Stahlrohr nach DIN 2448
Phasen - Phase erstellt: Phase 01

# IfcFlowSegment: Stahlrohr nach DIN 2448 604523:Stahlrohr nach DIN 2448 604523, Stahlrohr nach DIN 2448
In: Erdgeschoss
Type - Material: IfcSurfaceStyle #352577
Type - Andere - Kategorie: Allgemeines Modell; Familienname: Stahlrohr nach DIN 2448 604523
Type - ID-Daten - Typname: Stahlrohr nach DIN 2448 604523
Type - IFC-Parameter - Typ in IFC-Datei exportieren: Vorgabe
Description: Stahlrohr nach DIN 2448
Pset_DistributionFlowElementCommon - Reference: Stahlrohr nach DIN 2448 604523; sets with these values: 2
Andere - Typ: Stahlrohr nach DIN 2448 604523; Familie: Stahlrohr nach DIN 2448 604523; Familie und Typ: Stahlrohr nach DIN 2448 604523: Stahlrohr nach DIN 2448 604523; Typ-ID: 2537171
Abhängigkeiten - Höhe von Ebene: 0 m; Verschieben mit umliegenden Elementen: no
Bemaßungen - Fläche: 0.13073 m2; Volumen: 0.00326581 m3
IFC-Parameter - In IFC-Datei exportieren: Nach Typ; Pset MEP.Geom-DN: 65; In IFC exportieren als: ifcflowsegment; NameOverride: Stahlrohr nach DIN 2448; IfcPresentationLayer: S_Gas; ObjectTypeOverride: Stahlrohr nach DIN 2448; Pset MEP.Name: Stahlrohr nach DIN 2448; IfcDescription: Stahlrohr nach DIN 2448; Pset MEP.Geom-Outer Ø (mm): 76.1; Pset MEP.Tech-Material: Stahlrohr nach DIN 2448; Pset MEP.Geom-Length (mm): 1099.2
Phasen - Phase erstellt: Phase 01

# IfcFlowSegment: Stahlrohr nach DIN 2448 604684:Stahlrohr nach DIN 2448 604684, Stahlrohr nach DIN 2448
In: Erdgeschoss
Type - Material: IfcSurfaceStyle #352577
Type - Andere - Kategorie: Allgemeines Modell; Familienname: Stahlrohr nach DIN 2448 604684
Type - ID-Daten - Typname: Stahlrohr nach DIN 2448 604684
Type - IFC-Parameter - Typ in IFC-Datei exportieren: Vorgabe
Description: Stahlrohr nach DIN 2448
Pset_DistributionFlowElementCommon - Reference: Stahlrohr nach DIN 2448 604684; sets with these values: 2
Andere - Typ: Stahlrohr nach DIN 2448 604684; Familie: Stahlrohr nach DIN 2448 604684; Familie und Typ: Stahlrohr nach DIN 2448 604684: Stahlrohr nach DIN 2448 604684; Typ-ID: 2537220
Abhängigkeiten - Höhe von Ebene: 0 m; Verschieben mit umliegenden Elementen: no
Bemaßungen - Fläche: 0.0541728 m2; Volumen: 0.00135331 m3
IFC-Parameter - In IFC-Datei exportieren: Nach Typ; Pset MEP.Geom-DN: 65; In IFC exportieren als: ifcflowsegment; NameOverride: Stahlrohr nach DIN 2448; IfcPresentationLayer: S_Gas; ObjectTypeOverride: Stahlrohr nach DIN 2448; Pset MEP.Name: Stahlrohr nach DIN 2448; IfcDescription: Stahlrohr nach DIN 2448; Pset MEP.Geom-Outer Ø (mm): 76.1; Pset MEP.Tech-Material: Stahlrohr nach DIN 2448; Pset MEP.Geom-Length (mm): 455.495
Phasen - Phase erstellt: Phase 01

# IfcFlowSegment: Stahlrohr nach DIN 2448 604751:Stahlrohr nach DIN 2448 604751, Stahlrohr nach DIN 2448
In: Erdgeschoss
Type - Material: IfcSurfaceStyle #352577
Type - Andere - Kategorie: Allgemeines Modell; Familienname: Stahlrohr nach DIN 2448 604751
Type - ID-Daten - Typname: Stahlrohr nach DIN 2448 604751
Type - IFC-Parameter - Typ in IFC-Datei exportieren: Vorgabe
Description: Stahlrohr nach DIN 2448
Pset_DistributionFlowElementCommon - Reference: Stahlrohr nach DIN 2448 604751; sets with these values: 2
Andere - Typ: Stahlrohr nach DIN 2448 604751; Familie: Stahlrohr nach DIN 2448 604751; Familie und Typ: Stahlrohr nach DIN 2448 604751: Stahlrohr nach DIN 2448 604751; Typ-ID: 2537241
Abhängigkeiten - Höhe von Ebene: 0 m; Verschieben mit umliegenden Elementen: no
Bemaßungen - Fläche: 0.0118932 m2; Volumen: 0.000297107 m3
IFC-Parameter - In IFC-Datei exportieren: Nach Typ; Pset MEP.Geom-Length (mm): 100; Pset MEP.Geom-DN: 65; In IFC exportieren als: ifcflowsegment; NameOverride: Stahlrohr nach DIN 2448; IfcPresentationLayer: S_Gas; ObjectTypeOverride: Stahlrohr nach DIN 2448; Pset MEP.Name: Stahlrohr nach DIN 2448; IfcDescription: Stahlrohr nach DIN 2448; Pset MEP.Geom-Outer Ø (mm): 76.1; Pset MEP.Tech-Material: Stahlrohr nach DIN 2448
Phasen - Phase erstellt: Phase 01

# IfcFlowSegment: Stahlrohr nach DIN 2448 604797:Stahlrohr nach DIN 2448 604797, Stahlrohr nach DIN 2448
In: Erdgeschoss
Type - Material: IfcSurfaceStyle #352577
Type - Andere - Kategorie: Allgemeines Modell; Familienname: Stahlrohr nach DIN 2448 604797
Type - ID-Daten - Typname: Stahlrohr nach DIN 2448 604797
Type - IFC-Parameter - Typ in IFC-Datei exportieren: Vorgabe
Description: Stahlrohr nach DIN 2448
Pset_DistributionFlowElementCommon - Reference: Stahlrohr nach DIN 2448 604797; sets with these values: 2
Andere - Typ: Stahlrohr nach DIN 2448 604797; Familie: Stahlrohr nach DIN 2448 604797; Familie und Typ: Stahlrohr nach DIN 2448 604797: Stahlrohr nach DIN 2448 604797; Typ-ID: 2537255
Abhängigkeiten - Höhe von Ebene: 0 m; Verschieben mit umliegenden Elementen: no
Bemaßungen - Fläche: 0.0107038 m2; Volumen: 0.000267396 m3
IFC-Parameter - In IFC-Datei exportieren: Nach Typ; Pset MEP.Geom-Length (mm): 90; Pset MEP.Geom-DN: 65; In IFC exportieren als: ifcflowsegment; NameOverride: Stahlrohr nach DIN 2448; IfcPresentationLayer: S_Gas; ObjectTypeOverride: Stahlrohr nach DIN 2448; Pset MEP.Name: Stahlrohr nach DIN 2448; IfcDescription: Stahlrohr nach DIN 2448; Pset MEP.Geom-Outer Ø (mm): 76.1; Pset MEP.Tech-Material: Stahlrohr nach DIN 2448
Phasen - Phase erstellt: Phase 01

# IfcFlowSegment: Stahlrohr nach DIN 2448 605049:Stahlrohr nach DIN 2448 605049, Stahlrohr nach DIN 2448
In: Erdgeschoss
Type - Material: IfcSurfaceStyle #352577
Type - Andere - Kategorie: Allgemeines Modell; Familienname: Stahlrohr nach DIN 2448 605049
Type - ID-Daten - Typname: Stahlrohr nach DIN 2448 605049
Type - IFC-Parameter - Typ in IFC-Datei exportieren: Vorgabe
Description: Stahlrohr nach DIN 2448
Pset_DistributionFlowElementCommon - Reference: Stahlrohr nach DIN 2448 605049; sets with these values: 2
Andere - Typ: Stahlrohr nach DIN 2448 605049; Familie: Stahlrohr nach DIN 2448 605049; Familie und Typ: Stahlrohr nach DIN 2448 605049: Stahlrohr nach DIN 2448 605049; Typ-ID: 2537332
Abhängigkeiten - Höhe von Ebene: 0 m; Verschieben mit umliegenden Elementen: no
Bemaßungen - Fläche: 0.185196 m2; Volumen: 0.00462644 m3
IFC-Parameter - In IFC-Datei exportieren: Nach Typ; Pset MEP.Geom-DN: 65; In IFC exportieren als: ifcflowsegment; NameOverride: Stahlrohr nach DIN 2448; IfcPresentationLayer: S_Gas; ObjectTypeOverride: Stahlrohr nach DIN 2448; Pset MEP.Name: Stahlrohr nach DIN 2448; IfcDescription: Stahlrohr nach DIN 2448; Pset MEP.Geom-Outer Ø (mm): 76.1; Pset MEP.Tech-Material: Stahlrohr nach DIN 2448; Pset MEP.Geom-Length (mm): 1557.16
Phasen - Phase erstellt: Phase 01

# IfcFlowSegment: Stahlrohr nach DIN 2448 605227:Stahlrohr nach DIN 2448 605227, Stahlrohr nach DIN 2448
In: Erdgeschoss
Type - Material: IfcSurfaceStyle #352577
Type - Andere - Kategorie: Allgemeines Modell; Familienname: Stahlrohr nach DIN 2448 605227
Type - ID-Daten - Typname: Stahlrohr nach DIN 2448 605227
Type - IFC-Parameter - Typ in IFC-Datei exportieren: Vorgabe
Description: Stahlrohr nach DIN 2448
Pset_DistributionFlowElementCommon - Reference: Stahlrohr nach DIN 2448 605227; sets with these values: 2
Andere - Typ: Stahlrohr nach DIN 2448 605227; Familie: Stahlrohr nach DIN 2448 605227; Familie und Typ: Stahlrohr nach DIN 2448 605227: Stahlrohr nach DIN 2448 605227; Typ-ID: 2537346
Abhängigkeiten - Höhe von Ebene: 0 m; Verschieben mit umliegenden Elementen: no
Bemaßungen - Fläche: 0.186029 m2; Volumen: 0.00464723 m3
IFC-Parameter - In IFC-Datei exportieren: Nach Typ; Pset MEP.Geom-DN: 65; In IFC exportieren als: ifcflowsegment; NameOverride: Stahlrohr nach DIN 2448; IfcPresentationLayer: S_Gas; ObjectTypeOverride: Stahlrohr nach DIN 2448; Pset MEP.Name: Stahlrohr nach DIN 2448; IfcDescription: Stahlrohr nach DIN 2448; Pset MEP.Geom-Outer Ø (mm): 76.1; Pset MEP.Tech-Material: Stahlrohr nach DIN 2448; Pset MEP.Geom-Length (mm): 1564.16
Phasen - Phase erstellt: Phase 01

# IfcFlowSegment: Stahlrohr nach DIN 2448 608249:Stahlrohr nach DIN 2448 608249, Stahlrohr nach DIN 2448
In: Erdgeschoss
Type - Material: IfcSurfaceStyle #352577
Type - Andere - Kategorie: Allgemeines Modell; Familienname: Stahlrohr nach DIN 2448 608249
Type - ID-Daten - Typname: Stahlrohr nach DIN 2448 608249
Type - IFC-Parameter - Typ in IFC-Datei exportieren: Vorgabe
Description: Stahlrohr nach DIN 2448
Pset_DistributionFlowElementCommon - Reference: Stahlrohr nach DIN 2448 608249; sets with these values: 2
Andere - Typ: Stahlrohr nach DIN 2448 608249; Familie: Stahlrohr nach DIN 2448 608249; Familie und Typ: Stahlrohr nach DIN 2448 608249: Stahlrohr nach DIN 2448 608249; Typ-ID: 2537437
Abhängigkeiten - Höhe von Ebene: 0 m; Verschieben mit umliegenden Elementen: no
Bemaßungen - Fläche: 0.00662641 m2; Volumen: 0.0000922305 m3
IFC-Parameter - In IFC-Datei exportieren: Nach Typ; Pset MEP.Geom-Length (mm): 100; Pset MEP.Geom-DN: 32; In IFC exportieren als: ifcflowsegment; NameOverride: Stahlrohr nach DIN 2448; IfcPresentationLayer: S_Gas; ObjectTypeOverride: Stahlrohr nach DIN 2448; Pset MEP.Name: Stahlrohr nach DIN 2448; IfcDescription: Stahlrohr nach DIN 2448; Pset MEP.Geom-Outer Ø (mm): 42.4; Pset MEP.Tech-Material: Stahlrohr nach DIN 2448
Phasen - Phase erstellt: Phase 01

# IfcFlowSegment: Stahlrohr nach DIN 2448 608480:Stahlrohr nach DIN 2448 608480, Stahlrohr nach DIN 2448
In: Erdgeschoss
Type - Material: IfcSurfaceStyle #352577
Type - Andere - Kategorie: Allgemeines Modell; Familienname: Stahlrohr nach DIN 2448 608480
Type - ID-Daten - Typname: Stahlrohr nach DIN 2448 608480
Type - IFC-Parameter - Typ in IFC-Datei exportieren: Vorgabe
Description: Stahlrohr nach DIN 2448
Pset_DistributionFlowElementCommon - Reference: Stahlrohr nach DIN 2448 608480; sets with these values: 2
Andere - Typ: Stahlrohr nach DIN 2448 608480; Familie: Stahlrohr nach DIN 2448 608480; Familie und Typ: Stahlrohr nach DIN 2448 608480: Stahlrohr nach DIN 2448 608480; Typ-ID: 2537458
Abhängigkeiten - Höhe von Ebene: 0 m; Verschieben mit umliegenden Elementen: no
Bemaßungen - Fläche: 0.00596377 m2; Volumen: 0.0000830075 m3
IFC-Parameter - In IFC-Datei exportieren: Nach Typ; Pset MEP.Geom-Length (mm): 90; Pset MEP.Geom-DN: 32; In IFC exportieren als: ifcflowsegment; NameOverride: Stahlrohr nach DIN 2448; IfcPresentationLayer: S_Gas; ObjectTypeOverride: Stahlrohr nach DIN 2448; Pset MEP.Name: Stahlrohr nach DIN 2448; IfcDescription: Stahlrohr nach DIN 2448; Pset MEP.Geom-Outer Ø (mm): 42.4; Pset MEP.Tech-Material: Stahlrohr nach DIN 2448
Phasen - Phase erstellt: Phase 01

# IfcFlowSegment: Stahlrohr nach DIN 2448 611800:Stahlrohr nach DIN 2448 611800, Stahlrohr nach DIN 2448
In: Erdgeschoss
Type - Material: IfcSurfaceStyle #352577
Type - Andere - Kategorie: Allgemeines Modell; Familienname: Stahlrohr nach DIN 2448 611800
Type - ID-Daten - Typname: Stahlrohr nach DIN 2448 611800
Type - IFC-Parameter - Typ in IFC-Datei exportieren: Vorgabe
Description: Stahlrohr nach DIN 2448
Pset_DistributionFlowElementCommon - Reference: Stahlrohr nach DIN 2448 611800; sets with these values: 2
Andere - Typ: Stahlrohr nach DIN 2448 611800; Familie: Stahlrohr nach DIN 2448 611800; Familie und Typ: Stahlrohr nach DIN 2448 611800: Stahlrohr nach DIN 2448 611800; Typ-ID: 2537542
Abhängigkeiten - Höhe von Ebene: 0 m; Verschieben mit umliegenden Elementen: no
Bemaßungen - Fläche: 0.0613049 m2; Volumen: 0.00085328 m3
IFC-Parameter - In IFC-Datei exportieren: Nach Typ; Pset MEP.Geom-DN: 32; In IFC exportieren als: ifcflowsegment; NameOverride: Stahlrohr nach DIN 2448; IfcPresentationLayer: S_Gas; ObjectTypeOverride: Stahlrohr nach DIN 2448; Pset MEP.Name: Stahlrohr nach DIN 2448; IfcDescription: Stahlrohr nach DIN 2448; Pset MEP.Geom-Outer Ø (mm): 42.4; Pset MEP.Tech-Material: Stahlrohr nach DIN 2448; Pset MEP.Geom-Length (mm): 925.16
Phasen - Phase erstellt: Phase 01

# IfcFlowSegment: Stahlrohr nach DIN 2448 611978:Stahlrohr nach DIN 2448 611978, Stahlrohr nach DIN 2448
In: Erdgeschoss
Type - Material: IfcSurfaceStyle #352577
Type - Andere - Kategorie: Allgemeines Modell; Familienname: Stahlrohr nach DIN 2448 611978
Type - ID-Daten - Typname: Stahlrohr nach DIN 2448 611978
Type - IFC-Parameter - Typ in IFC-Datei exportieren: Vorgabe
Description: Stahlrohr nach DIN 2448
Pset_DistributionFlowElementCommon - Reference: Stahlrohr nach DIN 2448 611978; sets with these values: 2
Andere - Typ: Stahlrohr nach DIN 2448 611978; Familie: Stahlrohr nach DIN 2448 611978; Familie und Typ: Stahlrohr nach DIN 2448 611978: Stahlrohr nach DIN 2448 611978; Typ-ID: 2537556
Abhängigkeiten - Höhe von Ebene: 0 m; Verschieben mit umliegenden Elementen: no
Bemaßungen - Fläche: 0.0420112 m2; Volumen: 0.000584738 m3
IFC-Parameter - In IFC-Datei exportieren: Nach Typ; Pset MEP.Geom-DN: 32; In IFC exportieren als: ifcflowsegment; NameOverride: Stahlrohr nach DIN 2448; IfcPresentationLayer: S_Gas; ObjectTypeOverride: Stahlrohr nach DIN 2448; Pset MEP.Name: Stahlrohr nach DIN 2448; IfcDescription: Stahlrohr nach DIN 2448; Pset MEP.Geom-Outer Ø (mm): 42.4; Pset MEP.Tech-Material: Stahlrohr nach DIN 2448; Pset MEP.Geom-Length (mm): 633.996
Phasen - Phase erstellt: Phase 01

# IfcFlowSegment: Stahlrohr nach DIN 2448 612156:Stahlrohr nach DIN 2448 612156, Stahlrohr nach DIN 2448
In: Erdgeschoss
Type - Material: IfcSurfaceStyle #352577
Type - Andere - Kategorie: Allgemeines Modell; Familienname: Stahlrohr nach DIN 2448 612156
Type - ID-Daten - Typname: Stahlrohr nach DIN 2448 612156
Type - IFC-Parameter - Typ in IFC-Datei exportieren: Vorgabe
Description: Stahlrohr nach DIN 2448
Pset_DistributionFlowElementCommon - Reference: Stahlrohr nach DIN 2448 612156; sets with these values: 2
Andere - Typ: Stahlrohr nach DIN 2448 612156; Familie: Stahlrohr nach DIN 2448 612156; Familie und Typ: Stahlrohr nach DIN 2448 612156: Stahlrohr nach DIN 2448 612156; Typ-ID: 2537570
Abhängigkeiten - Höhe von Ebene: 0 m; Verschieben mit umliegenden Elementen: no
Bemaßungen - Fläche: 0.0941071 m2; Volumen: 0.00130984 m3
IFC-Parameter - In IFC-Datei exportieren: Nach Typ; Pset MEP.Geom-DN: 32; In IFC exportieren als: ifcflowsegment; NameOverride: Stahlrohr nach DIN 2448; IfcPresentationLayer: S_Gas; ObjectTypeOverride: Stahlrohr nach DIN 2448; Pset MEP.Name: Stahlrohr nach DIN 2448; IfcDescription: Stahlrohr nach DIN 2448; Pset MEP.Geom-Outer Ø (mm): 42.4; Pset MEP.Tech-Material: Stahlrohr nach DIN 2448; Pset MEP.Geom-Length (mm): 1420.18
Phasen - Phase erstellt: Phase 01

# IfcFlowSegment: Stahlrohr nach DIN 2448 612334:Stahlrohr nach DIN 2448 612334, Stahlrohr nach DIN 2448
In: Erdgeschoss
Type - Material: IfcSurfaceStyle #352577
Type - Andere - Kategorie: Allgemeines Modell; Familienname: Stahlrohr nach DIN 2448 612334
Type - ID-Daten - Typname: Stahlrohr nach DIN 2448 612334
Type - IFC-Parameter - Typ in IFC-Datei exportieren: Vorgabe
Description: Stahlrohr nach DIN 2448
Pset_DistributionFlowElementCommon - Reference: Stahlrohr nach DIN 2448 612334; sets with these values: 2
Andere - Typ: Stahlrohr nach DIN 2448 612334; Familie: Stahlrohr nach DIN 2448 612334; Familie und Typ: Stahlrohr nach DIN 2448 612334: Stahlrohr nach DIN 2448 612334; Typ-ID: 2537584
Abhängigkeiten - Höhe von Ebene: 0 m; Verschieben mit umliegenden Elementen: no
Bemaßungen - Fläche: 0.0764418 m2; Volumen: 0.00106396 m3
IFC-Parameter - In IFC-Datei exportieren: Nach Typ; Pset MEP.Geom-DN: 32; In IFC exportieren als: ifcflowsegment; NameOverride: Stahlrohr nach DIN 2448; IfcPresentationLayer: S_Gas; ObjectTypeOverride: Stahlrohr nach DIN 2448; Pset MEP.Name: Stahlrohr nach DIN 2448; IfcDescription: Stahlrohr nach DIN 2448; Pset MEP.Geom-Outer Ø (mm): 42.4; Pset MEP.Tech-Material: Stahlrohr nach DIN 2448; Pset MEP.Geom-Length (mm): 1153.59
Phasen - Phase erstellt: Phase 01

# IfcFlowSegment: Stahlrohr nach DIN 2448 612518:Stahlrohr nach DIN 2448 612518, Stahlrohr nach DIN 2448
In: Erdgeschoss
Type - Material: IfcSurfaceStyle #352577
Type - Andere - Kategorie: Allgemeines Modell; Familienname: Stahlrohr nach DIN 2448 612518
Type - ID-Daten - Typname: Stahlrohr nach DIN 2448 612518
Type - IFC-Parameter - Typ in IFC-Datei exportieren: Vorgabe
Description: Stahlrohr nach DIN 2448
Pset_DistributionFlowElementCommon - Reference: Stahlrohr nach DIN 2448 612518; sets with these values: 2
Andere - Typ: Stahlrohr nach DIN 2448 612518; Familie: Stahlrohr nach DIN 2448 612518; Familie und Typ: Stahlrohr nach DIN 2448 612518: Stahlrohr nach DIN 2448 612518; Typ-ID: 2537598
Abhängigkeiten - Höhe von Ebene: 0 m; Verschieben mit umliegenden Elementen: no
Bemaßungen - Fläche: 0.00503607 m2; Volumen: 0.0000700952 m3
IFC-Parameter - In IFC-Datei exportieren: Nach Typ; Pset MEP.Geom-DN: 32; In IFC exportieren als: ifcflowsegment; NameOverride: Stahlrohr nach DIN 2448; IfcPresentationLayer: S_Gas; ObjectTypeOverride: Stahlrohr nach DIN 2448; Pset MEP.Name: Stahlrohr nach DIN 2448; IfcDescription: Stahlrohr nach DIN 2448; Pset MEP.Geom-Outer Ø (mm): 42.4; Pset MEP.Tech-Material: Stahlrohr nach DIN 2448; Pset MEP.Geom-Length (mm): 76
Phasen - Phase erstellt: Phase 01

# IfcFlowSegment: Stahlrohr nach DIN 2448 612719:Stahlrohr nach DIN 2448 612719, Stahlrohr nach DIN 2448
In: 1. Obergeschoss
Type - Material: IfcSurfaceStyle #9317
Type - Andere - Kategorie: Allgemeines Modell; Familienname: Stahlrohr nach DIN 2448 612719
Type - ID-Daten - Typname: Stahlrohr nach DIN 2448 612719
Type - IFC-Parameter - Typ in IFC-Datei exportieren: Vorgabe
Description: Stahlrohr nach DIN 2448
Pset_DistributionFlowElementCommon - Reference: Stahlrohr nach DIN 2448 612719; sets with these values: 2
Andere - Typ: Stahlrohr nach DIN 2448 612719; Familie: Stahlrohr nach DIN 2448 612719; Familie und Typ: Stahlrohr nach DIN 2448 612719: Stahlrohr nach DIN 2448 612719; Typ-ID: 2537619
Abhängigkeiten - Höhe von Ebene: 0 m; Verschieben mit umliegenden Elementen: no
Bemaßungen - Fläche: 0.56977 m2; Volumen: 0.0655453 m3
IFC-Parameter - In IFC-Datei exportieren: Nach Typ; Pset MEP.Geom-DN: 200; Pset MEP.Tech-Insulation thickness (mm): 100; In IFC exportieren als: ifcflowsegment; NameOverride: Stahlrohr nach DIN 2448; IfcPresentationLayer: 0-TFT-H_Vorlauf; ObjectTypeOverride: Stahlrohr nach DIN 2448; Pset MEP.Name: Stahlrohr nach DIN 2448; IfcDescription: Stahlrohr nach DIN 2448; Pset MEP.Geom-Outer Ø (mm): 219.1; Pset MEP.Tech-Material: Stahlrohr nach DIN 2448; Pset MEP.Geom-Length (mm): 571.255
Phasen - Phase erstellt: Phase 01

# IfcFlowSegment: Stahlrohr nach DIN 2448 613000:Stahlrohr nach DIN 2448 613000, Stahlrohr nach DIN 2448
In: 1. Obergeschoss
Type - Material: IfcSurfaceStyle #9317
Type - Andere - Kategorie: Allgemeines Modell; Familienname: Stahlrohr nach DIN 2448 613000
Type - ID-Daten - Typname: Stahlrohr nach DIN 2448 613000
Type - IFC-Parameter - Typ in IFC-Datei exportieren: Vorgabe
Description: Stahlrohr nach DIN 2448
Pset_DistributionFlowElementCommon - Reference: Stahlrohr nach DIN 2448 613000; sets with these values: 2
Andere - Typ: Stahlrohr nach DIN 2448 613000; Familie: Stahlrohr nach DIN 2448 613000; Familie und Typ: Stahlrohr nach DIN 2448 613000: Stahlrohr nach DIN 2448 613000; Typ-ID: 2537626
Abhängigkeiten - Höhe von Ebene: 0 m; Verschieben mit umliegenden Elementen: no
Bemaßungen - Fläche: 1.09602 m2; Volumen: 0.126084 m3
IFC-Parameter - In IFC-Datei exportieren: Nach Typ; Pset MEP.Geom-DN: 200; Pset MEP.Tech-Insulation thickness (mm): 100; In IFC exportieren als: ifcflowsegment; NameOverride: Stahlrohr nach DIN 2448; IfcPresentationLayer: 0-TFT-H_Vorlauf; ObjectTypeOverride: Stahlrohr nach DIN 2448; Pset MEP.Name: Stahlrohr nach DIN 2448; IfcDescription: Stahlrohr nach DIN 2448; Pset MEP.Geom-Outer Ø (mm): 219.1; Pset MEP.Tech-Material: Stahlrohr nach DIN 2448; Pset MEP.Geom-Length (mm): 1098.88
Phasen - Phase erstellt: Phase 01

# IfcFlowSegment: Stahlrohr nach DIN 2448 613304:Stahlrohr nach DIN 2448 613304, Stahlrohr nach DIN 2448
In: 1. Obergeschoss
Type - Material: IfcSurfaceStyle #9317
Type - Andere - Kategorie: Allgemeines Modell; Familienname: Stahlrohr nach DIN 2448 613304
Type - ID-Daten - Typname: Stahlrohr nach DIN 2448 613304
Type - IFC-Parameter - Typ in IFC-Datei exportieren: Vorgabe
Description: Stahlrohr nach DIN 2448
Pset_DistributionFlowElementCommon - Reference: Stahlrohr nach DIN 2448 613304; sets with these values: 2
Andere - Typ: Stahlrohr nach DIN 2448 613304; Familie: Stahlrohr nach DIN 2448 613304; Familie und Typ: Stahlrohr nach DIN 2448 613304: Stahlrohr nach DIN 2448 613304; Typ-ID: 2537640
Abhängigkeiten - Höhe von Ebene: 0 m; Verschieben mit umliegenden Elementen: no
Bemaßungen - Fläche: 0.024685 m2; Volumen: 0.00283971 m3
IFC-Parameter - In IFC-Datei exportieren: Nach Typ; Pset MEP.Geom-DN: 200; Pset MEP.Tech-Insulation thickness (mm): 100; In IFC exportieren als: ifcflowsegment; NameOverride: Stahlrohr nach DIN 2448; IfcPresentationLayer: 0-TFT-H_Vorlauf; ObjectTypeOverride: Stahlrohr nach DIN 2448; Pset MEP.Name: Stahlrohr nach DIN 2448; IfcDescription: Stahlrohr nach DIN 2448; Pset MEP.Geom-Outer Ø (mm): 219.1; Pset MEP.Tech-Material: Stahlrohr nach DIN 2448; Pset MEP.Geom-Length (mm): 24.7493
Phasen - Phase erstellt: Phase 01

# IfcFlowSegment: Stahlrohr nach DIN 2448 614313:Stahlrohr nach DIN 2448 614313, Stahlrohr nach DIN 2448
In: Erdgeschoss
Type - Material: IfcSurfaceStyle #1741
Type - Andere - Kategorie: Allgemeines Modell; Familienname: Stahlrohr nach DIN 2448 614313
Type - ID-Daten - Typname: Stahlrohr nach DIN 2448 614313
Type - IFC-Parameter - Typ in IFC-Datei exportieren: Vorgabe
Description: Stahlrohr nach DIN 2448
Pset_DistributionFlowElementCommon - Reference: Stahlrohr nach DIN 2448 614313; sets with these values: 2
Andere - Typ: Stahlrohr nach DIN 2448 614313; Familie: Stahlrohr nach DIN 2448 614313; Familie und Typ: Stahlrohr nach DIN 2448 614313: Stahlrohr nach DIN 2448 614313; Typ-ID: 2537675
Abhängigkeiten - Höhe von Ebene: 0 m; Verschieben mit umliegenden Elementen: no
Bemaßungen - Fläche: 0.435094 m2; Volumen: 0.0436441 m3
IFC-Parameter - In IFC-Datei exportieren: Nach Typ; Pset MEP.Tech-Insulation thickness (mm): 100; Pset MEP.Geom-DN: 150; In IFC exportieren als: ifcflowsegment; NameOverride: Stahlrohr nach DIN 2448; IfcPresentationLayer: 0-TFT-H_Ruecklauf; ObjectTypeOverride: Stahlrohr nach DIN 2448; Pset MEP.Name: Stahlrohr nach DIN 2448; IfcDescription: Stahlrohr nach DIN 2448; Pset MEP.Geom-Outer Ø (mm): 168.3; Pset MEP.Tech-Material: Stahlrohr nach DIN 2448; Pset MEP.Geom-Length (mm): 518.823
Phasen - Phase erstellt: Phase 01

# IfcFlowSegment: Stahlrohr nach DIN 2448 614359:Stahlrohr nach DIN 2448 614359, Stahlrohr nach DIN 2448
In: Erdgeschoss
Type - Material: IfcSurfaceStyle #1741
Type - Andere - Kategorie: Allgemeines Modell; Familienname: Stahlrohr nach DIN 2448 614359
Type - ID-Daten - Typname: Stahlrohr nach DIN 2448 614359
Type - IFC-Parameter - Typ in IFC-Datei exportieren: Vorgabe
Description: Stahlrohr nach DIN 2448
Pset_DistributionFlowElementCommon - Reference: Stahlrohr nach DIN 2448 614359; sets with these values: 2
Andere - Typ: Stahlrohr nach DIN 2448 614359; Familie: Stahlrohr nach DIN 2448 614359; Familie und Typ: Stahlrohr nach DIN 2448 614359: Stahlrohr nach DIN 2448 614359; Typ-ID: 2537689
Abhängigkeiten - Höhe von Ebene: 0 m; Verschieben mit umliegenden Elementen: no
Bemaßungen - Fläche: 0.419308 m2; Volumen: 0.0420607 m3
IFC-Parameter - In IFC-Datei exportieren: Nach Typ; Pset MEP.Tech-Insulation thickness (mm): 100; Pset MEP.Geom-DN: 150; Pset MEP.Geom-Length (mm): 500; In IFC exportieren als: ifcflowsegment; NameOverride: Stahlrohr nach DIN 2448; IfcPresentationLayer: 0-TFT-H_Ruecklauf; ObjectTypeOverride: Stahlrohr nach DIN 2448; Pset MEP.Name: Stahlrohr nach DIN 2448; IfcDescription: Stahlrohr nach DIN 2448; Pset MEP.Geom-Outer Ø (mm): 168.3; Pset MEP.Tech-Material: Stahlrohr nach DIN 2448
Phasen - Phase erstellt: Phase 01

# IfcFlowSegment: Stahlrohr nach DIN 2448 614382:Stahlrohr nach DIN 2448 614382, Stahlrohr nach DIN 2448
In: 1. Obergeschoss
Type - Material: IfcSurfaceStyle #1741
Type - Andere - Kategorie: Allgemeines Modell; Familienname: Stahlrohr nach DIN 2448 614382
Type - ID-Daten - Typname: Stahlrohr nach DIN 2448 614382
Type - IFC-Parameter - Typ in IFC-Datei exportieren: Vorgabe
Description: Stahlrohr nach DIN 2448
Pset_DistributionFlowElementCommon - Reference: Stahlrohr nach DIN 2448 614382; sets with these values: 2
Andere - Typ: Stahlrohr nach DIN 2448 614382; Familie: Stahlrohr nach DIN 2448 614382; Familie und Typ: Stahlrohr nach DIN 2448 614382: Stahlrohr nach DIN 2448 614382; Typ-ID: 2537696
Abhängigkeiten - Höhe von Ebene: 0 m; Verschieben mit umliegenden Elementen: no
Bemaßungen - Fläche: 0.160003 m2; Volumen: 0.0137068 m3
IFC-Parameter - In IFC-Datei exportieren: Nach Typ; Pset MEP.Tech-Insulation thickness (mm): 100; Pset MEP.Geom-DN: 100; In IFC exportieren als: ifcflowsegment; NameOverride: Stahlrohr nach DIN 2448; IfcPresentationLayer: 0-TFT-H_Ruecklauf; ObjectTypeOverride: Stahlrohr nach DIN 2448; Pset MEP.Name: Stahlrohr nach DIN 2448; IfcDescription: Stahlrohr nach DIN 2448; Pset MEP.Geom-Outer Ø (mm): 114.3; Pset MEP.Tech-Material: Stahlrohr nach DIN 2448; Pset MEP.Geom-Length (mm): 238.87
Phasen - Phase erstellt: Phase 01

# IfcFlowSegment: Stahlrohr nach DIN 2448 614582:Stahlrohr nach DIN 2448 614582, Stahlrohr nach DIN 2448
In: 1. Obergeschoss
Type - Material: IfcSurfaceStyle #1741
Type - Andere - Kategorie: Allgemeines Modell; Familienname: Stahlrohr nach DIN 2448 614582
Type - ID-Daten - Typname: Stahlrohr nach DIN 2448 614582
Type - IFC-Parameter - Typ in IFC-Datei exportieren: Vorgabe
Description: Stahlrohr nach DIN 2448
Pset_DistributionFlowElementCommon - Reference: Stahlrohr nach DIN 2448 614582; sets with these values: 2
Andere - Typ: Stahlrohr nach DIN 2448 614582; Familie: Stahlrohr nach DIN 2448 614582; Familie und Typ: Stahlrohr nach DIN 2448 614582: Stahlrohr nach DIN 2448 614582; Typ-ID: 2537752
Abhängigkeiten - Höhe von Ebene: 0 m; Verschieben mit umliegenden Elementen: no
Bemaßungen - Fläche: 0.414959 m2; Volumen: 0.0416245 m3
IFC-Parameter - In IFC-Datei exportieren: Nach Typ; Pset MEP.Tech-Insulation thickness (mm): 100; Pset MEP.Geom-DN: 150; In IFC exportieren als: ifcflowsegment; NameOverride: Stahlrohr nach DIN 2448; IfcPresentationLayer: 0-TFT-H_Ruecklauf; ObjectTypeOverride: Stahlrohr nach DIN 2448; Pset MEP.Name: Stahlrohr nach DIN 2448; IfcDescription: Stahlrohr nach DIN 2448; Pset MEP.Geom-Outer Ø (mm): 168.3; Pset MEP.Tech-Material: Stahlrohr nach DIN 2448; Pset MEP.Geom-Length (mm): 494.814
Phasen - Phase erstellt: Phase 01

# IfcFlowSegment: Stahlrohr nach DIN 2448 614628:Stahlrohr nach DIN 2448 614628, Stahlrohr nach DIN 2448
In: 1. Obergeschoss
Type - Material: IfcSurfaceStyle #1741
Type - Andere - Kategorie: Allgemeines Modell; Familienname: Stahlrohr nach DIN 2448 614628
Type - ID-Daten - Typname: Stahlrohr nach DIN 2448 614628
Type - IFC-Parameter - Typ in IFC-Datei exportieren: Vorgabe
Description: Stahlrohr nach DIN 2448
Pset_DistributionFlowElementCommon - Reference: Stahlrohr nach DIN 2448 614628; sets with these values: 2
Andere - Typ: Stahlrohr nach DIN 2448 614628; Familie: Stahlrohr nach DIN 2448 614628; Familie und Typ: Stahlrohr nach DIN 2448 614628: Stahlrohr nach DIN 2448 614628; Typ-ID: 2537766
Abhängigkeiten - Höhe von Ebene: 0 m; Verschieben mit umliegenden Elementen: no
Bemaßungen - Fläche: 0.199853 m2; Volumen: 0.0200473 m3
IFC-Parameter - In IFC-Datei exportieren: Nach Typ; Pset MEP.Tech-Insulation thickness (mm): 100; Pset MEP.Geom-DN: 150; In IFC exportieren als: ifcflowsegment; NameOverride: Stahlrohr nach DIN 2448; IfcPresentationLayer: 0-TFT-H_Ruecklauf; ObjectTypeOverride: Stahlrohr nach DIN 2448; Pset MEP.Name: Stahlrohr nach DIN 2448; IfcDescription: Stahlrohr nach DIN 2448; Pset MEP.Geom-Outer Ø (mm): 168.3; Pset MEP.Tech-Material: Stahlrohr nach DIN 2448; Pset MEP.Geom-Length (mm): 238.313
Phasen - Phase erstellt: Phase 01

# IfcFlowSegment: Stahlrohr nach DIN 2448 614697:Stahlrohr nach DIN 2448 614697, Stahlrohr nach DIN 2448
In: 1. Obergeschoss
Type - Material: IfcSurfaceStyle #1741
Type - Andere - Kategorie: Allgemeines Modell; Familienname: Stahlrohr nach DIN 2448 614697
Type - ID-Daten - Typname: Stahlrohr nach DIN 2448 614697
Type - IFC-Parameter - Typ in IFC-Datei exportieren: Vorgabe
Description: Stahlrohr nach DIN 2448
Pset_DistributionFlowElementCommon - Reference: Stahlrohr nach DIN 2448 614697; sets with these values: 2
Andere - Typ: Stahlrohr nach DIN 2448 614697; Familie: Stahlrohr nach DIN 2448 614697; Familie und Typ: Stahlrohr nach DIN 2448 614697: Stahlrohr nach DIN 2448 614697; Typ-ID: 2537787
Abhängigkeiten - Höhe von Ebene: 0 m; Verschieben mit umliegenden Elementen: no
Bemaßungen - Fläche: 1.9938 m2; Volumen: 0.229363 m3
IFC-Parameter - In IFC-Datei exportieren: Nach Typ; Pset MEP.Geom-DN: 200; Pset MEP.Tech-Insulation thickness (mm): 100; In IFC exportieren als: ifcflowsegment; NameOverride: Stahlrohr nach DIN 2448; IfcPresentationLayer: 0-TFT-H_Ruecklauf; ObjectTypeOverride: Stahlrohr nach DIN 2448; Pset MEP.Name: Stahlrohr nach DIN 2448; IfcDescription: Stahlrohr nach DIN 2448; Pset MEP.Geom-Outer Ø (mm): 219.1; Pset MEP.Tech-Material: Stahlrohr nach DIN 2448; Pset MEP.Geom-Length (mm): 1999
Phasen - Phase erstellt: Phase 01

# IfcFlowSegment: Stahlrohr nach DIN 2448 614743:Stahlrohr nach DIN 2448 614743, Stahlrohr nach DIN 2448
In: 1. Obergeschoss
Type - Material: IfcSurfaceStyle #1741
Type - Andere - Kategorie: Allgemeines Modell; Familienname: Stahlrohr nach DIN 2448 614743
Type - ID-Daten - Typname: Stahlrohr nach DIN 2448 614743
Type - IFC-Parameter - Typ in IFC-Datei exportieren: Vorgabe
Description: Stahlrohr nach DIN 2448
Pset_DistributionFlowElementCommon - Reference: Stahlrohr nach DIN 2448 614743; sets with these values: 2
Andere - Typ: Stahlrohr nach DIN 2448 614743; Familie: Stahlrohr nach DIN 2448 614743; Familie und Typ: Stahlrohr nach DIN 2448 614743: Stahlrohr nach DIN 2448 614743; Typ-ID: 2537801
Abhängigkeiten - Höhe von Ebene: 0 m; Verschieben mit umliegenden Elementen: no
Bemaßungen - Fläche: 2.61625 m2; Volumen: 0.300968 m3
IFC-Parameter - In IFC-Datei exportieren: Nach Typ; Pset MEP.Geom-DN: 200; Pset MEP.Tech-Insulation thickness (mm): 100; In IFC exportieren als: ifcflowsegment; NameOverride: Stahlrohr nach DIN 2448; IfcPresentationLayer: 0-TFT-H_Ruecklauf; ObjectTypeOverride: Stahlrohr nach DIN 2448; Pset MEP.Name: Stahlrohr nach DIN 2448; IfcDescription: Stahlrohr nach DIN 2448; Pset MEP.Geom-Outer Ø (mm): 219.1; Pset MEP.Tech-Material: Stahlrohr nach DIN 2448; Pset MEP.Geom-Length (mm): 2623.07
Phasen - Phase erstellt: Phase 01

# IfcFlowSegment: Stahlrohr nach DIN 2448 615024:Stahlrohr nach DIN 2448 615024, Stahlrohr nach DIN 2448
In: 1. Obergeschoss
Type - Material: IfcSurfaceStyle #1741
Type - Andere - Kategorie: Allgemeines Modell; Familienname: Stahlrohr nach DIN 2448 615024
Type - ID-Daten - Typname: Stahlrohr nach DIN 2448 615024
Type - IFC-Parameter - Typ in IFC-Datei exportieren: Vorgabe
Description: Stahlrohr nach DIN 2448
Pset_DistributionFlowElementCommon - Reference: Stahlrohr nach DIN 2448 615024; sets with these values: 2
Andere - Typ: Stahlrohr nach DIN 2448 615024; Familie: Stahlrohr nach DIN 2448 615024; Familie und Typ: Stahlrohr nach DIN 2448 615024: Stahlrohr nach DIN 2448 615024; Typ-ID: 2537808
Abhängigkeiten - Höhe von Ebene: 0 m; Verschieben mit umliegenden Elementen: no
Bemaßungen - Fläche: 1.4567 m2; Volumen: 0.167575 m3
IFC-Parameter - In IFC-Datei exportieren: Nach Typ; Pset MEP.Geom-DN: 200; Pset MEP.Tech-Insulation thickness (mm): 100; In IFC exportieren als: ifcflowsegment; NameOverride: Stahlrohr nach DIN 2448; IfcPresentationLayer: 0-TFT-H_Ruecklauf; ObjectTypeOverride: Stahlrohr nach DIN 2448; Pset MEP.Name: Stahlrohr nach DIN 2448; IfcDescription: Stahlrohr nach DIN 2448; Pset MEP.Geom-Outer Ø (mm): 219.1; Pset MEP.Tech-Material: Stahlrohr nach DIN 2448; Pset MEP.Geom-Length (mm): 1460.49
Phasen - Phase erstellt: Phase 01

# IfcFlowSegment: Stahlrohr nach DIN 2448 615305:Stahlrohr nach DIN 2448 615305, Stahlrohr nach DIN 2448
In: Erdgeschoss
Type - Material: IfcSurfaceStyle #352577
Type - Andere - Kategorie: Allgemeines Modell; Familienname: Stahlrohr nach DIN 2448 615305
Type - ID-Daten - Typname: Stahlrohr nach DIN 2448 615305
Type - IFC-Parameter - Typ in IFC-Datei exportieren: Vorgabe
Description: Stahlrohr nach DIN 2448
Pset_DistributionFlowElementCommon - Reference: Stahlrohr nach DIN 2448 615305; sets with these values: 2
Andere - Typ: Stahlrohr nach DIN 2448 615305; Familie: Stahlrohr nach DIN 2448 615305; Familie und Typ: Stahlrohr nach DIN 2448 615305: Stahlrohr nach DIN 2448 615305; Typ-ID: 2537815
Abhängigkeiten - Höhe von Ebene: 0 m; Verschieben mit umliegenden Elementen: no
Bemaßungen - Fläche: 0.268251 m2; Volumen: 0.0100651 m3
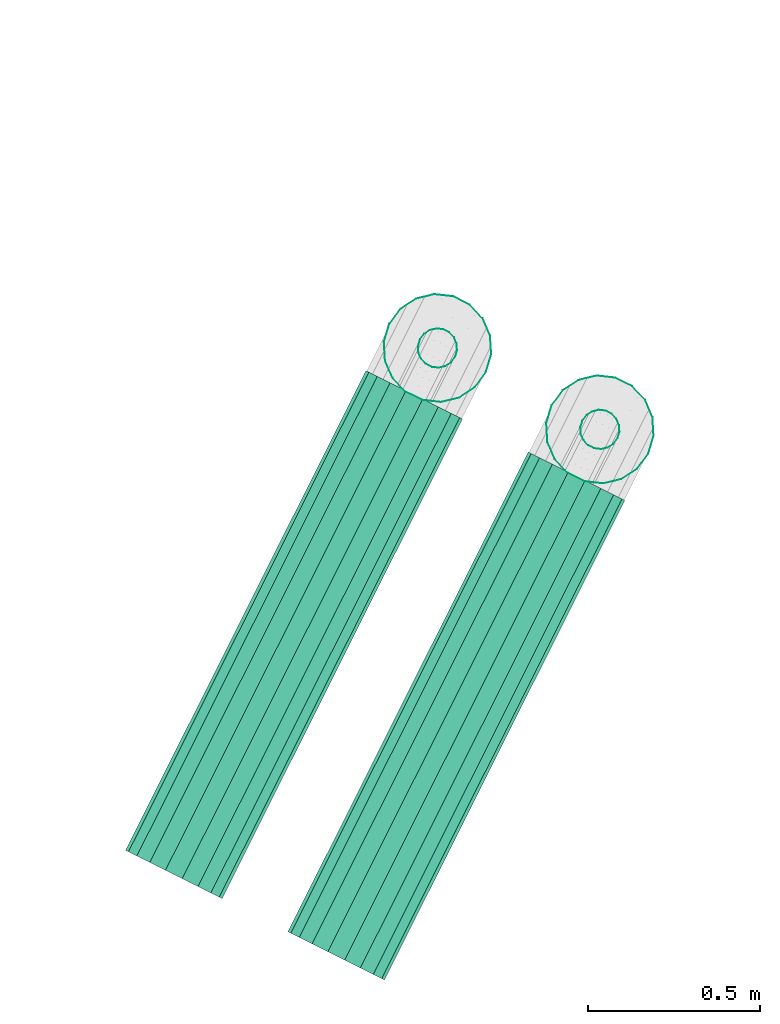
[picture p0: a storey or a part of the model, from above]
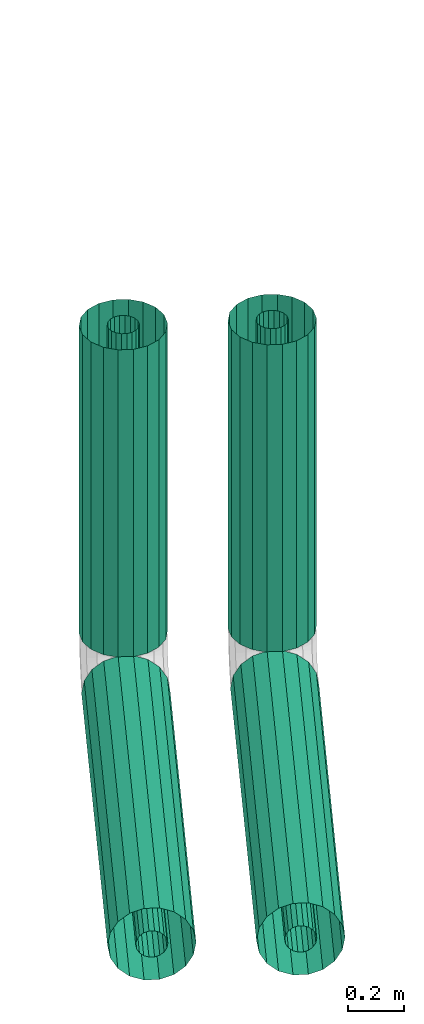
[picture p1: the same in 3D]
Properties of the parts of a building model (IFC2X3), part 21 of 23

# IfcFlowSegment: Stahlrohr nach DIN 2448 615305:Stahlrohr nach DIN 2448 615305, Stahlrohr nach DIN 2448
IFC-Parameter - In IFC-Datei exportieren: Nach Typ; Pset MEP.Geom-DN: 100; In IFC exportieren als: ifcflowsegment; NameOverride: Stahlrohr nach DIN 2448; IfcPresentationLayer: S_Gas; ObjectTypeOverride: Stahlrohr nach DIN 2448; Pset MEP.Name: Stahlrohr nach DIN 2448; IfcDescription: Stahlrohr nach DIN 2448; Pset MEP.Geom-Outer Ø (mm): 114.3; Pset MEP.Tech-Material: Stahlrohr nach DIN 2448; Pset MEP.Geom-Length (mm): 1501.7
Phasen - Phase erstellt: Phase 01

# IfcFlowSegment: Stahlrohr nach DIN 2448 617611:Stahlrohr nach DIN 2448 617611, Stahlrohr nach DIN 2448
In: Erdgeschoss
Type - Material: IfcSurfaceStyle #352577
Type - Andere - Kategorie: Allgemeines Modell; Familienname: Stahlrohr nach DIN 2448 617611
Type - ID-Daten - Typname: Stahlrohr nach DIN 2448 617611
Type - IFC-Parameter - Typ in IFC-Datei exportieren: Vorgabe
Description: Stahlrohr nach DIN 2448
Pset_DistributionFlowElementCommon - Reference: Stahlrohr nach DIN 2448 617611; sets with these values: 2
Andere - Typ: Stahlrohr nach DIN 2448 617611; Familie: Stahlrohr nach DIN 2448 617611; Familie und Typ: Stahlrohr nach DIN 2448 617611: Stahlrohr nach DIN 2448 617611; Typ-ID: 2537836
Abhängigkeiten - Höhe von Ebene: 0 m; Verschieben mit umliegenden Elementen: no
Bemaßungen - Fläche: 0.0614284 m2; Volumen: 0.000854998 m3
IFC-Parameter - In IFC-Datei exportieren: Nach Typ; Pset MEP.Geom-DN: 32; In IFC exportieren als: ifcflowsegment; NameOverride: Stahlrohr nach DIN 2448; IfcPresentationLayer: S_Gas; ObjectTypeOverride: Stahlrohr nach DIN 2448; Pset MEP.Name: Stahlrohr nach DIN 2448; IfcDescription: Stahlrohr nach DIN 2448; Pset MEP.Geom-Outer Ø (mm): 42.4; Pset MEP.Tech-Material: Stahlrohr nach DIN 2448; Pset MEP.Geom-Length (mm): 927.023
Phasen - Phase erstellt: Phase 01

# IfcFlowSegment: Stahlrohr nach DIN 2448 617789:Stahlrohr nach DIN 2448 617789, Stahlrohr nach DIN 2448
In: Erdgeschoss
Type - Material: IfcSurfaceStyle #352577
Type - Andere - Kategorie: Allgemeines Modell; Familienname: Stahlrohr nach DIN 2448 617789
Type - ID-Daten - Typname: Stahlrohr nach DIN 2448 617789
Type - IFC-Parameter - Typ in IFC-Datei exportieren: Vorgabe
Description: Stahlrohr nach DIN 2448
Pset_DistributionFlowElementCommon - Reference: Stahlrohr nach DIN 2448 617789; sets with these values: 2
Andere - Typ: Stahlrohr nach DIN 2448 617789; Familie: Stahlrohr nach DIN 2448 617789; Familie und Typ: Stahlrohr nach DIN 2448 617789: Stahlrohr nach DIN 2448 617789; Typ-ID: 2537850
Abhängigkeiten - Höhe von Ebene: 0 m; Verschieben mit umliegenden Elementen: no
Bemaßungen - Fläche: 0.0155822 m2; Volumen: 0.000216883 m3
IFC-Parameter - In IFC-Datei exportieren: Nach Typ; Pset MEP.Geom-DN: 32; In IFC exportieren als: ifcflowsegment; NameOverride: Stahlrohr nach DIN 2448; IfcPresentationLayer: S_Gas; ObjectTypeOverride: Stahlrohr nach DIN 2448; Pset MEP.Name: Stahlrohr nach DIN 2448; IfcDescription: Stahlrohr nach DIN 2448; Pset MEP.Geom-Outer Ø (mm): 42.4; Pset MEP.Tech-Material: Stahlrohr nach DIN 2448; Pset MEP.Geom-Length (mm): 235.153
Phasen - Phase erstellt: Phase 01

# IfcFlowSegment: Stahlrohr nach DIN 2448 618509:Stahlrohr nach DIN 2448 618509, Stahlrohr nach DIN 2448
In: Erdgeschoss
Type - Material: IfcSurfaceStyle #352577
Type - Andere - Kategorie: Allgemeines Modell; Familienname: Stahlrohr nach DIN 2448 618509
Type - ID-Daten - Typname: Stahlrohr nach DIN 2448 618509
Type - IFC-Parameter - Typ in IFC-Datei exportieren: Vorgabe
Description: Stahlrohr nach DIN 2448
Pset_DistributionFlowElementCommon - Reference: Stahlrohr nach DIN 2448 618509; sets with these values: 2
Andere - Typ: Stahlrohr nach DIN 2448 618509; Familie: Stahlrohr nach DIN 2448 618509; Familie und Typ: Stahlrohr nach DIN 2448 618509: Stahlrohr nach DIN 2448 618509; Typ-ID: 2537864
Abhängigkeiten - Höhe von Ebene: 0 m; Verschieben mit umliegenden Elementen: no
Bemaßungen - Fläche: 0.299311 m2; Volumen: 0.0112305 m3
IFC-Parameter - In IFC-Datei exportieren: Nach Typ; Pset MEP.Geom-DN: 100; In IFC exportieren als: ifcflowsegment; NameOverride: Stahlrohr nach DIN 2448; IfcPresentationLayer: S_Gas; ObjectTypeOverride: Stahlrohr nach DIN 2448; Pset MEP.Name: Stahlrohr nach DIN 2448; IfcDescription: Stahlrohr nach DIN 2448; Pset MEP.Geom-Outer Ø (mm): 114.3; Pset MEP.Tech-Material: Stahlrohr nach DIN 2448; Pset MEP.Geom-Length (mm): 1675.57
Phasen - Phase erstellt: Phase 01

# IfcFlowSegment: Stahlrohr nach DIN 2448 623365:Stahlrohr nach DIN 2448 623365, Stahlrohr nach DIN 2448
In: 1. Obergeschoss
Type - Material: IfcSurfaceStyle #1741
Type - Andere - Kategorie: Allgemeines Modell; Familienname: Stahlrohr nach DIN 2448 623365
Type - ID-Daten - Typname: Stahlrohr nach DIN 2448 623365
Type - IFC-Parameter - Typ in IFC-Datei exportieren: Vorgabe
Description: Stahlrohr nach DIN 2448
Pset_DistributionFlowElementCommon - Reference: Stahlrohr nach DIN 2448 623365; sets with these values: 2
Andere - Typ: Stahlrohr nach DIN 2448 623365; Familie: Stahlrohr nach DIN 2448 623365; Familie und Typ: Stahlrohr nach DIN 2448 623365: Stahlrohr nach DIN 2448 623365; Typ-ID: 2538259
Abhängigkeiten - Höhe von Ebene: 0 m; Verschieben mit umliegenden Elementen: no
Bemaßungen - Fläche: 0.54285 m2; Volumen: 0.0299912 m3
IFC-Parameter - In IFC-Datei exportieren: Nach Typ; Pset MEP.Tech-Insulation thickness (mm): 100; Pset MEP.Geom-DN: 150; In IFC exportieren als: ifcflowsegment; NameOverride: Stahlrohr nach DIN 2448; IfcPresentationLayer: 0-TFT-H_Ruecklauf; ObjectTypeOverride: Stahlrohr nach DIN 2448; Pset MEP.Name: Stahlrohr nach DIN 2448; IfcDescription: Stahlrohr nach DIN 2448; Pset MEP.Geom-Outer Ø (mm): 168.3; Pset MEP.Tech-Material: Stahlrohr nach DIN 2448; Pset MEP.Geom-Length (mm): 2063.87
Phasen - Phase erstellt: Phase 01

# IfcFlowSegment: Stahlrohr nach DIN 2448 848518:Stahlrohr nach DIN 2448 848518, Stahlrohr nach DIN 2448
In: Erdgeschoss
Type - Material: IfcSurfaceStyle #9317
Type - Andere - Kategorie: Allgemeines Modell; Familienname: Stahlrohr nach DIN 2448 848518
Type - ID-Daten - Typname: Stahlrohr nach DIN 2448 848518
Type - IFC-Parameter - Typ in IFC-Datei exportieren: Vorgabe
Description: Stahlrohr nach DIN 2448
Pset_DistributionFlowElementCommon - Reference: Stahlrohr nach DIN 2448 848518; sets with these values: 2
Andere - Typ: Stahlrohr nach DIN 2448 848518; Familie: Stahlrohr nach DIN 2448 848518; Familie und Typ: Stahlrohr nach DIN 2448 848518: Stahlrohr nach DIN 2448 848518; Typ-ID: 2539015
Abhängigkeiten - Höhe von Ebene: 0 m; Verschieben mit umliegenden Elementen: no
Bemaßungen - Fläche: 0.121613 m2; Volumen: 0.00671882 m3
IFC-Parameter - In IFC-Datei exportieren: Nach Typ; Pset MEP.Tech-Insulation thickness (mm): 100; Pset MEP.Geom-DN: 150; In IFC exportieren als: ifcflowsegment; NameOverride: Stahlrohr nach DIN 2448; IfcPresentationLayer: 0-TFT-H_Vorlauf; ObjectTypeOverride: Stahlrohr nach DIN 2448; Pset MEP.Name: Stahlrohr nach DIN 2448; IfcDescription: Stahlrohr nach DIN 2448; Pset MEP.Geom-Outer Ø (mm): 168.3; Pset MEP.Tech-Material: Stahlrohr nach DIN 2448; Pset MEP.Geom-Length (mm): 462.361
Phasen - Phase erstellt: Phase 01

# IfcFlowSegment: Stahlrohr nach DIN 2448 848673:Stahlrohr nach DIN 2448 848673, Stahlrohr nach DIN 2448
In: Erdgeschoss
Type - Material: IfcSurfaceStyle #9317
Type - Andere - Kategorie: Allgemeines Modell; Familienname: Stahlrohr nach DIN 2448 848673
Type - ID-Daten - Typname: Stahlrohr nach DIN 2448 848673
Type - IFC-Parameter - Typ in IFC-Datei exportieren: Vorgabe
Description: Stahlrohr nach DIN 2448
Pset_DistributionFlowElementCommon - Reference: Stahlrohr nach DIN 2448 848673; sets with these values: 2
Andere - Typ: Stahlrohr nach DIN 2448 848673; Familie: Stahlrohr nach DIN 2448 848673; Familie und Typ: Stahlrohr nach DIN 2448 848673: Stahlrohr nach DIN 2448 848673; Typ-ID: 2539022
Abhängigkeiten - Höhe von Ebene: 0 m; Verschieben mit umliegenden Elementen: no
Bemaßungen - Fläche: 1.68467 m2; Volumen: 0.168989 m3
IFC-Parameter - In IFC-Datei exportieren: Nach Typ; Pset MEP.Tech-Insulation thickness (mm): 100; Pset MEP.Geom-DN: 150; In IFC exportieren als: ifcflowsegment; NameOverride: Stahlrohr nach DIN 2448; IfcPresentationLayer: 0-TFT-H_Vorlauf; ObjectTypeOverride: Stahlrohr nach DIN 2448; Pset MEP.Name: Stahlrohr nach DIN 2448; IfcDescription: Stahlrohr nach DIN 2448; Pset MEP.Geom-Outer Ø (mm): 168.3; Pset MEP.Tech-Material: Stahlrohr nach DIN 2448; Pset MEP.Geom-Length (mm): 2008.87
Phasen - Phase erstellt: Phase 01

# IfcFlowSegment: Stahlrohr nach DIN 2448 849145:Stahlrohr nach DIN 2448 849145, Stahlrohr nach DIN 2448
In: Erdgeschoss
Type - Material: IfcSurfaceStyle #352577
Type - Andere - Kategorie: Allgemeines Modell; Familienname: Stahlrohr nach DIN 2448 849145
Type - ID-Daten - Typname: Stahlrohr nach DIN 2448 849145
Type - IFC-Parameter - Typ in IFC-Datei exportieren: Vorgabe
Description: Stahlrohr nach DIN 2448
Pset_DistributionFlowElementCommon - Reference: Stahlrohr nach DIN 2448 849145; sets with these values: 2
Andere - Typ: Stahlrohr nach DIN 2448 849145; Familie: Stahlrohr nach DIN 2448 849145; Familie und Typ: Stahlrohr nach DIN 2448 849145: Stahlrohr nach DIN 2448 849145; Typ-ID: 2539036
Abhängigkeiten - Höhe von Ebene: 0 m; Verschieben mit umliegenden Elementen: no
Bemaßungen - Fläche: 0.213788 m2; Volumen: 0.00802159 m3
IFC-Parameter - In IFC-Datei exportieren: Nach Typ; Pset MEP.Geom-DN: 100; In IFC exportieren als: ifcflowsegment; NameOverride: Stahlrohr nach DIN 2448; IfcPresentationLayer: S_Gas; ObjectTypeOverride: Stahlrohr nach DIN 2448; Pset MEP.Name: Stahlrohr nach DIN 2448; IfcDescription: Stahlrohr nach DIN 2448; Pset MEP.Geom-Outer Ø (mm): 114.3; Pset MEP.Tech-Material: Stahlrohr nach DIN 2448; Pset MEP.Geom-Length (mm): 1196.81
Phasen - Phase erstellt: Phase 01

# IfcFlowSegment: Stahlrohr nach DIN 2448 849323:Stahlrohr nach DIN 2448 849323, Stahlrohr nach DIN 2448
In: Erdgeschoss
Type - Material: IfcSurfaceStyle #352577
Type - Andere - Kategorie: Allgemeines Modell; Familienname: Stahlrohr nach DIN 2448 849323
Type - ID-Daten - Typname: Stahlrohr nach DIN 2448 849323
Type - IFC-Parameter - Typ in IFC-Datei exportieren: Vorgabe
Description: Stahlrohr nach DIN 2448
Pset_DistributionFlowElementCommon - Reference: Stahlrohr nach DIN 2448 849323; sets with these values: 2
Andere - Typ: Stahlrohr nach DIN 2448 849323; Familie: Stahlrohr nach DIN 2448 849323; Familie und Typ: Stahlrohr nach DIN 2448 849323: Stahlrohr nach DIN 2448 849323; Typ-ID: 2539050
Abhängigkeiten - Höhe von Ebene: 0 m; Verschieben mit umliegenden Elementen: no
Bemaßungen - Fläche: 0.246664 m2; Volumen: 0.00616199 m3
IFC-Parameter - In IFC-Datei exportieren: Nach Typ; Pset MEP.Geom-DN: 65; In IFC exportieren als: ifcflowsegment; NameOverride: Stahlrohr nach DIN 2448; IfcPresentationLayer: S_Gas; ObjectTypeOverride: Stahlrohr nach DIN 2448; Pset MEP.Name: Stahlrohr nach DIN 2448; IfcDescription: Stahlrohr nach DIN 2448; Pset MEP.Geom-Outer Ø (mm): 76.1; Pset MEP.Tech-Material: Stahlrohr nach DIN 2448; Pset MEP.Geom-Length (mm): 2074
Phasen - Phase erstellt: Phase 01

# IfcFlowSegment: Stahlrohr nach DIN 2448 852532:Stahlrohr nach DIN 2448 852532, Stahlrohr nach DIN 2448
In: 1. Untergeschoss
Type - Material: IfcSurfaceStyle #9317
Type - Andere - Kategorie: Allgemeines Modell; Familienname: Stahlrohr nach DIN 2448 852532
Type - ID-Daten - Typname: Stahlrohr nach DIN 2448 852532
Type - IFC-Parameter - Typ in IFC-Datei exportieren: Vorgabe
Description: Stahlrohr nach DIN 2448
Pset_DistributionFlowElementCommon - Reference: Stahlrohr nach DIN 2448 852532; sets with these values: 2
Andere - Typ: Stahlrohr nach DIN 2448 852532; Familie: Stahlrohr nach DIN 2448 852532; Familie und Typ: Stahlrohr nach DIN 2448 852532: Stahlrohr nach DIN 2448 852532; Typ-ID: 2539499
Abhängigkeiten - Höhe von Ebene: 0 m; Verschieben mit umliegenden Elementen: no
Bemaßungen - Fläche: 0.717852 m2; Volumen: 0.0825803 m3
IFC-Parameter - In IFC-Datei exportieren: Nach Typ; Pset MEP.Geom-DN: 200; Pset MEP.Tech-Insulation thickness (mm): 100; In IFC exportieren als: ifcflowsegment; NameOverride: Stahlrohr nach DIN 2448; IfcPresentationLayer: 0-TFT-H_Vorlauf; ObjectTypeOverride: Stahlrohr nach DIN 2448; Pset MEP.Name: Stahlrohr nach DIN 2448; IfcDescription: Stahlrohr nach DIN 2448; Pset MEP.Geom-Outer Ø (mm): 219.1; Pset MEP.Tech-Material: Stahlrohr nach DIN 2448; Pset MEP.Geom-Length (mm): 719.723
Phasen - Phase erstellt: Phase 01

# IfcFlowSegment: Stahlrohr nach DIN 2448 852836:Stahlrohr nach DIN 2448 852836, Stahlrohr nach DIN 2448
In: 1. Untergeschoss
Type - Material: IfcSurfaceStyle #1741
Type - Andere - Kategorie: Allgemeines Modell; Familienname: Stahlrohr nach DIN 2448 852836
Type - ID-Daten - Typname: Stahlrohr nach DIN 2448 852836
Type - IFC-Parameter - Typ in IFC-Datei exportieren: Vorgabe
Description: Stahlrohr nach DIN 2448
Pset_DistributionFlowElementCommon - Reference: Stahlrohr nach DIN 2448 852836; sets with these values: 2
Andere - Typ: Stahlrohr nach DIN 2448 852836; Familie: Stahlrohr nach DIN 2448 852836; Familie und Typ: Stahlrohr nach DIN 2448 852836: Stahlrohr nach DIN 2448 852836; Typ-ID: 2539513
Abhängigkeiten - Höhe von Ebene: 0 m; Verschieben mit umliegenden Elementen: no
Bemaßungen - Fläche: 0.717852 m2; Volumen: 0.0825803 m3
IFC-Parameter - In IFC-Datei exportieren: Nach Typ; Pset MEP.Geom-DN: 200; Pset MEP.Tech-Insulation thickness (mm): 100; In IFC exportieren als: ifcflowsegment; NameOverride: Stahlrohr nach DIN 2448; IfcPresentationLayer: 0-TFT-H_Ruecklauf; ObjectTypeOverride: Stahlrohr nach DIN 2448; Pset MEP.Name: Stahlrohr nach DIN 2448; IfcDescription: Stahlrohr nach DIN 2448; Pset MEP.Geom-Outer Ø (mm): 219.1; Pset MEP.Tech-Material: Stahlrohr nach DIN 2448; Pset MEP.Geom-Length (mm): 719.723
Phasen - Phase erstellt: Phase 01

# IfcFlowSegment: Stahlrohr nach DIN 2448 860225:Stahlrohr nach DIN 2448 860225, Stahlrohr nach DIN 2448
In: 1. Untergeschoss
Type - Material: IfcSurfaceStyle #1741
Type - Andere - Kategorie: Allgemeines Modell; Familienname: Stahlrohr nach DIN 2448 860225
Type - ID-Daten - Typname: Stahlrohr nach DIN 2448 860225
Type - IFC-Parameter - Typ in IFC-Datei exportieren: Vorgabe
Description: Stahlrohr nach DIN 2448
Pset_DistributionFlowElementCommon - Reference: Stahlrohr nach DIN 2448 860225; sets with these values: 2
Andere - Typ: Stahlrohr nach DIN 2448 860225; Familie: Stahlrohr nach DIN 2448 860225; Familie und Typ: Stahlrohr nach DIN 2448 860225: Stahlrohr nach DIN 2448 860225; Typ-ID: 2539583
Abhängigkeiten - Höhe von Ebene: 0 m; Verschieben mit umliegenden Elementen: no
Bemaßungen - Fläche: 0.589357 m2; Volumen: 0.0677984 m3
IFC-Parameter - In IFC-Datei exportieren: Nach Typ; Pset MEP.Geom-DN: 200; Pset MEP.Tech-Insulation thickness (mm): 100; In IFC exportieren als: ifcflowsegment; NameOverride: Stahlrohr nach DIN 2448; IfcPresentationLayer: 0-TFT-H_Ruecklauf; ObjectTypeOverride: Stahlrohr nach DIN 2448; Pset MEP.Name: Stahlrohr nach DIN 2448; IfcDescription: Stahlrohr nach DIN 2448; Pset MEP.Geom-Outer Ø (mm): 219.1; Pset MEP.Tech-Material: Stahlrohr nach DIN 2448; Pset MEP.Geom-Length (mm): 590.893
Phasen - Phase erstellt: Phase 01

# IfcFlowSegment: Stahlrohr nach DIN 2448 860506:Stahlrohr nach DIN 2448 860506, Stahlrohr nach DIN 2448
In: 1. Untergeschoss
Type - Material: IfcSurfaceStyle #1741
Type - Andere - Kategorie: Allgemeines Modell; Familienname: Stahlrohr nach DIN 2448 860506
Type - ID-Daten - Typname: Stahlrohr nach DIN 2448 860506
Type - IFC-Parameter - Typ in IFC-Datei exportieren: Vorgabe
Description: Stahlrohr nach DIN 2448
Pset_DistributionFlowElementCommon - Reference: Stahlrohr nach DIN 2448 860506; sets with these values: 2
Andere - Typ: Stahlrohr nach DIN 2448 860506; Familie: Stahlrohr nach DIN 2448 860506; Familie und Typ: Stahlrohr nach DIN 2448 860506: Stahlrohr nach DIN 2448 860506; Typ-ID: 2539590
Abhängigkeiten - Höhe von Ebene: 0 m; Verschieben mit umliegenden Elementen: no
Bemaßungen - Fläche: 2.17145 m2; Volumen: 0.249799 m3
IFC-Parameter - In IFC-Datei exportieren: Nach Typ; Pset MEP.Geom-DN: 200; Pset MEP.Tech-Insulation thickness (mm): 100; In IFC exportieren als: ifcflowsegment; NameOverride: Stahlrohr nach DIN 2448; IfcPresentationLayer: 0-TFT-H_Ruecklauf; ObjectTypeOverride: Stahlrohr nach DIN 2448; Pset MEP.Name: Stahlrohr nach DIN 2448; IfcDescription: Stahlrohr nach DIN 2448; Pset MEP.Geom-Outer Ø (mm): 219.1; Pset MEP.Tech-Material: Stahlrohr nach DIN 2448; Pset MEP.Geom-Length (mm): 2177.11
Phasen - Phase erstellt: Phase 01

# IfcFlowSegment: Stahlrohr nach DIN 2448 860810:Stahlrohr nach DIN 2448 860810, Stahlrohr nach DIN 2448
In: 1. Untergeschoss
Type - Material: IfcSurfaceStyle #9317
Type - Andere - Kategorie: Allgemeines Modell; Familienname: Stahlrohr nach DIN 2448 860810
Type - ID-Daten - Typname: Stahlrohr nach DIN 2448 860810
Type - IFC-Parameter - Typ in IFC-Datei exportieren: Vorgabe
Description: Stahlrohr nach DIN 2448
Pset_DistributionFlowElementCommon - Reference: Stahlrohr nach DIN 2448 860810; sets with these values: 2
Andere - Typ: Stahlrohr nach DIN 2448 860810; Familie: Stahlrohr nach DIN 2448 860810; Familie und Typ: Stahlrohr nach DIN 2448 860810: Stahlrohr nach DIN 2448 860810; Typ-ID: 2539604
Abhängigkeiten - Höhe von Ebene: 0 m; Verschieben mit umliegenden Elementen: no
Bemaßungen - Fläche: 0.589357 m2; Volumen: 0.0677984 m3
IFC-Parameter - In IFC-Datei exportieren: Nach Typ; Pset MEP.Geom-DN: 200; Pset MEP.Tech-Insulation thickness (mm): 100; In IFC exportieren als: ifcflowsegment; NameOverride: Stahlrohr nach DIN 2448; IfcPresentationLayer: 0-TFT-H_Vorlauf; ObjectTypeOverride: Stahlrohr nach DIN 2448; Pset MEP.Name: Stahlrohr nach DIN 2448; IfcDescription: Stahlrohr nach DIN 2448; Pset MEP.Geom-Outer Ø (mm): 219.1; Pset MEP.Tech-Material: Stahlrohr nach DIN 2448; Pset MEP.Geom-Length (mm): 590.893
Phasen - Phase erstellt: Phase 01

# IfcFlowSegment: Stahlrohr nach DIN 2448 860833:Stahlrohr nach DIN 2448 860833, Stahlrohr nach DIN 2448
In: 1. Untergeschoss
Type - Material: IfcSurfaceStyle #9317
Type - Andere - Kategorie: Allgemeines Modell; Familienname: Stahlrohr nach DIN 2448 860833
Type - ID-Daten - Typname: Stahlrohr nach DIN 2448 860833
Type - IFC-Parameter - Typ in IFC-Datei exportieren: Vorgabe
Description: Stahlrohr nach DIN 2448
Pset_DistributionFlowElementCommon - Reference: Stahlrohr nach DIN 2448 860833; sets with these values: 2
Andere - Typ: Stahlrohr nach DIN 2448 860833; Familie: Stahlrohr nach DIN 2448 860833; Familie und Typ: Stahlrohr nach DIN 2448 860833: Stahlrohr nach DIN 2448 860833; Typ-ID: 2539611
Abhängigkeiten - Höhe von Ebene: 0 m; Verschieben mit umliegenden Elementen: no
Bemaßungen - Fläche: 2.17145 m2; Volumen: 0.249799 m3
IFC-Parameter - In IFC-Datei exportieren: Nach Typ; Pset MEP.Geom-DN: 200; Pset MEP.Tech-Insulation thickness (mm): 100; In IFC exportieren als: ifcflowsegment; NameOverride: Stahlrohr nach DIN 2448; IfcPresentationLayer: 0-TFT-H_Vorlauf; ObjectTypeOverride: Stahlrohr nach DIN 2448; Pset MEP.Name: Stahlrohr nach DIN 2448; IfcDescription: Stahlrohr nach DIN 2448; Pset MEP.Geom-Outer Ø (mm): 219.1; Pset MEP.Tech-Material: Stahlrohr nach DIN 2448; Pset MEP.Geom-Length (mm): 2177.11
Phasen - Phase erstellt: Phase 01

# IfcFlowSegment: Stahlrohr nach DIN 2448 860879:Stahlrohr nach DIN 2448 860879, Stahlrohr nach DIN 2448
In: 1. Untergeschoss
Type - Material: IfcSurfaceStyle #9317
Type - Andere - Kategorie: Allgemeines Modell; Familienname: Stahlrohr nach DIN 2448 860879
Type - ID-Daten - Typname: Stahlrohr nach DIN 2448 860879
Type - IFC-Parameter - Typ in IFC-Datei exportieren: Vorgabe
Description: Stahlrohr nach DIN 2448
Pset_DistributionFlowElementCommon - Reference: Stahlrohr nach DIN 2448 860879; sets with these values: 2
Andere - Typ: Stahlrohr nach DIN 2448 860879; Familie: Stahlrohr nach DIN 2448 860879; Familie und Typ: Stahlrohr nach DIN 2448 860879: Stahlrohr nach DIN 2448 860879; Typ-ID: 2539625
Abhängigkeiten - Höhe von Ebene: 0 m; Verschieben mit umliegenden Elementen: no
Bemaßungen - Fläche: 0.153001 m2; Volumen: 0.0176009 m3
IFC-Parameter - In IFC-Datei exportieren: Nach Typ; Pset MEP.Geom-DN: 200; Pset MEP.Tech-Insulation thickness (mm): 100; In IFC exportieren als: ifcflowsegment; NameOverride: Stahlrohr nach DIN 2448; IfcPresentationLayer: 0-TFT-H_Vorlauf; ObjectTypeOverride: Stahlrohr nach DIN 2448; Pset MEP.Name: Stahlrohr nach DIN 2448; IfcDescription: Stahlrohr nach DIN 2448; Pset MEP.Geom-Outer Ø (mm): 219.1; Pset MEP.Tech-Material: Stahlrohr nach DIN 2448; Pset MEP.Geom-Length (mm): 153.399
Phasen - Phase erstellt: Phase 01

# IfcFlowSegment: Stahlrohr nach DIN 2448 861210:Stahlrohr nach DIN 2448 861210, Stahlrohr nach DIN 2448
In: 1. Untergeschoss
Type - Material: IfcSurfaceStyle #1741
Type - Andere - Kategorie: Allgemeines Modell; Familienname: Stahlrohr nach DIN 2448 861210
Type - ID-Daten - Typname: Stahlrohr nach DIN 2448 861210
Type - IFC-Parameter - Typ in IFC-Datei exportieren: Vorgabe
Description: Stahlrohr nach DIN 2448
Pset_DistributionFlowElementCommon - Reference: Stahlrohr nach DIN 2448 861210; sets with these values: 2
Andere - Typ: Stahlrohr nach DIN 2448 861210; Familie: Stahlrohr nach DIN 2448 861210; Familie und Typ: Stahlrohr nach DIN 2448 861210: Stahlrohr nach DIN 2448 861210; Typ-ID: 2539646
Abhängigkeiten - Höhe von Ebene: 0 m; Verschieben mit umliegenden Elementen: no
Bemaßungen - Fläche: 0.153001 m2; Volumen: 0.0176009 m3
IFC-Parameter - In IFC-Datei exportieren: Nach Typ; Pset MEP.Geom-DN: 200; Pset MEP.Tech-Insulation thickness (mm): 100; In IFC exportieren als: ifcflowsegment; NameOverride: Stahlrohr nach DIN 2448; IfcPresentationLayer: 0-TFT-H_Ruecklauf; ObjectTypeOverride: Stahlrohr nach DIN 2448; Pset MEP.Name: Stahlrohr nach DIN 2448; IfcDescription: Stahlrohr nach DIN 2448; Pset MEP.Geom-Outer Ø (mm): 219.1; Pset MEP.Tech-Material: Stahlrohr nach DIN 2448; Pset MEP.Geom-Length (mm): 153.399
Phasen - Phase erstellt: Phase 01

# IfcFlowSegment: Stahlrohr nach DIN 2448 9686:Stahlrohr nach DIN 2448 9686, Stahlrohr nach DIN 2448
In: 1. Obergeschoss
Type - Material: IfcSurfaceStyle #9317
Type - Andere - Kategorie: Allgemeines Modell; Familienname: Stahlrohr nach DIN 2448 9686
Type - ID-Daten - Typname: Stahlrohr nach DIN 2448 9686
Type - IFC-Parameter - Typ in IFC-Datei exportieren: Vorgabe
Description: Stahlrohr nach DIN 2448
Pset_DistributionFlowElementCommon - Reference: Stahlrohr nach DIN 2448 9686; sets with these values: 2
Andere - Typ: Stahlrohr nach DIN 2448 9686; Familie: Stahlrohr nach DIN 2448 9686; Familie und Typ: Stahlrohr nach DIN 2448 9686: Stahlrohr nach DIN 2448 9686; Typ-ID: 2531485
Abhängigkeiten - Höhe von Ebene: 0 m; Verschieben mit umliegenden Elementen: no
Bemaßungen - Fläche: 2.38996 m2; Volumen: 0.204739 m3
IFC-Parameter - In IFC-Datei exportieren: Nach Typ; Pset MEP.Tech-Insulation thickness (mm): 100; Pset MEP.Geom-DN: 100; In IFC exportieren als: ifcflowsegment; NameOverride: Stahlrohr nach DIN 2448; IfcPresentationLayer: 0-TFT-H_Vorlauf; ObjectTypeOverride: Stahlrohr nach DIN 2448; Pset MEP.Name: Stahlrohr nach DIN 2448; IfcDescription: Stahlrohr nach DIN 2448; Pset MEP.Geom-Outer Ø (mm): 114.3; Pset MEP.Tech-Material: Stahlrohr nach DIN 2448; Pset MEP.Geom-Length (mm): 3568
Phasen - Phase erstellt: Phase 01

# IfcFlowSegment: Stahlrohr nach DIN 2448 9783:Stahlrohr nach DIN 2448 9783, Stahlrohr nach DIN 2448
In: 1. Obergeschoss
Type - Material: IfcSurfaceStyle #1741
Type - Andere - Kategorie: Allgemeines Modell; Familienname: Stahlrohr nach DIN 2448 9783
Type - ID-Daten - Typname: Stahlrohr nach DIN 2448 9783
Type - IFC-Parameter - Typ in IFC-Datei exportieren: Vorgabe
Description: Stahlrohr nach DIN 2448
Pset_DistributionFlowElementCommon - Reference: Stahlrohr nach DIN 2448 9783; sets with these values: 2
Andere - Typ: Stahlrohr nach DIN 2448 9783; Familie: Stahlrohr nach DIN 2448 9783; Familie und Typ: Stahlrohr nach DIN 2448 9783: Stahlrohr nach DIN 2448 9783; Typ-ID: 2531506
Abhängigkeiten - Höhe von Ebene: 0 m; Verschieben mit umliegenden Elementen: no
Bemaßungen - Fläche: 2.39022 m2; Volumen: 0.204762 m3
IFC-Parameter - In IFC-Datei exportieren: Nach Typ; Pset MEP.Tech-Insulation thickness (mm): 100; Pset MEP.Geom-DN: 100; In IFC exportieren als: ifcflowsegment; NameOverride: Stahlrohr nach DIN 2448; IfcPresentationLayer: 0-TFT-H_Ruecklauf; ObjectTypeOverride: Stahlrohr nach DIN 2448; Pset MEP.Name: Stahlrohr nach DIN 2448; IfcDescription: Stahlrohr nach DIN 2448; Pset MEP.Geom-Outer Ø (mm): 114.3; Pset MEP.Tech-Material: Stahlrohr nach DIN 2448; Pset MEP.Geom-Length (mm): 3568.4
Phasen - Phase erstellt: Phase 01

# IfcFlowSegment: Stahlrohr nach DIN 2448:Stahlrohr nach DIN 2448, Stahlrohr nach DIN 2448
In: 1. Obergeschoss
Type - Material: IfcSurfaceStyle #1741
Type - Andere - Kategorie: Allgemeines Modell; Familienname: Stahlrohr nach DIN 2448
Type - ID-Daten - Typname: Stahlrohr nach DIN 2448
Type - IFC-Parameter - Typ in IFC-Datei exportieren: Vorgabe
Description: Stahlrohr nach DIN 2448
Pset_DistributionFlowElementCommon - Reference: Stahlrohr nach DIN 2448; sets with these values: 2
Andere - Typ: Stahlrohr nach DIN 2448; Familie: Stahlrohr nach DIN 2448; Familie und Typ: Stahlrohr nach DIN 2448: Stahlrohr nach DIN 2448; Typ-ID: 2531478
Abhängigkeiten - Höhe von Ebene: 0 m; Verschieben mit umliegenden Elementen: no
Bemaßungen - Fläche: 2.38996 m2; Volumen: 0.204739 m3
IFC-Parameter - In IFC-Datei exportieren: Nach Typ; Pset MEP.Tech-Insulation thickness (mm): 100; In IFC exportieren als: ifcflowsegment; NameOverride: Stahlrohr nach DIN 2448; IfcPresentationLayer: 0-TFT-H_Ruecklauf; ObjectTypeOverride: Stahlrohr nach DIN 2448; Pset MEP.Name: Stahlrohr nach DIN 2448; IfcDescription: Stahlrohr nach DIN 2448; Pset MEP.Geom-DN: 100; Pset MEP.Geom-Outer Ø (mm): 114.3; Pset MEP.Tech-Material: Stahlrohr nach DIN 2448; Pset MEP.Geom-Length (mm): 3568
Phasen - Phase erstellt: Phase 01

# IfcFlowSegment: Wickelfalzrohr 251470:Wickelfalzrohr 251470, Wickelfalzrohr
In: Erdgeschoss
Type - Material: IfcSurfaceStyle #251447
Type - Andere - Kategorie: Allgemeines Modell; Familienname: Wickelfalzrohr 251470
Type - ID-Daten - Typname: Wickelfalzrohr 251470
Type - IFC-Parameter - Typ in IFC-Datei exportieren: Vorgabe
Description: Wickelfalzrohr
Pset_DistributionFlowElementCommon - Reference: Wickelfalzrohr 251470; sets with these values: 2
Andere - Typ: Wickelfalzrohr 251470; Familie: Wickelfalzrohr 251470; Familie und Typ: Wickelfalzrohr 251470: Wickelfalzrohr 251470; Typ-ID: 2532869
Abhängigkeiten - Höhe von Ebene: 0 m; Verschieben mit umliegenden Elementen: no
Bemaßungen - Fläche: 18.3789 m2; Volumen: 2.41329 m3
IFC-Parameter - In IFC-Datei exportieren: Nach Typ; Pset MEP.Geom-Length (mm): 29400; Pset MEP.Geom-Ø (mm): 400; Pset MEP.Tech-Material (ID): 1; In IFC exportieren als: ifcflowsegment; NameOverride: Wickelfalzrohr; IfcPresentationLayer: 0-TFT-H_Abgasabführung Variante 1; ObjectTypeOverride: Wickelfalzrohr; Pset MEP.Name: Wickelfalzrohr; IfcDescription: Wickelfalzrohr; Pset MEP.Abbreviation: R-R; Pset MEP.Tech-Medium: L_Entrauchung
Phasen - Phase erstellt: Phase 01

# IfcFlowSegment: Wickelfalzrohr 251493:Wickelfalzrohr 251493, Wickelfalzrohr
In: Erdgeschoss
Type - Material: IfcSurfaceStyle #251447
Type - Andere - Kategorie: Allgemeines Modell; Familienname: Wickelfalzrohr 251493
Type - ID-Daten - Typname: Wickelfalzrohr 251493
Type - IFC-Parameter - Typ in IFC-Datei exportieren: Vorgabe
Description: Wickelfalzrohr
Pset_DistributionFlowElementCommon - Reference: Wickelfalzrohr 251493; sets with these values: 2
Andere - Typ: Wickelfalzrohr 251493; Familie: Wickelfalzrohr 251493; Familie und Typ: Wickelfalzrohr 251493: Wickelfalzrohr 251493; Typ-ID: 2532876
Abhängigkeiten - Höhe von Ebene: 0 m; Verschieben mit umliegenden Elementen: no
Bemaßungen - Fläche: 9.23635 m2; Volumen: 0.606402 m3
IFC-Parameter - In IFC-Datei exportieren: Nach Typ; Pset MEP.Tech-Material (ID): 1; In IFC exportieren als: ifcflowsegment; NameOverride: Wickelfalzrohr; IfcPresentationLayer: 0-TFT-H_Abgasabführung Variante 1; ObjectTypeOverride: Wickelfalzrohr; Pset MEP.Name: Wickelfalzrohr; IfcDescription: Wickelfalzrohr; Pset MEP.Geom-Length (mm): 29550; Pset MEP.Abbreviation: R-R; Pset MEP.Geom-Ø (mm): 200; Pset MEP.Tech-Medium: L_Entrauchung
Phasen - Phase erstellt: Phase 01

# IfcFlowSegment: Wickelfalzrohr 268873:Wickelfalzrohr 268873, Wickelfalzrohr
In: Erdgeschoss
Type - Material: IfcSurfaceStyle #251447
Type - Andere - Kategorie: Allgemeines Modell; Familienname: Wickelfalzrohr 268873
Type - ID-Daten - Typname: Wickelfalzrohr 268873
Type - IFC-Parameter - Typ in IFC-Datei exportieren: Vorgabe
Description: Wickelfalzrohr
Pset_DistributionFlowElementCommon - Reference: Wickelfalzrohr 268873; sets with these values: 2
Andere - Typ: Wickelfalzrohr 268873; Familie: Wickelfalzrohr 268873; Familie und Typ: Wickelfalzrohr 268873: Wickelfalzrohr 268873; Typ-ID: 2533296
Abhängigkeiten - Höhe von Ebene: 0 m; Verschieben mit umliegenden Elementen: no
Bemaßungen - Fläche: 18.3789 m2; Volumen: 2.41329 m3
IFC-Parameter - In IFC-Datei exportieren: Nach Typ; Pset MEP.Geom-Length (mm): 29400; Pset MEP.Geom-Ø (mm): 400; Pset MEP.Tech-Material (ID): 1; In IFC exportieren als: ifcflowsegment; NameOverride: Wickelfalzrohr; IfcPresentationLayer: 0-TFT-H_Abgasabführung Variante 1; ObjectTypeOverride: Wickelfalzrohr; Pset MEP.Name: Wickelfalzrohr; IfcDescription: Wickelfalzrohr; Pset MEP.Abbreviation: R-R; Pset MEP.Tech-Medium: L_Entrauchung
Phasen - Phase erstellt: Phase 01

# IfcFlowSegment: Wickelfalzrohr 278002:Wickelfalzrohr 278002, Wickelfalzrohr
In: Erdgeschoss
Type - Material: IfcSurfaceStyle #251447
Type - Andere - Kategorie: Allgemeines Modell; Familienname: Wickelfalzrohr 278002
Type - ID-Daten - Typname: Wickelfalzrohr 278002
Type - IFC-Parameter - Typ in IFC-Datei exportieren: Vorgabe
Description: Wickelfalzrohr
Pset_DistributionFlowElementCommon - Reference: Wickelfalzrohr 278002; sets with these values: 2
Andere - Typ: Wickelfalzrohr 278002; Familie: Wickelfalzrohr 278002; Familie und Typ: Wickelfalzrohr 278002: Wickelfalzrohr 278002; Typ-ID: 2533927
Abhängigkeiten - Höhe von Ebene: 0 m; Verschieben mit umliegenden Elementen: no
Bemaßungen - Fläche: 0.18754 m2; Volumen: 0.0246255 m3
IFC-Parameter - In IFC-Datei exportieren: Nach Typ; Pset MEP.Geom-Ø (mm): 400; Pset MEP.Tech-Material (ID): 1; Pset MEP.Geom-Length (mm): 300; In IFC exportieren als: ifcflowsegment; NameOverride: Wickelfalzrohr; IfcPresentationLayer: 0-TFT-H_Abgasabführung Variante 1; ObjectTypeOverride: Wickelfalzrohr; Pset MEP.Name: Wickelfalzrohr; IfcDescription: Wickelfalzrohr; Pset MEP.Abbreviation: R-R; Pset MEP.Tech-Medium: L_Entrauchung
Phasen - Phase erstellt: Phase 01

# IfcFlowSegment: Wickelfalzrohr 278729:Wickelfalzrohr 278729, Wickelfalzrohr
In: Erdgeschoss
Type - Material: IfcSurfaceStyle #251447
Type - Andere - Kategorie: Allgemeines Modell; Familienname: Wickelfalzrohr 278729
Type - ID-Daten - Typname: Wickelfalzrohr 278729
Type - IFC-Parameter - Typ in IFC-Datei exportieren: Vorgabe
Description: Wickelfalzrohr
Pset_DistributionFlowElementCommon - Reference: Wickelfalzrohr 278729; sets with these values: 2
Andere - Typ: Wickelfalzrohr 278729; Familie: Wickelfalzrohr 278729; Familie und Typ: Wickelfalzrohr 278729: Wickelfalzrohr 278729; Typ-ID: 2533943
Abhängigkeiten - Höhe von Ebene: 0 m; Verschieben mit umliegenden Elementen: no
Bemaßungen - Fläche: 0.106273 m2; Volumen: 0.0139544 m3
IFC-Parameter - In IFC-Datei exportieren: Nach Typ; Pset MEP.Geom-Ø (mm): 400; Pset MEP.Tech-Material (ID): 1; In IFC exportieren als: ifcflowsegment; NameOverride: Wickelfalzrohr; IfcPresentationLayer: 0-TFT-H_Abgasabführung Variante 1; ObjectTypeOverride: Wickelfalzrohr; Pset MEP.Name: Wickelfalzrohr; IfcDescription: Wickelfalzrohr; Pset MEP.Geom-Length (mm): 170; Pset MEP.Abbreviation: R-R; Pset MEP.Tech-Medium: L_Entrauchung
Phasen - Phase erstellt: Phase 01

# IfcFlowSegment: Wickelfalzrohr 279449:Wickelfalzrohr 279449, Wickelfalzrohr
In: Erdgeschoss
Type - Material: IfcSurfaceStyle #251447
Type - Andere - Kategorie: Allgemeines Modell; Familienname: Wickelfalzrohr 279449
Type - ID-Daten - Typname: Wickelfalzrohr 279449
Type - IFC-Parameter - Typ in IFC-Datei exportieren: Vorgabe
Description: Wickelfalzrohr
Pset_DistributionFlowElementCommon - Reference: Wickelfalzrohr 279449; sets with these values: 2
Andere - Typ: Wickelfalzrohr 279449; Familie: Wickelfalzrohr 279449; Familie und Typ: Wickelfalzrohr 279449: Wickelfalzrohr 279449; Typ-ID: 2533957
Abhängigkeiten - Höhe von Ebene: 0 m; Verschieben mit umliegenden Elementen: no
Bemaßungen - Fläche: 0.18754 m2; Volumen: 0.0246255 m3
IFC-Parameter - In IFC-Datei exportieren: Nach Typ; Pset MEP.Geom-Ø (mm): 400; Pset MEP.Tech-Material (ID): 1; Pset MEP.Geom-Length (mm): 300; In IFC exportieren als: ifcflowsegment; NameOverride: Wickelfalzrohr; IfcPresentationLayer: 0-TFT-H_Abgasabführung Variante 2; ObjectTypeOverride: Wickelfalzrohr; Pset MEP.Name: Wickelfalzrohr; IfcDescription: Wickelfalzrohr; Pset MEP.Abbreviation: R-R; Pset MEP.Tech-Medium: L_Entrauchung
Phasen - Phase erstellt: Phase 01

# IfcFlowSegment: Wickelfalzrohr 280417:Wickelfalzrohr 280417, Wickelfalzrohr
In: Erdgeschoss
Type - Material: IfcSurfaceStyle #251447
Type - Andere - Kategorie: Allgemeines Modell; Familienname: Wickelfalzrohr 280417
Type - ID-Daten - Typname: Wickelfalzrohr 280417
Type - IFC-Parameter - Typ in IFC-Datei exportieren: Vorgabe
Description: Wickelfalzrohr
Pset_DistributionFlowElementCommon - Reference: Wickelfalzrohr 280417; sets with these values: 2
Andere - Typ: Wickelfalzrohr 280417; Familie: Wickelfalzrohr 280417; Familie und Typ: Wickelfalzrohr 280417: Wickelfalzrohr 280417; Typ-ID: 2534006
Abhängigkeiten - Höhe von Ebene: 0 m; Verschieben mit umliegenden Elementen: no
Bemaßungen - Fläche: 1.54599 m2; Volumen: 0.203 m3
IFC-Parameter - In IFC-Datei exportieren: Nach Typ; Pset MEP.Geom-Ø (mm): 400; Pset MEP.Tech-Material (ID): 1; In IFC exportieren als: ifcflowsegment; NameOverride: Wickelfalzrohr; IfcPresentationLayer: 0-TFT-H_Abgasabführung Variante 2; ObjectTypeOverride: Wickelfalzrohr; Pset MEP.Name: Wickelfalzrohr; IfcDescription: Wickelfalzrohr; Pset MEP.Geom-Length (mm): 2473.05; Pset MEP.Abbreviation: R-R; Pset MEP.Tech-Medium: L_Entrauchung
Phasen - Phase erstellt: Phase 01

# IfcFlowSegment: Wickelfalzrohr 280572:Wickelfalzrohr 280572, Wickelfalzrohr
In: Erdgeschoss
Type - Material: IfcSurfaceStyle #251447
Type - Andere - Kategorie: Allgemeines Modell; Familienname: Wickelfalzrohr 280572
Type - ID-Daten - Typname: Wickelfalzrohr 280572
Type - IFC-Parameter - Typ in IFC-Datei exportieren: Vorgabe
Description: Wickelfalzrohr
Pset_DistributionFlowElementCommon - Reference: Wickelfalzrohr 280572; sets with these values: 2
Andere - Typ: Wickelfalzrohr 280572; Familie: Wickelfalzrohr 280572; Familie und Typ: Wickelfalzrohr 280572: Wickelfalzrohr 280572; Typ-ID: 2534013
Abhängigkeiten - Höhe von Ebene: 0 m; Verschieben mit umliegenden Elementen: no
Bemaßungen - Fläche: 12.5027 m2; Volumen: 1.6417 m3
IFC-Parameter - In IFC-Datei exportieren: Nach Typ; Pset MEP.Geom-Ø (mm): 400; Pset MEP.Tech-Material (ID): 1; In IFC exportieren als: ifcflowsegment; NameOverride: Wickelfalzrohr; IfcPresentationLayer: 0-TFT-H_Abgasabführung Variante 2; ObjectTypeOverride: Wickelfalzrohr; Pset MEP.Name: Wickelfalzrohr; IfcDescription: Wickelfalzrohr; Pset MEP.Geom-Length (mm): 20000; Pset MEP.Abbreviation: R-R; Pset MEP.Tech-Medium: L_Entrauchung
Phasen - Phase erstellt: Phase 01

# IfcFlowSegment: Wickelfalzrohr 280727:Wickelfalzrohr 280727, Wickelfalzrohr
In: Erdgeschoss
Type - Material: IfcSurfaceStyle #251447
Type - Andere - Kategorie: Allgemeines Modell; Familienname: Wickelfalzrohr 280727
Type - ID-Daten - Typname: Wickelfalzrohr 280727
Type - IFC-Parameter - Typ in IFC-Datei exportieren: Vorgabe
Description: Wickelfalzrohr
Pset_DistributionFlowElementCommon - Reference: Wickelfalzrohr 280727; sets with these values: 2
Andere - Typ: Wickelfalzrohr 280727; Familie: Wickelfalzrohr 280727; Familie und Typ: Wickelfalzrohr 280727: Wickelfalzrohr 280727; Typ-ID: 2534020
Abhängigkeiten - Höhe von Ebene: 0 m; Verschieben mit umliegenden Elementen: no
Bemaßungen - Fläche: 0.18754 m2; Volumen: 0.0246255 m3
IFC-Parameter - In IFC-Datei exportieren: Nach Typ; Pset MEP.Geom-Ø (mm): 400; Pset MEP.Tech-Material (ID): 1; Pset MEP.Geom-Length (mm): 300; In IFC exportieren als: ifcflowsegment; NameOverride: Wickelfalzrohr; IfcPresentationLayer: 0-TFT-H_Abgasabführung Variante 2; ObjectTypeOverride: Wickelfalzrohr; Pset MEP.Name: Wickelfalzrohr; IfcDescription: Wickelfalzrohr; Pset MEP.Abbreviation: R-R; Pset MEP.Tech-Medium: L_Entrauchung
Phasen - Phase erstellt: Phase 01

# IfcFlowSegment: Wickelfalzrohr 280819:Wickelfalzrohr 280819, Wickelfalzrohr
In: Erdgeschoss
Type - Material: IfcSurfaceStyle #251447
Type - Andere - Kategorie: Allgemeines Modell; Familienname: Wickelfalzrohr 280819
Type - ID-Daten - Typname: Wickelfalzrohr 280819
Type - IFC-Parameter - Typ in IFC-Datei exportieren: Vorgabe
Description: Wickelfalzrohr
Pset_DistributionFlowElementCommon - Reference: Wickelfalzrohr 280819; sets with these values: 2
Andere - Typ: Wickelfalzrohr 280819; Familie: Wickelfalzrohr 280819; Familie und Typ: Wickelfalzrohr 280819: Wickelfalzrohr 280819; Typ-ID: 2534048
Abhängigkeiten - Höhe von Ebene: 0 m; Verschieben mit umliegenden Elementen: no
Bemaßungen - Fläche: 0.876765 m2; Volumen: 0.115126 m3
IFC-Parameter - In IFC-Datei exportieren: Nach Typ; Pset MEP.Geom-Ø (mm): 400; Pset MEP.Tech-Material (ID): 1; In IFC exportieren als: ifcflowsegment; NameOverride: Wickelfalzrohr; IfcPresentationLayer: 0-TFT-H_Abgasabführung Variante 2; ObjectTypeOverride: Wickelfalzrohr; Pset MEP.Name: Wickelfalzrohr; IfcDescription: Wickelfalzrohr; Pset MEP.Geom-Length (mm): 1402.52; Pset MEP.Abbreviation: R-R; Pset MEP.Tech-Medium: L_Entrauchung
Phasen - Phase erstellt: Phase 01

# IfcFlowSegment: Wickelfalzrohr 280995:Wickelfalzrohr 280995, Wickelfalzrohr
In: Erdgeschoss
Type - Material: IfcSurfaceStyle #251447
Type - Andere - Kategorie: Allgemeines Modell; Familienname: Wickelfalzrohr 280995
Type - ID-Daten - Typname: Wickelfalzrohr 280995
Type - IFC-Parameter - Typ in IFC-Datei exportieren: Vorgabe
Description: Wickelfalzrohr
Pset_DistributionFlowElementCommon - Reference: Wickelfalzrohr 280995; sets with these values: 2
Andere - Typ: Wickelfalzrohr 280995; Familie: Wickelfalzrohr 280995; Familie und Typ: Wickelfalzrohr 280995: Wickelfalzrohr 280995; Typ-ID: 2534062
Abhängigkeiten - Höhe von Ebene: 0 m; Verschieben mit umliegenden Elementen: no
Bemaßungen - Fläche: 0.291022 m2; Volumen: 0.0382135 m3
IFC-Parameter - In IFC-Datei exportieren: Nach Typ; Pset MEP.Geom-Ø (mm): 400; Pset MEP.Tech-Material (ID): 1; In IFC exportieren als: ifcflowsegment; NameOverride: Wickelfalzrohr; IfcPresentationLayer: 0-TFT-H_Abgasabführung Variante 2; ObjectTypeOverride: Wickelfalzrohr; Pset MEP.Name: Wickelfalzrohr; IfcDescription: Wickelfalzrohr; Pset MEP.Geom-Length (mm): 465.536; Pset MEP.Abbreviation: R-R; Pset MEP.Tech-Medium: L_Entrauchung
Phasen - Phase erstellt: Phase 01

# IfcFlowSegment: Wickelfalzrohr 281175:Wickelfalzrohr 281175, Wickelfalzrohr
In: Erdgeschoss
Type - Material: IfcSurfaceStyle #251447
Type - Andere - Kategorie: Allgemeines Modell; Familienname: Wickelfalzrohr 281175
Type - ID-Daten - Typname: Wickelfalzrohr 281175
Type - IFC-Parameter - Typ in IFC-Datei exportieren: Vorgabe
Description: Wickelfalzrohr
Pset_DistributionFlowElementCommon - Reference: Wickelfalzrohr 281175; sets with these values: 2
Andere - Typ: Wickelfalzrohr 281175; Familie: Wickelfalzrohr 281175; Familie und Typ: Wickelfalzrohr 281175: Wickelfalzrohr 281175; Typ-ID: 2534076
Abhängigkeiten - Höhe von Ebene: 0 m; Verschieben mit umliegenden Elementen: no
Bemaßungen - Fläche: 0.962093 m2; Volumen: 0.12633 m3
IFC-Parameter - In IFC-Datei exportieren: Nach Typ; Pset MEP.Geom-Ø (mm): 400; Pset MEP.Tech-Material (ID): 1; In IFC exportieren als: ifcflowsegment; NameOverride: Wickelfalzrohr; IfcPresentationLayer: 0-TFT-H_Abgasabführung Variante 2; ObjectTypeOverride: Wickelfalzrohr; Pset MEP.Name: Wickelfalzrohr; IfcDescription: Wickelfalzrohr; Pset MEP.Geom-Length (mm): 1539.02; Pset MEP.Abbreviation: R-R; Pset MEP.Tech-Medium: L_Entrauchung
Phasen - Phase erstellt: Phase 01

# IfcFlowSegment: Wickelfalzrohr 281330:Wickelfalzrohr 281330, Wickelfalzrohr
In: Erdgeschoss
Type - Material: IfcSurfaceStyle #251447
Type - Andere - Kategorie: Allgemeines Modell; Familienname: Wickelfalzrohr 281330
Type - ID-Daten - Typname: Wickelfalzrohr 281330
Type - IFC-Parameter - Typ in IFC-Datei exportieren: Vorgabe
Description: Wickelfalzrohr
Pset_DistributionFlowElementCommon - Reference: Wickelfalzrohr 281330; sets with these values: 2
Andere - Typ: Wickelfalzrohr 281330; Familie: Wickelfalzrohr 281330; Familie und Typ: Wickelfalzrohr 281330: Wickelfalzrohr 281330; Typ-ID: 2534083
Abhängigkeiten - Höhe von Ebene: 0 m; Verschieben mit umliegenden Elementen: no
Bemaßungen - Fläche: 12.5027 m2; Volumen: 1.6417 m3
IFC-Parameter - In IFC-Datei exportieren: Nach Typ; Pset MEP.Geom-Ø (mm): 400; Pset MEP.Tech-Material (ID): 1; Pset MEP.Geom-Length (mm): 20000; In IFC exportieren als: ifcflowsegment; NameOverride: Wickelfalzrohr; IfcPresentationLayer: 0-TFT-H_Abgasabführung Variante 2; ObjectTypeOverride: Wickelfalzrohr; Pset MEP.Name: Wickelfalzrohr; IfcDescription: Wickelfalzrohr; Pset MEP.Abbreviation: R-R; Pset MEP.Tech-Medium: L_Entrauchung
Phasen - Phase erstellt: Phase 01

# IfcFlowSegment: Wickelfalzrohr 281353:Wickelfalzrohr 281353, Wickelfalzrohr
In: Erdgeschoss
Type - Material: IfcSurfaceStyle #251447
Type - Andere - Kategorie: Allgemeines Modell; Familienname: Wickelfalzrohr 281353
Type - ID-Daten - Typname: Wickelfalzrohr 281353
Type - IFC-Parameter - Typ in IFC-Datei exportieren: Vorgabe
Description: Wickelfalzrohr
Pset_DistributionFlowElementCommon - Reference: Wickelfalzrohr 281353; sets with these values: 2
Andere - Typ: Wickelfalzrohr 281353; Familie: Wickelfalzrohr 281353; Familie und Typ: Wickelfalzrohr 281353: Wickelfalzrohr 281353; Typ-ID: 2534090
Abhängigkeiten - Höhe von Ebene: 0 m; Verschieben mit umliegenden Elementen: no
Bemaßungen - Fläche: 0.18754 m2; Volumen: 0.0246255 m3
IFC-Parameter - In IFC-Datei exportieren: Nach Typ; Pset MEP.Geom-Ø (mm): 400; Pset MEP.Tech-Material (ID): 1; Pset MEP.Geom-Length (mm): 300; In IFC exportieren als: ifcflowsegment; NameOverride: Wickelfalzrohr; IfcPresentationLayer: 0-TFT-H_Abgasabführung Variante 2; ObjectTypeOverride: Wickelfalzrohr; Pset MEP.Name: Wickelfalzrohr; IfcDescription: Wickelfalzrohr; Pset MEP.Abbreviation: R-R; Pset MEP.Tech-Medium: L_Entrauchung
Phasen - Phase erstellt: Phase 01

# IfcFlowSegment: Wickelfalzrohr 281445:Wickelfalzrohr 281445, Wickelfalzrohr
In: Erdgeschoss
Type - Material: IfcSurfaceStyle #251447
Type - Andere - Kategorie: Allgemeines Modell; Familienname: Wickelfalzrohr 281445
Type - ID-Daten - Typname: Wickelfalzrohr 281445
Type - IFC-Parameter - Typ in IFC-Datei exportieren: Vorgabe
Description: Wickelfalzrohr
Pset_DistributionFlowElementCommon - Reference: Wickelfalzrohr 281445; sets with these values: 2
Andere - Typ: Wickelfalzrohr 281445; Familie: Wickelfalzrohr 281445; Familie und Typ: Wickelfalzrohr 281445: Wickelfalzrohr 281445; Typ-ID: 2534118
Abhängigkeiten - Höhe von Ebene: 0 m; Verschieben mit umliegenden Elementen: no
Bemaßungen - Fläche: 2.15172 m2; Volumen: 0.282537 m3
IFC-Parameter - In IFC-Datei exportieren: Nach Typ; Pset MEP.Geom-Ø (mm): 400; Pset MEP.Tech-Material (ID): 1; In IFC exportieren als: ifcflowsegment; NameOverride: Wickelfalzrohr; IfcPresentationLayer: 0-TFT-H_Abgasabführung Variante 2; ObjectTypeOverride: Wickelfalzrohr; Pset MEP.Name: Wickelfalzrohr; IfcDescription: Wickelfalzrohr; Pset MEP.Geom-Length (mm): 3442.01; Pset MEP.Abbreviation: R-R; Pset MEP.Tech-Medium: L_Entrauchung
Phasen - Phase erstellt: Phase 01

# IfcFlowSegment: Wickelfalzrohr 281623:Wickelfalzrohr 281623, Wickelfalzrohr
In: Erdgeschoss
Type - Material: IfcSurfaceStyle #251447
Type - Andere - Kategorie: Allgemeines Modell; Familienname: Wickelfalzrohr 281623
Type - ID-Daten - Typname: Wickelfalzrohr 281623
Type - IFC-Parameter - Typ in IFC-Datei exportieren: Vorgabe
Description: Wickelfalzrohr
Pset_DistributionFlowElementCommon - Reference: Wickelfalzrohr 281623; sets with these values: 2
Andere - Typ: Wickelfalzrohr 281623; Familie: Wickelfalzrohr 281623; Familie und Typ: Wickelfalzrohr 281623: Wickelfalzrohr 281623; Typ-ID: 2534132
Abhängigkeiten - Höhe von Ebene: 0 m; Verschieben mit umliegenden Elementen: no
Bemaßungen - Fläche: 0.168111 m2; Volumen: 0.0220742 m3
IFC-Parameter - In IFC-Datei exportieren: Nach Typ; Pset MEP.Geom-Ø (mm): 400; Pset MEP.Tech-Material (ID): 1; In IFC exportieren als: ifcflowsegment; NameOverride: Wickelfalzrohr; IfcPresentationLayer: 0-TFT-H_Abgasabführung Variante 2; ObjectTypeOverride: Wickelfalzrohr; Pset MEP.Name: Wickelfalzrohr; IfcDescription: Wickelfalzrohr; Pset MEP.Geom-Length (mm): 268.919; Pset MEP.Abbreviation: R-R; Pset MEP.Tech-Medium: L_Entrauchung
Phasen - Phase erstellt: Phase 01

# IfcFlowSegment: Wickelfalzrohr 281801:Wickelfalzrohr 281801, Wickelfalzrohr
In: Erdgeschoss
Type - Material: IfcSurfaceStyle #251447
Type - Andere - Kategorie: Allgemeines Modell; Familienname: Wickelfalzrohr 281801
Type - ID-Daten - Typname: Wickelfalzrohr 281801
Type - IFC-Parameter - Typ in IFC-Datei exportieren: Vorgabe
Description: Wickelfalzrohr
Pset_DistributionFlowElementCommon - Reference: Wickelfalzrohr 281801; sets with these values: 2
Andere - Typ: Wickelfalzrohr 281801; Familie: Wickelfalzrohr 281801; Familie und Typ: Wickelfalzrohr 281801: Wickelfalzrohr 281801; Typ-ID: 2534146
Abhängigkeiten - Höhe von Ebene: 0 m; Verschieben mit umliegenden Elementen: no
Bemaßungen - Fläche: 0.386072 m2; Volumen: 0.0506942 m3
IFC-Parameter - In IFC-Datei exportieren: Nach Typ; Pset MEP.Geom-Ø (mm): 400; Pset MEP.Tech-Material (ID): 1; In IFC exportieren als: ifcflowsegment; NameOverride: Wickelfalzrohr; IfcPresentationLayer: 0-TFT-H_Abgasabführung Variante 2; ObjectTypeOverride: Wickelfalzrohr; Pset MEP.Name: Wickelfalzrohr; IfcDescription: Wickelfalzrohr; Pset MEP.Geom-Length (mm): 617.583; Pset MEP.Abbreviation: R-R; Pset MEP.Tech-Medium: L_Entrauchung
Phasen - Phase erstellt: Phase 01

# IfcFlowSegment: Wickelfalzrohr 281956:Wickelfalzrohr 281956, Wickelfalzrohr
In: Erdgeschoss
Type - Material: IfcSurfaceStyle #251447
Type - Andere - Kategorie: Allgemeines Modell; Familienname: Wickelfalzrohr 281956
Type - ID-Daten - Typname: Wickelfalzrohr 281956
Type - IFC-Parameter - Typ in IFC-Datei exportieren: Vorgabe
Description: Wickelfalzrohr
Pset_DistributionFlowElementCommon - Reference: Wickelfalzrohr 281956; sets with these values: 2
Andere - Typ: Wickelfalzrohr 281956; Familie: Wickelfalzrohr 281956; Familie und Typ: Wickelfalzrohr 281956: Wickelfalzrohr 281956; Typ-ID: 2534153
Abhängigkeiten - Höhe von Ebene: 0 m; Verschieben mit umliegenden Elementen: no
Bemaßungen - Fläche: 12.5027 m2; Volumen: 1.6417 m3
IFC-Parameter - In IFC-Datei exportieren: Nach Typ; Pset MEP.Geom-Ø (mm): 400; Pset MEP.Tech-Material (ID): 1; Pset MEP.Geom-Length (mm): 20000; In IFC exportieren als: ifcflowsegment; NameOverride: Wickelfalzrohr; IfcPresentationLayer: 0-TFT-H_Abgasabführung Variante 2; ObjectTypeOverride: Wickelfalzrohr; Pset MEP.Name: Wickelfalzrohr; IfcDescription: Wickelfalzrohr; Pset MEP.Abbreviation: R-R; Pset MEP.Tech-Medium: L_Entrauchung
Phasen - Phase erstellt: Phase 01

# IfcFlowSegment: Wickelfalzrohr 281979:Wickelfalzrohr 281979, Wickelfalzrohr
In: Erdgeschoss
Type - Material: IfcSurfaceStyle #251447
Type - Andere - Kategorie: Allgemeines Modell; Familienname: Wickelfalzrohr 281979
Type - ID-Daten - Typname: Wickelfalzrohr 281979
Type - IFC-Parameter - Typ in IFC-Datei exportieren: Vorgabe
Description: Wickelfalzrohr
Pset_DistributionFlowElementCommon - Reference: Wickelfalzrohr 281979; sets with these values: 2
Andere - Typ: Wickelfalzrohr 281979; Familie: Wickelfalzrohr 281979; Familie und Typ: Wickelfalzrohr 281979: Wickelfalzrohr 281979; Typ-ID: 2534160
Abhängigkeiten - Höhe von Ebene: 0 m; Verschieben mit umliegenden Elementen: no
Bemaßungen - Fläche: 0.117213 m2; Volumen: 0.00961932 m3
IFC-Parameter - In IFC-Datei exportieren: Nach Typ; Pset MEP.Tech-Material (ID): 1; Pset MEP.Geom-Length (mm): 300; In IFC exportieren als: ifcflowsegment; NameOverride: Wickelfalzrohr; IfcPresentationLayer: 0-TFT-H_Abgasabführung Variante 2; ObjectTypeOverride: Wickelfalzrohr; Pset MEP.Name: Wickelfalzrohr; IfcDescription: Wickelfalzrohr; Pset MEP.Abbreviation: R-R; Pset MEP.Geom-Ø (mm): 250; Pset MEP.Tech-Medium: L_Entrauchung
Phasen - Phase erstellt: Phase 01

# IfcFlowSegment: Wickelfalzrohr 282826:Wickelfalzrohr 282826, Wickelfalzrohr
In: Erdgeschoss
Type - Material: IfcSurfaceStyle #251447
Type - Andere - Kategorie: Allgemeines Modell; Familienname: Wickelfalzrohr 282826
Type - ID-Daten - Typname: Wickelfalzrohr 282826
Type - IFC-Parameter - Typ in IFC-Datei exportieren: Vorgabe
Description: Wickelfalzrohr
Pset_DistributionFlowElementCommon - Reference: Wickelfalzrohr 282826; sets with these values: 2
Andere - Typ: Wickelfalzrohr 282826; Familie: Wickelfalzrohr 282826; Familie und Typ: Wickelfalzrohr 282826: Wickelfalzrohr 282826; Typ-ID: 2534174
Abhängigkeiten - Höhe von Ebene: 0 m; Verschieben mit umliegenden Elementen: no
Bemaßungen - Fläche: 0.188443 m2; Volumen: 0.015465 m3
IFC-Parameter - In IFC-Datei exportieren: Nach Typ; Pset MEP.Tech-Material (ID): 1; Pset MEP.Geom-Ø (mm): 250; In IFC exportieren als: ifcflowsegment; NameOverride: Wickelfalzrohr; IfcPresentationLayer: 0-TFT-H_Abgasabführung Variante 2; ObjectTypeOverride: Wickelfalzrohr; Pset MEP.Name: Wickelfalzrohr; IfcDescription: Wickelfalzrohr; Pset MEP.Geom-Length (mm): 482.312; Pset MEP.Abbreviation: R-R; Pset MEP.Tech-Medium: L_Entrauchung
Phasen - Phase erstellt: Phase 01

# IfcFlowSegment: Wickelfalzrohr 283569:Wickelfalzrohr 283569, Wickelfalzrohr
In: Erdgeschoss
Type - Material: IfcSurfaceStyle #251447
Type - Andere - Kategorie: Allgemeines Modell; Familienname: Wickelfalzrohr 283569
Type - ID-Daten - Typname: Wickelfalzrohr 283569
Type - IFC-Parameter - Typ in IFC-Datei exportieren: Vorgabe
Description: Wickelfalzrohr
Pset_DistributionFlowElementCommon - Reference: Wickelfalzrohr 283569; sets with these values: 2
Andere - Typ: Wickelfalzrohr 283569; Familie: Wickelfalzrohr 283569; Familie und Typ: Wickelfalzrohr 283569: Wickelfalzrohr 283569; Typ-ID: 2534195
Abhängigkeiten - Höhe von Ebene: 0 m; Verschieben mit umliegenden Elementen: no
Bemaßungen - Fläche: 0.183633 m2; Volumen: 0.0150703 m3
IFC-Parameter - In IFC-Datei exportieren: Nach Typ; Pset MEP.Tech-Material (ID): 1; Pset MEP.Geom-Ø (mm): 250; In IFC exportieren als: ifcflowsegment; NameOverride: Wickelfalzrohr; IfcPresentationLayer: 0-TFT-H_Abgasabführung Variante 2; ObjectTypeOverride: Wickelfalzrohr; Pset MEP.Name: Wickelfalzrohr; IfcDescription: Wickelfalzrohr; Pset MEP.Geom-Length (mm): 470; Pset MEP.Abbreviation: R-R; Pset MEP.Tech-Medium: L_Entrauchung
Phasen - Phase erstellt: Phase 01

# IfcFlowSegment: Wickelfalzrohr 283724:Wickelfalzrohr 283724, Wickelfalzrohr
In: Erdgeschoss
Type - Material: IfcSurfaceStyle #251447
Type - Andere - Kategorie: Allgemeines Modell; Familienname: Wickelfalzrohr 283724
Type - ID-Daten - Typname: Wickelfalzrohr 283724
Type - IFC-Parameter - Typ in IFC-Datei exportieren: Vorgabe
Description: Wickelfalzrohr
Pset_DistributionFlowElementCommon - Reference: Wickelfalzrohr 283724; sets with these values: 2
Andere - Typ: Wickelfalzrohr 283724; Familie: Wickelfalzrohr 283724; Familie und Typ: Wickelfalzrohr 283724: Wickelfalzrohr 283724; Typ-ID: 2534202
Abhängigkeiten - Höhe von Ebene: 0 m; Verschieben mit umliegenden Elementen: no
Bemaßungen - Fläche: 1.2879 m2; Volumen: 0.105695 m3
IFC-Parameter - In IFC-Datei exportieren: Nach Typ; Pset MEP.Tech-Material (ID): 1; Pset MEP.Geom-Ø (mm): 250; In IFC exportieren als: ifcflowsegment; NameOverride: Wickelfalzrohr; IfcPresentationLayer: 0-TFT-H_Abgasabführung Variante 2; ObjectTypeOverride: Wickelfalzrohr; Pset MEP.Name: Wickelfalzrohr; IfcDescription: Wickelfalzrohr; Pset MEP.Geom-Length (mm): 3296.33; Pset MEP.Abbreviation: R-R; Pset MEP.Tech-Medium: L_Entrauchung
Phasen - Phase erstellt: Phase 01

# IfcFlowSegment: Wickelfalzrohr 284036:Wickelfalzrohr 284036, Wickelfalzrohr
In: Erdgeschoss
Type - Material: IfcSurfaceStyle #251447
Type - Andere - Kategorie: Allgemeines Modell; Familienname: Wickelfalzrohr 284036
Type - ID-Daten - Typname: Wickelfalzrohr 284036
Type - IFC-Parameter - Typ in IFC-Datei exportieren: Vorgabe
Description: Wickelfalzrohr
Pset_DistributionFlowElementCommon - Reference: Wickelfalzrohr 284036; sets with these values: 2
Andere - Typ: Wickelfalzrohr 284036; Familie: Wickelfalzrohr 284036; Familie und Typ: Wickelfalzrohr 284036: Wickelfalzrohr 284036; Typ-ID: 2534216
Abhängigkeiten - Höhe von Ebene: 0 m; Verschieben mit umliegenden Elementen: no
Bemaßungen - Fläche: 0.111241 m2; Volumen: 0.00912923 m3
IFC-Parameter - In IFC-Datei exportieren: Nach Typ; Pset MEP.Tech-Material (ID): 1; Pset MEP.Geom-Ø (mm): 250; In IFC exportieren als: ifcflowsegment; NameOverride: Wickelfalzrohr; IfcPresentationLayer: 0-TFT-H_Abgasabführung Variante 2; ObjectTypeOverride: Wickelfalzrohr; Pset MEP.Name: Wickelfalzrohr; IfcDescription: Wickelfalzrohr; Pset MEP.Geom-Length (mm): 284.716; Pset MEP.Abbreviation: R-R; Pset MEP.Tech-Medium: L_Entrauchung
Phasen - Phase erstellt: Phase 01

# IfcFlowSegment: Wickelfalzrohr 284345:Wickelfalzrohr 284345, Wickelfalzrohr
In: Erdgeschoss
Type - Material: IfcSurfaceStyle #251447
Type - Andere - Kategorie: Allgemeines Modell; Familienname: Wickelfalzrohr 284345
Type - ID-Daten - Typname: Wickelfalzrohr 284345
Type - IFC-Parameter - Typ in IFC-Datei exportieren: Vorgabe
Description: Wickelfalzrohr
Pset_DistributionFlowElementCommon - Reference: Wickelfalzrohr 284345; sets with these values: 2
Andere - Typ: Wickelfalzrohr 284345; Familie: Wickelfalzrohr 284345; Familie und Typ: Wickelfalzrohr 284345: Wickelfalzrohr 284345; Typ-ID: 2534230
Abhängigkeiten - Höhe von Ebene: 0 m; Verschieben mit umliegenden Elementen: no
Bemaßungen - Fläche: 2.34425 m2; Volumen: 0.192386 m3
IFC-Parameter - In IFC-Datei exportieren: Nach Typ; Pset MEP.Tech-Material (ID): 1; Pset MEP.Geom-Ø (mm): 250; In IFC exportieren als: ifcflowsegment; NameOverride: Wickelfalzrohr; IfcPresentationLayer: 0-TFT-H_Abgasabführung Variante 2; ObjectTypeOverride: Wickelfalzrohr; Pset MEP.Name: Wickelfalzrohr; IfcDescription: Wickelfalzrohr; Pset MEP.Geom-Length (mm): 6000; Pset MEP.Abbreviation: R-R; Pset MEP.Tech-Medium: L_Entrauchung
Phasen - Phase erstellt: Phase 01

# IfcFlowSegment: Wickelfalzrohr 284500:Wickelfalzrohr 284500, Wickelfalzrohr
In: Erdgeschoss
Type - Material: IfcSurfaceStyle #251447
Type - Andere - Kategorie: Allgemeines Modell; Familienname: Wickelfalzrohr 284500
Type - ID-Daten - Typname: Wickelfalzrohr 284500
Type - IFC-Parameter - Typ in IFC-Datei exportieren: Vorgabe
Description: Wickelfalzrohr
Pset_DistributionFlowElementCommon - Reference: Wickelfalzrohr 284500; sets with these values: 2
Andere - Typ: Wickelfalzrohr 284500; Familie: Wickelfalzrohr 284500; Familie und Typ: Wickelfalzrohr 284500: Wickelfalzrohr 284500; Typ-ID: 2534237
Abhängigkeiten - Höhe von Ebene: 0 m; Verschieben mit umliegenden Elementen: no
Bemaßungen - Fläche: 0.326314 m2; Volumen: 0.0267797 m3
IFC-Parameter - In IFC-Datei exportieren: Nach Typ; Pset MEP.Tech-Material (ID): 1; Pset MEP.Geom-Ø (mm): 250; In IFC exportieren als: ifcflowsegment; NameOverride: Wickelfalzrohr; IfcPresentationLayer: 0-TFT-H_Abgasabführung Variante 2; ObjectTypeOverride: Wickelfalzrohr; Pset MEP.Name: Wickelfalzrohr; IfcDescription: Wickelfalzrohr; Pset MEP.Geom-Length (mm): 835.187; Pset MEP.Abbreviation: R-R; Pset MEP.Tech-Medium: L_Entrauchung
Phasen - Phase erstellt: Phase 01

# IfcFlowSegment: Wickelfalzrohr 284655:Wickelfalzrohr 284655, Wickelfalzrohr
In: Erdgeschoss
Type - Material: IfcSurfaceStyle #251447
Type - Andere - Kategorie: Allgemeines Modell; Familienname: Wickelfalzrohr 284655
Type - ID-Daten - Typname: Wickelfalzrohr 284655
Type - IFC-Parameter - Typ in IFC-Datei exportieren: Vorgabe
Description: Wickelfalzrohr
Pset_DistributionFlowElementCommon - Reference: Wickelfalzrohr 284655; sets with these values: 2
Andere - Typ: Wickelfalzrohr 284655; Familie: Wickelfalzrohr 284655; Familie und Typ: Wickelfalzrohr 284655: Wickelfalzrohr 284655; Typ-ID: 2534244
Abhängigkeiten - Höhe von Ebene: 0 m; Verschieben mit umliegenden Elementen: no
Bemaßungen - Fläche: 0.192619 m2; Volumen: 0.0158077 m3
IFC-Parameter - In IFC-Datei exportieren: Nach Typ; Pset MEP.Tech-Material (ID): 1; Pset MEP.Geom-Ø (mm): 250; In IFC exportieren als: ifcflowsegment; NameOverride: Wickelfalzrohr; IfcPresentationLayer: 0-TFT-H_Abgasabführung Variante 2; ObjectTypeOverride: Wickelfalzrohr; Pset MEP.Name: Wickelfalzrohr; IfcDescription: Wickelfalzrohr; Pset MEP.Geom-Length (mm): 493; Pset MEP.Abbreviation: R-R; Pset MEP.Tech-Medium: L_Entrauchung
Phasen - Phase erstellt: Phase 01

# IfcFlowSegment: Wickelfalzrohr 284810:Wickelfalzrohr 284810, Wickelfalzrohr
In: Erdgeschoss
Type - Material: IfcSurfaceStyle #251447
Type - Andere - Kategorie: Allgemeines Modell; Familienname: Wickelfalzrohr 284810
Type - ID-Daten - Typname: Wickelfalzrohr 284810
Type - IFC-Parameter - Typ in IFC-Datei exportieren: Vorgabe
Description: Wickelfalzrohr
Pset_DistributionFlowElementCommon - Reference: Wickelfalzrohr 284810; sets with these values: 2
Andere - Typ: Wickelfalzrohr 284810; Familie: Wickelfalzrohr 284810; Familie und Typ: Wickelfalzrohr 284810: Wickelfalzrohr 284810; Typ-ID: 2534251
Abhängigkeiten - Höhe von Ebene: 0 m; Verschieben mit umliegenden Elementen: no
Bemaßungen - Fläche: 7.81417 m2; Volumen: 0.641288 m3
IFC-Parameter - In IFC-Datei exportieren: Nach Typ; Pset MEP.Tech-Material (ID): 1; Pset MEP.Geom-Length (mm): 20000; Pset MEP.Geom-Ø (mm): 250; In IFC exportieren als: ifcflowsegment; NameOverride: Wickelfalzrohr; IfcPresentationLayer: 0-TFT-H_Abgasabführung Variante 2; ObjectTypeOverride: Wickelfalzrohr; Pset MEP.Name: Wickelfalzrohr; IfcDescription: Wickelfalzrohr; Pset MEP.Abbreviation: R-R; Pset MEP.Tech-Medium: L_Entrauchung
Phasen - Phase erstellt: Phase 01

# IfcFlowSegment: Wickelfalzrohr 284985:Wickelfalzrohr 284985, Wickelfalzrohr
In: Erdgeschoss
Type - Material: IfcSurfaceStyle #251447
Type - Andere - Kategorie: Allgemeines Modell; Familienname: Wickelfalzrohr 284985
Type - ID-Daten - Typname: Wickelfalzrohr 284985
Type - IFC-Parameter - Typ in IFC-Datei exportieren: Vorgabe
Description: Wickelfalzrohr
Pset_DistributionFlowElementCommon - Reference: Wickelfalzrohr 284985; sets with these values: 2
Andere - Typ: Wickelfalzrohr 284985; Familie: Wickelfalzrohr 284985; Familie und Typ: Wickelfalzrohr 284985: Wickelfalzrohr 284985; Typ-ID: 2534265
Abhängigkeiten - Höhe von Ebene: 0 m; Verschieben mit umliegenden Elementen: no
Bemaßungen - Fläche: 0.106273 m2; Volumen: 0.0139544 m3
IFC-Parameter - In IFC-Datei exportieren: Nach Typ; Pset MEP.Geom-Ø (mm): 400; Pset MEP.Tech-Material (ID): 1; Pset MEP.Geom-Length (mm): 170; In IFC exportieren als: ifcflowsegment; NameOverride: Wickelfalzrohr; IfcPresentationLayer: 0-TFT-H_Abgasabführung Variante 2; ObjectTypeOverride: Wickelfalzrohr; Pset MEP.Name: Wickelfalzrohr; IfcDescription: Wickelfalzrohr; Pset MEP.Abbreviation: R-R; Pset MEP.Tech-Medium: L_Entrauchung
Phasen - Phase erstellt: Phase 01

# IfcFlowSegment: Wickelfalzrohr 285008:Wickelfalzrohr 285008, Wickelfalzrohr
In: Erdgeschoss
Type - Material: IfcSurfaceStyle #251447
Type - Andere - Kategorie: Allgemeines Modell; Familienname: Wickelfalzrohr 285008
Type - ID-Daten - Typname: Wickelfalzrohr 285008
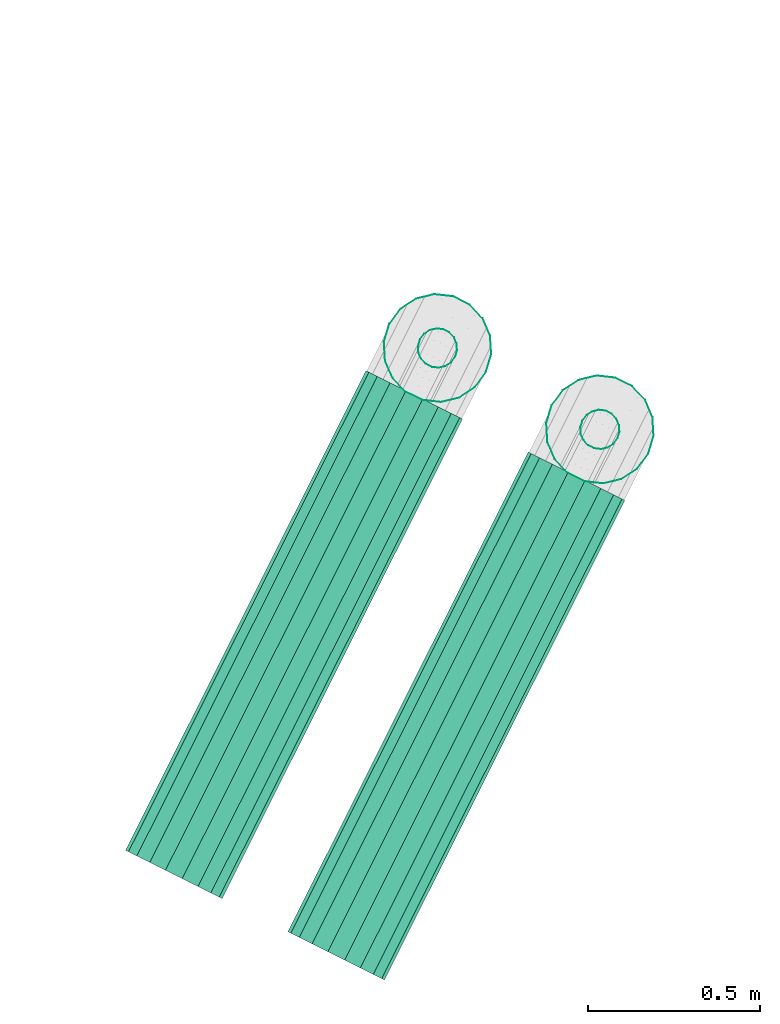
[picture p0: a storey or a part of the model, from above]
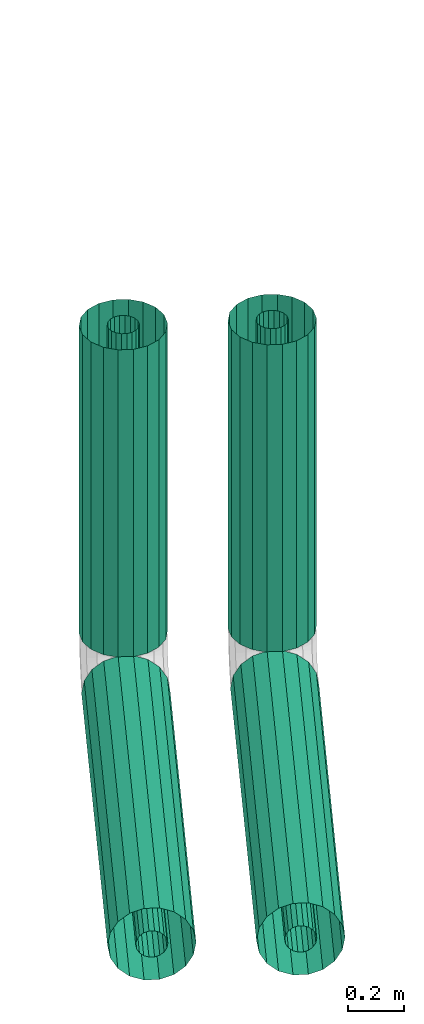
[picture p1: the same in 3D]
Properties of the parts of a building model (IFC2X3), part 22 of 23

# IfcFlowSegment: Wickelfalzrohr 285008:Wickelfalzrohr 285008, Wickelfalzrohr
Type - IFC-Parameter - Typ in IFC-Datei exportieren: Vorgabe
Description: Wickelfalzrohr
Pset_DistributionFlowElementCommon - Reference: Wickelfalzrohr 285008; sets with these values: 2
Andere - Typ: Wickelfalzrohr 285008; Familie: Wickelfalzrohr 285008; Familie und Typ: Wickelfalzrohr 285008: Wickelfalzrohr 285008; Typ-ID: 2534272
Abhängigkeiten - Höhe von Ebene: 0 m; Verschieben mit umliegenden Elementen: no
Bemaßungen - Fläche: 0.106273 m2; Volumen: 0.0139544 m3
IFC-Parameter - In IFC-Datei exportieren: Nach Typ; Pset MEP.Geom-Ø (mm): 400; Pset MEP.Tech-Material (ID): 1; Pset MEP.Geom-Length (mm): 170; In IFC exportieren als: ifcflowsegment; NameOverride: Wickelfalzrohr; IfcPresentationLayer: 0-TFT-H_Abgasabführung Variante 2; ObjectTypeOverride: Wickelfalzrohr; Pset MEP.Name: Wickelfalzrohr; IfcDescription: Wickelfalzrohr; Pset MEP.Abbreviation: R-R; Pset MEP.Tech-Medium: L_Entrauchung
Phasen - Phase erstellt: Phase 01

# IfcFlowSegment: Wickelfalzrohr 285031:Wickelfalzrohr 285031, Wickelfalzrohr
In: Erdgeschoss
Type - Material: IfcSurfaceStyle #251447
Type - Andere - Kategorie: Allgemeines Modell; Familienname: Wickelfalzrohr 285031
Type - ID-Daten - Typname: Wickelfalzrohr 285031
Type - IFC-Parameter - Typ in IFC-Datei exportieren: Vorgabe
Description: Wickelfalzrohr
Pset_DistributionFlowElementCommon - Reference: Wickelfalzrohr 285031; sets with these values: 2
Andere - Typ: Wickelfalzrohr 285031; Familie: Wickelfalzrohr 285031; Familie und Typ: Wickelfalzrohr 285031: Wickelfalzrohr 285031; Typ-ID: 2534279
Abhängigkeiten - Höhe von Ebene: 0 m; Verschieben mit umliegenden Elementen: no
Bemaßungen - Fläche: 0.106273 m2; Volumen: 0.0139544 m3
IFC-Parameter - In IFC-Datei exportieren: Nach Typ; Pset MEP.Geom-Ø (mm): 400; Pset MEP.Tech-Material (ID): 1; Pset MEP.Geom-Length (mm): 170; In IFC exportieren als: ifcflowsegment; NameOverride: Wickelfalzrohr; IfcPresentationLayer: 0-TFT-H_Abgasabführung Variante 2; ObjectTypeOverride: Wickelfalzrohr; Pset MEP.Name: Wickelfalzrohr; IfcDescription: Wickelfalzrohr; Pset MEP.Abbreviation: R-R; Pset MEP.Tech-Medium: L_Entrauchung
Phasen - Phase erstellt: Phase 01

# IfcFlowSegment: Wickelfalzrohr 293628:Wickelfalzrohr 293628, Wickelfalzrohr
In: Erdgeschoss
Type - Material: IfcSurfaceStyle #251447
Type - Andere - Kategorie: Allgemeines Modell; Familienname: Wickelfalzrohr 293628
Type - ID-Daten - Typname: Wickelfalzrohr 293628
Type - IFC-Parameter - Typ in IFC-Datei exportieren: Vorgabe
Description: Wickelfalzrohr
Pset_DistributionFlowElementCommon - Reference: Wickelfalzrohr 293628; sets with these values: 2
Andere - Typ: Wickelfalzrohr 293628; Familie: Wickelfalzrohr 293628; Familie und Typ: Wickelfalzrohr 293628: Wickelfalzrohr 293628; Typ-ID: 2534403
Abhängigkeiten - Höhe von Ebene: 0 m; Verschieben mit umliegenden Elementen: no
Bemaßungen - Fläche: 7.81417 m2; Volumen: 0.641288 m3
IFC-Parameter - In IFC-Datei exportieren: Nach Typ; Pset MEP.Tech-Material (ID): 1; Pset MEP.Geom-Length (mm): 20000; Pset MEP.Geom-Ø (mm): 250; In IFC exportieren als: ifcflowsegment; NameOverride: Wickelfalzrohr; IfcPresentationLayer: 0-TFT-H_Abgasabführung Variante 3; ObjectTypeOverride: Wickelfalzrohr; Pset MEP.Name: Wickelfalzrohr; IfcDescription: Wickelfalzrohr; Pset MEP.Abbreviation: R-R; Pset MEP.Tech-Medium: L_Entrauchung
Phasen - Phase erstellt: Phase 01

# IfcFlowSegment: Wickelfalzrohr 293699:Wickelfalzrohr 293699, Wickelfalzrohr
In: Erdgeschoss
Type - Material: IfcSurfaceStyle #251447
Type - Andere - Kategorie: Allgemeines Modell; Familienname: Wickelfalzrohr 293699
Type - ID-Daten - Typname: Wickelfalzrohr 293699
Type - IFC-Parameter - Typ in IFC-Datei exportieren: Vorgabe
Description: Wickelfalzrohr
Pset_DistributionFlowElementCommon - Reference: Wickelfalzrohr 293699; sets with these values: 2
Andere - Typ: Wickelfalzrohr 293699; Familie: Wickelfalzrohr 293699; Familie und Typ: Wickelfalzrohr 293699: Wickelfalzrohr 293699; Typ-ID: 2534424
Abhängigkeiten - Höhe von Ebene: 0 m; Verschieben mit umliegenden Elementen: no
Bemaßungen - Fläche: 0.117213 m2; Volumen: 0.00961932 m3
IFC-Parameter - In IFC-Datei exportieren: Nach Typ; Pset MEP.Tech-Material (ID): 1; Pset MEP.Geom-Length (mm): 300; Pset MEP.Geom-Ø (mm): 250; In IFC exportieren als: ifcflowsegment; NameOverride: Wickelfalzrohr; IfcPresentationLayer: 0-TFT-H_Abgasabführung Variante 2; ObjectTypeOverride: Wickelfalzrohr; Pset MEP.Name: Wickelfalzrohr; IfcDescription: Wickelfalzrohr; Pset MEP.Abbreviation: R-R; Pset MEP.Tech-Medium: L_Entrauchung
Phasen - Phase erstellt: Phase 01

# IfcFlowSegment: Wickelfalzrohr 293792:Wickelfalzrohr 293792, Wickelfalzrohr
In: Erdgeschoss
Type - Material: IfcSurfaceStyle #251447
Type - Andere - Kategorie: Allgemeines Modell; Familienname: Wickelfalzrohr 293792
Type - ID-Daten - Typname: Wickelfalzrohr 293792
Type - IFC-Parameter - Typ in IFC-Datei exportieren: Vorgabe
Description: Wickelfalzrohr
Pset_DistributionFlowElementCommon - Reference: Wickelfalzrohr 293792; sets with these values: 2
Andere - Typ: Wickelfalzrohr 293792; Familie: Wickelfalzrohr 293792; Familie und Typ: Wickelfalzrohr 293792: Wickelfalzrohr 293792; Typ-ID: 2534452
Abhängigkeiten - Höhe von Ebene: 0 m; Verschieben mit umliegenden Elementen: no
Bemaßungen - Fläche: 1.16295 m2; Volumen: 0.09544 m3
IFC-Parameter - In IFC-Datei exportieren: Nach Typ; Pset MEP.Tech-Material (ID): 1; Pset MEP.Geom-Ø (mm): 250; In IFC exportieren als: ifcflowsegment; NameOverride: Wickelfalzrohr; IfcPresentationLayer: 0-TFT-H_Abgasabführung Variante 3; ObjectTypeOverride: Wickelfalzrohr; Pset MEP.Name: Wickelfalzrohr; IfcDescription: Wickelfalzrohr; Pset MEP.Geom-Length (mm): 2976.51; Pset MEP.Abbreviation: R-R; Pset MEP.Tech-Medium: L_Entrauchung
Phasen - Phase erstellt: Phase 01

# IfcFlowSegment: Wickelfalzrohr 293947:Wickelfalzrohr 293947, Wickelfalzrohr
In: Erdgeschoss
Type - Material: IfcSurfaceStyle #251447
Type - Andere - Kategorie: Allgemeines Modell; Familienname: Wickelfalzrohr 293947
Type - ID-Daten - Typname: Wickelfalzrohr 293947
Type - IFC-Parameter - Typ in IFC-Datei exportieren: Vorgabe
Description: Wickelfalzrohr
Pset_DistributionFlowElementCommon - Reference: Wickelfalzrohr 293947; sets with these values: 2
Andere - Typ: Wickelfalzrohr 293947; Familie: Wickelfalzrohr 293947; Familie und Typ: Wickelfalzrohr 293947: Wickelfalzrohr 293947; Typ-ID: 2534459
Abhängigkeiten - Höhe von Ebene: 0 m; Verschieben mit umliegenden Elementen: no
Bemaßungen - Fläche: 0.368246 m2; Volumen: 0.030221 m3
IFC-Parameter - In IFC-Datei exportieren: Nach Typ; Pset MEP.Tech-Material (ID): 1; Pset MEP.Geom-Ø (mm): 250; In IFC exportieren als: ifcflowsegment; NameOverride: Wickelfalzrohr; IfcPresentationLayer: 0-TFT-H_Abgasabführung Variante 3; ObjectTypeOverride: Wickelfalzrohr; Pset MEP.Name: Wickelfalzrohr; IfcDescription: Wickelfalzrohr; Pset MEP.Geom-Length (mm): 942.509; Pset MEP.Abbreviation: R-R; Pset MEP.Tech-Medium: L_Entrauchung
Phasen - Phase erstellt: Phase 01

# IfcFlowSegment: Wickelfalzrohr 294125:Wickelfalzrohr 294125, Wickelfalzrohr
In: Erdgeschoss
Type - Material: IfcSurfaceStyle #251447
Type - Andere - Kategorie: Allgemeines Modell; Familienname: Wickelfalzrohr 294125
Type - ID-Daten - Typname: Wickelfalzrohr 294125
Type - IFC-Parameter - Typ in IFC-Datei exportieren: Vorgabe
Description: Wickelfalzrohr
Pset_DistributionFlowElementCommon - Reference: Wickelfalzrohr 294125; sets with these values: 2
Andere - Typ: Wickelfalzrohr 294125; Familie: Wickelfalzrohr 294125; Familie und Typ: Wickelfalzrohr 294125: Wickelfalzrohr 294125; Typ-ID: 2534473
Abhängigkeiten - Höhe von Ebene: 0 m; Verschieben mit umliegenden Elementen: no
Bemaßungen - Fläche: 0.464003 m2; Volumen: 0.0380795 m3
IFC-Parameter - In IFC-Datei exportieren: Nach Typ; Pset MEP.Tech-Material (ID): 1; Pset MEP.Geom-Ø (mm): 250; In IFC exportieren als: ifcflowsegment; NameOverride: Wickelfalzrohr; IfcPresentationLayer: 0-TFT-H_Abgasabführung Variante 3; ObjectTypeOverride: Wickelfalzrohr; Pset MEP.Name: Wickelfalzrohr; IfcDescription: Wickelfalzrohr; Pset MEP.Geom-Length (mm): 1187.59; Pset MEP.Abbreviation: R-R; Pset MEP.Tech-Medium: L_Entrauchung
Phasen - Phase erstellt: Phase 01

# IfcFlowSegment: Wickelfalzrohr 294280:Wickelfalzrohr 294280, Wickelfalzrohr
In: Erdgeschoss
Type - Material: IfcSurfaceStyle #251447
Type - Andere - Kategorie: Allgemeines Modell; Familienname: Wickelfalzrohr 294280
Type - ID-Daten - Typname: Wickelfalzrohr 294280
Type - IFC-Parameter - Typ in IFC-Datei exportieren: Vorgabe
Description: Wickelfalzrohr
Pset_DistributionFlowElementCommon - Reference: Wickelfalzrohr 294280; sets with these values: 2
Andere - Typ: Wickelfalzrohr 294280; Familie: Wickelfalzrohr 294280; Familie und Typ: Wickelfalzrohr 294280: Wickelfalzrohr 294280; Typ-ID: 2534480
Abhängigkeiten - Höhe von Ebene: 0 m; Verschieben mit umliegenden Elementen: no
Bemaßungen - Fläche: 1.04568 m2; Volumen: 0.0858162 m3
IFC-Parameter - In IFC-Datei exportieren: Nach Typ; Pset MEP.Tech-Material (ID): 1; Pset MEP.Geom-Ø (mm): 250; In IFC exportieren als: ifcflowsegment; NameOverride: Wickelfalzrohr; IfcPresentationLayer: 0-TFT-H_Abgasabführung Variante 3; ObjectTypeOverride: Wickelfalzrohr; Pset MEP.Name: Wickelfalzrohr; IfcDescription: Wickelfalzrohr; Pset MEP.Geom-Length (mm): 2676.37; Pset MEP.Abbreviation: R-R; Pset MEP.Tech-Medium: L_Entrauchung
Phasen - Phase erstellt: Phase 01

# IfcFlowSegment: Wickelfalzrohr 294435:Wickelfalzrohr 294435, Wickelfalzrohr
In: Erdgeschoss
Type - Material: IfcSurfaceStyle #251447
Type - Andere - Kategorie: Allgemeines Modell; Familienname: Wickelfalzrohr 294435
Type - ID-Daten - Typname: Wickelfalzrohr 294435
Type - IFC-Parameter - Typ in IFC-Datei exportieren: Vorgabe
Description: Wickelfalzrohr
Pset_DistributionFlowElementCommon - Reference: Wickelfalzrohr 294435; sets with these values: 2
Andere - Typ: Wickelfalzrohr 294435; Familie: Wickelfalzrohr 294435; Familie und Typ: Wickelfalzrohr 294435: Wickelfalzrohr 294435; Typ-ID: 2534487
Abhängigkeiten - Höhe von Ebene: 0 m; Verschieben mit umliegenden Elementen: no
Bemaßungen - Fläche: 0.118627 m2; Volumen: 0.00973536 m3
IFC-Parameter - In IFC-Datei exportieren: Nach Typ; Pset MEP.Tech-Material (ID): 1; Pset MEP.Geom-Ø (mm): 250; In IFC exportieren als: ifcflowsegment; NameOverride: Wickelfalzrohr; IfcPresentationLayer: 0-TFT-H_Abgasabführung Variante 3; ObjectTypeOverride: Wickelfalzrohr; Pset MEP.Name: Wickelfalzrohr; IfcDescription: Wickelfalzrohr; Pset MEP.Geom-Length (mm): 303.619; Pset MEP.Abbreviation: R-R; Pset MEP.Tech-Medium: L_Entrauchung
Phasen - Phase erstellt: Phase 01

# IfcFlowSegment: Wickelfalzrohr 294613:Wickelfalzrohr 294613, Wickelfalzrohr
In: Erdgeschoss
Type - Material: IfcSurfaceStyle #251447
Type - Andere - Kategorie: Allgemeines Modell; Familienname: Wickelfalzrohr 294613
Type - ID-Daten - Typname: Wickelfalzrohr 294613
Type - IFC-Parameter - Typ in IFC-Datei exportieren: Vorgabe
Description: Wickelfalzrohr
Pset_DistributionFlowElementCommon - Reference: Wickelfalzrohr 294613; sets with these values: 2
Andere - Typ: Wickelfalzrohr 294613; Familie: Wickelfalzrohr 294613; Familie und Typ: Wickelfalzrohr 294613: Wickelfalzrohr 294613; Typ-ID: 2534501
Abhängigkeiten - Höhe von Ebene: 0 m; Verschieben mit umliegenden Elementen: no
Bemaßungen - Fläche: 12.5027 m2; Volumen: 1.6417 m3
IFC-Parameter - In IFC-Datei exportieren: Nach Typ; Pset MEP.Geom-Ø (mm): 400; Pset MEP.Tech-Material (ID): 1; Pset MEP.Geom-Length (mm): 20000; In IFC exportieren als: ifcflowsegment; NameOverride: Wickelfalzrohr; IfcPresentationLayer: 0-TFT-H_Abgasabführung Variante 3; ObjectTypeOverride: Wickelfalzrohr; Pset MEP.Name: Wickelfalzrohr; IfcDescription: Wickelfalzrohr; Pset MEP.Abbreviation: R-R; Pset MEP.Tech-Medium: L_Entrauchung
Phasen - Phase erstellt: Phase 01

# IfcFlowSegment: Wickelfalzrohr 294702:Wickelfalzrohr 294702, Wickelfalzrohr
In: Erdgeschoss
Type - Material: IfcSurfaceStyle #251447
Type - Andere - Kategorie: Allgemeines Modell; Familienname: Wickelfalzrohr 294702
Type - ID-Daten - Typname: Wickelfalzrohr 294702
Type - IFC-Parameter - Typ in IFC-Datei exportieren: Vorgabe
Description: Wickelfalzrohr
Pset_DistributionFlowElementCommon - Reference: Wickelfalzrohr 294702; sets with these values: 2
Andere - Typ: Wickelfalzrohr 294702; Familie: Wickelfalzrohr 294702; Familie und Typ: Wickelfalzrohr 294702: Wickelfalzrohr 294702; Typ-ID: 2534529
Abhängigkeiten - Höhe von Ebene: 0 m; Verschieben mit umliegenden Elementen: no
Bemaßungen - Fläche: 0.106273 m2; Volumen: 0.0139544 m3
IFC-Parameter - In IFC-Datei exportieren: Nach Typ; Pset MEP.Geom-Ø (mm): 400; Pset MEP.Tech-Material (ID): 1; Pset MEP.Geom-Length (mm): 170; In IFC exportieren als: ifcflowsegment; NameOverride: Wickelfalzrohr; IfcPresentationLayer: 0-TFT-H_Abgasabführung Variante 3; ObjectTypeOverride: Wickelfalzrohr; Pset MEP.Name: Wickelfalzrohr; IfcDescription: Wickelfalzrohr; Pset MEP.Abbreviation: R-R; Pset MEP.Tech-Medium: L_Entrauchung
Phasen - Phase erstellt: Phase 01

# IfcFlowSegment: Wickelfalzrohr 295116:Wickelfalzrohr 295116, Wickelfalzrohr
In: Erdgeschoss
Type - Material: IfcSurfaceStyle #251447
Type - Andere - Kategorie: Allgemeines Modell; Familienname: Wickelfalzrohr 295116
Type - ID-Daten - Typname: Wickelfalzrohr 295116
Type - IFC-Parameter - Typ in IFC-Datei exportieren: Vorgabe
Description: Wickelfalzrohr
Pset_DistributionFlowElementCommon - Reference: Wickelfalzrohr 295116; sets with these values: 2
Andere - Typ: Wickelfalzrohr 295116; Familie: Wickelfalzrohr 295116; Familie und Typ: Wickelfalzrohr 295116: Wickelfalzrohr 295116; Typ-ID: 2534550
Abhängigkeiten - Höhe von Ebene: 0 m; Verschieben mit umliegenden Elementen: no
Bemaßungen - Fläche: 0.18754 m2; Volumen: 0.0246255 m3
IFC-Parameter - In IFC-Datei exportieren: Nach Typ; Pset MEP.Geom-Ø (mm): 400; Pset MEP.Tech-Material (ID): 1; Pset MEP.Geom-Length (mm): 300; In IFC exportieren als: ifcflowsegment; NameOverride: Wickelfalzrohr; IfcPresentationLayer: 0-TFT-H_Abgasabführung Variante 3; ObjectTypeOverride: Wickelfalzrohr; Pset MEP.Name: Wickelfalzrohr; IfcDescription: Wickelfalzrohr; Pset MEP.Abbreviation: R-R; Pset MEP.Tech-Medium: L_Entrauchung
Phasen - Phase erstellt: Phase 01

# IfcFlowSegment: Wickelfalzrohr 295136:Wickelfalzrohr 295136, Wickelfalzrohr
In: Erdgeschoss
Type - Material: IfcSurfaceStyle #251447
Type - Andere - Kategorie: Allgemeines Modell; Familienname: Wickelfalzrohr 295136
Type - ID-Daten - Typname: Wickelfalzrohr 295136
Type - IFC-Parameter - Typ in IFC-Datei exportieren: Vorgabe
Description: Wickelfalzrohr
Pset_DistributionFlowElementCommon - Reference: Wickelfalzrohr 295136; sets with these values: 2
Andere - Typ: Wickelfalzrohr 295136; Familie: Wickelfalzrohr 295136; Familie und Typ: Wickelfalzrohr 295136: Wickelfalzrohr 295136; Typ-ID: 2534557
Abhängigkeiten - Höhe von Ebene: 0 m; Verschieben mit umliegenden Elementen: no
Bemaßungen - Fläche: 0.376331 m2; Volumen: 0.0494151 m3
IFC-Parameter - In IFC-Datei exportieren: Nach Typ; Pset MEP.Geom-Ø (mm): 400; Pset MEP.Tech-Material (ID): 1; In IFC exportieren als: ifcflowsegment; NameOverride: Wickelfalzrohr; IfcPresentationLayer: 0-TFT-H_Abgasabführung Variante 3; ObjectTypeOverride: Wickelfalzrohr; Pset MEP.Name: Wickelfalzrohr; IfcDescription: Wickelfalzrohr; Pset MEP.Geom-Length (mm): 602.001; Pset MEP.Abbreviation: R-R; Pset MEP.Tech-Medium: L_Entrauchung
Phasen - Phase erstellt: Phase 01

# IfcFlowSegment: Wickelfalzrohr 295314:Wickelfalzrohr 295314, Wickelfalzrohr
In: Erdgeschoss
Type - Material: IfcSurfaceStyle #251447
Type - Andere - Kategorie: Allgemeines Modell; Familienname: Wickelfalzrohr 295314
Type - ID-Daten - Typname: Wickelfalzrohr 295314
Type - IFC-Parameter - Typ in IFC-Datei exportieren: Vorgabe
Description: Wickelfalzrohr
Pset_DistributionFlowElementCommon - Reference: Wickelfalzrohr 295314; sets with these values: 2
Andere - Typ: Wickelfalzrohr 295314; Familie: Wickelfalzrohr 295314; Familie und Typ: Wickelfalzrohr 295314: Wickelfalzrohr 295314; Typ-ID: 2534571
Abhängigkeiten - Höhe von Ebene: 0 m; Verschieben mit umliegenden Elementen: no
Bemaßungen - Fläche: 0.18754 m2; Volumen: 0.0246255 m3
IFC-Parameter - In IFC-Datei exportieren: Nach Typ; Pset MEP.Geom-Ø (mm): 400; Pset MEP.Tech-Material (ID): 1; Pset MEP.Geom-Length (mm): 300; In IFC exportieren als: ifcflowsegment; NameOverride: Wickelfalzrohr; IfcPresentationLayer: 0-TFT-H_Abgasabführung Variante 3; ObjectTypeOverride: Wickelfalzrohr; Pset MEP.Name: Wickelfalzrohr; IfcDescription: Wickelfalzrohr; Pset MEP.Abbreviation: R-R; Pset MEP.Tech-Medium: L_Entrauchung
Phasen - Phase erstellt: Phase 01

# IfcFlowSegment: Wickelfalzrohr 295334:Wickelfalzrohr 295334, Wickelfalzrohr
In: Erdgeschoss
Type - Material: IfcSurfaceStyle #251447
Type - Andere - Kategorie: Allgemeines Modell; Familienname: Wickelfalzrohr 295334
Type - ID-Daten - Typname: Wickelfalzrohr 295334
Type - IFC-Parameter - Typ in IFC-Datei exportieren: Vorgabe
Description: Wickelfalzrohr
Pset_DistributionFlowElementCommon - Reference: Wickelfalzrohr 295334; sets with these values: 2
Andere - Typ: Wickelfalzrohr 295334; Familie: Wickelfalzrohr 295334; Familie und Typ: Wickelfalzrohr 295334: Wickelfalzrohr 295334; Typ-ID: 2534578
Abhängigkeiten - Höhe von Ebene: 0 m; Verschieben mit umliegenden Elementen: no
Bemaßungen - Fläche: 0.106273 m2; Volumen: 0.0139544 m3
IFC-Parameter - In IFC-Datei exportieren: Nach Typ; Pset MEP.Geom-Ø (mm): 400; Pset MEP.Tech-Material (ID): 1; Pset MEP.Geom-Length (mm): 170; In IFC exportieren als: ifcflowsegment; NameOverride: Wickelfalzrohr; IfcPresentationLayer: 0-TFT-H_Abgasabführung Variante 3; ObjectTypeOverride: Wickelfalzrohr; Pset MEP.Name: Wickelfalzrohr; IfcDescription: Wickelfalzrohr; Pset MEP.Abbreviation: R-R; Pset MEP.Tech-Medium: L_Entrauchung
Phasen - Phase erstellt: Phase 01

# IfcFlowSegment: Wickelfalzrohr 295868:Wickelfalzrohr 295868, Wickelfalzrohr
In: Erdgeschoss
Type - Material: IfcSurfaceStyle #251447
Type - Andere - Kategorie: Allgemeines Modell; Familienname: Wickelfalzrohr 295868
Type - ID-Daten - Typname: Wickelfalzrohr 295868
Type - IFC-Parameter - Typ in IFC-Datei exportieren: Vorgabe
Description: Wickelfalzrohr
Pset_DistributionFlowElementCommon - Reference: Wickelfalzrohr 295868; sets with these values: 2
Andere - Typ: Wickelfalzrohr 295868; Familie: Wickelfalzrohr 295868; Familie und Typ: Wickelfalzrohr 295868: Wickelfalzrohr 295868; Typ-ID: 2534613
Abhängigkeiten - Höhe von Ebene: 0 m; Verschieben mit umliegenden Elementen: no
Bemaßungen - Fläche: 12.5027 m2; Volumen: 1.6417 m3
IFC-Parameter - In IFC-Datei exportieren: Nach Typ; Pset MEP.Geom-Ø (mm): 400; Pset MEP.Tech-Material (ID): 1; Pset MEP.Geom-Length (mm): 20000; In IFC exportieren als: ifcflowsegment; NameOverride: Wickelfalzrohr; IfcPresentationLayer: 0-TFT-H_Abgasabführung Variante 3; ObjectTypeOverride: Wickelfalzrohr; Pset MEP.Name: Wickelfalzrohr; IfcDescription: Wickelfalzrohr; Pset MEP.Abbreviation: R-R; Pset MEP.Tech-Medium: L_Entrauchung
Phasen - Phase erstellt: Phase 01

# IfcFlowSegment: Wickelfalzrohr 295891:Wickelfalzrohr 295891, Wickelfalzrohr
In: Erdgeschoss
Type - Material: IfcSurfaceStyle #251447
Type - Andere - Kategorie: Allgemeines Modell; Familienname: Wickelfalzrohr 295891
Type - ID-Daten - Typname: Wickelfalzrohr 295891
Type - IFC-Parameter - Typ in IFC-Datei exportieren: Vorgabe
Description: Wickelfalzrohr
Pset_DistributionFlowElementCommon - Reference: Wickelfalzrohr 295891; sets with these values: 2
Andere - Typ: Wickelfalzrohr 295891; Familie: Wickelfalzrohr 295891; Familie und Typ: Wickelfalzrohr 295891: Wickelfalzrohr 295891; Typ-ID: 2534620
Abhängigkeiten - Höhe von Ebene: 0 m; Verschieben mit umliegenden Elementen: no
Bemaßungen - Fläche: 0.157655 m2; Volumen: 0.0207013 m3
IFC-Parameter - In IFC-Datei exportieren: Nach Typ; Pset MEP.Geom-Ø (mm): 400; Pset MEP.Tech-Material (ID): 1; In IFC exportieren als: ifcflowsegment; NameOverride: Wickelfalzrohr; IfcPresentationLayer: 0-TFT-H_Abgasabführung Variante 3; ObjectTypeOverride: Wickelfalzrohr; Pset MEP.Name: Wickelfalzrohr; IfcDescription: Wickelfalzrohr; Pset MEP.Geom-Length (mm): 252.194; Pset MEP.Abbreviation: R-R; Pset MEP.Tech-Medium: L_Entrauchung
Phasen - Phase erstellt: Phase 01

# IfcFlowSegment: Wickelfalzrohr 296073:Wickelfalzrohr 296073, Wickelfalzrohr
In: Erdgeschoss
Type - Material: IfcSurfaceStyle #251447
Type - Andere - Kategorie: Allgemeines Modell; Familienname: Wickelfalzrohr 296073
Type - ID-Daten - Typname: Wickelfalzrohr 296073
Type - IFC-Parameter - Typ in IFC-Datei exportieren: Vorgabe
Description: Wickelfalzrohr
Pset_DistributionFlowElementCommon - Reference: Wickelfalzrohr 296073; sets with these values: 2
Andere - Typ: Wickelfalzrohr 296073; Familie: Wickelfalzrohr 296073; Familie und Typ: Wickelfalzrohr 296073: Wickelfalzrohr 296073; Typ-ID: 2534634
Abhängigkeiten - Höhe von Ebene: 0 m; Verschieben mit umliegenden Elementen: no
Bemaßungen - Fläche: 0.108985 m2; Volumen: 0.0143106 m3
IFC-Parameter - In IFC-Datei exportieren: Nach Typ; Pset MEP.Geom-Ø (mm): 400; Pset MEP.Tech-Material (ID): 1; In IFC exportieren als: ifcflowsegment; NameOverride: Wickelfalzrohr; IfcPresentationLayer: 0-TFT-H_Abgasabführung Variante 3; ObjectTypeOverride: Wickelfalzrohr; Pset MEP.Name: Wickelfalzrohr; IfcDescription: Wickelfalzrohr; Pset MEP.Geom-Length (mm): 174.34; Pset MEP.Abbreviation: R-R; Pset MEP.Tech-Medium: L_Entrauchung
Phasen - Phase erstellt: Phase 01

# IfcFlowSegment: Wickelfalzrohr 296232:Wickelfalzrohr 296232, Wickelfalzrohr
In: Erdgeschoss
Type - Material: IfcSurfaceStyle #251447
Type - Andere - Kategorie: Allgemeines Modell; Familienname: Wickelfalzrohr 296232
Type - ID-Daten - Typname: Wickelfalzrohr 296232
Type - IFC-Parameter - Typ in IFC-Datei exportieren: Vorgabe
Description: Wickelfalzrohr
Pset_DistributionFlowElementCommon - Reference: Wickelfalzrohr 296232; sets with these values: 2
Andere - Typ: Wickelfalzrohr 296232; Familie: Wickelfalzrohr 296232; Familie und Typ: Wickelfalzrohr 296232: Wickelfalzrohr 296232; Typ-ID: 2534641
Abhängigkeiten - Höhe von Ebene: 0 m; Verschieben mit umliegenden Elementen: no
Bemaßungen - Fläche: 2.07201 m2; Volumen: 0.27207 m3
IFC-Parameter - In IFC-Datei exportieren: Nach Typ; Pset MEP.Geom-Ø (mm): 400; Pset MEP.Tech-Material (ID): 1; In IFC exportieren als: ifcflowsegment; NameOverride: Wickelfalzrohr; IfcPresentationLayer: 0-TFT-H_Abgasabführung Variante 3; ObjectTypeOverride: Wickelfalzrohr; Pset MEP.Name: Wickelfalzrohr; IfcDescription: Wickelfalzrohr; Pset MEP.Geom-Length (mm): 3314.5; Pset MEP.Abbreviation: R-R; Pset MEP.Tech-Medium: L_Entrauchung
Phasen - Phase erstellt: Phase 01

# IfcFlowSegment: Wickelfalzrohr 296387:Wickelfalzrohr 296387, Wickelfalzrohr
In: Erdgeschoss
Type - Material: IfcSurfaceStyle #251447
Type - Andere - Kategorie: Allgemeines Modell; Familienname: Wickelfalzrohr 296387
Type - ID-Daten - Typname: Wickelfalzrohr 296387
Type - IFC-Parameter - Typ in IFC-Datei exportieren: Vorgabe
Description: Wickelfalzrohr
Pset_DistributionFlowElementCommon - Reference: Wickelfalzrohr 296387; sets with these values: 2
Andere - Typ: Wickelfalzrohr 296387; Familie: Wickelfalzrohr 296387; Familie und Typ: Wickelfalzrohr 296387: Wickelfalzrohr 296387; Typ-ID: 2534648
Abhängigkeiten - Höhe von Ebene: 0 m; Verschieben mit umliegenden Elementen: no
Bemaßungen - Fläche: 12.5027 m2; Volumen: 1.6417 m3
IFC-Parameter - In IFC-Datei exportieren: Nach Typ; Pset MEP.Geom-Ø (mm): 400; Pset MEP.Tech-Material (ID): 1; Pset MEP.Geom-Length (mm): 20000; In IFC exportieren als: ifcflowsegment; NameOverride: Wickelfalzrohr; IfcPresentationLayer: 0-TFT-H_Abgasabführung Variante 3; ObjectTypeOverride: Wickelfalzrohr; Pset MEP.Name: Wickelfalzrohr; IfcDescription: Wickelfalzrohr; Pset MEP.Abbreviation: R-R; Pset MEP.Tech-Medium: L_Entrauchung
Phasen - Phase erstellt: Phase 01

# IfcFlowSegment: Wickelfalzrohr 296433:Wickelfalzrohr 296433, Wickelfalzrohr
In: Erdgeschoss
Type - Material: IfcSurfaceStyle #251447
Type - Andere - Kategorie: Allgemeines Modell; Familienname: Wickelfalzrohr 296433
Type - ID-Daten - Typname: Wickelfalzrohr 296433
Type - IFC-Parameter - Typ in IFC-Datei exportieren: Vorgabe
Description: Wickelfalzrohr
Pset_DistributionFlowElementCommon - Reference: Wickelfalzrohr 296433; sets with these values: 2
Andere - Typ: Wickelfalzrohr 296433; Familie: Wickelfalzrohr 296433; Familie und Typ: Wickelfalzrohr 296433: Wickelfalzrohr 296433; Typ-ID: 2534662
Abhängigkeiten - Höhe von Ebene: 0 m; Verschieben mit umliegenden Elementen: no
Bemaßungen - Fläche: 2.70318 m2; Volumen: 0.354948 m3
IFC-Parameter - In IFC-Datei exportieren: Nach Typ; Pset MEP.Geom-Ø (mm): 400; Pset MEP.Tech-Material (ID): 1; In IFC exportieren als: ifcflowsegment; NameOverride: Wickelfalzrohr; IfcPresentationLayer: 0-TFT-H_Abgasabführung Variante 3; ObjectTypeOverride: Wickelfalzrohr; Pset MEP.Name: Wickelfalzrohr; IfcDescription: Wickelfalzrohr; Pset MEP.Geom-Length (mm): 4324.17; Pset MEP.Abbreviation: R-R; Pset MEP.Tech-Medium: L_Entrauchung
Phasen - Phase erstellt: Phase 01

# IfcFlowSegment: Wickelfalzrohr 296660:Wickelfalzrohr 296660, Wickelfalzrohr
In: Erdgeschoss
Type - Material: IfcSurfaceStyle #251447
Type - Andere - Kategorie: Allgemeines Modell; Familienname: Wickelfalzrohr 296660
Type - ID-Daten - Typname: Wickelfalzrohr 296660
Type - IFC-Parameter - Typ in IFC-Datei exportieren: Vorgabe
Description: Wickelfalzrohr
Pset_DistributionFlowElementCommon - Reference: Wickelfalzrohr 296660; sets with these values: 2
Andere - Typ: Wickelfalzrohr 296660; Familie: Wickelfalzrohr 296660; Familie und Typ: Wickelfalzrohr 296660: Wickelfalzrohr 296660; Typ-ID: 2534690
Abhängigkeiten - Höhe von Ebene: 0 m; Verschieben mit umliegenden Elementen: no
Bemaßungen - Fläche: 0.623647 m2; Volumen: 0.0818897 m3
IFC-Parameter - In IFC-Datei exportieren: Nach Typ; Pset MEP.Geom-Ø (mm): 400; Pset MEP.Tech-Material (ID): 1; In IFC exportieren als: ifcflowsegment; NameOverride: Wickelfalzrohr; IfcPresentationLayer: 0-TFT-H_Abgasabführung Variante 3; ObjectTypeOverride: Wickelfalzrohr; Pset MEP.Name: Wickelfalzrohr; IfcDescription: Wickelfalzrohr; Pset MEP.Geom-Length (mm): 997.622; Pset MEP.Abbreviation: R-R; Pset MEP.Tech-Medium: L_Entrauchung
Phasen - Phase erstellt: Phase 01

# IfcFlowSegment: Wickelfalzrohr 296817:Wickelfalzrohr 296817, Wickelfalzrohr
In: Erdgeschoss
Type - Material: IfcSurfaceStyle #251447
Type - Andere - Kategorie: Allgemeines Modell; Familienname: Wickelfalzrohr 296817
Type - ID-Daten - Typname: Wickelfalzrohr 296817
Type - IFC-Parameter - Typ in IFC-Datei exportieren: Vorgabe
Description: Wickelfalzrohr
Pset_DistributionFlowElementCommon - Reference: Wickelfalzrohr 296817; sets with these values: 2
Andere - Typ: Wickelfalzrohr 296817; Familie: Wickelfalzrohr 296817; Familie und Typ: Wickelfalzrohr 296817: Wickelfalzrohr 296817; Typ-ID: 2534697
Abhängigkeiten - Höhe von Ebene: 0 m; Verschieben mit umliegenden Elementen: no
Bemaßungen - Fläche: 0.18754 m2; Volumen: 0.0246255 m3
IFC-Parameter - In IFC-Datei exportieren: Nach Typ; Pset MEP.Geom-Ø (mm): 400; Pset MEP.Tech-Material (ID): 1; Pset MEP.Geom-Length (mm): 300; In IFC exportieren als: ifcflowsegment; NameOverride: Wickelfalzrohr; IfcPresentationLayer: 0-TFT-H_Abgasabführung Variante 3; ObjectTypeOverride: Wickelfalzrohr; Pset MEP.Name: Wickelfalzrohr; IfcDescription: Wickelfalzrohr; Pset MEP.Abbreviation: R-R; Pset MEP.Tech-Medium: L_Entrauchung
Phasen - Phase erstellt: Phase 01

# IfcFlowSegment: Wickelfalzrohr 296887:Wickelfalzrohr 296887, Wickelfalzrohr
In: Erdgeschoss
Type - Material: IfcSurfaceStyle #251447
Type - Andere - Kategorie: Allgemeines Modell; Familienname: Wickelfalzrohr 296887
Type - ID-Daten - Typname: Wickelfalzrohr 296887
Type - IFC-Parameter - Typ in IFC-Datei exportieren: Vorgabe
Description: Wickelfalzrohr
Pset_DistributionFlowElementCommon - Reference: Wickelfalzrohr 296887; sets with these values: 2
Andere - Typ: Wickelfalzrohr 296887; Familie: Wickelfalzrohr 296887; Familie und Typ: Wickelfalzrohr 296887: Wickelfalzrohr 296887; Typ-ID: 2534718
Abhängigkeiten - Höhe von Ebene: 0 m; Verschieben mit umliegenden Elementen: no
Bemaßungen - Fläche: 0.4233 m2; Volumen: 0.0555826 m3
IFC-Parameter - In IFC-Datei exportieren: Nach Typ; Pset MEP.Geom-Ø (mm): 400; Pset MEP.Tech-Material (ID): 1; In IFC exportieren als: ifcflowsegment; NameOverride: Wickelfalzrohr; IfcPresentationLayer: 0-TFT-H_Abgasabführung Variante 3; ObjectTypeOverride: Wickelfalzrohr; Pset MEP.Name: Wickelfalzrohr; IfcDescription: Wickelfalzrohr; Pset MEP.Geom-Length (mm): 677.136; Pset MEP.Abbreviation: R-R; Pset MEP.Tech-Medium: L_Entrauchung
Phasen - Phase erstellt: Phase 01

# IfcFlowSegment: Wickelfalzrohr 297042:Wickelfalzrohr 297042, Wickelfalzrohr
In: Erdgeschoss
Type - Material: IfcSurfaceStyle #251447
Type - Andere - Kategorie: Allgemeines Modell; Familienname: Wickelfalzrohr 297042
Type - ID-Daten - Typname: Wickelfalzrohr 297042
Type - IFC-Parameter - Typ in IFC-Datei exportieren: Vorgabe
Description: Wickelfalzrohr
Pset_DistributionFlowElementCommon - Reference: Wickelfalzrohr 297042; sets with these values: 2
Andere - Typ: Wickelfalzrohr 297042; Familie: Wickelfalzrohr 297042; Familie und Typ: Wickelfalzrohr 297042: Wickelfalzrohr 297042; Typ-ID: 2534725
Abhängigkeiten - Höhe von Ebene: 0 m; Verschieben mit umliegenden Elementen: no
Bemaßungen - Fläche: 0.979373 m2; Volumen: 0.128599 m3
IFC-Parameter - In IFC-Datei exportieren: Nach Typ; Pset MEP.Geom-Ø (mm): 400; Pset MEP.Tech-Material (ID): 1; In IFC exportieren als: ifcflowsegment; NameOverride: Wickelfalzrohr; IfcPresentationLayer: 0-TFT-H_Abgasabführung Variante 3; ObjectTypeOverride: Wickelfalzrohr; Pset MEP.Name: Wickelfalzrohr; IfcDescription: Wickelfalzrohr; Pset MEP.Geom-Length (mm): 1566.66; Pset MEP.Abbreviation: R-R; Pset MEP.Tech-Medium: L_Entrauchung
Phasen - Phase erstellt: Phase 01

# IfcFlowSegment: Wickelfalzrohr 297197:Wickelfalzrohr 297197, Wickelfalzrohr
In: Erdgeschoss
Type - Material: IfcSurfaceStyle #251447
Type - Andere - Kategorie: Allgemeines Modell; Familienname: Wickelfalzrohr 297197
Type - ID-Daten - Typname: Wickelfalzrohr 297197
Type - IFC-Parameter - Typ in IFC-Datei exportieren: Vorgabe
Description: Wickelfalzrohr
Pset_DistributionFlowElementCommon - Reference: Wickelfalzrohr 297197; sets with these values: 2
Andere - Typ: Wickelfalzrohr 297197; Familie: Wickelfalzrohr 297197; Familie und Typ: Wickelfalzrohr 297197: Wickelfalzrohr 297197; Typ-ID: 2534732
Abhängigkeiten - Höhe von Ebene: 0 m; Verschieben mit umliegenden Elementen: no
Bemaßungen - Fläche: 0.117213 m2; Volumen: 0.00961932 m3
IFC-Parameter - In IFC-Datei exportieren: Nach Typ; Pset MEP.Tech-Material (ID): 1; Pset MEP.Geom-Length (mm): 300; Pset MEP.Geom-Ø (mm): 250; In IFC exportieren als: ifcflowsegment; NameOverride: Wickelfalzrohr; IfcPresentationLayer: 0-TFT-H_Abgasabführung Variante 3; ObjectTypeOverride: Wickelfalzrohr; Pset MEP.Name: Wickelfalzrohr; IfcDescription: Wickelfalzrohr; Pset MEP.Abbreviation: R-R; Pset MEP.Tech-Medium: L_Entrauchung
Phasen - Phase erstellt: Phase 01

# IfcFlowSegment: Wickelfalzrohr 297220:Wickelfalzrohr 297220, Wickelfalzrohr
In: Erdgeschoss
Type - Material: IfcSurfaceStyle #251447
Type - Andere - Kategorie: Allgemeines Modell; Familienname: Wickelfalzrohr 297220
Type - ID-Daten - Typname: Wickelfalzrohr 297220
Type - IFC-Parameter - Typ in IFC-Datei exportieren: Vorgabe
Description: Wickelfalzrohr
Pset_DistributionFlowElementCommon - Reference: Wickelfalzrohr 297220; sets with these values: 2
Andere - Typ: Wickelfalzrohr 297220; Familie: Wickelfalzrohr 297220; Familie und Typ: Wickelfalzrohr 297220: Wickelfalzrohr 297220; Typ-ID: 2534739
Abhängigkeiten - Höhe von Ebene: 0 m; Verschieben mit umliegenden Elementen: no
Bemaßungen - Fläche: 0.183633 m2; Volumen: 0.0150703 m3
IFC-Parameter - In IFC-Datei exportieren: Nach Typ; Pset MEP.Tech-Material (ID): 1; Pset MEP.Geom-Ø (mm): 250; Pset MEP.Geom-Length (mm): 470; In IFC exportieren als: ifcflowsegment; NameOverride: Wickelfalzrohr; IfcPresentationLayer: 0-TFT-H_Abgasabführung Variante 3; ObjectTypeOverride: Wickelfalzrohr; Pset MEP.Name: Wickelfalzrohr; IfcDescription: Wickelfalzrohr; Pset MEP.Abbreviation: R-R; Pset MEP.Tech-Medium: L_Entrauchung
Phasen - Phase erstellt: Phase 01

# IfcFlowSegment: Wickelfalzrohr 328855:Wickelfalzrohr 328855, Wickelfalzrohr
In: Erdgeschoss
Type - Material: IfcSurfaceStyle #251447
Type - Andere - Kategorie: Allgemeines Modell; Familienname: Wickelfalzrohr 328855
Type - ID-Daten - Typname: Wickelfalzrohr 328855
Type - IFC-Parameter - Typ in IFC-Datei exportieren: Vorgabe
Description: Wickelfalzrohr
Pset_DistributionFlowElementCommon - Reference: Wickelfalzrohr 328855; sets with these values: 2
Andere - Typ: Wickelfalzrohr 328855; Familie: Wickelfalzrohr 328855; Familie und Typ: Wickelfalzrohr 328855: Wickelfalzrohr 328855; Typ-ID: 2535670
Abhängigkeiten - Höhe von Ebene: 0 m; Verschieben mit umliegenden Elementen: no
Bemaßungen - Fläche: 0.365703 m2; Volumen: 0.0216088 m3
IFC-Parameter - In IFC-Datei exportieren: Nach Typ; Pset MEP.Tech-Material (ID): 1; Pset MEP.Geom-Ø (mm): 180; In IFC exportieren als: ifcflowsegment; NameOverride: Wickelfalzrohr; IfcPresentationLayer: 0-TFT-H_Abgasabführung Variante 1; ObjectTypeOverride: Wickelfalzrohr; Pset MEP.Name: Wickelfalzrohr; IfcDescription: Wickelfalzrohr; Pset MEP.Geom-Length (mm): 1300; Pset MEP.Abbreviation: R-R; Pset MEP.Tech-Medium: L_Entrauchung
Phasen - Phase erstellt: Phase 01

# IfcFlowSegment: Wickelfalzrohr 329044:Wickelfalzrohr 329044, Wickelfalzrohr
In: Erdgeschoss
Type - Material: IfcSurfaceStyle #251447
Type - Andere - Kategorie: Allgemeines Modell; Familienname: Wickelfalzrohr 329044
Type - ID-Daten - Typname: Wickelfalzrohr 329044
Type - IFC-Parameter - Typ in IFC-Datei exportieren: Vorgabe
Description: Wickelfalzrohr
Pset_DistributionFlowElementCommon - Reference: Wickelfalzrohr 329044; sets with these values: 2
Andere - Typ: Wickelfalzrohr 329044; Familie: Wickelfalzrohr 329044; Familie und Typ: Wickelfalzrohr 329044: Wickelfalzrohr 329044; Typ-ID: 2535677
Abhängigkeiten - Höhe von Ebene: 0 m; Verschieben mit umliegenden Elementen: no
Bemaßungen - Fläche: 0.191291 m2; Volumen: 0.0113031 m3
IFC-Parameter - In IFC-Datei exportieren: Nach Typ; Pset MEP.Tech-Material (ID): 1; Pset MEP.Geom-Ø (mm): 180; In IFC exportieren als: ifcflowsegment; NameOverride: Wickelfalzrohr; IfcPresentationLayer: 0-TFT-H_Abgasabführung Variante 1; ObjectTypeOverride: Wickelfalzrohr; Pset MEP.Name: Wickelfalzrohr; IfcDescription: Wickelfalzrohr; Pset MEP.Geom-Length (mm): 680; Pset MEP.Abbreviation: R-R; Pset MEP.Tech-Medium: L_Entrauchung
Phasen - Phase erstellt: Phase 01

# IfcFlowSegment: Wickelfalzrohr 618664:Wickelfalzrohr 618664, Wickelfalzrohr
In: 1. Untergeschoss
Type - Material: IfcSurfaceStyle #251447
Type - Andere - Kategorie: Allgemeines Modell; Familienname: Wickelfalzrohr 618664
Type - ID-Daten - Typname: Wickelfalzrohr 618664
Type - IFC-Parameter - Typ in IFC-Datei exportieren: Vorgabe
Description: Wickelfalzrohr
Pset_DistributionFlowElementCommon - Reference: Wickelfalzrohr 618664; sets with these values: 2
Andere - Typ: Wickelfalzrohr 618664; Familie: Wickelfalzrohr 618664; Familie und Typ: Wickelfalzrohr 618664: Wickelfalzrohr 618664; Typ-ID: 2537871
Abhängigkeiten - Höhe von Ebene: 0 m; Verschieben mit umliegenden Elementen: no
Bemaßungen - Fläche: 9.23635 m2; Volumen: 0.606402 m3
IFC-Parameter - In IFC-Datei exportieren: Nach Typ; Pset MEP.Tech-Material (ID): 1; Pset MEP.Geom-Length (mm): 29550; Pset MEP.Geom-Ø (mm): 200; In IFC exportieren als: ifcflowsegment; NameOverride: Wickelfalzrohr; IfcPresentationLayer: 0-TFT-H_Abgasabführung Variante 1; ObjectTypeOverride: Wickelfalzrohr; Pset MEP.Name: Wickelfalzrohr; IfcDescription: Wickelfalzrohr; Pset MEP.Abbreviation: R-R; Pset MEP.Tech-Medium: L_Entrauchung
Phasen - Phase erstellt: Phase 01

# IfcFlowSegment: Wickelfalzrohr 618707:Wickelfalzrohr 618707, Wickelfalzrohr
In: Erdgeschoss
Type - Material: IfcSurfaceStyle #251447
Type - Andere - Kategorie: Allgemeines Modell; Familienname: Wickelfalzrohr 618707
Type - ID-Daten - Typname: Wickelfalzrohr 618707
Type - IFC-Parameter - Typ in IFC-Datei exportieren: Vorgabe
Description: Wickelfalzrohr
Pset_DistributionFlowElementCommon - Reference: Wickelfalzrohr 618707; sets with these values: 2
Andere - Typ: Wickelfalzrohr 618707; Familie: Wickelfalzrohr 618707; Familie und Typ: Wickelfalzrohr 618707: Wickelfalzrohr 618707; Typ-ID: 2537885
Abhängigkeiten - Höhe von Ebene: 0 m; Verschieben mit umliegenden Elementen: no
Bemaßungen - Fläche: 0.145563 m2; Volumen: 0.00955678 m3
IFC-Parameter - In IFC-Datei exportieren: Nach Typ; Pset MEP.Tech-Material (ID): 1; Pset MEP.Geom-Ø (mm): 200; In IFC exportieren als: ifcflowsegment; NameOverride: Wickelfalzrohr; IfcPresentationLayer: 0-TFT-H_Abgasabführung Variante 1; ObjectTypeOverride: Wickelfalzrohr; Pset MEP.Name: Wickelfalzrohr; IfcDescription: Wickelfalzrohr; Pset MEP.Geom-Length (mm): 465.703; Pset MEP.Abbreviation: R-R; Pset MEP.Tech-Medium: L_Entrauchung
Phasen - Phase erstellt: Phase 01

# IfcFlowSegment: Wickelfalzrohr 619300:Wickelfalzrohr 619300, Wickelfalzrohr
In: Erdgeschoss
Type - Material: IfcSurfaceStyle #251447
Type - Andere - Kategorie: Allgemeines Modell; Familienname: Wickelfalzrohr 619300
Type - ID-Daten - Typname: Wickelfalzrohr 619300
Type - IFC-Parameter - Typ in IFC-Datei exportieren: Vorgabe
Description: Wickelfalzrohr
Pset_DistributionFlowElementCommon - Reference: Wickelfalzrohr 619300; sets with these values: 2
Andere - Typ: Wickelfalzrohr 619300; Familie: Wickelfalzrohr 619300; Familie und Typ: Wickelfalzrohr 619300: Wickelfalzrohr 619300; Typ-ID: 2537899
Abhängigkeiten - Höhe von Ebene: 0 m; Verschieben mit umliegenden Elementen: no
Bemaßungen - Fläche: 1.39121 m2; Volumen: 0.0913386 m3
IFC-Parameter - In IFC-Datei exportieren: Nach Typ; Pset MEP.Tech-Material (ID): 1; Pset MEP.Geom-Ø (mm): 200; In IFC exportieren als: ifcflowsegment; NameOverride: Wickelfalzrohr; IfcPresentationLayer: 0-TFT-H_Abgasabführung Variante 1; ObjectTypeOverride: Wickelfalzrohr; Pset MEP.Name: Wickelfalzrohr; IfcDescription: Wickelfalzrohr; Pset MEP.Geom-Length (mm): 4450.94; Pset MEP.Abbreviation: R-R; Pset MEP.Tech-Medium: L_Entrauchung
Phasen - Phase erstellt: Phase 01

# IfcFlowSegment: Wickelfalzrohr 619478:Wickelfalzrohr 619478, Wickelfalzrohr
In: Erdgeschoss
Type - Material: IfcSurfaceStyle #251447
Type - Andere - Kategorie: Allgemeines Modell; Familienname: Wickelfalzrohr 619478
Type - ID-Daten - Typname: Wickelfalzrohr 619478
Type - IFC-Parameter - Typ in IFC-Datei exportieren: Vorgabe
Description: Wickelfalzrohr
Pset_DistributionFlowElementCommon - Reference: Wickelfalzrohr 619478; sets with these values: 2
Andere - Typ: Wickelfalzrohr 619478; Familie: Wickelfalzrohr 619478; Familie und Typ: Wickelfalzrohr 619478: Wickelfalzrohr 619478; Typ-ID: 2537913
Abhängigkeiten - Höhe von Ebene: 0 m; Verschieben mit umliegenden Elementen: no
Bemaßungen - Fläche: 0.162639 m2; Volumen: 0.0106779 m3
IFC-Parameter - In IFC-Datei exportieren: Nach Typ; Pset MEP.Tech-Material (ID): 1; Pset MEP.Geom-Ø (mm): 200; In IFC exportieren als: ifcflowsegment; NameOverride: Wickelfalzrohr; IfcPresentationLayer: 0-TFT-H_Abgasabführung Variante 1; ObjectTypeOverride: Wickelfalzrohr; Pset MEP.Name: Wickelfalzrohr; IfcDescription: Wickelfalzrohr; Pset MEP.Geom-Length (mm): 520.332; Pset MEP.Abbreviation: R-R; Pset MEP.Tech-Medium: L_Entrauchung
Phasen - Phase erstellt: Phase 01

# IfcFlowSegment: Wickelfalzrohr 619993:Wickelfalzrohr 619993, Wickelfalzrohr
In: Erdgeschoss
Type - Material: IfcSurfaceStyle #251447
Type - Andere - Kategorie: Allgemeines Modell; Familienname: Wickelfalzrohr 619993
Type - ID-Daten - Typname: Wickelfalzrohr 619993
Type - IFC-Parameter - Typ in IFC-Datei exportieren: Vorgabe
Description: Wickelfalzrohr
Pset_DistributionFlowElementCommon - Reference: Wickelfalzrohr 619993; sets with these values: 2
Andere - Typ: Wickelfalzrohr 619993; Familie: Wickelfalzrohr 619993; Familie und Typ: Wickelfalzrohr 619993: Wickelfalzrohr 619993; Typ-ID: 2537944
Abhängigkeiten - Höhe von Ebene: 0 m; Verschieben mit umliegenden Elementen: no
Bemaßungen - Fläche: 0.234486 m2; Volumen: 0.0153949 m3
IFC-Parameter - In IFC-Datei exportieren: Nach Typ; Pset MEP.Tech-Material (ID): 1; Pset MEP.Geom-Ø (mm): 200; In IFC exportieren als: ifcflowsegment; NameOverride: Wickelfalzrohr; IfcPresentationLayer: 0-TFT-H_Abgasabführung Variante 1; ObjectTypeOverride: Wickelfalzrohr; Pset MEP.Name: Wickelfalzrohr; IfcDescription: Wickelfalzrohr; Pset MEP.Geom-Length (mm): 750.195; Pset MEP.Abbreviation: R-R; Pset MEP.Tech-Medium: L_Entrauchung
Phasen - Phase erstellt: Phase 01

# IfcFlowSegment: Wickelfalzrohr 620716:Wickelfalzrohr 620716, Wickelfalzrohr
In: Erdgeschoss
Type - Material: IfcSurfaceStyle #251447
Type - Andere - Kategorie: Allgemeines Modell; Familienname: Wickelfalzrohr 620716
Type - ID-Daten - Typname: Wickelfalzrohr 620716
Type - IFC-Parameter - Typ in IFC-Datei exportieren: Vorgabe
Description: Wickelfalzrohr
Pset_DistributionFlowElementCommon - Reference: Wickelfalzrohr 620716; sets with these values: 2
Andere - Typ: Wickelfalzrohr 620716; Familie: Wickelfalzrohr 620716; Familie und Typ: Wickelfalzrohr 620716: Wickelfalzrohr 620716; Typ-ID: 2538022
Abhängigkeiten - Höhe von Ebene: 0 m; Verschieben mit umliegenden Elementen: no
Bemaßungen - Fläche: 0.48422 m2; Volumen: 0.0635818 m3
IFC-Parameter - In IFC-Datei exportieren: Nach Typ; Pset MEP.Geom-Ø (mm): 400; Pset MEP.Tech-Material (ID): 1; In IFC exportieren als: ifcflowsegment; NameOverride: Wickelfalzrohr; IfcPresentationLayer: 0-TFT-H_Abgasabführung Variante 1; ObjectTypeOverride: Wickelfalzrohr; Pset MEP.Name: Wickelfalzrohr; IfcDescription: Wickelfalzrohr; Pset MEP.Geom-Length (mm): 774.587; Pset MEP.Abbreviation: R-R; Pset MEP.Tech-Medium: L_Entrauchung
Phasen - Phase erstellt: Phase 01

# IfcFlowSegment: Wickelfalzrohr 620900:Wickelfalzrohr 620900, Wickelfalzrohr
In: Erdgeschoss
Type - Material: IfcSurfaceStyle #251447
Type - Andere - Kategorie: Allgemeines Modell; Familienname: Wickelfalzrohr 620900
Type - ID-Daten - Typname: Wickelfalzrohr 620900
Type - IFC-Parameter - Typ in IFC-Datei exportieren: Vorgabe
Description: Wickelfalzrohr
Pset_DistributionFlowElementCommon - Reference: Wickelfalzrohr 620900; sets with these values: 2
Andere - Typ: Wickelfalzrohr 620900; Familie: Wickelfalzrohr 620900; Familie und Typ: Wickelfalzrohr 620900: Wickelfalzrohr 620900; Typ-ID: 2538036
Abhängigkeiten - Höhe von Ebene: 0 m; Verschieben mit umliegenden Elementen: no
Bemaßungen - Fläche: 1.11961 m2; Volumen: 0.147014 m3
IFC-Parameter - In IFC-Datei exportieren: Nach Typ; Pset MEP.Geom-Ø (mm): 400; Pset MEP.Tech-Material (ID): 1; In IFC exportieren als: ifcflowsegment; NameOverride: Wickelfalzrohr; IfcPresentationLayer: 0-TFT-H_Abgasabführung Variante 1; ObjectTypeOverride: Wickelfalzrohr; Pset MEP.Name: Wickelfalzrohr; IfcDescription: Wickelfalzrohr; Pset MEP.Geom-Length (mm): 1791; Pset MEP.Abbreviation: R-R; Pset MEP.Tech-Medium: L_Entrauchung
Phasen - Phase erstellt: Phase 01

# IfcFlowSegment: Wickelfalzrohr 621055:Wickelfalzrohr 621055, Wickelfalzrohr
In: Erdgeschoss
Type - Material: IfcSurfaceStyle #251447
Type - Andere - Kategorie: Allgemeines Modell; Familienname: Wickelfalzrohr 621055
Type - ID-Daten - Typname: Wickelfalzrohr 621055
Type - IFC-Parameter - Typ in IFC-Datei exportieren: Vorgabe
Description: Wickelfalzrohr
Pset_DistributionFlowElementCommon - Reference: Wickelfalzrohr 621055; sets with these values: 2
Andere - Typ: Wickelfalzrohr 621055; Familie: Wickelfalzrohr 621055; Familie und Typ: Wickelfalzrohr 621055: Wickelfalzrohr 621055; Typ-ID: 2538043
Abhängigkeiten - Höhe von Ebene: 0 m; Verschieben mit umliegenden Elementen: no
Bemaßungen - Fläche: 3.18967 m2; Volumen: 0.418828 m3
IFC-Parameter - In IFC-Datei exportieren: Nach Typ; Pset MEP.Geom-Ø (mm): 400; Pset MEP.Tech-Material (ID): 1; In IFC exportieren als: ifcflowsegment; NameOverride: Wickelfalzrohr; IfcPresentationLayer: 0-TFT-H_Abgasabführung Variante 1; ObjectTypeOverride: Wickelfalzrohr; Pset MEP.Name: Wickelfalzrohr; IfcDescription: Wickelfalzrohr; Pset MEP.Geom-Length (mm): 5102.38; Pset MEP.Abbreviation: R-R; Pset MEP.Tech-Medium: L_Entrauchung
Phasen - Phase erstellt: Phase 01

# IfcFlowSegment: Wickelfalzrohr 621210:Wickelfalzrohr 621210, Wickelfalzrohr
In: Erdgeschoss
Type - Material: IfcSurfaceStyle #251447
Type - Andere - Kategorie: Allgemeines Modell; Familienname: Wickelfalzrohr 621210
Type - ID-Daten - Typname: Wickelfalzrohr 621210
Type - IFC-Parameter - Typ in IFC-Datei exportieren: Vorgabe
Description: Wickelfalzrohr
Pset_DistributionFlowElementCommon - Reference: Wickelfalzrohr 621210; sets with these values: 2
Andere - Typ: Wickelfalzrohr 621210; Familie: Wickelfalzrohr 621210; Familie und Typ: Wickelfalzrohr 621210: Wickelfalzrohr 621210; Typ-ID: 2538050
Abhängigkeiten - Höhe von Ebene: 0 m; Verschieben mit umliegenden Elementen: no
Bemaßungen - Fläche: 0.478227 m2; Volumen: 0.0627949 m3
IFC-Parameter - In IFC-Datei exportieren: Nach Typ; Pset MEP.Geom-Ø (mm): 400; Pset MEP.Tech-Material (ID): 1; In IFC exportieren als: ifcflowsegment; NameOverride: Wickelfalzrohr; IfcPresentationLayer: 0-TFT-H_Abgasabführung Variante 1; ObjectTypeOverride: Wickelfalzrohr; Pset MEP.Name: Wickelfalzrohr; IfcDescription: Wickelfalzrohr; Pset MEP.Geom-Length (mm): 765; Pset MEP.Abbreviation: R-R; Pset MEP.Tech-Medium: L_Entrauchung
Phasen - Phase erstellt: Phase 01

# IfcFlowSegment: Wickelfalzrohr 621365:Wickelfalzrohr 621365, Wickelfalzrohr
In: Erdgeschoss
Type - Material: IfcSurfaceStyle #251447
Type - Andere - Kategorie: Allgemeines Modell; Familienname: Wickelfalzrohr 621365
Type - ID-Daten - Typname: Wickelfalzrohr 621365
Type - IFC-Parameter - Typ in IFC-Datei exportieren: Vorgabe
Description: Wickelfalzrohr
Pset_DistributionFlowElementCommon - Reference: Wickelfalzrohr 621365; sets with these values: 2
Andere - Typ: Wickelfalzrohr 621365; Familie: Wickelfalzrohr 621365; Familie und Typ: Wickelfalzrohr 621365: Wickelfalzrohr 621365; Typ-ID: 2538057
Abhängigkeiten - Höhe von Ebene: 0 m; Verschieben mit umliegenden Elementen: no
Bemaßungen - Fläche: 2.21473 m2; Volumen: 0.290811 m3
IFC-Parameter - In IFC-Datei exportieren: Nach Typ; Pset MEP.Geom-Ø (mm): 400; Pset MEP.Tech-Material (ID): 1; In IFC exportieren als: ifcflowsegment; NameOverride: Wickelfalzrohr; IfcPresentationLayer: 0-TFT-H_Abgasabführung Variante 1; ObjectTypeOverride: Wickelfalzrohr; Pset MEP.Name: Wickelfalzrohr; IfcDescription: Wickelfalzrohr; Pset MEP.Geom-Length (mm): 3542.81; Pset MEP.Abbreviation: R-R; Pset MEP.Tech-Medium: L_Entrauchung
Phasen - Phase erstellt: Phase 01

# IfcFlowSegment: Wickelfalzrohr 621566:Wickelfalzrohr 621566, Wickelfalzrohr
In: Erdgeschoss
Type - Material: IfcSurfaceStyle #251447
Type - Andere - Kategorie: Allgemeines Modell; Familienname: Wickelfalzrohr 621566
Type - ID-Daten - Typname: Wickelfalzrohr 621566
Type - IFC-Parameter - Typ in IFC-Datei exportieren: Vorgabe
Description: Wickelfalzrohr
Pset_DistributionFlowElementCommon - Reference: Wickelfalzrohr 621566; sets with these values: 2
Andere - Typ: Wickelfalzrohr 621566; Familie: Wickelfalzrohr 621566; Familie und Typ: Wickelfalzrohr 621566: Wickelfalzrohr 621566; Typ-ID: 2538078
Abhängigkeiten - Höhe von Ebene: 0 m; Verschieben mit umliegenden Elementen: no
Bemaßungen - Fläche: 2.10331 m2; Volumen: 0.27618 m3
IFC-Parameter - In IFC-Datei exportieren: Nach Typ; Pset MEP.Geom-Ø (mm): 400; Pset MEP.Tech-Material (ID): 1; In IFC exportieren als: ifcflowsegment; NameOverride: Wickelfalzrohr; IfcPresentationLayer: 0-TFT-H_Abgasabführung Variante 1; ObjectTypeOverride: Wickelfalzrohr; Pset MEP.Name: Wickelfalzrohr; IfcDescription: Wickelfalzrohr; Pset MEP.Geom-Length (mm): 3364.57; Pset MEP.Abbreviation: R-R; Pset MEP.Tech-Medium: L_Entrauchung
Phasen - Phase erstellt: Phase 01

# IfcFlowSegment: Wickelfalzrohr 621721:Wickelfalzrohr 621721, Wickelfalzrohr
In: Erdgeschoss
Type - Material: IfcSurfaceStyle #251447
Type - Andere - Kategorie: Allgemeines Modell; Familienname: Wickelfalzrohr 621721
Type - ID-Daten - Typname: Wickelfalzrohr 621721
Type - IFC-Parameter - Typ in IFC-Datei exportieren: Vorgabe
Description: Wickelfalzrohr
Pset_DistributionFlowElementCommon - Reference: Wickelfalzrohr 621721; sets with these values: 2
Andere - Typ: Wickelfalzrohr 621721; Familie: Wickelfalzrohr 621721; Familie und Typ: Wickelfalzrohr 621721: Wickelfalzrohr 621721; Typ-ID: 2538085
Abhängigkeiten - Höhe von Ebene: 0 m; Verschieben mit umliegenden Elementen: no
Bemaßungen - Fläche: 18.3789 m2; Volumen: 2.41329 m3
IFC-Parameter - In IFC-Datei exportieren: Nach Typ; Pset MEP.Geom-Length (mm): 29400; Pset MEP.Geom-Ø (mm): 400; Pset MEP.Tech-Material (ID): 1; In IFC exportieren als: ifcflowsegment; NameOverride: Wickelfalzrohr; IfcPresentationLayer: 0-TFT-H_Abgasabführung Variante 1; ObjectTypeOverride: Wickelfalzrohr; Pset MEP.Name: Wickelfalzrohr; IfcDescription: Wickelfalzrohr; Pset MEP.Abbreviation: R-R; Pset MEP.Tech-Medium: L_Entrauchung
Phasen - Phase erstellt: Phase 01

# IfcFlowSegment: Wickelfalzrohr 621923:Wickelfalzrohr 621923, Wickelfalzrohr
In: Erdgeschoss
Type - Material: IfcSurfaceStyle #251447
Type - Andere - Kategorie: Allgemeines Modell; Familienname: Wickelfalzrohr 621923
Type - ID-Daten - Typname: Wickelfalzrohr 621923
Type - IFC-Parameter - Typ in IFC-Datei exportieren: Vorgabe
Description: Wickelfalzrohr
Pset_DistributionFlowElementCommon - Reference: Wickelfalzrohr 621923; sets with these values: 2
Andere - Typ: Wickelfalzrohr 621923; Familie: Wickelfalzrohr 621923; Familie und Typ: Wickelfalzrohr 621923: Wickelfalzrohr 621923; Typ-ID: 2538106
Abhängigkeiten - Höhe von Ebene: 0 m; Verschieben mit umliegenden Elementen: no
Bemaßungen - Fläche: 0.106273 m2; Volumen: 0.0139544 m3
IFC-Parameter - In IFC-Datei exportieren: Nach Typ; Pset MEP.Geom-Ø (mm): 400; Pset MEP.Tech-Material (ID): 1; Pset MEP.Geom-Length (mm): 170; In IFC exportieren als: ifcflowsegment; NameOverride: Wickelfalzrohr; IfcPresentationLayer: 0-TFT-H_Abgasabführung Variante 1; ObjectTypeOverride: Wickelfalzrohr; Pset MEP.Name: Wickelfalzrohr; IfcDescription: Wickelfalzrohr; Pset MEP.Abbreviation: R-R; Pset MEP.Tech-Medium: L_Entrauchung
Phasen - Phase erstellt: Phase 01

# IfcFlowSegment: Wickelfalzrohr 621946:Wickelfalzrohr 621946, Wickelfalzrohr
In: Erdgeschoss
Type - Material: IfcSurfaceStyle #251447
Type - Andere - Kategorie: Allgemeines Modell; Familienname: Wickelfalzrohr 621946
Type - ID-Daten - Typname: Wickelfalzrohr 621946
Type - IFC-Parameter - Typ in IFC-Datei exportieren: Vorgabe
Description: Wickelfalzrohr
Pset_DistributionFlowElementCommon - Reference: Wickelfalzrohr 621946; sets with these values: 2
Andere - Typ: Wickelfalzrohr 621946; Familie: Wickelfalzrohr 621946; Familie und Typ: Wickelfalzrohr 621946: Wickelfalzrohr 621946; Typ-ID: 2538113
Abhängigkeiten - Höhe von Ebene: 0 m; Verschieben mit umliegenden Elementen: no
Bemaßungen - Fläche: 0.106273 m2; Volumen: 0.0139544 m3
IFC-Parameter - In IFC-Datei exportieren: Nach Typ; Pset MEP.Geom-Ø (mm): 400; Pset MEP.Tech-Material (ID): 1; Pset MEP.Geom-Length (mm): 170; In IFC exportieren als: ifcflowsegment; NameOverride: Wickelfalzrohr; IfcPresentationLayer: 0-TFT-H_Abgasabführung Variante 1; ObjectTypeOverride: Wickelfalzrohr; Pset MEP.Name: Wickelfalzrohr; IfcDescription: Wickelfalzrohr; Pset MEP.Abbreviation: R-R; Pset MEP.Tech-Medium: L_Entrauchung
Phasen - Phase erstellt: Phase 01

# IfcFlowSegment: Wickelfalzrohr 621996:Wickelfalzrohr 621996, Wickelfalzrohr
In: Erdgeschoss
Type - Material: IfcSurfaceStyle #251447
Type - Andere - Kategorie: Allgemeines Modell; Familienname: Wickelfalzrohr 621996
Type - ID-Daten - Typname: Wickelfalzrohr 621996
Type - IFC-Parameter - Typ in IFC-Datei exportieren: Vorgabe
Description: Wickelfalzrohr
Pset_DistributionFlowElementCommon - Reference: Wickelfalzrohr 621996; sets with these values: 2
Andere - Typ: Wickelfalzrohr 621996; Familie: Wickelfalzrohr 621996; Familie und Typ: Wickelfalzrohr 621996: Wickelfalzrohr 621996; Typ-ID: 2538127
Abhängigkeiten - Höhe von Ebene: 0 m; Verschieben mit umliegenden Elementen: no
Bemaßungen - Fläche: 0.18754 m2; Volumen: 0.0246255 m3
IFC-Parameter - In IFC-Datei exportieren: Nach Typ; Pset MEP.Geom-Ø (mm): 400; Pset MEP.Tech-Material (ID): 1; Pset MEP.Geom-Length (mm): 300; In IFC exportieren als: ifcflowsegment; NameOverride: Wickelfalzrohr; IfcPresentationLayer: 0-TFT-H_Abgasabführung Variante 1; ObjectTypeOverride: Wickelfalzrohr; Pset MEP.Name: Wickelfalzrohr; IfcDescription: Wickelfalzrohr; Pset MEP.Abbreviation: R-R; Pset MEP.Tech-Medium: L_Entrauchung
Phasen - Phase erstellt: Phase 01

# IfcFlowSegment: Wickelfalzrohr 622042:Wickelfalzrohr 622042, Wickelfalzrohr
In: Erdgeschoss
Type - Material: IfcSurfaceStyle #251447
Type - Andere - Kategorie: Allgemeines Modell; Familienname: Wickelfalzrohr 622042
Type - ID-Daten - Typname: Wickelfalzrohr 622042
Type - IFC-Parameter - Typ in IFC-Datei exportieren: Vorgabe
Description: Wickelfalzrohr
Pset_DistributionFlowElementCommon - Reference: Wickelfalzrohr 622042; sets with these values: 2
Andere - Typ: Wickelfalzrohr 622042; Familie: Wickelfalzrohr 622042; Familie und Typ: Wickelfalzrohr 622042: Wickelfalzrohr 622042; Typ-ID: 2538141
Abhängigkeiten - Höhe von Ebene: 0 m; Verschieben mit umliegenden Elementen: no
Bemaßungen - Fläche: 0.18754 m2; Volumen: 0.0246255 m3
IFC-Parameter - In IFC-Datei exportieren: Nach Typ; Pset MEP.Geom-Ø (mm): 400; Pset MEP.Tech-Material (ID): 1; Pset MEP.Geom-Length (mm): 300; In IFC exportieren als: ifcflowsegment; NameOverride: Wickelfalzrohr; IfcPresentationLayer: 0-TFT-H_Abgasabführung Variante 1; ObjectTypeOverride: Wickelfalzrohr; Pset MEP.Name: Wickelfalzrohr; IfcDescription: Wickelfalzrohr; Pset MEP.Abbreviation: R-R; Pset MEP.Tech-Medium: L_Entrauchung
Phasen - Phase erstellt: Phase 01

# IfcFlowSegment: Wickelfalzrohr 622088:Wickelfalzrohr 622088, Wickelfalzrohr
In: Erdgeschoss
Type - Material: IfcSurfaceStyle #251447
Type - Andere - Kategorie: Allgemeines Modell; Familienname: Wickelfalzrohr 622088
Type - ID-Daten - Typname: Wickelfalzrohr 622088
Type - IFC-Parameter - Typ in IFC-Datei exportieren: Vorgabe
Description: Wickelfalzrohr
Pset_DistributionFlowElementCommon - Reference: Wickelfalzrohr 622088; sets with these values: 2
Andere - Typ: Wickelfalzrohr 622088; Familie: Wickelfalzrohr 622088; Familie und Typ: Wickelfalzrohr 622088: Wickelfalzrohr 622088; Typ-ID: 2538155
Abhängigkeiten - Höhe von Ebene: 0 m; Verschieben mit umliegenden Elementen: no
Bemaßungen - Fläche: 0.18754 m2; Volumen: 0.0246255 m3
IFC-Parameter - In IFC-Datei exportieren: Nach Typ; Pset MEP.Geom-Ø (mm): 400; Pset MEP.Tech-Material (ID): 1; Pset MEP.Geom-Length (mm): 300; In IFC exportieren als: ifcflowsegment; NameOverride: Wickelfalzrohr; IfcPresentationLayer: 0-TFT-H_Abgasabführung Variante 1; ObjectTypeOverride: Wickelfalzrohr; Pset MEP.Name: Wickelfalzrohr; IfcDescription: Wickelfalzrohr; Pset MEP.Abbreviation: R-R; Pset MEP.Tech-Medium: L_Entrauchung
Phasen - Phase erstellt: Phase 01

# IfcFlowSegment: Wickelfalzrohr 622108:Wickelfalzrohr 622108, Wickelfalzrohr
In: Erdgeschoss
Type - Material: IfcSurfaceStyle #251447
Type - Andere - Kategorie: Allgemeines Modell; Familienname: Wickelfalzrohr 622108
Type - ID-Daten - Typname: Wickelfalzrohr 622108
Type - IFC-Parameter - Typ in IFC-Datei exportieren: Vorgabe
Description: Wickelfalzrohr
Pset_DistributionFlowElementCommon - Reference: Wickelfalzrohr 622108; sets with these values: 2
Andere - Typ: Wickelfalzrohr 622108; Familie: Wickelfalzrohr 622108; Familie und Typ: Wickelfalzrohr 622108: Wickelfalzrohr 622108; Typ-ID: 2538162
Abhängigkeiten - Höhe von Ebene: 0 m; Verschieben mit umliegenden Elementen: no
Bemaßungen - Fläche: 0.18754 m2; Volumen: 0.0246255 m3
IFC-Parameter - In IFC-Datei exportieren: Nach Typ; Pset MEP.Geom-Ø (mm): 400; Pset MEP.Tech-Material (ID): 1; Pset MEP.Geom-Length (mm): 300; In IFC exportieren als: ifcflowsegment; NameOverride: Wickelfalzrohr; IfcPresentationLayer: 0-TFT-H_Abgasabführung Variante 1; ObjectTypeOverride: Wickelfalzrohr; Pset MEP.Name: Wickelfalzrohr; IfcDescription: Wickelfalzrohr; Pset MEP.Abbreviation: R-R; Pset MEP.Tech-Medium: L_Entrauchung
Phasen - Phase erstellt: Phase 01

# IfcFlowSegment: Wickelfalzrohr 622475:Wickelfalzrohr 622475, Wickelfalzrohr
In: Erdgeschoss
Type - Material: IfcSurfaceStyle #251447
Type - Andere - Kategorie: Allgemeines Modell; Familienname: Wickelfalzrohr 622475
Type - ID-Daten - Typname: Wickelfalzrohr 622475
Type - IFC-Parameter - Typ in IFC-Datei exportieren: Vorgabe
Description: Wickelfalzrohr
Pset_DistributionFlowElementCommon - Reference: Wickelfalzrohr 622475; sets with these values: 2
Andere - Typ: Wickelfalzrohr 622475; Familie: Wickelfalzrohr 622475; Familie und Typ: Wickelfalzrohr 622475: Wickelfalzrohr 622475; Typ-ID: 2538189
Abhängigkeiten - Höhe von Ebene: 0 m; Verschieben mit umliegenden Elementen: no
Bemaßungen - Fläche: 0.0718903 m2; Volumen: 0.00943976 m3
IFC-Parameter - In IFC-Datei exportieren: Nach Typ; Pset MEP.Geom-Ø (mm): 400; Pset MEP.Tech-Material (ID): 1; In IFC exportieren als: ifcflowsegment; NameOverride: Wickelfalzrohr; IfcPresentationLayer: 0-TFT-H_Abgasabführung Variante 1; ObjectTypeOverride: Wickelfalzrohr; Pset MEP.Name: Wickelfalzrohr; IfcDescription: Wickelfalzrohr; Pset MEP.Geom-Length (mm): 115; Pset MEP.Abbreviation: R-R; Pset MEP.Tech-Medium: L_Entrauchung
Phasen - Phase erstellt: Phase 01

# IfcFlowSegment: Wickelfalzrohr 622653:Wickelfalzrohr 622653, Wickelfalzrohr
In: Erdgeschoss
Type - Material: IfcSurfaceStyle #251447
Type - Andere - Kategorie: Allgemeines Modell; Familienname: Wickelfalzrohr 622653
Type - ID-Daten - Typname: Wickelfalzrohr 622653
Type - IFC-Parameter - Typ in IFC-Datei exportieren: Vorgabe
Description: Wickelfalzrohr
Pset_DistributionFlowElementCommon - Reference: Wickelfalzrohr 622653; sets with these values: 2
Andere - Typ: Wickelfalzrohr 622653; Familie: Wickelfalzrohr 622653; Familie und Typ: Wickelfalzrohr 622653: Wickelfalzrohr 622653; Typ-ID: 2538203
Abhängigkeiten - Höhe von Ebene: 0 m; Verschieben mit umliegenden Elementen: no
Bemaßungen - Fläche: 0.0719445 m2; Volumen: 0.00944686 m3
IFC-Parameter - In IFC-Datei exportieren: Nach Typ; Pset MEP.Geom-Ø (mm): 400; Pset MEP.Tech-Material (ID): 1; In IFC exportieren als: ifcflowsegment; NameOverride: Wickelfalzrohr; IfcPresentationLayer: 0-TFT-H_Abgasabführung Variante 1; ObjectTypeOverride: Wickelfalzrohr; Pset MEP.Name: Wickelfalzrohr; IfcDescription: Wickelfalzrohr; Pset MEP.Geom-Length (mm): 115.087; Pset MEP.Abbreviation: R-R; Pset MEP.Tech-Medium: L_Entrauchung
Phasen - Phase erstellt: Phase 01

# IfcFlowSegment: Wickelfalzrohr 622831:Wickelfalzrohr 622831, Wickelfalzrohr
In: Erdgeschoss
Type - Material: IfcSurfaceStyle #251447
Type - Andere - Kategorie: Allgemeines Modell; Familienname: Wickelfalzrohr 622831
Type - ID-Daten - Typname: Wickelfalzrohr 622831
Type - IFC-Parameter - Typ in IFC-Datei exportieren: Vorgabe
Description: Wickelfalzrohr
Pset_DistributionFlowElementCommon - Reference: Wickelfalzrohr 622831; sets with these values: 2
Andere - Typ: Wickelfalzrohr 622831; Familie: Wickelfalzrohr 622831; Familie und Typ: Wickelfalzrohr 622831: Wickelfalzrohr 622831; Typ-ID: 2538217
Abhängigkeiten - Höhe von Ebene: 0 m; Verschieben mit umliegenden Elementen: no
Bemaßungen - Fläche: 0.0718453 m2; Volumen: 0.00943385 m3
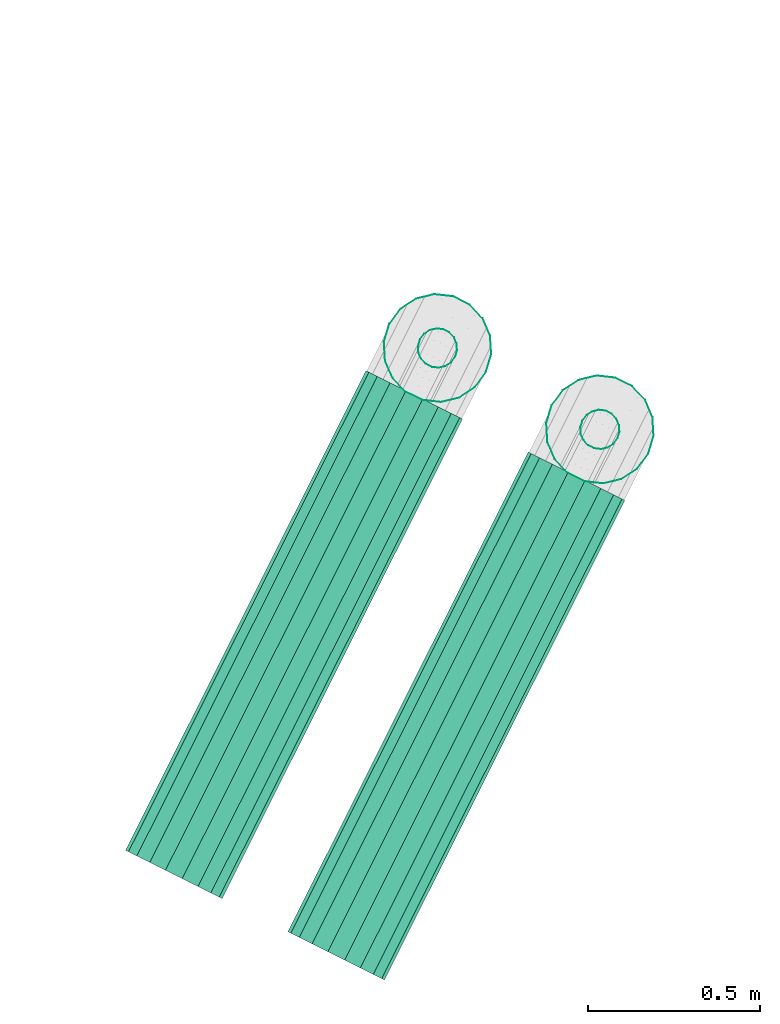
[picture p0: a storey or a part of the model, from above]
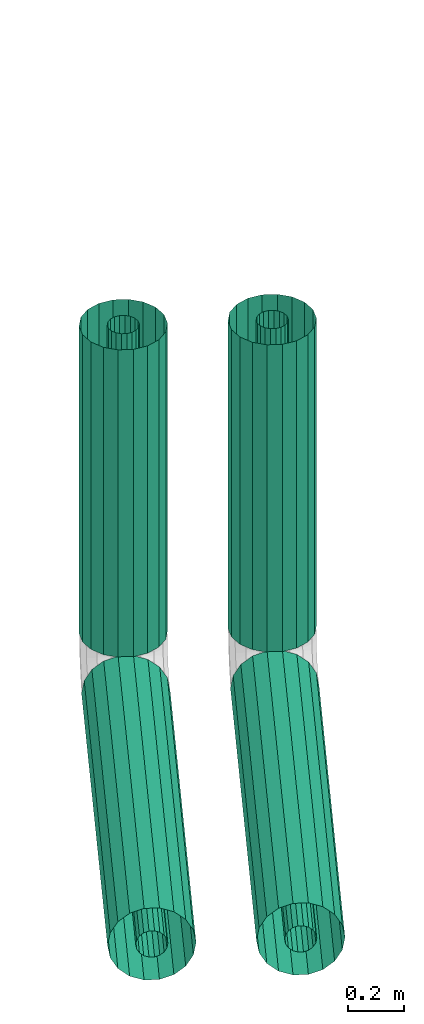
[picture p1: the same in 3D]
Properties of the parts of a building model (IFC2X3), part 23 of 23

# IfcFlowSegment: Wickelfalzrohr 622831:Wickelfalzrohr 622831, Wickelfalzrohr
IFC-Parameter - In IFC-Datei exportieren: Nach Typ; Pset MEP.Geom-Ø (mm): 400; Pset MEP.Tech-Material (ID): 1; In IFC exportieren als: ifcflowsegment; NameOverride: Wickelfalzrohr; IfcPresentationLayer: 0-TFT-H_Abgasabführung Variante 1; ObjectTypeOverride: Wickelfalzrohr; Pset MEP.Name: Wickelfalzrohr; IfcDescription: Wickelfalzrohr; Pset MEP.Geom-Length (mm): 114.928; Pset MEP.Abbreviation: R-R; Pset MEP.Tech-Medium: L_Entrauchung
Phasen - Phase erstellt: Phase 01

# IfcFlowSegment: Wickelfalzrohr 622986:Wickelfalzrohr 622986, Wickelfalzrohr
In: Erdgeschoss
Type - Material: IfcSurfaceStyle #251447
Type - Andere - Kategorie: Allgemeines Modell; Familienname: Wickelfalzrohr 622986
Type - ID-Daten - Typname: Wickelfalzrohr 622986
Type - IFC-Parameter - Typ in IFC-Datei exportieren: Vorgabe
Description: Wickelfalzrohr
Pset_DistributionFlowElementCommon - Reference: Wickelfalzrohr 622986; sets with these values: 2
Andere - Typ: Wickelfalzrohr 622986; Familie: Wickelfalzrohr 622986; Familie und Typ: Wickelfalzrohr 622986: Wickelfalzrohr 622986; Typ-ID: 2538224
Abhängigkeiten - Höhe von Ebene: 0 m; Verschieben mit umliegenden Elementen: no
Bemaßungen - Fläche: 1.19713 m2; Volumen: 0.157192 m3
IFC-Parameter - In IFC-Datei exportieren: Nach Typ; Pset MEP.Geom-Ø (mm): 400; Pset MEP.Tech-Material (ID): 1; In IFC exportieren als: ifcflowsegment; NameOverride: Wickelfalzrohr; IfcPresentationLayer: 0-TFT-H_Abgasabführung Variante 1; ObjectTypeOverride: Wickelfalzrohr; Pset MEP.Name: Wickelfalzrohr; IfcDescription: Wickelfalzrohr; Pset MEP.Geom-Length (mm): 1915; Pset MEP.Abbreviation: R-R; Pset MEP.Tech-Medium: L_Entrauchung
Phasen - Phase erstellt: Phase 01

# IfcFlowSegment: Wickelfalzrohr 623141:Wickelfalzrohr 623141, Wickelfalzrohr
In: Erdgeschoss
Type - Material: IfcSurfaceStyle #251447
Type - Andere - Kategorie: Allgemeines Modell; Familienname: Wickelfalzrohr 623141
Type - ID-Daten - Typname: Wickelfalzrohr 623141
Type - IFC-Parameter - Typ in IFC-Datei exportieren: Vorgabe
Description: Wickelfalzrohr
Pset_DistributionFlowElementCommon - Reference: Wickelfalzrohr 623141; sets with these values: 2
Andere - Typ: Wickelfalzrohr 623141; Familie: Wickelfalzrohr 623141; Familie und Typ: Wickelfalzrohr 623141: Wickelfalzrohr 623141; Typ-ID: 2538231
Abhängigkeiten - Höhe von Ebene: 0 m; Verschieben mit umliegenden Elementen: no
Bemaßungen - Fläche: 1.20338 m2; Volumen: 0.158013 m3
IFC-Parameter - In IFC-Datei exportieren: Nach Typ; Pset MEP.Geom-Ø (mm): 400; Pset MEP.Tech-Material (ID): 1; In IFC exportieren als: ifcflowsegment; NameOverride: Wickelfalzrohr; IfcPresentationLayer: 0-TFT-H_Abgasabführung Variante 1; ObjectTypeOverride: Wickelfalzrohr; Pset MEP.Name: Wickelfalzrohr; IfcDescription: Wickelfalzrohr; Pset MEP.Geom-Length (mm): 1925; Pset MEP.Abbreviation: R-R; Pset MEP.Tech-Medium: L_Entrauchung
Phasen - Phase erstellt: Phase 01

# IfcFlowSegment: Wickelfalzrohr 623296:Wickelfalzrohr 623296, Wickelfalzrohr
In: Erdgeschoss
Type - Material: IfcSurfaceStyle #251447
Type - Andere - Kategorie: Allgemeines Modell; Familienname: Wickelfalzrohr 623296
Type - ID-Daten - Typname: Wickelfalzrohr 623296
Type - IFC-Parameter - Typ in IFC-Datei exportieren: Vorgabe
Description: Wickelfalzrohr
Pset_DistributionFlowElementCommon - Reference: Wickelfalzrohr 623296; sets with these values: 2
Andere - Typ: Wickelfalzrohr 623296; Familie: Wickelfalzrohr 623296; Familie und Typ: Wickelfalzrohr 623296: Wickelfalzrohr 623296; Typ-ID: 2538238
Abhängigkeiten - Höhe von Ebene: 0 m; Verschieben mit umliegenden Elementen: no
Bemaßungen - Fläche: 1.19713 m2; Volumen: 0.157192 m3
IFC-Parameter - In IFC-Datei exportieren: Nach Typ; Pset MEP.Geom-Ø (mm): 400; Pset MEP.Tech-Material (ID): 1; Pset MEP.Geom-Length (mm): 1915; In IFC exportieren als: ifcflowsegment; NameOverride: Wickelfalzrohr; IfcPresentationLayer: 0-TFT-H_Abgasabführung Variante 1; ObjectTypeOverride: Wickelfalzrohr; Pset MEP.Name: Wickelfalzrohr; IfcDescription: Wickelfalzrohr; Pset MEP.Abbreviation: R-R; Pset MEP.Tech-Medium: L_Entrauchung
Phasen - Phase erstellt: Phase 01

# IfcFlowSegment: Wickelfalzrohr:Wickelfalzrohr, Wickelfalzrohr
In: Erdgeschoss
Type - Material: IfcSurfaceStyle #251447
Type - Andere - Kategorie: Allgemeines Modell; Familienname: Wickelfalzrohr
Type - ID-Daten - Typname: Wickelfalzrohr
Type - IFC-Parameter - Typ in IFC-Datei exportieren: Vorgabe
Description: Wickelfalzrohr
Pset_DistributionFlowElementCommon - Reference: Wickelfalzrohr; sets with these values: 2
Andere - Typ: Wickelfalzrohr; Familie: Wickelfalzrohr; Familie und Typ: Wickelfalzrohr: Wickelfalzrohr; Typ-ID: 2532851
Abhängigkeiten - Höhe von Ebene: 0 m; Verschieben mit umliegenden Elementen: no
Bemaßungen - Fläche: 18.3789 m2; Volumen: 2.41329 m3
IFC-Parameter - In IFC-Datei exportieren: Nach Typ; In IFC exportieren als: ifcflowsegment; NameOverride: Wickelfalzrohr; IfcPresentationLayer: 0-TFT-H_Abgasabführung Variante 1; ObjectTypeOverride: Wickelfalzrohr; Pset MEP.Name: Wickelfalzrohr; IfcDescription: Wickelfalzrohr; Pset MEP.Geom-Length (mm): 29400; Pset MEP.Abbreviation: R-R; Pset MEP.Geom-Ø (mm): 400; Pset MEP.Tech-Material (ID): 1; Pset MEP.Tech-Medium: L_Entrauchung
Phasen - Phase erstellt: Phase 01

# IfcFlowStorageDevice: Behälter 288680:Behälter 288680, Behälter
In: Erdgeschoss
Type - Material: IfcSurfaceStyle #292280
Type - Andere - Kategorie: Sonderausstattung; Familienname: Behälter 288680
Type - ID-Daten - Typname: Behälter 288680
Type - IFC-Parameter - Typ in IFC-Datei exportieren: Vorgabe
Description: Behälter
Pset_DistributionFlowElementCommon - Reference: Behälter 288680; sets with these values: 2
Andere - Typ: Behälter 288680; Familie: Behälter 288680; Familie und Typ: Behälter 288680: Behälter 288680; Typ-ID: 2534304
Abhängigkeiten - Höhe von Ebene: 0 m; Verschieben mit umliegenden Elementen: no
Bemaßungen - Fläche: 37.4128 m2; Volumen: 28.4244 m3
IFC-Parameter - In IFC-Datei exportieren: Nach Typ; Pset MEP.Tech-Insulation thickness (mm): 100; Pset MEP.Geom-Length (mm): 6500; Pset MEP.Geom-Ø (mm): 1600; In IFC exportieren als: ifcflowstoragedevice; NameOverride: Behälter; IfcPresentationLayer: 0-TFT-H_Variante 2 Pufferspeicher; ObjectTypeOverride: Behälter; Pset MEP.Name: Behälter; IfcDescription: Behälter
Phasen - Phase erstellt: Phase 01

# IfcFlowStorageDevice: Behälter 297339:Behälter 297339, Behälter
In: Erdgeschoss
Type - Material: IfcSurfaceStyle #228457
Type - Andere - Kategorie: Sonderausstattung; Familienname: Behälter 297339
Type - ID-Daten - Typname: Behälter 297339
Type - IFC-Parameter - Typ in IFC-Datei exportieren: Vorgabe
Description: Behälter
Pset_DistributionFlowElementCommon - Reference: Behälter 297339; sets with these values: 2
Andere - Typ: Behälter 297339; Familie: Behälter 297339; Familie und Typ: Behälter 297339: Behälter 297339; Typ-ID: 2534776
Abhängigkeiten - Höhe von Ebene: 0 m; Verschieben mit umliegenden Elementen: no
Bemaßungen - Fläche: 58.4298 m2; Volumen: 10.3055 m3
IFC-Parameter - In IFC-Datei exportieren: Nach Typ; In IFC exportieren als: ifcflowstoragedevice; NameOverride: Behälter; IfcPresentationLayer: 0; ObjectTypeOverride: Behälter; Pset MEP.Name: Behälter; IfcDescription: Behälter; Pset MEP.Tech-Insulation thickness (mm): 200; Pset MEP.Geom-Length (mm): 5900; Pset MEP.Geom-Ø (mm): 2500
Phasen - Phase erstellt: Phase 01

# IfcFlowStorageDevice: Behälter:Behälter, Behälter
In: Erdgeschoss
Type - Material: IfcSurfaceStyle #288664
Type - Andere - Kategorie: Sonderausstattung; Familienname: Behälter
Type - ID-Daten - Typname: Behälter
Type - IFC-Parameter - Typ in IFC-Datei exportieren: Vorgabe
Description: Behälter
Pset_DistributionFlowElementCommon - Reference: Behälter; sets with these values: 2
Andere - Typ: Behälter; Familie: Behälter; Familie und Typ: Behälter: Behälter; Typ-ID: 2534286
Abhängigkeiten - Höhe von Ebene: 0 m; Verschieben mit umliegenden Elementen: no
Bemaßungen - Fläche: 37.4128 m2; Volumen: 28.4244 m3
IFC-Parameter - In IFC-Datei exportieren: Nach Typ; Pset MEP.Tech-Insulation thickness (mm): 100; In IFC exportieren als: ifcflowstoragedevice; NameOverride: Behälter; IfcPresentationLayer: 0-TFT-H_Variante 2 Pufferspeicher; ObjectTypeOverride: Behälter; Pset MEP.Name: Behälter; IfcDescription: Behälter; Pset MEP.Geom-Length (mm): 6500; Pset MEP.Geom-Ø (mm): 1600
Phasen - Phase erstellt: Phase 01

# IfcFlowTerminal: Ausgussbecken:Ausgussbecken, Ausgussbecken
In: Erdgeschoss
Type - Material: IfcSurfaceStyle #270045
Type - Andere - Kategorie: Allgemeines Modell; Familienname: Ausgussbecken
Type - ID-Daten - Typname: Ausgussbecken
Type - IFC-Parameter - Typ in IFC-Datei exportieren: Vorgabe
Description: Ausgussbecken
Pset_DistributionFlowElementCommon - Reference: Ausgussbecken; sets with these values: 2
Andere - Typ: Ausgussbecken; Familie: Ausgussbecken; Familie und Typ: Ausgussbecken: Ausgussbecken; Typ-ID: 2539109
Abhängigkeiten - Höhe von Ebene: 0 m; Verschieben mit umliegenden Elementen: no
Bemaßungen - Fläche: 0.5324 m2; Volumen: 0.0600174 m3
IFC-Parameter - In IFC-Datei exportieren: Nach Typ; In IFC exportieren als: ifcflowterminal; NameOverride: Ausgussbecken; IfcPresentationLayer: 0-TFT-S_Einrichtungsgegenstände; ObjectTypeOverride: Ausgussbecken; Pset MEP.Name: Ausgussbecken; IfcDescription: Ausgussbecken; Pset MEP.Geom-Length (mm): 600; Pset MEP.Calc-Coefficient: 2.5; Pset MEP.Calc-Consumption (l/s): 0.07; Pset MEP.Calc-Permanent flow (true/false): no; Pset MEP.Calc-Relevant for piping calculation (true/false): yes; Pset MEP.Geom-height(mm): 200; Pset MEP.Geom-Width(mm): 500
Phasen - Phase erstellt: Phase 01

# IfcFlowTerminal: Bodengitter 852295:Bodengitter 852295, Bodengitter
In: Erdgeschoss
Type - Material: IfcSurfaceStyle #271082
Type - Andere - Kategorie: Allgemeines Modell; Familienname: Bodengitter 852295
Type - ID-Daten - Typname: Bodengitter 852295
Type - IFC-Parameter - Typ in IFC-Datei exportieren: Vorgabe
Description: Bodengitter
Pset_DistributionFlowElementCommon - Reference: Bodengitter 852295; sets with these values: 2
Andere - Typ: Bodengitter 852295; Familie: Bodengitter 852295; Familie und Typ: Bodengitter 852295: Bodengitter 852295; Typ-ID: 2539450
Abhängigkeiten - Höhe von Ebene: 0 m; Verschieben mit umliegenden Elementen: no
Bemaßungen - Fläche: 0.003058 m2; Volumen: 0.00155856 m3
IFC-Parameter - In IFC-Datei exportieren: Nach Typ; Pset MEP.Calc-Pressure loss (Pa): 0; Pset MEP.Calc-Required throttling (Pa): 0; Pset MEP.Calc-volumetric flow (m3/h): 200; Pset MEP.Geom-Length (mm): 1; In IFC exportieren als: ifcflowterminal; NameOverride: Bodengitter; IfcPresentationLayer: 0-TFT-L_Bauteil; ObjectTypeOverride: Bodengitter; Pset MEP.Name: Bodengitter; IfcDescription: Bodengitter; Pset MEP.Tech-Medium: L_Zuluft; Pset MEP.Geom-Side 1 (mm): 1530; Pset MEP.Geom-Side 2 (mm): 1530
Phasen - Phase erstellt: Phase 01

# IfcFlowTerminal: Bodengitter 852407:Bodengitter 852407, Bodengitter
In: Erdgeschoss
Type - Material: IfcSurfaceStyle #271082
Type - Andere - Kategorie: Allgemeines Modell; Familienname: Bodengitter 852407
Type - ID-Daten - Typname: Bodengitter 852407
Type - IFC-Parameter - Typ in IFC-Datei exportieren: Vorgabe
Description: Bodengitter
Pset_DistributionFlowElementCommon - Reference: Bodengitter 852407; sets with these values: 2
Andere - Typ: Bodengitter 852407; Familie: Bodengitter 852407; Familie und Typ: Bodengitter 852407: Bodengitter 852407; Typ-ID: 2539471
Abhängigkeiten - Höhe von Ebene: 0 m; Verschieben mit umliegenden Elementen: no
Bemaßungen - Fläche: 0.003028 m2; Volumen: 0.00152798 m3
IFC-Parameter - In IFC-Datei exportieren: Nach Typ; Pset MEP.Calc-Pressure loss (Pa): 0; Pset MEP.Calc-Required throttling (Pa): 0; Pset MEP.Calc-volumetric flow (m3/h): 200; Pset MEP.Geom-Length (mm): 1; Pset MEP.Geom-Side 2 (mm): 1530; In IFC exportieren als: ifcflowterminal; NameOverride: Bodengitter; IfcPresentationLayer: 0-TFT-L_Bauteil; ObjectTypeOverride: Bodengitter; Pset MEP.Name: Bodengitter; IfcDescription: Bodengitter; Pset MEP.Tech-Medium: L_Abluft; Pset MEP.Geom-Side 1 (mm): 1500
Phasen - Phase erstellt: Phase 01

# IfcFlowTerminal: Bodengitter:Bodengitter, Bodengitter
In: Erdgeschoss
Type - Material: IfcSurfaceStyle #271082
Type - Andere - Kategorie: Allgemeines Modell; Familienname: Bodengitter
Type - ID-Daten - Typname: Bodengitter
Type - IFC-Parameter - Typ in IFC-Datei exportieren: Vorgabe
Description: Bodengitter
Pset_DistributionFlowElementCommon - Reference: Bodengitter; sets with these values: 2
Andere - Typ: Bodengitter; Familie: Bodengitter; Familie und Typ: Bodengitter: Bodengitter; Typ-ID: 2539422
Abhängigkeiten - Höhe von Ebene: 0 m; Verschieben mit umliegenden Elementen: no
Bemaßungen - Fläche: 0.001398 m2; Volumen: 0.000299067 m3
IFC-Parameter - In IFC-Datei exportieren: Nach Typ; Pset MEP.Calc-Pressure loss (Pa): 0; Pset MEP.Calc-Required throttling (Pa): 0; In IFC exportieren als: ifcflowterminal; NameOverride: Bodengitter; IfcPresentationLayer: 0-TFT-L_Bauteil; ObjectTypeOverride: Bodengitter; Pset MEP.Name: Bodengitter; IfcDescription: Bodengitter; Pset MEP.Geom-Length (mm): 1; Pset MEP.Tech-Medium: L_Zuluft; Pset MEP.Geom-Side 1 (mm): 500; Pset MEP.Geom-Side 2 (mm): 900; Pset MEP.Calc-volumetric flow (m3/h): 4500
Phasen - Phase erstellt: Phase 01

# IfcFlowTerminal: Wetterschutzgitter 275189:Wetterschutzgitter 275189, Wetterschutzgitter
In: 1. Obergeschoss
Type - Material: IfcSurfaceStyle #271082
Type - Andere - Kategorie: Allgemeines Modell; Familienname: Wetterschutzgitter 275189
Type - ID-Daten - Typname: Wetterschutzgitter 275189
Type - IFC-Parameter - Typ in IFC-Datei exportieren: Vorgabe
Description: Wetterschutzgitter
Pset_DistributionFlowElementCommon - Reference: Wetterschutzgitter 275189; sets with these values: 2
Andere - Typ: Wetterschutzgitter 275189; Familie: Wetterschutzgitter 275189; Familie und Typ: Wetterschutzgitter 275189: Wetterschutzgitter 275189; Typ-ID: 2533717
Abhängigkeiten - Höhe von Ebene: 0 m; Verschieben mit umliegenden Elementen: no
Bemaßungen - Fläche: 0.28481 m2; Volumen: 0.13661 m3
IFC-Parameter - In IFC-Datei exportieren: Nach Typ; Pset MEP.Geom-Length (mm): 95; Pset MEP.Calc-Pressure loss (Pa): 0; Pset MEP.Calc-Required throttling (Pa): 0; In IFC exportieren als: ifcflowterminal; NameOverride: Wetterschutzgitter; IfcPresentationLayer: 0-TFT-L_Bauteil; ObjectTypeOverride: Wetterschutzgitter; Pset MEP.Name: Wetterschutzgitter; IfcDescription: Wetterschutzgitter; Pset MEP.Tech-Medium: L_Aussenluft; Pset MEP.Geom-Side 1 (mm): 1800; Pset MEP.Geom-Side 2 (mm): 1200; Pset MEP.Calc-volumetric flow (m3/h): 26900
Phasen - Phase erstellt: Phase 01

# IfcFlowTerminal: Wetterschutzgitter 851361:Wetterschutzgitter 851361, Wetterschutzgitter
In: Erdgeschoss
Type - Material: IfcSurfaceStyle #271082
Type - Andere - Kategorie: Allgemeines Modell; Familienname: Wetterschutzgitter 851361
Type - ID-Daten - Typname: Wetterschutzgitter 851361
Type - IFC-Parameter - Typ in IFC-Datei exportieren: Vorgabe
Description: Wetterschutzgitter
Pset_DistributionFlowElementCommon - Reference: Wetterschutzgitter 851361; sets with these values: 2
Andere - Typ: Wetterschutzgitter 851361; Familie: Wetterschutzgitter 851361; Familie und Typ: Wetterschutzgitter 851361: Wetterschutzgitter 851361; Typ-ID: 2539281
Abhängigkeiten - Höhe von Ebene: 0 m; Verschieben mit umliegenden Elementen: no
Bemaßungen - Fläche: 0.32281 m2; Volumen: 0.182185 m3
IFC-Parameter - In IFC-Datei exportieren: Nach Typ; Pset MEP.Geom-Length (mm): 95; Pset MEP.Calc-Pressure loss (Pa): 0; Pset MEP.Calc-Required throttling (Pa): 0; Pset MEP.Calc-volumetric flow (m3/h): 200; Pset MEP.Geom-Side 1 (mm): 1800; In IFC exportieren als: ifcflowterminal; NameOverride: Wetterschutzgitter; IfcPresentationLayer: 0-TFT-L_Bauteil; ObjectTypeOverride: Wetterschutzgitter; Pset MEP.Name: Wetterschutzgitter; IfcDescription: Wetterschutzgitter; Pset MEP.Tech-Medium: L_Zuluft; Pset MEP.Geom-Side 2 (mm): 1600
Phasen - Phase erstellt: Phase 01

# IfcFlowTerminal: Wetterschutzgitter:Wetterschutzgitter, Wetterschutzgitter
In: 1. Obergeschoss
Type - Material: IfcSurfaceStyle #271082
Type - Andere - Kategorie: Allgemeines Modell; Familienname: Wetterschutzgitter
Type - ID-Daten - Typname: Wetterschutzgitter
Type - IFC-Parameter - Typ in IFC-Datei exportieren: Vorgabe
Description: Wetterschutzgitter
Pset_DistributionFlowElementCommon - Reference: Wetterschutzgitter; sets with these values: 2
Andere - Typ: Wetterschutzgitter; Familie: Wetterschutzgitter; Familie und Typ: Wetterschutzgitter: Wetterschutzgitter; Typ-ID: 2533664
Abhängigkeiten - Höhe von Ebene: 0 m; Verschieben mit umliegenden Elementen: no
Bemaßungen - Fläche: 0.28481 m2; Volumen: 0.13661 m3
IFC-Parameter - In IFC-Datei exportieren: Nach Typ; In IFC exportieren als: ifcflowterminal; NameOverride: Wetterschutzgitter; IfcPresentationLayer: 0-TFT-L_Bauteil; ObjectTypeOverride: Wetterschutzgitter; Pset MEP.Name: Wetterschutzgitter; IfcDescription: Wetterschutzgitter; Pset MEP.Geom-Length (mm): 95; Pset MEP.Tech-Medium: L_Fortluft; Pset MEP.Geom-Side 1 (mm): 1200; Pset MEP.Geom-Side 2 (mm): 1800; Pset MEP.Calc-Pressure loss (Pa): 0; Pset MEP.Calc-Required throttling (Pa): 0; Pset MEP.Calc-volumetric flow (m3/h): 200
Phasen - Phase erstellt: Phase 01

# IfcFlowTreatmentDevice: Schalldämpfer 276123:Schalldämpfer 276123, Schalldämpfer
In: 1. Obergeschoss
Type - Material: IfcSurfaceStyle #271082
Type - Andere - Kategorie: Sanitärausstattung; Familienname: Schalldämpfer 276123
Type - ID-Daten - Typname: Schalldämpfer 276123
Type - IFC-Parameter - Typ in IFC-Datei exportieren: Vorgabe
Type - HLS - Klassifizierung: Keine
Description: Schalldämpfer
Pset_DistributionFlowElementCommon - Reference: Schalldämpfer 276123; sets with these values: 2
Andere - Typ: Schalldämpfer 276123; Familie: Schalldämpfer 276123; Familie und Typ: Schalldämpfer 276123: Schalldämpfer 276123; Typ-ID: 2533766
Abhängigkeiten - Höhe von Ebene: 0 m; Verschieben mit umliegenden Elementen: no
Bemaßungen - Fläche: 6.6 m2; Volumen: 2.34 m3
IFC-Parameter - In IFC-Datei exportieren: Nach Typ; Pset MEP.Geom-Length (mm): 3000; Pset MEP.Calc-Pressure loss (Pa): 22; Pset MEP.Calc-Zeta: 2; Pset MEP.Geom-Side 2 (mm): 900; In IFC exportieren als: ifcflowtreatmentdevice; NameOverride: Schalldämpfer; IfcPresentationLayer: 0-TFT-L_Bauteil; ObjectTypeOverride: Schalldämpfer; Pset MEP.Name: Schalldämpfer; IfcDescription: Schalldämpfer; Pset MEP.Tech-Medium: L_Aussenluft; Pset MEP.Geom-Side 1 (mm): 1300
Phasen - Phase erstellt: Phase 01

# IfcFlowTreatmentDevice: Schalldämpfer 852105:Schalldämpfer 852105, Schalldämpfer
In: Erdgeschoss
Type - Material: IfcSurfaceStyle #271082
Type - Andere - Kategorie: Sanitärausstattung; Familienname: Schalldämpfer 852105
Type - ID-Daten - Typname: Schalldämpfer 852105
Type - IFC-Parameter - Typ in IFC-Datei exportieren: Vorgabe
Type - HLS - Klassifizierung: Keine
Description: Schalldämpfer
Pset_DistributionFlowElementCommon - Reference: Schalldämpfer 852105; sets with these values: 2
Andere - Typ: Schalldämpfer 852105; Familie: Schalldämpfer 852105; Familie und Typ: Schalldämpfer 852105: Schalldämpfer 852105; Typ-ID: 2539415
Abhängigkeiten - Höhe von Ebene: 0 m; Verschieben mit umliegenden Elementen: no
Bemaßungen - Fläche: 1.4 m2; Volumen: 0.3 m3
IFC-Parameter - In IFC-Datei exportieren: Nach Typ; Pset MEP.Geom-Length (mm): 1000; Pset MEP.Calc-Pressure loss (Pa): 22; Pset MEP.Calc-Zeta: 2; Pset MEP.Geom-Side 2 (mm): 900; Pset MEP.Geom-Side 1 (mm): 500; In IFC exportieren als: ifcflowtreatmentdevice; NameOverride: Schalldämpfer; IfcPresentationLayer: 0-TFT-L_Schalldaempfer; ObjectTypeOverride: Schalldämpfer; Pset MEP.Name: Schalldämpfer; IfcDescription: Schalldämpfer; Pset MEP.Tech-Medium: L_Zuluft
Phasen - Phase erstellt: Phase 01

# IfcFlowTreatmentDevice: Schalldämpfer:Schalldämpfer, Schalldämpfer
In: 1. Obergeschoss
Type - Material: IfcSurfaceStyle #271082
Type - Andere - Kategorie: Sanitärausstattung; Familienname: Schalldämpfer
Type - ID-Daten - Typname: Schalldämpfer
Type - IFC-Parameter - Typ in IFC-Datei exportieren: Vorgabe
Type - HLS - Klassifizierung: Keine
Description: Schalldämpfer
Pset_DistributionFlowElementCommon - Reference: Schalldämpfer; sets with these values: 2
Andere - Typ: Schalldämpfer; Familie: Schalldämpfer; Familie und Typ: Schalldämpfer: Schalldämpfer; Typ-ID: 2533690
Abhängigkeiten - Höhe von Ebene: 0 m; Verschieben mit umliegenden Elementen: no
Bemaßungen - Fläche: 6 m2; Volumen: 2 m3
IFC-Parameter - In IFC-Datei exportieren: Nach Typ; Pset MEP.Geom-Side 1 (mm): 1000; Pset MEP.Geom-Side 2 (mm): 1000; In IFC exportieren als: ifcflowtreatmentdevice; NameOverride: Schalldämpfer; IfcPresentationLayer: 0-TFT-L_Bauteil; ObjectTypeOverride: Schalldämpfer; Pset MEP.Name: Schalldämpfer; IfcDescription: Schalldämpfer; Pset MEP.Geom-Length (mm): 3000; Pset MEP.Tech-Medium: L_Fortluft; Pset MEP.Calc-Pressure loss (Pa): 22; Pset MEP.Calc-Zeta: 2
Phasen - Phase erstellt: Phase 01

# IfcFlowTreatmentDevice: Schmutzfänger 312846:Schmutzfänger 312846, Schmutzfänger
In: Erdgeschoss
Type - Material: IfcSurfaceStyle #1741
Type - Andere - Kategorie: Sanitärausstattung; Familienname: Schmutzfänger 312846
Type - ID-Daten - Typname: Schmutzfänger 312846
Type - IFC-Parameter - Typ in IFC-Datei exportieren: Vorgabe
Type - HLS - Klassifizierung: Keine
Description: Schmutzfänger
Pset_DistributionFlowElementCommon - Reference: Schmutzfänger 312846; sets with these values: 2
Andere - Typ: Schmutzfänger 312846; Familie: Schmutzfänger 312846; Familie und Typ: Schmutzfänger 312846: Schmutzfänger 312846; Typ-ID: 2535145
Abhängigkeiten - Höhe von Ebene: 0 m; Verschieben mit umliegenden Elementen: no
Bemaßungen - Fläche: 0.43752 m2; Volumen: 0.0168581 m3
IFC-Parameter - In IFC-Datei exportieren: Nach Typ; Pset MEP.Tech-Insulation thickness (mm): 100; Pset MEP.Tech-PN: 16; Pset MEP.Tech-Connection type (Inner thread=2, flange=3): 2; Pset MEP.Geom-DN: 150; Pset MEP.Geom-Outer Ø (mm): 285; In IFC exportieren als: ifcflowtreatmentdevice; NameOverride: Schmutzfänger; IfcPresentationLayer: 0-TFT-H_Ruecklauf; ObjectTypeOverride: Schmutzfänger; Pset MEP.Name: Schmutzfänger; IfcDescription: Schmutzfänger; Pset MEP.Geom-Length (mm): 480
Phasen - Phase erstellt: Phase 01

# IfcFlowTreatmentDevice: Schmutzfänger 319970:Schmutzfänger 319970, Schmutzfänger
In: Erdgeschoss
Type - Material: IfcSurfaceStyle #1741
Type - Andere - Kategorie: Sanitärausstattung; Familienname: Schmutzfänger 319970
Type - ID-Daten - Typname: Schmutzfänger 319970
Type - IFC-Parameter - Typ in IFC-Datei exportieren: Vorgabe
Type - HLS - Klassifizierung: Keine
Description: Schmutzfänger
Pset_DistributionFlowElementCommon - Reference: Schmutzfänger 319970; sets with these values: 2
Andere - Typ: Schmutzfänger 319970; Familie: Schmutzfänger 319970; Familie und Typ: Schmutzfänger 319970: Schmutzfänger 319970; Typ-ID: 2535474
Abhängigkeiten - Höhe von Ebene: 0 m; Verschieben mit umliegenden Elementen: no
Bemaßungen - Fläche: 0.801348 m2; Volumen: 0.0747833 m3
IFC-Parameter - In IFC-Datei exportieren: Nach Typ; Pset MEP.Tech-Insulation thickness (mm): 100; Pset MEP.Tech-PN: 16; Pset MEP.Tech-Connection type (Inner thread=2, flange=3): 2; Pset MEP.Geom-DN: 150; Pset MEP.Geom-Outer Ø (mm): 285; Pset MEP.Geom-Length (mm): 480; In IFC exportieren als: ifcflowtreatmentdevice; NameOverride: Schmutzfänger; IfcPresentationLayer: 0-TFT-H_Ruecklauf; ObjectTypeOverride: Schmutzfänger; Pset MEP.Name: Schmutzfänger; IfcDescription: Schmutzfänger
Phasen - Phase erstellt: Phase 01

# IfcFlowTreatmentDevice: Schmutzfänger 332510:Schmutzfänger 332510, Schmutzfänger
In: Erdgeschoss
Type - Material: IfcSurfaceStyle #1741
Type - Andere - Kategorie: Sanitärausstattung; Familienname: Schmutzfänger 332510
Type - ID-Daten - Typname: Schmutzfänger 332510
Type - IFC-Parameter - Typ in IFC-Datei exportieren: Vorgabe
Type - HLS - Klassifizierung: Keine
Description: Schmutzfänger
Pset_DistributionFlowElementCommon - Reference: Schmutzfänger 332510; sets with these values: 2
Andere - Typ: Schmutzfänger 332510; Familie: Schmutzfänger 332510; Familie und Typ: Schmutzfänger 332510: Schmutzfänger 332510; Typ-ID: 2535789
Abhängigkeiten - Höhe von Ebene: 0 m; Verschieben mit umliegenden Elementen: no
Bemaßungen - Fläche: 0.319571 m2; Volumen: 0.024861 m3
IFC-Parameter - In IFC-Datei exportieren: Nach Typ; Pset MEP.Tech-Insulation thickness (mm): 100; Pset MEP.Tech-PN: 16; Pset MEP.Tech-Connection type (Inner thread=2, flange=3): 2; Pset MEP.Geom-DN: 65; Pset MEP.Geom-Outer Ø (mm): 185; Pset MEP.Geom-Length (mm): 290; In IFC exportieren als: ifcflowtreatmentdevice; NameOverride: Schmutzfänger; IfcPresentationLayer: 0-TFT-H_Ruecklauf; ObjectTypeOverride: Schmutzfänger; Pset MEP.Name: Schmutzfänger; IfcDescription: Schmutzfänger
Phasen - Phase erstellt: Phase 01

# IfcFlowTreatmentDevice: Schmutzfänger 341058:Schmutzfänger 341058, Schmutzfänger
In: Erdgeschoss
Type - Material: IfcSurfaceStyle #1741
Type - Andere - Kategorie: Sanitärausstattung; Familienname: Schmutzfänger 341058
Type - ID-Daten - Typname: Schmutzfänger 341058
Type - IFC-Parameter - Typ in IFC-Datei exportieren: Vorgabe
Type - HLS - Klassifizierung: Keine
Description: Schmutzfänger
Pset_DistributionFlowElementCommon - Reference: Schmutzfänger 341058; sets with these values: 2
Andere - Typ: Schmutzfänger 341058; Familie: Schmutzfänger 341058; Familie und Typ: Schmutzfänger 341058: Schmutzfänger 341058; Typ-ID: 2536020
Abhängigkeiten - Höhe von Ebene: 0 m; Verschieben mit umliegenden Elementen: no
Bemaßungen - Fläche: 0.801348 m2; Volumen: 0.0747833 m3
IFC-Parameter - In IFC-Datei exportieren: Nach Typ; Pset MEP.Tech-Insulation thickness (mm): 100; Pset MEP.Tech-PN: 16; Pset MEP.Tech-Connection type (Inner thread=2, flange=3): 2; Pset MEP.Geom-DN: 150; Pset MEP.Geom-Outer Ø (mm): 285; Pset MEP.Geom-Length (mm): 480; In IFC exportieren als: ifcflowtreatmentdevice; NameOverride: Schmutzfänger; IfcPresentationLayer: 0-TFT-H_Ruecklauf; ObjectTypeOverride: Schmutzfänger; Pset MEP.Name: Schmutzfänger; IfcDescription: Schmutzfänger
Phasen - Phase erstellt: Phase 01

# IfcFlowTreatmentDevice: Schmutzfänger:Schmutzfänger, Schmutzfänger
In: 1. Obergeschoss
Type - Material: IfcSurfaceStyle #1741
Type - Andere - Kategorie: Sanitärausstattung; Familienname: Schmutzfänger
Type - ID-Daten - Typname: Schmutzfänger
Type - IFC-Parameter - Typ in IFC-Datei exportieren: Vorgabe
Type - HLS - Klassifizierung: Keine
Description: Schmutzfänger
Pset_DistributionFlowElementCommon - Reference: Schmutzfänger; sets with these values: 2
Andere - Typ: Schmutzfänger; Familie: Schmutzfänger; Familie und Typ: Schmutzfänger: Schmutzfänger; Typ-ID: 2531436
Abhängigkeiten - Höhe von Ebene: 0 m; Verschieben mit umliegenden Elementen: no
IFC-Parameter - In IFC-Datei exportieren: Nach Typ; Pset MEP.Geom-DN: 200; Pset MEP.Geom-Outer Ø (mm): 340; Pset MEP.Tech-Insulation thickness (mm): 100; Pset MEP.Tech-PN: 16; Pset MEP.Tech-Connection type (Inner thread=2, flange=3): 2; In IFC exportieren als: ifcflowtreatmentdevice; NameOverride: Schmutzfänger; IfcPresentationLayer: 0-TFT-H_Ruecklauf; ObjectTypeOverride: Schmutzfänger; Pset MEP.Name: Schmutzfänger; IfcDescription: Schmutzfänger; Pset MEP.Geom-Length (mm): 400
Phasen - Phase erstellt: Phase 01

# IfcFlowTreatmentDevice: Telefonieschalldämpfer 280796:Telefonieschalldämpfer 280796, Telefonieschalldämpfer
In: Erdgeschoss
Type - Material: IfcSurfaceStyle #280217
Type - Andere - Kategorie: Sanitärausstattung; Familienname: Telefonieschalldämpfer 280796
Type - ID-Daten - Typname: Telefonieschalldämpfer 280796
Type - IFC-Parameter - Typ in IFC-Datei exportieren: Vorgabe
Type - HLS - Klassifizierung: Keine
Description: Telefonieschalldämpfer
Pset_DistributionFlowElementCommon - Reference: Telefonieschalldämpfer 280796; sets with these values: 2
Andere - Typ: Telefonieschalldämpfer 280796; Familie: Telefonieschalldämpfer 280796; Familie und Typ: Telefonieschalldämpfer 280796: Telefonieschalldämpfer 280796; Typ-ID: 2534041
Abhängigkeiten - Höhe von Ebene: 0 m; Verschieben mit umliegenden Elementen: no
Bemaßungen - Fläche: 2.25784 m2; Volumen: 0.460124 m3
IFC-Parameter - In IFC-Datei exportieren: Nach Typ; Pset MEP.Geom-Ø (mm): 400; Pset MEP.Geom-Length (mm): 3000; Pset MEP.Calc-Pressure loss (Pa): 22; Pset MEP.Calc-Zeta: 2; Pset MEP.Geom-Outer Ø (mm): 450; In IFC exportieren als: ifcflowtreatmentdevice; NameOverride: Telefonieschalldämpfer; IfcPresentationLayer: 0-TFT-H_Abgasabführung Variante 2; ObjectTypeOverride: Telefonieschalldämpfer; Pset MEP.Name: Telefonieschalldämpfer; IfcDescription: Telefonieschalldämpfer; Pset MEP.Abbreviation: B.RSD; Pset MEP.Tech-Medium: L_Entrauchung; Pset MEP.Info: ETB ERA 35
Phasen - Phase erstellt: Phase 01

# IfcFlowTreatmentDevice: Telefonieschalldämpfer 281422:Telefonieschalldämpfer 281422, Telefonieschalldämpfer
In: Erdgeschoss
Type - Material: IfcSurfaceStyle #280217
Type - Andere - Kategorie: Sanitärausstattung; Familienname: Telefonieschalldämpfer 281422
Type - ID-Daten - Typname: Telefonieschalldämpfer 281422
Type - IFC-Parameter - Typ in IFC-Datei exportieren: Vorgabe
Type - HLS - Klassifizierung: Keine
Description: Telefonieschalldämpfer
Pset_DistributionFlowElementCommon - Reference: Telefonieschalldämpfer 281422; sets with these values: 2
Andere - Typ: Telefonieschalldämpfer 281422; Familie: Telefonieschalldämpfer 281422; Familie und Typ: Telefonieschalldämpfer 281422: Telefonieschalldämpfer 281422; Typ-ID: 2534111
Abhängigkeiten - Höhe von Ebene: 0 m; Verschieben mit umliegenden Elementen: no
Bemaßungen - Fläche: 2.25784 m2; Volumen: 0.460124 m3
IFC-Parameter - In IFC-Datei exportieren: Nach Typ; Pset MEP.Geom-Ø (mm): 400; Pset MEP.Geom-Length (mm): 3000; Pset MEP.Calc-Pressure loss (Pa): 22; Pset MEP.Calc-Zeta: 2; Pset MEP.Geom-Outer Ø (mm): 450; In IFC exportieren als: ifcflowtreatmentdevice; NameOverride: Telefonieschalldämpfer; IfcPresentationLayer: 0-TFT-H_Abgasabführung Variante 2; ObjectTypeOverride: Telefonieschalldämpfer; Pset MEP.Name: Telefonieschalldämpfer; IfcDescription: Telefonieschalldämpfer; Pset MEP.Abbreviation: B.RSD; Pset MEP.Tech-Medium: L_Entrauchung; Pset MEP.Info: ETB ERA 35
Phasen - Phase erstellt: Phase 01

# IfcFlowTreatmentDevice: Telefonieschalldämpfer 282164:Telefonieschalldämpfer 282164, Telefonieschalldämpfer
In: Erdgeschoss
Type - Material: IfcSurfaceStyle #280217
Type - Andere - Kategorie: Sanitärausstattung; Familienname: Telefonieschalldämpfer 282164
Type - ID-Daten - Typname: Telefonieschalldämpfer 282164
Type - IFC-Parameter - Typ in IFC-Datei exportieren: Vorgabe
Type - HLS - Klassifizierung: Keine
Description: Telefonieschalldämpfer
Pset_DistributionFlowElementCommon - Reference: Telefonieschalldämpfer 282164; sets with these values: 2
Andere - Typ: Telefonieschalldämpfer 282164; Familie: Telefonieschalldämpfer 282164; Familie und Typ: Telefonieschalldämpfer 282164: Telefonieschalldämpfer 282164; Typ-ID: 2534167
Abhängigkeiten - Höhe von Ebene: 0 m; Verschieben mit umliegenden Elementen: no
Bemaßungen - Fläche: 0.999145 m2; Volumen: 0.134799 m3
IFC-Parameter - In IFC-Datei exportieren: Nach Typ; Pset MEP.Calc-Pressure loss (Pa): 22; Pset MEP.Calc-Zeta: 2; Pset MEP.Geom-Ø (mm): 250; In IFC exportieren als: ifcflowtreatmentdevice; NameOverride: Telefonieschalldämpfer; IfcPresentationLayer: 0-TFT-H_Abgasabführung Variante 2; ObjectTypeOverride: Telefonieschalldämpfer; Pset MEP.Name: Telefonieschalldämpfer; IfcDescription: Telefonieschalldämpfer; Pset MEP.Geom-Outer Ø (mm): 300; Pset MEP.Geom-Length (mm): 2000; Pset MEP.Abbreviation: B.RSD; Pset MEP.Tech-Medium: L_Entrauchung; Pset MEP.Info: ETB ERA 35
Phasen - Phase erstellt: Phase 01

# IfcFlowTreatmentDevice: Telefonieschalldämpfer 294102:Telefonieschalldämpfer 294102, Telefonieschalldämpfer
In: Erdgeschoss
Type - Material: IfcSurfaceStyle #280217
Type - Andere - Kategorie: Sanitärausstattung; Familienname: Telefonieschalldämpfer 294102
Type - ID-Daten - Typname: Telefonieschalldämpfer 294102
Type - IFC-Parameter - Typ in IFC-Datei exportieren: Vorgabe
Type - HLS - Klassifizierung: Keine
Description: Telefonieschalldämpfer
Pset_DistributionFlowElementCommon - Reference: Telefonieschalldämpfer 294102; sets with these values: 2
Andere - Typ: Telefonieschalldämpfer 294102; Familie: Telefonieschalldämpfer 294102; Familie und Typ: Telefonieschalldämpfer 294102: Telefonieschalldämpfer 294102; Typ-ID: 2534466
Abhängigkeiten - Höhe von Ebene: 0 m; Verschieben mit umliegenden Elementen: no
Bemaßungen - Fläche: 0.999145 m2; Volumen: 0.134799 m3
IFC-Parameter - In IFC-Datei exportieren: Nach Typ; Pset MEP.Calc-Pressure loss (Pa): 22; Pset MEP.Calc-Zeta: 2; Pset MEP.Geom-Ø (mm): 250; Pset MEP.Geom-Outer Ø (mm): 300; Pset MEP.Geom-Length (mm): 2000; In IFC exportieren als: ifcflowtreatmentdevice; NameOverride: Telefonieschalldämpfer; IfcPresentationLayer: 0-TFT-H_Abgasabführung Variante 3; ObjectTypeOverride: Telefonieschalldämpfer; Pset MEP.Name: Telefonieschalldämpfer; IfcDescription: Telefonieschalldämpfer; Pset MEP.Abbreviation: B.RSD; Pset MEP.Tech-Medium: L_Entrauchung; Pset MEP.Info: ETB ERA 35
Phasen - Phase erstellt: Phase 01

# IfcFlowTreatmentDevice: Telefonieschalldämpfer 294722:Telefonieschalldämpfer 294722, Telefonieschalldämpfer
In: Erdgeschoss
Type - Material: IfcSurfaceStyle #280217
Type - Andere - Kategorie: Sanitärausstattung; Familienname: Telefonieschalldämpfer 294722
Type - ID-Daten - Typname: Telefonieschalldämpfer 294722
Type - IFC-Parameter - Typ in IFC-Datei exportieren: Vorgabe
Type - HLS - Klassifizierung: Keine
Description: Telefonieschalldämpfer
Pset_DistributionFlowElementCommon - Reference: Telefonieschalldämpfer 294722; sets with these values: 2
Andere - Typ: Telefonieschalldämpfer 294722; Familie: Telefonieschalldämpfer 294722; Familie und Typ: Telefonieschalldämpfer 294722: Telefonieschalldämpfer 294722; Typ-ID: 2534536
Abhängigkeiten - Höhe von Ebene: 0 m; Verschieben mit umliegenden Elementen: no
Bemaßungen - Fläche: 2.52101 m2; Volumen: 0.566129 m3
IFC-Parameter - In IFC-Datei exportieren: Nach Typ; Pset MEP.Geom-Ø (mm): 400; Pset MEP.Geom-Length (mm): 3000; Pset MEP.Calc-Pressure loss (Pa): 22; Pset MEP.Calc-Zeta: 2; In IFC exportieren als: ifcflowtreatmentdevice; NameOverride: Telefonieschalldämpfer; IfcPresentationLayer: 0-TFT-H_Abgasabführung Variante 3; ObjectTypeOverride: Telefonieschalldämpfer; Pset MEP.Name: Telefonieschalldämpfer; IfcDescription: Telefonieschalldämpfer; Pset MEP.Geom-Outer Ø (mm): 500; Pset MEP.Abbreviation: B.RSD; Pset MEP.Tech-Medium: L_Entrauchung; Pset MEP.Info: ETB ERA 35
Phasen - Phase erstellt: Phase 01

# IfcFlowTreatmentDevice: Telefonieschalldämpfer 295822:Telefonieschalldämpfer 295822, Telefonieschalldämpfer
In: Erdgeschoss
Type - Material: IfcSurfaceStyle #280217
Type - Andere - Kategorie: Sanitärausstattung; Familienname: Telefonieschalldämpfer 295822
Type - ID-Daten - Typname: Telefonieschalldämpfer 295822
Type - IFC-Parameter - Typ in IFC-Datei exportieren: Vorgabe
Type - HLS - Klassifizierung: Keine
Description: Telefonieschalldämpfer
Pset_DistributionFlowElementCommon - Reference: Telefonieschalldämpfer 295822; sets with these values: 2
Andere - Typ: Telefonieschalldämpfer 295822; Familie: Telefonieschalldämpfer 295822; Familie und Typ: Telefonieschalldämpfer 295822: Telefonieschalldämpfer 295822; Typ-ID: 2534599
Abhängigkeiten - Höhe von Ebene: 0 m; Verschieben mit umliegenden Elementen: no
Bemaßungen - Fläche: 2.52101 m2; Volumen: 0.566129 m3
IFC-Parameter - In IFC-Datei exportieren: Nach Typ; Pset MEP.Geom-Ø (mm): 400; Pset MEP.Geom-Length (mm): 3000; Pset MEP.Calc-Pressure loss (Pa): 22; Pset MEP.Calc-Zeta: 2; Pset MEP.Geom-Outer Ø (mm): 500; In IFC exportieren als: ifcflowtreatmentdevice; NameOverride: Telefonieschalldämpfer; IfcPresentationLayer: 0-TFT-H_Abgasabführung Variante 3; ObjectTypeOverride: Telefonieschalldämpfer; Pset MEP.Name: Telefonieschalldämpfer; IfcDescription: Telefonieschalldämpfer; Pset MEP.Abbreviation: B.RSD; Pset MEP.Tech-Medium: L_Entrauchung; Pset MEP.Info: ETB ERA 35
Phasen - Phase erstellt: Phase 01

# IfcFlowTreatmentDevice: Telefonieschalldämpfer 296637:Telefonieschalldämpfer 296637, Telefonieschalldämpfer
In: Erdgeschoss
Type - Material: IfcSurfaceStyle #280217
Type - Andere - Kategorie: Sanitärausstattung; Familienname: Telefonieschalldämpfer 296637
Type - ID-Daten - Typname: Telefonieschalldämpfer 296637
Type - IFC-Parameter - Typ in IFC-Datei exportieren: Vorgabe
Type - HLS - Klassifizierung: Keine
Description: Telefonieschalldämpfer
Pset_DistributionFlowElementCommon - Reference: Telefonieschalldämpfer 296637; sets with these values: 2
Andere - Typ: Telefonieschalldämpfer 296637; Familie: Telefonieschalldämpfer 296637; Familie und Typ: Telefonieschalldämpfer 296637: Telefonieschalldämpfer 296637; Typ-ID: 2534683
Abhängigkeiten - Höhe von Ebene: 0 m; Verschieben mit umliegenden Elementen: no
Bemaßungen - Fläche: 2.25784 m2; Volumen: 0.460124 m3
IFC-Parameter - In IFC-Datei exportieren: Nach Typ; Pset MEP.Geom-Ø (mm): 400; Pset MEP.Geom-Length (mm): 3000; Pset MEP.Calc-Pressure loss (Pa): 22; Pset MEP.Calc-Zeta: 2; Pset MEP.Geom-Outer Ø (mm): 450; In IFC exportieren als: ifcflowtreatmentdevice; NameOverride: Telefonieschalldämpfer; IfcPresentationLayer: 0-TFT-H_Abgasabführung Variante 3; ObjectTypeOverride: Telefonieschalldämpfer; Pset MEP.Name: Telefonieschalldämpfer; IfcDescription: Telefonieschalldämpfer; Pset MEP.Abbreviation: B.RSD; Pset MEP.Tech-Medium: L_Entrauchung; Pset MEP.Info: ETB ERA 35
Phasen - Phase erstellt: Phase 01

# IfcFlowTreatmentDevice: Telefonieschalldämpfer 613631:Telefonieschalldämpfer 613631, Telefonieschalldämpfer
In: Erdgeschoss
Type - Material: IfcSurfaceStyle #280217
Type - Andere - Kategorie: Sanitärausstattung; Familienname: Telefonieschalldämpfer 613631
Type - ID-Daten - Typname: Telefonieschalldämpfer 613631
Type - IFC-Parameter - Typ in IFC-Datei exportieren: Vorgabe
Type - HLS - Klassifizierung: Keine
Description: Telefonieschalldämpfer
Pset_DistributionFlowElementCommon - Reference: Telefonieschalldämpfer 613631; sets with these values: 2
Andere - Typ: Telefonieschalldämpfer 613631; Familie: Telefonieschalldämpfer 613631; Familie und Typ: Telefonieschalldämpfer 613631: Telefonieschalldämpfer 613631; Typ-ID: 2537661
Abhängigkeiten - Höhe von Ebene: 0 m; Verschieben mit umliegenden Elementen: no
Bemaßungen - Fläche: 1.11438 m2; Volumen: 0.120108 m3
IFC-Parameter - In IFC-Datei exportieren: Nach Typ; Pset MEP.Geom-Ø (mm): 200; Pset MEP.Geom-Length (mm): 3000; Pset MEP.Calc-Pressure loss (Pa): 22; Pset MEP.Calc-Zeta: 2; In IFC exportieren als: ifcflowtreatmentdevice; NameOverride: Telefonieschalldämpfer; IfcPresentationLayer: 0-TFT-H_Abgasabführung Variante 1; ObjectTypeOverride: Telefonieschalldämpfer; Pset MEP.Name: Telefonieschalldämpfer; IfcDescription: Telefonieschalldämpfer; Pset MEP.Geom-Outer Ø (mm): 230; Pset MEP.Abbreviation: B.RSD; Pset MEP.Tech-Medium: L_Entrauchung; Pset MEP.Info: ETB ERA 35
Phasen - Phase erstellt: Phase 01

# IfcFlowTreatmentDevice: Telefonieschalldämpfer 620622:Telefonieschalldämpfer 620622, Telefonieschalldämpfer
In: Erdgeschoss
Type - Material: IfcSurfaceStyle #280217
Type - Andere - Kategorie: Sanitärausstattung; Familienname: Telefonieschalldämpfer 620622
Type - ID-Daten - Typname: Telefonieschalldämpfer 620622
Type - IFC-Parameter - Typ in IFC-Datei exportieren: Vorgabe
Type - HLS - Klassifizierung: Keine
Description: Telefonieschalldämpfer
Pset_DistributionFlowElementCommon - Reference: Telefonieschalldämpfer 620622; sets with these values: 2
Andere - Typ: Telefonieschalldämpfer 620622; Familie: Telefonieschalldämpfer 620622; Familie und Typ: Telefonieschalldämpfer 620622: Telefonieschalldämpfer 620622; Typ-ID: 2537994
Abhängigkeiten - Höhe von Ebene: 0 m; Verschieben mit umliegenden Elementen: no
Bemaßungen - Fläche: 2.25784 m2; Volumen: 0.460124 m3
IFC-Parameter - In IFC-Datei exportieren: Nach Typ; Pset MEP.Geom-Ø (mm): 400; Pset MEP.Geom-Length (mm): 3000; Pset MEP.Calc-Pressure loss (Pa): 22; Pset MEP.Calc-Zeta: 2; Pset MEP.Geom-Outer Ø (mm): 450; In IFC exportieren als: ifcflowtreatmentdevice; NameOverride: Telefonieschalldämpfer; IfcPresentationLayer: 0-TFT-H_Abgasabführung Variante 1; ObjectTypeOverride: Telefonieschalldämpfer; Pset MEP.Name: Telefonieschalldämpfer; IfcDescription: Telefonieschalldämpfer; Pset MEP.Abbreviation: B.RSD; Pset MEP.Tech-Medium: L_Entrauchung; Pset MEP.Info: ETB ERA 35
Phasen - Phase erstellt: Phase 01

# IfcFlowTreatmentDevice: Telefonieschalldämpfer 620691:Telefonieschalldämpfer 620691, Telefonieschalldämpfer
In: Erdgeschoss
Type - Material: IfcSurfaceStyle #280217
Type - Andere - Kategorie: Sanitärausstattung; Familienname: Telefonieschalldämpfer 620691
Type - ID-Daten - Typname: Telefonieschalldämpfer 620691
Type - IFC-Parameter - Typ in IFC-Datei exportieren: Vorgabe
Type - HLS - Klassifizierung: Keine
Description: Telefonieschalldämpfer
Pset_DistributionFlowElementCommon - Reference: Telefonieschalldämpfer 620691; sets with these values: 2
Andere - Typ: Telefonieschalldämpfer 620691; Familie: Telefonieschalldämpfer 620691; Familie und Typ: Telefonieschalldämpfer 620691: Telefonieschalldämpfer 620691; Typ-ID: 2538015
Abhängigkeiten - Höhe von Ebene: 0 m; Verschieben mit umliegenden Elementen: no
Bemaßungen - Fläche: 2.25784 m2; Volumen: 0.460124 m3
IFC-Parameter - In IFC-Datei exportieren: Nach Typ; Pset MEP.Geom-Ø (mm): 400; Pset MEP.Geom-Length (mm): 3000; Pset MEP.Calc-Pressure loss (Pa): 22; Pset MEP.Calc-Zeta: 2; Pset MEP.Geom-Outer Ø (mm): 450; In IFC exportieren als: ifcflowtreatmentdevice; NameOverride: Telefonieschalldämpfer; IfcPresentationLayer: 0-TFT-H_Abgasabführung Variante 1; ObjectTypeOverride: Telefonieschalldämpfer; Pset MEP.Name: Telefonieschalldämpfer; IfcDescription: Telefonieschalldämpfer; Pset MEP.Abbreviation: B.RSD; Pset MEP.Tech-Medium: L_Entrauchung; Pset MEP.Info: ETB ERA 35
Phasen - Phase erstellt: Phase 01

# IfcFlowTreatmentDevice: Telefonieschalldämpfer 621543:Telefonieschalldämpfer 621543, Telefonieschalldämpfer
In: Erdgeschoss
Type - Material: IfcSurfaceStyle #280217
Type - Andere - Kategorie: Sanitärausstattung; Familienname: Telefonieschalldämpfer 621543
Type - ID-Daten - Typname: Telefonieschalldämpfer 621543
Type - IFC-Parameter - Typ in IFC-Datei exportieren: Vorgabe
Type - HLS - Klassifizierung: Keine
Description: Telefonieschalldämpfer
Pset_DistributionFlowElementCommon - Reference: Telefonieschalldämpfer 621543; sets with these values: 2
Andere - Typ: Telefonieschalldämpfer 621543; Familie: Telefonieschalldämpfer 621543; Familie und Typ: Telefonieschalldämpfer 621543: Telefonieschalldämpfer 621543; Typ-ID: 2538071
Abhängigkeiten - Höhe von Ebene: 0 m; Verschieben mit umliegenden Elementen: no
Bemaßungen - Fläche: 2.25784 m2; Volumen: 0.460124 m3
IFC-Parameter - In IFC-Datei exportieren: Nach Typ; Pset MEP.Geom-Ø (mm): 400; Pset MEP.Geom-Length (mm): 3000; Pset MEP.Calc-Pressure loss (Pa): 22; Pset MEP.Calc-Zeta: 2; Pset MEP.Geom-Outer Ø (mm): 450; In IFC exportieren als: ifcflowtreatmentdevice; NameOverride: Telefonieschalldämpfer; IfcPresentationLayer: 0-TFT-H_Abgasabführung Variante 1; ObjectTypeOverride: Telefonieschalldämpfer; Pset MEP.Name: Telefonieschalldämpfer; IfcDescription: Telefonieschalldämpfer; Pset MEP.Abbreviation: B.RSD; Pset MEP.Tech-Medium: L_Entrauchung; Pset MEP.Info: ETB ERA 35
Phasen - Phase erstellt: Phase 01

# IfcFlowTreatmentDevice: Telefonieschalldämpfer:Telefonieschalldämpfer, Telefonieschalldämpfer
In: Erdgeschoss
Type - Material: IfcSurfaceStyle #280217
Type - Andere - Kategorie: Sanitärausstattung; Familienname: Telefonieschalldämpfer
Type - ID-Daten - Typname: Telefonieschalldämpfer
Type - IFC-Parameter - Typ in IFC-Datei exportieren: Vorgabe
Type - HLS - Klassifizierung: Keine
Description: Telefonieschalldämpfer
Pset_DistributionFlowElementCommon - Reference: Telefonieschalldämpfer; sets with these values: 2
Andere - Typ: Telefonieschalldämpfer; Familie: Telefonieschalldämpfer; Familie und Typ: Telefonieschalldämpfer: Telefonieschalldämpfer; Typ-ID: 2533978
Abhängigkeiten - Höhe von Ebene: 0 m; Verschieben mit umliegenden Elementen: no
Bemaßungen - Fläche: 2.25784 m2; Volumen: 0.460124 m3
IFC-Parameter - In IFC-Datei exportieren: Nach Typ; Pset MEP.Geom-Ø (mm): 400; Pset MEP.Geom-Length (mm): 3000; Pset MEP.Calc-Pressure loss (Pa): 22; Pset MEP.Calc-Zeta: 2; In IFC exportieren als: ifcflowtreatmentdevice; NameOverride: Telefonieschalldämpfer; IfcPresentationLayer: 0-TFT-H_Abgasabführung Variante 2; ObjectTypeOverride: Telefonieschalldämpfer; Pset MEP.Name: Telefonieschalldämpfer; IfcDescription: Telefonieschalldämpfer; Pset MEP.Geom-Outer Ø (mm): 450; Pset MEP.Abbreviation: B.RSD; Pset MEP.Tech-Medium: L_Entrauchung; Pset MEP.Info: ETB ERA 35
Phasen - Phase erstellt: Phase 01

# IfcGroup: Modellgruppe:Gebäudeautomation, Modellgruppe:Gebäudeautomation:2542714
Andere - Typ: Gebäudeautomation; Familie: Modellgruppe; Familie und Typ: Modellgruppe: Gebäudeautomation; Typ-ID: 2542715; Kategorie: Modellgruppen
Abhängigkeiten - Referenzebene: Erdgeschoss; Versatz der Ursprungsebene: 0 m
IFC-Parameter - In IFC-Datei exportieren: Nach Typ
Andere(Typ) - Kategorie: Modellgruppen; Familienname: Modellgruppe
ID-Daten(Typ) - Typname: Gebäudeautomation
IFC-Parameter(Typ) - Typ in IFC-Datei exportieren: Vorgabe

# IfcProxy: Teilstrecke:Teilstrecke, Teilstrecke
Type - Material: IfcSurfaceStyle #220236
Type - Andere - Kategorie: Allgemeines Modell; Familienname: Teilstrecke
Type - ID-Daten - Typname: Teilstrecke
Type - IFC-Parameter - Typ in IFC-Datei exportieren: Vorgabe
Description: Teilstrecke
Andere - Typ: Teilstrecke; Familie: Teilstrecke; Familie und Typ: Teilstrecke: Teilstrecke; Typ-ID: 2539202
Abhängigkeiten - Höhe von Ebene: 0 m; Verschieben mit umliegenden Elementen: no
Bemaßungen - Fläche: 0.141797 m2; Volumen: 0.000349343 m3
IFC-Parameter - In IFC-Datei exportieren: Nach Typ; In IFC exportieren als: ifcproxy; NameOverride: Teilstrecke; IfcPresentationLayer: 0-TFT-S_Kaltwasser; ObjectTypeOverride: Teilstrecke; Pset MEP.Name: Teilstrecke; IfcDescription: Teilstrecke; Pset MEP.Tech-Insulation thickness (mm): 9; Pset MEP.Geom-Length (mm): 11643.2
Phasen - Phase erstellt: Phase 01

# IfcSlab: Geschossdecke 112:Geschossdecke 112, Geschossdecke
In: 1. Obergeschoss
Type - PredefinedType: FLOOR; Material: IfcSurfaceStyle #105
Type - Andere - Kategorie: Geschossdecken; Familienname: Geschossdecke 112
Type - ID-Daten - Typname: Geschossdecke 112
Type - IFC-Parameter - Typ in IFC-Datei exportieren: Vorgabe; Typ Vordefinierter IFC-Typ: ROOF; Typ in IFC exportieren als: ifcslabtype
Pset_QuantityTakeOff - Reference: Geschossdecke 112; sets with these values: 2
Pset_SlabCommon - IsExternal: no; Reference: Geschossdecke 112; ThermalTransmittance: 0.455 kg/K/s3
Andere - Typ: Geschossdecke 112; Familie: Geschossdecke 112; Familie und Typ: Geschossdecke 112: Geschossdecke 112; Typ-ID: 2531277
Abhängigkeiten - Höhe von Ebene: 0 m; Verschieben mit umliegenden Elementen: no; Raumbegrenzung: yes
Bemaßungen - Fläche: 1.58046 m2; Volumen: 0.316093 m3
IFC-Parameter - In IFC-Datei exportieren: Nach Typ; Pset_SlabCommon.IsExternal: no; Vordefinierter IFC-Typ: FLOOR; In IFC exportieren als: ifcslab; NameOverride: Geschossdecke; IfcPresentationLayer: 0-TFT-X_Geometrie; ObjectTypeOverride: Geschossdecke; Pset MEP.Geom-Surface (m2): 1.57282; Pset MEP.Name: Geschossdecke; Pset_SlabCommon.ThermalTransmittance: 0.455 kg/K/s3
Phasen - Phase erstellt: Phase 01
Tragwerk - Betonüberdeckung: c=2.0cm <2,0 cm>

# IfcSlab: Geschossdecke 135:Geschossdecke 135, Geschossdecke
In: 1. Obergeschoss
Type - PredefinedType: FLOOR; Material: IfcSurfaceStyle #105
Type - Andere - Kategorie: Geschossdecken; Familienname: Geschossdecke 135
Type - ID-Daten - Typname: Geschossdecke 135
Type - IFC-Parameter - Typ in IFC-Datei exportieren: Vorgabe; Typ Vordefinierter IFC-Typ: ROOF; Typ in IFC exportieren als: ifcslabtype
Pset_QuantityTakeOff - Reference: Geschossdecke 135; sets with these values: 2
Pset_SlabCommon - IsExternal: no; Reference: Geschossdecke 135; ThermalTransmittance: 0.455 kg/K/s3
Andere - Typ: Geschossdecke 135; Familie: Geschossdecke 135; Familie und Typ: Geschossdecke 135: Geschossdecke 135; Typ-ID: 2531291
Abhängigkeiten - Höhe von Ebene: 0 m; Verschieben mit umliegenden Elementen: no; Raumbegrenzung: yes
Bemaßungen - Fläche: 1.58046 m2; Volumen: 0.316093 m3
IFC-Parameter - In IFC-Datei exportieren: Nach Typ; Pset_SlabCommon.IsExternal: no; Vordefinierter IFC-Typ: FLOOR; In IFC exportieren als: ifcslab; NameOverride: Geschossdecke; IfcPresentationLayer: 0-TFT-X_Geometrie; ObjectTypeOverride: Geschossdecke; Pset MEP.Geom-Surface (m2): 1.57282; Pset MEP.Name: Geschossdecke; Pset_SlabCommon.ThermalTransmittance: 0.455 kg/K/s3
Phasen - Phase erstellt: Phase 01
Tragwerk - Betonüberdeckung: c=2.0cm <2,0 cm>

# IfcSlab: Geschossdecke 158:Geschossdecke 158, Geschossdecke
In: 1. Obergeschoss
Type - PredefinedType: FLOOR; Material: IfcSurfaceStyle #105
Type - Andere - Kategorie: Geschossdecken; Familienname: Geschossdecke 158
Type - ID-Daten - Typname: Geschossdecke 158
Type - IFC-Parameter - Typ in IFC-Datei exportieren: Vorgabe; Typ Vordefinierter IFC-Typ: ROOF; Typ in IFC exportieren als: ifcslabtype
Pset_QuantityTakeOff - Reference: Geschossdecke 158; sets with these values: 2
Pset_SlabCommon - IsExternal: no; Reference: Geschossdecke 158; ThermalTransmittance: 0.455 kg/K/s3
Andere - Typ: Geschossdecke 158; Familie: Geschossdecke 158; Familie und Typ: Geschossdecke 158: Geschossdecke 158; Typ-ID: 2531305
Abhängigkeiten - Höhe von Ebene: 0 m; Verschieben mit umliegenden Elementen: no; Raumbegrenzung: yes
Bemaßungen - Fläche: 1.58046 m2; Volumen: 0.316093 m3
IFC-Parameter - In IFC-Datei exportieren: Nach Typ; Pset_SlabCommon.IsExternal: no; Vordefinierter IFC-Typ: FLOOR; In IFC exportieren als: ifcslab; NameOverride: Geschossdecke; IfcPresentationLayer: 0-TFT-X_Geometrie; ObjectTypeOverride: Geschossdecke; Pset MEP.Geom-Surface (m2): 1.57282; Pset MEP.Name: Geschossdecke; Pset_SlabCommon.ThermalTransmittance: 0.455 kg/K/s3
Phasen - Phase erstellt: Phase 01
Tragwerk - Betonüberdeckung: c=2.0cm <2,0 cm>

# IfcSlab: Geschossdecke 929:Geschossdecke 929, Geschossdecke
In: 1. Obergeschoss
Type - PredefinedType: FLOOR; Material: IfcSurfaceStyle #953
Type - Andere - Kategorie: Geschossdecken; Familienname: Geschossdecke 929
Type - ID-Daten - Typname: Geschossdecke 929
Type - IFC-Parameter - Typ in IFC-Datei exportieren: Vorgabe; Typ Vordefinierter IFC-Typ: ROOF; Typ in IFC exportieren als: ifcslabtype
Pset_QuantityTakeOff - Reference: Geschossdecke 929; sets with these values: 2
Pset_SlabCommon - IsExternal: no; Reference: Geschossdecke 929; ThermalTransmittance: 0.455 kg/K/s3
Andere - Typ: Geschossdecke 929; Familie: Geschossdecke 929; Familie und Typ: Geschossdecke 929: Geschossdecke 929; Typ-ID: 2533865
Abhängigkeiten - Höhe von Ebene: 0 m; Verschieben mit umliegenden Elementen: no; Raumbegrenzung: yes
Bemaßungen - Fläche: 24.2217 m2; Volumen: 2.42217 m3
IFC-Parameter - In IFC-Datei exportieren: Nach Typ; Pset_SlabCommon.IsExternal: no; Vordefinierter IFC-Typ: FLOOR; In IFC exportieren als: ifcslab; NameOverride: Geschossdecke; IfcPresentationLayer: 0-TFT-A_Geschossdecke; ObjectTypeOverride: Geschossdecke; Pset MEP.Geom-Surface (m2): 24.2217; Pset MEP.Name: Geschossdecke; Pset_SlabCommon.ThermalTransmittance: 0.455 kg/K/s3
Phasen - Phase erstellt: Phase 01
Tragwerk - Betonüberdeckung: c=2.0cm <2,0 cm>

# IfcSlab: Geschossdecke:Geschossdecke, Geschossdecke
In: 1. Obergeschoss
Type - PredefinedType: FLOOR; Material: IfcSurfaceStyle #105
Type - Andere - Kategorie: Geschossdecken; Familienname: Geschossdecke
Type - ID-Daten - Typname: Geschossdecke
Type - IFC-Parameter - Typ Vordefinierter IFC-Typ: ROOF; Typ in IFC exportieren als: ifcslabtype; Typ in IFC-Datei exportieren: Vorgabe
Pset_QuantityTakeOff - Reference: Geschossdecke; sets with these values: 2
Pset_SlabCommon - Reference: Geschossdecke; ThermalTransmittance: 0.455 kg/K/s3; IsExternal: no
Andere - Typ: Geschossdecke; Familie: Geschossdecke; Familie und Typ: Geschossdecke: Geschossdecke; Typ-ID: 2531250
Abhängigkeiten - Höhe von Ebene: 0 m; Verschieben mit umliegenden Elementen: no; Raumbegrenzung: yes
Bemaßungen - Fläche: 1.58046 m2; Volumen: 0.316093 m3
IFC-Parameter - Vordefinierter IFC-Typ: FLOOR; In IFC exportieren als: ifcslab; In IFC-Datei exportieren: Nach Typ; NameOverride: Geschossdecke; IfcPresentationLayer: 0-TFT-X_Geometrie; ObjectTypeOverride: Geschossdecke; Pset MEP.Geom-Surface (m2): 1.57282; Pset MEP.Name: Geschossdecke; Pset_SlabCommon.IsExternal: no; Pset_SlabCommon.ThermalTransmittance: 0.455 kg/K/s3
Phasen - Phase erstellt: Phase 01
Tragwerk - Betonüberdeckung: c=2.0cm <2,0 cm>

# IfcWallStandardCase: Basiswand:Wand (5)
In: Erdgeschoss
Type - PredefinedType: STANDARD; Material: KS 0.115 m
Type - Andere - Kategorie: Wände; Familienname: Basiswand
Type - Konstruktion - Abschluss an Öffnungen: Keine; Abschluss an Wänden: Keine; Breite: 0.115 m; Funktion: Außen
Type - Grafiken - Farbfüllung für groben Maßstab: 0
Type - ID-Daten - Typname: Wand
Type - IFC-Parameter - Typ in IFC-Datei exportieren: Vorgabe
Type - Analytische Eigenschaften - Absorptionsgrad: 0.1; Rauigkeit: 1
Pset_QuantityTakeOff - Reference: Wand; sets with these values: 2
Pset_WallCommon - Reference: Wand; IsExternal: yes; ExtendToStructure: no; LoadBearing: no
Andere - Typ: Wand; Familie: Basiswand; Familie und Typ: Basiswand: Wand; Typ-ID: 2539959
Abhängigkeiten - Raumbegrenzung: yes; Basislinie: Wandachse; Abhängigkeit unten: Erdgeschoss; Versatz unten: 0 m; Unterkante ist fixiert: no; Verlängerungsabstand unten: 0 m; Nicht verbundene Höhe: 2.5 m; Versatz oben: 0 m; Oberkante ist fixiert.: no; Verlängerungsabstand oben: 0 m; Abhängig von Körper: no
IFC-Parameter - In IFC-Datei exportieren: Nach Typ; In IFC exportieren als: ifcwallstandardcase; NameOverride: Wand; IfcPresentationLayer: 0-TFT-H_Bauteil; ObjectTypeOverride: Wand; Pset MEP.Name: Wand
Phasen - Phase erstellt: Phase 01
Tragwerk - Tragwerk: no; Tragwerksverwendung: Nichttragend
Referenz - Basisbauteilabhängig: no
Querschnittsdefinition - Querschnitt: Vertikal
Name | Länge (m) | Fläche (m2) | Volumen (m3)
Wand | 2.8225 | 7.34375 | 0.828
Wand | 2.8225 | 7.05625 | 0.794937
Wand | 3.3225 | 8.59375 | 0.955219
Wand | 3.3225 | 8.30625 | 0.955219
Wand | 2.8225 | 6.76875 | 0.778406

# IfcWallStandardCase: Basiswand:Wand:1000 (4)
In: Erdgeschoss
Type - PredefinedType: STANDARD; Material: KS 0.1 m
Type - Andere - Kategorie: Wände; Familienname: Basiswand
Type - Konstruktion - Abschluss an Öffnungen: Keine; Abschluss an Wänden: Keine; Funktion: Außen; Breite: 0.1 m
Type - Grafiken - Farbfüllung für groben Maßstab: 0
Type - ID-Daten - Typname: Wand:1000
Type - IFC-Parameter - Typ in IFC-Datei exportieren: Vorgabe
Type - Analytische Eigenschaften - Absorptionsgrad: 0.1; Rauigkeit: 1
Pset_QuantityTakeOff - Reference: Wand:1000; sets with these values: 2
Pset_WallCommon - IsExternal: yes; ExtendToStructure: no; LoadBearing: no; Reference: Wand:1000
Andere - Familie: Basiswand; Typ: Wand:1000; Familie und Typ: Basiswand: Wand:1000; Typ-ID: 2540043
Abhängigkeiten - Raumbegrenzung: yes; Basislinie: Wandachse; Abhängigkeit unten: Erdgeschoss; Versatz unten: 0 m; Unterkante ist fixiert: no; Verlängerungsabstand unten: 0 m; Versatz oben: 0 m; Oberkante ist fixiert.: no; Verlängerungsabstand oben: 0 m; Abhängig von Körper: no; Nicht verbundene Höhe: 2.75 m
IFC-Parameter - In IFC-Datei exportieren: Nach Typ; In IFC exportieren als: ifcwallstandardcase; NameOverride: Wand; IfcPresentationLayer: 0-TFT-H_Variante 3 Kessel; ObjectTypeOverride: Wand; Pset MEP.Name: Wand
Phasen - Phase erstellt: Phase 01
Tragwerk - Tragwerk: no; Tragwerksverwendung: Nichttragend
Referenz - Basisbauteilabhängig: no
Querschnittsdefinition - Querschnitt: Vertikal
Name | Länge (m) | Fläche (m2) | Volumen (m3)
Wand | 7.26134 | 16.0437 | 1.60437
Wand | 3.19039 | 8.77359 | 0.877359
Wand | 7.26134 | 19.9687 | 1.99687
Wand | 3.19039 | 8.49859 | 0.849859
